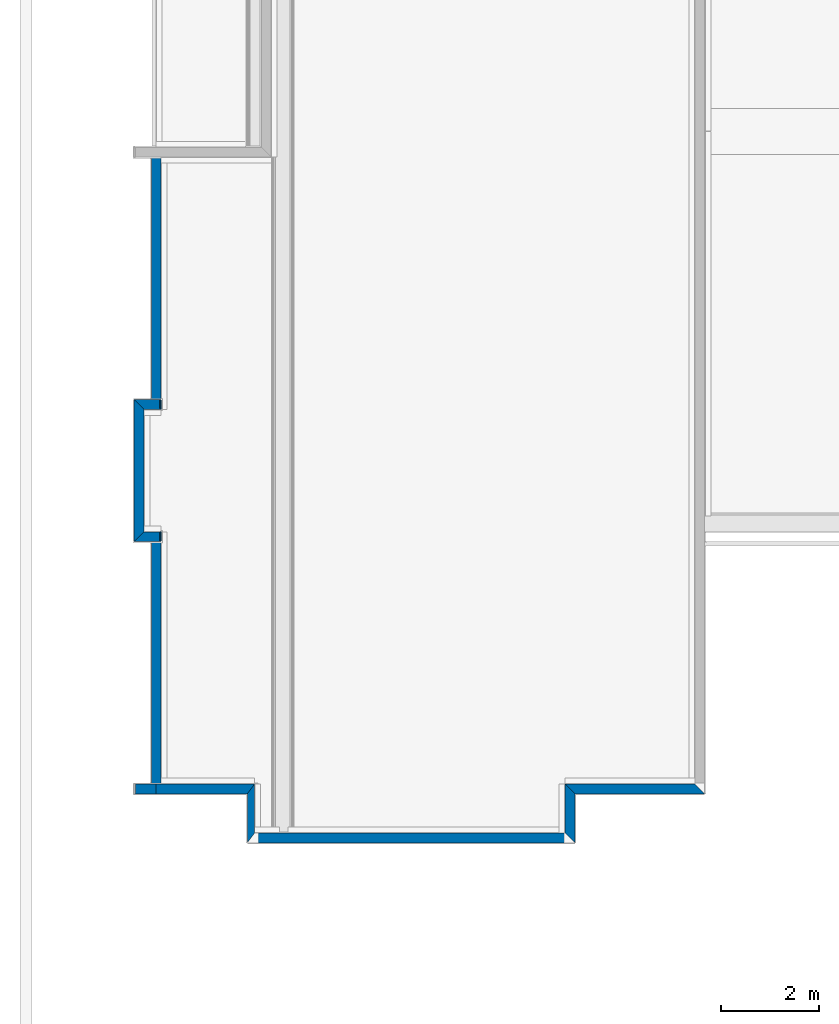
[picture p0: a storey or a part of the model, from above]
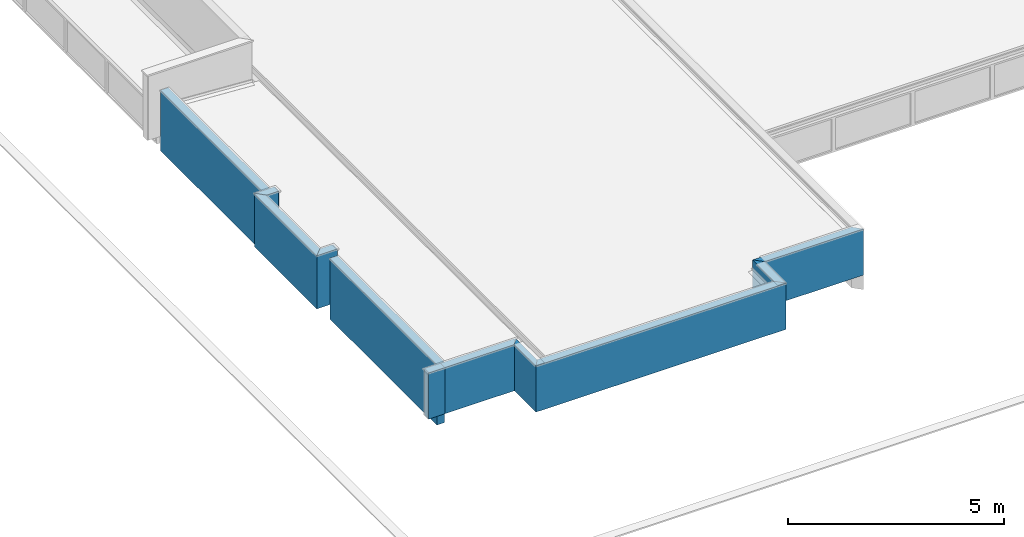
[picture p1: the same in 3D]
Properties of the parts of a building model (IFC4), part 1 of 22

# File
Description: ViewDefinition [Design_Transfer_View], ExchangeRequirement [Architecture], Option [Elements to export: Visible elements (on all stories)], Option [Partial Structure Display: Entire Model], Option [IFC Domain: All], Option [Structural Function: All Elements], Option [Convert Grid elements: On], Option [Convert IFC Annotations and Archicad 2D elements: Off], Option [Convert 2D symbols of Doors and Windows: Off], Option [Export geometries that Participates in Collision Detection only: Off], Option [Split complex elements: Off], Option [Material Preservation: Never explode], Option [Elements in Solid Element Operations: Extruded/revolved], Option [Elements with junctions: Extruded/revolved without junctions], Option [IFC Model position: Survey Point only], Option [Curtain Wall export mode: Container Element], Option [Railing export mode: Single Element], Option [Stair export mode: Single Element], Option [Properties To Export: Current Scheme properties only], Option [Space containment: Off], Option [Geometry to type objects: Off], Option [Element Properties: Visible Only], Option [Building Material Properties: Off], Option [Element Parameters: Off], Option [Component Parameters: IFC Component Quantities Only], Option [IFC Base Quantities: Off], Option [Door Window Parameters: Off], Option [IFC Space boundaries: Off], Option [Archicad Zone Categories as IFC Space classification data: Off], Option [Element Classifications: On]
File name: TIPO2-ARQ-DTV_R03.ifc
Time: 2025-12-15T11:57:10-03:00
Author: Architect
Organization: FUNDO NACIONAL DE DESENVOLVIMENTO DA EDUCAÇÃO - FNDE
Written by: IfcOpenShell 0.8.4
Made in: Bonsai 0.8.4
Authorization: The authorising person

# IfcProject, PROJETO PADRÃO - FNDE
Description: CRECHE PRÉ-ESCOLA TIPO 2; LongName: PROJETO DE ARQUITETURA; Phase: PROJETO PADRÃO

# IfcSite, PADRÃO
RefLatitude: -15, -48, -3, -672000; RefLongitude: -47, -53, 0, -456000; RefElevation: 0 m

# IfcBuildingStorey (2)
In: CRECHE PRÉ-ESCOLA TIPO 2
Name | Elevation (m)
COBERTURA | 3.26
TÉRREO | 0.16

# IfcSpace: Ambientes Administrativos (5)
In: TÉRREO
Type - PredefinedType: INTERNAL
Classification: Zoneamento (Classificação Archicad)
Pset_SpaceCommon - Category: Ambientes Administrativos
FNDE - Ambiente - Quantidade de Alunos: -; Ambiente - Idade dos Alunos: -
Name | LongName = Ambiente
05 | DEPÓSITO
05 | SALA DE ATENDIMENTO
04 | SALA PROF. / REUNIÕES
05 | ADMINISTRAÇÃO
01 | HALL DE ENTRADA

# IfcSpace: Ambientes Externos de Atividades (6)
In: TÉRREO
Type - PredefinedType: INTERNAL
Classification: Zoneamento (Classificação Archicad)
Pset_SpaceCommon - Category: Ambientes Externos de Atividades
FNDE - Ambiente - Quantidade de Alunos: -; Ambiente - Idade dos Alunos: -
Name | LongName = Ambiente
29 | SOLÁRIO - 3
29 | SOLÁRIO - 2
2 x 03 | PLAYGROUND
03 | PÁTIO COBERTO / REFEITÓRIO
29 | SOLÁRIO - 1

# IfcSpace: Ambientes de Alimentaçao / Atenção (2)
In: TÉRREO
Type - PredefinedType: INTERNAL
Classification: Zoneamento (Classificação Archicad)
Pset_SpaceCommon - Category: Ambientes de Alimentaçao / Atenção
FNDE - Ambiente - Quantidade de Alunos: -; Ambiente - Idade dos Alunos: -
Name | LongName = Ambiente
02 | AMAMENTAÇÃO
02 | LACTÁRIO

# IfcSpace: Ambientes de Aprendizagem (6)
In: TÉRREO
Type - PredefinedType: INTERNAL
Classification: Zoneamento (Classificação Archicad)
Pset_SpaceCommon - Category: Ambientes de Aprendizagem
Name | LongName = Ambiente | Ambiente - Quantidade de Alunos | Ambiente - Idade dos Alunos
06 | INFANTIL 1 | 16 alunos | (1 a 2 anos)
06 | INFANTIL 2/3 | 20 alunos | (2 a 4 anos)
06 | INFANTIL 4 | 24 alunos | (4 a 5 anos)
06 | INFANTIL 5 | 24 alunos | (5 a 6 anos)
07 | SALA MULTIUSO | 10 alunos | (0 a 1 ano)
06 | BERÇARIO | 10 alunos | (0 a 1 ano)

# IfcSpace: Ambientes de Higiene (7)
In: TÉRREO
Type - PredefinedType: INTERNAL
Classification: Zoneamento (Classificação Archicad)
Pset_SpaceCommon - Category: Ambientes de Higiene
FNDE - Ambiente - Quantidade de Alunos: -; Ambiente - Idade dos Alunos: -
Name | LongName = Ambiente
11 | SANIT. INFANTIL FEM.
11 | SANIT. INFANTIL MASC.
11 | PCD INFANTIL
06 | HIGIENIZAÇÃO
07 | SANIT. PCD FEM.
06 | SANIT. PCD MASC.
10 | FRALDÁRIO

# IfcSpace: Ambientes de Serviço (11)
In: TÉRREO
Type - PredefinedType: INTERNAL
Classification: Zoneamento (Classificação Archicad)
Pset_SpaceCommon - Category: Ambientes de Serviço
FNDE - Ambiente - Quantidade de Alunos: -; Ambiente - Idade dos Alunos: -
Name | LongName = Ambiente
03 | CASA DE BOMBAS
04 | COZINHA
03 | DESPENSA
05 | LAVANDERIA / ROUPARIA
04 | COPA FUNCIONÁRIOS
03 | VEST. FUNC. FEM.
03 | VEST. FUNC. MASC.
03 | VARANDA DE SERVIÇO / DML
03 | GÁS
03 | CASTELO D'ÁGUA
03 | LIXO

# IfcSpace: Circulações Internas (4)
In: TÉRREO
Type - PredefinedType: INTERNAL
LongName: CIRCULAÇÃO; Classification: Zoneamento (Classificação Archicad)
Pset_SpaceCommon - Category: Circulações Internas
FNDE - Ambiente - Quantidade de Alunos: -; Ambiente - Idade dos Alunos: -; Ambiente: CIRCULAÇÃO

# IfcCovering: ACABAMENTO POLIDO PARA PISO DE CONCRETO 10, L06
In: TÉRREO
Classification: Piso (Acabamento) (Classificação Archicad); Material: ACABAMENTO POLIDO PARA PISO DE CONCRETO
Pset_CoveringCommon - Material: ACABAMENTO POLIDO PARA PISO DE CONCRETO
FNDE - 1_Bloco: ÁREAS EXTERNAS; 0_ID: L06
Component Quantities - ACABAMENTO POLIDO PARA PISO DE CONCRETO, Massa: 49.2388 kg; ACABAMENTO POLIDO PARA PISO DE CONCRETO, Área de Componente Projetada (Líquida): 2.8964 m2; ACABAMENTO POLIDO PARA PISO DE CONCRETO, Área de Componente Projetada (Bruta): 2.8964 m2; ACABAMENTO POLIDO PARA PISO DE CONCRETO, Espessura do Componente: 0.01 m; ACABAMENTO POLIDO PARA PISO DE CONCRETO, Volume Componente (Líquido): 0.028964 m3; ACABAMENTO POLIDO PARA PISO DE CONCRETO, Volume do componente (Bruto): 0.028964 m3

# IfcCovering: ACABAMENTO POLIDO PARA PISO DE CONCRETO 190, L01
In: TÉRREO
Classification: Piso (Acabamento) (Classificação Archicad); Material: ACABAMENTO POLIDO PARA PISO DE CONCRETO
Pset_CoveringCommon - Material: ACABAMENTO POLIDO PARA PISO DE CONCRETO
FNDE - 1_Bloco: CASA DE BOMBAS / GÁS / LIXO; 0_ID: L01
Component Quantities - ACABAMENTO POLIDO PARA PISO DE CONCRETO, Massa: 1296.58 kg; ACABAMENTO POLIDO PARA PISO DE CONCRETO, Área de Componente Projetada (Líquida): 4.01418 m2; ACABAMENTO POLIDO PARA PISO DE CONCRETO, Área de Componente Projetada (Bruta): 4.01418 m2; ACABAMENTO POLIDO PARA PISO DE CONCRETO, Espessura do Componente: 0.19 m; ACABAMENTO POLIDO PARA PISO DE CONCRETO, Volume Componente (Líquido): 0.762694 m3; ACABAMENTO POLIDO PARA PISO DE CONCRETO, Volume do componente (Bruto): 0.762694 m3

# IfcCovering: EI-GRA-Granito cinza Andorinha (Bancadas, bancos e prateleiras) 20 (7)
In: TÉRREO
Type - PredefinedType: CLADDING
Classification: Acabamento (Classificação Archicad); Material: EI-GRA-Granito cinza Andorinha (Bancadas, bancos e prateleiras)
Pset_CoveringCommon - Material: EI-GRA-Granito cinza Andorinha (Bancadas, bancos e prateleiras)
FNDE - Alvenarias: -; Soleira/Peitoril: -
Component Quantities - EI-GRA-Granito cinza Andorinha (Bancadas, bancos e prateleiras), Espessura do Componente: 0.02 m
Name | Pedras | 1_Bloco | 0_ID | EI-GRA-Granito cinza Andorinha (Bancadas, bancos e prateleiras), Massa (kg) | EI-GRA-Granito cinza Andorinha (Bancadas, bancos e prateleiras), Área de Componente Projetada (Líquida) (m2) | EI-GRA-Granito cinza Andorinha (Bancadas, bancos e prateleiras), Área de Componente Projetada (Bruta) (m2) | EI-GRA-Granito cinza Andorinha (Bancadas, bancos e prateleiras), Volume Componente (Líquido) (m3) | EI-GRA-Granito cinza Andorinha (Bancadas, bancos e prateleiras), Volume do componente (Bruto) (m3)
2 x B22 | PRATELEIRA - GRANITO CINZA ANDORINHA - esp. 2 cm | BLOCO A | B22 | 2.52 | 0.045 | 0.045 | 0.0009 | 0.0009
2 x B19 | BANCADA - GRANITO CINZA ANDORINHA - esp. 2 cm | BLOCO B | B19 | 45.0169 | 0.803874 | 0.803874 | 0.0160775 | 0.0160775
2 x B18 | BANCADA - GRANITO CINZA ANDORINHA - esp. 2 cm | BLOCO B | B18 | 56.1624 | 1.0029 | 1.38604 | 0.020058 | 0.0277207
B23 | BANCADA - GRANITO CINZA ANDORINHA - esp. 2 cm | BLOCO A | B23 | 73.4475 | 1.31156 | 1.31156 | 0.0262313 | 0.0262313

# IfcCovering: EI-PIS-3-Cerâmica 45x45 50, L09
In: TÉRREO
Type - PredefinedType: CLADDING
Classification: Acabamento (Classificação Archicad); Material: EI-PIS-3-Cerâmica 45x45
Pset_CoveringCommon - Material: EI-PIS-3-Cerâmica 45x45
FNDE - Alvenarias: -; Soleira/Peitoril: -; Pedras: - -; 1_Bloco: BLOCO B; 0_ID: L09
Component Quantities - EI-PIS-3-Cerâmica 45x45, Massa: 13.0523 kg; EI-PIS-3-Cerâmica 45x45, Área de Componente Projetada (Líquida): 0.130523 m2; EI-PIS-3-Cerâmica 45x45, Área de Componente Projetada (Bruta): 0.130523 m2; EI-PIS-3-Cerâmica 45x45, Espessura do Componente: 0.05 m; EI-PIS-3-Cerâmica 45x45, Volume Componente (Líquido): 0.00652617 m3; EI-PIS-3-Cerâmica 45x45, Volume do componente (Bruto): 0.00652617 m3

# IfcCovering: EI-PIS-6-Bloco intertravado de concreto 100, L01
In: TÉRREO
Classification: Piso (Acabamento) (Classificação Archicad); Material: EI-PIS-6-Bloco intertravado de concreto
Pset_CoveringCommon - Material: EI-PIS-6-Bloco intertravado de concreto
FNDE - 1_Bloco: ÁREAS EXTERNAS; 0_ID: L01
Component Quantities - EI-PIS-6-Bloco intertravado de concreto, Massa: 4190.73 kg; EI-PIS-6-Bloco intertravado de concreto, Área de Componente Projetada (Líquida): 23.2818 m2; EI-PIS-6-Bloco intertravado de concreto, Área de Componente Projetada (Bruta): 23.2818 m2; EI-PIS-6-Bloco intertravado de concreto, Espessura do Componente: 0.1 m; EI-PIS-6-Bloco intertravado de concreto, Volume Componente (Líquido): 2.32818 m3; EI-PIS-6-Bloco intertravado de concreto, Volume do componente (Bruto): 2.32818 m3

# IfcCovering: EI-PIS-8-Gramado (2)
In: TÉRREO
Type - PredefinedType: CLADDING
Classification: Acabamento (Classificação Archicad); Material: EI-PIS-8-Gramado
Pset_CoveringCommon - Material: EI-PIS-8-Gramado
FNDE - Alvenarias: -; Soleira/Peitoril: -; Pedras: - -; 1_Bloco: ÁREAS EXTERNAS; 0_ID: Malha-001

# IfcCovering: EI-PIS-8-Gramado 100 (8)
In: TÉRREO
Type - PredefinedType: CLADDING
Classification: Acabamento (Classificação Archicad); Material: EI-PIS-8-Gramado
Pset_CoveringCommon - Material: EI-PIS-8-Gramado
FNDE - Alvenarias: -; Soleira/Peitoril: -; Pedras: - -; 1_Bloco: ÁREAS EXTERNAS
Component Quantities - EI-PIS-8-Gramado, Espessura do Componente: 0.1 m
Name | 0_ID | EI-PIS-8-Gramado, Massa (kg) | EI-PIS-8-Gramado, Área de Componente Projetada (Líquida) (m2) = EI-PIS-8-Gramado, Área de Componente Projetada (Bruta) (m2) | EI-PIS-8-Gramado, Volume Componente (Líquido) (m3) = EI-PIS-8-Gramado, Volume do componente (Bruto) (m3)
L01 | L01 | 11459.6 | 127.329 | 12.7329
L01 | L01 | 6568.96 | 72.9885 | 7.29885
L01 | L01 | 107.095 | 1.18994 | 0.118994
L01 | L01 | 1648.21 | 18.3135 | 1.83135
L01 | L01 | 335.469 | 3.72743 | 0.372743
L02 | L02 | 5713.51 | 63.4835 | 6.34835
L02 | L02 | 1409.41 | 15.6601 | 1.56601
L01 | L01 | 797.238 | 8.8582 | 0.88582

# IfcCovering: EI-PIS-Piso Tátil alerta em placas de borracha Amarela 7 (5)
In: TÉRREO
Type - PredefinedType: CLADDING
Classification: Acabamento (Classificação Archicad); Material: EI-PIS-Piso Tátil alerta em placas de borracha Amarela
Pset_CoveringCommon - Material: EI-PIS-Piso Tátil alerta em placas de borracha Amarela
FNDE - Alvenarias: -; Soleira/Peitoril: -; Pedras: - -; 0_ID: L01
Component Quantities - EI-PIS-Piso Tátil alerta em placas de borracha Amarela, Massa: 7.2975 kg; EI-PIS-Piso Tátil alerta em placas de borracha Amarela, Área de Componente Projetada (Líquida): 0.75 m2; EI-PIS-Piso Tátil alerta em placas de borracha Amarela, Área de Componente Projetada (Bruta): 1 m2; EI-PIS-Piso Tátil alerta em placas de borracha Amarela, Espessura do Componente: 0.007 m; EI-PIS-Piso Tátil alerta em placas de borracha Amarela, Volume Componente (Líquido): 0.00525 m3; EI-PIS-Piso Tátil alerta em placas de borracha Amarela, Volume do componente (Bruto): 0.007 m3
Name | 1_Bloco
3 x L01 | BLOCO A
2 x L01 | BLOCO B

# IfcCovering: EI-PIS-Piso Tátil alerta em placas de borracha Azul 7 (8)
In: TÉRREO
Type - PredefinedType: CLADDING
Classification: Acabamento (Classificação Archicad); Material: EI-PIS-Piso Tátil alerta em placas de borracha Azul
Pset_CoveringCommon - Material: EI-PIS-Piso Tátil alerta em placas de borracha Azul
FNDE - Alvenarias: -; Soleira/Peitoril: -; Pedras: - -
Component Quantities - EI-PIS-Piso Tátil alerta em placas de borracha Azul, Espessura do Componente: 0.007 m
Name | 1_Bloco | 0_ID | EI-PIS-Piso Tátil alerta em placas de borracha Azul, Massa (kg) | EI-PIS-Piso Tátil alerta em placas de borracha Azul, Área de Componente Projetada (Líquida) (m2) = EI-PIS-Piso Tátil alerta em placas de borracha Azul, Área de Componente Projetada (Bruta) (m2) | EI-PIS-Piso Tátil alerta em placas de borracha Azul, Volume Componente (Líquido) (m3) = EI-PIS-Piso Tátil alerta em placas de borracha Azul, Volume do componente (Bruto) (m3)
2 x L01 | BLOCO B | L01 | 6.68938 | 0.6875 | 0.0048125
Forro-017 | BLOCO B | Forro-017 | 3.64875 | 0.375 | 0.002625
L01 | BLOCO A | L01 | 1.82439 | 0.187502 | 0.00131251
L01 | BLOCO A | L01 | 2.43253 | 0.250003 | 0.00175002
L01 | BLOCO A | L01 | 3.64879 | 0.375004 | 0.00262503
L01 | BLOCO A | L01 | 1.82438 | 0.1875 | 0.0013125
L01 | BLOCO A | L01 | 1.82437 | 0.1875 | 0.0013125

# IfcCovering: EI-PIS-Piso Tátil alerta em placas pré-moldadas na cor vermelha 10 (4)
In: TÉRREO
Type - PredefinedType: CLADDING
Classification: Acabamento (Classificação Archicad); Material: EI-PIS-Piso Tátil alerta em placas pré-moldadas na cor vermelha
Pset_CoveringCommon - Material: EI-PIS-Piso Tátil alerta em placas pré-moldadas na cor vermelha
FNDE - Alvenarias: -; Soleira/Peitoril: -; Pedras: - -; 1_Bloco: ÁREAS EXTERNAS
Name | 0_ID | EI-PIS-Piso Tátil alerta em placas pré-moldadas na cor vermelha, Massa (kg) | EI-PIS-Piso Tátil alerta em placas pré-moldadas na cor vermelha, Área de Componente Projetada (Líquida) (m2) = EI-PIS-Piso Tátil alerta em placas pré-moldadas na cor vermelha, Área de Componente Projetada (Bruta) (m2) | EI-PIS-Piso Tátil alerta em placas pré-moldadas na cor vermelha, Espessura do Componente (m) | EI-PIS-Piso Tátil alerta em placas pré-moldadas na cor vermelha, Volume Componente (Líquido) (m3) = EI-PIS-Piso Tátil alerta em placas pré-moldadas na cor vermelha, Volume do componente (Bruto) (m3)
Cobert.-001 | Cobert.-001 | 4.5 | 0.250084 | 0.00999662 | 0.0025
L01 | L01 | 3.375 | 0.1875 | 0.01 | 0.001875
2 x Cobert.-001 | Cobert.-001 | 3.375 | 0.187563 | 0.00999662 | 0.001875

# IfcCovering: EI-PIS-Piso Tátil direcional em placas de borracha Azul 7 (3)
In: TÉRREO
Type - PredefinedType: CLADDING
Classification: Acabamento (Classificação Archicad); Material: EI-PIS-Piso Tátil direcional em placas de borracha Azul
Pset_CoveringCommon - Material: EI-PIS-Piso Tátil direcional em placas de borracha Azul
FNDE - Alvenarias: -; Soleira/Peitoril: -; Pedras: - -
Component Quantities - EI-PIS-Piso Tátil direcional em placas de borracha Azul, Espessura do Componente: 0.007 m
Name | 1_Bloco | 0_ID | EI-PIS-Piso Tátil direcional em placas de borracha Azul, Massa (kg) | EI-PIS-Piso Tátil direcional em placas de borracha Azul, Área de Componente Projetada (Líquida) (m2) = EI-PIS-Piso Tátil direcional em placas de borracha Azul, Área de Componente Projetada (Bruta) (m2) | EI-PIS-Piso Tátil direcional em placas de borracha Azul, Volume Componente (Líquido) (m3) = EI-PIS-Piso Tátil direcional em placas de borracha Azul, Volume do componente (Bruto) (m3)
Forro-016 | BLOCO B | Forro-016 | 1.82438 | 0.1875 | 0.0013125
Forro-015 | BLOCO B | Forro-015 | 1.82438 | 0.1875 | 0.0013125
Forro-014 | PÁTIO COBERTO | Forro-014 | 32.8364 | 3.37476 | 0.0236233

# IfcCovering: EI-PIS-Piso Tátil direcional em placas pré-moldadas na cor vermelha 10 (6)
In: TÉRREO
Type - PredefinedType: CLADDING
Classification: Acabamento (Classificação Archicad); Material: EI-PIS-Piso Tátil direcional em placas pré-moldadas na cor vermelha
Pset_CoveringCommon - Material: EI-PIS-Piso Tátil direcional em placas pré-moldadas na cor vermelha
FNDE - Alvenarias: -; Soleira/Peitoril: -; Pedras: - -; 1_Bloco: ÁREAS EXTERNAS
Name | 0_ID | EI-PIS-Piso Tátil direcional em placas pré-moldadas na cor vermelha, Massa (kg) | EI-PIS-Piso Tátil direcional em placas pré-moldadas na cor vermelha, Área de Componente Projetada (Líquida) (m2) = EI-PIS-Piso Tátil direcional em placas pré-moldadas na cor vermelha, Área de Componente Projetada (Bruta) (m2) | EI-PIS-Piso Tátil direcional em placas pré-moldadas na cor vermelha, Espessura do Componente (m) | EI-PIS-Piso Tátil direcional em placas pré-moldadas na cor vermelha, Volume Componente (Líquido) (m3) = EI-PIS-Piso Tátil direcional em placas pré-moldadas na cor vermelha, Volume do componente (Bruto) (m3)
Cobert.-001 | Cobert.-001 | 3.375 | 0.187563 | 0.00999662 | 0.001875
Cobert.-001 | Cobert.-001 | 0.67308 | 0.037406 | 0.00999662 | 0.000373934
L01 | L01 | 17.9094 | 0.994966 | 0.01 | 0.00994966
Cobert.-001 | Cobert.-001 | 14.3572 | 0.798535 | 0.0099886 | 0.00797624
Cobert.-001 | Cobert.-001 | 2.25 | 0.125042 | 0.00999662 | 0.00125
L01 | L01 | 2.74503 | 0.152502 | 0.01 | 0.00152502

# IfcCovering: EI-REV-Cerâmica 10x10 Azul 10 (2)
In: TÉRREO
Type - PredefinedType: CLADDING
Classification: Acabamento (Classificação Archicad); Material: EI-REV-Cerâmica 10x10 Azul
Pset_CoveringCommon - Material: EI-REV-Cerâmica 10x10 Azul
FNDE - Alvenarias: -; Soleira/Peitoril: -; Pedras: - -; 1_Bloco: BLOCO B
Component Quantities - EI-REV-Cerâmica 10x10 Azul, Espessura do Componente: 0.01 m
Name | EI-REV-Cerâmica 10x10 Azul, Massa (kg) | EI-REV-Cerâmica 10x10 Azul, Área de Componente Projetada (Líquida) (m2) = EI-REV-Cerâmica 10x10 Azul, Área de Componente Projetada (Bruta) (m2) | EI-REV-Cerâmica 10x10 Azul, Volume Componente (Líquido) (m3) = EI-REV-Cerâmica 10x10 Azul, Volume do componente (Bruto) (m3)
 | 1.19029 | 0.1329 | 0.000595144
 | 2.06608 | 0.103304 | 0.00103304

# IfcCovering: EI-REV-Cerâmica 10x10 Vermelha 10
In: TÉRREO
Type - PredefinedType: CLADDING
Classification: Acabamento (Classificação Archicad); Material: EI-REV-Cerâmica 10x10 Vermelha
Pset_CoveringCommon - Material: EI-REV-Cerâmica 10x10 Vermelha
FNDE - Alvenarias: -; Soleira/Peitoril: -; Pedras: - -; 1_Bloco: BLOCO B
Component Quantities - EI-REV-Cerâmica 10x10 Vermelha, Massa: 0.92164 kg; EI-REV-Cerâmica 10x10 Vermelha, Área de Componente Projetada (Líquida): 0.103304 m2; EI-REV-Cerâmica 10x10 Vermelha, Área de Componente Projetada (Bruta): 0.103304 m2; EI-REV-Cerâmica 10x10 Vermelha, Espessura do Componente: 0.01 m; EI-REV-Cerâmica 10x10 Vermelha, Volume Componente (Líquido): 0.00046082 m3; EI-REV-Cerâmica 10x10 Vermelha, Volume do componente (Bruto): 0.00046082 m3

# IfcCovering: EI-REV-Cerâmica 30x40 15, L26
In: TÉRREO
Classification: Piso (Acabamento) (Classificação Archicad); Material: EI-REV-Cerâmica 30x40
Pset_CoveringCommon - Material: EI-REV-Cerâmica 30x40
FNDE - 1_Bloco: BLOCO A; 0_ID: L26
Component Quantities - EI-REV-Cerâmica 30x40, Massa: 3.1509 kg; EI-REV-Cerâmica 30x40, Área de Componente Projetada (Líquida): 0.10503 m2; EI-REV-Cerâmica 30x40, Área de Componente Projetada (Bruta): 0.10503 m2; EI-REV-Cerâmica 30x40, Espessura do Componente: 0.015 m; EI-REV-Cerâmica 30x40, Volume Componente (Líquido): 0.00157545 m3; EI-REV-Cerâmica 30x40, Volume do componente (Bruto): 0.00157545 m3

# IfcCovering: EI-REV-Pintura Epóxi cor Amarelo 1, L01
In: TÉRREO
Classification: Piso (Acabamento) (Classificação Archicad); Material: EI-REV-Pintura Epóxi cor Amarelo
Pset_CoveringCommon - Material: EI-REV-Pintura Epóxi cor Amarelo
FNDE - 1_Bloco: ÁREAS EXTERNAS; 0_ID: L01
Component Quantities - EI-REV-Pintura Epóxi cor Amarelo, Massa: 0.663006 kg; EI-REV-Pintura Epóxi cor Amarelo, Área de Componente Projetada (Líquida): 0.510004 m2; EI-REV-Pintura Epóxi cor Amarelo, Área de Componente Projetada (Bruta): 1 m2; EI-REV-Pintura Epóxi cor Amarelo, Espessura do Componente: 0.001 m; EI-REV-Pintura Epóxi cor Amarelo, Volume Componente (Líquido): 0.000510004 m3; EI-REV-Pintura Epóxi cor Amarelo, Volume do componente (Bruto): 0.001 m3

# IfcCovering: EI-REV-Pintura Epóxi cor Amarelo 1 (7)
In: TÉRREO
Type - PredefinedType: CLADDING
Classification: Acabamento (Classificação Archicad); Material: EI-REV-Pintura Epóxi cor Amarelo
Pset_CoveringCommon - Material: EI-REV-Pintura Epóxi cor Amarelo
FNDE - Alvenarias: -; Soleira/Peitoril: -; Pedras: - -; 1_Bloco: PÁTIO COBERTO; 0_ID: L09
Component Quantities - EI-REV-Pintura Epóxi cor Amarelo, Espessura do Componente: 0.001 m
Name | EI-REV-Pintura Epóxi cor Amarelo, Massa (kg) | EI-REV-Pintura Epóxi cor Amarelo, Área de Componente Projetada (Líquida) (m2) = EI-REV-Pintura Epóxi cor Amarelo, Área de Componente Projetada (Bruta) (m2) | EI-REV-Pintura Epóxi cor Amarelo, Volume Componente (Líquido) (m3) = EI-REV-Pintura Epóxi cor Amarelo, Volume do componente (Bruto) (m3)
L09 | 0.208 | 0.16 | 0.00016
L09 | 0.312 | 0.24 | 0.00024
L09 | 0.286629 | 0.220484 | 0.000220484
L09 | 0.304129 | 0.233946 | 0.000233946
L09 | 0.267889 | 0.206069 | 0.000206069
L09 | 0.246051 | 0.18927 | 0.00018927
L09 | 0.270051 | 0.207731 | 0.000207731

# IfcCovering: EI-REV-Pintura Epóxi cor Azul 1 (10)
In: TÉRREO
Type - PredefinedType: CLADDING
Classification: Acabamento (Classificação Archicad); Material: EI-REV-Pintura Epóxi cor Azul
Pset_CoveringCommon - Material: EI-REV-Pintura Epóxi cor Azul
FNDE - Alvenarias: -; Soleira/Peitoril: -; Pedras: - -; 1_Bloco: PÁTIO COBERTO; 0_ID: L09
Component Quantities - EI-REV-Pintura Epóxi cor Azul, Espessura do Componente: 0.001 m
Name | EI-REV-Pintura Epóxi cor Azul, Massa (kg) | EI-REV-Pintura Epóxi cor Azul, Área de Componente Projetada (Líquida) (m2) = EI-REV-Pintura Epóxi cor Azul, Área de Componente Projetada (Bruta) (m2) | EI-REV-Pintura Epóxi cor Azul, Volume Componente (Líquido) (m3) = EI-REV-Pintura Epóxi cor Azul, Volume do componente (Bruto) (m3)
L09 | 1.1115 | 0.855 | 0.000855
L09 | 0.91975 | 0.7075 | 0.0007075
2 x L09 | 0.312 | 0.24 | 0.00024
L09 | 0.208 | 0.16 | 0.00016
L09 | 0.277579 | 0.213523 | 0.000213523
L09 | 0.301406 | 0.231851 | 0.000231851
L09 | 0.284155 | 0.21858 | 0.00021858
L09 | 0.248022 | 0.190786 | 0.000190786
L09 | 0.230028 | 0.176945 | 0.000176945

# IfcCovering: EI-REV-Pintura Epóxi cor Branco 1, L09
In: TÉRREO
Type - PredefinedType: CLADDING
Classification: Acabamento (Classificação Archicad); Material: EI-REV-Pintura Epóxi cor Branco
Pset_CoveringCommon - Material: EI-REV-Pintura Epóxi cor Branco
FNDE - Alvenarias: -; Soleira/Peitoril: -; Pedras: - -; 1_Bloco: PÁTIO COBERTO; 0_ID: L09
Component Quantities - EI-REV-Pintura Epóxi cor Branco, Massa: 1.60513 kg; EI-REV-Pintura Epóxi cor Branco, Área de Componente Projetada (Líquida): 0.944197 m2; EI-REV-Pintura Epóxi cor Branco, Área de Componente Projetada (Bruta): 6.75984 m2; EI-REV-Pintura Epóxi cor Branco, Espessura do Componente: 0.001 m; EI-REV-Pintura Epóxi cor Branco, Volume Componente (Líquido): 0.000944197 m3; EI-REV-Pintura Epóxi cor Branco, Volume do componente (Bruto): 0.00675984 m3

# IfcCovering: EI-REV-Pintura Epóxi cor Cinza 1 (6)
In: TÉRREO
Type - PredefinedType: CLADDING
Classification: Acabamento (Classificação Archicad); Material: EI-REV-Pintura Epóxi cor Cinza
Pset_CoveringCommon - Material: EI-REV-Pintura Epóxi cor Cinza
FNDE - Alvenarias: -; Soleira/Peitoril: -; Pedras: - -; 1_Bloco: PÁTIO COBERTO; 0_ID: L09
Component Quantities - EI-REV-Pintura Epóxi cor Cinza, Espessura do Componente: 0.001 m
Name | EI-REV-Pintura Epóxi cor Cinza, Massa (kg) | EI-REV-Pintura Epóxi cor Cinza, Área de Componente Projetada (Líquida) (m2) = EI-REV-Pintura Epóxi cor Cinza, Área de Componente Projetada (Bruta) (m2) | EI-REV-Pintura Epóxi cor Cinza, Volume Componente (Líquido) (m3) = EI-REV-Pintura Epóxi cor Cinza, Volume do componente (Bruto) (m3)
L09 | 0.352964 | 0.207626 | 0.000207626
L09 | 0.331531 | 0.195018 | 0.000195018
L09 | 0.217341 | 0.127848 | 0.000127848
L09 | 0.403751 | 0.2375 | 0.0002375
L09 | 0.359886 | 0.211698 | 0.000211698
L09 | 0.418063 | 0.245919 | 0.000245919

# IfcCovering: EI-REV-Pintura Epóxi cor Laranja 1 (9)
In: TÉRREO
Type - PredefinedType: CLADDING
Classification: Acabamento (Classificação Archicad); Material: EI-REV-Pintura Epóxi cor Laranja
Pset_CoveringCommon - Material: EI-REV-Pintura Epóxi cor Laranja
FNDE - Alvenarias: -; Soleira/Peitoril: -; Pedras: - -; 1_Bloco: PÁTIO COBERTO; 0_ID: L09
Component Quantities - EI-REV-Pintura Epóxi cor Laranja, Espessura do Componente: 0.001 m
Name | EI-REV-Pintura Epóxi cor Laranja, Massa (kg) | EI-REV-Pintura Epóxi cor Laranja, Área de Componente Projetada (Líquida) (m2) = EI-REV-Pintura Epóxi cor Laranja, Área de Componente Projetada (Bruta) (m2) | EI-REV-Pintura Epóxi cor Laranja, Volume Componente (Líquido) (m3) = EI-REV-Pintura Epóxi cor Laranja, Volume do componente (Bruto) (m3)
L09 | 0.312 | 0.24 | 0.00024
L09 | 0.208 | 0.16 | 0.00016
L09 | 0.593406 | 0.456466 | 0.000456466
L09 | 0.482799 | 0.371384 | 0.000371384
L09 | 0.290484 | 0.223449 | 0.000223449
L09 | 0.294511 | 0.226547 | 0.000226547
L09 | 0.275317 | 0.211782 | 0.000211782
L09 | 0.289915 | 0.223012 | 0.000223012
L09 | 0.246722 | 0.189786 | 0.000189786

# IfcCovering: EI-REV-Pintura Epóxi cor Verde 1 (8)
In: TÉRREO
Type - PredefinedType: CLADDING
Classification: Acabamento (Classificação Archicad); Material: EI-REV-Pintura Epóxi cor Verde
Pset_CoveringCommon - Material: EI-REV-Pintura Epóxi cor Verde
FNDE - Alvenarias: -; Soleira/Peitoril: -; Pedras: - -; 1_Bloco: PÁTIO COBERTO; 0_ID: L09
Component Quantities - EI-REV-Pintura Epóxi cor Verde, Espessura do Componente: 0.001 m
Name | EI-REV-Pintura Epóxi cor Verde, Massa (kg) | EI-REV-Pintura Epóxi cor Verde, Área de Componente Projetada (Líquida) (m2) = EI-REV-Pintura Epóxi cor Verde, Área de Componente Projetada (Bruta) (m2) | EI-REV-Pintura Epóxi cor Verde, Volume Componente (Líquido) (m3) = EI-REV-Pintura Epóxi cor Verde, Volume do componente (Bruto) (m3)
L09 | 0.208 | 0.16 | 0.00016
2 x L09 | 0.312 | 0.24 | 0.00024
L09 | 0.327408 | 0.251852 | 0.000251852
L09 | 0.273217 | 0.210167 | 0.000210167
L09 | 0.289267 | 0.222513 | 0.000222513
L09 | 0.266747 | 0.20519 | 0.00020519
L09 | 0.214944 | 0.165341 | 0.000165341

# IfcCovering: EI-REV-Pintura Epóxi cor Vermelho 1, L01
In: TÉRREO
Classification: Piso (Acabamento) (Classificação Archicad); Material: EI-REV-Pintura Epóxi cor Vermelho
Pset_CoveringCommon - Material: EI-REV-Pintura Epóxi cor Vermelho
FNDE - 1_Bloco: ÁREAS EXTERNAS; 0_ID: L01
Component Quantities - EI-REV-Pintura Epóxi cor Vermelho, Massa: 0.637 kg; EI-REV-Pintura Epóxi cor Vermelho, Área de Componente Projetada (Líquida): 0.49 m2; EI-REV-Pintura Epóxi cor Vermelho, Área de Componente Projetada (Bruta): 0.49 m2; EI-REV-Pintura Epóxi cor Vermelho, Espessura do Componente: 0.001 m; EI-REV-Pintura Epóxi cor Vermelho, Volume Componente (Líquido): 0.00049 m3; EI-REV-Pintura Epóxi cor Vermelho, Volume do componente (Bruto): 0.00049 m3

# IfcCovering: EI-REV-Rodapé Ceramico 13 x 70 (23)
In: TÉRREO
Classification: Rodapé (Classificação Archicad); Material: EI-REV-Rodapé Ceramico
Pset_CoveringCommon - Material: EI-REV-Rodapé Ceramico
FNDE - 1_Bloco: BLOCO B
Component Quantities - EI-REV-Rodapé Ceramico, Espessura do Componente: 0.013 m; EI-REV-Rodapé Ceramico, Altura do Componente Retangular: 0.07 m; EI-REV-Rodapé Ceramico, Largura do Componente Retangular: 0.013 m; EI-REV-Rodapé Ceramico, Área de Seção Transversal do Componente: 0.00091 m2
Name | EI-REV-Rodapé Ceramico, Massa (kg) | EI-REV-Rodapé Ceramico, Área de Componente Projetada (Líquida) (m2) = EI-REV-Rodapé Ceramico, Área de Componente Projetada (Bruta) (m2) | EI-REV-Rodapé Ceramico, Volume Componente (Líquido) (m3) = EI-REV-Rodapé Ceramico, Volume do componente (Bruto) (m3)
 | 2.77277 | 0.1071 | 0.00138639
 | 4.52634 | 0.175 | 0.00226317
2 x  | 5.43622 | 0.209995 | 0.00271811
 | 0.11557 | 0.0049 | 0.000057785
 | 8.01588 | 0.312547 | 0.00400794
 | 1.62617 | 0.063 | 0.000813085
 | 2.77272 | 0.107098 | 0.00138636
2 x  | 10.8963 | 0.419998 | 0.00544815
 | 3.96487 | 0.15295 | 0.00198244
 | 0.141089 | 0.00559692 | 0.0000705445
 | 4.17417 | 0.161 | 0.00208709
 | 4.89034 | 0.189 | 0.00244517
 | 2.62712 | 0.101498 | 0.00131356
 | 8.26917 | 0.3185 | 0.00413458
 | 0.09737 | 0.0042 | 0.000048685
 | 3.1006 | 0.119709 | 0.0015503
 | 0.552619 | 0.0217096 | 0.000276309
 | 2.26298 | 0.0874927 | 0.00113149
2 x  | 5.43201 | 0.209834 | 0.00271601
 | 4.5082 | 0.174302 | 0.0022541

# IfcCovering: EI-REV-Rodapé em PVC para piso vinílico 13 x 50 (49)
In: TÉRREO
Classification: Rodapé (Classificação Archicad); Material: EI-REV-Rodapé em PVC para piso vinílico
Pset_CoveringCommon - Material: EI-REV-Rodapé em PVC para piso vinílico
Component Quantities - EI-REV-Rodapé em PVC para piso vinílico, Espessura do Componente: 0.013 m; EI-REV-Rodapé em PVC para piso vinílico, Altura do Componente Retangular: 0.05 m; EI-REV-Rodapé em PVC para piso vinílico, Largura do Componente Retangular: 0.013 m; EI-REV-Rodapé em PVC para piso vinílico, Área de Seção Transversal do Componente: 0.00065 m2
Name | 1_Bloco | EI-REV-Rodapé em PVC para piso vinílico, Massa (kg) | EI-REV-Rodapé em PVC para piso vinílico, Área de Componente Projetada (Líquida) (m2) = EI-REV-Rodapé em PVC para piso vinílico, Área de Componente Projetada (Bruta) (m2) | EI-REV-Rodapé em PVC para piso vinílico, Volume Componente (Líquido) (m3) = EI-REV-Rodapé em PVC para piso vinílico, Volume do componente (Bruto) (m3)
 | BLOCO A | 1.40359 | 0.078 | 0.00100977
 | BLOCO A | 0.728784 | 0.0406561 | 0.000524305
 | BLOCO A | 5.41827 | 0.300499 | 0.00389804
 | BLOCO A | 0.897627 | 0.05 | 0.000645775
 | BLOCO A | 3.29188 | 0.182499 | 0.00236826
 | BLOCO A | 3.79631 | 0.210414 | 0.00273116
 | BLOCO A | 0.400702 | 0.0225 | 0.000288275
 | BLOCO B | 0.400703 | 0.0225001 | 0.000288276
4 x  | BLOCO B | 0.406575 | 0.02315 | 0.0002925
2 x  | BLOCO B | 1.79525 | 0.1 | 0.00129155
 | BLOCO B | 3.82045 | 0.21175 | 0.00274853
 | BLOCO B | 0.147271 | 0.0088 | 0.00010595
 | BLOCO B | 0.89763 | 0.0500001 | 0.000645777
 | BLOCO B | 5.40928 | 0.300001 | 0.00389157
 | BLOCO B | 3.46675 | 0.192501 | 0.00249407
 | BLOCO B | 0.703375 | 0.03925 | 0.000506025
 | BLOCO B | 0.195607 | 0.01115 | 0.000140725
 | BLOCO B | 0.0483367 | 0.00299997 | 0.0000347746
 | BLOCO B | 2.92465 | 0.162501 | 0.00210407
 | BLOCO B | 0.14727 | 0.0088 | 0.00010595
4 x  | BLOCO B | 5.40929 | 0.300002 | 0.00389158
 | BLOCO B | 0.988026 | 0.0550027 | 0.00071081
2 x  | BLOCO B | 0.400702 | 0.0225 | 0.000288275
2 x  | BLOCO B | 0.5421 | 0.03065 | 0.00039
2 x  | BLOCO B | 0.852452 | 0.0475 | 0.000613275
 | BLOCO B | 0.852425 | 0.0474985 | 0.000613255
2 x  | BLOCO B | 4.37023 | 0.2425 | 0.00314405
 | BLOCO B | 0.85248 | 0.0475015 | 0.000613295
 | BLOCO B | 0.195608 | 0.01115 | 0.000140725
 | BLOCO B | 0.987971 | 0.0549997 | 0.000710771
 | BLOCO B | 4.86713 | 0.269999 | 0.00350153
 | BLOCO B | 0.400764 | 0.0225034 | 0.000288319
 | BLOCO B | 0.703435 | 0.0392533 | 0.000506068
 | BLOCO B | 5.40923 | 0.299999 | 0.00389153
 | BLOCO B | 0.897565 | 0.0499965 | 0.00064573
 | BLOCO B | 5.40919 | 0.299996 | 0.0038915
 | BLOCO B | 3.82033 | 0.211743 | 0.00274844
 | BLOCO B | 0.0483372 | 0.003 | 0.000034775

# IfcCovering: FNDE-COB_IMP-PM 33, L01
In: TÉRREO
Classification: Piso (Acabamento) (Classificação Archicad); Material: EI-ISO-Impermeabilização Manta Líquida, EI-PIS-Proteção Meânica
Pset_CoveringCommon - Material: FNDE-COB_IMP-PM
FNDE - 1_Bloco: CASA DE BOMBAS / GÁS / LIXO; 0_ID: L01
Component Quantities - EI-PIS-Proteção Meânica, Massa: 922.258 kg; EI-PIS-Proteção Meânica, Área de Componente Projetada (Líquida): 13.8841 m2; EI-PIS-Proteção Meânica, Área de Componente Projetada (Bruta): 13.8841 m2; EI-PIS-Proteção Meânica, Espessura do Componente: 0.03 m; EI-PIS-Proteção Meânica, Volume Componente (Líquido): 0.400982 m3; EI-PIS-Proteção Meânica, Volume do componente (Bruto): 0.400982 m3; EI-ISO-Impermeabilização Manta Líquida, Massa: 42.8007 kg; EI-ISO-Impermeabilização Manta Líquida, Área de Componente Projetada (Líquida): 12.9699 m2; EI-ISO-Impermeabilização Manta Líquida, Área de Componente Projetada (Bruta): 12.9699 m2; EI-ISO-Impermeabilização Manta Líquida, Espessura do Componente: 0.003 m; EI-ISO-Impermeabilização Manta Líquida, Volume Componente (Líquido): 0.0389098 m3; EI-ISO-Impermeabilização Manta Líquida, Volume do componente (Bruto): 0.0389098 m3

# IfcCovering: FNDE-Chuveiros - escada 920 x 370 (4)
In: TÉRREO
Type - PredefinedType: CLADDING
Classification: Acabamento (Classificação Archicad); Material: FNDE-Enchimento, LASTRO DE CONCRETO, EI-ISO-Impermeabilização, EI-PIS-3-Cerâmica 45x45, TIJOLO - CERAMICO 9x19x39 - espessura 15cm, EI-REV-Chapisco (interno) (3), EI-REV-Emboço Interno (3), EI-REV-Cerâmica 30x40 (3)
Pset_CoveringCommon - Material: FNDE-Chuveiros - escada
FNDE - Alvenarias: Mureta; Soleira/Peitoril: -; Pedras: - -
Component Quantities - FNDE-Enchimento, Altura do Componente Retangular: 0.29 m; FNDE-Enchimento, Largura do Componente Retangular: 0.61 m; FNDE-Enchimento, Área de Seção Transversal do Componente: 0.1769 m2; LASTRO DE CONCRETO, Altura do Componente Retangular: 0.05 m; LASTRO DE CONCRETO, Largura do Componente Retangular: 0.615 m; LASTRO DE CONCRETO, Área de Seção Transversal do Componente: 0.03075 m2; EI-ISO-Impermeabilização, Altura do Componente Retangular: 0.005 m; EI-ISO-Impermeabilização, Largura do Componente Retangular: 0.62 m; EI-ISO-Impermeabilização, Área de Seção Transversal do Componente: 0.0031 m2; EI-PIS-3-Cerâmica 45x45, Área de Seção Transversal do Componente: 0.01575 m2; TIJOLO - CERAMICO 9x19x39 - espessura 15cm, Altura do Componente Retangular: 0.17 m; TIJOLO - CERAMICO 9x19x39 - espessura 15cm, Largura do Componente Retangular: 0.28 m; TIJOLO - CERAMICO 9x19x39 - espessura 15cm, Área de Seção Transversal do Componente: 0.0476 m2; EI-REV-Chapisco (interno) 1, Área de Seção Transversal do Componente: 0.000862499 m2; EI-REV-Emboço Interno 1, Área de Seção Transversal do Componente: 0.0008875 m2; EI-REV-Cerâmica 30x40 1, Área de Seção Transversal do Componente: 0.0032 m2; EI-REV-Chapisco (interno) 2, Área de Seção Transversal do Componente: 0.0014 m2; EI-REV-Cerâmica 30x40 2, Área de Seção Transversal do Componente: 0.0056 m2; EI-REV-Chapisco (interno) 3, Área de Seção Transversal do Componente: 0.0005875 m2; EI-REV-Emboço Interno 3, Área de Seção Transversal do Componente: 0.0008125 m2; EI-REV-Cerâmica 30x40 3, Área de Seção Transversal do Componente: 0.00335 m2
Name | 1_Bloco | FNDE-Enchimento, Massa (kg) | FNDE-Enchimento, Área de Componente Projetada (Líquida) (m2) = FNDE-Enchimento, Área de Componente Projetada (Bruta) (m2) | FNDE-Enchimento, Volume Componente (Líquido) (m3) = FNDE-Enchimento, Volume do componente (Bruto) (m3) | LASTRO DE CONCRETO, Massa (kg) | LASTRO DE CONCRETO, Área de Componente Projetada (Líquida) (m2) = LASTRO DE CONCRETO, Área de Componente Projetada (Bruta) (m2) | LASTRO DE CONCRETO, Volume Componente (Líquido) (m3) = LASTRO DE CONCRETO, Volume do componente (Bruto) (m3) | EI-ISO-Impermeabilização, Massa (kg) | EI-ISO-Impermeabilização, Área de Componente Projetada (Líquida) (m2) = EI-ISO-Impermeabilização, Área de Componente Projetada (Bruta) (m2) | EI-ISO-Impermeabilização, Volume Componente (Líquido) (m3) = EI-ISO-Impermeabilização, Volume do componente (Bruto) (m3) | EI-PIS-3-Cerâmica 45x45, Massa (kg) | EI-PIS-3-Cerâmica 45x45, Área de Componente Projetada (Líquida) (m2) = EI-PIS-3-Cerâmica 45x45, Área de Componente Projetada (Bruta) (m2) | EI-PIS-3-Cerâmica 45x45, Volume Componente (Líquido) (m3) = EI-PIS-3-Cerâmica 45x45, Volume do componente (Bruto) (m3) | TIJOLO - CERAMICO 9x19x39 - espessura 15cm, Massa (kg) | TIJOLO - CERAMICO 9x19x39 - espessura 15cm, Área de Componente Projetada (Líquida) (m2) = TIJOLO - CERAMICO 9x19x39 - espessura 15cm, Área de Componente Projetada (Bruta) (m2) = EI-REV-Cerâmica 30x40 1, Área de Componente Projetada (Líquida) (m2) = EI-REV-Cerâmica 30x40 1, Área de Componente Projetada (Bruta) (m2) | TIJOLO - CERAMICO 9x19x39 - espessura 15cm, Volume Componente (Líquido) (m3) = TIJOLO - CERAMICO 9x19x39 - espessura 15cm, Volume do componente (Bruto) (m3) | EI-REV-Chapisco (interno) 1, Massa (kg) | EI-REV-Chapisco (interno) 1, Área de Componente Projetada (Líquida) (m2) = EI-REV-Chapisco (interno) 1, Área de Componente Projetada (Bruta) (m2) | EI-REV-Chapisco (interno) 1, Volume Componente (Líquido) (m3) = EI-REV-Chapisco (interno) 1, Volume do componente (Bruto) (m3) | EI-REV-Emboço Interno 1, Massa (kg) | EI-REV-Emboço Interno 1, Área de Componente Projetada (Líquida) (m2) = EI-REV-Emboço Interno 1, Área de Componente Projetada (Bruta) (m2) | EI-REV-Emboço Interno 1, Volume Componente (Líquido) (m3) = EI-REV-Emboço Interno 1, Volume do componente (Bruto) (m3) | EI-REV-Cerâmica 30x40 1, Massa (kg) | EI-REV-Cerâmica 30x40 1, Volume Componente (Líquido) (m3) = EI-REV-Cerâmica 30x40 1, Volume do componente (Bruto) (m3) | EI-REV-Chapisco (interno) 2, Massa (kg) | EI-REV-Chapisco (interno) 2, Área de Componente Projetada (Líquida) (m2) = EI-REV-Chapisco (interno) 2, Área de Componente Projetada (Bruta) (m2) | EI-REV-Chapisco (interno) 2, Volume Componente (Líquido) (m3) = EI-REV-Chapisco (interno) 2, Volume do componente (Bruto) (m3) | EI-REV-Cerâmica 30x40 2, Massa (kg) | EI-REV-Cerâmica 30x40 2, Área de Componente Projetada (Líquida) (m2) = EI-REV-Cerâmica 30x40 2, Área de Componente Projetada (Bruta) (m2) | EI-REV-Cerâmica 30x40 2, Volume Componente (Líquido) (m3) = EI-REV-Cerâmica 30x40 2, Volume do componente (Bruto) (m3) | EI-REV-Chapisco (interno) 3, Massa (kg) | EI-REV-Chapisco (interno) 3, Área de Componente Projetada (Líquida) (m2) = EI-REV-Chapisco (interno) 3, Área de Componente Projetada (Bruta) (m2) | EI-REV-Chapisco (interno) 3, Volume Componente (Líquido) (m3) = EI-REV-Chapisco (interno) 3, Volume do componente (Bruto) (m3) | EI-REV-Emboço Interno 3, Massa (kg) | EI-REV-Emboço Interno 3, Área de Componente Projetada (Líquida) (m2) = EI-REV-Emboço Interno 3, Área de Componente Projetada (Bruta) (m2) | EI-REV-Emboço Interno 3, Volume Componente (Líquido) (m3) = EI-REV-Emboço Interno 3, Volume do componente (Bruto) (m3) | EI-REV-Cerâmica 30x40 3, Massa (kg) | EI-REV-Cerâmica 30x40 3, Área de Componente Projetada (Líquida) (m2) = EI-REV-Cerâmica 30x40 3, Área de Componente Projetada (Bruta) (m2) | EI-REV-Cerâmica 30x40 3, Volume Componente (Líquido) (m3) = EI-REV-Cerâmica 30x40 3, Volume do componente (Bruto) (m3)
 | BLOCO B | 169.778 | 0.390293 | 0.113185 | 35.4144 | 0.393493 | 0.0196747 | 2.18181 | 0.396693 | 0.00198347 | 20.1546 | 0.409493 | 0.0100773 | 19.7398 | 0.108795 | 0.0304627 | 0.568284 | 0.0889533 | 0.000437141 | 0.588108 | 0.0920031 | 0.000452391 | 4.09583 | 0.00204791 | 1.11015 | 0.173842 | 0.000853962 | 7.1677 | 0.191992 | 0.00358385 | 0.465867 | 0.0731967 | 0.000358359 | 0.644284 | 0.100646 | 0.000495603 | 4.28782 | 0.121595 | 0.00214391 | Component Quantities - EI-REV-Chapisco (interno) 2: 2 with these values
 | BLOCO A | 169.733 | 0.390191 | 0.113155 | 35.405 | 0.393389 | 0.0196694 | 2.18123 | 0.396587 | 0.00198294 | 20.1492 | 0.40938 | 0.0100746 | 19.7301 | 0.108742 | 0.0304477 | 0.592458 | 0.0927466 | 0.000455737 | 0.613247 | 0.0959448 | 0.000471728 | 4.0938 | 0.0020469 | 1.16413 | 0.182295 | 0.000895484 | 7.16415 | 0.191897 | 0.00358208 | 0.488519 | 0.0767558 | 0.000375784 | 0.675611 | 0.105539 | 0.000519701 | 4.2857 | 0.121535 | 0.00214285 | Component Quantities - EI-REV-Emboço Interno 2, Massa: 1.16413 kg; EI-REV-Emboço Interno 2, Área de Componente Projetada (Líquida): 0.182295 m2; EI-REV-Emboço Interno 2, Área de Componente Projetada (Bruta): 0.182295 m2; EI-REV-Emboço Interno 2, Área de Seção Transversal do Componente: 0.0014 m2; EI-REV-Emboço Interno 2, Volume Componente (Líquido): 0.000895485 m3; EI-REV-Emboço Interno 2, Volume do componente (Bruto): 0.000895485 m3
 | BLOCO B | 0.00772169 | 0.0000428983 | 0.00000514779 | 0.00386085 | 0.0000428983 | 0.00000214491 | 0.000235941 | 0.0000428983 | 2.14491e-07 | 0.00000359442 | 0.0000428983 | 1.79721e-09 | 0.00472567 | 0.108795 | 0.00000729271 | 0 | 0 | 0 | 0.0000442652 | 0.000507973 | 3.40502e-08 | 0.0145825 | 0.00000729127 | 0 | 0 | 0 | 0.00000287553 | 0.0000428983 | 1.43777e-09 | 0 | 0 | 0 | 0 | 0 | 0 | 0.0145818 | 0.108795 | 0.00000729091 | Component Quantities - EI-REV-Chapisco (interno) 2: 2 with these values
 | BLOCO B | 169.778 | 0.390293 | 0.113185 | 35.4144 | 0.393493 | 0.0196747 | 2.18181 | 0.396693 | 0.00198347 | 20.1546 | 0.409493 | 0.0100773 | 19.7398 | 0.108795 | 0.0304627 | 0.560827 | 0.0889577 | 0.000431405 | 0.588137 | 0.0920077 | 0.000452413 | 4.09583 | 0.00204791 | 1.11019 | 0.173809 | 0.000853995 | 7.1677 | 0.191992 | 0.00358385 | 0.459509 | 0.0731589 | 0.000353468 | 0.641652 | 0.10065 | 0.000493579 | 4.28739 | 0.121595 | 0.00214369 | Component Quantities - EI-REV-Emboço Interno 2, Massa: 1.1102 kg; EI-REV-Emboço Interno 2, Área de Componente Projetada (Líquida): 0.173849 m2; EI-REV-Emboço Interno 2, Área de Componente Projetada (Bruta): 0.173849 m2; EI-REV-Emboço Interno 2, Área de Seção Transversal do Componente: 0.0014 m2; EI-REV-Emboço Interno 2, Volume Componente (Líquido): 0.000853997 m3; EI-REV-Emboço Interno 2, Volume do componente (Bruto): 0.000853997 m3

# IfcCovering: FNDE-Chuveiros 890 x 830 (4)
In: TÉRREO
Type - PredefinedType: CLADDING
Classification: Acabamento (Classificação Archicad); Material: FNDE-Enchimento, LASTRO DE CONCRETO, EI-ISO-Impermeabilização (2), EI-PIS-3-Cerâmica 45x45, TIJOLO - CERAMICO 9x19x39 - espessura 15cm (2), EI-REV-Chapisco (interno) (5), EI-REV-Emboço Interno (5), EI-REV-Cerâmica 30x40 (5)
Pset_CoveringCommon - Material: FNDE-Chuveiros
FNDE - Alvenarias: Mureta; Soleira/Peitoril: -; Pedras: - -
Component Quantities - FNDE-Enchimento, Altura do Componente Retangular: 0.29 m; FNDE-Enchimento, Largura do Componente Retangular: 0.67 m; FNDE-Enchimento, Área de Seção Transversal do Componente: 0.1943 m2; LASTRO DE CONCRETO, Altura do Componente Retangular: 0.05 m; LASTRO DE CONCRETO, Largura do Componente Retangular: 0.67 m; LASTRO DE CONCRETO, Área de Seção Transversal do Componente: 0.0335 m2; EI-ISO-Impermeabilização 1, Área de Seção Transversal do Componente: 0.0033375 m2; EI-PIS-3-Cerâmica 45x45, Altura do Componente Retangular: 0.025 m; EI-PIS-3-Cerâmica 45x45, Largura do Componente Retangular: 0.665 m; EI-PIS-3-Cerâmica 45x45, Área de Seção Transversal do Componente: 0.016625 m2; EI-ISO-Impermeabilização 2, Área de Seção Transversal do Componente: 0.0015375 m2; TIJOLO - CERAMICO 9x19x39 - espessura 15cm 1, Área de Seção Transversal do Componente: 0.072 m2; EI-REV-Chapisco (interno) 1, Área de Seção Transversal do Componente: 0.0040125 m2; EI-REV-Emboço Interno 1, Área de Seção Transversal do Componente: 0.0040375 m2; EI-REV-Cerâmica 30x40 1, Área de Seção Transversal do Componente: 0.0158 m2; TIJOLO - CERAMICO 9x19x39 - espessura 15cm 2, Altura do Componente Retangular: 0.65 m; TIJOLO - CERAMICO 9x19x39 - espessura 15cm 2, Largura do Componente Retangular: 0.1 m; TIJOLO - CERAMICO 9x19x39 - espessura 15cm 2, Área de Seção Transversal do Componente: 0.065 m2; EI-REV-Chapisco (interno) 2, Área de Seção Transversal do Componente: 0.0014125 m2; EI-REV-Emboço Interno 2, Área de Seção Transversal do Componente: 0.0014375 m2; EI-REV-Cerâmica 30x40 2, Área de Seção Transversal do Componente: 0.0045 m2; EI-REV-Chapisco (interno) 3, Área de Seção Transversal do Componente: 0.000525 m2; EI-REV-Cerâmica 30x40 3, Área de Seção Transversal do Componente: 0.00205 m2; EI-REV-Chapisco (interno) 4, Área de Seção Transversal do Componente: 0.000750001 m2; EI-REV-Emboço Interno 4, Área de Seção Transversal do Componente: 0.00075 m2; EI-REV-Cerâmica 30x40 4, Área de Seção Transversal do Componente: 0.003 m2; EI-REV-Chapisco (interno) 5, Área de Seção Transversal do Componente: 0.000475 m2; EI-REV-Cerâmica 30x40 5, Área de Seção Transversal do Componente: 0.0026 m2
Name | 1_Bloco | FNDE-Enchimento, Massa (kg) | FNDE-Enchimento, Área de Componente Projetada (Líquida) (m2) = FNDE-Enchimento, Área de Componente Projetada (Bruta) (m2) = LASTRO DE CONCRETO, Área de Componente Projetada (Líquida) (m2) = LASTRO DE CONCRETO, Área de Componente Projetada (Bruta) (m2) = EI-ISO-Impermeabilização 1, Área de Componente Projetada (Líquida) (m2) = EI-ISO-Impermeabilização 1, Área de Componente Projetada (Bruta) (m2) | FNDE-Enchimento, Volume Componente (Líquido) (m3) = FNDE-Enchimento, Volume do componente (Bruto) (m3) | LASTRO DE CONCRETO, Massa (kg) | LASTRO DE CONCRETO, Volume Componente (Líquido) (m3) = LASTRO DE CONCRETO, Volume do componente (Bruto) (m3) | EI-ISO-Impermeabilização 1, Massa (kg) | EI-ISO-Impermeabilização 1, Volume Componente (Líquido) (m3) = EI-ISO-Impermeabilização 1, Volume do componente (Bruto) (m3) | EI-PIS-3-Cerâmica 45x45, Massa (kg) | EI-PIS-3-Cerâmica 45x45, Área de Componente Projetada (Líquida) (m2) = EI-PIS-3-Cerâmica 45x45, Área de Componente Projetada (Bruta) (m2) | EI-PIS-3-Cerâmica 45x45, Volume Componente (Líquido) (m3) | EI-PIS-3-Cerâmica 45x45, Volume do componente (Bruto) (m3) | EI-ISO-Impermeabilização 2, Massa (kg) | EI-ISO-Impermeabilização 2, Área de Componente Projetada (Líquida) (m2) = EI-ISO-Impermeabilização 2, Área de Componente Projetada (Bruta) (m2) | EI-ISO-Impermeabilização 2, Volume Componente (Líquido) (m3) = EI-ISO-Impermeabilização 2, Volume do componente (Bruto) (m3) | TIJOLO - CERAMICO 9x19x39 - espessura 15cm 1, Massa (kg) | TIJOLO - CERAMICO 9x19x39 - espessura 15cm 1, Área de Componente Projetada (Líquida) (m2) = TIJOLO - CERAMICO 9x19x39 - espessura 15cm 1, Área de Componente Projetada (Bruta) (m2) | TIJOLO - CERAMICO 9x19x39 - espessura 15cm 1, Volume Componente (Líquido) (m3) = TIJOLO - CERAMICO 9x19x39 - espessura 15cm 1, Volume do componente (Bruto) (m3) | EI-REV-Chapisco (interno) 1, Massa (kg) | EI-REV-Chapisco (interno) 1, Área de Componente Projetada (Líquida) (m2) = EI-REV-Chapisco (interno) 1, Área de Componente Projetada (Bruta) (m2) | EI-REV-Chapisco (interno) 1, Volume Componente (Líquido) (m3) = EI-REV-Chapisco (interno) 1, Volume do componente (Bruto) (m3) | EI-REV-Emboço Interno 1, Massa (kg) | EI-REV-Emboço Interno 1, Área de Componente Projetada (Líquida) (m2) = EI-REV-Emboço Interno 1, Área de Componente Projetada (Bruta) (m2) | EI-REV-Emboço Interno 1, Volume Componente (Líquido) (m3) = EI-REV-Emboço Interno 1, Volume do componente (Bruto) (m3) | EI-REV-Cerâmica 30x40 1, Massa (kg) | EI-REV-Cerâmica 30x40 1, Área de Componente Projetada (Líquida) (m2) = EI-REV-Cerâmica 30x40 1, Área de Componente Projetada (Bruta) (m2) | EI-REV-Cerâmica 30x40 1, Volume Componente (Líquido) (m3) = EI-REV-Cerâmica 30x40 1, Volume do componente (Bruto) (m3) | TIJOLO - CERAMICO 9x19x39 - espessura 15cm 2, Massa (kg) | TIJOLO - CERAMICO 9x19x39 - espessura 15cm 2, Área de Componente Projetada (Líquida) (m2) = TIJOLO - CERAMICO 9x19x39 - espessura 15cm 2, Área de Componente Projetada (Bruta) (m2) | TIJOLO - CERAMICO 9x19x39 - espessura 15cm 2, Volume Componente (Líquido) (m3) = TIJOLO - CERAMICO 9x19x39 - espessura 15cm 2, Volume do componente (Bruto) (m3) | EI-REV-Chapisco (interno) 2, Massa (kg) | EI-REV-Chapisco (interno) 2, Área de Componente Projetada (Líquida) (m2) = EI-REV-Chapisco (interno) 2, Área de Componente Projetada (Bruta) (m2) | EI-REV-Chapisco (interno) 2, Volume Componente (Líquido) (m3) = EI-REV-Chapisco (interno) 2, Volume do componente (Bruto) (m3) | EI-REV-Emboço Interno 2, Massa (kg) | EI-REV-Emboço Interno 2, Área de Componente Projetada (Líquida) (m2) = EI-REV-Emboço Interno 2, Área de Componente Projetada (Bruta) (m2) | EI-REV-Emboço Interno 2, Volume Componente (Líquido) (m3) = EI-REV-Emboço Interno 2, Volume do componente (Bruto) (m3) | EI-REV-Cerâmica 30x40 2, Massa (kg) | EI-REV-Cerâmica 30x40 2, Área de Componente Projetada (Líquida) (m2) = EI-REV-Cerâmica 30x40 2, Área de Componente Projetada (Bruta) (m2) | EI-REV-Cerâmica 30x40 2, Volume Componente (Líquido) (m3) = EI-REV-Cerâmica 30x40 2, Volume do componente (Bruto) (m3) | EI-REV-Chapisco (interno) 3, Massa (kg) | EI-REV-Chapisco (interno) 3, Área de Componente Projetada (Líquida) (m2) = EI-REV-Chapisco (interno) 3, Área de Componente Projetada (Bruta) (m2) | EI-REV-Chapisco (interno) 3, Volume Componente (Líquido) (m3) = EI-REV-Chapisco (interno) 3, Volume do componente (Bruto) (m3) | EI-REV-Cerâmica 30x40 3, Massa (kg) | EI-REV-Cerâmica 30x40 3, Área de Componente Projetada (Líquida) (m2) = EI-REV-Cerâmica 30x40 3, Área de Componente Projetada (Bruta) (m2) | EI-REV-Cerâmica 30x40 3, Volume Componente (Líquido) (m3) = EI-REV-Cerâmica 30x40 3, Volume do componente (Bruto) (m3) | EI-REV-Chapisco (interno) 4, Massa (kg) | EI-REV-Chapisco (interno) 4, Área de Componente Projetada (Líquida) (m2) = EI-REV-Chapisco (interno) 4, Área de Componente Projetada (Bruta) (m2) | EI-REV-Chapisco (interno) 4, Volume Componente (Líquido) (m3) = EI-REV-Chapisco (interno) 4, Volume do componente (Bruto) (m3) | EI-REV-Emboço Interno 4, Massa (kg) | EI-REV-Emboço Interno 4, Área de Componente Projetada (Líquida) (m2) = EI-REV-Emboço Interno 4, Área de Componente Projetada (Bruta) (m2) | EI-REV-Emboço Interno 4, Volume Componente (Líquido) (m3) = EI-REV-Emboço Interno 4, Volume do componente (Bruto) (m3) | EI-REV-Cerâmica 30x40 4, Massa (kg) | EI-REV-Cerâmica 30x40 4, Área de Componente Projetada (Líquida) (m2) = EI-REV-Cerâmica 30x40 4, Área de Componente Projetada (Bruta) (m2) | EI-REV-Cerâmica 30x40 4, Volume Componente (Líquido) (m3) = EI-REV-Cerâmica 30x40 4, Volume do componente (Bruto) (m3) | EI-REV-Chapisco (interno) 5, Massa (kg) | EI-REV-Chapisco (interno) 5, Área de Componente Projetada (Líquida) (m2) = EI-REV-Chapisco (interno) 5, Área de Componente Projetada (Bruta) (m2) | EI-REV-Chapisco (interno) 5, Volume Componente (Líquido) (m3) = EI-REV-Chapisco (interno) 5, Volume do componente (Bruto) (m3) | EI-REV-Cerâmica 30x40 5, Massa (kg) | EI-REV-Cerâmica 30x40 5, Área de Componente Projetada (Líquida) (m2) = EI-REV-Cerâmica 30x40 5, Área de Componente Projetada (Bruta) (m2) | EI-REV-Cerâmica 30x40 5, Volume Componente (Líquido) (m3) = EI-REV-Cerâmica 30x40 5, Volume do componente (Bruto) (m3)
 | BLOCO B | 408.909 | 0.94002 | 0.272606 | 84.6018 | 0.047001 | 5.15073 | 0.00468248 | 45.6497 | 0.93297 | 0.0228248 | 0.0233242 | 2.38471 | 0.437108 | 0.00216791 | 65.7862 | 1.12802 | 0.101522 | 7.0801 | 1.09277 | 0.00544623 | 7.12593 | 1.09982 | 0.00548148 | 43.9928 | 1.09982 | 0.0219964 | 59.3903 | 0.916518 | 0.0916518 | 2.58917 | 0.401858 | 0.00199167 | 2.63499 | 0.408908 | 0.00202691 | 12.6902 | 0.437108 | 0.00634512 | 0.962343 | 0.155103 | 0.000740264 | 5.78111 | 0.169203 | 0.00289056 | 1.37478 | 0.218554 | 0.00105752 | 1.37478 | 0.218554 | 0.00105752 | 7.89615 | 0.211504 | 0.00394808 | 0.870692 | 0.141003 | 0.000669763 | 0 | 0 | 0 | Component Quantities - EI-REV-Emboço Interno 3, Massa: 0.962344 kg; EI-REV-Emboço Interno 3, Área de Componente Projetada (Líquida): 0.155103 m2; EI-REV-Emboço Interno 3, Área de Componente Projetada (Bruta): 0.155103 m2; EI-REV-Emboço Interno 3, Área de Seção Transversal do Componente: 0.000525 m2; EI-REV-Emboço Interno 3, Volume Componente (Líquido): 0.000740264 m3; EI-REV-Emboço Interno 3, Volume do componente (Bruto): 0.000740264 m3; EI-REV-Emboço Interno 3: 2 with these values
 | BLOCO A | 177.892 | 0.408947 | 0.118595 | 36.8053 | 0.0204474 | 2.24082 | 0.00203711 | 20.2948 | 0.405895 | 0.0101474 | 0.0101474 | 1.03229 | 0.189214 | 0.000938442 | 28.4774 | 0.488295 | 0.0439466 | 3.06482 | 0.473036 | 0.00235755 | 3.08466 | 0.476088 | 0.00237281 | 19.2266 | 0.482192 | 0.00961332 | 25.7087 | 0.39674 | 0.039674 | 1.12079 | 0.173955 | 0.000862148 | 1.14063 | 0.177007 | 0.000877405 | 5.49332 | 0.189214 | 0.00274666 | 0.416577 | 0.0671406 | 0.000320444 | 2.50251 | 0.0732443 | 0.00125126 | 0.59511 | 0.0946072 | 0.000457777 | 0.59511 | 0.0946072 | 0.000457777 | 3.60118 | 0.0976591 | 0.00180059 | 0.376903 | 0.0610369 | 0.000289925 | 1.46489 | 0.0793481 | 0.000732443 | Component Quantities - EI-REV-Chapisco (interno) 3: 3 with these values
 | BLOCO B | 0 | 0 | 0 | 0 | 0 | 0 | 0 | 0 | 0 | 0 | 0 | 0 | 0 | 0 | 0.0489972 | 1.12802 | 0.0000756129 | 0 | 0 | 0 | 0 | 0 | 0 | 0.147445 | 1.09982 | 0.0000737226 | 0 | 0 | 0 | 0 | 0 | 0 | 0 | 0 | 0 | 0.0548193 | 0.408908 | 0.0000274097 | 0 | 0 | 0 | 0.00000633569 | 0.0000945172 | 3.16785e-09 | 0 | 0 | 0 | 0 | 0 | 0 | 0.0283485 | 0.211504 | 0.0000141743 | 0 | 0 | 0 | 0 | 0 | 0 | Component Quantities - EI-REV-Chapisco (interno) 3: 3 with these values
 | BLOCO B | 408.901 | 0.940002 | 0.272601 | 84.6002 | 0.0470001 | 5.15063 | 0.00468239 | 45.6488 | 0.932952 | 0.0228244 | 0.0233238 | 2.38471 | 0.437108 | 0.00216791 | 65.7862 | 1.12802 | 0.101522 | 6.98549 | 1.09277 | 0.00537345 | 7.12593 | 1.09982 | 0.00548148 | 43.9928 | 1.09982 | 0.0219964 | 59.3903 | 0.916518 | 0.0916518 | 2.58917 | 0.401858 | 0.00199167 | 2.59936 | 0.408813 | 0.00199951 | 12.6902 | 0.437108 | 0.00634512 | 0.962343 | 0.155103 | 0.000740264 | 5.78111 | 0.169203 | 0.00289056 | 1.37478 | 0.218554 | 0.00105752 | 1.35635 | 0.21846 | 0.00104335 | 7.89615 | 0.211504 | 0.00394808 | 0.870692 | 0.141003 | 0.000669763 | 0 | 0 | 0 | Component Quantities - EI-REV-Emboço Interno 3, Massa: 0.962339 kg; EI-REV-Emboço Interno 3, Área de Componente Projetada (Líquida): 0.155008 m2; EI-REV-Emboço Interno 3, Área de Componente Projetada (Bruta): 0.155008 m2; EI-REV-Emboço Interno 3, Área de Seção Transversal do Componente: 0.000525 m2; EI-REV-Emboço Interno 3, Volume Componente (Líquido): 0.000740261 m3; EI-REV-Emboço Interno 3, Volume do componente (Bruto): 0.000740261 m3; EI-REV-Emboço Interno 3: 2 with these values

# IfcCovering: FNDE-FOR_FOR-MSA-PTA 15 (29)
In: TÉRREO
Type - PredefinedType: CEILING
Classification: Forro (Classificação Archicad); Material: EI-REV-Pintura PVA Cor Branco Neve, EI-REV-Massa Corrida PVA (interna), EI-FOR-2-Forro de Gesso Acartonado
Pset_CoveringCommon - Material: FNDE-FOR_FOR-MSA-PTA
Component Quantities - EI-FOR-2-Forro de Gesso Acartonado, Espessura do Componente: 0.01 m; EI-REV-Massa Corrida PVA (interna), Espessura do Componente: 0.0025 m; EI-REV-Massa Corrida PVA (interna): 2 with these values
Name | 1_Bloco | 0_ID | EI-FOR-2-Forro de Gesso Acartonado, Massa (kg) | EI-FOR-2-Forro de Gesso Acartonado, Área de Componente Projetada (Líquida) (m2) = EI-FOR-2-Forro de Gesso Acartonado, Área de Componente Projetada (Bruta) (m2) | EI-FOR-2-Forro de Gesso Acartonado, Volume Componente (Líquido) (m3) = EI-FOR-2-Forro de Gesso Acartonado, Volume do componente (Bruto) (m3) | EI-REV-Massa Corrida PVA (interna), Massa (kg) | EI-REV-Massa Corrida PVA (interna), Área de Componente Projetada (Líquida) (m2) = EI-REV-Massa Corrida PVA (interna), Área de Componente Projetada (Bruta) (m2) | EI-REV-Massa Corrida PVA (interna), Volume Componente (Líquido) (m3) = EI-REV-Massa Corrida PVA (interna), Volume do componente (Bruto) (m3)
Forro-014 | BLOCO B | Forro-014 | 137.389 | 15.2655 | 0.152655 | 49.6127 | 15.2655 | 0.0381636
Forro-014 | BLOCO B | Forro-014 | 64.1341 | 7.12602 | 0.0712602 | 23.1596 | 7.12602 | 0.017815
Forro-015 | BLOCO B | Forro-015 | 232.503 | 25.8337 | 0.258337 | 83.9594 | 25.8337 | 0.0645841
Forro-015 | BLOCO B | Forro-015 | 232.509 | 25.8344 | 0.258344 | 83.9617 | 25.8344 | 0.0645859
Forro-014 | BLOCO B | Forro-014 | 64.1342 | 7.12602 | 0.0712602 | 23.1596 | 7.12602 | 0.017815
Forro-011 | BLOCO A | Forro-011 | 106.085 | 11.7872 | 0.117872 | 38.3085 | 11.7872 | 0.0294681
Forro-015 | BLOCO A | Forro-015 | 239.183 | 26.5759 | 0.265759 | 86.3715 | 26.5759 | 0.0664397
Forro-014 | BLOCO A | Forro-014 | 23.8812 | 2.65346 | 0.0265346 | 8.62375 | 2.65346 | 0.00663365
Forro-015 | BLOCO A | Forro-015 | 23.8812 | 2.65347 | 0.0265347 | 8.62376 | 2.65347 | 0.00663366
Forro-016 | BLOCO A | Forro-016 | 51.198 | 5.68866 | 0.0568866 | 18.4882 | 5.68866 | 0.0142217
Forro-017 | BLOCO A | Forro-017 | 29.3192 | 3.25769 | 0.0325769 | 10.5875 | 3.25769 | 0.00814423
Forro-015 | BLOCO A | Forro-015 | 232.503 | 25.8337 | 0.258337 | 83.9594 | 25.8337 | 0.0645841
Forro-018 | BLOCO A | Forro-018 | 29.299 | 3.25545 | 0.0325545 | 10.5802 | 3.25545 | 0.00813862
Forro-019 | BLOCO A | Forro-019 | 64.1351 | 7.12612 | 0.0712612 | 23.1599 | 7.12612 | 0.0178153
Forro-020 | BLOCO A | Forro-020 | 56.3425 | 6.26028 | 0.0626028 | 20.3459 | 6.26028 | 0.0156507
Forro-021 | BLOCO A | Forro-021 | 175.828 | 19.5365 | 0.195365 | 63.4935 | 19.5365 | 0.0488412
Forro-022 | BLOCO A | Forro-022 | 0.000584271 | 0.0000656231 | 6.4919e-07 | 0.000213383 | 0.0000656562 | 1.64141e-07
Forro-001 | BLOCO B | Forro-001 | 553.614 | 61.5127 | 0.615127 | 199.916 | 61.5127 | 0.153782
Forro-001 | BLOCO A | Forro-001 | 602.408 | 66.9342 | 0.669342 | 217.536 | 66.9342 | 0.167335
Forro-015 | BLOCO A | Forro-015 | 271.249 | 30.1388 | 0.301388 | 97.8489 | 30.1074 | 0.0752684
Forro-022 | BLOCO A | Forro-022 | 284.295 | 31.5883 | 0.315883 | 102.662 | 31.5883 | 0.0789707
Forro-015 | BLOCO A | Forro-015 | 85.2555 | 9.48511 | 0.0947283 | 30.8266 | 9.48511 | 0.0237128
Forro-001 | BLOCO A | Forro-001 | 37.8815 | 4.20905 | 0.0420905 | 13.6794 | 4.20905 | 0.0105226
Forro-014 | BLOCO B | Forro-014 | 136.823 | 15.2026 | 0.152026 | 49.4085 | 15.2026 | 0.0380065
Forro-014 | BLOCO B | Forro-014 | 13.1372 | 1.45968 | 0.0145968 | 4.74397 | 1.45968 | 0.00364921
Forro-022 | BLOCO A | Forro-022 | 19.4001 | 2.15819 | 0.0215556 | 7.01413 | 2.15819 | 0.00539548
Forro-001 | BLOCO B | Forro-001 | 3.51775 | 0.390861 | 0.00390861 | 1.2703 | 0.390861 | 0.000977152
Forro-001 | BLOCO B | Forro-001 | 3.51775 | 0.390861 | 0.00390861 | 1.2703 | 0.390861 | 0.000977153
Forro-001 | BLOCO B | Forro-001 | 37.8815 | 4.20905 | 0.0420905 | 13.6794 | 4.20905 | 0.0105226

# IfcCovering: FNDE-FOR_MSA-PTA 20, L01
In: TÉRREO
Type - PredefinedType: CEILING
Classification: Forro (Classificação Archicad); Material: EI-REV-Pintura PVA Cor Branco Neve, EI-REV-Massa Corrida PVA (interna)
Pset_CoveringCommon - Material: FNDE-FOR_MSA-PTA
FNDE - 1_Bloco: CASA DE BOMBAS / GÁS / LIXO; 0_ID: L01
Component Quantities - EI-REV-Massa Corrida PVA (interna), Massa: 144.869 kg; EI-REV-Massa Corrida PVA (interna), Área de Componente Projetada (Líquida): 11.1438 m2; EI-REV-Massa Corrida PVA (interna), Área de Componente Projetada (Bruta): 11.1438 m2; EI-REV-Massa Corrida PVA (interna), Espessura do Componente: 0.01 m; EI-REV-Massa Corrida PVA (interna), Volume Componente (Líquido): 0.111438 m3; EI-REV-Massa Corrida PVA (interna), Volume do componente (Bruto): 0.111438 m3; EI-REV-Pintura PVA Cor Branco Neve, Massa: 147.548 kg; EI-REV-Pintura PVA Cor Branco Neve, Área de Componente Projetada (Líquida): 11.3498 m2; EI-REV-Pintura PVA Cor Branco Neve, Área de Componente Projetada (Bruta): 11.3498 m2; EI-REV-Pintura PVA Cor Branco Neve, Espessura do Componente: 0.01 m; EI-REV-Pintura PVA Cor Branco Neve, Volume Componente (Líquido): 0.113498 m3; EI-REV-Pintura PVA Cor Branco Neve, Volume do componente (Bruto): 0.113498 m3

# IfcCovering: FNDE-PIS_EXT_AREIA 350, L01
In: TÉRREO
Classification: Piso (Acabamento) (Classificação Archicad); Material: COMPACTAÇÃO DE SOLO, EI-PIS-7-Areia
Pset_CoveringCommon - Material: FNDE-PIS_EXT_AREIA
FNDE - 1_Bloco: ÁREAS EXTERNAS; 0_ID: L01
Component Quantities - EI-PIS-7-Areia, Massa: 40132.6 kg; EI-PIS-7-Areia, Área de Componente Projetada (Líquida): 53.7394 m2; EI-PIS-7-Areia, Área de Componente Projetada (Bruta): 53.7394 m2; EI-PIS-7-Areia, Espessura do Componente: 0.34 m; EI-PIS-7-Areia, Volume Componente (Líquido): 18.2421 m3; EI-PIS-7-Areia, Volume do componente (Bruto): 18.2421 m3; COMPACTAÇÃO DE SOLO, Massa: 967.309 kg; COMPACTAÇÃO DE SOLO, Área de Componente Projetada (Líquida): 53.7394 m2; COMPACTAÇÃO DE SOLO, Área de Componente Projetada (Bruta): 53.7394 m2; COMPACTAÇÃO DE SOLO, Espessura do Componente: 0.01 m; COMPACTAÇÃO DE SOLO, Volume Componente (Líquido): 0.537394 m3; COMPACTAÇÃO DE SOLO, Volume do componente (Bruto): 0.537394 m3
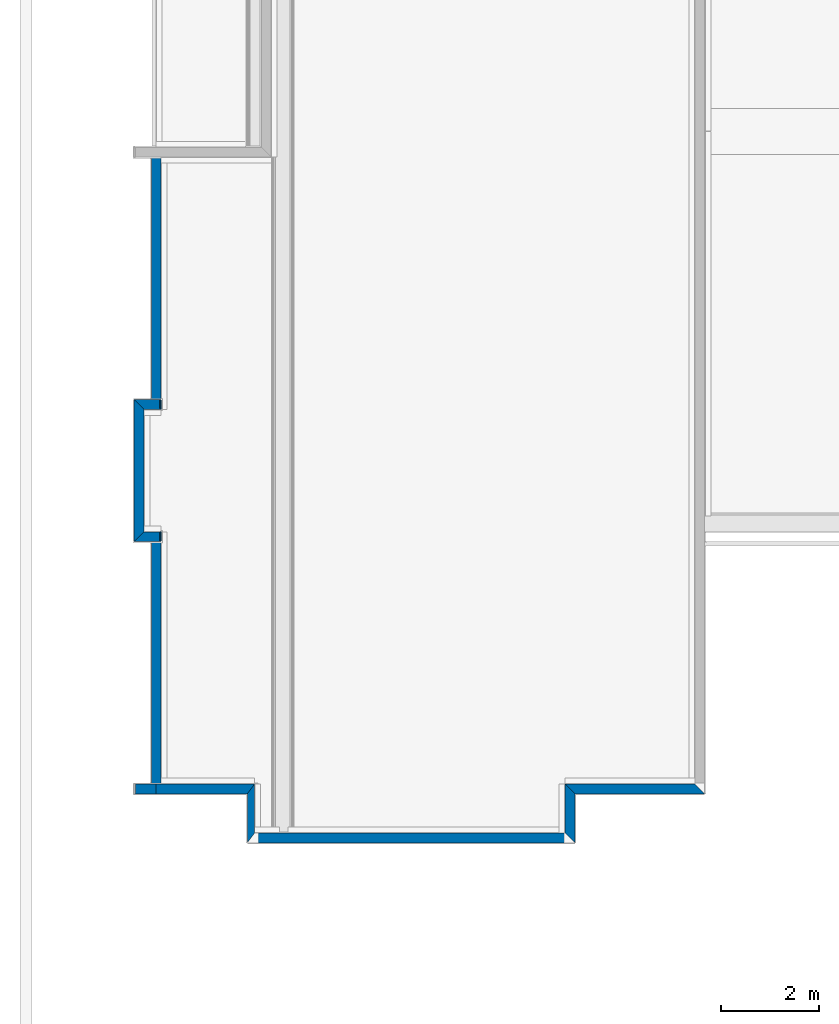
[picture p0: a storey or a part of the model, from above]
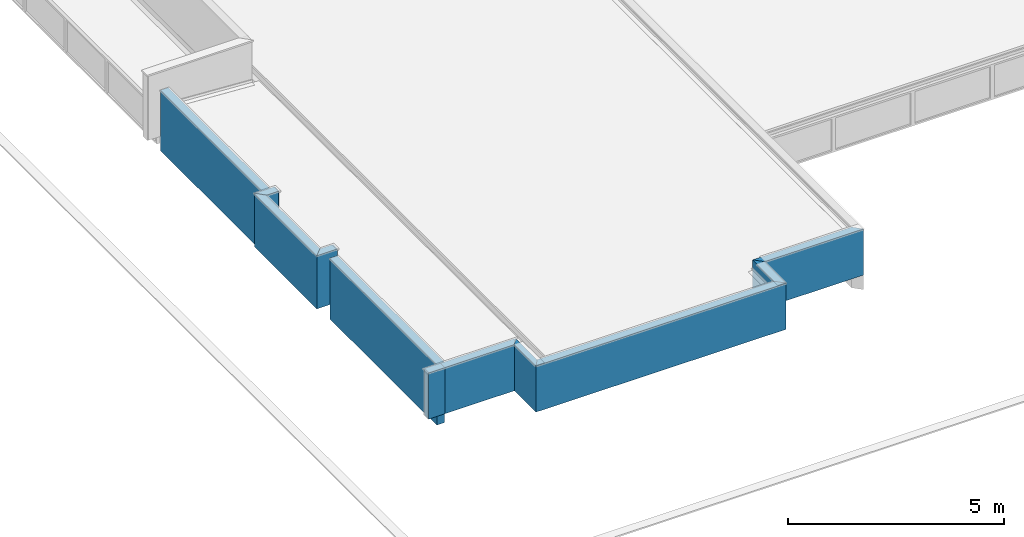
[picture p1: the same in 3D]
Properties of the parts of a building model (IFC4), part 2 of 22

# IfcCovering: FNDE-PIS_EXT_CON (gás) 260, L01
In: TÉRREO
Classification: Piso (Acabamento) (Classificação Archicad); Material: COMPACTAÇÃO DE SOLO, LASTRO DE BRITA, EI-PIS-1-Passeio de Concreto desempenado
Pset_CoveringCommon - Material: FNDE-PIS_EXT_CON (gás)
FNDE - 1_Bloco: CASA DE BOMBAS / GÁS / LIXO; 0_ID: L01
Component Quantities - EI-PIS-1-Passeio de Concreto desempenado, Massa: 410.551 kg; EI-PIS-1-Passeio de Concreto desempenado, Área de Componente Projetada (Líquida): 1.52056 m2; EI-PIS-1-Passeio de Concreto desempenado, Área de Componente Projetada (Bruta): 1.32846 m2; EI-PIS-1-Passeio de Concreto desempenado, Espessura do Componente: 0.15 m; EI-PIS-1-Passeio de Concreto desempenado, Volume Componente (Líquido): 0.228084 m3; EI-PIS-1-Passeio de Concreto desempenado, Volume do componente (Bruto): 0.199269 m3; LASTRO DE BRITA, Massa: 319.142 kg; LASTRO DE BRITA, Área de Componente Projetada (Líquida): 1.77301 m2; LASTRO DE BRITA, Área de Componente Projetada (Bruta): 1.77301 m2; LASTRO DE BRITA, Espessura do Componente: 0.1 m; LASTRO DE BRITA, Volume Componente (Líquido): 0.177301 m3; LASTRO DE BRITA, Volume do componente (Bruto): 0.177301 m3; COMPACTAÇÃO DE SOLO, Massa: 31.9142 kg; COMPACTAÇÃO DE SOLO, Área de Componente Projetada (Líquida): 1.77301 m2; COMPACTAÇÃO DE SOLO, Área de Componente Projetada (Bruta): 1.77301 m2; COMPACTAÇÃO DE SOLO, Espessura do Componente: 0.01 m; COMPACTAÇÃO DE SOLO, Volume Componente (Líquido): 0.0177301 m3; COMPACTAÇÃO DE SOLO, Volume do componente (Bruto): 0.0177301 m3

# IfcCovering: FNDE-PIS_EXT_CON 190 (14)
In: TÉRREO
Classification: Piso (Acabamento) (Classificação Archicad); Material: COMPACTAÇÃO DE SOLO, LASTRO DE BRITA, EI-PIS-1-Passeio de Concreto desempenado
Pset_CoveringCommon - Material: FNDE-PIS_EXT_CON
FNDE - 1_Bloco: ÁREAS EXTERNAS; 0_ID: L01
Component Quantities - EI-PIS-1-Passeio de Concreto desempenado, Espessura do Componente: 0.08 m; LASTRO DE BRITA, Espessura do Componente: 0.1 m; COMPACTAÇÃO DE SOLO, Espessura do Componente: 0.01 m
Name | EI-PIS-1-Passeio de Concreto desempenado, Massa (kg) | EI-PIS-1-Passeio de Concreto desempenado, Área de Componente Projetada (Líquida) (m2) | EI-PIS-1-Passeio de Concreto desempenado, Área de Componente Projetada (Bruta) (m2) | EI-PIS-1-Passeio de Concreto desempenado, Volume Componente (Líquido) (m3) | EI-PIS-1-Passeio de Concreto desempenado, Volume do componente (Bruto) (m3) | LASTRO DE BRITA, Massa (kg) | LASTRO DE BRITA, Área de Componente Projetada (Líquida) (m2) = COMPACTAÇÃO DE SOLO, Área de Componente Projetada (Líquida) (m2) | LASTRO DE BRITA, Área de Componente Projetada (Bruta) (m2) = COMPACTAÇÃO DE SOLO, Área de Componente Projetada (Bruta) (m2) | LASTRO DE BRITA, Volume Componente (Líquido) (m3) | LASTRO DE BRITA, Volume do componente (Bruto) (m3) | COMPACTAÇÃO DE SOLO, Massa (kg) | COMPACTAÇÃO DE SOLO, Volume Componente (Líquido) (m3) | COMPACTAÇÃO DE SOLO, Volume do componente (Bruto) (m3)
L01 | 1951.12 | 13.5495 | 13.5495 | 1.08396 | 1.08396 | 2438.9 | 13.5495 | 13.5495 | 1.35495 | 1.35495 | 243.89 | 0.135495 | 0.135495
L01 | 2538.16 | 17.6261 | 17.6261 | 1.41009 | 1.41009 | 3172.7 | 17.6261 | 17.6261 | 1.76261 | 1.76261 | 317.27 | 0.176261 | 0.176261
L01 | 2575.54 | 17.9177 | 17.9177 | 1.43086 | 1.43086 | 3221.05 | 17.8947 | 17.8947 | 1.78947 | 1.78947 | 322.105 | 0.178947 | 0.178947
L01 | 704.537 | 4.89262 | 4.89262 | 0.391409 | 0.391409 | 880.671 | 4.89262 | 4.89262 | 0.489262 | 0.489262 | 88.0671 | 0.0489262 | 0.0489262
L01 | 1686.56 | 11.7122 | 11.7122 | 0.936977 | 0.936977 | 2108.2 | 11.7122 | 11.7122 | 1.17122 | 1.17122 | 210.82 | 0.117122 | 0.117122
L01 | 1835.35 | 12.7455 | 12.7455 | 1.01964 | 1.01964 | 2294.19 | 12.7455 | 12.7455 | 1.27455 | 1.27455 | 229.419 | 0.127455 | 0.127455
L01 | 24566.6 | 170.602 | 170.619 | 13.6481 | 13.6496 | 30708.4 | 170.606 | 170.623 | 17.0602 | 17.062 | 3070.9 | 1.70606 | 1.70623
L01 | 0.0102946 | 0.00007149 | 0.00007149 | 0.0000057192 | 0.0000057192 | 0.0128682 | 0.00007149 | 0.00007149 | 0.000007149 | 0.000007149 | 0.00128682 | 7.149e-07 | 7.149e-07
L01 | 734.98 | 5.10402 | 5.10402 | 0.408322 | 0.408322 | 918.724 | 5.10402 | 5.10402 | 0.510402 | 0.510402 | 91.8724 | 0.0510402 | 0.0510402
L01 | 3144.93 | 21.8398 | 21.8398 | 1.74718 | 1.74718 | 3931.16 | 21.8398 | 21.8398 | 2.18398 | 2.18398 | 393.116 | 0.218398 | 0.218398
L01 | 8501.7 | 59.4451 | 75.104 | 4.72317 | 5.97588 | 10586.2 | 58.8123 | 74.4712 | 5.88123 | 7.44712 | 1058.62 | 0.588123 | 0.744712
L01 | 1982.28 | 13.7658 | 13.7658 | 1.10126 | 1.10126 | 2477.85 | 13.7658 | 13.7658 | 1.37658 | 1.37658 | 247.785 | 0.137658 | 0.137658
L01 | 51.6327 | 0.35856 | 0.35856 | 0.0286848 | 0.0286848 | 64.5409 | 0.35856 | 0.35856 | 0.035856 | 0.035856 | 6.45409 | 0.0035856 | 0.0035856
L01 | 1522.39 | 10.5722 | 10.5722 | 0.845774 | 0.845774 | 1902.99 | 10.5722 | 10.5722 | 1.05722 | 1.05722 | 190.299 | 0.105722 | 0.105722

# IfcCovering: FNDE-PIS_INT_DIV_CER45 261 (3)
In: TÉRREO
Classification: Piso (Acabamento) (Classificação Archicad); Material: COMPACTAÇÃO DE SOLO, LASTRO DE BRITA, CAMADA SEPARADORA EM LONA PLÁSTICA, LASTRO DE CONCRETO, EI-PIS-Contrapiso Áreas secas, EI-PIS-3-Cerâmica 45x45
Pset_CoveringCommon - Material: FNDE-PIS_INT_DIV_CER45
Component Quantities - EI-PIS-3-Cerâmica 45x45, Espessura do Componente: 0.04 m; EI-PIS-Contrapiso Áreas secas, Espessura do Componente: 0.03 m; LASTRO DE CONCRETO, Espessura do Componente: 0.08 m; CAMADA SEPARADORA EM LONA PLÁSTICA, Espessura do Componente: 0.001 m; LASTRO DE BRITA, Espessura do Componente: 0.1 m; COMPACTAÇÃO DE SOLO, Espessura do Componente: 0.01 m
Name | 1_Bloco | 0_ID | EI-PIS-3-Cerâmica 45x45, Massa (kg) | EI-PIS-3-Cerâmica 45x45, Área de Componente Projetada (Líquida) (m2) = EI-PIS-3-Cerâmica 45x45, Área de Componente Projetada (Bruta) (m2) | EI-PIS-3-Cerâmica 45x45, Volume Componente (Líquido) (m3) = EI-PIS-3-Cerâmica 45x45, Volume do componente (Bruto) (m3) | EI-PIS-Contrapiso Áreas secas, Massa (kg) | EI-PIS-Contrapiso Áreas secas, Área de Componente Projetada (Líquida) (m2) = EI-PIS-Contrapiso Áreas secas, Área de Componente Projetada (Bruta) (m2) = LASTRO DE CONCRETO, Área de Componente Projetada (Líquida) (m2) = LASTRO DE CONCRETO, Área de Componente Projetada (Bruta) (m2) = CAMADA SEPARADORA EM LONA PLÁSTICA, Área de Componente Projetada (Líquida) (m2) = CAMADA SEPARADORA EM LONA PLÁSTICA, Área de Componente Projetada (Bruta) (m2) = LASTRO DE BRITA, Área de Componente Projetada (Líquida) (m2) = LASTRO DE BRITA, Área de Componente Projetada (Bruta) (m2) = COMPACTAÇÃO DE SOLO, Área de Componente Projetada (Líquida) (m2) = COMPACTAÇÃO DE SOLO, Área de Componente Projetada (Bruta) (m2) | EI-PIS-Contrapiso Áreas secas, Volume Componente (Líquido) (m3) = EI-PIS-Contrapiso Áreas secas, Volume do componente (Bruto) (m3) | LASTRO DE CONCRETO, Massa (kg) | LASTRO DE CONCRETO, Volume Componente (Líquido) (m3) = LASTRO DE CONCRETO, Volume do componente (Bruto) (m3) | CAMADA SEPARADORA EM LONA PLÁSTICA, Massa (kg) | CAMADA SEPARADORA EM LONA PLÁSTICA, Volume Componente (Líquido) (m3) = CAMADA SEPARADORA EM LONA PLÁSTICA, Volume do componente (Bruto) (m3) | LASTRO DE BRITA, Massa (kg) | LASTRO DE BRITA, Volume Componente (Líquido) (m3) = LASTRO DE BRITA, Volume do componente (Bruto) (m3) | COMPACTAÇÃO DE SOLO, Massa (kg) | COMPACTAÇÃO DE SOLO, Volume Componente (Líquido) (m3) = COMPACTAÇÃO DE SOLO, Volume do componente (Bruto) (m3)
L26 | BLOCO A | L26 | 412.646 | 6.03857 | 0.206323 | 310.198 | 5.7444 | 0.172332 | 827.194 | 0.459552 | 10.3399 | 0.0057444 | 1033.99 | 0.57444 | 103.399 | 0.057444
L13 | BLOCO B | L13 | 611.584 | 7.65007 | 0.305792 | 393.005 | 7.27787 | 0.218336 | 1048.01 | 0.582229 | 13.1002 | 0.00727787 | 1310.02 | 0.727787 | 131.002 | 0.0727787
L26 | BLOCO A | L26 | 1560.05 | 20.2701 | 0.780023 | 1065.36 | 19.7288 | 0.591864 | 2840.95 | 1.5783 | 35.5119 | 0.0197288 | 3551.19 | 1.97288 | 355.119 | 0.197288

# IfcCovering: FNDE-PIS_INT_DIV_CER60 252 (3)
In: TÉRREO
Classification: Piso (Acabamento) (Classificação Archicad); Material: COMPACTAÇÃO DE SOLO, LASTRO DE BRITA, CAMADA SEPARADORA EM LONA PLÁSTICA, LASTRO DE CONCRETO, EI-PIS-Contrapiso Áreas secas, EI-PIS-4-Cerâmica 60x60
Pset_CoveringCommon - Material: FNDE-PIS_INT_DIV_CER60
FNDE - 1_Bloco: BLOCO A
Component Quantities - EI-PIS-4-Cerâmica 60x60, Espessura do Componente: 0.04 m; EI-PIS-Contrapiso Áreas secas, Espessura do Componente: 0.03 m; LASTRO DE CONCRETO, Espessura do Componente: 0.08 m; CAMADA SEPARADORA EM LONA PLÁSTICA, Espessura do Componente: 0.001 m; LASTRO DE BRITA, Espessura do Componente: 0.1 m; CAMADA SEPARADORA EM LONA PLÁSTICA: 2 with these values
Name | 0_ID | EI-PIS-4-Cerâmica 60x60, Massa (kg) | EI-PIS-4-Cerâmica 60x60, Área de Componente Projetada (Líquida) (m2) = EI-PIS-4-Cerâmica 60x60, Área de Componente Projetada (Bruta) (m2) | EI-PIS-4-Cerâmica 60x60, Volume Componente (Líquido) (m3) = EI-PIS-4-Cerâmica 60x60, Volume do componente (Bruto) (m3) | EI-PIS-Contrapiso Áreas secas, Massa (kg) | EI-PIS-Contrapiso Áreas secas, Área de Componente Projetada (Líquida) (m2) = EI-PIS-Contrapiso Áreas secas, Área de Componente Projetada (Bruta) (m2) = LASTRO DE CONCRETO, Área de Componente Projetada (Líquida) (m2) = LASTRO DE CONCRETO, Área de Componente Projetada (Bruta) (m2) = CAMADA SEPARADORA EM LONA PLÁSTICA, Área de Componente Projetada (Líquida) (m2) = CAMADA SEPARADORA EM LONA PLÁSTICA, Área de Componente Projetada (Bruta) (m2) = LASTRO DE BRITA, Área de Componente Projetada (Líquida) (m2) = LASTRO DE BRITA, Área de Componente Projetada (Bruta) (m2) | EI-PIS-Contrapiso Áreas secas, Volume Componente (Líquido) (m3) = EI-PIS-Contrapiso Áreas secas, Volume do componente (Bruto) (m3) | LASTRO DE CONCRETO, Massa (kg) | LASTRO DE CONCRETO, Volume Componente (Líquido) (m3) = LASTRO DE CONCRETO, Volume do componente (Bruto) (m3) | CAMADA SEPARADORA EM LONA PLÁSTICA, Massa (kg) | CAMADA SEPARADORA EM LONA PLÁSTICA, Volume Componente (Líquido) (m3) = CAMADA SEPARADORA EM LONA PLÁSTICA, Volume do componente (Bruto) (m3) | LASTRO DE BRITA, Massa (kg) | LASTRO DE BRITA, Volume Componente (Líquido) (m3) = LASTRO DE BRITA, Volume do componente (Bruto) (m3)
L25 | L25 | 1535.99 | 19.2001 | 0.767993 | 1016.04 | 18.8155 | 0.564464 | 2709.43 | 1.50524 | 33.8678 | 0.0188155 | 3386.78 | 1.88155
L27 | L27 | 597.093 | 7.46396 | 0.298546 | 398.959 | 7.38813 | 0.221644 | 1063.89 | 0.59105 | 13.2986 | 0.00738813 | 1329.86 | 0.738813
L26 | L26 | 1295.98 | 16.2 | 0.647988 | 856.271 | 15.8569 | 0.475706 | 2283.39 | 1.26855 | 28.5424 | 0.0158569 | 2854.24 | 1.58569

# IfcCovering: FNDE-PIS_INT_DIV_GRA 229 (7)
In: TÉRREO
Classification: Piso (Acabamento) (Classificação Archicad); Material: COMPACTAÇÃO DE SOLO, LASTRO DE BRITA, CAMADA SEPARADORA EM LONA PLÁSTICA, LASTRO DE CONCRETO, EI-PIS-Contrapiso Áreas molhadas, EI-PIS-2-Granitina com juntas plásticas cor cinza
Pset_CoveringCommon - Material: FNDE-PIS_INT_DIV_GRA
FNDE - 0_ID: L09
Component Quantities - EI-PIS-2-Granitina com juntas plásticas cor cinza, Espessura do Componente: 0.008 m; EI-PIS-Contrapiso Áreas molhadas, Espessura do Componente: 0.03 m; LASTRO DE CONCRETO, Espessura do Componente: 0.08 m; CAMADA SEPARADORA EM LONA PLÁSTICA, Espessura do Componente: 0.001 m; LASTRO DE BRITA, Espessura do Componente: 0.1 m; COMPACTAÇÃO DE SOLO, Espessura do Componente: 0.01 m
Name | 1_Bloco | EI-PIS-2-Granitina com juntas plásticas cor cinza, Massa (kg) | EI-PIS-2-Granitina com juntas plásticas cor cinza, Área de Componente Projetada (Líquida) (m2) = EI-PIS-2-Granitina com juntas plásticas cor cinza, Área de Componente Projetada (Bruta) (m2) | EI-PIS-2-Granitina com juntas plásticas cor cinza, Volume Componente (Líquido) (m3) = EI-PIS-2-Granitina com juntas plásticas cor cinza, Volume do componente (Bruto) (m3) | EI-PIS-Contrapiso Áreas molhadas, Massa (kg) | EI-PIS-Contrapiso Áreas molhadas, Área de Componente Projetada (Líquida) (m2) = EI-PIS-Contrapiso Áreas molhadas, Área de Componente Projetada (Bruta) (m2) | EI-PIS-Contrapiso Áreas molhadas, Volume Componente (Líquido) (m3) = EI-PIS-Contrapiso Áreas molhadas, Volume do componente (Bruto) (m3) | LASTRO DE CONCRETO, Massa (kg) | LASTRO DE CONCRETO, Área de Componente Projetada (Líquida) (m2) = LASTRO DE CONCRETO, Área de Componente Projetada (Bruta) (m2) = CAMADA SEPARADORA EM LONA PLÁSTICA, Área de Componente Projetada (Líquida) (m2) = CAMADA SEPARADORA EM LONA PLÁSTICA, Área de Componente Projetada (Bruta) (m2) = LASTRO DE BRITA, Área de Componente Projetada (Líquida) (m2) = LASTRO DE BRITA, Área de Componente Projetada (Bruta) (m2) = COMPACTAÇÃO DE SOLO, Área de Componente Projetada (Líquida) (m2) = COMPACTAÇÃO DE SOLO, Área de Componente Projetada (Bruta) (m2) | LASTRO DE CONCRETO, Volume Componente (Líquido) (m3) = LASTRO DE CONCRETO, Volume do componente (Bruto) (m3) | CAMADA SEPARADORA EM LONA PLÁSTICA, Massa (kg) | CAMADA SEPARADORA EM LONA PLÁSTICA, Volume Componente (Líquido) (m3) = CAMADA SEPARADORA EM LONA PLÁSTICA, Volume do componente (Bruto) (m3) | LASTRO DE BRITA, Massa (kg) | LASTRO DE BRITA, Volume Componente (Líquido) (m3) = LASTRO DE BRITA, Volume do componente (Bruto) (m3) | COMPACTAÇÃO DE SOLO, Massa (kg) | COMPACTAÇÃO DE SOLO, Volume Componente (Líquido) (m3) = COMPACTAÇÃO DE SOLO, Volume do componente (Bruto) (m3)
L09 | BLOCO A | 387.797 | 26.9303 | 0.215443 | 1435.41 | 26.9303 | 0.79745 | 3689.69 | 25.6229 | 2.04983 | 46.1212 | 0.0256229 | 4612.12 | 2.56229 | 461.212 | 0.256229
L09 | BLOCO B | 399.497 | 27.7452 | 0.221943 | 1467.99 | 27.836 | 0.815547 | 3675.07 | 25.5213 | 2.0417 | 45.9383 | 0.0255213 | 4593.83 | 2.55213 | 459.383 | 0.255213
L09 | BLOCO B | 400.736 | 27.8313 | 0.222631 | 1472.29 | 27.9239 | 0.817939 | 3683.69 | 25.5812 | 2.04649 | 46.0461 | 0.0255812 | 4604.61 | 2.55812 | 460.461 | 0.255812
L09 | BLOCO A | 402.268 | 27.9353 | 0.223482 | 1499.38 | 27.9353 | 0.83299 | 3982.13 | 27.6537 | 2.2123 | 49.7766 | 0.0276537 | 4977.66 | 2.76537 | 497.766 | 0.276537
L09 | PÁTIO COBERTO | 2050.21 | 142.376 | 1.13901 | 7688.3 | 142.376 | 4.27128 | 20502.1 | 142.376 | 11.3901 | 256.277 | 0.142376 | 25627.7 | 14.2376 | 2562.77 | 1.42376
L09 | BLOCO B | 1085.09 | 75.3544 | 0.602827 | 4052.03 | 75.359 | 2.25113 | 10678.8 | 74.1584 | 5.93267 | 133.485 | 0.0741584 | 13348.5 | 7.41584 | 1334.85 | 0.741584
L09 | BLOCO A | 1569.29 | 108.979 | 0.871829 | 5843.4 | 108.979 | 3.24633 | 15278.4 | 106.1 | 8.48801 | 190.98 | 0.1061 | 19098 | 10.61 | 1909.8 | 1.061

# IfcCovering: FNDE-PIS_INT_IMP_CER45 236 (13)
In: TÉRREO
Classification: Piso (Acabamento) (Classificação Archicad); Material: COMPACTAÇÃO DE SOLO, LASTRO DE BRITA, CAMADA SEPARADORA EM LONA PLÁSTICA, LASTRO DE CONCRETO, EI-ISO-Impermeabilização, EI-PIS-Contrapiso Áreas molhadas, EI-PIS-3-Cerâmica 45x45
Pset_CoveringCommon - Material: FNDE-PIS_INT_IMP_CER45
Component Quantities - EI-PIS-3-Cerâmica 45x45, Espessura do Componente: 0.01 m; EI-PIS-Contrapiso Áreas molhadas, Espessura do Componente: 0.03 m; EI-ISO-Impermeabilização, Espessura do Componente: 0.005 m; LASTRO DE CONCRETO, Espessura do Componente: 0.08 m; CAMADA SEPARADORA EM LONA PLÁSTICA, Espessura do Componente: 0.001 m; LASTRO DE BRITA, Espessura do Componente: 0.1 m; COMPACTAÇÃO DE SOLO, Espessura do Componente: 0.01 m
Name | 1_Bloco | 0_ID | EI-PIS-3-Cerâmica 45x45, Massa (kg) | EI-PIS-3-Cerâmica 45x45, Área de Componente Projetada (Líquida) (m2) = EI-PIS-3-Cerâmica 45x45, Área de Componente Projetada (Bruta) (m2) | EI-PIS-3-Cerâmica 45x45, Volume Componente (Líquido) (m3) = EI-PIS-3-Cerâmica 45x45, Volume do componente (Bruto) (m3) | EI-PIS-Contrapiso Áreas molhadas, Massa (kg) | EI-PIS-Contrapiso Áreas molhadas, Área de Componente Projetada (Líquida) (m2) = EI-PIS-Contrapiso Áreas molhadas, Área de Componente Projetada (Bruta) (m2) | EI-PIS-Contrapiso Áreas molhadas, Volume Componente (Líquido) (m3) = EI-PIS-Contrapiso Áreas molhadas, Volume do componente (Bruto) (m3) | EI-ISO-Impermeabilização, Massa (kg) | EI-ISO-Impermeabilização, Área de Componente Projetada (Líquida) (m2) = EI-ISO-Impermeabilização, Área de Componente Projetada (Bruta) (m2) = LASTRO DE CONCRETO, Área de Componente Projetada (Líquida) (m2) = LASTRO DE CONCRETO, Área de Componente Projetada (Bruta) (m2) = CAMADA SEPARADORA EM LONA PLÁSTICA, Área de Componente Projetada (Líquida) (m2) = CAMADA SEPARADORA EM LONA PLÁSTICA, Área de Componente Projetada (Bruta) (m2) = LASTRO DE BRITA, Área de Componente Projetada (Líquida) (m2) = LASTRO DE BRITA, Área de Componente Projetada (Bruta) (m2) = COMPACTAÇÃO DE SOLO, Área de Componente Projetada (Líquida) (m2) = COMPACTAÇÃO DE SOLO, Área de Componente Projetada (Bruta) (m2) | EI-ISO-Impermeabilização, Volume Componente (Líquido) (m3) = EI-ISO-Impermeabilização, Volume do componente (Bruto) (m3) | LASTRO DE CONCRETO, Massa (kg) | LASTRO DE CONCRETO, Volume Componente (Líquido) (m3) = LASTRO DE CONCRETO, Volume do componente (Bruto) (m3) | CAMADA SEPARADORA EM LONA PLÁSTICA, Massa (kg) | CAMADA SEPARADORA EM LONA PLÁSTICA, Volume Componente (Líquido) (m3) = CAMADA SEPARADORA EM LONA PLÁSTICA, Volume do componente (Bruto) (m3) | LASTRO DE BRITA, Massa (kg) | LASTRO DE BRITA, Volume Componente (Líquido) (m3) = LASTRO DE BRITA, Volume do componente (Bruto) (m3) | COMPACTAÇÃO DE SOLO, Massa (kg) | COMPACTAÇÃO DE SOLO, Volume Componente (Líquido) (m3) = COMPACTAÇÃO DE SOLO, Volume do componente (Bruto) (m3)
L26 | BLOCO A | L26 | 545.515 | 27.2764 | 0.272758 | 1583.7 | 34.2288 | 0.879831 | 181.998 | 33.0906 | 0.165453 | 4765.05 | 2.64725 | 59.5631 | 0.0330906 | 5956.31 | 3.30906 | 595.631 | 0.330906
L27 | BLOCO A | L27 | 57.6811 | 2.88406 | 0.0288406 | 152.858 | 2.88406 | 0.0849208 | 14.9818 | 2.72397 | 0.0136199 | 392.252 | 0.217918 | 4.90315 | 0.00272397 | 490.315 | 0.272397 | 49.0315 | 0.0272397
L23 | BLOCO B | L23 | 150.027 | 7.50137 | 0.0750137 | 399.796 | 7.50947 | 0.222109 | 39.6003 | 7.20005 | 0.0360002 | 1036.81 | 0.576004 | 12.9601 | 0.00720005 | 1296.01 | 0.720005 | 129.601 | 0.0720005
L23 | BLOCO B | L23 | 284.078 | 14.2039 | 0.142039 | 769.393 | 15.817 | 0.427441 | 78.577 | 14.2867 | 0.0714336 | 2057.29 | 1.14294 | 25.7161 | 0.0142867 | 2571.61 | 1.42867 | 257.161 | 0.142867
L23 | BLOCO B | L23 | 283.4 | 14.17 | 0.1417 | 769.867 | 15.827 | 0.427704 | 79.0967 | 14.3812 | 0.0719061 | 2070.9 | 1.1505 | 25.8862 | 0.0143812 | 2588.62 | 1.43812 | 258.862 | 0.143812
L28 | BLOCO A | L28 | 57.6811 | 2.88406 | 0.0288406 | 152.898 | 2.88406 | 0.0849434 | 14.9942 | 2.72623 | 0.0136311 | 392.577 | 0.218098 | 4.90721 | 0.00272623 | 490.721 | 0.272623 | 49.0721 | 0.0272623
L21 | BLOCO A | L21 | 50.8641 | 2.54321 | 0.0254321 | 134.421 | 2.54321 | 0.0746781 | 13.0977 | 2.3814 | 0.011907 | 342.922 | 0.190512 | 4.28653 | 0.0023814 | 428.653 | 0.23814 | 42.8653 | 0.023814
L22 | BLOCO A | L22 | 50.8453 | 2.54227 | 0.0254227 | 135.214 | 2.54227 | 0.0751189 | 13.3505 | 2.42736 | 0.0121368 | 349.54 | 0.194189 | 4.36925 | 0.00242736 | 436.925 | 0.242736 | 43.6925 | 0.0242736
L23 | BLOCO A | L23 | 114.124 | 5.70619 | 0.0570619 | 319.667 | 6.46272 | 0.177593 | 34.8421 | 6.33492 | 0.0316746 | 912.229 | 0.506794 | 11.4029 | 0.00633492 | 1140.29 | 0.633492 | 114.029 | 0.0633492
L24 | BLOCO A | L24 | 121.483 | 6.07417 | 0.0607417 | 353.2 | 7.49995 | 0.196222 | 40.9057 | 7.43741 | 0.037187 | 1070.99 | 0.594993 | 13.3873 | 0.00743741 | 1338.73 | 0.743741 | 133.873 | 0.0743741
L22 | BLOCO A | L22 | 225.033 | 11.2519 | 0.112517 | 610.28 | 12.0701 | 0.339044 | 62.6656 | 11.3937 | 0.0569687 | 1640.7 | 0.911499 | 20.5087 | 0.0113937 | 2050.87 | 1.13937 | 205.087 | 0.113937
L16 | BLOCO A | L16 | 19.3928 | 0.969642 | 0.00969642 | 50.8907 | 0.942421 | 0.0282726 | 5.18332 | 0.942421 | 0.00471211 | 135.709 | 0.0753937 | 1.69636 | 0.000942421 | 169.636 | 0.0942421 | 16.9636 | 0.00942421
L16 | BLOCO A | L16 | 19.3928 | 0.969642 | 0.00969642 | 50.8316 | 0.941326 | 0.0282398 | 5.17729 | 0.941326 | 0.00470663 | 135.551 | 0.0753061 | 1.69439 | 0.000941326 | 169.439 | 0.0941326 | 16.9439 | 0.00941326

# IfcCovering: FNDE-PIS_INT_VIN (amarelo) 223 (4)
In: TÉRREO
Classification: Piso (Acabamento) (Classificação Archicad); Material: COMPACTAÇÃO DE SOLO, LASTRO DE BRITA, CAMADA SEPARADORA EM LONA PLÁSTICA, LASTRO DE CONCRETO, EI-PIS-Contrapiso Áreas secas, EI-PIS-5-Piso Vinílico em manta Amarelo
Pset_CoveringCommon - Material: FNDE-PIS_INT_VIN (amarelo)
Component Quantities - EI-PIS-5-Piso Vinílico em manta Amarelo, Espessura do Componente: 0.002 m; EI-PIS-Contrapiso Áreas secas, Espessura do Componente: 0.03 m; LASTRO DE CONCRETO, Espessura do Componente: 0.08 m; CAMADA SEPARADORA EM LONA PLÁSTICA, Espessura do Componente: 0.001 m; LASTRO DE BRITA, Espessura do Componente: 0.1 m; COMPACTAÇÃO DE SOLO, Espessura do Componente: 0.01 m
Name | 1_Bloco | 0_ID | EI-PIS-5-Piso Vinílico em manta Amarelo, Massa (kg) | EI-PIS-5-Piso Vinílico em manta Amarelo, Área de Componente Projetada (Líquida) (m2) = EI-PIS-Contrapiso Áreas secas, Área de Componente Projetada (Líquida) (m2) = LASTRO DE CONCRETO, Área de Componente Projetada (Líquida) (m2) | EI-PIS-5-Piso Vinílico em manta Amarelo, Área de Componente Projetada (Bruta) (m2) = EI-PIS-Contrapiso Áreas secas, Área de Componente Projetada (Bruta) (m2) = LASTRO DE CONCRETO, Área de Componente Projetada (Bruta) (m2) | EI-PIS-5-Piso Vinílico em manta Amarelo, Volume Componente (Líquido) (m3) | EI-PIS-5-Piso Vinílico em manta Amarelo, Volume do componente (Bruto) (m3) | EI-PIS-Contrapiso Áreas secas, Massa (kg) | EI-PIS-Contrapiso Áreas secas, Volume Componente (Líquido) (m3) | EI-PIS-Contrapiso Áreas secas, Volume do componente (Bruto) (m3) | LASTRO DE CONCRETO, Massa (kg) | LASTRO DE CONCRETO, Volume Componente (Líquido) (m3) | LASTRO DE CONCRETO, Volume do componente (Bruto) (m3) | CAMADA SEPARADORA EM LONA PLÁSTICA, Massa (kg) | CAMADA SEPARADORA EM LONA PLÁSTICA, Área de Componente Projetada (Líquida) (m2) = LASTRO DE BRITA, Área de Componente Projetada (Líquida) (m2) = COMPACTAÇÃO DE SOLO, Área de Componente Projetada (Líquida) (m2) | CAMADA SEPARADORA EM LONA PLÁSTICA, Área de Componente Projetada (Bruta) (m2) = LASTRO DE BRITA, Área de Componente Projetada (Bruta) (m2) = COMPACTAÇÃO DE SOLO, Área de Componente Projetada (Bruta) (m2) | CAMADA SEPARADORA EM LONA PLÁSTICA, Volume Componente (Líquido) (m3) | CAMADA SEPARADORA EM LONA PLÁSTICA, Volume do componente (Bruto) (m3) | LASTRO DE BRITA, Massa (kg) | LASTRO DE BRITA, Volume Componente (Líquido) (m3) | LASTRO DE BRITA, Volume do componente (Bruto) (m3) | COMPACTAÇÃO DE SOLO, Massa (kg) | COMPACTAÇÃO DE SOLO, Volume Componente (Líquido) (m3) | COMPACTAÇÃO DE SOLO, Volume do componente (Bruto) (m3)
L10 | BLOCO B | L10 | 25.33 | 7.45 | 17.8 | 0.0149 | 0.0356 | 402.3 | 0.2235 | 0.534 | 1072.8 | 0.596 | 1.424 | 13.41 | 7.45 | 17.8 | 0.00745 | 0.0178 | 1341 | 0.745 | 1.78 | 134.1 | 0.0745 | 0.178
L10 | BLOCO B | L10 | 12.5801 | 3.70003 | 3.70003 | 0.00740006 | 0.00740006 | 199.802 | 0.111001 | 0.111001 | 532.805 | 0.296003 | 0.296003 | 6.66006 | 3.70003 | 3.70003 | 0.00370003 | 0.00370003 | 666.006 | 0.370003 | 0.370003 | 66.6006 | 0.0370003 | 0.0370003
L09 | BLOCO B | L09 | 14.1933 | 4.17454 | 4.17454 | 0.00834901 | 0.00834901 | 225.413 | 0.12523 | 0.12523 | 599.47 | 0.333039 | 0.333039 | 7.49106 | 4.1617 | 4.1617 | 0.0041617 | 0.0041617 | 749.106 | 0.41617 | 0.41617 | 74.9106 | 0.041617 | 0.041617
L10 | BLOCO A | L10 | 25.0241 | 7.36002 | 17.4436 | 0.01472 | 0.0348871 | 397.441 | 0.220801 | 0.523307 | 1059.84 | 0.588801 | 1.39549 | 13.248 | 7.36002 | 17.4436 | 0.00736002 | 0.0174436 | 1324.8 | 0.736002 | 1.74436 | 132.48 | 0.0736002 | 0.174436

# IfcCovering: FNDE-PIS_INT_VIN (azul) 223 (3)
In: TÉRREO
Classification: Piso (Acabamento) (Classificação Archicad); Material: COMPACTAÇÃO DE SOLO, LASTRO DE BRITA, CAMADA SEPARADORA EM LONA PLÁSTICA, LASTRO DE CONCRETO, EI-PIS-Contrapiso Áreas secas, EI-PIS-5-Piso Vinílico em manta Azul
Pset_CoveringCommon - Material: FNDE-PIS_INT_VIN (azul)
FNDE - 1_Bloco: BLOCO B
Component Quantities - EI-PIS-5-Piso Vinílico em manta Azul, Espessura do Componente: 0.002 m; EI-PIS-Contrapiso Áreas secas, Espessura do Componente: 0.03 m; LASTRO DE CONCRETO, Espessura do Componente: 0.08 m; CAMADA SEPARADORA EM LONA PLÁSTICA, Espessura do Componente: 0.001 m; LASTRO DE BRITA, Espessura do Componente: 0.1 m; COMPACTAÇÃO DE SOLO, Espessura do Componente: 0.01 m
Name | 0_ID | EI-PIS-5-Piso Vinílico em manta Azul, Massa (kg) | EI-PIS-5-Piso Vinílico em manta Azul, Área de Componente Projetada (Líquida) (m2) = EI-PIS-Contrapiso Áreas secas, Área de Componente Projetada (Líquida) (m2) = LASTRO DE CONCRETO, Área de Componente Projetada (Líquida) (m2) = CAMADA SEPARADORA EM LONA PLÁSTICA, Área de Componente Projetada (Líquida) (m2) = LASTRO DE BRITA, Área de Componente Projetada (Líquida) (m2) = COMPACTAÇÃO DE SOLO, Área de Componente Projetada (Líquida) (m2) | EI-PIS-5-Piso Vinílico em manta Azul, Área de Componente Projetada (Bruta) (m2) = EI-PIS-Contrapiso Áreas secas, Área de Componente Projetada (Bruta) (m2) = LASTRO DE CONCRETO, Área de Componente Projetada (Bruta) (m2) = CAMADA SEPARADORA EM LONA PLÁSTICA, Área de Componente Projetada (Bruta) (m2) = LASTRO DE BRITA, Área de Componente Projetada (Bruta) (m2) = COMPACTAÇÃO DE SOLO, Área de Componente Projetada (Bruta) (m2) | EI-PIS-5-Piso Vinílico em manta Azul, Volume Componente (Líquido) (m3) | EI-PIS-5-Piso Vinílico em manta Azul, Volume do componente (Bruto) (m3) | EI-PIS-Contrapiso Áreas secas, Massa (kg) | EI-PIS-Contrapiso Áreas secas, Volume Componente (Líquido) (m3) | EI-PIS-Contrapiso Áreas secas, Volume do componente (Bruto) (m3) | LASTRO DE CONCRETO, Massa (kg) | LASTRO DE CONCRETO, Volume Componente (Líquido) (m3) | LASTRO DE CONCRETO, Volume do componente (Bruto) (m3) | CAMADA SEPARADORA EM LONA PLÁSTICA, Massa (kg) | CAMADA SEPARADORA EM LONA PLÁSTICA, Volume Componente (Líquido) (m3) | CAMADA SEPARADORA EM LONA PLÁSTICA, Volume do componente (Bruto) (m3) | LASTRO DE BRITA, Massa (kg) | LASTRO DE BRITA, Volume Componente (Líquido) (m3) | LASTRO DE BRITA, Volume do componente (Bruto) (m3) | COMPACTAÇÃO DE SOLO, Massa (kg) | COMPACTAÇÃO DE SOLO, Volume Componente (Líquido) (m3) | COMPACTAÇÃO DE SOLO, Volume do componente (Bruto) (m3)
L09 | L09 | 14.197 | 4.17911 | 4.17911 | 0.00835119 | 0.00835119 | 225.527 | 0.125293 | 0.125293 | 601.792 | 0.334329 | 0.334329 | 7.52241 | 0.00417911 | 0.00417911 | 752.241 | 0.417911 | 0.417911 | 75.2241 | 0.0417911 | 0.0417911
L09 | L09 | 12.5802 | 3.70006 | 3.70006 | 0.00740011 | 0.00740011 | 199.803 | 0.111002 | 0.111002 | 532.808 | 0.296005 | 0.296005 | 6.6601 | 0.00370006 | 0.00370006 | 666.01 | 0.370006 | 0.370006 | 66.601 | 0.0370006 | 0.0370006
L10 | L10 | 25.3303 | 7.45009 | 17.8 | 0.0149002 | 0.0356 | 402.305 | 0.223503 | 0.534 | 1072.81 | 0.596007 | 1.424 | 13.4102 | 0.00745009 | 0.0178 | 1341.02 | 0.745009 | 1.78 | 134.102 | 0.0745009 | 0.178

# IfcCovering: FNDE-PIS_INT_VIN (cinza claro) 223 (11)
In: TÉRREO
Classification: Piso (Acabamento) (Classificação Archicad); Material: COMPACTAÇÃO DE SOLO, LASTRO DE BRITA, CAMADA SEPARADORA EM LONA PLÁSTICA, LASTRO DE CONCRETO, EI-PIS-Contrapiso Áreas secas, EI-PIS-5-Piso Vinílico em manta Cinza Claro
Pset_CoveringCommon - Material: FNDE-PIS_INT_VIN (cinza claro)
Component Quantities - EI-PIS-5-Piso Vinílico em manta Cinza Claro, Espessura do Componente: 0.002 m; EI-PIS-Contrapiso Áreas secas, Espessura do Componente: 0.03 m; LASTRO DE CONCRETO, Espessura do Componente: 0.08 m; CAMADA SEPARADORA EM LONA PLÁSTICA, Espessura do Componente: 0.001 m; LASTRO DE BRITA, Espessura do Componente: 0.1 m; COMPACTAÇÃO DE SOLO, Espessura do Componente: 0.01 m
Name | 1_Bloco | 0_ID | EI-PIS-5-Piso Vinílico em manta Cinza Claro, Massa (kg) | EI-PIS-5-Piso Vinílico em manta Cinza Claro, Área de Componente Projetada (Líquida) (m2) = LASTRO DE CONCRETO, Área de Componente Projetada (Líquida) (m2) | EI-PIS-5-Piso Vinílico em manta Cinza Claro, Área de Componente Projetada (Bruta) (m2) = LASTRO DE CONCRETO, Área de Componente Projetada (Bruta) (m2) | EI-PIS-5-Piso Vinílico em manta Cinza Claro, Volume Componente (Líquido) (m3) | EI-PIS-5-Piso Vinílico em manta Cinza Claro, Volume do componente (Bruto) (m3) | EI-PIS-Contrapiso Áreas secas, Massa (kg) | EI-PIS-Contrapiso Áreas secas, Área de Componente Projetada (Líquida) (m2) | EI-PIS-Contrapiso Áreas secas, Área de Componente Projetada (Bruta) (m2) | EI-PIS-Contrapiso Áreas secas, Volume Componente (Líquido) (m3) | EI-PIS-Contrapiso Áreas secas, Volume do componente (Bruto) (m3) | LASTRO DE CONCRETO, Massa (kg) | LASTRO DE CONCRETO, Volume Componente (Líquido) (m3) | LASTRO DE CONCRETO, Volume do componente (Bruto) (m3) | CAMADA SEPARADORA EM LONA PLÁSTICA, Massa (kg) | CAMADA SEPARADORA EM LONA PLÁSTICA, Área de Componente Projetada (Líquida) (m2) = LASTRO DE BRITA, Área de Componente Projetada (Líquida) (m2) = COMPACTAÇÃO DE SOLO, Área de Componente Projetada (Líquida) (m2) | CAMADA SEPARADORA EM LONA PLÁSTICA, Área de Componente Projetada (Bruta) (m2) = LASTRO DE BRITA, Área de Componente Projetada (Bruta) (m2) = COMPACTAÇÃO DE SOLO, Área de Componente Projetada (Bruta) (m2) | CAMADA SEPARADORA EM LONA PLÁSTICA, Volume Componente (Líquido) (m3) | CAMADA SEPARADORA EM LONA PLÁSTICA, Volume do componente (Bruto) (m3) | LASTRO DE BRITA, Massa (kg) | LASTRO DE BRITA, Volume Componente (Líquido) (m3) | LASTRO DE BRITA, Volume do componente (Bruto) (m3) | COMPACTAÇÃO DE SOLO, Massa (kg) | COMPACTAÇÃO DE SOLO, Volume Componente (Líquido) (m3) | COMPACTAÇÃO DE SOLO, Volume do componente (Bruto) (m3)
L10 | BLOCO A | L10 | 34.2841 | 10.0836 | 10.0836 | 0.0201671 | 0.0201671 | 544.512 | 10.0836 | 10.0836 | 0.302507 | 0.302507 | 1452.03 | 0.806685 | 0.806685 | 18.1504 | 10.0836 | 10.0836 | 0.0100836 | 0.0100836 | 1815.04 | 1.00836 | 1.00836 | 181.504 | 0.100836 | 0.100836
L09 | BLOCO B | L09 | 29.989 | 8.846 | 8.846 | 0.0176406 | 0.0176406 | 476.626 | 8.846 | 8.846 | 0.264792 | 0.264792 | 1229.25 | 0.682917 | 0.682917 | 15.3037 | 8.50207 | 8.50207 | 0.00850207 | 0.00850207 | 1530.37 | 0.850207 | 0.850207 | 153.037 | 0.0850207 | 0.0850207
L09 | BLOCO B | L09 | 29.9871 | 8.84424 | 8.84424 | 0.0176395 | 0.0176395 | 476.586 | 8.84424 | 8.84424 | 0.26477 | 0.26477 | 1209.15 | 0.671748 | 0.671748 | 15.0249 | 8.34714 | 8.34714 | 0.00834714 | 0.00834714 | 1502.49 | 0.834714 | 0.834714 | 150.249 | 0.0834714 | 0.0834714
L09 | BLOCO B | L09 | 71.2957 | 21.0454 | 38.6454 | 0.0419386 | 0.0771387 | 1133.27 | 21.0454 | 38.6454 | 0.629593 | 1.15759 | 2896.56 | 1.6092 | 3.0172 | 36.021 | 20.0117 | 37.6117 | 0.0200117 | 0.0376117 | 3602.1 | 2.00117 | 3.76117 | 360.21 | 0.200117 | 0.376117
L09 | BLOCO B | L09 | 29.5715 | 8.69997 | 8.69997 | 0.017395 | 0.017395 | 469.375 | 8.69998 | 8.69998 | 0.260764 | 0.260764 | 1212.47 | 0.673593 | 0.673593 | 15.0998 | 8.38879 | 8.38879 | 0.00838879 | 0.00838879 | 1509.98 | 0.838879 | 0.838879 | 150.998 | 0.0838879 | 0.0838879
L09 | BLOCO B | L09 | 34.1697 | 10.0499 | 10.0499 | 0.0200998 | 0.0200998 | 542.696 | 10.0499 | 10.0499 | 0.301498 | 0.301498 | 1447.19 | 0.803993 | 0.803993 | 18.0899 | 10.0499 | 10.0499 | 0.0100499 | 0.0100499 | 1808.99 | 1.00499 | 1.00499 | 180.899 | 0.100499 | 0.100499
L09 | BLOCO B | L09 | 35.19 | 10.35 | 10.35 | 0.0207 | 0.0207 | 558.9 | 10.35 | 10.35 | 0.3105 | 0.3105 | 1490.4 | 0.828 | 0.828 | 18.63 | 10.35 | 10.35 | 0.01035 | 0.01035 | 1863 | 1.035 | 1.035 | 186.3 | 0.1035 | 0.1035
L09 | BLOCO B | L09 | 34.6798 | 10.1999 | 10.1999 | 0.0203999 | 0.0203999 | 550.797 | 10.1999 | 10.1999 | 0.305998 | 0.305998 | 1468.79 | 0.815995 | 0.815995 | 18.3599 | 10.1999 | 10.1999 | 0.0101999 | 0.0101999 | 1835.99 | 1.01999 | 1.01999 | 183.599 | 0.101999 | 0.101999
L09 | BLOCO B | L09 | 35.1897 | 10.3499 | 10.3499 | 0.0206998 | 0.0206998 | 558.895 | 10.3499 | 10.3499 | 0.310497 | 0.310497 | 1490.39 | 0.827993 | 0.827993 | 18.6298 | 10.3499 | 10.3499 | 0.0103499 | 0.0103499 | 1862.98 | 1.03499 | 1.03499 | 186.298 | 0.103499 | 0.103499
L09 | BLOCO B | L09 | 29.7923 | 8.76246 | 8.76246 | 0.0175249 | 0.0175249 | 472.842 | 8.76246 | 8.76246 | 0.26269 | 0.26269 | 1221.94 | 0.678856 | 0.678856 | 15.2189 | 8.45494 | 8.45494 | 0.00845494 | 0.00845494 | 1521.89 | 0.845494 | 0.845494 | 152.189 | 0.0845494 | 0.0845494
L09 | BLOCO B | L09 | 34.17 | 10.05 | 10.05 | 0.0201 | 0.0201 | 542.7 | 10.05 | 10.05 | 0.3015 | 0.3015 | 1447.2 | 0.804 | 0.804 | 18.09 | 10.05 | 10.05 | 0.01005 | 0.01005 | 1809 | 1.005 | 1.005 | 180.9 | 0.1005 | 0.1005

# IfcCovering: FNDE-PIS_INT_VIN (cinza escuro) 223 (5)
In: TÉRREO
Classification: Piso (Acabamento) (Classificação Archicad); Material: COMPACTAÇÃO DE SOLO, LASTRO DE BRITA, CAMADA SEPARADORA EM LONA PLÁSTICA, LASTRO DE CONCRETO, EI-PIS-Contrapiso Áreas secas, EI-PIS-5-Piso Vinílico em manta Cinza Escuro
Pset_CoveringCommon - Material: FNDE-PIS_INT_VIN (cinza escuro)
Component Quantities - EI-PIS-5-Piso Vinílico em manta Cinza Escuro, Espessura do Componente: 0.002 m; EI-PIS-Contrapiso Áreas secas, Espessura do Componente: 0.03 m; LASTRO DE CONCRETO, Espessura do Componente: 0.08 m; CAMADA SEPARADORA EM LONA PLÁSTICA, Espessura do Componente: 0.001 m; LASTRO DE BRITA, Espessura do Componente: 0.1 m; COMPACTAÇÃO DE SOLO, Espessura do Componente: 0.01 m
Name | 1_Bloco | 0_ID | EI-PIS-5-Piso Vinílico em manta Cinza Escuro, Massa (kg) | EI-PIS-5-Piso Vinílico em manta Cinza Escuro, Área de Componente Projetada (Líquida) (m2) = EI-PIS-Contrapiso Áreas secas, Área de Componente Projetada (Líquida) (m2) = LASTRO DE CONCRETO, Área de Componente Projetada (Líquida) (m2) | EI-PIS-5-Piso Vinílico em manta Cinza Escuro, Área de Componente Projetada (Bruta) (m2) = EI-PIS-Contrapiso Áreas secas, Área de Componente Projetada (Bruta) (m2) = LASTRO DE CONCRETO, Área de Componente Projetada (Bruta) (m2) | EI-PIS-5-Piso Vinílico em manta Cinza Escuro, Volume Componente (Líquido) (m3) | EI-PIS-5-Piso Vinílico em manta Cinza Escuro, Volume do componente (Bruto) (m3) | EI-PIS-Contrapiso Áreas secas, Massa (kg) | EI-PIS-Contrapiso Áreas secas, Volume Componente (Líquido) (m3) | EI-PIS-Contrapiso Áreas secas, Volume do componente (Bruto) (m3) | LASTRO DE CONCRETO, Massa (kg) | LASTRO DE CONCRETO, Volume Componente (Líquido) (m3) | LASTRO DE CONCRETO, Volume do componente (Bruto) (m3) | CAMADA SEPARADORA EM LONA PLÁSTICA, Massa (kg) | CAMADA SEPARADORA EM LONA PLÁSTICA, Área de Componente Projetada (Líquida) (m2) = LASTRO DE BRITA, Área de Componente Projetada (Líquida) (m2) = COMPACTAÇÃO DE SOLO, Área de Componente Projetada (Líquida) (m2) | CAMADA SEPARADORA EM LONA PLÁSTICA, Área de Componente Projetada (Bruta) (m2) = LASTRO DE BRITA, Área de Componente Projetada (Bruta) (m2) = COMPACTAÇÃO DE SOLO, Área de Componente Projetada (Bruta) (m2) | CAMADA SEPARADORA EM LONA PLÁSTICA, Volume Componente (Líquido) (m3) | CAMADA SEPARADORA EM LONA PLÁSTICA, Volume do componente (Bruto) (m3) | LASTRO DE BRITA, Massa (kg) | LASTRO DE BRITA, Volume Componente (Líquido) (m3) | LASTRO DE BRITA, Volume do componente (Bruto) (m3) | COMPACTAÇÃO DE SOLO, Massa (kg) | COMPACTAÇÃO DE SOLO, Volume Componente (Líquido) (m3) | COMPACTAÇÃO DE SOLO, Volume do componente (Bruto) (m3)
L10 | BLOCO A | L10 | 63.115 | 18.64 | 36.0835 | 0.0371265 | 0.0720136 | 1002.68 | 0.557043 | 1.08035 | 2595.16 | 1.44175 | 2.83724 | 32.3159 | 17.9533 | 35.3968 | 0.0179533 | 0.0353968 | 3231.59 | 1.79533 | 3.53968 | 323.159 | 0.179533 | 0.353968
L09 | BLOCO B | L09 | 60.8432 | 17.9267 | 35.7267 | 0.0357901 | 0.0713901 | 966.74 | 0.537078 | 1.07108 | 2470.77 | 1.37265 | 2.79665 | 30.7309 | 17.0727 | 34.8727 | 0.0170727 | 0.0348727 | 3073.09 | 1.70727 | 3.48727 | 307.309 | 0.170727 | 0.348727
L09 | BLOCO B | L09 | 61.0828 | 17.9973 | 35.7973 | 0.035931 | 0.071531 | 970.546 | 0.539192 | 1.07319 | 2480.85 | 1.37825 | 2.80225 | 30.8568 | 17.1427 | 34.9427 | 0.0171427 | 0.0349427 | 3085.68 | 1.71427 | 3.49427 | 308.568 | 0.171427 | 0.349427
L09 | BLOCO B | L09 | 14.2156 | 4.18107 | 4.18107 | 0.00836213 | 0.00836213 | 225.778 | 0.125432 | 0.125432 | 598.062 | 0.332257 | 0.332257 | 7.47021 | 4.15011 | 4.15011 | 0.00415011 | 0.00415011 | 747.021 | 0.415011 | 0.415011 | 74.7021 | 0.0415011 | 0.0415011
L09 | BLOCO B | L09 | 14.2163 | 4.18127 | 4.18127 | 0.00836253 | 0.00836253 | 225.788 | 0.125438 | 0.125438 | 598.092 | 0.332273 | 0.332273 | 7.47057 | 4.15032 | 4.15032 | 0.00415032 | 0.00415032 | 747.057 | 0.415032 | 0.415032 | 74.7057 | 0.0415032 | 0.0415032

# IfcCovering: FNDE-Soco em Alvenaria Rev. Ceramica Branco Gelo 30x40cm 300 x 130 (2)
In: TÉRREO
Type - PredefinedType: CLADDING
Classification: Acabamento (Classificação Archicad); Material: TIJOLO - CERAMICO 9x19x19 - sóculos, EI-PIS-3-Cerâmica 45x45 (2)
Pset_CoveringCommon - Material: FNDE-Soco em Alvenaria Rev. Ceramica Branco Gelo 30x40cm
FNDE - Alvenarias: Alvenaria de Vedação / Edificação; Soleira/Peitoril: -; Pedras: - -; 1_Bloco: BLOCO A; 0_ID: V14
Component Quantities - TIJOLO - CERAMICO 9x19x19 - sóculos, Altura do Componente Retangular: 0.12 m; TIJOLO - CERAMICO 9x19x19 - sóculos, Largura do Componente Retangular: 0.2925 m; TIJOLO - CERAMICO 9x19x19 - sóculos, Área de Seção Transversal do Componente: 0.0351 m2; EI-PIS-3-Cerâmica 45x45 1, Área de Seção Transversal do Componente: 0.0007125 m2; EI-PIS-3-Cerâmica 45x45 2, Área de Seção Transversal do Componente: 0.0029625 m2
Name | TIJOLO - CERAMICO 9x19x19 - sóculos, Massa (kg) | TIJOLO - CERAMICO 9x19x19 - sóculos, Área de Componente Projetada (Líquida) (m2) = TIJOLO - CERAMICO 9x19x19 - sóculos, Área de Componente Projetada (Bruta) (m2) | TIJOLO - CERAMICO 9x19x19 - sóculos, Volume Componente (Líquido) (m3) = TIJOLO - CERAMICO 9x19x19 - sóculos, Volume do componente (Bruto) (m3) | EI-PIS-3-Cerâmica 45x45 1, Massa (kg) | EI-PIS-3-Cerâmica 45x45 1, Área de Componente Projetada (Líquida) (m2) = EI-PIS-3-Cerâmica 45x45 1, Área de Componente Projetada (Bruta) (m2) | EI-PIS-3-Cerâmica 45x45 1, Volume Componente (Líquido) (m3) = EI-PIS-3-Cerâmica 45x45 1, Volume do componente (Bruto) (m3) | EI-PIS-3-Cerâmica 45x45 2, Massa (kg) | EI-PIS-3-Cerâmica 45x45 2, Área de Componente Projetada (Líquida) (m2) = EI-PIS-3-Cerâmica 45x45 2, Área de Componente Projetada (Bruta) (m2) | EI-PIS-3-Cerâmica 45x45 2, Volume Componente (Líquido) (m3) = EI-PIS-3-Cerâmica 45x45 2, Volume do componente (Bruto) (m3)
V14 | 34.1244 | 0.438843 | 0.0526612 | 2.13795 | 0.150032 | 0.00106898 | 8.88938 | 0.450095 | 0.00444469
V14 | 34.1243 | 0.438841 | 0.0526609 | 2.13794 | 0.150031 | 0.00106897 | 8.88935 | 0.450093 | 0.00444467

# IfcCovering: FNDE-Soco em Alvenaria Rev. Ceramica Branco Gelo 30x40cm 350 x 130 (4)
In: TÉRREO
Type - PredefinedType: CLADDING
Classification: Acabamento (Classificação Archicad); Material: TIJOLO - CERAMICO 9x19x19 - sóculos, EI-PIS-3-Cerâmica 45x45 (2)
Pset_CoveringCommon - Material: FNDE-Soco em Alvenaria Rev. Ceramica Branco Gelo 30x40cm
FNDE - Alvenarias: Alvenaria de Vedação / Edificação; Soleira/Peitoril: -; Pedras: - -; 1_Bloco: BLOCO A
Component Quantities - TIJOLO - CERAMICO 9x19x19 - sóculos, Altura do Componente Retangular: 0.12 m
Name | 0_ID | TIJOLO - CERAMICO 9x19x19 - sóculos, Massa (kg) | TIJOLO - CERAMICO 9x19x19 - sóculos, Área de Componente Projetada (Líquida) (m2) = TIJOLO - CERAMICO 9x19x19 - sóculos, Área de Componente Projetada (Bruta) (m2) | TIJOLO - CERAMICO 9x19x19 - sóculos, Largura do Componente Retangular (m) | TIJOLO - CERAMICO 9x19x19 - sóculos, Área de Seção Transversal do Componente (m2) | TIJOLO - CERAMICO 9x19x19 - sóculos, Volume Componente (Líquido) (m3) = TIJOLO - CERAMICO 9x19x19 - sóculos, Volume do componente (Bruto) (m3) | EI-PIS-3-Cerâmica 45x45 1, Massa (kg) | EI-PIS-3-Cerâmica 45x45 1, Área de Componente Projetada (Líquida) (m2) = EI-PIS-3-Cerâmica 45x45 1, Área de Componente Projetada (Bruta) (m2) | EI-PIS-3-Cerâmica 45x45 1, Área de Seção Transversal do Componente (m2) | EI-PIS-3-Cerâmica 45x45 1, Volume Componente (Líquido) (m3) = EI-PIS-3-Cerâmica 45x45 1, Volume do componente (Bruto) (m3) | EI-PIS-3-Cerâmica 45x45 2, Massa (kg) | EI-PIS-3-Cerâmica 45x45 2, Área de Componente Projetada (Líquida) (m2) = EI-PIS-3-Cerâmica 45x45 2, Área de Componente Projetada (Bruta) (m2) | EI-PIS-3-Cerâmica 45x45 2, Área de Seção Transversal do Componente (m2) | EI-PIS-3-Cerâmica 45x45 2, Volume Componente (Líquido) (m3) = EI-PIS-3-Cerâmica 45x45 2, Volume do componente (Bruto) (m3)
V08 | V08 | 38.2124 | 0.491415 | 0.34126 | 0.0409512 | 0.0589698 | 2.39407 | 0.144 | 0.000831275 | 0.00119704 | 9.95429 | 0.504015 | 0.00345635 | 0.00497715
V08 | V08 | 31.5944 | 0.406306 | 0.341255 | 0.0409506 | 0.0487567 | 1.6052 | 0.0970684 | 0.000831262 | 0.000802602 | 8.21078 | 0.414755 | 0.0034563 | 0.00410539
V09 | V09 | 37.9656 | 0.488241 | 0.34126 | 0.0409512 | 0.0585889 | 2.00443 | 0.121079 | 0.000831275 | 0.00100221 | 9.87048 | 0.498791 | 0.00345635 | 0.00493524
V14 | V14 | 49.2561 | 0.633438 | 0.341255 | 0.0409506 | 0.0760125 | 2.6702 | 0.161185 | 0.000831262 | 0.0013351 | 12.8095 | 0.647492 | 0.0034563 | 0.00640474

# IfcCovering: FNDE-Soco em Alvenaria Rev. Ceramica Branco Gelo 30x40cm 400 x 130 (2)
In: TÉRREO
Type - PredefinedType: CLADDING
Classification: Acabamento (Classificação Archicad); Material: TIJOLO - CERAMICO 9x19x19 - sóculos, EI-PIS-3-Cerâmica 45x45 (2)
Pset_CoveringCommon - Material: FNDE-Soco em Alvenaria Rev. Ceramica Branco Gelo 30x40cm
FNDE - Alvenarias: Alvenaria de Vedação / Edificação; Soleira/Peitoril: -; Pedras: - -; 1_Bloco: BLOCO A
Component Quantities - TIJOLO - CERAMICO 9x19x19 - sóculos, Altura do Componente Retangular: 0.12 m; TIJOLO - CERAMICO 9x19x19 - sóculos, Largura do Componente Retangular: 0.39 m; TIJOLO - CERAMICO 9x19x19 - sóculos, Área de Seção Transversal do Componente: 0.0468 m2; EI-PIS-3-Cerâmica 45x45 1, Área de Seção Transversal do Componente: 0.00095 m2; EI-PIS-3-Cerâmica 45x45 2, Área de Seção Transversal do Componente: 0.00395 m2
Name | TIJOLO - CERAMICO 9x19x19 - sóculos, Massa (kg) | TIJOLO - CERAMICO 9x19x19 - sóculos, Área de Componente Projetada (Líquida) (m2) = TIJOLO - CERAMICO 9x19x19 - sóculos, Área de Componente Projetada (Bruta) (m2) | TIJOLO - CERAMICO 9x19x19 - sóculos, Volume Componente (Líquido) (m3) = TIJOLO - CERAMICO 9x19x19 - sóculos, Volume do componente (Bruto) (m3) | EI-PIS-3-Cerâmica 45x45 1, Massa (kg) | EI-PIS-3-Cerâmica 45x45 1, Área de Componente Projetada (Líquida) (m2) = EI-PIS-3-Cerâmica 45x45 1, Área de Componente Projetada (Bruta) (m2) | EI-PIS-3-Cerâmica 45x45 1, Volume Componente (Líquido) (m3) = EI-PIS-3-Cerâmica 45x45 1, Volume do componente (Bruto) (m3) | EI-PIS-3-Cerâmica 45x45 2, Massa (kg) | EI-PIS-3-Cerâmica 45x45 2, Área de Componente Projetada (Líquida) (m2) = EI-PIS-3-Cerâmica 45x45 2, Área de Componente Projetada (Bruta) (m2) | EI-PIS-3-Cerâmica 45x45 2, Volume Componente (Líquido) (m3) = EI-PIS-3-Cerâmica 45x45 2, Volume do componente (Bruto) (m3)
 | 48.5222 | 0.624 | 0.07488 | 2.338 | 0.1249 | 0.001169 | 12.64 | 0.64 | 0.00632
 | 42.8371 | 0.550889 | 0.0661067 | 2.66482 | 0.140254 | 0.00133241 | 11.08 | 0.561014 | 0.00554002

# IfcCovering: FNDE-Soco em Alvenaria Rev. Ceramica Branco Gelo 30x40cm 450 x 130 (7)
In: TÉRREO
Type - PredefinedType: CLADDING
Classification: Acabamento (Classificação Archicad); Material: TIJOLO - CERAMICO 9x19x19 - sóculos, EI-PIS-3-Cerâmica 45x45 (2)
Pset_CoveringCommon - Material: FNDE-Soco em Alvenaria Rev. Ceramica Branco Gelo 30x40cm
FNDE - Alvenarias: Alvenaria de Vedação / Edificação; Soleira/Peitoril: -; Pedras: - -; 1_Bloco: BLOCO A
Component Quantities - TIJOLO - CERAMICO 9x19x19 - sóculos, Altura do Componente Retangular: 0.12 m
Name | 0_ID | TIJOLO - CERAMICO 9x19x19 - sóculos, Massa (kg) | TIJOLO - CERAMICO 9x19x19 - sóculos, Área de Componente Projetada (Líquida) (m2) = TIJOLO - CERAMICO 9x19x19 - sóculos, Área de Componente Projetada (Bruta) (m2) | TIJOLO - CERAMICO 9x19x19 - sóculos, Largura do Componente Retangular (m) | TIJOLO - CERAMICO 9x19x19 - sóculos, Área de Seção Transversal do Componente (m2) | TIJOLO - CERAMICO 9x19x19 - sóculos, Volume Componente (Líquido) (m3) = TIJOLO - CERAMICO 9x19x19 - sóculos, Volume do componente (Bruto) (m3) | EI-PIS-3-Cerâmica 45x45 1, Massa (kg) | EI-PIS-3-Cerâmica 45x45 1, Área de Componente Projetada (Líquida) (m2) = EI-PIS-3-Cerâmica 45x45 1, Área de Componente Projetada (Bruta) (m2) | EI-PIS-3-Cerâmica 45x45 1, Área de Seção Transversal do Componente (m2) | EI-PIS-3-Cerâmica 45x45 1, Volume Componente (Líquido) (m3) = EI-PIS-3-Cerâmica 45x45 1, Volume do componente (Bruto) (m3) | EI-PIS-3-Cerâmica 45x45 2, Massa (kg) | EI-PIS-3-Cerâmica 45x45 2, Área de Componente Projetada (Líquida) (m2) = EI-PIS-3-Cerâmica 45x45 2, Área de Componente Projetada (Bruta) (m2) | EI-PIS-3-Cerâmica 45x45 2, Área de Seção Transversal do Componente (m2) | EI-PIS-3-Cerâmica 45x45 2, Volume Componente (Líquido) (m3) = EI-PIS-3-Cerâmica 45x45 2, Volume do componente (Bruto) (m3)
V13 | V13 | 65.1881 | 0.838324 | 0.438755 | 0.0526506 | 0.100599 | 3.4104 | 0.160075 | 0.00106876 | 0.0017052 | 16.1564 | 0.816787 | 0.0044438 | 0.00807822
V07 | V07 | 68.6389 | 0.882702 | 0.438754 | 0.0526505 | 0.105924 | 3.92611 | 0.184077 | 0.00106876 | 0.00196305 | 17.8609 | 0.903367 | 0.00444379 | 0.00893043
V10 | V10 | 58.9444 | 0.75803 | 0.438754 | 0.0526505 | 0.0909636 | 3.31882 | 0.155666 | 0.00106876 | 0.00165941 | 15.3354 | 0.775498 | 0.00444379 | 0.00766772
V11 | V11 | 58.3616 | 0.750535 | 0.438758 | 0.0526509 | 0.0900642 | 3.17522 | 0.149062 | 0.00106877 | 0.00158761 | 15.178 | 0.767248 | 0.00444383 | 0.00758902
V10 | V10 | 60.7223 | 0.780893 | 0.438758 | 0.0526509 | 0.0937072 | 3.32312 | 0.155981 | 0.00106877 | 0.00166156 | 15.793 | 0.798385 | 0.00444383 | 0.0078965
V14 | V14 | 61.498 | 0.79087 | 0.438754 | 0.0526505 | 0.0949044 | 3.85296 | 0.180254 | 0.00106876 | 0.00192648 | 16.0202 | 0.811149 | 0.00444379 | 0.00801009
V13 | V13 | 37.8929 | 0.487305 | 0.438755 | 0.0526506 | 0.0584767 | 1.89289 | 0.0890714 | 0.00106876 | 0.000946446 | 9.84596 | 0.497269 | 0.0044438 | 0.00492298

# IfcCovering: FNDE-Soco em Alvenaria Rev. Ceramica Branco Gelo 30x40cm 500 x 130 (3)
In: TÉRREO
Type - PredefinedType: CLADDING
Classification: Acabamento (Classificação Archicad); Material: TIJOLO - CERAMICO 9x19x19 - sóculos, EI-PIS-3-Cerâmica 45x45 (2)
Pset_CoveringCommon - Material: FNDE-Soco em Alvenaria Rev. Ceramica Branco Gelo 30x40cm
FNDE - Alvenarias: Alvenaria de Vedação / Edificação; Soleira/Peitoril: -; Pedras: - -; 1_Bloco: BLOCO A
Component Quantities - TIJOLO - CERAMICO 9x19x19 - sóculos, Altura do Componente Retangular: 0.12 m; TIJOLO - CERAMICO 9x19x19 - sóculos, Largura do Componente Retangular: 0.4875 m; TIJOLO - CERAMICO 9x19x19 - sóculos, Área de Seção Transversal do Componente: 0.0585 m2; EI-PIS-3-Cerâmica 45x45 1, Área de Seção Transversal do Componente: 0.0011875 m2; EI-PIS-3-Cerâmica 45x45 2, Área de Seção Transversal do Componente: 0.0049375 m2
Name | 0_ID | TIJOLO - CERAMICO 9x19x19 - sóculos, Massa (kg) | TIJOLO - CERAMICO 9x19x19 - sóculos, Área de Componente Projetada (Líquida) (m2) = TIJOLO - CERAMICO 9x19x19 - sóculos, Área de Componente Projetada (Bruta) (m2) | TIJOLO - CERAMICO 9x19x19 - sóculos, Volume Componente (Líquido) (m3) = TIJOLO - CERAMICO 9x19x19 - sóculos, Volume do componente (Bruto) (m3) | EI-PIS-3-Cerâmica 45x45 1, Massa (kg) | EI-PIS-3-Cerâmica 45x45 1, Área de Componente Projetada (Líquida) (m2) = EI-PIS-3-Cerâmica 45x45 1, Área de Componente Projetada (Bruta) (m2) | EI-PIS-3-Cerâmica 45x45 1, Volume Componente (Líquido) (m3) = EI-PIS-3-Cerâmica 45x45 1, Volume do componente (Bruto) (m3) | EI-PIS-3-Cerâmica 45x45 2, Massa (kg) | EI-PIS-3-Cerâmica 45x45 2, Área de Componente Projetada (Líquida) (m2) = EI-PIS-3-Cerâmica 45x45 2, Área de Componente Projetada (Bruta) (m2) | EI-PIS-3-Cerâmica 45x45 2, Volume Componente (Líquido) (m3) = EI-PIS-3-Cerâmica 45x45 2, Volume do componente (Bruto) (m3)
V13 | V13 | 12.4871 | 0.160585 | 0.0192702 | 0.366602 | 0.0158372 | 0.000183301 | 3.23119 | 0.162516 | 0.0016156
V12 | V12 | 83.3964 | 1.07248 | 0.128698 | 5.22492 | 0.219997 | 0.00261246 | 21.7247 | 1.09998 | 0.0108623
V12 | V12 | 79.5803 | 1.02341 | 0.122809 | 4.98802 | 0.210022 | 0.00249401 | 20.7307 | 1.04966 | 0.0103654

# IfcCovering: FNDE-Soleira em Granito 150 x 20 (6)
In: TÉRREO
Type - PredefinedType: CLADDING
Classification: Acabamento (Classificação Archicad); Material: EI-GRA-Soleira/ Peitoril - Granito cinza Andorinha
Pset_CoveringCommon - Material: FNDE-Soleira em Granito
FNDE - Alvenarias: -; Soleira/Peitoril: SOLEIRA EM GRANITO CINZA ANDORINHA E=2cm; Pedras: - -
Component Quantities - EI-GRA-Soleira/ Peitoril - Granito cinza Andorinha, Altura do Componente Retangular: 0.02 m
Name | 1_Bloco | 0_ID | EI-GRA-Soleira/ Peitoril - Granito cinza Andorinha, Massa (kg) | EI-GRA-Soleira/ Peitoril - Granito cinza Andorinha, Largura do Componente Retangular (m) | EI-GRA-Soleira/ Peitoril - Granito cinza Andorinha, Área de Seção Transversal do Componente (m2) | EI-GRA-Soleira/ Peitoril - Granito cinza Andorinha, Volume Componente (Líquido) (m3) = EI-GRA-Soleira/ Peitoril - Granito cinza Andorinha, Volume do componente (Bruto) (m3)
S | BLOCO B | S | 7.56 | 0.15 | 0.003 | 0.0027
S | BLOCO B | S | 7.5605 | 0.15001 | 0.0030002 | 0.00270018
S | BLOCO B | S | 7.56017 | 0.150003 | 0.00300007 | 0.00270006
S | BLOCO A | S | 7.56 | 0.15 | 0.003 | 0.0027
B14 | BLOCO A | B14 | 7.56 | 0.15 | 0.003 | 0.0027
B15 | BLOCO A | B15 | 7.56 | 0.15 | 0.003 | 0.0027

# IfcCovering: FNDE-Soleira em Granito 320 x 20 (4)
In: TÉRREO
Type - PredefinedType: CLADDING
Classification: Acabamento (Classificação Archicad); Material: EI-GRA-Soleira/ Peitoril - Granito cinza Andorinha
Pset_CoveringCommon - Material: FNDE-Soleira em Granito
FNDE - Alvenarias: -; Soleira/Peitoril: SOLEIRA EM GRANITO CINZA ANDORINHA E=2cm; Pedras: - -; 1_Bloco: BLOCO A; 0_ID: B13
Component Quantities - EI-GRA-Soleira/ Peitoril - Granito cinza Andorinha, Altura do Componente Retangular: 0.02 m; EI-GRA-Soleira/ Peitoril - Granito cinza Andorinha, Largura do Componente Retangular: 0.320014 m; EI-GRA-Soleira/ Peitoril - Granito cinza Andorinha, Área de Seção Transversal do Componente: 0.00640027 m2
Name | EI-GRA-Soleira/ Peitoril - Granito cinza Andorinha, Massa (kg) | EI-GRA-Soleira/ Peitoril - Granito cinza Andorinha, Volume Componente (Líquido) (m3) = EI-GRA-Soleira/ Peitoril - Granito cinza Andorinha, Volume do componente (Bruto) (m3)
2 x B13 | 12.5445 | 0.00448019
2 x B13 | 6.2174 | 0.0022205

# IfcCovering: FNDE-Soleira em Granito Inclinada 150 x 30 (22)
In: TÉRREO
Type - PredefinedType: CLADDING
Classification: Acabamento (Classificação Archicad); Material: EI-GRA-Soleira/ Peitoril - Granito cinza Andorinha
Pset_CoveringCommon - Material: FNDE-Soleira em Granito Inclinada
FNDE - Alvenarias: -; Soleira/Peitoril: SOLEIRA EM GRANITO CINZA ANDORINHA E=2cm; Pedras: - -
Name | 1_Bloco | 0_ID | EI-GRA-Soleira/ Peitoril - Granito cinza Andorinha, Massa (kg) | EI-GRA-Soleira/ Peitoril - Granito cinza Andorinha, Área de Seção Transversal do Componente (m2) | EI-GRA-Soleira/ Peitoril - Granito cinza Andorinha, Volume Componente (Líquido) (m3) = EI-GRA-Soleira/ Peitoril - Granito cinza Andorinha, Volume do componente (Bruto) (m3)
2 x S | BLOCO B | S | 37.5508 | 0.00298018 | 0.013411
S | BLOCO B | S | 37.5504 | 0.00298018 | 0.0134108
S | BLOCO B | S | 37.5503 | 0.00298018 | 0.0134108
4 x B13 | BLOCO B | B13 | 7.51058 | 0.00298034 | 0.00268235
B13 | BLOCO B | B13 | 7.51074 | 0.00298041 | 0.00268241
B13 | BLOCO B | B13 | 37.5529 | 0.00298034 | 0.0134117
S | BLOCO A | S | 6.67592 | 0.00298028 | 0.00238426
B13 | BLOCO A | B13 | 7.51058 | 0.00298034 | 0.00268235
B14 | BLOCO A | B14 | 7.51058 | 0.00298034 | 0.00268235
B15 | BLOCO A | B15 | 7.51058 | 0.00298034 | 0.00268235
B16 | BLOCO A | B16 | 7.51058 | 0.00298034 | 0.00268235
4 x S | BLOCO A | S | 7.5109 | 0.00298047 | 0.00268246
S | BLOCO A | S | 6.92672 | 0.00298047 | 0.00247383
S | BLOCO A | S | 37.5533 | 0.00298038 | 0.0134119
S | BLOCO A | S | 7.51066 | 0.00298038 | 0.00268238

# IfcCovering: FNDE-Soleira em Granito Inclinada 151 x 30 (2)
In: TÉRREO
Type - PredefinedType: CLADDING
Classification: Acabamento (Classificação Archicad); Material: EI-GRA-Soleira/ Peitoril - Granito cinza Andorinha
Pset_CoveringCommon - Material: FNDE-Soleira em Granito Inclinada
FNDE - Alvenarias: -; Soleira/Peitoril: SOLEIRA EM GRANITO CINZA ANDORINHA E=2cm; Pedras: - -; 1_Bloco: BLOCO A; 0_ID: B13
Component Quantities - EI-GRA-Soleira/ Peitoril - Granito cinza Andorinha, Altura do Componente Retangular: 0.02 m; EI-GRA-Soleira/ Peitoril - Granito cinza Andorinha, Largura do Componente Retangular: 0.15 m; EI-GRA-Soleira/ Peitoril - Granito cinza Andorinha, Área de Seção Transversal do Componente: 0.003 m2
Name | EI-GRA-Soleira/ Peitoril - Granito cinza Andorinha, Massa (kg) | EI-GRA-Soleira/ Peitoril - Granito cinza Andorinha, Volume Componente (Líquido) (m3) = EI-GRA-Soleira/ Peitoril - Granito cinza Andorinha, Volume do componente (Bruto) (m3)
B13 | 6.972 | 0.00249
B13 | 8.652 | 0.00309

# IfcCovering: FNDE-Soleira em Granito Inclinada 201 x 30, S
In: TÉRREO
Type - PredefinedType: CLADDING
Classification: Acabamento (Classificação Archicad); Material: EI-GRA-Soleira/ Peitoril - Granito cinza Andorinha
Pset_CoveringCommon - Material: FNDE-Soleira em Granito Inclinada
FNDE - Alvenarias: -; Soleira/Peitoril: SOLEIRA EM GRANITO CINZA ANDORINHA E=2cm; Pedras: - -; 1_Bloco: BLOCO B; 0_ID: S
Component Quantities - EI-GRA-Soleira/ Peitoril - Granito cinza Andorinha, Massa: 50.3723 kg; EI-GRA-Soleira/ Peitoril - Granito cinza Andorinha, Área de Seção Transversal do Componente: 0.0039978 m2; EI-GRA-Soleira/ Peitoril - Granito cinza Andorinha, Volume Componente (Líquido): 0.0179901 m3; EI-GRA-Soleira/ Peitoril - Granito cinza Andorinha, Volume do componente (Bruto): 0.0179901 m3

# IfcCovering: FNDE-Tabica 60 x 60 (252)
In: TÉRREO
Type - PredefinedType: CEILING
Classification: Forro (Classificação Archicad); Material: Alumínio, Volume de Ar - Moldura
Pset_CoveringCommon - Material: FNDE-Tabica
Component Quantities - Alumínio, Área de Seção Transversal do Componente: 0.000566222 m2; Volume de Ar - Moldura, Altura do Componente Retangular: 0.03 m; Volume de Ar - Moldura, Largura do Componente Retangular: 0.03 m; Volume de Ar - Moldura, Área de Seção Transversal do Componente: 0.0009 m2
Name | 1_Bloco | 0_ID | Alumínio, Massa (kg) | Alumínio, Volume Componente (Líquido) (m3) = Alumínio, Volume do componente (Bruto) (m3) | Volume de Ar - Moldura, Massa (kg) | Volume de Ar - Moldura, Volume Componente (Líquido) (m3) = Volume de Ar - Moldura, Volume do componente (Bruto) (m3)
B72 | BLOCO B | B72 | 1.5595 | 0.000556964 | 0.00104178 | 0.000868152
4 x B21 | BLOCO B | B21 | 1.67274 | 0.000597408 | 0.00113948 | 0.00094957
2 x B21 | BLOCO B | B21 | 4.56754 | 0.00163126 | 0.003132 | 0.00261
4 x B21 | BLOCO B | B21 | 1.67285 | 0.000597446 | 0.00113956 | 0.00094963
4 x B21 | BLOCO B | B21 | 0.315557 | 0.000112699 | 0.0001944 | 0.000162
B21 | BLOCO A | B21 | 0.315557 | 0.000112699 | 0.0001944 | 0.000162
B71 | BLOCO B | B71 | 0.539044 | 0.000192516 | 0.000367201 | 0.000306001
B21 | BLOCO B | B21 | 7.77019 | 0.00277507 | 0.00531367 | 0.00442806
B21 | BLOCO B | B21 | 4.67546 | 0.00166981 | 0.0031644 | 0.002637
2 x B21 | BLOCO B | B21 | 1.50768 | 0.000538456 | 0.0010476 | 0.000873
2 x B21 | BLOCO B | B21 | 0.396355 | 0.000141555 | 0.00027 | 0.000225
2 x B21 | BLOCO B | B21 | 3.25169 | 0.00116132 | 0.00223563 | 0.00186303
2 x B21 | BLOCO B | B21 | 0.951202 | 0.000339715 | 0.000647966 | 0.000539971
B21 | BLOCO B | B21 | 3.88576 | 0.00138777 | 0.00266756 | 0.00222297
2 x B21 | BLOCO B | B21 | 0.951213 | 0.000339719 | 0.000647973 | 0.000539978
B21 | BLOCO B | B21 | 7.77013 | 0.00277505 | 0.00531363 | 0.00442802
B21 | BLOCO B | B21 | 0.396373 | 0.000141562 | 0.000270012 | 0.00022501
2 x B21 | BLOCO B | B21 | 0.396395 | 0.00014157 | 0.000270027 | 0.000225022
2 x B21 | BLOCO B | B21 | 3.25177 | 0.00116135 | 0.00223569 | 0.00186307
B21 | BLOCO B | B21 | 7.7701 | 0.00277504 | 0.00531361 | 0.00442801
B21 | BLOCO B | B21 | 7.7701 | 0.00277503 | 0.00531361 | 0.00442801
B21 | BLOCO B | B21 | 0.396374 | 0.000141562 | 0.000270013 | 0.000225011
B21 | BLOCO B | B21 | 3.88576 | 0.00138777 | 0.00266757 | 0.00222297
B21 | BLOCO B | B21 | 7.77014 | 0.00277505 | 0.00531364 | 0.00442803
B21 | BLOCO B | B21 | 0.396363 | 0.000141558 | 0.000270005 | 0.000225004
B21 | BLOCO B | B21 | 9.83113 | 0.00351112 | 0.0067176 | 0.005598
3 x B21 | BLOCO B | B21 | 4.67841 | 0.00167086 | 0.00320753 | 0.00267294
2 x B21 | BLOCO B | B21 | 4.04424 | 0.00144437 | 0.00277553 | 0.00231294
B21 | BLOCO B | B21 | 3.12485 | 0.00111602 | 0.00214923 | 0.00179102
2 x B21 | BLOCO B | B21 | 4.04435 | 0.00144441 | 0.0027756 | 0.002313
B21 | BLOCO B | B21 | 3.76614 | 0.00134505 | 0.0025758 | 0.0021465
4 x B21 | BLOCO B | B21 | 3.88581 | 0.00138779 | 0.0026676 | 0.002223
B21 | BLOCO B | B21 | 2.02207 | 0.000722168 | 0.00138773 | 0.00115644
4 x B21 | BLOCO B | B21 | 0.394828 | 0.00014101 | 0.0002484 | 0.000207
B21 | BLOCO B | B21 | 6.06504 | 0.00216608 | 0.00414183 | 0.00345152
B21 | BLOCO B | B21 | 7.77 | 0.002775 | 0.00531354 | 0.00442795
B21 | BLOCO B | B21 | 3.12481 | 0.001116 | 0.0021492 | 0.001791
B21 | BLOCO B | B21 | 2.65634 | 0.000948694 | 0.0018198 | 0.0015165
B21 | BLOCO B | B21 | 4.67536 | 0.00166977 | 0.00316433 | 0.00263694
B21 | BLOCO B | B21 | 0.396362 | 0.000141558 | 0.000270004 | 0.000225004
B21 | BLOCO B | B21 | 7.77001 | 0.002775 | 0.00531355 | 0.00442796
B21 | BLOCO B | B21 | 7.77009 | 0.00277503 | 0.0053136 | 0.004428
B73 | BLOCO B | B73 | 0.539044 | 0.000192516 | 0.000367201 | 0.000306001
B71 | BLOCO B | B71 | 22.6728 | 0.00809744 | 0.0154655 | 0.0128879
B13 | BLOCO A | B13 | 0.586607 | 0.000209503 | 0.000399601 | 0.000333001
B21 | BLOCO A | B21 | 7.53231 | 0.00269011 | 0.00515163 | 0.00429302
B21 | BLOCO A | B21 | 4.04435 | 0.00144441 | 0.0027756 | 0.002313
B21 | BLOCO A | B21 | 1.22946 | 0.000439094 | 0.0008478 | 0.0007065
B21 | BLOCO A | B21 | 1.82648 | 0.000652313 | 0.00124421 | 0.00103684
B21 | BLOCO A | B21 | 1.36346 | 0.000486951 | 0.0009288 | 0.000774
B21 | BLOCO A | B21 | 0.988409 | 0.000353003 | 0.000683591 | 0.000569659
B21 | BLOCO A | B21 | 1.36346 | 0.00048695 | 0.0009288 | 0.000774
B21 | BLOCO A | B21 | 1.90403 | 0.000680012 | 0.0013176 | 0.001098
B21 | BLOCO A | B21 | 5.31269 | 0.00189739 | 0.0036396 | 0.003033
B78 | BLOCO B | B78 | 0.489953 | 0.000174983 | 0.0003132 | 0.000261
B21 | BLOCO A | B21 | 2.78003 | 0.000992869 | 0.00191434 | 0.00159528
B22 | BLOCO A | B22 | 2.45789 | 0.000877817 | 0.00169489 | 0.00141241
B24 | BLOCO A | B24 | 2.45789 | 0.000877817 | 0.00169489 | 0.00141241
B25 | BLOCO A | B25 | 2.45789 | 0.000877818 | 0.00169489 | 0.00141241
B23 | BLOCO A | B23 | 2.78003 | 0.000992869 | 0.00191434 | 0.00159528
B26 | BLOCO A | B26 | 2.78003 | 0.00099287 | 0.00191434 | 0.00159528
B27 | BLOCO A | B27 | 2.45789 | 0.000877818 | 0.00169489 | 0.00141241
B28 | BLOCO A | B28 | 2.78003 | 0.00099287 | 0.00191434 | 0.00159528
B29 | BLOCO A | B29 | 3.2436 | 0.00115843 | 0.00223012 | 0.00185844
B30 | BLOCO A | B30 | 2.69417 | 0.000962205 | 0.00183529 | 0.00152941
B32 | BLOCO A | B32 | 2.69417 | 0.000962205 | 0.00183529 | 0.00152941
B33 | BLOCO A | B33 | 2.9319 | 0.00104711 | 0.00200751 | 0.00167293
B34 | BLOCO A | B34 | 2.93533 | 0.00104833 | 0.00200985 | 0.00167488
B35 | BLOCO A | B35 | 6.02501 | 0.00215179 | 0.00412484 | 0.00343737
B37 | BLOCO A | B37 | 4.12249 | 0.00147232 | 0.00282883 | 0.00235736
B39 | BLOCO A | B39 | 1.30961 | 0.000467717 | 0.000901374 | 0.000751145
B40 | BLOCO A | B40 | 0.315557 | 0.000112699 | 0.0001944 | 0.000162
B38 | BLOCO A | B38 | 3.25092 | 0.00116104 | 0.00223538 | 0.00186281
B41 | BLOCO A | B41 | 3.24879 | 0.00116028 | 0.0022131 | 0.00184425
B42 | BLOCO A | B42 | 1.60172 | 0.000572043 | 0.00110748 | 0.000922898
B43 | BLOCO A | B43 | 3.25092 | 0.00116104 | 0.00223538 | 0.00186281
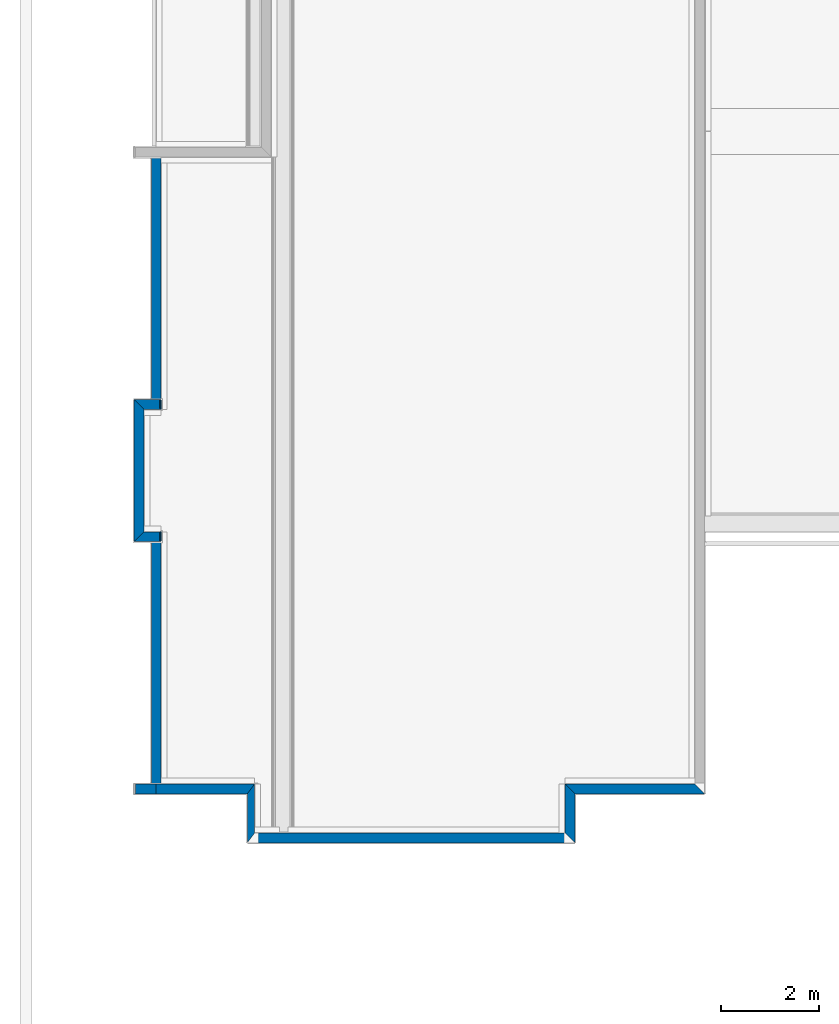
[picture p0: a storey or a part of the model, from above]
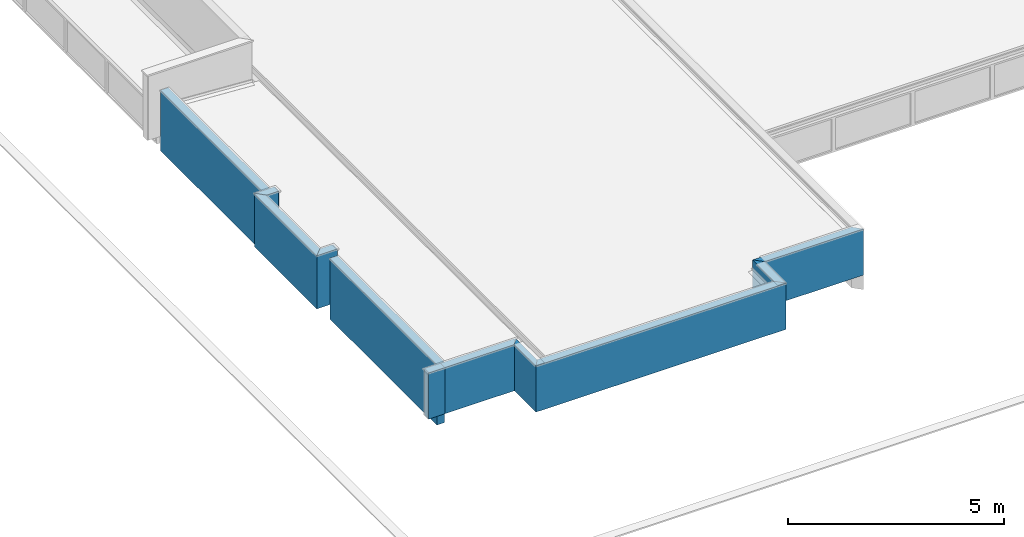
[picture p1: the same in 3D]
Properties of the parts of a building model (IFC4), part 3 of 22

# IfcCovering: FNDE-Tabica 60 x 60 (252)
Name | 1_Bloco | 0_ID | Alumínio, Massa (kg) | Alumínio, Volume Componente (Líquido) (m3) = Alumínio, Volume do componente (Bruto) (m3) | Volume de Ar - Moldura, Massa (kg) | Volume de Ar - Moldura, Volume Componente (Líquido) (m3) = Volume de Ar - Moldura, Volume do componente (Bruto) (m3)
B44 | BLOCO A | B44 | 3.33209 | 0.00119003 | 0.00229023 | 0.00190853
B45 | BLOCO A | B45 | 0.0000188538 | 6.73352e-09 | 1.28439e-08 | 1.07032e-08
B46 | BLOCO A | B46 | 1.58532 | 0.000566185 | 0.00107982 | 0.000899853
B36 | BLOCO A | B36 | 9.43476 | 0.00336956 | 0.00644759 | 0.00537299
B48 | BLOCO A | B48 | 3.29149 | 0.00117553 | 0.00225246 | 0.00187705
B49 | BLOCO A | B49 | 3.88578 | 0.00138778 | 0.00266758 | 0.00222298
B50 | BLOCO A | B50 | 4.67852 | 0.0016709 | 0.0032076 | 0.002673
B51 | BLOCO A | B51 | 3.88578 | 0.00138778 | 0.00266758 | 0.00222298
B69 | BLOCO A | B69 | 2.77412 | 0.000990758 | 0.00191031 | 0.00159193
B68 | BLOCO A | B68 | 3.0148 | 0.00107671 | 0.00207426 | 0.00172855
B52 | BLOCO A | B52 | 4.67852 | 0.0016709 | 0.0032076 | 0.002673
B47 | BLOCO A | B47 | 3.25195 | 0.00116141 | 0.00223581 | 0.00186318
B62 | BLOCO A | B62 | 1.27692 | 0.000456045 | 0.00088013 | 0.000733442
B61 | BLOCO A | B61 | 2.77601 | 0.000991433 | 0.0019116 | 0.001593
B64 | BLOCO A | B64 | 2.77601 | 0.000991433 | 0.0019116 | 0.001593
B66 | BLOCO A | B66 | 3.0148 | 0.00107671 | 0.00207426 | 0.00172855
B63 | BLOCO A | B63 | 1.73788 | 0.00062067 | 0.00119413 | 0.000995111
B67 | BLOCO A | B67 | 2.77412 | 0.000990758 | 0.00191031 | 0.00159193
B73 | BLOCO A | B73 | 2.31467 | 0.000826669 | 0.00157677 | 0.00131398
B65 | BLOCO A | B65 | 3.0148 | 0.00107671 | 0.00207426 | 0.00172855
B71 | BLOCO B | B71 | 0.659633 | 0.000235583 | 0.000470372 | 0.000391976
B72 | BLOCO A | B72 | 4.04435 | 0.00144441 | 0.0027756 | 0.002313
B75 | BLOCO A | B75 | 2.29882 | 0.000821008 | 0.00156597 | 0.00130498
B72 | BLOCO B | B72 | 1.5859 | 0.000566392 | 0.00110115 | 0.000917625
B71 | BLOCO B | B71 | 0.468647 | 0.000167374 | 0.0003885 | 0.00032375
B77 | BLOCO B | B77 | 11.0996 | 0.00396415 | 0.00758171 | 0.00631809
B84 | BLOCO A | B84 | 2.78003 | 0.000992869 | 0.00191434 | 0.00159528
B85 | BLOCO A | B85 | 5.23348 | 0.0018691 | 0.00358564 | 0.00298804
B87 | BLOCO A | B87 | 5.23348 | 0.0018691 | 0.00358564 | 0.00298804
B86 | BLOCO A | B86 | 2.78004 | 0.000992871 | 0.00191434 | 0.00159529
B12 | BLOCO A | B12 | 1.89534 | 0.000676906 | 0.0013014 | 0.0010845
B13 | BLOCO A | B13 | 2.42972 | 0.000867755 | 0.00165514 | 0.00137928
B15 | BLOCO A | B15 | 0.400375 | 0.000142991 | 0.000272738 | 0.000227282
B17 | BLOCO A | B17 | 6.73956 | 0.00240699 | 0.0046116 | 0.003843
B16 | BLOCO A | B16 | 10.0689 | 0.00359605 | 0.0068796 | 0.005733
B18 | BLOCO A | B18 | 2.48195 | 0.00088641 | 0.001701 | 0.0014175
B20 | BLOCO A | B20 | 7.77001 | 0.002775 | 0.00531355 | 0.00442796
B19 | BLOCO A | B19 | 5.10505 | 0.00182323 | 0.0034776 | 0.002898
B21 | BLOCO A | B21 | 0.396362 | 0.000141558 | 0.000270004 | 0.000225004
B23 | BLOCO A | B23 | 0.951202 | 0.000339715 | 0.000647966 | 0.000539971
B24 | BLOCO A | B24 | 3.88576 | 0.00138777 | 0.00266756 | 0.00222297
B22 | BLOCO A | B22 | 0.394828 | 0.00014101 | 0.0002484 | 0.000207
B25 | BLOCO A | B25 | 0.951213 | 0.000339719 | 0.000647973 | 0.000539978
B26 | BLOCO A | B26 | 0.394828 | 0.00014101 | 0.0002484 | 0.000207
B28 | BLOCO A | B28 | 7.77013 | 0.00277505 | 0.00531363 | 0.00442802
B27 | BLOCO A | B27 | 0.396373 | 0.000141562 | 0.000270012 | 0.00022501
B30 | BLOCO A | B30 | 7.77009 | 0.00277503 | 0.0053136 | 0.004428
B29 | BLOCO A | B29 | 3.25169 | 0.00116132 | 0.00223563 | 0.00186303
B31 | BLOCO A | B31 | 0.396355 | 0.000141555 | 0.00027 | 0.000225
B73 | BLOCO B | B73 | 0.659632 | 0.000235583 | 0.000470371 | 0.000391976
B33 | BLOCO A | B33 | 0.396355 | 0.000141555 | 0.00027 | 0.000225
B35 | BLOCO A | B35 | 3.25169 | 0.00116132 | 0.00223563 | 0.00186303
B36 | BLOCO A | B36 | 3.25169 | 0.00116132 | 0.00223563 | 0.00186303
B37 | BLOCO A | B37 | 7.80896 | 0.00278891 | 0.0053298 | 0.0044415
B38 | BLOCO A | B38 | 4.59772 | 0.00164204 | 0.003132 | 0.00261
B32 | BLOCO A | B32 | 4.67546 | 0.00166981 | 0.0031644 | 0.002637
B39 | BLOCO A | B39 | 7.80887 | 0.00278888 | 0.00532974 | 0.00444145
B40 | BLOCO A | B40 | 3.25169 | 0.00116132 | 0.00223563 | 0.00186303
B42 | BLOCO A | B42 | 0.396362 | 0.000141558 | 0.000270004 | 0.000225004
B43 | BLOCO A | B43 | 0.394828 | 0.00014101 | 0.0002484 | 0.000207
B41 | BLOCO A | B41 | 7.77001 | 0.002775 | 0.00531355 | 0.00442796
B45 | BLOCO A | B45 | 3.88576 | 0.00138777 | 0.00266756 | 0.00222297
B44 | BLOCO A | B44 | 0.951202 | 0.000339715 | 0.000647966 | 0.000539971
B46 | BLOCO A | B46 | 0.951213 | 0.000339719 | 0.000647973 | 0.000539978
B47 | BLOCO A | B47 | 0.394828 | 0.00014101 | 0.0002484 | 0.000207
B48 | BLOCO A | B48 | 0.396373 | 0.000141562 | 0.000270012 | 0.00022501
B14 | BLOCO A | B14 | 2.80056 | 0.0010002 | 0.00192878 | 0.00160732
B15 | BLOCO A | B15 | 1.75258 | 0.000625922 | 0.00120415 | 0.00100346
B49 | BLOCO A | B49 | 7.77013 | 0.00277505 | 0.00531363 | 0.00442802
B16 | BLOCO A | B16 | 0.230649 | 0.0000823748 | 0.0001674 | 0.0001395
B18 | BLOCO A | B18 | 8.95769 | 0.00319918 | 0.00610204 | 0.00508504
B17 | BLOCO A | B17 | 2.80056 | 0.0010002 | 0.00192878 | 0.00160732
B19 | BLOCO A | B19 | 6.33919 | 0.002264 | 0.00433886 | 0.00361572
B20 | BLOCO A | B20 | 11.0994 | 0.00396408 | 0.00758157 | 0.00631797
B24 | BLOCO A | B24 | 3.2516 | 0.00116128 | 0.00223557 | 0.00186298
B23 | BLOCO A | B23 | 9.43478 | 0.00336956 | 0.0064476 | 0.005373
B25 | BLOCO A | B25 | 2.78003 | 0.000992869 | 0.00191434 | 0.00159528
B26 | BLOCO A | B26 | 1.10987 | 0.000396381 | 0.000756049 | 0.000630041
2 x B72 | BLOCO B | B72 | 1.07578 | 0.000384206 | 0.000727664 | 0.000606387
B34 | BLOCO A | B34 | 7.77 | 0.002775 | 0.00531354 | 0.00442795
B27 | BLOCO A | B27 | 0.315557 | 0.000112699 | 0.0001944 | 0.000162
B72 | BLOCO B | B72 | 1.58695 | 0.000566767 | 0.0011016 | 0.000918
B21 | BLOCO A | B21 | 3.0996 | 0.001107 | 0.00211147 | 0.00175956
B22 | BLOCO A | B22 | 3.47338 | 0.00124049 | 0.00238665 | 0.00198888
B26 | BLOCO A | B26 | 0.435444 | 0.000155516 | 0.000286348 | 0.000238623
B27 | BLOCO A | B27 | 0.103375 | 0.0000369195 | 0.0000704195 | 0.0000586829
B28 | BLOCO A | B28 | 0.413513 | 0.000147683 | 0.000291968 | 0.000243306
B25 | BLOCO A | B25 | 3.17852 | 0.00113519 | 0.00216523 | 0.00180436
B29 | BLOCO A | B29 | 3.88576 | 0.00138777 | 0.00266757 | 0.00222297
B30 | BLOCO A | B30 | 0.407394 | 0.000145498 | 0.0002878 | 0.000239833
B32 | BLOCO A | B32 | 0.394828 | 0.00014101 | 0.0002484 | 0.000207
B31 | BLOCO A | B31 | 0.544949 | 0.000194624 | 0.000360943 | 0.000300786
B33 | BLOCO A | B33 | 0.396584 | 0.000141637 | 0.000270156 | 0.00022513
B35 | BLOCO A | B35 | 0.0712151 | 0.000025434 | 0.0000485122 | 0.0000404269
B34 | BLOCO A | B34 | 7.74679 | 0.00276671 | 0.00529773 | 0.00441478
B36 | BLOCO A | B36 | 0.489953 | 0.000174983 | 0.0003132 | 0.000261
B38 | BLOCO A | B38 | 11.0996 | 0.00396415 | 0.00758171 | 0.00631809
B37 | BLOCO A | B37 | 0.0711755 | 0.0000254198 | 0.0000484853 | 0.0000404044
B39 | BLOCO A | B39 | 1.03047 | 0.000368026 | 0.000701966 | 0.000584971
B41 | BLOCO A | B41 | 3.88577 | 0.00138777 | 0.00266757 | 0.00222298
B42 | BLOCO A | B42 | 2.77622 | 0.000991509 | 0.00191174 | 0.00159312
B44 | BLOCO A | B44 | 2.77622 | 0.000991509 | 0.00191174 | 0.00159312
B43 | BLOCO A | B43 | 3.88577 | 0.00138777 | 0.00266757 | 0.00222298
B46 | BLOCO A | B46 | 0.696058 | 0.000248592 | 0.0004536 | 0.000378
B45 | BLOCO A | B45 | 0.951253 | 0.000339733 | 0.000648 | 0.00054
B48 | BLOCO A | B48 | 2.4577 | 0.00087775 | 0.00169476 | 0.0014123
B47 | BLOCO A | B47 | 0.951253 | 0.000339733 | 0.000648 | 0.00054
B50 | BLOCO A | B50 | 0.902164 | 0.000322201 | 0.000594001 | 0.000495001
B52 | BLOCO A | B52 | 19.6275 | 0.00700982 | 0.0133704 | 0.011142
B49 | BLOCO A | B49 | 0.951253 | 0.000339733 | 0.000648 | 0.00054
B54 | BLOCO B | B54 | 0.489953 | 0.000174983 | 0.0003132 | 0.000261
B55 | BLOCO B | B55 | 0.129383 | 0.0000462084 | 0.000088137 | 0.0000734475
B53 | BLOCO B | B53 | 0.129344 | 0.0000461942 | 0.00008811 | 0.000073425
B58 | BLOCO B | B58 | 4.67541 | 0.00166979 | 0.00316437 | 0.00263697
B56 | BLOCO B | B56 | 7.74645 | 0.00276659 | 0.0052975 | 0.00441458
B57 | BLOCO B | B57 | 0.87221 | 0.000311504 | 0.000594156 | 0.00049513
B66 | BLOCO B | B66 | 0.87221 | 0.000311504 | 0.000594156 | 0.00049513
B68 | BLOCO B | B68 | 3.88581 | 0.00138779 | 0.0026676 | 0.002223
B67 | BLOCO B | B67 | 2.7837 | 0.000994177 | 0.00191683 | 0.00159736
B73 | BLOCO B | B73 | 0.659633 | 0.000235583 | 0.000470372 | 0.000391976
B72 | BLOCO B | B72 | 3.88577 | 0.00138777 | 0.00266757 | 0.00222298
B71 | BLOCO B | B71 | 17.2357 | 0.00615559 | 0.0117616 | 0.00980135
B73 | BLOCO B | B73 | 2.77622 | 0.000991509 | 0.00191174 | 0.00159312
B74 | BLOCO B | B74 | 3.88577 | 0.00138777 | 0.00265799 | 0.00221499
B75 | BLOCO B | B75 | 0.0922879 | 0.0000329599 | 0.0000324 | 0.000027
B76 | BLOCO B | B76 | 3.88577 | 0.00138777 | 0.00265799 | 0.00221499
B77 | BLOCO B | B77 | 14.1829 | 0.00506532 | 0.00968205 | 0.00806838
B17 | BLOCO A | B17 | 9.67259 | 0.0034545 | 0.0066096 | 0.005508
B18 | BLOCO A | B18 | 2.49733 | 0.000891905 | 0.00172176 | 0.0014348
B19 | BLOCO A | B19 | 9.67259 | 0.0034545 | 0.0066096 | 0.005508
B16 | BLOCO A | B16 | 2.49733 | 0.000891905 | 0.00172176 | 0.0014348
B51 | BLOCO A | B51 | 0.951253 | 0.000339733 | 0.000648 | 0.00054
B51 | BLOCO A | B51 | 0.665886 | 0.000237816 | 0.000453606 | 0.000378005
B22 | BLOCO B | B22 | 1.11217 | 0.000397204 | 0.000778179 | 0.000648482
B21 | BLOCO B | B21 | 3.42598 | 0.00122357 | 0.00235437 | 0.00196197
B24 | BLOCO B | B24 | 1.11221 | 0.000397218 | 0.000778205 | 0.000648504
B23 | BLOCO B | B23 | 3.42598 | 0.00122357 | 0.00235437 | 0.00196197
B79 | BLOCO B | B79 | 0.129344 | 0.0000461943 | 0.00008811 | 0.000073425
B39 | BLOCO A | B39 | 1.98391 | 0.00070854 | 0.00130391 | 0.00108659
B71 | BLOCO B | B71 | 2.77622 | 0.000991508 | 0.00191174 | 0.00159312
B39 | BLOCO A | B39 | 0.1002 | 0.0000357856 | 0.0000687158 | 0.0000572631
B14 | BLOCO A | B14 | 1.34918 | 0.00048185 | 0.000906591 | 0.000755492
B44 | BLOCO A | B44 | 10.6795 | 0.0038141 | 0.00728522 | 0.00607102
B38 | BLOCO A | B38 | 0.0711755 | 0.0000254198 | 0.0000484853 | 0.0000404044
B40 | BLOCO A | B40 | 0.0711755 | 0.0000254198 | 0.0000484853 | 0.0000404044
B38 | BLOCO A | B38 | 14.1825 | 0.0050652 | 0.00968182 | 0.00806818
B39 | BLOCO A | B39 | 0.489953 | 0.000174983 | 0.0003132 | 0.000261
B77 | BLOCO B | B77 | 0.129344 | 0.0000461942 | 0.00008811 | 0.000073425

# IfcCovering: FORRO EM FIBRA MINERAL 40 (9)
In: TÉRREO
Type - PredefinedType: CEILING
Classification: Forro (Classificação Archicad); Material: FORRO EM FIBRA MINERAL
Pset_CoveringCommon - Material: FORRO EM FIBRA MINERAL
Component Quantities - FORRO EM FIBRA MINERAL, Espessura do Componente: 0.04 m
Name | 1_Bloco | 0_ID | FORRO EM FIBRA MINERAL, Massa (kg) | FORRO EM FIBRA MINERAL, Área de Componente Projetada (Líquida) (m2) = FORRO EM FIBRA MINERAL, Área de Componente Projetada (Bruta) (m2) | FORRO EM FIBRA MINERAL, Volume Componente (Líquido) (m3) = FORRO EM FIBRA MINERAL, Volume do componente (Bruto) (m3)
Forro-001 | BLOCO B | Forro-001 | 57.1191 | 35.6994 | 1.42798
Forro-001 | BLOCO B | Forro-001 | 61.4404 | 38.4003 | 1.53601
Forro-001 | BLOCO B | Forro-001 | 56.8203 | 35.5127 | 1.42051
Forro-001 | BLOCO B | Forro-001 | 57.0109 | 35.6318 | 1.42527
Forro-001 | BLOCO B | Forro-001 | 56.9279 | 35.5799 | 1.4232
Forro-001 | BLOCO A | Forro-001 | 57.215 | 35.7594 | 1.43037
Forro-002 | BLOCO A | Forro-002 | 25.9199 | 16.1999 | 0.647997
Forro-004 | BLOCO A | Forro-004 | 11.9423 | 7.46396 | 0.298558
Forro-003 | BLOCO A | Forro-003 | 30.6715 | 19.1697 | 0.766786

# IfcCovering: RODAMEIO EM MADEIRA COM PINTURA ESMALTE NA COR BRANCA 13 x 70 (47)
In: TÉRREO
Classification: Rodapé (Classificação Archicad); Material: RODAMEIO EM MADEIRA COM PINTURA ESMALTE NA COR BRANCA
Pset_CoveringCommon - Material: RODAMEIO EM MADEIRA COM PINTURA ESMALTE NA COR BRANCA
Component Quantities - RODAMEIO EM MADEIRA COM PINTURA ESMALTE NA COR BRANCA, Espessura do Componente: 0.013 m; RODAMEIO EM MADEIRA COM PINTURA ESMALTE NA COR BRANCA, Altura do Componente Retangular: 0.07 m; RODAMEIO EM MADEIRA COM PINTURA ESMALTE NA COR BRANCA, Largura do Componente Retangular: 0.013 m; RODAMEIO EM MADEIRA COM PINTURA ESMALTE NA COR BRANCA, Área de Seção Transversal do Componente: 0.00091 m2
Name | 1_Bloco | RODAMEIO EM MADEIRA COM PINTURA ESMALTE NA COR BRANCA, Massa (kg) | RODAMEIO EM MADEIRA COM PINTURA ESMALTE NA COR BRANCA, Área de Componente Projetada (Líquida) (m2) = RODAMEIO EM MADEIRA COM PINTURA ESMALTE NA COR BRANCA, Área de Componente Projetada (Bruta) (m2) | RODAMEIO EM MADEIRA COM PINTURA ESMALTE NA COR BRANCA, Volume Componente (Líquido) (m3) = RODAMEIO EM MADEIRA COM PINTURA ESMALTE NA COR BRANCA, Volume do componente (Bruto) (m3)
 | BLOCO B | 1.63443 | 0.419995 | 0.0054481
3 x  | BLOCO B | 1.63446 | 0.420003 | 0.00544821
2 x  | BLOCO B | 0.0427245 | 0.01141 | 0.000142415
2 x  | BLOCO B | 0.12285 | 0.03241 | 0.0004095
 | BLOCO B | 0.271207 | 0.0699952 | 0.000904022
 | BLOCO B | 0.121076 | 0.0315 | 0.000403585
 | BLOCO B | 0.1638 | 0.04291 | 0.000546
 | BLOCO B | 0.0146053 | 0.00419996 | 0.0000486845
 | BLOCO B | 0.257576 | 0.0665 | 0.000858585
 | BLOCO B | 0.212531 | 0.05495 | 0.000708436
 | BLOCO B | 0.257584 | 0.0665021 | 0.000858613
 | BLOCO B | 0.257575 | 0.0665 | 0.000858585
 | BLOCO B | 1.63624 | 0.420003 | 0.00545412
 | BLOCO B | 0.121094 | 0.0315048 | 0.000403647
 | BLOCO B | 1.47064 | 0.377998 | 0.00490215
 | BLOCO B | 0.298524 | 0.0769995 | 0.000995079
 | BLOCO B | 0.165574 | 0.04291 | 0.000551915
 | BLOCO B | 0.257567 | 0.0664979 | 0.000858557
 | BLOCO B | 0.0591045 | 0.01561 | 0.000197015
 | BLOCO B | 0.0146055 | 0.0042 | 0.000048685
 | BLOCO B | 0.212549 | 0.0549547 | 0.000708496
 | BLOCO B | 1.15434 | 0.29644 | 0.00384781
 | BLOCO A | 0.271225 | 0.07 | 0.000904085
 | BLOCO A | 0.220017 | 0.0568695 | 0.000733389
 | BLOCO A | 1.63717 | 0.420698 | 0.00545725
 | BLOCO A | 1.14709 | 0.29458 | 0.00382362
 | BLOCO A | 0.121076 | 0.0315 | 0.000403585
 | BLOCO B | 1.63444 | 0.419998 | 0.00544815
2 x  | BLOCO B | 1.15616 | 0.29645 | 0.00385385
 | BLOCO B | 1.32405 | 0.3395 | 0.0044135
 | BLOCO B | 0.29854 | 0.0770038 | 0.000995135
 | BLOCO A | 0.994669 | 0.255498 | 0.00331556
 | BLOCO B | 0.883708 | 0.227502 | 0.00294569
 | BLOCO B | 1.3205 | 0.3395 | 0.00440167
 | BLOCO A | 0.424105 | 0.1092 | 0.00141368
 | BLOCO B | 1.47419 | 0.377998 | 0.00491398
 | BLOCO B | 0.271226 | 0.0700002 | 0.000904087
 | BLOCO B | 1.63446 | 0.420002 | 0.00544819
 | BLOCO B | 1.04751 | 0.269502 | 0.00349169
 | BLOCO B | 1.15438 | 0.29645 | 0.00384794
 | BLOCO B | 0.0591043 | 0.01561 | 0.000197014
 | BLOCO B | 1.63526 | 0.419298 | 0.00545088

# IfcDoor: FNDE - Porta Personalizada - Com veneziana (3)
In: TÉRREO
OverallHeight: 2.4 m; OverallWidth: 1.5 m; Classification: Porta (Classificação Archicad); Material: Água, Madeira
Pset_DoorCommon - ThermalTransmittance: 0; IsExternal: no
FNDE - Esquadrias - Grupo da Esquadria: PORTA DE MADEIRA; Soleira/Peitoril: SOLEIRA EM GRANITO CINZA ANDORINHA E=2cm; Esquadrias - Tipo de Abertura: DE ABRIR; Esquadrias - Descrição ou Complemento: COM VENEZIANA; Esquadrias - Tipo de Vidro: -; Esquadrias - Quantidade de Folhas: 01 FOLHA; Esquadrias - Fechaduras: Internas; Esquadrias - Fechamentos metálicos e Gradis: -; 0_ID: PM2; Esquadrias - Verga e Contra-verga: C1-IN - Verga Interna
Component Quantities - Água, Massa: 84.1503 kg; Água, Volume Componente (Líquido): 0.0841503 m3; Água, Volume do componente (Bruto): 0.0841503 m3; Madeira, Massa: 0.4248 kg; Madeira, Volume Componente (Líquido): 0.001416 m3; Madeira, Volume do componente (Bruto): 0.001416 m3
Name | 1_Bloco
PM2 | BLOCO B
2 x PM2 | BLOCO A

# IfcDoor: FNDE - Porta Personalizada - Com visor (5)
In: TÉRREO
OverallHeight: 2.4 m; OverallWidth: 1.5 m; Classification: Porta (Classificação Archicad); Material: Alumínio, Vidro, Madeira, Madeira Compensada
Pset_DoorCommon - ThermalTransmittance: 0; IsExternal: no
FNDE - Esquadrias - Grupo da Esquadria: PORTA DE MADEIRA; Soleira/Peitoril: SOLEIRA EM GRANITO CINZA ANDORINHA E=2cm; Esquadrias - Tipo de Abertura: DE ABRIR; Esquadrias - Descrição ou Complemento: COM VISOR DE VIDRO E CHAPA METÁLICA; Esquadrias - Tipo de Vidro: TEMPERADO INCOLOR 6mm VISOR; Esquadrias - Quantidade de Folhas: 01 FOLHA; Esquadrias - Fechaduras: Internas; Esquadrias - Fechamentos metálicos e Gradis: -; 0_ID: PM4; Esquadrias - Verga e Contra-verga: C1-IN - Verga Interna
Component Quantities - Alumínio, Massa: 0.140758 kg; Alumínio, Volume Componente (Líquido): 0.0000502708 m3; Alumínio, Volume do componente (Bruto): 0.0000502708 m3; Vidro, Massa: 0 kg; Vidro, Volume Componente (Líquido): 0 m3; Vidro, Volume do componente (Bruto): 0 m3; Madeira, Massa: 13.008 kg; Madeira, Volume Componente (Líquido): 0.04336 m3; Madeira, Volume do componente (Bruto): 0.04336 m3; Madeira Compensada, Massa: 46.368 kg; Madeira Compensada, Volume Componente (Líquido): 0.046368 m3; Madeira Compensada, Volume do componente (Bruto): 0.046368 m3
Name | 1_Bloco
4 x PM4 | BLOCO B
PM4 | BLOCO A

# IfcDoor: FNDE - Porta Personalizada - Sanitários (3)
In: TÉRREO
OverallHeight: 2.4 m; OverallWidth: 1.5 m; Classification: Porta (Classificação Archicad); Material: Água
Pset_DoorCommon - ThermalTransmittance: 0; IsExternal: no
FNDE - Esquadrias - Grupo da Esquadria: PORTA DE MADEIRA; Soleira/Peitoril: SOLEIRA EM GRANITO CINZA ANDORINHA E=2cm; Esquadrias - Tipo de Abertura: DE ABRIR; Esquadrias - Descrição ou Complemento: COM CHAPA E BARRA METÁLICA; Esquadrias - Tipo de Vidro: -; Esquadrias - Quantidade de Folhas: 01 FOLHA; Esquadrias - Fechaduras: Banheiros; Esquadrias - Fechamentos metálicos e Gradis: -; 0_ID: PM3; Esquadrias - Verga e Contra-verga: C1-IN - Verga Interna
Component Quantities - Água, Massa: 94.7107 kg; Água, Volume Componente (Líquido): 0.0947107 m3; Água, Volume do componente (Bruto): 0.0947107 m3
Name | 1_Bloco
PM3 | BLOCO B
2 x PM3 | BLOCO A

# IfcDoor: FNDE - Porta Personalizada - sanitarios infantis - amarelo (2)
In: TÉRREO
OverallHeight: 2.4 m; OverallWidth: 1.5 m; Classification: Porta (Classificação Archicad); Material: Água, Alumínio
Pset_DoorCommon - ThermalTransmittance: 0; IsExternal: no
FNDE - Esquadrias - Grupo da Esquadria: PORTA DE MADEIRA; Soleira/Peitoril: -; Esquadrias - Tipo de Abertura: DE ABRIR; Esquadrias - Descrição ou Complemento: COM REVESTIMENTO EM LAMINADO MELAMÍNICO; Esquadrias - Tipo de Vidro: -; Esquadrias - Quantidade de Folhas: 01 FOLHA; Esquadrias - Fechaduras: Tarj. Livre/Ocupado; Esquadrias - Fechamentos metálicos e Gradis: -; 1_Bloco: BLOCO B; 0_ID: PM5; Esquadrias - Verga e Contra-verga: -
Component Quantities - Água, Massa: 13.56 kg; Água, Volume Componente (Líquido): 0.01356 m3; Água, Volume do componente (Bruto): 0.01356 m3; Alumínio, Massa: 0.0468757 kg; Alumínio, Volume Componente (Líquido): 0.0000167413 m3; Alumínio, Volume do componente (Bruto): 0.0000167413 m3

# IfcDoor: FNDE - Porta Personalizada - sanitarios infantis - azul (2)
In: TÉRREO
OverallHeight: 2.4 m; OverallWidth: 1.5 m; Classification: Porta (Classificação Archicad); Material: Água, Alumínio
Pset_DoorCommon - ThermalTransmittance: 0; IsExternal: no
FNDE - Esquadrias - Grupo da Esquadria: PORTA DE MADEIRA; Soleira/Peitoril: -; Esquadrias - Tipo de Abertura: DE ABRIR; Esquadrias - Descrição ou Complemento: COM REVESTIMENTO EM LAMINADO MELAMÍNICO; Esquadrias - Tipo de Vidro: -; Esquadrias - Quantidade de Folhas: 01 FOLHA; Esquadrias - Fechaduras: Tarj. Livre/Ocupado; Esquadrias - Fechamentos metálicos e Gradis: -; 1_Bloco: BLOCO B; 0_ID: PM5; Esquadrias - Verga e Contra-verga: -
Component Quantities - Água, Massa: 13.56 kg; Água, Volume Componente (Líquido): 0.01356 m3; Água, Volume do componente (Bruto): 0.01356 m3; Alumínio, Massa: 0.0468757 kg; Alumínio, Volume Componente (Líquido): 0.0000167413 m3; Alumínio, Volume do componente (Bruto): 0.0000167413 m3

# IfcDoor: FNDE - Porta Personalizada - sanitarios infantis - laranja (2)
In: TÉRREO
OverallHeight: 2.4 m; OverallWidth: 1.5 m; Classification: Porta (Classificação Archicad); Material: Água, Alumínio
Pset_DoorCommon - ThermalTransmittance: 0; IsExternal: no
FNDE - Esquadrias - Grupo da Esquadria: PORTA DE MADEIRA; Soleira/Peitoril: -; Esquadrias - Tipo de Abertura: DE ABRIR; Esquadrias - Descrição ou Complemento: COM REVESTIMENTO EM LAMINADO MELAMÍNICO; Esquadrias - Tipo de Vidro: -; Esquadrias - Quantidade de Folhas: 01 FOLHA; Esquadrias - Fechaduras: Tarj. Livre/Ocupado; Esquadrias - Fechamentos metálicos e Gradis: -; 1_Bloco: BLOCO B; 0_ID: PM5; Esquadrias - Verga e Contra-verga: -
Component Quantities - Água, Massa: 13.56 kg; Água, Volume Componente (Líquido): 0.01356 m3; Água, Volume do componente (Bruto): 0.01356 m3; Alumínio, Massa: 0.0468757 kg; Alumínio, Volume Componente (Líquido): 0.0000167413 m3; Alumínio, Volume do componente (Bruto): 0.0000167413 m3

# IfcDoor: FNDE - Porta Personalizada - sanitarios infantis - verde (2)
In: TÉRREO
OverallHeight: 2.4 m; OverallWidth: 1.5 m; Classification: Porta (Classificação Archicad); Material: Água, Alumínio
Pset_DoorCommon - ThermalTransmittance: 0; IsExternal: no
FNDE - Esquadrias - Grupo da Esquadria: PORTA DE MADEIRA; Soleira/Peitoril: -; Esquadrias - Tipo de Abertura: DE ABRIR; Esquadrias - Descrição ou Complemento: COM REVESTIMENTO EM LAMINADO MELAMÍNICO; Esquadrias - Tipo de Vidro: -; Esquadrias - Quantidade de Folhas: 01 FOLHA; Esquadrias - Fechaduras: Tarj. Livre/Ocupado; Esquadrias - Fechamentos metálicos e Gradis: -; 1_Bloco: BLOCO B; 0_ID: PM5; Esquadrias - Verga e Contra-verga: -
Component Quantities - Água, Massa: 13.56 kg; Água, Volume Componente (Líquido): 0.01356 m3; Água, Volume do componente (Bruto): 0.01356 m3; Alumínio, Massa: 0.0468757 kg; Alumínio, Volume Componente (Líquido): 0.0000167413 m3; Alumínio, Volume do componente (Bruto): 0.0000167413 m3

# IfcDoor: FNDE-PF solarios R01 (2)
In: TÉRREO
OverallHeight: 2.4 m; OverallWidth: 1.5 m; Classification: Porta (Classificação Archicad); Material: EI-MTL-CHAPA DE AÇO CARBONO PERFURADA -AMARELO, EI-MTL-PERFIL EM AÇO GALVANIZADO -AMARELO
Pset_DoorCommon - ThermalTransmittance: 0; IsExternal: yes
FNDE - Esquadrias - Grupo da Esquadria: PORTÃO METÁLICO; Soleira/Peitoril: -; Esquadrias - Tipo de Abertura: DE ABRIR; Esquadrias - Descrição ou Complemento: COM CHAPA METÁLICA; Esquadrias - Tipo de Vidro: -; Esquadrias - Quantidade de Folhas: 01 FOLHA; Esquadrias - Fechaduras: -; Esquadrias - Fechamentos metálicos e Gradis: -; 1_Bloco: BLOCO B; 0_ID: PF2; Esquadrias - Verga e Contra-verga: -
Component Quantities - EI-MTL-CHAPA DE AÇO CARBONO PERFURADA -AMARELO, Massa: 11.8381 kg; EI-MTL-CHAPA DE AÇO CARBONO PERFURADA -AMARELO, Volume Componente (Líquido): 0.0014985 m3; EI-MTL-CHAPA DE AÇO CARBONO PERFURADA -AMARELO, Volume do componente (Bruto): 0.0014985 m3; EI-MTL-PERFIL EM AÇO GALVANIZADO -AMARELO, Massa: 126.037 kg; EI-MTL-PERFIL EM AÇO GALVANIZADO -AMARELO, Volume Componente (Líquido): 0.015954 m3; EI-MTL-PERFIL EM AÇO GALVANIZADO -AMARELO, Volume do componente (Bruto): 0.015954 m3

# IfcDoor: FNDE-PO-1 Folha 120, PO3
In: TÉRREO
OverallHeight: 2.4 m; OverallWidth: 1.5 m; Classification: Porta (Classificação Archicad); Material: EI-MTL-PERFIL EM AÇO GALVANIZADO, GENÉRICO - ESTRUTURAL, EI-MTL-PERFIL EM AÇO GALVANIZADO -AMARELO
Pset_DoorCommon - ThermalTransmittance: 0; IsExternal: yes
FNDE - Esquadrias - Grupo da Esquadria: PORTÃO METÁLICO; Soleira/Peitoril: -; Esquadrias - Tipo de Abertura: DE ABRIR; Esquadrias - Descrição ou Complemento: COM GRADIL METÁLICO E TELA DE AÇO GALVANIZADO; Esquadrias - Tipo de Vidro: -; Esquadrias - Quantidade de Folhas: 01 FOLHA; Esquadrias - Fechaduras: -; Esquadrias - Fechamentos metálicos e Gradis: -; 1_Bloco: MURETAS; 0_ID: PO3; Esquadrias - Verga e Contra-verga: -
Component Quantities - EI-MTL-PERFIL EM AÇO GALVANIZADO, Massa: 171.588 kg; EI-MTL-PERFIL EM AÇO GALVANIZADO, Volume Componente (Líquido): 0.02172 m3; EI-MTL-PERFIL EM AÇO GALVANIZADO, Volume do componente (Bruto): 0.02172 m3; GENÉRICO - ESTRUTURAL, Massa: 0.117714 kg; GENÉRICO - ESTRUTURAL, Volume Componente (Líquido): 0.00005118 m3; GENÉRICO - ESTRUTURAL, Volume do componente (Bruto): 0.00005118 m3; EI-MTL-PERFIL EM AÇO GALVANIZADO -AMARELO, Massa: 1.64121 kg; EI-MTL-PERFIL EM AÇO GALVANIZADO -AMARELO, Volume Componente (Líquido): 0.000207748 m3; EI-MTL-PERFIL EM AÇO GALVANIZADO -AMARELO, Volume do componente (Bruto): 0.000207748 m3

# IfcDoor: FNDE-PO-1 Folha 140 180graus, PO2
In: TÉRREO
OverallHeight: 2.4 m; OverallWidth: 1.5 m; Classification: Porta (Classificação Archicad); Material: EI-MTL-PERFIL EM AÇO GALVANIZADO, GENÉRICO - ESTRUTURAL, EI-MTL-PERFIL EM AÇO GALVANIZADO -AMARELO
Pset_DoorCommon - ThermalTransmittance: 0; IsExternal: yes
FNDE - Esquadrias - Grupo da Esquadria: PORTÃO METÁLICO; Soleira/Peitoril: -; Esquadrias - Tipo de Abertura: DE ABRIR 180º; Esquadrias - Descrição ou Complemento: COM GRADIL METÁLICO E TELA DE AÇO GALVANIZADO; Esquadrias - Tipo de Vidro: -; Esquadrias - Quantidade de Folhas: 01 FOLHA; Esquadrias - Fechaduras: -; Esquadrias - Fechamentos metálicos e Gradis: -; 1_Bloco: MURETAS; 0_ID: PO2; Esquadrias - Verga e Contra-verga: -
Component Quantities - EI-MTL-PERFIL EM AÇO GALVANIZADO, Massa: 185.808 kg; EI-MTL-PERFIL EM AÇO GALVANIZADO, Volume Componente (Líquido): 0.02352 m3; EI-MTL-PERFIL EM AÇO GALVANIZADO, Volume do componente (Bruto): 0.02352 m3; GENÉRICO - ESTRUTURAL, Massa: 0.139978 kg; GENÉRICO - ESTRUTURAL, Volume Componente (Líquido): 0.00006086 m3; GENÉRICO - ESTRUTURAL, Volume do componente (Bruto): 0.00006086 m3; EI-MTL-PERFIL EM AÇO GALVANIZADO -AMARELO, Massa: 1.64121 kg; EI-MTL-PERFIL EM AÇO GALVANIZADO -AMARELO, Volume Componente (Líquido): 0.000207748 m3; EI-MTL-PERFIL EM AÇO GALVANIZADO -AMARELO, Volume do componente (Bruto): 0.000207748 m3

# IfcDoor: FNDE-PO-1 Folha 140 90graus, PO2
In: TÉRREO
OverallHeight: 2.4 m; OverallWidth: 1.5 m; Classification: Porta (Classificação Archicad); Material: EI-MTL-PERFIL EM AÇO GALVANIZADO, GENÉRICO - ESTRUTURAL, EI-MTL-PERFIL EM AÇO GALVANIZADO -AMARELO
Pset_DoorCommon - ThermalTransmittance: 0; IsExternal: yes
FNDE - Esquadrias - Grupo da Esquadria: PORTÃO METÁLICO; Soleira/Peitoril: -; Esquadrias - Tipo de Abertura: DE ABRIR 180º; Esquadrias - Descrição ou Complemento: COM GRADIL METÁLICO E TELA DE AÇO GALVANIZADO; Esquadrias - Tipo de Vidro: -; Esquadrias - Quantidade de Folhas: 01 FOLHA; Esquadrias - Fechaduras: -; Esquadrias - Fechamentos metálicos e Gradis: -; 1_Bloco: MURETAS; 0_ID: PO2; Esquadrias - Verga e Contra-verga: -
Component Quantities - EI-MTL-PERFIL EM AÇO GALVANIZADO, Massa: 185.808 kg; EI-MTL-PERFIL EM AÇO GALVANIZADO, Volume Componente (Líquido): 0.02352 m3; EI-MTL-PERFIL EM AÇO GALVANIZADO, Volume do componente (Bruto): 0.02352 m3; GENÉRICO - ESTRUTURAL, Massa: 0.139978 kg; GENÉRICO - ESTRUTURAL, Volume Componente (Líquido): 0.00006086 m3; GENÉRICO - ESTRUTURAL, Volume do componente (Bruto): 0.00006086 m3; EI-MTL-PERFIL EM AÇO GALVANIZADO -AMARELO, Massa: 1.64121 kg; EI-MTL-PERFIL EM AÇO GALVANIZADO -AMARELO, Volume Componente (Líquido): 0.000207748 m3; EI-MTL-PERFIL EM AÇO GALVANIZADO -AMARELO, Volume do componente (Bruto): 0.000207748 m3

# IfcDoor: FNDE-PO-2 Folhas 185 (2)
In: TÉRREO
OverallHeight: 2.4 m; OverallWidth: 1.5 m; Classification: Porta (Classificação Archicad); Material: EI-MTL-PERFIL EM AÇO GALVANIZADO, GENÉRICO - ESTRUTURAL, EI-MTL-PERFIL EM AÇO GALVANIZADO -AMARELO
Pset_DoorCommon - ThermalTransmittance: 0; IsExternal: yes
FNDE - Esquadrias - Grupo da Esquadria: PORTÃO METÁLICO; Soleira/Peitoril: SOLEIRA EM GRANITO CINZA ANDORINHA E=2cm; Esquadrias - Tipo de Abertura: DE ABRIR 180º; Esquadrias - Descrição ou Complemento: COM GRADIL METÁLICO E TELA DE AÇO GALVANIZADO; Esquadrias - Tipo de Vidro: -; Esquadrias - Quantidade de Folhas: 02 FOLHAS; Esquadrias - Fechaduras: -; Esquadrias - Fechamentos metálicos e Gradis: -; 1_Bloco: MURETAS; 0_ID: PO1; Esquadrias - Verga e Contra-verga: -
Component Quantities - EI-MTL-PERFIL EM AÇO GALVANIZADO, Massa: 312.129 kg; EI-MTL-PERFIL EM AÇO GALVANIZADO, Volume Componente (Líquido): 0.03951 m3; EI-MTL-PERFIL EM AÇO GALVANIZADO, Volume do componente (Bruto): 0.03951 m3; GENÉRICO - ESTRUTURAL, Massa: 0.175536 kg; GENÉRICO - ESTRUTURAL, Volume Componente (Líquido): 0.00007632 m3; GENÉRICO - ESTRUTURAL, Volume do componente (Bruto): 0.00007632 m3; EI-MTL-PERFIL EM AÇO GALVANIZADO -AMARELO, Massa: 2.63997 kg; EI-MTL-PERFIL EM AÇO GALVANIZADO -AMARELO, Volume Componente (Líquido): 0.000334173 m3; EI-MTL-PERFIL EM AÇO GALVANIZADO -AMARELO, Volume do componente (Bruto): 0.000334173 m3

# IfcDoor: FNDE-PV-Acesso (2)
In: TÉRREO
OverallHeight: 2.4 m; OverallWidth: 1.5 m; Classification: Porta (Classificação Archicad); Material: Água, Alumínio, GENÉRICO - REV. INTERNO
Pset_DoorCommon - ThermalTransmittance: 0; IsExternal: yes
FNDE - Esquadrias - Grupo da Esquadria: PORTA DE VIDRO; Soleira/Peitoril: SOLEIRA EM GRANITO CINZA ANDORINHA E=2cm; Esquadrias - Tipo de Abertura: DE ABRIR; Esquadrias - Tipo de Vidro: TEMPERADO INCOLOR 10mm; Esquadrias - Quantidade de Folhas: 02 FOLHAS; Esquadrias - Fechaduras: -; Esquadrias - Fechamentos metálicos e Gradis: -; 1_Bloco: BLOCO A; 0_ID: PV1; Esquadrias - Verga e Contra-verga: -
Component Quantities - Água, Massa: 50.5632 kg; Água, Volume Componente (Líquido): 0.0505632 m3; Água, Volume do componente (Bruto): 0.0505632 m3; Alumínio, Massa: 4.94894 kg; Alumínio, Volume Componente (Líquido): 0.00176748 m3; Alumínio, Volume do componente (Bruto): 0.00176748 m3; GENÉRICO - REV. INTERNO, Massa: 0.739063 kg; GENÉRICO - REV. INTERNO, Volume Componente (Líquido): 0.000492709 m3; GENÉRICO - REV. INTERNO, Volume do componente (Bruto): 0.000492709 m3

# IfcDoor: FNDE-Portão de Ferro Tipo 2, PO4
In: TÉRREO
OverallHeight: 2.4 m; OverallWidth: 1.5 m; Classification: Porta (Classificação Archicad); Material: Água, AÇO SUPORTE
Pset_DoorCommon - ThermalTransmittance: 0; IsExternal: yes
FNDE - Esquadrias - Grupo da Esquadria: PORTÃO METÁLICO; Soleira/Peitoril: -; Esquadrias - Tipo de Abertura: DE ABRIR; Esquadrias - Descrição ou Complemento: COM GRADIL METÁLICO E TELA DE AÇO GALVANIZADO; Esquadrias - Tipo de Vidro: -; Esquadrias - Quantidade de Folhas: 02 FOLHAS; Esquadrias - Fechaduras: -; Esquadrias - Fechamentos metálicos e Gradis: -; 1_Bloco: MURO; 0_ID: PO4; Esquadrias - Verga e Contra-verga: -
Component Quantities - Água, Massa: 59.0645 kg; Água, Volume Componente (Líquido): 0.0590645 m3; Água, Volume do componente (Bruto): 0.0590645 m3; AÇO SUPORTE, Massa: 0.498706 kg; AÇO SUPORTE, Volume Componente (Líquido): 0.000216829 m3; AÇO SUPORTE, Volume do componente (Bruto): 0.000216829 m3

# IfcDoor: PF1-portão de ferro R01, PF1
In: TÉRREO
OverallHeight: 2.4 m; OverallWidth: 1.5 m; Classification: Porta (Classificação Archicad); Material: EI-MTL-PERFIL EM AÇO GALVANIZADO -AMARELO, EI-MTL-CHAPA DE AÇO CARBONO PERFURADA -AMARELO
Pset_DoorCommon - ThermalTransmittance: 0; IsExternal: yes
FNDE - Esquadrias - Grupo da Esquadria: PORTÃO METÁLICO; Soleira/Peitoril: -; Esquadrias - Tipo de Abertura: DE ABRIR; Esquadrias - Descrição ou Complemento: COM CHAPA METÁLICA; Esquadrias - Tipo de Vidro: -; Esquadrias - Quantidade de Folhas: 01 FOLHA; Esquadrias - Fechaduras: -; Esquadrias - Fechamentos metálicos e Gradis: -; 1_Bloco: BLOCO A; 0_ID: PF1; Esquadrias - Verga e Contra-verga: -
Component Quantities - EI-MTL-PERFIL EM AÇO GALVANIZADO -AMARELO, Massa: 239.11 kg; EI-MTL-PERFIL EM AÇO GALVANIZADO -AMARELO, Volume Componente (Líquido): 0.030267 m3; EI-MTL-PERFIL EM AÇO GALVANIZADO -AMARELO, Volume do componente (Bruto): 0.030267 m3; EI-MTL-CHAPA DE AÇO CARBONO PERFURADA -AMARELO, Massa: 25.3827 kg; EI-MTL-CHAPA DE AÇO CARBONO PERFURADA -AMARELO, Volume Componente (Líquido): 0.003213 m3; EI-MTL-CHAPA DE AÇO CARBONO PERFURADA -AMARELO, Volume do componente (Bruto): 0.003213 m3

# IfcDoor: Porta 27 (7)
In: TÉRREO
Type - OperationType: SINGLE_SWING_LEFT
Classification: Porta (Classificação Archicad)
Pset_DoorCommon - ThermalTransmittance: 0; IsExternal: no
FNDE - Soleira/Peitoril: SOLEIRA EM GRANITO CINZA ANDORINHA E=2cm; Esquadrias - Tipo de Abertura: DE ABRIR; Esquadrias - Quantidade de Folhas: 01 FOLHA; Esquadrias - Fechamentos metálicos e Gradis: -; 1_Bloco: BLOCO A; Esquadrias - Verga e Contra-verga: C1-IN - Verga Interna
Name | OverallHeight (m) | OverallWidth (m) | Esquadrias - Grupo da Esquadria | Esquadrias - Descrição ou Complemento | Esquadrias - Tipo de Vidro | Esquadrias - Fechaduras | 0_ID | Component, Volume Componente (Líquido) (m3) = Component, Volume do componente (Bruto) (m3)
PM1 | 2.14 | 0.9 | PORTA DE MADEIRA | COM CHAPA METÁLICA | - | Internas | PM1 | 0.0946983
2 x PA2 | 2.115 | 0.83 | PORTA DE ALUMÍNIO | COM VENEZIANA | - | Externas | PA2 | 0.00424943 | Material: Água; Component Quantities - Água, Massa: 23.3221 kg; Água, Volume Componente (Líquido): 0.0233221 m3; Água, Volume do componente (Bruto): 0.0233221 m3
PA1 | 2.115 | 1.03 | PORTA DE ALUMÍNIO | COM VIDRO E VENEZIANA | MINIBOREAL 6mm | Externas | PA1 | 0.00287104 | Material: Água, Vidro; Component Quantities - Água, Massa: 20.1797 kg; Água, Volume Componente (Líquido): 0.0201797 m3; Água, Volume do componente (Bruto): 0.0201797 m3; Vidro, Massa: 0 kg; Vidro, Volume Componente (Líquido): 0 m3; Vidro, Volume do componente (Bruto): 0 m3
3 x PM1 | 2.14 | 0.9 | PORTA DE MADEIRA | COM CHAPA METÁLICA | - | Banheiros | PM1 | 0.0946983

# IfcDoor: Porta 27 (5)
In: TÉRREO
Type - OperationType: SINGLE_SWING_RIGHT
OverallHeight: 2.14 m; OverallWidth: 0.9 m; Classification: Porta (Classificação Archicad)
Pset_DoorCommon - ThermalTransmittance: 0; IsExternal: no
FNDE - Esquadrias - Grupo da Esquadria: PORTA DE MADEIRA; Soleira/Peitoril: SOLEIRA EM GRANITO CINZA ANDORINHA E=2cm; Esquadrias - Tipo de Abertura: DE ABRIR; Esquadrias - Descrição ou Complemento: COM CHAPA METÁLICA; Esquadrias - Tipo de Vidro: -; Esquadrias - Quantidade de Folhas: 01 FOLHA; Esquadrias - Fechamentos metálicos e Gradis: -; 0_ID: PM1; Esquadrias - Verga e Contra-verga: C1-IN - Verga Interna
Component Quantities - Component, Volume Componente (Líquido): 0.0946983 m3; Component, Volume do componente (Bruto): 0.0946983 m3
Name | Esquadrias - Fechaduras | 1_Bloco
2 x PM1 | Internas | BLOCO B
2 x PM1 | Internas | BLOCO A
PM1 | Banheiros | BLOCO A

# IfcDoor: Porta Dupla 27 (4)
In: TÉRREO
Type - OperationType: DOUBLE_DOOR_SINGLE_SWING
Classification: Porta (Classificação Archicad); Material: Água
Pset_DoorCommon - ThermalTransmittance: 0
FNDE - Esquadrias - Grupo da Esquadria: PORTA DE ALUMÍNIO; Esquadrias - Tipo de Abertura: DE ABRIR; Esquadrias - Descrição ou Complemento: COM VENEZIANA; Esquadrias - Tipo de Vidro: -; Esquadrias - Quantidade de Folhas: 02 FOLHAS; Esquadrias - Fechamentos metálicos e Gradis: -
Name | OverallHeight (m) | OverallWidth (m) | IsExternal | Soleira/Peitoril | Esquadrias - Fechaduras | 1_Bloco | 0_ID | Esquadrias - Verga e Contra-verga | Component, Volume Componente (Líquido) (m3) = Component, Volume do componente (Bruto) (m3) | Água, Massa (kg) | Água, Volume Componente (Líquido) (m3) = Água, Volume do componente (Bruto) (m3)
PA3 | 2.115 | 1.63 | no | SOLEIRA EM GRANITO CINZA ANDORINHA E=2cm | - | BLOCO B | PA3 | C1-IN - Verga Interna | 0.00331133 | 46.9122 | 0.0469122
3 x PA5 | 1.715 | 1.13 | yes | - | Internas | CASA DE BOMBAS / GÁS / LIXO | PA5 | - | 0.00262883 | 27.9823 | 0.0279823

# IfcDoor: Porta de Correr com Travessa 27 (7)
In: TÉRREO
Type - OperationType: USERDEFINED
OverallHeight: 2.65 m; OverallWidth: 4.5 m; Classification: Porta (Classificação Archicad); Material: Água
Pset_DoorCommon - ThermalTransmittance: 0
FNDE - Esquadrias - Grupo da Esquadria: PORTA DE ALUMÍNIO; Soleira/Peitoril: SOLEIRA EM GRANITO CINZA ANDORINHA E=2cm; Esquadrias - Tipo de Abertura: DE CORRER COM BANDEIRA SUPERIOR FIXA; Esquadrias - Descrição ou Complemento: COM VIDRO; Esquadrias - Tipo de Vidro: TEMPERADO INCOLOR 8mm; Esquadrias - Quantidade de Folhas: 04 FOLHAS; Esquadrias - Fechaduras: -; Esquadrias - Fechamentos metálicos e Gradis: -; 0_ID: PA4; Esquadrias - Verga e Contra-verga: -
Name | IsExternal | 1_Bloco | Component, Volume Componente (Líquido) (m3) = Component, Volume do componente (Bruto) (m3) | Água, Massa (kg) | Água, Volume Componente (Líquido) (m3) = Água, Volume do componente (Bruto) (m3)
PA4 | yes | BLOCO B | 0.0272256 | 35.718 | 0.035718
4 x PA4 | no | BLOCO B | 0.0272256 | 35.718 | 0.035718
PA4 | no | BLOCO A | 0.0272256 | 35.718 | 0.035718
PA4 | no | BLOCO B | 0.0424488 | 35.4397 | 0.0354397

# IfcFurniture: Barra de Apoio 27 (18)
In: TÉRREO
Classification: Mobiliário (Classificação Archicad)
FNDE - Pedras: - -
Component Quantities - Component, Volume Componente (Líquido): 0.0000123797 m3; Component, Volume do componente (Bruto): 0.0000123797 m3
Name | ModelLabel = Mobiliário ou Equipamento - Modelo | 1_Bloco | 0_ID
3 x BR2 | BARRA DE APOIO 70cm | BLOCO B | BR2
3 x BR3 | BARRA DE APOIO 80cm | BLOCO B | BR3
2 x BR1 | BARRA DE APOIO 40cm | BLOCO B | BR1
4 x BR3 | BARRA DE APOIO 80cm | BLOCO A | BR3
2 x BR2 | BARRA DE APOIO 70cm | BLOCO A | BR2
4 x BR1 | BARRA DE APOIO 40cm | BLOCO A | BR1

# IfcFurniture: Deca Izy Registro Parede (7)
In: TÉRREO
Classification: Mobiliário (Classificação Archicad)
Pset_ManufacturerTypeInformation - ModelLabel: ACABAMENTO PARA REGISTRO PEQUENO, DECA OU EQUIVALENTE
FNDE - Mobiliário ou Equipamento - Modelo: ACABAMENTO PARA REGISTRO PEQUENO, DECA OU EQUIVALENTE; Pedras: - -; 0_ID: RG1
Component Quantities - Component, Volume Componente (Líquido): 0.000056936 m3; Component, Volume do componente (Bruto): 0.000056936 m3
Name | 1_Bloco
4 x RG1 | BLOCO B
3 x RG1 | BLOCO A

# IfcFurniture: Deca Link Registro Parede, RG2
In: TÉRREO
Classification: Mobiliário (Classificação Archicad)
Pset_ManufacturerTypeInformation - ModelLabel: ACABAMENTO PARA REGISTRO (ACIONAMENTO FACILITADO)
FNDE - Mobiliário ou Equipamento - Modelo: ACABAMENTO PARA REGISTRO (ACIONAMENTO FACILITADO); Pedras: - -; 1_Bloco: BLOCO B; 0_ID: RG2
Component Quantities - Component, Volume Componente (Líquido): 0.0000728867 m3; Component, Volume do componente (Bruto): 0.0000728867 m3

# IfcFurniture: EI-CON-Banco de Concreto Pré-moldado 50 (3)
In: TÉRREO
Classification: Mobiliário (Classificação Archicad); Material: EI-CON-Banco de Concreto Pré-moldado
FNDE - Pedras: BANCO - ALVENARIA E ASSENTO EM CONCRETO PRÉ-MOLDADO
Component Quantities - EI-CON-Banco de Concreto Pré-moldado, Espessura do Componente: 0.05 m
Name | 1_Bloco | 0_ID | EI-CON-Banco de Concreto Pré-moldado, Massa (kg) | EI-CON-Banco de Concreto Pré-moldado, Área de Componente Projetada (Líquida) (m2) = EI-CON-Banco de Concreto Pré-moldado, Área de Componente Projetada (Bruta) (m2) | EI-CON-Banco de Concreto Pré-moldado, Volume Componente (Líquido) (m3) = EI-CON-Banco de Concreto Pré-moldado, Volume do componente (Bruto) (m3)
BC1 | BLOCO A | BC1 | 210.847 | 2.34275 | 0.117137
BC4 | BLOCO B | BC4 | 183.011 | 2.03345 | 0.101673
BC4 | BLOCO A | BC4 | 177.469 | 1.97187 | 0.0985937

# IfcFurniture: EI-GRA-Divisória - Granito cinza Andorinha 30 (2)
In: TÉRREO
Classification: Mobiliário (Classificação Archicad); Material: EI-GRA-Divisória - Granito cinza Andorinha
FNDE - Pedras: DIVISÓRIA - GRANITO CINZA ANDORINHA - esp. 3 cm; 1_Bloco: BLOCO B; 0_ID: DV1
Component Quantities - EI-GRA-Divisória - Granito cinza Andorinha, Massa: 53.3232 kg; EI-GRA-Divisória - Granito cinza Andorinha, Área de Componente Projetada (Líquida): 0.6348 m2; EI-GRA-Divisória - Granito cinza Andorinha, Área de Componente Projetada (Bruta): 3.5148 m2; EI-GRA-Divisória - Granito cinza Andorinha, Espessura do Componente: 0.03 m; EI-GRA-Divisória - Granito cinza Andorinha, Altura do Componente Retangular: 1.2 m; EI-GRA-Divisória - Granito cinza Andorinha, Largura do Componente Retangular: 0.03 m; EI-GRA-Divisória - Granito cinza Andorinha, Área de Seção Transversal do Componente: 0.036 m2; EI-GRA-Divisória - Granito cinza Andorinha, Volume Componente (Líquido): 0.019044 m3; EI-GRA-Divisória - Granito cinza Andorinha, Volume do componente (Bruto): 0.105444 m3

# IfcFurniture: EI-GRA-Granito cinza Andorinha (Bancadas, bancos e prateleiras) 20 x 100 (6)
In: TÉRREO
Classification: Mobiliário (Classificação Archicad); Material: EI-GRA-Granito cinza Andorinha (Bancadas, bancos e prateleiras)
FNDE - Pedras: BANCADA - GRANITO CINZA ANDORINHA - esp. 2 cm; 1_Bloco: BLOCO B
Component Quantities - EI-GRA-Granito cinza Andorinha (Bancadas, bancos e prateleiras), Espessura do Componente: 0.02 m; EI-GRA-Granito cinza Andorinha (Bancadas, bancos e prateleiras), Altura do Componente Retangular: 0.1 m; EI-GRA-Granito cinza Andorinha (Bancadas, bancos e prateleiras), Largura do Componente Retangular: 0.02 m; EI-GRA-Granito cinza Andorinha (Bancadas, bancos e prateleiras), Área de Seção Transversal do Componente: 0.002 m2
Name | 0_ID | EI-GRA-Granito cinza Andorinha (Bancadas, bancos e prateleiras), Massa (kg) | EI-GRA-Granito cinza Andorinha (Bancadas, bancos e prateleiras), Área de Componente Projetada (Líquida) (m2) = EI-GRA-Granito cinza Andorinha (Bancadas, bancos e prateleiras), Área de Componente Projetada (Bruta) (m2) | EI-GRA-Granito cinza Andorinha (Bancadas, bancos e prateleiras), Volume Componente (Líquido) (m3) = EI-GRA-Granito cinza Andorinha (Bancadas, bancos e prateleiras), Volume do componente (Bruto) (m3)
2 x B19 | B19 | 6.664 | 0.12 | 0.00238
2 x B19 | B19 | 3.864 | 0.07 | 0.00138
2 x B18 | B18 | 16.408 | 0.293 | 0.00586

# IfcFurniture: EI-GRA-Granito cinza Andorinha (Bancadas, bancos e prateleiras) 20 x 50 (14)
In: TÉRREO
Classification: Mobiliário (Classificação Archicad); Material: EI-GRA-Granito cinza Andorinha (Bancadas, bancos e prateleiras)
FNDE - Pedras: BANCADA - GRANITO CINZA ANDORINHA - esp. 2 cm; 1_Bloco: BLOCO B
Component Quantities - EI-GRA-Granito cinza Andorinha (Bancadas, bancos e prateleiras), Espessura do Componente: 0.02 m; EI-GRA-Granito cinza Andorinha (Bancadas, bancos e prateleiras), Altura do Componente Retangular: 0.05 m; EI-GRA-Granito cinza Andorinha (Bancadas, bancos e prateleiras), Largura do Componente Retangular: 0.02 m; EI-GRA-Granito cinza Andorinha (Bancadas, bancos e prateleiras), Área de Seção Transversal do Componente: 0.001 m2
Name | 0_ID | EI-GRA-Granito cinza Andorinha (Bancadas, bancos e prateleiras), Massa (kg) | EI-GRA-Granito cinza Andorinha (Bancadas, bancos e prateleiras), Área de Componente Projetada (Líquida) (m2) = EI-GRA-Granito cinza Andorinha (Bancadas, bancos e prateleiras), Área de Componente Projetada (Bruta) (m2) | EI-GRA-Granito cinza Andorinha (Bancadas, bancos e prateleiras), Volume Componente (Líquido) (m3) = EI-GRA-Granito cinza Andorinha (Bancadas, bancos e prateleiras), Volume do componente (Bruto) (m3)
2 x B19 | B19 | 1.68 | 0.03 | 0.0006
2 x B19 | B19 | 0.396849 | 0.00785398 | 0.000141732
2 x B19 | B19 | 3.08 | 0.055 | 0.0011
2 x B18 | B18 | 1.372 | 0.025 | 0.00049
2 x B18 | B18 | 7.896 | 0.1415 | 0.00282
2 x B18 | B18 | 1.12 | 0.02 | 0.0004
2 x B18 | B18 | 0.396849 | 0.00785398 | 0.000141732

# IfcFurniture: EI-GRA-Soleira/ Peitoril - Granito cinza Andorinha 160 x 20 (3)
In: TÉRREO
Classification: Mobiliário (Classificação Archicad); Material: EI-GRA-Soleira/ Peitoril - Granito cinza Andorinha
FNDE - Pedras: PEITORIL - GRANITO CINZA ANDORINHA - esp. 2 cm
Component Quantities - EI-GRA-Soleira/ Peitoril - Granito cinza Andorinha, Espessura do Componente: 0.16 m; EI-GRA-Soleira/ Peitoril - Granito cinza Andorinha, Altura do Componente Retangular: 0.02 m; EI-GRA-Soleira/ Peitoril - Granito cinza Andorinha, Largura do Componente Retangular: 0.16 m; EI-GRA-Soleira/ Peitoril - Granito cinza Andorinha, Área de Seção Transversal do Componente: 0.0032 m2
Name | 1_Bloco | EI-GRA-Soleira/ Peitoril - Granito cinza Andorinha, Massa (kg) | EI-GRA-Soleira/ Peitoril - Granito cinza Andorinha, Área de Componente Projetada (Líquida) (m2) = EI-GRA-Soleira/ Peitoril - Granito cinza Andorinha, Área de Componente Projetada (Bruta) (m2) | EI-GRA-Soleira/ Peitoril - Granito cinza Andorinha, Volume Componente (Líquido) (m3) = EI-GRA-Soleira/ Peitoril - Granito cinza Andorinha, Volume do componente (Bruto) (m3)
2 x  | BLOCO B | 12.6786 | 0.0283005 | 0.00452809
 | BLOCO A | 5.4877 | 0.0122493 | 0.00195989

# IfcFurniture: EI-GRA-Soleira/ Peitoril - Granito cinza Andorinha 190 x 20
In: TÉRREO
Classification: Mobiliário (Classificação Archicad); Material: EI-GRA-Soleira/ Peitoril - Granito cinza Andorinha
FNDE - Pedras: PEITORIL - GRANITO CINZA ANDORINHA - esp. 2 cm; 1_Bloco: BLOCO A
Component Quantities - EI-GRA-Soleira/ Peitoril - Granito cinza Andorinha, Massa: 25.2168 kg; EI-GRA-Soleira/ Peitoril - Granito cinza Andorinha, Área de Componente Projetada (Líquida): 0.0474 m2; EI-GRA-Soleira/ Peitoril - Granito cinza Andorinha, Área de Componente Projetada (Bruta): 0.0474 m2; EI-GRA-Soleira/ Peitoril - Granito cinza Andorinha, Espessura do Componente: 0.19 m; EI-GRA-Soleira/ Peitoril - Granito cinza Andorinha, Altura do Componente Retangular: 0.02 m; EI-GRA-Soleira/ Peitoril - Granito cinza Andorinha, Largura do Componente Retangular: 0.19 m; EI-GRA-Soleira/ Peitoril - Granito cinza Andorinha, Área de Seção Transversal do Componente: 0.0038 m2; EI-GRA-Soleira/ Peitoril - Granito cinza Andorinha, Volume Componente (Líquido): 0.009006 m3; EI-GRA-Soleira/ Peitoril - Granito cinza Andorinha, Volume do componente (Bruto): 0.009006 m3

# IfcFurniture: Escaninho Sala Multiuso, EC3
In: TÉRREO
Classification: Mobiliário (Classificação Archicad)
Pset_ManufacturerTypeInformation - ModelLabel: ESCANINHO EM MDF COM LAMINADO MELAMÍNICO BRANCO
FNDE - Mobiliário ou Equipamento - Modelo: ESCANINHO EM MDF COM LAMINADO MELAMÍNICO BRANCO; Pedras: - - MDF REV. COM LAMINADO MELAMÍNICO BRANCO - esp. 2 cm; 1_Bloco: BLOCO B; 0_ID: EC3
Component Quantities - Component, Volume Componente (Líquido): 0.173565 m3; Component, Volume do componente (Bruto): 0.173565 m3

# IfcFurniture: Espelho 27 (15)
In: TÉRREO
Classification: Mobiliário (Classificação Archicad)
FNDE - Pedras: - -
Name | ModelLabel = Mobiliário ou Equipamento - Modelo | 1_Bloco | 0_ID | Component, Volume Componente (Líquido) (m3) = Component, Volume do componente (Bruto) (m3)
8 x ES1 | ESPELHO 40x50cm | BLOCO B | ES1 | 0.00266667
ES3 | ESPELHO 50x90cm | BLOCO B | ES3 | 0.006
ES4 | ESPELHO 300X80cm | BLOCO A | ES4 | 0.034
2 x ES2 | ESPELHO 50x80cm | BLOCO A | ES2 | 0.00533333
2 x ES3 | ESPELHO 50x90cm | BLOCO A | ES3 | 0.006
ES4 | ESPELHO 300X80cm | BLOCO B | ES4 | 0.034

# IfcFurniture: Estante 01 27 (5)
In: TÉRREO
Classification: Mobiliário (Classificação Archicad)
Pset_ManufacturerTypeInformation - ModelLabel: ESCANINHO EM MDF COM LAMINADO MELAMÍNICO BRANCO
FNDE - Mobiliário ou Equipamento - Modelo: ESCANINHO EM MDF COM LAMINADO MELAMÍNICO BRANCO; Pedras: - - MDF REV. COM LAMINADO MELAMÍNICO BRANCO - esp. 2 cm
Name | 1_Bloco | 0_ID | Component, Volume Componente (Líquido) (m3) = Component, Volume do componente (Bruto) (m3)
2 x EC2 | BLOCO B | EC2 | 0.1528
EC4 | BLOCO B | EC4 | 0.161639
EC5 | BLOCO B | EC5 | 0.15
EC1 | BLOCO A | EC1 | 0.1028

# IfcFurniture: FITA ANTIDERRAPANTE 50mm 50 x 1 (8)
In: TÉRREO
Classification: Mobiliário (Classificação Archicad); Material: FITA ANTIDERRAPANTE 50mm
FNDE - Pedras: - -
Component Quantities - FITA ANTIDERRAPANTE 50mm, Massa: 0 kg; FITA ANTIDERRAPANTE 50mm, Espessura do Componente: 0.05 m; FITA ANTIDERRAPANTE 50mm, Altura do Componente Retangular: 0.001 m; FITA ANTIDERRAPANTE 50mm, Largura do Componente Retangular: 0.05 m; FITA ANTIDERRAPANTE 50mm, Área de Seção Transversal do Componente: 0.00005 m2
Name | 1_Bloco | FITA ANTIDERRAPANTE 50mm, Área de Componente Projetada (Líquida) (m2) = FITA ANTIDERRAPANTE 50mm, Área de Componente Projetada (Bruta) (m2) | FITA ANTIDERRAPANTE 50mm, Volume Componente (Líquido) (m3) = FITA ANTIDERRAPANTE 50mm, Volume do componente (Bruto) (m3)
4 x  | BLOCO B | 0.00056 | 0.000028
2 x  | BLOCO A | 0.0006 | 0.00003
2 x  | BLOCO B | 0.00056 | 3.75376e-08

# IfcFurniture: FNDE-Bancada Granito - Área Seca 500 x 150 (3)
In: TÉRREO
Classification: Mobiliário (Classificação Archicad); Material: EI-GRA-Granito cinza Andorinha (Bancadas, bancos e prateleiras) (3)
FNDE - Pedras: BANCADA - GRANITO CINZA ANDORINHA - esp. 2 cm; 1_Bloco: BLOCO A
Component Quantities - EI-GRA-Granito cinza Andorinha (Bancadas, bancos e prateleiras) 1, Altura do Componente Retangular: 0.1 m; EI-GRA-Granito cinza Andorinha (Bancadas, bancos e prateleiras) 1, Largura do Componente Retangular: 0.02 m; EI-GRA-Granito cinza Andorinha (Bancadas, bancos e prateleiras) 1, Área de Seção Transversal do Componente: 0.002 m2; EI-GRA-Granito cinza Andorinha (Bancadas, bancos e prateleiras) 2, Área de Seção Transversal do Componente: 0.0098 m2; EI-GRA-Granito cinza Andorinha (Bancadas, bancos e prateleiras) 3, Área de Seção Transversal do Componente: 0.0008 m2
Name | 0_ID | EI-GRA-Granito cinza Andorinha (Bancadas, bancos e prateleiras) 1, Massa (kg) | EI-GRA-Granito cinza Andorinha (Bancadas, bancos e prateleiras) 1, Área de Componente Projetada (Líquida) (m2) = EI-GRA-Granito cinza Andorinha (Bancadas, bancos e prateleiras) 1, Área de Componente Projetada (Bruta) (m2) | EI-GRA-Granito cinza Andorinha (Bancadas, bancos e prateleiras) 1, Volume Componente (Líquido) (m3) = EI-GRA-Granito cinza Andorinha (Bancadas, bancos e prateleiras) 1, Volume do componente (Bruto) (m3) | EI-GRA-Granito cinza Andorinha (Bancadas, bancos e prateleiras) 2, Massa (kg) | EI-GRA-Granito cinza Andorinha (Bancadas, bancos e prateleiras) 2, Área de Componente Projetada (Líquida) (m2) = EI-GRA-Granito cinza Andorinha (Bancadas, bancos e prateleiras) 2, Área de Componente Projetada (Bruta) (m2) | EI-GRA-Granito cinza Andorinha (Bancadas, bancos e prateleiras) 2, Volume Componente (Líquido) (m3) = EI-GRA-Granito cinza Andorinha (Bancadas, bancos e prateleiras) 2, Volume do componente (Bruto) (m3) | EI-GRA-Granito cinza Andorinha (Bancadas, bancos e prateleiras) 3, Massa (kg) | EI-GRA-Granito cinza Andorinha (Bancadas, bancos e prateleiras) 3, Área de Componente Projetada (Líquida) (m2) = EI-GRA-Granito cinza Andorinha (Bancadas, bancos e prateleiras) 3, Área de Componente Projetada (Bruta) (m2) | EI-GRA-Granito cinza Andorinha (Bancadas, bancos e prateleiras) 3, Volume Componente (Líquido) (m3) = EI-GRA-Granito cinza Andorinha (Bancadas, bancos e prateleiras) 3, Volume do componente (Bruto) (m3)
B08 | B08 | 4.96679 | 0.0899928 | 0.00177386 | 15.9532 | 0.287464 | 0.00569756 | 0.586531 | 0.0135364 | 0.000209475
B10 | B10 | 10.125 | 0.182004 | 0.00361609 | 41.8745 | 0.76004 | 0.0149552 | 2.75771 | 0.0619659 | 0.000984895
B10 | B10 | 8.7808 | 0.158 | 0.003136 | 35.2867 | 0.64 | 0.0126024 | 2.21984 | 0.04996 | 0.0007928

# IfcFurniture: FNDE-Cantoneira emborrachada 30 x 30 (10)
In: TÉRREO
Classification: Mobiliário (Classificação Archicad); Material: EI-CANTONEIRA EMBORRACHADA
FNDE - Pedras: - -
Component Quantities - EI-CANTONEIRA EMBORRACHADA, Área de Seção Transversal do Componente: 0.000224 m2
Name | 1_Bloco | EI-CANTONEIRA EMBORRACHADA, Massa (kg) | EI-CANTONEIRA EMBORRACHADA, Volume Componente (Líquido) (m3) = EI-CANTONEIRA EMBORRACHADA, Volume do componente (Bruto) (m3)
2 x  | BLOCO B | 0.346183 | 0.000314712
 | BLOCO B | 1.21967 | 0.00110879
 | BLOCO B | 1.2209 | 0.00110991
 | BLOCO B | 1.21969 | 0.00110881
 | BLOCO B | 1.22091 | 0.00110992
2 x  | BLOCO A | 1.21968 | 0.0011088
 | BLOCO A | 0.343975 | 0.000312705
 | BLOCO A | 0.343974 | 0.000312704

# IfcFurniture: FNDE-Cobrimento vigas com ceramica 150 x 426, B21
In: TÉRREO
Classification: Mobiliário (Classificação Archicad); Material: EI-REV-Cerâmica 30x40 (3)
FNDE - Pedras: - -; 1_Bloco: BLOCO A; 0_ID: B21
Component Quantities - EI-REV-Cerâmica 30x40 1, Massa: 6.20697 kg; EI-REV-Cerâmica 30x40 1, Área de Componente Projetada (Líquida): 0.553781 m2; EI-REV-Cerâmica 30x40 1, Área de Componente Projetada (Bruta): 0.553781 m2; EI-REV-Cerâmica 30x40 1, Área de Seção Transversal do Componente: 0.0123966 m2; EI-REV-Cerâmica 30x40 1, Volume Componente (Líquido): 0.00310349 m3; EI-REV-Cerâmica 30x40 1, Volume do componente (Bruto): 0.00310349 m3; EI-REV-Cerâmica 30x40 2, Massa: 5.79355 kg; EI-REV-Cerâmica 30x40 2, Área de Componente Projetada (Líquida): 0.508032 m2; EI-REV-Cerâmica 30x40 2, Área de Componente Projetada (Bruta): 0.508032 m2; EI-REV-Cerâmica 30x40 2, Área de Seção Transversal do Componente: 0.0123966 m2; EI-REV-Cerâmica 30x40 2, Volume Componente (Líquido): 0.00289677 m3; EI-REV-Cerâmica 30x40 2, Volume do componente (Bruto): 0.00289677 m3; EI-REV-Cerâmica 30x40 3, Massa: 7.97444 kg; EI-REV-Cerâmica 30x40 3, Área de Componente Projetada (Líquida): 0.194993 m2; EI-REV-Cerâmica 30x40 3, Área de Componente Projetada (Bruta): 0.194993 m2; EI-REV-Cerâmica 30x40 3, Área de Seção Transversal do Componente: 0.0030672 m2; EI-REV-Cerâmica 30x40 3, Volume Componente (Líquido): 0.00398722 m3; EI-REV-Cerâmica 30x40 3, Volume do componente (Bruto): 0.00398722 m3

# IfcFurniture: FNDE-Cobrimento vigas com pintura (20cm) 260 x 111, B21
In: TÉRREO
Classification: Mobiliário (Classificação Archicad); Material: EI-REV-Pintura Acrílica Cor Branco Gelo (3)
FNDE - Pedras: - -; 1_Bloco: CASA DE BOMBAS / GÁS / LIXO; 0_ID: B21
Component Quantities - EI-REV-Pintura Acrílica Cor Branco Gelo 1, Massa: 15.9067 kg; EI-REV-Pintura Acrílica Cor Branco Gelo 1, Área de Componente Projetada (Líquida): 0.420478 m2; EI-REV-Pintura Acrílica Cor Branco Gelo 1, Área de Componente Projetada (Bruta): 0.420478 m2; EI-REV-Pintura Acrílica Cor Branco Gelo 1, Área de Seção Transversal do Componente: 0.00321997 m2; EI-REV-Pintura Acrílica Cor Branco Gelo 1, Volume Componente (Líquido): 0.0122359 m3; EI-REV-Pintura Acrílica Cor Branco Gelo 1, Volume do componente (Bruto): 0.0122359 m3; EI-REV-Pintura Acrílica Cor Branco Gelo 3, Massa: 7.54337 kg; EI-REV-Pintura Acrílica Cor Branco Gelo 3, Área de Componente Projetada (Líquida): 0.988 m2; EI-REV-Pintura Acrílica Cor Branco Gelo 3, Área de Componente Projetada (Bruta): 0.988 m2; EI-REV-Pintura Acrílica Cor Branco Gelo 3, Área de Seção Transversal do Componente: 0.001527 m2; EI-REV-Pintura Acrílica Cor Branco Gelo 3, Volume Componente (Líquido): 0.00580259 m3; EI-REV-Pintura Acrílica Cor Branco Gelo 3, Volume do componente (Bruto): 0.00580259 m3; EI-REV-Pintura Acrílica Cor Branco Gelo 1: 2 with these values

# IfcFurniture: FNDE-Cobrimento vigas com pintura AL09 150 x 400, B21
In: TÉRREO
Classification: Mobiliário (Classificação Archicad); Material: EI-REV-Pintura Acrílica Cor Branco Gelo (3)
FNDE - Pedras: - -; 1_Bloco: BLOCO A; 0_ID: B21
Component Quantities - EI-REV-Pintura Acrílica Cor Branco Gelo 1, Massa: 5.26182 kg; EI-REV-Pintura Acrílica Cor Branco Gelo 1, Área de Componente Projetada (Líquida): 0.742131 m2; EI-REV-Pintura Acrílica Cor Branco Gelo 1, Área de Componente Projetada (Bruta): 0.742131 m2; EI-REV-Pintura Acrílica Cor Branco Gelo 1, Área de Seção Transversal do Componente: 0.01164 m2; EI-REV-Pintura Acrílica Cor Branco Gelo 1, Volume Componente (Líquido): 0.00404755 m3; EI-REV-Pintura Acrílica Cor Branco Gelo 1, Volume do componente (Bruto): 0.00404755 m3; EI-REV-Pintura Acrílica Cor Branco Gelo 2, Massa: 5.109 kg; EI-REV-Pintura Acrílica Cor Branco Gelo 2, Área de Componente Projetada (Líquida): 0.677328 m2; EI-REV-Pintura Acrílica Cor Branco Gelo 2, Área de Componente Projetada (Bruta): 0.677328 m2; EI-REV-Pintura Acrílica Cor Branco Gelo 2, Área de Seção Transversal do Componente: 0.01164 m2; EI-REV-Pintura Acrílica Cor Branco Gelo 2, Volume Componente (Líquido): 0.00393 m3; EI-REV-Pintura Acrílica Cor Branco Gelo 2, Volume do componente (Bruto): 0.00393 m3; EI-REV-Pintura Acrílica Cor Branco Gelo 3, Massa: 6.94536 kg; EI-REV-Pintura Acrílica Cor Branco Gelo 3, Área de Componente Projetada (Líquida): 0.278304 m2; EI-REV-Pintura Acrílica Cor Branco Gelo 3, Área de Componente Projetada (Bruta): 0.278304 m2; EI-REV-Pintura Acrílica Cor Branco Gelo 3, Área de Seção Transversal do Componente: 0.00288 m2; EI-REV-Pintura Acrílica Cor Branco Gelo 3, Volume Componente (Líquido): 0.00534259 m3; EI-REV-Pintura Acrílica Cor Branco Gelo 3, Volume do componente (Bruto): 0.00534259 m3

# IfcFurniture: FNDE-Cobrimento vigas com pintura AL09 150 x 425 (2)
In: TÉRREO
Classification: Mobiliário (Classificação Archicad); Material: EI-REV-Pintura Acrílica Cor Branco Gelo (3)
FNDE - Pedras: - -; 1_Bloco: BLOCO A; 0_ID: B21
Component Quantities - EI-REV-Pintura Acrílica Cor Branco Gelo 1, Área de Seção Transversal do Componente: 0.0123675 m2; EI-REV-Pintura Acrílica Cor Branco Gelo 2, Área de Seção Transversal do Componente: 0.0123675 m2; EI-REV-Pintura Acrílica Cor Branco Gelo 3, Área de Seção Transversal do Componente: 0.00306 m2
Name | EI-REV-Pintura Acrílica Cor Branco Gelo 1, Massa (kg) | EI-REV-Pintura Acrílica Cor Branco Gelo 1, Área de Componente Projetada (Líquida) (m2) = EI-REV-Pintura Acrílica Cor Branco Gelo 1, Área de Componente Projetada (Bruta) (m2) = EI-REV-Pintura Acrílica Cor Branco Gelo 2, Área de Componente Projetada (Líquida) (m2) = EI-REV-Pintura Acrílica Cor Branco Gelo 2, Área de Componente Projetada (Bruta) (m2) | EI-REV-Pintura Acrílica Cor Branco Gelo 1, Volume Componente (Líquido) (m3) = EI-REV-Pintura Acrílica Cor Branco Gelo 1, Volume do componente (Bruto) (m3) | EI-REV-Pintura Acrílica Cor Branco Gelo 2, Massa (kg) | EI-REV-Pintura Acrílica Cor Branco Gelo 2, Volume Componente (Líquido) (m3) = EI-REV-Pintura Acrílica Cor Branco Gelo 2, Volume do componente (Bruto) (m3) | EI-REV-Pintura Acrílica Cor Branco Gelo 3, Massa (kg) | EI-REV-Pintura Acrílica Cor Branco Gelo 3, Área de Componente Projetada (Líquida) (m2) = EI-REV-Pintura Acrílica Cor Branco Gelo 3, Área de Componente Projetada (Bruta) (m2) | EI-REV-Pintura Acrílica Cor Branco Gelo 3, Volume Componente (Líquido) (m3) = EI-REV-Pintura Acrílica Cor Branco Gelo 3, Volume do componente (Bruto) (m3)
B21 | 3.82507 | 0.522749 | 0.00294236 | 3.78592 | 0.00291225 | 4.89294 | 0.1845 | 0.0037638
B21 | 4.92979 | 0.67575 | 0.00379215 | 4.90607 | 0.0037739 | 6.32502 | 0.2385 | 0.0048654

# IfcFurniture: FNDE-Cobrimento vigas com pintura AL14 200 x 430, B21
In: TÉRREO
Classification: Mobiliário (Classificação Archicad); Material: EI-REV-Pintura Acrílica Cor Branco Gelo (3)
FNDE - Pedras: - -; 1_Bloco: BLOCO B; 0_ID: B21
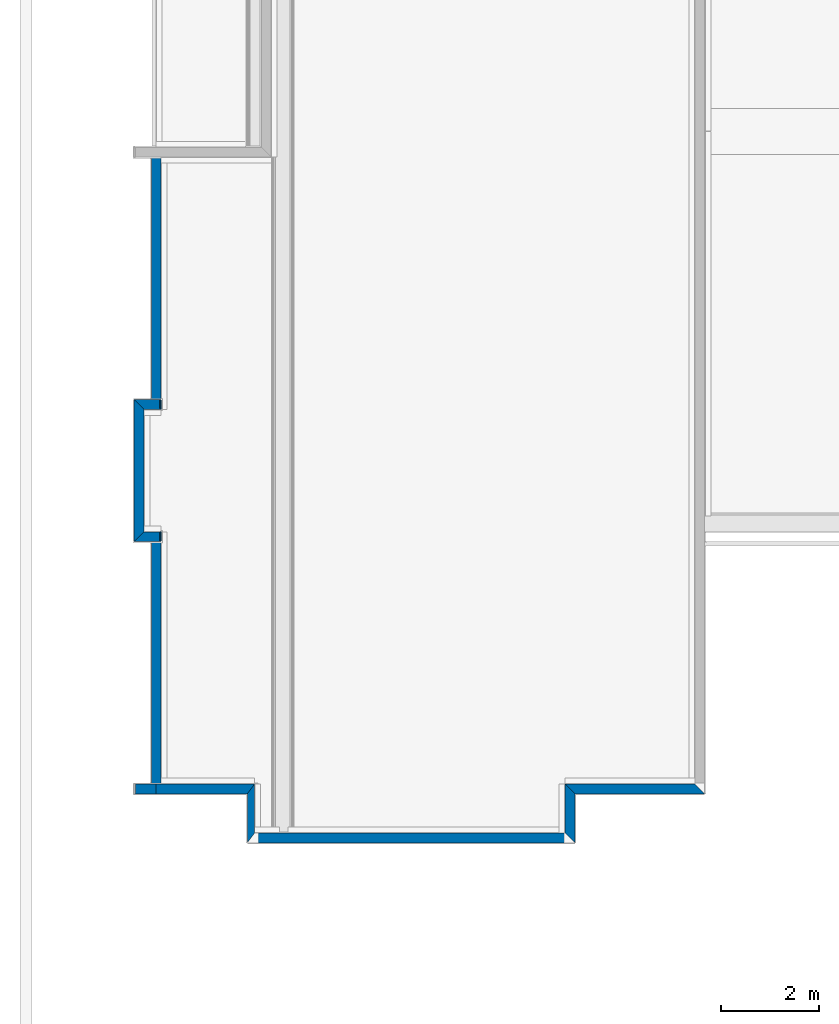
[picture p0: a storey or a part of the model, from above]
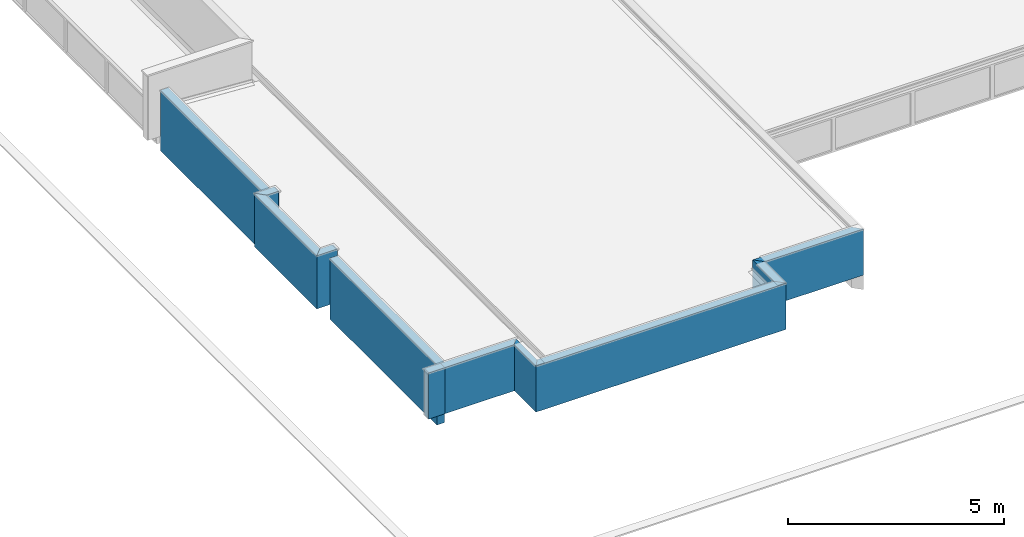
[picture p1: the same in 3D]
Properties of the parts of a building model (IFC4), part 4 of 22

# IfcFurniture: FNDE-Cobrimento vigas com pintura AL14 200 x 430, B21
Component Quantities - EI-REV-Pintura Acrílica Cor Branco Gelo 1, Massa: 21.1122 kg; EI-REV-Pintura Acrílica Cor Branco Gelo 1, Área de Componente Projetada (Líquida): 1.07349 m2; EI-REV-Pintura Acrílica Cor Branco Gelo 1, Área de Componente Projetada (Bruta): 1.07349 m2; EI-REV-Pintura Acrílica Cor Branco Gelo 1, Área de Seção Transversal do Componente: 0.012513 m2; EI-REV-Pintura Acrílica Cor Branco Gelo 1, Volume Componente (Líquido): 0.0162401 m3; EI-REV-Pintura Acrílica Cor Branco Gelo 1, Volume do componente (Bruto): 0.0162401 m3; EI-REV-Pintura Acrílica Cor Branco Gelo 2, Massa: 21.1634 kg; EI-REV-Pintura Acrílica Cor Branco Gelo 2, Área de Componente Projetada (Líquida): 1.07349 m2; EI-REV-Pintura Acrílica Cor Branco Gelo 2, Área de Componente Projetada (Bruta): 1.07349 m2; EI-REV-Pintura Acrílica Cor Branco Gelo 2, Área de Seção Transversal do Componente: 0.012513 m2; EI-REV-Pintura Acrílica Cor Branco Gelo 2, Volume Componente (Líquido): 0.0162795 m3; EI-REV-Pintura Acrílica Cor Branco Gelo 2, Volume do componente (Bruto): 0.0162795 m3; EI-REV-Pintura Acrílica Cor Branco Gelo 3, Massa: 14.2539 kg; EI-REV-Pintura Acrílica Cor Branco Gelo 3, Área de Componente Projetada (Líquida): 0.499979 m2; EI-REV-Pintura Acrílica Cor Branco Gelo 3, Área de Componente Projetada (Bruta): 0.499979 m2; EI-REV-Pintura Acrílica Cor Branco Gelo 3, Área de Seção Transversal do Componente: 0.004386 m2; EI-REV-Pintura Acrílica Cor Branco Gelo 3, Volume Componente (Líquido): 0.0109645 m3; EI-REV-Pintura Acrílica Cor Branco Gelo 3, Volume do componente (Bruto): 0.0109645 m3

# IfcFurniture: FNDE-DV Divisória de Granito (105cm) 1050 x 1200 (6)
In: TÉRREO
Classification: Mobiliário (Classificação Archicad); Material: EI-GRA-Divisória - Granito cinza Andorinha
FNDE - Pedras: DIVISÓRIA - GRANITO CINZA ANDORINHA - esp. 3 cm; 1_Bloco: BLOCO B; 0_ID: DV1
Component Quantities - EI-GRA-Divisória - Granito cinza Andorinha, Massa: 96.075 kg; EI-GRA-Divisória - Granito cinza Andorinha, Área de Componente Projetada (Líquida): 0.169752 m2; EI-GRA-Divisória - Granito cinza Andorinha, Área de Componente Projetada (Bruta): 0.169752 m2; EI-GRA-Divisória - Granito cinza Andorinha, Área de Seção Transversal do Componente: 1.14375 m2; EI-GRA-Divisória - Granito cinza Andorinha, Volume Componente (Líquido): 0.0343125 m3; EI-GRA-Divisória - Granito cinza Andorinha, Volume do componente (Bruto): 0.0343125 m3

# IfcFurniture: FNDE-Mão Francesa 250 x 250 (4)
In: TÉRREO
Classification: Mobiliário (Classificação Archicad); Material: Aço
FNDE - Pedras: - - GRANITO CINZA ANDORINHA - esp. 2 cm; 1_Bloco: BLOCO B; 0_ID: B18
Component Quantities - Aço, Massa: 0.5772 kg; Aço, Área de Seção Transversal do Componente: 0.0037 m2; Aço, Volume Componente (Líquido): 0.000074 m3; Aço, Volume do componente (Bruto): 0.000074 m3

# IfcFurniture: Lousa Escolar 27 (5)
In: TÉRREO
Classification: Mobiliário (Classificação Archicad)
FNDE - Pedras: - -
Name | ModelLabel = Mobiliário ou Equipamento - Modelo | 1_Bloco | 0_ID | Component, Volume Componente (Líquido) (m3) = Component, Volume do componente (Bruto) (m3)
2 x QB1 | QUADRO BRANCO TIPO LOUSA MAGNÉTICO - DIM: 120x200cm (AxL) | BLOCO B | QB1 | 0.12
2 x QB2 | QUADRO BRANCO TIPO LOUSA MAGNÉTICO - DIM: 120x300cm (AxL) | BLOCO B | QB2 | 0.18
QM | QUADRO MURAL DE FELTRO - DIM: 120x90cm (AxL) | BLOCO A | QM | 0.054

# IfcFurniture: Porta de Chuveiro 27 (2)
In: TÉRREO
Classification: Mobiliário (Classificação Archicad)
Pset_ManufacturerTypeInformation - ModelLabel: BOX EM VIDRO TEMPERADO INCOLOR, 10mm, COM ALTURA DE 1,80m
FNDE - Mobiliário ou Equipamento - Modelo: BOX EM VIDRO TEMPERADO INCOLOR, 10mm, COM ALTURA DE 1,80m; Pedras: - -; 1_Bloco: BLOCO A
Component Quantities - Component, Volume Componente (Líquido): 0.00873526 m3; Component, Volume do componente (Bruto): 0.00873526 m3

# IfcFurniture: Shower Seat, CA
In: TÉRREO
Classification: Mobiliário (Classificação Archicad)
Pset_ManufacturerTypeInformation - ModelLabel: CADEIRA ARTICULADA PARA BANHO CONFORTO, DECA OU EQUIVALENTE
FNDE - Mobiliário ou Equipamento - Modelo: CADEIRA ARTICULADA PARA BANHO CONFORTO, DECA OU EQUIVALENTE; Pedras: - -; 1_Bloco: BLOCO B; 0_ID: CA
Component Quantities - Component, Volume Componente (Líquido): 0.00289503 m3; Component, Volume do componente (Bruto): 0.00289503 m3

# IfcFurniture: Texto 3D 27 (2)
In: TÉRREO
Classification: Mobiliário (Classificação Archicad)
Pset_ManufacturerTypeInformation - ModelLabel: Papeleira sobrepor interfolhado
FNDE - Mobiliário ou Equipamento - Modelo: Papeleira sobrepor interfolhado; Pedras: - -; 1_Bloco: BLOCO A; 0_ID: CJR-70
Name | Component, Volume Componente (Líquido) (m3) = Component, Volume do componente (Bruto) (m3)
CJR-70 | 0.00564572
CJR-70 | 0.00327974

# IfcFurniture: Várias Estruturas- 2 Segmentos - 600 x 150 x 1235 (20+1215), B13
In: TÉRREO
Classification: Mobiliário (Classificação Archicad); Material: EI-GRA-Granito cinza Andorinha (Bancadas, bancos e prateleiras) (6)
FNDE - Pedras: BANCADA - GRANITO CINZA ANDORINHA - esp. 2 cm; 1_Bloco: BLOCO A; 0_ID: B13
Component Quantities - EI-GRA-Granito cinza Andorinha (Bancadas, bancos e prateleiras) 1, Massa: 3.696 kg; EI-GRA-Granito cinza Andorinha (Bancadas, bancos e prateleiras) 1, Altura do Componente Retangular: 0.11 m; EI-GRA-Granito cinza Andorinha (Bancadas, bancos e prateleiras) 1, Largura do Componente Retangular: 0.6 m; EI-GRA-Granito cinza Andorinha (Bancadas, bancos e prateleiras) 1, Área de Seção Transversal do Componente: 0.066 m2; EI-GRA-Granito cinza Andorinha (Bancadas, bancos e prateleiras) 1, Volume Componente (Líquido): 0.00132 m3; EI-GRA-Granito cinza Andorinha (Bancadas, bancos e prateleiras) 1, Volume do componente (Bruto): 0.00132 m3; EI-GRA-Granito cinza Andorinha (Bancadas, bancos e prateleiras) 2, Massa: 0.64512 kg; EI-GRA-Granito cinza Andorinha (Bancadas, bancos e prateleiras) 2, Altura do Componente Retangular: 0.02 m; EI-GRA-Granito cinza Andorinha (Bancadas, bancos e prateleiras) 2, Largura do Componente Retangular: 0.576 m; EI-GRA-Granito cinza Andorinha (Bancadas, bancos e prateleiras) 2, Área de Seção Transversal do Componente: 0.01152 m2; EI-GRA-Granito cinza Andorinha (Bancadas, bancos e prateleiras) 2, Volume Componente (Líquido): 0.0002304 m3; EI-GRA-Granito cinza Andorinha (Bancadas, bancos e prateleiras) 2, Volume do componente (Bruto): 0.0002304 m3; EI-GRA-Granito cinza Andorinha (Bancadas, bancos e prateleiras) 3, Massa: 0.05376 kg; EI-GRA-Granito cinza Andorinha (Bancadas, bancos e prateleiras) 3, Altura do Componente Retangular: 0.04 m; EI-GRA-Granito cinza Andorinha (Bancadas, bancos e prateleiras) 3, Largura do Componente Retangular: 0.024 m; EI-GRA-Granito cinza Andorinha (Bancadas, bancos e prateleiras) 3, Área de Seção Transversal do Componente: 0.00096 m2; EI-GRA-Granito cinza Andorinha (Bancadas, bancos e prateleiras) 3, Volume Componente (Líquido): 0.0000192 m3; EI-GRA-Granito cinza Andorinha (Bancadas, bancos e prateleiras) 3, Volume do componente (Bruto): 0.0000192 m3; EI-GRA-Granito cinza Andorinha (Bancadas, bancos e prateleiras) 4, Massa: 8.98065 kg; EI-GRA-Granito cinza Andorinha (Bancadas, bancos e prateleiras) 4, Altura do Componente Retangular: 0.11 m; EI-GRA-Granito cinza Andorinha (Bancadas, bancos e prateleiras) 4, Largura do Componente Retangular: 0.024 m; EI-GRA-Granito cinza Andorinha (Bancadas, bancos e prateleiras) 4, Área de Seção Transversal do Componente: 0.00264 m2; EI-GRA-Granito cinza Andorinha (Bancadas, bancos e prateleiras) 4, Volume Componente (Líquido): 0.00320738 m3; EI-GRA-Granito cinza Andorinha (Bancadas, bancos e prateleiras) 4, Volume do componente (Bruto): 0.00320738 m3; EI-GRA-Granito cinza Andorinha (Bancadas, bancos e prateleiras) 5, Massa: 28.1775 kg; EI-GRA-Granito cinza Andorinha (Bancadas, bancos e prateleiras) 5, Altura do Componente Retangular: 0.02 m; EI-GRA-Granito cinza Andorinha (Bancadas, bancos e prateleiras) 5, Largura do Componente Retangular: 0.576 m; EI-GRA-Granito cinza Andorinha (Bancadas, bancos e prateleiras) 5, Área de Seção Transversal do Componente: 0.01152 m2; EI-GRA-Granito cinza Andorinha (Bancadas, bancos e prateleiras) 5, Volume Componente (Líquido): 0.0100634 m3; EI-GRA-Granito cinza Andorinha (Bancadas, bancos e prateleiras) 5, Volume do componente (Bruto): 0.0139958 m3; EI-GRA-Granito cinza Andorinha (Bancadas, bancos e prateleiras) 6, Massa: 4.08211 kg; EI-GRA-Granito cinza Andorinha (Bancadas, bancos e prateleiras) 6, Altura do Componente Retangular: 0.05 m; EI-GRA-Granito cinza Andorinha (Bancadas, bancos e prateleiras) 6, Largura do Componente Retangular: 0.024 m; EI-GRA-Granito cinza Andorinha (Bancadas, bancos e prateleiras) 6, Área de Seção Transversal do Componente: 0.0012 m2; EI-GRA-Granito cinza Andorinha (Bancadas, bancos e prateleiras) 6, Volume Componente (Líquido): 0.0014579 m3; EI-GRA-Granito cinza Andorinha (Bancadas, bancos e prateleiras) 6, Volume do componente (Bruto): 0.0014579 m3

# IfcFurniture: Várias Estruturas- 2 Segmentos - 600 x 150 x 1500 (20+1480), B16
In: TÉRREO
Classification: Mobiliário (Classificação Archicad); Material: EI-GRA-Granito cinza Andorinha (Bancadas, bancos e prateleiras) (6)
FNDE - Pedras: BANCADA - GRANITO CINZA ANDORINHA - esp. 2 cm; 1_Bloco: BLOCO A; 0_ID: B16
Component Quantities - EI-GRA-Granito cinza Andorinha (Bancadas, bancos e prateleiras) 1, Massa: 0.1344 kg; EI-GRA-Granito cinza Andorinha (Bancadas, bancos e prateleiras) 1, Altura do Componente Retangular: 0.1 m; EI-GRA-Granito cinza Andorinha (Bancadas, bancos e prateleiras) 1, Largura do Componente Retangular: 0.024 m; EI-GRA-Granito cinza Andorinha (Bancadas, bancos e prateleiras) 1, Área de Seção Transversal do Componente: 0.0024 m2; EI-GRA-Granito cinza Andorinha (Bancadas, bancos e prateleiras) 1, Volume Componente (Líquido): 0.000048 m3; EI-GRA-Granito cinza Andorinha (Bancadas, bancos e prateleiras) 1, Volume do componente (Bruto): 0.000048 m3; EI-GRA-Granito cinza Andorinha (Bancadas, bancos e prateleiras) 2, Massa: 0.672 kg; EI-GRA-Granito cinza Andorinha (Bancadas, bancos e prateleiras) 2, Altura do Componente Retangular: 0.02 m; EI-GRA-Granito cinza Andorinha (Bancadas, bancos e prateleiras) 2, Largura do Componente Retangular: 0.6 m; EI-GRA-Granito cinza Andorinha (Bancadas, bancos e prateleiras) 2, Área de Seção Transversal do Componente: 0.012 m2; EI-GRA-Granito cinza Andorinha (Bancadas, bancos e prateleiras) 2, Volume Componente (Líquido): 0.00024 m3; EI-GRA-Granito cinza Andorinha (Bancadas, bancos e prateleiras) 2, Volume do componente (Bruto): 0.00024 m3; EI-GRA-Granito cinza Andorinha (Bancadas, bancos e prateleiras) 3, Massa: 1.008 kg; EI-GRA-Granito cinza Andorinha (Bancadas, bancos e prateleiras) 3, Altura do Componente Retangular: 0.03 m; EI-GRA-Granito cinza Andorinha (Bancadas, bancos e prateleiras) 3, Largura do Componente Retangular: 0.6 m; EI-GRA-Granito cinza Andorinha (Bancadas, bancos e prateleiras) 3, Área de Seção Transversal do Componente: 0.018 m2; EI-GRA-Granito cinza Andorinha (Bancadas, bancos e prateleiras) 3, Volume Componente (Líquido): 0.00036 m3; EI-GRA-Granito cinza Andorinha (Bancadas, bancos e prateleiras) 3, Volume do componente (Bruto): 0.00036 m3; EI-GRA-Granito cinza Andorinha (Bancadas, bancos e prateleiras) 4, Massa: 9.86294 kg; EI-GRA-Granito cinza Andorinha (Bancadas, bancos e prateleiras) 4, Altura do Componente Retangular: 0.1 m; EI-GRA-Granito cinza Andorinha (Bancadas, bancos e prateleiras) 4, Largura do Componente Retangular: 0.024 m; EI-GRA-Granito cinza Andorinha (Bancadas, bancos e prateleiras) 4, Área de Seção Transversal do Componente: 0.0024 m2; EI-GRA-Granito cinza Andorinha (Bancadas, bancos e prateleiras) 4, Volume Componente (Líquido): 0.00352248 m3; EI-GRA-Granito cinza Andorinha (Bancadas, bancos e prateleiras) 4, Volume do componente (Bruto): 0.00352248 m3; EI-GRA-Granito cinza Andorinha (Bancadas, bancos e prateleiras) 5, Massa: 29.6385 kg; EI-GRA-Granito cinza Andorinha (Bancadas, bancos e prateleiras) 5, Área de Seção Transversal do Componente: 0.01176 m2; EI-GRA-Granito cinza Andorinha (Bancadas, bancos e prateleiras) 5, Volume Componente (Líquido): 0.0105852 m3; EI-GRA-Granito cinza Andorinha (Bancadas, bancos e prateleiras) 5, Volume do componente (Bruto): 0.0105852 m3; EI-GRA-Granito cinza Andorinha (Bancadas, bancos e prateleiras) 6, Massa: 2.36553 kg; EI-GRA-Granito cinza Andorinha (Bancadas, bancos e prateleiras) 6, Área de Seção Transversal do Componente: 0.00096 m2; EI-GRA-Granito cinza Andorinha (Bancadas, bancos e prateleiras) 6, Volume Componente (Líquido): 0.000844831 m3; EI-GRA-Granito cinza Andorinha (Bancadas, bancos e prateleiras) 6, Volume do componente (Bruto): 0.000844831 m3

# IfcFurniture: Várias Estruturas- 2 Segmentos - 600 x 150 x 2100 (2080+20), B12
In: TÉRREO
Classification: Mobiliário (Classificação Archicad); Material: EI-GRA-Granito cinza Andorinha (Bancadas, bancos e prateleiras) (6)
FNDE - Pedras: BANCADA - GRANITO CINZA ANDORINHA - esp. 2 cm; 1_Bloco: BLOCO A; 0_ID: B12
Component Quantities - EI-GRA-Granito cinza Andorinha (Bancadas, bancos e prateleiras) 1, Massa: 13.8969 kg; EI-GRA-Granito cinza Andorinha (Bancadas, bancos e prateleiras) 1, Altura do Componente Retangular: 0.1 m; EI-GRA-Granito cinza Andorinha (Bancadas, bancos e prateleiras) 1, Largura do Componente Retangular: 0.024 m; EI-GRA-Granito cinza Andorinha (Bancadas, bancos e prateleiras) 1, Área de Seção Transversal do Componente: 0.0024 m2; EI-GRA-Granito cinza Andorinha (Bancadas, bancos e prateleiras) 1, Volume Componente (Líquido): 0.0049632 m3; EI-GRA-Granito cinza Andorinha (Bancadas, bancos e prateleiras) 1, Volume do componente (Bruto): 0.0049632 m3; EI-GRA-Granito cinza Andorinha (Bancadas, bancos e prateleiras) 2, Massa: 58.8065 kg; EI-GRA-Granito cinza Andorinha (Bancadas, bancos e prateleiras) 2, Área de Seção Transversal do Componente: 0.01176 m2; EI-GRA-Granito cinza Andorinha (Bancadas, bancos e prateleiras) 2, Volume Componente (Líquido): 0.0210023 m3; EI-GRA-Granito cinza Andorinha (Bancadas, bancos e prateleiras) 2, Volume do componente (Bruto): 0.0210023 m3; EI-GRA-Granito cinza Andorinha (Bancadas, bancos e prateleiras) 3, Massa: 4.00756 kg; EI-GRA-Granito cinza Andorinha (Bancadas, bancos e prateleiras) 3, Área de Seção Transversal do Componente: 0.00096 m2; EI-GRA-Granito cinza Andorinha (Bancadas, bancos e prateleiras) 3, Volume Componente (Líquido): 0.00143127 m3; EI-GRA-Granito cinza Andorinha (Bancadas, bancos e prateleiras) 3, Volume do componente (Bruto): 0.00143127 m3; EI-GRA-Granito cinza Andorinha (Bancadas, bancos e prateleiras) 4, Massa: 0.1344 kg; EI-GRA-Granito cinza Andorinha (Bancadas, bancos e prateleiras) 4, Altura do Componente Retangular: 0.1 m; EI-GRA-Granito cinza Andorinha (Bancadas, bancos e prateleiras) 4, Largura do Componente Retangular: 0.024 m; EI-GRA-Granito cinza Andorinha (Bancadas, bancos e prateleiras) 4, Área de Seção Transversal do Componente: 0.0024 m2; EI-GRA-Granito cinza Andorinha (Bancadas, bancos e prateleiras) 4, Volume Componente (Líquido): 0.000048 m3; EI-GRA-Granito cinza Andorinha (Bancadas, bancos e prateleiras) 4, Volume do componente (Bruto): 0.000048 m3; EI-GRA-Granito cinza Andorinha (Bancadas, bancos e prateleiras) 5, Massa: 0.672 kg; EI-GRA-Granito cinza Andorinha (Bancadas, bancos e prateleiras) 5, Altura do Componente Retangular: 0.02 m; EI-GRA-Granito cinza Andorinha (Bancadas, bancos e prateleiras) 5, Largura do Componente Retangular: 0.6 m; EI-GRA-Granito cinza Andorinha (Bancadas, bancos e prateleiras) 5, Área de Seção Transversal do Componente: 0.012 m2; EI-GRA-Granito cinza Andorinha (Bancadas, bancos e prateleiras) 5, Volume Componente (Líquido): 0.00024 m3; EI-GRA-Granito cinza Andorinha (Bancadas, bancos e prateleiras) 5, Volume do componente (Bruto): 0.00024 m3; EI-GRA-Granito cinza Andorinha (Bancadas, bancos e prateleiras) 6, Massa: 1.008 kg; EI-GRA-Granito cinza Andorinha (Bancadas, bancos e prateleiras) 6, Altura do Componente Retangular: 0.03 m; EI-GRA-Granito cinza Andorinha (Bancadas, bancos e prateleiras) 6, Largura do Componente Retangular: 0.6 m; EI-GRA-Granito cinza Andorinha (Bancadas, bancos e prateleiras) 6, Área de Seção Transversal do Componente: 0.018 m2; EI-GRA-Granito cinza Andorinha (Bancadas, bancos e prateleiras) 6, Volume Componente (Líquido): 0.00036 m3; EI-GRA-Granito cinza Andorinha (Bancadas, bancos e prateleiras) 6, Volume do componente (Bruto): 0.00036 m3

# IfcFurniture: Várias Estruturas- 2 Segmentos - 600 x 150 x 865 (845+20), B13
In: TÉRREO
Classification: Mobiliário (Classificação Archicad); Material: EI-GRA-Granito cinza Andorinha (Bancadas, bancos e prateleiras) (6)
FNDE - Pedras: BANCADA - GRANITO CINZA ANDORINHA - esp. 2 cm; 1_Bloco: BLOCO A; 0_ID: B13
Component Quantities - EI-GRA-Granito cinza Andorinha (Bancadas, bancos e prateleiras) 1, Massa: 5.68045 kg; EI-GRA-Granito cinza Andorinha (Bancadas, bancos e prateleiras) 1, Altura do Componente Retangular: 0.1 m; EI-GRA-Granito cinza Andorinha (Bancadas, bancos e prateleiras) 1, Largura do Componente Retangular: 0.024 m; EI-GRA-Granito cinza Andorinha (Bancadas, bancos e prateleiras) 1, Área de Seção Transversal do Componente: 0.0024 m2; EI-GRA-Granito cinza Andorinha (Bancadas, bancos e prateleiras) 1, Volume Componente (Líquido): 0.00202873 m3; EI-GRA-Granito cinza Andorinha (Bancadas, bancos e prateleiras) 1, Volume do componente (Bruto): 0.00202873 m3; EI-GRA-Granito cinza Andorinha (Bancadas, bancos e prateleiras) 2, Massa: 27.8342 kg; EI-GRA-Granito cinza Andorinha (Bancadas, bancos e prateleiras) 2, Área de Seção Transversal do Componente: 0.01176 m2; EI-GRA-Granito cinza Andorinha (Bancadas, bancos e prateleiras) 2, Volume Componente (Líquido): 0.00994079 m3; EI-GRA-Granito cinza Andorinha (Bancadas, bancos e prateleiras) 2, Volume do componente (Bruto): 0.00994079 m3; EI-GRA-Granito cinza Andorinha (Bancadas, bancos e prateleiras) 3, Massa: 2.27218 kg; EI-GRA-Granito cinza Andorinha (Bancadas, bancos e prateleiras) 3, Área de Seção Transversal do Componente: 0.00096 m2; EI-GRA-Granito cinza Andorinha (Bancadas, bancos e prateleiras) 3, Volume Componente (Líquido): 0.000811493 m3; EI-GRA-Granito cinza Andorinha (Bancadas, bancos e prateleiras) 3, Volume do componente (Bruto): 0.000811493 m3; EI-GRA-Granito cinza Andorinha (Bancadas, bancos e prateleiras) 4, Massa: 0.05376 kg; EI-GRA-Granito cinza Andorinha (Bancadas, bancos e prateleiras) 4, Área de Seção Transversal do Componente: 0.00096 m2; EI-GRA-Granito cinza Andorinha (Bancadas, bancos e prateleiras) 4, Volume Componente (Líquido): 0.0000192 m3; EI-GRA-Granito cinza Andorinha (Bancadas, bancos e prateleiras) 4, Volume do componente (Bruto): 0.0000192 m3; EI-GRA-Granito cinza Andorinha (Bancadas, bancos e prateleiras) 5, Massa: 3.23433 kg; EI-GRA-Granito cinza Andorinha (Bancadas, bancos e prateleiras) 5, Altura do Componente Retangular: 0.1 m; EI-GRA-Granito cinza Andorinha (Bancadas, bancos e prateleiras) 5, Largura do Componente Retangular: 0.6 m; EI-GRA-Granito cinza Andorinha (Bancadas, bancos e prateleiras) 5, Área de Seção Transversal do Componente: 0.06 m2; EI-GRA-Granito cinza Andorinha (Bancadas, bancos e prateleiras) 5, Volume Componente (Líquido): 0.00115512 m3; EI-GRA-Granito cinza Andorinha (Bancadas, bancos e prateleiras) 5, Volume do componente (Bruto): 0.00115512 m3; EI-GRA-Granito cinza Andorinha (Bancadas, bancos e prateleiras) 6, Massa: 0.633426 kg; EI-GRA-Granito cinza Andorinha (Bancadas, bancos e prateleiras) 6, Área de Seção Transversal do Componente: 0.01176 m2; EI-GRA-Granito cinza Andorinha (Bancadas, bancos e prateleiras) 6, Volume Componente (Líquido): 0.000226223 m3; EI-GRA-Granito cinza Andorinha (Bancadas, bancos e prateleiras) 6, Volume do componente (Bruto): 0.000226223 m3

# IfcFurniture: Várias Estruturas- 3 Segmentos - 40 x 40 x 6000 (3000+2000+1000) (2)
In: TÉRREO
Classification: Mobiliário (Classificação Archicad); Material: GENÉRICO - ESTRUTURAL (3)
FNDE - Pedras: - -; 1_Bloco: ÁREAS EXTERNAS; 0_ID: P01
Component Quantities - GENÉRICO - ESTRUTURAL 1, Massa: 8.28 kg; GENÉRICO - ESTRUTURAL 1, Espessura do Componente: 0.04 m; GENÉRICO - ESTRUTURAL 1, Área de Seção Transversal do Componente: 0.00125664 m2; GENÉRICO - ESTRUTURAL 1, Volume Componente (Líquido): 0.0036 m3; GENÉRICO - ESTRUTURAL 1, Volume do componente (Bruto): 0.0036 m3; GENÉRICO - ESTRUTURAL 2, Massa: 3.105 kg; GENÉRICO - ESTRUTURAL 2, Espessura do Componente: 0.03 m; GENÉRICO - ESTRUTURAL 2, Área de Seção Transversal do Componente: 0.000706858 m2; GENÉRICO - ESTRUTURAL 2, Volume Componente (Líquido): 0.00135 m3; GENÉRICO - ESTRUTURAL 2, Volume do componente (Bruto): 0.00135 m3; GENÉRICO - ESTRUTURAL 3, Massa: 0.650538 kg; GENÉRICO - ESTRUTURAL 3, Espessura do Componente: 0.02 m; GENÉRICO - ESTRUTURAL 3, Área de Seção Transversal do Componente: 0.000314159 m2; GENÉRICO - ESTRUTURAL 3, Volume Componente (Líquido): 0.000282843 m3; GENÉRICO - ESTRUTURAL 3, Volume do componente (Bruto): 0.000282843 m3

# IfcFurniture: Várias Estruturas- 3 Segmentos - 40 x 40 x 7000 (3000+3000+1000), P01
In: TÉRREO
Classification: Mobiliário (Classificação Archicad); Material: GENÉRICO - ESTRUTURAL (3)
FNDE - Pedras: - -; 1_Bloco: ÁREAS EXTERNAS; 0_ID: P01
Component Quantities - GENÉRICO - ESTRUTURAL 1, Massa: 8.28 kg; GENÉRICO - ESTRUTURAL 1, Espessura do Componente: 0.04 m; GENÉRICO - ESTRUTURAL 1, Área de Seção Transversal do Componente: 0.00125664 m2; GENÉRICO - ESTRUTURAL 1, Volume Componente (Líquido): 0.0036 m3; GENÉRICO - ESTRUTURAL 1, Volume do componente (Bruto): 0.0036 m3; GENÉRICO - ESTRUTURAL 2, Massa: 4.6575 kg; GENÉRICO - ESTRUTURAL 2, Espessura do Componente: 0.03 m; GENÉRICO - ESTRUTURAL 2, Área de Seção Transversal do Componente: 0.000706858 m2; GENÉRICO - ESTRUTURAL 2, Volume Componente (Líquido): 0.002025 m3; GENÉRICO - ESTRUTURAL 2, Volume do componente (Bruto): 0.002025 m3; GENÉRICO - ESTRUTURAL 3, Massa: 0.650538 kg; GENÉRICO - ESTRUTURAL 3, Espessura do Componente: 0.02 m; GENÉRICO - ESTRUTURAL 3, Área de Seção Transversal do Componente: 0.000314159 m2; GENÉRICO - ESTRUTURAL 3, Volume Componente (Líquido): 0.000282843 m3; GENÉRICO - ESTRUTURAL 3, Volume do componente (Bruto): 0.000282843 m3

# IfcFurniture: Várias Estruturas- 3 Segmentos - 400 x 150 x 3151 (20+3111+20), B14
In: TÉRREO
Classification: Mobiliário (Classificação Archicad); Material: EI-GRA-Granito cinza Andorinha (Bancadas, bancos e prateleiras) (9)
FNDE - Pedras: BANCADA - GRANITO CINZA ANDORINHA - esp. 2 cm; 1_Bloco: BLOCO A; 0_ID: B14
Component Quantities - EI-GRA-Granito cinza Andorinha (Bancadas, bancos e prateleiras) 1, Massa: 0.03584 kg; EI-GRA-Granito cinza Andorinha (Bancadas, bancos e prateleiras) 1, Área de Seção Transversal do Componente: 0.00064 m2; EI-GRA-Granito cinza Andorinha (Bancadas, bancos e prateleiras) 1, Volume Componente (Líquido): 0.0000128 m3; EI-GRA-Granito cinza Andorinha (Bancadas, bancos e prateleiras) 1, Volume do componente (Bruto): 0.0000128 m3; EI-GRA-Granito cinza Andorinha (Bancadas, bancos e prateleiras) 2, Massa: 2.24 kg; EI-GRA-Granito cinza Andorinha (Bancadas, bancos e prateleiras) 2, Altura do Componente Retangular: 0.1 m; EI-GRA-Granito cinza Andorinha (Bancadas, bancos e prateleiras) 2, Largura do Componente Retangular: 0.4 m; EI-GRA-Granito cinza Andorinha (Bancadas, bancos e prateleiras) 2, Área de Seção Transversal do Componente: 0.04 m2; EI-GRA-Granito cinza Andorinha (Bancadas, bancos e prateleiras) 2, Volume Componente (Líquido): 0.0008 m3; EI-GRA-Granito cinza Andorinha (Bancadas, bancos e prateleiras) 2, Volume do componente (Bruto): 0.0008 m3; EI-GRA-Granito cinza Andorinha (Bancadas, bancos e prateleiras) 3, Massa: 0.43904 kg; EI-GRA-Granito cinza Andorinha (Bancadas, bancos e prateleiras) 3, Área de Seção Transversal do Componente: 0.00784 m2; EI-GRA-Granito cinza Andorinha (Bancadas, bancos e prateleiras) 3, Volume Componente (Líquido): 0.0001568 m3; EI-GRA-Granito cinza Andorinha (Bancadas, bancos e prateleiras) 3, Volume do componente (Bruto): 0.0001568 m3; EI-GRA-Granito cinza Andorinha (Bancadas, bancos e prateleiras) 4, Massa: 13.9356 kg; EI-GRA-Granito cinza Andorinha (Bancadas, bancos e prateleiras) 4, Altura do Componente Retangular: 0.1 m; EI-GRA-Granito cinza Andorinha (Bancadas, bancos e prateleiras) 4, Largura do Componente Retangular: 0.016 m; EI-GRA-Granito cinza Andorinha (Bancadas, bancos e prateleiras) 4, Área de Seção Transversal do Componente: 0.0016 m2; EI-GRA-Granito cinza Andorinha (Bancadas, bancos e prateleiras) 4, Volume Componente (Líquido): 0.00497701 m3; EI-GRA-Granito cinza Andorinha (Bancadas, bancos e prateleiras) 4, Volume do componente (Bruto): 0.00497701 m3; EI-GRA-Granito cinza Andorinha (Bancadas, bancos e prateleiras) 5, Massa: 68.2845 kg; EI-GRA-Granito cinza Andorinha (Bancadas, bancos e prateleiras) 5, Área de Seção Transversal do Componente: 0.00784 m2; EI-GRA-Granito cinza Andorinha (Bancadas, bancos e prateleiras) 5, Volume Componente (Líquido): 0.0243873 m3; EI-GRA-Granito cinza Andorinha (Bancadas, bancos e prateleiras) 5, Volume do componente (Bruto): 0.0243873 m3; EI-GRA-Granito cinza Andorinha (Bancadas, bancos e prateleiras) 6, Massa: 5.57425 kg; EI-GRA-Granito cinza Andorinha (Bancadas, bancos e prateleiras) 6, Área de Seção Transversal do Componente: 0.00064 m2; EI-GRA-Granito cinza Andorinha (Bancadas, bancos e prateleiras) 6, Volume Componente (Líquido): 0.0019908 m3; EI-GRA-Granito cinza Andorinha (Bancadas, bancos e prateleiras) 6, Volume do componente (Bruto): 0.0019908 m3; EI-GRA-Granito cinza Andorinha (Bancadas, bancos e prateleiras) 1: 2 with these values; EI-GRA-Granito cinza Andorinha (Bancadas, bancos e prateleiras) 2: 2 with these values; EI-GRA-Granito cinza Andorinha (Bancadas, bancos e prateleiras) 3: 2 with these values

# IfcFurniture: Várias Estruturas- 3 Segmentos - 400 x 50 x 1310 (30+1250+30) (2)
In: TÉRREO
Classification: Mobiliário (Classificação Archicad); Material: EI-GRA-Granito cinza Andorinha (Bancadas, bancos e prateleiras) (4)
FNDE - Pedras: BANCO - GRANITO CINZA ANDORINHA - esp. 2 cm; 1_Bloco: BLOCO B; 0_ID: BC2
Component Quantities - EI-GRA-Granito cinza Andorinha (Bancadas, bancos e prateleiras) 1, Massa: 0.672 kg; EI-GRA-Granito cinza Andorinha (Bancadas, bancos e prateleiras) 1, Altura do Componente Retangular: 0.02 m; EI-GRA-Granito cinza Andorinha (Bancadas, bancos e prateleiras) 1, Largura do Componente Retangular: 0.4 m; EI-GRA-Granito cinza Andorinha (Bancadas, bancos e prateleiras) 1, Área de Seção Transversal do Componente: 0.008 m2; EI-GRA-Granito cinza Andorinha (Bancadas, bancos e prateleiras) 1, Volume Componente (Líquido): 0.00024 m3; EI-GRA-Granito cinza Andorinha (Bancadas, bancos e prateleiras) 1, Volume do componente (Bruto): 0.00024 m3; EI-GRA-Granito cinza Andorinha (Bancadas, bancos e prateleiras) 2, Massa: 27.44 kg; EI-GRA-Granito cinza Andorinha (Bancadas, bancos e prateleiras) 2, Área de Seção Transversal do Componente: 0.00784 m2; EI-GRA-Granito cinza Andorinha (Bancadas, bancos e prateleiras) 2, Volume Componente (Líquido): 0.0098 m3; EI-GRA-Granito cinza Andorinha (Bancadas, bancos e prateleiras) 2, Volume do componente (Bruto): 0.0098 m3; EI-GRA-Granito cinza Andorinha (Bancadas, bancos e prateleiras) 3, Massa: 2.24 kg; EI-GRA-Granito cinza Andorinha (Bancadas, bancos e prateleiras) 3, Área de Seção Transversal do Componente: 0.00064 m2; EI-GRA-Granito cinza Andorinha (Bancadas, bancos e prateleiras) 3, Volume Componente (Líquido): 0.0008 m3; EI-GRA-Granito cinza Andorinha (Bancadas, bancos e prateleiras) 3, Volume do componente (Bruto): 0.0008 m3
Name
BC2 | Component Quantities - EI-GRA-Granito cinza Andorinha (Bancadas, bancos e prateleiras) 4, Massa: 0.56358 kg; EI-GRA-Granito cinza Andorinha (Bancadas, bancos e prateleiras) 4, Altura do Componente Retangular: 0.02 m; EI-GRA-Granito cinza Andorinha (Bancadas, bancos e prateleiras) 4, Largura do Componente Retangular: 0.4 m; EI-GRA-Granito cinza Andorinha (Bancadas, bancos e prateleiras) 4, Área de Seção Transversal do Componente: 0.008 m2; EI-GRA-Granito cinza Andorinha (Bancadas, bancos e prateleiras) 4, Volume Componente (Líquido): 0.000201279 m3; EI-GRA-Granito cinza Andorinha (Bancadas, bancos e prateleiras) 4, Volume do componente (Bruto): 0.000201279 m3
BC2 | Component Quantities - EI-GRA-Granito cinza Andorinha (Bancadas, bancos e prateleiras) 1: 2 with these values

# IfcFurniture: Várias Estruturas- 3 Segmentos - 400 x 50 x 927 (30+870+27) (2)
In: TÉRREO
Classification: Mobiliário (Classificação Archicad); Material: EI-GRA-Granito cinza Andorinha (Bancadas, bancos e prateleiras) (4)
FNDE - Pedras: BANCO - GRANITO CINZA ANDORINHA - esp. 2 cm; 1_Bloco: BLOCO B; 0_ID: BC3
Component Quantities - EI-GRA-Granito cinza Andorinha (Bancadas, bancos e prateleiras) 1, Massa: 0.672 kg; EI-GRA-Granito cinza Andorinha (Bancadas, bancos e prateleiras) 1, Altura do Componente Retangular: 0.02 m; EI-GRA-Granito cinza Andorinha (Bancadas, bancos e prateleiras) 1, Largura do Componente Retangular: 0.4 m; EI-GRA-Granito cinza Andorinha (Bancadas, bancos e prateleiras) 1, Área de Seção Transversal do Componente: 0.008 m2; EI-GRA-Granito cinza Andorinha (Bancadas, bancos e prateleiras) 1, Volume Componente (Líquido): 0.00024 m3; EI-GRA-Granito cinza Andorinha (Bancadas, bancos e prateleiras) 1, Volume do componente (Bruto): 0.00024 m3; EI-GRA-Granito cinza Andorinha (Bancadas, bancos e prateleiras) 2, Massa: 19.0982 kg; EI-GRA-Granito cinza Andorinha (Bancadas, bancos e prateleiras) 2, Área de Seção Transversal do Componente: 0.00784 m2; EI-GRA-Granito cinza Andorinha (Bancadas, bancos e prateleiras) 2, Volume Componente (Líquido): 0.0068208 m3; EI-GRA-Granito cinza Andorinha (Bancadas, bancos e prateleiras) 2, Volume do componente (Bruto): 0.0068208 m3; EI-GRA-Granito cinza Andorinha (Bancadas, bancos e prateleiras) 3, Massa: 1.55904 kg; EI-GRA-Granito cinza Andorinha (Bancadas, bancos e prateleiras) 3, Área de Seção Transversal do Componente: 0.00064 m2; EI-GRA-Granito cinza Andorinha (Bancadas, bancos e prateleiras) 3, Volume Componente (Líquido): 0.0005568 m3; EI-GRA-Granito cinza Andorinha (Bancadas, bancos e prateleiras) 3, Volume do componente (Bruto): 0.0005568 m3; EI-GRA-Granito cinza Andorinha (Bancadas, bancos e prateleiras) 4, Massa: 0.615276 kg; EI-GRA-Granito cinza Andorinha (Bancadas, bancos e prateleiras) 4, Altura do Componente Retangular: 0.02 m; EI-GRA-Granito cinza Andorinha (Bancadas, bancos e prateleiras) 4, Largura do Componente Retangular: 0.4 m; EI-GRA-Granito cinza Andorinha (Bancadas, bancos e prateleiras) 4, Área de Seção Transversal do Componente: 0.008 m2; EI-GRA-Granito cinza Andorinha (Bancadas, bancos e prateleiras) 4, Volume Componente (Líquido): 0.000219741 m3; EI-GRA-Granito cinza Andorinha (Bancadas, bancos e prateleiras) 4, Volume do componente (Bruto): 0.000219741 m3

# IfcFurniture: Várias Estruturas- 3 Segmentos - 500 x 150 x 1599 (20+1559+20), B05
In: TÉRREO
Classification: Mobiliário (Classificação Archicad); Material: EI-GRA-Granito cinza Andorinha (Bancadas, bancos e prateleiras) (9)
FNDE - Pedras: BANCADA - GRANITO CINZA ANDORINHA - esp. 2 cm; 1_Bloco: BLOCO A; 0_ID: B05
Component Quantities - EI-GRA-Granito cinza Andorinha (Bancadas, bancos e prateleiras) 1, Massa: 0.0448 kg; EI-GRA-Granito cinza Andorinha (Bancadas, bancos e prateleiras) 1, Área de Seção Transversal do Componente: 0.0008 m2; EI-GRA-Granito cinza Andorinha (Bancadas, bancos e prateleiras) 1, Volume Componente (Líquido): 0.000016 m3; EI-GRA-Granito cinza Andorinha (Bancadas, bancos e prateleiras) 1, Volume do componente (Bruto): 0.000016 m3; EI-GRA-Granito cinza Andorinha (Bancadas, bancos e prateleiras) 2, Massa: 2.8 kg; EI-GRA-Granito cinza Andorinha (Bancadas, bancos e prateleiras) 2, Altura do Componente Retangular: 0.1 m; EI-GRA-Granito cinza Andorinha (Bancadas, bancos e prateleiras) 2, Largura do Componente Retangular: 0.5 m; EI-GRA-Granito cinza Andorinha (Bancadas, bancos e prateleiras) 2, Área de Seção Transversal do Componente: 0.05 m2; EI-GRA-Granito cinza Andorinha (Bancadas, bancos e prateleiras) 2, Volume Componente (Líquido): 0.001 m3; EI-GRA-Granito cinza Andorinha (Bancadas, bancos e prateleiras) 2, Volume do componente (Bruto): 0.001 m3; EI-GRA-Granito cinza Andorinha (Bancadas, bancos e prateleiras) 3, Massa: 0.5488 kg; EI-GRA-Granito cinza Andorinha (Bancadas, bancos e prateleiras) 3, Área de Seção Transversal do Componente: 0.0098 m2; EI-GRA-Granito cinza Andorinha (Bancadas, bancos e prateleiras) 3, Volume Componente (Líquido): 0.000196 m3; EI-GRA-Granito cinza Andorinha (Bancadas, bancos e prateleiras) 3, Volume do componente (Bruto): 0.000196 m3; EI-GRA-Granito cinza Andorinha (Bancadas, bancos e prateleiras) 4, Massa: 8.73167 kg; EI-GRA-Granito cinza Andorinha (Bancadas, bancos e prateleiras) 4, Altura do Componente Retangular: 0.1 m; EI-GRA-Granito cinza Andorinha (Bancadas, bancos e prateleiras) 4, Largura do Componente Retangular: 0.02 m; EI-GRA-Granito cinza Andorinha (Bancadas, bancos e prateleiras) 4, Área de Seção Transversal do Componente: 0.002 m2; EI-GRA-Granito cinza Andorinha (Bancadas, bancos e prateleiras) 4, Volume Componente (Líquido): 0.00311845 m3; EI-GRA-Granito cinza Andorinha (Bancadas, bancos e prateleiras) 4, Volume do componente (Bruto): 0.00311845 m3; EI-GRA-Granito cinza Andorinha (Bancadas, bancos e prateleiras) 5, Massa: 32.3748 kg; EI-GRA-Granito cinza Andorinha (Bancadas, bancos e prateleiras) 5, Área de Seção Transversal do Componente: 0.0098 m2; EI-GRA-Granito cinza Andorinha (Bancadas, bancos e prateleiras) 5, Volume Componente (Líquido): 0.0115624 m3; EI-GRA-Granito cinza Andorinha (Bancadas, bancos e prateleiras) 5, Volume do componente (Bruto): 0.0152804 m3; EI-GRA-Granito cinza Andorinha (Bancadas, bancos e prateleiras) 6, Massa: 3.49267 kg; EI-GRA-Granito cinza Andorinha (Bancadas, bancos e prateleiras) 6, Área de Seção Transversal do Componente: 0.0008 m2; EI-GRA-Granito cinza Andorinha (Bancadas, bancos e prateleiras) 6, Volume Componente (Líquido): 0.00124738 m3; EI-GRA-Granito cinza Andorinha (Bancadas, bancos e prateleiras) 6, Volume do componente (Bruto): 0.00124738 m3; EI-GRA-Granito cinza Andorinha (Bancadas, bancos e prateleiras) 1: 2 with these values; EI-GRA-Granito cinza Andorinha (Bancadas, bancos e prateleiras) 2: 2 with these values; EI-GRA-Granito cinza Andorinha (Bancadas, bancos e prateleiras) 3: 2 with these values

# IfcFurniture: Várias Estruturas- 3 Segmentos - 500 x 150 x 1800 (20+1760+20), B15
In: TÉRREO
Classification: Mobiliário (Classificação Archicad); Material: EI-GRA-Granito cinza Andorinha (Bancadas, bancos e prateleiras) (9)
FNDE - Pedras: BANCADA - GRANITO CINZA ANDORINHA - esp. 2 cm; 1_Bloco: BLOCO A; 0_ID: B15
Component Quantities - EI-GRA-Granito cinza Andorinha (Bancadas, bancos e prateleiras) 1, Massa: 0.0448 kg; EI-GRA-Granito cinza Andorinha (Bancadas, bancos e prateleiras) 1, Área de Seção Transversal do Componente: 0.0008 m2; EI-GRA-Granito cinza Andorinha (Bancadas, bancos e prateleiras) 1, Volume Componente (Líquido): 0.000016 m3; EI-GRA-Granito cinza Andorinha (Bancadas, bancos e prateleiras) 1, Volume do componente (Bruto): 0.000016 m3; EI-GRA-Granito cinza Andorinha (Bancadas, bancos e prateleiras) 2, Massa: 2.8 kg; EI-GRA-Granito cinza Andorinha (Bancadas, bancos e prateleiras) 2, Altura do Componente Retangular: 0.1 m; EI-GRA-Granito cinza Andorinha (Bancadas, bancos e prateleiras) 2, Largura do Componente Retangular: 0.5 m; EI-GRA-Granito cinza Andorinha (Bancadas, bancos e prateleiras) 2, Área de Seção Transversal do Componente: 0.05 m2; EI-GRA-Granito cinza Andorinha (Bancadas, bancos e prateleiras) 2, Volume Componente (Líquido): 0.001 m3; EI-GRA-Granito cinza Andorinha (Bancadas, bancos e prateleiras) 2, Volume do componente (Bruto): 0.001 m3; EI-GRA-Granito cinza Andorinha (Bancadas, bancos e prateleiras) 3, Massa: 0.5488 kg; EI-GRA-Granito cinza Andorinha (Bancadas, bancos e prateleiras) 3, Área de Seção Transversal do Componente: 0.0098 m2; EI-GRA-Granito cinza Andorinha (Bancadas, bancos e prateleiras) 3, Volume Componente (Líquido): 0.000196 m3; EI-GRA-Granito cinza Andorinha (Bancadas, bancos e prateleiras) 3, Volume do componente (Bruto): 0.000196 m3; EI-GRA-Granito cinza Andorinha (Bancadas, bancos e prateleiras) 4, Massa: 9.85552 kg; EI-GRA-Granito cinza Andorinha (Bancadas, bancos e prateleiras) 4, Altura do Componente Retangular: 0.1 m; EI-GRA-Granito cinza Andorinha (Bancadas, bancos e prateleiras) 4, Largura do Componente Retangular: 0.02 m; EI-GRA-Granito cinza Andorinha (Bancadas, bancos e prateleiras) 4, Área de Seção Transversal do Componente: 0.002 m2; EI-GRA-Granito cinza Andorinha (Bancadas, bancos e prateleiras) 4, Volume Componente (Líquido): 0.00351983 m3; EI-GRA-Granito cinza Andorinha (Bancadas, bancos e prateleiras) 4, Volume do componente (Bruto): 0.00351983 m3; EI-GRA-Granito cinza Andorinha (Bancadas, bancos e prateleiras) 5, Massa: 43.0869 kg; EI-GRA-Granito cinza Andorinha (Bancadas, bancos e prateleiras) 5, Área de Seção Transversal do Componente: 0.0098 m2; EI-GRA-Granito cinza Andorinha (Bancadas, bancos e prateleiras) 5, Volume Componente (Líquido): 0.0153882 m3; EI-GRA-Granito cinza Andorinha (Bancadas, bancos e prateleiras) 5, Volume do componente (Bruto): 0.0172472 m3; EI-GRA-Granito cinza Andorinha (Bancadas, bancos e prateleiras) 6, Massa: 3.94221 kg; EI-GRA-Granito cinza Andorinha (Bancadas, bancos e prateleiras) 6, Área de Seção Transversal do Componente: 0.0008 m2; EI-GRA-Granito cinza Andorinha (Bancadas, bancos e prateleiras) 6, Volume Componente (Líquido): 0.00140793 m3; EI-GRA-Granito cinza Andorinha (Bancadas, bancos e prateleiras) 6, Volume do componente (Bruto): 0.00140793 m3; EI-GRA-Granito cinza Andorinha (Bancadas, bancos e prateleiras) 1: 2 with these values; EI-GRA-Granito cinza Andorinha (Bancadas, bancos e prateleiras) 2: 2 with these values; EI-GRA-Granito cinza Andorinha (Bancadas, bancos e prateleiras) 3: 2 with these values

# IfcFurniture: Várias Estruturas- 3 Segmentos - 500 x 150 x 2500 (20+2460+20), B01
In: TÉRREO
Classification: Mobiliário (Classificação Archicad); Material: EI-GRA-Granito cinza Andorinha (Bancadas, bancos e prateleiras) (9)
FNDE - Pedras: BANCADA - GRANITO CINZA ANDORINHA - esp. 2 cm; 1_Bloco: BLOCO A; 0_ID: B01
Component Quantities - EI-GRA-Granito cinza Andorinha (Bancadas, bancos e prateleiras) 1, Massa: 0.0448 kg; EI-GRA-Granito cinza Andorinha (Bancadas, bancos e prateleiras) 1, Área de Seção Transversal do Componente: 0.0008 m2; EI-GRA-Granito cinza Andorinha (Bancadas, bancos e prateleiras) 1, Volume Componente (Líquido): 0.000016 m3; EI-GRA-Granito cinza Andorinha (Bancadas, bancos e prateleiras) 1, Volume do componente (Bruto): 0.000016 m3; EI-GRA-Granito cinza Andorinha (Bancadas, bancos e prateleiras) 2, Massa: 2.8 kg; EI-GRA-Granito cinza Andorinha (Bancadas, bancos e prateleiras) 2, Altura do Componente Retangular: 0.1 m; EI-GRA-Granito cinza Andorinha (Bancadas, bancos e prateleiras) 2, Largura do Componente Retangular: 0.5 m; EI-GRA-Granito cinza Andorinha (Bancadas, bancos e prateleiras) 2, Área de Seção Transversal do Componente: 0.05 m2; EI-GRA-Granito cinza Andorinha (Bancadas, bancos e prateleiras) 2, Volume Componente (Líquido): 0.001 m3; EI-GRA-Granito cinza Andorinha (Bancadas, bancos e prateleiras) 2, Volume do componente (Bruto): 0.001 m3; EI-GRA-Granito cinza Andorinha (Bancadas, bancos e prateleiras) 3, Massa: 0.5488 kg; EI-GRA-Granito cinza Andorinha (Bancadas, bancos e prateleiras) 3, Área de Seção Transversal do Componente: 0.0098 m2; EI-GRA-Granito cinza Andorinha (Bancadas, bancos e prateleiras) 3, Volume Componente (Líquido): 0.000196 m3; EI-GRA-Granito cinza Andorinha (Bancadas, bancos e prateleiras) 3, Volume do componente (Bruto): 0.000196 m3; EI-GRA-Granito cinza Andorinha (Bancadas, bancos e prateleiras) 4, Massa: 13.776 kg; EI-GRA-Granito cinza Andorinha (Bancadas, bancos e prateleiras) 4, Altura do Componente Retangular: 0.1 m; EI-GRA-Granito cinza Andorinha (Bancadas, bancos e prateleiras) 4, Largura do Componente Retangular: 0.02 m; EI-GRA-Granito cinza Andorinha (Bancadas, bancos e prateleiras) 4, Área de Seção Transversal do Componente: 0.002 m2; EI-GRA-Granito cinza Andorinha (Bancadas, bancos e prateleiras) 4, Volume Componente (Líquido): 0.00492 m3; EI-GRA-Granito cinza Andorinha (Bancadas, bancos e prateleiras) 4, Volume do componente (Bruto): 0.00492 m3; EI-GRA-Granito cinza Andorinha (Bancadas, bancos e prateleiras) 5, Massa: 62.2972 kg; EI-GRA-Granito cinza Andorinha (Bancadas, bancos e prateleiras) 5, Área de Seção Transversal do Componente: 0.0098 m2; EI-GRA-Granito cinza Andorinha (Bancadas, bancos e prateleiras) 5, Volume Componente (Líquido): 0.022249 m3; EI-GRA-Granito cinza Andorinha (Bancadas, bancos e prateleiras) 5, Volume do componente (Bruto): 0.024108 m3; EI-GRA-Granito cinza Andorinha (Bancadas, bancos e prateleiras) 6, Massa: 5.5104 kg; EI-GRA-Granito cinza Andorinha (Bancadas, bancos e prateleiras) 6, Área de Seção Transversal do Componente: 0.0008 m2; EI-GRA-Granito cinza Andorinha (Bancadas, bancos e prateleiras) 6, Volume Componente (Líquido): 0.001968 m3; EI-GRA-Granito cinza Andorinha (Bancadas, bancos e prateleiras) 6, Volume do componente (Bruto): 0.001968 m3; EI-GRA-Granito cinza Andorinha (Bancadas, bancos e prateleiras) 1: 2 with these values; EI-GRA-Granito cinza Andorinha (Bancadas, bancos e prateleiras) 2: 2 with these values; EI-GRA-Granito cinza Andorinha (Bancadas, bancos e prateleiras) 3: 2 with these values

# IfcFurniture: Várias Estruturas- 3 Segmentos - 500 x 150 x 899 (20+859+20) (2)
In: TÉRREO
Classification: Mobiliário (Classificação Archicad); Material: EI-GRA-Granito cinza Andorinha (Bancadas, bancos e prateleiras) (9)
FNDE - Pedras: BANCADA - GRANITO CINZA ANDORINHA - esp. 2 cm; 1_Bloco: BLOCO A
Component Quantities - EI-GRA-Granito cinza Andorinha (Bancadas, bancos e prateleiras) 1, Massa: 0.0448 kg; EI-GRA-Granito cinza Andorinha (Bancadas, bancos e prateleiras) 1, Área de Seção Transversal do Componente: 0.0008 m2; EI-GRA-Granito cinza Andorinha (Bancadas, bancos e prateleiras) 1, Volume Componente (Líquido): 0.000016 m3; EI-GRA-Granito cinza Andorinha (Bancadas, bancos e prateleiras) 1, Volume do componente (Bruto): 0.000016 m3; EI-GRA-Granito cinza Andorinha (Bancadas, bancos e prateleiras) 2, Massa: 2.8 kg; EI-GRA-Granito cinza Andorinha (Bancadas, bancos e prateleiras) 2, Altura do Componente Retangular: 0.1 m; EI-GRA-Granito cinza Andorinha (Bancadas, bancos e prateleiras) 2, Largura do Componente Retangular: 0.5 m; EI-GRA-Granito cinza Andorinha (Bancadas, bancos e prateleiras) 2, Área de Seção Transversal do Componente: 0.05 m2; EI-GRA-Granito cinza Andorinha (Bancadas, bancos e prateleiras) 2, Volume Componente (Líquido): 0.001 m3; EI-GRA-Granito cinza Andorinha (Bancadas, bancos e prateleiras) 2, Volume do componente (Bruto): 0.001 m3; EI-GRA-Granito cinza Andorinha (Bancadas, bancos e prateleiras) 3, Massa: 0.5488 kg; EI-GRA-Granito cinza Andorinha (Bancadas, bancos e prateleiras) 3, Área de Seção Transversal do Componente: 0.0098 m2; EI-GRA-Granito cinza Andorinha (Bancadas, bancos e prateleiras) 3, Volume Componente (Líquido): 0.000196 m3; EI-GRA-Granito cinza Andorinha (Bancadas, bancos e prateleiras) 3, Volume do componente (Bruto): 0.000196 m3; EI-GRA-Granito cinza Andorinha (Bancadas, bancos e prateleiras) 4, Massa: 4.80812 kg; EI-GRA-Granito cinza Andorinha (Bancadas, bancos e prateleiras) 4, Altura do Componente Retangular: 0.1 m; EI-GRA-Granito cinza Andorinha (Bancadas, bancos e prateleiras) 4, Largura do Componente Retangular: 0.02 m; EI-GRA-Granito cinza Andorinha (Bancadas, bancos e prateleiras) 4, Área de Seção Transversal do Componente: 0.002 m2; EI-GRA-Granito cinza Andorinha (Bancadas, bancos e prateleiras) 4, Volume Componente (Líquido): 0.00171719 m3; EI-GRA-Granito cinza Andorinha (Bancadas, bancos e prateleiras) 4, Volume do componente (Bruto): 0.00171719 m3; EI-GRA-Granito cinza Andorinha (Bancadas, bancos e prateleiras) 5, Massa: 23.5598 kg; EI-GRA-Granito cinza Andorinha (Bancadas, bancos e prateleiras) 5, Área de Seção Transversal do Componente: 0.0098 m2; EI-GRA-Granito cinza Andorinha (Bancadas, bancos e prateleiras) 5, Volume Componente (Líquido): 0.00841421 m3; EI-GRA-Granito cinza Andorinha (Bancadas, bancos e prateleiras) 5, Volume do componente (Bruto): 0.00841421 m3; EI-GRA-Granito cinza Andorinha (Bancadas, bancos e prateleiras) 6, Massa: 1.92325 kg; EI-GRA-Granito cinza Andorinha (Bancadas, bancos e prateleiras) 6, Área de Seção Transversal do Componente: 0.0008 m2; EI-GRA-Granito cinza Andorinha (Bancadas, bancos e prateleiras) 6, Volume Componente (Líquido): 0.000686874 m3; EI-GRA-Granito cinza Andorinha (Bancadas, bancos e prateleiras) 6, Volume do componente (Bruto): 0.000686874 m3; EI-GRA-Granito cinza Andorinha (Bancadas, bancos e prateleiras) 7, Massa: 0.112 kg; EI-GRA-Granito cinza Andorinha (Bancadas, bancos e prateleiras) 7, Altura do Componente Retangular: 0.1 m; EI-GRA-Granito cinza Andorinha (Bancadas, bancos e prateleiras) 7, Largura do Componente Retangular: 0.02 m; EI-GRA-Granito cinza Andorinha (Bancadas, bancos e prateleiras) 7, Área de Seção Transversal do Componente: 0.002 m2; EI-GRA-Granito cinza Andorinha (Bancadas, bancos e prateleiras) 7, Volume Componente (Líquido): 0.00004 m3; EI-GRA-Granito cinza Andorinha (Bancadas, bancos e prateleiras) 7, Volume do componente (Bruto): 0.00004 m3; EI-GRA-Granito cinza Andorinha (Bancadas, bancos e prateleiras) 8, Massa: 0.56 kg; EI-GRA-Granito cinza Andorinha (Bancadas, bancos e prateleiras) 8, Altura do Componente Retangular: 0.02 m; EI-GRA-Granito cinza Andorinha (Bancadas, bancos e prateleiras) 8, Largura do Componente Retangular: 0.5 m; EI-GRA-Granito cinza Andorinha (Bancadas, bancos e prateleiras) 8, Área de Seção Transversal do Componente: 0.01 m2; EI-GRA-Granito cinza Andorinha (Bancadas, bancos e prateleiras) 8, Volume Componente (Líquido): 0.0002 m3; EI-GRA-Granito cinza Andorinha (Bancadas, bancos e prateleiras) 8, Volume do componente (Bruto): 0.0002 m3; EI-GRA-Granito cinza Andorinha (Bancadas, bancos e prateleiras) 9, Massa: 0.84 kg; EI-GRA-Granito cinza Andorinha (Bancadas, bancos e prateleiras) 9, Altura do Componente Retangular: 0.03 m; EI-GRA-Granito cinza Andorinha (Bancadas, bancos e prateleiras) 9, Largura do Componente Retangular: 0.5 m; EI-GRA-Granito cinza Andorinha (Bancadas, bancos e prateleiras) 9, Área de Seção Transversal do Componente: 0.015 m2; EI-GRA-Granito cinza Andorinha (Bancadas, bancos e prateleiras) 9, Volume Componente (Líquido): 0.0003 m3; EI-GRA-Granito cinza Andorinha (Bancadas, bancos e prateleiras) 9, Volume do componente (Bruto): 0.0003 m3
Name | 0_ID
B04 | B04
B03 | B03

# IfcFurniture: Várias Estruturas- 3 Segmentos - 550 x 150 x 950 (20+910+20) (2)
In: TÉRREO
Classification: Mobiliário (Classificação Archicad); Material: EI-GRA-Granito cinza Andorinha (Bancadas, bancos e prateleiras) (9)
FNDE - Pedras: BANCADA - GRANITO CINZA ANDORINHA - esp. 2 cm; 1_Bloco: BLOCO B; 0_ID: B20
Component Quantities - EI-GRA-Granito cinza Andorinha (Bancadas, bancos e prateleiras) 1, Massa: 0.1232 kg; EI-GRA-Granito cinza Andorinha (Bancadas, bancos e prateleiras) 1, Altura do Componente Retangular: 0.1 m; EI-GRA-Granito cinza Andorinha (Bancadas, bancos e prateleiras) 1, Largura do Componente Retangular: 0.0220001 m; EI-GRA-Granito cinza Andorinha (Bancadas, bancos e prateleiras) 1, Área de Seção Transversal do Componente: 0.00220001 m2; EI-GRA-Granito cinza Andorinha (Bancadas, bancos e prateleiras) 1, Volume Componente (Líquido): 0.0000440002 m3; EI-GRA-Granito cinza Andorinha (Bancadas, bancos e prateleiras) 1, Volume do componente (Bruto): 0.0000440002 m3; EI-GRA-Granito cinza Andorinha (Bancadas, bancos e prateleiras) 2, Massa: 0.616002 kg; EI-GRA-Granito cinza Andorinha (Bancadas, bancos e prateleiras) 2, Altura do Componente Retangular: 0.02 m; EI-GRA-Granito cinza Andorinha (Bancadas, bancos e prateleiras) 2, Largura do Componente Retangular: 0.550002 m; EI-GRA-Granito cinza Andorinha (Bancadas, bancos e prateleiras) 2, Área de Seção Transversal do Componente: 0.011 m2; EI-GRA-Granito cinza Andorinha (Bancadas, bancos e prateleiras) 2, Volume Componente (Líquido): 0.000220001 m3; EI-GRA-Granito cinza Andorinha (Bancadas, bancos e prateleiras) 2, Volume do componente (Bruto): 0.000220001 m3; EI-GRA-Granito cinza Andorinha (Bancadas, bancos e prateleiras) 3, Massa: 0.924004 kg; EI-GRA-Granito cinza Andorinha (Bancadas, bancos e prateleiras) 3, Altura do Componente Retangular: 0.03 m; EI-GRA-Granito cinza Andorinha (Bancadas, bancos e prateleiras) 3, Largura do Componente Retangular: 0.550002 m; EI-GRA-Granito cinza Andorinha (Bancadas, bancos e prateleiras) 3, Área de Seção Transversal do Componente: 0.0165001 m2; EI-GRA-Granito cinza Andorinha (Bancadas, bancos e prateleiras) 3, Volume Componente (Líquido): 0.000330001 m3; EI-GRA-Granito cinza Andorinha (Bancadas, bancos e prateleiras) 3, Volume do componente (Bruto): 0.000330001 m3; EI-GRA-Granito cinza Andorinha (Bancadas, bancos e prateleiras) 4, Massa: 6.16596 kg; EI-GRA-Granito cinza Andorinha (Bancadas, bancos e prateleiras) 4, Altura do Componente Retangular: 0.11 m; EI-GRA-Granito cinza Andorinha (Bancadas, bancos e prateleiras) 4, Largura do Componente Retangular: 0.0220001 m; EI-GRA-Granito cinza Andorinha (Bancadas, bancos e prateleiras) 4, Área de Seção Transversal do Componente: 0.00242001 m2; EI-GRA-Granito cinza Andorinha (Bancadas, bancos e prateleiras) 4, Volume Componente (Líquido): 0.00220213 m3; EI-GRA-Granito cinza Andorinha (Bancadas, bancos e prateleiras) 4, Volume do componente (Bruto): 0.00220213 m3; EI-GRA-Granito cinza Andorinha (Bancadas, bancos e prateleiras) 5, Altura do Componente Retangular: 0.02 m; EI-GRA-Granito cinza Andorinha (Bancadas, bancos e prateleiras) 5, Largura do Componente Retangular: 0.528002 m; EI-GRA-Granito cinza Andorinha (Bancadas, bancos e prateleiras) 5, Área de Seção Transversal do Componente: 0.01056 m2; EI-GRA-Granito cinza Andorinha (Bancadas, bancos e prateleiras) 5, Volume do componente (Bruto): 0.0091893 m3; EI-GRA-Granito cinza Andorinha (Bancadas, bancos e prateleiras) 6, Massa: 2.80271 kg; EI-GRA-Granito cinza Andorinha (Bancadas, bancos e prateleiras) 6, Altura do Componente Retangular: 0.05 m; EI-GRA-Granito cinza Andorinha (Bancadas, bancos e prateleiras) 6, Largura do Componente Retangular: 0.0220001 m; EI-GRA-Granito cinza Andorinha (Bancadas, bancos e prateleiras) 6, Área de Seção Transversal do Componente: 0.0011 m2; EI-GRA-Granito cinza Andorinha (Bancadas, bancos e prateleiras) 6, Volume Componente (Líquido): 0.00100097 m3; EI-GRA-Granito cinza Andorinha (Bancadas, bancos e prateleiras) 6, Volume do componente (Bruto): 0.00100097 m3; EI-GRA-Granito cinza Andorinha (Bancadas, bancos e prateleiras) 7, Massa: 3.38801 kg; EI-GRA-Granito cinza Andorinha (Bancadas, bancos e prateleiras) 7, Altura do Componente Retangular: 0.11 m; EI-GRA-Granito cinza Andorinha (Bancadas, bancos e prateleiras) 7, Largura do Componente Retangular: 0.550002 m; EI-GRA-Granito cinza Andorinha (Bancadas, bancos e prateleiras) 7, Área de Seção Transversal do Componente: 0.0605002 m2; EI-GRA-Granito cinza Andorinha (Bancadas, bancos e prateleiras) 7, Volume Componente (Líquido): 0.00121 m3; EI-GRA-Granito cinza Andorinha (Bancadas, bancos e prateleiras) 7, Volume do componente (Bruto): 0.00121 m3; EI-GRA-Granito cinza Andorinha (Bancadas, bancos e prateleiras) 8, Massa: 0.591362 kg; EI-GRA-Granito cinza Andorinha (Bancadas, bancos e prateleiras) 8, Altura do Componente Retangular: 0.02 m; EI-GRA-Granito cinza Andorinha (Bancadas, bancos e prateleiras) 8, Largura do Componente Retangular: 0.528002 m; EI-GRA-Granito cinza Andorinha (Bancadas, bancos e prateleiras) 8, Área de Seção Transversal do Componente: 0.01056 m2; EI-GRA-Granito cinza Andorinha (Bancadas, bancos e prateleiras) 8, Volume Componente (Líquido): 0.000211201 m3; EI-GRA-Granito cinza Andorinha (Bancadas, bancos e prateleiras) 8, Volume do componente (Bruto): 0.000211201 m3; EI-GRA-Granito cinza Andorinha (Bancadas, bancos e prateleiras) 9, Massa: 0.0492802 kg; EI-GRA-Granito cinza Andorinha (Bancadas, bancos e prateleiras) 9, Altura do Componente Retangular: 0.04 m; EI-GRA-Granito cinza Andorinha (Bancadas, bancos e prateleiras) 9, Largura do Componente Retangular: 0.0220001 m; EI-GRA-Granito cinza Andorinha (Bancadas, bancos e prateleiras) 9, Área de Seção Transversal do Componente: 0.000880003 m2; EI-GRA-Granito cinza Andorinha (Bancadas, bancos e prateleiras) 9, Volume Componente (Líquido): 0.0000176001 m3; EI-GRA-Granito cinza Andorinha (Bancadas, bancos e prateleiras) 9, Volume do componente (Bruto): 0.0000176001 m3
Name | EI-GRA-Granito cinza Andorinha (Bancadas, bancos e prateleiras) 5, Massa (kg) | EI-GRA-Granito cinza Andorinha (Bancadas, bancos e prateleiras) 5, Volume Componente (Líquido) (m3)
B20 | 18.3032 | 0.00653687
B20 | 18.3033 | 0.00653688

# IfcFurniture: Várias Estruturas- 3 Segmentos - 600 x 150 x 3400 (20+3360+20), B06
In: TÉRREO
Classification: Mobiliário (Classificação Archicad); Material: EI-GRA-Granito cinza Andorinha (Bancadas, bancos e prateleiras) (9)
FNDE - Pedras: BANCADA - GRANITO CINZA ANDORINHA - esp. 2 cm; 1_Bloco: BLOCO A; 0_ID: B06
Component Quantities - EI-GRA-Granito cinza Andorinha (Bancadas, bancos e prateleiras) 1, Massa: 0.1344 kg; EI-GRA-Granito cinza Andorinha (Bancadas, bancos e prateleiras) 1, Altura do Componente Retangular: 0.1 m; EI-GRA-Granito cinza Andorinha (Bancadas, bancos e prateleiras) 1, Largura do Componente Retangular: 0.024 m; EI-GRA-Granito cinza Andorinha (Bancadas, bancos e prateleiras) 1, Área de Seção Transversal do Componente: 0.0024 m2; EI-GRA-Granito cinza Andorinha (Bancadas, bancos e prateleiras) 1, Volume Componente (Líquido): 0.000048 m3; EI-GRA-Granito cinza Andorinha (Bancadas, bancos e prateleiras) 1, Volume do componente (Bruto): 0.000048 m3; EI-GRA-Granito cinza Andorinha (Bancadas, bancos e prateleiras) 2, Massa: 0.672 kg; EI-GRA-Granito cinza Andorinha (Bancadas, bancos e prateleiras) 2, Altura do Componente Retangular: 0.02 m; EI-GRA-Granito cinza Andorinha (Bancadas, bancos e prateleiras) 2, Largura do Componente Retangular: 0.6 m; EI-GRA-Granito cinza Andorinha (Bancadas, bancos e prateleiras) 2, Área de Seção Transversal do Componente: 0.012 m2; EI-GRA-Granito cinza Andorinha (Bancadas, bancos e prateleiras) 2, Volume Componente (Líquido): 0.00024 m3; EI-GRA-Granito cinza Andorinha (Bancadas, bancos e prateleiras) 2, Volume do componente (Bruto): 0.00024 m3; EI-GRA-Granito cinza Andorinha (Bancadas, bancos e prateleiras) 3, Massa: 1.008 kg; EI-GRA-Granito cinza Andorinha (Bancadas, bancos e prateleiras) 3, Altura do Componente Retangular: 0.03 m; EI-GRA-Granito cinza Andorinha (Bancadas, bancos e prateleiras) 3, Largura do Componente Retangular: 0.6 m; EI-GRA-Granito cinza Andorinha (Bancadas, bancos e prateleiras) 3, Área de Seção Transversal do Componente: 0.018 m2; EI-GRA-Granito cinza Andorinha (Bancadas, bancos e prateleiras) 3, Volume Componente (Líquido): 0.00036 m3; EI-GRA-Granito cinza Andorinha (Bancadas, bancos e prateleiras) 3, Volume do componente (Bruto): 0.00036 m3; EI-GRA-Granito cinza Andorinha (Bancadas, bancos e prateleiras) 4, Massa: 24.8371 kg; EI-GRA-Granito cinza Andorinha (Bancadas, bancos e prateleiras) 4, Altura do Componente Retangular: 0.11 m; EI-GRA-Granito cinza Andorinha (Bancadas, bancos e prateleiras) 4, Largura do Componente Retangular: 0.024 m; EI-GRA-Granito cinza Andorinha (Bancadas, bancos e prateleiras) 4, Área de Seção Transversal do Componente: 0.00264 m2; EI-GRA-Granito cinza Andorinha (Bancadas, bancos e prateleiras) 4, Volume Componente (Líquido): 0.0088704 m3; EI-GRA-Granito cinza Andorinha (Bancadas, bancos e prateleiras) 4, Volume do componente (Bruto): 0.0088704 m3; EI-GRA-Granito cinza Andorinha (Bancadas, bancos e prateleiras) 5, Massa: 94.467 kg; EI-GRA-Granito cinza Andorinha (Bancadas, bancos e prateleiras) 5, Altura do Componente Retangular: 0.02 m; EI-GRA-Granito cinza Andorinha (Bancadas, bancos e prateleiras) 5, Largura do Componente Retangular: 0.576 m; EI-GRA-Granito cinza Andorinha (Bancadas, bancos e prateleiras) 5, Área de Seção Transversal do Componente: 0.01152 m2; EI-GRA-Granito cinza Andorinha (Bancadas, bancos e prateleiras) 5, Volume Componente (Líquido): 0.0337382 m3; EI-GRA-Granito cinza Andorinha (Bancadas, bancos e prateleiras) 5, Volume do componente (Bruto): 0.0376706 m3; EI-GRA-Granito cinza Andorinha (Bancadas, bancos e prateleiras) 6, Massa: 11.2896 kg; EI-GRA-Granito cinza Andorinha (Bancadas, bancos e prateleiras) 6, Altura do Componente Retangular: 0.05 m; EI-GRA-Granito cinza Andorinha (Bancadas, bancos e prateleiras) 6, Largura do Componente Retangular: 0.024 m; EI-GRA-Granito cinza Andorinha (Bancadas, bancos e prateleiras) 6, Área de Seção Transversal do Componente: 0.0012 m2; EI-GRA-Granito cinza Andorinha (Bancadas, bancos e prateleiras) 6, Volume Componente (Líquido): 0.004032 m3; EI-GRA-Granito cinza Andorinha (Bancadas, bancos e prateleiras) 6, Volume do componente (Bruto): 0.004032 m3; EI-GRA-Granito cinza Andorinha (Bancadas, bancos e prateleiras) 7, Massa: 3.696 kg; EI-GRA-Granito cinza Andorinha (Bancadas, bancos e prateleiras) 7, Altura do Componente Retangular: 0.11 m; EI-GRA-Granito cinza Andorinha (Bancadas, bancos e prateleiras) 7, Largura do Componente Retangular: 0.6 m; EI-GRA-Granito cinza Andorinha (Bancadas, bancos e prateleiras) 7, Área de Seção Transversal do Componente: 0.066 m2; EI-GRA-Granito cinza Andorinha (Bancadas, bancos e prateleiras) 7, Volume Componente (Líquido): 0.00132 m3; EI-GRA-Granito cinza Andorinha (Bancadas, bancos e prateleiras) 7, Volume do componente (Bruto): 0.00132 m3; EI-GRA-Granito cinza Andorinha (Bancadas, bancos e prateleiras) 8, Massa: 0.64512 kg; EI-GRA-Granito cinza Andorinha (Bancadas, bancos e prateleiras) 8, Altura do Componente Retangular: 0.02 m; EI-GRA-Granito cinza Andorinha (Bancadas, bancos e prateleiras) 8, Largura do Componente Retangular: 0.576 m; EI-GRA-Granito cinza Andorinha (Bancadas, bancos e prateleiras) 8, Área de Seção Transversal do Componente: 0.01152 m2; EI-GRA-Granito cinza Andorinha (Bancadas, bancos e prateleiras) 8, Volume Componente (Líquido): 0.0002304 m3; EI-GRA-Granito cinza Andorinha (Bancadas, bancos e prateleiras) 8, Volume do componente (Bruto): 0.0002304 m3; EI-GRA-Granito cinza Andorinha (Bancadas, bancos e prateleiras) 9, Massa: 0.05376 kg; EI-GRA-Granito cinza Andorinha (Bancadas, bancos e prateleiras) 9, Altura do Componente Retangular: 0.04 m; EI-GRA-Granito cinza Andorinha (Bancadas, bancos e prateleiras) 9, Largura do Componente Retangular: 0.024 m; EI-GRA-Granito cinza Andorinha (Bancadas, bancos e prateleiras) 9, Área de Seção Transversal do Componente: 0.00096 m2; EI-GRA-Granito cinza Andorinha (Bancadas, bancos e prateleiras) 9, Volume Componente (Líquido): 0.0000192 m3; EI-GRA-Granito cinza Andorinha (Bancadas, bancos e prateleiras) 9, Volume do componente (Bruto): 0.0000192 m3

# IfcFurniture: Várias Estruturas- 3 Segmentos - 750 x 200 x 1440 (20+1400+20), B10
In: TÉRREO
Classification: Mobiliário (Classificação Archicad); Material: EI-GRA-Granito cinza Andorinha (Bancadas, bancos e prateleiras) (6)
FNDE - Pedras: BANCADA - GRANITO CINZA ANDORINHA - esp. 2 cm; 1_Bloco: BLOCO A; 0_ID: B10
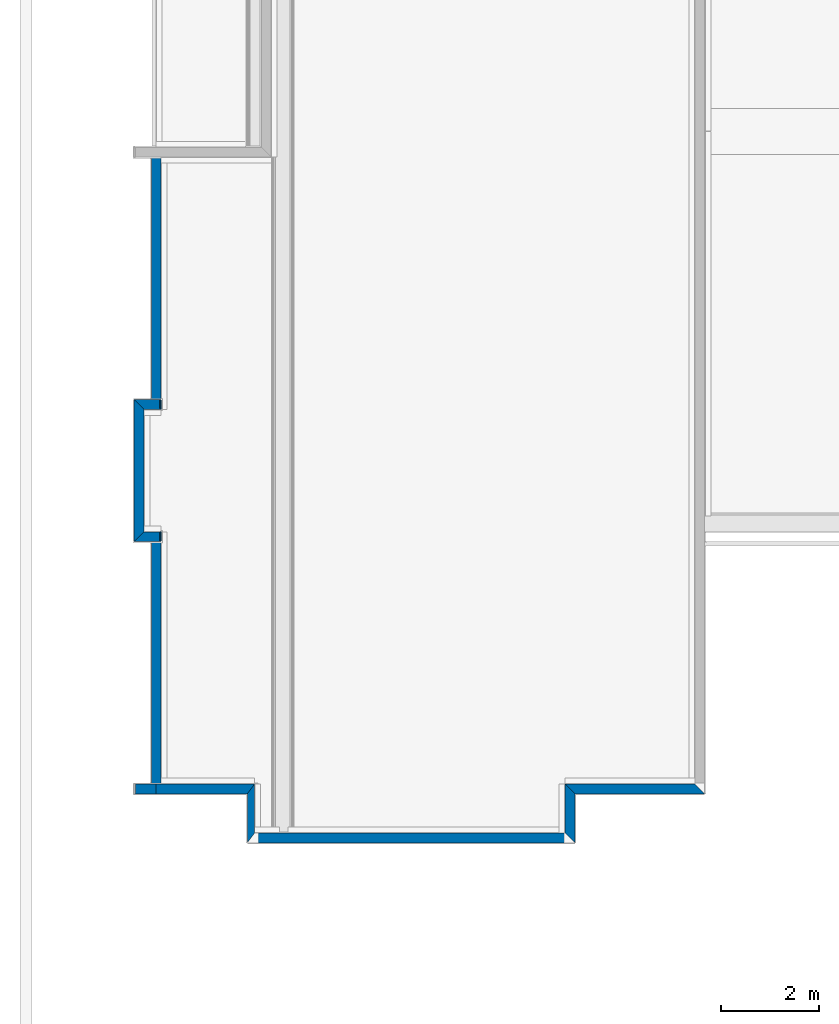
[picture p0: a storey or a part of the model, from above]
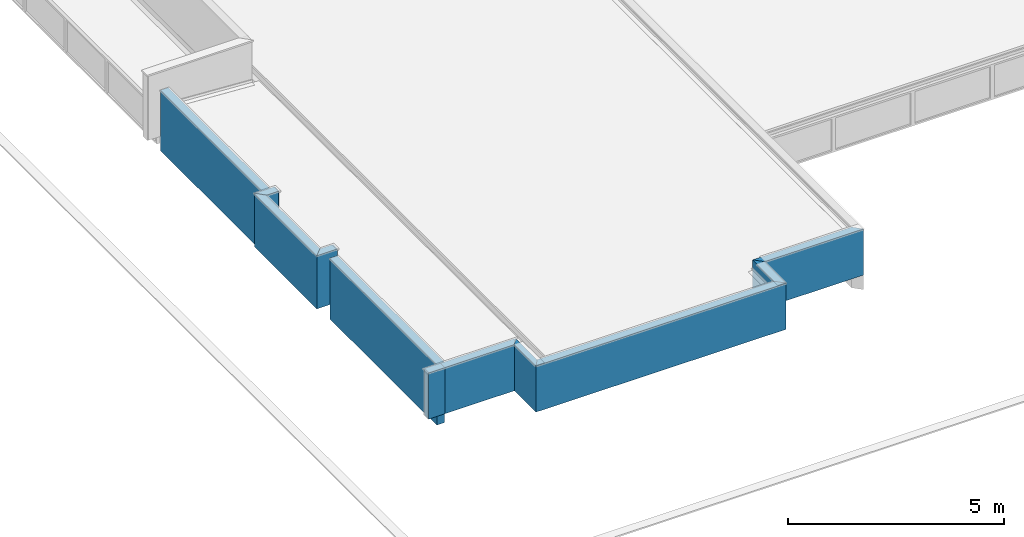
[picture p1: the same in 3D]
Properties of the parts of a building model (IFC4), part 5 of 22

# IfcFurniture: Várias Estruturas- 3 Segmentos - 750 x 200 x 1440 (20+1400+20), B10
Component Quantities - EI-GRA-Granito cinza Andorinha (Bancadas, bancos e prateleiras) 1, Massa: 4.7264 kg; EI-GRA-Granito cinza Andorinha (Bancadas, bancos e prateleiras) 1, Altura do Componente Retangular: 0.17 m; EI-GRA-Granito cinza Andorinha (Bancadas, bancos e prateleiras) 1, Largura do Componente Retangular: 0.5 m; EI-GRA-Granito cinza Andorinha (Bancadas, bancos e prateleiras) 1, Área de Seção Transversal do Componente: 0.085 m2; EI-GRA-Granito cinza Andorinha (Bancadas, bancos e prateleiras) 1, Volume Componente (Líquido): 0.001688 m3; EI-GRA-Granito cinza Andorinha (Bancadas, bancos e prateleiras) 1, Volume do componente (Bruto): 0.001688 m3; EI-GRA-Granito cinza Andorinha (Bancadas, bancos e prateleiras) 2, Massa: 0.84 kg; EI-GRA-Granito cinza Andorinha (Bancadas, bancos e prateleiras) 2, Altura do Componente Retangular: 0.03 m; EI-GRA-Granito cinza Andorinha (Bancadas, bancos e prateleiras) 2, Largura do Componente Retangular: 0.5 m; EI-GRA-Granito cinza Andorinha (Bancadas, bancos e prateleiras) 2, Área de Seção Transversal do Componente: 0.015 m2; EI-GRA-Granito cinza Andorinha (Bancadas, bancos e prateleiras) 2, Volume Componente (Líquido): 0.0003 m3; EI-GRA-Granito cinza Andorinha (Bancadas, bancos e prateleiras) 2, Volume do componente (Bruto): 0.0003 m3; EI-GRA-Granito cinza Andorinha (Bancadas, bancos e prateleiras) 3, Massa: 50.96 kg; EI-GRA-Granito cinza Andorinha (Bancadas, bancos e prateleiras) 3, Área de Seção Transversal do Componente: 0.0148 m2; EI-GRA-Granito cinza Andorinha (Bancadas, bancos e prateleiras) 3, Volume Componente (Líquido): 0.0182 m3; EI-GRA-Granito cinza Andorinha (Bancadas, bancos e prateleiras) 3, Volume do componente (Bruto): 0.0182 m3; EI-GRA-Granito cinza Andorinha (Bancadas, bancos e prateleiras) 4, Massa: 3.136 kg; EI-GRA-Granito cinza Andorinha (Bancadas, bancos e prateleiras) 4, Área de Seção Transversal do Componente: 0.0008 m2; EI-GRA-Granito cinza Andorinha (Bancadas, bancos e prateleiras) 4, Volume Componente (Líquido): 0.00112 m3; EI-GRA-Granito cinza Andorinha (Bancadas, bancos e prateleiras) 4, Volume do componente (Bruto): 0.00112 m3; EI-GRA-Granito cinza Andorinha (Bancadas, bancos e prateleiras) 1: 2 with these values; EI-GRA-Granito cinza Andorinha (Bancadas, bancos e prateleiras) 2: 2 with these values

# IfcFurniture: Várias Estruturas- 4 Segmentos - 600 x 150 x 2300 (20+1060+1200+20), B16
In: TÉRREO
Classification: Mobiliário (Classificação Archicad); Material: EI-GRA-Granito cinza Andorinha (Bancadas, bancos e prateleiras) (11)
FNDE - Pedras: BANCADA - GRANITO CINZA ANDORINHA - esp. 2 cm; 1_Bloco: BLOCO A; 0_ID: B16
Component Quantities - EI-GRA-Granito cinza Andorinha (Bancadas, bancos e prateleiras) 1, Massa: 0.056 kg; EI-GRA-Granito cinza Andorinha (Bancadas, bancos e prateleiras) 1, Altura do Componente Retangular: 0.1 m; EI-GRA-Granito cinza Andorinha (Bancadas, bancos e prateleiras) 1, Largura do Componente Retangular: 0.024 m; EI-GRA-Granito cinza Andorinha (Bancadas, bancos e prateleiras) 1, Área de Seção Transversal do Componente: 0.0024 m2; EI-GRA-Granito cinza Andorinha (Bancadas, bancos e prateleiras) 1, Volume Componente (Líquido): 0.00002 m3; EI-GRA-Granito cinza Andorinha (Bancadas, bancos e prateleiras) 1, Volume do componente (Bruto): 0.00002 m3; EI-GRA-Granito cinza Andorinha (Bancadas, bancos e prateleiras) 2, Massa: 0.0112 kg; EI-GRA-Granito cinza Andorinha (Bancadas, bancos e prateleiras) 2, Altura do Componente Retangular: 0.02 m; EI-GRA-Granito cinza Andorinha (Bancadas, bancos e prateleiras) 2, Largura do Componente Retangular: 0.6 m; EI-GRA-Granito cinza Andorinha (Bancadas, bancos e prateleiras) 2, Área de Seção Transversal do Componente: 0.012 m2; EI-GRA-Granito cinza Andorinha (Bancadas, bancos e prateleiras) 2, Volume Componente (Líquido): 0.000004 m3; EI-GRA-Granito cinza Andorinha (Bancadas, bancos e prateleiras) 2, Volume do componente (Bruto): 0.000004 m3; EI-GRA-Granito cinza Andorinha (Bancadas, bancos e prateleiras) 3, Massa: 0.0168 kg; EI-GRA-Granito cinza Andorinha (Bancadas, bancos e prateleiras) 3, Altura do Componente Retangular: 0.03 m; EI-GRA-Granito cinza Andorinha (Bancadas, bancos e prateleiras) 3, Largura do Componente Retangular: 0.6 m; EI-GRA-Granito cinza Andorinha (Bancadas, bancos e prateleiras) 3, Área de Seção Transversal do Componente: 0.018 m2; EI-GRA-Granito cinza Andorinha (Bancadas, bancos e prateleiras) 3, Volume Componente (Líquido): 0.000006 m3; EI-GRA-Granito cinza Andorinha (Bancadas, bancos e prateleiras) 3, Volume do componente (Bruto): 0.000006 m3; EI-GRA-Granito cinza Andorinha (Bancadas, bancos e prateleiras) 4, Massa: 7.12363 kg; EI-GRA-Granito cinza Andorinha (Bancadas, bancos e prateleiras) 4, Altura do Componente Retangular: 0.1 m; EI-GRA-Granito cinza Andorinha (Bancadas, bancos e prateleiras) 4, Largura do Componente Retangular: 0.024 m; EI-GRA-Granito cinza Andorinha (Bancadas, bancos e prateleiras) 4, Área de Seção Transversal do Componente: 0.0024 m2; EI-GRA-Granito cinza Andorinha (Bancadas, bancos e prateleiras) 4, Volume Componente (Líquido): 0.00254416 m3; EI-GRA-Granito cinza Andorinha (Bancadas, bancos e prateleiras) 4, Volume do componente (Bruto): 0.00254416 m3; EI-GRA-Granito cinza Andorinha (Bancadas, bancos e prateleiras) 5, Massa: 34.9058 kg; EI-GRA-Granito cinza Andorinha (Bancadas, bancos e prateleiras) 5, Área de Seção Transversal do Componente: 0.01176 m2; EI-GRA-Granito cinza Andorinha (Bancadas, bancos e prateleiras) 5, Volume Componente (Líquido): 0.0124664 m3; EI-GRA-Granito cinza Andorinha (Bancadas, bancos e prateleiras) 5, Volume do componente (Bruto): 0.0124664 m3; EI-GRA-Granito cinza Andorinha (Bancadas, bancos e prateleiras) 6, Massa: 2.84945 kg; EI-GRA-Granito cinza Andorinha (Bancadas, bancos e prateleiras) 6, Área de Seção Transversal do Componente: 0.00096 m2; EI-GRA-Granito cinza Andorinha (Bancadas, bancos e prateleiras) 6, Volume Componente (Líquido): 0.00101766 m3; EI-GRA-Granito cinza Andorinha (Bancadas, bancos e prateleiras) 6, Volume do componente (Bruto): 0.00101766 m3; EI-GRA-Granito cinza Andorinha (Bancadas, bancos e prateleiras) 7, Massa: 8.8704 kg; EI-GRA-Granito cinza Andorinha (Bancadas, bancos e prateleiras) 7, Altura do Componente Retangular: 0.11 m; EI-GRA-Granito cinza Andorinha (Bancadas, bancos e prateleiras) 7, Largura do Componente Retangular: 0.024 m; EI-GRA-Granito cinza Andorinha (Bancadas, bancos e prateleiras) 7, Área de Seção Transversal do Componente: 0.00264 m2; EI-GRA-Granito cinza Andorinha (Bancadas, bancos e prateleiras) 7, Volume Componente (Líquido): 0.003168 m3; EI-GRA-Granito cinza Andorinha (Bancadas, bancos e prateleiras) 7, Volume do componente (Bruto): 0.003168 m3; EI-GRA-Granito cinza Andorinha (Bancadas, bancos e prateleiras) 8, Massa: 25.9324 kg; EI-GRA-Granito cinza Andorinha (Bancadas, bancos e prateleiras) 8, Altura do Componente Retangular: 0.02 m; EI-GRA-Granito cinza Andorinha (Bancadas, bancos e prateleiras) 8, Largura do Componente Retangular: 0.576 m; EI-GRA-Granito cinza Andorinha (Bancadas, bancos e prateleiras) 8, Área de Seção Transversal do Componente: 0.01152 m2; EI-GRA-Granito cinza Andorinha (Bancadas, bancos e prateleiras) 8, Volume Componente (Líquido): 0.00926157 m3; EI-GRA-Granito cinza Andorinha (Bancadas, bancos e prateleiras) 8, Volume do componente (Bruto): 0.013194 m3; EI-GRA-Granito cinza Andorinha (Bancadas, bancos e prateleiras) 9, Massa: 4.032 kg; EI-GRA-Granito cinza Andorinha (Bancadas, bancos e prateleiras) 9, Altura do Componente Retangular: 0.05 m; EI-GRA-Granito cinza Andorinha (Bancadas, bancos e prateleiras) 9, Largura do Componente Retangular: 0.024 m; EI-GRA-Granito cinza Andorinha (Bancadas, bancos e prateleiras) 9, Área de Seção Transversal do Componente: 0.0012 m2; EI-GRA-Granito cinza Andorinha (Bancadas, bancos e prateleiras) 9, Volume Componente (Líquido): 0.00144 m3; EI-GRA-Granito cinza Andorinha (Bancadas, bancos e prateleiras) 9, Volume do componente (Bruto): 0.00144 m3; EI-GRA-Granito cinza Andorinha (Bancadas, bancos e prateleiras) 10, Massa: 0.1344 kg; EI-GRA-Granito cinza Andorinha (Bancadas, bancos e prateleiras) 10, Altura do Componente Retangular: 0.1 m; EI-GRA-Granito cinza Andorinha (Bancadas, bancos e prateleiras) 10, Largura do Componente Retangular: 0.024 m; EI-GRA-Granito cinza Andorinha (Bancadas, bancos e prateleiras) 10, Área de Seção Transversal do Componente: 0.0024 m2; EI-GRA-Granito cinza Andorinha (Bancadas, bancos e prateleiras) 10, Volume Componente (Líquido): 0.000048 m3; EI-GRA-Granito cinza Andorinha (Bancadas, bancos e prateleiras) 10, Volume do componente (Bruto): 0.000048 m3; EI-GRA-Granito cinza Andorinha (Bancadas, bancos e prateleiras) 11, Massa: 1.68 kg; EI-GRA-Granito cinza Andorinha (Bancadas, bancos e prateleiras) 11, Altura do Componente Retangular: 0.05 m; EI-GRA-Granito cinza Andorinha (Bancadas, bancos e prateleiras) 11, Largura do Componente Retangular: 0.6 m; EI-GRA-Granito cinza Andorinha (Bancadas, bancos e prateleiras) 11, Área de Seção Transversal do Componente: 0.03 m2; EI-GRA-Granito cinza Andorinha (Bancadas, bancos e prateleiras) 11, Volume Componente (Líquido): 0.0006 m3; EI-GRA-Granito cinza Andorinha (Bancadas, bancos e prateleiras) 11, Volume do componente (Bruto): 0.0006 m3

# IfcFurniture: Várias Estruturas- 4 Segmentos - 600 x 150 x 2832 (20+1832+480+500), B09
In: TÉRREO
Classification: Mobiliário (Classificação Archicad); Material: EI-GRA-Granito cinza Andorinha (Bancadas, bancos e prateleiras) (11)
FNDE - Pedras: BANCADA - GRANITO CINZA ANDORINHA - esp. 2 cm; 1_Bloco: BLOCO A; 0_ID: B09
Component Quantities - EI-GRA-Granito cinza Andorinha (Bancadas, bancos e prateleiras) 1, Massa: 0.1344 kg; EI-GRA-Granito cinza Andorinha (Bancadas, bancos e prateleiras) 1, Altura do Componente Retangular: 0.1 m; EI-GRA-Granito cinza Andorinha (Bancadas, bancos e prateleiras) 1, Largura do Componente Retangular: 0.024 m; EI-GRA-Granito cinza Andorinha (Bancadas, bancos e prateleiras) 1, Área de Seção Transversal do Componente: 0.0024 m2; EI-GRA-Granito cinza Andorinha (Bancadas, bancos e prateleiras) 1, Volume Componente (Líquido): 0.000048 m3; EI-GRA-Granito cinza Andorinha (Bancadas, bancos e prateleiras) 1, Volume do componente (Bruto): 0.000048 m3; EI-GRA-Granito cinza Andorinha (Bancadas, bancos e prateleiras) 2, Massa: 1.68 kg; EI-GRA-Granito cinza Andorinha (Bancadas, bancos e prateleiras) 2, Altura do Componente Retangular: 0.05 m; EI-GRA-Granito cinza Andorinha (Bancadas, bancos e prateleiras) 2, Largura do Componente Retangular: 0.6 m; EI-GRA-Granito cinza Andorinha (Bancadas, bancos e prateleiras) 2, Área de Seção Transversal do Componente: 0.03 m2; EI-GRA-Granito cinza Andorinha (Bancadas, bancos e prateleiras) 2, Volume Componente (Líquido): 0.0006 m3; EI-GRA-Granito cinza Andorinha (Bancadas, bancos e prateleiras) 2, Volume do componente (Bruto): 0.0006 m3; EI-GRA-Granito cinza Andorinha (Bancadas, bancos e prateleiras) 3, Massa: 13.5456 kg; EI-GRA-Granito cinza Andorinha (Bancadas, bancos e prateleiras) 3, Altura do Componente Retangular: 0.11 m; EI-GRA-Granito cinza Andorinha (Bancadas, bancos e prateleiras) 3, Largura do Componente Retangular: 0.024 m; EI-GRA-Granito cinza Andorinha (Bancadas, bancos e prateleiras) 3, Área de Seção Transversal do Componente: 0.00264 m2; EI-GRA-Granito cinza Andorinha (Bancadas, bancos e prateleiras) 3, Volume Componente (Líquido): 0.00483771 m3; EI-GRA-Granito cinza Andorinha (Bancadas, bancos e prateleiras) 3, Volume do componente (Bruto): 0.00483771 m3; EI-GRA-Granito cinza Andorinha (Bancadas, bancos e prateleiras) 4, Massa: 35.9525 kg; EI-GRA-Granito cinza Andorinha (Bancadas, bancos e prateleiras) 4, Altura do Componente Retangular: 0.02 m; EI-GRA-Granito cinza Andorinha (Bancadas, bancos e prateleiras) 4, Largura do Componente Retangular: 0.576 m; EI-GRA-Granito cinza Andorinha (Bancadas, bancos e prateleiras) 4, Área de Seção Transversal do Componente: 0.01152 m2; EI-GRA-Granito cinza Andorinha (Bancadas, bancos e prateleiras) 4, Volume Componente (Líquido): 0.0128402 m3; EI-GRA-Granito cinza Andorinha (Bancadas, bancos e prateleiras) 4, Volume do componente (Bruto): 0.020705 m3; EI-GRA-Granito cinza Andorinha (Bancadas, bancos e prateleiras) 5, Massa: 6.15709 kg; EI-GRA-Granito cinza Andorinha (Bancadas, bancos e prateleiras) 5, Altura do Componente Retangular: 0.05 m; EI-GRA-Granito cinza Andorinha (Bancadas, bancos e prateleiras) 5, Largura do Componente Retangular: 0.024 m; EI-GRA-Granito cinza Andorinha (Bancadas, bancos e prateleiras) 5, Área de Seção Transversal do Componente: 0.0012 m2; EI-GRA-Granito cinza Andorinha (Bancadas, bancos e prateleiras) 5, Volume Componente (Líquido): 0.00219896 m3; EI-GRA-Granito cinza Andorinha (Bancadas, bancos e prateleiras) 5, Volume do componente (Bruto): 0.00219896 m3; EI-GRA-Granito cinza Andorinha (Bancadas, bancos e prateleiras) 6, Massa: 3.2256 kg; EI-GRA-Granito cinza Andorinha (Bancadas, bancos e prateleiras) 6, Altura do Componente Retangular: 0.1 m; EI-GRA-Granito cinza Andorinha (Bancadas, bancos e prateleiras) 6, Largura do Componente Retangular: 0.024 m; EI-GRA-Granito cinza Andorinha (Bancadas, bancos e prateleiras) 6, Área de Seção Transversal do Componente: 0.0024 m2; EI-GRA-Granito cinza Andorinha (Bancadas, bancos e prateleiras) 6, Volume Componente (Líquido): 0.001152 m3; EI-GRA-Granito cinza Andorinha (Bancadas, bancos e prateleiras) 6, Volume do componente (Bruto): 0.001152 m3; EI-GRA-Granito cinza Andorinha (Bancadas, bancos e prateleiras) 7, Massa: 8.38208 kg; EI-GRA-Granito cinza Andorinha (Bancadas, bancos e prateleiras) 7, Área de Seção Transversal do Componente: 0.01176 m2; EI-GRA-Granito cinza Andorinha (Bancadas, bancos e prateleiras) 7, Volume Componente (Líquido): 0.0029936 m3; EI-GRA-Granito cinza Andorinha (Bancadas, bancos e prateleiras) 7, Volume do componente (Bruto): 0.0029936 m3; EI-GRA-Granito cinza Andorinha (Bancadas, bancos e prateleiras) 8, Massa: 0.952 kg; EI-GRA-Granito cinza Andorinha (Bancadas, bancos e prateleiras) 8, Área de Seção Transversal do Componente: 0.00096 m2; EI-GRA-Granito cinza Andorinha (Bancadas, bancos e prateleiras) 8, Volume Componente (Líquido): 0.00034 m3; EI-GRA-Granito cinza Andorinha (Bancadas, bancos e prateleiras) 8, Volume do componente (Bruto): 0.00034 m3; EI-GRA-Granito cinza Andorinha (Bancadas, bancos e prateleiras) 9, Massa: 1.2656 kg; EI-GRA-Granito cinza Andorinha (Bancadas, bancos e prateleiras) 9, Área de Seção Transversal do Componente: 0.00096 m2; EI-GRA-Granito cinza Andorinha (Bancadas, bancos e prateleiras) 9, Volume Componente (Líquido): 0.000452 m3; EI-GRA-Granito cinza Andorinha (Bancadas, bancos e prateleiras) 9, Volume do componente (Bruto): 0.000452 m3; EI-GRA-Granito cinza Andorinha (Bancadas, bancos e prateleiras) 10, Massa: 0.0672 kg; EI-GRA-Granito cinza Andorinha (Bancadas, bancos e prateleiras) 10, Altura do Componente Retangular: 0.1 m; EI-GRA-Granito cinza Andorinha (Bancadas, bancos e prateleiras) 10, Largura do Componente Retangular: 0.6 m; EI-GRA-Granito cinza Andorinha (Bancadas, bancos e prateleiras) 10, Área de Seção Transversal do Componente: 0.06 m2; EI-GRA-Granito cinza Andorinha (Bancadas, bancos e prateleiras) 10, Volume Componente (Líquido): 0.000024 m3; EI-GRA-Granito cinza Andorinha (Bancadas, bancos e prateleiras) 10, Volume do componente (Bruto): 0.000024 m3; EI-GRA-Granito cinza Andorinha (Bancadas, bancos e prateleiras) 11, Massa: 0.01344 kg; EI-GRA-Granito cinza Andorinha (Bancadas, bancos e prateleiras) 11, Área de Seção Transversal do Componente: 0.01176 m2; EI-GRA-Granito cinza Andorinha (Bancadas, bancos e prateleiras) 11, Volume Componente (Líquido): 0.0000048 m3; EI-GRA-Granito cinza Andorinha (Bancadas, bancos e prateleiras) 11, Volume do componente (Bruto): 0.0000048 m3

# IfcFurniture: Várias Estruturas- 4 Segmentos - 650 x 150 x 3500 (20+2500+480+500), B07
In: TÉRREO
Classification: Mobiliário (Classificação Archicad); Material: EI-GRA-Granito cinza Andorinha (Bancadas, bancos e prateleiras) (12)
FNDE - Pedras: BANCADA - GRANITO CINZA ANDORINHA - esp. 2 cm; 1_Bloco: BLOCO A; 0_ID: B07
Component Quantities - EI-GRA-Granito cinza Andorinha (Bancadas, bancos e prateleiras) 1, Massa: 4.004 kg; EI-GRA-Granito cinza Andorinha (Bancadas, bancos e prateleiras) 1, Altura do Componente Retangular: 0.11 m; EI-GRA-Granito cinza Andorinha (Bancadas, bancos e prateleiras) 1, Largura do Componente Retangular: 0.65 m; EI-GRA-Granito cinza Andorinha (Bancadas, bancos e prateleiras) 1, Área de Seção Transversal do Componente: 0.0715 m2; EI-GRA-Granito cinza Andorinha (Bancadas, bancos e prateleiras) 1, Volume Componente (Líquido): 0.00143 m3; EI-GRA-Granito cinza Andorinha (Bancadas, bancos e prateleiras) 1, Volume do componente (Bruto): 0.00143 m3; EI-GRA-Granito cinza Andorinha (Bancadas, bancos e prateleiras) 2, Massa: 0.69888 kg; EI-GRA-Granito cinza Andorinha (Bancadas, bancos e prateleiras) 2, Altura do Componente Retangular: 0.02 m; EI-GRA-Granito cinza Andorinha (Bancadas, bancos e prateleiras) 2, Largura do Componente Retangular: 0.624 m; EI-GRA-Granito cinza Andorinha (Bancadas, bancos e prateleiras) 2, Área de Seção Transversal do Componente: 0.01248 m2; EI-GRA-Granito cinza Andorinha (Bancadas, bancos e prateleiras) 2, Volume Componente (Líquido): 0.0002496 m3; EI-GRA-Granito cinza Andorinha (Bancadas, bancos e prateleiras) 2, Volume do componente (Bruto): 0.0002496 m3; EI-GRA-Granito cinza Andorinha (Bancadas, bancos e prateleiras) 3, Massa: 0.05824 kg; EI-GRA-Granito cinza Andorinha (Bancadas, bancos e prateleiras) 3, Altura do Componente Retangular: 0.04 m; EI-GRA-Granito cinza Andorinha (Bancadas, bancos e prateleiras) 3, Largura do Componente Retangular: 0.026 m; EI-GRA-Granito cinza Andorinha (Bancadas, bancos e prateleiras) 3, Área de Seção Transversal do Componente: 0.00104 m2; EI-GRA-Granito cinza Andorinha (Bancadas, bancos e prateleiras) 3, Volume Componente (Líquido): 0.0000208 m3; EI-GRA-Granito cinza Andorinha (Bancadas, bancos e prateleiras) 3, Volume do componente (Bruto): 0.0000208 m3; EI-GRA-Granito cinza Andorinha (Bancadas, bancos e prateleiras) 4, Massa: 20.02 kg; EI-GRA-Granito cinza Andorinha (Bancadas, bancos e prateleiras) 4, Altura do Componente Retangular: 0.11 m; EI-GRA-Granito cinza Andorinha (Bancadas, bancos e prateleiras) 4, Largura do Componente Retangular: 0.026 m; EI-GRA-Granito cinza Andorinha (Bancadas, bancos e prateleiras) 4, Área de Seção Transversal do Componente: 0.00286 m2; EI-GRA-Granito cinza Andorinha (Bancadas, bancos e prateleiras) 4, Volume Componente (Líquido): 0.00715 m3; EI-GRA-Granito cinza Andorinha (Bancadas, bancos e prateleiras) 4, Volume do componente (Bruto): 0.00715 m3; EI-GRA-Granito cinza Andorinha (Bancadas, bancos e prateleiras) 5, Massa: 56.7988 kg; EI-GRA-Granito cinza Andorinha (Bancadas, bancos e prateleiras) 5, Altura do Componente Retangular: 0.02 m; EI-GRA-Granito cinza Andorinha (Bancadas, bancos e prateleiras) 5, Largura do Componente Retangular: 0.624 m; EI-GRA-Granito cinza Andorinha (Bancadas, bancos e prateleiras) 5, Área de Seção Transversal do Componente: 0.01248 m2; EI-GRA-Granito cinza Andorinha (Bancadas, bancos e prateleiras) 5, Volume Componente (Líquido): 0.0202853 m3; EI-GRA-Granito cinza Andorinha (Bancadas, bancos e prateleiras) 5, Volume do componente (Bruto): 0.0301501 m3; EI-GRA-Granito cinza Andorinha (Bancadas, bancos e prateleiras) 6, Massa: 9.1 kg; EI-GRA-Granito cinza Andorinha (Bancadas, bancos e prateleiras) 6, Altura do Componente Retangular: 0.05 m; EI-GRA-Granito cinza Andorinha (Bancadas, bancos e prateleiras) 6, Largura do Componente Retangular: 0.026 m; EI-GRA-Granito cinza Andorinha (Bancadas, bancos e prateleiras) 6, Área de Seção Transversal do Componente: 0.0013 m2; EI-GRA-Granito cinza Andorinha (Bancadas, bancos e prateleiras) 6, Volume Componente (Líquido): 0.00325 m3; EI-GRA-Granito cinza Andorinha (Bancadas, bancos e prateleiras) 6, Volume do componente (Bruto): 0.00325 m3; EI-GRA-Granito cinza Andorinha (Bancadas, bancos e prateleiras) 7, Massa: 3.4944 kg; EI-GRA-Granito cinza Andorinha (Bancadas, bancos e prateleiras) 7, Altura do Componente Retangular: 0.1 m; EI-GRA-Granito cinza Andorinha (Bancadas, bancos e prateleiras) 7, Largura do Componente Retangular: 0.026 m; EI-GRA-Granito cinza Andorinha (Bancadas, bancos e prateleiras) 7, Área de Seção Transversal do Componente: 0.0026 m2; EI-GRA-Granito cinza Andorinha (Bancadas, bancos e prateleiras) 7, Volume Componente (Líquido): 0.001248 m3; EI-GRA-Granito cinza Andorinha (Bancadas, bancos e prateleiras) 7, Volume do componente (Bruto): 0.001248 m3; EI-GRA-Granito cinza Andorinha (Bancadas, bancos e prateleiras) 8, Massa: 9.08059 kg; EI-GRA-Granito cinza Andorinha (Bancadas, bancos e prateleiras) 8, Área de Seção Transversal do Componente: 0.01274 m2; EI-GRA-Granito cinza Andorinha (Bancadas, bancos e prateleiras) 8, Volume Componente (Líquido): 0.00324307 m3; EI-GRA-Granito cinza Andorinha (Bancadas, bancos e prateleiras) 8, Volume do componente (Bruto): 0.00324307 m3; EI-GRA-Granito cinza Andorinha (Bancadas, bancos e prateleiras) 9, Massa: 1.03133 kg; EI-GRA-Granito cinza Andorinha (Bancadas, bancos e prateleiras) 9, Área de Seção Transversal do Componente: 0.00104 m2; EI-GRA-Granito cinza Andorinha (Bancadas, bancos e prateleiras) 9, Volume Componente (Líquido): 0.000368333 m3; EI-GRA-Granito cinza Andorinha (Bancadas, bancos e prateleiras) 9, Volume do componente (Bruto): 0.000368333 m3; EI-GRA-Granito cinza Andorinha (Bancadas, bancos e prateleiras) 10, Massa: 1.37107 kg; EI-GRA-Granito cinza Andorinha (Bancadas, bancos e prateleiras) 10, Área de Seção Transversal do Componente: 0.00104 m2; EI-GRA-Granito cinza Andorinha (Bancadas, bancos e prateleiras) 10, Volume Componente (Líquido): 0.000489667 m3; EI-GRA-Granito cinza Andorinha (Bancadas, bancos e prateleiras) 10, Volume do componente (Bruto): 0.000489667 m3; EI-GRA-Granito cinza Andorinha (Bancadas, bancos e prateleiras) 11, Massa: 0.0728 kg; EI-GRA-Granito cinza Andorinha (Bancadas, bancos e prateleiras) 11, Altura do Componente Retangular: 0.1 m; EI-GRA-Granito cinza Andorinha (Bancadas, bancos e prateleiras) 11, Largura do Componente Retangular: 0.65 m; EI-GRA-Granito cinza Andorinha (Bancadas, bancos e prateleiras) 11, Área de Seção Transversal do Componente: 0.065 m2; EI-GRA-Granito cinza Andorinha (Bancadas, bancos e prateleiras) 11, Volume Componente (Líquido): 0.000026 m3; EI-GRA-Granito cinza Andorinha (Bancadas, bancos e prateleiras) 11, Volume do componente (Bruto): 0.000026 m3; EI-GRA-Granito cinza Andorinha (Bancadas, bancos e prateleiras) 12, Massa: 0.01456 kg; EI-GRA-Granito cinza Andorinha (Bancadas, bancos e prateleiras) 12, Área de Seção Transversal do Componente: 0.01274 m2; EI-GRA-Granito cinza Andorinha (Bancadas, bancos e prateleiras) 12, Volume Componente (Líquido): 0.0000052 m3; EI-GRA-Granito cinza Andorinha (Bancadas, bancos e prateleiras) 12, Volume do componente (Bruto): 0.0000052 m3

# IfcFurniture: Várias Estruturas- 4 Segmentos - 750 x 200 x 1220 (20+1099+81+20), B08
In: TÉRREO
Classification: Mobiliário (Classificação Archicad); Material: EI-GRA-Granito cinza Andorinha (Bancadas, bancos e prateleiras) (10)
FNDE - Pedras: BANCADA - GRANITO CINZA ANDORINHA - esp. 2 cm; 1_Bloco: BLOCO A; 0_ID: B08
Component Quantities - EI-GRA-Granito cinza Andorinha (Bancadas, bancos e prateleiras) 1, Massa: 4.7264 kg; EI-GRA-Granito cinza Andorinha (Bancadas, bancos e prateleiras) 1, Altura do Componente Retangular: 0.17 m; EI-GRA-Granito cinza Andorinha (Bancadas, bancos e prateleiras) 1, Largura do Componente Retangular: 0.5 m; EI-GRA-Granito cinza Andorinha (Bancadas, bancos e prateleiras) 1, Área de Seção Transversal do Componente: 0.085 m2; EI-GRA-Granito cinza Andorinha (Bancadas, bancos e prateleiras) 1, Volume Componente (Líquido): 0.001688 m3; EI-GRA-Granito cinza Andorinha (Bancadas, bancos e prateleiras) 1, Volume do componente (Bruto): 0.001688 m3; EI-GRA-Granito cinza Andorinha (Bancadas, bancos e prateleiras) 2, Massa: 0.84 kg; EI-GRA-Granito cinza Andorinha (Bancadas, bancos e prateleiras) 2, Altura do Componente Retangular: 0.03 m; EI-GRA-Granito cinza Andorinha (Bancadas, bancos e prateleiras) 2, Largura do Componente Retangular: 0.5 m; EI-GRA-Granito cinza Andorinha (Bancadas, bancos e prateleiras) 2, Área de Seção Transversal do Componente: 0.015 m2; EI-GRA-Granito cinza Andorinha (Bancadas, bancos e prateleiras) 2, Volume Componente (Líquido): 0.0003 m3; EI-GRA-Granito cinza Andorinha (Bancadas, bancos e prateleiras) 2, Volume do componente (Bruto): 0.0003 m3; EI-GRA-Granito cinza Andorinha (Bancadas, bancos e prateleiras) 3, Massa: 39.9898 kg; EI-GRA-Granito cinza Andorinha (Bancadas, bancos e prateleiras) 3, Área de Seção Transversal do Componente: 0.0148 m2; EI-GRA-Granito cinza Andorinha (Bancadas, bancos e prateleiras) 3, Volume Componente (Líquido): 0.0142821 m3; EI-GRA-Granito cinza Andorinha (Bancadas, bancos e prateleiras) 3, Volume do componente (Bruto): 0.0142821 m3; EI-GRA-Granito cinza Andorinha (Bancadas, bancos e prateleiras) 4, Massa: 2.46091 kg; EI-GRA-Granito cinza Andorinha (Bancadas, bancos e prateleiras) 4, Área de Seção Transversal do Componente: 0.0008 m2; EI-GRA-Granito cinza Andorinha (Bancadas, bancos e prateleiras) 4, Volume Componente (Líquido): 0.000878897 m3; EI-GRA-Granito cinza Andorinha (Bancadas, bancos e prateleiras) 4, Volume do componente (Bruto): 0.000878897 m3; EI-GRA-Granito cinza Andorinha (Bancadas, bancos e prateleiras) 5, Massa: 0.455724 kg; EI-GRA-Granito cinza Andorinha (Bancadas, bancos e prateleiras) 5, Altura do Componente Retangular: 0.1 m; EI-GRA-Granito cinza Andorinha (Bancadas, bancos e prateleiras) 5, Largura do Componente Retangular: 0.02 m; EI-GRA-Granito cinza Andorinha (Bancadas, bancos e prateleiras) 5, Área de Seção Transversal do Componente: 0.002 m2; EI-GRA-Granito cinza Andorinha (Bancadas, bancos e prateleiras) 5, Volume Componente (Líquido): 0.000162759 m3; EI-GRA-Granito cinza Andorinha (Bancadas, bancos e prateleiras) 5, Volume do componente (Bruto): 0.000162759 m3; EI-GRA-Granito cinza Andorinha (Bancadas, bancos e prateleiras) 6, Massa: 2.23305 kg; EI-GRA-Granito cinza Andorinha (Bancadas, bancos e prateleiras) 6, Área de Seção Transversal do Componente: 0.0098 m2; EI-GRA-Granito cinza Andorinha (Bancadas, bancos e prateleiras) 6, Volume Componente (Líquido): 0.000797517 m3; EI-GRA-Granito cinza Andorinha (Bancadas, bancos e prateleiras) 6, Volume do componente (Bruto): 0.000797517 m3; EI-GRA-Granito cinza Andorinha (Bancadas, bancos e prateleiras) 7, Massa: 0.18229 kg; EI-GRA-Granito cinza Andorinha (Bancadas, bancos e prateleiras) 7, Área de Seção Transversal do Componente: 0.0008 m2; EI-GRA-Granito cinza Andorinha (Bancadas, bancos e prateleiras) 7, Volume Componente (Líquido): 0.0000651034 m3; EI-GRA-Granito cinza Andorinha (Bancadas, bancos e prateleiras) 7, Volume do componente (Bruto): 0.0000651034 m3; EI-GRA-Granito cinza Andorinha (Bancadas, bancos e prateleiras) 8, Massa: 0.0448 kg; EI-GRA-Granito cinza Andorinha (Bancadas, bancos e prateleiras) 8, Área de Seção Transversal do Componente: 0.0008 m2; EI-GRA-Granito cinza Andorinha (Bancadas, bancos e prateleiras) 8, Volume Componente (Líquido): 0.000016 m3; EI-GRA-Granito cinza Andorinha (Bancadas, bancos e prateleiras) 8, Volume do componente (Bruto): 0.000016 m3; EI-GRA-Granito cinza Andorinha (Bancadas, bancos e prateleiras) 9, Massa: 2.8 kg; EI-GRA-Granito cinza Andorinha (Bancadas, bancos e prateleiras) 9, Altura do Componente Retangular: 0.1 m; EI-GRA-Granito cinza Andorinha (Bancadas, bancos e prateleiras) 9, Largura do Componente Retangular: 0.5 m; EI-GRA-Granito cinza Andorinha (Bancadas, bancos e prateleiras) 9, Área de Seção Transversal do Componente: 0.05 m2; EI-GRA-Granito cinza Andorinha (Bancadas, bancos e prateleiras) 9, Volume Componente (Líquido): 0.001 m3; EI-GRA-Granito cinza Andorinha (Bancadas, bancos e prateleiras) 9, Volume do componente (Bruto): 0.001 m3; EI-GRA-Granito cinza Andorinha (Bancadas, bancos e prateleiras) 10, Massa: 0.5488 kg; EI-GRA-Granito cinza Andorinha (Bancadas, bancos e prateleiras) 10, Área de Seção Transversal do Componente: 0.0098 m2; EI-GRA-Granito cinza Andorinha (Bancadas, bancos e prateleiras) 10, Volume Componente (Líquido): 0.000196 m3; EI-GRA-Granito cinza Andorinha (Bancadas, bancos e prateleiras) 10, Volume do componente (Bruto): 0.000196 m3

# IfcFurniture: Várias Estruturas- 5 Segmentos - 300 x 270 x 1220 (200+20+780+20+200), PTG9
In: TÉRREO
Classification: Mobiliário (Classificação Archicad); Material: EI-GRA-Granito cinza Andorinha (Bancadas, bancos e prateleiras) (5), Aço (2)
FNDE - Pedras: PRATELEIRA - GRANITO CINZA ANDORINHA - esp. 2 cm; 1_Bloco: BLOCO A; 0_ID: PTG9
Component Quantities - EI-GRA-Granito cinza Andorinha (Bancadas, bancos e prateleiras) 1, Massa: 3.36 kg; EI-GRA-Granito cinza Andorinha (Bancadas, bancos e prateleiras) 1, Altura do Componente Retangular: 0.02 m; EI-GRA-Granito cinza Andorinha (Bancadas, bancos e prateleiras) 1, Largura do Componente Retangular: 0.3 m; EI-GRA-Granito cinza Andorinha (Bancadas, bancos e prateleiras) 1, Área de Seção Transversal do Componente: 0.006 m2; EI-GRA-Granito cinza Andorinha (Bancadas, bancos e prateleiras) 1, Volume Componente (Líquido): 0.0012 m3; EI-GRA-Granito cinza Andorinha (Bancadas, bancos e prateleiras) 1, Volume do componente (Bruto): 0.0012 m3; EI-GRA-Granito cinza Andorinha (Bancadas, bancos e prateleiras) 2, Massa: 0.336 kg; EI-GRA-Granito cinza Andorinha (Bancadas, bancos e prateleiras) 2, Altura do Componente Retangular: 0.02 m; EI-GRA-Granito cinza Andorinha (Bancadas, bancos e prateleiras) 2, Largura do Componente Retangular: 0.3 m; EI-GRA-Granito cinza Andorinha (Bancadas, bancos e prateleiras) 2, Área de Seção Transversal do Componente: 0.006 m2; EI-GRA-Granito cinza Andorinha (Bancadas, bancos e prateleiras) 2, Volume Componente (Líquido): 0.00012 m3; EI-GRA-Granito cinza Andorinha (Bancadas, bancos e prateleiras) 2, Volume do componente (Bruto): 0.00012 m3; Aço 1, Massa: 0.5772 kg; Aço 1, Área de Seção Transversal do Componente: 0.0037 m2; Aço 1, Volume Componente (Líquido): 0.000074 m3; Aço 1, Volume do componente (Bruto): 0.000074 m3; EI-GRA-Granito cinza Andorinha (Bancadas, bancos e prateleiras) 3, Massa: 13.104 kg; EI-GRA-Granito cinza Andorinha (Bancadas, bancos e prateleiras) 3, Altura do Componente Retangular: 0.02 m; EI-GRA-Granito cinza Andorinha (Bancadas, bancos e prateleiras) 3, Largura do Componente Retangular: 0.3 m; EI-GRA-Granito cinza Andorinha (Bancadas, bancos e prateleiras) 3, Área de Seção Transversal do Componente: 0.006 m2; EI-GRA-Granito cinza Andorinha (Bancadas, bancos e prateleiras) 3, Volume Componente (Líquido): 0.00468 m3; EI-GRA-Granito cinza Andorinha (Bancadas, bancos e prateleiras) 3, Volume do componente (Bruto): 0.00468 m3; EI-GRA-Granito cinza Andorinha (Bancadas, bancos e prateleiras) 1: 2 with these values; EI-GRA-Granito cinza Andorinha (Bancadas, bancos e prateleiras) 2: 2 with these values; Aço 1: 2 with these values

# IfcFurniture: Várias Estruturas- 5 Segmentos - 300 x 270 x 2100 (200+20+1660+20+200), PTG7
In: TÉRREO
Classification: Mobiliário (Classificação Archicad); Material: EI-GRA-Granito cinza Andorinha (Bancadas, bancos e prateleiras) (5), Aço (2)
FNDE - Pedras: PRATELEIRA - GRANITO CINZA ANDORINHA - esp. 2 cm; 1_Bloco: BLOCO A; 0_ID: PTG7
Component Quantities - EI-GRA-Granito cinza Andorinha (Bancadas, bancos e prateleiras) 1, Massa: 3.33487 kg; EI-GRA-Granito cinza Andorinha (Bancadas, bancos e prateleiras) 1, Altura do Componente Retangular: 0.02 m; EI-GRA-Granito cinza Andorinha (Bancadas, bancos e prateleiras) 1, Largura do Componente Retangular: 0.3 m; EI-GRA-Granito cinza Andorinha (Bancadas, bancos e prateleiras) 1, Área de Seção Transversal do Componente: 0.006 m2; EI-GRA-Granito cinza Andorinha (Bancadas, bancos e prateleiras) 1, Volume Componente (Líquido): 0.00119102 m3; EI-GRA-Granito cinza Andorinha (Bancadas, bancos e prateleiras) 1, Volume do componente (Bruto): 0.00119102 m3; EI-GRA-Granito cinza Andorinha (Bancadas, bancos e prateleiras) 2, Massa: 0.336 kg; EI-GRA-Granito cinza Andorinha (Bancadas, bancos e prateleiras) 2, Altura do Componente Retangular: 0.02 m; EI-GRA-Granito cinza Andorinha (Bancadas, bancos e prateleiras) 2, Largura do Componente Retangular: 0.3 m; EI-GRA-Granito cinza Andorinha (Bancadas, bancos e prateleiras) 2, Área de Seção Transversal do Componente: 0.006 m2; EI-GRA-Granito cinza Andorinha (Bancadas, bancos e prateleiras) 2, Volume Componente (Líquido): 0.00012 m3; EI-GRA-Granito cinza Andorinha (Bancadas, bancos e prateleiras) 2, Volume do componente (Bruto): 0.00012 m3; Aço 1, Massa: 0.5772 kg; Aço 1, Área de Seção Transversal do Componente: 0.0037 m2; Aço 1, Volume Componente (Líquido): 0.000074 m3; Aço 1, Volume do componente (Bruto): 0.000074 m3; EI-GRA-Granito cinza Andorinha (Bancadas, bancos e prateleiras) 3, Massa: 27.8917 kg; EI-GRA-Granito cinza Andorinha (Bancadas, bancos e prateleiras) 3, Altura do Componente Retangular: 0.02 m; EI-GRA-Granito cinza Andorinha (Bancadas, bancos e prateleiras) 3, Largura do Componente Retangular: 0.3 m; EI-GRA-Granito cinza Andorinha (Bancadas, bancos e prateleiras) 3, Área de Seção Transversal do Componente: 0.006 m2; EI-GRA-Granito cinza Andorinha (Bancadas, bancos e prateleiras) 3, Volume Componente (Líquido): 0.00996132 m3; EI-GRA-Granito cinza Andorinha (Bancadas, bancos e prateleiras) 3, Volume do componente (Bruto): 0.00996132 m3; EI-GRA-Granito cinza Andorinha (Bancadas, bancos e prateleiras) 5, Massa: 3.36 kg; EI-GRA-Granito cinza Andorinha (Bancadas, bancos e prateleiras) 5, Altura do Componente Retangular: 0.02 m; EI-GRA-Granito cinza Andorinha (Bancadas, bancos e prateleiras) 5, Largura do Componente Retangular: 0.3 m; EI-GRA-Granito cinza Andorinha (Bancadas, bancos e prateleiras) 5, Área de Seção Transversal do Componente: 0.006 m2; EI-GRA-Granito cinza Andorinha (Bancadas, bancos e prateleiras) 5, Volume Componente (Líquido): 0.0012 m3; EI-GRA-Granito cinza Andorinha (Bancadas, bancos e prateleiras) 5, Volume do componente (Bruto): 0.0012 m3; EI-GRA-Granito cinza Andorinha (Bancadas, bancos e prateleiras) 2: 2 with these values; Aço 1: 2 with these values

# IfcFurniture: Várias Estruturas- 5 Segmentos - 400 x 1110 x 1201 (130+20+901+20+130), PTG2b
In: TÉRREO
Classification: Mobiliário (Classificação Archicad); Material: EI-GRA-Granito cinza Andorinha (Bancadas, bancos e prateleiras) (15), Aço (6)
FNDE - Pedras: PRATELEIRA - GRANITO CINZA ANDORINHA - esp. 2 cm; 1_Bloco: BLOCO A; 0_ID: PTG2b
Component Quantities - EI-GRA-Granito cinza Andorinha (Bancadas, bancos e prateleiras) 1, Massa: 2.912 kg; EI-GRA-Granito cinza Andorinha (Bancadas, bancos e prateleiras) 1, Altura do Componente Retangular: 0.02 m; EI-GRA-Granito cinza Andorinha (Bancadas, bancos e prateleiras) 1, Largura do Componente Retangular: 0.4 m; EI-GRA-Granito cinza Andorinha (Bancadas, bancos e prateleiras) 1, Área de Seção Transversal do Componente: 0.008 m2; EI-GRA-Granito cinza Andorinha (Bancadas, bancos e prateleiras) 1, Volume Componente (Líquido): 0.00104 m3; EI-GRA-Granito cinza Andorinha (Bancadas, bancos e prateleiras) 1, Volume do componente (Bruto): 0.00104 m3; EI-GRA-Granito cinza Andorinha (Bancadas, bancos e prateleiras) 4, Massa: 0.448 kg; EI-GRA-Granito cinza Andorinha (Bancadas, bancos e prateleiras) 4, Altura do Componente Retangular: 0.02 m; EI-GRA-Granito cinza Andorinha (Bancadas, bancos e prateleiras) 4, Largura do Componente Retangular: 0.4 m; EI-GRA-Granito cinza Andorinha (Bancadas, bancos e prateleiras) 4, Área de Seção Transversal do Componente: 0.008 m2; EI-GRA-Granito cinza Andorinha (Bancadas, bancos e prateleiras) 4, Volume Componente (Líquido): 0.00016 m3; EI-GRA-Granito cinza Andorinha (Bancadas, bancos e prateleiras) 4, Volume do componente (Bruto): 0.00016 m3; Aço 1, Massa: 0.5772 kg; Aço 1, Área de Seção Transversal do Componente: 0.0037 m2; Aço 1, Volume Componente (Líquido): 0.000074 m3; Aço 1, Volume do componente (Bruto): 0.000074 m3; EI-GRA-Granito cinza Andorinha (Bancadas, bancos e prateleiras) 7, Massa: 20.1742 kg; EI-GRA-Granito cinza Andorinha (Bancadas, bancos e prateleiras) 7, Altura do Componente Retangular: 0.02 m; EI-GRA-Granito cinza Andorinha (Bancadas, bancos e prateleiras) 7, Largura do Componente Retangular: 0.4 m; EI-GRA-Granito cinza Andorinha (Bancadas, bancos e prateleiras) 7, Área de Seção Transversal do Componente: 0.008 m2; EI-GRA-Granito cinza Andorinha (Bancadas, bancos e prateleiras) 7, Volume Componente (Líquido): 0.00720506 m3; EI-GRA-Granito cinza Andorinha (Bancadas, bancos e prateleiras) 7, Volume do componente (Bruto): 0.00720506 m3; EI-GRA-Granito cinza Andorinha (Bancadas, bancos e prateleiras) 1: 6 with these values; EI-GRA-Granito cinza Andorinha (Bancadas, bancos e prateleiras) 4: 6 with these values; Aço 1: 6 with these values; EI-GRA-Granito cinza Andorinha (Bancadas, bancos e prateleiras) 7: 3 with these values

# IfcFurniture: Várias Estruturas- 5 Segmentos - 400 x 1950 x 1803 (150+20+1463+20+150), PTG2a
In: TÉRREO
Classification: Mobiliário (Classificação Archicad); Material: EI-GRA-Granito cinza Andorinha (Bancadas, bancos e prateleiras) (25), Aço (10)
FNDE - Pedras: PRATELEIRA - GRANITO CINZA ANDORINHA - esp. 2 cm; 1_Bloco: BLOCO A; 0_ID: PTG2a
Component Quantities - EI-GRA-Granito cinza Andorinha (Bancadas, bancos e prateleiras) 1, Massa: 3.36 kg; EI-GRA-Granito cinza Andorinha (Bancadas, bancos e prateleiras) 1, Altura do Componente Retangular: 0.02 m; EI-GRA-Granito cinza Andorinha (Bancadas, bancos e prateleiras) 1, Largura do Componente Retangular: 0.4 m; EI-GRA-Granito cinza Andorinha (Bancadas, bancos e prateleiras) 1, Área de Seção Transversal do Componente: 0.008 m2; EI-GRA-Granito cinza Andorinha (Bancadas, bancos e prateleiras) 1, Volume Componente (Líquido): 0.0012 m3; EI-GRA-Granito cinza Andorinha (Bancadas, bancos e prateleiras) 1, Volume do componente (Bruto): 0.0012 m3; EI-GRA-Granito cinza Andorinha (Bancadas, bancos e prateleiras) 6, Massa: 0.448 kg; EI-GRA-Granito cinza Andorinha (Bancadas, bancos e prateleiras) 6, Altura do Componente Retangular: 0.02 m; EI-GRA-Granito cinza Andorinha (Bancadas, bancos e prateleiras) 6, Largura do Componente Retangular: 0.4 m; EI-GRA-Granito cinza Andorinha (Bancadas, bancos e prateleiras) 6, Área de Seção Transversal do Componente: 0.008 m2; EI-GRA-Granito cinza Andorinha (Bancadas, bancos e prateleiras) 6, Volume Componente (Líquido): 0.00016 m3; EI-GRA-Granito cinza Andorinha (Bancadas, bancos e prateleiras) 6, Volume do componente (Bruto): 0.00016 m3; Aço 1, Massa: 0.5772 kg; Aço 1, Área de Seção Transversal do Componente: 0.0037 m2; Aço 1, Volume Componente (Líquido): 0.000074 m3; Aço 1, Volume do componente (Bruto): 0.000074 m3; EI-GRA-Granito cinza Andorinha (Bancadas, bancos e prateleiras) 11, Massa: 32.7608 kg; EI-GRA-Granito cinza Andorinha (Bancadas, bancos e prateleiras) 11, Altura do Componente Retangular: 0.02 m; EI-GRA-Granito cinza Andorinha (Bancadas, bancos e prateleiras) 11, Largura do Componente Retangular: 0.4 m; EI-GRA-Granito cinza Andorinha (Bancadas, bancos e prateleiras) 11, Área de Seção Transversal do Componente: 0.008 m2; EI-GRA-Granito cinza Andorinha (Bancadas, bancos e prateleiras) 11, Volume Componente (Líquido): 0.0117003 m3; EI-GRA-Granito cinza Andorinha (Bancadas, bancos e prateleiras) 11, Volume do componente (Bruto): 0.0117003 m3; EI-GRA-Granito cinza Andorinha (Bancadas, bancos e prateleiras) 1: 10 with these values; EI-GRA-Granito cinza Andorinha (Bancadas, bancos e prateleiras) 6: 10 with these values; Aço 1: 10 with these values; EI-GRA-Granito cinza Andorinha (Bancadas, bancos e prateleiras) 11: 5 with these values

# IfcFurniture: Várias Estruturas- 5 Segmentos - 500 x 370 x 850 (20+20+770+20+20) (2)
In: TÉRREO
Classification: Mobiliário (Classificação Archicad); Material: EI-GRA-Granito cinza Andorinha (Bancadas, bancos e prateleiras) (15), Aço (2)
FNDE - Pedras: BANCADA - GRANITO CINZA ANDORINHA - esp. 2 cm; 1_Bloco: BLOCO A; 0_ID: B17
Component Quantities - EI-GRA-Granito cinza Andorinha (Bancadas, bancos e prateleiras) 1, Massa: 0.0448 kg; EI-GRA-Granito cinza Andorinha (Bancadas, bancos e prateleiras) 1, Área de Seção Transversal do Componente: 0.0008 m2; EI-GRA-Granito cinza Andorinha (Bancadas, bancos e prateleiras) 1, Volume Componente (Líquido): 0.000016 m3; EI-GRA-Granito cinza Andorinha (Bancadas, bancos e prateleiras) 1, Volume do componente (Bruto): 0.000016 m3; EI-GRA-Granito cinza Andorinha (Bancadas, bancos e prateleiras) 2, Massa: 2.8 kg; EI-GRA-Granito cinza Andorinha (Bancadas, bancos e prateleiras) 2, Altura do Componente Retangular: 0.1 m; EI-GRA-Granito cinza Andorinha (Bancadas, bancos e prateleiras) 2, Largura do Componente Retangular: 0.5 m; EI-GRA-Granito cinza Andorinha (Bancadas, bancos e prateleiras) 2, Área de Seção Transversal do Componente: 0.05 m2; EI-GRA-Granito cinza Andorinha (Bancadas, bancos e prateleiras) 2, Volume Componente (Líquido): 0.001 m3; EI-GRA-Granito cinza Andorinha (Bancadas, bancos e prateleiras) 2, Volume do componente (Bruto): 0.001 m3; EI-GRA-Granito cinza Andorinha (Bancadas, bancos e prateleiras) 3, Massa: 0.5488 kg; EI-GRA-Granito cinza Andorinha (Bancadas, bancos e prateleiras) 3, Área de Seção Transversal do Componente: 0.0098 m2; EI-GRA-Granito cinza Andorinha (Bancadas, bancos e prateleiras) 3, Volume Componente (Líquido): 0.000196 m3; EI-GRA-Granito cinza Andorinha (Bancadas, bancos e prateleiras) 3, Volume do componente (Bruto): 0.000196 m3; EI-GRA-Granito cinza Andorinha (Bancadas, bancos e prateleiras) 4, Massa: 0.112 kg; EI-GRA-Granito cinza Andorinha (Bancadas, bancos e prateleiras) 4, Altura do Componente Retangular: 0.1 m; EI-GRA-Granito cinza Andorinha (Bancadas, bancos e prateleiras) 4, Largura do Componente Retangular: 0.02 m; EI-GRA-Granito cinza Andorinha (Bancadas, bancos e prateleiras) 4, Área de Seção Transversal do Componente: 0.002 m2; EI-GRA-Granito cinza Andorinha (Bancadas, bancos e prateleiras) 4, Volume Componente (Líquido): 0.00004 m3; EI-GRA-Granito cinza Andorinha (Bancadas, bancos e prateleiras) 4, Volume do componente (Bruto): 0.00004 m3; Aço 1, Massa: 0.5772 kg; Aço 1, Área de Seção Transversal do Componente: 0.0037 m2; Aço 1, Volume Componente (Líquido): 0.000074 m3; Aço 1, Volume do componente (Bruto): 0.000074 m3; EI-GRA-Granito cinza Andorinha (Bancadas, bancos e prateleiras) 7, Massa: 4.312 kg; EI-GRA-Granito cinza Andorinha (Bancadas, bancos e prateleiras) 7, Altura do Componente Retangular: 0.1 m; EI-GRA-Granito cinza Andorinha (Bancadas, bancos e prateleiras) 7, Largura do Componente Retangular: 0.02 m; EI-GRA-Granito cinza Andorinha (Bancadas, bancos e prateleiras) 7, Área de Seção Transversal do Componente: 0.002 m2; EI-GRA-Granito cinza Andorinha (Bancadas, bancos e prateleiras) 7, Volume Componente (Líquido): 0.00154 m3; EI-GRA-Granito cinza Andorinha (Bancadas, bancos e prateleiras) 7, Volume do componente (Bruto): 0.00154 m3; EI-GRA-Granito cinza Andorinha (Bancadas, bancos e prateleiras) 8, Massa: 15.9236 kg; EI-GRA-Granito cinza Andorinha (Bancadas, bancos e prateleiras) 8, Área de Seção Transversal do Componente: 0.0098 m2; EI-GRA-Granito cinza Andorinha (Bancadas, bancos e prateleiras) 8, Volume Componente (Líquido): 0.00568701 m3; EI-GRA-Granito cinza Andorinha (Bancadas, bancos e prateleiras) 8, Volume do componente (Bruto): 0.007546 m3; EI-GRA-Granito cinza Andorinha (Bancadas, bancos e prateleiras) 9, Massa: 1.7248 kg; EI-GRA-Granito cinza Andorinha (Bancadas, bancos e prateleiras) 9, Área de Seção Transversal do Componente: 0.0008 m2; EI-GRA-Granito cinza Andorinha (Bancadas, bancos e prateleiras) 9, Volume Componente (Líquido): 0.000616 m3; EI-GRA-Granito cinza Andorinha (Bancadas, bancos e prateleiras) 9, Volume do componente (Bruto): 0.000616 m3; EI-GRA-Granito cinza Andorinha (Bancadas, bancos e prateleiras) 14, Massa: 0.56 kg; EI-GRA-Granito cinza Andorinha (Bancadas, bancos e prateleiras) 14, Altura do Componente Retangular: 0.02 m; EI-GRA-Granito cinza Andorinha (Bancadas, bancos e prateleiras) 14, Largura do Componente Retangular: 0.5 m; EI-GRA-Granito cinza Andorinha (Bancadas, bancos e prateleiras) 14, Área de Seção Transversal do Componente: 0.01 m2; EI-GRA-Granito cinza Andorinha (Bancadas, bancos e prateleiras) 14, Volume Componente (Líquido): 0.0002 m3; EI-GRA-Granito cinza Andorinha (Bancadas, bancos e prateleiras) 14, Volume do componente (Bruto): 0.0002 m3; EI-GRA-Granito cinza Andorinha (Bancadas, bancos e prateleiras) 15, Massa: 0.84 kg; EI-GRA-Granito cinza Andorinha (Bancadas, bancos e prateleiras) 15, Altura do Componente Retangular: 0.03 m; EI-GRA-Granito cinza Andorinha (Bancadas, bancos e prateleiras) 15, Largura do Componente Retangular: 0.5 m; EI-GRA-Granito cinza Andorinha (Bancadas, bancos e prateleiras) 15, Área de Seção Transversal do Componente: 0.015 m2; EI-GRA-Granito cinza Andorinha (Bancadas, bancos e prateleiras) 15, Volume Componente (Líquido): 0.0003 m3; EI-GRA-Granito cinza Andorinha (Bancadas, bancos e prateleiras) 15, Volume do componente (Bruto): 0.0003 m3; EI-GRA-Granito cinza Andorinha (Bancadas, bancos e prateleiras) 1: 3 with these values; EI-GRA-Granito cinza Andorinha (Bancadas, bancos e prateleiras) 3: 3 with these values; EI-GRA-Granito cinza Andorinha (Bancadas, bancos e prateleiras) 4: 3 with these values; Aço 1: 2 with these values

# IfcFurniture: Várias Estruturas- 5 Segmentos - 550 x 370 x 1570 (20+610+20+900+20), B20
In: TÉRREO
Classification: Mobiliário (Classificação Archicad); Material: EI-GRA-Granito cinza Andorinha (Bancadas, bancos e prateleiras) (14), Aço
FNDE - Pedras: BANCADA - GRANITO CINZA ANDORINHA - esp. 2 cm; 1_Bloco: BLOCO B; 0_ID: B20
Component Quantities - EI-GRA-Granito cinza Andorinha (Bancadas, bancos e prateleiras) 1, Massa: 0.0492804 kg; EI-GRA-Granito cinza Andorinha (Bancadas, bancos e prateleiras) 1, Área de Seção Transversal do Componente: 0.000880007 m2; EI-GRA-Granito cinza Andorinha (Bancadas, bancos e prateleiras) 1, Volume Componente (Líquido): 0.0000176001 m3; EI-GRA-Granito cinza Andorinha (Bancadas, bancos e prateleiras) 1, Volume do componente (Bruto): 0.0000176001 m3; EI-GRA-Granito cinza Andorinha (Bancadas, bancos e prateleiras) 2, Massa: 3.08002 kg; EI-GRA-Granito cinza Andorinha (Bancadas, bancos e prateleiras) 2, Altura do Componente Retangular: 0.1 m; EI-GRA-Granito cinza Andorinha (Bancadas, bancos e prateleiras) 2, Largura do Componente Retangular: 0.550004 m; EI-GRA-Granito cinza Andorinha (Bancadas, bancos e prateleiras) 2, Área de Seção Transversal do Componente: 0.0550004 m2; EI-GRA-Granito cinza Andorinha (Bancadas, bancos e prateleiras) 2, Volume Componente (Líquido): 0.00110001 m3; EI-GRA-Granito cinza Andorinha (Bancadas, bancos e prateleiras) 2, Volume do componente (Bruto): 0.00110001 m3; EI-GRA-Granito cinza Andorinha (Bancadas, bancos e prateleiras) 3, Massa: 0.603685 kg; EI-GRA-Granito cinza Andorinha (Bancadas, bancos e prateleiras) 3, Área de Seção Transversal do Componente: 0.0107801 m2; EI-GRA-Granito cinza Andorinha (Bancadas, bancos e prateleiras) 3, Volume Componente (Líquido): 0.000215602 m3; EI-GRA-Granito cinza Andorinha (Bancadas, bancos e prateleiras) 3, Volume do componente (Bruto): 0.000215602 m3; EI-GRA-Granito cinza Andorinha (Bancadas, bancos e prateleiras) 4, Massa: 3.75751 kg; EI-GRA-Granito cinza Andorinha (Bancadas, bancos e prateleiras) 4, Altura do Componente Retangular: 0.1 m; EI-GRA-Granito cinza Andorinha (Bancadas, bancos e prateleiras) 4, Largura do Componente Retangular: 0.0220002 m; EI-GRA-Granito cinza Andorinha (Bancadas, bancos e prateleiras) 4, Área de Seção Transversal do Componente: 0.00220002 m2; EI-GRA-Granito cinza Andorinha (Bancadas, bancos e prateleiras) 4, Volume Componente (Líquido): 0.00134197 m3; EI-GRA-Granito cinza Andorinha (Bancadas, bancos e prateleiras) 4, Volume do componente (Bruto): 0.00134197 m3; EI-GRA-Granito cinza Andorinha (Bancadas, bancos e prateleiras) 5, Massa: 18.4118 kg; EI-GRA-Granito cinza Andorinha (Bancadas, bancos e prateleiras) 5, Área de Seção Transversal do Componente: 0.0107801 m2; EI-GRA-Granito cinza Andorinha (Bancadas, bancos e prateleiras) 5, Volume Componente (Líquido): 0.00657565 m3; EI-GRA-Granito cinza Andorinha (Bancadas, bancos e prateleiras) 5, Volume do componente (Bruto): 0.00657565 m3; EI-GRA-Granito cinza Andorinha (Bancadas, bancos e prateleiras) 6, Massa: 1.50301 kg; EI-GRA-Granito cinza Andorinha (Bancadas, bancos e prateleiras) 6, Área de Seção Transversal do Componente: 0.000880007 m2; EI-GRA-Granito cinza Andorinha (Bancadas, bancos e prateleiras) 6, Volume Componente (Líquido): 0.000536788 m3; EI-GRA-Granito cinza Andorinha (Bancadas, bancos e prateleiras) 6, Volume do componente (Bruto): 0.000536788 m3; EI-GRA-Granito cinza Andorinha (Bancadas, bancos e prateleiras) 7, Massa: 0.123315 kg; EI-GRA-Granito cinza Andorinha (Bancadas, bancos e prateleiras) 7, Altura do Componente Retangular: 0.1 m; EI-GRA-Granito cinza Andorinha (Bancadas, bancos e prateleiras) 7, Largura do Componente Retangular: 0.0220001 m; EI-GRA-Granito cinza Andorinha (Bancadas, bancos e prateleiras) 7, Área de Seção Transversal do Componente: 0.00220001 m2; EI-GRA-Granito cinza Andorinha (Bancadas, bancos e prateleiras) 7, Volume Componente (Líquido): 0.000044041 m3; EI-GRA-Granito cinza Andorinha (Bancadas, bancos e prateleiras) 7, Volume do componente (Bruto): 0.000044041 m3; EI-GRA-Granito cinza Andorinha (Bancadas, bancos e prateleiras) 8, Massa: 0.604243 kg; EI-GRA-Granito cinza Andorinha (Bancadas, bancos e prateleiras) 8, Área de Seção Transversal do Componente: 0.0107801 m2; EI-GRA-Granito cinza Andorinha (Bancadas, bancos e prateleiras) 8, Volume Componente (Líquido): 0.000215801 m3; EI-GRA-Granito cinza Andorinha (Bancadas, bancos e prateleiras) 8, Volume do componente (Bruto): 0.000215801 m3; EI-GRA-Granito cinza Andorinha (Bancadas, bancos e prateleiras) 9, Massa: 0.0493259 kg; EI-GRA-Granito cinza Andorinha (Bancadas, bancos e prateleiras) 9, Área de Seção Transversal do Componente: 0.000880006 m2; EI-GRA-Granito cinza Andorinha (Bancadas, bancos e prateleiras) 9, Volume Componente (Líquido): 0.0000176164 m3; EI-GRA-Granito cinza Andorinha (Bancadas, bancos e prateleiras) 9, Volume do componente (Bruto): 0.0000176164 m3; Aço, Massa: 0.635512 kg; Aço, Área de Seção Transversal do Componente: 0.00407003 m2; Aço, Volume Componente (Líquido): 0.0000814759 m3; Aço, Volume do componente (Bruto): 0.0000814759 m3; EI-GRA-Granito cinza Andorinha (Bancadas, bancos e prateleiras) 10, Massa: 6.09845 kg; EI-GRA-Granito cinza Andorinha (Bancadas, bancos e prateleiras) 10, Altura do Componente Retangular: 0.11 m; EI-GRA-Granito cinza Andorinha (Bancadas, bancos e prateleiras) 10, Largura do Componente Retangular: 0.0220002 m; EI-GRA-Granito cinza Andorinha (Bancadas, bancos e prateleiras) 10, Área de Seção Transversal do Componente: 0.00242002 m2; EI-GRA-Granito cinza Andorinha (Bancadas, bancos e prateleiras) 10, Volume Componente (Líquido): 0.00217802 m3; EI-GRA-Granito cinza Andorinha (Bancadas, bancos e prateleiras) 10, Volume do componente (Bruto): 0.00217802 m3; EI-GRA-Granito cinza Andorinha (Bancadas, bancos e prateleiras) 11, Massa: 19.1846 kg; EI-GRA-Granito cinza Andorinha (Bancadas, bancos e prateleiras) 11, Altura do Componente Retangular: 0.02 m; EI-GRA-Granito cinza Andorinha (Bancadas, bancos e prateleiras) 11, Largura do Componente Retangular: 0.528004 m; EI-GRA-Granito cinza Andorinha (Bancadas, bancos e prateleiras) 11, Área de Seção Transversal do Componente: 0.0105601 m2; EI-GRA-Granito cinza Andorinha (Bancadas, bancos e prateleiras) 11, Volume Componente (Líquido): 0.00685165 m3; EI-GRA-Granito cinza Andorinha (Bancadas, bancos e prateleiras) 11, Volume do componente (Bruto): 0.00950407 m3; EI-GRA-Granito cinza Andorinha (Bancadas, bancos e prateleiras) 12, Massa: 2.77202 kg; EI-GRA-Granito cinza Andorinha (Bancadas, bancos e prateleiras) 12, Altura do Componente Retangular: 0.05 m; EI-GRA-Granito cinza Andorinha (Bancadas, bancos e prateleiras) 12, Largura do Componente Retangular: 0.0220002 m; EI-GRA-Granito cinza Andorinha (Bancadas, bancos e prateleiras) 12, Área de Seção Transversal do Componente: 0.00110001 m2; EI-GRA-Granito cinza Andorinha (Bancadas, bancos e prateleiras) 12, Volume Componente (Líquido): 0.000990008 m3; EI-GRA-Granito cinza Andorinha (Bancadas, bancos e prateleiras) 12, Volume do componente (Bruto): 0.000990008 m3; EI-GRA-Granito cinza Andorinha (Bancadas, bancos e prateleiras) 13, Massa: 5.23601 kg; EI-GRA-Granito cinza Andorinha (Bancadas, bancos e prateleiras) 13, Altura do Componente Retangular: 0.22 m; EI-GRA-Granito cinza Andorinha (Bancadas, bancos e prateleiras) 13, Largura do Componente Retangular: 0.55 m; EI-GRA-Granito cinza Andorinha (Bancadas, bancos e prateleiras) 13, Área de Seção Transversal do Componente: 0.121 m2; EI-GRA-Granito cinza Andorinha (Bancadas, bancos e prateleiras) 13, Volume Componente (Líquido): 0.00187 m3; EI-GRA-Granito cinza Andorinha (Bancadas, bancos e prateleiras) 13, Volume do componente (Bruto): 0.00187 m3; EI-GRA-Granito cinza Andorinha (Bancadas, bancos e prateleiras) 14, Massa: 0.924 kg; EI-GRA-Granito cinza Andorinha (Bancadas, bancos e prateleiras) 14, Altura do Componente Retangular: 0.03 m; EI-GRA-Granito cinza Andorinha (Bancadas, bancos e prateleiras) 14, Largura do Componente Retangular: 0.55 m; EI-GRA-Granito cinza Andorinha (Bancadas, bancos e prateleiras) 14, Área de Seção Transversal do Componente: 0.0165 m2; EI-GRA-Granito cinza Andorinha (Bancadas, bancos e prateleiras) 14, Volume Componente (Líquido): 0.00033 m3; EI-GRA-Granito cinza Andorinha (Bancadas, bancos e prateleiras) 14, Volume do componente (Bruto): 0.00033 m3

# IfcFurniture: Várias Estruturas- 5 Segmentos - 550 x 370 x 1570 (20+611+19+900+20), B20
In: TÉRREO
Classification: Mobiliário (Classificação Archicad); Material: EI-GRA-Granito cinza Andorinha (Bancadas, bancos e prateleiras) (14), Aço
FNDE - Pedras: BANCADA - GRANITO CINZA ANDORINHA - esp. 2 cm; 1_Bloco: BLOCO B; 0_ID: B20
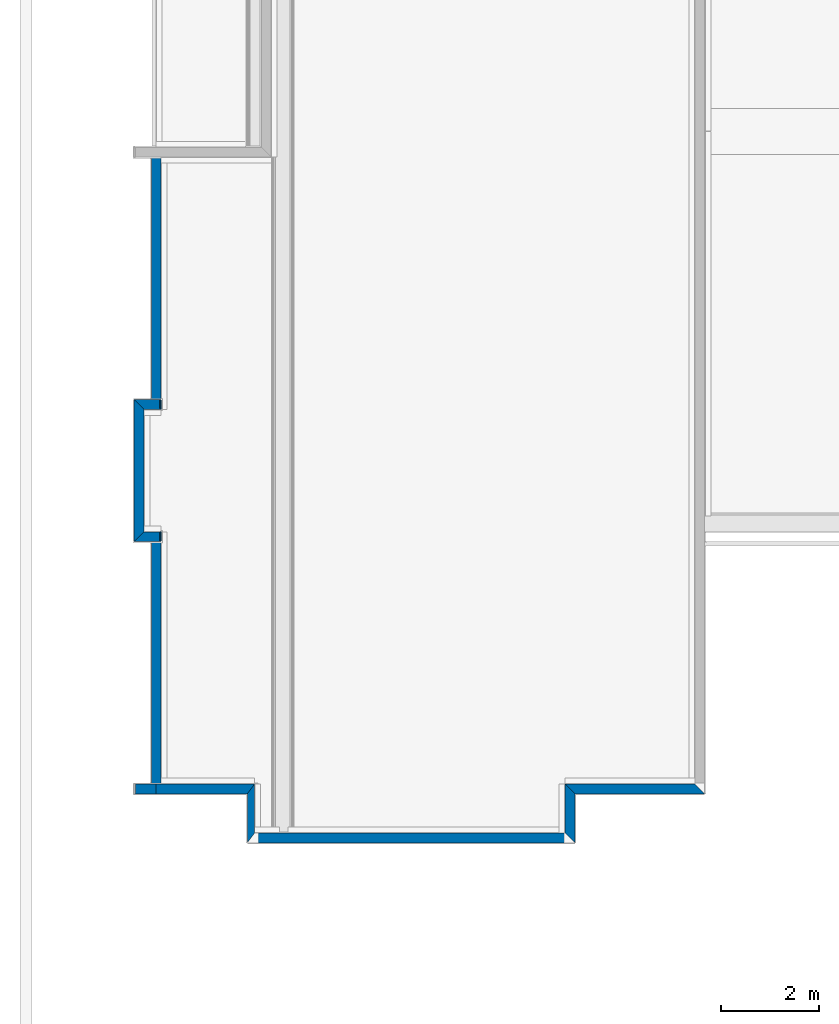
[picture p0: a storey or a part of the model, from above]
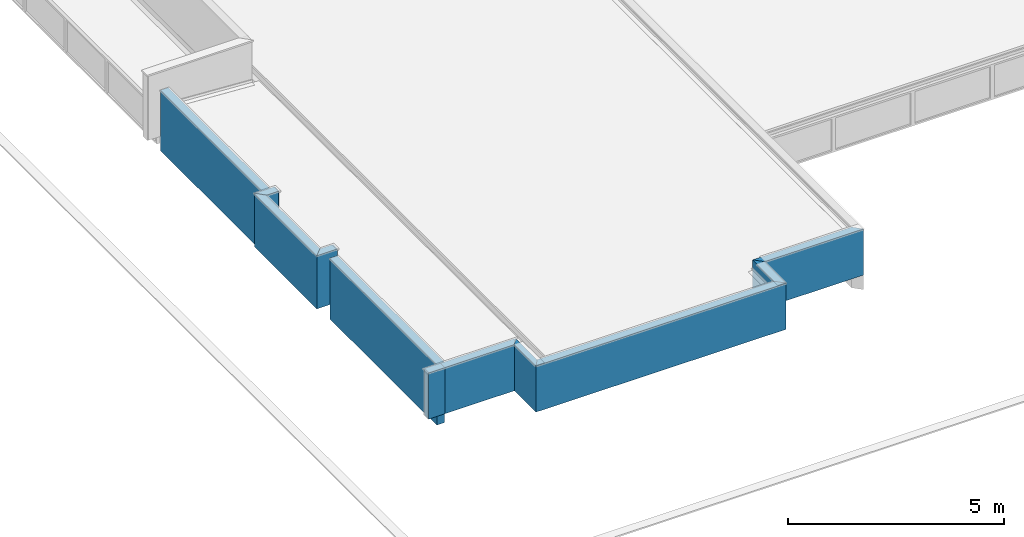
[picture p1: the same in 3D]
Properties of the parts of a building model (IFC4), part 6 of 22

# IfcFurniture: Várias Estruturas- 5 Segmentos - 550 x 370 x 1570 (20+611+19+900+20), B20
Component Quantities - EI-GRA-Granito cinza Andorinha (Bancadas, bancos e prateleiras) 1, Massa: 0.0492804 kg; EI-GRA-Granito cinza Andorinha (Bancadas, bancos e prateleiras) 1, Área de Seção Transversal do Componente: 0.000880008 m2; EI-GRA-Granito cinza Andorinha (Bancadas, bancos e prateleiras) 1, Volume Componente (Líquido): 0.0000176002 m3; EI-GRA-Granito cinza Andorinha (Bancadas, bancos e prateleiras) 1, Volume do componente (Bruto): 0.0000176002 m3; EI-GRA-Granito cinza Andorinha (Bancadas, bancos e prateleiras) 2, Massa: 3.08003 kg; EI-GRA-Granito cinza Andorinha (Bancadas, bancos e prateleiras) 2, Altura do Componente Retangular: 0.1 m; EI-GRA-Granito cinza Andorinha (Bancadas, bancos e prateleiras) 2, Largura do Componente Retangular: 0.550005 m; EI-GRA-Granito cinza Andorinha (Bancadas, bancos e prateleiras) 2, Área de Seção Transversal do Componente: 0.0550005 m2; EI-GRA-Granito cinza Andorinha (Bancadas, bancos e prateleiras) 2, Volume Componente (Líquido): 0.00110001 m3; EI-GRA-Granito cinza Andorinha (Bancadas, bancos e prateleiras) 2, Volume do componente (Bruto): 0.00110001 m3; EI-GRA-Granito cinza Andorinha (Bancadas, bancos e prateleiras) 3, Massa: 0.603685 kg; EI-GRA-Granito cinza Andorinha (Bancadas, bancos e prateleiras) 3, Área de Seção Transversal do Componente: 0.0107801 m2; EI-GRA-Granito cinza Andorinha (Bancadas, bancos e prateleiras) 3, Volume Componente (Líquido): 0.000215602 m3; EI-GRA-Granito cinza Andorinha (Bancadas, bancos e prateleiras) 3, Volume do componente (Bruto): 0.000215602 m3; EI-GRA-Granito cinza Andorinha (Bancadas, bancos e prateleiras) 4, Massa: 3.76307 kg; EI-GRA-Granito cinza Andorinha (Bancadas, bancos e prateleiras) 4, Altura do Componente Retangular: 0.1 m; EI-GRA-Granito cinza Andorinha (Bancadas, bancos e prateleiras) 4, Largura do Componente Retangular: 0.0220002 m; EI-GRA-Granito cinza Andorinha (Bancadas, bancos e prateleiras) 4, Área de Seção Transversal do Componente: 0.00220002 m2; EI-GRA-Granito cinza Andorinha (Bancadas, bancos e prateleiras) 4, Volume Componente (Líquido): 0.00134395 m3; EI-GRA-Granito cinza Andorinha (Bancadas, bancos e prateleiras) 4, Volume do componente (Bruto): 0.00134395 m3; EI-GRA-Granito cinza Andorinha (Bancadas, bancos e prateleiras) 5, Massa: 18.439 kg; EI-GRA-Granito cinza Andorinha (Bancadas, bancos e prateleiras) 5, Área de Seção Transversal do Componente: 0.0107801 m2; EI-GRA-Granito cinza Andorinha (Bancadas, bancos e prateleiras) 5, Volume Componente (Líquido): 0.00658537 m3; EI-GRA-Granito cinza Andorinha (Bancadas, bancos e prateleiras) 5, Volume do componente (Bruto): 0.00658537 m3; EI-GRA-Granito cinza Andorinha (Bancadas, bancos e prateleiras) 6, Massa: 1.50523 kg; EI-GRA-Granito cinza Andorinha (Bancadas, bancos e prateleiras) 6, Área de Seção Transversal do Componente: 0.000880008 m2; EI-GRA-Granito cinza Andorinha (Bancadas, bancos e prateleiras) 6, Volume Componente (Líquido): 0.000537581 m3; EI-GRA-Granito cinza Andorinha (Bancadas, bancos e prateleiras) 6, Volume do componente (Bruto): 0.000537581 m3; EI-GRA-Granito cinza Andorinha (Bancadas, bancos e prateleiras) 7, Massa: 0.117767 kg; EI-GRA-Granito cinza Andorinha (Bancadas, bancos e prateleiras) 7, Altura do Componente Retangular: 0.1 m; EI-GRA-Granito cinza Andorinha (Bancadas, bancos e prateleiras) 7, Largura do Componente Retangular: 0.0220001 m; EI-GRA-Granito cinza Andorinha (Bancadas, bancos e prateleiras) 7, Área de Seção Transversal do Componente: 0.00220001 m2; EI-GRA-Granito cinza Andorinha (Bancadas, bancos e prateleiras) 7, Volume Componente (Líquido): 0.0000420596 m3; EI-GRA-Granito cinza Andorinha (Bancadas, bancos e prateleiras) 7, Volume do componente (Bruto): 0.0000420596 m3; EI-GRA-Granito cinza Andorinha (Bancadas, bancos e prateleiras) 8, Massa: 0.577057 kg; EI-GRA-Granito cinza Andorinha (Bancadas, bancos e prateleiras) 8, Área de Seção Transversal do Componente: 0.0107801 m2; EI-GRA-Granito cinza Andorinha (Bancadas, bancos e prateleiras) 8, Volume Componente (Líquido): 0.000206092 m3; EI-GRA-Granito cinza Andorinha (Bancadas, bancos e prateleiras) 8, Volume do componente (Bruto): 0.000206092 m3; EI-GRA-Granito cinza Andorinha (Bancadas, bancos e prateleiras) 9, Massa: 0.0471067 kg; EI-GRA-Granito cinza Andorinha (Bancadas, bancos e prateleiras) 9, Área de Seção Transversal do Componente: 0.000880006 m2; EI-GRA-Granito cinza Andorinha (Bancadas, bancos e prateleiras) 9, Volume Componente (Líquido): 0.0000168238 m3; EI-GRA-Granito cinza Andorinha (Bancadas, bancos e prateleiras) 9, Volume do componente (Bruto): 0.0000168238 m3; Aço, Massa: 0.60692 kg; Aço, Área de Seção Transversal do Componente: 0.00407003 m2; Aço, Volume Componente (Líquido): 0.0000778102 m3; Aço, Volume do componente (Bruto): 0.0000778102 m3; EI-GRA-Granito cinza Andorinha (Bancadas, bancos e prateleiras) 10, Massa: 6.09846 kg; EI-GRA-Granito cinza Andorinha (Bancadas, bancos e prateleiras) 10, Altura do Componente Retangular: 0.11 m; EI-GRA-Granito cinza Andorinha (Bancadas, bancos e prateleiras) 10, Largura do Componente Retangular: 0.0220002 m; EI-GRA-Granito cinza Andorinha (Bancadas, bancos e prateleiras) 10, Área de Seção Transversal do Componente: 0.00242002 m2; EI-GRA-Granito cinza Andorinha (Bancadas, bancos e prateleiras) 10, Volume Componente (Líquido): 0.00217802 m3; EI-GRA-Granito cinza Andorinha (Bancadas, bancos e prateleiras) 10, Volume do componente (Bruto): 0.00217802 m3; EI-GRA-Granito cinza Andorinha (Bancadas, bancos e prateleiras) 11, Massa: 19.1846 kg; EI-GRA-Granito cinza Andorinha (Bancadas, bancos e prateleiras) 11, Altura do Componente Retangular: 0.02 m; EI-GRA-Granito cinza Andorinha (Bancadas, bancos e prateleiras) 11, Largura do Componente Retangular: 0.528005 m; EI-GRA-Granito cinza Andorinha (Bancadas, bancos e prateleiras) 11, Área de Seção Transversal do Componente: 0.0105601 m2; EI-GRA-Granito cinza Andorinha (Bancadas, bancos e prateleiras) 11, Volume Componente (Líquido): 0.00685166 m3; EI-GRA-Granito cinza Andorinha (Bancadas, bancos e prateleiras) 11, Volume do componente (Bruto): 0.00950409 m3; EI-GRA-Granito cinza Andorinha (Bancadas, bancos e prateleiras) 12, Massa: 2.77203 kg; EI-GRA-Granito cinza Andorinha (Bancadas, bancos e prateleiras) 12, Altura do Componente Retangular: 0.05 m; EI-GRA-Granito cinza Andorinha (Bancadas, bancos e prateleiras) 12, Largura do Componente Retangular: 0.0220002 m; EI-GRA-Granito cinza Andorinha (Bancadas, bancos e prateleiras) 12, Área de Seção Transversal do Componente: 0.00110001 m2; EI-GRA-Granito cinza Andorinha (Bancadas, bancos e prateleiras) 12, Volume Componente (Líquido): 0.000990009 m3; EI-GRA-Granito cinza Andorinha (Bancadas, bancos e prateleiras) 12, Volume do componente (Bruto): 0.000990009 m3; EI-GRA-Granito cinza Andorinha (Bancadas, bancos e prateleiras) 13, Massa: 5.23601 kg; EI-GRA-Granito cinza Andorinha (Bancadas, bancos e prateleiras) 13, Altura do Componente Retangular: 0.22 m; EI-GRA-Granito cinza Andorinha (Bancadas, bancos e prateleiras) 13, Largura do Componente Retangular: 0.55 m; EI-GRA-Granito cinza Andorinha (Bancadas, bancos e prateleiras) 13, Área de Seção Transversal do Componente: 0.121 m2; EI-GRA-Granito cinza Andorinha (Bancadas, bancos e prateleiras) 13, Volume Componente (Líquido): 0.00187 m3; EI-GRA-Granito cinza Andorinha (Bancadas, bancos e prateleiras) 13, Volume do componente (Bruto): 0.00187 m3; EI-GRA-Granito cinza Andorinha (Bancadas, bancos e prateleiras) 14, Massa: 0.924 kg; EI-GRA-Granito cinza Andorinha (Bancadas, bancos e prateleiras) 14, Altura do Componente Retangular: 0.03 m; EI-GRA-Granito cinza Andorinha (Bancadas, bancos e prateleiras) 14, Largura do Componente Retangular: 0.55 m; EI-GRA-Granito cinza Andorinha (Bancadas, bancos e prateleiras) 14, Área de Seção Transversal do Componente: 0.0165 m2; EI-GRA-Granito cinza Andorinha (Bancadas, bancos e prateleiras) 14, Volume Componente (Líquido): 0.00033 m3; EI-GRA-Granito cinza Andorinha (Bancadas, bancos e prateleiras) 14, Volume do componente (Bruto): 0.00033 m3

# IfcFurniture: Várias Estruturas- 5 Segmentos - 600 x 150 x 4047 (500+1200+550+1197+600), B11
In: TÉRREO
Classification: Mobiliário (Classificação Archicad); Material: EI-GRA-Granito cinza Andorinha (Bancadas, bancos e prateleiras) (15)
FNDE - Pedras: BANCADA - GRANITO CINZA ANDORINHA - esp. 2 cm; 1_Bloco: BLOCO A; 0_ID: B11
Component Quantities - EI-GRA-Granito cinza Andorinha (Bancadas, bancos e prateleiras) 1, Massa: 3.29281 kg; EI-GRA-Granito cinza Andorinha (Bancadas, bancos e prateleiras) 1, Altura do Componente Retangular: 0.1 m; EI-GRA-Granito cinza Andorinha (Bancadas, bancos e prateleiras) 1, Largura do Componente Retangular: 0.024 m; EI-GRA-Granito cinza Andorinha (Bancadas, bancos e prateleiras) 1, Área de Seção Transversal do Componente: 0.0024 m2; EI-GRA-Granito cinza Andorinha (Bancadas, bancos e prateleiras) 1, Volume Componente (Líquido): 0.001176 m3; EI-GRA-Granito cinza Andorinha (Bancadas, bancos e prateleiras) 1, Volume do componente (Bruto): 0.001176 m3; EI-GRA-Granito cinza Andorinha (Bancadas, bancos e prateleiras) 2, Massa: 8.39704 kg; EI-GRA-Granito cinza Andorinha (Bancadas, bancos e prateleiras) 2, Área de Seção Transversal do Componente: 0.01176 m2; EI-GRA-Granito cinza Andorinha (Bancadas, bancos e prateleiras) 2, Volume Componente (Líquido): 0.00299894 m3; EI-GRA-Granito cinza Andorinha (Bancadas, bancos e prateleiras) 2, Volume do componente (Bruto): 0.00299894 m3; EI-GRA-Granito cinza Andorinha (Bancadas, bancos e prateleiras) 3, Massa: 0.0248884 kg; EI-GRA-Granito cinza Andorinha (Bancadas, bancos e prateleiras) 3, Área de Seção Transversal do Componente: 0.00096 m2; EI-GRA-Granito cinza Andorinha (Bancadas, bancos e prateleiras) 3, Volume Componente (Líquido): 0.00000888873 m3; EI-GRA-Granito cinza Andorinha (Bancadas, bancos e prateleiras) 3, Volume do componente (Bruto): 0.00000888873 m3; EI-GRA-Granito cinza Andorinha (Bancadas, bancos e prateleiras) 4, Massa: 8.8704 kg; EI-GRA-Granito cinza Andorinha (Bancadas, bancos e prateleiras) 4, Altura do Componente Retangular: 0.11 m; EI-GRA-Granito cinza Andorinha (Bancadas, bancos e prateleiras) 4, Largura do Componente Retangular: 0.024 m; EI-GRA-Granito cinza Andorinha (Bancadas, bancos e prateleiras) 4, Área de Seção Transversal do Componente: 0.00264 m2; EI-GRA-Granito cinza Andorinha (Bancadas, bancos e prateleiras) 4, Volume Componente (Líquido): 0.003168 m3; EI-GRA-Granito cinza Andorinha (Bancadas, bancos e prateleiras) 4, Volume do componente (Bruto): 0.003168 m3; EI-GRA-Granito cinza Andorinha (Bancadas, bancos e prateleiras) 5, Massa: 27.6964 kg; EI-GRA-Granito cinza Andorinha (Bancadas, bancos e prateleiras) 5, Altura do Componente Retangular: 0.02 m; EI-GRA-Granito cinza Andorinha (Bancadas, bancos e prateleiras) 5, Largura do Componente Retangular: 0.576 m; EI-GRA-Granito cinza Andorinha (Bancadas, bancos e prateleiras) 5, Área de Seção Transversal do Componente: 0.01152 m2; EI-GRA-Granito cinza Andorinha (Bancadas, bancos e prateleiras) 5, Volume Componente (Líquido): 0.00989158 m3; EI-GRA-Granito cinza Andorinha (Bancadas, bancos e prateleiras) 5, Volume do componente (Bruto): 0.013824 m3; EI-GRA-Granito cinza Andorinha (Bancadas, bancos e prateleiras) 6, Massa: 4.032 kg; EI-GRA-Granito cinza Andorinha (Bancadas, bancos e prateleiras) 6, Altura do Componente Retangular: 0.05 m; EI-GRA-Granito cinza Andorinha (Bancadas, bancos e prateleiras) 6, Largura do Componente Retangular: 0.024 m; EI-GRA-Granito cinza Andorinha (Bancadas, bancos e prateleiras) 6, Área de Seção Transversal do Componente: 0.0012 m2; EI-GRA-Granito cinza Andorinha (Bancadas, bancos e prateleiras) 6, Volume Componente (Líquido): 0.00144 m3; EI-GRA-Granito cinza Andorinha (Bancadas, bancos e prateleiras) 6, Volume do componente (Bruto): 0.00144 m3; EI-GRA-Granito cinza Andorinha (Bancadas, bancos e prateleiras) 7, Massa: 3.696 kg; EI-GRA-Granito cinza Andorinha (Bancadas, bancos e prateleiras) 7, Altura do Componente Retangular: 0.1 m; EI-GRA-Granito cinza Andorinha (Bancadas, bancos e prateleiras) 7, Largura do Componente Retangular: 0.024 m; EI-GRA-Granito cinza Andorinha (Bancadas, bancos e prateleiras) 7, Área de Seção Transversal do Componente: 0.0024 m2; EI-GRA-Granito cinza Andorinha (Bancadas, bancos e prateleiras) 7, Volume Componente (Líquido): 0.00132 m3; EI-GRA-Granito cinza Andorinha (Bancadas, bancos e prateleiras) 7, Volume do componente (Bruto): 0.00132 m3; EI-GRA-Granito cinza Andorinha (Bancadas, bancos e prateleiras) 8, Massa: 18.1104 kg; EI-GRA-Granito cinza Andorinha (Bancadas, bancos e prateleiras) 8, Área de Seção Transversal do Componente: 0.01176 m2; EI-GRA-Granito cinza Andorinha (Bancadas, bancos e prateleiras) 8, Volume Componente (Líquido): 0.006468 m3; EI-GRA-Granito cinza Andorinha (Bancadas, bancos e prateleiras) 8, Volume do componente (Bruto): 0.006468 m3; EI-GRA-Granito cinza Andorinha (Bancadas, bancos e prateleiras) 9, Massa: 1.4784 kg; EI-GRA-Granito cinza Andorinha (Bancadas, bancos e prateleiras) 9, Área de Seção Transversal do Componente: 0.00096 m2; EI-GRA-Granito cinza Andorinha (Bancadas, bancos e prateleiras) 9, Volume Componente (Líquido): 0.000528 m3; EI-GRA-Granito cinza Andorinha (Bancadas, bancos e prateleiras) 9, Volume do componente (Bruto): 0.000528 m3; EI-GRA-Granito cinza Andorinha (Bancadas, bancos e prateleiras) 10, Massa: 8.85096 kg; EI-GRA-Granito cinza Andorinha (Bancadas, bancos e prateleiras) 10, Altura do Componente Retangular: 0.11 m; EI-GRA-Granito cinza Andorinha (Bancadas, bancos e prateleiras) 10, Largura do Componente Retangular: 0.024 m; EI-GRA-Granito cinza Andorinha (Bancadas, bancos e prateleiras) 10, Área de Seção Transversal do Componente: 0.00264 m2; EI-GRA-Granito cinza Andorinha (Bancadas, bancos e prateleiras) 10, Volume Componente (Líquido): 0.00316106 m3; EI-GRA-Granito cinza Andorinha (Bancadas, bancos e prateleiras) 10, Volume do componente (Bruto): 0.00316106 m3; EI-GRA-Granito cinza Andorinha (Bancadas, bancos e prateleiras) 11, Massa: 27.6116 kg; EI-GRA-Granito cinza Andorinha (Bancadas, bancos e prateleiras) 11, Altura do Componente Retangular: 0.02 m; EI-GRA-Granito cinza Andorinha (Bancadas, bancos e prateleiras) 11, Largura do Componente Retangular: 0.576 m; EI-GRA-Granito cinza Andorinha (Bancadas, bancos e prateleiras) 11, Área de Seção Transversal do Componente: 0.01152 m2; EI-GRA-Granito cinza Andorinha (Bancadas, bancos e prateleiras) 11, Volume Componente (Líquido): 0.00986129 m3; EI-GRA-Granito cinza Andorinha (Bancadas, bancos e prateleiras) 11, Volume do componente (Bruto): 0.0137937 m3; EI-GRA-Granito cinza Andorinha (Bancadas, bancos e prateleiras) 12, Massa: 4.02317 kg; EI-GRA-Granito cinza Andorinha (Bancadas, bancos e prateleiras) 12, Altura do Componente Retangular: 0.05 m; EI-GRA-Granito cinza Andorinha (Bancadas, bancos e prateleiras) 12, Largura do Componente Retangular: 0.024 m; EI-GRA-Granito cinza Andorinha (Bancadas, bancos e prateleiras) 12, Área de Seção Transversal do Componente: 0.0012 m2; EI-GRA-Granito cinza Andorinha (Bancadas, bancos e prateleiras) 12, Volume Componente (Líquido): 0.00143684 m3; EI-GRA-Granito cinza Andorinha (Bancadas, bancos e prateleiras) 12, Volume do componente (Bruto): 0.00143684 m3; EI-GRA-Granito cinza Andorinha (Bancadas, bancos e prateleiras) 13, Massa: 3.95198 kg; EI-GRA-Granito cinza Andorinha (Bancadas, bancos e prateleiras) 13, Altura do Componente Retangular: 0.1 m; EI-GRA-Granito cinza Andorinha (Bancadas, bancos e prateleiras) 13, Largura do Componente Retangular: 0.024 m; EI-GRA-Granito cinza Andorinha (Bancadas, bancos e prateleiras) 13, Área de Seção Transversal do Componente: 0.0024 m2; EI-GRA-Granito cinza Andorinha (Bancadas, bancos e prateleiras) 13, Volume Componente (Líquido): 0.00141142 m3; EI-GRA-Granito cinza Andorinha (Bancadas, bancos e prateleiras) 13, Volume do componente (Bruto): 0.00141142 m3; EI-GRA-Granito cinza Andorinha (Bancadas, bancos e prateleiras) 14, Massa: 10.0762 kg; EI-GRA-Granito cinza Andorinha (Bancadas, bancos e prateleiras) 14, Área de Seção Transversal do Componente: 0.01176 m2; EI-GRA-Granito cinza Andorinha (Bancadas, bancos e prateleiras) 14, Volume Componente (Líquido): 0.00359864 m3; EI-GRA-Granito cinza Andorinha (Bancadas, bancos e prateleiras) 14, Volume do componente (Bruto): 0.00359864 m3; EI-GRA-Granito cinza Andorinha (Bancadas, bancos e prateleiras) 15, Massa: 0.0295726 kg; EI-GRA-Granito cinza Andorinha (Bancadas, bancos e prateleiras) 15, Área de Seção Transversal do Componente: 0.00096 m2; EI-GRA-Granito cinza Andorinha (Bancadas, bancos e prateleiras) 15, Volume Componente (Líquido): 0.0000105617 m3; EI-GRA-Granito cinza Andorinha (Bancadas, bancos e prateleiras) 15, Volume do componente (Bruto): 0.0000105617 m3

# IfcFurniture: Várias Estruturas- 5 Segmentos - 700 x 150 x 4800 (20+1380+2015+1365+20), B02
In: TÉRREO
Classification: Mobiliário (Classificação Archicad); Material: EI-GRA-Granito cinza Andorinha (Bancadas, bancos e prateleiras) (15)
FNDE - Pedras: BANCADA - GRANITO CINZA ANDORINHA - esp. 2 cm; 1_Bloco: BLOCO A; 0_ID: B02
Component Quantities - EI-GRA-Granito cinza Andorinha (Bancadas, bancos e prateleiras) 1, Massa: 4.312 kg; EI-GRA-Granito cinza Andorinha (Bancadas, bancos e prateleiras) 1, Altura do Componente Retangular: 0.11 m; EI-GRA-Granito cinza Andorinha (Bancadas, bancos e prateleiras) 1, Largura do Componente Retangular: 0.7 m; EI-GRA-Granito cinza Andorinha (Bancadas, bancos e prateleiras) 1, Área de Seção Transversal do Componente: 0.077 m2; EI-GRA-Granito cinza Andorinha (Bancadas, bancos e prateleiras) 1, Volume Componente (Líquido): 0.00154 m3; EI-GRA-Granito cinza Andorinha (Bancadas, bancos e prateleiras) 1, Volume do componente (Bruto): 0.00154 m3; EI-GRA-Granito cinza Andorinha (Bancadas, bancos e prateleiras) 2, Massa: 0.75264 kg; EI-GRA-Granito cinza Andorinha (Bancadas, bancos e prateleiras) 2, Altura do Componente Retangular: 0.02 m; EI-GRA-Granito cinza Andorinha (Bancadas, bancos e prateleiras) 2, Largura do Componente Retangular: 0.672 m; EI-GRA-Granito cinza Andorinha (Bancadas, bancos e prateleiras) 2, Área de Seção Transversal do Componente: 0.01344 m2; EI-GRA-Granito cinza Andorinha (Bancadas, bancos e prateleiras) 2, Volume Componente (Líquido): 0.0002688 m3; EI-GRA-Granito cinza Andorinha (Bancadas, bancos e prateleiras) 2, Volume do componente (Bruto): 0.0002688 m3; EI-GRA-Granito cinza Andorinha (Bancadas, bancos e prateleiras) 3, Massa: 0.06272 kg; EI-GRA-Granito cinza Andorinha (Bancadas, bancos e prateleiras) 3, Altura do Componente Retangular: 0.04 m; EI-GRA-Granito cinza Andorinha (Bancadas, bancos e prateleiras) 3, Largura do Componente Retangular: 0.028 m; EI-GRA-Granito cinza Andorinha (Bancadas, bancos e prateleiras) 3, Área de Seção Transversal do Componente: 0.00112 m2; EI-GRA-Granito cinza Andorinha (Bancadas, bancos e prateleiras) 3, Volume Componente (Líquido): 0.0000224 m3; EI-GRA-Granito cinza Andorinha (Bancadas, bancos e prateleiras) 3, Volume do componente (Bruto): 0.0000224 m3; EI-GRA-Granito cinza Andorinha (Bancadas, bancos e prateleiras) 4, Massa: 11.9013 kg; EI-GRA-Granito cinza Andorinha (Bancadas, bancos e prateleiras) 4, Altura do Componente Retangular: 0.11 m; EI-GRA-Granito cinza Andorinha (Bancadas, bancos e prateleiras) 4, Largura do Componente Retangular: 0.028 m; EI-GRA-Granito cinza Andorinha (Bancadas, bancos e prateleiras) 4, Área de Seção Transversal do Componente: 0.00308 m2; EI-GRA-Granito cinza Andorinha (Bancadas, bancos e prateleiras) 4, Volume Componente (Líquido): 0.00425048 m3; EI-GRA-Granito cinza Andorinha (Bancadas, bancos e prateleiras) 4, Volume do componente (Bruto): 0.00425048 m3; EI-GRA-Granito cinza Andorinha (Bancadas, bancos e prateleiras) 5, Massa: 31.8365 kg; EI-GRA-Granito cinza Andorinha (Bancadas, bancos e prateleiras) 5, Altura do Componente Retangular: 0.02 m; EI-GRA-Granito cinza Andorinha (Bancadas, bancos e prateleiras) 5, Largura do Componente Retangular: 0.672 m; EI-GRA-Granito cinza Andorinha (Bancadas, bancos e prateleiras) 5, Área de Seção Transversal do Componente: 0.01344 m2; EI-GRA-Granito cinza Andorinha (Bancadas, bancos e prateleiras) 5, Volume Componente (Líquido): 0.0113702 m3; EI-GRA-Granito cinza Andorinha (Bancadas, bancos e prateleiras) 5, Volume do componente (Bruto): 0.0183002 m3; EI-GRA-Granito cinza Andorinha (Bancadas, bancos e prateleiras) 6, Massa: 5.4097 kg; EI-GRA-Granito cinza Andorinha (Bancadas, bancos e prateleiras) 6, Altura do Componente Retangular: 0.05 m; EI-GRA-Granito cinza Andorinha (Bancadas, bancos e prateleiras) 6, Largura do Componente Retangular: 0.028 m; EI-GRA-Granito cinza Andorinha (Bancadas, bancos e prateleiras) 6, Área de Seção Transversal do Componente: 0.0014 m2; EI-GRA-Granito cinza Andorinha (Bancadas, bancos e prateleiras) 6, Volume Componente (Líquido): 0.00193204 m3; EI-GRA-Granito cinza Andorinha (Bancadas, bancos e prateleiras) 6, Volume do componente (Bruto): 0.00193204 m3; EI-GRA-Granito cinza Andorinha (Bancadas, bancos e prateleiras) 7, Massa: 15.7984 kg; EI-GRA-Granito cinza Andorinha (Bancadas, bancos e prateleiras) 7, Altura do Componente Retangular: 0.1 m; EI-GRA-Granito cinza Andorinha (Bancadas, bancos e prateleiras) 7, Largura do Componente Retangular: 0.028 m; EI-GRA-Granito cinza Andorinha (Bancadas, bancos e prateleiras) 7, Área de Seção Transversal do Componente: 0.0028 m2; EI-GRA-Granito cinza Andorinha (Bancadas, bancos e prateleiras) 7, Volume Componente (Líquido): 0.00564228 m3; EI-GRA-Granito cinza Andorinha (Bancadas, bancos e prateleiras) 7, Volume do componente (Bruto): 0.00564228 m3; EI-GRA-Granito cinza Andorinha (Bancadas, bancos e prateleiras) 8, Massa: 77.4121 kg; EI-GRA-Granito cinza Andorinha (Bancadas, bancos e prateleiras) 8, Área de Seção Transversal do Componente: 0.01372 m2; EI-GRA-Granito cinza Andorinha (Bancadas, bancos e prateleiras) 8, Volume Componente (Líquido): 0.0276472 m3; EI-GRA-Granito cinza Andorinha (Bancadas, bancos e prateleiras) 8, Volume do componente (Bruto): 0.0276472 m3; EI-GRA-Granito cinza Andorinha (Bancadas, bancos e prateleiras) 9, Massa: 6.31935 kg; EI-GRA-Granito cinza Andorinha (Bancadas, bancos e prateleiras) 9, Área de Seção Transversal do Componente: 0.00112 m2; EI-GRA-Granito cinza Andorinha (Bancadas, bancos e prateleiras) 9, Volume Componente (Líquido): 0.00225691 m3; EI-GRA-Granito cinza Andorinha (Bancadas, bancos e prateleiras) 9, Volume do componente (Bruto): 0.00225691 m3; EI-GRA-Granito cinza Andorinha (Bancadas, bancos e prateleiras) 10, Massa: 11.7709 kg; EI-GRA-Granito cinza Andorinha (Bancadas, bancos e prateleiras) 10, Altura do Componente Retangular: 0.11 m; EI-GRA-Granito cinza Andorinha (Bancadas, bancos e prateleiras) 10, Largura do Componente Retangular: 0.028 m; EI-GRA-Granito cinza Andorinha (Bancadas, bancos e prateleiras) 10, Área de Seção Transversal do Componente: 0.00308 m2; EI-GRA-Granito cinza Andorinha (Bancadas, bancos e prateleiras) 10, Volume Componente (Líquido): 0.00420389 m3; EI-GRA-Granito cinza Andorinha (Bancadas, bancos e prateleiras) 10, Volume do componente (Bruto): 0.00420389 m3; EI-GRA-Granito cinza Andorinha (Bancadas, bancos e prateleiras) 11, Massa: 31.9599 kg; EI-GRA-Granito cinza Andorinha (Bancadas, bancos e prateleiras) 11, Altura do Componente Retangular: 0.02 m; EI-GRA-Granito cinza Andorinha (Bancadas, bancos e prateleiras) 11, Largura do Componente Retangular: 0.672 m; EI-GRA-Granito cinza Andorinha (Bancadas, bancos e prateleiras) 11, Área de Seção Transversal do Componente: 0.01344 m2; EI-GRA-Granito cinza Andorinha (Bancadas, bancos e prateleiras) 11, Volume Componente (Líquido): 0.0114143 m3; EI-GRA-Granito cinza Andorinha (Bancadas, bancos e prateleiras) 11, Volume do componente (Bruto): 0.0183443 m3; EI-GRA-Granito cinza Andorinha (Bancadas, bancos e prateleiras) 12, Massa: 5.35041 kg; EI-GRA-Granito cinza Andorinha (Bancadas, bancos e prateleiras) 12, Altura do Componente Retangular: 0.05 m; EI-GRA-Granito cinza Andorinha (Bancadas, bancos e prateleiras) 12, Largura do Componente Retangular: 0.028 m; EI-GRA-Granito cinza Andorinha (Bancadas, bancos e prateleiras) 12, Área de Seção Transversal do Componente: 0.0014 m2; EI-GRA-Granito cinza Andorinha (Bancadas, bancos e prateleiras) 12, Volume Componente (Líquido): 0.00191086 m3; EI-GRA-Granito cinza Andorinha (Bancadas, bancos e prateleiras) 12, Volume do componente (Bruto): 0.00191086 m3; EI-GRA-Granito cinza Andorinha (Bancadas, bancos e prateleiras) 1: 2 with these values; EI-GRA-Granito cinza Andorinha (Bancadas, bancos e prateleiras) 2: 2 with these values; EI-GRA-Granito cinza Andorinha (Bancadas, bancos e prateleiras) 3: 2 with these values

# IfcFurniture: Várias Estruturas- 5 Segmentos - 700 x 370 x 1550 (20+745+20+745+20), B21
In: TÉRREO
Classification: Mobiliário (Classificação Archicad); Material: EI-GRA-Granito cinza Andorinha (Bancadas, bancos e prateleiras) (15), Aço
FNDE - Pedras: BANCADA - GRANITO CINZA ANDORINHA - esp. 2 cm; 1_Bloco: BLOCO B; 0_ID: B21
Component Quantities - EI-GRA-Granito cinza Andorinha (Bancadas, bancos e prateleiras) 1, Massa: 0.06272 kg; EI-GRA-Granito cinza Andorinha (Bancadas, bancos e prateleiras) 1, Área de Seção Transversal do Componente: 0.00112 m2; EI-GRA-Granito cinza Andorinha (Bancadas, bancos e prateleiras) 1, Volume Componente (Líquido): 0.0000224 m3; EI-GRA-Granito cinza Andorinha (Bancadas, bancos e prateleiras) 1, Volume do componente (Bruto): 0.0000224 m3; EI-GRA-Granito cinza Andorinha (Bancadas, bancos e prateleiras) 2, Massa: 3.92 kg; EI-GRA-Granito cinza Andorinha (Bancadas, bancos e prateleiras) 2, Altura do Componente Retangular: 0.1 m; EI-GRA-Granito cinza Andorinha (Bancadas, bancos e prateleiras) 2, Largura do Componente Retangular: 0.7 m; EI-GRA-Granito cinza Andorinha (Bancadas, bancos e prateleiras) 2, Área de Seção Transversal do Componente: 0.07 m2; EI-GRA-Granito cinza Andorinha (Bancadas, bancos e prateleiras) 2, Volume Componente (Líquido): 0.0014 m3; EI-GRA-Granito cinza Andorinha (Bancadas, bancos e prateleiras) 2, Volume do componente (Bruto): 0.0014 m3; EI-GRA-Granito cinza Andorinha (Bancadas, bancos e prateleiras) 3, Massa: 0.76832 kg; EI-GRA-Granito cinza Andorinha (Bancadas, bancos e prateleiras) 3, Área de Seção Transversal do Componente: 0.01372 m2; EI-GRA-Granito cinza Andorinha (Bancadas, bancos e prateleiras) 3, Volume Componente (Líquido): 0.0002744 m3; EI-GRA-Granito cinza Andorinha (Bancadas, bancos e prateleiras) 3, Volume do componente (Bruto): 0.0002744 m3; EI-GRA-Granito cinza Andorinha (Bancadas, bancos e prateleiras) 4, Massa: 5.8408 kg; EI-GRA-Granito cinza Andorinha (Bancadas, bancos e prateleiras) 4, Altura do Componente Retangular: 0.1 m; EI-GRA-Granito cinza Andorinha (Bancadas, bancos e prateleiras) 4, Largura do Componente Retangular: 0.028 m; EI-GRA-Granito cinza Andorinha (Bancadas, bancos e prateleiras) 4, Área de Seção Transversal do Componente: 0.0028 m2; EI-GRA-Granito cinza Andorinha (Bancadas, bancos e prateleiras) 4, Volume Componente (Líquido): 0.002086 m3; EI-GRA-Granito cinza Andorinha (Bancadas, bancos e prateleiras) 4, Volume do componente (Bruto): 0.002086 m3; EI-GRA-Granito cinza Andorinha (Bancadas, bancos e prateleiras) 5, Massa: 28.6199 kg; EI-GRA-Granito cinza Andorinha (Bancadas, bancos e prateleiras) 5, Área de Seção Transversal do Componente: 0.01372 m2; EI-GRA-Granito cinza Andorinha (Bancadas, bancos e prateleiras) 5, Volume Componente (Líquido): 0.0102214 m3; EI-GRA-Granito cinza Andorinha (Bancadas, bancos e prateleiras) 5, Volume do componente (Bruto): 0.0102214 m3; EI-GRA-Granito cinza Andorinha (Bancadas, bancos e prateleiras) 6, Massa: 2.33632 kg; EI-GRA-Granito cinza Andorinha (Bancadas, bancos e prateleiras) 6, Área de Seção Transversal do Componente: 0.00112 m2; EI-GRA-Granito cinza Andorinha (Bancadas, bancos e prateleiras) 6, Volume Componente (Líquido): 0.0008344 m3; EI-GRA-Granito cinza Andorinha (Bancadas, bancos e prateleiras) 6, Volume do componente (Bruto): 0.0008344 m3; EI-GRA-Granito cinza Andorinha (Bancadas, bancos e prateleiras) 7, Massa: 0.1568 kg; EI-GRA-Granito cinza Andorinha (Bancadas, bancos e prateleiras) 7, Altura do Componente Retangular: 0.1 m; EI-GRA-Granito cinza Andorinha (Bancadas, bancos e prateleiras) 7, Largura do Componente Retangular: 0.028 m; EI-GRA-Granito cinza Andorinha (Bancadas, bancos e prateleiras) 7, Área de Seção Transversal do Componente: 0.0028 m2; EI-GRA-Granito cinza Andorinha (Bancadas, bancos e prateleiras) 7, Volume Componente (Líquido): 0.000056 m3; EI-GRA-Granito cinza Andorinha (Bancadas, bancos e prateleiras) 7, Volume do componente (Bruto): 0.000056 m3; Aço, Massa: 0.80808 kg; Aço, Área de Seção Transversal do Componente: 0.00518 m2; Aço, Volume Componente (Líquido): 0.0001036 m3; Aço, Volume do componente (Bruto): 0.0001036 m3; EI-GRA-Granito cinza Andorinha (Bancadas, bancos e prateleiras) 1: 3 with these values; EI-GRA-Granito cinza Andorinha (Bancadas, bancos e prateleiras) 2: 2 with these values; EI-GRA-Granito cinza Andorinha (Bancadas, bancos e prateleiras) 3: 3 with these values; EI-GRA-Granito cinza Andorinha (Bancadas, bancos e prateleiras) 4: 2 with these values; EI-GRA-Granito cinza Andorinha (Bancadas, bancos e prateleiras) 5: 2 with these values; EI-GRA-Granito cinza Andorinha (Bancadas, bancos e prateleiras) 6: 2 with these values

# IfcFurniture: Várias Estruturas- 7 Segmentos - 300 x 270 x 2100 (100+20+920+20+920+20+100), PTG7
In: TÉRREO
Classification: Mobiliário (Classificação Archicad); Material: EI-GRA-Granito cinza Andorinha (Bancadas, bancos e prateleiras) (7), Aço (3)
FNDE - Pedras: PRATELEIRA - GRANITO CINZA ANDORINHA - esp. 2 cm; 1_Bloco: BLOCO A; 0_ID: PTG7
Component Quantities - EI-GRA-Granito cinza Andorinha (Bancadas, bancos e prateleiras) 1, Massa: 1.68 kg; EI-GRA-Granito cinza Andorinha (Bancadas, bancos e prateleiras) 1, Altura do Componente Retangular: 0.02 m; EI-GRA-Granito cinza Andorinha (Bancadas, bancos e prateleiras) 1, Largura do Componente Retangular: 0.3 m; EI-GRA-Granito cinza Andorinha (Bancadas, bancos e prateleiras) 1, Área de Seção Transversal do Componente: 0.006 m2; EI-GRA-Granito cinza Andorinha (Bancadas, bancos e prateleiras) 1, Volume Componente (Líquido): 0.0006 m3; EI-GRA-Granito cinza Andorinha (Bancadas, bancos e prateleiras) 1, Volume do componente (Bruto): 0.0006 m3; EI-GRA-Granito cinza Andorinha (Bancadas, bancos e prateleiras) 2, Massa: 0.336 kg; EI-GRA-Granito cinza Andorinha (Bancadas, bancos e prateleiras) 2, Altura do Componente Retangular: 0.02 m; EI-GRA-Granito cinza Andorinha (Bancadas, bancos e prateleiras) 2, Largura do Componente Retangular: 0.3 m; EI-GRA-Granito cinza Andorinha (Bancadas, bancos e prateleiras) 2, Área de Seção Transversal do Componente: 0.006 m2; EI-GRA-Granito cinza Andorinha (Bancadas, bancos e prateleiras) 2, Volume Componente (Líquido): 0.00012 m3; EI-GRA-Granito cinza Andorinha (Bancadas, bancos e prateleiras) 2, Volume do componente (Bruto): 0.00012 m3; Aço 1, Massa: 0.5772 kg; Aço 1, Área de Seção Transversal do Componente: 0.0037 m2; Aço 1, Volume Componente (Líquido): 0.000074 m3; Aço 1, Volume do componente (Bruto): 0.000074 m3; EI-GRA-Granito cinza Andorinha (Bancadas, bancos e prateleiras) 3, Massa: 15.456 kg; EI-GRA-Granito cinza Andorinha (Bancadas, bancos e prateleiras) 3, Altura do Componente Retangular: 0.02 m; EI-GRA-Granito cinza Andorinha (Bancadas, bancos e prateleiras) 3, Largura do Componente Retangular: 0.3 m; EI-GRA-Granito cinza Andorinha (Bancadas, bancos e prateleiras) 3, Área de Seção Transversal do Componente: 0.006 m2; EI-GRA-Granito cinza Andorinha (Bancadas, bancos e prateleiras) 3, Volume Componente (Líquido): 0.00552 m3; EI-GRA-Granito cinza Andorinha (Bancadas, bancos e prateleiras) 3, Volume do componente (Bruto): 0.00552 m3; EI-GRA-Granito cinza Andorinha (Bancadas, bancos e prateleiras) 1: 2 with these values; EI-GRA-Granito cinza Andorinha (Bancadas, bancos e prateleiras) 2: 3 with these values; Aço 1: 3 with these values; EI-GRA-Granito cinza Andorinha (Bancadas, bancos e prateleiras) 3: 2 with these values

# IfcFurniture: Várias Estruturas- 7 Segmentos - 300 x 270 x 2500 (100+20+1120+20+1120+20+100) (3)
In: TÉRREO
Classification: Mobiliário (Classificação Archicad); Material: EI-GRA-Granito cinza Andorinha (Bancadas, bancos e prateleiras) (7), Aço (3)
FNDE - Pedras: PRATELEIRA - GRANITO CINZA ANDORINHA - esp. 2 cm; 0_ID: PTG1
Component Quantities - EI-GRA-Granito cinza Andorinha (Bancadas, bancos e prateleiras) 1, Massa: 1.68 kg; EI-GRA-Granito cinza Andorinha (Bancadas, bancos e prateleiras) 1, Altura do Componente Retangular: 0.02 m; EI-GRA-Granito cinza Andorinha (Bancadas, bancos e prateleiras) 1, Largura do Componente Retangular: 0.3 m; EI-GRA-Granito cinza Andorinha (Bancadas, bancos e prateleiras) 1, Área de Seção Transversal do Componente: 0.006 m2; EI-GRA-Granito cinza Andorinha (Bancadas, bancos e prateleiras) 1, Volume Componente (Líquido): 0.0006 m3; EI-GRA-Granito cinza Andorinha (Bancadas, bancos e prateleiras) 1, Volume do componente (Bruto): 0.0006 m3; EI-GRA-Granito cinza Andorinha (Bancadas, bancos e prateleiras) 2, Massa: 0.336 kg; EI-GRA-Granito cinza Andorinha (Bancadas, bancos e prateleiras) 2, Altura do Componente Retangular: 0.02 m; EI-GRA-Granito cinza Andorinha (Bancadas, bancos e prateleiras) 2, Largura do Componente Retangular: 0.3 m; EI-GRA-Granito cinza Andorinha (Bancadas, bancos e prateleiras) 2, Área de Seção Transversal do Componente: 0.006 m2; EI-GRA-Granito cinza Andorinha (Bancadas, bancos e prateleiras) 2, Volume Componente (Líquido): 0.00012 m3; EI-GRA-Granito cinza Andorinha (Bancadas, bancos e prateleiras) 2, Volume do componente (Bruto): 0.00012 m3; Aço 1, Massa: 0.5772 kg; Aço 1, Área de Seção Transversal do Componente: 0.0037 m2; Aço 1, Volume Componente (Líquido): 0.000074 m3; Aço 1, Volume do componente (Bruto): 0.000074 m3; EI-GRA-Granito cinza Andorinha (Bancadas, bancos e prateleiras) 3, Altura do Componente Retangular: 0.02 m; EI-GRA-Granito cinza Andorinha (Bancadas, bancos e prateleiras) 3, Largura do Componente Retangular: 0.3 m; EI-GRA-Granito cinza Andorinha (Bancadas, bancos e prateleiras) 3, Área de Seção Transversal do Componente: 0.006 m2; EI-GRA-Granito cinza Andorinha (Bancadas, bancos e prateleiras) 1: 2 with these values; EI-GRA-Granito cinza Andorinha (Bancadas, bancos e prateleiras) 2: 3 with these values; Aço 1: 3 with these values; EI-GRA-Granito cinza Andorinha (Bancadas, bancos e prateleiras) 3: 2 with these values
Name | 1_Bloco | EI-GRA-Granito cinza Andorinha (Bancadas, bancos e prateleiras) 3, Massa (kg) | EI-GRA-Granito cinza Andorinha (Bancadas, bancos e prateleiras) 3, Volume Componente (Líquido) (m3) = EI-GRA-Granito cinza Andorinha (Bancadas, bancos e prateleiras) 3, Volume do componente (Bruto) (m3)
PTG1 | BLOCO A | 18.8161 | 0.00672002
2 x PTG1 | BLOCO B | 18.8157 | 0.0067199

# IfcFurniture: Várias Estruturas- 7 Segmentos - 300 x 270 x 2520 (100+20+1130+20+1130+20+100), PTG4
In: TÉRREO
Classification: Mobiliário (Classificação Archicad); Material: EI-GRA-Granito cinza Andorinha (Bancadas, bancos e prateleiras) (7), Aço (3)
FNDE - Pedras: PRATELEIRA - GRANITO CINZA ANDORINHA - esp. 2 cm; 1_Bloco: BLOCO A; 0_ID: PTG4
Component Quantities - EI-GRA-Granito cinza Andorinha (Bancadas, bancos e prateleiras) 1, Massa: 1.68 kg; EI-GRA-Granito cinza Andorinha (Bancadas, bancos e prateleiras) 1, Altura do Componente Retangular: 0.02 m; EI-GRA-Granito cinza Andorinha (Bancadas, bancos e prateleiras) 1, Largura do Componente Retangular: 0.3 m; EI-GRA-Granito cinza Andorinha (Bancadas, bancos e prateleiras) 1, Área de Seção Transversal do Componente: 0.006 m2; EI-GRA-Granito cinza Andorinha (Bancadas, bancos e prateleiras) 1, Volume Componente (Líquido): 0.0006 m3; EI-GRA-Granito cinza Andorinha (Bancadas, bancos e prateleiras) 1, Volume do componente (Bruto): 0.0006 m3; EI-GRA-Granito cinza Andorinha (Bancadas, bancos e prateleiras) 2, Massa: 0.336 kg; EI-GRA-Granito cinza Andorinha (Bancadas, bancos e prateleiras) 2, Altura do Componente Retangular: 0.02 m; EI-GRA-Granito cinza Andorinha (Bancadas, bancos e prateleiras) 2, Largura do Componente Retangular: 0.3 m; EI-GRA-Granito cinza Andorinha (Bancadas, bancos e prateleiras) 2, Área de Seção Transversal do Componente: 0.006 m2; EI-GRA-Granito cinza Andorinha (Bancadas, bancos e prateleiras) 2, Volume Componente (Líquido): 0.00012 m3; EI-GRA-Granito cinza Andorinha (Bancadas, bancos e prateleiras) 2, Volume do componente (Bruto): 0.00012 m3; Aço 1, Massa: 0.5772 kg; Aço 1, Área de Seção Transversal do Componente: 0.0037 m2; Aço 1, Volume Componente (Líquido): 0.000074 m3; Aço 1, Volume do componente (Bruto): 0.000074 m3; EI-GRA-Granito cinza Andorinha (Bancadas, bancos e prateleiras) 3, Massa: 18.984 kg; EI-GRA-Granito cinza Andorinha (Bancadas, bancos e prateleiras) 3, Altura do Componente Retangular: 0.02 m; EI-GRA-Granito cinza Andorinha (Bancadas, bancos e prateleiras) 3, Largura do Componente Retangular: 0.3 m; EI-GRA-Granito cinza Andorinha (Bancadas, bancos e prateleiras) 3, Área de Seção Transversal do Componente: 0.006 m2; EI-GRA-Granito cinza Andorinha (Bancadas, bancos e prateleiras) 3, Volume Componente (Líquido): 0.00678 m3; EI-GRA-Granito cinza Andorinha (Bancadas, bancos e prateleiras) 3, Volume do componente (Bruto): 0.00678 m3; EI-GRA-Granito cinza Andorinha (Bancadas, bancos e prateleiras) 1: 2 with these values; EI-GRA-Granito cinza Andorinha (Bancadas, bancos e prateleiras) 2: 3 with these values; Aço 1: 3 with these values; EI-GRA-Granito cinza Andorinha (Bancadas, bancos e prateleiras) 3: 2 with these values

# IfcFurniture: Várias Estruturas- 7 Segmentos - 300 x 270 x 2950 (100+20+1345+20+1345+20+100), PTG3
In: TÉRREO
Classification: Mobiliário (Classificação Archicad); Material: EI-GRA-Granito cinza Andorinha (Bancadas, bancos e prateleiras) (7), Aço (3)
FNDE - Pedras: PRATELEIRA - GRANITO CINZA ANDORINHA - esp. 2 cm; 1_Bloco: BLOCO A; 0_ID: PTG3
Component Quantities - EI-GRA-Granito cinza Andorinha (Bancadas, bancos e prateleiras) 1, Massa: 1.68 kg; EI-GRA-Granito cinza Andorinha (Bancadas, bancos e prateleiras) 1, Altura do Componente Retangular: 0.02 m; EI-GRA-Granito cinza Andorinha (Bancadas, bancos e prateleiras) 1, Largura do Componente Retangular: 0.3 m; EI-GRA-Granito cinza Andorinha (Bancadas, bancos e prateleiras) 1, Área de Seção Transversal do Componente: 0.006 m2; EI-GRA-Granito cinza Andorinha (Bancadas, bancos e prateleiras) 1, Volume Componente (Líquido): 0.0006 m3; EI-GRA-Granito cinza Andorinha (Bancadas, bancos e prateleiras) 1, Volume do componente (Bruto): 0.0006 m3; EI-GRA-Granito cinza Andorinha (Bancadas, bancos e prateleiras) 2, Massa: 0.336 kg; EI-GRA-Granito cinza Andorinha (Bancadas, bancos e prateleiras) 2, Altura do Componente Retangular: 0.02 m; EI-GRA-Granito cinza Andorinha (Bancadas, bancos e prateleiras) 2, Largura do Componente Retangular: 0.3 m; EI-GRA-Granito cinza Andorinha (Bancadas, bancos e prateleiras) 2, Área de Seção Transversal do Componente: 0.006 m2; EI-GRA-Granito cinza Andorinha (Bancadas, bancos e prateleiras) 2, Volume Componente (Líquido): 0.00012 m3; EI-GRA-Granito cinza Andorinha (Bancadas, bancos e prateleiras) 2, Volume do componente (Bruto): 0.00012 m3; Aço 1, Massa: 0.5772 kg; Aço 1, Área de Seção Transversal do Componente: 0.0037 m2; Aço 1, Volume Componente (Líquido): 0.000074 m3; Aço 1, Volume do componente (Bruto): 0.000074 m3; EI-GRA-Granito cinza Andorinha (Bancadas, bancos e prateleiras) 3, Massa: 22.596 kg; EI-GRA-Granito cinza Andorinha (Bancadas, bancos e prateleiras) 3, Altura do Componente Retangular: 0.02 m; EI-GRA-Granito cinza Andorinha (Bancadas, bancos e prateleiras) 3, Largura do Componente Retangular: 0.3 m; EI-GRA-Granito cinza Andorinha (Bancadas, bancos e prateleiras) 3, Área de Seção Transversal do Componente: 0.006 m2; EI-GRA-Granito cinza Andorinha (Bancadas, bancos e prateleiras) 3, Volume Componente (Líquido): 0.00807 m3; EI-GRA-Granito cinza Andorinha (Bancadas, bancos e prateleiras) 3, Volume do componente (Bruto): 0.00807 m3; EI-GRA-Granito cinza Andorinha (Bancadas, bancos e prateleiras) 1: 2 with these values; EI-GRA-Granito cinza Andorinha (Bancadas, bancos e prateleiras) 2: 3 with these values; Aço 1: 3 with these values; EI-GRA-Granito cinza Andorinha (Bancadas, bancos e prateleiras) 3: 2 with these values

# IfcFurniture: Várias Estruturas- 7 Segmentos - 300 x 270 x 3151 (100+20+1445+20+1445+20+100), PTG8
In: TÉRREO
Classification: Mobiliário (Classificação Archicad); Material: EI-GRA-Granito cinza Andorinha (Bancadas, bancos e prateleiras) (7), Aço (3)
FNDE - Pedras: PRATELEIRA - GRANITO CINZA ANDORINHA - esp. 2 cm; 1_Bloco: BLOCO A; 0_ID: PTG8
Component Quantities - EI-GRA-Granito cinza Andorinha (Bancadas, bancos e prateleiras) 1, Massa: 1.68 kg; EI-GRA-Granito cinza Andorinha (Bancadas, bancos e prateleiras) 1, Altura do Componente Retangular: 0.02 m; EI-GRA-Granito cinza Andorinha (Bancadas, bancos e prateleiras) 1, Largura do Componente Retangular: 0.3 m; EI-GRA-Granito cinza Andorinha (Bancadas, bancos e prateleiras) 1, Área de Seção Transversal do Componente: 0.006 m2; EI-GRA-Granito cinza Andorinha (Bancadas, bancos e prateleiras) 1, Volume Componente (Líquido): 0.0006 m3; EI-GRA-Granito cinza Andorinha (Bancadas, bancos e prateleiras) 1, Volume do componente (Bruto): 0.0006 m3; EI-GRA-Granito cinza Andorinha (Bancadas, bancos e prateleiras) 2, Massa: 0.336 kg; EI-GRA-Granito cinza Andorinha (Bancadas, bancos e prateleiras) 2, Altura do Componente Retangular: 0.02 m; EI-GRA-Granito cinza Andorinha (Bancadas, bancos e prateleiras) 2, Largura do Componente Retangular: 0.3 m; EI-GRA-Granito cinza Andorinha (Bancadas, bancos e prateleiras) 2, Área de Seção Transversal do Componente: 0.006 m2; EI-GRA-Granito cinza Andorinha (Bancadas, bancos e prateleiras) 2, Volume Componente (Líquido): 0.00012 m3; EI-GRA-Granito cinza Andorinha (Bancadas, bancos e prateleiras) 2, Volume do componente (Bruto): 0.00012 m3; Aço 1, Massa: 0.5772 kg; Aço 1, Área de Seção Transversal do Componente: 0.0037 m2; Aço 1, Volume Componente (Líquido): 0.000074 m3; Aço 1, Volume do componente (Bruto): 0.000074 m3; EI-GRA-Granito cinza Andorinha (Bancadas, bancos e prateleiras) 3, Massa: 24.2813 kg; EI-GRA-Granito cinza Andorinha (Bancadas, bancos e prateleiras) 3, Altura do Componente Retangular: 0.02 m; EI-GRA-Granito cinza Andorinha (Bancadas, bancos e prateleiras) 3, Largura do Componente Retangular: 0.3 m; EI-GRA-Granito cinza Andorinha (Bancadas, bancos e prateleiras) 3, Área de Seção Transversal do Componente: 0.006 m2; EI-GRA-Granito cinza Andorinha (Bancadas, bancos e prateleiras) 3, Volume Componente (Líquido): 0.00867189 m3; EI-GRA-Granito cinza Andorinha (Bancadas, bancos e prateleiras) 3, Volume do componente (Bruto): 0.00867189 m3; EI-GRA-Granito cinza Andorinha (Bancadas, bancos e prateleiras) 1: 2 with these values; EI-GRA-Granito cinza Andorinha (Bancadas, bancos e prateleiras) 2: 3 with these values; Aço 1: 3 with these values; EI-GRA-Granito cinza Andorinha (Bancadas, bancos e prateleiras) 3: 2 with these values

# IfcFurniture: Várias Estruturas- 7 Segmentos - 400 x 1530 x 2500 (140+20+766+20+766+20+768), PTG10b
In: TÉRREO
Classification: Mobiliário (Classificação Archicad); Material: EI-GRA-Granito cinza Andorinha (Bancadas, bancos e prateleiras) (28), Aço (12)
FNDE - Pedras: PRATELEIRA - GRANITO CINZA ANDORINHA - esp. 2 cm; 1_Bloco: BLOCO B; 0_ID: PTG10b
Component Quantities - EI-GRA-Granito cinza Andorinha (Bancadas, bancos e prateleiras) 1, Massa: 3.136 kg; EI-GRA-Granito cinza Andorinha (Bancadas, bancos e prateleiras) 1, Altura do Componente Retangular: 0.02 m; EI-GRA-Granito cinza Andorinha (Bancadas, bancos e prateleiras) 1, Largura do Componente Retangular: 0.4 m; EI-GRA-Granito cinza Andorinha (Bancadas, bancos e prateleiras) 1, Área de Seção Transversal do Componente: 0.008 m2; EI-GRA-Granito cinza Andorinha (Bancadas, bancos e prateleiras) 1, Volume Componente (Líquido): 0.00112 m3; EI-GRA-Granito cinza Andorinha (Bancadas, bancos e prateleiras) 1, Volume do componente (Bruto): 0.00112 m3; EI-GRA-Granito cinza Andorinha (Bancadas, bancos e prateleiras) 5, Massa: 0.448 kg; EI-GRA-Granito cinza Andorinha (Bancadas, bancos e prateleiras) 5, Altura do Componente Retangular: 0.02 m; EI-GRA-Granito cinza Andorinha (Bancadas, bancos e prateleiras) 5, Largura do Componente Retangular: 0.4 m; EI-GRA-Granito cinza Andorinha (Bancadas, bancos e prateleiras) 5, Área de Seção Transversal do Componente: 0.008 m2; EI-GRA-Granito cinza Andorinha (Bancadas, bancos e prateleiras) 5, Volume Componente (Líquido): 0.00016 m3; EI-GRA-Granito cinza Andorinha (Bancadas, bancos e prateleiras) 5, Volume do componente (Bruto): 0.00016 m3; Aço 1, Massa: 0.5772 kg; Aço 1, Área de Seção Transversal do Componente: 0.0037 m2; Aço 1, Volume Componente (Líquido): 0.000074 m3; Aço 1, Volume do componente (Bruto): 0.000074 m3; EI-GRA-Granito cinza Andorinha (Bancadas, bancos e prateleiras) 9, Massa: 17.156 kg; EI-GRA-Granito cinza Andorinha (Bancadas, bancos e prateleiras) 9, Altura do Componente Retangular: 0.02 m; EI-GRA-Granito cinza Andorinha (Bancadas, bancos e prateleiras) 9, Largura do Componente Retangular: 0.4 m; EI-GRA-Granito cinza Andorinha (Bancadas, bancos e prateleiras) 9, Área de Seção Transversal do Componente: 0.008 m2; EI-GRA-Granito cinza Andorinha (Bancadas, bancos e prateleiras) 9, Volume Componente (Líquido): 0.00612713 m3; EI-GRA-Granito cinza Andorinha (Bancadas, bancos e prateleiras) 9, Volume do componente (Bruto): 0.00612713 m3; EI-GRA-Granito cinza Andorinha (Bancadas, bancos e prateleiras) 25, Massa: 12.7275 kg; EI-GRA-Granito cinza Andorinha (Bancadas, bancos e prateleiras) 25, Altura do Componente Retangular: 0.02 m; EI-GRA-Granito cinza Andorinha (Bancadas, bancos e prateleiras) 25, Largura do Componente Retangular: 0.4 m; EI-GRA-Granito cinza Andorinha (Bancadas, bancos e prateleiras) 25, Área de Seção Transversal do Componente: 0.008 m2; EI-GRA-Granito cinza Andorinha (Bancadas, bancos e prateleiras) 25, Volume Componente (Líquido): 0.00454553 m3; EI-GRA-Granito cinza Andorinha (Bancadas, bancos e prateleiras) 25, Volume do componente (Bruto): 0.00454553 m3; EI-GRA-Granito cinza Andorinha (Bancadas, bancos e prateleiras) 1: 4 with these values; EI-GRA-Granito cinza Andorinha (Bancadas, bancos e prateleiras) 5: 12 with these values; Aço 1: 12 with these values; EI-GRA-Granito cinza Andorinha (Bancadas, bancos e prateleiras) 9: 8 with these values; EI-GRA-Granito cinza Andorinha (Bancadas, bancos e prateleiras) 25: 4 with these values

# IfcFurniture: Várias Estruturas- 7 Segmentos - 500 x 1530 x 1699 (130+20+689+20+689+20+130), PTG6
In: TÉRREO
Classification: Mobiliário (Classificação Archicad); Material: EI-GRA-Granito cinza Andorinha (Bancadas, bancos e prateleiras) (28), Aço (12)
FNDE - Pedras: PRATELEIRA - GRANITO CINZA ANDORINHA - esp. 2 cm; 1_Bloco: BLOCO A; 0_ID: PTG6
Component Quantities - EI-GRA-Granito cinza Andorinha (Bancadas, bancos e prateleiras) 1, Massa: 3.64 kg; EI-GRA-Granito cinza Andorinha (Bancadas, bancos e prateleiras) 1, Altura do Componente Retangular: 0.02 m; EI-GRA-Granito cinza Andorinha (Bancadas, bancos e prateleiras) 1, Largura do Componente Retangular: 0.5 m; EI-GRA-Granito cinza Andorinha (Bancadas, bancos e prateleiras) 1, Área de Seção Transversal do Componente: 0.01 m2; EI-GRA-Granito cinza Andorinha (Bancadas, bancos e prateleiras) 1, Volume Componente (Líquido): 0.0013 m3; EI-GRA-Granito cinza Andorinha (Bancadas, bancos e prateleiras) 1, Volume do componente (Bruto): 0.0013 m3; EI-GRA-Granito cinza Andorinha (Bancadas, bancos e prateleiras) 5, Massa: 0.56 kg; EI-GRA-Granito cinza Andorinha (Bancadas, bancos e prateleiras) 5, Altura do Componente Retangular: 0.02 m; EI-GRA-Granito cinza Andorinha (Bancadas, bancos e prateleiras) 5, Largura do Componente Retangular: 0.5 m; EI-GRA-Granito cinza Andorinha (Bancadas, bancos e prateleiras) 5, Área de Seção Transversal do Componente: 0.01 m2; EI-GRA-Granito cinza Andorinha (Bancadas, bancos e prateleiras) 5, Volume Componente (Líquido): 0.0002 m3; EI-GRA-Granito cinza Andorinha (Bancadas, bancos e prateleiras) 5, Volume do componente (Bruto): 0.0002 m3; Aço 1, Massa: 0.7215 kg; Aço 1, Área de Seção Transversal do Componente: 0.004625 m2; Aço 1, Volume Componente (Líquido): 0.0000925 m3; Aço 1, Volume do componente (Bruto): 0.0000925 m3; EI-GRA-Granito cinza Andorinha (Bancadas, bancos e prateleiras) 9, Massa: 19.3 kg; EI-GRA-Granito cinza Andorinha (Bancadas, bancos e prateleiras) 9, Altura do Componente Retangular: 0.02 m; EI-GRA-Granito cinza Andorinha (Bancadas, bancos e prateleiras) 9, Largura do Componente Retangular: 0.5 m; EI-GRA-Granito cinza Andorinha (Bancadas, bancos e prateleiras) 9, Área de Seção Transversal do Componente: 0.01 m2; EI-GRA-Granito cinza Andorinha (Bancadas, bancos e prateleiras) 9, Volume Componente (Líquido): 0.00689285 m3; EI-GRA-Granito cinza Andorinha (Bancadas, bancos e prateleiras) 9, Volume do componente (Bruto): 0.00689285 m3; EI-GRA-Granito cinza Andorinha (Bancadas, bancos e prateleiras) 1: 8 with these values; EI-GRA-Granito cinza Andorinha (Bancadas, bancos e prateleiras) 5: 12 with these values; Aço 1: 12 with these values; EI-GRA-Granito cinza Andorinha (Bancadas, bancos e prateleiras) 9: 8 with these values

# IfcFurniture: Várias Estruturas- 7 Segmentos - 600 x 1110 x 1803 (130+20+741+20+741+20+130), PTG5
In: TÉRREO
Classification: Mobiliário (Classificação Archicad); Material: EI-GRA-Granito cinza Andorinha (Bancadas, bancos e prateleiras) (21), Aço (9)
FNDE - Pedras: PRATELEIRA - GRANITO CINZA ANDORINHA - esp. 2 cm; 1_Bloco: BLOCO A; 0_ID: PTG5
Component Quantities - EI-GRA-Granito cinza Andorinha (Bancadas, bancos e prateleiras) 1, Massa: 4.368 kg; EI-GRA-Granito cinza Andorinha (Bancadas, bancos e prateleiras) 1, Altura do Componente Retangular: 0.02 m; EI-GRA-Granito cinza Andorinha (Bancadas, bancos e prateleiras) 1, Largura do Componente Retangular: 0.6 m; EI-GRA-Granito cinza Andorinha (Bancadas, bancos e prateleiras) 1, Área de Seção Transversal do Componente: 0.012 m2; EI-GRA-Granito cinza Andorinha (Bancadas, bancos e prateleiras) 1, Volume Componente (Líquido): 0.00156 m3; EI-GRA-Granito cinza Andorinha (Bancadas, bancos e prateleiras) 1, Volume do componente (Bruto): 0.00156 m3; EI-GRA-Granito cinza Andorinha (Bancadas, bancos e prateleiras) 4, Massa: 0.672 kg; EI-GRA-Granito cinza Andorinha (Bancadas, bancos e prateleiras) 4, Altura do Componente Retangular: 0.02 m; EI-GRA-Granito cinza Andorinha (Bancadas, bancos e prateleiras) 4, Largura do Componente Retangular: 0.6 m; EI-GRA-Granito cinza Andorinha (Bancadas, bancos e prateleiras) 4, Área de Seção Transversal do Componente: 0.012 m2; EI-GRA-Granito cinza Andorinha (Bancadas, bancos e prateleiras) 4, Volume Componente (Líquido): 0.00024 m3; EI-GRA-Granito cinza Andorinha (Bancadas, bancos e prateleiras) 4, Volume do componente (Bruto): 0.00024 m3; Aço 1, Massa: 0.8658 kg; Aço 1, Área de Seção Transversal do Componente: 0.00555 m2; Aço 1, Volume Componente (Líquido): 0.000111 m3; Aço 1, Volume do componente (Bruto): 0.000111 m3; EI-GRA-Granito cinza Andorinha (Bancadas, bancos e prateleiras) 7, Massa: 24.9066 kg; EI-GRA-Granito cinza Andorinha (Bancadas, bancos e prateleiras) 7, Altura do Componente Retangular: 0.02 m; EI-GRA-Granito cinza Andorinha (Bancadas, bancos e prateleiras) 7, Largura do Componente Retangular: 0.6 m; EI-GRA-Granito cinza Andorinha (Bancadas, bancos e prateleiras) 7, Área de Seção Transversal do Componente: 0.012 m2; EI-GRA-Granito cinza Andorinha (Bancadas, bancos e prateleiras) 7, Volume Componente (Líquido): 0.00889522 m3; EI-GRA-Granito cinza Andorinha (Bancadas, bancos e prateleiras) 7, Volume do componente (Bruto): 0.00889522 m3; EI-GRA-Granito cinza Andorinha (Bancadas, bancos e prateleiras) 1: 6 with these values; EI-GRA-Granito cinza Andorinha (Bancadas, bancos e prateleiras) 4: 9 with these values; Aço 1: 9 with these values; EI-GRA-Granito cinza Andorinha (Bancadas, bancos e prateleiras) 7: 6 with these values

# IfcFurniture: Várias Estruturas- 9 Segmentos - 400 x 1530 x 3000 (140+20+879+20+882+20+879+20+140), PTG10a
In: TÉRREO
Classification: Mobiliário (Classificação Archicad); Material: EI-GRA-Granito cinza Andorinha (Bancadas, bancos e prateleiras) (36), Aço (16)
FNDE - Pedras: PRATELEIRA - GRANITO CINZA ANDORINHA - esp. 2 cm; 1_Bloco: BLOCO B; 0_ID: PTG10a
Component Quantities - EI-GRA-Granito cinza Andorinha (Bancadas, bancos e prateleiras) 1, Massa: 0.5488 kg; EI-GRA-Granito cinza Andorinha (Bancadas, bancos e prateleiras) 1, Altura do Componente Retangular: 0.02 m; EI-GRA-Granito cinza Andorinha (Bancadas, bancos e prateleiras) 1, Largura do Componente Retangular: 0.4 m; EI-GRA-Granito cinza Andorinha (Bancadas, bancos e prateleiras) 1, Área de Seção Transversal do Componente: 0.008 m2; EI-GRA-Granito cinza Andorinha (Bancadas, bancos e prateleiras) 1, Volume Componente (Líquido): 0.000196 m3; EI-GRA-Granito cinza Andorinha (Bancadas, bancos e prateleiras) 1, Volume do componente (Bruto): 0.000196 m3; EI-GRA-Granito cinza Andorinha (Bancadas, bancos e prateleiras) 5, Massa: 0.168 kg; EI-GRA-Granito cinza Andorinha (Bancadas, bancos e prateleiras) 5, Altura do Componente Retangular: 0.02 m; EI-GRA-Granito cinza Andorinha (Bancadas, bancos e prateleiras) 5, Largura do Componente Retangular: 0.4 m; EI-GRA-Granito cinza Andorinha (Bancadas, bancos e prateleiras) 5, Área de Seção Transversal do Componente: 0.008 m2; EI-GRA-Granito cinza Andorinha (Bancadas, bancos e prateleiras) 5, Volume Componente (Líquido): 0.00006 m3; EI-GRA-Granito cinza Andorinha (Bancadas, bancos e prateleiras) 5, Volume do componente (Bruto): 0.00006 m3; Aço 1, Massa: 0.5772 kg; Aço 1, Área de Seção Transversal do Componente: 0.0037 m2; Aço 1, Volume Componente (Líquido): 0.000074 m3; Aço 1, Volume do componente (Bruto): 0.000074 m3; EI-GRA-Granito cinza Andorinha (Bancadas, bancos e prateleiras) 9, Massa: 18.079 kg; EI-GRA-Granito cinza Andorinha (Bancadas, bancos e prateleiras) 9, Altura do Componente Retangular: 0.02 m; EI-GRA-Granito cinza Andorinha (Bancadas, bancos e prateleiras) 9, Largura do Componente Retangular: 0.4 m; EI-GRA-Granito cinza Andorinha (Bancadas, bancos e prateleiras) 9, Área de Seção Transversal do Componente: 0.008 m2; EI-GRA-Granito cinza Andorinha (Bancadas, bancos e prateleiras) 9, Volume Componente (Líquido): 0.00645679 m3; EI-GRA-Granito cinza Andorinha (Bancadas, bancos e prateleiras) 9, Volume do componente (Bruto): 0.00645679 m3; EI-GRA-Granito cinza Andorinha (Bancadas, bancos e prateleiras) 13, Massa: 0.448 kg; EI-GRA-Granito cinza Andorinha (Bancadas, bancos e prateleiras) 13, Altura do Componente Retangular: 0.02 m; EI-GRA-Granito cinza Andorinha (Bancadas, bancos e prateleiras) 13, Largura do Componente Retangular: 0.4 m; EI-GRA-Granito cinza Andorinha (Bancadas, bancos e prateleiras) 13, Área de Seção Transversal do Componente: 0.008 m2; EI-GRA-Granito cinza Andorinha (Bancadas, bancos e prateleiras) 13, Volume Componente (Líquido): 0.00016 m3; EI-GRA-Granito cinza Andorinha (Bancadas, bancos e prateleiras) 13, Volume do componente (Bruto): 0.00016 m3; EI-GRA-Granito cinza Andorinha (Bancadas, bancos e prateleiras) 17, Massa: 19.7509 kg; EI-GRA-Granito cinza Andorinha (Bancadas, bancos e prateleiras) 17, Altura do Componente Retangular: 0.02 m; EI-GRA-Granito cinza Andorinha (Bancadas, bancos e prateleiras) 17, Largura do Componente Retangular: 0.4 m; EI-GRA-Granito cinza Andorinha (Bancadas, bancos e prateleiras) 17, Área de Seção Transversal do Componente: 0.008 m2; EI-GRA-Granito cinza Andorinha (Bancadas, bancos e prateleiras) 17, Volume Componente (Líquido): 0.0070539 m3; EI-GRA-Granito cinza Andorinha (Bancadas, bancos e prateleiras) 17, Volume do componente (Bruto): 0.0070539 m3; EI-GRA-Granito cinza Andorinha (Bancadas, bancos e prateleiras) 25, Massa: 19.6918 kg; EI-GRA-Granito cinza Andorinha (Bancadas, bancos e prateleiras) 25, Altura do Componente Retangular: 0.02 m; EI-GRA-Granito cinza Andorinha (Bancadas, bancos e prateleiras) 25, Largura do Componente Retangular: 0.4 m; EI-GRA-Granito cinza Andorinha (Bancadas, bancos e prateleiras) 25, Área de Seção Transversal do Componente: 0.008 m2; EI-GRA-Granito cinza Andorinha (Bancadas, bancos e prateleiras) 25, Volume Componente (Líquido): 0.00703279 m3; EI-GRA-Granito cinza Andorinha (Bancadas, bancos e prateleiras) 25, Volume do componente (Bruto): 0.00703279 m3; EI-GRA-Granito cinza Andorinha (Bancadas, bancos e prateleiras) 33, Massa: 3.136 kg; EI-GRA-Granito cinza Andorinha (Bancadas, bancos e prateleiras) 33, Altura do Componente Retangular: 0.02 m; EI-GRA-Granito cinza Andorinha (Bancadas, bancos e prateleiras) 33, Largura do Componente Retangular: 0.4 m; EI-GRA-Granito cinza Andorinha (Bancadas, bancos e prateleiras) 33, Área de Seção Transversal do Componente: 0.008 m2; EI-GRA-Granito cinza Andorinha (Bancadas, bancos e prateleiras) 33, Volume Componente (Líquido): 0.00112 m3; EI-GRA-Granito cinza Andorinha (Bancadas, bancos e prateleiras) 33, Volume do componente (Bruto): 0.00112 m3; EI-GRA-Granito cinza Andorinha (Bancadas, bancos e prateleiras) 1: 4 with these values; EI-GRA-Granito cinza Andorinha (Bancadas, bancos e prateleiras) 5: 4 with these values; Aço 1: 16 with these values; EI-GRA-Granito cinza Andorinha (Bancadas, bancos e prateleiras) 9: 4 with these values; EI-GRA-Granito cinza Andorinha (Bancadas, bancos e prateleiras) 13: 12 with these values; EI-GRA-Granito cinza Andorinha (Bancadas, bancos e prateleiras) 17: 4 with these values; EI-GRA-Granito cinza Andorinha (Bancadas, bancos e prateleiras) 25: 4 with these values; EI-GRA-Granito cinza Andorinha (Bancadas, bancos e prateleiras) 33: 4 with these values

# IfcLightFixture: Arandela Led Tartaruga (8)
In: TÉRREO
Classification: Luminária (Classificação Archicad); Material: Vidro, Plástico
FNDE - Iluminação - Descrição luminária: ARANDELAS LED SOBREPOR 24W, BRANCO FRIO, REF.: ILUMINIM OU SIMILAR, H=220cm DO PISO ACABADO; 0_ID: L7
Component Quantities - Vidro, Massa: 1.52361 kg; Vidro, Volume Componente (Líquido): 0.000609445 m3; Vidro, Volume do componente (Bruto): 0.000609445 m3; Plástico, Massa: 0.907501 kg; Plástico, Volume Componente (Líquido): 0.000652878 m3; Plástico, Volume do componente (Bruto): 0.000652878 m3
Name | 1_Bloco
4 x L7 | BLOCO B
4 x L7 | BLOCO A

# IfcLightFixture: Arandela Led Tartaruga para teto (2)
In: TÉRREO
Classification: Luminária (Classificação Archicad); Material: Água
FNDE - Iluminação - Descrição luminária: ARANDELAS LED SOBREPOR 24W, BRANCO FRIO, REF.: ILUMINIM OU SIMILAR; 1_Bloco: CASA DE BOMBAS / GÁS / LIXO; 0_ID: L7
Component Quantities - Água, Massa: 1.26232 kg; Água, Volume Componente (Líquido): 0.00126232 m3; Água, Volume do componente (Bruto): 0.00126232 m3

# IfcLightFixture: Luminária Fluorescente 27 (106)
In: TÉRREO
Classification: Luminária (Classificação Archicad)
Name | Iluminação - Descrição luminária | 1_Bloco | 0_ID | Component, Volume Componente (Líquido) (m3) = Component, Volume do componente (Bruto) (m3)
26 x L1 | LUMINÁRIA DE EMBUTIR EM FORRO DE GESSO OU MODULADO COM PERFIL “T”, COM BARRA DE LED 39W, REFLETOR E ALETA, REF.: 2005 LED SOFT ITAIM OU SIMILAR (dim.: 220 X 1250mm) | BLOCO B | L1 | 0.00073044
20 x L3 | LUMINÁRIA DE EMBUTIR EM FORRO DE GESSO OU MODULADO COM PERFIL “T”, COM BARRA DE LED 31W, REF.: MINOTAURO RE SOFT ITAIM OU SIMILAR (dim.: 220 X 1250mm) | BLOCO B | L3 | 0.0007346
26 x L3 | LUMINÁRIA DE EMBUTIR EM FORRO DE GESSO OU MODULADO COM PERFIL “T”, COM BARRA DE LED 31W, REF.: MINOTAURO RE SOFT ITAIM OU SIMILAR (dim.: 220 X 1250mm) | BLOCO A | L3 | 0.0007346
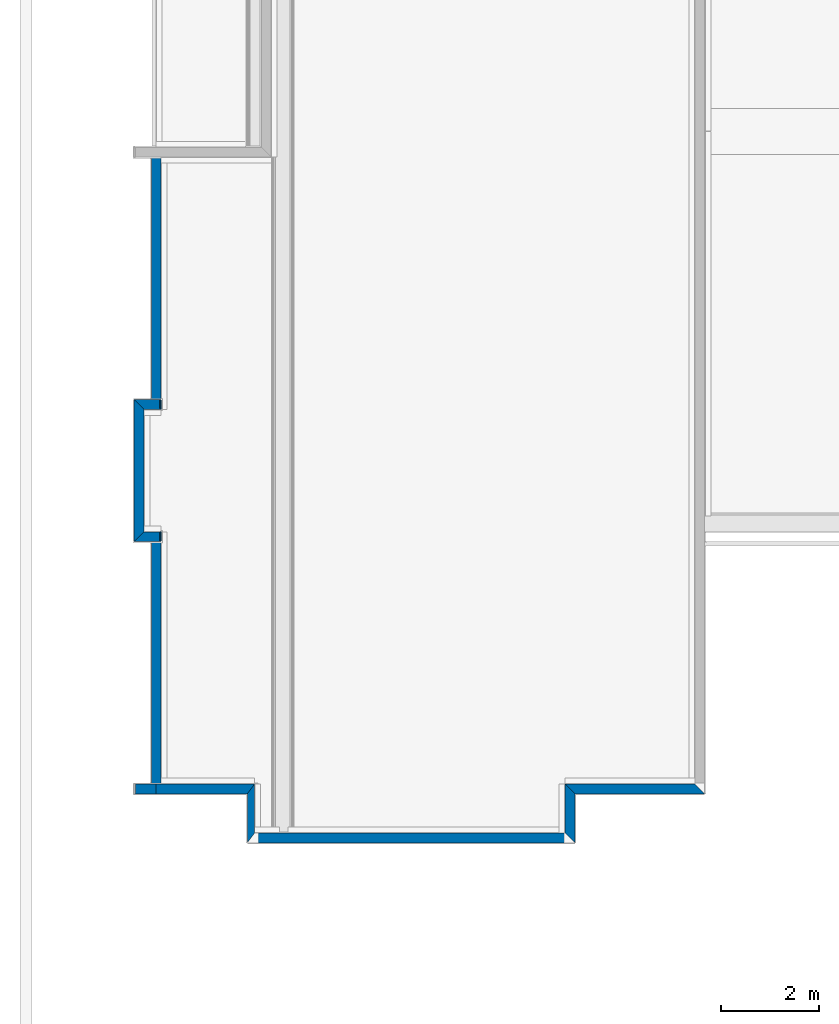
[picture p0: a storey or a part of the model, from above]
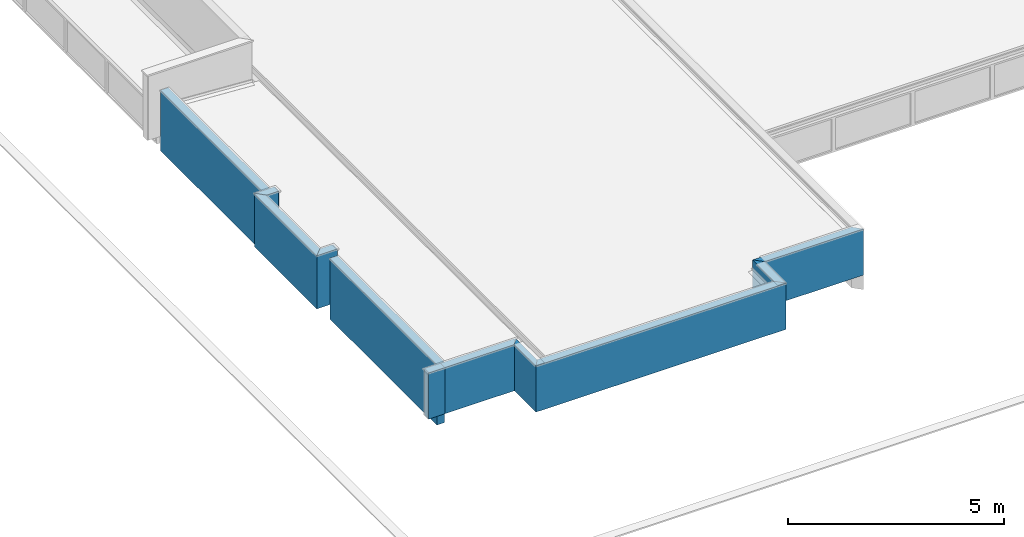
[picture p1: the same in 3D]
Properties of the parts of a building model (IFC4), part 7 of 22

# IfcLightFixture: Luminária Fluorescente 27 (106)
Name | Iluminação - Descrição luminária | 1_Bloco | 0_ID | Component, Volume Componente (Líquido) (m3) = Component, Volume do componente (Bruto) (m3)
5 x L1 | LUMINÁRIA DE EMBUTIR EM FORRO DE GESSO OU MODULADO COM PERFIL “T”, COM BARRA DE LED 39W, REFLETOR E ALETA, REF.: 2005 LED SOFT ITAIM OU SIMILAR (dim.: 220 X 1250mm) | BLOCO A | L1 | 0.00073044
6 x L2 | LUMINÁRIA DE EMBUTIR EM FORRO DE GESSO OU MODULADO COM PERFIL “T”, COM BARRA DE LED 17W, REF.: MINOTAURO 2PE SOFT ITAIM OU SIMILAR (dim. 212 X 625mm) | BLOCO A | L2 | 0.0004096
6 x L9 | LUMINÁRIA BLINDADA HERMÉTICA, LED 36W COM 2XT8 DE 120CM IP65, REF.:TLR 3118 TASCHIBRA OU SIMILAR | BLOCO A | L9 | 0.00726963
2 x L10 | LUMINÁRIA BLINDADA HERMÉTICA, LED 18W COM 2XT8 DE 65CM IP65, REF.:TLR 3118 TASCHIBRA OU SIMILAR | BLOCO A | L10 | 0.00367578
15 x L4 | LÂMPADA TUBULAR LED T8 18W, COM CALHA ACOPLADA. REF.: TASCHIBRA OU SIMILAR. (dim.: 40 X 1200mm) | PÁTIO COBERTO | L4 | 0.00216904

# IfcLightFixture: Spot Parede 27 (4)
In: TÉRREO
Classification: Luminária (Classificação Archicad)
FNDE - Iluminação - Descrição luminária: REFLETORES LED SLIM 200W, BRANCO FRIO, REF.: ILUMINIM OU SIMILAR, H=260cm DO PISO ACABADO; 0_ID: L6
Component Quantities - Component, Volume Componente (Líquido): 0.000272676 m3; Component, Volume do componente (Bruto): 0.000272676 m3
Name | 1_Bloco
L6 | BLOCO B
2 x L6 | PÁTIO COBERTO
L6 | BLOCO A

# IfcLightFixture: Spot de Piso 27 (10)
In: TÉRREO
Classification: Luminária (Classificação Archicad)
FNDE - 1_Bloco: ÁREAS EXTERNAS
Component Quantities - Component, Volume Componente (Líquido): 0.000320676 m3; Component, Volume do componente (Bruto): 0.000320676 m3
Name | Iluminação - Descrição luminária | 0_ID
9 x L5 | SPOTS BALIZADORES LED 12W, BRANCO FRIO, REF.: ILUMINIM OU SIMILAR | L5
L8 | REFLETORES LED SLIM 200W, BRANCO FRIO, REF.: ILUMINIM OU SIMILAR, FIXADO NO PISO | L8

# IfcRailing: Janela 27 (2)
In: TÉRREO
Classification: Guarda-Corpo (Classificação Archicad)
FNDE - Esquadrias - Fechamentos metálicos e Gradis: Guarda-corpo metálico; Barras metálicas: -; 1_Bloco: BLOCO B
Pset_RailingCommon - IsExternal: yes
Component Quantities - Component, Volume Componente (Líquido): 0.011 m3; Component, Volume do componente (Bruto): 0.011 m3

# IfcRailing: Tipo de Guarda-Corpo (9)
In: TÉRREO
Classification: Guarda-Corpo (Classificação Archicad)
FNDE - Esquadrias - Fechamentos metálicos e Gradis: -
Name | Material | Barras metálicas | 1_Bloco | 0_ID | IsExternal | Aço - Inoxidável 1, Massa (kg) | Aço - Inoxidável 1, Volume Componente (Líquido) (m3) = Aço - Inoxidável 1, Volume do componente (Bruto) (m3) | Aço - Inoxidável 3, Massa (kg) | Aço - Inoxidável 3, Volume Componente (Líquido) (m3) = Aço - Inoxidável 3, Volume do componente (Bruto) (m3) | Aço - Inoxidável 1
2 x Guarda-Corpo - 001 | Aço - Inoxidável (8) | BARRA DE APOIO DUPLA EM AÇO INOX POLIDO d=30mm | BLOCO B | Guarda-Corpo - 001 | no | 0.912524 | 0.000115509 | 0.816838 | 0.000103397 | 2 with these values | Component Quantities - Aço - Inoxidável 5, Massa: 6.58556 kg; Aço - Inoxidável 5, Volume Componente (Líquido): 0.000833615 m3; Aço - Inoxidável 5, Volume do componente (Bruto): 0.000833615 m3; Aço - Inoxidável 7, Massa: 1.67785 kg; Aço - Inoxidável 7, Volume Componente (Líquido): 0.000212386 m3; Aço - Inoxidável 7, Volume do componente (Bruto): 0.000212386 m3; Aço - Inoxidável 5: 2 with these values; Aço - Inoxidável 7: 2 with these values; Aço - Inoxidável 3: 2 with these values
2 x BM | Aço - Inoxidável | BARRA DE APOIO EM AÇO INOX POLIDO d=30mm | BLOCO B | BM | no | Component Quantities - Aço - Inoxidável, Massa: 7.92343 kg; Aço - Inoxidável, Volume Componente (Líquido): 0.00100297 m3; Aço - Inoxidável, Volume do componente (Bruto): 0.00100297 m3
Guarda-Corpo - 001 | Aço - Inoxidável (8) | BARRA DE APOIO DUPLA EM AÇO INOX POLIDO d=30mm | BLOCO A | Guarda-Corpo - 001 | no | 0.915422 | 0.000115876 | 0.816838 | 0.000103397 | 2 with these values | Component Quantities - Aço - Inoxidável 5, Massa: 6.59823 kg; Aço - Inoxidável 5, Volume Componente (Líquido): 0.000835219 m3; Aço - Inoxidável 5, Volume do componente (Bruto): 0.000835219 m3; Aço - Inoxidável 7, Massa: 1.67785 kg; Aço - Inoxidável 7, Volume Componente (Líquido): 0.000212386 m3; Aço - Inoxidável 7, Volume do componente (Bruto): 0.000212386 m3; Aço - Inoxidável 5: 2 with these values; Aço - Inoxidável 7: 2 with these values; Aço - Inoxidável 3: 2 with these values
BM | Aço - Inoxidável | BARRA DE APOIO EM AÇO INOX POLIDO d=30mm | BLOCO A | BM | no | Component Quantities - Aço - Inoxidável, Massa: 3.35822 kg; Aço - Inoxidável, Volume Componente (Líquido): 0.000425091 m3; Aço - Inoxidável, Volume do componente (Bruto): 0.000425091 m3
BM | Aço - Inoxidável (3) | BARRA DE PROTEÇÃO EM AÇO INOX POLIDO d=30mm | BLOCO A | BM | no | 0.487251 | 0.0000616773 | 17.2232 | 0.00218015 | 2 with these values
Guarda-Corpo - 002 | EI-MTL-PERFIL EM AÇO GALVANIZADO -AZUL (12), Alumínio (8) | GUARDA CORPO EM AÇO INOX POLIDO d=30mm COM PINTURA AZUL | CASA DE BOMBAS / GÁS / LIXO | Guarda-Corpo - 002 | yes | Component Quantities - EI-MTL-PERFIL EM AÇO GALVANIZADO -AZUL 2, Massa: 0.493855 kg; EI-MTL-PERFIL EM AÇO GALVANIZADO -AZUL 2, Volume Componente (Líquido): 0.0000625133 m3; EI-MTL-PERFIL EM AÇO GALVANIZADO -AZUL 2, Volume do componente (Bruto): 0.0000625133 m3; EI-MTL-PERFIL EM AÇO GALVANIZADO -AZUL 1, Massa: 11.6056 kg; EI-MTL-PERFIL EM AÇO GALVANIZADO -AZUL 1, Volume Componente (Líquido): 0.00146906 m3; EI-MTL-PERFIL EM AÇO GALVANIZADO -AZUL 1, Volume do componente (Bruto): 0.00146906 m3; Alumínio 1, Massa: 0.0700149 kg; Alumínio 1, Volume Componente (Líquido): 0.0000250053 m3; Alumínio 1, Volume do componente (Bruto): 0.0000250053 m3; EI-MTL-PERFIL EM AÇO GALVANIZADO -AZUL 5, Massa: 38.8087 kg; EI-MTL-PERFIL EM AÇO GALVANIZADO -AZUL 5, Volume Componente (Líquido): 0.0049125 m3; EI-MTL-PERFIL EM AÇO GALVANIZADO -AZUL 5, Volume do componente (Bruto): 0.0049125 m3; EI-MTL-PERFIL EM AÇO GALVANIZADO -AZUL 6, Massa: 9.70218 kg; EI-MTL-PERFIL EM AÇO GALVANIZADO -AZUL 6, Volume Componente (Líquido): 0.00122812 m3; EI-MTL-PERFIL EM AÇO GALVANIZADO -AZUL 6, Volume do componente (Bruto): 0.00122812 m3; EI-MTL-PERFIL EM AÇO GALVANIZADO -AZUL 2: 2 with these values; EI-MTL-PERFIL EM AÇO GALVANIZADO -AZUL 1: 8 with these values; Alumínio 1: 8 with these values
BM | Aço - Inoxidável (3) | BARRA DE PROTEÇÃO EM AÇO INOX POLIDO d=30mm | BLOCO B | BM | no | 0.487251 | 0.0000616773 | 17.2232 | 0.00218015 | 2 with these values

# IfcRailing: Várias Estruturas- 15 Segmentos - 50 x 900 x 4950 (50+300+50+1100+50+325+50+1100+50+325+50+1100+50+300+50) (4)
In: TÉRREO
Classification: Guarda-Corpo (Classificação Archicad); Material: Aço (10), EI-MTL-CHAPA DE AÇO CARBONO PERFURADA (4), EI-MTL-PERFIL EM AÇO GALVANIZADO -AMARELO (12), EI-MTL-CHAPA DE AÇO CARBONO PERFURADA -AMARELO (3)
FNDE - Esquadrias - Fechamentos metálicos e Gradis: Guarda-corpo metálico; Barras metálicas: -; 1_Bloco: BLOCO B
Pset_RailingCommon - IsExternal: yes
Component Quantities - Aço 1, Massa: 15.6 kg; Aço 1, Altura do Componente Retangular: 0.8 m; Aço 1, Largura do Componente Retangular: 0.05 m; Aço 1, Área de Seção Transversal do Componente: 0.04 m2; Aço 1, Volume Componente (Líquido): 0.002 m3; Aço 1, Volume do componente (Bruto): 0.002 m3; Aço 2, Massa: 5.85 kg; Aço 2, Altura do Componente Retangular: 0.05 m; Aço 2, Largura do Componente Retangular: 0.05 m; Aço 2, Área de Seção Transversal do Componente: 0.0025 m2; Aço 2, Volume Componente (Líquido): 0.00075 m3; Aço 2, Volume do componente (Bruto): 0.00075 m3; EI-MTL-CHAPA DE AÇO CARBONO PERFURADA 1, Massa: 2.48851 kg; EI-MTL-CHAPA DE AÇO CARBONO PERFURADA 1, Altura do Componente Retangular: 0.7 m; EI-MTL-CHAPA DE AÇO CARBONO PERFURADA 1, Largura do Componente Retangular: 0.0015 m; EI-MTL-CHAPA DE AÇO CARBONO PERFURADA 1, Área de Seção Transversal do Componente: 0.00105 m2; EI-MTL-CHAPA DE AÇO CARBONO PERFURADA 1, Volume Componente (Líquido): 0.000315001 m3; EI-MTL-CHAPA DE AÇO CARBONO PERFURADA 1, Volume do componente (Bruto): 0.000315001 m3; EI-MTL-PERFIL EM AÇO GALVANIZADO -AMARELO 1, Massa: 17.775 kg; EI-MTL-PERFIL EM AÇO GALVANIZADO -AMARELO 1, Altura do Componente Retangular: 0.9 m; EI-MTL-PERFIL EM AÇO GALVANIZADO -AMARELO 1, Largura do Componente Retangular: 0.05 m; EI-MTL-PERFIL EM AÇO GALVANIZADO -AMARELO 1, Área de Seção Transversal do Componente: 0.045 m2; EI-MTL-PERFIL EM AÇO GALVANIZADO -AMARELO 1, Volume Componente (Líquido): 0.00225 m3; EI-MTL-PERFIL EM AÇO GALVANIZADO -AMARELO 1, Volume do componente (Bruto): 0.00225 m3; EI-MTL-PERFIL EM AÇO GALVANIZADO -AMARELO 2, Massa: 21.725 kg; EI-MTL-PERFIL EM AÇO GALVANIZADO -AMARELO 2, Altura do Componente Retangular: 0.05 m; EI-MTL-PERFIL EM AÇO GALVANIZADO -AMARELO 2, Largura do Componente Retangular: 0.05 m; EI-MTL-PERFIL EM AÇO GALVANIZADO -AMARELO 2, Área de Seção Transversal do Componente: 0.0025 m2; EI-MTL-PERFIL EM AÇO GALVANIZADO -AMARELO 2, Volume Componente (Líquido): 0.00275 m3; EI-MTL-PERFIL EM AÇO GALVANIZADO -AMARELO 2, Volume do componente (Bruto): 0.00275 m3; EI-MTL-CHAPA DE AÇO CARBONO PERFURADA -AMARELO 1, Massa: 10.428 kg; EI-MTL-CHAPA DE AÇO CARBONO PERFURADA -AMARELO 1, Altura do Componente Retangular: 0.8 m; EI-MTL-CHAPA DE AÇO CARBONO PERFURADA -AMARELO 1, Largura do Componente Retangular: 0.0015 m; EI-MTL-CHAPA DE AÇO CARBONO PERFURADA -AMARELO 1, Área de Seção Transversal do Componente: 0.0012 m2; EI-MTL-CHAPA DE AÇO CARBONO PERFURADA -AMARELO 1, Volume Componente (Líquido): 0.00132 m3; EI-MTL-CHAPA DE AÇO CARBONO PERFURADA -AMARELO 1, Volume do componente (Bruto): 0.00132 m3; Aço 4, Altura do Componente Retangular: 0.05 m; Aço 4, Largura do Componente Retangular: 0.05 m; Aço 4, Área de Seção Transversal do Componente: 0.0025 m2; EI-MTL-CHAPA DE AÇO CARBONO PERFURADA 2, Altura do Componente Retangular: 0.7 m; EI-MTL-CHAPA DE AÇO CARBONO PERFURADA 2, Largura do Componente Retangular: 0.0015 m; EI-MTL-CHAPA DE AÇO CARBONO PERFURADA 2, Área de Seção Transversal do Componente: 0.00105 m2; Aço 1: 2 with these values; Aço 2: 4 with these values; EI-MTL-CHAPA DE AÇO CARBONO PERFURADA 1: 2 with these values; EI-MTL-PERFIL EM AÇO GALVANIZADO -AMARELO 1: 6 with these values; EI-MTL-PERFIL EM AÇO GALVANIZADO -AMARELO 2: 6 with these values; EI-MTL-CHAPA DE AÇO CARBONO PERFURADA -AMARELO 1: 3 with these values; Aço 4: 4 with these values; EI-MTL-CHAPA DE AÇO CARBONO PERFURADA 2: 2 with these values
Name | Aço 4, Massa (kg) | Aço 4, Volume Componente (Líquido) (m3) = Aço 4, Volume do componente (Bruto) (m3) | EI-MTL-CHAPA DE AÇO CARBONO PERFURADA 2, Massa (kg) | EI-MTL-CHAPA DE AÇO CARBONO PERFURADA 2, Volume Componente (Líquido) (m3) = EI-MTL-CHAPA DE AÇO CARBONO PERFURADA 2, Volume do componente (Bruto) (m3)
 | 6.33775 | 0.000812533 | 2.69599 | 0.000341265
 | 6.33703 | 0.00081244 | 2.69568 | 0.000341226
 | 6.33782 | 0.000812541 | 2.69602 | 0.000341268
 | 6.33756 | 0.000812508 | 2.69591 | 0.000341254

# IfcRamp: FNDE-PIS_EXT_CON 190 (5)
In: TÉRREO
Classification: Rampa (Classificação Archicad); Material: COMPACTAÇÃO DE SOLO, LASTRO DE BRITA, EI-PIS-1-Passeio de Concreto desempenado
FNDE - 1_Bloco: ÁREAS EXTERNAS
Pset_RampCommon - IsExternal: yes
Component Quantities - EI-PIS-1-Passeio de Concreto desempenado, Espessura do Componente: 0.08 m; LASTRO DE BRITA, Espessura do Componente: 0.1 m; COMPACTAÇÃO DE SOLO, Espessura do Componente: 0.01 m
Name | 0_ID | EI-PIS-1-Passeio de Concreto desempenado, Massa (kg) | EI-PIS-1-Passeio de Concreto desempenado, Área de Componente Projetada (Líquida) (m2) = EI-PIS-1-Passeio de Concreto desempenado, Área de Componente Projetada (Bruta) (m2) = LASTRO DE BRITA, Área de Componente Projetada (Líquida) (m2) = LASTRO DE BRITA, Área de Componente Projetada (Bruta) (m2) = COMPACTAÇÃO DE SOLO, Área de Componente Projetada (Líquida) (m2) = COMPACTAÇÃO DE SOLO, Área de Componente Projetada (Bruta) (m2) | EI-PIS-1-Passeio de Concreto desempenado, Volume Componente (Líquido) (m3) = EI-PIS-1-Passeio de Concreto desempenado, Volume do componente (Bruto) (m3) | LASTRO DE BRITA, Massa (kg) | LASTRO DE BRITA, Volume Componente (Líquido) (m3) = LASTRO DE BRITA, Volume do componente (Bruto) (m3) | COMPACTAÇÃO DE SOLO, Massa (kg) | COMPACTAÇÃO DE SOLO, Volume Componente (Líquido) (m3) = COMPACTAÇÃO DE SOLO, Volume do componente (Bruto) (m3)
Cobert.-002 | Cobert.-002 | 2191.63 | 15.2197 | 1.21757 | 2739.54 | 1.52197 | 273.954 | 0.152197
Cobert.-003 | Cobert.-003 | 1374.05 | 9.54204 | 0.763363 | 1717.57 | 0.954204 | 171.757 | 0.0954204
Cobert.-001 | Cobert.-001 | 1469.25 | 10.2031 | 0.816251 | 1836.56 | 1.02031 | 183.656 | 0.102031
Cobert.-001 | Cobert.-001 | 172.878 | 1.20054 | 0.0960432 | 216.097 | 0.120054 | 21.6097 | 0.0120054
Cobert.-002 | Cobert.-002 | 172.877 | 1.20053 | 0.0960426 | 216.096 | 0.120053 | 21.6096 | 0.0120053

# IfcRoof: FNDE-Calha 2 320 x 225, V01
In: COBERTURA
Classification: Cobertura (Classificação Archicad); Material: CALHA EM CHAPA DE AÇO GALVANIZADO (5)
Pset_RoofCommon - TotalArea: 17.1376 m2; IsExternal: yes
FNDE - Sistemas de Cobertura: CALHA EM CHAPA DE AÇO GALVANIZADO; 1_Bloco: BLOCO B; 0_ID: V01
Component Quantities - CALHA EM CHAPA DE AÇO GALVANIZADO 1, Massa: 132.709 kg; CALHA EM CHAPA DE AÇO GALVANIZADO 1, Área de Seção Transversal do Componente: 0.00199952 m2; CALHA EM CHAPA DE AÇO GALVANIZADO 1, Volume Componente (Líquido): 0.0167986 m3; CALHA EM CHAPA DE AÇO GALVANIZADO 1, Volume do componente (Bruto): 0.0167986 m3; CALHA EM CHAPA DE AÇO GALVANIZADO 2, Massa: 41.6831 kg; CALHA EM CHAPA DE AÇO GALVANIZADO 2, Área de Seção Transversal do Componente: 0.000621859 m2; CALHA EM CHAPA DE AÇO GALVANIZADO 2, Volume Componente (Líquido): 0.00527634 m3; CALHA EM CHAPA DE AÇO GALVANIZADO 2, Volume do componente (Bruto): 0.00527634 m3; CALHA EM CHAPA DE AÇO GALVANIZADO 3, Massa: 532.522 kg; CALHA EM CHAPA DE AÇO GALVANIZADO 3, Área de Seção Transversal do Componente: 0.00800335 m2; CALHA EM CHAPA DE AÇO GALVANIZADO 3, Volume Componente (Líquido): 0.0674079 m3; CALHA EM CHAPA DE AÇO GALVANIZADO 3, Volume do componente (Bruto): 0.0674079 m3; CALHA EM CHAPA DE AÇO GALVANIZADO 4, Massa: 19.9551 kg; CALHA EM CHAPA DE AÇO GALVANIZADO 4, Área de Seção Transversal do Componente: 0.000297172 m2; CALHA EM CHAPA DE AÇO GALVANIZADO 4, Volume Componente (Líquido): 0.00252597 m3; CALHA EM CHAPA DE AÇO GALVANIZADO 4, Volume do componente (Bruto): 0.00252597 m3

# IfcRoof: FNDE-Calha 3 398 x 400 (2)
In: COBERTURA
Classification: Cobertura (Classificação Archicad); Material: CALHA EM CHAPA DE AÇO GALVANIZADO
Pset_RoofCommon - IsExternal: yes
FNDE - Sistemas de Cobertura: CALHA EM CHAPA DE AÇO GALVANIZADO; 1_Bloco: PÁTIO COBERTO; 0_ID: V06
Component Quantities - CALHA EM CHAPA DE AÇO GALVANIZADO, Área de Seção Transversal do Componente: 0.000462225 m2
Name | TotalArea (m2) | CALHA EM CHAPA DE AÇO GALVANIZADO, Massa (kg) | CALHA EM CHAPA DE AÇO GALVANIZADO, Volume Componente (Líquido) (m3) = CALHA EM CHAPA DE AÇO GALVANIZADO, Volume do componente (Bruto) (m3)
V06 | 15.725 | 31.0047 | 0.00392464
V06 | 15.7253 | 31.0012 | 0.0039242

# IfcRoof: FNDE-Calha 4 259 x 385, V01
In: COBERTURA
Classification: Cobertura (Classificação Archicad); Material: CALHA EM CHAPA DE AÇO GALVANIZADO
Pset_RoofCommon - TotalArea: 9.65055 m2; IsExternal: yes
FNDE - Sistemas de Cobertura: CALHA EM CHAPA DE AÇO GALVANIZADO; 1_Bloco: BLOCO A; 0_ID: V01
Component Quantities - CALHA EM CHAPA DE AÇO GALVANIZADO, Massa: 18.9937 kg; CALHA EM CHAPA DE AÇO GALVANIZADO, Área de Seção Transversal do Componente: 0.000367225 m2; CALHA EM CHAPA DE AÇO GALVANIZADO, Volume Componente (Líquido): 0.00240427 m3; CALHA EM CHAPA DE AÇO GALVANIZADO, Volume do componente (Bruto): 0.00240427 m3

# IfcRoof: FNDE-Calha 450 x 234 (3)
In: COBERTURA
Classification: Cobertura (Classificação Archicad); Material: CALHA EM CHAPA DE AÇO GALVANIZADO (7)
Pset_RoofCommon - IsExternal: yes
FNDE - Sistemas de Cobertura: CALHA EM CHAPA DE AÇO GALVANIZADO; 0_ID: V01
Component Quantities - CALHA EM CHAPA DE AÇO GALVANIZADO 1, Área de Seção Transversal do Componente: 0.001998 m2; CALHA EM CHAPA DE AÇO GALVANIZADO 2, Área de Seção Transversal do Componente: 0.00199952 m2; CALHA EM CHAPA DE AÇO GALVANIZADO 3, Área de Seção Transversal do Componente: 0.000621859 m2; CALHA EM CHAPA DE AÇO GALVANIZADO 4, Altura do Componente Retangular: 0.024998 m; CALHA EM CHAPA DE AÇO GALVANIZADO 4, Largura do Componente Retangular: 0.450452 m; CALHA EM CHAPA DE AÇO GALVANIZADO 4, Área de Seção Transversal do Componente: 0.0112605 m2
Name | TotalArea (m2) | 1_Bloco | CALHA EM CHAPA DE AÇO GALVANIZADO 1, Massa (kg) | CALHA EM CHAPA DE AÇO GALVANIZADO 1, Volume Componente (Líquido) (m3) = CALHA EM CHAPA DE AÇO GALVANIZADO 1, Volume do componente (Bruto) (m3) | CALHA EM CHAPA DE AÇO GALVANIZADO 2, Massa (kg) | CALHA EM CHAPA DE AÇO GALVANIZADO 2, Volume Componente (Líquido) (m3) = CALHA EM CHAPA DE AÇO GALVANIZADO 2, Volume do componente (Bruto) (m3) | CALHA EM CHAPA DE AÇO GALVANIZADO 3, Massa (kg) | CALHA EM CHAPA DE AÇO GALVANIZADO 3, Volume Componente (Líquido) (m3) = CALHA EM CHAPA DE AÇO GALVANIZADO 3, Volume do componente (Bruto) (m3) | CALHA EM CHAPA DE AÇO GALVANIZADO 4, Massa (kg) | CALHA EM CHAPA DE AÇO GALVANIZADO 4, Volume Componente (Líquido) (m3) = CALHA EM CHAPA DE AÇO GALVANIZADO 4, Volume do componente (Bruto) (m3) | CALHA EM CHAPA DE AÇO GALVANIZADO 3
V01 | 109.585 | BLOCO B | 574.827 | 0.072763 | 575.889 | 0.0728973 | 178.99 | 0.022657 | 3235.4 | 0.409544 | 2 with these values
V01 | 44.8155 | BLOCO A | 234.375 | 0.0296677 | 231.459 | 0.0292986 | 72.794 | 0.00921443 | 1315.92 | 0.166573 | Component Quantities - CALHA EM CHAPA DE AÇO GALVANIZADO 5, Massa: 72.8219 kg; CALHA EM CHAPA DE AÇO GALVANIZADO 5, Área de Seção Transversal do Componente: 0.000621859 m2; CALHA EM CHAPA DE AÇO GALVANIZADO 5, Volume Componente (Líquido): 0.00921796 m3; CALHA EM CHAPA DE AÇO GALVANIZADO 5, Volume do componente (Bruto): 0.00921796 m3
V01 | 45.3862 | BLOCO A | 237.812 | 0.0301027 | 238.095 | 0.0301386 | 74.0528 | 0.00937377 | 1337.87 | 0.169351 | 2 with these values

# IfcRoof: FNDE-Cumeeira 936 x 33, V05
In: COBERTURA
Classification: Cobertura (Classificação Archicad); Material: CUMEEIRA
Pset_RoofCommon - TotalArea: 15.9072 m2; IsExternal: yes
FNDE - Sistemas de Cobertura: CUMEEIRA METÁLICA; 1_Bloco: PÁTIO COBERTO; 0_ID: V05
Component Quantities - CUMEEIRA, Massa: 79.0671 kg; CUMEEIRA, Área de Seção Transversal do Componente: 0.00468468 m2; CUMEEIRA, Volume Componente (Líquido): 0.0395336 m3; CUMEEIRA, Volume do componente (Bruto): 0.0395336 m3

# IfcRoof: FNDE-Pingadeira em chapa de aço galvanizado 250 x 40 (38)
In: COBERTURA
Classification: Cobertura (Classificação Archicad); Material: PINGADEIRA EM CHAPA DE AÇO GALVANIZADO
Pset_RoofCommon - IsExternal: yes
FNDE - Sistemas de Cobertura: PINGADEIRA EM CHAPA DE AÇO GALVANIZADO
Component Quantities - PINGADEIRA EM CHAPA DE AÇO GALVANIZADO, Área de Seção Transversal do Componente: 0.000370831 m2
Name | TotalArea (m2) | 1_Bloco | 0_ID | PINGADEIRA EM CHAPA DE AÇO GALVANIZADO, Massa (kg) | PINGADEIRA EM CHAPA DE AÇO GALVANIZADO, Volume Componente (Líquido) (m3) | PINGADEIRA EM CHAPA DE AÇO GALVANIZADO, Volume do componente (Bruto) (m3)
V01 | 4.82736 | BLOCO A | V01 | 19.0126 | 0.00240666 | 0.00240666
V01 | 0.74471 | BLOCO A | V01 | 2.92956 | 0.000370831 | 0.000370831
V01 | 4.82738 | BLOCO A | V01 | 19.0127 | 0.00240667 | 0.00240667
V01 | 0.744753 | BLOCO A | V01 | 2.92973 | 0.000370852 | 0.000370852
V01 | 1.97137 | BLOCO A | V01 | 7.76183 | 0.00098251 | 0.00098251
V01 | 1.97137 | BLOCO A | V01 | 7.76183 | 0.000982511 | 0.000982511
V01 | 0.744712 | BLOCO A | V01 | 2.92957 | 0.000370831 | 0.000370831
V01 | 6.43918 | BLOCO A | V01 | 25.3603 | 0.00321017 | 0.00321017
V01 | 3.6694 | BLOCO A | V01 | 14.45 | 0.00182911 | 0.00182911
V01 | 2.0089 | BLOCO A | V01 | 7.90968 | 0.00100122 | 0.00100122
V01 | 3.68186 | BLOCO A | V01 | 14.5013 | 0.00183561 | 0.00183561
V01 | 0.744812 | BLOCO A | V01 | 2.92996 | 0.000370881 | 0.000370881
V01 | 3.6637 | BLOCO A | V01 | 14.4298 | 0.00182655 | 0.00182655
2 x V01 | 2.00892 | BLOCO A | V01 | 7.90975 | 0.00100123 | 0.00100123
V01 | 3.68142 | BLOCO A | V01 | 14.4996 | 0.00183539 | 0.00183539
V01 | 0.744658 | BLOCO B | V01 | 2.92936 | 0.000370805 | 0.000370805
V01 | 4.82741 | BLOCO B | V01 | 19.0129 | 0.00240669 | 0.00240669
V01 | 0.744635 | BLOCO B | V01 | 2.92927 | 0.000370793 | 0.000370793
V01 | 1.97171 | BLOCO B | V01 | 7.76317 | 0.00098268 | 0.00098268
V01 | 1.97173 | BLOCO B | V01 | 7.76327 | 0.000982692 | 0.000982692
V01 | 0.747784 | BLOCO B | V01 | 2.94167 | 0.000372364 | 0.000372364
V01 | 0.743176 | BLOCO B | V01 | 2.92352 | 0.000370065 | 0.000370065
V01 | 4.8272 | BLOCO B | V01 | 19.012 | 0.00240659 | 0.00240659
V01 | 3.65955 | BLOCO B | V01 | 14.4134 | 0.00182449 | 0.00182449
2 x V01 | 3.68186 | BLOCO B | V01 | 14.5013 | 0.00183561 | 0.00183561
V01 | 3.66326 | BLOCO B | V01 | 14.4281 | 0.00182634 | 0.00182634
3 x V01 | 2.00892 | BLOCO B | V01 | 7.90975 | 0.00100123 | 0.00100123
V01 | 6.47092 | BLOCO B | V01 | 25.4873 | 0.00322624 | 0.00322624
V02 | 33.3171 | MURO | V02 | 131.244 | 0.0166132 | 0.0166132
V03 | 28.3396 | MURO | V03 | 111.623 | 0.0141295 | 0.0141293
V01 | 3.75631 | BLOCO A | V01 | 14.794 | 0.00187266 | 0.00187266
V03 | 19.894 | BLOCO B | V03 | 78.3655 | 0.00991969 | 0.00991969
V02 | 19.8938 | BLOCO A | V02 | 78.3658 | 0.00991973 | 0.00991973
V01 | 3.75386 | BLOCO B | V01 | 14.7843 | 0.00187144 | 0.00187144

# IfcRoof: FNDE-Rufo 124 x 94 (73)
In: COBERTURA
Classification: Cobertura (Classificação Archicad); Material: RUFO EM CHAPA DE AÇO GALVANIZADO
Pset_RoofCommon - IsExternal: yes
FNDE - Sistemas de Cobertura: RUFO EM CHAPA DE AÇO GALV.
Component Quantities - RUFO EM CHAPA DE AÇO GALVANIZADO, Área de Seção Transversal do Componente: 0.000198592 m2
Name | TotalArea (m2) | 1_Bloco | 0_ID | RUFO EM CHAPA DE AÇO GALVANIZADO, Massa (kg) | RUFO EM CHAPA DE AÇO GALVANIZADO, Volume Componente (Líquido) (m3) = RUFO EM CHAPA DE AÇO GALVANIZADO, Volume do componente (Bruto) (m3)
V01 | 0.688198 | BLOCO A | V01 | 2.69801 | 0.000341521
V01 | 0.124234 | BLOCO A | V01 | 0.486523 | 0.0000615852
V01 | 0.963179 | BLOCO A | V01 | 3.7836 | 0.000478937
V01 | 0.140157 | BLOCO A | V01 | 0.547913 | 0.0000693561
V01 | 2.03848 | BLOCO A | V01 | 8.0097 | 0.00101389
V01 | 2.05614 | BLOCO A | V01 | 8.07865 | 0.00102261
V01 | 0.963172 | BLOCO A | V01 | 3.78357 | 0.000478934
V01 | 2.05628 | BLOCO A | V01 | 8.07932 | 0.0010227
V01 | 0.140643 | BLOCO A | V01 | 0.5505 | 0.0000696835
V01 | 0.140689 | BLOCO A | V01 | 0.550681 | 0.0000697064
V01 | 1.06031 | BLOCO A | V01 | 4.16499 | 0.000527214
V01 | 2.27681 | BLOCO A | V01 | 8.94659 | 0.00113248
V01 | 2.27777 | BLOCO A | V01 | 8.95016 | 0.00113293
V01 | 1.0603 | BLOCO A | V01 | 4.16495 | 0.000527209
V01 | 0.399732 | BLOCO A | V01 | 1.56887 | 0.000198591
V01 | 0.399757 | BLOCO A | V01 | 1.56897 | 0.000198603
V01 | 0.764592 | BLOCO A | V01 | 3.00275 | 0.000380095
V01 | 0.852395 | BLOCO A | V01 | 3.34783 | 0.000423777
V01 | 0.852543 | BLOCO A | V01 | 3.34842 | 0.000423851
V01 | 2.43779 | BLOCO A | V01 | 9.57789 | 0.00121239
V01 | 0.692838 | BLOCO A | V01 | 2.72143 | 0.000344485
V01 | 0.676775 | BLOCO A | V01 | 2.65812 | 0.000336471
V01 | 0.482083 | BLOCO A | V01 | 1.89313 | 0.000239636
V01 | 0.227657 | BLOCO A | V01 | 0.892997 | 0.000113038
V01 | 0.53738 | BLOCO A | V01 | 2.10993 | 0.000267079
V01 | 0.376543 | BLOCO A | V01 | 1.47527 | 0.000186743
V01 | 0.226755 | BLOCO A | V01 | 0.889452 | 0.000112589
V01 | 0.399713 | BLOCO A | V01 | 1.56879 | 0.000198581
V01 | 0.399734 | BLOCO A | V01 | 1.56887 | 0.000198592
V01 | 2.08384 | BLOCO A | V01 | 8.18782 | 0.00103643
V01 | 0.77257 | BLOCO A | V01 | 3.02627 | 0.000383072
V01 | 0.185705 | BLOCO B | V01 | 0.728117 | 0.0000921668
V01 | 0.239689 | BLOCO B | V01 | 0.940465 | 0.000119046
V01 | 0.144753 | BLOCO B | V01 | 0.566654 | 0.0000717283
V01 | 0.963179 | BLOCO B | V01 | 3.7836 | 0.000478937
V01 | 0.140338 | BLOCO B | V01 | 0.549302 | 0.0000695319
V01 | 2.06954 | BLOCO B | V01 | 8.12449 | 0.00102842
V01 | 2.05478 | BLOCO B | V01 | 8.07326 | 0.00102193
V01 | 2.05601 | BLOCO B | V01 | 8.07812 | 0.00102255
V01 | 0.963172 | BLOCO B | V01 | 3.78357 | 0.000478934
V01 | 2.056 | BLOCO B | V01 | 8.0781 | 0.00102254
V01 | 0.140643 | BLOCO B | V01 | 0.5505 | 0.0000696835
V01 | 1.06105 | BLOCO B | V01 | 4.16789 | 0.000527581
V01 | 0.140715 | BLOCO B | V01 | 0.550786 | 0.0000697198
V10 | 3.13961 | BLOCO B | V10 | 12.3275 | 0.00156045
V01 | 2.25453 | BLOCO B | V01 | 8.85527 | 0.00112092
V01 | 2.2767 | BLOCO B | V01 | 8.94618 | 0.00113243
V01 | 0.391745 | BLOCO B | V01 | 1.53575 | 0.000194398
V01 | 0.417334 | BLOCO B | V01 | 1.63821 | 0.000207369
V01 | 1.06256 | BLOCO B | V01 | 4.17383 | 0.000528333
V01 | 0.78311 | BLOCO B | V01 | 3.07571 | 0.000389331
V01 | 0.884452 | BLOCO B | V01 | 3.47434 | 0.000439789
V01 | 0.884416 | BLOCO B | V01 | 3.4742 | 0.000439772
V01 | 0.764547 | BLOCO B | V01 | 3.00258 | 0.000380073
V01 | 3.35824 | BLOCO B | V01 | 13.1966 | 0.00167046
V02 | 0.713874 | BLOCO B | V02 | 2.80393 | 0.000354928
V01 | 3.634 | BLOCO B | V01 | 14.2785 | 0.0018074
V01 | 0.718086 | BLOCO B | V01 | 2.82049 | 0.000357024
V01 | 0.399761 | BLOCO B | V01 | 1.56898 | 0.000198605
V01 | 0.413184 | BLOCO B | V01 | 1.62131 | 0.00020523
V13 | 0.963779 | BLOCO B | V13 | 3.78596 | 0.000479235
V14 | 0.13923 | BLOCO B | V14 | 0.544941 | 0.0000689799
V02 | 10.7186 | BLOCO A | V02 | 42.1241 | 0.00533217
V03 | 2.05629 | BLOCO A | V03 | 8.0795 | 0.00102272
V05 | 0.963167 | BLOCO A | V05 | 3.78356 | 0.000478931
V12 | 0.139227 | BLOCO B | V12 | 0.544937 | 0.0000689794
V09 | 3.13354 | BLOCO B | V09 | 12.3034 | 0.00155739
V04 | 0.140535 | BLOCO A | V04 | 0.550078 | 0.0000696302
V06 | 0.140526 | BLOCO A | V06 | 0.550042 | 0.0000696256
V11 | 10.7187 | BLOCO B | V11 | 42.1245 | 0.00533222
V15 | 2.05631 | BLOCO B | V15 | 8.07957 | 0.00102273
V08 | 3.15085 | BLOCO A | V08 | 12.3786 | 0.00156691
V07 | 3.15095 | BLOCO A | V07 | 12.3807 | 0.00156717

# IfcRoof: TELHA METÁLICA TERMOACÚSTICA 70 (10)
In: COBERTURA
Classification: Cobertura (Classificação Archicad); Material: TELHA METÁLICA TERMOACÚSTICA
Pset_RoofCommon - IsExternal: yes
FNDE - Sistemas de Cobertura: -
Component Quantities - TELHA METÁLICA TERMOACÚSTICA, Espessura do Componente: 0.07 m
Name | TotalArea (m2) = TELHA METÁLICA TERMOACÚSTICA, Área de Componente Projetada (Líquida) (m2) = TELHA METÁLICA TERMOACÚSTICA, Área de Componente Projetada (Bruta) (m2) | 1_Bloco | 0_ID | TELHA METÁLICA TERMOACÚSTICA, Massa (kg) | TELHA METÁLICA TERMOACÚSTICA, Volume Componente (Líquido) (m3) = TELHA METÁLICA TERMOACÚSTICA, Volume do componente (Bruto) (m3)
Cobert.-001 | 32.6255 | BLOCO B | Cobert.-001 | 4567.57 | 2.28378
Cobert.-001 | 15.5326 | BLOCO B | Cobert.-001 | 2174.56 | 1.08728
Cobert.-001 | 32.7078 | BLOCO B | Cobert.-001 | 4579.09 | 2.28954
Cobert.-001 | 33.1009 | BLOCO A | Cobert.-001 | 4634.12 | 2.31706
Cobert.-001 | 32.9962 | BLOCO A | Cobert.-001 | 4619.47 | 2.30973
Cobert.-001 | 10.7954 | BLOCO A | Cobert.-001 | 1511.36 | 0.755678
Cobert.-004 | 299.25 | BLOCO B | Cobert.-004 | 41895 | 20.9475
Cobert.-005 | 289.084 | BLOCO A | Cobert.-005 | 40471.8 | 20.2359
Cobert.-005 | 67.0939 | PÁTIO COBERTO | Cobert.-005 | 9393.15 | 4.69658
Cobert.-005 | 67.0936 | PÁTIO COBERTO | Cobert.-005 | 9393.11 | 4.69655

# IfcRoof: Várias Estruturas- 2 Segmentos - 250 x 40 x 1700 (1+1699), V01
In: COBERTURA
Classification: Cobertura (Classificação Archicad); Material: PINGADEIRA EM CHAPA DE AÇO GALVANIZADO (2)
Pset_RoofCommon - TotalArea: 1.28481 m2; IsExternal: yes
FNDE - Sistemas de Cobertura: PINGADEIRA EM CHAPA DE AÇO GALVANIZADO; 1_Bloco: BLOCO A; 0_ID: V01
Component Quantities - PINGADEIRA EM CHAPA DE AÇO GALVANIZADO 1, Massa: 0.0790118 kg; PINGADEIRA EM CHAPA DE AÇO GALVANIZADO 1, Altura do Componente Retangular: 0.04 m; PINGADEIRA EM CHAPA DE AÇO GALVANIZADO 1, Largura do Componente Retangular: 0.250037 m; PINGADEIRA EM CHAPA DE AÇO GALVANIZADO 1, Área de Seção Transversal do Componente: 0.0100015 m2; PINGADEIRA EM CHAPA DE AÇO GALVANIZADO 1, Volume Componente (Líquido): 0.0000100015 m3; PINGADEIRA EM CHAPA DE AÇO GALVANIZADO 1, Volume do componente (Bruto): 0.0000100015 m3; PINGADEIRA EM CHAPA DE AÇO GALVANIZADO 2, Massa: 4.97733 kg; PINGADEIRA EM CHAPA DE AÇO GALVANIZADO 2, Área de Seção Transversal do Componente: 0.000370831 m2; PINGADEIRA EM CHAPA DE AÇO GALVANIZADO 2, Volume Componente (Líquido): 0.000630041 m3; PINGADEIRA EM CHAPA DE AÇO GALVANIZADO 2, Volume do componente (Bruto): 0.000630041 m3

# IfcRoof: Várias Estruturas- 2 Segmentos - 250 x 40 x 1700 (1699+1), V01
In: COBERTURA
Classification: Cobertura (Classificação Archicad); Material: PINGADEIRA EM CHAPA DE AÇO GALVANIZADO (2)
Pset_RoofCommon - TotalArea: 1.28481 m2; IsExternal: yes
FNDE - Sistemas de Cobertura: PINGADEIRA EM CHAPA DE AÇO GALVANIZADO; 1_Bloco: BLOCO A; 0_ID: V01
Component Quantities - PINGADEIRA EM CHAPA DE AÇO GALVANIZADO 1, Massa: 4.97733 kg; PINGADEIRA EM CHAPA DE AÇO GALVANIZADO 1, Área de Seção Transversal do Componente: 0.000370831 m2; PINGADEIRA EM CHAPA DE AÇO GALVANIZADO 1, Volume Componente (Líquido): 0.000630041 m3; PINGADEIRA EM CHAPA DE AÇO GALVANIZADO 1, Volume do componente (Bruto): 0.000630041 m3; PINGADEIRA EM CHAPA DE AÇO GALVANIZADO 2, Massa: 0.0790118 kg; PINGADEIRA EM CHAPA DE AÇO GALVANIZADO 2, Altura do Componente Retangular: 0.04 m; PINGADEIRA EM CHAPA DE AÇO GALVANIZADO 2, Largura do Componente Retangular: 0.250037 m; PINGADEIRA EM CHAPA DE AÇO GALVANIZADO 2, Área de Seção Transversal do Componente: 0.0100015 m2; PINGADEIRA EM CHAPA DE AÇO GALVANIZADO 2, Volume Componente (Líquido): 0.0000100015 m3; PINGADEIRA EM CHAPA DE AÇO GALVANIZADO 2, Volume do componente (Bruto): 0.0000100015 m3

# IfcRoof: Várias Estruturas- 2 Segmentos - 250 x 40 x 2536 (1+2535), V01
In: COBERTURA
Classification: Cobertura (Classificação Archicad); Material: PINGADEIRA EM CHAPA DE AÇO GALVANIZADO (2)
Pset_RoofCommon - TotalArea: 1.78988 m2; IsExternal: yes
FNDE - Sistemas de Cobertura: PINGADEIRA EM CHAPA DE AÇO GALVANIZADO; 1_Bloco: BLOCO A; 0_ID: V01
Component Quantities - PINGADEIRA EM CHAPA DE AÇO GALVANIZADO 1, Massa: 0.0458317 kg; PINGADEIRA EM CHAPA DE AÇO GALVANIZADO 1, Altura do Componente Retangular: 0.04 m; PINGADEIRA EM CHAPA DE AÇO GALVANIZADO 1, Largura do Componente Retangular: 0.250037 m; PINGADEIRA EM CHAPA DE AÇO GALVANIZADO 1, Área de Seção Transversal do Componente: 0.0100015 m2; PINGADEIRA EM CHAPA DE AÇO GALVANIZADO 1, Volume Componente (Líquido): 0.00000580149 m3; PINGADEIRA EM CHAPA DE AÇO GALVANIZADO 1, Volume do componente (Bruto): 0.00000580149 m3; PINGADEIRA EM CHAPA DE AÇO GALVANIZADO 2, Massa: 6.99868 kg; PINGADEIRA EM CHAPA DE AÇO GALVANIZADO 2, Área de Seção Transversal do Componente: 0.000370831 m2; PINGADEIRA EM CHAPA DE AÇO GALVANIZADO 2, Volume Componente (Líquido): 0.000885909 m3; PINGADEIRA EM CHAPA DE AÇO GALVANIZADO 2, Volume do componente (Bruto): 0.000885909 m3

# IfcRoof: Várias Estruturas- 2 Segmentos - 250 x 40 x 2560 (1+2559) (2)
In: COBERTURA
Classification: Cobertura (Classificação Archicad); Material: PINGADEIRA EM CHAPA DE AÇO GALVANIZADO (2)
Pset_RoofCommon - IsExternal: yes
FNDE - Sistemas de Cobertura: PINGADEIRA EM CHAPA DE AÇO GALVANIZADO; 0_ID: V01
Component Quantities - PINGADEIRA EM CHAPA DE AÇO GALVANIZADO 1, Massa: 0.0790118 kg; PINGADEIRA EM CHAPA DE AÇO GALVANIZADO 1, Altura do Componente Retangular: 0.04 m; PINGADEIRA EM CHAPA DE AÇO GALVANIZADO 1, Largura do Componente Retangular: 0.250037 m; PINGADEIRA EM CHAPA DE AÇO GALVANIZADO 1, Área de Seção Transversal do Componente: 0.0100015 m2; PINGADEIRA EM CHAPA DE AÇO GALVANIZADO 1, Volume Componente (Líquido): 0.0000100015 m3; PINGADEIRA EM CHAPA DE AÇO GALVANIZADO 1, Volume do componente (Bruto): 0.0000100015 m3; PINGADEIRA EM CHAPA DE AÇO GALVANIZADO 2, Área de Seção Transversal do Componente: 0.000370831 m2
Name | TotalArea (m2) | 1_Bloco | PINGADEIRA EM CHAPA DE AÇO GALVANIZADO 2, Massa (kg) | PINGADEIRA EM CHAPA DE AÇO GALVANIZADO 2, Volume Componente (Líquido) (m3) = PINGADEIRA EM CHAPA DE AÇO GALVANIZADO 2, Volume do componente (Bruto) (m3)
V01 | 1.81603 | BLOCO A | 7.06884 | 0.00089479
V01 | 1.81599 | BLOCO B | 7.06867 | 0.000894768

# IfcRoof: Várias Estruturas- 2 Segmentos - 250 x 40 x 2560 (2559+1), V01
In: COBERTURA
Classification: Cobertura (Classificação Archicad); Material: PINGADEIRA EM CHAPA DE AÇO GALVANIZADO (2)
Pset_RoofCommon - TotalArea: 1.816 m2; IsExternal: yes
FNDE - Sistemas de Cobertura: PINGADEIRA EM CHAPA DE AÇO GALVANIZADO; 1_Bloco: BLOCO B; 0_ID: V01
Component Quantities - PINGADEIRA EM CHAPA DE AÇO GALVANIZADO 1, Massa: 7.06872 kg; PINGADEIRA EM CHAPA DE AÇO GALVANIZADO 1, Área de Seção Transversal do Componente: 0.000370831 m2; PINGADEIRA EM CHAPA DE AÇO GALVANIZADO 1, Volume Componente (Líquido): 0.000894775 m3; PINGADEIRA EM CHAPA DE AÇO GALVANIZADO 1, Volume do componente (Bruto): 0.000894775 m3; PINGADEIRA EM CHAPA DE AÇO GALVANIZADO 2, Massa: 0.0790118 kg; PINGADEIRA EM CHAPA DE AÇO GALVANIZADO 2, Altura do Componente Retangular: 0.04 m; PINGADEIRA EM CHAPA DE AÇO GALVANIZADO 2, Largura do Componente Retangular: 0.250037 m; PINGADEIRA EM CHAPA DE AÇO GALVANIZADO 2, Área de Seção Transversal do Componente: 0.0100015 m2; PINGADEIRA EM CHAPA DE AÇO GALVANIZADO 2, Volume Componente (Líquido): 0.0000100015 m3; PINGADEIRA EM CHAPA DE AÇO GALVANIZADO 2, Volume do componente (Bruto): 0.0000100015 m3

# IfcRoof: Várias Estruturas- 2 Segmentos - 250 x 40 x 2705 (1+2704), V01
In: COBERTURA
Classification: Cobertura (Classificação Archicad); Material: PINGADEIRA EM CHAPA DE AÇO GALVANIZADO (2)
Pset_RoofCommon - TotalArea: 1.93927 m2; IsExternal: yes
FNDE - Sistemas de Cobertura: PINGADEIRA EM CHAPA DE AÇO GALVANIZADO; 1_Bloco: BLOCO A; 0_ID: V01
Component Quantities - PINGADEIRA EM CHAPA DE AÇO GALVANIZADO 1, Massa: 0.0790118 kg; PINGADEIRA EM CHAPA DE AÇO GALVANIZADO 1, Altura do Componente Retangular: 0.04 m; PINGADEIRA EM CHAPA DE AÇO GALVANIZADO 1, Largura do Componente Retangular: 0.250037 m; PINGADEIRA EM CHAPA DE AÇO GALVANIZADO 1, Área de Seção Transversal do Componente: 0.0100015 m2; PINGADEIRA EM CHAPA DE AÇO GALVANIZADO 1, Volume Componente (Líquido): 0.0000100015 m3; PINGADEIRA EM CHAPA DE AÇO GALVANIZADO 1, Volume do componente (Bruto): 0.0000100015 m3; PINGADEIRA EM CHAPA DE AÇO GALVANIZADO 2, Massa: 7.55491 kg; PINGADEIRA EM CHAPA DE AÇO GALVANIZADO 2, Área de Seção Transversal do Componente: 0.000370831 m2; PINGADEIRA EM CHAPA DE AÇO GALVANIZADO 2, Volume Componente (Líquido): 0.000956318 m3; PINGADEIRA EM CHAPA DE AÇO GALVANIZADO 2, Volume do componente (Bruto): 0.000956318 m3

# IfcRoof: Várias Estruturas- 2 Segmentos - 250 x 40 x 2715 (2714+1), V01
In: COBERTURA
Classification: Cobertura (Classificação Archicad); Material: PINGADEIRA EM CHAPA DE AÇO GALVANIZADO (2)
Pset_RoofCommon - TotalArea: 1.94683 m2; IsExternal: yes
FNDE - Sistemas de Cobertura: PINGADEIRA EM CHAPA DE AÇO GALVANIZADO; 1_Bloco: BLOCO A; 0_ID: V01
Component Quantities - PINGADEIRA EM CHAPA DE AÇO GALVANIZADO 1, Massa: 7.58468 kg; PINGADEIRA EM CHAPA DE AÇO GALVANIZADO 1, Área de Seção Transversal do Componente: 0.000370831 m2; PINGADEIRA EM CHAPA DE AÇO GALVANIZADO 1, Volume Componente (Líquido): 0.000960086 m3; PINGADEIRA EM CHAPA DE AÇO GALVANIZADO 1, Volume do componente (Bruto): 0.000960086 m3; PINGADEIRA EM CHAPA DE AÇO GALVANIZADO 2, Massa: 0.0790118 kg; PINGADEIRA EM CHAPA DE AÇO GALVANIZADO 2, Altura do Componente Retangular: 0.04 m; PINGADEIRA EM CHAPA DE AÇO GALVANIZADO 2, Largura do Componente Retangular: 0.250037 m; PINGADEIRA EM CHAPA DE AÇO GALVANIZADO 2, Área de Seção Transversal do Componente: 0.0100015 m2; PINGADEIRA EM CHAPA DE AÇO GALVANIZADO 2, Volume Componente (Líquido): 0.0000100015 m3; PINGADEIRA EM CHAPA DE AÇO GALVANIZADO 2, Volume do componente (Bruto): 0.0000100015 m3

# IfcRoof: Várias Estruturas- 2 Segmentos - 250 x 40 x 2850 (1+2849), V01
In: COBERTURA
Classification: Cobertura (Classificação Archicad); Material: PINGADEIRA EM CHAPA DE AÇO GALVANIZADO (2)
Pset_RoofCommon - TotalArea: 2.04722 m2; IsExternal: yes
FNDE - Sistemas de Cobertura: PINGADEIRA EM CHAPA DE AÇO GALVANIZADO; 1_Bloco: BLOCO B; 0_ID: V01
Component Quantities - PINGADEIRA EM CHAPA DE AÇO GALVANIZADO 1, Massa: 0.0790118 kg; PINGADEIRA EM CHAPA DE AÇO GALVANIZADO 1, Altura do Componente Retangular: 0.04 m; PINGADEIRA EM CHAPA DE AÇO GALVANIZADO 1, Largura do Componente Retangular: 0.250037 m; PINGADEIRA EM CHAPA DE AÇO GALVANIZADO 1, Área de Seção Transversal do Componente: 0.0100015 m2; PINGADEIRA EM CHAPA DE AÇO GALVANIZADO 1, Volume Componente (Líquido): 0.0000100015 m3; PINGADEIRA EM CHAPA DE AÇO GALVANIZADO 1, Volume do componente (Bruto): 0.0000100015 m3; PINGADEIRA EM CHAPA DE AÇO GALVANIZADO 2, Massa: 7.98016 kg; PINGADEIRA EM CHAPA DE AÇO GALVANIZADO 2, Área de Seção Transversal do Componente: 0.000370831 m2; PINGADEIRA EM CHAPA DE AÇO GALVANIZADO 2, Volume Componente (Líquido): 0.00101015 m3; PINGADEIRA EM CHAPA DE AÇO GALVANIZADO 2, Volume do componente (Bruto): 0.00101015 m3

# IfcRoof: Várias Estruturas- 2 Segmentos - 250 x 40 x 2850 (2849+1), V01
In: COBERTURA
Classification: Cobertura (Classificação Archicad); Material: PINGADEIRA EM CHAPA DE AÇO GALVANIZADO (2)
Pset_RoofCommon - TotalArea: 2.04725 m2; IsExternal: yes
FNDE - Sistemas de Cobertura: PINGADEIRA EM CHAPA DE AÇO GALVANIZADO; 1_Bloco: BLOCO B; 0_ID: V01
Component Quantities - PINGADEIRA EM CHAPA DE AÇO GALVANIZADO 1, Massa: 7.98027 kg; PINGADEIRA EM CHAPA DE AÇO GALVANIZADO 1, Área de Seção Transversal do Componente: 0.000370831 m2; PINGADEIRA EM CHAPA DE AÇO GALVANIZADO 1, Volume Componente (Líquido): 0.00101016 m3; PINGADEIRA EM CHAPA DE AÇO GALVANIZADO 1, Volume do componente (Bruto): 0.00101016 m3; PINGADEIRA EM CHAPA DE AÇO GALVANIZADO 2, Massa: 0.0790118 kg; PINGADEIRA EM CHAPA DE AÇO GALVANIZADO 2, Altura do Componente Retangular: 0.04 m; PINGADEIRA EM CHAPA DE AÇO GALVANIZADO 2, Largura do Componente Retangular: 0.250037 m; PINGADEIRA EM CHAPA DE AÇO GALVANIZADO 2, Área de Seção Transversal do Componente: 0.0100015 m2; PINGADEIRA EM CHAPA DE AÇO GALVANIZADO 2, Volume Componente (Líquido): 0.0000100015 m3; PINGADEIRA EM CHAPA DE AÇO GALVANIZADO 2, Volume do componente (Bruto): 0.0000100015 m3

# IfcRoof: Várias Estruturas- 2 Segmentos - 250 x 40 x 40025 (1+40024), V01
In: COBERTURA
Classification: Cobertura (Classificação Archicad); Material: PINGADEIRA EM CHAPA DE AÇO GALVANIZADO (2)
Pset_RoofCommon - TotalArea: 29.6845 m2; IsExternal: yes
FNDE - Sistemas de Cobertura: PINGADEIRA EM CHAPA DE AÇO GALVANIZADO; 1_Bloco: MURO; 0_ID: V01
Component Quantities - PINGADEIRA EM CHAPA DE AÇO GALVANIZADO 1, Massa: 0.0458318 kg; PINGADEIRA EM CHAPA DE AÇO GALVANIZADO 1, Altura do Componente Retangular: 0.04 m; PINGADEIRA EM CHAPA DE AÇO GALVANIZADO 1, Largura do Componente Retangular: 0.250037 m; PINGADEIRA EM CHAPA DE AÇO GALVANIZADO 1, Área de Seção Transversal do Componente: 0.0100015 m2; PINGADEIRA EM CHAPA DE AÇO GALVANIZADO 1, Volume Componente (Líquido): 0.0000058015 m3; PINGADEIRA EM CHAPA DE AÇO GALVANIZADO 1, Volume do componente (Bruto): 0.0000058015 m3; PINGADEIRA EM CHAPA DE AÇO GALVANIZADO 2, Massa: 116.887 kg; PINGADEIRA EM CHAPA DE AÇO GALVANIZADO 2, Área de Seção Transversal do Componente: 0.000370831 m2; PINGADEIRA EM CHAPA DE AÇO GALVANIZADO 2, Volume Componente (Líquido): 0.0147958 m3; PINGADEIRA EM CHAPA DE AÇO GALVANIZADO 2, Volume do componente (Bruto): 0.0147958 m3

# IfcRoof: Várias Estruturas- 2 Segmentos - 250 x 40 x 609 (1+608) (5)
In: COBERTURA
Classification: Cobertura (Classificação Archicad); Material: PINGADEIRA EM CHAPA DE AÇO GALVANIZADO (2)
Pset_RoofCommon - IsExternal: yes
FNDE - Sistemas de Cobertura: PINGADEIRA EM CHAPA DE AÇO GALVANIZADO; 0_ID: V01
Component Quantities - PINGADEIRA EM CHAPA DE AÇO GALVANIZADO 1, Massa: 0.0790118 kg; PINGADEIRA EM CHAPA DE AÇO GALVANIZADO 1, Altura do Componente Retangular: 0.04 m; PINGADEIRA EM CHAPA DE AÇO GALVANIZADO 1, Largura do Componente Retangular: 0.250037 m; PINGADEIRA EM CHAPA DE AÇO GALVANIZADO 1, Área de Seção Transversal do Componente: 0.0100015 m2; PINGADEIRA EM CHAPA DE AÇO GALVANIZADO 1, Volume Componente (Líquido): 0.0000100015 m3; PINGADEIRA EM CHAPA DE AÇO GALVANIZADO 1, Volume do componente (Bruto): 0.0000100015 m3; PINGADEIRA EM CHAPA DE AÇO GALVANIZADO 2, Área de Seção Transversal do Componente: 0.000370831 m2
Name | TotalArea (m2) | 1_Bloco | PINGADEIRA EM CHAPA DE AÇO GALVANIZADO 2, Massa (kg) | PINGADEIRA EM CHAPA DE AÇO GALVANIZADO 2, Volume Componente (Líquido) (m3) = PINGADEIRA EM CHAPA DE AÇO GALVANIZADO 2, Volume do componente (Bruto) (m3)
V01 | 0.380761 | BLOCO A | 1.41535 | 0.000179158
V01 | 0.380615 | BLOCO A | 1.41478 | 0.000179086
V01 | 0.38066 | BLOCO B | 1.41495 | 0.000179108
V01 | 0.380636 | BLOCO A | 1.41486 | 0.000179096
V01 | 0.380636 | BLOCO B | 1.41486 | 0.000179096

# IfcRoof: Várias Estruturas- 2 Segmentos - 250 x 40 x 609 (608+1) (6)
In: COBERTURA
Classification: Cobertura (Classificação Archicad); Material: PINGADEIRA EM CHAPA DE AÇO GALVANIZADO (2)
Pset_RoofCommon - IsExternal: yes
FNDE - Sistemas de Cobertura: PINGADEIRA EM CHAPA DE AÇO GALVANIZADO; 0_ID: V01
Component Quantities - PINGADEIRA EM CHAPA DE AÇO GALVANIZADO 1, Área de Seção Transversal do Componente: 0.000370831 m2; PINGADEIRA EM CHAPA DE AÇO GALVANIZADO 2, Massa: 0.0790118 kg; PINGADEIRA EM CHAPA DE AÇO GALVANIZADO 2, Altura do Componente Retangular: 0.04 m; PINGADEIRA EM CHAPA DE AÇO GALVANIZADO 2, Largura do Componente Retangular: 0.250037 m; PINGADEIRA EM CHAPA DE AÇO GALVANIZADO 2, Área de Seção Transversal do Componente: 0.0100015 m2; PINGADEIRA EM CHAPA DE AÇO GALVANIZADO 2, Volume Componente (Líquido): 0.0000100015 m3; PINGADEIRA EM CHAPA DE AÇO GALVANIZADO 2, Volume do componente (Bruto): 0.0000100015 m3
Name | TotalArea (m2) | 1_Bloco | PINGADEIRA EM CHAPA DE AÇO GALVANIZADO 1, Massa (kg) | PINGADEIRA EM CHAPA DE AÇO GALVANIZADO 1, Volume Componente (Líquido) (m3) = PINGADEIRA EM CHAPA DE AÇO GALVANIZADO 1, Volume do componente (Bruto) (m3)
V01 | 0.380661 | BLOCO A | 1.41496 | 0.000179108
V01 | 0.380619 | BLOCO A | 1.41479 | 0.000179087
3 x V01 | 0.380635 | BLOCO B | 1.41486 | 0.000179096
V01 | 0.380635 | BLOCO A | 1.41486 | 0.000179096

# IfcRoof: Várias Estruturas- 2 Segmentos - 250 x 40 x 612 (1+611), V01
In: COBERTURA
Classification: Cobertura (Classificação Archicad); Material: PINGADEIRA EM CHAPA DE AÇO GALVANIZADO (2)
Pset_RoofCommon - TotalArea: 0.383245 m2; IsExternal: yes
FNDE - Sistemas de Cobertura: PINGADEIRA EM CHAPA DE AÇO GALVANIZADO; 1_Bloco: BLOCO B; 0_ID: V01
Component Quantities - PINGADEIRA EM CHAPA DE AÇO GALVANIZADO 1, Massa: 0.0790118 kg; PINGADEIRA EM CHAPA DE AÇO GALVANIZADO 1, Altura do Componente Retangular: 0.04 m; PINGADEIRA EM CHAPA DE AÇO GALVANIZADO 1, Largura do Componente Retangular: 0.250037 m; PINGADEIRA EM CHAPA DE AÇO GALVANIZADO 1, Área de Seção Transversal do Componente: 0.0100015 m2; PINGADEIRA EM CHAPA DE AÇO GALVANIZADO 1, Volume Componente (Líquido): 0.0000100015 m3; PINGADEIRA EM CHAPA DE AÇO GALVANIZADO 1, Volume do componente (Bruto): 0.0000100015 m3; PINGADEIRA EM CHAPA DE AÇO GALVANIZADO 2, Massa: 1.42514 kg; PINGADEIRA EM CHAPA DE AÇO GALVANIZADO 2, Área de Seção Transversal do Componente: 0.000370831 m2; PINGADEIRA EM CHAPA DE AÇO GALVANIZADO 2, Volume Componente (Líquido): 0.000180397 m3; PINGADEIRA EM CHAPA DE AÇO GALVANIZADO 2, Volume do componente (Bruto): 0.000180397 m3

# IfcSanitaryTerminal: Banheira 27 (2)
In: TÉRREO
Classification: Terminal Hidrosanitário (Classificação Archicad)
Pset_ManufacturerTypeInformation - ModelLabel: BANHEIRA PLÁSTICA RÍGIDA, 77x45x20cm DE EMBUTIR, BURIGOTTO OU EQUIVALENTE
FNDE - Mobiliário ou Equipamento - Modelo: BANHEIRA PLÁSTICA RÍGIDA, 77x45x20cm DE EMBUTIR, BURIGOTTO OU EQUIVALENTE; 1_Bloco: BLOCO A; 0_ID: BP
Component Quantities - Component, Volume Componente (Líquido): 0.00799275 m3; Component, Volume do componente (Bruto): 0.00799275 m3

# IfcSanitaryTerminal: Basin Oval #1397 (14)
In: TÉRREO
Classification: Terminal Hidrosanitário (Classificação Archicad)
Pset_ManufacturerTypeInformation - ModelLabel: CUBA DE EMBUTIR OVAL COR BRANCO GELO, DECA OU EQUIVALENTE
FNDE - Mobiliário ou Equipamento - Modelo: CUBA DE EMBUTIR OVAL COR BRANCO GELO, DECA OU EQUIVALENTE; 0_ID: CB
Component Quantities - Component, Volume Componente (Líquido): 0.00282224 m3; Component, Volume do componente (Bruto): 0.00282224 m3
Name | 1_Bloco
6 x CB | BLOCO A
8 x CB | BLOCO B

# IfcSanitaryTerminal: Chuveiro Elétrico (1) (8)
In: TÉRREO
Classification: Terminal Hidrosanitário (Classificação Archicad)
Pset_ManufacturerTypeInformation - ModelLabel: CHUVEIRO COM DESVIADOR PARA DUCHAS ELÉTRICAS, LORENZETTI OU EQUIVALENTE
FNDE - Mobiliário ou Equipamento - Modelo: CHUVEIRO COM DESVIADOR PARA DUCHAS ELÉTRICAS, LORENZETTI OU EQUIVALENTE; 0_ID: CH
Component Quantities - Component, Volume Componente (Líquido): 0 m3; Component, Volume do componente (Bruto): 0 m3
Name | 1_Bloco
5 x CH | BLOCO B
3 x CH | BLOCO A

# IfcSanitaryTerminal: Deca Izy Parede (16)
In: TÉRREO
Classification: Terminal Hidrosanitário (Classificação Archicad)
Pset_ManufacturerTypeInformation - ModelLabel: TORNEIRA DE PAREDE DE USO GERAL PARA TANQUE OU JARDIM
FNDE - Mobiliário ou Equipamento - Modelo: TORNEIRA DE PAREDE DE USO GERAL PARA TANQUE OU JARDIM; 0_ID: TJ
Component Quantities - Component, Volume Componente (Líquido): 0.000109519 m3; Component, Volume do componente (Bruto): 0.000109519 m3
Name | 1_Bloco
8 x TJ | BLOCO A
4 x TJ | BLOCO B
4 x TJ | CASA DE BOMBAS / GÁS / LIXO

# IfcSanitaryTerminal: Deca Sif+úo para Lavat+¦rio Slim (34)
In: TÉRREO
Classification: Terminal Hidrosanitário (Classificação Archicad)
Pset_ManufacturerTypeInformation - ModelLabel: SIFÃO CROMADO
FNDE - Mobiliário ou Equipamento - Modelo: SIFÃO CROMADO; 0_ID: SF
Name | 1_Bloco | Component, Volume Componente (Líquido) (m3) = Component, Volume do componente (Bruto) (m3)
8 x SF | BLOCO B | 0.000490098
15 x SF | BLOCO A | 0.000418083
5 x SF | BLOCO B | 0.000418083
6 x SF | BLOCO A | 0.000490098

# IfcSanitaryTerminal: Ducha_Higiênica_Deca_Universal (11)
In: TÉRREO
Classification: Terminal Hidrosanitário (Classificação Archicad); Material: Alumínio
Pset_ManufacturerTypeInformation - ModelLabel: DUCHA HIGIÊNICA COM REGISTRO E DERIVAÇAO, DECA OU EQUIVALENTE
FNDE - Mobiliário ou Equipamento - Modelo: DUCHA HIGIÊNICA COM REGISTRO E DERIVAÇAO, DECA OU EQUIVALENTE; 0_ID: DH
Name | 1_Bloco | Alumínio, Massa (kg) | Alumínio, Volume Componente (Líquido) (m3) = Alumínio, Volume do componente (Bruto) (m3)
9 x DH | BLOCO B | 0.296288 | 0.000105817
2 x DH | BLOCO A | 0.242195 | 0.0000864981

# IfcSanitaryTerminal: Lavatório 27 (2)
In: TÉRREO
Classification: Terminal Hidrosanitário (Classificação Archicad)
Pset_ManufacturerTypeInformation - ModelLabel: LAVATÓRIO PEQUENO COR BRANCO GELO, COM COLUNA SUSPENSA, DECA OU EQUIVALENTE
FNDE - Mobiliário ou Equipamento - Modelo: LAVATÓRIO PEQUENO COR BRANCO GELO, COM COLUNA SUSPENSA, DECA OU EQUIVALENTE; 1_Bloco: BLOCO A; 0_ID: LV3
Component Quantities - Component, Volume Componente (Líquido): 0.0100128 m3; Component, Volume do componente (Bruto): 0.0100128 m3

# IfcSanitaryTerminal: Lavatório de Canto 27 (3)
In: TÉRREO
Classification: Terminal Hidrosanitário (Classificação Archicad)
Pset_ManufacturerTypeInformation - ModelLabel: LAVATÓRIO DE CANTO SUSPENSO, DECA OU EQUIVALENTE
FNDE - Mobiliário ou Equipamento - Modelo: LAVATÓRIO DE CANTO SUSPENSO, DECA OU EQUIVALENTE; 0_ID: LV1
Component Quantities - Component, Volume Componente (Líquido): 0 m3; Component, Volume do componente (Bruto): 0 m3
Name | 1_Bloco
LV1 | BLOCO B
2 x LV1 | BLOCO A

# IfcSanitaryTerminal: Pia Belfast 27 (13)
In: TÉRREO
Classification: Terminal Hidrosanitário (Classificação Archicad)
Name | ModelLabel = Mobiliário ou Equipamento - Modelo | 1_Bloco | 0_ID | Component, Volume Componente (Líquido) (m3) = Component, Volume do componente (Bruto) (m3)
8 x CM2 | CUBA INOX DE EMBUTIR (50x40x20cm) | BLOCO A | CM2 | 0.0178919
4 x CM1 | CUBA INOX DE EMBUTIR (40x34x17cm) | BLOCO B | CM1 | 0.0117844
CM3 | CUBA INOX DE EMBUTIR (60x50x40cm) | BLOCO A | CM3 | 0.0401781

# IfcSanitaryTerminal: Tanque de Lavar Roupa 27 (4)
In: TÉRREO
Classification: Terminal Hidrosanitário (Classificação Archicad)
Pset_ManufacturerTypeInformation - ModelLabel: TANQUE DE LOUÇA 40l, COR BRANCO GELO, DECA OU EQUIVALENTE
FNDE - Mobiliário ou Equipamento - Modelo: TANQUE DE LOUÇA 40l, COR BRANCO GELO, DECA OU EQUIVALENTE; 1_Bloco: BLOCO A; 0_ID: TQ
Component Quantities - Component, Volume Componente (Líquido): 0.0238542 m3; Component, Volume do componente (Bruto): 0.0238542 m3

# IfcSanitaryTerminal: Torneira 27 (27)
In: TÉRREO
Classification: Terminal Hidrosanitário (Classificação Archicad)
Name | ModelLabel = Mobiliário ou Equipamento - Modelo | 1_Bloco | 0_ID | Component, Volume Componente (Líquido) (m3) = Component, Volume do componente (Bruto) (m3)
4 x TM3 | TORNEIRA PARA COZINHA DE MESA BICA MÓVEL, DECA OU EQUIVALENTE | BLOCO A | TM3 | 0.000120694
4 x TM3 | TORNEIRA PARA COZINHA DE MESA BICA MÓVEL, DECA OU EQUIVALENTE | BLOCO B | TM3 | 0.000120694
TM2 | TORNEIRA PARA LAVATÓRIO COM ACIONAMENTO POR ALAVANCA | BLOCO B | TM2 | 0.000187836
8 x TM1 | TORNEIRA AUTOMÁTICA DE PRESSÃO PARA LAVATÓRIO DE MESA BICA BAIXA, DECA OU EQUIVALENTE | BLOCO B | TM1 | 0.000602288
8 x TM1 | TORNEIRA AUTOMÁTICA DE PRESSÃO PARA LAVATÓRIO DE MESA BICA BAIXA, DECA OU EQUIVALENTE | BLOCO A | TM1 | 0.000602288
2 x TM2 | TORNEIRA PARA LAVATÓRIO COM ACIONAMENTO POR ALAVANCA | BLOCO A | TM2 | 0.000187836

# IfcSanitaryTerminal: Torneira Elétrica 2 (2)
In: TÉRREO
Classification: Terminal Hidrosanitário (Classificação Archicad); Material: Plástico, Água
Pset_ManufacturerTypeInformation - ModelLabel: TORNEIRA ELÉTRICA COM MANGUEIRA PLÁSTICA FORTTI MAXI, LORENZETTI OU EQUIVALENTE
FNDE - Mobiliário ou Equipamento - Modelo: TORNEIRA ELÉTRICA COM MANGUEIRA PLÁSTICA FORTTI MAXI, LORENZETTI OU EQUIVALENTE; 1_Bloco: BLOCO A; 0_ID: TE1
Component Quantities - Plástico, Massa: 1.16494 kg; Plástico, Volume Componente (Líquido): 0.000838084 m3; Plástico, Volume do componente (Bruto): 0.000838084 m3; Água, Massa: 0 kg; Água, Volume Componente (Líquido): 0 m3; Água, Volume do componente (Bruto): 0 m3

# IfcSanitaryTerminal: Torneira de Parede Deca Just (4)
In: TÉRREO
Classification: Terminal Hidrosanitário (Classificação Archicad)
Pset_ManufacturerOccurrence - SerialNumber: 00525206
Pset_ManufacturerTypeInformation - ModelLabel: TORNEIRA ELÉTRICA DE PAREDE
FNDE - Mobiliário ou Equipamento - Modelo: TORNEIRA ELÉTRICA DE PAREDE; 1_Bloco: BLOCO A; 0_ID: TE2
Component Quantities - Component, Volume Componente (Líquido): 0.000205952 m3; Component, Volume do componente (Bruto): 0.000205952 m3

# IfcSanitaryTerminal: Vaso Sanitário 27 (14)
In: TÉRREO
Classification: Terminal Hidrosanitário (Classificação Archicad)
Name | ModelLabel = Mobiliário ou Equipamento - Modelo | 1_Bloco | 0_ID | Component, Volume Componente (Líquido) (m3) = Component, Volume do componente (Bruto) (m3)
8 x VS1 | BACIA CONVENCIONAL STUDIO KIDS, DECA OU EQUIVALENTE COM ACESSORIOS | BLOCO B | VS1 | 0.00383456
VS1 | BACIA CONVENCIONAL STUDIO KIDS, DECA OU EQUIVALENTE COM ACESSORIOS | BLOCO B | VS1 | 0.00244422
VS1 | BACIA CONVENCIONAL STUDIO KIDS, DECA OU EQUIVALENTE COM ACESSORIOS | BLOCO A | VS1 | 0.00383456
4 x VS2 | BACIA CONVENCIONAL, DECA OU EQUIVALENTE COM ACESSORIOS | BLOCO A | VS2 | 0.00648043

# IfcShadingDevice: Janela 27 (3)
In: TÉRREO
Classification: Dispositivo de Sombreamento (Classificação Archicad)
FNDE - Esquadrias - Fechamentos metálicos e Gradis: Fechamento metálico; 1_Bloco: BLOCO A
Component Quantities - Component, Volume Componente (Líquido): 0.023125 m3; Component, Volume do componente (Bruto): 0.023125 m3

# IfcShadingDevice: Várias Estruturas- 13 Segmentos - 60 x 1580 x 14655 (40+2480+40+2480+40+2480+40+2480+40+2480+40+1975+40), GR4
In: TÉRREO
Classification: Dispositivo de Sombreamento (Classificação Archicad); Material: EI-REV-Pintura Acrílica Cor Branco Gelo (7), EI-MTL-GRADIL METÁLICO (6)
FNDE - Esquadrias - Fechamentos metálicos e Gradis: Gradis; 1_Bloco: MURETAS; 0_ID: GR4
Component Quantities - EI-REV-Pintura Acrílica Cor Branco Gelo 1, Massa: 4.9296 kg; EI-REV-Pintura Acrílica Cor Branco Gelo 1, Altura do Componente Retangular: 1.58 m; EI-REV-Pintura Acrílica Cor Branco Gelo 1, Largura do Componente Retangular: 0.06 m; EI-REV-Pintura Acrílica Cor Branco Gelo 1, Área de Seção Transversal do Componente: 0.0948 m2; EI-REV-Pintura Acrílica Cor Branco Gelo 1, Volume Componente (Líquido): 0.003792 m3; EI-REV-Pintura Acrílica Cor Branco Gelo 1, Volume do componente (Bruto): 0.003792 m3; EI-MTL-GRADIL METÁLICO 1, Massa: 299.758 kg; EI-MTL-GRADIL METÁLICO 1, Altura do Componente Retangular: 1.53 m; EI-MTL-GRADIL METÁLICO 1, Largura do Componente Retangular: 0.01 m; EI-MTL-GRADIL METÁLICO 1, Área de Seção Transversal do Componente: 0.0153 m2; EI-MTL-GRADIL METÁLICO 1, Volume Componente (Líquido): 0.037944 m3; EI-MTL-GRADIL METÁLICO 1, Volume do componente (Bruto): 0.037944 m3; EI-MTL-GRADIL METÁLICO 6, Massa: 238.714 kg; EI-MTL-GRADIL METÁLICO 6, Altura do Componente Retangular: 1.53 m; EI-MTL-GRADIL METÁLICO 6, Largura do Componente Retangular: 0.01 m; EI-MTL-GRADIL METÁLICO 6, Área de Seção Transversal do Componente: 0.0153 m2; EI-MTL-GRADIL METÁLICO 6, Volume Componente (Líquido): 0.030217 m3; EI-MTL-GRADIL METÁLICO 6, Volume do componente (Bruto): 0.030217 m3; EI-REV-Pintura Acrílica Cor Branco Gelo 1: 7 with these values; EI-MTL-GRADIL METÁLICO 1: 5 with these values

# IfcShadingDevice: Várias Estruturas- 15 Segmentos - 90 x 1000 x 8500 (50+2024+50+1+50+2024+50+1+50+2024+50+1+50+2024+50) (2)
In: COBERTURA
Classification: Dispositivo de Sombreamento (Classificação Archicad); Material: EI-MTL-PERFIL EM AÇO GALVANIZADO -AZUL (16), EI-MTL-CHAPA DE AÇO CARBONO PERFURADA -AZUL (4), Volume de Ar - Moldura (3)
FNDE - Esquadrias - Fechamentos metálicos e Gradis: Platibanda metálica; 1_Bloco: PÁTIO COBERTO
Component Quantities - EI-MTL-PERFIL EM AÇO GALVANIZADO -AZUL 1, Massa: 35.546 kg; EI-MTL-PERFIL EM AÇO GALVANIZADO -AZUL 1, Altura do Componente Retangular: 1 m; EI-MTL-PERFIL EM AÇO GALVANIZADO -AZUL 1, Largura do Componente Retangular: 0.09 m; EI-MTL-PERFIL EM AÇO GALVANIZADO -AZUL 1, Área de Seção Transversal do Componente: 0.09 m2; EI-MTL-PERFIL EM AÇO GALVANIZADO -AZUL 1, Volume Componente (Líquido): 0.00449949 m3; EI-MTL-PERFIL EM AÇO GALVANIZADO -AZUL 1, Volume do componente (Bruto): 0.00449949 m3; EI-MTL-PERFIL EM AÇO GALVANIZADO -AZUL 2, Massa: 71.9624 kg; EI-MTL-PERFIL EM AÇO GALVANIZADO -AZUL 2, Altura do Componente Retangular: 0.05 m; EI-MTL-PERFIL EM AÇO GALVANIZADO -AZUL 2, Largura do Componente Retangular: 0.09 m; EI-MTL-PERFIL EM AÇO GALVANIZADO -AZUL 2, Área de Seção Transversal do Componente: 0.0045 m2; EI-MTL-PERFIL EM AÇO GALVANIZADO -AZUL 2, Volume Componente (Líquido): 0.00910916 m3; EI-MTL-PERFIL EM AÇO GALVANIZADO -AZUL 2, Volume do componente (Bruto): 0.00910916 m3; EI-MTL-CHAPA DE AÇO CARBONO PERFURADA -AZUL 1, Massa: 21.5889 kg; EI-MTL-CHAPA DE AÇO CARBONO PERFURADA -AZUL 1, Altura do Componente Retangular: 0.9 m; EI-MTL-CHAPA DE AÇO CARBONO PERFURADA -AZUL 1, Largura do Componente Retangular: 0.00150001 m; EI-MTL-CHAPA DE AÇO CARBONO PERFURADA -AZUL 1, Área de Seção Transversal do Componente: 0.00135001 m2; EI-MTL-CHAPA DE AÇO CARBONO PERFURADA -AZUL 1, Volume Componente (Líquido): 0.00273277 m3; EI-MTL-CHAPA DE AÇO CARBONO PERFURADA -AZUL 1, Volume do componente (Bruto): 0.00273277 m3; EI-MTL-PERFIL EM AÇO GALVANIZADO -AZUL 3, Massa: 71.7995 kg; EI-MTL-PERFIL EM AÇO GALVANIZADO -AZUL 3, Altura do Componente Retangular: 0.05 m; EI-MTL-PERFIL EM AÇO GALVANIZADO -AZUL 3, Largura do Componente Retangular: 0.09 m; EI-MTL-PERFIL EM AÇO GALVANIZADO -AZUL 3, Área de Seção Transversal do Componente: 0.0045 m2; EI-MTL-PERFIL EM AÇO GALVANIZADO -AZUL 3, Volume Componente (Líquido): 0.00908854 m3; EI-MTL-PERFIL EM AÇO GALVANIZADO -AZUL 3, Volume do componente (Bruto): 0.00908854 m3; Volume de Ar - Moldura 1, Massa: 0.000107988 kg; Volume de Ar - Moldura 1, Altura do Componente Retangular: 1 m; Volume de Ar - Moldura 1, Largura do Componente Retangular: 0.09 m; Volume de Ar - Moldura 1, Área de Seção Transversal do Componente: 0.09 m2; Volume de Ar - Moldura 1, Volume Componente (Líquido): 0.0000899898 m3; Volume de Ar - Moldura 1, Volume do componente (Bruto): 0.0000899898 m3; EI-MTL-PERFIL EM AÇO GALVANIZADO -AZUL 12, Massa: 35.5576 kg; EI-MTL-PERFIL EM AÇO GALVANIZADO -AZUL 12, Altura do Componente Retangular: 1 m; EI-MTL-PERFIL EM AÇO GALVANIZADO -AZUL 12, Largura do Componente Retangular: 0.09 m; EI-MTL-PERFIL EM AÇO GALVANIZADO -AZUL 12, Área de Seção Transversal do Componente: 0.09 m2; EI-MTL-PERFIL EM AÇO GALVANIZADO -AZUL 12, Volume Componente (Líquido): 0.00450096 m3; EI-MTL-PERFIL EM AÇO GALVANIZADO -AZUL 12, Volume do componente (Bruto): 0.00450096 m3; EI-MTL-PERFIL EM AÇO GALVANIZADO -AZUL 1: 7 with these values; EI-MTL-PERFIL EM AÇO GALVANIZADO -AZUL 2: 4 with these values; EI-MTL-CHAPA DE AÇO CARBONO PERFURADA -AZUL 1: 4 with these values; Volume de Ar - Moldura 1: 3 with these values
Name | EI-MTL-PERFIL EM AÇO GALVANIZADO -AZUL 3
 | 4 with these values
 | 2 with these values | Component Quantities - EI-MTL-PERFIL EM AÇO GALVANIZADO -AZUL 11, Massa: 71.7995 kg; EI-MTL-PERFIL EM AÇO GALVANIZADO -AZUL 11, Altura do Componente Retangular: 0.05 m; EI-MTL-PERFIL EM AÇO GALVANIZADO -AZUL 11, Largura do Componente Retangular: 0.09 m; EI-MTL-PERFIL EM AÇO GALVANIZADO -AZUL 11, Área de Seção Transversal do Componente: 0.0045 m2; EI-MTL-PERFIL EM AÇO GALVANIZADO -AZUL 11, Volume Componente (Líquido): 0.00908855 m3; EI-MTL-PERFIL EM AÇO GALVANIZADO -AZUL 11, Volume do componente (Bruto): 0.00908855 m3; EI-MTL-PERFIL EM AÇO GALVANIZADO -AZUL 11: 2 with these values

# IfcShadingDevice: Várias Estruturas- 17 Segmentos - 60 x 1580 x 19945 (40+2480+40+2480+40+2480+40+2480+40+2480+40+2480+40+2480+40+2225+40), GR4
In: TÉRREO
Classification: Dispositivo de Sombreamento (Classificação Archicad); Material: EI-REV-Pintura Acrílica Cor Branco Gelo (9), EI-MTL-GRADIL METÁLICO (8)
FNDE - Esquadrias - Fechamentos metálicos e Gradis: Gradis; 1_Bloco: MURETAS; 0_ID: GR4
Component Quantities - EI-REV-Pintura Acrílica Cor Branco Gelo 1, Massa: 4.9296 kg; EI-REV-Pintura Acrílica Cor Branco Gelo 1, Altura do Componente Retangular: 1.58 m; EI-REV-Pintura Acrílica Cor Branco Gelo 1, Largura do Componente Retangular: 0.06 m; EI-REV-Pintura Acrílica Cor Branco Gelo 1, Área de Seção Transversal do Componente: 0.0948 m2; EI-REV-Pintura Acrílica Cor Branco Gelo 1, Volume Componente (Líquido): 0.003792 m3; EI-REV-Pintura Acrílica Cor Branco Gelo 1, Volume do componente (Bruto): 0.003792 m3; EI-MTL-GRADIL METÁLICO 1, Massa: 299.758 kg; EI-MTL-GRADIL METÁLICO 1, Altura do Componente Retangular: 1.53 m; EI-MTL-GRADIL METÁLICO 1, Largura do Componente Retangular: 0.01 m; EI-MTL-GRADIL METÁLICO 1, Área de Seção Transversal do Componente: 0.0153 m2; EI-MTL-GRADIL METÁLICO 1, Volume Componente (Líquido): 0.037944 m3; EI-MTL-GRADIL METÁLICO 1, Volume do componente (Bruto): 0.037944 m3; EI-MTL-GRADIL METÁLICO 8, Massa: 268.917 kg; EI-MTL-GRADIL METÁLICO 8, Altura do Componente Retangular: 1.53 m; EI-MTL-GRADIL METÁLICO 8, Largura do Componente Retangular: 0.01 m; EI-MTL-GRADIL METÁLICO 8, Área de Seção Transversal do Componente: 0.0153 m2; EI-MTL-GRADIL METÁLICO 8, Volume Componente (Líquido): 0.0340402 m3; EI-MTL-GRADIL METÁLICO 8, Volume do componente (Bruto): 0.0340402 m3; EI-REV-Pintura Acrílica Cor Branco Gelo 1: 9 with these values; EI-MTL-GRADIL METÁLICO 1: 7 with these values

# IfcShadingDevice: Várias Estruturas- 2 Segmentos - 50 x 950 x 2375 (2325+50)
In: TÉRREO
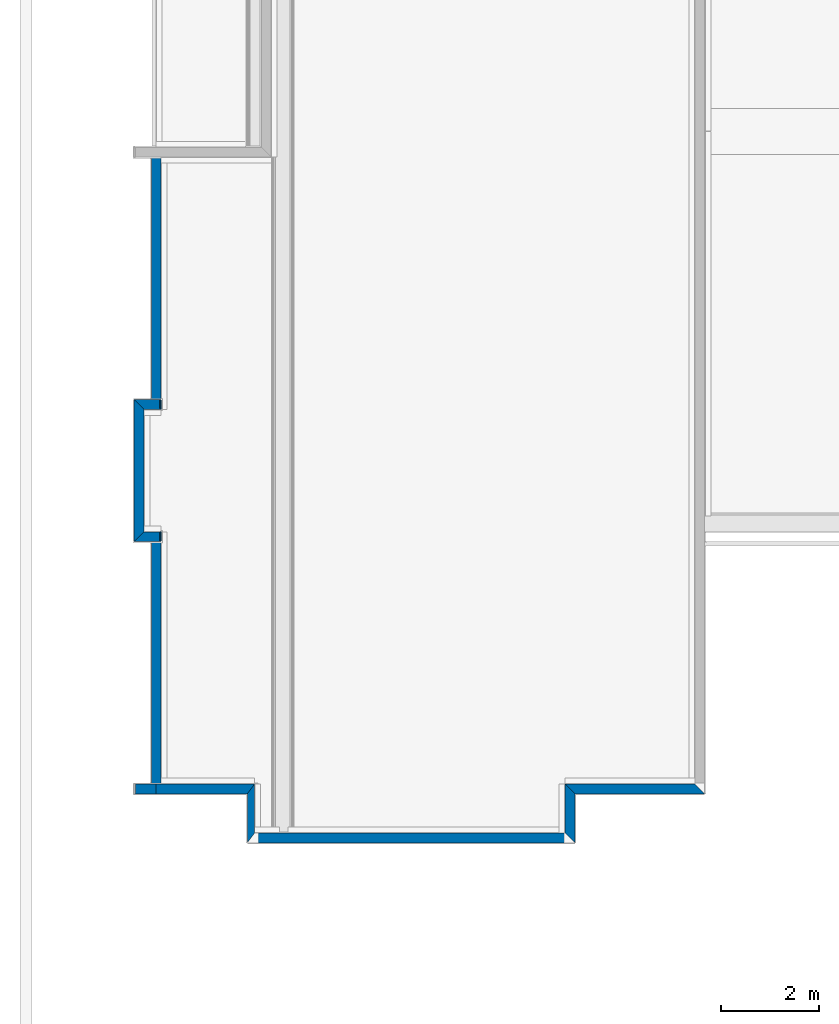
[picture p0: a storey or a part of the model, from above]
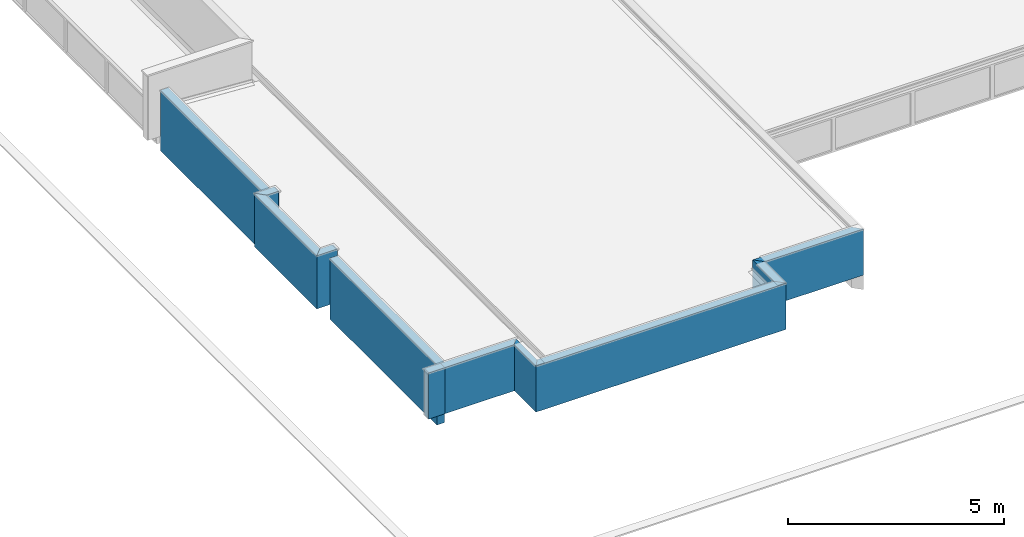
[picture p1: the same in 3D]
Properties of the parts of a building model (IFC4), part 8 of 22

# IfcShadingDevice: Várias Estruturas- 2 Segmentos - 50 x 950 x 2375 (2325+50)
Classification: Dispositivo de Sombreamento (Classificação Archicad); Material: EI-MTL-CHAPA DE AÇO CARBONO PERFURADA, Aço (3)
FNDE - Esquadrias - Fechamentos metálicos e Gradis: Fechamento metálico; 1_Bloco: BLOCO A
Component Quantities - Aço 1, Massa: 45.3375 kg; Aço 1, Altura do Componente Retangular: 0.05 m; Aço 1, Largura do Componente Retangular: 0.05 m; Aço 1, Área de Seção Transversal do Componente: 0.0025 m2; Aço 1, Volume Componente (Líquido): 0.0058125 m3; Aço 1, Volume do componente (Bruto): 0.0058125 m3; EI-MTL-CHAPA DE AÇO CARBONO PERFURADA, Massa: 23.4186 kg; EI-MTL-CHAPA DE AÇO CARBONO PERFURADA, Altura do Componente Retangular: 0.85 m; EI-MTL-CHAPA DE AÇO CARBONO PERFURADA, Largura do Componente Retangular: 0.0015 m; EI-MTL-CHAPA DE AÇO CARBONO PERFURADA, Área de Seção Transversal do Componente: 0.001275 m2; EI-MTL-CHAPA DE AÇO CARBONO PERFURADA, Volume Componente (Líquido): 0.00296437 m3; EI-MTL-CHAPA DE AÇO CARBONO PERFURADA, Volume do componente (Bruto): 0.00296437 m3; Aço 3, Massa: 18.525 kg; Aço 3, Altura do Componente Retangular: 0.95 m; Aço 3, Largura do Componente Retangular: 0.05 m; Aço 3, Área de Seção Transversal do Componente: 0.0475 m2; Aço 3, Volume Componente (Líquido): 0.002375 m3; Aço 3, Volume do componente (Bruto): 0.002375 m3; Aço 1: 2 with these values

# IfcShadingDevice: Várias Estruturas- 2 Segmentos - 50 x 950 x 2375 (50+2325)
In: TÉRREO
Classification: Dispositivo de Sombreamento (Classificação Archicad); Material: Aço (3), EI-MTL-CHAPA DE AÇO CARBONO PERFURADA
FNDE - Esquadrias - Fechamentos metálicos e Gradis: Fechamento metálico; 1_Bloco: BLOCO A
Component Quantities - Aço 1, Massa: 18.525 kg; Aço 1, Altura do Componente Retangular: 0.95 m; Aço 1, Largura do Componente Retangular: 0.05 m; Aço 1, Área de Seção Transversal do Componente: 0.0475 m2; Aço 1, Volume Componente (Líquido): 0.002375 m3; Aço 1, Volume do componente (Bruto): 0.002375 m3; Aço 2, Massa: 45.3375 kg; Aço 2, Altura do Componente Retangular: 0.05 m; Aço 2, Largura do Componente Retangular: 0.05 m; Aço 2, Área de Seção Transversal do Componente: 0.0025 m2; Aço 2, Volume Componente (Líquido): 0.0058125 m3; Aço 2, Volume do componente (Bruto): 0.0058125 m3; EI-MTL-CHAPA DE AÇO CARBONO PERFURADA, Massa: 23.4186 kg; EI-MTL-CHAPA DE AÇO CARBONO PERFURADA, Altura do Componente Retangular: 0.85 m; EI-MTL-CHAPA DE AÇO CARBONO PERFURADA, Largura do Componente Retangular: 0.0015 m; EI-MTL-CHAPA DE AÇO CARBONO PERFURADA, Área de Seção Transversal do Componente: 0.001275 m2; EI-MTL-CHAPA DE AÇO CARBONO PERFURADA, Volume Componente (Líquido): 0.00296437 m3; EI-MTL-CHAPA DE AÇO CARBONO PERFURADA, Volume do componente (Bruto): 0.00296437 m3; Aço 2: 2 with these values

# IfcShadingDevice: Várias Estruturas- 23 Segmentos - 90 x 1000 x 8502 (51+350+49+1+50+1800+50+1+50+1799+50+1+50+1799+50+1+50+1800+50+1+49+350+51)
In: COBERTURA
Classification: Dispositivo de Sombreamento (Classificação Archicad); Material: EI-MTL-PERFIL EM AÇO GALVANIZADO -AZUL (24), EI-MTL-CHAPA DE AÇO CARBONO PERFURADA -AZUL (6), Volume de Ar - Moldura (5)
FNDE - Esquadrias - Fechamentos metálicos e Gradis: Platibanda metálica; 1_Bloco: BLOCO B
Component Quantities - EI-MTL-PERFIL EM AÇO GALVANIZADO -AZUL 1, Massa: 35.1535 kg; EI-MTL-PERFIL EM AÇO GALVANIZADO -AZUL 1, Altura do Componente Retangular: 1 m; EI-MTL-PERFIL EM AÇO GALVANIZADO -AZUL 1, Largura do Componente Retangular: 0.09 m; EI-MTL-PERFIL EM AÇO GALVANIZADO -AZUL 1, Área de Seção Transversal do Componente: 0.09 m2; EI-MTL-PERFIL EM AÇO GALVANIZADO -AZUL 1, Volume Componente (Líquido): 0.00444981 m3; EI-MTL-PERFIL EM AÇO GALVANIZADO -AZUL 1, Volume do componente (Bruto): 0.00444981 m3; EI-MTL-PERFIL EM AÇO GALVANIZADO -AZUL 2, Massa: 12.4317 kg; EI-MTL-PERFIL EM AÇO GALVANIZADO -AZUL 2, Altura do Componente Retangular: 0.05 m; EI-MTL-PERFIL EM AÇO GALVANIZADO -AZUL 2, Largura do Componente Retangular: 0.09 m; EI-MTL-PERFIL EM AÇO GALVANIZADO -AZUL 2, Área de Seção Transversal do Componente: 0.0045 m2; EI-MTL-PERFIL EM AÇO GALVANIZADO -AZUL 2, Volume Componente (Líquido): 0.00157364 m3; EI-MTL-PERFIL EM AÇO GALVANIZADO -AZUL 2, Volume do componente (Bruto): 0.00157364 m3; EI-MTL-CHAPA DE AÇO CARBONO PERFURADA -AZUL 1, Massa: 3.73207 kg; EI-MTL-CHAPA DE AÇO CARBONO PERFURADA -AZUL 1, Altura do Componente Retangular: 0.9 m; EI-MTL-CHAPA DE AÇO CARBONO PERFURADA -AZUL 1, Largura do Componente Retangular: 0.00150001 m; EI-MTL-CHAPA DE AÇO CARBONO PERFURADA -AZUL 1, Área de Seção Transversal do Componente: 0.00135001 m2; EI-MTL-CHAPA DE AÇO CARBONO PERFURADA -AZUL 1, Volume Componente (Líquido): 0.000472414 m3; EI-MTL-CHAPA DE AÇO CARBONO PERFURADA -AZUL 1, Volume do componente (Bruto): 0.000472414 m3; EI-MTL-PERFIL EM AÇO GALVANIZADO -AZUL 3, Massa: 12.4402 kg; EI-MTL-PERFIL EM AÇO GALVANIZADO -AZUL 3, Altura do Componente Retangular: 0.05 m; EI-MTL-PERFIL EM AÇO GALVANIZADO -AZUL 3, Largura do Componente Retangular: 0.09 m; EI-MTL-PERFIL EM AÇO GALVANIZADO -AZUL 3, Área de Seção Transversal do Componente: 0.0045 m2; EI-MTL-PERFIL EM AÇO GALVANIZADO -AZUL 3, Volume Componente (Líquido): 0.0015747 m3; EI-MTL-PERFIL EM AÇO GALVANIZADO -AZUL 3, Volume do componente (Bruto): 0.0015747 m3; EI-MTL-PERFIL EM AÇO GALVANIZADO -AZUL 4, Massa: 35.0541 kg; EI-MTL-PERFIL EM AÇO GALVANIZADO -AZUL 4, Altura do Componente Retangular: 1 m; EI-MTL-PERFIL EM AÇO GALVANIZADO -AZUL 4, Largura do Componente Retangular: 0.09 m; EI-MTL-PERFIL EM AÇO GALVANIZADO -AZUL 4, Área de Seção Transversal do Componente: 0.09 m2; EI-MTL-PERFIL EM AÇO GALVANIZADO -AZUL 4, Volume Componente (Líquido): 0.00443723 m3; EI-MTL-PERFIL EM AÇO GALVANIZADO -AZUL 4, Volume do componente (Bruto): 0.00443723 m3; Volume de Ar - Moldura 1, Massa: 0.000128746 kg; Volume de Ar - Moldura 1, Altura do Componente Retangular: 1 m; Volume de Ar - Moldura 1, Largura do Componente Retangular: 0.09 m; Volume de Ar - Moldura 1, Área de Seção Transversal do Componente: 0.09 m2; Volume de Ar - Moldura 1, Volume Componente (Líquido): 0.000107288 m3; Volume de Ar - Moldura 1, Volume do componente (Bruto): 0.000107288 m3; EI-MTL-PERFIL EM AÇO GALVANIZADO -AZUL 5, Massa: 35.1908 kg; EI-MTL-PERFIL EM AÇO GALVANIZADO -AZUL 5, Altura do Componente Retangular: 1 m; EI-MTL-PERFIL EM AÇO GALVANIZADO -AZUL 5, Largura do Componente Retangular: 0.09 m; EI-MTL-PERFIL EM AÇO GALVANIZADO -AZUL 5, Área de Seção Transversal do Componente: 0.09 m2; EI-MTL-PERFIL EM AÇO GALVANIZADO -AZUL 5, Volume Componente (Líquido): 0.00445453 m3; EI-MTL-PERFIL EM AÇO GALVANIZADO -AZUL 5, Volume do componente (Bruto): 0.00445453 m3; EI-MTL-PERFIL EM AÇO GALVANIZADO -AZUL 6, Massa: 63.9328 kg; EI-MTL-PERFIL EM AÇO GALVANIZADO -AZUL 6, Altura do Componente Retangular: 0.05 m; EI-MTL-PERFIL EM AÇO GALVANIZADO -AZUL 6, Largura do Componente Retangular: 0.09 m; EI-MTL-PERFIL EM AÇO GALVANIZADO -AZUL 6, Área de Seção Transversal do Componente: 0.0045 m2; EI-MTL-PERFIL EM AÇO GALVANIZADO -AZUL 6, Volume Componente (Líquido): 0.00809276 m3; EI-MTL-PERFIL EM AÇO GALVANIZADO -AZUL 6, Volume do componente (Bruto): 0.00809276 m3; EI-MTL-CHAPA DE AÇO CARBONO PERFURADA -AZUL 2, Massa: 19.1918 kg; EI-MTL-CHAPA DE AÇO CARBONO PERFURADA -AZUL 2, Altura do Componente Retangular: 0.9 m; EI-MTL-CHAPA DE AÇO CARBONO PERFURADA -AZUL 2, Largura do Componente Retangular: 0.00150001 m; EI-MTL-CHAPA DE AÇO CARBONO PERFURADA -AZUL 2, Área de Seção Transversal do Componente: 0.00135001 m2; EI-MTL-CHAPA DE AÇO CARBONO PERFURADA -AZUL 2, Volume Componente (Líquido): 0.00242934 m3; EI-MTL-CHAPA DE AÇO CARBONO PERFURADA -AZUL 2, Volume do componente (Bruto): 0.00242934 m3; EI-MTL-PERFIL EM AÇO GALVANIZADO -AZUL 7, Massa: 63.9722 kg; EI-MTL-PERFIL EM AÇO GALVANIZADO -AZUL 7, Altura do Componente Retangular: 0.05 m; EI-MTL-PERFIL EM AÇO GALVANIZADO -AZUL 7, Largura do Componente Retangular: 0.09 m; EI-MTL-PERFIL EM AÇO GALVANIZADO -AZUL 7, Área de Seção Transversal do Componente: 0.0045 m2; EI-MTL-PERFIL EM AÇO GALVANIZADO -AZUL 7, Volume Componente (Líquido): 0.00809775 m3; EI-MTL-PERFIL EM AÇO GALVANIZADO -AZUL 7, Volume do componente (Bruto): 0.00809775 m3; EI-MTL-PERFIL EM AÇO GALVANIZADO -AZUL 8, Massa: 35.5467 kg; EI-MTL-PERFIL EM AÇO GALVANIZADO -AZUL 8, Altura do Componente Retangular: 1 m; EI-MTL-PERFIL EM AÇO GALVANIZADO -AZUL 8, Largura do Componente Retangular: 0.09 m; EI-MTL-PERFIL EM AÇO GALVANIZADO -AZUL 8, Área de Seção Transversal do Componente: 0.09 m2; EI-MTL-PERFIL EM AÇO GALVANIZADO -AZUL 8, Volume Componente (Líquido): 0.00449958 m3; EI-MTL-PERFIL EM AÇO GALVANIZADO -AZUL 8, Volume do componente (Bruto): 0.00449958 m3; Volume de Ar - Moldura 2, Massa: 0.00010799 kg; Volume de Ar - Moldura 2, Altura do Componente Retangular: 1 m; Volume de Ar - Moldura 2, Largura do Componente Retangular: 0.09 m; Volume de Ar - Moldura 2, Área de Seção Transversal do Componente: 0.09 m2; Volume de Ar - Moldura 2, Volume Componente (Líquido): 0.0000899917 m3; Volume de Ar - Moldura 2, Volume do componente (Bruto): 0.0000899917 m3; EI-MTL-PERFIL EM AÇO GALVANIZADO -AZUL 9, Massa: 35.5467 kg; EI-MTL-PERFIL EM AÇO GALVANIZADO -AZUL 9, Altura do Componente Retangular: 1 m; EI-MTL-PERFIL EM AÇO GALVANIZADO -AZUL 9, Largura do Componente Retangular: 0.09 m; EI-MTL-PERFIL EM AÇO GALVANIZADO -AZUL 9, Área de Seção Transversal do Componente: 0.09 m2; EI-MTL-PERFIL EM AÇO GALVANIZADO -AZUL 9, Volume Componente (Líquido): 0.00449959 m3; EI-MTL-PERFIL EM AÇO GALVANIZADO -AZUL 9, Volume do componente (Bruto): 0.00449959 m3; EI-MTL-PERFIL EM AÇO GALVANIZADO -AZUL 10, Massa: 63.9236 kg; EI-MTL-PERFIL EM AÇO GALVANIZADO -AZUL 10, Altura do Componente Retangular: 0.05 m; EI-MTL-PERFIL EM AÇO GALVANIZADO -AZUL 10, Largura do Componente Retangular: 0.09 m; EI-MTL-PERFIL EM AÇO GALVANIZADO -AZUL 10, Área de Seção Transversal do Componente: 0.0045 m2; EI-MTL-PERFIL EM AÇO GALVANIZADO -AZUL 10, Volume Componente (Líquido): 0.0080916 m3; EI-MTL-PERFIL EM AÇO GALVANIZADO -AZUL 10, Volume do componente (Bruto): 0.0080916 m3; EI-MTL-CHAPA DE AÇO CARBONO PERFURADA -AZUL 3, Massa: 19.1872 kg; EI-MTL-CHAPA DE AÇO CARBONO PERFURADA -AZUL 3, Altura do Componente Retangular: 0.9 m; EI-MTL-CHAPA DE AÇO CARBONO PERFURADA -AZUL 3, Largura do Componente Retangular: 0.00150001 m; EI-MTL-CHAPA DE AÇO CARBONO PERFURADA -AZUL 3, Área de Seção Transversal do Componente: 0.00135001 m2; EI-MTL-CHAPA DE AÇO CARBONO PERFURADA -AZUL 3, Volume Componente (Líquido): 0.00242876 m3; EI-MTL-CHAPA DE AÇO CARBONO PERFURADA -AZUL 3, Volume do componente (Bruto): 0.00242876 m3; EI-MTL-PERFIL EM AÇO GALVANIZADO -AZUL 11, Massa: 63.9568 kg; EI-MTL-PERFIL EM AÇO GALVANIZADO -AZUL 11, Altura do Componente Retangular: 0.05 m; EI-MTL-PERFIL EM AÇO GALVANIZADO -AZUL 11, Largura do Componente Retangular: 0.09 m; EI-MTL-PERFIL EM AÇO GALVANIZADO -AZUL 11, Área de Seção Transversal do Componente: 0.0045 m2; EI-MTL-PERFIL EM AÇO GALVANIZADO -AZUL 11, Volume Componente (Líquido): 0.0080958 m3; EI-MTL-PERFIL EM AÇO GALVANIZADO -AZUL 11, Volume do componente (Bruto): 0.0080958 m3; EI-MTL-PERFIL EM AÇO GALVANIZADO -AZUL 12, Massa: 35.5472 kg; EI-MTL-PERFIL EM AÇO GALVANIZADO -AZUL 12, Altura do Componente Retangular: 1 m; EI-MTL-PERFIL EM AÇO GALVANIZADO -AZUL 12, Largura do Componente Retangular: 0.09 m; EI-MTL-PERFIL EM AÇO GALVANIZADO -AZUL 12, Área de Seção Transversal do Componente: 0.09 m2; EI-MTL-PERFIL EM AÇO GALVANIZADO -AZUL 12, Volume Componente (Líquido): 0.00449965 m3; EI-MTL-PERFIL EM AÇO GALVANIZADO -AZUL 12, Volume do componente (Bruto): 0.00449965 m3; Volume de Ar - Moldura 3, Massa: 0.000107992 kg; Volume de Ar - Moldura 3, Altura do Componente Retangular: 1 m; Volume de Ar - Moldura 3, Largura do Componente Retangular: 0.09 m; Volume de Ar - Moldura 3, Área de Seção Transversal do Componente: 0.09 m2; Volume de Ar - Moldura 3, Volume Componente (Líquido): 0.000089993 m3; Volume de Ar - Moldura 3, Volume do componente (Bruto): 0.000089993 m3; EI-MTL-PERFIL EM AÇO GALVANIZADO -AZUL 13, Massa: 35.5473 kg; EI-MTL-PERFIL EM AÇO GALVANIZADO -AZUL 13, Altura do Componente Retangular: 1 m; EI-MTL-PERFIL EM AÇO GALVANIZADO -AZUL 13, Largura do Componente Retangular: 0.09 m; EI-MTL-PERFIL EM AÇO GALVANIZADO -AZUL 13, Área de Seção Transversal do Componente: 0.09 m2; EI-MTL-PERFIL EM AÇO GALVANIZADO -AZUL 13, Volume Componente (Líquido): 0.00449965 m3; EI-MTL-PERFIL EM AÇO GALVANIZADO -AZUL 13, Volume do componente (Bruto): 0.00449965 m3; EI-MTL-PERFIL EM AÇO GALVANIZADO -AZUL 14, Massa: 63.9151 kg; EI-MTL-PERFIL EM AÇO GALVANIZADO -AZUL 14, Altura do Componente Retangular: 0.05 m; EI-MTL-PERFIL EM AÇO GALVANIZADO -AZUL 14, Largura do Componente Retangular: 0.09 m; EI-MTL-PERFIL EM AÇO GALVANIZADO -AZUL 14, Área de Seção Transversal do Componente: 0.0045 m2; EI-MTL-PERFIL EM AÇO GALVANIZADO -AZUL 14, Volume Componente (Líquido): 0.00809052 m3; EI-MTL-PERFIL EM AÇO GALVANIZADO -AZUL 14, Volume do componente (Bruto): 0.00809052 m3; EI-MTL-CHAPA DE AÇO CARBONO PERFURADA -AZUL 4, Massa: 19.1827 kg; EI-MTL-CHAPA DE AÇO CARBONO PERFURADA -AZUL 4, Altura do Componente Retangular: 0.9 m; EI-MTL-CHAPA DE AÇO CARBONO PERFURADA -AZUL 4, Largura do Componente Retangular: 0.00150001 m; EI-MTL-CHAPA DE AÇO CARBONO PERFURADA -AZUL 4, Área de Seção Transversal do Componente: 0.00135001 m2; EI-MTL-CHAPA DE AÇO CARBONO PERFURADA -AZUL 4, Volume Componente (Líquido): 0.00242819 m3; EI-MTL-CHAPA DE AÇO CARBONO PERFURADA -AZUL 4, Volume do componente (Bruto): 0.00242819 m3; EI-MTL-PERFIL EM AÇO GALVANIZADO -AZUL 15, Massa: 63.942 kg; EI-MTL-PERFIL EM AÇO GALVANIZADO -AZUL 15, Altura do Componente Retangular: 0.05 m; EI-MTL-PERFIL EM AÇO GALVANIZADO -AZUL 15, Largura do Componente Retangular: 0.09 m; EI-MTL-PERFIL EM AÇO GALVANIZADO -AZUL 15, Área de Seção Transversal do Componente: 0.0045 m2; EI-MTL-PERFIL EM AÇO GALVANIZADO -AZUL 15, Volume Componente (Líquido): 0.00809393 m3; EI-MTL-PERFIL EM AÇO GALVANIZADO -AZUL 15, Volume do componente (Bruto): 0.00809393 m3; EI-MTL-PERFIL EM AÇO GALVANIZADO -AZUL 16, Massa: 35.7494 kg; EI-MTL-PERFIL EM AÇO GALVANIZADO -AZUL 16, Altura do Componente Retangular: 1 m; EI-MTL-PERFIL EM AÇO GALVANIZADO -AZUL 16, Largura do Componente Retangular: 0.09 m; EI-MTL-PERFIL EM AÇO GALVANIZADO -AZUL 16, Área de Seção Transversal do Componente: 0.09 m2; EI-MTL-PERFIL EM AÇO GALVANIZADO -AZUL 16, Volume Componente (Líquido): 0.00452524 m3; EI-MTL-PERFIL EM AÇO GALVANIZADO -AZUL 16, Volume do componente (Bruto): 0.00452524 m3; Volume de Ar - Moldura 4, Massa: 0.000107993 kg; Volume de Ar - Moldura 4, Altura do Componente Retangular: 1 m; Volume de Ar - Moldura 4, Largura do Componente Retangular: 0.09 m; Volume de Ar - Moldura 4, Área de Seção Transversal do Componente: 0.09 m2; Volume de Ar - Moldura 4, Volume Componente (Líquido): 0.0000899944 m3; Volume de Ar - Moldura 4, Volume do componente (Bruto): 0.0000899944 m3; EI-MTL-PERFIL EM AÇO GALVANIZADO -AZUL 17, Massa: 35.5478 kg; EI-MTL-PERFIL EM AÇO GALVANIZADO -AZUL 17, Altura do Componente Retangular: 1 m; EI-MTL-PERFIL EM AÇO GALVANIZADO -AZUL 17, Largura do Componente Retangular: 0.09 m; EI-MTL-PERFIL EM AÇO GALVANIZADO -AZUL 17, Área de Seção Transversal do Componente: 0.09 m2; EI-MTL-PERFIL EM AÇO GALVANIZADO -AZUL 17, Volume Componente (Líquido): 0.00449972 m3; EI-MTL-PERFIL EM AÇO GALVANIZADO -AZUL 17, Volume do componente (Bruto): 0.00449972 m3; EI-MTL-PERFIL EM AÇO GALVANIZADO -AZUL 18, Massa: 63.9516 kg; EI-MTL-PERFIL EM AÇO GALVANIZADO -AZUL 18, Altura do Componente Retangular: 0.05 m; EI-MTL-PERFIL EM AÇO GALVANIZADO -AZUL 18, Largura do Componente Retangular: 0.09 m; EI-MTL-PERFIL EM AÇO GALVANIZADO -AZUL 18, Área de Seção Transversal do Componente: 0.0045 m2; EI-MTL-PERFIL EM AÇO GALVANIZADO -AZUL 18, Volume Componente (Líquido): 0.00809514 m3; EI-MTL-PERFIL EM AÇO GALVANIZADO -AZUL 18, Volume do componente (Bruto): 0.00809514 m3; EI-MTL-PERFIL EM AÇO GALVANIZADO -AZUL 20, Massa: 35.2137 kg; EI-MTL-PERFIL EM AÇO GALVANIZADO -AZUL 20, Altura do Componente Retangular: 1 m; EI-MTL-PERFIL EM AÇO GALVANIZADO -AZUL 20, Largura do Componente Retangular: 0.09 m; EI-MTL-PERFIL EM AÇO GALVANIZADO -AZUL 20, Área de Seção Transversal do Componente: 0.09 m2; EI-MTL-PERFIL EM AÇO GALVANIZADO -AZUL 20, Volume Componente (Líquido): 0.00445743 m3; EI-MTL-PERFIL EM AÇO GALVANIZADO -AZUL 20, Volume do componente (Bruto): 0.00445743 m3; Volume de Ar - Moldura 5, Massa: 0.000107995 kg; Volume de Ar - Moldura 5, Altura do Componente Retangular: 1 m; Volume de Ar - Moldura 5, Largura do Componente Retangular: 0.09 m; Volume de Ar - Moldura 5, Área de Seção Transversal do Componente: 0.09 m2; Volume de Ar - Moldura 5, Volume Componente (Líquido): 0.0000899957 m3; Volume de Ar - Moldura 5, Volume do componente (Bruto): 0.0000899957 m3; EI-MTL-PERFIL EM AÇO GALVANIZADO -AZUL 21, Massa: 35.1719 kg; EI-MTL-PERFIL EM AÇO GALVANIZADO -AZUL 21, Altura do Componente Retangular: 1 m; EI-MTL-PERFIL EM AÇO GALVANIZADO -AZUL 21, Largura do Componente Retangular: 0.09 m; EI-MTL-PERFIL EM AÇO GALVANIZADO -AZUL 21, Área de Seção Transversal do Componente: 0.09 m2; EI-MTL-PERFIL EM AÇO GALVANIZADO -AZUL 21, Volume Componente (Líquido): 0.00445214 m3; EI-MTL-PERFIL EM AÇO GALVANIZADO -AZUL 21, Volume do componente (Bruto): 0.00445214 m3; EI-MTL-PERFIL EM AÇO GALVANIZADO -AZUL 22, Massa: 12.4416 kg; EI-MTL-PERFIL EM AÇO GALVANIZADO -AZUL 22, Altura do Componente Retangular: 0.05 m; EI-MTL-PERFIL EM AÇO GALVANIZADO -AZUL 22, Largura do Componente Retangular: 0.09 m; EI-MTL-PERFIL EM AÇO GALVANIZADO -AZUL 22, Área de Seção Transversal do Componente: 0.0045 m2; EI-MTL-PERFIL EM AÇO GALVANIZADO -AZUL 22, Volume Componente (Líquido): 0.00157489 m3; EI-MTL-PERFIL EM AÇO GALVANIZADO -AZUL 22, Volume do componente (Bruto): 0.00157489 m3; EI-MTL-CHAPA DE AÇO CARBONO PERFURADA -AZUL 6, Massa: 3.73349 kg; EI-MTL-CHAPA DE AÇO CARBONO PERFURADA -AZUL 6, Altura do Componente Retangular: 0.9 m; EI-MTL-CHAPA DE AÇO CARBONO PERFURADA -AZUL 6, Largura do Componente Retangular: 0.00150001 m; EI-MTL-CHAPA DE AÇO CARBONO PERFURADA -AZUL 6, Área de Seção Transversal do Componente: 0.00135001 m2; EI-MTL-CHAPA DE AÇO CARBONO PERFURADA -AZUL 6, Volume Componente (Líquido): 0.000472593 m3; EI-MTL-CHAPA DE AÇO CARBONO PERFURADA -AZUL 6, Volume do componente (Bruto): 0.000472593 m3; EI-MTL-PERFIL EM AÇO GALVANIZADO -AZUL 23, Massa: 12.4449 kg; EI-MTL-PERFIL EM AÇO GALVANIZADO -AZUL 23, Altura do Componente Retangular: 0.05 m; EI-MTL-PERFIL EM AÇO GALVANIZADO -AZUL 23, Largura do Componente Retangular: 0.09 m; EI-MTL-PERFIL EM AÇO GALVANIZADO -AZUL 23, Área de Seção Transversal do Componente: 0.0045 m2; EI-MTL-PERFIL EM AÇO GALVANIZADO -AZUL 23, Volume Componente (Líquido): 0.0015753 m3; EI-MTL-PERFIL EM AÇO GALVANIZADO -AZUL 23, Volume do componente (Bruto): 0.0015753 m3; EI-MTL-PERFIL EM AÇO GALVANIZADO -AZUL 24, Massa: 35.1554 kg; EI-MTL-PERFIL EM AÇO GALVANIZADO -AZUL 24, Altura do Componente Retangular: 1 m; EI-MTL-PERFIL EM AÇO GALVANIZADO -AZUL 24, Largura do Componente Retangular: 0.09 m; EI-MTL-PERFIL EM AÇO GALVANIZADO -AZUL 24, Área de Seção Transversal do Componente: 0.09 m2; EI-MTL-PERFIL EM AÇO GALVANIZADO -AZUL 24, Volume Componente (Líquido): 0.00445005 m3; EI-MTL-PERFIL EM AÇO GALVANIZADO -AZUL 24, Volume do componente (Bruto): 0.00445005 m3; EI-MTL-CHAPA DE AÇO CARBONO PERFURADA -AZUL 2: 2 with these values; EI-MTL-PERFIL EM AÇO GALVANIZADO -AZUL 7: 2 with these values

# IfcShadingDevice: Várias Estruturas- 3 Segmentos - 50 x 2250 x 400 (50+300+50) (8)
In: TÉRREO
Classification: Dispositivo de Sombreamento (Classificação Archicad); Material: EI-MTL-PERFIL EM AÇO GALVANIZADO (4), EI-MTL-CHAPA DE AÇO CARBONO PERFURADA
FNDE - Esquadrias - Fechamentos metálicos e Gradis: Fechamento metálico; 1_Bloco: BLOCO A
Component Quantities - EI-MTL-PERFIL EM AÇO GALVANIZADO 1, Massa: 44.4375 kg; EI-MTL-PERFIL EM AÇO GALVANIZADO 1, Altura do Componente Retangular: 2.25 m; EI-MTL-PERFIL EM AÇO GALVANIZADO 1, Largura do Componente Retangular: 0.05 m; EI-MTL-PERFIL EM AÇO GALVANIZADO 1, Área de Seção Transversal do Componente: 0.1125 m2; EI-MTL-PERFIL EM AÇO GALVANIZADO 1, Volume Componente (Líquido): 0.005625 m3; EI-MTL-PERFIL EM AÇO GALVANIZADO 1, Volume do componente (Bruto): 0.005625 m3; EI-MTL-PERFIL EM AÇO GALVANIZADO 2, Massa: 5.925 kg; EI-MTL-PERFIL EM AÇO GALVANIZADO 2, Altura do Componente Retangular: 0.05 m; EI-MTL-PERFIL EM AÇO GALVANIZADO 2, Largura do Componente Retangular: 0.05 m; EI-MTL-PERFIL EM AÇO GALVANIZADO 2, Área de Seção Transversal do Componente: 0.0025 m2; EI-MTL-PERFIL EM AÇO GALVANIZADO 2, Volume Componente (Líquido): 0.00075 m3; EI-MTL-PERFIL EM AÇO GALVANIZADO 2, Volume do componente (Bruto): 0.00075 m3; EI-MTL-CHAPA DE AÇO CARBONO PERFURADA, Massa: 7.64325 kg; EI-MTL-CHAPA DE AÇO CARBONO PERFURADA, Altura do Componente Retangular: 2.15 m; EI-MTL-CHAPA DE AÇO CARBONO PERFURADA, Largura do Componente Retangular: 0.0015 m; EI-MTL-CHAPA DE AÇO CARBONO PERFURADA, Área de Seção Transversal do Componente: 0.003225 m2; EI-MTL-CHAPA DE AÇO CARBONO PERFURADA, Volume Componente (Líquido): 0.0009675 m3; EI-MTL-CHAPA DE AÇO CARBONO PERFURADA, Volume do componente (Bruto): 0.0009675 m3; EI-MTL-PERFIL EM AÇO GALVANIZADO 1: 2 with these values; EI-MTL-PERFIL EM AÇO GALVANIZADO 2: 2 with these values

# IfcShadingDevice: Várias Estruturas- 3 Segmentos - 50 x 2250 x 420 (50+320+50) (3)
In: TÉRREO
Classification: Dispositivo de Sombreamento (Classificação Archicad); Material: EI-MTL-PERFIL EM AÇO GALVANIZADO (4), EI-MTL-CHAPA DE AÇO CARBONO PERFURADA
FNDE - Esquadrias - Fechamentos metálicos e Gradis: Fechamento metálico; 1_Bloco: BLOCO A
Component Quantities - EI-MTL-PERFIL EM AÇO GALVANIZADO 1, Massa: 44.4375 kg; EI-MTL-PERFIL EM AÇO GALVANIZADO 1, Altura do Componente Retangular: 2.25 m; EI-MTL-PERFIL EM AÇO GALVANIZADO 1, Largura do Componente Retangular: 0.05 m; EI-MTL-PERFIL EM AÇO GALVANIZADO 1, Área de Seção Transversal do Componente: 0.1125 m2; EI-MTL-PERFIL EM AÇO GALVANIZADO 1, Volume Componente (Líquido): 0.005625 m3; EI-MTL-PERFIL EM AÇO GALVANIZADO 1, Volume do componente (Bruto): 0.005625 m3; EI-MTL-PERFIL EM AÇO GALVANIZADO 2, Massa: 6.32 kg; EI-MTL-PERFIL EM AÇO GALVANIZADO 2, Altura do Componente Retangular: 0.05 m; EI-MTL-PERFIL EM AÇO GALVANIZADO 2, Largura do Componente Retangular: 0.05 m; EI-MTL-PERFIL EM AÇO GALVANIZADO 2, Área de Seção Transversal do Componente: 0.0025 m2; EI-MTL-PERFIL EM AÇO GALVANIZADO 2, Volume Componente (Líquido): 0.0008 m3; EI-MTL-PERFIL EM AÇO GALVANIZADO 2, Volume do componente (Bruto): 0.0008 m3; EI-MTL-CHAPA DE AÇO CARBONO PERFURADA, Massa: 8.1528 kg; EI-MTL-CHAPA DE AÇO CARBONO PERFURADA, Altura do Componente Retangular: 2.15 m; EI-MTL-CHAPA DE AÇO CARBONO PERFURADA, Largura do Componente Retangular: 0.0015 m; EI-MTL-CHAPA DE AÇO CARBONO PERFURADA, Área de Seção Transversal do Componente: 0.003225 m2; EI-MTL-CHAPA DE AÇO CARBONO PERFURADA, Volume Componente (Líquido): 0.001032 m3; EI-MTL-CHAPA DE AÇO CARBONO PERFURADA, Volume do componente (Bruto): 0.001032 m3; EI-MTL-PERFIL EM AÇO GALVANIZADO 1: 2 with these values; EI-MTL-PERFIL EM AÇO GALVANIZADO 2: 2 with these values

# IfcShadingDevice: Várias Estruturas- 3 Segmentos - 50 x 2250 x 430 (50+330+50) (5)
In: TÉRREO
Classification: Dispositivo de Sombreamento (Classificação Archicad); Material: EI-MTL-PERFIL EM AÇO GALVANIZADO (4), EI-MTL-CHAPA DE AÇO CARBONO PERFURADA
FNDE - Esquadrias - Fechamentos metálicos e Gradis: Fechamento metálico; 1_Bloco: BLOCO A
Component Quantities - EI-MTL-PERFIL EM AÇO GALVANIZADO 1, Massa: 44.4375 kg; EI-MTL-PERFIL EM AÇO GALVANIZADO 1, Altura do Componente Retangular: 2.25 m; EI-MTL-PERFIL EM AÇO GALVANIZADO 1, Largura do Componente Retangular: 0.05 m; EI-MTL-PERFIL EM AÇO GALVANIZADO 1, Área de Seção Transversal do Componente: 0.1125 m2; EI-MTL-PERFIL EM AÇO GALVANIZADO 1, Volume Componente (Líquido): 0.005625 m3; EI-MTL-PERFIL EM AÇO GALVANIZADO 1, Volume do componente (Bruto): 0.005625 m3; EI-MTL-PERFIL EM AÇO GALVANIZADO 2, Massa: 6.5175 kg; EI-MTL-PERFIL EM AÇO GALVANIZADO 2, Altura do Componente Retangular: 0.05 m; EI-MTL-PERFIL EM AÇO GALVANIZADO 2, Largura do Componente Retangular: 0.05 m; EI-MTL-PERFIL EM AÇO GALVANIZADO 2, Área de Seção Transversal do Componente: 0.0025 m2; EI-MTL-PERFIL EM AÇO GALVANIZADO 2, Volume Componente (Líquido): 0.000825 m3; EI-MTL-PERFIL EM AÇO GALVANIZADO 2, Volume do componente (Bruto): 0.000825 m3; EI-MTL-CHAPA DE AÇO CARBONO PERFURADA, Altura do Componente Retangular: 2.15 m; EI-MTL-CHAPA DE AÇO CARBONO PERFURADA, Largura do Componente Retangular: 0.0015 m; EI-MTL-CHAPA DE AÇO CARBONO PERFURADA, Área de Seção Transversal do Componente: 0.003225 m2; EI-MTL-CHAPA DE AÇO CARBONO PERFURADA, Volume Componente (Líquido): 0.00106425 m3; EI-MTL-CHAPA DE AÇO CARBONO PERFURADA, Volume do componente (Bruto): 0.00106425 m3; EI-MTL-PERFIL EM AÇO GALVANIZADO 1: 2 with these values; EI-MTL-PERFIL EM AÇO GALVANIZADO 2: 2 with these values
Name | EI-MTL-CHAPA DE AÇO CARBONO PERFURADA, Massa (kg)
4 x  | 8.40758
 | 8.40757

# IfcShadingDevice: Várias Estruturas- 3 Segmentos - 50 x 2750 x 1200 (50+1100+50) (12)
In: TÉRREO
Classification: Dispositivo de Sombreamento (Classificação Archicad)
FNDE - Esquadrias - Fechamentos metálicos e Gradis: Fechamento metálico; 1_Bloco: BLOCO A
Name | Material
4 x  | EI-MTL-PERFIL EM AÇO GALVANIZADO (4), EI-MTL-CHAPA DE AÇO CARBONO PERFURADA | Component Quantities - EI-MTL-PERFIL EM AÇO GALVANIZADO 1, Massa: 54.3125 kg; EI-MTL-PERFIL EM AÇO GALVANIZADO 1, Altura do Componente Retangular: 2.75 m; EI-MTL-PERFIL EM AÇO GALVANIZADO 1, Largura do Componente Retangular: 0.05 m; EI-MTL-PERFIL EM AÇO GALVANIZADO 1, Área de Seção Transversal do Componente: 0.1375 m2; EI-MTL-PERFIL EM AÇO GALVANIZADO 1, Volume Componente (Líquido): 0.006875 m3; EI-MTL-PERFIL EM AÇO GALVANIZADO 1, Volume do componente (Bruto): 0.006875 m3; EI-MTL-PERFIL EM AÇO GALVANIZADO 2, Massa: 21.725 kg; EI-MTL-PERFIL EM AÇO GALVANIZADO 2, Altura do Componente Retangular: 0.05 m; EI-MTL-PERFIL EM AÇO GALVANIZADO 2, Largura do Componente Retangular: 0.05 m; EI-MTL-PERFIL EM AÇO GALVANIZADO 2, Área de Seção Transversal do Componente: 0.0025 m2; EI-MTL-PERFIL EM AÇO GALVANIZADO 2, Volume Componente (Líquido): 0.00275 m3; EI-MTL-PERFIL EM AÇO GALVANIZADO 2, Volume do componente (Bruto): 0.00275 m3; EI-MTL-CHAPA DE AÇO CARBONO PERFURADA, Massa: 34.5428 kg; EI-MTL-CHAPA DE AÇO CARBONO PERFURADA, Altura do Componente Retangular: 2.65 m; EI-MTL-CHAPA DE AÇO CARBONO PERFURADA, Largura do Componente Retangular: 0.0015 m; EI-MTL-CHAPA DE AÇO CARBONO PERFURADA, Área de Seção Transversal do Componente: 0.003975 m2; EI-MTL-CHAPA DE AÇO CARBONO PERFURADA, Volume Componente (Líquido): 0.0043725 m3; EI-MTL-CHAPA DE AÇO CARBONO PERFURADA, Volume do componente (Bruto): 0.0043725 m3; EI-MTL-PERFIL EM AÇO GALVANIZADO 1: 2 with these values; EI-MTL-PERFIL EM AÇO GALVANIZADO 2: 2 with these values
5 x  | EI-MTL-PERFIL EM AÇO GALVANIZADO -AMARELO (4), EI-MTL-CHAPA DE AÇO CARBONO PERFURADA -AMARELO | Component Quantities - EI-MTL-PERFIL EM AÇO GALVANIZADO -AMARELO 1, Massa: 54.3125 kg; EI-MTL-PERFIL EM AÇO GALVANIZADO -AMARELO 1, Altura do Componente Retangular: 2.75 m; EI-MTL-PERFIL EM AÇO GALVANIZADO -AMARELO 1, Largura do Componente Retangular: 0.05 m; EI-MTL-PERFIL EM AÇO GALVANIZADO -AMARELO 1, Área de Seção Transversal do Componente: 0.1375 m2; EI-MTL-PERFIL EM AÇO GALVANIZADO -AMARELO 1, Volume Componente (Líquido): 0.006875 m3; EI-MTL-PERFIL EM AÇO GALVANIZADO -AMARELO 1, Volume do componente (Bruto): 0.006875 m3; EI-MTL-PERFIL EM AÇO GALVANIZADO -AMARELO 2, Massa: 21.725 kg; EI-MTL-PERFIL EM AÇO GALVANIZADO -AMARELO 2, Altura do Componente Retangular: 0.05 m; EI-MTL-PERFIL EM AÇO GALVANIZADO -AMARELO 2, Largura do Componente Retangular: 0.05 m; EI-MTL-PERFIL EM AÇO GALVANIZADO -AMARELO 2, Área de Seção Transversal do Componente: 0.0025 m2; EI-MTL-PERFIL EM AÇO GALVANIZADO -AMARELO 2, Volume Componente (Líquido): 0.00275 m3; EI-MTL-PERFIL EM AÇO GALVANIZADO -AMARELO 2, Volume do componente (Bruto): 0.00275 m3; EI-MTL-CHAPA DE AÇO CARBONO PERFURADA -AMARELO, Massa: 34.5428 kg; EI-MTL-CHAPA DE AÇO CARBONO PERFURADA -AMARELO, Altura do Componente Retangular: 2.65 m; EI-MTL-CHAPA DE AÇO CARBONO PERFURADA -AMARELO, Largura do Componente Retangular: 0.0015 m; EI-MTL-CHAPA DE AÇO CARBONO PERFURADA -AMARELO, Área de Seção Transversal do Componente: 0.003975 m2; EI-MTL-CHAPA DE AÇO CARBONO PERFURADA -AMARELO, Volume Componente (Líquido): 0.0043725 m3; EI-MTL-CHAPA DE AÇO CARBONO PERFURADA -AMARELO, Volume do componente (Bruto): 0.0043725 m3; EI-MTL-PERFIL EM AÇO GALVANIZADO -AMARELO 1: 2 with these values; EI-MTL-PERFIL EM AÇO GALVANIZADO -AMARELO 2: 2 with these values
 | EI-MTL-PERFIL EM AÇO GALVANIZADO -AMARELO (4), EI-MTL-CHAPA DE AÇO CARBONO PERFURADA -AMARELO | Component Quantities - EI-MTL-PERFIL EM AÇO GALVANIZADO -AMARELO 1, Massa: 54.3125 kg; EI-MTL-PERFIL EM AÇO GALVANIZADO -AMARELO 1, Altura do Componente Retangular: 2.75 m; EI-MTL-PERFIL EM AÇO GALVANIZADO -AMARELO 1, Largura do Componente Retangular: 0.05 m; EI-MTL-PERFIL EM AÇO GALVANIZADO -AMARELO 1, Área de Seção Transversal do Componente: 0.1375 m2; EI-MTL-PERFIL EM AÇO GALVANIZADO -AMARELO 1, Volume Componente (Líquido): 0.006875 m3; EI-MTL-PERFIL EM AÇO GALVANIZADO -AMARELO 1, Volume do componente (Bruto): 0.006875 m3; EI-MTL-PERFIL EM AÇO GALVANIZADO -AMARELO 2, Massa: 21.725 kg; EI-MTL-PERFIL EM AÇO GALVANIZADO -AMARELO 2, Altura do Componente Retangular: 0.05 m; EI-MTL-PERFIL EM AÇO GALVANIZADO -AMARELO 2, Largura do Componente Retangular: 0.05 m; EI-MTL-PERFIL EM AÇO GALVANIZADO -AMARELO 2, Área de Seção Transversal do Componente: 0.0025 m2; EI-MTL-PERFIL EM AÇO GALVANIZADO -AMARELO 2, Volume Componente (Líquido): 0.00275 m3; EI-MTL-PERFIL EM AÇO GALVANIZADO -AMARELO 2, Volume do componente (Bruto): 0.00275 m3; EI-MTL-CHAPA DE AÇO CARBONO PERFURADA -AMARELO, Massa: 34.5427 kg; EI-MTL-CHAPA DE AÇO CARBONO PERFURADA -AMARELO, Altura do Componente Retangular: 2.65 m; EI-MTL-CHAPA DE AÇO CARBONO PERFURADA -AMARELO, Largura do Componente Retangular: 0.0015 m; EI-MTL-CHAPA DE AÇO CARBONO PERFURADA -AMARELO, Área de Seção Transversal do Componente: 0.003975 m2; EI-MTL-CHAPA DE AÇO CARBONO PERFURADA -AMARELO, Volume Componente (Líquido): 0.0043725 m3; EI-MTL-CHAPA DE AÇO CARBONO PERFURADA -AMARELO, Volume do componente (Bruto): 0.0043725 m3; EI-MTL-PERFIL EM AÇO GALVANIZADO -AMARELO 1: 2 with these values; EI-MTL-PERFIL EM AÇO GALVANIZADO -AMARELO 2: 2 with these values
2 x  | EI-MTL-PERFIL EM AÇO GALVANIZADO (4), EI-MTL-CHAPA DE AÇO CARBONO PERFURADA | Component Quantities - EI-MTL-PERFIL EM AÇO GALVANIZADO 1, Massa: 54.3125 kg; EI-MTL-PERFIL EM AÇO GALVANIZADO 1, Altura do Componente Retangular: 2.75 m; EI-MTL-PERFIL EM AÇO GALVANIZADO 1, Largura do Componente Retangular: 0.05 m; EI-MTL-PERFIL EM AÇO GALVANIZADO 1, Área de Seção Transversal do Componente: 0.1375 m2; EI-MTL-PERFIL EM AÇO GALVANIZADO 1, Volume Componente (Líquido): 0.006875 m3; EI-MTL-PERFIL EM AÇO GALVANIZADO 1, Volume do componente (Bruto): 0.006875 m3; EI-MTL-PERFIL EM AÇO GALVANIZADO 2, Massa: 21.725 kg; EI-MTL-PERFIL EM AÇO GALVANIZADO 2, Altura do Componente Retangular: 0.05 m; EI-MTL-PERFIL EM AÇO GALVANIZADO 2, Largura do Componente Retangular: 0.05 m; EI-MTL-PERFIL EM AÇO GALVANIZADO 2, Área de Seção Transversal do Componente: 0.0025 m2; EI-MTL-PERFIL EM AÇO GALVANIZADO 2, Volume Componente (Líquido): 0.00275 m3; EI-MTL-PERFIL EM AÇO GALVANIZADO 2, Volume do componente (Bruto): 0.00275 m3; EI-MTL-CHAPA DE AÇO CARBONO PERFURADA, Massa: 34.5427 kg; EI-MTL-CHAPA DE AÇO CARBONO PERFURADA, Altura do Componente Retangular: 2.65 m; EI-MTL-CHAPA DE AÇO CARBONO PERFURADA, Largura do Componente Retangular: 0.0015 m; EI-MTL-CHAPA DE AÇO CARBONO PERFURADA, Área de Seção Transversal do Componente: 0.003975 m2; EI-MTL-CHAPA DE AÇO CARBONO PERFURADA, Volume Componente (Líquido): 0.0043725 m3; EI-MTL-CHAPA DE AÇO CARBONO PERFURADA, Volume do componente (Bruto): 0.0043725 m3; EI-MTL-PERFIL EM AÇO GALVANIZADO 1: 2 with these values; EI-MTL-PERFIL EM AÇO GALVANIZADO 2: 2 with these values

# IfcShadingDevice: Várias Estruturas- 3 Segmentos - 50 x 3600 x 700 (50+600+50) (2)
In: TÉRREO
Classification: Dispositivo de Sombreamento (Classificação Archicad)
FNDE - Esquadrias - Fechamentos metálicos e Gradis: Fechamento metálico; 1_Bloco: BLOCO A
Component Quantities - Aço 1, Largura do Componente Retangular: 0.05 m; Aço 2, Largura do Componente Retangular: 0.05 m; Aço 3, Largura do Componente Retangular: 0.05 m; Aço 4, Altura do Componente Retangular: 0.05 m; Aço 4, Largura do Componente Retangular: 0.05 m; Aço 4, Área de Seção Transversal do Componente: 0.0025 m2; Aço 11, Largura do Componente Retangular: 0.05 m; Aço 12, Largura do Componente Retangular: 0.05 m; Aço 13, Largura do Componente Retangular: 0.05 m
Name | Material | Aço 1, Massa (kg) | Aço 1, Altura do Componente Retangular (m) | Aço 1, Área de Seção Transversal do Componente (m2) | Aço 1, Volume Componente (Líquido) (m3) = Aço 1, Volume do componente (Bruto) (m3) | Aço 2, Massa (kg) | Aço 2, Altura do Componente Retangular (m) | Aço 2, Área de Seção Transversal do Componente (m2) | Aço 2, Volume Componente (Líquido) (m3) = Aço 2, Volume do componente (Bruto) (m3) | Aço 3, Massa (kg) | Aço 3, Altura do Componente Retangular (m) | Aço 3, Área de Seção Transversal do Componente (m2) | Aço 3, Volume Componente (Líquido) (m3) = Aço 3, Volume do componente (Bruto) (m3) | Aço 4, Massa (kg) | Aço 4, Volume Componente (Líquido) (m3) = Aço 4, Volume do componente (Bruto) (m3) | EI-MTL-CHAPA DE AÇO CARBONO PERFURADA 1, Massa (kg) | EI-MTL-CHAPA DE AÇO CARBONO PERFURADA 1, Altura do Componente Retangular (m) | EI-MTL-CHAPA DE AÇO CARBONO PERFURADA 1, Largura do Componente Retangular (m) | EI-MTL-CHAPA DE AÇO CARBONO PERFURADA 1, Área de Seção Transversal do Componente (m2) | EI-MTL-CHAPA DE AÇO CARBONO PERFURADA 1, Volume Componente (Líquido) (m3) = EI-MTL-CHAPA DE AÇO CARBONO PERFURADA 1, Volume do componente (Bruto) (m3) | EI-MTL-CHAPA DE AÇO CARBONO PERFURADA 2, Massa (kg) | EI-MTL-CHAPA DE AÇO CARBONO PERFURADA 2, Altura do Componente Retangular (m) | EI-MTL-CHAPA DE AÇO CARBONO PERFURADA 2, Largura do Componente Retangular (m) | EI-MTL-CHAPA DE AÇO CARBONO PERFURADA 2, Área de Seção Transversal do Componente (m2) | EI-MTL-CHAPA DE AÇO CARBONO PERFURADA 2, Volume Componente (Líquido) (m3) = EI-MTL-CHAPA DE AÇO CARBONO PERFURADA 2, Volume do componente (Bruto) (m3) | EI-MTL-CHAPA DE AÇO CARBONO PERFURADA 3, Massa (kg) | EI-MTL-CHAPA DE AÇO CARBONO PERFURADA 3, Altura do Componente Retangular (m) | EI-MTL-CHAPA DE AÇO CARBONO PERFURADA 3, Largura do Componente Retangular (m) | EI-MTL-CHAPA DE AÇO CARBONO PERFURADA 3, Área de Seção Transversal do Componente (m2) | EI-MTL-CHAPA DE AÇO CARBONO PERFURADA 3, Volume Componente (Líquido) (m3) = EI-MTL-CHAPA DE AÇO CARBONO PERFURADA 3, Volume do componente (Bruto) (m3) | Aço 11, Massa (kg) | Aço 11, Altura do Componente Retangular (m) | Aço 11, Área de Seção Transversal do Componente (m2) | Aço 11, Volume Componente (Líquido) (m3) = Aço 11, Volume do componente (Bruto) (m3) | Aço 12, Massa (kg) | Aço 12, Altura do Componente Retangular (m) | Aço 12, Área de Seção Transversal do Componente (m2) | Aço 12, Volume Componente (Líquido) (m3) = Aço 12, Volume do componente (Bruto) (m3) | EI-MTL-CHAPA DE AÇO CARBONO PERFURADA 4, Massa (kg) | EI-MTL-CHAPA DE AÇO CARBONO PERFURADA 4, Altura do Componente Retangular (m) | EI-MTL-CHAPA DE AÇO CARBONO PERFURADA 4, Largura do Componente Retangular (m) | EI-MTL-CHAPA DE AÇO CARBONO PERFURADA 4, Área de Seção Transversal do Componente (m2) | EI-MTL-CHAPA DE AÇO CARBONO PERFURADA 4, Volume Componente (Líquido) (m3) = EI-MTL-CHAPA DE AÇO CARBONO PERFURADA 4, Volume do componente (Bruto) (m3) | Aço 13, Massa (kg) | Aço 13, Altura do Componente Retangular (m) | Aço 13, Área de Seção Transversal do Componente (m2) | Aço 13, Volume Componente (Líquido) (m3) = Aço 13, Volume do componente (Bruto) (m3)
 | Aço (13), EI-MTL-CHAPA DE AÇO CARBONO PERFURADA (4) | 25.74 | 1.32 | 0.066 | 0.0033 | 19.11 | 0.98 | 0.049 | 0.00245 | 25.35 | 1.3 | 0.065 | 0.00325 | 11.7009 | 0.00150011 | 8.31935 | 1.17 | 0.0015 | 0.001755 | 0.00105308 | 6.61283 | 0.93 | 0.00150001 | 0.00139501 | 0.000837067 | 8.53259 | 1.2 | 0.00149999 | 0.00179999 | 0.00108007 | 20.0667 | 1.03 | 0.0515 | 0.00257266 | 7.79291 | 0.4 | 0.02 | 0.000999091 | 0.50317 | 0.85 | 0.00150001 | 0.00127501 | 0.0000636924 | 0.974114 | 0.05 | 0.0025 | 0.000124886 | Component Quantities - Aço 10, Massa: 24.7425 kg; Aço 10, Altura do Componente Retangular: 1.27 m; Aço 10, Largura do Componente Retangular: 0.05 m; Aço 10, Área de Seção Transversal do Componente: 0.0635 m2; Aço 10, Volume Componente (Líquido): 0.00317211 m3; Aço 10, Volume do componente (Bruto): 0.00317211 m3; Aço 4: 6 with these values
 | EI-MTL-CHAPA DE AÇO CARBONO PERFURADA (4), Aço (13) | 24.7425 | 1.27 | 0.0635 | 0.00317211 | 20.0667 | 1.03 | 0.0515 | 0.00257266 | 7.79291 | 0.4 | 0.02 | 0.000999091 | 0.974114 | 0.000124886 | 0.50317 | 0.85 | 0.00150001 | 0.00127501 | 0.0000636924 | 8.31935 | 1.17 | 0.0015 | 0.001755 | 0.00105308 | 6.61283 | 0.93 | 0.00150001 | 0.00139501 | 0.000837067 | 25.74 | 1.32 | 0.066 | 0.0033 | 19.11 | 0.98 | 0.049 | 0.00245 | 8.53259 | 1.2 | 0.00149999 | 0.00179999 | 0.00108007 | 25.35 | 1.3 | 0.065 | 0.00325 | Component Quantities - Aço 5, Massa: 11.7009 kg; Aço 5, Altura do Componente Retangular: 0.05 m; Aço 5, Largura do Componente Retangular: 0.05 m; Aço 5, Área de Seção Transversal do Componente: 0.0025 m2; Aço 5, Volume Componente (Líquido): 0.00150011 m3; Aço 5, Volume do componente (Bruto): 0.00150011 m3; Aço 5: 6 with these values

# IfcShadingDevice: Várias Estruturas- 3 Segmentos - 60 x 1580 x 200 (40+120+40), GR2
In: TÉRREO
Classification: Dispositivo de Sombreamento (Classificação Archicad); Material: EI-REV-Pintura Acrílica Cor Branco Gelo (2), EI-MTL-GRADIL METÁLICO
FNDE - Esquadrias - Fechamentos metálicos e Gradis: Gradis; 1_Bloco: MURETAS; 0_ID: GR2
Component Quantities - EI-REV-Pintura Acrílica Cor Branco Gelo 1, Massa: 4.9296 kg; EI-REV-Pintura Acrílica Cor Branco Gelo 1, Altura do Componente Retangular: 1.58 m; EI-REV-Pintura Acrílica Cor Branco Gelo 1, Largura do Componente Retangular: 0.06 m; EI-REV-Pintura Acrílica Cor Branco Gelo 1, Área de Seção Transversal do Componente: 0.0948 m2; EI-REV-Pintura Acrílica Cor Branco Gelo 1, Volume Componente (Líquido): 0.003792 m3; EI-REV-Pintura Acrílica Cor Branco Gelo 1, Volume do componente (Bruto): 0.003792 m3; EI-MTL-GRADIL METÁLICO, Massa: 14.5044 kg; EI-MTL-GRADIL METÁLICO, Altura do Componente Retangular: 1.53 m; EI-MTL-GRADIL METÁLICO, Largura do Componente Retangular: 0.01 m; EI-MTL-GRADIL METÁLICO, Área de Seção Transversal do Componente: 0.0153 m2; EI-MTL-GRADIL METÁLICO, Volume Componente (Líquido): 0.001836 m3; EI-MTL-GRADIL METÁLICO, Volume do componente (Bruto): 0.001836 m3; EI-REV-Pintura Acrílica Cor Branco Gelo 1: 2 with these values

# IfcShadingDevice: Várias Estruturas- 3 Segmentos - 60 x 1580 x 2360 (40+2280+40), GR3
In: TÉRREO
Classification: Dispositivo de Sombreamento (Classificação Archicad); Material: EI-REV-Pintura Acrílica Cor Branco Gelo (2), EI-MTL-GRADIL METÁLICO
FNDE - Esquadrias - Fechamentos metálicos e Gradis: Gradis; 1_Bloco: MURETAS; 0_ID: GR3
Component Quantities - EI-REV-Pintura Acrílica Cor Branco Gelo 1, Massa: 4.91687 kg; EI-REV-Pintura Acrílica Cor Branco Gelo 1, Altura do Componente Retangular: 1.58 m; EI-REV-Pintura Acrílica Cor Branco Gelo 1, Largura do Componente Retangular: 0.06 m; EI-REV-Pintura Acrílica Cor Branco Gelo 1, Área de Seção Transversal do Componente: 0.0948 m2; EI-REV-Pintura Acrílica Cor Branco Gelo 1, Volume Componente (Líquido): 0.00378221 m3; EI-REV-Pintura Acrílica Cor Branco Gelo 1, Volume do componente (Bruto): 0.00378221 m3; EI-MTL-GRADIL METÁLICO, Massa: 275.565 kg; EI-MTL-GRADIL METÁLICO, Altura do Componente Retangular: 1.53 m; EI-MTL-GRADIL METÁLICO, Largura do Componente Retangular: 0.01 m; EI-MTL-GRADIL METÁLICO, Área de Seção Transversal do Componente: 0.0153 m2; EI-MTL-GRADIL METÁLICO, Volume Componente (Líquido): 0.0348816 m3; EI-MTL-GRADIL METÁLICO, Volume do componente (Bruto): 0.0348816 m3; EI-REV-Pintura Acrílica Cor Branco Gelo 2, Massa: 4.9296 kg; EI-REV-Pintura Acrílica Cor Branco Gelo 2, Altura do Componente Retangular: 1.58 m; EI-REV-Pintura Acrílica Cor Branco Gelo 2, Largura do Componente Retangular: 0.06 m; EI-REV-Pintura Acrílica Cor Branco Gelo 2, Área de Seção Transversal do Componente: 0.0948 m2; EI-REV-Pintura Acrílica Cor Branco Gelo 2, Volume Componente (Líquido): 0.003792 m3; EI-REV-Pintura Acrílica Cor Branco Gelo 2, Volume do componente (Bruto): 0.003792 m3

# IfcShadingDevice: Várias Estruturas- 3 Segmentos - 60 x 1580 x 3160 (40+3080+40), GR2
In: TÉRREO
Classification: Dispositivo de Sombreamento (Classificação Archicad); Material: EI-REV-Pintura Acrílica Cor Branco Gelo (2), EI-MTL-GRADIL METÁLICO
FNDE - Esquadrias - Fechamentos metálicos e Gradis: Gradis; 1_Bloco: MURETAS; 0_ID: GR2
Component Quantities - EI-REV-Pintura Acrílica Cor Branco Gelo 1, Massa: 4.9296 kg; EI-REV-Pintura Acrílica Cor Branco Gelo 1, Altura do Componente Retangular: 1.58 m; EI-REV-Pintura Acrílica Cor Branco Gelo 1, Largura do Componente Retangular: 0.06 m; EI-REV-Pintura Acrílica Cor Branco Gelo 1, Área de Seção Transversal do Componente: 0.0948 m2; EI-REV-Pintura Acrílica Cor Branco Gelo 1, Volume Componente (Líquido): 0.003792 m3; EI-REV-Pintura Acrílica Cor Branco Gelo 1, Volume do componente (Bruto): 0.003792 m3; EI-MTL-GRADIL METÁLICO, Massa: 372.299 kg; EI-MTL-GRADIL METÁLICO, Altura do Componente Retangular: 1.53 m; EI-MTL-GRADIL METÁLICO, Largura do Componente Retangular: 0.01 m; EI-MTL-GRADIL METÁLICO, Área de Seção Transversal do Componente: 0.0153 m2; EI-MTL-GRADIL METÁLICO, Volume Componente (Líquido): 0.0471264 m3; EI-MTL-GRADIL METÁLICO, Volume do componente (Bruto): 0.0471264 m3; EI-REV-Pintura Acrílica Cor Branco Gelo 1: 2 with these values

# IfcShadingDevice: Várias Estruturas- 5 Segmentos - 60 x 1580 x 4400 (40+2140+40+2140+40), GR1
In: TÉRREO
Classification: Dispositivo de Sombreamento (Classificação Archicad); Material: EI-REV-Pintura Acrílica Cor Branco Gelo (3), EI-MTL-GRADIL METÁLICO (2)
FNDE - Esquadrias - Fechamentos metálicos e Gradis: Gradis; 1_Bloco: MURETAS; 0_ID: GR1
Component Quantities - EI-REV-Pintura Acrílica Cor Branco Gelo 1, Massa: 4.9296 kg; EI-REV-Pintura Acrílica Cor Branco Gelo 1, Altura do Componente Retangular: 1.58 m; EI-REV-Pintura Acrílica Cor Branco Gelo 1, Largura do Componente Retangular: 0.06 m; EI-REV-Pintura Acrílica Cor Branco Gelo 1, Área de Seção Transversal do Componente: 0.0948 m2; EI-REV-Pintura Acrílica Cor Branco Gelo 1, Volume Componente (Líquido): 0.003792 m3; EI-REV-Pintura Acrílica Cor Branco Gelo 1, Volume do componente (Bruto): 0.003792 m3; EI-MTL-GRADIL METÁLICO 1, Massa: 258.664 kg; EI-MTL-GRADIL METÁLICO 1, Altura do Componente Retangular: 1.53 m; EI-MTL-GRADIL METÁLICO 1, Largura do Componente Retangular: 0.01 m; EI-MTL-GRADIL METÁLICO 1, Área de Seção Transversal do Componente: 0.0153 m2; EI-MTL-GRADIL METÁLICO 1, Volume Componente (Líquido): 0.0327422 m3; EI-MTL-GRADIL METÁLICO 1, Volume do componente (Bruto): 0.0327422 m3; EI-REV-Pintura Acrílica Cor Branco Gelo 1: 3 with these values; EI-MTL-GRADIL METÁLICO 1: 2 with these values

# IfcStair: Escada Enjaulada 27, ESCADA MARINHEIRO COM GAIOLA
In: TÉRREO
Classification: Escada (Classificação Archicad)
FNDE - 1_Bloco: CASA DE BOMBAS / GÁS / LIXO; 0_ID: ESCADA MARINHEIRO COM GAIOLA
Pset_StairCommon - IsExternal: yes
Component Quantities - Component, Volume Componente (Líquido): 0.159836 m3; Component, Volume do componente (Bruto): 0.159836 m3

# IfcTank: FNDE-TORRE CAIXA D'ÁGUA 200 (2)
In: TÉRREO
Classification: Reservatório (Classificação Archicad); Material: EI-REV-Pintura Primer interno, GENÉRICO - ESTRUTURAL, EI-REV-Pintura Primer externo, EI-REV-Pintura Poliuretano cor Amarelo
FNDE - 1_Bloco: CASA DE BOMBAS / GÁS / LIXO; 0_ID: AL14
Component Quantities - EI-REV-Pintura Poliuretano cor Amarelo, Massa: 645.961 kg; EI-REV-Pintura Poliuretano cor Amarelo, Área de Componente Projetada (Líquida): 24.8186 m2; EI-REV-Pintura Poliuretano cor Amarelo, Área de Componente Projetada (Bruta): 24.8186 m2; EI-REV-Pintura Poliuretano cor Amarelo, Espessura do Componente: 0.02 m; EI-REV-Pintura Poliuretano cor Amarelo, Altura do Componente Retangular: 10 m; EI-REV-Pintura Poliuretano cor Amarelo, Largura do Componente Retangular: 0.02 m; EI-REV-Pintura Poliuretano cor Amarelo, Área de Seção Transversal do Componente: 0.2 m2; EI-REV-Pintura Poliuretano cor Amarelo, Volume Componente (Líquido): 0.496893 m3; EI-REV-Pintura Poliuretano cor Amarelo, Volume do componente (Bruto): 0.496893 m3; EI-REV-Pintura Primer externo, Massa: 619.505 kg; EI-REV-Pintura Primer externo, Área de Componente Projetada (Líquida): 24.2688 m2; EI-REV-Pintura Primer externo, Área de Componente Projetada (Bruta): 24.2688 m2; EI-REV-Pintura Primer externo, Espessura do Componente: 0.015 m; EI-REV-Pintura Primer externo, Altura do Componente Retangular: 10 m; EI-REV-Pintura Primer externo, Largura do Componente Retangular: 0.015 m; EI-REV-Pintura Primer externo, Área de Seção Transversal do Componente: 0.15 m2; EI-REV-Pintura Primer externo, Volume Componente (Líquido): 0.364414 m3; EI-REV-Pintura Primer externo, Volume do componente (Bruto): 0.364414 m3; GENÉRICO - ESTRUTURAL, Massa: 7486.42 kg; GENÉRICO - ESTRUTURAL, Área de Componente Projetada (Líquida): 21.677 m2; GENÉRICO - ESTRUTURAL, Área de Componente Projetada (Bruta): 21.677 m2; GENÉRICO - ESTRUTURAL, Espessura do Componente: 0.15 m; GENÉRICO - ESTRUTURAL, Altura do Componente Retangular: 10 m; GENÉRICO - ESTRUTURAL, Largura do Componente Retangular: 0.15 m; GENÉRICO - ESTRUTURAL, Área de Seção Transversal do Componente: 1.5 m2; GENÉRICO - ESTRUTURAL, Volume Componente (Líquido): 3.25496 m3; GENÉRICO - ESTRUTURAL, Volume do componente (Bruto): 3.25496 m3; EI-REV-Pintura Primer interno, Massa: 487.183 kg; EI-REV-Pintura Primer interno, Área de Componente Projetada (Líquida): 19.0852 m2; EI-REV-Pintura Primer interno, Área de Componente Projetada (Bruta): 19.0852 m2; EI-REV-Pintura Primer interno, Espessura do Componente: 0.015 m; EI-REV-Pintura Primer interno, Altura do Componente Retangular: 10 m; EI-REV-Pintura Primer interno, Largura do Componente Retangular: 0.015 m; EI-REV-Pintura Primer interno, Área de Seção Transversal do Componente: 0.15 m2; EI-REV-Pintura Primer interno, Volume Componente (Líquido): 0.286578 m3; EI-REV-Pintura Primer interno, Volume do componente (Bruto): 0.286578 m3

# IfcWall: Arremate com Dobra Revest 27 (61)
Classification: Parede (Classificação Archicad)
FNDE - Sistemas de Cobertura: -; Esquadrias - Fechamentos metálicos e Gradis: -
Pset_WallCommon - LoadBearing: no
Name | In | Material | Alvenarias | 1_Bloco | 0_ID | IsExternal | EI-REV-Massa Acrílica (externa), Massa (kg) | EI-REV-Massa Acrílica (externa), Volume Componente (Líquido) (m3) = EI-REV-Massa Acrílica (externa), Volume do componente (Bruto) (m3) | EI-REV-Massa única - Fachada, Massa (kg) | EI-REV-Massa única - Fachada, Volume Componente (Líquido) (m3) = EI-REV-Massa única - Fachada, Volume do componente (Bruto) (m3)
4 x AL14 | TÉRREO | EI-REV-Pintura Acrílica Cor Cinza, EI-REV-Massa Acrílica (externa), EI-REV-Massa única - Fachada | Alvenaria de Vedação / Edificação | BLOCO B | AL14 | yes | 3.72775 | 0.0028675 | 3.627 | 0.00279 | Component Quantities - EI-REV-Pintura Acrílica Cor Cinza, Massa: 12.09 kg; EI-REV-Pintura Acrílica Cor Cinza, Volume Componente (Líquido): 0.0093 m3; EI-REV-Pintura Acrílica Cor Cinza, Volume do componente (Bruto): 0.0093 m3
AL14 | TÉRREO | EI-REV-Cerâmica 30x40, EI-REV-Emboço Interno, EI-REV-Chapisco (interno) | Mureta | BLOCO B | AL14 | no | Component Quantities - EI-REV-Cerâmica 30x40, Massa: 3.016 kg; EI-REV-Cerâmica 30x40, Volume Componente (Líquido): 0.001508 m3; EI-REV-Cerâmica 30x40, Volume do componente (Bruto): 0.001508 m3; EI-REV-Emboço Interno, Massa: 0.4147 kg; EI-REV-Emboço Interno, Volume Componente (Líquido): 0.000319 m3; EI-REV-Emboço Interno, Volume do componente (Bruto): 0.000319 m3; EI-REV-Chapisco (interno), Massa: 0.39585 kg; EI-REV-Chapisco (interno), Volume Componente (Líquido): 0.0003045 m3; EI-REV-Chapisco (interno), Volume do componente (Bruto): 0.0003045 m3
AL14 | TÉRREO | EI-REV-Cerâmica 30x40, EI-REV-Emboço Interno, EI-REV-Chapisco (interno) | Mureta | BLOCO B | AL14 | no | Component Quantities - EI-REV-Cerâmica 30x40, Massa: 4.056 kg; EI-REV-Cerâmica 30x40, Volume Componente (Líquido): 0.002028 m3; EI-REV-Cerâmica 30x40, Volume do componente (Bruto): 0.002028 m3; EI-REV-Emboço Interno, Massa: 0.5577 kg; EI-REV-Emboço Interno, Volume Componente (Líquido): 0.000429 m3; EI-REV-Emboço Interno, Volume do componente (Bruto): 0.000429 m3; EI-REV-Chapisco (interno), Massa: 0.53235 kg; EI-REV-Chapisco (interno), Volume Componente (Líquido): 0.0004095 m3; EI-REV-Chapisco (interno), Volume do componente (Bruto): 0.0004095 m3
AL18 | TÉRREO | EI-REV-Cerâmica 30x40, EI-REV-Emboço Interno, EI-REV-Chapisco (interno) | - | BLOCO A | AL18 | no | Component Quantities - EI-REV-Cerâmica 30x40, Massa: 4.68 kg; EI-REV-Cerâmica 30x40, Volume Componente (Líquido): 0.00234 m3; EI-REV-Cerâmica 30x40, Volume do componente (Bruto): 0.00234 m3; EI-REV-Emboço Interno, Massa: 0.6591 kg; EI-REV-Emboço Interno, Volume Componente (Líquido): 0.000507 m3; EI-REV-Emboço Interno, Volume do componente (Bruto): 0.000507 m3; EI-REV-Chapisco (interno), Massa: 0.63375 kg; EI-REV-Chapisco (interno), Volume Componente (Líquido): 0.0004875 m3; EI-REV-Chapisco (interno), Volume do componente (Bruto): 0.0004875 m3
AL12 | TÉRREO | EI-REV-Cerâmica 30x40, EI-REV-Emboço Interno, EI-REV-Chapisco (interno) | - | BLOCO A | AL12 | no | Component Quantities - EI-REV-Cerâmica 30x40, Massa: 5.46 kg; EI-REV-Cerâmica 30x40, Volume Componente (Líquido): 0.00273 m3; EI-REV-Cerâmica 30x40, Volume do componente (Bruto): 0.00273 m3; EI-REV-Emboço Interno, Massa: 0.76895 kg; EI-REV-Emboço Interno, Volume Componente (Líquido): 0.0005915 m3; EI-REV-Emboço Interno, Volume do componente (Bruto): 0.0005915 m3; EI-REV-Chapisco (interno), Massa: 0.739375 kg; EI-REV-Chapisco (interno), Volume Componente (Líquido): 0.00056875 m3; EI-REV-Chapisco (interno), Volume do componente (Bruto): 0.00056875 m3
2 x AL16 | TÉRREO | EI-REV-Cerâmica 30x40, EI-REV-Emboço Interno, EI-REV-Chapisco (interno) | - | BLOCO A | AL16 | no | Component Quantities - EI-REV-Cerâmica 30x40, Massa: 5.46 kg; EI-REV-Cerâmica 30x40, Volume Componente (Líquido): 0.00273 m3; EI-REV-Cerâmica 30x40, Volume do componente (Bruto): 0.00273 m3; EI-REV-Emboço Interno, Massa: 0.76895 kg; EI-REV-Emboço Interno, Volume Componente (Líquido): 0.0005915 m3; EI-REV-Emboço Interno, Volume do componente (Bruto): 0.0005915 m3; EI-REV-Chapisco (interno), Massa: 0.739375 kg; EI-REV-Chapisco (interno), Volume Componente (Líquido): 0.00056875 m3; EI-REV-Chapisco (interno), Volume do componente (Bruto): 0.00056875 m3
AL10 | TÉRREO | EI-REV-Cerâmica 30x40, EI-REV-Emboço Interno, EI-REV-Chapisco (interno) | - | BLOCO A | AL10 | no | Component Quantities - EI-REV-Cerâmica 30x40, Massa: 5.46 kg; EI-REV-Cerâmica 30x40, Volume Componente (Líquido): 0.00273 m3; EI-REV-Cerâmica 30x40, Volume do componente (Bruto): 0.00273 m3; EI-REV-Emboço Interno, Massa: 0.76895 kg; EI-REV-Emboço Interno, Volume Componente (Líquido): 0.0005915 m3; EI-REV-Emboço Interno, Volume do componente (Bruto): 0.0005915 m3; EI-REV-Chapisco (interno), Massa: 0.739375 kg; EI-REV-Chapisco (interno), Volume Componente (Líquido): 0.00056875 m3; EI-REV-Chapisco (interno), Volume do componente (Bruto): 0.00056875 m3
AL14 | TÉRREO | EI-REV-Cerâmica 30x40, EI-REV-Emboço Interno, EI-REV-Chapisco (interno) | Mureta | BLOCO B | AL14 | no | Component Quantities - EI-REV-Cerâmica 30x40, Massa: 4.16 kg; EI-REV-Cerâmica 30x40, Volume Componente (Líquido): 0.00208 m3; EI-REV-Cerâmica 30x40, Volume do componente (Bruto): 0.00208 m3; EI-REV-Emboço Interno, Massa: 0.572 kg; EI-REV-Emboço Interno, Volume Componente (Líquido): 0.00044 m3; EI-REV-Emboço Interno, Volume do componente (Bruto): 0.00044 m3; EI-REV-Chapisco (interno), Massa: 0.546 kg; EI-REV-Chapisco (interno), Volume Componente (Líquido): 0.00042 m3; EI-REV-Chapisco (interno), Volume do componente (Bruto): 0.00042 m3
4 x AL14 | TÉRREO | EI-REV-Pintura Acrílica Cor Cinza, EI-REV-Massa Acrílica (externa), EI-REV-Massa única - Fachada | Alvenaria de Vedação / Edificação | BLOCO A | AL14 | yes | 3.72775 | 0.0028675 | 3.627 | 0.00279 | Component Quantities - EI-REV-Pintura Acrílica Cor Cinza, Massa: 12.09 kg; EI-REV-Pintura Acrílica Cor Cinza, Volume Componente (Líquido): 0.0093 m3; EI-REV-Pintura Acrílica Cor Cinza, Volume do componente (Bruto): 0.0093 m3
2 x AL14 | TÉRREO | EI-REV-Pintura Acrílica Cor Branco Gelo, EI-REV-Massa Acrílica (externa), EI-REV-Massa única - Fachada | - | BLOCO A | AL14 | no | 3.4255 | 0.002635 | 3.32475 | 0.0025575 | Component Quantities - EI-REV-Pintura Acrílica Cor Branco Gelo, Massa: 11.1832 kg; EI-REV-Pintura Acrílica Cor Branco Gelo, Volume Componente (Líquido): 0.0086025 m3; EI-REV-Pintura Acrílica Cor Branco Gelo, Volume do componente (Bruto): 0.0086025 m3
3 x AL14 | TÉRREO | EI-REV-Cerâmica 30x40, EI-REV-Emboço Interno, EI-REV-Chapisco (interno) | Mureta | BLOCO A | AL14 | no | Component Quantities - EI-REV-Cerâmica 30x40, Massa: 4.68 kg; EI-REV-Cerâmica 30x40, Volume Componente (Líquido): 0.00234 m3; EI-REV-Cerâmica 30x40, Volume do componente (Bruto): 0.00234 m3; EI-REV-Emboço Interno, Massa: 0.6591 kg; EI-REV-Emboço Interno, Volume Componente (Líquido): 0.000507 m3; EI-REV-Emboço Interno, Volume do componente (Bruto): 0.000507 m3; EI-REV-Chapisco (interno), Massa: 0.63375 kg; EI-REV-Chapisco (interno), Volume Componente (Líquido): 0.0004875 m3; EI-REV-Chapisco (interno), Volume do componente (Bruto): 0.0004875 m3
AL14 | TÉRREO | EI-REV-Cerâmica 30x40, EI-REV-Emboço Interno, EI-REV-Chapisco (interno) | Mureta | BLOCO A | AL14 | no | Component Quantities - EI-REV-Cerâmica 30x40, Massa: 4.86 kg; EI-REV-Cerâmica 30x40, Volume Componente (Líquido): 0.00243 m3; EI-REV-Cerâmica 30x40, Volume do componente (Bruto): 0.00243 m3; EI-REV-Emboço Interno, Massa: 0.68445 kg; EI-REV-Emboço Interno, Volume Componente (Líquido): 0.0005265 m3; EI-REV-Emboço Interno, Volume do componente (Bruto): 0.0005265 m3; EI-REV-Chapisco (interno), Massa: 0.658125 kg; EI-REV-Chapisco (interno), Volume Componente (Líquido): 0.00050625 m3; EI-REV-Chapisco (interno), Volume do componente (Bruto): 0.00050625 m3
AL09 | TÉRREO | EI-REV-Cerâmica 30x40, EI-REV-Emboço Interno, EI-REV-Chapisco (interno) | - | BLOCO A | AL09 | no | Component Quantities - EI-REV-Cerâmica 30x40, Massa: 18.6 kg; EI-REV-Cerâmica 30x40, Volume Componente (Líquido): 0.0093 m3; EI-REV-Cerâmica 30x40, Volume do componente (Bruto): 0.0093 m3; EI-REV-Emboço Interno, Massa: 2.6195 kg; EI-REV-Emboço Interno, Volume Componente (Líquido): 0.002015 m3; EI-REV-Emboço Interno, Volume do componente (Bruto): 0.002015 m3; EI-REV-Chapisco (interno), Massa: 2.51875 kg; EI-REV-Chapisco (interno), Volume Componente (Líquido): 0.0019375 m3; EI-REV-Chapisco (interno), Volume do componente (Bruto): 0.0019375 m3
AL25 | TÉRREO | EI-REV-Cerâmica 30x40, EI-REV-Emboço Interno, EI-REV-Chapisco (interno) | - | BLOCO A | AL25 | no | Component Quantities - EI-REV-Cerâmica 30x40, Massa: 16.12 kg; EI-REV-Cerâmica 30x40, Volume Componente (Líquido): 0.00806 m3; EI-REV-Cerâmica 30x40, Volume do componente (Bruto): 0.00806 m3; EI-REV-Emboço Interno, Massa: 2.2165 kg; EI-REV-Emboço Interno, Volume Componente (Líquido): 0.001705 m3; EI-REV-Emboço Interno, Volume do componente (Bruto): 0.001705 m3; EI-REV-Chapisco (interno), Massa: 2.11575 kg; EI-REV-Chapisco (interno), Volume Componente (Líquido): 0.0016275 m3; EI-REV-Chapisco (interno), Volume do componente (Bruto): 0.0016275 m3
AL22 | TÉRREO | EI-REV-Cerâmica 30x40, EI-REV-Emboço Interno, EI-REV-Chapisco (interno) | - | BLOCO A | AL22 | no | Component Quantities - EI-REV-Cerâmica 30x40, Massa: 6.136 kg; EI-REV-Cerâmica 30x40, Volume Componente (Líquido): 0.003068 m3; EI-REV-Cerâmica 30x40, Volume do componente (Bruto): 0.003068 m3; EI-REV-Emboço Interno, Massa: 0.8437 kg; EI-REV-Emboço Interno, Volume Componente (Líquido): 0.000649 m3; EI-REV-Emboço Interno, Volume do componente (Bruto): 0.000649 m3; EI-REV-Chapisco (interno), Massa: 0.80535 kg; EI-REV-Chapisco (interno), Volume Componente (Líquido): 0.0006195 m3; EI-REV-Chapisco (interno), Volume do componente (Bruto): 0.0006195 m3
AL17 | TÉRREO | EI-REV-Cerâmica 30x40, EI-REV-Emboço Interno, EI-REV-Chapisco (interno) | - | BLOCO A | AL17 | no | Component Quantities - EI-REV-Cerâmica 30x40, Massa: 5.4 kg; EI-REV-Cerâmica 30x40, Volume Componente (Líquido): 0.0027 m3; EI-REV-Cerâmica 30x40, Volume do componente (Bruto): 0.0027 m3; EI-REV-Emboço Interno, Massa: 0.7605 kg; EI-REV-Emboço Interno, Volume Componente (Líquido): 0.000585 m3; EI-REV-Emboço Interno, Volume do componente (Bruto): 0.000585 m3; EI-REV-Chapisco (interno), Massa: 0.73125 kg; EI-REV-Chapisco (interno), Volume Componente (Líquido): 0.0005625 m3; EI-REV-Chapisco (interno), Volume do componente (Bruto): 0.0005625 m3
AL14 | TÉRREO | EI-REV-Cerâmica 30x40, EI-REV-Emboço Interno, EI-REV-Chapisco (interno) | - | BLOCO A | AL14 | no | Component Quantities - EI-REV-Cerâmica 30x40, Massa: 5.4 kg; EI-REV-Cerâmica 30x40, Volume Componente (Líquido): 0.0027 m3; EI-REV-Cerâmica 30x40, Volume do componente (Bruto): 0.0027 m3; EI-REV-Emboço Interno, Massa: 0.7605 kg; EI-REV-Emboço Interno, Volume Componente (Líquido): 0.000585 m3; EI-REV-Emboço Interno, Volume do componente (Bruto): 0.000585 m3; EI-REV-Chapisco (interno), Massa: 0.73125 kg; EI-REV-Chapisco (interno), Volume Componente (Líquido): 0.0005625 m3; EI-REV-Chapisco (interno), Volume do componente (Bruto): 0.0005625 m3
AL16 | TÉRREO | EI-REV-Cerâmica 30x40, EI-REV-Emboço Interno, EI-REV-Chapisco (interno) | - | BLOCO A | AL16 | no | Component Quantities - EI-REV-Cerâmica 30x40, Massa: 4.732 kg; EI-REV-Cerâmica 30x40, Volume Componente (Líquido): 0.002366 m3; EI-REV-Cerâmica 30x40, Volume do componente (Bruto): 0.002366 m3; EI-REV-Emboço Interno, Massa: 0.65065 kg; EI-REV-Emboço Interno, Volume Componente (Líquido): 0.0005005 m3; EI-REV-Emboço Interno, Volume do componente (Bruto): 0.0005005 m3; EI-REV-Chapisco (interno), Massa: 0.621075 kg; EI-REV-Chapisco (interno), Volume Componente (Líquido): 0.00047775 m3; EI-REV-Chapisco (interno), Volume do componente (Bruto): 0.00047775 m3
AL17 | TÉRREO | EI-REV-Cerâmica 30x40, EI-REV-Emboço Interno, EI-REV-Chapisco (interno) | - | BLOCO A | AL17 | no | Component Quantities - EI-REV-Cerâmica 30x40, Massa: 5.46 kg; EI-REV-Cerâmica 30x40, Volume Componente (Líquido): 0.00273 m3; EI-REV-Cerâmica 30x40, Volume do componente (Bruto): 0.00273 m3; EI-REV-Emboço Interno, Massa: 0.76895 kg; EI-REV-Emboço Interno, Volume Componente (Líquido): 0.0005915 m3; EI-REV-Emboço Interno, Volume do componente (Bruto): 0.0005915 m3; EI-REV-Chapisco (interno), Massa: 0.739375 kg; EI-REV-Chapisco (interno), Volume Componente (Líquido): 0.00056875 m3; EI-REV-Chapisco (interno), Volume do componente (Bruto): 0.00056875 m3
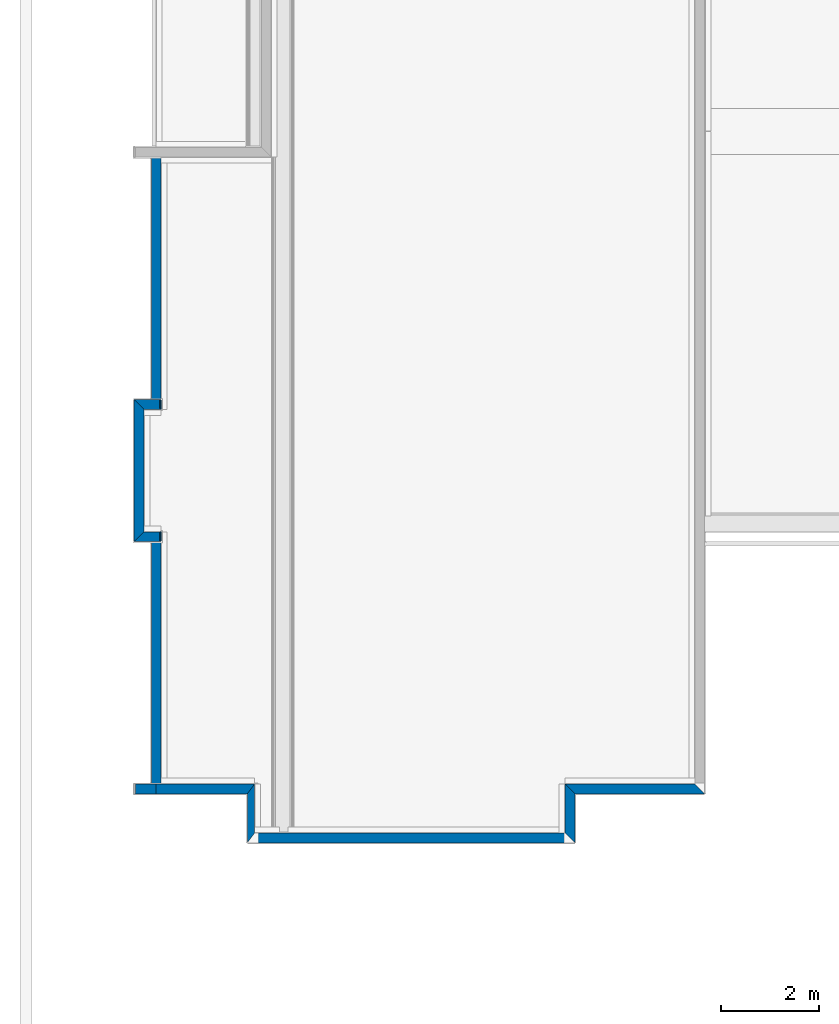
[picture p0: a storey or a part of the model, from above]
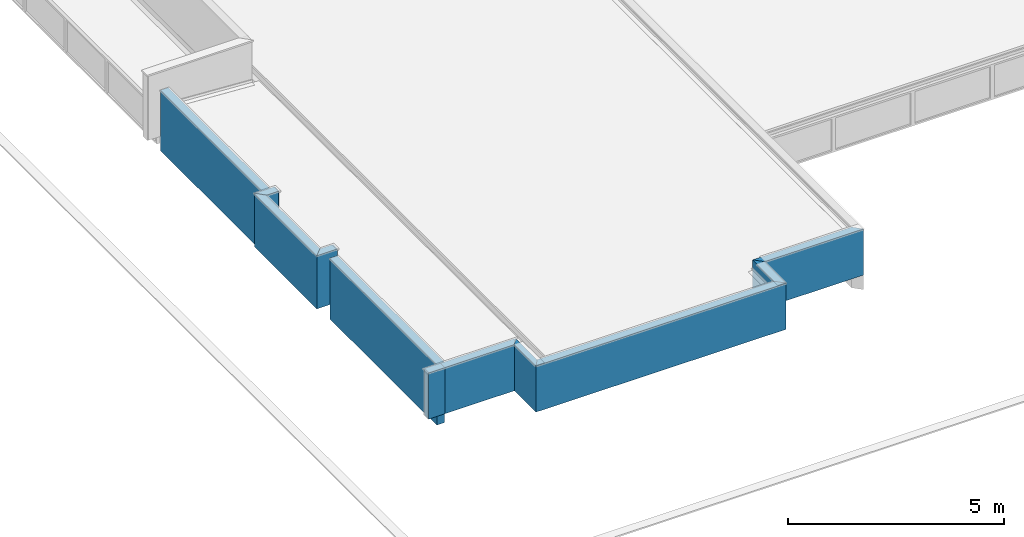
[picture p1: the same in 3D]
Properties of the parts of a building model (IFC4), part 9 of 22

# IfcWall: Arremate com Dobra Revest 27 (61)
Name | In | Material | Alvenarias | 1_Bloco | 0_ID | IsExternal | EI-REV-Massa Acrílica (externa), Massa (kg) | EI-REV-Massa Acrílica (externa), Volume Componente (Líquido) (m3) = EI-REV-Massa Acrílica (externa), Volume do componente (Bruto) (m3) | EI-REV-Massa única - Fachada, Massa (kg) | EI-REV-Massa única - Fachada, Volume Componente (Líquido) (m3) = EI-REV-Massa única - Fachada, Volume do componente (Bruto) (m3)
AL18 | TÉRREO | EI-REV-Cerâmica 30x40, EI-REV-Emboço Interno, EI-REV-Chapisco (interno) | - | BLOCO A | AL18 | no | Component Quantities - EI-REV-Cerâmica 30x40, Massa: 5.46 kg; EI-REV-Cerâmica 30x40, Volume Componente (Líquido): 0.00273 m3; EI-REV-Cerâmica 30x40, Volume do componente (Bruto): 0.00273 m3; EI-REV-Emboço Interno, Massa: 0.76895 kg; EI-REV-Emboço Interno, Volume Componente (Líquido): 0.0005915 m3; EI-REV-Emboço Interno, Volume do componente (Bruto): 0.0005915 m3; EI-REV-Chapisco (interno), Massa: 0.739375 kg; EI-REV-Chapisco (interno), Volume Componente (Líquido): 0.00056875 m3; EI-REV-Chapisco (interno), Volume do componente (Bruto): 0.00056875 m3
AL19 | TÉRREO | EI-REV-Cerâmica 30x40, EI-REV-Emboço Interno, EI-REV-Chapisco (interno) | - | BLOCO A | AL19 | no | Component Quantities - EI-REV-Cerâmica 30x40, Massa: 4.732 kg; EI-REV-Cerâmica 30x40, Volume Componente (Líquido): 0.002366 m3; EI-REV-Cerâmica 30x40, Volume do componente (Bruto): 0.002366 m3; EI-REV-Emboço Interno, Massa: 0.65065 kg; EI-REV-Emboço Interno, Volume Componente (Líquido): 0.0005005 m3; EI-REV-Emboço Interno, Volume do componente (Bruto): 0.0005005 m3; EI-REV-Chapisco (interno), Massa: 0.621075 kg; EI-REV-Chapisco (interno), Volume Componente (Líquido): 0.00047775 m3; EI-REV-Chapisco (interno), Volume do componente (Bruto): 0.00047775 m3
AL15 | TÉRREO | EI-REV-Cerâmica 30x40, EI-REV-Emboço Interno, EI-REV-Chapisco (interno) | - | BLOCO A | AL15 | no | Component Quantities - EI-REV-Cerâmica 30x40, Massa: 5.46 kg; EI-REV-Cerâmica 30x40, Volume Componente (Líquido): 0.00273 m3; EI-REV-Cerâmica 30x40, Volume do componente (Bruto): 0.00273 m3; EI-REV-Emboço Interno, Massa: 0.76895 kg; EI-REV-Emboço Interno, Volume Componente (Líquido): 0.0005915 m3; EI-REV-Emboço Interno, Volume do componente (Bruto): 0.0005915 m3; EI-REV-Chapisco (interno), Massa: 0.739375 kg; EI-REV-Chapisco (interno), Volume Componente (Líquido): 0.00056875 m3; EI-REV-Chapisco (interno), Volume do componente (Bruto): 0.00056875 m3
AL24 | TÉRREO | EI-REV-Cerâmica 30x40, EI-REV-Emboço Interno, EI-REV-Chapisco (interno) | - | BLOCO A | AL24 | no | Component Quantities - EI-REV-Cerâmica 30x40, Massa: 4.238 kg; EI-REV-Cerâmica 30x40, Volume Componente (Líquido): 0.002119 m3; EI-REV-Cerâmica 30x40, Volume do componente (Bruto): 0.002119 m3; EI-REV-Emboço Interno, Massa: 0.582725 kg; EI-REV-Emboço Interno, Volume Componente (Líquido): 0.00044825 m3; EI-REV-Emboço Interno, Volume do componente (Bruto): 0.00044825 m3; EI-REV-Chapisco (interno), Massa: 0.556238 kg; EI-REV-Chapisco (interno), Volume Componente (Líquido): 0.000427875 m3; EI-REV-Chapisco (interno), Volume do componente (Bruto): 0.000427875 m3
AL21 | TÉRREO | EI-REV-Cerâmica 30x40, EI-REV-Emboço Interno, EI-REV-Chapisco (interno) | - | BLOCO A | AL21 | no | Component Quantities - EI-REV-Cerâmica 30x40, Massa: 5.46 kg; EI-REV-Cerâmica 30x40, Volume Componente (Líquido): 0.00273 m3; EI-REV-Cerâmica 30x40, Volume do componente (Bruto): 0.00273 m3; EI-REV-Emboço Interno, Massa: 0.76895 kg; EI-REV-Emboço Interno, Volume Componente (Líquido): 0.0005915 m3; EI-REV-Emboço Interno, Volume do componente (Bruto): 0.0005915 m3; EI-REV-Chapisco (interno), Massa: 0.739375 kg; EI-REV-Chapisco (interno), Volume Componente (Líquido): 0.00056875 m3; EI-REV-Chapisco (interno), Volume do componente (Bruto): 0.00056875 m3
AL20 | TÉRREO | EI-REV-Cerâmica 30x40, EI-REV-Emboço Interno, EI-REV-Chapisco (interno) | - | BLOCO A | AL20 | no | Component Quantities - EI-REV-Cerâmica 30x40, Massa: 5.46 kg; EI-REV-Cerâmica 30x40, Volume Componente (Líquido): 0.00273 m3; EI-REV-Cerâmica 30x40, Volume do componente (Bruto): 0.00273 m3; EI-REV-Emboço Interno, Massa: 0.76895 kg; EI-REV-Emboço Interno, Volume Componente (Líquido): 0.0005915 m3; EI-REV-Emboço Interno, Volume do componente (Bruto): 0.0005915 m3; EI-REV-Chapisco (interno), Massa: 0.739375 kg; EI-REV-Chapisco (interno), Volume Componente (Líquido): 0.00056875 m3; EI-REV-Chapisco (interno), Volume do componente (Bruto): 0.00056875 m3
AL23 | TÉRREO | EI-REV-Cerâmica 30x40, EI-REV-Emboço Interno, EI-REV-Chapisco (interno) | - | BLOCO A | AL23 | no | Component Quantities - EI-REV-Cerâmica 30x40, Massa: 4.238 kg; EI-REV-Cerâmica 30x40, Volume Componente (Líquido): 0.002119 m3; EI-REV-Cerâmica 30x40, Volume do componente (Bruto): 0.002119 m3; EI-REV-Emboço Interno, Massa: 0.582725 kg; EI-REV-Emboço Interno, Volume Componente (Líquido): 0.00044825 m3; EI-REV-Emboço Interno, Volume do componente (Bruto): 0.00044825 m3; EI-REV-Chapisco (interno), Massa: 0.556238 kg; EI-REV-Chapisco (interno), Volume Componente (Líquido): 0.000427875 m3; EI-REV-Chapisco (interno), Volume do componente (Bruto): 0.000427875 m3
AL14 | TÉRREO | EI-REV-Cerâmica 30x40, EI-REV-Emboço Interno, EI-REV-Chapisco (interno) | Mureta | BLOCO B | AL14 | no | Component Quantities - EI-REV-Cerâmica 30x40, Massa: 3.48 kg; EI-REV-Cerâmica 30x40, Volume Componente (Líquido): 0.00174 m3; EI-REV-Cerâmica 30x40, Volume do componente (Bruto): 0.00174 m3; EI-REV-Emboço Interno, Massa: 0.4901 kg; EI-REV-Emboço Interno, Volume Componente (Líquido): 0.000377 m3; EI-REV-Emboço Interno, Volume do componente (Bruto): 0.000377 m3; EI-REV-Chapisco (interno), Massa: 0.47125 kg; EI-REV-Chapisco (interno), Volume Componente (Líquido): 0.0003625 m3; EI-REV-Chapisco (interno), Volume do componente (Bruto): 0.0003625 m3
AL14 | TÉRREO | EI-REV-Cerâmica 30x40, EI-REV-Emboço Interno, EI-REV-Chapisco (interno) | Mureta | BLOCO B | AL14 | no | Component Quantities - EI-REV-Cerâmica 30x40, Massa: 4.8 kg; EI-REV-Cerâmica 30x40, Volume Componente (Líquido): 0.0024 m3; EI-REV-Cerâmica 30x40, Volume do componente (Bruto): 0.0024 m3; EI-REV-Emboço Interno, Massa: 0.676 kg; EI-REV-Emboço Interno, Volume Componente (Líquido): 0.00052 m3; EI-REV-Emboço Interno, Volume do componente (Bruto): 0.00052 m3; EI-REV-Chapisco (interno), Massa: 0.65 kg; EI-REV-Chapisco (interno), Volume Componente (Líquido): 0.0005 m3; EI-REV-Chapisco (interno), Volume do componente (Bruto): 0.0005 m3
AL09 | TÉRREO | EI-REV-Cerâmica 30x40, EI-REV-Emboço Interno, EI-REV-Chapisco (interno) | - | BLOCO A | AL09 | no | Component Quantities - EI-REV-Cerâmica 30x40, Massa: 5.46 kg; EI-REV-Cerâmica 30x40, Volume Componente (Líquido): 0.00273 m3; EI-REV-Cerâmica 30x40, Volume do componente (Bruto): 0.00273 m3; EI-REV-Emboço Interno, Massa: 0.76895 kg; EI-REV-Emboço Interno, Volume Componente (Líquido): 0.0005915 m3; EI-REV-Emboço Interno, Volume do componente (Bruto): 0.0005915 m3; EI-REV-Chapisco (interno), Massa: 0.739375 kg; EI-REV-Chapisco (interno), Volume Componente (Líquido): 0.00056875 m3; EI-REV-Chapisco (interno), Volume do componente (Bruto): 0.00056875 m3
2 x AL14 | COBERTURA | EI-REV-Pintura Acrílica Cor Cinza, EI-REV-Massa Acrílica (externa), EI-REV-Massa única - Fachada | Alvenaria de Vedação / Edificação | BLOCO B | AL14 | yes | 1.57527 | 0.00121175 | 1.5327 | 0.001179 | Component Quantities - EI-REV-Pintura Acrílica Cor Cinza, Massa: 5.109 kg; EI-REV-Pintura Acrílica Cor Cinza, Volume Componente (Líquido): 0.00393 m3; EI-REV-Pintura Acrílica Cor Cinza, Volume do componente (Bruto): 0.00393 m3
2 x AL14 | COBERTURA | EI-REV-Pintura Acrílica Cor Cinza, EI-REV-Massa Acrílica (externa), EI-REV-Massa única - Fachada | Alvenaria de Vedação / Edificação | BLOCO B | AL14 | yes | 2.23665 | 0.0017205 | 2.1762 | 0.001674 | Component Quantities - EI-REV-Pintura Acrílica Cor Cinza, Massa: 7.254 kg; EI-REV-Pintura Acrílica Cor Cinza, Volume Componente (Líquido): 0.00558 m3; EI-REV-Pintura Acrílica Cor Cinza, Volume do componente (Bruto): 0.00558 m3
6 x AL14 | COBERTURA | EI-REV-Pintura Acrílica Cor Branco Gelo, EI-REV-Massa Acrílica (externa), EI-REV-Massa única - Fachada | - | BLOCO B | AL14 | yes | 1.66855 | 0.0012835 | 1.61947 | 0.00124575 | Component Quantities - EI-REV-Pintura Acrílica Cor Branco Gelo, Massa: 5.44733 kg; EI-REV-Pintura Acrílica Cor Branco Gelo, Volume Componente (Líquido): 0.00419025 m3; EI-REV-Pintura Acrílica Cor Branco Gelo, Volume do componente (Bruto): 0.00419025 m3
5 x AL14 | COBERTURA | EI-REV-Pintura Acrílica Cor Branco Gelo, EI-REV-Massa Acrílica (externa), EI-REV-Massa única - Fachada | - | BLOCO A | AL14 | yes | 1.66855 | 0.0012835 | 1.61947 | 0.00124575 | Component Quantities - EI-REV-Pintura Acrílica Cor Branco Gelo, Massa: 5.44733 kg; EI-REV-Pintura Acrílica Cor Branco Gelo, Volume Componente (Líquido): 0.00419025 m3; EI-REV-Pintura Acrílica Cor Branco Gelo, Volume do componente (Bruto): 0.00419025 m3
AL14 | COBERTURA | EI-REV-Pintura Acrílica Cor Branco Gelo, EI-REV-Massa Acrílica (externa), EI-REV-Massa única - Fachada | - | BLOCO A | AL14 | no | 1.66855 | 0.0012835 | 1.61947 | 0.00124575 | Component Quantities - EI-REV-Pintura Acrílica Cor Branco Gelo, Massa: 5.44733 kg; EI-REV-Pintura Acrílica Cor Branco Gelo, Volume Componente (Líquido): 0.00419025 m3; EI-REV-Pintura Acrílica Cor Branco Gelo, Volume do componente (Bruto): 0.00419025 m3
2 x AL14 | COBERTURA | EI-REV-Pintura Acrílica Cor Cinza, EI-REV-Massa Acrílica (externa), EI-REV-Massa única - Fachada | Alvenaria de Vedação / Edificação | BLOCO A | AL14 | yes | 2.23665 | 0.0017205 | 2.1762 | 0.001674 | Component Quantities - EI-REV-Pintura Acrílica Cor Cinza, Massa: 7.254 kg; EI-REV-Pintura Acrílica Cor Cinza, Volume Componente (Líquido): 0.00558 m3; EI-REV-Pintura Acrílica Cor Cinza, Volume do componente (Bruto): 0.00558 m3
2 x AL14 | COBERTURA | EI-REV-Pintura Acrílica Cor Cinza, EI-REV-Massa Acrílica (externa), EI-REV-Massa única - Fachada | Alvenaria de Vedação / Edificação | BLOCO A | AL14 | yes | 1.57527 | 0.00121175 | 1.5327 | 0.001179 | Component Quantities - EI-REV-Pintura Acrílica Cor Cinza, Massa: 5.109 kg; EI-REV-Pintura Acrílica Cor Cinza, Volume Componente (Líquido): 0.00393 m3; EI-REV-Pintura Acrílica Cor Cinza, Volume do componente (Bruto): 0.00393 m3
2 x AL09 | COBERTURA | EI-REV-Pintura Acrílica Cor Branco Gelo, EI-REV-Massa Acrílica (externa), EI-REV-Massa única - Fachada | - | BLOCO A | AL09 | no | 1.4586 | 0.001122 | 1.4157 | 0.001089 | Component Quantities - EI-REV-Pintura Acrílica Cor Branco Gelo, Massa: 4.7619 kg; EI-REV-Pintura Acrílica Cor Branco Gelo, Volume Componente (Líquido): 0.003663 m3; EI-REV-Pintura Acrílica Cor Branco Gelo, Volume do componente (Bruto): 0.003663 m3

# IfcWall: Cobogó 27 (30)
In: TÉRREO
Classification: Parede (Classificação Archicad)
Pset_WallCommon - ThermalTransmittance: 0; IsExternal: no; LoadBearing: no
FNDE - Alvenarias: -; Sistemas de Cobertura: -; Esquadrias - Fechamentos metálicos e Gradis: -; 1_Bloco: BLOCO A; 0_ID: CG1
Name | Cobogó | Component, Volume Componente (Líquido) (m3) = Component, Volume do componente (Bruto) (m3)
18 x CG1 | COBOGÓ PADRÃO 03 - QUADRICULADO | 0.001824
7 x CG1 | COBOGÓ PADRÃO 02 - TACO CHINES | 0.00111744
5 x CG1 | COBOGÓ PADRÃO 01 - 4 PONTAS | 0.00352349

# IfcWall: FNDE-AL09-E1 (cinza) 120 x 3100 (4)
In: TÉRREO
Classification: Parede (Classificação Archicad); Material: TIJOLO - CERAMICO 9x19x39 - espessura 15cm, EI-REV-Chapisco (externo), EI-REV-Pintura Acrílica Cor Cinza, EI-REV-Massa única - Fachada, EI-REV-Massa Acrílica (externa), EI-REV-Pintura Acrílica Cor Branco Gelo
FNDE - Alvenarias: Alvenaria de Vedação / Edificação; Sistemas de Cobertura: -; Esquadrias - Fechamentos metálicos e Gradis: -; 0_ID: AL09
Pset_WallCommon - IsExternal: yes; LoadBearing: no
Component Quantities - TIJOLO - CERAMICO 9x19x39 - espessura 15cm, Altura do Componente Retangular: 3.1 m; TIJOLO - CERAMICO 9x19x39 - espessura 15cm, Largura do Componente Retangular: 0.09 m; TIJOLO - CERAMICO 9x19x39 - espessura 15cm, Área de Seção Transversal do Componente: 0.279 m2; EI-REV-Chapisco (externo), Altura do Componente Retangular: 3.1 m; EI-REV-Chapisco (externo), Largura do Componente Retangular: 0.005 m; EI-REV-Chapisco (externo), Área de Seção Transversal do Componente: 0.0155 m2; EI-REV-Pintura Acrílica Cor Cinza, Altura do Componente Retangular: 0.44 m; EI-REV-Pintura Acrílica Cor Cinza, Largura do Componente Retangular: 0.015 m; EI-REV-Pintura Acrílica Cor Cinza, Área de Seção Transversal do Componente: 0.0066 m2; EI-REV-Pintura Acrílica Cor Branco Gelo, Altura do Componente Retangular: 2.66 m; EI-REV-Pintura Acrílica Cor Branco Gelo, Largura do Componente Retangular: 0.015 m; EI-REV-Pintura Acrílica Cor Branco Gelo, Área de Seção Transversal do Componente: 0.0399 m2
Name | 1_Bloco | TIJOLO - CERAMICO 9x19x39 - espessura 15cm, Massa (kg) | TIJOLO - CERAMICO 9x19x39 - espessura 15cm, Área de Componente Projetada (Líquida) (m2) = TIJOLO - CERAMICO 9x19x39 - espessura 15cm, Área de Componente Projetada (Bruta) (m2) | TIJOLO - CERAMICO 9x19x39 - espessura 15cm, Volume Componente (Líquido) (m3) = TIJOLO - CERAMICO 9x19x39 - espessura 15cm, Volume do componente (Bruto) (m3) | EI-REV-Chapisco (externo), Massa (kg) | EI-REV-Chapisco (externo), Área de Componente Projetada (Líquida) (m2) = EI-REV-Chapisco (externo), Área de Componente Projetada (Bruta) (m2) | EI-REV-Chapisco (externo), Volume Componente (Líquido) (m3) = EI-REV-Chapisco (externo), Volume do componente (Bruto) (m3) | EI-REV-Pintura Acrílica Cor Cinza, Massa (kg) | EI-REV-Pintura Acrílica Cor Cinza, Área de Componente Projetada (Líquida) (m2) = EI-REV-Pintura Acrílica Cor Cinza, Área de Componente Projetada (Bruta) (m2) | EI-REV-Pintura Acrílica Cor Cinza, Volume Componente (Líquido) (m3) = EI-REV-Pintura Acrílica Cor Cinza, Volume do componente (Bruto) (m3) | EI-REV-Pintura Acrílica Cor Branco Gelo, Massa (kg) | EI-REV-Pintura Acrílica Cor Branco Gelo, Área de Componente Projetada (Líquida) (m2) = EI-REV-Pintura Acrílica Cor Branco Gelo, Área de Componente Projetada (Bruta) (m2) | EI-REV-Pintura Acrílica Cor Branco Gelo, Volume Componente (Líquido) (m3) = EI-REV-Pintura Acrílica Cor Branco Gelo, Volume do componente (Bruto) (m3)
AL09 | BLOCO B | 135.426 | 2.66201 | 0.20899 | 20.0363 | 3.08251 | 0.0154125 | 8.45132 | 0.433401 | 0.00650102 | 51.0921 | 2.62011 | 0.0393016 | Component Quantities - EI-REV-Massa única - Fachada, Massa: 20.0493 kg; EI-REV-Massa única - Fachada, Área de Componente Projetada (Líquida): 3.08451 m2; EI-REV-Massa única - Fachada, Área de Componente Projetada (Bruta): 3.08451 m2; EI-REV-Massa única - Fachada, Altura do Componente Retangular: 3.1 m; EI-REV-Massa única - Fachada, Largura do Componente Retangular: 0.005 m; EI-REV-Massa única - Fachada, Área de Seção Transversal do Componente: 0.0155 m2; EI-REV-Massa única - Fachada, Volume Componente (Líquido): 0.0154225 m3; EI-REV-Massa única - Fachada, Volume do componente (Bruto): 0.0154225 m3; EI-REV-Massa única - Fachada: 2 with these values
AL09 | BLOCO B | 133.852 | 2.66558 | 0.206561 | 20.0465 | 3.08408 | 0.0154204 | 8.45014 | 0.43334 | 0.0065001 | 51.0849 | 2.61974 | 0.0392961 | Component Quantities - EI-REV-Chapisco (externo): 3 with these values
AL09 | BLOCO A | 135.651 | 2.32598 | 0.209338 | 15.1319 | 2.32798 | 0.0116399 | 8.57556 | 0.44 | 0.00659658 | 51.8195 | 2.66 | 0.0398612 | Component Quantities - EI-REV-Massa única - Fachada, Massa: 15.1449 kg; EI-REV-Massa única - Fachada, Área de Componente Projetada (Líquida): 2.32998 m2; EI-REV-Massa única - Fachada, Área de Componente Projetada (Bruta): 2.32998 m2; EI-REV-Massa única - Fachada, Altura do Componente Retangular: 3.1 m; EI-REV-Massa única - Fachada, Largura do Componente Retangular: 0.005 m; EI-REV-Massa única - Fachada, Área de Seção Transversal do Componente: 0.0155 m2; EI-REV-Massa única - Fachada, Volume Componente (Líquido): 0.0116499 m3; EI-REV-Massa única - Fachada, Volume do componente (Bruto): 0.0116499 m3; EI-REV-Massa Acrílica (externa), Massa: 15.1579 kg; EI-REV-Massa Acrílica (externa), Área de Componente Projetada (Líquida): 2.33198 m2; EI-REV-Massa Acrílica (externa), Área de Componente Projetada (Bruta): 2.33198 m2; EI-REV-Massa Acrílica (externa), Altura do Componente Retangular: 3.1 m; EI-REV-Massa Acrílica (externa), Largura do Componente Retangular: 0.005 m; EI-REV-Massa Acrílica (externa), Área de Seção Transversal do Componente: 0.0155 m2; EI-REV-Massa Acrílica (externa), Volume Componente (Líquido): 0.0116599 m3; EI-REV-Massa Acrílica (externa), Volume do componente (Bruto): 0.0116599 m3
AL09 | BLOCO A | 148.82 | 2.66578 | 0.22966 | 20.0479 | 3.0843 | 0.0154215 | 8.45075 | 0.433372 | 0.00650057 | 51.0886 | 2.61993 | 0.0392989 | Component Quantities - EI-REV-Chapisco (externo): 3 with these values

# IfcWall: FNDE-AL09-E1 (cinza) 120 x 3640, AL09
In: TÉRREO
Classification: Parede (Classificação Archicad); Material: TIJOLO - CERAMICO 9x19x39 - espessura 15cm, EI-REV-Chapisco (externo), EI-REV-Pintura Acrílica Cor Cinza, EI-REV-Massa única - Fachada, EI-REV-Massa Acrílica (externa), EI-REV-Pintura Acrílica Cor Branco Gelo
FNDE - Alvenarias: Alvenaria de Vedação / Edificação; Sistemas de Cobertura: -; Esquadrias - Fechamentos metálicos e Gradis: -; 1_Bloco: BLOCO A; 0_ID: AL09
Pset_WallCommon - IsExternal: yes; LoadBearing: no
Component Quantities - TIJOLO - CERAMICO 9x19x39 - espessura 15cm, Massa: 302.945 kg; TIJOLO - CERAMICO 9x19x39 - espessura 15cm, Área de Componente Projetada (Líquida): 5.51471 m2; TIJOLO - CERAMICO 9x19x39 - espessura 15cm, Área de Componente Projetada (Bruta): 5.51471 m2; TIJOLO - CERAMICO 9x19x39 - espessura 15cm, Altura do Componente Retangular: 3.64 m; TIJOLO - CERAMICO 9x19x39 - espessura 15cm, Largura do Componente Retangular: 0.09 m; TIJOLO - CERAMICO 9x19x39 - espessura 15cm, Área de Seção Transversal do Componente: 0.3276 m2; TIJOLO - CERAMICO 9x19x39 - espessura 15cm, Volume Componente (Líquido): 0.467508 m3; TIJOLO - CERAMICO 9x19x39 - espessura 15cm, Volume do componente (Bruto): 0.467508 m3; EI-REV-Chapisco (externo), Massa: 41.7442 kg; EI-REV-Chapisco (externo), Área de Componente Projetada (Líquida): 6.42222 m2; EI-REV-Chapisco (externo), Área de Componente Projetada (Bruta): 6.42222 m2; EI-REV-Chapisco (externo), Altura do Componente Retangular: 3.64 m; EI-REV-Chapisco (externo), Largura do Componente Retangular: 0.00499998 m; EI-REV-Chapisco (externo), Área de Seção Transversal do Componente: 0.0181999 m2; EI-REV-Chapisco (externo), Volume Componente (Líquido): 0.0321109 m3; EI-REV-Chapisco (externo), Volume do componente (Bruto): 0.0321109 m3; EI-REV-Pintura Acrílica Cor Cinza, Massa: 17.0312 kg; EI-REV-Pintura Acrílica Cor Cinza, Área de Componente Projetada (Líquida): 0.873396 m2; EI-REV-Pintura Acrílica Cor Cinza, Área de Componente Projetada (Bruta): 0.873396 m2; EI-REV-Pintura Acrílica Cor Cinza, Altura do Componente Retangular: 0.44 m; EI-REV-Pintura Acrílica Cor Cinza, Largura do Componente Retangular: 0.015 m; EI-REV-Pintura Acrílica Cor Cinza, Área de Seção Transversal do Componente: 0.00659999 m2; EI-REV-Pintura Acrílica Cor Cinza, Volume Componente (Líquido): 0.0131009 m3; EI-REV-Pintura Acrílica Cor Cinza, Volume do componente (Bruto): 0.0131009 m3; EI-REV-Massa única - Fachada, Massa: 42.1981 kg; EI-REV-Massa única - Fachada, Área de Componente Projetada (Líquida): 6.49202 m2; EI-REV-Massa única - Fachada, Área de Componente Projetada (Bruta): 6.49202 m2; EI-REV-Massa única - Fachada, Altura do Componente Retangular: 3.64 m; EI-REV-Massa única - Fachada, Largura do Componente Retangular: 0.005 m; EI-REV-Massa única - Fachada, Área de Seção Transversal do Componente: 0.0182 m2; EI-REV-Massa única - Fachada, Volume Componente (Líquido): 0.0324601 m3; EI-REV-Massa única - Fachada, Volume do componente (Bruto): 0.0324601 m3; EI-REV-Massa Acrílica (externa), Massa: 42.489 kg; EI-REV-Massa Acrílica (externa), Área de Componente Projetada (Líquida): 7.2049 m2; EI-REV-Massa Acrílica (externa), Área de Componente Projetada (Bruta): 7.2049 m2; EI-REV-Massa Acrílica (externa), Altura do Componente Retangular: 3.64 m; EI-REV-Massa Acrílica (externa), Largura do Componente Retangular: 0.00500003 m; EI-REV-Massa Acrílica (externa), Área de Seção Transversal do Componente: 0.0182 m2; EI-REV-Massa Acrílica (externa), Volume Componente (Líquido): 0.0326838 m3; EI-REV-Massa Acrílica (externa), Volume do componente (Bruto): 0.0326838 m3; EI-REV-Pintura Acrílica Cor Branco Gelo, Massa: 123.819 kg; EI-REV-Pintura Acrílica Cor Branco Gelo, Área de Componente Projetada (Líquida): 6.3497 m2; EI-REV-Pintura Acrílica Cor Branco Gelo, Área de Componente Projetada (Bruta): 6.3497 m2; EI-REV-Pintura Acrílica Cor Branco Gelo, Altura do Componente Retangular: 3.2 m; EI-REV-Pintura Acrílica Cor Branco Gelo, Largura do Componente Retangular: 0.015 m; EI-REV-Pintura Acrílica Cor Branco Gelo, Área de Seção Transversal do Componente: 0.048 m2; EI-REV-Pintura Acrílica Cor Branco Gelo, Volume Componente (Líquido): 0.0952454 m3; EI-REV-Pintura Acrílica Cor Branco Gelo, Volume do componente (Bruto): 0.0952454 m3

# IfcWall: FNDE-AL09-E2 120 (3)
In: TÉRREO
Classification: Parede (Classificação Archicad); Material: EI-REV-Pintura Acrílica Cor Cinza 0.015 m, EI-REV-Massa Acrílica (externa) 0.005 m, EI-REV-Massa única - Fachada 0.005 m, EI-REV-Chapisco (externo) 0.005 m, TIJOLO - CERAMICO 9x19x39 - espessura 15cm 0.09 m
FNDE - Alvenarias: Alvenaria de Vedação / Edificação; Sistemas de Cobertura: -; Esquadrias - Fechamentos metálicos e Gradis: -; 1_Bloco: BLOCO B; 0_ID: AL09
Pset_WallCommon - IsExternal: yes; LoadBearing: no
Component Quantities - EI-REV-Pintura Acrílica Cor Cinza, Espessura do Componente: 0.015 m; EI-REV-Pintura Acrílica Cor Cinza, Altura do Componente Retangular: 3.14 m; EI-REV-Pintura Acrílica Cor Cinza, Largura do Componente Retangular: 0.015 m; EI-REV-Pintura Acrílica Cor Cinza, Área de Seção Transversal do Componente: 0.0471 m2; EI-REV-Massa Acrílica (externa), Espessura do Componente: 0.005 m; EI-REV-Massa Acrílica (externa), Altura do Componente Retangular: 3.14 m; EI-REV-Massa Acrílica (externa), Largura do Componente Retangular: 0.005 m; EI-REV-Massa Acrílica (externa), Área de Seção Transversal do Componente: 0.0157 m2; TIJOLO - CERAMICO 9x19x39 - espessura 15cm, Espessura do Componente: 0.09 m; TIJOLO - CERAMICO 9x19x39 - espessura 15cm, Altura do Componente Retangular: 3.14 m; TIJOLO - CERAMICO 9x19x39 - espessura 15cm, Largura do Componente Retangular: 0.09 m; TIJOLO - CERAMICO 9x19x39 - espessura 15cm, Área de Seção Transversal do Componente: 0.2826 m2
Name | EI-REV-Pintura Acrílica Cor Cinza, Massa (kg) | EI-REV-Pintura Acrílica Cor Cinza, Área de Componente Projetada (Líquida) (m2) = EI-REV-Pintura Acrílica Cor Cinza, Área de Componente Projetada (Bruta) (m2) | EI-REV-Pintura Acrílica Cor Cinza, Volume Componente (Líquido) (m3) = EI-REV-Pintura Acrílica Cor Cinza, Volume do componente (Bruto) (m3) | EI-REV-Massa Acrílica (externa), Massa (kg) | EI-REV-Massa Acrílica (externa), Área de Componente Projetada (Líquida) (m2) = EI-REV-Massa Acrílica (externa), Área de Componente Projetada (Bruta) (m2) | EI-REV-Massa Acrílica (externa), Volume Componente (Líquido) (m3) = EI-REV-Massa Acrílica (externa), Volume do componente (Bruto) (m3) | EI-REV-Massa única - Fachada, Massa (kg) | EI-REV-Massa única - Fachada, Área de Componente Projetada (Líquida) (m2) = EI-REV-Massa única - Fachada, Área de Componente Projetada (Bruta) (m2) | EI-REV-Massa única - Fachada, Espessura do Componente (m) = EI-REV-Massa única - Fachada, Largura do Componente Retangular (m) | EI-REV-Massa única - Fachada, Altura do Componente Retangular (m) | EI-REV-Massa única - Fachada, Área de Seção Transversal do Componente (m2) | EI-REV-Massa única - Fachada, Volume Componente (Líquido) (m3) = EI-REV-Massa única - Fachada, Volume do componente (Bruto) (m3) | TIJOLO - CERAMICO 9x19x39 - espessura 15cm, Massa (kg) | TIJOLO - CERAMICO 9x19x39 - espessura 15cm, Área de Componente Projetada (Líquida) (m2) = TIJOLO - CERAMICO 9x19x39 - espessura 15cm, Área de Componente Projetada (Bruta) (m2) | TIJOLO - CERAMICO 9x19x39 - espessura 15cm, Volume Componente (Líquido) (m3) = TIJOLO - CERAMICO 9x19x39 - espessura 15cm, Volume do componente (Bruto) (m3)
AL09 | 29.0842 | 1.4915 | 0.0223725 | 9.89592 | 1.52245 | 0.00761224 | 9.88206 | 1.52032 | 0.005 | 3.14 | 0.0157 | 0.00760158 | 66.1117 | 1.1336 | 0.102024 | Component Quantities - EI-REV-Chapisco (externo), Massa: 9.86099 kg; EI-REV-Chapisco (externo), Área de Componente Projetada (Líquida): 1.51817 m2; EI-REV-Chapisco (externo), Área de Componente Projetada (Bruta): 1.51817 m2; EI-REV-Chapisco (externo), Espessura do Componente: 0.005 m; EI-REV-Chapisco (externo), Altura do Componente Retangular: 3.14 m; EI-REV-Chapisco (externo), Largura do Componente Retangular: 0.005 m; EI-REV-Chapisco (externo), Área de Seção Transversal do Componente: 0.0157 m2; EI-REV-Chapisco (externo), Volume Componente (Líquido): 0.00758537 m3; EI-REV-Chapisco (externo), Volume do componente (Bruto): 0.00758537 m3
AL09 | 36.6839 | 1.88111 | 0.0282184 | 10.6586 | 1.64116 | 0.00819889 | 10.6675 | 1.64116 | 0.005 | 3.14 | 0.0157 | 0.00820581 | 73.5087 | 1.26044 | 0.113439 | Component Quantities - EI-REV-Massa única - Fachada: 2 with these values
AL09 | 36.6818 | 1.88112 | 0.0282167 | 12.2272 | 1.88111 | 0.00940553 |  |  |  |  |  |  | 99.385 | 1.88405 | 0.153372 | Component Quantities - EI-REV-Massa Acrílica (externa): 3 with these values

# IfcWall: FNDE-AL09-E2-E2 150 (3)
In: TÉRREO
Classification: Parede (Classificação Archicad); Material: EI-REV-Pintura Acrílica Cor Cinza 0.015 m, EI-REV-Massa Acrílica (externa) 0.005 m, EI-REV-Massa única - Fachada 0.005 m, EI-REV-Chapisco (externo) 0.005 m, TIJOLO - CERAMICO 9x19x39 - espessura 15cm 0.09 m, EI-REV-Chapisco (externo) 0.005 m, EI-REV-Massa única - Fachada 0.005 m, EI-REV-Massa Acrílica (externa) 0.005 m, EI-REV-Pintura Acrílica Cor Cinza 0.015 m
FNDE - Alvenarias: Alvenaria de Vedação / Edificação; Sistemas de Cobertura: -; Esquadrias - Fechamentos metálicos e Gradis: -; 1_Bloco: CASA DE BOMBAS / GÁS / LIXO; 0_ID: AL09
Pset_WallCommon - IsExternal: yes; LoadBearing: no
Component Quantities - EI-REV-Pintura Acrílica Cor Cinza 1, Espessura do Componente: 0.015 m; EI-REV-Pintura Acrílica Cor Cinza 1, Altura do Componente Retangular: 2.12 m; EI-REV-Pintura Acrílica Cor Cinza 1, Largura do Componente Retangular: 0.015 m; EI-REV-Pintura Acrílica Cor Cinza 1, Área de Seção Transversal do Componente: 0.0318 m2; EI-REV-Massa Acrílica (externa) 1, Espessura do Componente: 0.005 m; EI-REV-Massa Acrílica (externa) 1, Altura do Componente Retangular: 2.12 m; EI-REV-Massa Acrílica (externa) 1, Largura do Componente Retangular: 0.005 m; EI-REV-Massa Acrílica (externa) 1, Área de Seção Transversal do Componente: 0.0106 m2; EI-REV-Massa única - Fachada 1, Espessura do Componente: 0.005 m; EI-REV-Massa única - Fachada 1, Altura do Componente Retangular: 2.12 m; EI-REV-Massa única - Fachada 1, Largura do Componente Retangular: 0.005 m; EI-REV-Massa única - Fachada 1, Área de Seção Transversal do Componente: 0.0106 m2; EI-REV-Chapisco (externo) 1, Espessura do Componente: 0.005 m; EI-REV-Chapisco (externo) 1, Altura do Componente Retangular: 2.12 m; EI-REV-Chapisco (externo) 1, Largura do Componente Retangular: 0.005 m; EI-REV-Chapisco (externo) 1, Área de Seção Transversal do Componente: 0.0106 m2; TIJOLO - CERAMICO 9x19x39 - espessura 15cm, Espessura do Componente: 0.09 m; TIJOLO - CERAMICO 9x19x39 - espessura 15cm, Altura do Componente Retangular: 2.12 m; TIJOLO - CERAMICO 9x19x39 - espessura 15cm, Largura do Componente Retangular: 0.09 m; TIJOLO - CERAMICO 9x19x39 - espessura 15cm, Área de Seção Transversal do Componente: 0.1908 m2; EI-REV-Pintura Acrílica Cor Cinza 2, Espessura do Componente: 0.015 m; EI-REV-Pintura Acrílica Cor Cinza 2, Altura do Componente Retangular: 2.12 m; EI-REV-Pintura Acrílica Cor Cinza 2, Largura do Componente Retangular: 0.015 m; EI-REV-Pintura Acrílica Cor Cinza 2, Área de Seção Transversal do Componente: 0.0318 m2
Name | EI-REV-Pintura Acrílica Cor Cinza 1, Massa (kg) | EI-REV-Pintura Acrílica Cor Cinza 1, Área de Componente Projetada (Líquida) (m2) | EI-REV-Pintura Acrílica Cor Cinza 1, Área de Componente Projetada (Bruta) (m2) | EI-REV-Pintura Acrílica Cor Cinza 1, Volume Componente (Líquido) (m3) | EI-REV-Pintura Acrílica Cor Cinza 1, Volume do componente (Bruto) (m3) | EI-REV-Massa Acrílica (externa) 1, Massa (kg) | EI-REV-Massa Acrílica (externa) 1, Área de Componente Projetada (Líquida) (m2) | EI-REV-Massa Acrílica (externa) 1, Área de Componente Projetada (Bruta) (m2) | EI-REV-Massa Acrílica (externa) 1, Volume Componente (Líquido) (m3) | EI-REV-Massa Acrílica (externa) 1, Volume do componente (Bruto) (m3) | EI-REV-Massa única - Fachada 1, Massa (kg) | EI-REV-Massa única - Fachada 1, Área de Componente Projetada (Líquida) (m2) | EI-REV-Massa única - Fachada 1, Área de Componente Projetada (Bruta) (m2) | EI-REV-Massa única - Fachada 1, Volume Componente (Líquido) (m3) | EI-REV-Massa única - Fachada 1, Volume do componente (Bruto) (m3) | EI-REV-Chapisco (externo) 1, Massa (kg) | EI-REV-Chapisco (externo) 1, Área de Componente Projetada (Líquida) (m2) | EI-REV-Chapisco (externo) 1, Área de Componente Projetada (Bruta) (m2) | EI-REV-Chapisco (externo) 1, Volume Componente (Líquido) (m3) | EI-REV-Chapisco (externo) 1, Volume do componente (Bruto) (m3) | TIJOLO - CERAMICO 9x19x39 - espessura 15cm, Massa (kg) | TIJOLO - CERAMICO 9x19x39 - espessura 15cm, Área de Componente Projetada (Líquida) (m2) | TIJOLO - CERAMICO 9x19x39 - espessura 15cm, Área de Componente Projetada (Bruta) (m2) | TIJOLO - CERAMICO 9x19x39 - espessura 15cm, Volume Componente (Líquido) (m3) | TIJOLO - CERAMICO 9x19x39 - espessura 15cm, Volume do componente (Bruto) (m3) | EI-REV-Chapisco (externo) 2, Massa (kg) | EI-REV-Chapisco (externo) 2, Área de Componente Projetada (Líquida) (m2) | EI-REV-Chapisco (externo) 2, Área de Componente Projetada (Bruta) (m2) | EI-REV-Chapisco (externo) 2, Espessura do Componente (m) = EI-REV-Chapisco (externo) 2, Largura do Componente Retangular (m) = EI-REV-Massa única - Fachada 2, Espessura do Componente (m) = EI-REV-Massa única - Fachada 2, Largura do Componente Retangular (m) = EI-REV-Massa Acrílica (externa) 2, Espessura do Componente (m) = EI-REV-Massa Acrílica (externa) 2, Largura do Componente Retangular (m) | EI-REV-Chapisco (externo) 2, Altura do Componente Retangular (m) = EI-REV-Massa única - Fachada 2, Altura do Componente Retangular (m) = EI-REV-Massa Acrílica (externa) 2, Altura do Componente Retangular (m) | EI-REV-Chapisco (externo) 2, Área de Seção Transversal do Componente (m2) = EI-REV-Massa única - Fachada 2, Área de Seção Transversal do Componente (m2) = EI-REV-Massa Acrílica (externa) 2, Área de Seção Transversal do Componente (m2) | EI-REV-Chapisco (externo) 2, Volume Componente (Líquido) (m3) | EI-REV-Chapisco (externo) 2, Volume do componente (Bruto) (m3) | EI-REV-Massa única - Fachada 2, Massa (kg) | EI-REV-Massa única - Fachada 2, Área de Componente Projetada (Líquida) (m2) | EI-REV-Massa única - Fachada 2, Área de Componente Projetada (Bruta) (m2) | EI-REV-Massa única - Fachada 2, Volume Componente (Líquido) (m3) | EI-REV-Massa única - Fachada 2, Volume do componente (Bruto) (m3) | EI-REV-Massa Acrílica (externa) 2, Massa (kg) | EI-REV-Massa Acrílica (externa) 2, Área de Componente Projetada (Líquida) (m2) | EI-REV-Massa Acrílica (externa) 2, Área de Componente Projetada (Bruta) (m2) | EI-REV-Massa Acrílica (externa) 2, Volume Componente (Líquido) (m3) | EI-REV-Massa Acrílica (externa) 2, Volume do componente (Bruto) (m3) | EI-REV-Pintura Acrílica Cor Cinza 2, Massa (kg) | EI-REV-Pintura Acrílica Cor Cinza 2, Área de Componente Projetada (Líquida) (m2) | EI-REV-Pintura Acrílica Cor Cinza 2, Área de Componente Projetada (Bruta) (m2) | EI-REV-Pintura Acrílica Cor Cinza 2, Volume Componente (Líquido) (m3) | EI-REV-Pintura Acrílica Cor Cinza 2, Volume do componente (Bruto) (m3)
AL09 | 63.5718 | 3.48681 | 3.48681 | 0.0489014 | 0.0489014 | 18.0628 | 2.77889 | 2.77889 | 0.0138944 | 0.0138944 | 17.9984 | 2.76899 | 2.76899 | 0.0138449 | 0.0138449 | 17.9341 | 2.75909 | 2.75909 | 0.0137954 | 0.0137954 | 162.705 | 2.78987 | 2.78987 | 0.251088 | 0.251088 | 17.907 | 2.75493 | 2.75493 | 0.005 | 2.12 | 0.0106 | 0.0137746 | 0.0137746 | 17.9181 | 3.44891 | 3.44891 | 0.0137832 | 0.0137832 | 21.1583 | 3.25342 | 3.25342 | 0.0162756 | 0.0162756 | 62.9541 | 3.22842 | 3.22842 | 0.0484262 | 0.0484262
AL09 | 27.7678 | 1.42399 | 5.29989 | 0.0213599 | 0.0794984 | 9.17341 | 1.41129 | 5.28719 | 0.00705647 | 0.026436 | 9.04471 | 1.39149 | 5.26739 | 0.00695747 | 0.026337 | 6.61261 | 1.37169 | 5.24759 | 0.00508663 | 0.0244661 | 47.3428 | 0.811776 | 4.68768 | 0.0730598 | 0.421891 | 4.94436 | 0.76067 | 4.63657 | 0.005 | 2.12 | 0.0106 | 0.00380335 | 0.0231829 | 4.9442 | 0.760647 | 4.63655 | 0.00380323 | 0.0231827 | 4.88245 | 0.751147 | 4.62705 | 0.00375573 | 0.0231352 | 14.0916 | 0.722647 | 4.59855 | 0.0108397 | 0.0689782
AL09 | 58.3297 | 2.99126 | 3.47126 | 0.044869 | 0.052069 | 14.89 | 2.99898 | 3.47898 | 0.0114538 | 0.0138538 | 14.8141 | 2.27909 | 2.75909 | 0.0113954 | 0.0137954 | 14.787 | 2.27493 | 2.75493 | 0.0113746 | 0.0137746 | 134.607 | 2.30807 | 2.78807 | 0.207726 | 0.250926 |  |  |  |  |  |  |  |  |  |  |  |  |  |  |  |  |  |  | 51.0983 | 2.62085 | 3.10085 | 0.0393064 | 0.0465064 | Component Quantities - EI-REV-Chapisco (externo) 1: 4 with these values

# IfcWall: FNDE-AL09-I1 (branco) 120 x 3100 (3)
In: TÉRREO
Classification: Parede (Classificação Archicad); Material: TIJOLO - CERAMICO 9x19x39 - espessura 15cm, EI-REV-Chapisco (interno), EI-REV-Massa única - Maior que 10m², EI-REV-Massa Corrida PVA (interna), EI-REV-Pintura Acrílica Cor Branco Gelo - Interna
FNDE - Alvenarias: Alvenaria de Vedação / Edificação; Sistemas de Cobertura: -; Esquadrias - Fechamentos metálicos e Gradis: -; 1_Bloco: BLOCO A; 0_ID: AL09
Pset_WallCommon - LoadBearing: no
Component Quantities - TIJOLO - CERAMICO 9x19x39 - espessura 15cm, Altura do Componente Retangular: 3.1 m; TIJOLO - CERAMICO 9x19x39 - espessura 15cm, Largura do Componente Retangular: 0.09 m; TIJOLO - CERAMICO 9x19x39 - espessura 15cm, Área de Seção Transversal do Componente: 0.279 m2; EI-REV-Chapisco (interno), Altura do Componente Retangular: 3.1 m; EI-REV-Chapisco (interno), Largura do Componente Retangular: 0.005 m; EI-REV-Chapisco (interno), Área de Seção Transversal do Componente: 0.0155 m2; EI-REV-Massa única - Maior que 10m², Altura do Componente Retangular: 3.06 m; EI-REV-Massa única - Maior que 10m², Largura do Componente Retangular: 0.01 m; EI-REV-Massa única - Maior que 10m², Área de Seção Transversal do Componente: 0.0306 m2; EI-REV-Massa Corrida PVA (interna), Altura do Componente Retangular: 3.06 m; EI-REV-Massa Corrida PVA (interna), Largura do Componente Retangular: 0.005 m; EI-REV-Massa Corrida PVA (interna), Área de Seção Transversal do Componente: 0.0153 m2; EI-REV-Pintura Acrílica Cor Branco Gelo - Interna, Altura do Componente Retangular: 3.06 m; EI-REV-Pintura Acrílica Cor Branco Gelo - Interna, Largura do Componente Retangular: 0.01 m; EI-REV-Pintura Acrílica Cor Branco Gelo - Interna, Área de Seção Transversal do Componente: 0.0306 m2
Name | IsExternal | TIJOLO - CERAMICO 9x19x39 - espessura 15cm, Massa (kg) | TIJOLO - CERAMICO 9x19x39 - espessura 15cm, Área de Componente Projetada (Líquida) (m2) = TIJOLO - CERAMICO 9x19x39 - espessura 15cm, Área de Componente Projetada (Bruta) (m2) | TIJOLO - CERAMICO 9x19x39 - espessura 15cm, Volume Componente (Líquido) (m3) = TIJOLO - CERAMICO 9x19x39 - espessura 15cm, Volume do componente (Bruto) (m3) | EI-REV-Chapisco (interno), Massa (kg) | EI-REV-Chapisco (interno), Área de Componente Projetada (Líquida) (m2) = EI-REV-Chapisco (interno), Área de Componente Projetada (Bruta) (m2) | EI-REV-Chapisco (interno), Volume Componente (Líquido) (m3) = EI-REV-Chapisco (interno), Volume do componente (Bruto) (m3) | EI-REV-Massa única - Maior que 10m², Massa (kg) | EI-REV-Massa única - Maior que 10m², Área de Componente Projetada (Líquida) (m2) = EI-REV-Massa única - Maior que 10m², Área de Componente Projetada (Bruta) (m2) | EI-REV-Massa única - Maior que 10m², Volume Componente (Líquido) (m3) = EI-REV-Massa única - Maior que 10m², Volume do componente (Bruto) (m3) | EI-REV-Massa Corrida PVA (interna), Massa (kg) | EI-REV-Massa Corrida PVA (interna), Área de Componente Projetada (Líquida) (m2) = EI-REV-Massa Corrida PVA (interna), Área de Componente Projetada (Bruta) (m2) | EI-REV-Massa Corrida PVA (interna), Volume Componente (Líquido) (m3) = EI-REV-Massa Corrida PVA (interna), Volume do componente (Bruto) (m3) | EI-REV-Pintura Acrílica Cor Branco Gelo - Interna, Massa (kg) | EI-REV-Pintura Acrílica Cor Branco Gelo - Interna, Área de Componente Projetada (Líquida) (m2) = EI-REV-Pintura Acrílica Cor Branco Gelo - Interna, Área de Componente Projetada (Bruta) (m2) | EI-REV-Pintura Acrílica Cor Branco Gelo - Interna, Volume Componente (Líquido) (m3) = EI-REV-Pintura Acrílica Cor Branco Gelo - Interna, Volume do componente (Bruto) (m3)
AL09 | yes | 120.453 | 2.06538 | 0.185884 | 13.2443 | 2.03758 | 0.0101879 | 29.8156 | 2.5511 | 0.0229351 | 16.4093 | 2.5245 | 0.0126225 | 33.8861 | 2.75198 | 0.0260662
AL09 | yes | 230.716 | 3.95604 | 0.356044 | 25.7143 | 3.95604 | 0.0197802 | 50.6667 | 3.89743 | 0.0389744 | 26.6998 | 4.10963 | 0.0205383 | 53.2523 | 4.09633 | 0.0409633
AL09 | no | 84.4338 | 1.44777 | 0.130299 | 6.90756 | 1.0627 | 0.00531351 | 13.4446 | 1.0342 | 0.010342 | 6.54938 | 1.0076 | 0.00503798 | 13.6206 | 1.10211 | 0.0104774

# IfcWall: FNDE-AL09-I1 120, AL09
In: TÉRREO
Classification: Parede (Classificação Archicad); Material: EI-REV-Pintura Acrílica Cor Branco Gelo - Interna 0.01 m, EI-REV-Massa Corrida PVA (interna) 0.005 m, EI-REV-Massa única - Maior que 10m² 0.01 m, EI-REV-Chapisco (interno) 0.005 m, TIJOLO - CERAMICO 9x19x39 - espessura 15cm 0.09 m
FNDE - Alvenarias: Alvenaria de Vedação / Edificação; Sistemas de Cobertura: -; Esquadrias - Fechamentos metálicos e Gradis: -; 1_Bloco: BLOCO B; 0_ID: AL09
Pset_WallCommon - IsExternal: no; LoadBearing: no
Component Quantities - EI-REV-Pintura Acrílica Cor Branco Gelo - Interna, Massa: 31.3475 kg; EI-REV-Pintura Acrílica Cor Branco Gelo - Interna, Área de Componente Projetada (Líquida): 2.41135 m2; EI-REV-Pintura Acrílica Cor Branco Gelo - Interna, Área de Componente Projetada (Bruta): 2.41135 m2; EI-REV-Pintura Acrílica Cor Branco Gelo - Interna, Espessura do Componente: 0.01 m; EI-REV-Pintura Acrílica Cor Branco Gelo - Interna, Altura do Componente Retangular: 3.1 m; EI-REV-Pintura Acrílica Cor Branco Gelo - Interna, Largura do Componente Retangular: 0.01 m; EI-REV-Pintura Acrílica Cor Branco Gelo - Interna, Área de Seção Transversal do Componente: 0.031 m2; EI-REV-Pintura Acrílica Cor Branco Gelo - Interna, Volume Componente (Líquido): 0.0241135 m3; EI-REV-Pintura Acrílica Cor Branco Gelo - Interna, Volume do componente (Bruto): 0.0241135 m3; EI-REV-Massa Corrida PVA (interna), Massa: 15.7384 kg; EI-REV-Massa Corrida PVA (interna), Área de Componente Projetada (Líquida): 2.42129 m2; EI-REV-Massa Corrida PVA (interna), Área de Componente Projetada (Bruta): 2.42129 m2; EI-REV-Massa Corrida PVA (interna), Espessura do Componente: 0.005 m; EI-REV-Massa Corrida PVA (interna), Altura do Componente Retangular: 3.1 m; EI-REV-Massa Corrida PVA (interna), Largura do Componente Retangular: 0.005 m; EI-REV-Massa Corrida PVA (interna), Área de Seção Transversal do Componente: 0.0155 m2; EI-REV-Massa Corrida PVA (interna), Volume Componente (Líquido): 0.0121065 m3; EI-REV-Massa Corrida PVA (interna), Volume do componente (Bruto): 0.0121065 m3; EI-REV-Massa única - Maior que 10m², Massa: 32.2204 kg; EI-REV-Massa única - Maior que 10m², Área de Componente Projetada (Líquida): 2.47849 m2; EI-REV-Massa única - Maior que 10m², Área de Componente Projetada (Bruta): 2.47849 m2; EI-REV-Massa única - Maior que 10m², Espessura do Componente: 0.01 m; EI-REV-Massa única - Maior que 10m², Altura do Componente Retangular: 3.1 m; EI-REV-Massa única - Maior que 10m², Largura do Componente Retangular: 0.01 m; EI-REV-Massa única - Maior que 10m², Área de Seção Transversal do Componente: 0.031 m2; EI-REV-Massa única - Maior que 10m², Volume Componente (Líquido): 0.0247849 m3; EI-REV-Massa única - Maior que 10m², Volume do componente (Bruto): 0.0247849 m3; EI-REV-Chapisco (interno), Massa: 16.2948 kg; EI-REV-Chapisco (interno), Área de Componente Projetada (Líquida): 2.50689 m2; EI-REV-Chapisco (interno), Área de Componente Projetada (Bruta): 2.50689 m2; EI-REV-Chapisco (interno), Espessura do Componente: 0.005 m; EI-REV-Chapisco (interno), Altura do Componente Retangular: 3.1 m; EI-REV-Chapisco (interno), Largura do Componente Retangular: 0.005 m; EI-REV-Chapisco (interno), Área de Seção Transversal do Componente: 0.0155 m2; EI-REV-Chapisco (interno), Volume Componente (Líquido): 0.0125345 m3; EI-REV-Chapisco (interno), Volume do componente (Bruto): 0.0125345 m3; TIJOLO - CERAMICO 9x19x39 - espessura 15cm, Massa: 184.506 kg; TIJOLO - CERAMICO 9x19x39 - espessura 15cm, Área de Componente Projetada (Líquida): 3.16369 m2; TIJOLO - CERAMICO 9x19x39 - espessura 15cm, Área de Componente Projetada (Bruta): 3.16369 m2; TIJOLO - CERAMICO 9x19x39 - espessura 15cm, Espessura do Componente: 0.09 m; TIJOLO - CERAMICO 9x19x39 - espessura 15cm, Altura do Componente Retangular: 3.1 m; TIJOLO - CERAMICO 9x19x39 - espessura 15cm, Largura do Componente Retangular: 0.09 m; TIJOLO - CERAMICO 9x19x39 - espessura 15cm, Área de Seção Transversal do Componente: 0.279 m2; TIJOLO - CERAMICO 9x19x39 - espessura 15cm, Volume Componente (Líquido): 0.284732 m3; TIJOLO - CERAMICO 9x19x39 - espessura 15cm, Volume do componente (Bruto): 0.284732 m3

# IfcWall: FNDE-AL09-I1-I1 150, AL09
In: TÉRREO
Classification: Parede (Classificação Archicad); Material: EI-REV-Pintura Acrílica Cor Branco Gelo - Interna 0.01 m, EI-REV-Massa Corrida PVA (interna) 0.005 m, EI-REV-Massa única - Maior que 10m² 0.01 m, EI-REV-Chapisco (interno) 0.005 m, TIJOLO - CERAMICO 9x19x39 - espessura 15cm 0.09 m, EI-REV-Chapisco (interno) 0.005 m, EI-REV-Massa única - Maior que 10m² 0.01 m, EI-REV-Massa Corrida PVA (interna) 0.005 m, EI-REV-Pintura Acrílica Cor Branco Gelo - Interna 0.01 m
FNDE - Alvenarias: Alvenaria de Vedação / Edificação; Sistemas de Cobertura: -; Esquadrias - Fechamentos metálicos e Gradis: -; 1_Bloco: BLOCO A; 0_ID: AL09
Pset_WallCommon - IsExternal: no; LoadBearing: no
Component Quantities - EI-REV-Pintura Acrílica Cor Branco Gelo - Interna 1, Massa: 218.909 kg; EI-REV-Pintura Acrílica Cor Branco Gelo - Interna 1, Área de Componente Projetada (Líquida): 18.6589 m2; EI-REV-Pintura Acrílica Cor Branco Gelo - Interna 1, Área de Componente Projetada (Bruta): 18.6589 m2; EI-REV-Pintura Acrílica Cor Branco Gelo - Interna 1, Espessura do Componente: 0.01 m; EI-REV-Pintura Acrílica Cor Branco Gelo - Interna 1, Altura do Componente Retangular: 3.1 m; EI-REV-Pintura Acrílica Cor Branco Gelo - Interna 1, Largura do Componente Retangular: 0.01 m; EI-REV-Pintura Acrílica Cor Branco Gelo - Interna 1, Área de Seção Transversal do Componente: 0.031 m2; EI-REV-Pintura Acrílica Cor Branco Gelo - Interna 1, Volume Componente (Líquido): 0.168392 m3; EI-REV-Pintura Acrílica Cor Branco Gelo - Interna 1, Volume do componente (Bruto): 0.168392 m3; EI-REV-Massa Corrida PVA (interna) 1, Massa: 97.4025 kg; EI-REV-Massa Corrida PVA (interna) 1, Área de Componente Projetada (Líquida): 14.985 m2; EI-REV-Massa Corrida PVA (interna) 1, Área de Componente Projetada (Bruta): 14.985 m2; EI-REV-Massa Corrida PVA (interna) 1, Espessura do Componente: 0.005 m; EI-REV-Massa Corrida PVA (interna) 1, Altura do Componente Retangular: 3.1 m; EI-REV-Massa Corrida PVA (interna) 1, Largura do Componente Retangular: 0.005 m; EI-REV-Massa Corrida PVA (interna) 1, Área de Seção Transversal do Componente: 0.0155 m2; EI-REV-Massa Corrida PVA (interna) 1, Volume Componente (Líquido): 0.074925 m3; EI-REV-Massa Corrida PVA (interna) 1, Volume do componente (Bruto): 0.074925 m3; EI-REV-Massa única - Maior que 10m² 1, Massa: 194.805 kg; EI-REV-Massa única - Maior que 10m² 1, Área de Componente Projetada (Líquida): 14.985 m2; EI-REV-Massa única - Maior que 10m² 1, Área de Componente Projetada (Bruta): 14.985 m2; EI-REV-Massa única - Maior que 10m² 1, Espessura do Componente: 0.01 m; EI-REV-Massa única - Maior que 10m² 1, Altura do Componente Retangular: 3.1 m; EI-REV-Massa única - Maior que 10m² 1, Largura do Componente Retangular: 0.01 m; EI-REV-Massa única - Maior que 10m² 1, Área de Seção Transversal do Componente: 0.031 m2; EI-REV-Massa única - Maior que 10m² 1, Volume Componente (Líquido): 0.14985 m3; EI-REV-Massa única - Maior que 10m² 1, Volume do componente (Bruto): 0.14985 m3; TIJOLO - CERAMICO 9x19x39 - espessura 15cm, Massa: 873.925 kg; TIJOLO - CERAMICO 9x19x39 - espessura 15cm, Área de Componente Projetada (Líquida): 14.985 m2; TIJOLO - CERAMICO 9x19x39 - espessura 15cm, Área de Componente Projetada (Bruta): 14.985 m2; TIJOLO - CERAMICO 9x19x39 - espessura 15cm, Espessura do Componente: 0.09 m; TIJOLO - CERAMICO 9x19x39 - espessura 15cm, Altura do Componente Retangular: 3.1 m; TIJOLO - CERAMICO 9x19x39 - espessura 15cm, Largura do Componente Retangular: 0.09 m; TIJOLO - CERAMICO 9x19x39 - espessura 15cm, Área de Seção Transversal do Componente: 0.279 m2; TIJOLO - CERAMICO 9x19x39 - espessura 15cm, Volume Componente (Líquido): 1.34865 m3; TIJOLO - CERAMICO 9x19x39 - espessura 15cm, Volume do componente (Bruto): 1.34865 m3; EI-REV-Pintura Acrílica Cor Branco Gelo - Interna 2, Massa: 218.202 kg; EI-REV-Pintura Acrílica Cor Branco Gelo - Interna 2, Área de Componente Projetada (Líquida): 18.6299 m2; EI-REV-Pintura Acrílica Cor Branco Gelo - Interna 2, Área de Componente Projetada (Bruta): 18.6299 m2; EI-REV-Pintura Acrílica Cor Branco Gelo - Interna 2, Espessura do Componente: 0.01 m; EI-REV-Pintura Acrílica Cor Branco Gelo - Interna 2, Altura do Componente Retangular: 3.1 m; EI-REV-Pintura Acrílica Cor Branco Gelo - Interna 2, Largura do Componente Retangular: 0.01 m; EI-REV-Pintura Acrílica Cor Branco Gelo - Interna 2, Área de Seção Transversal do Componente: 0.031 m2; EI-REV-Pintura Acrílica Cor Branco Gelo - Interna 2, Volume Componente (Líquido): 0.167848 m3; EI-REV-Pintura Acrílica Cor Branco Gelo - Interna 2, Volume do componente (Bruto): 0.167848 m3; EI-REV-Massa Corrida PVA (interna) 1: 4 with these values; EI-REV-Massa única - Maior que 10m² 1: 2 with these values

# IfcWall: FNDE-AL09-I1-I2 (branco-laranja) 150 x 3100 (3)
In: TÉRREO
Classification: Parede (Classificação Archicad); Material: EI-REV-Chapisco (interno) (2), EI-REV-Massa única - Maior que 10m² (2), EI-REV-Massa Corrida PVA (interna) (2), EI-REV-Pintura Acrílica Cor Branco Gelo - Interna, EI-REV-Pintura Epóxi cor Laranja, EI-REV-Pintura Acrílica Cor Branco Gelo, TIJOLO - CERAMICO 9x19x39 - espessura 15cm
FNDE - Alvenarias: Alvenaria de Vedação / Edificação; Sistemas de Cobertura: -; Esquadrias - Fechamentos metálicos e Gradis: -; 0_ID: AL09
Pset_WallCommon - IsExternal: no; LoadBearing: no
Component Quantities - EI-REV-Chapisco (interno) 1, Altura do Componente Retangular: 3.1 m; EI-REV-Chapisco (interno) 1, Largura do Componente Retangular: 0.005 m; EI-REV-Chapisco (interno) 1, Área de Seção Transversal do Componente: 0.0155 m2; EI-REV-Massa única - Maior que 10m² 1, Altura do Componente Retangular: 3.06 m; EI-REV-Massa única - Maior que 10m² 1, Largura do Componente Retangular: 0.01 m; EI-REV-Massa única - Maior que 10m² 1, Área de Seção Transversal do Componente: 0.0306 m2; EI-REV-Massa Corrida PVA (interna) 1, Altura do Componente Retangular: 3.06 m; EI-REV-Massa Corrida PVA (interna) 1, Largura do Componente Retangular: 0.005 m; EI-REV-Massa Corrida PVA (interna) 1, Área de Seção Transversal do Componente: 0.0153 m2; EI-REV-Pintura Epóxi cor Laranja, Altura do Componente Retangular: 0.9 m; EI-REV-Pintura Epóxi cor Laranja, Largura do Componente Retangular: 0.02 m; EI-REV-Pintura Epóxi cor Laranja, Área de Seção Transversal do Componente: 0.018 m2; EI-REV-Massa Corrida PVA (interna) 2, Altura do Componente Retangular: 2.16 m; EI-REV-Massa Corrida PVA (interna) 2, Largura do Componente Retangular: 0.005 m; EI-REV-Massa Corrida PVA (interna) 2, Área de Seção Transversal do Componente: 0.0108 m2; EI-REV-Pintura Acrílica Cor Branco Gelo, Altura do Componente Retangular: 2.16 m; EI-REV-Pintura Acrílica Cor Branco Gelo, Largura do Componente Retangular: 0.015 m; EI-REV-Pintura Acrílica Cor Branco Gelo, Área de Seção Transversal do Componente: 0.0324 m2; TIJOLO - CERAMICO 9x19x39 - espessura 15cm, Altura do Componente Retangular: 3.1 m; TIJOLO - CERAMICO 9x19x39 - espessura 15cm, Largura do Componente Retangular: 0.09 m; TIJOLO - CERAMICO 9x19x39 - espessura 15cm, Área de Seção Transversal do Componente: 0.279 m2
Name | 1_Bloco | EI-REV-Chapisco (interno) 1, Massa (kg) | EI-REV-Chapisco (interno) 1, Área de Componente Projetada (Líquida) (m2) = EI-REV-Chapisco (interno) 1, Área de Componente Projetada (Bruta) (m2) | EI-REV-Chapisco (interno) 1, Volume Componente (Líquido) (m3) = EI-REV-Chapisco (interno) 1, Volume do componente (Bruto) (m3) | EI-REV-Massa única - Maior que 10m² 1, Massa (kg) | EI-REV-Massa única - Maior que 10m² 1, Área de Componente Projetada (Líquida) (m2) = EI-REV-Massa única - Maior que 10m² 1, Área de Componente Projetada (Bruta) (m2) | EI-REV-Massa única - Maior que 10m² 1, Volume Componente (Líquido) (m3) = EI-REV-Massa única - Maior que 10m² 1, Volume do componente (Bruto) (m3) | EI-REV-Massa Corrida PVA (interna) 1, Massa (kg) | EI-REV-Massa Corrida PVA (interna) 1, Área de Componente Projetada (Líquida) (m2) = EI-REV-Massa Corrida PVA (interna) 1, Área de Componente Projetada (Bruta) (m2) | EI-REV-Massa Corrida PVA (interna) 1, Volume Componente (Líquido) (m3) = EI-REV-Massa Corrida PVA (interna) 1, Volume do componente (Bruto) (m3) | EI-REV-Pintura Acrílica Cor Branco Gelo - Interna, Massa (kg) | EI-REV-Pintura Acrílica Cor Branco Gelo - Interna, Área de Componente Projetada (Líquida) (m2) = EI-REV-Pintura Acrílica Cor Branco Gelo - Interna, Área de Componente Projetada (Bruta) (m2) | EI-REV-Pintura Acrílica Cor Branco Gelo - Interna, Altura do Componente Retangular (m) | EI-REV-Pintura Acrílica Cor Branco Gelo - Interna, Largura do Componente Retangular (m) | EI-REV-Pintura Acrílica Cor Branco Gelo - Interna, Área de Seção Transversal do Componente (m2) | EI-REV-Pintura Acrílica Cor Branco Gelo - Interna, Volume Componente (Líquido) (m3) = EI-REV-Pintura Acrílica Cor Branco Gelo - Interna, Volume do componente (Bruto) (m3) | EI-REV-Chapisco (interno) 2, Massa (kg) | EI-REV-Chapisco (interno) 2, Área de Componente Projetada (Líquida) (m2) = EI-REV-Chapisco (interno) 2, Área de Componente Projetada (Bruta) (m2) | EI-REV-Chapisco (interno) 2, Altura do Componente Retangular (m) = EI-REV-Massa única - Maior que 10m² 2, Altura do Componente Retangular (m) | EI-REV-Chapisco (interno) 2, Largura do Componente Retangular (m) = EI-REV-Massa única - Maior que 10m² 2, Largura do Componente Retangular (m) | EI-REV-Chapisco (interno) 2, Área de Seção Transversal do Componente (m2) = EI-REV-Massa única - Maior que 10m² 2, Área de Seção Transversal do Componente (m2) | EI-REV-Chapisco (interno) 2, Volume Componente (Líquido) (m3) = EI-REV-Chapisco (interno) 2, Volume do componente (Bruto) (m3) | EI-REV-Pintura Epóxi cor Laranja, Massa (kg) | EI-REV-Pintura Epóxi cor Laranja, Área de Componente Projetada (Líquida) (m2) = EI-REV-Pintura Epóxi cor Laranja, Área de Componente Projetada (Bruta) (m2) | EI-REV-Pintura Epóxi cor Laranja, Volume Componente (Líquido) (m3) = EI-REV-Pintura Epóxi cor Laranja, Volume do componente (Bruto) (m3) | EI-REV-Massa única - Maior que 10m² 2, Massa (kg) | EI-REV-Massa única - Maior que 10m² 2, Área de Componente Projetada (Líquida) (m2) = EI-REV-Massa única - Maior que 10m² 2, Área de Componente Projetada (Bruta) (m2) | EI-REV-Massa única - Maior que 10m² 2, Volume Componente (Líquido) (m3) = EI-REV-Massa única - Maior que 10m² 2, Volume do componente (Bruto) (m3) | EI-REV-Massa Corrida PVA (interna) 2, Massa (kg) | EI-REV-Massa Corrida PVA (interna) 2, Área de Componente Projetada (Líquida) (m2) = EI-REV-Massa Corrida PVA (interna) 2, Área de Componente Projetada (Bruta) (m2) | EI-REV-Massa Corrida PVA (interna) 2, Volume Componente (Líquido) (m3) = EI-REV-Massa Corrida PVA (interna) 2, Volume do componente (Bruto) (m3) | EI-REV-Pintura Acrílica Cor Branco Gelo, Massa (kg) | EI-REV-Pintura Acrílica Cor Branco Gelo, Área de Componente Projetada (Líquida) (m2) = EI-REV-Pintura Acrílica Cor Branco Gelo, Área de Componente Projetada (Bruta) (m2) | EI-REV-Pintura Acrílica Cor Branco Gelo, Volume Componente (Líquido) (m3) = EI-REV-Pintura Acrílica Cor Branco Gelo, Volume do componente (Bruto) (m3) | TIJOLO - CERAMICO 9x19x39 - espessura 15cm, Massa (kg) | TIJOLO - CERAMICO 9x19x39 - espessura 15cm, Área de Componente Projetada (Líquida) (m2) = TIJOLO - CERAMICO 9x19x39 - espessura 15cm, Área de Componente Projetada (Bruta) (m2) | TIJOLO - CERAMICO 9x19x39 - espessura 15cm, Volume Componente (Líquido) (m3) = TIJOLO - CERAMICO 9x19x39 - espessura 15cm, Volume do componente (Bruto) (m3)
AL09 | BLOCO B | 51.9468 | 7.99182 | 0.0399591 | 102.009 | 7.84682 | 0.0784683 | 50.9179 | 7.83352 | 0.0391676 | 106.479 | 9.1798 | 3.06 | 0.01 | 0.0306 | 0.0819073 | 51.9273 | 7.98882 | 3.1 | 0.005 | 0.0155 | 0.0399441 | 69.2253 | 2.69994 | 0.0532503 | 51.7835 | 7.96672 | 0.0398334 | 33.69 | 5.18308 | 0.0259154 | 113.037 | 6.47986 | 0.0869514 | 466.865 | 8.00523 | 0.720471
AL09 | BLOCO A | 53.1342 | 8.17449 | 0.0408725 | 104.348 | 8.02679 | 0.080268 | 52.0877 | 8.01349 | 0.0400675 | 111.499 | 9.17273 | 3.06 | 0.01 | 0.0306 | 0.0857686 | 53.1747 | 8.1807 | 3.1 | 0.005 | 0.0155 | 0.0409036 | 70.1447 | 2.69786 | 0.0539575 | 53.0316 | 8.1586 | 0.0407935 | 34.4647 | 5.30216 | 0.0265113 | 110.626 | 6.47487 | 0.0850966 | 477.524 | 8.18799 | 0.73692
AL09 | BLOCO A | 0 | 0 | 0 | 0 | 0 | 0 | 0 | 0 | 0 |  |  |  |  |  |  |  |  |  |  |  |  | 0 | 0 | 0 |  |  |  | 0 | 0 | 0 | 0 | 0 | 0 | 37.0041 | 0.6345 | 0.057105 | Component Quantities - EI-REV-Chapisco (interno) 1: 3 with these values; EI-REV-Massa única - Maior que 10m² 1: 2 with these values

# IfcWall: FNDE-AL09-I1-I5 (branco-vermelho) 150 x 3100, AL09
In: TÉRREO
Classification: Parede (Classificação Archicad); Material: TIJOLO - CERAMICO 9x19x39 - espessura 15cm, EI-REV-Chapisco (interno) (2), EI-REV-Cerâmica 30x40, EI-REV-Cerâmica 10x10 Vermelha, EI-REV-Emboço Interno, EI-REV-Massa única - Maior que 10m² (2), EI-REV-Massa Corrida PVA (interna) (2), EI-REV-Pintura Acrílica Cor Branco Gelo, EI-REV-Pintura Acrílica Cor Branco Gelo - Interna
FNDE - Alvenarias: Alvenaria de Vedação / Edificação; Sistemas de Cobertura: -; Esquadrias - Fechamentos metálicos e Gradis: -; 1_Bloco: BLOCO A; 0_ID: AL09
Pset_WallCommon - IsExternal: no; LoadBearing: no
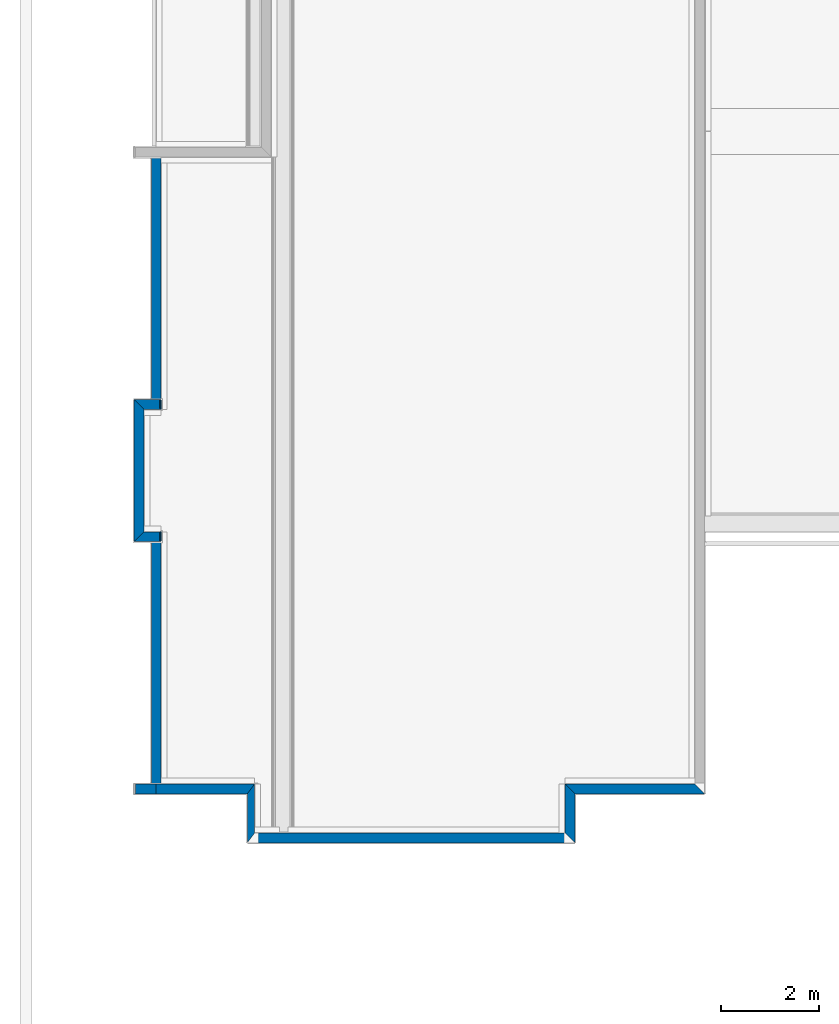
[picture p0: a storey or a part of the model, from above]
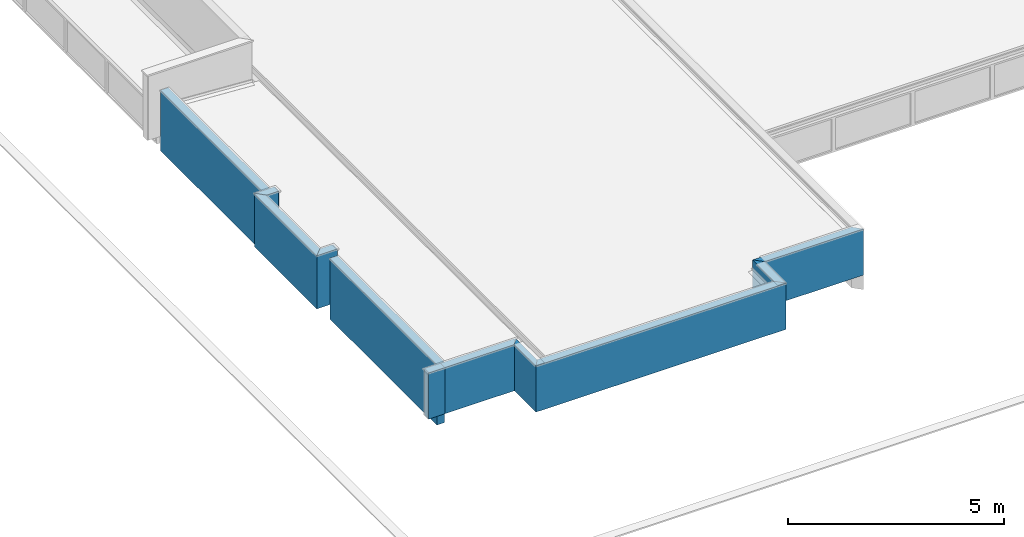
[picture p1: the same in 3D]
Properties of the parts of a building model (IFC4), part 10 of 22

# IfcWall: FNDE-AL09-I1-I5 (branco-vermelho) 150 x 3100, AL09
Component Quantities - TIJOLO - CERAMICO 9x19x39 - espessura 15cm, Massa: 693.629 kg; TIJOLO - CERAMICO 9x19x39 - espessura 15cm, Área de Componente Projetada (Líquida): 11.8935 m2; TIJOLO - CERAMICO 9x19x39 - espessura 15cm, Área de Componente Projetada (Bruta): 11.8935 m2; TIJOLO - CERAMICO 9x19x39 - espessura 15cm, Altura do Componente Retangular: 3.1 m; TIJOLO - CERAMICO 9x19x39 - espessura 15cm, Largura do Componente Retangular: 0.09 m; TIJOLO - CERAMICO 9x19x39 - espessura 15cm, Área de Seção Transversal do Componente: 0.279 m2; TIJOLO - CERAMICO 9x19x39 - espessura 15cm, Volume Componente (Líquido): 1.07041 m3; TIJOLO - CERAMICO 9x19x39 - espessura 15cm, Volume do componente (Bruto): 1.07041 m3; EI-REV-Chapisco (interno) 1, Massa: 75.9194 kg; EI-REV-Chapisco (interno) 1, Área de Componente Projetada (Líquida): 11.6799 m2; EI-REV-Chapisco (interno) 1, Área de Componente Projetada (Bruta): 11.6799 m2; EI-REV-Chapisco (interno) 1, Altura do Componente Retangular: 3.1 m; EI-REV-Chapisco (interno) 1, Largura do Componente Retangular: 0.005 m; EI-REV-Chapisco (interno) 1, Área de Seção Transversal do Componente: 0.0155 m2; EI-REV-Chapisco (interno) 1, Volume Componente (Líquido): 0.0583995 m3; EI-REV-Chapisco (interno) 1, Volume do componente (Bruto): 0.0583995 m3; EI-REV-Cerâmica 30x40, Massa: 309.874 kg; EI-REV-Cerâmica 30x40, Área de Componente Projetada (Líquida): 7.8417 m2; EI-REV-Cerâmica 30x40, Área de Componente Projetada (Bruta): 7.8417 m2; EI-REV-Cerâmica 30x40, Altura do Componente Retangular: 1.8 m; EI-REV-Cerâmica 30x40, Largura do Componente Retangular: 0.02 m; EI-REV-Cerâmica 30x40, Área de Seção Transversal do Componente: 0.036 m2; EI-REV-Cerâmica 30x40, Volume Componente (Líquido): 0.154937 m3; EI-REV-Cerâmica 30x40, Volume do componente (Bruto): 0.154937 m3; EI-REV-Cerâmica 10x10 Vermelha, Massa: 17.5892 kg; EI-REV-Cerâmica 10x10 Vermelha, Área de Componente Projetada (Líquida): 0.445 m2; EI-REV-Cerâmica 10x10 Vermelha, Área de Componente Projetada (Bruta): 0.445 m2; EI-REV-Cerâmica 10x10 Vermelha, Altura do Componente Retangular: 0.1 m; EI-REV-Cerâmica 10x10 Vermelha, Largura do Componente Retangular: 0.02 m; EI-REV-Cerâmica 10x10 Vermelha, Área de Seção Transversal do Componente: 0.002 m2; EI-REV-Cerâmica 10x10 Vermelha, Volume Componente (Líquido): 0.00879461 m3; EI-REV-Cerâmica 10x10 Vermelha, Volume do componente (Bruto): 0.00879461 m3; EI-REV-Emboço Interno, Massa: 75.82 kg; EI-REV-Emboço Interno, Área de Componente Projetada (Líquida): 11.6646 m2; EI-REV-Emboço Interno, Área de Componente Projetada (Bruta): 11.6646 m2; EI-REV-Emboço Interno, Altura do Componente Retangular: 3.1 m; EI-REV-Emboço Interno, Largura do Componente Retangular: 0.005 m; EI-REV-Emboço Interno, Área de Seção Transversal do Componente: 0.0155 m2; EI-REV-Emboço Interno, Volume Componente (Líquido): 0.058323 m3; EI-REV-Emboço Interno, Volume do componente (Bruto): 0.058323 m3; EI-REV-Massa única - Maior que 10m² 1, Massa: 21.9215 kg; EI-REV-Massa única - Maior que 10m² 1, Área de Componente Projetada (Líquida): 3.37256 m2; EI-REV-Massa única - Maior que 10m² 1, Área de Componente Projetada (Bruta): 3.37256 m2; EI-REV-Massa única - Maior que 10m² 1, Altura do Componente Retangular: 1.17 m; EI-REV-Massa única - Maior que 10m² 1, Largura do Componente Retangular: 0.005 m; EI-REV-Massa única - Maior que 10m² 1, Área de Seção Transversal do Componente: 0.00585001 m2; EI-REV-Massa única - Maior que 10m² 1, Volume Componente (Líquido): 0.0168627 m3; EI-REV-Massa única - Maior que 10m² 1, Volume do componente (Bruto): 0.0168627 m3; EI-REV-Massa Corrida PVA (interna) 1, Massa: 21.9217 kg; EI-REV-Massa Corrida PVA (interna) 1, Área de Componente Projetada (Líquida): 3.37256 m2; EI-REV-Massa Corrida PVA (interna) 1, Área de Componente Projetada (Bruta): 3.37256 m2; EI-REV-Massa Corrida PVA (interna) 1, Altura do Componente Retangular: 1.17 m; EI-REV-Massa Corrida PVA (interna) 1, Largura do Componente Retangular: 0.005 m; EI-REV-Massa Corrida PVA (interna) 1, Área de Seção Transversal do Componente: 0.00585001 m2; EI-REV-Massa Corrida PVA (interna) 1, Volume Componente (Líquido): 0.0168628 m3; EI-REV-Massa Corrida PVA (interna) 1, Volume do componente (Bruto): 0.0168628 m3; EI-REV-Pintura Acrílica Cor Branco Gelo, Massa: 57.5947 kg; EI-REV-Pintura Acrílica Cor Branco Gelo, Área de Componente Projetada (Líquida): 5.4873 m2; EI-REV-Pintura Acrílica Cor Branco Gelo, Área de Componente Projetada (Bruta): 5.4873 m2; EI-REV-Pintura Acrílica Cor Branco Gelo, Altura do Componente Retangular: 1.17 m; EI-REV-Pintura Acrílica Cor Branco Gelo, Largura do Componente Retangular: 0.00999999 m; EI-REV-Pintura Acrílica Cor Branco Gelo, Área de Seção Transversal do Componente: 0.0117 m2; EI-REV-Pintura Acrílica Cor Branco Gelo, Volume Componente (Líquido): 0.0443036 m3; EI-REV-Pintura Acrílica Cor Branco Gelo, Volume do componente (Bruto): 0.0443036 m3; EI-REV-Chapisco (interno) 2, Massa: 77.3077 kg; EI-REV-Chapisco (interno) 2, Área de Componente Projetada (Líquida): 11.8935 m2; EI-REV-Chapisco (interno) 2, Área de Componente Projetada (Bruta): 11.8935 m2; EI-REV-Chapisco (interno) 2, Altura do Componente Retangular: 3.1 m; EI-REV-Chapisco (interno) 2, Largura do Componente Retangular: 0.005 m; EI-REV-Chapisco (interno) 2, Área de Seção Transversal do Componente: 0.0155 m2; EI-REV-Chapisco (interno) 2, Volume Componente (Líquido): 0.0594675 m3; EI-REV-Chapisco (interno) 2, Volume do componente (Bruto): 0.0594675 m3; EI-REV-Massa única - Maior que 10m² 2, Massa: 152.325 kg; EI-REV-Massa única - Maior que 10m² 2, Área de Componente Projetada (Líquida): 11.7173 m2; EI-REV-Massa única - Maior que 10m² 2, Área de Componente Projetada (Bruta): 11.7173 m2; EI-REV-Massa única - Maior que 10m² 2, Altura do Componente Retangular: 3.06 m; EI-REV-Massa única - Maior que 10m² 2, Largura do Componente Retangular: 0.01 m; EI-REV-Massa única - Maior que 10m² 2, Área de Seção Transversal do Componente: 0.0306 m2; EI-REV-Massa única - Maior que 10m² 2, Volume Componente (Líquido): 0.117173 m3; EI-REV-Massa única - Maior que 10m² 2, Volume do componente (Bruto): 0.117173 m3; EI-REV-Massa Corrida PVA (interna) 2, Massa: 76.1626 kg; EI-REV-Massa Corrida PVA (interna) 2, Área de Componente Projetada (Líquida): 11.7173 m2; EI-REV-Massa Corrida PVA (interna) 2, Área de Componente Projetada (Bruta): 11.7173 m2; EI-REV-Massa Corrida PVA (interna) 2, Altura do Componente Retangular: 3.06 m; EI-REV-Massa Corrida PVA (interna) 2, Largura do Componente Retangular: 0.005 m; EI-REV-Massa Corrida PVA (interna) 2, Área de Seção Transversal do Componente: 0.0153 m2; EI-REV-Massa Corrida PVA (interna) 2, Volume Componente (Líquido): 0.0585866 m3; EI-REV-Massa Corrida PVA (interna) 2, Volume do componente (Bruto): 0.0585866 m3; EI-REV-Pintura Acrílica Cor Branco Gelo - Interna, Massa: 166.788 kg; EI-REV-Pintura Acrílica Cor Branco Gelo - Interna, Área de Componente Projetada (Líquida): 13.923 m2; EI-REV-Pintura Acrílica Cor Branco Gelo - Interna, Área de Componente Projetada (Bruta): 13.923 m2; EI-REV-Pintura Acrílica Cor Branco Gelo - Interna, Altura do Componente Retangular: 3.06 m; EI-REV-Pintura Acrílica Cor Branco Gelo - Interna, Largura do Componente Retangular: 0.01 m; EI-REV-Pintura Acrílica Cor Branco Gelo - Interna, Área de Seção Transversal do Componente: 0.0306 m2; EI-REV-Pintura Acrílica Cor Branco Gelo - Interna, Volume Componente (Líquido): 0.128298 m3; EI-REV-Pintura Acrílica Cor Branco Gelo - Interna, Volume do componente (Bruto): 0.128298 m3

# IfcWall: FNDE-AL09-I1-I7 (branco-amarela) 150 x 3100 (6)
In: TÉRREO
Classification: Parede (Classificação Archicad); Material: EI-REV-Chapisco (interno) (2), EI-REV-Cerâmica 10x10 Amarela, EI-REV-Cerâmica 10x10 Branca, EI-REV-Emboço Interno, EI-REV-Massa única - Maior que 10m² (2), EI-REV-Massa Corrida PVA (interna) (2), EI-REV-Pintura Acrílica Cor Branco Gelo, EI-REV-Pintura Acrílica Cor Branco Gelo - Interna, TIJOLO - CERAMICO 9x19x39 - espessura 15cm
FNDE - Alvenarias: Alvenaria de Vedação / Edificação; Sistemas de Cobertura: -; Esquadrias - Fechamentos metálicos e Gradis: -; 0_ID: AL09
Pset_WallCommon - IsExternal: no; LoadBearing: no
Component Quantities - EI-REV-Chapisco (interno) 1, Altura do Componente Retangular: 3.1 m; EI-REV-Chapisco (interno) 1, Largura do Componente Retangular: 0.005 m; EI-REV-Chapisco (interno) 1, Área de Seção Transversal do Componente: 0.0155 m2; EI-REV-Cerâmica 10x10 Amarela, Altura do Componente Retangular: 0.9 m; EI-REV-Cerâmica 10x10 Amarela, Largura do Componente Retangular: 0.02 m; EI-REV-Cerâmica 10x10 Amarela, Área de Seção Transversal do Componente: 0.018 m2; EI-REV-Cerâmica 10x10 Branca, Altura do Componente Retangular: 0.1 m; EI-REV-Cerâmica 10x10 Branca, Largura do Componente Retangular: 0.02 m; EI-REV-Cerâmica 10x10 Branca, Área de Seção Transversal do Componente: 0.002 m2; EI-REV-Massa única - Maior que 10m² 1, Altura do Componente Retangular: 2.06 m; EI-REV-Massa única - Maior que 10m² 1, Largura do Componente Retangular: 0.00499999 m; EI-REV-Massa única - Maior que 10m² 1, Área de Seção Transversal do Componente: 0.0103 m2; EI-REV-Massa Corrida PVA (interna) 1, Altura do Componente Retangular: 2.06 m; EI-REV-Massa Corrida PVA (interna) 1, Largura do Componente Retangular: 0.00500002 m; EI-REV-Massa Corrida PVA (interna) 1, Área de Seção Transversal do Componente: 0.0103 m2; EI-REV-Pintura Acrílica Cor Branco Gelo, Altura do Componente Retangular: 2.06 m; EI-REV-Pintura Acrílica Cor Branco Gelo, Largura do Componente Retangular: 0.01 m; EI-REV-Pintura Acrílica Cor Branco Gelo, Área de Seção Transversal do Componente: 0.0206 m2; EI-REV-Massa única - Maior que 10m² 2, Altura do Componente Retangular: 3.06 m; EI-REV-Massa única - Maior que 10m² 2, Largura do Componente Retangular: 0.01 m; EI-REV-Massa única - Maior que 10m² 2, Área de Seção Transversal do Componente: 0.0306 m2; EI-REV-Massa Corrida PVA (interna) 2, Altura do Componente Retangular: 3.06 m; EI-REV-Massa Corrida PVA (interna) 2, Largura do Componente Retangular: 0.005 m; EI-REV-Massa Corrida PVA (interna) 2, Área de Seção Transversal do Componente: 0.0153 m2; EI-REV-Pintura Acrílica Cor Branco Gelo - Interna, Altura do Componente Retangular: 3.06 m; EI-REV-Pintura Acrílica Cor Branco Gelo - Interna, Largura do Componente Retangular: 0.01 m; EI-REV-Pintura Acrílica Cor Branco Gelo - Interna, Área de Seção Transversal do Componente: 0.0306 m2; TIJOLO - CERAMICO 9x19x39 - espessura 15cm, Altura do Componente Retangular: 3.1 m; TIJOLO - CERAMICO 9x19x39 - espessura 15cm, Largura do Componente Retangular: 0.09 m; TIJOLO - CERAMICO 9x19x39 - espessura 15cm, Área de Seção Transversal do Componente: 0.279 m2
Name | 1_Bloco | EI-REV-Chapisco (interno) 1, Massa (kg) | EI-REV-Chapisco (interno) 1, Área de Componente Projetada (Líquida) (m2) | EI-REV-Chapisco (interno) 1, Área de Componente Projetada (Bruta) (m2) | EI-REV-Chapisco (interno) 1, Volume Componente (Líquido) (m3) | EI-REV-Chapisco (interno) 1, Volume do componente (Bruto) (m3) | EI-REV-Cerâmica 10x10 Amarela, Massa (kg) | EI-REV-Cerâmica 10x10 Amarela, Área de Componente Projetada (Líquida) (m2) | EI-REV-Cerâmica 10x10 Amarela, Área de Componente Projetada (Bruta) (m2) | EI-REV-Cerâmica 10x10 Amarela, Volume Componente (Líquido) (m3) | EI-REV-Cerâmica 10x10 Amarela, Volume do componente (Bruto) (m3) | EI-REV-Cerâmica 10x10 Branca, Massa (kg) | EI-REV-Cerâmica 10x10 Branca, Área de Componente Projetada (Líquida) (m2) | EI-REV-Cerâmica 10x10 Branca, Área de Componente Projetada (Bruta) (m2) | EI-REV-Cerâmica 10x10 Branca, Volume Componente (Líquido) (m3) | EI-REV-Cerâmica 10x10 Branca, Volume do componente (Bruto) (m3) | EI-REV-Massa única - Maior que 10m² 1, Massa (kg) | EI-REV-Massa única - Maior que 10m² 1, Área de Componente Projetada (Líquida) (m2) | EI-REV-Massa única - Maior que 10m² 1, Área de Componente Projetada (Bruta) (m2) | EI-REV-Massa única - Maior que 10m² 1, Volume Componente (Líquido) (m3) | EI-REV-Massa única - Maior que 10m² 1, Volume do componente (Bruto) (m3) | EI-REV-Massa Corrida PVA (interna) 1, Massa (kg) | EI-REV-Massa Corrida PVA (interna) 1, Área de Componente Projetada (Líquida) (m2) | EI-REV-Massa Corrida PVA (interna) 1, Área de Componente Projetada (Bruta) (m2) | EI-REV-Massa Corrida PVA (interna) 1, Volume Componente (Líquido) (m3) | EI-REV-Massa Corrida PVA (interna) 1, Volume do componente (Bruto) (m3) | EI-REV-Pintura Acrílica Cor Branco Gelo, Massa (kg) | EI-REV-Pintura Acrílica Cor Branco Gelo, Área de Componente Projetada (Líquida) (m2) | EI-REV-Pintura Acrílica Cor Branco Gelo, Área de Componente Projetada (Bruta) (m2) | EI-REV-Pintura Acrílica Cor Branco Gelo, Volume Componente (Líquido) (m3) | EI-REV-Pintura Acrílica Cor Branco Gelo, Volume do componente (Bruto) (m3) | EI-REV-Chapisco (interno) 2, Massa (kg) | EI-REV-Chapisco (interno) 2, Área de Componente Projetada (Líquida) (m2) | EI-REV-Chapisco (interno) 2, Área de Componente Projetada (Bruta) (m2) | EI-REV-Chapisco (interno) 2, Altura do Componente Retangular (m) | EI-REV-Chapisco (interno) 2, Largura do Componente Retangular (m) | EI-REV-Chapisco (interno) 2, Área de Seção Transversal do Componente (m2) | EI-REV-Chapisco (interno) 2, Volume Componente (Líquido) (m3) | EI-REV-Chapisco (interno) 2, Volume do componente (Bruto) (m3) | EI-REV-Massa única - Maior que 10m² 2, Massa (kg) | EI-REV-Massa única - Maior que 10m² 2, Área de Componente Projetada (Líquida) (m2) | EI-REV-Massa única - Maior que 10m² 2, Área de Componente Projetada (Bruta) (m2) | EI-REV-Massa única - Maior que 10m² 2, Volume Componente (Líquido) (m3) | EI-REV-Massa única - Maior que 10m² 2, Volume do componente (Bruto) (m3) | EI-REV-Massa Corrida PVA (interna) 2, Massa (kg) | EI-REV-Massa Corrida PVA (interna) 2, Área de Componente Projetada (Líquida) (m2) | EI-REV-Massa Corrida PVA (interna) 2, Área de Componente Projetada (Bruta) (m2) | EI-REV-Massa Corrida PVA (interna) 2, Volume Componente (Líquido) (m3) | EI-REV-Massa Corrida PVA (interna) 2, Volume do componente (Bruto) (m3) | EI-REV-Pintura Acrílica Cor Branco Gelo - Interna, Massa (kg) | EI-REV-Pintura Acrílica Cor Branco Gelo - Interna, Área de Componente Projetada (Líquida) (m2) | EI-REV-Pintura Acrílica Cor Branco Gelo - Interna, Área de Componente Projetada (Bruta) (m2) | EI-REV-Pintura Acrílica Cor Branco Gelo - Interna, Volume Componente (Líquido) (m3) | EI-REV-Pintura Acrílica Cor Branco Gelo - Interna, Volume do componente (Bruto) (m3) | TIJOLO - CERAMICO 9x19x39 - espessura 15cm, Massa (kg) | TIJOLO - CERAMICO 9x19x39 - espessura 15cm, Área de Componente Projetada (Líquida) (m2) | TIJOLO - CERAMICO 9x19x39 - espessura 15cm, Área de Componente Projetada (Bruta) (m2) | TIJOLO - CERAMICO 9x19x39 - espessura 15cm, Volume Componente (Líquido) (m3) | TIJOLO - CERAMICO 9x19x39 - espessura 15cm, Volume do componente (Bruto) (m3) | EI-REV-Emboço Interno, Massa (kg) | EI-REV-Emboço Interno, Área de Componente Projetada (Líquida) (m2) | EI-REV-Emboço Interno, Área de Componente Projetada (Bruta) (m2) | EI-REV-Emboço Interno, Altura do Componente Retangular (m) | EI-REV-Emboço Interno, Largura do Componente Retangular (m) | EI-REV-Emboço Interno, Área de Seção Transversal do Componente (m2) | EI-REV-Emboço Interno, Volume Componente (Líquido) (m3) | EI-REV-Emboço Interno, Volume do componente (Bruto) (m3)
AL09 | BLOCO B | 38.1611 | 5.87124 | 7.79724 | 0.0293547 | 0.0389847 | 58.3632 | 1.45908 | 2.26908 | 0.0291816 | 0.0453816 | 6.4848 | 0.16212 | 0.25212 | 0.0032424 | 0.0050424 | 27.0898 | 4.16767 | 5.19367 | 0.0208383 | 0.0259683 | 27.0438 | 4.16058 | 5.18658 | 0.0208029 | 0.025933 | 53.6858 | 4.12968 | 5.15568 | 0.0412968 | 0.0515568 | 38.1659 | 5.87198 | 7.79798 | 3.1 | 0.005 | 0.0155 | 0.0293584 | 0.0389884 | 75.119 | 5.77838 | 7.70438 | 0.0577838 | 0.0770438 | 37.4601 | 5.76308 | 7.68908 | 0.0288154 | 0.0384455 | 74.8084 | 5.75449 | 7.68049 | 0.0575449 | 0.0768049 | 342.436 | 5.87712 | 7.80312 | 0.528451 | 0.701791 | Component Quantities - EI-REV-Chapisco (interno) 1: 2 with these values
AL09 | BLOCO A | 72.832 | 11.2055 | 15.0575 | 0.0560246 | 0.0752846 | 143.861 | 4.095 | 5.715 | 0.0719303 | 0.10433 | 15.9845 | 0.455 | 0.635 | 0.00799225 | 0.0115923 | 46.9784 | 7.22747 | 9.27947 | 0.0361373 | 0.0463972 | 47.0327 | 7.23577 | 9.28777 | 0.036179 | 0.046439 | 119.044 | 11.029 | 13.081 | 0.0915727 | 0.112093 |  |  |  |  |  |  |  |  | 143.226 | 11.0174 | 14.8694 | 0.110174 | 0.148694 | 71.6132 | 11.0174 | 14.8694 | 0.055087 | 0.0743471 | 164.255 | 14.2724 | 18.1244 | 0.12635 | 0.16487 | 653.471 | 11.2158 | 15.0678 | 1.00844 | 1.35512 | Component Quantities - EI-REV-Chapisco (interno) 1: 3 with these values
AL09 | BLOCO A | 56.3707 | 8.67242 | 11.2324 | 0.0433621 | 0.0561621 | 149.657 | 3.805 | 3.965 | 0.0748285 | 0.0780285 | 9.51745 | 0.245 | 0.445 | 0.00475873 | 0.00875873 | 30.7648 | 6.91699 | 9.11699 | 0.0236652 | 0.0346652 | 44.9476 | 6.91499 | 9.11499 | 0.0345751 | 0.0455751 | 89.8689 | 6.91299 | 9.11299 | 0.0691299 | 0.0911299 | 57.863 | 8.902 | 11.462 | 3.1 | 0.005 | 0.0155 | 0.04451 | 0.05731 | 113.511 | 8.7316 | 11.2916 | 0.0873161 | 0.112916 | 57.6976 | 8.87782 | 11.4378 | 0.0443828 | 0.0571828 | 115.412 | 8.87782 | 11.4378 | 0.0887782 | 0.114378 | 521.497 | 8.942 | 11.502 | 0.80478 | 1.03518 | 56.283 | 8.65892 | 11.2189 | 3.1 | 0.005 | 0.0155 | 0.0432946 | 0.0560946
AL09 | BLOCO A | 21.4987 | 3.3075 | 3.3075 | 0.0165375 | 0.0165375 | 46.107 | 1.30498 | 1.30498 | 0.0230535 | 0.0230535 | 5.123 | 0.144998 | 0.144998 | 0.0025615 | 0.0025615 | 13.2177 | 2.0335 | 2.0335 | 0.0101675 | 0.0101675 | 13.2178 | 2.0335 | 2.0335 | 0.0101675 | 0.0101675 | 32.5528 | 2.98297 | 2.98297 | 0.0250406 | 0.0250406 |  |  |  |  |  |  |  |  | 42.3605 | 3.2585 | 3.2585 | 0.032585 | 0.032585 | 21.1803 | 3.2585 | 3.2585 | 0.0162925 | 0.0162925 | 49.7546 | 4.39912 | 4.39912 | 0.0382728 | 0.0382728 | 192.893 | 3.3075 | 3.3075 | 0.297675 | 0.297675 | 21.4988 | 3.3075 | 3.3075 | 3.1 | 0.005 | 0.0155 | 0.0165375 | 0.0165375 | Component Quantities - EI-REV-Chapisco (interno) 1: 2 with these values
AL09 | BLOCO A | 25.8548 | 3.97797 | 5.90397 | 0.0198883 | 0.0295183 | 44.9612 | 1.24188 | 2.05188 | 0.0224806 | 0.0386806 | 4.99568 | 0.137987 | 0.227987 | 0.00249784 | 0.00429784 | 17.411 | 2.67862 | 3.70462 | 0.013393 | 0.018523 | 17.3539 | 2.66982 | 3.69582 | 0.0133491 | 0.0184791 | 40.4338 | 3.62733 | 4.65333 | 0.0311029 | 0.0413629 | 23.8403 | 3.66803 | 5.54046 | 3.1 | 0.005 | 0.0155 | 0.0183387 | 0.0277009 | 46.8764 | 3.60588 | 5.47831 | 0.0360588 | 0.0547832 | 23.4382 | 3.60588 | 5.47831 | 0.0180294 | 0.0273916 | 54.3681 | 4.75055 | 6.62299 | 0.0418217 | 0.060546 | 213.902 | 3.67302 | 5.54545 | 0.330096 | 0.498615 | 25.7638 | 3.96397 | 5.88997 | 3.1 | 0.005 | 0.0155 | 0.0198183 | 0.0294483
AL09 | BLOCO B | 25.7137 | 3.95595 | 7.4034 | 0.0197798 | 0.037017 | 28.0788 | 0.701971 | 2.16897 | 0.0140394 | 0.0433794 | 3.11987 | 0.0779968 | 0.240997 | 0.00155994 | 0.00481994 | 20.456 | 3.14708 | 4.96453 | 0.0157354 | 0.0248227 | 20.4561 | 3.14708 | 4.96453 | 0.0157354 | 0.0248227 | 40.6443 | 3.12648 | 4.94393 | 0.0312648 | 0.0494394 | 22.686 | 3.49015 | 6.9376 | 3.1 | 0.005 | 0.0155 | 0.0174507 | 0.034688 | 44.2891 | 3.40685 | 6.8543 | 0.0340685 | 0.0685431 | 21.9457 | 3.37625 | 6.8237 | 0.0168813 | 0.0341185 | 43.0957 | 3.31505 | 6.7625 | 0.0331505 | 0.067625 | 205.47 | 3.52315 | 6.9706 | 0.317084 | 0.627354 | 25.7149 | 3.95615 | 7.4036 | 3.1 | 0.005 | 0.0155 | 0.0197807 | 0.037018

# IfcWall: FNDE-AL09-I1-I8 (branco-cinza) 150 x 3100 (2)
In: TÉRREO
Classification: Parede (Classificação Archicad); Material: TIJOLO - CERAMICO 9x19x39 - espessura 15cm, EI-REV-Chapisco (interno) (2), EI-REV-Pintura Acrílica Cor Cinza, EI-REV-Massa única - Maior que 10m² (2), EI-REV-Massa Corrida PVA (interna) (2), EI-REV-Pintura Acrílica Cor Branco Gelo, EI-REV-Pintura Acrílica Cor Branco Gelo - Interna
FNDE - Alvenarias: Alvenaria de Vedação / Edificação; Sistemas de Cobertura: -; Esquadrias - Fechamentos metálicos e Gradis: -; 1_Bloco: BLOCO A; 0_ID: AL09
Pset_WallCommon - IsExternal: no; LoadBearing: no
Component Quantities - TIJOLO - CERAMICO 9x19x39 - espessura 15cm, Altura do Componente Retangular: 3.1 m; TIJOLO - CERAMICO 9x19x39 - espessura 15cm, Largura do Componente Retangular: 0.09 m; TIJOLO - CERAMICO 9x19x39 - espessura 15cm, Área de Seção Transversal do Componente: 0.279 m2; EI-REV-Chapisco (interno) 1, Altura do Componente Retangular: 3.1 m; EI-REV-Chapisco (interno) 1, Largura do Componente Retangular: 0.005 m; EI-REV-Chapisco (interno) 1, Área de Seção Transversal do Componente: 0.0155 m2; EI-REV-Pintura Acrílica Cor Cinza, Altura do Componente Retangular: 0.44 m; EI-REV-Pintura Acrílica Cor Cinza, Largura do Componente Retangular: 0.01 m; EI-REV-Pintura Acrílica Cor Cinza, Área de Seção Transversal do Componente: 0.0044 m2; EI-REV-Massa única - Maior que 10m² 1, Altura do Componente Retangular: 3.1 m; EI-REV-Massa única - Maior que 10m² 1, Largura do Componente Retangular: 0.01 m; EI-REV-Massa única - Maior que 10m² 1, Área de Seção Transversal do Componente: 0.031 m2; EI-REV-Pintura Acrílica Cor Branco Gelo, Altura do Componente Retangular: 2.66 m; EI-REV-Pintura Acrílica Cor Branco Gelo, Largura do Componente Retangular: 0.01 m; EI-REV-Pintura Acrílica Cor Branco Gelo, Área de Seção Transversal do Componente: 0.0266 m2; EI-REV-Chapisco (interno) 2, Altura do Componente Retangular: 3.1 m; EI-REV-Chapisco (interno) 2, Largura do Componente Retangular: 0.005 m; EI-REV-Chapisco (interno) 2, Área de Seção Transversal do Componente: 0.0155 m2; EI-REV-Massa única - Maior que 10m² 2, Altura do Componente Retangular: 3.06 m; EI-REV-Massa única - Maior que 10m² 2, Largura do Componente Retangular: 0.01 m; EI-REV-Massa única - Maior que 10m² 2, Área de Seção Transversal do Componente: 0.0306 m2; EI-REV-Massa Corrida PVA (interna) 2, Altura do Componente Retangular: 3.06 m; EI-REV-Massa Corrida PVA (interna) 2, Largura do Componente Retangular: 0.005 m; EI-REV-Massa Corrida PVA (interna) 2, Área de Seção Transversal do Componente: 0.0153 m2; EI-REV-Pintura Acrílica Cor Branco Gelo - Interna, Altura do Componente Retangular: 3.06 m; EI-REV-Pintura Acrílica Cor Branco Gelo - Interna, Largura do Componente Retangular: 0.01 m; EI-REV-Pintura Acrílica Cor Branco Gelo - Interna, Área de Seção Transversal do Componente: 0.0306 m2
Name | TIJOLO - CERAMICO 9x19x39 - espessura 15cm, Massa (kg) | TIJOLO - CERAMICO 9x19x39 - espessura 15cm, Área de Componente Projetada (Líquida) (m2) | TIJOLO - CERAMICO 9x19x39 - espessura 15cm, Área de Componente Projetada (Bruta) (m2) | TIJOLO - CERAMICO 9x19x39 - espessura 15cm, Volume Componente (Líquido) (m3) | TIJOLO - CERAMICO 9x19x39 - espessura 15cm, Volume do componente (Bruto) (m3) | EI-REV-Chapisco (interno) 1, Massa (kg) | EI-REV-Chapisco (interno) 1, Área de Componente Projetada (Líquida) (m2) = EI-REV-Massa única - Maior que 10m² 1, Área de Componente Projetada (Líquida) (m2) | EI-REV-Chapisco (interno) 1, Área de Componente Projetada (Bruta) (m2) = EI-REV-Massa única - Maior que 10m² 1, Área de Componente Projetada (Bruta) (m2) | EI-REV-Chapisco (interno) 1, Volume Componente (Líquido) (m3) | EI-REV-Chapisco (interno) 1, Volume do componente (Bruto) (m3) | EI-REV-Pintura Acrílica Cor Cinza, Massa (kg) | EI-REV-Pintura Acrílica Cor Cinza, Área de Componente Projetada (Líquida) (m2) = EI-REV-Pintura Acrílica Cor Cinza, Área de Componente Projetada (Bruta) (m2) | EI-REV-Pintura Acrílica Cor Cinza, Volume Componente (Líquido) (m3) = EI-REV-Pintura Acrílica Cor Cinza, Volume do componente (Bruto) (m3) | EI-REV-Massa única - Maior que 10m² 1, Massa (kg) | EI-REV-Massa única - Maior que 10m² 1, Volume Componente (Líquido) (m3) | EI-REV-Massa única - Maior que 10m² 1, Volume do componente (Bruto) (m3) | EI-REV-Pintura Acrílica Cor Branco Gelo, Massa (kg) | EI-REV-Pintura Acrílica Cor Branco Gelo, Área de Componente Projetada (Líquida) (m2) | EI-REV-Pintura Acrílica Cor Branco Gelo, Área de Componente Projetada (Bruta) (m2) | EI-REV-Pintura Acrílica Cor Branco Gelo, Volume Componente (Líquido) (m3) | EI-REV-Pintura Acrílica Cor Branco Gelo, Volume do componente (Bruto) (m3) | EI-REV-Chapisco (interno) 2, Massa (kg) | EI-REV-Chapisco (interno) 2, Área de Componente Projetada (Líquida) (m2) | EI-REV-Chapisco (interno) 2, Área de Componente Projetada (Bruta) (m2) | EI-REV-Chapisco (interno) 2, Volume Componente (Líquido) (m3) | EI-REV-Chapisco (interno) 2, Volume do componente (Bruto) (m3) | EI-REV-Massa única - Maior que 10m² 2, Massa (kg) | EI-REV-Massa única - Maior que 10m² 2, Área de Componente Projetada (Líquida) (m2) = EI-REV-Massa Corrida PVA (interna) 2, Área de Componente Projetada (Líquida) (m2) | EI-REV-Massa única - Maior que 10m² 2, Área de Componente Projetada (Bruta) (m2) = EI-REV-Massa Corrida PVA (interna) 2, Área de Componente Projetada (Bruta) (m2) | EI-REV-Massa única - Maior que 10m² 2, Volume Componente (Líquido) (m3) | EI-REV-Massa única - Maior que 10m² 2, Volume do componente (Bruto) (m3) | EI-REV-Massa Corrida PVA (interna) 2, Massa (kg) | EI-REV-Massa Corrida PVA (interna) 2, Volume Componente (Líquido) (m3) | EI-REV-Massa Corrida PVA (interna) 2, Volume do componente (Bruto) (m3) | EI-REV-Pintura Acrílica Cor Branco Gelo - Interna, Massa (kg) | EI-REV-Pintura Acrílica Cor Branco Gelo - Interna, Área de Componente Projetada (Líquida) (m2) | EI-REV-Pintura Acrílica Cor Branco Gelo - Interna, Área de Componente Projetada (Bruta) (m2) | EI-REV-Pintura Acrílica Cor Branco Gelo - Interna, Volume Componente (Líquido) (m3) | EI-REV-Pintura Acrílica Cor Branco Gelo - Interna, Volume do componente (Bruto) (m3)
AL09 | 243.019 | 4.167 | 7.317 | 0.37503 | 0.65853 | 27.0855 | 4.167 | 7.317 | 0.020835 | 0.036585 | 15.8831 | 1.25182 | 0.0122178 | 54.171 | 0.04167 | 0.07317 | 48.0221 | 4.42362 | 7.57362 | 0.03694 | 0.06844 | 27.0842 | 4.1668 | 7.3168 | 0.020834 | 0.0365839 | 52.7618 | 4.0586 | 7.2086 | 0.040586 | 0.072086 | 26.3809 | 0.020293 | 0.036043 | 59.7016 | 5.12743 | 8.27743 | 0.0459243 | 0.0774243 | Component Quantities - EI-REV-Chapisco (interno) 1: 2 with these values
AL09 | 152.485 | 2.61462 | 5.76462 | 0.235316 | 0.518816 | 16.8195 | 2.58762 | 5.73762 | 0.0129381 | 0.0286881 | 12.012 | 0.924 | 0.00924 | 33.639 | 0.0258762 | 0.0573762 | 26.1474 | 2.436 | 5.586 | 0.0201134 | 0.0516134 | 19.4507 | 2.99242 | 6.14242 | 0.0149621 | 0.0307121 | 37.894 | 2.91492 | 6.06492 | 0.0291492 | 0.0606492 | 18.947 | 0.0145746 | 0.0303246 | 43.7001 | 3.8115 | 6.9615 | 0.0336155 | 0.0651155 | Component Quantities - EI-REV-Massa Corrida PVA (interna) 1, Massa: 16.7318 kg; EI-REV-Massa Corrida PVA (interna) 1, Área de Componente Projetada (Líquida): 2.57412 m2; EI-REV-Massa Corrida PVA (interna) 1, Área de Componente Projetada (Bruta): 5.72412 m2; EI-REV-Massa Corrida PVA (interna) 1, Altura do Componente Retangular: 3.1 m; EI-REV-Massa Corrida PVA (interna) 1, Largura do Componente Retangular: 0.005 m; EI-REV-Massa Corrida PVA (interna) 1, Área de Seção Transversal do Componente: 0.0155 m2; EI-REV-Massa Corrida PVA (interna) 1, Volume Componente (Líquido): 0.0128706 m3; EI-REV-Massa Corrida PVA (interna) 1, Volume do componente (Bruto): 0.0286206 m3

# IfcWall: FNDE-AL09-I2 (laranja) 120 x 3100 (2)
In: TÉRREO
Classification: Parede (Classificação Archicad); Material: TIJOLO - CERAMICO 9x19x39 - espessura 15cm, EI-REV-Chapisco (interno), EI-REV-Pintura Epóxi cor Laranja, EI-REV-Massa única - Maior que 10m², EI-REV-Massa Corrida PVA (interna), EI-REV-Pintura Acrílica Cor Branco Gelo
FNDE - Alvenarias: Alvenaria de Vedação / Edificação; Sistemas de Cobertura: -; Esquadrias - Fechamentos metálicos e Gradis: -; 0_ID: AL09
Pset_WallCommon - IsExternal: yes; LoadBearing: no
Component Quantities - TIJOLO - CERAMICO 9x19x39 - espessura 15cm, Altura do Componente Retangular: 3.1 m; TIJOLO - CERAMICO 9x19x39 - espessura 15cm, Largura do Componente Retangular: 0.09 m; TIJOLO - CERAMICO 9x19x39 - espessura 15cm, Área de Seção Transversal do Componente: 0.279 m2; EI-REV-Chapisco (interno), Altura do Componente Retangular: 3.1 m; EI-REV-Chapisco (interno), Largura do Componente Retangular: 0.005 m; EI-REV-Chapisco (interno), Área de Seção Transversal do Componente: 0.0155 m2; EI-REV-Pintura Epóxi cor Laranja, Altura do Componente Retangular: 0.9 m; EI-REV-Pintura Epóxi cor Laranja, Largura do Componente Retangular: 0.02 m; EI-REV-Pintura Epóxi cor Laranja, Área de Seção Transversal do Componente: 0.018 m2; EI-REV-Massa única - Maior que 10m², Área de Seção Transversal do Componente: 0.0155 m2; EI-REV-Massa Corrida PVA (interna), Altura do Componente Retangular: 2.16 m; EI-REV-Massa Corrida PVA (interna), Largura do Componente Retangular: 0.005 m; EI-REV-Massa Corrida PVA (interna), Área de Seção Transversal do Componente: 0.0108001 m2; EI-REV-Pintura Acrílica Cor Branco Gelo, Altura do Componente Retangular: 2.16 m; EI-REV-Pintura Acrílica Cor Branco Gelo, Largura do Componente Retangular: 0.015 m; EI-REV-Pintura Acrílica Cor Branco Gelo, Área de Seção Transversal do Componente: 0.0324 m2
Name | 1_Bloco | TIJOLO - CERAMICO 9x19x39 - espessura 15cm, Massa (kg) | TIJOLO - CERAMICO 9x19x39 - espessura 15cm, Área de Componente Projetada (Líquida) (m2) = TIJOLO - CERAMICO 9x19x39 - espessura 15cm, Área de Componente Projetada (Bruta) (m2) | TIJOLO - CERAMICO 9x19x39 - espessura 15cm, Volume Componente (Líquido) (m3) = TIJOLO - CERAMICO 9x19x39 - espessura 15cm, Volume do componente (Bruto) (m3) | EI-REV-Chapisco (interno), Massa (kg) | EI-REV-Chapisco (interno), Área de Componente Projetada (Líquida) (m2) = EI-REV-Chapisco (interno), Área de Componente Projetada (Bruta) (m2) | EI-REV-Chapisco (interno), Volume Componente (Líquido) (m3) = EI-REV-Chapisco (interno), Volume do componente (Bruto) (m3) | EI-REV-Pintura Epóxi cor Laranja, Massa (kg) | EI-REV-Pintura Epóxi cor Laranja, Área de Componente Projetada (Líquida) (m2) = EI-REV-Pintura Epóxi cor Laranja, Área de Componente Projetada (Bruta) (m2) | EI-REV-Pintura Epóxi cor Laranja, Volume Componente (Líquido) (m3) = EI-REV-Pintura Epóxi cor Laranja, Volume do componente (Bruto) (m3) | EI-REV-Massa única - Maior que 10m², Massa (kg) | EI-REV-Massa única - Maior que 10m², Área de Componente Projetada (Líquida) (m2) = EI-REV-Massa única - Maior que 10m², Área de Componente Projetada (Bruta) (m2) | EI-REV-Massa única - Maior que 10m², Volume Componente (Líquido) (m3) = EI-REV-Massa única - Maior que 10m², Volume do componente (Bruto) (m3) | EI-REV-Massa Corrida PVA (interna), Massa (kg) | EI-REV-Massa Corrida PVA (interna), Área de Componente Projetada (Líquida) (m2) = EI-REV-Massa Corrida PVA (interna), Área de Componente Projetada (Bruta) (m2) | EI-REV-Massa Corrida PVA (interna), Volume Componente (Líquido) (m3) = EI-REV-Massa Corrida PVA (interna), Volume do componente (Bruto) (m3) | EI-REV-Pintura Acrílica Cor Branco Gelo, Massa (kg) | EI-REV-Pintura Acrílica Cor Branco Gelo, Área de Componente Projetada (Líquida) (m2) = EI-REV-Pintura Acrílica Cor Branco Gelo, Área de Componente Projetada (Bruta) (m2) | EI-REV-Pintura Acrílica Cor Branco Gelo, Volume Componente (Líquido) (m3) = EI-REV-Pintura Acrílica Cor Branco Gelo, Volume do componente (Bruto) (m3)
AL09 | BLOCO B | 133.226 | 2.2844 | 0.205596 | 12.5476 | 1.9304 | 0.00965199 | 17.5825 | 0.827878 | 0.013525 | 12.4598 | 1.9169 | 0.00958449 | 8.06481 | 1.24073 | 0.0062037 | 28.2006 | 1.97611 | 0.0216928
AL09 | BLOCO A | 133.24 | 2.28464 | 0.205618 | 12.5492 | 1.93064 | 0.0096532 | 17.7696 | 0.827998 | 0.0136689 | 12.4605 | 1.91714 | 0.00958501 | 8.06585 | 1.24089 | 0.0062045 | 28.9174 | 1.97639 | 0.0222442

# IfcWall: FNDE-AL09-I2-I2 (laranja) 150 x 3100, AL09
In: TÉRREO
Classification: Parede (Classificação Archicad); Material: TIJOLO - CERAMICO 9x19x39 - espessura 15cm, EI-REV-Chapisco (interno) (2), EI-REV-Pintura Epóxi cor Laranja (2), EI-REV-Massa única - Maior que 10m² (2), EI-REV-Massa Corrida PVA (interna) (2), EI-REV-Pintura Acrílica Cor Branco Gelo (2)
FNDE - Alvenarias: Alvenaria de Vedação / Edificação; Sistemas de Cobertura: -; Esquadrias - Fechamentos metálicos e Gradis: -; 1_Bloco: BLOCO B; 0_ID: AL09
Pset_WallCommon - IsExternal: no; LoadBearing: no
Component Quantities - TIJOLO - CERAMICO 9x19x39 - espessura 15cm, Massa: 100.32 kg; TIJOLO - CERAMICO 9x19x39 - espessura 15cm, Área de Componente Projetada (Líquida): 1.72016 m2; TIJOLO - CERAMICO 9x19x39 - espessura 15cm, Área de Componente Projetada (Bruta): 1.72016 m2; TIJOLO - CERAMICO 9x19x39 - espessura 15cm, Altura do Componente Retangular: 3.1 m; TIJOLO - CERAMICO 9x19x39 - espessura 15cm, Largura do Componente Retangular: 0.09 m; TIJOLO - CERAMICO 9x19x39 - espessura 15cm, Área de Seção Transversal do Componente: 0.279 m2; TIJOLO - CERAMICO 9x19x39 - espessura 15cm, Volume Componente (Líquido): 0.154814 m3; TIJOLO - CERAMICO 9x19x39 - espessura 15cm, Volume do componente (Bruto): 0.154814 m3; EI-REV-Chapisco (interno) 1, Massa: 9.60152 kg; EI-REV-Chapisco (interno) 1, Área de Componente Projetada (Líquida): 1.47716 m2; EI-REV-Chapisco (interno) 1, Área de Componente Projetada (Bruta): 1.47716 m2; EI-REV-Chapisco (interno) 1, Altura do Componente Retangular: 3.1 m; EI-REV-Chapisco (interno) 1, Largura do Componente Retangular: 0.005 m; EI-REV-Chapisco (interno) 1, Área de Seção Transversal do Componente: 0.0155 m2; EI-REV-Chapisco (interno) 1, Volume Componente (Líquido): 0.00738578 m3; EI-REV-Chapisco (interno) 1, Volume do componente (Bruto): 0.00738578 m3; EI-REV-Pintura Epóxi cor Laranja 1, Massa: 10.998 kg; EI-REV-Pintura Epóxi cor Laranja 1, Área de Componente Projetada (Líquida): 0.423 m2; EI-REV-Pintura Epóxi cor Laranja 1, Área de Componente Projetada (Bruta): 0.423 m2; EI-REV-Pintura Epóxi cor Laranja 1, Altura do Componente Retangular: 0.9 m; EI-REV-Pintura Epóxi cor Laranja 1, Largura do Componente Retangular: 0.02 m; EI-REV-Pintura Epóxi cor Laranja 1, Área de Seção Transversal do Componente: 0.018 m2; EI-REV-Pintura Epóxi cor Laranja 1, Volume Componente (Líquido): 0.00846 m3; EI-REV-Pintura Epóxi cor Laranja 1, Volume do componente (Bruto): 0.00846 m3; EI-REV-Massa única - Maior que 10m² 1, Massa: 9.51248 kg; EI-REV-Massa única - Maior que 10m² 1, Área de Componente Projetada (Líquida): 1.46346 m2; EI-REV-Massa única - Maior que 10m² 1, Área de Componente Projetada (Bruta): 1.46346 m2; EI-REV-Massa única - Maior que 10m² 1, Área de Seção Transversal do Componente: 0.0155 m2; EI-REV-Massa única - Maior que 10m² 1, Volume Componente (Líquido): 0.00731729 m3; EI-REV-Massa única - Maior que 10m² 1, Volume do componente (Bruto): 0.00731729 m3; EI-REV-Massa Corrida PVA (interna) 1, Massa: 6.55957 kg; EI-REV-Massa Corrida PVA (interna) 1, Área de Componente Projetada (Líquida): 1.00916 m2; EI-REV-Massa Corrida PVA (interna) 1, Área de Componente Projetada (Bruta): 1.00916 m2; EI-REV-Massa Corrida PVA (interna) 1, Altura do Componente Retangular: 2.16 m; EI-REV-Massa Corrida PVA (interna) 1, Largura do Componente Retangular: 0.005 m; EI-REV-Massa Corrida PVA (interna) 1, Área de Seção Transversal do Componente: 0.0108001 m2; EI-REV-Massa Corrida PVA (interna) 1, Volume Componente (Líquido): 0.00504582 m3; EI-REV-Massa Corrida PVA (interna) 1, Volume do componente (Bruto): 0.00504582 m3; EI-REV-Pintura Acrílica Cor Branco Gelo 1, Massa: 19.507 kg; EI-REV-Pintura Acrílica Cor Branco Gelo 1, Área de Componente Projetada (Líquida): 1.00036 m2; EI-REV-Pintura Acrílica Cor Branco Gelo 1, Área de Componente Projetada (Bruta): 1.00036 m2; EI-REV-Pintura Acrílica Cor Branco Gelo 1, Altura do Componente Retangular: 2.16 m; EI-REV-Pintura Acrílica Cor Branco Gelo 1, Largura do Componente Retangular: 0.015 m; EI-REV-Pintura Acrílica Cor Branco Gelo 1, Área de Seção Transversal do Componente: 0.0324 m2; EI-REV-Pintura Acrílica Cor Branco Gelo 1, Volume Componente (Líquido): 0.0150054 m3; EI-REV-Pintura Acrílica Cor Branco Gelo 1, Volume do componente (Bruto): 0.0150054 m3; EI-REV-Chapisco (interno) 2, Massa: 9.6025 kg; EI-REV-Chapisco (interno) 2, Área de Componente Projetada (Líquida): 1.47731 m2; EI-REV-Chapisco (interno) 2, Área de Componente Projetada (Bruta): 1.47731 m2; EI-REV-Chapisco (interno) 2, Altura do Componente Retangular: 3.1 m; EI-REV-Chapisco (interno) 2, Largura do Componente Retangular: 0.005 m; EI-REV-Chapisco (interno) 2, Área de Seção Transversal do Componente: 0.0155 m2; EI-REV-Chapisco (interno) 2, Volume Componente (Líquido): 0.00738654 m3; EI-REV-Chapisco (interno) 2, Volume do componente (Bruto): 0.00738654 m3; EI-REV-Massa única - Maior que 10m² 2, Massa: 9.51476 kg; EI-REV-Massa única - Maior que 10m² 2, Área de Componente Projetada (Líquida): 1.46381 m2; EI-REV-Massa única - Maior que 10m² 2, Área de Componente Projetada (Bruta): 1.46381 m2; EI-REV-Massa única - Maior que 10m² 2, Altura do Componente Retangular: 3.1 m; EI-REV-Massa única - Maior que 10m² 2, Largura do Componente Retangular: 0.005 m; EI-REV-Massa única - Maior que 10m² 2, Área de Seção Transversal do Componente: 0.0155 m2; EI-REV-Massa única - Maior que 10m² 2, Volume Componente (Líquido): 0.00731905 m3; EI-REV-Massa única - Maior que 10m² 2, Volume do componente (Bruto): 0.00731905 m3; EI-REV-Massa Corrida PVA (interna) 2, Massa: 6.55954 kg; EI-REV-Massa Corrida PVA (interna) 2, Área de Componente Projetada (Líquida): 1.00916 m2; EI-REV-Massa Corrida PVA (interna) 2, Área de Componente Projetada (Bruta): 1.00916 m2; EI-REV-Massa Corrida PVA (interna) 2, Altura do Componente Retangular: 2.16 m; EI-REV-Massa Corrida PVA (interna) 2, Largura do Componente Retangular: 0.005 m; EI-REV-Massa Corrida PVA (interna) 2, Área de Seção Transversal do Componente: 0.0108 m2; EI-REV-Massa Corrida PVA (interna) 2, Volume Componente (Líquido): 0.0050458 m3; EI-REV-Massa Corrida PVA (interna) 2, Volume do componente (Bruto): 0.0050458 m3; EI-REV-Pintura Acrílica Cor Branco Gelo 2, Massa: 19.8139 kg; EI-REV-Pintura Acrílica Cor Branco Gelo 2, Área de Componente Projetada (Líquida): 1.0161 m2; EI-REV-Pintura Acrílica Cor Branco Gelo 2, Área de Componente Projetada (Bruta): 1.0161 m2; EI-REV-Pintura Acrílica Cor Branco Gelo 2, Altura do Componente Retangular: 2.16 m; EI-REV-Pintura Acrílica Cor Branco Gelo 2, Largura do Componente Retangular: 0.015 m; EI-REV-Pintura Acrílica Cor Branco Gelo 2, Área de Seção Transversal do Componente: 0.0324 m2; EI-REV-Pintura Acrílica Cor Branco Gelo 2, Volume Componente (Líquido): 0.0152415 m3; EI-REV-Pintura Acrílica Cor Branco Gelo 2, Volume do componente (Bruto): 0.0152415 m3; EI-REV-Pintura Epóxi cor Laranja 1: 2 with these values

# IfcWall: FNDE-AL09-I2-I3 (laranja-verde) 150 x 3100, AL09
In: TÉRREO
Classification: Parede (Classificação Archicad); Material: TIJOLO - CERAMICO 9x19x39 - espessura 15cm, EI-REV-Chapisco (interno) (2), EI-REV-Pintura Epóxi cor Laranja, EI-REV-Massa única - Maior que 10m² (2), EI-REV-Massa Corrida PVA (interna) (2), EI-REV-Pintura Acrílica Cor Branco Gelo (2), EI-REV-Pintura Epóxi cor Verde
FNDE - Alvenarias: Alvenaria de Vedação / Edificação; Sistemas de Cobertura: -; Esquadrias - Fechamentos metálicos e Gradis: -; 1_Bloco: BLOCO B; 0_ID: AL09
Pset_WallCommon - IsExternal: no; LoadBearing: no
Component Quantities - TIJOLO - CERAMICO 9x19x39 - espessura 15cm, Massa: 876.641 kg; TIJOLO - CERAMICO 9x19x39 - espessura 15cm, Área de Componente Projetada (Líquida): 15.0316 m2; TIJOLO - CERAMICO 9x19x39 - espessura 15cm, Área de Componente Projetada (Bruta): 15.0316 m2; TIJOLO - CERAMICO 9x19x39 - espessura 15cm, Altura do Componente Retangular: 3.1 m; TIJOLO - CERAMICO 9x19x39 - espessura 15cm, Largura do Componente Retangular: 0.09 m; TIJOLO - CERAMICO 9x19x39 - espessura 15cm, Área de Seção Transversal do Componente: 0.279 m2; TIJOLO - CERAMICO 9x19x39 - espessura 15cm, Volume Componente (Líquido): 1.35284 m3; TIJOLO - CERAMICO 9x19x39 - espessura 15cm, Volume do componente (Bruto): 1.35284 m3; EI-REV-Chapisco (interno) 1, Massa: 97.6174 kg; EI-REV-Chapisco (interno) 1, Área de Componente Projetada (Líquida): 15.0181 m2; EI-REV-Chapisco (interno) 1, Área de Componente Projetada (Bruta): 15.0181 m2; EI-REV-Chapisco (interno) 1, Altura do Componente Retangular: 3.1 m; EI-REV-Chapisco (interno) 1, Largura do Componente Retangular: 0.005 m; EI-REV-Chapisco (interno) 1, Área de Seção Transversal do Componente: 0.0155 m2; EI-REV-Chapisco (interno) 1, Volume Componente (Líquido): 0.0750903 m3; EI-REV-Chapisco (interno) 1, Volume do componente (Bruto): 0.0750903 m3; EI-REV-Pintura Epóxi cor Laranja, Massa: 137.695 kg; EI-REV-Pintura Epóxi cor Laranja, Área de Componente Projetada (Líquida): 5.40004 m2; EI-REV-Pintura Epóxi cor Laranja, Área de Componente Projetada (Bruta): 5.40004 m2; EI-REV-Pintura Epóxi cor Laranja, Altura do Componente Retangular: 0.9 m; EI-REV-Pintura Epóxi cor Laranja, Largura do Componente Retangular: 0.02 m; EI-REV-Pintura Epóxi cor Laranja, Área de Seção Transversal do Componente: 0.018 m2; EI-REV-Pintura Epóxi cor Laranja, Volume Componente (Líquido): 0.105919 m3; EI-REV-Pintura Epóxi cor Laranja, Volume do componente (Bruto): 0.105919 m3; EI-REV-Massa única - Maior que 10m² 1, Massa: 97.5297 kg; EI-REV-Massa única - Maior que 10m² 1, Área de Componente Projetada (Líquida): 15.0046 m2; EI-REV-Massa única - Maior que 10m² 1, Área de Componente Projetada (Bruta): 15.0046 m2; EI-REV-Massa única - Maior que 10m² 1, Área de Seção Transversal do Componente: 0.0155 m2; EI-REV-Massa única - Maior que 10m² 1, Volume Componente (Líquido): 0.0750228 m3; EI-REV-Massa única - Maior que 10m² 1, Volume do componente (Bruto): 0.0750228 m3; EI-REV-Massa Corrida PVA (interna) 1, Massa: 63.4994 kg; EI-REV-Massa Corrida PVA (interna) 1, Área de Componente Projetada (Líquida): 9.77195 m2; EI-REV-Massa Corrida PVA (interna) 1, Área de Componente Projetada (Bruta): 9.77195 m2; EI-REV-Massa Corrida PVA (interna) 1, Altura do Componente Retangular: 2.16 m; EI-REV-Massa Corrida PVA (interna) 1, Largura do Componente Retangular: 0.005 m; EI-REV-Massa Corrida PVA (interna) 1, Área de Seção Transversal do Componente: 0.0108001 m2; EI-REV-Massa Corrida PVA (interna) 1, Volume Componente (Líquido): 0.0488457 m3; EI-REV-Massa Corrida PVA (interna) 1, Volume do componente (Bruto): 0.0488457 m3; EI-REV-Pintura Acrílica Cor Branco Gelo 1, Massa: 221.528 kg; EI-REV-Pintura Acrílica Cor Branco Gelo 1, Área de Componente Projetada (Líquida): 12.9601 m2; EI-REV-Pintura Acrílica Cor Branco Gelo 1, Área de Componente Projetada (Bruta): 12.9601 m2; EI-REV-Pintura Acrílica Cor Branco Gelo 1, Altura do Componente Retangular: 2.16 m; EI-REV-Pintura Acrílica Cor Branco Gelo 1, Largura do Componente Retangular: 0.015 m; EI-REV-Pintura Acrílica Cor Branco Gelo 1, Área de Seção Transversal do Componente: 0.0324 m2; EI-REV-Pintura Acrílica Cor Branco Gelo 1, Volume Componente (Líquido): 0.170406 m3; EI-REV-Pintura Acrílica Cor Branco Gelo 1, Volume do componente (Bruto): 0.170406 m3; EI-REV-Pintura Epóxi cor Verde, Massa: 138.044 kg; EI-REV-Pintura Epóxi cor Verde, Área de Componente Projetada (Líquida): 5.41804 m2; EI-REV-Pintura Epóxi cor Verde, Área de Componente Projetada (Bruta): 5.41804 m2; EI-REV-Pintura Epóxi cor Verde, Altura do Componente Retangular: 0.9 m; EI-REV-Pintura Epóxi cor Verde, Largura do Componente Retangular: 0.02 m; EI-REV-Pintura Epóxi cor Verde, Área de Seção Transversal do Componente: 0.018 m2; EI-REV-Pintura Epóxi cor Verde, Volume Componente (Líquido): 0.106187 m3; EI-REV-Pintura Epóxi cor Verde, Volume do componente (Bruto): 0.106187 m3; EI-REV-Massa única - Maior que 10m² 2, Massa: 97.5297 kg; EI-REV-Massa única - Maior que 10m² 2, Área de Componente Projetada (Líquida): 15.0046 m2; EI-REV-Massa única - Maior que 10m² 2, Área de Componente Projetada (Bruta): 15.0046 m2; EI-REV-Massa única - Maior que 10m² 2, Altura do Componente Retangular: 3.1 m; EI-REV-Massa única - Maior que 10m² 2, Largura do Componente Retangular: 0.005 m; EI-REV-Massa única - Maior que 10m² 2, Área de Seção Transversal do Componente: 0.0155 m2; EI-REV-Massa única - Maior que 10m² 2, Volume Componente (Líquido): 0.0750228 m3; EI-REV-Massa única - Maior que 10m² 2, Volume do componente (Bruto): 0.0750228 m3; EI-REV-Massa Corrida PVA (interna) 2, Massa: 63.5362 kg; EI-REV-Massa Corrida PVA (interna) 2, Área de Componente Projetada (Líquida): 9.77195 m2; EI-REV-Massa Corrida PVA (interna) 2, Área de Componente Projetada (Bruta): 9.77195 m2; EI-REV-Massa Corrida PVA (interna) 2, Altura do Componente Retangular: 2.16 m; EI-REV-Massa Corrida PVA (interna) 2, Largura do Componente Retangular: 0.005 m; EI-REV-Massa Corrida PVA (interna) 2, Área de Seção Transversal do Componente: 0.0108 m2; EI-REV-Massa Corrida PVA (interna) 2, Volume Componente (Líquido): 0.048874 m3; EI-REV-Massa Corrida PVA (interna) 2, Volume do componente (Bruto): 0.048874 m3; EI-REV-Pintura Acrílica Cor Branco Gelo 2, Massa: 222.049 kg; EI-REV-Pintura Acrílica Cor Branco Gelo 2, Área de Componente Projetada (Líquida): 12.9894 m2; EI-REV-Pintura Acrílica Cor Branco Gelo 2, Área de Componente Projetada (Bruta): 12.9894 m2; EI-REV-Pintura Acrílica Cor Branco Gelo 2, Altura do Componente Retangular: 2.16 m; EI-REV-Pintura Acrílica Cor Branco Gelo 2, Largura do Componente Retangular: 0.015 m; EI-REV-Pintura Acrílica Cor Branco Gelo 2, Área de Seção Transversal do Componente: 0.0324 m2; EI-REV-Pintura Acrílica Cor Branco Gelo 2, Volume Componente (Líquido): 0.170807 m3; EI-REV-Pintura Acrílica Cor Branco Gelo 2, Volume do componente (Bruto): 0.170807 m3; EI-REV-Chapisco (interno) 1: 2 with these values

# IfcWall: FNDE-AL09-I2-I5 (laranja-azul) 150 x 3100 (4)
In: TÉRREO
Classification: Parede (Classificação Archicad); Material: EI-REV-Pintura Acrílica Cor Branco Gelo (2), EI-REV-Cerâmica 10x10 Azul, EI-REV-Chapisco (interno) (2), EI-REV-Massa Corrida PVA (interna) (2), EI-REV-Cerâmica 30x40, EI-REV-Emboço Interno, EI-REV-Massa única - Maior que 10m² (2), EI-REV-Pintura Epóxi cor Laranja, TIJOLO - CERAMICO 9x19x39 - espessura 15cm
FNDE - Alvenarias: Alvenaria de Vedação / Edificação; Sistemas de Cobertura: -; Esquadrias - Fechamentos metálicos e Gradis: -; 0_ID: AL09
Pset_WallCommon - IsExternal: no; LoadBearing: no
Component Quantities - EI-REV-Pintura Acrílica Cor Branco Gelo 1, Altura do Componente Retangular: 2.16 m; EI-REV-Pintura Acrílica Cor Branco Gelo 1, Largura do Componente Retangular: 0.015 m; EI-REV-Pintura Acrílica Cor Branco Gelo 1, Área de Seção Transversal do Componente: 0.0324 m2; EI-REV-Cerâmica 10x10 Azul, Altura do Componente Retangular: 0.1 m; EI-REV-Cerâmica 10x10 Azul, Largura do Componente Retangular: 0.02 m; EI-REV-Cerâmica 10x10 Azul, Área de Seção Transversal do Componente: 0.002 m2; EI-REV-Chapisco (interno) 1, Altura do Componente Retangular: 3.1 m; EI-REV-Chapisco (interno) 1, Largura do Componente Retangular: 0.005 m; EI-REV-Chapisco (interno) 1, Área de Seção Transversal do Componente: 0.0155 m2; EI-REV-Chapisco (interno) 2, Altura do Componente Retangular: 3.1 m; EI-REV-Chapisco (interno) 2, Largura do Componente Retangular: 0.005 m; EI-REV-Chapisco (interno) 2, Área de Seção Transversal do Componente: 0.0155 m2; EI-REV-Massa Corrida PVA (interna) 1, Altura do Componente Retangular: 2.16 m; EI-REV-Massa Corrida PVA (interna) 1, Largura do Componente Retangular: 0.005 m; EI-REV-Massa Corrida PVA (interna) 1, Área de Seção Transversal do Componente: 0.0108 m2; EI-REV-Cerâmica 30x40, Largura do Componente Retangular: 0.02 m; EI-REV-Emboço Interno, Altura do Componente Retangular: 3.1 m; EI-REV-Emboço Interno, Largura do Componente Retangular: 0.005 m; EI-REV-Emboço Interno, Área de Seção Transversal do Componente: 0.0155 m2; EI-REV-Massa única - Maior que 10m² 1, Largura do Componente Retangular: 0.005 m; EI-REV-Pintura Epóxi cor Laranja, Altura do Componente Retangular: 0.9 m; EI-REV-Pintura Epóxi cor Laranja, Largura do Componente Retangular: 0.02 m; EI-REV-Pintura Epóxi cor Laranja, Área de Seção Transversal do Componente: 0.018 m2; TIJOLO - CERAMICO 9x19x39 - espessura 15cm, Altura do Componente Retangular: 3.1 m; TIJOLO - CERAMICO 9x19x39 - espessura 15cm, Largura do Componente Retangular: 0.09 m; TIJOLO - CERAMICO 9x19x39 - espessura 15cm, Área de Seção Transversal do Componente: 0.279 m2
Name | 1_Bloco | EI-REV-Pintura Acrílica Cor Branco Gelo 1, Massa (kg) | EI-REV-Pintura Acrílica Cor Branco Gelo 1, Área de Componente Projetada (Líquida) (m2) | EI-REV-Pintura Acrílica Cor Branco Gelo 1, Área de Componente Projetada (Bruta) (m2) | EI-REV-Pintura Acrílica Cor Branco Gelo 1, Volume Componente (Líquido) (m3) | EI-REV-Pintura Acrílica Cor Branco Gelo 1, Volume do componente (Bruto) (m3) | EI-REV-Cerâmica 10x10 Azul, Massa (kg) | EI-REV-Cerâmica 10x10 Azul, Área de Componente Projetada (Líquida) (m2) | EI-REV-Cerâmica 10x10 Azul, Área de Componente Projetada (Bruta) (m2) | EI-REV-Cerâmica 10x10 Azul, Volume Componente (Líquido) (m3) | EI-REV-Cerâmica 10x10 Azul, Volume do componente (Bruto) (m3) | EI-REV-Chapisco (interno) 1, Massa (kg) | EI-REV-Chapisco (interno) 1, Área de Componente Projetada (Líquida) (m2) | EI-REV-Chapisco (interno) 1, Área de Componente Projetada (Bruta) (m2) | EI-REV-Chapisco (interno) 1, Volume Componente (Líquido) (m3) | EI-REV-Chapisco (interno) 1, Volume do componente (Bruto) (m3) | EI-REV-Chapisco (interno) 2, Massa (kg) | EI-REV-Chapisco (interno) 2, Área de Componente Projetada (Líquida) (m2) | EI-REV-Chapisco (interno) 2, Área de Componente Projetada (Bruta) (m2) | EI-REV-Chapisco (interno) 2, Volume Componente (Líquido) (m3) | EI-REV-Chapisco (interno) 2, Volume do componente (Bruto) (m3) | EI-REV-Massa Corrida PVA (interna) 1, Massa (kg) | EI-REV-Massa Corrida PVA (interna) 1, Área de Componente Projetada (Líquida) (m2) | EI-REV-Massa Corrida PVA (interna) 1, Área de Componente Projetada (Bruta) (m2) | EI-REV-Massa Corrida PVA (interna) 1, Volume Componente (Líquido) (m3) | EI-REV-Massa Corrida PVA (interna) 1, Volume do componente (Bruto) (m3) | EI-REV-Pintura Acrílica Cor Branco Gelo 2, Massa (kg) | EI-REV-Pintura Acrílica Cor Branco Gelo 2, Área de Componente Projetada (Líquida) (m2) | EI-REV-Pintura Acrílica Cor Branco Gelo 2, Área de Componente Projetada (Bruta) (m2) | EI-REV-Pintura Acrílica Cor Branco Gelo 2, Altura do Componente Retangular (m) = EI-REV-Massa única - Maior que 10m² 1, Altura do Componente Retangular (m) | EI-REV-Pintura Acrílica Cor Branco Gelo 2, Largura do Componente Retangular (m) | EI-REV-Pintura Acrílica Cor Branco Gelo 2, Área de Seção Transversal do Componente (m2) | EI-REV-Pintura Acrílica Cor Branco Gelo 2, Volume Componente (Líquido) (m3) | EI-REV-Pintura Acrílica Cor Branco Gelo 2, Volume do componente (Bruto) (m3) | EI-REV-Cerâmica 30x40, Massa (kg) | EI-REV-Cerâmica 30x40, Área de Componente Projetada (Líquida) (m2) | EI-REV-Cerâmica 30x40, Área de Componente Projetada (Bruta) (m2) | EI-REV-Cerâmica 30x40, Altura do Componente Retangular (m) | EI-REV-Cerâmica 30x40, Área de Seção Transversal do Componente (m2) | EI-REV-Cerâmica 30x40, Volume Componente (Líquido) (m3) | EI-REV-Cerâmica 30x40, Volume do componente (Bruto) (m3) | EI-REV-Emboço Interno, Massa (kg) | EI-REV-Emboço Interno, Área de Componente Projetada (Líquida) (m2) | EI-REV-Emboço Interno, Área de Componente Projetada (Bruta) (m2) | EI-REV-Emboço Interno, Volume Componente (Líquido) (m3) | EI-REV-Emboço Interno, Volume do componente (Bruto) (m3) | EI-REV-Massa única - Maior que 10m² 1, Massa (kg) | EI-REV-Massa única - Maior que 10m² 1, Área de Componente Projetada (Líquida) (m2) | EI-REV-Massa única - Maior que 10m² 1, Área de Componente Projetada (Bruta) (m2) | EI-REV-Massa única - Maior que 10m² 1, Área de Seção Transversal do Componente (m2) | EI-REV-Massa única - Maior que 10m² 1, Volume Componente (Líquido) (m3) | EI-REV-Massa única - Maior que 10m² 1, Volume do componente (Bruto) (m3) | EI-REV-Massa Corrida PVA (interna) 2, Massa (kg) | EI-REV-Massa Corrida PVA (interna) 2, Área de Componente Projetada (Líquida) (m2) | EI-REV-Massa Corrida PVA (interna) 2, Área de Componente Projetada (Bruta) (m2) | EI-REV-Massa Corrida PVA (interna) 2, Altura do Componente Retangular (m) | EI-REV-Massa Corrida PVA (interna) 2, Largura do Componente Retangular (m) | EI-REV-Massa Corrida PVA (interna) 2, Área de Seção Transversal do Componente (m2) | EI-REV-Massa Corrida PVA (interna) 2, Volume Componente (Líquido) (m3) | EI-REV-Massa Corrida PVA (interna) 2, Volume do componente (Bruto) (m3) | EI-REV-Pintura Epóxi cor Laranja, Massa (kg) | EI-REV-Pintura Epóxi cor Laranja, Área de Componente Projetada (Líquida) (m2) | EI-REV-Pintura Epóxi cor Laranja, Área de Componente Projetada (Bruta) (m2) | EI-REV-Pintura Epóxi cor Laranja, Volume Componente (Líquido) (m3) | EI-REV-Pintura Epóxi cor Laranja, Volume do componente (Bruto) (m3) | TIJOLO - CERAMICO 9x19x39 - espessura 15cm, Massa (kg) | TIJOLO - CERAMICO 9x19x39 - espessura 15cm, Área de Componente Projetada (Líquida) (m2) | TIJOLO - CERAMICO 9x19x39 - espessura 15cm, Área de Componente Projetada (Bruta) (m2) | TIJOLO - CERAMICO 9x19x39 - espessura 15cm, Volume Componente (Líquido) (m3) | TIJOLO - CERAMICO 9x19x39 - espessura 15cm, Volume do componente (Bruto) (m3) | EI-REV-Massa única - Maior que 10m² 2, Massa (kg) | EI-REV-Massa única - Maior que 10m² 2, Área de Componente Projetada (Líquida) (m2) | EI-REV-Massa única - Maior que 10m² 2, Área de Componente Projetada (Bruta) (m2) | EI-REV-Massa única - Maior que 10m² 2, Altura do Componente Retangular (m) | EI-REV-Massa única - Maior que 10m² 2, Largura do Componente Retangular (m) | EI-REV-Massa única - Maior que 10m² 2, Área de Seção Transversal do Componente (m2) | EI-REV-Massa única - Maior que 10m² 2, Volume Componente (Líquido) (m3) | EI-REV-Massa única - Maior que 10m² 2, Volume do componente (Bruto) (m3)
AL09 | BLOCO B | 153.067 | 9.04481 | 9.04481 | 0.117744 | 0.117744 | 16.4 | 0.41 | 0.41 | 0.0082 | 0.0082 | 71.7889 | 11.0444 | 11.0444 | 0.0552222 | 0.0552222 | 72.2315 | 11.1125 | 11.1125 | 0.0555627 | 0.0555627 | 47.1007 | 7.24627 | 7.24627 | 0.0362313 | 0.0362313 | 83.9237 | 7.30935 | 7.30935 | 1.77 | 0.00999998 | 0.0177 | 0.0645567 | 0.0645567 | 194.38 | 4.8595 | 4.8595 | 1.2 | 0.024 | 0.09719 | 0.09719 | 71.7099 | 11.0323 | 11.0323 | 0.0551615 | 0.0551615 | 36.5467 | 5.62257 | 5.62257 | 0.00885001 | 0.0281129 | 0.0281129 | 36.5469 | 5.62257 | 5.62257 | 1.77 | 0.00500003 | 0.00885005 | 0.028113 | 0.028113 | 96.9312 | 3.79548 | 3.79548 | 0.0745624 | 0.0745624 | 633.679 | 10.8655 | 10.8655 | 0.977899 | 0.977899 | Component Quantities - EI-REV-Chapisco (interno) 2: 2 with these values
AL09 | BLOCO B | 61.8451 | 3.9109 | 3.9109 | 0.0475732 | 0.0475732 | 7.53877 | 0.201997 | 0.201997 | 0.00376939 | 0.00376939 | 31.768 | 4.88739 | 4.88739 | 0.024437 | 0.024437 | 28.3682 | 4.36434 | 4.36434 | 0.0218217 | 0.0218217 | 18.361 | 2.82476 | 2.82476 | 0.0141238 | 0.0141238 | 21.9506 | 2.15862 | 2.15862 | 1.17 | 0.00999999 | 0.0117 | 0.0168851 | 0.0168851 | 132.31 | 3.55125 | 3.55125 | 1.8 | 0.036 | 0.066155 | 0.066155 | 31.717 | 4.87954 | 4.87954 | 0.0243977 | 0.0243977 | 9.2091 | 1.41678 | 1.41678 | 0.00585001 | 0.00708393 | 0.00708393 |  |  |  |  |  |  |  |  | 38.2651 | 1.59298 | 1.59298 | 0.0294347 | 0.0294347 | 269.72 | 4.62484 | 4.62484 | 0.416235 | 0.416235 | 28.2805 | 4.35084 | 4.35084 | 3.1 | 0.005 | 0.0155 | 0.0217542 | 0.0217542 | Component Quantities - EI-REV-Massa única - Maior que 10m² 1: 2 with these values
AL09 | BLOCO A | 112.647 | 6.929 | 7.929 | 0.0866514 | 0.101651 | 10.4 | 0.26 | 0.34 | 0.0052 | 0.0068 | 48.999 | 7.53858 | 9.25858 | 0.0376916 | 0.0462916 | 50.563 | 7.77919 | 9.49919 | 0.0388946 | 0.0474946 | 33.933 | 5.22046 | 6.22046 | 0.0261023 | 0.0311023 | 41.3085 | 3.77 | 3.978 | 1.17 | 0.00999999 | 0.0117 | 0.0317758 | 0.0338558 | 187.501 | 4.688 | 6.12 | 1.8 | 0.036 | 0.0937503 | 0.12239 | 48.9113 | 7.52508 | 9.24508 | 0.0376241 | 0.0462241 | 15.7899 | 2.42921 | 2.63721 | 0.00585001 | 0.012146 | 0.013186 | 15.7648 | 2.42536 | 2.63336 | 1.17 | 0.005 | 0.00585001 | 0.0121268 | 0.0131668 | 63.882 | 2.457 | 3.177 | 0.04914 | 0.06354 | 435.707 | 7.4758 | 9.1958 | 0.672387 | 0.827187 | 50.6507 | 7.79269 | 9.51269 | 3.1 | 0.005 | 0.0155 | 0.0389621 | 0.0475621
AL09 | BLOCO A | 36.5852 | 2.16 | 2.16 | 0.0281424 | 0.0281424 | 5 | 0.125 | 0.125 | 0.0025 | 0.0025 | 19.3694 | 2.98001 | 2.98001 | 0.0148996 | 0.0148996 | 18.0937 | 2.78365 | 2.78365 | 0.0139182 | 0.0139182 | 11.6617 | 1.7941 | 1.7941 | 0.0089705 | 0.0089705 | 12.9449 | 1.17 | 1.17 | 1.17 | 0.00999999 | 0.0117 | 0.00995758 | 0.00995758 | 73.0003 | 1.82501 | 1.82501 | 1.8 | 0.036 | 0.0365002 | 0.0365002 | 19.2823 | 2.96651 | 2.96651 | 0.0148325 | 0.0148325 | 6.33133 | 0.97405 | 0.97405 | 0.00585001 | 0.00487025 | 0.00487025 | 6.30631 | 0.9702 | 0.9702 | 1.17 | 0.005 | 0.00585001 | 0.004851 | 0.004851 | 23.4 | 0.9 | 0.9 | 0.018 | 0.018 | 201.554 | 3.456 | 3.456 | 0.31104 | 0.31104 | 17.98 | 2.76615 | 2.76615 | 3.1 | 0.005 | 0.0155 | 0.0138307 | 0.0138307

# IfcWall: FNDE-AL09-I2-I5 (laranja-vermelho) (sem rodameio) 150 x 3100 (2)
In: TÉRREO
Classification: Parede (Classificação Archicad); Material: TIJOLO - CERAMICO 9x19x39 - espessura 15cm, EI-REV-Chapisco (interno) (2), EI-REV-Cerâmica 30x40, EI-REV-Cerâmica 10x10 Vermelha, EI-REV-Emboço Interno, EI-REV-Massa única - Maior que 10m² (2), EI-REV-Massa Corrida PVA (interna) (2), EI-REV-Pintura Acrílica Cor Branco Gelo (2), EI-REV-Pintura Epóxi cor Laranja
FNDE - Alvenarias: Alvenaria de Vedação / Edificação; Sistemas de Cobertura: -; Esquadrias - Fechamentos metálicos e Gradis: -; 1_Bloco: BLOCO B; 0_ID: AL09
Pset_WallCommon - IsExternal: no; LoadBearing: no
Component Quantities - TIJOLO - CERAMICO 9x19x39 - espessura 15cm, Altura do Componente Retangular: 3.1 m; TIJOLO - CERAMICO 9x19x39 - espessura 15cm, Largura do Componente Retangular: 0.09 m; TIJOLO - CERAMICO 9x19x39 - espessura 15cm, Área de Seção Transversal do Componente: 0.279 m2; EI-REV-Chapisco (interno) 1, Altura do Componente Retangular: 3.1 m; EI-REV-Chapisco (interno) 1, Largura do Componente Retangular: 0.005 m; EI-REV-Chapisco (interno) 1, Área de Seção Transversal do Componente: 0.0155 m2; EI-REV-Cerâmica 30x40, Largura do Componente Retangular: 0.02 m; EI-REV-Cerâmica 10x10 Vermelha, Altura do Componente Retangular: 0.1 m; EI-REV-Cerâmica 10x10 Vermelha, Largura do Componente Retangular: 0.02 m; EI-REV-Cerâmica 10x10 Vermelha, Área de Seção Transversal do Componente: 0.002 m2; EI-REV-Emboço Interno, Altura do Componente Retangular: 3.1 m; EI-REV-Emboço Interno, Largura do Componente Retangular: 0.005 m; EI-REV-Emboço Interno, Área de Seção Transversal do Componente: 0.0155 m2; EI-REV-Massa única - Maior que 10m² 1, Largura do Componente Retangular: 0.005 m; EI-REV-Chapisco (interno) 2, Altura do Componente Retangular: 3.1 m; EI-REV-Chapisco (interno) 2, Largura do Componente Retangular: 0.005 m; EI-REV-Chapisco (interno) 2, Área de Seção Transversal do Componente: 0.0155 m2; EI-REV-Pintura Epóxi cor Laranja, Altura do Componente Retangular: 0.9 m; EI-REV-Pintura Epóxi cor Laranja, Largura do Componente Retangular: 0.02 m; EI-REV-Pintura Epóxi cor Laranja, Área de Seção Transversal do Componente: 0.018 m2; EI-REV-Massa única - Maior que 10m² 2, Área de Seção Transversal do Componente: 0.0155 m2; EI-REV-Massa Corrida PVA (interna) 2, Altura do Componente Retangular: 2.16 m; EI-REV-Massa Corrida PVA (interna) 2, Largura do Componente Retangular: 0.005 m; EI-REV-Massa Corrida PVA (interna) 2, Área de Seção Transversal do Componente: 0.0108001 m2; EI-REV-Pintura Acrílica Cor Branco Gelo 2, Altura do Componente Retangular: 2.16 m; EI-REV-Pintura Acrílica Cor Branco Gelo 2, Largura do Componente Retangular: 0.015 m; EI-REV-Pintura Acrílica Cor Branco Gelo 2, Área de Seção Transversal do Componente: 0.0324 m2
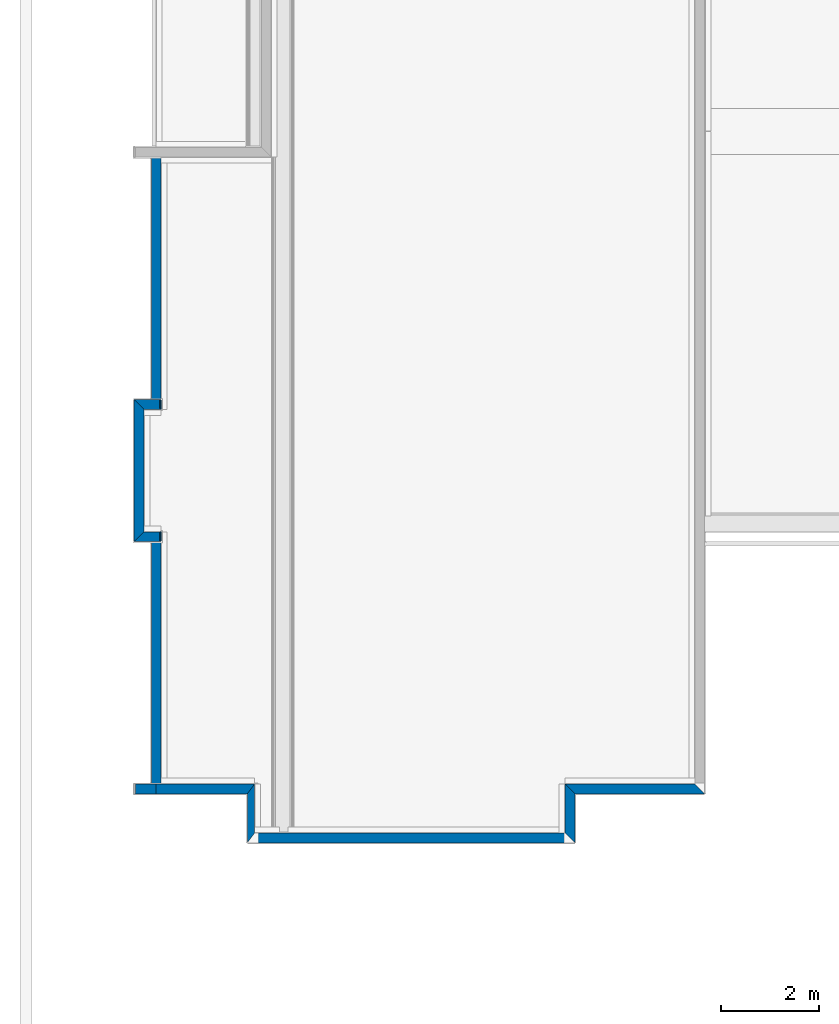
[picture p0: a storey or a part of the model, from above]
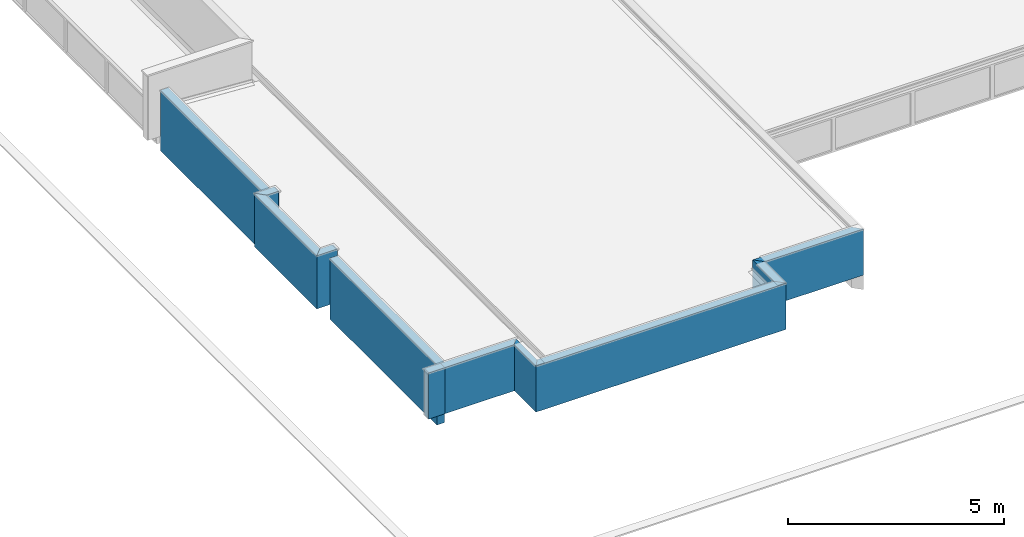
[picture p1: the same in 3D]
Properties of the parts of a building model (IFC4), part 11 of 22

# IfcWall: FNDE-AL09-I2-I5 (laranja-vermelho) (sem rodameio) 150 x 3100 (2)
Name | TIJOLO - CERAMICO 9x19x39 - espessura 15cm, Massa (kg) | TIJOLO - CERAMICO 9x19x39 - espessura 15cm, Área de Componente Projetada (Líquida) (m2) = TIJOLO - CERAMICO 9x19x39 - espessura 15cm, Área de Componente Projetada (Bruta) (m2) | TIJOLO - CERAMICO 9x19x39 - espessura 15cm, Volume Componente (Líquido) (m3) = TIJOLO - CERAMICO 9x19x39 - espessura 15cm, Volume do componente (Bruto) (m3) | EI-REV-Chapisco (interno) 1, Massa (kg) | EI-REV-Chapisco (interno) 1, Área de Componente Projetada (Líquida) (m2) = EI-REV-Chapisco (interno) 1, Área de Componente Projetada (Bruta) (m2) | EI-REV-Chapisco (interno) 1, Volume Componente (Líquido) (m3) = EI-REV-Chapisco (interno) 1, Volume do componente (Bruto) (m3) | EI-REV-Cerâmica 30x40, Massa (kg) | EI-REV-Cerâmica 30x40, Área de Componente Projetada (Líquida) (m2) = EI-REV-Cerâmica 30x40, Área de Componente Projetada (Bruta) (m2) | EI-REV-Cerâmica 30x40, Altura do Componente Retangular (m) | EI-REV-Cerâmica 30x40, Área de Seção Transversal do Componente (m2) | EI-REV-Cerâmica 30x40, Volume Componente (Líquido) (m3) = EI-REV-Cerâmica 30x40, Volume do componente (Bruto) (m3) | EI-REV-Cerâmica 10x10 Vermelha, Massa (kg) | EI-REV-Cerâmica 10x10 Vermelha, Área de Componente Projetada (Líquida) (m2) = EI-REV-Cerâmica 10x10 Vermelha, Área de Componente Projetada (Bruta) (m2) | EI-REV-Cerâmica 10x10 Vermelha, Volume Componente (Líquido) (m3) = EI-REV-Cerâmica 10x10 Vermelha, Volume do componente (Bruto) (m3) | EI-REV-Emboço Interno, Massa (kg) | EI-REV-Emboço Interno, Área de Componente Projetada (Líquida) (m2) = EI-REV-Emboço Interno, Área de Componente Projetada (Bruta) (m2) | EI-REV-Emboço Interno, Volume Componente (Líquido) (m3) = EI-REV-Emboço Interno, Volume do componente (Bruto) (m3) | EI-REV-Massa única - Maior que 10m² 1, Massa (kg) | EI-REV-Massa única - Maior que 10m² 1, Área de Componente Projetada (Líquida) (m2) = EI-REV-Massa única - Maior que 10m² 1, Área de Componente Projetada (Bruta) (m2) | EI-REV-Massa única - Maior que 10m² 1, Altura do Componente Retangular (m) = EI-REV-Pintura Acrílica Cor Branco Gelo 1, Altura do Componente Retangular (m) | EI-REV-Massa única - Maior que 10m² 1, Área de Seção Transversal do Componente (m2) | EI-REV-Massa única - Maior que 10m² 1, Volume Componente (Líquido) (m3) = EI-REV-Massa única - Maior que 10m² 1, Volume do componente (Bruto) (m3) | EI-REV-Pintura Acrílica Cor Branco Gelo 1, Massa (kg) | EI-REV-Pintura Acrílica Cor Branco Gelo 1, Área de Componente Projetada (Líquida) (m2) = EI-REV-Pintura Acrílica Cor Branco Gelo 1, Área de Componente Projetada (Bruta) (m2) | EI-REV-Pintura Acrílica Cor Branco Gelo 1, Largura do Componente Retangular (m) | EI-REV-Pintura Acrílica Cor Branco Gelo 1, Área de Seção Transversal do Componente (m2) | EI-REV-Pintura Acrílica Cor Branco Gelo 1, Volume Componente (Líquido) (m3) = EI-REV-Pintura Acrílica Cor Branco Gelo 1, Volume do componente (Bruto) (m3) | EI-REV-Chapisco (interno) 2, Massa (kg) | EI-REV-Chapisco (interno) 2, Área de Componente Projetada (Líquida) (m2) = EI-REV-Chapisco (interno) 2, Área de Componente Projetada (Bruta) (m2) | EI-REV-Chapisco (interno) 2, Volume Componente (Líquido) (m3) = EI-REV-Chapisco (interno) 2, Volume do componente (Bruto) (m3) | EI-REV-Pintura Epóxi cor Laranja, Massa (kg) | EI-REV-Pintura Epóxi cor Laranja, Área de Componente Projetada (Líquida) (m2) = EI-REV-Pintura Epóxi cor Laranja, Área de Componente Projetada (Bruta) (m2) | EI-REV-Pintura Epóxi cor Laranja, Volume Componente (Líquido) (m3) = EI-REV-Pintura Epóxi cor Laranja, Volume do componente (Bruto) (m3) | EI-REV-Massa única - Maior que 10m² 2, Massa (kg) | EI-REV-Massa única - Maior que 10m² 2, Área de Componente Projetada (Líquida) (m2) = EI-REV-Massa única - Maior que 10m² 2, Área de Componente Projetada (Bruta) (m2) | EI-REV-Massa única - Maior que 10m² 2, Volume Componente (Líquido) (m3) = EI-REV-Massa única - Maior que 10m² 2, Volume do componente (Bruto) (m3) | EI-REV-Massa Corrida PVA (interna) 2, Massa (kg) | EI-REV-Massa Corrida PVA (interna) 2, Área de Componente Projetada (Líquida) (m2) = EI-REV-Massa Corrida PVA (interna) 2, Área de Componente Projetada (Bruta) (m2) | EI-REV-Massa Corrida PVA (interna) 2, Volume Componente (Líquido) (m3) = EI-REV-Massa Corrida PVA (interna) 2, Volume do componente (Bruto) (m3) | EI-REV-Pintura Acrílica Cor Branco Gelo 2, Massa (kg) | EI-REV-Pintura Acrílica Cor Branco Gelo 2, Área de Componente Projetada (Líquida) (m2) = EI-REV-Pintura Acrílica Cor Branco Gelo 2, Área de Componente Projetada (Bruta) (m2) | EI-REV-Pintura Acrílica Cor Branco Gelo 2, Volume Componente (Líquido) (m3) = EI-REV-Pintura Acrílica Cor Branco Gelo 2, Volume do componente (Bruto) (m3)
AL09 | 22.0404 | 0.377921 | 0.0340129 | 6.11344 | 0.940529 | 0.00470265 | 15.8388 | 0.39597 | 1.2 | 0.024 | 0.0079194 | 1.3199 | 0.0329975 | 0.00065995 | 6.06924 | 0.933729 | 0.00466865 | 3.08856 | 0.475163 | 1.77 | 0.00885001 | 0.00237581 | 2.36546 | 0.229306 | 0.00999998 | 0.0177 | 0.00181958 | 1.99829 | 0.307429 | 0.00153715 | 1.87142 | 0.0719776 | 0.00143955 | 1.91054 | 0.293929 | 0.00146965 | 1.23665 | 0.190253 | 0.000951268 | 3.81065 | 0.260496 | 0.00293127 | Component Quantities - EI-REV-Massa Corrida PVA (interna) 1, Massa: 3.08857 kg; EI-REV-Massa Corrida PVA (interna) 1, Área de Componente Projetada (Líquida): 0.475163 m2; EI-REV-Massa Corrida PVA (interna) 1, Área de Componente Projetada (Bruta): 0.475163 m2; EI-REV-Massa Corrida PVA (interna) 1, Altura do Componente Retangular: 1.77 m; EI-REV-Massa Corrida PVA (interna) 1, Largura do Componente Retangular: 0.00500003 m; EI-REV-Massa Corrida PVA (interna) 1, Área de Seção Transversal do Componente: 0.00885005 m2; EI-REV-Massa Corrida PVA (interna) 1, Volume Componente (Líquido): 0.00237583 m3; EI-REV-Massa Corrida PVA (interna) 1, Volume do componente (Bruto): 0.00237583 m3
AL09 | 255.096 | 4.37408 | 0.393667 | 31.7689 | 4.88753 | 0.0244376 | 132.767 | 3.58735 | 1.8 | 0.036 | 0.0663833 | 7.56415 | 0.204003 | 0.00378207 | 31.7179 | 4.87968 | 0.0243984 | 9.20936 | 1.41682 | 1.17 | 0.00585001 | 0.00708412 | 22.1119 | 2.15868 | 0.00999999 | 0.0117 | 0.0170092 | 28.4055 | 4.37007 | 0.0218504 | 39.1602 | 1.71002 | 0.0301233 | 28.3795 | 4.36607 | 0.0218304 | 18.426 | 2.83475 | 0.0141738 | 62.6052 | 4.0397 | 0.0481579 | Component Quantities - EI-REV-Massa única - Maior que 10m² 1: 2 with these values

# IfcWall: FNDE-AL09-I2-I5 (laranja-vermelho) 150 x 3100, AL09
In: TÉRREO
Classification: Parede (Classificação Archicad); Material: TIJOLO - CERAMICO 9x19x39 - espessura 15cm, EI-REV-Chapisco (interno) (2), EI-REV-Cerâmica 30x40, EI-REV-Cerâmica 10x10 Vermelha, EI-REV-Emboço Interno, EI-REV-Massa única - Maior que 10m² (2), EI-REV-Massa Corrida PVA (interna) (2), EI-REV-Pintura Acrílica Cor Branco Gelo (2), EI-REV-Pintura Epóxi cor Laranja
FNDE - Alvenarias: Alvenaria de Vedação / Edificação; Sistemas de Cobertura: -; Esquadrias - Fechamentos metálicos e Gradis: -; 1_Bloco: BLOCO B; 0_ID: AL09
Pset_WallCommon - IsExternal: no; LoadBearing: no
Component Quantities - TIJOLO - CERAMICO 9x19x39 - espessura 15cm, Massa: 508.613 kg; TIJOLO - CERAMICO 9x19x39 - espessura 15cm, Área de Componente Projetada (Líquida): 8.72108 m2; TIJOLO - CERAMICO 9x19x39 - espessura 15cm, Área de Componente Projetada (Bruta): 8.72108 m2; TIJOLO - CERAMICO 9x19x39 - espessura 15cm, Altura do Componente Retangular: 3.1 m; TIJOLO - CERAMICO 9x19x39 - espessura 15cm, Largura do Componente Retangular: 0.09 m; TIJOLO - CERAMICO 9x19x39 - espessura 15cm, Área de Seção Transversal do Componente: 0.279 m2; TIJOLO - CERAMICO 9x19x39 - espessura 15cm, Volume Componente (Líquido): 0.784897 m3; TIJOLO - CERAMICO 9x19x39 - espessura 15cm, Volume do componente (Bruto): 0.784897 m3; EI-REV-Chapisco (interno) 1, Massa: 54.0974 kg; EI-REV-Chapisco (interno) 1, Área de Componente Projetada (Líquida): 8.32268 m2; EI-REV-Chapisco (interno) 1, Área de Componente Projetada (Bruta): 8.32268 m2; EI-REV-Chapisco (interno) 1, Altura do Componente Retangular: 3.1 m; EI-REV-Chapisco (interno) 1, Largura do Componente Retangular: 0.005 m; EI-REV-Chapisco (interno) 1, Área de Seção Transversal do Componente: 0.0155 m2; EI-REV-Chapisco (interno) 1, Volume Componente (Líquido): 0.0416134 m3; EI-REV-Chapisco (interno) 1, Volume do componente (Bruto): 0.0416134 m3; EI-REV-Cerâmica 30x40, Massa: 150.054 kg; EI-REV-Cerâmica 30x40, Área de Componente Projetada (Líquida): 4.01954 m2; EI-REV-Cerâmica 30x40, Área de Componente Projetada (Bruta): 4.01954 m2; EI-REV-Cerâmica 30x40, Altura do Componente Retangular: 1.2 m; EI-REV-Cerâmica 30x40, Largura do Componente Retangular: 0.02 m; EI-REV-Cerâmica 30x40, Área de Seção Transversal do Componente: 0.024 m2; EI-REV-Cerâmica 30x40, Volume Componente (Líquido): 0.075027 m3; EI-REV-Cerâmica 30x40, Volume do componente (Bruto): 0.075027 m3; EI-REV-Cerâmica 10x10 Vermelha, Massa: 12.7062 kg; EI-REV-Cerâmica 10x10 Vermelha, Área de Componente Projetada (Líquida): 0.340003 m2; EI-REV-Cerâmica 10x10 Vermelha, Área de Componente Projetada (Bruta): 0.340003 m2; EI-REV-Cerâmica 10x10 Vermelha, Altura do Componente Retangular: 0.1 m; EI-REV-Cerâmica 10x10 Vermelha, Largura do Componente Retangular: 0.02 m; EI-REV-Cerâmica 10x10 Vermelha, Área de Seção Transversal do Componente: 0.002 m2; EI-REV-Cerâmica 10x10 Vermelha, Volume Componente (Líquido): 0.00635308 m3; EI-REV-Cerâmica 10x10 Vermelha, Volume do componente (Bruto): 0.00635308 m3; EI-REV-Emboço Interno, Massa: 54.0626 kg; EI-REV-Emboço Interno, Área de Componente Projetada (Líquida): 8.31733 m2; EI-REV-Emboço Interno, Área de Componente Projetada (Bruta): 8.31733 m2; EI-REV-Emboço Interno, Altura do Componente Retangular: 3.1 m; EI-REV-Emboço Interno, Largura do Componente Retangular: 0.005 m; EI-REV-Emboço Interno, Área de Seção Transversal do Componente: 0.0155 m2; EI-REV-Emboço Interno, Volume Componente (Líquido): 0.0415866 m3; EI-REV-Emboço Interno, Volume do componente (Bruto): 0.0415866 m3; EI-REV-Massa única - Maior que 10m² 1, Massa: 27.6058 kg; EI-REV-Massa única - Maior que 10m² 1, Área de Componente Projetada (Líquida): 4.24704 m2; EI-REV-Massa única - Maior que 10m² 1, Área de Componente Projetada (Bruta): 4.24704 m2; EI-REV-Massa única - Maior que 10m² 1, Altura do Componente Retangular: 1.77 m; EI-REV-Massa única - Maior que 10m² 1, Largura do Componente Retangular: 0.005 m; EI-REV-Massa única - Maior que 10m² 1, Área de Seção Transversal do Componente: 0.00885001 m2; EI-REV-Massa única - Maior que 10m² 1, Volume Componente (Líquido): 0.0212352 m3; EI-REV-Massa única - Maior que 10m² 1, Volume do componente (Bruto): 0.0212352 m3; EI-REV-Massa Corrida PVA (interna) 1, Massa: 27.6059 kg; EI-REV-Massa Corrida PVA (interna) 1, Área de Componente Projetada (Líquida): 4.24704 m2; EI-REV-Massa Corrida PVA (interna) 1, Área de Componente Projetada (Bruta): 4.24704 m2; EI-REV-Massa Corrida PVA (interna) 1, Altura do Componente Retangular: 1.77 m; EI-REV-Massa Corrida PVA (interna) 1, Largura do Componente Retangular: 0.00500003 m; EI-REV-Massa Corrida PVA (interna) 1, Área de Seção Transversal do Componente: 0.00885005 m2; EI-REV-Massa Corrida PVA (interna) 1, Volume Componente (Líquido): 0.0212353 m3; EI-REV-Massa Corrida PVA (interna) 1, Volume do componente (Bruto): 0.0212353 m3; EI-REV-Pintura Acrílica Cor Branco Gelo 1, Massa: 71.7637 kg; EI-REV-Pintura Acrílica Cor Branco Gelo 1, Área de Componente Projetada (Líquida): 6.434 m2; EI-REV-Pintura Acrílica Cor Branco Gelo 1, Área de Componente Projetada (Bruta): 6.434 m2; EI-REV-Pintura Acrílica Cor Branco Gelo 1, Altura do Componente Retangular: 1.77 m; EI-REV-Pintura Acrílica Cor Branco Gelo 1, Largura do Componente Retangular: 0.00999998 m; EI-REV-Pintura Acrílica Cor Branco Gelo 1, Área de Seção Transversal do Componente: 0.0177 m2; EI-REV-Pintura Acrílica Cor Branco Gelo 1, Volume Componente (Líquido): 0.0552029 m3; EI-REV-Pintura Acrílica Cor Branco Gelo 1, Volume do componente (Bruto): 0.0552029 m3; EI-REV-Chapisco (interno) 2, Massa: 56.5993 kg; EI-REV-Chapisco (interno) 2, Área de Componente Projetada (Líquida): 8.70758 m2; EI-REV-Chapisco (interno) 2, Área de Componente Projetada (Bruta): 8.70758 m2; EI-REV-Chapisco (interno) 2, Altura do Componente Retangular: 3.1 m; EI-REV-Chapisco (interno) 2, Largura do Componente Retangular: 0.005 m; EI-REV-Chapisco (interno) 2, Área de Seção Transversal do Componente: 0.0155 m2; EI-REV-Chapisco (interno) 2, Volume Componente (Líquido): 0.0435379 m3; EI-REV-Chapisco (interno) 2, Volume do componente (Bruto): 0.0435379 m3; EI-REV-Pintura Epóxi cor Laranja, Massa: 75.1673 kg; EI-REV-Pintura Epóxi cor Laranja, Área de Componente Projetada (Líquida): 2.92502 m2; EI-REV-Pintura Epóxi cor Laranja, Área de Componente Projetada (Bruta): 2.92502 m2; EI-REV-Pintura Epóxi cor Laranja, Altura do Componente Retangular: 0.9 m; EI-REV-Pintura Epóxi cor Laranja, Largura do Componente Retangular: 0.02 m; EI-REV-Pintura Epóxi cor Laranja, Área de Seção Transversal do Componente: 0.018 m2; EI-REV-Pintura Epóxi cor Laranja, Volume Componente (Líquido): 0.057821 m3; EI-REV-Pintura Epóxi cor Laranja, Volume do componente (Bruto): 0.057821 m3; EI-REV-Massa única - Maior que 10m² 2, Massa: 56.5115 kg; EI-REV-Massa única - Maior que 10m² 2, Área de Componente Projetada (Líquida): 8.69408 m2; EI-REV-Massa única - Maior que 10m² 2, Área de Componente Projetada (Bruta): 8.69408 m2; EI-REV-Massa única - Maior que 10m² 2, Área de Seção Transversal do Componente: 0.0155 m2; EI-REV-Massa única - Maior que 10m² 2, Volume Componente (Líquido): 0.0434704 m3; EI-REV-Massa única - Maior que 10m² 2, Volume do componente (Bruto): 0.0434704 m3; EI-REV-Massa Corrida PVA (interna) 2, Massa: 36.78 kg; EI-REV-Massa Corrida PVA (interna) 2, Área de Componente Projetada (Líquida): 5.65845 m2; EI-REV-Massa Corrida PVA (interna) 2, Área de Componente Projetada (Bruta): 5.65845 m2; EI-REV-Massa Corrida PVA (interna) 2, Altura do Componente Retangular: 2.16 m; EI-REV-Massa Corrida PVA (interna) 2, Largura do Componente Retangular: 0.005 m; EI-REV-Massa Corrida PVA (interna) 2, Área de Seção Transversal do Componente: 0.0108001 m2; EI-REV-Massa Corrida PVA (interna) 2, Volume Componente (Líquido): 0.0282923 m3; EI-REV-Massa Corrida PVA (interna) 2, Volume do componente (Bruto): 0.0282923 m3; EI-REV-Pintura Acrílica Cor Branco Gelo 2, Massa: 118.665 kg; EI-REV-Pintura Acrílica Cor Branco Gelo 2, Área de Componente Projetada (Líquida): 7.02005 m2; EI-REV-Pintura Acrílica Cor Branco Gelo 2, Área de Componente Projetada (Bruta): 7.02005 m2; EI-REV-Pintura Acrílica Cor Branco Gelo 2, Altura do Componente Retangular: 2.16 m; EI-REV-Pintura Acrílica Cor Branco Gelo 2, Largura do Componente Retangular: 0.015 m; EI-REV-Pintura Acrílica Cor Branco Gelo 2, Área de Seção Transversal do Componente: 0.0324 m2; EI-REV-Pintura Acrílica Cor Branco Gelo 2, Volume Componente (Líquido): 0.0912809 m3; EI-REV-Pintura Acrílica Cor Branco Gelo 2, Volume do componente (Bruto): 0.0912809 m3

# IfcWall: FNDE-AL09-I2-I7 (laranja-amarela) 150 x 3100 (6)
In: TÉRREO
Classification: Parede (Classificação Archicad); Material: EI-REV-Chapisco (interno) (2), EI-REV-Cerâmica 10x10 Amarela, EI-REV-Cerâmica 10x10 Branca, EI-REV-Emboço Interno, EI-REV-Massa única - Maior que 10m² (2), EI-REV-Massa Corrida PVA (interna) (2), EI-REV-Pintura Acrílica Cor Branco Gelo (2), EI-REV-Pintura Epóxi cor Laranja, TIJOLO - CERAMICO 9x19x39 - espessura 15cm
FNDE - Alvenarias: Alvenaria de Vedação / Edificação; Sistemas de Cobertura: -; Esquadrias - Fechamentos metálicos e Gradis: -; 0_ID: AL09
Pset_WallCommon - IsExternal: no; LoadBearing: no
Component Quantities - EI-REV-Chapisco (interno) 1, Altura do Componente Retangular: 3.1 m; EI-REV-Chapisco (interno) 1, Largura do Componente Retangular: 0.005 m; EI-REV-Chapisco (interno) 1, Área de Seção Transversal do Componente: 0.0155 m2; EI-REV-Cerâmica 10x10 Amarela, Altura do Componente Retangular: 0.9 m; EI-REV-Cerâmica 10x10 Amarela, Largura do Componente Retangular: 0.02 m; EI-REV-Cerâmica 10x10 Amarela, Área de Seção Transversal do Componente: 0.018 m2; EI-REV-Cerâmica 10x10 Branca, Altura do Componente Retangular: 0.1 m; EI-REV-Cerâmica 10x10 Branca, Largura do Componente Retangular: 0.02 m; EI-REV-Cerâmica 10x10 Branca, Área de Seção Transversal do Componente: 0.002 m2; EI-REV-Massa única - Maior que 10m² 1, Altura do Componente Retangular: 2.06 m; EI-REV-Massa única - Maior que 10m² 1, Largura do Componente Retangular: 0.00499999 m; EI-REV-Massa única - Maior que 10m² 1, Área de Seção Transversal do Componente: 0.0103 m2; EI-REV-Massa Corrida PVA (interna) 1, Altura do Componente Retangular: 2.06 m; EI-REV-Massa Corrida PVA (interna) 1, Largura do Componente Retangular: 0.00500002 m; EI-REV-Massa Corrida PVA (interna) 1, Área de Seção Transversal do Componente: 0.0103 m2; EI-REV-Pintura Acrílica Cor Branco Gelo 1, Altura do Componente Retangular: 2.06 m; EI-REV-Pintura Acrílica Cor Branco Gelo 1, Largura do Componente Retangular: 0.01 m; EI-REV-Pintura Acrílica Cor Branco Gelo 1, Área de Seção Transversal do Componente: 0.0206 m2; EI-REV-Chapisco (interno) 2, Altura do Componente Retangular: 3.1 m; EI-REV-Chapisco (interno) 2, Largura do Componente Retangular: 0.005 m; EI-REV-Chapisco (interno) 2, Área de Seção Transversal do Componente: 0.0155 m2; EI-REV-Pintura Epóxi cor Laranja, Altura do Componente Retangular: 0.9 m; EI-REV-Pintura Epóxi cor Laranja, Largura do Componente Retangular: 0.02 m; EI-REV-Pintura Epóxi cor Laranja, Área de Seção Transversal do Componente: 0.018 m2; EI-REV-Massa única - Maior que 10m² 2, Área de Seção Transversal do Componente: 0.0155 m2; EI-REV-Massa Corrida PVA (interna) 2, Altura do Componente Retangular: 2.16 m; EI-REV-Massa Corrida PVA (interna) 2, Largura do Componente Retangular: 0.005 m; EI-REV-Massa Corrida PVA (interna) 2, Área de Seção Transversal do Componente: 0.0108001 m2; EI-REV-Pintura Acrílica Cor Branco Gelo 2, Altura do Componente Retangular: 2.16 m; EI-REV-Pintura Acrílica Cor Branco Gelo 2, Largura do Componente Retangular: 0.015 m; EI-REV-Pintura Acrílica Cor Branco Gelo 2, Área de Seção Transversal do Componente: 0.0324 m2; TIJOLO - CERAMICO 9x19x39 - espessura 15cm, Altura do Componente Retangular: 3.1 m; TIJOLO - CERAMICO 9x19x39 - espessura 15cm, Largura do Componente Retangular: 0.09 m; TIJOLO - CERAMICO 9x19x39 - espessura 15cm, Área de Seção Transversal do Componente: 0.279 m2
Name | 1_Bloco | EI-REV-Chapisco (interno) 1, Massa (kg) | EI-REV-Chapisco (interno) 1, Área de Componente Projetada (Líquida) (m2) | EI-REV-Chapisco (interno) 1, Área de Componente Projetada (Bruta) (m2) | EI-REV-Chapisco (interno) 1, Volume Componente (Líquido) (m3) | EI-REV-Chapisco (interno) 1, Volume do componente (Bruto) (m3) | EI-REV-Cerâmica 10x10 Amarela, Massa (kg) | EI-REV-Cerâmica 10x10 Amarela, Área de Componente Projetada (Líquida) (m2) | EI-REV-Cerâmica 10x10 Amarela, Área de Componente Projetada (Bruta) (m2) | EI-REV-Cerâmica 10x10 Amarela, Volume Componente (Líquido) (m3) | EI-REV-Cerâmica 10x10 Amarela, Volume do componente (Bruto) (m3) | EI-REV-Cerâmica 10x10 Branca, Massa (kg) | EI-REV-Cerâmica 10x10 Branca, Área de Componente Projetada (Líquida) (m2) | EI-REV-Cerâmica 10x10 Branca, Área de Componente Projetada (Bruta) (m2) | EI-REV-Cerâmica 10x10 Branca, Volume Componente (Líquido) (m3) | EI-REV-Cerâmica 10x10 Branca, Volume do componente (Bruto) (m3) | EI-REV-Massa única - Maior que 10m² 1, Massa (kg) | EI-REV-Massa única - Maior que 10m² 1, Área de Componente Projetada (Líquida) (m2) | EI-REV-Massa única - Maior que 10m² 1, Área de Componente Projetada (Bruta) (m2) | EI-REV-Massa única - Maior que 10m² 1, Volume Componente (Líquido) (m3) | EI-REV-Massa única - Maior que 10m² 1, Volume do componente (Bruto) (m3) | EI-REV-Massa Corrida PVA (interna) 1, Massa (kg) | EI-REV-Massa Corrida PVA (interna) 1, Área de Componente Projetada (Líquida) (m2) | EI-REV-Massa Corrida PVA (interna) 1, Área de Componente Projetada (Bruta) (m2) | EI-REV-Massa Corrida PVA (interna) 1, Volume Componente (Líquido) (m3) | EI-REV-Massa Corrida PVA (interna) 1, Volume do componente (Bruto) (m3) | EI-REV-Pintura Acrílica Cor Branco Gelo 1, Massa (kg) | EI-REV-Pintura Acrílica Cor Branco Gelo 1, Área de Componente Projetada (Líquida) (m2) | EI-REV-Pintura Acrílica Cor Branco Gelo 1, Área de Componente Projetada (Bruta) (m2) | EI-REV-Pintura Acrílica Cor Branco Gelo 1, Volume Componente (Líquido) (m3) | EI-REV-Pintura Acrílica Cor Branco Gelo 1, Volume do componente (Bruto) (m3) | EI-REV-Chapisco (interno) 2, Massa (kg) | EI-REV-Chapisco (interno) 2, Área de Componente Projetada (Líquida) (m2) | EI-REV-Chapisco (interno) 2, Área de Componente Projetada (Bruta) (m2) | EI-REV-Chapisco (interno) 2, Volume Componente (Líquido) (m3) | EI-REV-Chapisco (interno) 2, Volume do componente (Bruto) (m3) | EI-REV-Pintura Epóxi cor Laranja, Massa (kg) | EI-REV-Pintura Epóxi cor Laranja, Área de Componente Projetada (Líquida) (m2) | EI-REV-Pintura Epóxi cor Laranja, Área de Componente Projetada (Bruta) (m2) | EI-REV-Pintura Epóxi cor Laranja, Volume Componente (Líquido) (m3) | EI-REV-Pintura Epóxi cor Laranja, Volume do componente (Bruto) (m3) | EI-REV-Massa única - Maior que 10m² 2, Massa (kg) | EI-REV-Massa única - Maior que 10m² 2, Área de Componente Projetada (Líquida) (m2) | EI-REV-Massa única - Maior que 10m² 2, Área de Componente Projetada (Bruta) (m2) | EI-REV-Massa única - Maior que 10m² 2, Volume Componente (Líquido) (m3) | EI-REV-Massa única - Maior que 10m² 2, Volume do componente (Bruto) (m3) | EI-REV-Massa Corrida PVA (interna) 2, Massa (kg) | EI-REV-Massa Corrida PVA (interna) 2, Área de Componente Projetada (Líquida) (m2) | EI-REV-Massa Corrida PVA (interna) 2, Área de Componente Projetada (Bruta) (m2) | EI-REV-Massa Corrida PVA (interna) 2, Volume Componente (Líquido) (m3) | EI-REV-Massa Corrida PVA (interna) 2, Volume do componente (Bruto) (m3) | EI-REV-Pintura Acrílica Cor Branco Gelo 2, Massa (kg) | EI-REV-Pintura Acrílica Cor Branco Gelo 2, Área de Componente Projetada (Líquida) (m2) | EI-REV-Pintura Acrílica Cor Branco Gelo 2, Área de Componente Projetada (Bruta) (m2) | EI-REV-Pintura Acrílica Cor Branco Gelo 2, Volume Componente (Líquido) (m3) | EI-REV-Pintura Acrílica Cor Branco Gelo 2, Volume do componente (Bruto) (m3) | TIJOLO - CERAMICO 9x19x39 - espessura 15cm, Massa (kg) | TIJOLO - CERAMICO 9x19x39 - espessura 15cm, Área de Componente Projetada (Líquida) (m2) | TIJOLO - CERAMICO 9x19x39 - espessura 15cm, Área de Componente Projetada (Bruta) (m2) | TIJOLO - CERAMICO 9x19x39 - espessura 15cm, Volume Componente (Líquido) (m3) | TIJOLO - CERAMICO 9x19x39 - espessura 15cm, Volume do componente (Bruto) (m3) | EI-REV-Emboço Interno, Massa (kg) | EI-REV-Emboço Interno, Área de Componente Projetada (Líquida) (m2) | EI-REV-Emboço Interno, Área de Componente Projetada (Bruta) (m2) | EI-REV-Emboço Interno, Altura do Componente Retangular (m) | EI-REV-Emboço Interno, Largura do Componente Retangular (m) | EI-REV-Emboço Interno, Área de Seção Transversal do Componente (m2) | EI-REV-Emboço Interno, Volume Componente (Líquido) (m3) | EI-REV-Emboço Interno, Volume do componente (Bruto) (m3)
AL09 | BLOCO B | 69.8301 | 10.7431 | 12.8431 | 0.0537155 | 0.0642155 | 174.585 | 4.41 | 4.41 | 0.0872923 | 0.0872923 | 19.3983 | 0.49 | 0.49 | 0.00969914 | 0.00969914 | 37.6564 | 5.7933 | 7.8933 | 0.0289665 | 0.0394665 | 38.4709 | 6.0174 | 8.1174 | 0.029593 | 0.040093 | 85.547 | 7.98969 | 10.0897 | 0.0658054 | 0.0868054 | 71.8184 | 11.049 | 13.149 | 0.0552449 | 0.0657449 | 113.958 | 4.383 | 4.383 | 0.0876601 | 0.0876601 | 71.8185 | 11.049 | 13.149 | 0.055245 | 0.065745 | 42.063 | 6.4712 | 8.5712 | 0.0323561 | 0.0428562 | 139.982 | 8.4152 | 10.5152 | 0.107678 | 0.139178 | 626.269 | 10.7385 | 12.8385 | 0.966465 | 1.15546 | Component Quantities - EI-REV-Chapisco (interno) 1: 2 with these values
AL09 | BLOCO B | 5.56693 | 0.856451 | 0.856451 | 0.00428226 | 0.00428226 | 13.6956 | 0.54 | 0.54 | 0.00684778 | 0.00684778 | 1.52173 | 0.06 | 0.06 | 0.000760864 | 0.000760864 | 3.31472 | 0.509959 | 0.509959 | 0.00254979 | 0.00254979 | 3.2608 | 0.501659 | 0.501659 | 0.0025083 | 0.0025083 | 10.8755 | 1.175 | 1.175 | 0.00836576 | 0.00836576 | 7.23418 | 1.11295 | 1.11295 | 0.00556476 | 0.00556476 | 11.1826 | 0.54 | 0.54 | 0.00860198 | 0.00860198 | 7.32193 | 1.12645 | 1.12645 | 0.00563226 | 0.00563226 | 4.83003 | 0.743079 | 0.743079 | 0.00371541 | 0.00371541 | 18.4519 | 1.296 | 1.296 | 0.0141938 | 0.0141938 | 64.12 | 1.09945 | 1.09945 | 0.0989506 | 0.0989506 | 5.47919 | 0.842951 | 0.842951 | 3.1 | 0.005 | 0.0155 | 0.00421476 | 0.00421476
AL09 | BLOCO B | 6.31595 | 0.971986 | 2.89799 | 0.00485842 | 0.0144884 | 5.39996 | 0.134999 | 0.944999 | 0.00269998 | 0.0189 | 0.599995 | 0.0149999 | 0.105 | 0.000299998 | 0.0021 | 4.87519 | 0.750031 | 1.77603 | 0.00375014 | 0.00888013 | 4.82127 | 0.741731 | 1.76773 | 0.00370867 | 0.00883868 | 12.0487 | 1.137 | 2.163 | 0.0092682 | 0.0195282 | 7.9832 | 1.22849 | 3.15449 | 0.00614092 | 0.0157709 | 6.66662 | 0.256408 | 1.06641 | 0.00512817 | 0.0213282 | 8.07095 | 1.24199 | 3.16799 | 0.00620843 | 0.0158384 | 6.30127 | 0.969421 | 2.08542 | 0.00484713 | 0.0104272 | 22.1717 | 1.45418 | 2.57018 | 0.0170551 | 0.0337951 | 57.456 | 0.99062 | 2.91662 | 0.0886666 | 0.262007 | 6.2282 | 0.958486 | 2.88449 | 3.1 | 0.005 | 0.0155 | 0.00479092 | 0.0144209
AL09 | BLOCO B | 16.3212 | 2.51126 | 4.43726 | 0.0125548 | 0.0221848 | 27.7552 | 0.81006 | 1.62006 | 0.0138776 | 0.0300776 | 3.08391 | 0.0900067 | 0.180007 | 0.00154195 | 0.00334195 | 11.1345 | 1.713 | 2.739 | 0.00856498 | 0.013695 | 11.1345 | 1.713 | 2.739 | 0.00856503 | 0.013695 | 25.7912 | 2.68214 | 3.70814 | 0.0198394 | 0.0300994 | 16.3173 | 2.51066 | 4.43666 | 0.0125518 | 0.0221818 | 19.995 | 0.93606 | 1.74606 | 0.0153808 | 0.0315808 | 16.3173 | 2.51066 | 4.43666 | 0.0125518 | 0.0221818 | 11.622 | 1.788 | 2.904 | 0.00894001 | 0.01452 | 46.9153 | 3.07454 | 4.19054 | 0.0360887 | 0.0528287 | 146.439 | 2.5164 | 4.4424 | 0.225986 | 0.399326 | Component Quantities - EI-REV-Chapisco (interno) 1: 2 with these values
AL09 | BLOCO A | 25.1848 | 3.87458 | 3.87458 | 0.0193729 | 0.0193729 | 52.5611 | 1.31403 | 1.31403 | 0.0262805 | 0.0262805 | 5.84012 | 0.146003 | 0.146003 | 0.00292006 | 0.00292006 | 15.5918 | 2.39875 | 2.39875 | 0.0119937 | 0.0119937 | 15.6459 | 2.40705 | 2.40705 | 0.0120353 | 0.0120353 | 35.8039 | 3.00766 | 3.00766 | 0.0275414 | 0.0275414 | 23.498 | 3.61508 | 3.61508 | 0.0180754 | 0.0180754 | 31.785 | 1.31398 | 1.31398 | 0.02445 | 0.02445 | 23.4103 | 3.60158 | 3.60158 | 0.0180079 | 0.0180079 | 15.2156 | 2.34085 | 2.34085 | 0.0117043 | 0.0117043 | 47.4532 | 2.86963 | 2.86963 | 0.0365025 | 0.0365025 | 209.423 | 3.59093 | 3.59093 | 0.323184 | 0.323184 | 25.2725 | 3.88808 | 3.88808 | 3.1 | 0.005 | 0.0155 | 0.0194404 | 0.0194404
AL09 | BLOCO A | 21.1886 | 3.26009 | 5.18609 | 0.0162989 | 0.0259289 | 37.1632 | 0.92908 | 1.73908 | 0.0185816 | 0.0347816 | 4.12925 | 0.103231 | 0.193231 | 0.00206462 | 0.00386462 | 14.2349 | 2.18999 | 3.21599 | 0.0109499 | 0.0160799 | 14.2889 | 2.19829 | 3.22429 | 0.0109915 | 0.0161215 | 33.6579 | 2.97516 | 4.00116 | 0.0258907 | 0.0361507 | 19.4973 | 2.99988 | 4.92588 | 0.0149979 | 0.024628 | 22.0166 | 0.93808 | 1.74808 | 0.0169359 | 0.0331359 | 19.4096 | 2.98638 | 4.91238 | 0.0149304 | 0.0245605 | 13.5937 | 2.09133 | 3.20733 | 0.0104567 | 0.0160367 | 46.8199 | 3.07939 | 4.19539 | 0.0360153 | 0.0527553 | 175.939 | 3.02222 | 4.94822 | 0.271511 | 0.444851 | 21.2764 | 3.27359 | 5.19959 | 3.1 | 0.005 | 0.0155 | 0.0163664 | 0.0259964

# IfcWall: FNDE-AL09-I2-I8 (laranja-cinza) 150 x 3100 (3)
In: TÉRREO
Classification: Parede (Classificação Archicad); Material: TIJOLO - CERAMICO 9x19x39 - espessura 15cm, EI-REV-Chapisco (interno) (2), EI-REV-Pintura Acrílica Cor Cinza, EI-REV-Massa única - Maior que 10m² (2), EI-REV-Massa Corrida PVA (interna) (2), EI-REV-Pintura Acrílica Cor Branco Gelo (2), EI-REV-Pintura Epóxi cor Laranja
FNDE - Alvenarias: Alvenaria de Vedação / Edificação; Sistemas de Cobertura: -; Esquadrias - Fechamentos metálicos e Gradis: -; 0_ID: AL09
Pset_WallCommon - IsExternal: no; LoadBearing: no
Component Quantities - TIJOLO - CERAMICO 9x19x39 - espessura 15cm, Altura do Componente Retangular: 3.1 m; TIJOLO - CERAMICO 9x19x39 - espessura 15cm, Largura do Componente Retangular: 0.09 m; TIJOLO - CERAMICO 9x19x39 - espessura 15cm, Área de Seção Transversal do Componente: 0.279 m2; EI-REV-Chapisco (interno) 1, Altura do Componente Retangular: 3.1 m; EI-REV-Chapisco (interno) 1, Largura do Componente Retangular: 0.005 m; EI-REV-Chapisco (interno) 1, Área de Seção Transversal do Componente: 0.0155 m2; EI-REV-Pintura Acrílica Cor Cinza, Altura do Componente Retangular: 0.44 m; EI-REV-Pintura Acrílica Cor Cinza, Largura do Componente Retangular: 0.01 m; EI-REV-Pintura Acrílica Cor Cinza, Área de Seção Transversal do Componente: 0.0044 m2; EI-REV-Massa única - Maior que 10m² 1, Altura do Componente Retangular: 3.1 m; EI-REV-Massa única - Maior que 10m² 1, Largura do Componente Retangular: 0.01 m; EI-REV-Massa única - Maior que 10m² 1, Área de Seção Transversal do Componente: 0.031 m2; EI-REV-Massa Corrida PVA (interna) 1, Altura do Componente Retangular: 3.1 m; EI-REV-Massa Corrida PVA (interna) 1, Largura do Componente Retangular: 0.005 m; EI-REV-Massa Corrida PVA (interna) 1, Área de Seção Transversal do Componente: 0.0155 m2; EI-REV-Pintura Acrílica Cor Branco Gelo 1, Altura do Componente Retangular: 2.66 m; EI-REV-Pintura Acrílica Cor Branco Gelo 1, Largura do Componente Retangular: 0.01 m; EI-REV-Pintura Acrílica Cor Branco Gelo 1, Área de Seção Transversal do Componente: 0.0266 m2; EI-REV-Chapisco (interno) 2, Altura do Componente Retangular: 3.1 m; EI-REV-Chapisco (interno) 2, Largura do Componente Retangular: 0.005 m; EI-REV-Chapisco (interno) 2, Área de Seção Transversal do Componente: 0.0155 m2; EI-REV-Pintura Epóxi cor Laranja, Altura do Componente Retangular: 0.9 m; EI-REV-Pintura Epóxi cor Laranja, Largura do Componente Retangular: 0.02 m; EI-REV-Pintura Epóxi cor Laranja, Área de Seção Transversal do Componente: 0.018 m2; EI-REV-Massa única - Maior que 10m² 2, Área de Seção Transversal do Componente: 0.0155 m2; EI-REV-Massa Corrida PVA (interna) 2, Altura do Componente Retangular: 2.16 m; EI-REV-Massa Corrida PVA (interna) 2, Largura do Componente Retangular: 0.005 m; EI-REV-Massa Corrida PVA (interna) 2, Área de Seção Transversal do Componente: 0.0108001 m2; EI-REV-Pintura Acrílica Cor Branco Gelo 2, Altura do Componente Retangular: 2.16 m; EI-REV-Pintura Acrílica Cor Branco Gelo 2, Largura do Componente Retangular: 0.015 m; EI-REV-Pintura Acrílica Cor Branco Gelo 2, Área de Seção Transversal do Componente: 0.0324 m2
Name | 1_Bloco | TIJOLO - CERAMICO 9x19x39 - espessura 15cm, Massa (kg) | TIJOLO - CERAMICO 9x19x39 - espessura 15cm, Área de Componente Projetada (Líquida) (m2) | TIJOLO - CERAMICO 9x19x39 - espessura 15cm, Área de Componente Projetada (Bruta) (m2) | TIJOLO - CERAMICO 9x19x39 - espessura 15cm, Volume Componente (Líquido) (m3) | TIJOLO - CERAMICO 9x19x39 - espessura 15cm, Volume do componente (Bruto) (m3) | EI-REV-Chapisco (interno) 1, Massa (kg) | EI-REV-Chapisco (interno) 1, Área de Componente Projetada (Líquida) (m2) | EI-REV-Chapisco (interno) 1, Área de Componente Projetada (Bruta) (m2) | EI-REV-Chapisco (interno) 1, Volume Componente (Líquido) (m3) | EI-REV-Chapisco (interno) 1, Volume do componente (Bruto) (m3) | EI-REV-Pintura Acrílica Cor Cinza, Massa (kg) | EI-REV-Pintura Acrílica Cor Cinza, Área de Componente Projetada (Líquida) (m2) | EI-REV-Pintura Acrílica Cor Cinza, Área de Componente Projetada (Bruta) (m2) | EI-REV-Pintura Acrílica Cor Cinza, Volume Componente (Líquido) (m3) | EI-REV-Pintura Acrílica Cor Cinza, Volume do componente (Bruto) (m3) | EI-REV-Massa única - Maior que 10m² 1, Massa (kg) | EI-REV-Massa única - Maior que 10m² 1, Área de Componente Projetada (Líquida) (m2) | EI-REV-Massa única - Maior que 10m² 1, Área de Componente Projetada (Bruta) (m2) | EI-REV-Massa única - Maior que 10m² 1, Volume Componente (Líquido) (m3) | EI-REV-Massa única - Maior que 10m² 1, Volume do componente (Bruto) (m3) | EI-REV-Massa Corrida PVA (interna) 1, Massa (kg) | EI-REV-Massa Corrida PVA (interna) 1, Área de Componente Projetada (Líquida) (m2) | EI-REV-Massa Corrida PVA (interna) 1, Área de Componente Projetada (Bruta) (m2) | EI-REV-Massa Corrida PVA (interna) 1, Volume Componente (Líquido) (m3) | EI-REV-Massa Corrida PVA (interna) 1, Volume do componente (Bruto) (m3) | EI-REV-Pintura Acrílica Cor Branco Gelo 1, Massa (kg) | EI-REV-Pintura Acrílica Cor Branco Gelo 1, Área de Componente Projetada (Líquida) (m2) | EI-REV-Pintura Acrílica Cor Branco Gelo 1, Área de Componente Projetada (Bruta) (m2) | EI-REV-Pintura Acrílica Cor Branco Gelo 1, Volume Componente (Líquido) (m3) | EI-REV-Pintura Acrílica Cor Branco Gelo 1, Volume do componente (Bruto) (m3) | EI-REV-Chapisco (interno) 2, Massa (kg) | EI-REV-Chapisco (interno) 2, Área de Componente Projetada (Líquida) (m2) | EI-REV-Chapisco (interno) 2, Área de Componente Projetada (Bruta) (m2) | EI-REV-Chapisco (interno) 2, Volume Componente (Líquido) (m3) | EI-REV-Chapisco (interno) 2, Volume do componente (Bruto) (m3) | EI-REV-Pintura Epóxi cor Laranja, Massa (kg) | EI-REV-Pintura Epóxi cor Laranja, Área de Componente Projetada (Líquida) (m2) | EI-REV-Pintura Epóxi cor Laranja, Área de Componente Projetada (Bruta) (m2) | EI-REV-Pintura Epóxi cor Laranja, Volume Componente (Líquido) (m3) | EI-REV-Pintura Epóxi cor Laranja, Volume do componente (Bruto) (m3) | EI-REV-Massa única - Maior que 10m² 2, Massa (kg) | EI-REV-Massa única - Maior que 10m² 2, Área de Componente Projetada (Líquida) (m2) | EI-REV-Massa única - Maior que 10m² 2, Área de Componente Projetada (Bruta) (m2) | EI-REV-Massa única - Maior que 10m² 2, Volume Componente (Líquido) (m3) | EI-REV-Massa única - Maior que 10m² 2, Volume do componente (Bruto) (m3) | EI-REV-Massa Corrida PVA (interna) 2, Massa (kg) | EI-REV-Massa Corrida PVA (interna) 2, Área de Componente Projetada (Líquida) (m2) | EI-REV-Massa Corrida PVA (interna) 2, Área de Componente Projetada (Bruta) (m2) | EI-REV-Massa Corrida PVA (interna) 2, Volume Componente (Líquido) (m3) | EI-REV-Massa Corrida PVA (interna) 2, Volume do componente (Bruto) (m3) | EI-REV-Pintura Acrílica Cor Branco Gelo 2, Massa (kg) | EI-REV-Pintura Acrílica Cor Branco Gelo 2, Área de Componente Projetada (Líquida) (m2) | EI-REV-Pintura Acrílica Cor Branco Gelo 2, Área de Componente Projetada (Bruta) (m2) | EI-REV-Pintura Acrílica Cor Branco Gelo 2, Volume Componente (Líquido) (m3) | EI-REV-Pintura Acrílica Cor Branco Gelo 2, Volume do componente (Bruto) (m3)
AL09 | BLOCO B | 52.7338 | 0.931393 | 12.8564 | 0.0813793 | 1.15463 | 4.2979 | 0.662725 | 12.5877 | 0.00330607 | 0.0629311 | 2.41012 | 0.239779 | 2.03978 | 0.00185394 | 0.0198539 | 8.42029 | 0.650735 | 12.5757 | 0.00647715 | 0.125727 | 3.87012 | 0.622225 | 12.5472 | 0.00297701 | 0.062602 | 25.4106 | 3.10669 | 13.2317 | 0.0195466 | 0.120797 | 4.29884 | 0.662873 | 12.5879 | 0.0033068 | 0.0629318 | 6.27505 | 0.51306 | 4.56306 | 0.00482696 | 0.085827 | 4.21111 | 0.649373 | 12.5744 | 0.00323932 | 0.0628644 | 2.40868 | 0.370545 | 8.24554 | 0.00185283 | 0.0412279 | 22.4076 | 3.07124 | 10.9462 | 0.0172366 | 0.135362
AL09 | BLOCO B | 50.3768 | 0.89098 | 12.816 | 0.077742 | 1.15099 | 4.03521 | 0.622311 | 12.5473 | 0.00310401 | 0.062729 | 2.5299 | 0.2336 | 2.0336 | 0.00194607 | 0.0199461 | 7.89492 | 0.610322 | 12.5353 | 0.00607302 | 0.125323 | 3.63978 | 0.581812 | 12.5068 | 0.00279983 | 0.0624248 | 29.2474 | 3.06656 | 13.1916 | 0.022498 | 0.123748 | 4.03616 | 0.622459 | 12.5475 | 0.00310474 | 0.0627297 | 5.05578 | 0.423 | 4.473 | 0.00388906 | 0.0848891 | 3.94841 | 0.60896 | 12.534 | 0.00303724 | 0.0626623 | 2.23731 | 0.3442 | 8.2192 | 0.00172101 | 0.0410962 | 16.7494 | 2.8551 | 10.7301 | 0.0128841 | 0.131009
AL09 | BLOCO A | 99.9691 | 1.74133 | 13.6663 | 0.154273 | 1.22752 | 9.56247 | 1.47266 | 13.3977 | 0.00735574 | 0.0669807 | 4.116 | 0.389 | 2.189 | 0.00316615 | 0.0211662 | 18.9494 | 1.46067 | 13.3857 | 0.0145765 | 0.133826 | 9.29922 | 1.43216 | 13.3572 | 0.00715324 | 0.0667782 | 27.3167 | 3.10624 | 13.2312 | 0.0210128 | 0.122263 | 9.56241 | 1.47266 | 13.3977 | 0.0073557 | 0.0669807 | 11.8508 | 0.513 | 4.563 | 0.00911599 | 0.0901161 | 9.47116 | 1.45915 | 13.3841 | 0.00728551 | 0.0669105 | 5.84028 | 0.898501 | 8.7735 | 0.00449252 | 0.0438676 | 31.8142 | 3.0711 | 10.9461 | 0.0244725 | 0.142597

# IfcWall: FNDE-AL09-I3 (verde) 120 x 3100 (2)
In: TÉRREO
Classification: Parede (Classificação Archicad); Material: TIJOLO - CERAMICO 9x19x39 - espessura 15cm, EI-REV-Chapisco (interno), EI-REV-Pintura Epóxi cor Verde, EI-REV-Massa única - Maior que 10m², EI-REV-Massa Corrida PVA (interna), EI-REV-Pintura Acrílica Cor Branco Gelo
FNDE - Alvenarias: Alvenaria de Vedação / Edificação; Sistemas de Cobertura: -; Esquadrias - Fechamentos metálicos e Gradis: -; 1_Bloco: BLOCO B; 0_ID: AL09
Pset_WallCommon - LoadBearing: no
Component Quantities - TIJOLO - CERAMICO 9x19x39 - espessura 15cm, Altura do Componente Retangular: 3.1 m; TIJOLO - CERAMICO 9x19x39 - espessura 15cm, Largura do Componente Retangular: 0.09 m; TIJOLO - CERAMICO 9x19x39 - espessura 15cm, Área de Seção Transversal do Componente: 0.279 m2; EI-REV-Chapisco (interno), Altura do Componente Retangular: 3.1 m; EI-REV-Chapisco (interno), Largura do Componente Retangular: 0.005 m; EI-REV-Chapisco (interno), Área de Seção Transversal do Componente: 0.0155 m2; EI-REV-Pintura Epóxi cor Verde, Altura do Componente Retangular: 0.9 m; EI-REV-Pintura Epóxi cor Verde, Largura do Componente Retangular: 0.02 m; EI-REV-Pintura Epóxi cor Verde, Área de Seção Transversal do Componente: 0.018 m2; EI-REV-Massa única - Maior que 10m², Área de Seção Transversal do Componente: 0.0155 m2; EI-REV-Massa Corrida PVA (interna), Altura do Componente Retangular: 2.16 m; EI-REV-Massa Corrida PVA (interna), Largura do Componente Retangular: 0.005 m; EI-REV-Massa Corrida PVA (interna), Área de Seção Transversal do Componente: 0.0108001 m2; EI-REV-Pintura Acrílica Cor Branco Gelo, Altura do Componente Retangular: 2.16 m; EI-REV-Pintura Acrílica Cor Branco Gelo, Largura do Componente Retangular: 0.015 m; EI-REV-Pintura Acrílica Cor Branco Gelo, Área de Seção Transversal do Componente: 0.0324 m2
Name | IsExternal | TIJOLO - CERAMICO 9x19x39 - espessura 15cm, Massa (kg) | TIJOLO - CERAMICO 9x19x39 - espessura 15cm, Área de Componente Projetada (Líquida) (m2) = TIJOLO - CERAMICO 9x19x39 - espessura 15cm, Área de Componente Projetada (Bruta) (m2) | TIJOLO - CERAMICO 9x19x39 - espessura 15cm, Volume Componente (Líquido) (m3) = TIJOLO - CERAMICO 9x19x39 - espessura 15cm, Volume do componente (Bruto) (m3) | EI-REV-Chapisco (interno), Massa (kg) = EI-REV-Massa única - Maior que 10m², Massa (kg) | EI-REV-Chapisco (interno), Área de Componente Projetada (Líquida) (m2) = EI-REV-Massa única - Maior que 10m², Área de Componente Projetada (Líquida) (m2) | EI-REV-Chapisco (interno), Área de Componente Projetada (Bruta) (m2) = EI-REV-Massa única - Maior que 10m², Área de Componente Projetada (Bruta) (m2) | EI-REV-Chapisco (interno), Volume Componente (Líquido) (m3) = EI-REV-Massa única - Maior que 10m², Volume Componente (Líquido) (m3) | EI-REV-Chapisco (interno), Volume do componente (Bruto) (m3) = EI-REV-Massa única - Maior que 10m², Volume do componente (Bruto) (m3) | EI-REV-Pintura Epóxi cor Verde, Massa (kg) | EI-REV-Pintura Epóxi cor Verde, Área de Componente Projetada (Líquida) (m2) = EI-REV-Pintura Epóxi cor Verde, Área de Componente Projetada (Bruta) (m2) | EI-REV-Pintura Epóxi cor Verde, Volume Componente (Líquido) (m3) = EI-REV-Pintura Epóxi cor Verde, Volume do componente (Bruto) (m3) | EI-REV-Massa Corrida PVA (interna), Massa (kg) | EI-REV-Massa Corrida PVA (interna), Área de Componente Projetada (Líquida) (m2) | EI-REV-Massa Corrida PVA (interna), Área de Componente Projetada (Bruta) (m2) | EI-REV-Massa Corrida PVA (interna), Volume Componente (Líquido) (m3) | EI-REV-Massa Corrida PVA (interna), Volume do componente (Bruto) (m3) | EI-REV-Pintura Acrílica Cor Branco Gelo, Massa (kg) | EI-REV-Pintura Acrílica Cor Branco Gelo, Área de Componente Projetada (Líquida) (m2) = EI-REV-Pintura Acrílica Cor Branco Gelo, Área de Componente Projetada (Bruta) (m2) | EI-REV-Pintura Acrílica Cor Branco Gelo, Volume Componente (Líquido) (m3) | EI-REV-Pintura Acrílica Cor Branco Gelo, Volume do componente (Bruto) (m3)
AL09 | yes | 112.587 | 1.93051 | 0.173746 | 12.3727 | 1.9035 | 1.9035 | 0.0095175 | 0.0095175 | 17.3198 | 0.828002 | 0.0133229 | 8.06525 | 1.2408 | 1.2408 | 0.00620404 | 0.00620404 | 27.1891 | 1.97641 | 0.0209147 | 0.0209147
AL09 | no | 109.377 | 1.87546 | 0.168791 | 19.8994 | 3.06149 | 3.09333 | 0.0153073 | 0.0154665 | 26.55 | 1.02115 | 0.0204231 | 12.98 | 1.99692 | 2.02877 | 0.00998465 | 0.0101439 | 43.1905 | 2.45077 | 0.0332235 | 0.0334717

# IfcWall: FNDE-AL09-I3-I3 (verde) 150 x 3100 (2)
In: TÉRREO
Classification: Parede (Classificação Archicad); Material: TIJOLO - CERAMICO 9x19x39 - espessura 15cm, EI-REV-Chapisco (interno) (2), EI-REV-Pintura Epóxi cor Verde (2), EI-REV-Massa única - Maior que 10m² (2), EI-REV-Massa Corrida PVA (interna) (2), EI-REV-Pintura Acrílica Cor Branco Gelo (2)
FNDE - Alvenarias: Alvenaria de Vedação / Edificação; Sistemas de Cobertura: -; Esquadrias - Fechamentos metálicos e Gradis: -; 1_Bloco: BLOCO B; 0_ID: AL09
Pset_WallCommon - IsExternal: no; LoadBearing: no
Component Quantities - TIJOLO - CERAMICO 9x19x39 - espessura 15cm, Altura do Componente Retangular: 3.1 m; TIJOLO - CERAMICO 9x19x39 - espessura 15cm, Largura do Componente Retangular: 0.09 m; TIJOLO - CERAMICO 9x19x39 - espessura 15cm, Área de Seção Transversal do Componente: 0.279 m2; EI-REV-Chapisco (interno) 1, Altura do Componente Retangular: 3.1 m; EI-REV-Chapisco (interno) 1, Largura do Componente Retangular: 0.005 m; EI-REV-Chapisco (interno) 1, Área de Seção Transversal do Componente: 0.0155 m2; EI-REV-Pintura Epóxi cor Verde 1, Altura do Componente Retangular: 0.9 m; EI-REV-Pintura Epóxi cor Verde 1, Largura do Componente Retangular: 0.02 m; EI-REV-Pintura Epóxi cor Verde 1, Área de Seção Transversal do Componente: 0.018 m2; EI-REV-Massa única - Maior que 10m² 1, Área de Seção Transversal do Componente: 0.0155 m2; EI-REV-Massa Corrida PVA (interna) 1, Altura do Componente Retangular: 2.16 m; EI-REV-Massa Corrida PVA (interna) 1, Largura do Componente Retangular: 0.005 m; EI-REV-Massa Corrida PVA (interna) 1, Área de Seção Transversal do Componente: 0.0108001 m2; EI-REV-Pintura Acrílica Cor Branco Gelo 1, Altura do Componente Retangular: 2.16 m; EI-REV-Pintura Acrílica Cor Branco Gelo 1, Largura do Componente Retangular: 0.015 m; EI-REV-Pintura Acrílica Cor Branco Gelo 1, Área de Seção Transversal do Componente: 0.0324 m2; EI-REV-Chapisco (interno) 2, Altura do Componente Retangular: 3.1 m; EI-REV-Chapisco (interno) 2, Largura do Componente Retangular: 0.005 m; EI-REV-Chapisco (interno) 2, Área de Seção Transversal do Componente: 0.0155 m2; EI-REV-Pintura Epóxi cor Verde 2, Altura do Componente Retangular: 0.9 m; EI-REV-Pintura Epóxi cor Verde 2, Largura do Componente Retangular: 0.02 m; EI-REV-Pintura Epóxi cor Verde 2, Área de Seção Transversal do Componente: 0.018 m2; EI-REV-Massa única - Maior que 10m² 2, Altura do Componente Retangular: 3.1 m; EI-REV-Massa única - Maior que 10m² 2, Largura do Componente Retangular: 0.005 m; EI-REV-Massa única - Maior que 10m² 2, Área de Seção Transversal do Componente: 0.0155 m2; EI-REV-Massa Corrida PVA (interna) 2, Altura do Componente Retangular: 2.16 m; EI-REV-Massa Corrida PVA (interna) 2, Largura do Componente Retangular: 0.005 m; EI-REV-Massa Corrida PVA (interna) 2, Área de Seção Transversal do Componente: 0.0108 m2; EI-REV-Pintura Acrílica Cor Branco Gelo 2, Altura do Componente Retangular: 2.16 m; EI-REV-Pintura Acrílica Cor Branco Gelo 2, Largura do Componente Retangular: 0.015 m; EI-REV-Pintura Acrílica Cor Branco Gelo 2, Área de Seção Transversal do Componente: 0.0324 m2
Name | TIJOLO - CERAMICO 9x19x39 - espessura 15cm, Massa (kg) | TIJOLO - CERAMICO 9x19x39 - espessura 15cm, Área de Componente Projetada (Líquida) (m2) = TIJOLO - CERAMICO 9x19x39 - espessura 15cm, Área de Componente Projetada (Bruta) (m2) | TIJOLO - CERAMICO 9x19x39 - espessura 15cm, Volume Componente (Líquido) (m3) = TIJOLO - CERAMICO 9x19x39 - espessura 15cm, Volume do componente (Bruto) (m3) | EI-REV-Chapisco (interno) 1, Massa (kg) | EI-REV-Chapisco (interno) 1, Área de Componente Projetada (Líquida) (m2) = EI-REV-Chapisco (interno) 1, Área de Componente Projetada (Bruta) (m2) | EI-REV-Chapisco (interno) 1, Volume Componente (Líquido) (m3) = EI-REV-Chapisco (interno) 1, Volume do componente (Bruto) (m3) | EI-REV-Pintura Epóxi cor Verde 1, Massa (kg) | EI-REV-Pintura Epóxi cor Verde 1, Área de Componente Projetada (Líquida) (m2) = EI-REV-Pintura Epóxi cor Verde 1, Área de Componente Projetada (Bruta) (m2) | EI-REV-Pintura Epóxi cor Verde 1, Volume Componente (Líquido) (m3) = EI-REV-Pintura Epóxi cor Verde 1, Volume do componente (Bruto) (m3) | EI-REV-Massa única - Maior que 10m² 1, Massa (kg) | EI-REV-Massa única - Maior que 10m² 1, Área de Componente Projetada (Líquida) (m2) = EI-REV-Massa única - Maior que 10m² 1, Área de Componente Projetada (Bruta) (m2) | EI-REV-Massa única - Maior que 10m² 1, Volume Componente (Líquido) (m3) = EI-REV-Massa única - Maior que 10m² 1, Volume do componente (Bruto) (m3) | EI-REV-Massa Corrida PVA (interna) 1, Massa (kg) | EI-REV-Massa Corrida PVA (interna) 1, Área de Componente Projetada (Líquida) (m2) = EI-REV-Massa Corrida PVA (interna) 1, Área de Componente Projetada (Bruta) (m2) | EI-REV-Massa Corrida PVA (interna) 1, Volume Componente (Líquido) (m3) = EI-REV-Massa Corrida PVA (interna) 1, Volume do componente (Bruto) (m3) | EI-REV-Pintura Acrílica Cor Branco Gelo 1, Massa (kg) | EI-REV-Pintura Acrílica Cor Branco Gelo 1, Área de Componente Projetada (Líquida) (m2) = EI-REV-Pintura Acrílica Cor Branco Gelo 1, Área de Componente Projetada (Bruta) (m2) | EI-REV-Pintura Acrílica Cor Branco Gelo 1, Volume Componente (Líquido) (m3) = EI-REV-Pintura Acrílica Cor Branco Gelo 1, Volume do componente (Bruto) (m3) | EI-REV-Chapisco (interno) 2, Massa (kg) | EI-REV-Chapisco (interno) 2, Área de Componente Projetada (Líquida) (m2) = EI-REV-Chapisco (interno) 2, Área de Componente Projetada (Bruta) (m2) | EI-REV-Chapisco (interno) 2, Volume Componente (Líquido) (m3) = EI-REV-Chapisco (interno) 2, Volume do componente (Bruto) (m3) | EI-REV-Pintura Epóxi cor Verde 2, Massa (kg) | EI-REV-Pintura Epóxi cor Verde 2, Área de Componente Projetada (Líquida) (m2) = EI-REV-Pintura Epóxi cor Verde 2, Área de Componente Projetada (Bruta) (m2) | EI-REV-Pintura Epóxi cor Verde 2, Volume Componente (Líquido) (m3) = EI-REV-Pintura Epóxi cor Verde 2, Volume do componente (Bruto) (m3) | EI-REV-Massa única - Maior que 10m² 2, Massa (kg) | EI-REV-Massa única - Maior que 10m² 2, Área de Componente Projetada (Líquida) (m2) = EI-REV-Massa única - Maior que 10m² 2, Área de Componente Projetada (Bruta) (m2) | EI-REV-Massa única - Maior que 10m² 2, Volume Componente (Líquido) (m3) = EI-REV-Massa única - Maior que 10m² 2, Volume do componente (Bruto) (m3) | EI-REV-Massa Corrida PVA (interna) 2, Massa (kg) | EI-REV-Massa Corrida PVA (interna) 2, Área de Componente Projetada (Líquida) (m2) = EI-REV-Massa Corrida PVA (interna) 2, Área de Componente Projetada (Bruta) (m2) | EI-REV-Massa Corrida PVA (interna) 2, Volume Componente (Líquido) (m3) = EI-REV-Massa Corrida PVA (interna) 2, Volume do componente (Bruto) (m3) | EI-REV-Pintura Acrílica Cor Branco Gelo 2, Massa (kg) | EI-REV-Pintura Acrílica Cor Branco Gelo 2, Área de Componente Projetada (Líquida) (m2) = EI-REV-Pintura Acrílica Cor Branco Gelo 2, Área de Componente Projetada (Bruta) (m2) | EI-REV-Pintura Acrílica Cor Branco Gelo 2, Volume Componente (Líquido) (m3) = EI-REV-Pintura Acrílica Cor Branco Gelo 2, Volume do componente (Bruto) (m3)
AL09 | 876.641 | 15.0316 | 1.35284 | 97.6173 | 15.0181 | 0.0750902 | 138.044 | 5.41804 | 0.106187 | 97.5297 | 15.0046 | 0.0750228 | 63.5364 | 9.77195 | 0.0488742 | 222.056 | 12.9897 | 0.170812 | 97.6174 | 15.0181 | 0.0750903 | 138.046 | 5.41804 | 0.106189 | 97.5297 | 15.0046 | 0.0750228 | 63.4992 | 9.77195 | 0.0488455 | 222.407 | 13.0071 | 0.171082
AL09 | 86.1526 | 1.47724 | 0.132952 | 9.60076 | 1.47704 | 0.0073852 | 10.53 | 0.405 | 0.0081 | 9.51171 | 1.46334 | 0.0073167 | 6.56008 | 1.00924 | 0.00504622 | 18.8767 | 0.968039 | 0.0145205 | 9.51301 | 1.46354 | 0.0073177 | 10.062 | 0.387 | 0.00774001 | 9.42396 | 1.44984 | 0.0072492 | 6.50287 | 1.00044 | 0.0050022 | 18.3222 | 0.939601 | 0.014094

# IfcWall: FNDE-AL09-I3-I5 (verde-azul) 150 x 3100 (3)
In: TÉRREO
Classification: Parede (Classificação Archicad); Material: TIJOLO - CERAMICO 9x19x39 - espessura 15cm, EI-REV-Chapisco (interno) (2), EI-REV-Cerâmica 30x40, EI-REV-Cerâmica 10x10 Azul, EI-REV-Emboço Interno, EI-REV-Massa única - Maior que 10m² (2), EI-REV-Massa Corrida PVA (interna) (2), EI-REV-Pintura Acrílica Cor Branco Gelo (2), EI-REV-Pintura Epóxi cor Verde
FNDE - Alvenarias: Alvenaria de Vedação / Edificação; Sistemas de Cobertura: -; Esquadrias - Fechamentos metálicos e Gradis: -; 1_Bloco: BLOCO B; 0_ID: AL09
Pset_WallCommon - IsExternal: no; LoadBearing: no
Component Quantities - TIJOLO - CERAMICO 9x19x39 - espessura 15cm, Altura do Componente Retangular: 3.1 m; TIJOLO - CERAMICO 9x19x39 - espessura 15cm, Largura do Componente Retangular: 0.09 m; TIJOLO - CERAMICO 9x19x39 - espessura 15cm, Área de Seção Transversal do Componente: 0.279 m2; EI-REV-Chapisco (interno) 1, Altura do Componente Retangular: 3.1 m; EI-REV-Chapisco (interno) 1, Largura do Componente Retangular: 0.005 m; EI-REV-Chapisco (interno) 1, Área de Seção Transversal do Componente: 0.0155 m2; EI-REV-Cerâmica 30x40, Largura do Componente Retangular: 0.02 m; EI-REV-Cerâmica 10x10 Azul, Altura do Componente Retangular: 0.1 m; EI-REV-Cerâmica 10x10 Azul, Largura do Componente Retangular: 0.02 m; EI-REV-Cerâmica 10x10 Azul, Área de Seção Transversal do Componente: 0.002 m2; EI-REV-Emboço Interno, Altura do Componente Retangular: 3.1 m; EI-REV-Emboço Interno, Largura do Componente Retangular: 0.005 m; EI-REV-Emboço Interno, Área de Seção Transversal do Componente: 0.0155 m2; EI-REV-Massa única - Maior que 10m² 1, Largura do Componente Retangular: 0.005 m; EI-REV-Chapisco (interno) 2, Altura do Componente Retangular: 3.1 m; EI-REV-Chapisco (interno) 2, Largura do Componente Retangular: 0.005 m; EI-REV-Chapisco (interno) 2, Área de Seção Transversal do Componente: 0.0155 m2; EI-REV-Pintura Epóxi cor Verde, Altura do Componente Retangular: 0.9 m; EI-REV-Pintura Epóxi cor Verde, Largura do Componente Retangular: 0.02 m; EI-REV-Pintura Epóxi cor Verde, Área de Seção Transversal do Componente: 0.018 m2; EI-REV-Massa única - Maior que 10m² 2, Área de Seção Transversal do Componente: 0.0155 m2; EI-REV-Massa Corrida PVA (interna) 2, Altura do Componente Retangular: 2.16 m; EI-REV-Massa Corrida PVA (interna) 2, Largura do Componente Retangular: 0.005 m; EI-REV-Massa Corrida PVA (interna) 2, Área de Seção Transversal do Componente: 0.0108001 m2; EI-REV-Pintura Acrílica Cor Branco Gelo 2, Altura do Componente Retangular: 2.16 m; EI-REV-Pintura Acrílica Cor Branco Gelo 2, Largura do Componente Retangular: 0.015 m; EI-REV-Pintura Acrílica Cor Branco Gelo 2, Área de Seção Transversal do Componente: 0.0324 m2
Name | TIJOLO - CERAMICO 9x19x39 - espessura 15cm, Massa (kg) | TIJOLO - CERAMICO 9x19x39 - espessura 15cm, Área de Componente Projetada (Líquida) (m2) = TIJOLO - CERAMICO 9x19x39 - espessura 15cm, Área de Componente Projetada (Bruta) (m2) | TIJOLO - CERAMICO 9x19x39 - espessura 15cm, Volume Componente (Líquido) (m3) = TIJOLO - CERAMICO 9x19x39 - espessura 15cm, Volume do componente (Bruto) (m3) | EI-REV-Chapisco (interno) 1, Massa (kg) | EI-REV-Chapisco (interno) 1, Área de Componente Projetada (Líquida) (m2) = EI-REV-Chapisco (interno) 1, Área de Componente Projetada (Bruta) (m2) | EI-REV-Chapisco (interno) 1, Volume Componente (Líquido) (m3) = EI-REV-Chapisco (interno) 1, Volume do componente (Bruto) (m3) | EI-REV-Cerâmica 30x40, Massa (kg) | EI-REV-Cerâmica 30x40, Área de Componente Projetada (Líquida) (m2) = EI-REV-Cerâmica 30x40, Área de Componente Projetada (Bruta) (m2) | EI-REV-Cerâmica 30x40, Altura do Componente Retangular (m) | EI-REV-Cerâmica 30x40, Área de Seção Transversal do Componente (m2) | EI-REV-Cerâmica 30x40, Volume Componente (Líquido) (m3) = EI-REV-Cerâmica 30x40, Volume do componente (Bruto) (m3) | EI-REV-Cerâmica 10x10 Azul, Massa (kg) | EI-REV-Cerâmica 10x10 Azul, Área de Componente Projetada (Líquida) (m2) = EI-REV-Cerâmica 10x10 Azul, Área de Componente Projetada (Bruta) (m2) | EI-REV-Cerâmica 10x10 Azul, Volume Componente (Líquido) (m3) = EI-REV-Cerâmica 10x10 Azul, Volume do componente (Bruto) (m3) | EI-REV-Emboço Interno, Massa (kg) | EI-REV-Emboço Interno, Área de Componente Projetada (Líquida) (m2) = EI-REV-Emboço Interno, Área de Componente Projetada (Bruta) (m2) | EI-REV-Emboço Interno, Volume Componente (Líquido) (m3) = EI-REV-Emboço Interno, Volume do componente (Bruto) (m3) | EI-REV-Massa única - Maior que 10m² 1, Massa (kg) | EI-REV-Massa única - Maior que 10m² 1, Área de Componente Projetada (Líquida) (m2) = EI-REV-Massa única - Maior que 10m² 1, Área de Componente Projetada (Bruta) (m2) | EI-REV-Massa única - Maior que 10m² 1, Altura do Componente Retangular (m) = EI-REV-Massa Corrida PVA (interna) 1, Altura do Componente Retangular (m) = EI-REV-Pintura Acrílica Cor Branco Gelo 1, Altura do Componente Retangular (m) | EI-REV-Massa única - Maior que 10m² 1, Área de Seção Transversal do Componente (m2) | EI-REV-Massa única - Maior que 10m² 1, Volume Componente (Líquido) (m3) = EI-REV-Massa única - Maior que 10m² 1, Volume do componente (Bruto) (m3) | EI-REV-Massa Corrida PVA (interna) 1, Massa (kg) | EI-REV-Massa Corrida PVA (interna) 1, Área de Componente Projetada (Líquida) (m2) = EI-REV-Massa Corrida PVA (interna) 1, Área de Componente Projetada (Bruta) (m2) | EI-REV-Massa Corrida PVA (interna) 1, Largura do Componente Retangular (m) | EI-REV-Massa Corrida PVA (interna) 1, Área de Seção Transversal do Componente (m2) | EI-REV-Massa Corrida PVA (interna) 1, Volume Componente (Líquido) (m3) = EI-REV-Massa Corrida PVA (interna) 1, Volume do componente (Bruto) (m3) | EI-REV-Pintura Acrílica Cor Branco Gelo 1, Massa (kg) | EI-REV-Pintura Acrílica Cor Branco Gelo 1, Área de Componente Projetada (Líquida) (m2) = EI-REV-Pintura Acrílica Cor Branco Gelo 1, Área de Componente Projetada (Bruta) (m2) | EI-REV-Pintura Acrílica Cor Branco Gelo 1, Largura do Componente Retangular (m) | EI-REV-Pintura Acrílica Cor Branco Gelo 1, Área de Seção Transversal do Componente (m2) | EI-REV-Pintura Acrílica Cor Branco Gelo 1, Volume Componente (Líquido) (m3) = EI-REV-Pintura Acrílica Cor Branco Gelo 1, Volume do componente (Bruto) (m3) | EI-REV-Chapisco (interno) 2, Massa (kg) | EI-REV-Chapisco (interno) 2, Área de Componente Projetada (Líquida) (m2) = EI-REV-Chapisco (interno) 2, Área de Componente Projetada (Bruta) (m2) | EI-REV-Chapisco (interno) 2, Volume Componente (Líquido) (m3) = EI-REV-Chapisco (interno) 2, Volume do componente (Bruto) (m3) | EI-REV-Pintura Epóxi cor Verde, Massa (kg) | EI-REV-Pintura Epóxi cor Verde, Área de Componente Projetada (Líquida) (m2) = EI-REV-Pintura Epóxi cor Verde, Área de Componente Projetada (Bruta) (m2) | EI-REV-Pintura Epóxi cor Verde, Volume Componente (Líquido) (m3) = EI-REV-Pintura Epóxi cor Verde, Volume do componente (Bruto) (m3) | EI-REV-Massa única - Maior que 10m² 2, Massa (kg) | EI-REV-Massa única - Maior que 10m² 2, Área de Componente Projetada (Líquida) (m2) = EI-REV-Massa única - Maior que 10m² 2, Área de Componente Projetada (Bruta) (m2) | EI-REV-Massa única - Maior que 10m² 2, Volume Componente (Líquido) (m3) = EI-REV-Massa única - Maior que 10m² 2, Volume do componente (Bruto) (m3) | EI-REV-Massa Corrida PVA (interna) 2, Massa (kg) | EI-REV-Massa Corrida PVA (interna) 2, Área de Componente Projetada (Líquida) (m2) = EI-REV-Massa Corrida PVA (interna) 2, Área de Componente Projetada (Bruta) (m2) | EI-REV-Massa Corrida PVA (interna) 2, Volume Componente (Líquido) (m3) = EI-REV-Massa Corrida PVA (interna) 2, Volume do componente (Bruto) (m3) | EI-REV-Pintura Acrílica Cor Branco Gelo 2, Massa (kg) | EI-REV-Pintura Acrílica Cor Branco Gelo 2, Área de Componente Projetada (Líquida) (m2) = EI-REV-Pintura Acrílica Cor Branco Gelo 2, Área de Componente Projetada (Bruta) (m2) | EI-REV-Pintura Acrílica Cor Branco Gelo 2, Volume Componente (Líquido) (m3) = EI-REV-Pintura Acrílica Cor Branco Gelo 2, Volume do componente (Bruto) (m3)
AL09 | 414.12 | 7.10082 | 0.639074 | 47.2201 | 7.26462 | 0.0363231 | 201.734 | 5.23788 | 1.8 | 0.036 | 0.100867 | 11.2075 | 0.290993 | 0.00560374 | 46.9191 | 7.21832 | 0.0360916 | 13.6884 | 2.1059 | 1.17 | 0.00585001 | 0.0105295 | 14.4778 | 2.3292 | 0.005 | 0.00585001 | 0.0111368 | 34.5489 | 3.51934 | 0.00999999 | 0.0117 | 0.0265761 | 49.6826 | 7.64347 | 0.0382174 | 72.2593 | 2.81694 | 0.055584 | 49.7444 | 7.65297 | 0.0382649 | 33.9916 | 5.52469 | 0.0261474 | 110.788 | 6.28686 | 0.0852214
AL09 | 255.088 | 4.37394 | 0.393655 | 27.8665 | 4.28715 | 0.0214357 | 110.082 | 2.94916 | 1.8 | 0.036 | 0.0550409 | 7.53986 | 0.201997 | 0.00376993 | 27.8665 | 4.28715 | 0.0214358 | 9.2091 | 1.41678 | 1.17 | 0.00585001 | 0.00708393 | 9.20912 | 1.41678 | 0.005 | 0.00585001 | 0.00708394 | 21.4168 | 2.07087 | 0.00999999 | 0.0117 | 0.0164745 | 28.3429 | 4.36044 | 0.0218022 | 38.2588 | 1.59298 | 0.0294299 | 28.2552 | 4.34694 | 0.0217347 | 18.361 | 2.82476 | 0.0141239 | 61.2312 | 3.82315 | 0.0471009
AL09 | 564.508 | 9.67949 | 0.871154 | 61.3372 | 9.4365 | 0.0471825 | 162.54 | 4.0635 | 1.2 | 0.024 | 0.08127 | 13.86 | 0.3465 | 0.00693 | 60.4598 | 9.3015 | 0.0465075 | 30.8558 | 4.74705 | 1.77 | 0.00885001 | 0.0237353 | 30.7224 | 4.7265 | 0.00500003 | 0.00885005 | 0.0236326 | 70.1055 | 6.07995 | 0.00999998 | 0.0177 | 0.0539273 | 62.1268 | 9.55799 | 0.0477898 | 83.1872 | 3.267 | 0.0639901 | 62.0405 | 9.54469 | 0.0477235 | 40.3833 | 6.21279 | 0.0310641 | 131.676 | 7.8494 | 0.101289

# IfcWall: FNDE-AL09-I3-I5 (verde-vermelho) (sem rodameio) 150 x 3100 (2)
In: TÉRREO
Classification: Parede (Classificação Archicad); Material: TIJOLO - CERAMICO 9x19x39 - espessura 15cm, EI-REV-Chapisco (interno) (2), EI-REV-Cerâmica 30x40, EI-REV-Cerâmica 10x10 Vermelha, EI-REV-Emboço Interno, EI-REV-Massa única - Maior que 10m² (2), EI-REV-Massa Corrida PVA (interna) (2), EI-REV-Pintura Acrílica Cor Branco Gelo (2), EI-REV-Pintura Epóxi cor Verde
FNDE - Alvenarias: Alvenaria de Vedação / Edificação; Sistemas de Cobertura: -; Esquadrias - Fechamentos metálicos e Gradis: -; 1_Bloco: BLOCO B; 0_ID: AL09
Pset_WallCommon - IsExternal: no; LoadBearing: no
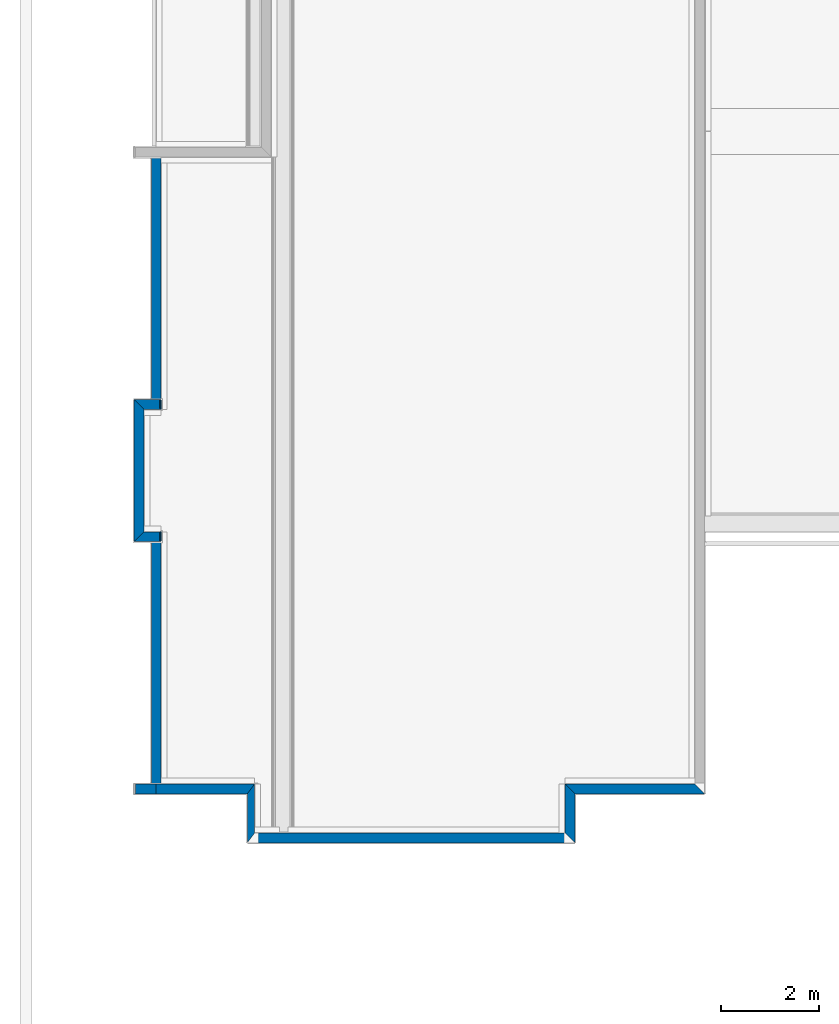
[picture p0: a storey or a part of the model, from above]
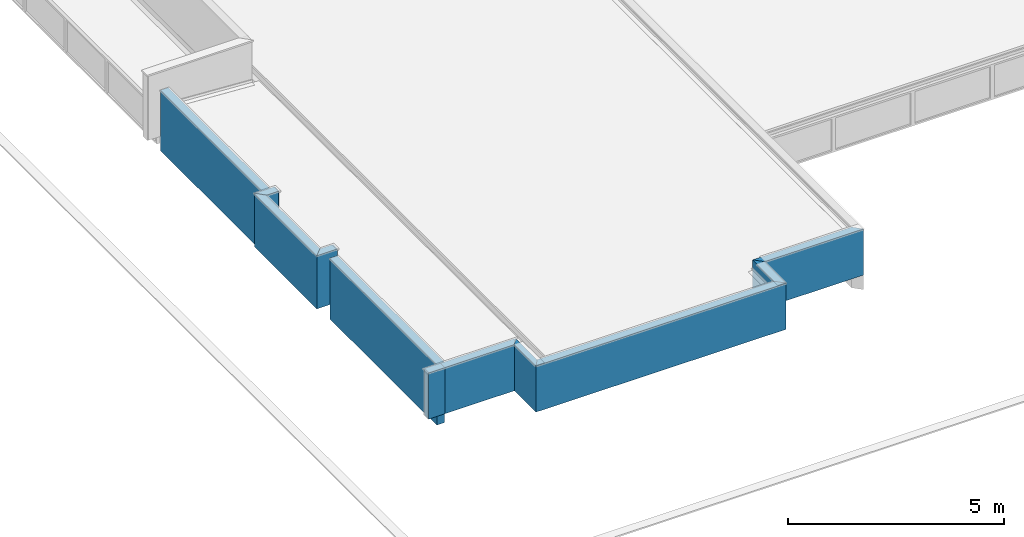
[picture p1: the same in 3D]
Properties of the parts of a building model (IFC4), part 12 of 22

# IfcWall: FNDE-AL09-I3-I5 (verde-vermelho) (sem rodameio) 150 x 3100 (2)
Component Quantities - TIJOLO - CERAMICO 9x19x39 - espessura 15cm, Altura do Componente Retangular: 3.1 m; TIJOLO - CERAMICO 9x19x39 - espessura 15cm, Largura do Componente Retangular: 0.09 m; TIJOLO - CERAMICO 9x19x39 - espessura 15cm, Área de Seção Transversal do Componente: 0.279 m2; EI-REV-Chapisco (interno) 1, Altura do Componente Retangular: 3.1 m; EI-REV-Chapisco (interno) 1, Largura do Componente Retangular: 0.005 m; EI-REV-Chapisco (interno) 1, Área de Seção Transversal do Componente: 0.0155 m2; EI-REV-Cerâmica 30x40, Largura do Componente Retangular: 0.02 m; EI-REV-Cerâmica 10x10 Vermelha, Altura do Componente Retangular: 0.1 m; EI-REV-Cerâmica 10x10 Vermelha, Largura do Componente Retangular: 0.02 m; EI-REV-Cerâmica 10x10 Vermelha, Área de Seção Transversal do Componente: 0.002 m2; EI-REV-Emboço Interno, Altura do Componente Retangular: 3.1 m; EI-REV-Emboço Interno, Largura do Componente Retangular: 0.005 m; EI-REV-Emboço Interno, Área de Seção Transversal do Componente: 0.0155 m2; EI-REV-Massa única - Maior que 10m² 1, Largura do Componente Retangular: 0.005 m; EI-REV-Chapisco (interno) 2, Altura do Componente Retangular: 3.1 m; EI-REV-Chapisco (interno) 2, Largura do Componente Retangular: 0.005 m; EI-REV-Chapisco (interno) 2, Área de Seção Transversal do Componente: 0.0155 m2; EI-REV-Pintura Epóxi cor Verde, Altura do Componente Retangular: 0.9 m; EI-REV-Pintura Epóxi cor Verde, Largura do Componente Retangular: 0.02 m; EI-REV-Pintura Epóxi cor Verde, Área de Seção Transversal do Componente: 0.018 m2; EI-REV-Massa única - Maior que 10m² 2, Área de Seção Transversal do Componente: 0.0155 m2; EI-REV-Massa Corrida PVA (interna) 2, Altura do Componente Retangular: 2.16 m; EI-REV-Massa Corrida PVA (interna) 2, Largura do Componente Retangular: 0.005 m; EI-REV-Massa Corrida PVA (interna) 2, Área de Seção Transversal do Componente: 0.0108001 m2; EI-REV-Pintura Acrílica Cor Branco Gelo 2, Altura do Componente Retangular: 2.16 m; EI-REV-Pintura Acrílica Cor Branco Gelo 2, Largura do Componente Retangular: 0.015 m; EI-REV-Pintura Acrílica Cor Branco Gelo 2, Área de Seção Transversal do Componente: 0.0324 m2
Name | TIJOLO - CERAMICO 9x19x39 - espessura 15cm, Massa (kg) | TIJOLO - CERAMICO 9x19x39 - espessura 15cm, Área de Componente Projetada (Líquida) (m2) = TIJOLO - CERAMICO 9x19x39 - espessura 15cm, Área de Componente Projetada (Bruta) (m2) | TIJOLO - CERAMICO 9x19x39 - espessura 15cm, Volume Componente (Líquido) (m3) = TIJOLO - CERAMICO 9x19x39 - espessura 15cm, Volume do componente (Bruto) (m3) | EI-REV-Chapisco (interno) 1, Massa (kg) | EI-REV-Chapisco (interno) 1, Área de Componente Projetada (Líquida) (m2) = EI-REV-Chapisco (interno) 1, Área de Componente Projetada (Bruta) (m2) | EI-REV-Chapisco (interno) 1, Volume Componente (Líquido) (m3) = EI-REV-Chapisco (interno) 1, Volume do componente (Bruto) (m3) | EI-REV-Cerâmica 30x40, Massa (kg) | EI-REV-Cerâmica 30x40, Área de Componente Projetada (Líquida) (m2) = EI-REV-Cerâmica 30x40, Área de Componente Projetada (Bruta) (m2) | EI-REV-Cerâmica 30x40, Altura do Componente Retangular (m) | EI-REV-Cerâmica 30x40, Área de Seção Transversal do Componente (m2) | EI-REV-Cerâmica 30x40, Volume Componente (Líquido) (m3) = EI-REV-Cerâmica 30x40, Volume do componente (Bruto) (m3) | EI-REV-Cerâmica 10x10 Vermelha, Massa (kg) | EI-REV-Cerâmica 10x10 Vermelha, Área de Componente Projetada (Líquida) (m2) = EI-REV-Cerâmica 10x10 Vermelha, Área de Componente Projetada (Bruta) (m2) | EI-REV-Cerâmica 10x10 Vermelha, Volume Componente (Líquido) (m3) = EI-REV-Cerâmica 10x10 Vermelha, Volume do componente (Bruto) (m3) | EI-REV-Emboço Interno, Massa (kg) | EI-REV-Emboço Interno, Área de Componente Projetada (Líquida) (m2) = EI-REV-Emboço Interno, Área de Componente Projetada (Bruta) (m2) | EI-REV-Emboço Interno, Volume Componente (Líquido) (m3) = EI-REV-Emboço Interno, Volume do componente (Bruto) (m3) | EI-REV-Massa única - Maior que 10m² 1, Massa (kg) | EI-REV-Massa única - Maior que 10m² 1, Área de Componente Projetada (Líquida) (m2) = EI-REV-Massa única - Maior que 10m² 1, Área de Componente Projetada (Bruta) (m2) | EI-REV-Massa única - Maior que 10m² 1, Altura do Componente Retangular (m) = EI-REV-Pintura Acrílica Cor Branco Gelo 1, Altura do Componente Retangular (m) | EI-REV-Massa única - Maior que 10m² 1, Área de Seção Transversal do Componente (m2) | EI-REV-Massa única - Maior que 10m² 1, Volume Componente (Líquido) (m3) = EI-REV-Massa única - Maior que 10m² 1, Volume do componente (Bruto) (m3) | EI-REV-Pintura Acrílica Cor Branco Gelo 1, Massa (kg) | EI-REV-Pintura Acrílica Cor Branco Gelo 1, Área de Componente Projetada (Líquida) (m2) = EI-REV-Pintura Acrílica Cor Branco Gelo 1, Área de Componente Projetada (Bruta) (m2) | EI-REV-Pintura Acrílica Cor Branco Gelo 1, Largura do Componente Retangular (m) | EI-REV-Pintura Acrílica Cor Branco Gelo 1, Área de Seção Transversal do Componente (m2) | EI-REV-Pintura Acrílica Cor Branco Gelo 1, Volume Componente (Líquido) (m3) = EI-REV-Pintura Acrílica Cor Branco Gelo 1, Volume do componente (Bruto) (m3) | EI-REV-Chapisco (interno) 2, Massa (kg) | EI-REV-Chapisco (interno) 2, Área de Componente Projetada (Líquida) (m2) = EI-REV-Chapisco (interno) 2, Área de Componente Projetada (Bruta) (m2) | EI-REV-Chapisco (interno) 2, Volume Componente (Líquido) (m3) = EI-REV-Chapisco (interno) 2, Volume do componente (Bruto) (m3) | EI-REV-Pintura Epóxi cor Verde, Massa (kg) | EI-REV-Pintura Epóxi cor Verde, Área de Componente Projetada (Líquida) (m2) = EI-REV-Pintura Epóxi cor Verde, Área de Componente Projetada (Bruta) (m2) | EI-REV-Pintura Epóxi cor Verde, Volume Componente (Líquido) (m3) = EI-REV-Pintura Epóxi cor Verde, Volume do componente (Bruto) (m3) | EI-REV-Massa única - Maior que 10m² 2, Massa (kg) | EI-REV-Massa única - Maior que 10m² 2, Área de Componente Projetada (Líquida) (m2) = EI-REV-Massa única - Maior que 10m² 2, Área de Componente Projetada (Bruta) (m2) | EI-REV-Massa única - Maior que 10m² 2, Volume Componente (Líquido) (m3) = EI-REV-Massa única - Maior que 10m² 2, Volume do componente (Bruto) (m3) | EI-REV-Massa Corrida PVA (interna) 2, Massa (kg) | EI-REV-Massa Corrida PVA (interna) 2, Área de Componente Projetada (Líquida) (m2) = EI-REV-Massa Corrida PVA (interna) 2, Área de Componente Projetada (Bruta) (m2) | EI-REV-Massa Corrida PVA (interna) 2, Volume Componente (Líquido) (m3) = EI-REV-Massa Corrida PVA (interna) 2, Volume do componente (Bruto) (m3) | EI-REV-Pintura Acrílica Cor Branco Gelo 2, Massa (kg) | EI-REV-Pintura Acrílica Cor Branco Gelo 2, Área de Componente Projetada (Líquida) (m2) = EI-REV-Pintura Acrílica Cor Branco Gelo 2, Área de Componente Projetada (Bruta) (m2) | EI-REV-Pintura Acrílica Cor Branco Gelo 2, Volume Componente (Líquido) (m3) = EI-REV-Pintura Acrílica Cor Branco Gelo 2, Volume do componente (Bruto) (m3)
AL09 | 262.182 | 4.49558 | 0.404602 | 25.2191 | 3.87952 | 0.0193993 | 100.165 | 2.72974 | 1.8 | 0.036 | 0.0500827 | 6.85608 | 0.186502 | 0.00342804 | 25.2169 | 3.87952 | 0.0193976 | 8.33348 | 1.28207 | 1.17 | 0.00585001 | 0.00641037 | 22.3655 | 2.17038 | 0.00999999 | 0.0117 | 0.0172042 | 28.4315 | 4.37408 | 0.0218704 | 39.1965 | 1.67852 | 0.0301512 | 28.3437 | 4.36058 | 0.0218029 | 18.4188 | 2.83365 | 0.0141683 | 62.9219 | 4.013 | 0.0484015 | Component Quantities - EI-REV-Massa única - Maior que 10m² 1: 2 with these values
AL09 | 36.2121 | 0.620921 | 0.0558829 | 4.12376 | 0.634425 | 0.00317213 | 11.9908 | 0.29977 | 1.2 | 0.024 | 0.0059954 | 0.9999 | 0.0249975 | 0.00049995 | 4.12381 | 0.634433 | 0.00317216 | 2.09245 | 0.321916 | 1.77 | 0.00885001 | 0.00160958 | 4.88573 | 0.424756 | 0.00999998 | 0.0177 | 0.00375825 | 2.45648 | 0.377921 | 0.0018896 | 3.3099 | 0.157478 | 0.00254608 | 2.36874 | 0.364421 | 0.00182211 | 1.48687 | 0.228749 | 0.00114375 | 5.26493 | 0.367146 | 0.00404994 | Component Quantities - EI-REV-Massa Corrida PVA (interna) 1, Massa: 2.04794 kg; EI-REV-Massa Corrida PVA (interna) 1, Área de Componente Projetada (Líquida): 0.315066 m2; EI-REV-Massa Corrida PVA (interna) 1, Área de Componente Projetada (Bruta): 0.315066 m2; EI-REV-Massa Corrida PVA (interna) 1, Altura do Componente Retangular: 1.77 m; EI-REV-Massa Corrida PVA (interna) 1, Largura do Componente Retangular: 0.00500003 m; EI-REV-Massa Corrida PVA (interna) 1, Área de Seção Transversal do Componente: 0.00885005 m2; EI-REV-Massa Corrida PVA (interna) 1, Volume Componente (Líquido): 0.00157534 m3; EI-REV-Massa Corrida PVA (interna) 1, Volume do componente (Bruto): 0.00157534 m3

# IfcWall: FNDE-AL09-I3-I5 (verde-vermelho) 150 x 3100 (2)
In: TÉRREO
Classification: Parede (Classificação Archicad); Material: TIJOLO - CERAMICO 9x19x39 - espessura 15cm, EI-REV-Chapisco (interno) (2), EI-REV-Cerâmica 30x40, EI-REV-Cerâmica 10x10 Vermelha, EI-REV-Emboço Interno, EI-REV-Massa única - Maior que 10m² (2), EI-REV-Massa Corrida PVA (interna) (2), EI-REV-Pintura Acrílica Cor Branco Gelo (2), EI-REV-Pintura Epóxi cor Verde
FNDE - Alvenarias: Alvenaria de Vedação / Edificação; Sistemas de Cobertura: -; Esquadrias - Fechamentos metálicos e Gradis: -; 1_Bloco: BLOCO B; 0_ID: AL09
Pset_WallCommon - IsExternal: no; LoadBearing: no
Component Quantities - TIJOLO - CERAMICO 9x19x39 - espessura 15cm, Altura do Componente Retangular: 3.1 m; TIJOLO - CERAMICO 9x19x39 - espessura 15cm, Largura do Componente Retangular: 0.09 m; TIJOLO - CERAMICO 9x19x39 - espessura 15cm, Área de Seção Transversal do Componente: 0.279 m2; EI-REV-Chapisco (interno) 1, Altura do Componente Retangular: 3.1 m; EI-REV-Chapisco (interno) 1, Largura do Componente Retangular: 0.005 m; EI-REV-Chapisco (interno) 1, Área de Seção Transversal do Componente: 0.0155 m2; EI-REV-Cerâmica 30x40, Altura do Componente Retangular: 1.2 m; EI-REV-Cerâmica 30x40, Largura do Componente Retangular: 0.02 m; EI-REV-Cerâmica 30x40, Área de Seção Transversal do Componente: 0.024 m2; EI-REV-Cerâmica 10x10 Vermelha, Altura do Componente Retangular: 0.1 m; EI-REV-Cerâmica 10x10 Vermelha, Largura do Componente Retangular: 0.02 m; EI-REV-Cerâmica 10x10 Vermelha, Área de Seção Transversal do Componente: 0.002 m2; EI-REV-Emboço Interno, Altura do Componente Retangular: 3.1 m; EI-REV-Emboço Interno, Largura do Componente Retangular: 0.005 m; EI-REV-Emboço Interno, Área de Seção Transversal do Componente: 0.0155 m2; EI-REV-Massa única - Maior que 10m² 1, Altura do Componente Retangular: 1.77 m; EI-REV-Massa única - Maior que 10m² 1, Largura do Componente Retangular: 0.005 m; EI-REV-Massa única - Maior que 10m² 1, Área de Seção Transversal do Componente: 0.00885001 m2; EI-REV-Massa Corrida PVA (interna) 1, Altura do Componente Retangular: 1.77 m; EI-REV-Massa Corrida PVA (interna) 1, Largura do Componente Retangular: 0.00500003 m; EI-REV-Massa Corrida PVA (interna) 1, Área de Seção Transversal do Componente: 0.00885005 m2; EI-REV-Pintura Acrílica Cor Branco Gelo 1, Altura do Componente Retangular: 1.77 m; EI-REV-Pintura Acrílica Cor Branco Gelo 1, Largura do Componente Retangular: 0.00999998 m; EI-REV-Pintura Acrílica Cor Branco Gelo 1, Área de Seção Transversal do Componente: 0.0177 m2; EI-REV-Chapisco (interno) 2, Altura do Componente Retangular: 3.1 m; EI-REV-Chapisco (interno) 2, Largura do Componente Retangular: 0.005 m; EI-REV-Chapisco (interno) 2, Área de Seção Transversal do Componente: 0.0155 m2; EI-REV-Pintura Epóxi cor Verde, Altura do Componente Retangular: 0.9 m; EI-REV-Pintura Epóxi cor Verde, Largura do Componente Retangular: 0.02 m; EI-REV-Pintura Epóxi cor Verde, Área de Seção Transversal do Componente: 0.018 m2; EI-REV-Massa única - Maior que 10m² 2, Área de Seção Transversal do Componente: 0.0155 m2; EI-REV-Massa Corrida PVA (interna) 2, Altura do Componente Retangular: 2.16 m; EI-REV-Massa Corrida PVA (interna) 2, Largura do Componente Retangular: 0.005 m; EI-REV-Massa Corrida PVA (interna) 2, Área de Seção Transversal do Componente: 0.0108001 m2; EI-REV-Pintura Acrílica Cor Branco Gelo 2, Altura do Componente Retangular: 2.16 m; EI-REV-Pintura Acrílica Cor Branco Gelo 2, Largura do Componente Retangular: 0.015 m; EI-REV-Pintura Acrílica Cor Branco Gelo 2, Área de Seção Transversal do Componente: 0.0324 m2
Name | TIJOLO - CERAMICO 9x19x39 - espessura 15cm, Massa (kg) | TIJOLO - CERAMICO 9x19x39 - espessura 15cm, Área de Componente Projetada (Líquida) (m2) = TIJOLO - CERAMICO 9x19x39 - espessura 15cm, Área de Componente Projetada (Bruta) (m2) | TIJOLO - CERAMICO 9x19x39 - espessura 15cm, Volume Componente (Líquido) (m3) = TIJOLO - CERAMICO 9x19x39 - espessura 15cm, Volume do componente (Bruto) (m3) | EI-REV-Chapisco (interno) 1, Massa (kg) | EI-REV-Chapisco (interno) 1, Área de Componente Projetada (Líquida) (m2) = EI-REV-Chapisco (interno) 1, Área de Componente Projetada (Bruta) (m2) | EI-REV-Chapisco (interno) 1, Volume Componente (Líquido) (m3) = EI-REV-Chapisco (interno) 1, Volume do componente (Bruto) (m3) | EI-REV-Cerâmica 30x40, Massa (kg) | EI-REV-Cerâmica 30x40, Área de Componente Projetada (Líquida) (m2) = EI-REV-Cerâmica 30x40, Área de Componente Projetada (Bruta) (m2) | EI-REV-Cerâmica 30x40, Volume Componente (Líquido) (m3) = EI-REV-Cerâmica 30x40, Volume do componente (Bruto) (m3) | EI-REV-Cerâmica 10x10 Vermelha, Massa (kg) | EI-REV-Cerâmica 10x10 Vermelha, Área de Componente Projetada (Líquida) (m2) = EI-REV-Cerâmica 10x10 Vermelha, Área de Componente Projetada (Bruta) (m2) | EI-REV-Cerâmica 10x10 Vermelha, Volume Componente (Líquido) (m3) = EI-REV-Cerâmica 10x10 Vermelha, Volume do componente (Bruto) (m3) | EI-REV-Emboço Interno, Massa (kg) | EI-REV-Emboço Interno, Área de Componente Projetada (Líquida) (m2) = EI-REV-Emboço Interno, Área de Componente Projetada (Bruta) (m2) | EI-REV-Emboço Interno, Volume Componente (Líquido) (m3) = EI-REV-Emboço Interno, Volume do componente (Bruto) (m3) | EI-REV-Massa única - Maior que 10m² 1, Massa (kg) | EI-REV-Massa única - Maior que 10m² 1, Área de Componente Projetada (Líquida) (m2) = EI-REV-Massa única - Maior que 10m² 1, Área de Componente Projetada (Bruta) (m2) | EI-REV-Massa única - Maior que 10m² 1, Volume Componente (Líquido) (m3) = EI-REV-Massa única - Maior que 10m² 1, Volume do componente (Bruto) (m3) | EI-REV-Massa Corrida PVA (interna) 1, Massa (kg) | EI-REV-Massa Corrida PVA (interna) 1, Área de Componente Projetada (Líquida) (m2) = EI-REV-Massa Corrida PVA (interna) 1, Área de Componente Projetada (Bruta) (m2) | EI-REV-Massa Corrida PVA (interna) 1, Volume Componente (Líquido) (m3) = EI-REV-Massa Corrida PVA (interna) 1, Volume do componente (Bruto) (m3) | EI-REV-Pintura Acrílica Cor Branco Gelo 1, Massa (kg) | EI-REV-Pintura Acrílica Cor Branco Gelo 1, Área de Componente Projetada (Líquida) (m2) = EI-REV-Pintura Acrílica Cor Branco Gelo 1, Área de Componente Projetada (Bruta) (m2) | EI-REV-Pintura Acrílica Cor Branco Gelo 1, Volume Componente (Líquido) (m3) = EI-REV-Pintura Acrílica Cor Branco Gelo 1, Volume do componente (Bruto) (m3) | EI-REV-Chapisco (interno) 2, Massa (kg) | EI-REV-Chapisco (interno) 2, Área de Componente Projetada (Líquida) (m2) = EI-REV-Chapisco (interno) 2, Área de Componente Projetada (Bruta) (m2) | EI-REV-Chapisco (interno) 2, Volume Componente (Líquido) (m3) = EI-REV-Chapisco (interno) 2, Volume do componente (Bruto) (m3) | EI-REV-Pintura Epóxi cor Verde, Massa (kg) | EI-REV-Pintura Epóxi cor Verde, Área de Componente Projetada (Líquida) (m2) = EI-REV-Pintura Epóxi cor Verde, Área de Componente Projetada (Bruta) (m2) | EI-REV-Pintura Epóxi cor Verde, Volume Componente (Líquido) (m3) = EI-REV-Pintura Epóxi cor Verde, Volume do componente (Bruto) (m3) | EI-REV-Massa única - Maior que 10m² 2, Massa (kg) | EI-REV-Massa única - Maior que 10m² 2, Área de Componente Projetada (Líquida) (m2) = EI-REV-Massa única - Maior que 10m² 2, Área de Componente Projetada (Bruta) (m2) | EI-REV-Massa única - Maior que 10m² 2, Volume Componente (Líquido) (m3) = EI-REV-Massa única - Maior que 10m² 2, Volume do componente (Bruto) (m3) | EI-REV-Massa Corrida PVA (interna) 2, Massa (kg) | EI-REV-Massa Corrida PVA (interna) 2, Área de Componente Projetada (Líquida) (m2) = EI-REV-Massa Corrida PVA (interna) 2, Área de Componente Projetada (Bruta) (m2) | EI-REV-Massa Corrida PVA (interna) 2, Volume Componente (Líquido) (m3) = EI-REV-Massa Corrida PVA (interna) 2, Volume do componente (Bruto) (m3) | EI-REV-Pintura Acrílica Cor Branco Gelo 2, Massa (kg) | EI-REV-Pintura Acrílica Cor Branco Gelo 2, Área de Componente Projetada (Líquida) (m2) = EI-REV-Pintura Acrílica Cor Branco Gelo 2, Área de Componente Projetada (Bruta) (m2) | EI-REV-Pintura Acrílica Cor Branco Gelo 2, Volume Componente (Líquido) (m3) = EI-REV-Pintura Acrílica Cor Branco Gelo 2, Volume do componente (Bruto) (m3)
AL09 | 142.852 | 2.44945 | 0.220451 | 18.2029 | 2.80045 | 0.0140023 | 49.4389 | 1.23597 | 0.0247194 | 4.12 | 0.103 | 0.00206 | 18.1152 | 2.78695 | 0.0139348 | 9.14725 | 1.40727 | 0.00703635 | 9.10276 | 1.40042 | 0.00700212 | 20.8185 | 1.8054 | 0.0160142 | 19.8263 | 3.0502 | 0.015251 | 26.6106 | 1.02348 | 0.0204697 | 19.9131 | 3.06355 | 0.0153178 | 13.0542 | 2.00833 | 0.0100417 | 35.2487 | 2.04926 | 0.0271144
AL09 | 469.247 | 8.04607 | 0.724146 | 48.2629 | 7.42507 | 0.0371253 | 125.829 | 3.14573 | 0.0629146 | 10.8001 | 0.270002 | 0.00540005 | 47.4732 | 7.30357 | 0.0365178 | 24.3109 | 3.74013 | 0.0187007 | 24.2664 | 3.73328 | 0.0186665 | 55.0208 | 4.77904 | 0.0423237 | 48.051 | 7.39247 | 0.0369623 | 63.1806 | 2.43002 | 0.0486005 | 47.9188 | 7.37212 | 0.0368606 | 31.149 | 4.79214 | 0.0239608 | 107.104 | 6.27455 | 0.0823874

# IfcWall: FNDE-AL09-I3-I7 (verde-amarela) (sem rodameio) 150 x 3100, AL09
In: TÉRREO
Classification: Parede (Classificação Archicad); Material: TIJOLO - CERAMICO 9x19x39 - espessura 15cm, EI-REV-Chapisco (interno) (2), EI-REV-Cerâmica 10x10 Amarela, EI-REV-Cerâmica 10x10 Branca, EI-REV-Emboço Interno, EI-REV-Massa única - Maior que 10m² (2), EI-REV-Massa Corrida PVA (interna) (2), EI-REV-Pintura Acrílica Cor Branco Gelo (2), EI-REV-Pintura Epóxi cor Verde
FNDE - Alvenarias: Alvenaria de Vedação / Edificação; Sistemas de Cobertura: -; Esquadrias - Fechamentos metálicos e Gradis: -; 1_Bloco: BLOCO B; 0_ID: AL09
Pset_WallCommon - IsExternal: no; LoadBearing: no
Component Quantities - TIJOLO - CERAMICO 9x19x39 - espessura 15cm, Massa: 619.184 kg; TIJOLO - CERAMICO 9x19x39 - espessura 15cm, Área de Componente Projetada (Líquida): 10.617 m2; TIJOLO - CERAMICO 9x19x39 - espessura 15cm, Área de Componente Projetada (Bruta): 12.717 m2; TIJOLO - CERAMICO 9x19x39 - espessura 15cm, Altura do Componente Retangular: 3.1 m; TIJOLO - CERAMICO 9x19x39 - espessura 15cm, Largura do Componente Retangular: 0.09 m; TIJOLO - CERAMICO 9x19x39 - espessura 15cm, Área de Seção Transversal do Componente: 0.279 m2; TIJOLO - CERAMICO 9x19x39 - espessura 15cm, Volume Componente (Líquido): 0.95553 m3; TIJOLO - CERAMICO 9x19x39 - espessura 15cm, Volume do componente (Bruto): 1.14453 m3; EI-REV-Chapisco (interno) 1, Massa: 65.7976 kg; EI-REV-Chapisco (interno) 1, Área de Componente Projetada (Líquida): 10.1227 m2; EI-REV-Chapisco (interno) 1, Área de Componente Projetada (Bruta): 12.2227 m2; EI-REV-Chapisco (interno) 1, Altura do Componente Retangular: 3.06 m; EI-REV-Chapisco (interno) 1, Largura do Componente Retangular: 0.005 m; EI-REV-Chapisco (interno) 1, Área de Seção Transversal do Componente: 0.0153 m2; EI-REV-Chapisco (interno) 1, Volume Componente (Líquido): 0.0506135 m3; EI-REV-Chapisco (interno) 1, Volume do componente (Bruto): 0.0611135 m3; EI-REV-Cerâmica 10x10 Amarela, Massa: 166.854 kg; EI-REV-Cerâmica 10x10 Amarela, Área de Componente Projetada (Líquida): 4.392 m2; EI-REV-Cerâmica 10x10 Amarela, Área de Componente Projetada (Bruta): 4.392 m2; EI-REV-Cerâmica 10x10 Amarela, Altura do Componente Retangular: 0.9 m; EI-REV-Cerâmica 10x10 Amarela, Largura do Componente Retangular: 0.02 m; EI-REV-Cerâmica 10x10 Amarela, Área de Seção Transversal do Componente: 0.018 m2; EI-REV-Cerâmica 10x10 Amarela, Volume Componente (Líquido): 0.0834271 m3; EI-REV-Cerâmica 10x10 Amarela, Volume do componente (Bruto): 0.0834271 m3; EI-REV-Cerâmica 10x10 Branca, Massa: 18.5394 kg; EI-REV-Cerâmica 10x10 Branca, Área de Componente Projetada (Líquida): 0.488 m2; EI-REV-Cerâmica 10x10 Branca, Área de Componente Projetada (Bruta): 0.488 m2; EI-REV-Cerâmica 10x10 Branca, Altura do Componente Retangular: 0.1 m; EI-REV-Cerâmica 10x10 Branca, Largura do Componente Retangular: 0.02 m; EI-REV-Cerâmica 10x10 Branca, Área de Seção Transversal do Componente: 0.002 m2; EI-REV-Cerâmica 10x10 Branca, Volume Componente (Líquido): 0.00926968 m3; EI-REV-Cerâmica 10x10 Branca, Volume do componente (Bruto): 0.00926968 m3; EI-REV-Massa única - Maior que 10m² 1, Massa: 35.9301 kg; EI-REV-Massa única - Maior que 10m² 1, Área de Componente Projetada (Líquida): 5.5277 m2; EI-REV-Massa única - Maior que 10m² 1, Área de Componente Projetada (Bruta): 7.6277 m2; EI-REV-Massa única - Maior que 10m² 1, Altura do Componente Retangular: 2.06 m; EI-REV-Massa única - Maior que 10m² 1, Largura do Componente Retangular: 0.00499999 m; EI-REV-Massa única - Maior que 10m² 1, Área de Seção Transversal do Componente: 0.0103 m2; EI-REV-Massa única - Maior que 10m² 1, Volume Componente (Líquido): 0.0276385 m3; EI-REV-Massa única - Maior que 10m² 1, Volume do componente (Bruto): 0.0381385 m3; EI-REV-Massa Corrida PVA (interna) 1, Massa: 35.93 kg; EI-REV-Massa Corrida PVA (interna) 1, Área de Componente Projetada (Líquida): 5.5277 m2; EI-REV-Massa Corrida PVA (interna) 1, Área de Componente Projetada (Bruta): 7.6277 m2; EI-REV-Massa Corrida PVA (interna) 1, Altura do Componente Retangular: 2.06 m; EI-REV-Massa Corrida PVA (interna) 1, Largura do Componente Retangular: 0.00500002 m; EI-REV-Massa Corrida PVA (interna) 1, Área de Seção Transversal do Componente: 0.0103 m2; EI-REV-Massa Corrida PVA (interna) 1, Volume Componente (Líquido): 0.0276384 m3; EI-REV-Massa Corrida PVA (interna) 1, Volume do componente (Bruto): 0.0381384 m3; EI-REV-Pintura Acrílica Cor Branco Gelo 1, Massa: 86.6112 kg; EI-REV-Pintura Acrílica Cor Branco Gelo 1, Área de Componente Projetada (Líquida): 8.4575 m2; EI-REV-Pintura Acrílica Cor Branco Gelo 1, Área de Componente Projetada (Bruta): 10.5575 m2; EI-REV-Pintura Acrílica Cor Branco Gelo 1, Altura do Componente Retangular: 2.06 m; EI-REV-Pintura Acrílica Cor Branco Gelo 1, Largura do Componente Retangular: 0.01 m; EI-REV-Pintura Acrílica Cor Branco Gelo 1, Área de Seção Transversal do Componente: 0.0206 m2; EI-REV-Pintura Acrílica Cor Branco Gelo 1, Volume Componente (Líquido): 0.066624 m3; EI-REV-Pintura Acrílica Cor Branco Gelo 1, Volume do componente (Bruto): 0.087624 m3; EI-REV-Chapisco (interno) 2, Massa: 67.7853 kg; EI-REV-Chapisco (interno) 2, Área de Componente Projetada (Líquida): 10.4286 m2; EI-REV-Chapisco (interno) 2, Área de Componente Projetada (Bruta): 12.5286 m2; EI-REV-Chapisco (interno) 2, Altura do Componente Retangular: 3.06 m; EI-REV-Chapisco (interno) 2, Largura do Componente Retangular: 0.00499996 m; EI-REV-Chapisco (interno) 2, Área de Seção Transversal do Componente: 0.0152999 m2; EI-REV-Chapisco (interno) 2, Volume Componente (Líquido): 0.0521426 m3; EI-REV-Chapisco (interno) 2, Volume do componente (Bruto): 0.0626425 m3; EI-REV-Pintura Epóxi cor Verde, Massa: 119.816 kg; EI-REV-Pintura Epóxi cor Verde, Área de Componente Projetada (Líquida): 4.7045 m2; EI-REV-Pintura Epóxi cor Verde, Área de Componente Projetada (Bruta): 4.7045 m2; EI-REV-Pintura Epóxi cor Verde, Altura do Componente Retangular: 0.97 m; EI-REV-Pintura Epóxi cor Verde, Largura do Componente Retangular: 0.02 m; EI-REV-Pintura Epóxi cor Verde, Área de Seção Transversal do Componente: 0.0194 m2; EI-REV-Pintura Epóxi cor Verde, Volume Componente (Líquido): 0.0921663 m3; EI-REV-Pintura Epóxi cor Verde, Volume do componente (Bruto): 0.0921663 m3; EI-REV-Massa única - Maior que 10m² 2, Massa: 67.7862 kg; EI-REV-Massa única - Maior que 10m² 2, Área de Componente Projetada (Líquida): 10.4286 m2; EI-REV-Massa única - Maior que 10m² 2, Área de Componente Projetada (Bruta): 12.5286 m2; EI-REV-Massa única - Maior que 10m² 2, Altura do Componente Retangular: 3.06 m; EI-REV-Massa única - Maior que 10m² 2, Largura do Componente Retangular: 0.005 m; EI-REV-Massa única - Maior que 10m² 2, Área de Seção Transversal do Componente: 0.0153001 m2; EI-REV-Massa única - Maior que 10m² 2, Volume Componente (Líquido): 0.0521432 m3; EI-REV-Massa única - Maior que 10m² 2, Volume do componente (Bruto): 0.0626433 m3; EI-REV-Massa Corrida PVA (interna) 2, Massa: 38.0893 kg; EI-REV-Massa Corrida PVA (interna) 2, Área de Componente Projetada (Líquida): 5.8599 m2; EI-REV-Massa Corrida PVA (interna) 2, Área de Componente Projetada (Bruta): 7.9599 m2; EI-REV-Massa Corrida PVA (interna) 2, Altura do Componente Retangular: 2.09 m; EI-REV-Massa Corrida PVA (interna) 2, Largura do Componente Retangular: 0.005 m; EI-REV-Massa Corrida PVA (interna) 2, Área de Seção Transversal do Componente: 0.01045 m2; EI-REV-Massa Corrida PVA (interna) 2, Volume Componente (Líquido): 0.0292994 m3; EI-REV-Massa Corrida PVA (interna) 2, Volume do componente (Bruto): 0.0397994 m3; EI-REV-Pintura Acrílica Cor Branco Gelo 2, Massa: 134.396 kg; EI-REV-Pintura Acrílica Cor Branco Gelo 2, Área de Componente Projetada (Líquida): 8.0365 m2; EI-REV-Pintura Acrílica Cor Branco Gelo 2, Área de Componente Projetada (Bruta): 10.1365 m2; EI-REV-Pintura Acrílica Cor Branco Gelo 2, Altura do Componente Retangular: 2.09 m; EI-REV-Pintura Acrílica Cor Branco Gelo 2, Largura do Componente Retangular: 0.015 m; EI-REV-Pintura Acrílica Cor Branco Gelo 2, Área de Seção Transversal do Componente: 0.03135 m2; EI-REV-Pintura Acrílica Cor Branco Gelo 2, Volume Componente (Líquido): 0.103382 m3; EI-REV-Pintura Acrílica Cor Branco Gelo 2, Volume do componente (Bruto): 0.134882 m3; EI-REV-Chapisco (interno) 1: 2 with these values

# IfcWall: FNDE-AL09-I3-I7 (verde-amarela) 150 x 3100 (5)
In: TÉRREO
Classification: Parede (Classificação Archicad); Material: TIJOLO - CERAMICO 9x19x39 - espessura 15cm, EI-REV-Chapisco (interno) (2), EI-REV-Cerâmica 10x10 Amarela, EI-REV-Cerâmica 10x10 Branca, EI-REV-Emboço Interno, EI-REV-Massa única - Maior que 10m² (2), EI-REV-Massa Corrida PVA (interna) (2), EI-REV-Pintura Acrílica Cor Branco Gelo (2), EI-REV-Pintura Epóxi cor Verde
FNDE - Alvenarias: Alvenaria de Vedação / Edificação; Sistemas de Cobertura: -; Esquadrias - Fechamentos metálicos e Gradis: -; 1_Bloco: BLOCO B; 0_ID: AL09
Pset_WallCommon - IsExternal: no; LoadBearing: no
Component Quantities - TIJOLO - CERAMICO 9x19x39 - espessura 15cm, Altura do Componente Retangular: 3.1 m; TIJOLO - CERAMICO 9x19x39 - espessura 15cm, Largura do Componente Retangular: 0.09 m; TIJOLO - CERAMICO 9x19x39 - espessura 15cm, Área de Seção Transversal do Componente: 0.279 m2; EI-REV-Chapisco (interno) 1, Altura do Componente Retangular: 3.06 m; EI-REV-Chapisco (interno) 1, Largura do Componente Retangular: 0.005 m; EI-REV-Chapisco (interno) 1, Área de Seção Transversal do Componente: 0.0153 m2; EI-REV-Cerâmica 10x10 Amarela, Altura do Componente Retangular: 0.9 m; EI-REV-Cerâmica 10x10 Amarela, Largura do Componente Retangular: 0.02 m; EI-REV-Cerâmica 10x10 Amarela, Área de Seção Transversal do Componente: 0.018 m2; EI-REV-Cerâmica 10x10 Branca, Altura do Componente Retangular: 0.1 m; EI-REV-Cerâmica 10x10 Branca, Largura do Componente Retangular: 0.02 m; EI-REV-Cerâmica 10x10 Branca, Área de Seção Transversal do Componente: 0.002 m2; EI-REV-Emboço Interno, Altura do Componente Retangular: 3.06 m; EI-REV-Emboço Interno, Largura do Componente Retangular: 0.005 m; EI-REV-Emboço Interno, Área de Seção Transversal do Componente: 0.0153 m2; EI-REV-Massa única - Maior que 10m² 1, Altura do Componente Retangular: 2.06 m; EI-REV-Massa única - Maior que 10m² 1, Área de Seção Transversal do Componente: 0.0103 m2; EI-REV-Massa Corrida PVA (interna) 1, Altura do Componente Retangular: 2.06 m; EI-REV-Pintura Acrílica Cor Branco Gelo 1, Altura do Componente Retangular: 2.06 m; EI-REV-Pintura Acrílica Cor Branco Gelo 1, Largura do Componente Retangular: 0.01 m; EI-REV-Pintura Acrílica Cor Branco Gelo 1, Área de Seção Transversal do Componente: 0.0206 m2; EI-REV-Chapisco (interno) 2, Altura do Componente Retangular: 3.06 m; EI-REV-Pintura Epóxi cor Verde, Altura do Componente Retangular: 0.9 m; EI-REV-Pintura Epóxi cor Verde, Largura do Componente Retangular: 0.02 m; EI-REV-Pintura Epóxi cor Verde, Área de Seção Transversal do Componente: 0.018 m2; EI-REV-Massa única - Maior que 10m² 2, Área de Seção Transversal do Componente: 0.0153 m2; EI-REV-Massa Corrida PVA (interna) 2, Altura do Componente Retangular: 2.16 m; EI-REV-Massa Corrida PVA (interna) 2, Largura do Componente Retangular: 0.005 m; EI-REV-Pintura Acrílica Cor Branco Gelo 2, Altura do Componente Retangular: 2.16 m; EI-REV-Pintura Acrílica Cor Branco Gelo 2, Largura do Componente Retangular: 0.015 m
Name | TIJOLO - CERAMICO 9x19x39 - espessura 15cm, Massa (kg) | TIJOLO - CERAMICO 9x19x39 - espessura 15cm, Área de Componente Projetada (Líquida) (m2) | TIJOLO - CERAMICO 9x19x39 - espessura 15cm, Área de Componente Projetada (Bruta) (m2) | TIJOLO - CERAMICO 9x19x39 - espessura 15cm, Volume Componente (Líquido) (m3) | TIJOLO - CERAMICO 9x19x39 - espessura 15cm, Volume do componente (Bruto) (m3) | EI-REV-Chapisco (interno) 1, Massa (kg) | EI-REV-Chapisco (interno) 1, Área de Componente Projetada (Líquida) (m2) | EI-REV-Chapisco (interno) 1, Área de Componente Projetada (Bruta) (m2) | EI-REV-Chapisco (interno) 1, Volume Componente (Líquido) (m3) | EI-REV-Chapisco (interno) 1, Volume do componente (Bruto) (m3) | EI-REV-Cerâmica 10x10 Amarela, Massa (kg) | EI-REV-Cerâmica 10x10 Amarela, Área de Componente Projetada (Líquida) (m2) | EI-REV-Cerâmica 10x10 Amarela, Área de Componente Projetada (Bruta) (m2) | EI-REV-Cerâmica 10x10 Amarela, Volume Componente (Líquido) (m3) | EI-REV-Cerâmica 10x10 Amarela, Volume do componente (Bruto) (m3) | EI-REV-Cerâmica 10x10 Branca, Massa (kg) | EI-REV-Cerâmica 10x10 Branca, Área de Componente Projetada (Líquida) (m2) | EI-REV-Cerâmica 10x10 Branca, Área de Componente Projetada (Bruta) (m2) | EI-REV-Cerâmica 10x10 Branca, Volume Componente (Líquido) (m3) | EI-REV-Cerâmica 10x10 Branca, Volume do componente (Bruto) (m3) | EI-REV-Emboço Interno, Massa (kg) | EI-REV-Emboço Interno, Área de Componente Projetada (Líquida) (m2) | EI-REV-Emboço Interno, Área de Componente Projetada (Bruta) (m2) | EI-REV-Emboço Interno, Volume Componente (Líquido) (m3) | EI-REV-Emboço Interno, Volume do componente (Bruto) (m3) | EI-REV-Massa única - Maior que 10m² 1, Massa (kg) | EI-REV-Massa única - Maior que 10m² 1, Área de Componente Projetada (Líquida) (m2) | EI-REV-Massa única - Maior que 10m² 1, Área de Componente Projetada (Bruta) (m2) | EI-REV-Massa única - Maior que 10m² 1, Largura do Componente Retangular (m) | EI-REV-Massa única - Maior que 10m² 1, Volume Componente (Líquido) (m3) | EI-REV-Massa única - Maior que 10m² 1, Volume do componente (Bruto) (m3) | EI-REV-Massa Corrida PVA (interna) 1, Massa (kg) | EI-REV-Massa Corrida PVA (interna) 1, Área de Componente Projetada (Líquida) (m2) | EI-REV-Massa Corrida PVA (interna) 1, Área de Componente Projetada (Bruta) (m2) | EI-REV-Massa Corrida PVA (interna) 1, Largura do Componente Retangular (m) | EI-REV-Massa Corrida PVA (interna) 1, Área de Seção Transversal do Componente (m2) | EI-REV-Massa Corrida PVA (interna) 1, Volume Componente (Líquido) (m3) | EI-REV-Massa Corrida PVA (interna) 1, Volume do componente (Bruto) (m3) | EI-REV-Pintura Acrílica Cor Branco Gelo 1, Massa (kg) | EI-REV-Pintura Acrílica Cor Branco Gelo 1, Área de Componente Projetada (Líquida) (m2) | EI-REV-Pintura Acrílica Cor Branco Gelo 1, Área de Componente Projetada (Bruta) (m2) | EI-REV-Pintura Acrílica Cor Branco Gelo 1, Volume Componente (Líquido) (m3) | EI-REV-Pintura Acrílica Cor Branco Gelo 1, Volume do componente (Bruto) (m3) | EI-REV-Chapisco (interno) 2, Massa (kg) | EI-REV-Chapisco (interno) 2, Área de Componente Projetada (Líquida) (m2) | EI-REV-Chapisco (interno) 2, Área de Componente Projetada (Bruta) (m2) | EI-REV-Chapisco (interno) 2, Largura do Componente Retangular (m) | EI-REV-Chapisco (interno) 2, Área de Seção Transversal do Componente (m2) | EI-REV-Chapisco (interno) 2, Volume Componente (Líquido) (m3) | EI-REV-Chapisco (interno) 2, Volume do componente (Bruto) (m3) | EI-REV-Pintura Epóxi cor Verde, Massa (kg) | EI-REV-Pintura Epóxi cor Verde, Área de Componente Projetada (Líquida) (m2) | EI-REV-Pintura Epóxi cor Verde, Área de Componente Projetada (Bruta) (m2) | EI-REV-Pintura Epóxi cor Verde, Volume Componente (Líquido) (m3) | EI-REV-Pintura Epóxi cor Verde, Volume do componente (Bruto) (m3) | EI-REV-Massa única - Maior que 10m² 2, Massa (kg) | EI-REV-Massa única - Maior que 10m² 2, Área de Componente Projetada (Líquida) (m2) | EI-REV-Massa única - Maior que 10m² 2, Área de Componente Projetada (Bruta) (m2) | EI-REV-Massa única - Maior que 10m² 2, Volume Componente (Líquido) (m3) | EI-REV-Massa única - Maior que 10m² 2, Volume do componente (Bruto) (m3) | EI-REV-Massa Corrida PVA (interna) 2, Massa (kg) | EI-REV-Massa Corrida PVA (interna) 2, Área de Componente Projetada (Líquida) (m2) | EI-REV-Massa Corrida PVA (interna) 2, Área de Componente Projetada (Bruta) (m2) | EI-REV-Massa Corrida PVA (interna) 2, Área de Seção Transversal do Componente (m2) | EI-REV-Massa Corrida PVA (interna) 2, Volume Componente (Líquido) (m3) | EI-REV-Massa Corrida PVA (interna) 2, Volume do componente (Bruto) (m3) | EI-REV-Pintura Acrílica Cor Branco Gelo 2, Massa (kg) | EI-REV-Pintura Acrílica Cor Branco Gelo 2, Área de Componente Projetada (Líquida) (m2) | EI-REV-Pintura Acrílica Cor Branco Gelo 2, Área de Componente Projetada (Bruta) (m2) | EI-REV-Pintura Acrílica Cor Branco Gelo 2, Área de Seção Transversal do Componente (m2) | EI-REV-Pintura Acrílica Cor Branco Gelo 2, Volume Componente (Líquido) (m3) | EI-REV-Pintura Acrílica Cor Branco Gelo 2, Volume do componente (Bruto) (m3)
AL09 | 90.8888 | 1.55845 | 1.55845 | 0.140261 | 0.140261 | 8.42376 | 1.29596 | 1.29596 | 0.00647982 | 0.00647982 | 18.5396 | 0.558 | 0.558 | 0.0092698 | 0.0092698 | 2.05996 | 0.062 | 0.062 | 0.00102998 | 0.00102998 | 8.33731 | 1.28266 | 1.28266 | 0.00641332 | 0.00641332 | 5.14902 | 0.792158 | 0.792158 | 0.00499999 | 0.00396078 | 0.00396078 | 5.0951 | 0.783858 | 0.783858 | 0.00500002 | 0.0103 | 0.00391931 | 0.00391931 | 11.6673 | 1.01372 | 1.01372 | 0.00897483 | 0.00897483 | 10.0662 | 1.54866 | 1.54866 | 0.00499996 | 0.0152999 | 0.00774325 | 0.00774325 | 14.2086 | 0.546483 | 0.546483 | 0.0109297 | 0.0109297 | 10.1528 | 1.56196 | 1.56196 | 0.00780982 | 0.00780982 | 6.77381 | 1.04228 | 1.04228 | 0.0108001 | 0.00521063 | 0.00521063 | 25.5754 | 1.31156 | 1.31156 | 0.0324 | 0.0196734 | 0.0196734
AL09 | 61.4086 | 1.0584 | 2.9844 | 0.0947664 | 0.268106 | 6.50001 | 1 | 2.926 | 0.005 | 0.01463 | 5.4 | 0.135 | 0.945 | 0.0027 | 0.0189 | 0.6 | 0.015 | 0.105 | 0.0003 | 0.0021 | 6.32711 | 0.9734 | 2.8994 | 0.004867 | 0.014497 | 4.98419 | 0.7668 | 1.7928 | 0.00499999 | 0.00383399 | 0.00896398 | 4.87632 | 0.7502 | 1.7762 | 0.00500002 | 0.0103 | 0.00375101 | 0.00888103 | 12.0359 | 1.135 | 2.161 | 0.00925838 | 0.0195184 | 8.14248 | 1.2527 | 3.1787 | 0.00499996 | 0.0152999 | 0.00626345 | 0.0158934 | 6.55201 | 0.252 | 1.062 | 0.00504 | 0.02124 | 8.14256 | 1.2527 | 3.1787 | 0.00626351 | 0.0158935 | 6.41683 | 0.9872 | 2.1032 | 0.0108001 | 0.00493603 | 0.010516 | 21.9906 | 1.4436 | 2.5596 | 0.0324 | 0.0169158 | 0.0336558
AL09 | 27.617 | 0.473543 | 0.473543 | 0.0426189 | 0.0426189 | 2.94598 | 0.453228 | 0.453228 | 0.00226614 | 0.00226614 | 7.99777 | 0.238848 | 0.238848 | 0.00399889 | 0.00399889 | 0.888641 | 0.0265386 | 0.0265386 | 0.000444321 | 0.000444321 | 2.85953 | 0.439928 | 0.439928 | 0.00219964 | 0.00219964 | 1.73057 | 0.266241 | 0.266241 | 0.00500001 | 0.00133121 | 0.00133121 | 2.40057 | 0.457141 | 0.457141 | 0.00499998 | 0.0102999 | 0.00184659 | 0.00184659 | 6.11285 | 0.546695 | 0.546695 | 0.00470219 | 0.00470219 | 0 | 0 | 0 | 0.005 | 0.0153 | 0 | 0 | 0 | 0 | 0 | 0 | 0 | 0 | 0 | 0 | 0 | 0 | 0 | 0 | 0 | 0.0108 | 0 | 0 | 0 | 0 | 0 | 0.0323999 | 0 | 0
AL09 | 201.552 | 3.4614 | 5.3874 | 0.311037 | 0.484377 | 18.1708 | 2.7955 | 4.7215 | 0.0139775 | 0.0236075 | 31.5058 | 0.927001 | 1.737 | 0.0157529 | 0.0319529 | 3.50065 | 0.103 | 0.193 | 0.00175032 | 0.00355032 | 18.0843 | 2.7822 | 4.7082 | 0.013911 | 0.023541 | 12.3754 | 1.9039 | 2.9299 | 0.00500001 | 0.00951953 | 0.0146495 | 12.3214 | 1.8956 | 2.9216 | 0.00499998 | 0.0102999 | 0.00947797 | 0.0146079 | 28.383 | 2.9675 | 3.9935 | 0.0218331 | 0.0320931 | 17.9543 | 2.7622 | 4.6882 | 0.005 | 0.0153 | 0.013811 | 0.023441 | 20.3115 | 0.810001 | 1.62 | 0.0156242 | 0.0318242 | 17.9003 | 2.7539 | 4.6799 | 0.0137695 | 0.0233995 | 12.8739 | 1.9806 | 3.0966 | 0.0108 | 0.00990301 | 0.015483 | 54.8945 | 3.287 | 4.403 | 0.0323999 | 0.0422265 | 0.0589666
AL09 | 164.538 | 2.84848 | 14.7735 | 0.253917 | 1.32717 | 19.3979 | 2.9843 | 14.9093 | 0.0149215 | 0.0745465 | 41.6439 | 1.08 | 5.13 | 0.0208219 | 0.101822 | 4.62709 | 0.12 | 0.57 | 0.00231355 | 0.0113135 | 19.3115 | 2.971 | 14.896 | 0.014855 | 0.07448 | 12.1076 | 1.8627 | 9.2877 | 0.00500001 | 0.00931351 | 0.0464386 | 12.952 | 2.1016 | 9.5266 | 0.00499998 | 0.0102999 | 0.00996304 | 0.0470879 | 29.0089 | 3.80199 | 11.227 | 0.0223146 | 0.0965647 | 16.9708 | 2.6109 | 14.2709 | 0.005 | 0.0153 | 0.0130545 | 0.0713544 | 22.23 | 0.855 | 4.815 | 0.0171 | 0.0963001 | 16.9709 | 2.6109 | 14.2709 | 0.0130546 | 0.0713545 | 11.3256 | 1.7424 | 9.4424 | 0.0108 | 0.008712 | 0.0472121 | 53.5045 | 3.856 | 11.556 | 0.0323999 | 0.0411573 | 0.156657

# IfcWall: FNDE-AL09-I3-I8 (verde-cinza) 150 x 3100 (2)
In: TÉRREO
Classification: Parede (Classificação Archicad); Material: TIJOLO - CERAMICO 9x19x39 - espessura 15cm, EI-REV-Chapisco (interno) (2), EI-REV-Pintura Acrílica Cor Cinza, EI-REV-Massa única - Maior que 10m² (2), EI-REV-Massa Corrida PVA (interna) (2), EI-REV-Pintura Acrílica Cor Branco Gelo (2), EI-REV-Pintura Epóxi cor Verde
FNDE - Alvenarias: Alvenaria de Vedação / Edificação; Sistemas de Cobertura: -; Esquadrias - Fechamentos metálicos e Gradis: -; 1_Bloco: BLOCO B; 0_ID: AL09
Pset_WallCommon - IsExternal: no; LoadBearing: no
Component Quantities - TIJOLO - CERAMICO 9x19x39 - espessura 15cm, Altura do Componente Retangular: 3.1 m; TIJOLO - CERAMICO 9x19x39 - espessura 15cm, Largura do Componente Retangular: 0.09 m; TIJOLO - CERAMICO 9x19x39 - espessura 15cm, Área de Seção Transversal do Componente: 0.279 m2; EI-REV-Chapisco (interno) 1, Altura do Componente Retangular: 3.1 m; EI-REV-Chapisco (interno) 1, Largura do Componente Retangular: 0.005 m; EI-REV-Chapisco (interno) 1, Área de Seção Transversal do Componente: 0.0155 m2; EI-REV-Pintura Acrílica Cor Cinza, Altura do Componente Retangular: 0.44 m; EI-REV-Pintura Acrílica Cor Cinza, Largura do Componente Retangular: 0.01 m; EI-REV-Pintura Acrílica Cor Cinza, Área de Seção Transversal do Componente: 0.0044 m2; EI-REV-Massa única - Maior que 10m² 1, Altura do Componente Retangular: 3.1 m; EI-REV-Massa única - Maior que 10m² 1, Largura do Componente Retangular: 0.01 m; EI-REV-Massa única - Maior que 10m² 1, Área de Seção Transversal do Componente: 0.031 m2; EI-REV-Massa Corrida PVA (interna) 1, Altura do Componente Retangular: 3.1 m; EI-REV-Massa Corrida PVA (interna) 1, Largura do Componente Retangular: 0.005 m; EI-REV-Massa Corrida PVA (interna) 1, Área de Seção Transversal do Componente: 0.0155 m2; EI-REV-Pintura Acrílica Cor Branco Gelo 1, Altura do Componente Retangular: 2.66 m; EI-REV-Pintura Acrílica Cor Branco Gelo 1, Largura do Componente Retangular: 0.01 m; EI-REV-Pintura Acrílica Cor Branco Gelo 1, Área de Seção Transversal do Componente: 0.0266 m2; EI-REV-Chapisco (interno) 2, Altura do Componente Retangular: 3.1 m; EI-REV-Chapisco (interno) 2, Largura do Componente Retangular: 0.005 m; EI-REV-Chapisco (interno) 2, Área de Seção Transversal do Componente: 0.0155 m2; EI-REV-Pintura Epóxi cor Verde, Altura do Componente Retangular: 0.9 m; EI-REV-Pintura Epóxi cor Verde, Largura do Componente Retangular: 0.02 m; EI-REV-Pintura Epóxi cor Verde, Área de Seção Transversal do Componente: 0.018 m2; EI-REV-Massa única - Maior que 10m² 2, Área de Seção Transversal do Componente: 0.0155 m2; EI-REV-Massa Corrida PVA (interna) 2, Área de Seção Transversal do Componente: 0.0108003 m2; EI-REV-Pintura Acrílica Cor Branco Gelo 2, Altura do Componente Retangular: 2.16 m; EI-REV-Pintura Acrílica Cor Branco Gelo 2, Largura do Componente Retangular: 0.015 m; EI-REV-Pintura Acrílica Cor Branco Gelo 2, Área de Seção Transversal do Componente: 0.0324 m2
Name | TIJOLO - CERAMICO 9x19x39 - espessura 15cm, Massa (kg) | TIJOLO - CERAMICO 9x19x39 - espessura 15cm, Área de Componente Projetada (Líquida) (m2) | TIJOLO - CERAMICO 9x19x39 - espessura 15cm, Área de Componente Projetada (Bruta) (m2) | TIJOLO - CERAMICO 9x19x39 - espessura 15cm, Volume Componente (Líquido) (m3) | TIJOLO - CERAMICO 9x19x39 - espessura 15cm, Volume do componente (Bruto) (m3) | EI-REV-Chapisco (interno) 1, Massa (kg) | EI-REV-Chapisco (interno) 1, Área de Componente Projetada (Líquida) (m2) | EI-REV-Chapisco (interno) 1, Área de Componente Projetada (Bruta) (m2) = EI-REV-Chapisco (interno) 2, Área de Componente Projetada (Bruta) (m2) | EI-REV-Chapisco (interno) 1, Volume Componente (Líquido) (m3) | EI-REV-Chapisco (interno) 1, Volume do componente (Bruto) (m3) = EI-REV-Chapisco (interno) 2, Volume do componente (Bruto) (m3) | EI-REV-Pintura Acrílica Cor Cinza, Massa (kg) | EI-REV-Pintura Acrílica Cor Cinza, Área de Componente Projetada (Líquida) (m2) | EI-REV-Pintura Acrílica Cor Cinza, Área de Componente Projetada (Bruta) (m2) | EI-REV-Pintura Acrílica Cor Cinza, Volume Componente (Líquido) (m3) | EI-REV-Pintura Acrílica Cor Cinza, Volume do componente (Bruto) (m3) | EI-REV-Massa única - Maior que 10m² 1, Massa (kg) | EI-REV-Massa única - Maior que 10m² 1, Área de Componente Projetada (Líquida) (m2) | EI-REV-Massa única - Maior que 10m² 1, Área de Componente Projetada (Bruta) (m2) | EI-REV-Massa única - Maior que 10m² 1, Volume Componente (Líquido) (m3) | EI-REV-Massa única - Maior que 10m² 1, Volume do componente (Bruto) (m3) | EI-REV-Massa Corrida PVA (interna) 1, Massa (kg) | EI-REV-Massa Corrida PVA (interna) 1, Área de Componente Projetada (Líquida) (m2) | EI-REV-Massa Corrida PVA (interna) 1, Área de Componente Projetada (Bruta) (m2) | EI-REV-Massa Corrida PVA (interna) 1, Volume Componente (Líquido) (m3) | EI-REV-Massa Corrida PVA (interna) 1, Volume do componente (Bruto) (m3) | EI-REV-Pintura Acrílica Cor Branco Gelo 1, Massa (kg) | EI-REV-Pintura Acrílica Cor Branco Gelo 1, Área de Componente Projetada (Líquida) (m2) | EI-REV-Pintura Acrílica Cor Branco Gelo 1, Área de Componente Projetada (Bruta) (m2) | EI-REV-Pintura Acrílica Cor Branco Gelo 1, Volume Componente (Líquido) (m3) | EI-REV-Pintura Acrílica Cor Branco Gelo 1, Volume do componente (Bruto) (m3) | EI-REV-Chapisco (interno) 2, Massa (kg) | EI-REV-Chapisco (interno) 2, Área de Componente Projetada (Líquida) (m2) | EI-REV-Chapisco (interno) 2, Volume Componente (Líquido) (m3) | EI-REV-Pintura Epóxi cor Verde, Massa (kg) | EI-REV-Pintura Epóxi cor Verde, Área de Componente Projetada (Líquida) (m2) | EI-REV-Pintura Epóxi cor Verde, Área de Componente Projetada (Bruta) (m2) | EI-REV-Pintura Epóxi cor Verde, Volume Componente (Líquido) (m3) | EI-REV-Pintura Epóxi cor Verde, Volume do componente (Bruto) (m3) | EI-REV-Massa única - Maior que 10m² 2, Massa (kg) | EI-REV-Massa única - Maior que 10m² 2, Área de Componente Projetada (Líquida) (m2) | EI-REV-Massa única - Maior que 10m² 2, Área de Componente Projetada (Bruta) (m2) | EI-REV-Massa única - Maior que 10m² 2, Volume Componente (Líquido) (m3) | EI-REV-Massa única - Maior que 10m² 2, Volume do componente (Bruto) (m3) | EI-REV-Massa Corrida PVA (interna) 2, Massa (kg) | EI-REV-Massa Corrida PVA (interna) 2, Área de Componente Projetada (Líquida) (m2) | EI-REV-Massa Corrida PVA (interna) 2, Área de Componente Projetada (Bruta) (m2) | EI-REV-Massa Corrida PVA (interna) 2, Volume Componente (Líquido) (m3) | EI-REV-Massa Corrida PVA (interna) 2, Volume do componente (Bruto) (m3) | EI-REV-Pintura Acrílica Cor Branco Gelo 2, Massa (kg) | EI-REV-Pintura Acrílica Cor Branco Gelo 2, Área de Componente Projetada (Líquida) (m2) | EI-REV-Pintura Acrílica Cor Branco Gelo 2, Área de Componente Projetada (Bruta) (m2) | EI-REV-Pintura Acrílica Cor Branco Gelo 2, Volume Componente (Líquido) (m3) | EI-REV-Pintura Acrílica Cor Branco Gelo 2, Volume do componente (Bruto) (m3)
AL09 | 38.5668 | 0.688476 | 12.6135 | 0.0595167 | 1.13277 | 4.21068 | 0.649307 | 12.5743 | 0.00323899 | 0.062864 | 2.5246 | 0.235651 | 2.03565 | 0.001942 | 0.019942 | 8.07037 | 0.623818 | 12.5488 | 0.00620798 | 0.125458 | 3.81413 | 0.608808 | 12.5338 | 0.00293395 | 0.0625589 | 28.8488 | 3.08189 | 13.2069 | 0.0221914 | 0.123441 | 4.21067 | 0.649305 | 0.00323898 | 5.33422 | 0.495001 | 4.545 | 0.00410325 | 0.0851033 | 4.12292 | 0.635806 | 12.5608 | 0.00317148 | 0.0627965 | 2.35356 | 0.362084 | 8.23708 | 0.00181043 | 0.0411855 | 17.8346 | 3.033 | 10.908 | 0.0137189 | 0.131864
AL09 | 50.3876 | 0.891164 | 12.8162 | 0.0777586 | 1.15101 | 4.03641 | 0.622496 | 12.5475 | 0.00310493 | 0.0627299 | 3.02115 | 0.233628 | 2.03363 | 0.00232396 | 0.020324 | 9.87616 | 1.42051 | 13.3455 | 0.00759705 | 0.126847 | 8.88739 | 1.392 | 13.317 | 0.00683645 | 0.0664614 | 31.8271 | 3.06678 | 13.1918 | 0.0244824 | 0.125732 | 4.03639 | 0.622494 | 0.00310492 | 8.58499 | 0.423062 | 4.47306 | 0.00660384 | 0.0876039 | 3.94863 | 0.608994 | 12.534 | 0.00303741 | 0.0626623 | 2.23994 | 0.344604 | 8.2196 | 0.00172303 | 0.041098 | 23.7789 | 2.85525 | 10.7302 | 0.0182915 | 0.136416

# IfcWall: FNDE-AL09-I4-I4 150 (33)
In: TÉRREO
Classification: Parede (Classificação Archicad); Material: EI-REV-Cerâmica 30x40 0.02 m, EI-REV-Emboço Interno 0.005 m, EI-REV-Chapisco (interno) 0.005 m, TIJOLO - CERAMICO 9x19x39 - espessura 15cm 0.09 m, EI-REV-Chapisco (interno) 0.005 m, EI-REV-Emboço Interno 0.005 m, EI-REV-Cerâmica 30x40 0.02 m
FNDE - Sistemas de Cobertura: -; Esquadrias - Fechamentos metálicos e Gradis: -; 0_ID: AL09
Pset_WallCommon - IsExternal: no; LoadBearing: no
Component Quantities - EI-REV-Cerâmica 30x40 1, Espessura do Componente: 0.02 m; EI-REV-Cerâmica 30x40 1, Largura do Componente Retangular: 0.02 m; EI-REV-Emboço Interno 1, Espessura do Componente: 0.005 m; EI-REV-Emboço Interno 1, Largura do Componente Retangular: 0.005 m; TIJOLO - CERAMICO 9x19x39 - espessura 15cm, Espessura do Componente: 0.09 m; TIJOLO - CERAMICO 9x19x39 - espessura 15cm, Largura do Componente Retangular: 0.09 m; EI-REV-Cerâmica 30x40 2, Espessura do Componente: 0.02 m; EI-REV-Cerâmica 30x40 2, Largura do Componente Retangular: 0.02 m
Name | Alvenarias | 1_Bloco | EI-REV-Cerâmica 30x40 1, Massa (kg) | EI-REV-Cerâmica 30x40 1, Área de Componente Projetada (Líquida) (m2) | EI-REV-Cerâmica 30x40 1, Área de Componente Projetada (Bruta) (m2) | EI-REV-Cerâmica 30x40 1, Altura do Componente Retangular (m) = EI-REV-Emboço Interno 1, Altura do Componente Retangular (m) = TIJOLO - CERAMICO 9x19x39 - espessura 15cm, Altura do Componente Retangular (m) = EI-REV-Cerâmica 30x40 2, Altura do Componente Retangular (m) | EI-REV-Cerâmica 30x40 1, Área de Seção Transversal do Componente (m2) = EI-REV-Cerâmica 30x40 2, Área de Seção Transversal do Componente (m2) | EI-REV-Cerâmica 30x40 1, Volume Componente (Líquido) (m3) | EI-REV-Cerâmica 30x40 1, Volume do componente (Bruto) (m3) | EI-REV-Emboço Interno 1, Massa (kg) | EI-REV-Emboço Interno 1, Área de Componente Projetada (Líquida) (m2) | EI-REV-Emboço Interno 1, Área de Componente Projetada (Bruta) (m2) | EI-REV-Emboço Interno 1, Área de Seção Transversal do Componente (m2) | EI-REV-Emboço Interno 1, Volume Componente (Líquido) (m3) | EI-REV-Emboço Interno 1, Volume do componente (Bruto) (m3) | EI-REV-Chapisco (interno) 1, Massa (kg) | EI-REV-Chapisco (interno) 1, Área de Componente Projetada (Líquida) (m2) | EI-REV-Chapisco (interno) 1, Área de Componente Projetada (Bruta) (m2) | EI-REV-Chapisco (interno) 1, Espessura do Componente (m) = EI-REV-Chapisco (interno) 1, Largura do Componente Retangular (m) | EI-REV-Chapisco (interno) 1, Altura do Componente Retangular (m) | EI-REV-Chapisco (interno) 1, Área de Seção Transversal do Componente (m2) | EI-REV-Chapisco (interno) 1, Volume Componente (Líquido) (m3) | EI-REV-Chapisco (interno) 1, Volume do componente (Bruto) (m3) | TIJOLO - CERAMICO 9x19x39 - espessura 15cm, Massa (kg) | TIJOLO - CERAMICO 9x19x39 - espessura 15cm, Área de Componente Projetada (Líquida) (m2) | TIJOLO - CERAMICO 9x19x39 - espessura 15cm, Área de Componente Projetada (Bruta) (m2) | TIJOLO - CERAMICO 9x19x39 - espessura 15cm, Área de Seção Transversal do Componente (m2) | TIJOLO - CERAMICO 9x19x39 - espessura 15cm, Volume Componente (Líquido) (m3) | TIJOLO - CERAMICO 9x19x39 - espessura 15cm, Volume do componente (Bruto) (m3) | EI-REV-Emboço Interno 2, Massa (kg) | EI-REV-Emboço Interno 2, Área de Componente Projetada (Líquida) (m2) | EI-REV-Emboço Interno 2, Área de Componente Projetada (Bruta) (m2) | EI-REV-Emboço Interno 2, Espessura do Componente (m) = EI-REV-Emboço Interno 2, Largura do Componente Retangular (m) | EI-REV-Emboço Interno 2, Altura do Componente Retangular (m) | EI-REV-Emboço Interno 2, Área de Seção Transversal do Componente (m2) | EI-REV-Emboço Interno 2, Volume Componente (Líquido) (m3) | EI-REV-Emboço Interno 2, Volume do componente (Bruto) (m3) | EI-REV-Cerâmica 30x40 2, Massa (kg) | EI-REV-Cerâmica 30x40 2, Área de Componente Projetada (Líquida) (m2) | EI-REV-Cerâmica 30x40 2, Área de Componente Projetada (Bruta) (m2) | EI-REV-Cerâmica 30x40 2, Volume Componente (Líquido) (m3) | EI-REV-Cerâmica 30x40 2, Volume do componente (Bruto) (m3) | EI-REV-Chapisco (interno) 1
AL09 | Mureta | BLOCO B | 8.38892 | 0.209724 | 0.220724 | 0.58 | 0.0116 | 0.00419446 | 0.00441446 | 1.44134 | 0.221744 | 0.235744 | 0.0029 | 0.00110872 | 0.00117872 | 1.44101 | 0.221694 | 0.238494 | 0.005 | 0.58 | 0.0029 | 0.00110847 | 0.00119247 | 13.5235 | 0.231884 | 0.249284 | 0.0522 | 0.0208696 | 0.0224356 | 1.37508 | 0.211551 | 0.227751 | 0.005 | 0.58 | 0.0029 | 0.00105776 | 0.00113876 | 8.50934 | 0.212734 | 0.212734 | 0.00425467 | 0.00425467 | Component Quantities - EI-REV-Chapisco (interno) 2, Massa: 1.39296 kg; EI-REV-Chapisco (interno) 2, Área de Componente Projetada (Líquida): 0.214301 m2; EI-REV-Chapisco (interno) 2, Área de Componente Projetada (Bruta): 0.230501 m2; EI-REV-Chapisco (interno) 2, Espessura do Componente: 0.005 m; EI-REV-Chapisco (interno) 2, Altura do Componente Retangular: 0.58 m; EI-REV-Chapisco (interno) 2, Largura do Componente Retangular: 0.005 m; EI-REV-Chapisco (interno) 2, Área de Seção Transversal do Componente: 0.0029 m2; EI-REV-Chapisco (interno) 2, Volume Componente (Líquido): 0.00107151 m3; EI-REV-Chapisco (interno) 2, Volume do componente (Bruto): 0.00115251 m3
AL09 | Mureta | BLOCO B | 10.1639 | 0.254098 | 0.269498 | 0.78 | 0.0156 | 0.00508196 | 0.00538996 | 1.72801 | 0.265848 | 0.285098 | 0.0039 | 0.00132924 | 0.00142549 | 1.72834 | 0.265898 | 0.288998 | 0.005 | 0.78 | 0.0039 | 0.00132949 | 0.00144499 | 15.9213 | 0.272998 | 0.296398 | 0.0702 | 0.0245698 | 0.0266758 | 1.72379 | 0.265198 | 0.288598 | 0.005 | 0.78 | 0.0039 | 0.00132599 | 0.00144299 | 10.9199 | 0.272998 | 0.272998 | 0.00545996 | 0.00545996 | Component Quantities - EI-REV-Chapisco (interno) 2, Massa: 1.74914 kg; EI-REV-Chapisco (interno) 2, Área de Componente Projetada (Líquida): 0.269098 m2; EI-REV-Chapisco (interno) 2, Área de Componente Projetada (Bruta): 0.292498 m2; EI-REV-Chapisco (interno) 2, Espessura do Componente: 0.005 m; EI-REV-Chapisco (interno) 2, Altura do Componente Retangular: 0.78 m; EI-REV-Chapisco (interno) 2, Largura do Componente Retangular: 0.005 m; EI-REV-Chapisco (interno) 2, Área de Seção Transversal do Componente: 0.0039 m2; EI-REV-Chapisco (interno) 2, Volume Componente (Líquido): 0.00134549 m3; EI-REV-Chapisco (interno) 2, Volume do componente (Bruto): 0.00146249 m3
AL09 | Mureta | BLOCO B | 9.85583 | 0.246396 | 0.269496 | 0.78 | 0.0156 | 0.00492791 | 0.00538991 | 1.70297 | 0.261996 | 0.285096 | 0.0039 | 0.00130998 | 0.00142548 | 1.72832 | 0.265896 | 0.288996 | 0.005 | 0.78 | 0.0039 | 0.00132948 | 0.00144498 | 15.9211 | 0.272996 | 0.296396 | 0.0702 | 0.0245696 | 0.0266756 | 1.74912 | 0.269096 | 0.288596 | 0.005 | 0.78 | 0.0039 | 0.00134548 | 0.00144298 | 10.2958 | 0.257396 | 0.272996 | 0.00514791 | 0.00545991 | Component Quantities - EI-REV-Chapisco (interno) 2, Massa: 1.74912 kg; EI-REV-Chapisco (interno) 2, Área de Componente Projetada (Líquida): 0.269096 m2; EI-REV-Chapisco (interno) 2, Área de Componente Projetada (Bruta): 0.292496 m2; EI-REV-Chapisco (interno) 2, Espessura do Componente: 0.005 m; EI-REV-Chapisco (interno) 2, Altura do Componente Retangular: 0.78 m; EI-REV-Chapisco (interno) 2, Largura do Componente Retangular: 0.005 m; EI-REV-Chapisco (interno) 2, Área de Seção Transversal do Componente: 0.0039 m2; EI-REV-Chapisco (interno) 2, Volume Componente (Líquido): 0.00134548 m3; EI-REV-Chapisco (interno) 2, Volume do componente (Bruto): 0.00146248 m3
AL09 | Mureta | BLOCO A | 15.1362 | 0.378405 | 0.396006 | 0.91 | 0.0182 | 0.00756811 | 0.00792011 | 2.57696 | 0.396455 | 0.418705 | 0.00455 | 0.00198227 | 0.00209352 | 2.57761 | 0.396555 | 0.423255 | 0.005 | 0.91 | 0.00455 | 0.00198277 | 0.00211627 | 23.8823 | 0.409504 | 0.436804 | 0.0819 | 0.0368553 | 0.0393123 | 2.54803 | 0.392005 | 0.418705 | 0.005 | 0.91 | 0.00455 | 0.00196002 | 0.00209352 | 14.7842 | 0.369605 | 0.396005 | 0.00739211 | 0.00792011 | 2 with these values
AL09 | Mureta | BLOCO A | 13.2441 | 0.331103 | 0.346504 | 0.91 | 0.0182 | 0.00662206 | 0.00693007 | 2.24544 | 0.345453 | 0.364816 | 0.00455 | 0.00172726 | 0.00182408 | 2.24999 | 0.346153 | 0.369366 | 0.005 | 0.91 | 0.00455 | 0.00173076 | 0.00184683 | 20.9429 | 0.359103 | 0.384153 | 0.0819 | 0.0323193 | 0.0345738 | 2.24772 | 0.345803 | 0.369316 | 0.005 | 0.91 | 0.00455 | 0.00172901 | 0.00184658 | 13.1041 | 0.327603 | 0.351004 | 0.00655206 | 0.00702007 | Component Quantities - EI-REV-Chapisco (interno) 2, Massa: 2.27729 kg; EI-REV-Chapisco (interno) 2, Área de Componente Projetada (Líquida): 0.350353 m2; EI-REV-Chapisco (interno) 2, Área de Componente Projetada (Bruta): 0.373866 m2; EI-REV-Chapisco (interno) 2, Espessura do Componente: 0.005 m; EI-REV-Chapisco (interno) 2, Altura do Componente Retangular: 0.91 m; EI-REV-Chapisco (interno) 2, Largura do Componente Retangular: 0.005 m; EI-REV-Chapisco (interno) 2, Área de Seção Transversal do Componente: 0.00455 m2; EI-REV-Chapisco (interno) 2, Volume Componente (Líquido): 0.00175176 m3; EI-REV-Chapisco (interno) 2, Volume do componente (Bruto): 0.00186933 m3
AL09 | Mureta | BLOCO A | 15.1362 | 0.378406 | 0.396006 | 0.91 | 0.0182 | 0.00756812 | 0.00792012 | 2.57695 | 0.396454 | 0.418704 | 0.00455 | 0.00198227 | 0.00209352 | 2.5776 | 0.396554 | 0.423254 | 0.005 | 0.91 | 0.00455 | 0.00198277 | 0.00211627 | 23.8823 | 0.409504 | 0.436804 | 0.0819 | 0.0368553 | 0.0393123 | 2.52072 | 0.387803 | 0.414203 | 0.005 | 0.91 | 0.00455 | 0.00193902 | 0.00207102 | 14.6162 | 0.365406 | 0.391506 | 0.00730812 | 0.00783012 | Component Quantities - EI-REV-Chapisco (interno) 2, Massa: 2.5503 kg; EI-REV-Chapisco (interno) 2, Área de Componente Projetada (Líquida): 0.392353 m2; EI-REV-Chapisco (interno) 2, Área de Componente Projetada (Bruta): 0.418753 m2; EI-REV-Chapisco (interno) 2, Espessura do Componente: 0.005 m; EI-REV-Chapisco (interno) 2, Altura do Componente Retangular: 0.91 m; EI-REV-Chapisco (interno) 2, Largura do Componente Retangular: 0.005 m; EI-REV-Chapisco (interno) 2, Área de Seção Transversal do Componente: 0.00455 m2; EI-REV-Chapisco (interno) 2, Volume Componente (Líquido): 0.00196177 m3; EI-REV-Chapisco (interno) 2, Volume do componente (Bruto): 0.00209377 m3
AL09 | Mureta | BLOCO B | 16.0272 | 0.400742 | 0.416142 | 0.8 | 0.016 | 0.00801361 | 0.00832161 | 2.71458 | 0.417628 | 0.437128 | 0.004 | 0.00208814 | 0.00218564 | 2.71426 | 0.417578 | 0.440978 | 0.005 | 0.8 | 0.004 | 0.00208789 | 0.00220489 | 25.6608 | 0.44 | 0.464 | 0.072 | 0.0396 | 0.04176 | 2.74125 | 0.421731 | 0.445131 | 0.005 | 0.8 | 0.004 | 0.00210866 | 0.00222566 | 16.9659 | 0.424148 | 0.424148 | 0.00848295 | 0.00848295 | Component Quantities - EI-REV-Chapisco (interno) 2, Massa: 2.76628 kg; EI-REV-Chapisco (interno) 2, Área de Componente Projetada (Líquida): 0.425581 m2; EI-REV-Chapisco (interno) 2, Área de Componente Projetada (Bruta): 0.448981 m2; EI-REV-Chapisco (interno) 2, Espessura do Componente: 0.005 m; EI-REV-Chapisco (interno) 2, Altura do Componente Retangular: 0.8 m; EI-REV-Chapisco (interno) 2, Largura do Componente Retangular: 0.005 m; EI-REV-Chapisco (interno) 2, Área de Seção Transversal do Componente: 0.004 m2; EI-REV-Chapisco (interno) 2, Volume Componente (Líquido): 0.00212791 m3; EI-REV-Chapisco (interno) 2, Volume do componente (Bruto): 0.00224491 m3
AL09 | Mureta | BLOCO A | 9.97548 | 0.249387 | 0.272787 | 0.78 | 0.0156 | 0.00498774 | 0.00545574 | 1.72242 | 0.264987 | 0.288387 | 0.0039 | 0.00132493 | 0.00144193 | 1.74777 | 0.268887 | 0.292287 | 0.005 | 0.78 | 0.0039 | 0.00134443 | 0.00146143 | 15.9089 | 0.272787 | 0.296187 | 0.0702 | 0.0245508 | 0.0266568 | 1.74777 | 0.268887 | 0.288387 | 0.005 | 0.78 | 0.0039 | 0.00134443 | 0.00144193 | 10.2875 | 0.257187 | 0.272787 | 0.00514374 | 0.00545574 | 2 with these values
AL09 | Mureta | BLOCO A | 10.2875 | 0.257187 | 0.272787 | 0.78 | 0.0156 | 0.00514374 | 0.00545574 | 1.74777 | 0.268887 | 0.288387 | 0.0039 | 0.00134443 | 0.00144193 | 1.74777 | 0.268887 | 0.292287 | 0.005 | 0.78 | 0.0039 | 0.00134443 | 0.00146143 | 15.9089 | 0.272787 | 0.296187 | 0.0702 | 0.0245508 | 0.0266568 | 1.72242 | 0.264987 | 0.288387 | 0.005 | 0.78 | 0.0039 | 0.00132493 | 0.00144193 | 9.97548 | 0.249387 | 0.272787 | 0.00498774 | 0.00545574 | 2 with these values
AL09 | Mureta | BLOCO A | 16.5717 | 0.4143 | 0.4299 | 0.78 | 0.0156 | 0.00828584 | 0.00859758 | 2.7651 | 0.4254 | 0.4449 | 0.0039 | 0.002127 | 0.0022245 | 2.76412 | 0.42525 | 0.44865 | 0.005 | 0.78 | 0.0039 | 0.00212625 | 0.00224325 | 25.0193 | 0.429 | 0.4524 | 0.0702 | 0.03861 | 0.040716 | 2.73975 | 0.4215 | 0.4449 | 0.005 | 0.78 | 0.0039 | 0.0021075 | 0.0022245 | 16.26 | 0.4065 | 0.4299 | 0.00813 | 0.008598 | 2 with these values
AL09 | Mureta | BLOCO A | 17.2024 | 0.4302 | 0.4464 | 0.81 | 0.0162 | 0.00860121 | 0.00892758 | 2.87137 | 0.44175 | 0.462 | 0.00405 | 0.00220875 | 0.00231 | 2.8704 | 0.4416 | 0.4659 | 0.005 | 0.81 | 0.00405 | 0.002208 | 0.0023295 | 25.9816 | 0.4455 | 0.4698 | 0.0729 | 0.040095 | 0.042282 | 2.81125 | 0.4325 | 0.4565 | 0.005 | 0.81 | 0.00405 | 0.0021625 | 0.0022825 | 16.676 | 0.4169 | 0.4409 | 0.008338 | 0.008818 | Component Quantities - EI-REV-Chapisco (interno) 2, Massa: 2.8366 kg; EI-REV-Chapisco (interno) 2, Área de Componente Projetada (Líquida): 0.4364 m2; EI-REV-Chapisco (interno) 2, Área de Componente Projetada (Bruta): 0.4604 m2; EI-REV-Chapisco (interno) 2, Espessura do Componente: 0.005 m; EI-REV-Chapisco (interno) 2, Altura do Componente Retangular: 0.81 m; EI-REV-Chapisco (interno) 2, Largura do Componente Retangular: 0.005 m; EI-REV-Chapisco (interno) 2, Área de Seção Transversal do Componente: 0.00405 m2; EI-REV-Chapisco (interno) 2, Volume Componente (Líquido): 0.002182 m3; EI-REV-Chapisco (interno) 2, Volume do componente (Bruto): 0.002302 m3
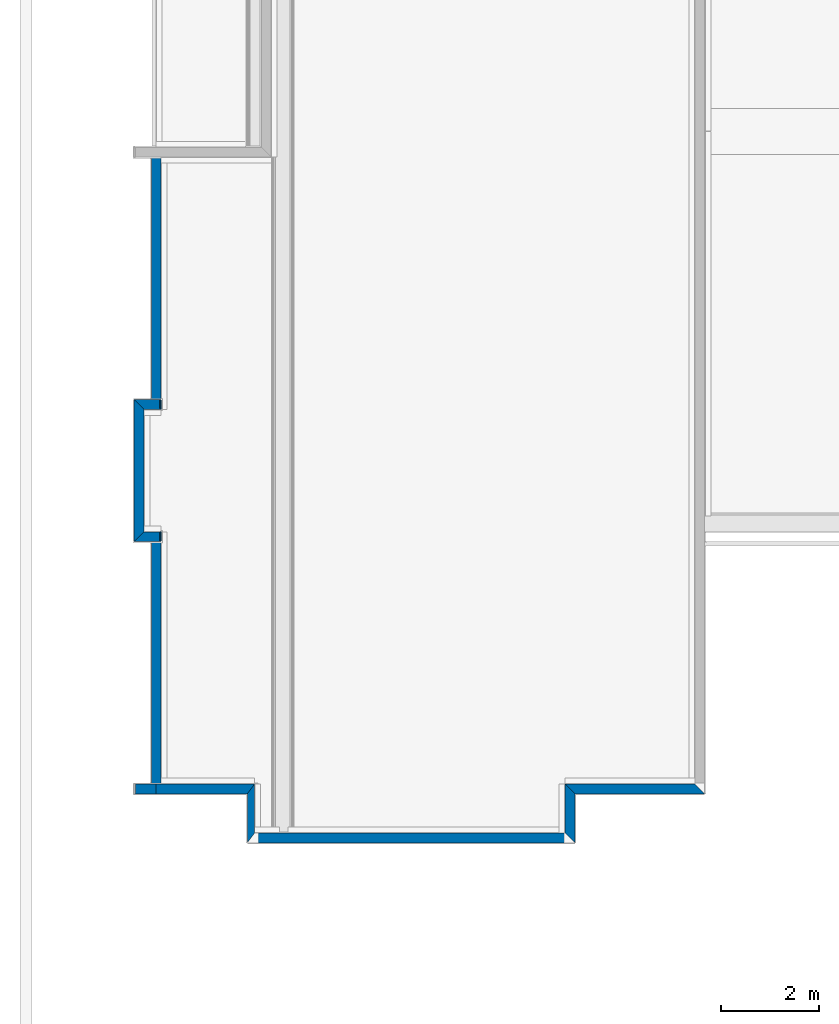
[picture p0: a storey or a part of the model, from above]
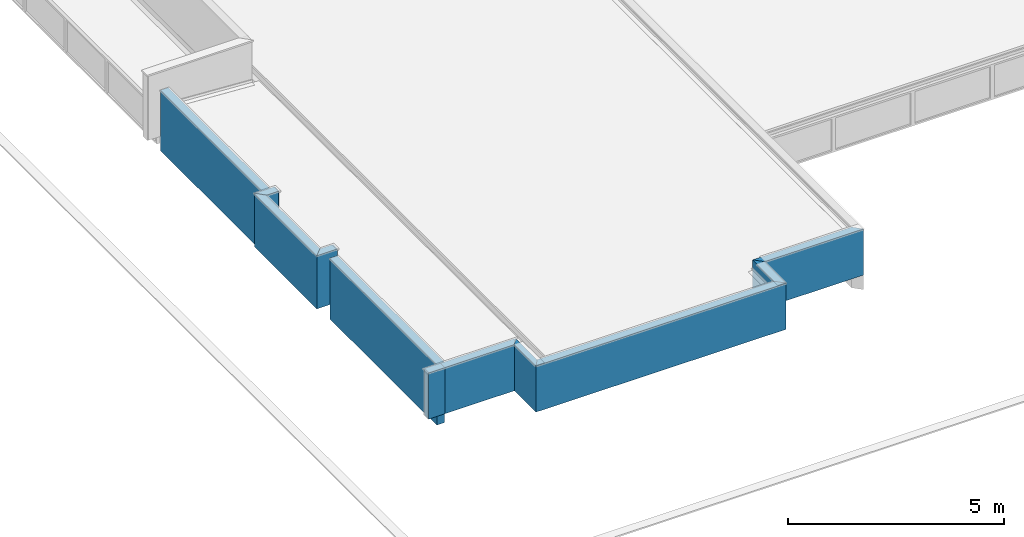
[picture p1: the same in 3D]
Properties of the parts of a building model (IFC4), part 13 of 22

# IfcWall: FNDE-AL09-I4-I4 150 (33)
Name | Alvenarias | 1_Bloco | EI-REV-Cerâmica 30x40 1, Massa (kg) | EI-REV-Cerâmica 30x40 1, Área de Componente Projetada (Líquida) (m2) | EI-REV-Cerâmica 30x40 1, Área de Componente Projetada (Bruta) (m2) | EI-REV-Cerâmica 30x40 1, Altura do Componente Retangular (m) = EI-REV-Emboço Interno 1, Altura do Componente Retangular (m) = TIJOLO - CERAMICO 9x19x39 - espessura 15cm, Altura do Componente Retangular (m) = EI-REV-Cerâmica 30x40 2, Altura do Componente Retangular (m) | EI-REV-Cerâmica 30x40 1, Área de Seção Transversal do Componente (m2) = EI-REV-Cerâmica 30x40 2, Área de Seção Transversal do Componente (m2) | EI-REV-Cerâmica 30x40 1, Volume Componente (Líquido) (m3) | EI-REV-Cerâmica 30x40 1, Volume do componente (Bruto) (m3) | EI-REV-Emboço Interno 1, Massa (kg) | EI-REV-Emboço Interno 1, Área de Componente Projetada (Líquida) (m2) | EI-REV-Emboço Interno 1, Área de Componente Projetada (Bruta) (m2) | EI-REV-Emboço Interno 1, Área de Seção Transversal do Componente (m2) | EI-REV-Emboço Interno 1, Volume Componente (Líquido) (m3) | EI-REV-Emboço Interno 1, Volume do componente (Bruto) (m3) | EI-REV-Chapisco (interno) 1, Massa (kg) | EI-REV-Chapisco (interno) 1, Área de Componente Projetada (Líquida) (m2) | EI-REV-Chapisco (interno) 1, Área de Componente Projetada (Bruta) (m2) | EI-REV-Chapisco (interno) 1, Espessura do Componente (m) = EI-REV-Chapisco (interno) 1, Largura do Componente Retangular (m) | EI-REV-Chapisco (interno) 1, Altura do Componente Retangular (m) | EI-REV-Chapisco (interno) 1, Área de Seção Transversal do Componente (m2) | EI-REV-Chapisco (interno) 1, Volume Componente (Líquido) (m3) | EI-REV-Chapisco (interno) 1, Volume do componente (Bruto) (m3) | TIJOLO - CERAMICO 9x19x39 - espessura 15cm, Massa (kg) | TIJOLO - CERAMICO 9x19x39 - espessura 15cm, Área de Componente Projetada (Líquida) (m2) | TIJOLO - CERAMICO 9x19x39 - espessura 15cm, Área de Componente Projetada (Bruta) (m2) | TIJOLO - CERAMICO 9x19x39 - espessura 15cm, Área de Seção Transversal do Componente (m2) | TIJOLO - CERAMICO 9x19x39 - espessura 15cm, Volume Componente (Líquido) (m3) | TIJOLO - CERAMICO 9x19x39 - espessura 15cm, Volume do componente (Bruto) (m3) | EI-REV-Emboço Interno 2, Massa (kg) | EI-REV-Emboço Interno 2, Área de Componente Projetada (Líquida) (m2) | EI-REV-Emboço Interno 2, Área de Componente Projetada (Bruta) (m2) | EI-REV-Emboço Interno 2, Espessura do Componente (m) = EI-REV-Emboço Interno 2, Largura do Componente Retangular (m) | EI-REV-Emboço Interno 2, Altura do Componente Retangular (m) | EI-REV-Emboço Interno 2, Área de Seção Transversal do Componente (m2) | EI-REV-Emboço Interno 2, Volume Componente (Líquido) (m3) | EI-REV-Emboço Interno 2, Volume do componente (Bruto) (m3) | EI-REV-Cerâmica 30x40 2, Massa (kg) | EI-REV-Cerâmica 30x40 2, Área de Componente Projetada (Líquida) (m2) | EI-REV-Cerâmica 30x40 2, Área de Componente Projetada (Bruta) (m2) | EI-REV-Cerâmica 30x40 2, Volume Componente (Líquido) (m3) | EI-REV-Cerâmica 30x40 2, Volume do componente (Bruto) (m3) | EI-REV-Chapisco (interno) 1
AL09 | Alvenaria de Vedação / Edificação | BLOCO A | 635.086 | 18.6 | 18.6 | 3.1 | 0.062 | 0.317543 | 0.317543 | 97.6652 | 15.0254 | 15.0254 | 0.0155 | 0.0751271 | 0.0751271 | 97.753 | 15.0389 | 15.0389 | 0.005 | 3.1 | 0.0155 | 0.0751946 | 0.0751946 | 877.857 | 15.0524 | 15.0524 | 0.279 | 1.35472 | 1.35472 | 96.4822 | 14.8434 | 14.8434 | 0.005 | 3.1 | 0.0155 | 0.0742171 | 0.0742171 | 627.159 | 18.3998 | 18.3998 | 0.313579 | 0.313579 | Component Quantities - EI-REV-Chapisco (interno) 2, Massa: 96.6883 kg; EI-REV-Chapisco (interno) 2, Área de Componente Projetada (Líquida): 14.8751 m2; EI-REV-Chapisco (interno) 2, Área de Componente Projetada (Bruta): 14.8751 m2; EI-REV-Chapisco (interno) 2, Espessura do Componente: 0.005 m; EI-REV-Chapisco (interno) 2, Altura do Componente Retangular: 3.1 m; EI-REV-Chapisco (interno) 2, Largura do Componente Retangular: 0.005 m; EI-REV-Chapisco (interno) 2, Área de Seção Transversal do Componente: 0.0155 m2; EI-REV-Chapisco (interno) 2, Volume Componente (Líquido): 0.0743756 m3; EI-REV-Chapisco (interno) 2, Volume do componente (Bruto): 0.0743756 m3
AL09 | Alvenaria de Vedação / Edificação | BLOCO A | 299.658 | 8.8741 | 10.4491 | 3.1 | 0.062 | 0.149829 | 0.181329 | 45.8049 | 7.04691 | 8.62191 | 0.0155 | 0.0352346 | 0.0431096 | 45.8049 | 7.04691 | 8.62191 | 0.005 | 3.1 | 0.0155 | 0.0352345 | 0.0431095 | 410.976 | 7.04691 | 8.62191 | 0.279 | 0.634222 | 0.775972 | 45.2134 | 6.95591 | 8.53091 | 0.005 | 3.1 | 0.0155 | 0.0347795 | 0.0426545 | 300.624 | 9.177 | 10.752 | 0.150312 | 0.181812 | Component Quantities - EI-REV-Chapisco (interno) 2, Massa: 45.2727 kg; EI-REV-Chapisco (interno) 2, Área de Componente Projetada (Líquida): 6.96501 m2; EI-REV-Chapisco (interno) 2, Área de Componente Projetada (Bruta): 8.54001 m2; EI-REV-Chapisco (interno) 2, Espessura do Componente: 0.005 m; EI-REV-Chapisco (interno) 2, Altura do Componente Retangular: 3.1 m; EI-REV-Chapisco (interno) 2, Largura do Componente Retangular: 0.005 m; EI-REV-Chapisco (interno) 2, Área de Seção Transversal do Componente: 0.0155 m2; EI-REV-Chapisco (interno) 2, Volume Componente (Líquido): 0.0348252 m3; EI-REV-Chapisco (interno) 2, Volume do componente (Bruto): 0.0427002 m3
AL09 | Alvenaria de Vedação / Edificação | BLOCO A | 146.776 | 3.70104 | 5.62704 | 3.1 | 0.062 | 0.0733878 | 0.111908 | 23.8876 | 3.67532 | 5.60132 | 0.0155 | 0.0183751 | 0.0280051 |  |  |  |  |  |  |  |  | 214.327 | 3.68046 | 5.60646 | 0.279 | 0.330752 | 0.504092 |  |  |  |  |  |  |  |  | 157.787 | 4.04588 | 5.97188 | 0.0788933 | 0.117413 | Component Quantities - EI-REV-Emboço Interno 1: 4 with these values
AL09 | Alvenaria de Vedação / Edificação | BLOCO A | 234.748 | 6.49522 | 6.49522 | 3.1 | 0.062 | 0.117374 | 0.117374 | 37.1223 | 5.71112 | 5.71112 | 0.0155 | 0.0285556 | 0.0285556 | 37.2101 | 5.72462 | 5.72462 | 0.005 | 3.1 | 0.0155 | 0.0286231 | 0.0286231 | 334.647 | 5.73812 | 5.73812 | 0.279 | 0.516431 | 0.516431 |  |  |  |  |  |  |  |  | 234.579 | 6.49522 | 6.49522 | 0.11729 | 0.11729 | 2 with these values | Component Quantities - EI-REV-Emboço Interno 1: 2 with these values
AL09 | Alvenaria de Vedação / Edificação | BLOCO A | 152.972 | 4.34751 | 6.33551 | 3.1 | 0.062 | 0.0764862 | 0.116245 | 19.8828 | 3.05919 | 5.06269 | 0.0155 | 0.0152944 | 0.0253119 | 19.8698 | 3.05719 | 5.07619 | 0.005 | 3.1 | 0.0155 | 0.0152844 | 0.0253794 | 179.065 | 3.07582 | 5.09482 | 0.279 | 0.276335 | 0.458045 | 19.782 | 3.04369 | 5.06269 | 0.005 | 3.1 | 0.0155 | 0.0152169 | 0.0253119 | 123.14 | 3.40342 | 5.42242 | 0.0615698 | 0.10195 | 2 with these values
AL09 | Alvenaria de Vedação / Edificação | BLOCO A | 336.082 | 9.3002 | 9.3002 | 3.1 | 0.062 | 0.168041 | 0.168041 | 53.265 | 8.19462 | 8.19462 | 0.0155 | 0.0409731 | 0.0409731 | 53.3528 | 8.20812 | 8.20812 | 0.005 | 3.1 | 0.0155 | 0.0410406 | 0.0410406 | 522 | 8.95062 | 8.95062 | 0.279 | 0.805555 | 0.805555 | 55.8325 | 8.58962 | 8.58962 | 0.005 | 3.1 | 0.0155 | 0.0429481 | 0.0429481 | 353.085 | 9.7771 | 9.7771 | 0.176542 | 0.176542 | Component Quantities - EI-REV-Chapisco (interno) 2, Massa: 56.0672 kg; EI-REV-Chapisco (interno) 2, Área de Componente Projetada (Líquida): 8.62572 m2; EI-REV-Chapisco (interno) 2, Área de Componente Projetada (Bruta): 8.62572 m2; EI-REV-Chapisco (interno) 2, Espessura do Componente: 0.005 m; EI-REV-Chapisco (interno) 2, Altura do Componente Retangular: 3.1 m; EI-REV-Chapisco (interno) 2, Largura do Componente Retangular: 0.005 m; EI-REV-Chapisco (interno) 2, Área de Seção Transversal do Componente: 0.0155 m2; EI-REV-Chapisco (interno) 2, Volume Componente (Líquido): 0.0431286 m3; EI-REV-Chapisco (interno) 2, Volume do componente (Bruto): 0.0431286 m3
AL09 | Alvenaria de Vedação / Edificação | BLOCO A | 191.751 | 5.93829 | 5.93829 | 3.1 | 0.062 | 0.0958757 | 0.0958757 | 29.0517 | 4.46949 | 4.46949 | 0.0155 | 0.0223474 | 0.0223474 | 29.1394 | 4.48299 | 4.48299 | 0.005 | 3.1 | 0.0155 | 0.0224149 | 0.0224149 | 264.157 | 4.52944 | 4.52944 | 0.279 | 0.407649 | 0.407649 |  |  |  |  |  |  |  |  | 187.969 | 5.59519 | 5.59519 | 0.0939844 | 0.0939844 | 2 with these values | Component Quantities - EI-REV-Emboço Interno 1: 2 with these values
AL09 | Alvenaria de Vedação / Edificação | BLOCO A | 83.5095 | 2.08774 | 2.14914 | 3.1 | 0.062 | 0.0417548 | 0.0429828 | 13.6149 | 2.0946 | 2.1716 | 0.0155 | 0.010473 | 0.010858 | 13.5148 | 2.0792 | 2.1716 | 0.005 | 3.1 | 0.0155 | 0.010396 | 0.010858 | 122.046 | 2.0927 | 2.1857 | 0.279 | 0.188343 | 0.196713 |  |  |  |  |  |  |  |  | 90.393 | 2.54824 | 2.54824 | 0.0451965 | 0.0451965 | 3 with these values
AL09 | Mureta | BLOCO A | 107.293 | 2.68234 | 2.70534 | 1.18 | 0.0236 | 0.0536467 | 0.0541067 | 17.5872 | 2.70573 | 2.73473 | 0.0059 | 0.0135286 | 0.0136736 | 17.5495 | 2.69993 | 2.73473 | 0.005 | 1.18 | 0.0059 | 0.0134996 | 0.0136736 | 160.169 | 2.74638 | 2.78178 | 0.1062 | 0.247174 | 0.25036 | 16.971 | 2.61093 | 2.64573 | 0.005 | 1.18 | 0.0059 | 0.0130546 | 0.0132286 | 104.341 | 2.60854 | 2.60854 | 0.0521707 | 0.0521707 | Component Quantities - EI-REV-Chapisco (interno) 2, Massa: 17.0289 kg; EI-REV-Chapisco (interno) 2, Área de Componente Projetada (Líquida): 2.61983 m2; EI-REV-Chapisco (interno) 2, Área de Componente Projetada (Bruta): 2.65463 m2; EI-REV-Chapisco (interno) 2, Espessura do Componente: 0.005 m; EI-REV-Chapisco (interno) 2, Altura do Componente Retangular: 1.18 m; EI-REV-Chapisco (interno) 2, Largura do Componente Retangular: 0.005 m; EI-REV-Chapisco (interno) 2, Área de Seção Transversal do Componente: 0.0059 m2; EI-REV-Chapisco (interno) 2, Volume Componente (Líquido): 0.0130991 m3; EI-REV-Chapisco (interno) 2, Volume do componente (Bruto): 0.0132731 m3
AL09 | Mureta | BLOCO A | 19.3441 | 0.483602 | 0.501002 | 0.9 | 0.018 | 0.00967204 | 0.01002 | 3.11514 | 0.479252 | 0.501002 | 0.0045 | 0.00239626 | 0.00250501 | 3.08686 | 0.474902 | 0.501002 | 0.005 | 0.9 | 0.0045 | 0.00237451 | 0.00250501 | 28.0146 | 0.48036 | 0.50676 | 0.081 | 0.0432324 | 0.0456084 |  |  |  |  |  |  |  |  | 18.9961 | 0.474902 | 0.501002 | 0.00949804 | 0.01002 | 3 with these values
AL09 | Mureta | BLOCO A | 18.9961 | 0.474902 | 0.501002 | 0.9 | 0.018 | 0.00949804 | 0.01002 | 3.08686 | 0.474902 | 0.501002 | 0.0045 | 0.00237451 | 0.00250501 |  |  |  |  |  |  |  |  | 28.0146 | 0.48036 | 0.50676 | 0.081 | 0.0432324 | 0.0456084 | 3.11514 | 0.479252 | 0.501002 | 0.005 | 0.9 | 0.0045 | 0.00239626 | 0.00250501 | 19.3441 | 0.483602 | 0.501002 | 0.00967203 | 0.01002 | Component Quantities - EI-REV-Emboço Interno 1: 3 with these values
AL09 | Mureta | BLOCO A | 15.1365 | 0.378413 | 0.396013 | 0.91 | 0.0182 | 0.00756826 | 0.00792026 | 2.45869 | 0.378259 | 0.400509 | 0.00455 | 0.0018913 | 0.00200255 | 2.42976 | 0.373809 | 0.400509 | 0.005 | 0.91 | 0.00455 | 0.00186905 | 0.00200255 | 22.29 | 0.382202 | 0.409502 | 0.0819 | 0.0343982 | 0.0368552 |  |  |  |  |  |  |  |  | 15.8405 | 0.396012 | 0.396012 | 0.00792025 | 0.00792025 | 3 with these values
AL09 | Mureta | BLOCO A | 11.6163 | 0.290407 | 0.308007 | 0.91 | 0.0182 | 0.00580814 | 0.00616014 | 1.99848 | 0.307458 | 0.329708 | 0.00455 | 0.00153729 | 0.00164854 | 1.99913 | 0.307558 | 0.334258 | 0.005 | 0.91 | 0.00455 | 0.00153779 | 0.00167129 | 18.5754 | 0.318508 | 0.345808 | 0.0819 | 0.0286657 | 0.0311227 | 1.96955 | 0.303008 | 0.329708 | 0.005 | 0.91 | 0.00455 | 0.00151504 | 0.00164854 | 11.2643 | 0.281607 | 0.308007 | 0.00563214 | 0.00616014 | 2 with these values
AL09 | Mureta | BLOCO A | 14.9643 | 0.3741 | 0.3915 | 0.91 | 0.0182 | 0.00748215 | 0.00783015 | 2.5467 | 0.3918 | 0.4138 | 0.00455 | 0.001959 | 0.002069 | 2.54703 | 0.39185 | 0.41825 | 0.005 | 0.91 | 0.00455 | 0.00195925 | 0.00209125 | 23.8821 | 0.4095 | 0.4368 | 0.0819 | 0.036855 | 0.039312 | 2.5181 | 0.3874 | 0.4138 | 0.005 | 0.91 | 0.00455 | 0.001937 | 0.002069 | 15.66 | 0.3915 | 0.3915 | 0.00783001 | 0.00783001 | 2 with these values
AL09 | Mureta | BLOCO A | 11.6163 | 0.290407 | 0.308007 | 0.91 | 0.0182 | 0.00580815 | 0.00616015 | 1.99848 | 0.307458 | 0.329708 | 0.00455 | 0.00153729 | 0.00164854 | 1.99913 | 0.307558 | 0.334258 | 0.005 | 0.91 | 0.00455 | 0.00153779 | 0.00167129 | 18.5754 | 0.318508 | 0.345808 | 0.0819 | 0.0286657 | 0.0311227 | 1.96955 | 0.303008 | 0.329708 | 0.005 | 0.91 | 0.00455 | 0.00151504 | 0.00164854 | 11.2643 | 0.281607 | 0.308007 | 0.00563215 | 0.00616015 | 2 with these values
AL09 | Mureta | BLOCO A | 14.7831 | 0.369578 | 0.395978 | 0.91 | 0.0182 | 0.00739156 | 0.00791956 | 2.54785 | 0.391978 | 0.418678 | 0.00455 | 0.00195989 | 0.00209339 | 2.57743 | 0.396528 | 0.423228 | 0.005 | 0.91 | 0.00455 | 0.00198264 | 0.00211614 | 23.8807 | 0.409477 | 0.436777 | 0.0819 | 0.0368529 | 0.0393099 | 2.57678 | 0.396428 | 0.418678 | 0.005 | 0.91 | 0.00455 | 0.00198214 | 0.00209339 | 15.1351 | 0.378378 | 0.395978 | 0.00756756 | 0.00791956 | 2 with these values
AL09 | Mureta | BLOCO A | 20.7303 | 0.518257 | 0.549657 | 0.815 | 0.0163 | 0.0103651 | 0.0109931 | 3.35991 | 0.516909 | 0.556659 | 0.004075 | 0.00258455 | 0.0027833 | 3.30824 | 0.508959 | 0.556659 | 0.005 | 0.815 | 0.004075 | 0.0025448 | 0.0027833 | 30.4292 | 0.521763 | 0.570663 | 0.07335 | 0.0469587 | 0.0513597 |  |  |  |  |  |  |  |  | 21.9863 | 0.549657 | 0.549657 | 0.0109931 | 0.0109931 | 3 with these values
AL09 | Mureta | BLOCO A | 16.8934 | 0.422335 | 0.439935 | 0.91 | 0.0182 | 0.00844671 | 0.00879871 | 2.86575 | 0.440885 | 0.463135 | 0.00455 | 0.00220442 | 0.00231567 | 2.8664 | 0.440985 | 0.467685 | 0.005 | 0.91 | 0.00455 | 0.00220492 | 0.00233842 | 26.5317 | 0.454933 | 0.482233 | 0.0819 | 0.040944 | 0.043401 | 2.80628 | 0.431735 | 0.458135 | 0.005 | 0.91 | 0.00455 | 0.00215868 | 0.00229068 | 16.3534 | 0.408836 | 0.434936 | 0.00817672 | 0.00869872 | Component Quantities - EI-REV-Chapisco (interno) 2, Massa: 2.83586 kg; EI-REV-Chapisco (interno) 2, Área de Componente Projetada (Líquida): 0.436285 m2; EI-REV-Chapisco (interno) 2, Área de Componente Projetada (Bruta): 0.462685 m2; EI-REV-Chapisco (interno) 2, Espessura do Componente: 0.005 m; EI-REV-Chapisco (interno) 2, Altura do Componente Retangular: 0.91 m; EI-REV-Chapisco (interno) 2, Largura do Componente Retangular: 0.005 m; EI-REV-Chapisco (interno) 2, Área de Seção Transversal do Componente: 0.00455 m2; EI-REV-Chapisco (interno) 2, Volume Componente (Líquido): 0.00218143 m3; EI-REV-Chapisco (interno) 2, Volume do componente (Bruto): 0.00231343 m3
AL09 | Mureta | BLOCO A | 16.6986 | 0.417543 | 0.434943 | 0.91 | 0.0182 | 0.00834928 | 0.00869725 | 2.83493 | 0.436143 | 0.458143 | 0.00455 | 0.00218071 | 0.00229071 | 2.8359 | 0.436293 | 0.462693 | 0.005 | 0.91 | 0.00455 | 0.00218146 | 0.00231346 | 26.5321 | 0.454941 | 0.482241 | 0.0819 | 0.0409447 | 0.0434017 | 2.80633 | 0.431743 | 0.458143 | 0.005 | 0.91 | 0.00455 | 0.00215871 | 0.00229071 | 16.3537 | 0.408843 | 0.434943 | 0.00817686 | 0.00869886 | 2 with these values
AL09 | Mureta | BLOCO B | 8.37949 | 0.209487 | 0.220487 | 0.58 | 0.0116 | 0.00418974 | 0.00440974 | 1.44031 | 0.221586 | 0.235586 | 0.0029 | 0.00110793 | 0.00117793 | 1.43999 | 0.221536 | 0.238336 | 0.005 | 0.58 | 0.0029 | 0.00110768 | 0.00119168 | 13.5235 | 0.231884 | 0.249284 | 0.0522 | 0.0208696 | 0.0224356 | 1.37404 | 0.21139 | 0.22759 | 0.005 | 0.58 | 0.0029 | 0.00105695 | 0.00113795 | 7.86365 | 0.196591 | 0.212491 | 0.00393182 | 0.00424983 | Component Quantities - EI-REV-Chapisco (interno) 2, Massa: 1.39191 kg; EI-REV-Chapisco (interno) 2, Área de Componente Projetada (Líquida): 0.21414 m2; EI-REV-Chapisco (interno) 2, Área de Componente Projetada (Bruta): 0.23034 m2; EI-REV-Chapisco (interno) 2, Espessura do Componente: 0.005 m; EI-REV-Chapisco (interno) 2, Altura do Componente Retangular: 0.58 m; EI-REV-Chapisco (interno) 2, Largura do Componente Retangular: 0.005 m; EI-REV-Chapisco (interno) 2, Área de Seção Transversal do Componente: 0.0029 m2; EI-REV-Chapisco (interno) 2, Volume Componente (Líquido): 0.0010707 m3; EI-REV-Chapisco (interno) 2, Volume do componente (Bruto): 0.0011517 m3
AL09 | Mureta | BLOCO B | 15.7175 | 0.392997 | 0.416097 | 0.8 | 0.016 | 0.00785873 | 0.00832073 | 2.68904 | 0.413698 | 0.437098 | 0.004 | 0.00206849 | 0.00218549 | 2.71406 | 0.417548 | 0.440948 | 0.005 | 0.8 | 0.004 | 0.00208774 | 0.00220474 | 25.6608 | 0.44 | 0.464 | 0.072 | 0.0396 | 0.04176 | 2.76639 | 0.425598 | 0.445098 | 0.005 | 0.8 | 0.004 | 0.00212799 | 0.00222549 | 16.3479 | 0.408697 | 0.424097 | 0.00817395 | 0.00848195 | Component Quantities - EI-REV-Chapisco (interno) 2, Massa: 2.76606 kg; EI-REV-Chapisco (interno) 2, Área de Componente Projetada (Líquida): 0.425548 m2; EI-REV-Chapisco (interno) 2, Área de Componente Projetada (Bruta): 0.448948 m2; EI-REV-Chapisco (interno) 2, Espessura do Componente: 0.005 m; EI-REV-Chapisco (interno) 2, Altura do Componente Retangular: 0.8 m; EI-REV-Chapisco (interno) 2, Largura do Componente Retangular: 0.005 m; EI-REV-Chapisco (interno) 2, Área de Seção Transversal do Componente: 0.004 m2; EI-REV-Chapisco (interno) 2, Volume Componente (Líquido): 0.00212774 m3; EI-REV-Chapisco (interno) 2, Volume do componente (Bruto): 0.00224474 m3
AL09 | Mureta | BLOCO A | 9.85647 | 0.246412 | 0.264012 | 0.91 | 0.0182 | 0.00492823 | 0.00528023 | 1.70925 | 0.262962 | 0.285212 | 0.00455 | 0.00131481 | 0.00142606 | 1.7099 | 0.263062 | 0.289762 | 0.005 | 0.91 | 0.00455 | 0.00131531 | 0.00144881 | 15.922 | 0.273012 | 0.300312 | 0.0819 | 0.0245711 | 0.0270281 | 1.68033 | 0.258512 | 0.285212 | 0.005 | 0.91 | 0.00455 | 0.00129256 | 0.00142606 | 9.50447 | 0.237612 | 0.264012 | 0.00475223 | 0.00528023 | 2 with these values

# IfcWall: FNDE-AL09-I4-I5 (30x40-azul) 150 x 3100 (2)
In: TÉRREO
Classification: Parede (Classificação Archicad); Material: TIJOLO - CERAMICO 9x19x39 - espessura 15cm, EI-REV-Chapisco (interno) (2), EI-REV-Cerâmica 30x40 (2), EI-REV-Cerâmica 10x10 Azul, EI-REV-Emboço Interno (2), EI-REV-Massa única - Maior que 10m², EI-REV-Massa Corrida PVA (interna), EI-REV-Pintura Acrílica Cor Branco Gelo
FNDE - Alvenarias: Alvenaria de Vedação / Edificação; Sistemas de Cobertura: -; Esquadrias - Fechamentos metálicos e Gradis: -; 1_Bloco: BLOCO A; 0_ID: AL09
Pset_WallCommon - IsExternal: no; LoadBearing: no
Component Quantities - TIJOLO - CERAMICO 9x19x39 - espessura 15cm, Altura do Componente Retangular: 3.1 m; TIJOLO - CERAMICO 9x19x39 - espessura 15cm, Largura do Componente Retangular: 0.09 m; TIJOLO - CERAMICO 9x19x39 - espessura 15cm, Área de Seção Transversal do Componente: 0.279 m2; EI-REV-Chapisco (interno) 1, Altura do Componente Retangular: 3.1 m; EI-REV-Chapisco (interno) 1, Largura do Componente Retangular: 0.005 m; EI-REV-Chapisco (interno) 1, Área de Seção Transversal do Componente: 0.0155 m2; EI-REV-Cerâmica 30x40 1, Altura do Componente Retangular: 1.8 m; EI-REV-Cerâmica 30x40 1, Largura do Componente Retangular: 0.02 m; EI-REV-Cerâmica 30x40 1, Área de Seção Transversal do Componente: 0.036 m2; EI-REV-Cerâmica 10x10 Azul, Altura do Componente Retangular: 0.1 m; EI-REV-Cerâmica 10x10 Azul, Largura do Componente Retangular: 0.02 m; EI-REV-Cerâmica 10x10 Azul, Área de Seção Transversal do Componente: 0.002 m2; EI-REV-Emboço Interno 1, Altura do Componente Retangular: 3.1 m; EI-REV-Emboço Interno 1, Largura do Componente Retangular: 0.005 m; EI-REV-Emboço Interno 1, Área de Seção Transversal do Componente: 0.0155 m2; EI-REV-Massa única - Maior que 10m², Altura do Componente Retangular: 1.17 m; EI-REV-Massa única - Maior que 10m², Largura do Componente Retangular: 0.005 m; EI-REV-Massa única - Maior que 10m², Área de Seção Transversal do Componente: 0.00585001 m2; EI-REV-Massa Corrida PVA (interna), Altura do Componente Retangular: 1.17 m; EI-REV-Massa Corrida PVA (interna), Largura do Componente Retangular: 0.005 m; EI-REV-Massa Corrida PVA (interna), Área de Seção Transversal do Componente: 0.00585001 m2; EI-REV-Pintura Acrílica Cor Branco Gelo, Altura do Componente Retangular: 1.17 m; EI-REV-Pintura Acrílica Cor Branco Gelo, Largura do Componente Retangular: 0.00999999 m; EI-REV-Pintura Acrílica Cor Branco Gelo, Área de Seção Transversal do Componente: 0.0117 m2; EI-REV-Chapisco (interno) 2, Altura do Componente Retangular: 3.1 m; EI-REV-Chapisco (interno) 2, Largura do Componente Retangular: 0.005 m; EI-REV-Chapisco (interno) 2, Área de Seção Transversal do Componente: 0.0155 m2; EI-REV-Emboço Interno 2, Altura do Componente Retangular: 3.1 m; EI-REV-Emboço Interno 2, Largura do Componente Retangular: 0.005 m; EI-REV-Emboço Interno 2, Área de Seção Transversal do Componente: 0.0155 m2; EI-REV-Cerâmica 30x40 2, Altura do Componente Retangular: 3.1 m; EI-REV-Cerâmica 30x40 2, Largura do Componente Retangular: 0.02 m; EI-REV-Cerâmica 30x40 2, Área de Seção Transversal do Componente: 0.062 m2
Name | TIJOLO - CERAMICO 9x19x39 - espessura 15cm, Massa (kg) | TIJOLO - CERAMICO 9x19x39 - espessura 15cm, Área de Componente Projetada (Líquida) (m2) | TIJOLO - CERAMICO 9x19x39 - espessura 15cm, Área de Componente Projetada (Bruta) (m2) | TIJOLO - CERAMICO 9x19x39 - espessura 15cm, Volume Componente (Líquido) (m3) | TIJOLO - CERAMICO 9x19x39 - espessura 15cm, Volume do componente (Bruto) (m3) | EI-REV-Chapisco (interno) 1, Massa (kg) | EI-REV-Chapisco (interno) 1, Área de Componente Projetada (Líquida) (m2) | EI-REV-Chapisco (interno) 1, Área de Componente Projetada (Bruta) (m2) | EI-REV-Chapisco (interno) 1, Volume Componente (Líquido) (m3) | EI-REV-Chapisco (interno) 1, Volume do componente (Bruto) (m3) | EI-REV-Cerâmica 30x40 1, Massa (kg) | EI-REV-Cerâmica 30x40 1, Área de Componente Projetada (Líquida) (m2) | EI-REV-Cerâmica 30x40 1, Área de Componente Projetada (Bruta) (m2) | EI-REV-Cerâmica 30x40 1, Volume Componente (Líquido) (m3) | EI-REV-Cerâmica 30x40 1, Volume do componente (Bruto) (m3) | EI-REV-Cerâmica 10x10 Azul, Massa (kg) | EI-REV-Cerâmica 10x10 Azul, Área de Componente Projetada (Líquida) (m2) | EI-REV-Cerâmica 10x10 Azul, Área de Componente Projetada (Bruta) (m2) | EI-REV-Cerâmica 10x10 Azul, Volume Componente (Líquido) (m3) | EI-REV-Cerâmica 10x10 Azul, Volume do componente (Bruto) (m3) | EI-REV-Emboço Interno 1, Massa (kg) | EI-REV-Emboço Interno 1, Área de Componente Projetada (Líquida) (m2) | EI-REV-Emboço Interno 1, Área de Componente Projetada (Bruta) (m2) | EI-REV-Emboço Interno 1, Volume Componente (Líquido) (m3) | EI-REV-Emboço Interno 1, Volume do componente (Bruto) (m3) | EI-REV-Massa única - Maior que 10m², Massa (kg) | EI-REV-Massa única - Maior que 10m², Área de Componente Projetada (Líquida) (m2) | EI-REV-Massa única - Maior que 10m², Área de Componente Projetada (Bruta) (m2) | EI-REV-Massa única - Maior que 10m², Volume Componente (Líquido) (m3) | EI-REV-Massa única - Maior que 10m², Volume do componente (Bruto) (m3) | EI-REV-Massa Corrida PVA (interna), Massa (kg) | EI-REV-Massa Corrida PVA (interna), Área de Componente Projetada (Líquida) (m2) | EI-REV-Massa Corrida PVA (interna), Área de Componente Projetada (Bruta) (m2) | EI-REV-Massa Corrida PVA (interna), Volume Componente (Líquido) (m3) | EI-REV-Massa Corrida PVA (interna), Volume do componente (Bruto) (m3) | EI-REV-Pintura Acrílica Cor Branco Gelo, Massa (kg) | EI-REV-Pintura Acrílica Cor Branco Gelo, Área de Componente Projetada (Líquida) (m2) | EI-REV-Pintura Acrílica Cor Branco Gelo, Área de Componente Projetada (Bruta) (m2) | EI-REV-Pintura Acrílica Cor Branco Gelo, Volume Componente (Líquido) (m3) | EI-REV-Pintura Acrílica Cor Branco Gelo, Volume do componente (Bruto) (m3) | EI-REV-Chapisco (interno) 2, Massa (kg) | EI-REV-Chapisco (interno) 2, Área de Componente Projetada (Líquida) (m2) | EI-REV-Chapisco (interno) 2, Área de Componente Projetada (Bruta) (m2) | EI-REV-Chapisco (interno) 2, Volume Componente (Líquido) (m3) | EI-REV-Chapisco (interno) 2, Volume do componente (Bruto) (m3) | EI-REV-Emboço Interno 2, Massa (kg) | EI-REV-Emboço Interno 2, Área de Componente Projetada (Líquida) (m2) | EI-REV-Emboço Interno 2, Área de Componente Projetada (Bruta) (m2) | EI-REV-Emboço Interno 2, Volume Componente (Líquido) (m3) | EI-REV-Emboço Interno 2, Volume do componente (Bruto) (m3) | EI-REV-Cerâmica 30x40 2, Massa (kg) | EI-REV-Cerâmica 30x40 2, Área de Componente Projetada (Líquida) (m2) | EI-REV-Cerâmica 30x40 2, Área de Componente Projetada (Bruta) (m2) | EI-REV-Cerâmica 30x40 2, Volume Componente (Líquido) (m3) | EI-REV-Cerâmica 30x40 2, Volume do componente (Bruto) (m3)
AL09 | 163.047 | 2.80116 | 4.72716 | 0.251616 | 0.424956 | 17.9545 | 2.76253 | 4.68853 | 0.0138111 | 0.0234411 | 64.9166 | 1.66675 | 3.27775 | 0.0324583 | 0.064678 | 3.58769 | 0.0920972 | 0.182097 | 0.00179384 | 0.00359383 | 17.8927 | 2.75303 | 4.67903 | 0.0137636 | 0.0233936 | 7.17348 | 1.10361 | 1.32861 | 0.00551806 | 0.00664306 | 7.6232 | 1.1733 | 1.3983 | 0.005864 | 0.006989 | 19.8773 | 1.89384 | 2.11884 | 0.0152902 | 0.0175402 | 18.0845 | 2.78253 | 4.70853 | 0.0139111 | 0.0235411 | 17.9967 | 2.76903 | 4.69503 | 0.0138436 | 0.0234736 | 128.367 | 3.87268 | 5.79868 | 0.0641833 | 0.102703
AL09 | 272.807 | 4.67777 | 4.67777 | 0.420999 | 0.420999 | 30.3177 | 4.66427 | 4.66427 | 0.0233213 | 0.0233213 | 123.449 | 3.24457 | 3.24457 | 0.0617245 | 0.0617245 | 6.85828 | 0.180254 | 0.180254 | 0.00342914 | 0.00342914 | 30.23 | 4.65077 | 4.65077 | 0.0232538 | 0.0232538 | 8.59612 | 1.32248 | 1.32248 | 0.0066124 | 0.0066124 | 8.5711 | 1.31863 | 1.31863 | 0.00659315 | 0.00659315 | 19.5447 | 2.10897 | 2.10897 | 0.0150344 | 0.0150344 | 30.3437 | 4.66827 | 4.66827 | 0.0233413 | 0.0233413 | 30.256 | 4.65477 | 4.65477 | 0.0232738 | 0.0232738 | 199.329 | 5.61445 | 5.61445 | 0.0996646 | 0.0996646

# IfcWall: FNDE-AL09-I4-I5 (30x40-vermelho) 150 x 3100 (3)
In: TÉRREO
Classification: Parede (Classificação Archicad); Material: TIJOLO - CERAMICO 9x19x39 - espessura 15cm, EI-REV-Chapisco (interno) (2), EI-REV-Cerâmica 30x40 (2), EI-REV-Cerâmica 10x10 Vermelha, EI-REV-Emboço Interno (2), EI-REV-Massa única - Maior que 10m², EI-REV-Massa Corrida PVA (interna), EI-REV-Pintura Acrílica Cor Branco Gelo
FNDE - Alvenarias: Alvenaria de Vedação / Edificação; Sistemas de Cobertura: -; Esquadrias - Fechamentos metálicos e Gradis: -; 1_Bloco: BLOCO A; 0_ID: AL09
Pset_WallCommon - IsExternal: no; LoadBearing: no
Component Quantities - TIJOLO - CERAMICO 9x19x39 - espessura 15cm, Altura do Componente Retangular: 3.1 m; TIJOLO - CERAMICO 9x19x39 - espessura 15cm, Largura do Componente Retangular: 0.09 m; TIJOLO - CERAMICO 9x19x39 - espessura 15cm, Área de Seção Transversal do Componente: 0.279 m2; EI-REV-Chapisco (interno) 1, Altura do Componente Retangular: 3.1 m; EI-REV-Chapisco (interno) 1, Largura do Componente Retangular: 0.005 m; EI-REV-Chapisco (interno) 1, Área de Seção Transversal do Componente: 0.0155 m2; EI-REV-Cerâmica 30x40 1, Altura do Componente Retangular: 1.8 m; EI-REV-Cerâmica 30x40 1, Largura do Componente Retangular: 0.02 m; EI-REV-Cerâmica 30x40 1, Área de Seção Transversal do Componente: 0.036 m2; EI-REV-Cerâmica 10x10 Vermelha, Altura do Componente Retangular: 0.1 m; EI-REV-Cerâmica 10x10 Vermelha, Largura do Componente Retangular: 0.02 m; EI-REV-Cerâmica 10x10 Vermelha, Área de Seção Transversal do Componente: 0.002 m2; EI-REV-Emboço Interno 1, Altura do Componente Retangular: 3.1 m; EI-REV-Emboço Interno 1, Largura do Componente Retangular: 0.005 m; EI-REV-Emboço Interno 1, Área de Seção Transversal do Componente: 0.0155 m2; EI-REV-Massa única - Maior que 10m², Altura do Componente Retangular: 1.17 m; EI-REV-Massa única - Maior que 10m², Largura do Componente Retangular: 0.005 m; EI-REV-Massa única - Maior que 10m², Área de Seção Transversal do Componente: 0.00585001 m2; EI-REV-Massa Corrida PVA (interna), Altura do Componente Retangular: 1.17 m; EI-REV-Massa Corrida PVA (interna), Largura do Componente Retangular: 0.005 m; EI-REV-Massa Corrida PVA (interna), Área de Seção Transversal do Componente: 0.00585001 m2; EI-REV-Pintura Acrílica Cor Branco Gelo, Altura do Componente Retangular: 1.17 m; EI-REV-Pintura Acrílica Cor Branco Gelo, Largura do Componente Retangular: 0.00999999 m; EI-REV-Pintura Acrílica Cor Branco Gelo, Área de Seção Transversal do Componente: 0.0117 m2; EI-REV-Cerâmica 30x40 2, Altura do Componente Retangular: 3.1 m; EI-REV-Cerâmica 30x40 2, Largura do Componente Retangular: 0.02 m; EI-REV-Cerâmica 30x40 2, Área de Seção Transversal do Componente: 0.062 m2
Name | TIJOLO - CERAMICO 9x19x39 - espessura 15cm, Massa (kg) | TIJOLO - CERAMICO 9x19x39 - espessura 15cm, Área de Componente Projetada (Líquida) (m2) | TIJOLO - CERAMICO 9x19x39 - espessura 15cm, Área de Componente Projetada (Bruta) (m2) | TIJOLO - CERAMICO 9x19x39 - espessura 15cm, Volume Componente (Líquido) (m3) | TIJOLO - CERAMICO 9x19x39 - espessura 15cm, Volume do componente (Bruto) (m3) | EI-REV-Chapisco (interno) 1, Massa (kg) | EI-REV-Chapisco (interno) 1, Área de Componente Projetada (Líquida) (m2) | EI-REV-Chapisco (interno) 1, Área de Componente Projetada (Bruta) (m2) | EI-REV-Chapisco (interno) 1, Volume Componente (Líquido) (m3) | EI-REV-Chapisco (interno) 1, Volume do componente (Bruto) (m3) | EI-REV-Cerâmica 30x40 1, Massa (kg) | EI-REV-Cerâmica 30x40 1, Área de Componente Projetada (Líquida) (m2) | EI-REV-Cerâmica 30x40 1, Área de Componente Projetada (Bruta) (m2) | EI-REV-Cerâmica 30x40 1, Volume Componente (Líquido) (m3) | EI-REV-Cerâmica 30x40 1, Volume do componente (Bruto) (m3) | EI-REV-Cerâmica 10x10 Vermelha, Massa (kg) | EI-REV-Cerâmica 10x10 Vermelha, Área de Componente Projetada (Líquida) (m2) | EI-REV-Cerâmica 10x10 Vermelha, Área de Componente Projetada (Bruta) (m2) | EI-REV-Cerâmica 10x10 Vermelha, Volume Componente (Líquido) (m3) | EI-REV-Cerâmica 10x10 Vermelha, Volume do componente (Bruto) (m3) | EI-REV-Emboço Interno 1, Massa (kg) | EI-REV-Emboço Interno 1, Área de Componente Projetada (Líquida) (m2) | EI-REV-Emboço Interno 1, Área de Componente Projetada (Bruta) (m2) | EI-REV-Emboço Interno 1, Volume Componente (Líquido) (m3) | EI-REV-Emboço Interno 1, Volume do componente (Bruto) (m3) | EI-REV-Massa única - Maior que 10m², Massa (kg) | EI-REV-Massa única - Maior que 10m², Área de Componente Projetada (Líquida) (m2) | EI-REV-Massa única - Maior que 10m², Área de Componente Projetada (Bruta) (m2) | EI-REV-Massa única - Maior que 10m², Volume Componente (Líquido) (m3) | EI-REV-Massa única - Maior que 10m², Volume do componente (Bruto) (m3) | EI-REV-Massa Corrida PVA (interna), Massa (kg) | EI-REV-Massa Corrida PVA (interna), Área de Componente Projetada (Líquida) (m2) | EI-REV-Massa Corrida PVA (interna), Área de Componente Projetada (Bruta) (m2) | EI-REV-Massa Corrida PVA (interna), Volume Componente (Líquido) (m3) | EI-REV-Massa Corrida PVA (interna), Volume do componente (Bruto) (m3) | EI-REV-Pintura Acrílica Cor Branco Gelo, Massa (kg) | EI-REV-Pintura Acrílica Cor Branco Gelo, Área de Componente Projetada (Líquida) (m2) | EI-REV-Pintura Acrílica Cor Branco Gelo, Área de Componente Projetada (Bruta) (m2) | EI-REV-Pintura Acrílica Cor Branco Gelo, Volume Componente (Líquido) (m3) | EI-REV-Pintura Acrílica Cor Branco Gelo, Volume do componente (Bruto) (m3) | EI-REV-Chapisco (interno) 2, Massa (kg) | EI-REV-Chapisco (interno) 2, Área de Componente Projetada (Líquida) (m2) | EI-REV-Chapisco (interno) 2, Área de Componente Projetada (Bruta) (m2) | EI-REV-Chapisco (interno) 2, Altura do Componente Retangular (m) | EI-REV-Chapisco (interno) 2, Largura do Componente Retangular (m) | EI-REV-Chapisco (interno) 2, Área de Seção Transversal do Componente (m2) | EI-REV-Chapisco (interno) 2, Volume Componente (Líquido) (m3) | EI-REV-Chapisco (interno) 2, Volume do componente (Bruto) (m3) | EI-REV-Cerâmica 30x40 2, Massa (kg) | EI-REV-Cerâmica 30x40 2, Área de Componente Projetada (Líquida) (m2) | EI-REV-Cerâmica 30x40 2, Área de Componente Projetada (Bruta) (m2) | EI-REV-Cerâmica 30x40 2, Volume Componente (Líquido) (m3) | EI-REV-Cerâmica 30x40 2, Volume do componente (Bruto) (m3) | EI-REV-Chapisco (interno) 1
AL09 | 177.036 | 3.04103 | 4.96703 | 0.273204 | 0.446544 | 18.1519 | 2.7929 | 4.7189 | 0.013963 | 0.023593 | 66.2191 | 1.69885 | 3.30985 | 0.0331096 | 0.0653296 | 3.66006 | 0.0938808 | 0.183881 | 0.00183003 | 0.00363003 | 18.0641 | 2.7794 | 4.7054 | 0.0138955 | 0.0235255 | 7.26778 | 1.11812 | 1.34312 | 0.0055906 | 0.0067156 | 7.68748 | 1.18318 | 1.40818 | 0.00591345 | 0.00703845 | 19.9649 | 1.90124 | 2.12624 | 0.0153576 | 0.0176076 | 18.2396 | 2.8064 | 4.7324 | 3.1 | 0.005 | 0.0155 | 0.0140305 | 0.0236605 | 132.564 | 3.97797 | 5.90397 | 0.066282 | 0.104802 | 2 with these values
AL09 | 316.599 | 5.42866 | 5.42866 | 0.488579 | 0.488579 | 35.1108 | 5.40166 | 5.40166 | 0.0270083 | 0.0270083 | 140.444 | 3.51111 | 3.51111 | 0.0702221 | 0.0702221 | 7.80246 | 0.195061 | 0.195061 | 0.00390123 | 0.00390123 | 34.9353 | 5.37466 | 5.37466 | 0.0268733 | 0.0268733 | 9.91298 | 1.52507 | 1.52507 | 0.00762537 | 0.00762537 | 9.86293 | 1.51737 | 1.51737 | 0.00758687 | 0.00758687 | 25.1952 | 2.28222 | 2.28222 | 0.0193809 | 0.0193809 | 36.778 | 5.65816 | 5.65816 | 3.1 | 0.005 | 0.0155 | 0.0282908 | 0.0282908 | 232.048 | 6.4499 | 6.4499 | 0.116024 | 0.116024 | Component Quantities - EI-REV-Chapisco (interno) 2: 2 with these values
AL09 | 276.754 | 4.74544 | 4.74544 | 0.427089 | 0.427089 | 30.7576 | 4.73194 | 4.73194 | 0.0236597 | 0.0236597 | 125.036 | 3.24456 | 3.24456 | 0.062518 | 0.062518 | 6.94645 | 0.180254 | 0.180254 | 0.00347322 | 0.00347322 | 30.6698 | 4.71844 | 4.71844 | 0.0235922 | 0.0235922 | 8.72157 | 1.34178 | 1.34178 | 0.0067089 | 0.0067089 | 8.69654 | 1.33793 | 1.33793 | 0.00668965 | 0.00668965 | 19.7351 | 2.10897 | 2.10897 | 0.0151808 | 0.0151808 |  |  |  |  |  |  |  |  | 200.393 | 5.58846 | 5.58846 | 0.100196 | 0.100196 | 2 with these values | Component Quantities - EI-REV-Emboço Interno 1: 2 with these values

# IfcWall: FNDE-AL09-I4-I6 (30x40) 150 x 3100 (2)
In: TÉRREO
Classification: Parede (Classificação Archicad); Material: TIJOLO - CERAMICO 9x19x39 - espessura 15cm, EI-REV-Chapisco (interno) (2), EI-REV-Cerâmica 30x40 h=1,50, EI-REV-Emboço Interno (2), EI-REV-Massa única - Maior que 10m², EI-REV-Massa Corrida PVA (interna), EI-REV-Pintura Acrílica Cor Branco Gelo, EI-REV-Cerâmica 30x40
FNDE - Alvenarias: Alvenaria de Vedação / Edificação; Sistemas de Cobertura: -; Esquadrias - Fechamentos metálicos e Gradis: -; 1_Bloco: BLOCO A; 0_ID: AL09
Pset_WallCommon - IsExternal: no; LoadBearing: no
Component Quantities - TIJOLO - CERAMICO 9x19x39 - espessura 15cm, Altura do Componente Retangular: 3.1 m; TIJOLO - CERAMICO 9x19x39 - espessura 15cm, Largura do Componente Retangular: 0.09 m; TIJOLO - CERAMICO 9x19x39 - espessura 15cm, Área de Seção Transversal do Componente: 0.279 m2; EI-REV-Chapisco (interno) 1, Altura do Componente Retangular: 3.1 m; EI-REV-Chapisco (interno) 1, Largura do Componente Retangular: 0.005 m; EI-REV-Chapisco (interno) 1, Área de Seção Transversal do Componente: 0.0155 m2; EI-REV-Cerâmica 30x40 h=1,50, Altura do Componente Retangular: 1.5 m; EI-REV-Cerâmica 30x40 h=1,50, Largura do Componente Retangular: 0.02 m; EI-REV-Cerâmica 30x40 h=1,50, Área de Seção Transversal do Componente: 0.03 m2; EI-REV-Massa única - Maior que 10m², Altura do Componente Retangular: 1.6 m; EI-REV-Massa única - Maior que 10m², Largura do Componente Retangular: 0.005 m; EI-REV-Massa única - Maior que 10m², Área de Seção Transversal do Componente: 0.008 m2; EI-REV-Pintura Acrílica Cor Branco Gelo, Altura do Componente Retangular: 1.6 m; EI-REV-Pintura Acrílica Cor Branco Gelo, Largura do Componente Retangular: 0.01 m; EI-REV-Pintura Acrílica Cor Branco Gelo, Área de Seção Transversal do Componente: 0.016 m2; EI-REV-Cerâmica 30x40, Altura do Componente Retangular: 3.1 m; EI-REV-Cerâmica 30x40, Largura do Componente Retangular: 0.02 m; EI-REV-Cerâmica 30x40, Área de Seção Transversal do Componente: 0.062 m2; EI-REV-Massa única - Maior que 10m²: 2 with these values
Name | TIJOLO - CERAMICO 9x19x39 - espessura 15cm, Massa (kg) | TIJOLO - CERAMICO 9x19x39 - espessura 15cm, Área de Componente Projetada (Líquida) (m2) = EI-REV-Chapisco (interno) 1, Área de Componente Projetada (Líquida) (m2) | TIJOLO - CERAMICO 9x19x39 - espessura 15cm, Área de Componente Projetada (Bruta) (m2) = EI-REV-Chapisco (interno) 1, Área de Componente Projetada (Bruta) (m2) | TIJOLO - CERAMICO 9x19x39 - espessura 15cm, Volume Componente (Líquido) (m3) | TIJOLO - CERAMICO 9x19x39 - espessura 15cm, Volume do componente (Bruto) (m3) | EI-REV-Chapisco (interno) 1, Massa (kg) | EI-REV-Chapisco (interno) 1, Volume Componente (Líquido) (m3) | EI-REV-Chapisco (interno) 1, Volume do componente (Bruto) (m3) | EI-REV-Cerâmica 30x40 h=1,50, Massa (kg) | EI-REV-Cerâmica 30x40 h=1,50, Área de Componente Projetada (Líquida) (m2) = EI-REV-Cerâmica 30x40 h=1,50, Área de Componente Projetada (Bruta) (m2) | EI-REV-Cerâmica 30x40 h=1,50, Volume Componente (Líquido) (m3) = EI-REV-Cerâmica 30x40 h=1,50, Volume do componente (Bruto) (m3) | EI-REV-Massa única - Maior que 10m², Massa (kg) | EI-REV-Massa única - Maior que 10m², Área de Componente Projetada (Líquida) (m2) | EI-REV-Massa única - Maior que 10m², Área de Componente Projetada (Bruta) (m2) | EI-REV-Massa única - Maior que 10m², Volume Componente (Líquido) (m3) | EI-REV-Massa única - Maior que 10m², Volume do componente (Bruto) (m3) | EI-REV-Pintura Acrílica Cor Branco Gelo, Massa (kg) | EI-REV-Pintura Acrílica Cor Branco Gelo, Área de Componente Projetada (Líquida) (m2) | EI-REV-Pintura Acrílica Cor Branco Gelo, Área de Componente Projetada (Bruta) (m2) | EI-REV-Pintura Acrílica Cor Branco Gelo, Volume Componente (Líquido) (m3) | EI-REV-Pintura Acrílica Cor Branco Gelo, Volume do componente (Bruto) (m3) | EI-REV-Cerâmica 30x40, Massa (kg) | EI-REV-Cerâmica 30x40, Área de Componente Projetada (Líquida) (m2) | EI-REV-Cerâmica 30x40, Área de Componente Projetada (Bruta) (m2) | EI-REV-Cerâmica 30x40, Volume Componente (Líquido) (m3) | EI-REV-Cerâmica 30x40, Volume do componente (Bruto) (m3) | EI-REV-Chapisco (interno) 1
AL09 | 448.344 | 7.68765 | 9.26265 | 0.691889 | 0.833639 | 49.9697 | 0.0384383 | 0.0463133 | 207.701 | 5.33352 | 0.103851 | 16.5213 | 2.54173 | 4.11673 | 0.0127087 | 0.0205837 | 43.201 | 4.11408 | 5.68908 | 0.0332316 | 0.0489816 | 314.547 | 8.86913 | 10.4441 | 0.157274 | 0.188774 | 2 with these values | Component Quantities - EI-REV-Chapisco (interno) 2, Massa: 49.18 kg; EI-REV-Chapisco (interno) 2, Área de Componente Projetada (Líquida): 7.56615 m2; EI-REV-Chapisco (interno) 2, Área de Componente Projetada (Bruta): 9.14115 m2; EI-REV-Chapisco (interno) 2, Altura do Componente Retangular: 3.1 m; EI-REV-Chapisco (interno) 2, Largura do Componente Retangular: 0.005 m; EI-REV-Chapisco (interno) 2, Área de Seção Transversal do Componente: 0.0155 m2; EI-REV-Chapisco (interno) 2, Volume Componente (Líquido): 0.0378308 m3; EI-REV-Chapisco (interno) 2, Volume do componente (Bruto): 0.0457058 m3; EI-REV-Emboço Interno 2, Massa: 49.0922 kg; EI-REV-Emboço Interno 2, Área de Componente Projetada (Líquida): 7.55265 m2; EI-REV-Emboço Interno 2, Área de Componente Projetada (Bruta): 9.12765 m2; EI-REV-Emboço Interno 2, Altura do Componente Retangular: 3.1 m; EI-REV-Emboço Interno 2, Largura do Componente Retangular: 0.005 m; EI-REV-Emboço Interno 2, Área de Seção Transversal do Componente: 0.0155 m2; EI-REV-Emboço Interno 2, Volume Componente (Líquido): 0.0377633 m3; EI-REV-Emboço Interno 2, Volume do componente (Bruto): 0.0456383 m3
AL09 | 2.37212 | 0.0406742 | 0.0406742 | 0.00366068 | 0.00366068 | 0.264382 | 0.000203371 | 0.000203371 | 3.21385 | 0.255 | 0.00160693 | 0.117503 | 0.0180774 | 0.0180774 | 0.0000903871 | 0.0000903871 | 1.87552 | 0.272 | 0.272 | 0.00144271 | 0.00144271 | 6.51963 | 0.527 | 0.527 | 0.00325982 | 0.00325982 | 4 with these values

# IfcWall: FNDE-AL09-I4-I7 (30x40-amarela) 150 x 3100 (2)
In: TÉRREO
Classification: Parede (Classificação Archicad); Material: TIJOLO - CERAMICO 9x19x39 - espessura 15cm, EI-REV-Chapisco (interno) (2), EI-REV-Cerâmica 10x10 Amarela, EI-REV-Cerâmica 10x10 Branca, EI-REV-Emboço Interno (2), EI-REV-Massa única - Maior que 10m², EI-REV-Massa Corrida PVA (interna), EI-REV-Pintura Acrílica Cor Branco Gelo, EI-REV-Cerâmica 30x40
FNDE - Alvenarias: Alvenaria de Vedação / Edificação; Sistemas de Cobertura: -; Esquadrias - Fechamentos metálicos e Gradis: -; 1_Bloco: BLOCO A; 0_ID: AL09
Pset_WallCommon - IsExternal: no; LoadBearing: no
Component Quantities - TIJOLO - CERAMICO 9x19x39 - espessura 15cm, Altura do Componente Retangular: 3.1 m; TIJOLO - CERAMICO 9x19x39 - espessura 15cm, Largura do Componente Retangular: 0.09 m; TIJOLO - CERAMICO 9x19x39 - espessura 15cm, Área de Seção Transversal do Componente: 0.279 m2; EI-REV-Chapisco (interno) 1, Altura do Componente Retangular: 3.1 m; EI-REV-Chapisco (interno) 1, Largura do Componente Retangular: 0.005 m; EI-REV-Chapisco (interno) 1, Área de Seção Transversal do Componente: 0.0155 m2; EI-REV-Cerâmica 10x10 Amarela, Altura do Componente Retangular: 0.9 m; EI-REV-Cerâmica 10x10 Amarela, Largura do Componente Retangular: 0.02 m; EI-REV-Cerâmica 10x10 Amarela, Área de Seção Transversal do Componente: 0.018 m2; EI-REV-Cerâmica 10x10 Branca, Altura do Componente Retangular: 0.1 m; EI-REV-Cerâmica 10x10 Branca, Largura do Componente Retangular: 0.02 m; EI-REV-Cerâmica 10x10 Branca, Área de Seção Transversal do Componente: 0.002 m2; EI-REV-Emboço Interno 1, Altura do Componente Retangular: 3.1 m; EI-REV-Emboço Interno 1, Largura do Componente Retangular: 0.005 m; EI-REV-Emboço Interno 1, Área de Seção Transversal do Componente: 0.0155 m2; EI-REV-Massa única - Maior que 10m², Altura do Componente Retangular: 2.06 m; EI-REV-Massa única - Maior que 10m², Largura do Componente Retangular: 0.00499999 m; EI-REV-Massa única - Maior que 10m², Área de Seção Transversal do Componente: 0.0103 m2; EI-REV-Massa Corrida PVA (interna), Altura do Componente Retangular: 2.06 m; EI-REV-Massa Corrida PVA (interna), Largura do Componente Retangular: 0.00500002 m; EI-REV-Massa Corrida PVA (interna), Área de Seção Transversal do Componente: 0.0103 m2; EI-REV-Pintura Acrílica Cor Branco Gelo, Altura do Componente Retangular: 2.06 m; EI-REV-Pintura Acrílica Cor Branco Gelo, Largura do Componente Retangular: 0.01 m; EI-REV-Pintura Acrílica Cor Branco Gelo, Área de Seção Transversal do Componente: 0.0206 m2; EI-REV-Chapisco (interno) 2, Altura do Componente Retangular: 3.1 m; EI-REV-Chapisco (interno) 2, Largura do Componente Retangular: 0.005 m; EI-REV-Chapisco (interno) 2, Área de Seção Transversal do Componente: 0.0155 m2; EI-REV-Cerâmica 30x40, Altura do Componente Retangular: 3.1 m; EI-REV-Cerâmica 30x40, Largura do Componente Retangular: 0.02 m; EI-REV-Cerâmica 30x40, Área de Seção Transversal do Componente: 0.062 m2; EI-REV-Emboço Interno 2, Altura do Componente Retangular: 3.1 m; EI-REV-Emboço Interno 2, Largura do Componente Retangular: 0.005 m; EI-REV-Emboço Interno 2, Área de Seção Transversal do Componente: 0.0155 m2
Name | TIJOLO - CERAMICO 9x19x39 - espessura 15cm, Massa (kg) | TIJOLO - CERAMICO 9x19x39 - espessura 15cm, Área de Componente Projetada (Líquida) (m2) | TIJOLO - CERAMICO 9x19x39 - espessura 15cm, Área de Componente Projetada (Bruta) (m2) | TIJOLO - CERAMICO 9x19x39 - espessura 15cm, Volume Componente (Líquido) (m3) | TIJOLO - CERAMICO 9x19x39 - espessura 15cm, Volume do componente (Bruto) (m3) | EI-REV-Chapisco (interno) 1, Massa (kg) | EI-REV-Chapisco (interno) 1, Área de Componente Projetada (Líquida) (m2) | EI-REV-Chapisco (interno) 1, Área de Componente Projetada (Bruta) (m2) | EI-REV-Chapisco (interno) 1, Volume Componente (Líquido) (m3) | EI-REV-Chapisco (interno) 1, Volume do componente (Bruto) (m3) | EI-REV-Cerâmica 10x10 Amarela, Massa (kg) | EI-REV-Cerâmica 10x10 Amarela, Área de Componente Projetada (Líquida) (m2) | EI-REV-Cerâmica 10x10 Amarela, Área de Componente Projetada (Bruta) (m2) | EI-REV-Cerâmica 10x10 Amarela, Volume Componente (Líquido) (m3) | EI-REV-Cerâmica 10x10 Amarela, Volume do componente (Bruto) (m3) | EI-REV-Cerâmica 10x10 Branca, Massa (kg) | EI-REV-Cerâmica 10x10 Branca, Área de Componente Projetada (Líquida) (m2) | EI-REV-Cerâmica 10x10 Branca, Área de Componente Projetada (Bruta) (m2) | EI-REV-Cerâmica 10x10 Branca, Volume Componente (Líquido) (m3) | EI-REV-Cerâmica 10x10 Branca, Volume do componente (Bruto) (m3) | EI-REV-Emboço Interno 1, Massa (kg) | EI-REV-Emboço Interno 1, Área de Componente Projetada (Líquida) (m2) | EI-REV-Emboço Interno 1, Área de Componente Projetada (Bruta) (m2) | EI-REV-Emboço Interno 1, Volume Componente (Líquido) (m3) | EI-REV-Emboço Interno 1, Volume do componente (Bruto) (m3) | EI-REV-Massa única - Maior que 10m², Massa (kg) | EI-REV-Massa única - Maior que 10m², Área de Componente Projetada (Líquida) (m2) | EI-REV-Massa única - Maior que 10m², Área de Componente Projetada (Bruta) (m2) | EI-REV-Massa única - Maior que 10m², Volume Componente (Líquido) (m3) | EI-REV-Massa única - Maior que 10m², Volume do componente (Bruto) (m3) | EI-REV-Massa Corrida PVA (interna), Massa (kg) | EI-REV-Massa Corrida PVA (interna), Área de Componente Projetada (Líquida) (m2) | EI-REV-Massa Corrida PVA (interna), Área de Componente Projetada (Bruta) (m2) | EI-REV-Massa Corrida PVA (interna), Volume Componente (Líquido) (m3) | EI-REV-Massa Corrida PVA (interna), Volume do componente (Bruto) (m3) | EI-REV-Pintura Acrílica Cor Branco Gelo, Massa (kg) | EI-REV-Pintura Acrílica Cor Branco Gelo, Área de Componente Projetada (Líquida) (m2) | EI-REV-Pintura Acrílica Cor Branco Gelo, Área de Componente Projetada (Bruta) (m2) | EI-REV-Pintura Acrílica Cor Branco Gelo, Volume Componente (Líquido) (m3) | EI-REV-Pintura Acrílica Cor Branco Gelo, Volume do componente (Bruto) (m3) | EI-REV-Chapisco (interno) 2, Massa (kg) | EI-REV-Chapisco (interno) 2, Área de Componente Projetada (Líquida) (m2) | EI-REV-Chapisco (interno) 2, Área de Componente Projetada (Bruta) (m2) | EI-REV-Chapisco (interno) 2, Volume Componente (Líquido) (m3) | EI-REV-Chapisco (interno) 2, Volume do componente (Bruto) (m3) | EI-REV-Cerâmica 30x40, Massa (kg) | EI-REV-Cerâmica 30x40, Área de Componente Projetada (Líquida) (m2) | EI-REV-Cerâmica 30x40, Área de Componente Projetada (Bruta) (m2) | EI-REV-Cerâmica 30x40, Volume Componente (Líquido) (m3) | EI-REV-Cerâmica 30x40, Volume do componente (Bruto) (m3) | EI-REV-Emboço Interno 2, Massa (kg) | EI-REV-Emboço Interno 2, Área de Componente Projetada (Líquida) (m2) | EI-REV-Emboço Interno 2, Área de Componente Projetada (Bruta) (m2) | EI-REV-Emboço Interno 2, Volume Componente (Líquido) (m3) | EI-REV-Emboço Interno 2, Volume do componente (Bruto) (m3)
AL09 | 806.122 | 13.8278 | 22.6538 | 1.24402 | 2.03836 | 88.2661 | 13.5797 | 22.3557 | 0.067897 | 0.111777 | 250.879 | 6.69296 | 7.97799 | 0.125439 | 0.15114 | 20.2088 | 0.551996 | 0.891996 | 0.0101044 | 0.0169044 | 88.1783 | 13.5662 | 22.3422 | 0.0678295 | 0.11171 | 43.0212 | 6.61866 | 13.7697 | 0.0330932 | 0.0688481 | 42.9675 | 6.61036 | 13.7614 | 0.0330519 | 0.068807 | 115.28 | 11.1056 | 18.2566 | 0.0886771 | 0.160187 | 88.7809 | 13.6589 | 22.4349 | 0.068293 | 0.112173 | 597.13 | 18.758 | 27.5341 | 0.298565 | 0.474086 | 88.6626 | 13.6407 | 22.4167 | 0.068202 | 0.112082
AL09 | 237.145 | 4.06627 | 6.86727 | 0.365964 | 0.618054 | 26.1662 | 4.02557 | 6.82657 | 0.0201279 | 0.0341329 | 58.0198 | 1.4505 | 2.2815 | 0.0290099 | 0.0456299 | 3.73998 | 0.0934995 | 0.2535 | 0.00186999 | 0.00506999 | 26.0788 | 4.01212 | 6.81312 | 0.0200606 | 0.0340656 | 15.4804 | 2.3816 | 4.1916 | 0.011908 | 0.020958 | 15.4265 | 2.3733 | 4.1833 | 0.0118666 | 0.0209166 | 37.1908 | 3.36067 | 5.17067 | 0.0286083 | 0.0467083 | 26.1669 | 4.02567 | 6.82667 | 0.0201284 | 0.0341334 | 171.214 | 5.04911 | 7.85011 | 0.0856071 | 0.141627 | 26.0791 | 4.01217 | 6.81317 | 0.0200609 | 0.0340659

# IfcWall: FNDE-AL09-I4-I8 (30x40-cinza) 150 x 3100, AL09
In: TÉRREO
Classification: Parede (Classificação Archicad); Material: TIJOLO - CERAMICO 9x19x39 - espessura 15cm, EI-REV-Chapisco (interno) (2), EI-REV-Pintura Acrílica Cor Cinza, EI-REV-Massa única - Maior que 10m², EI-REV-Massa Corrida PVA (interna), EI-REV-Pintura Acrílica Cor Branco Gelo, EI-REV-Cerâmica 30x40, EI-REV-Emboço Interno
FNDE - Alvenarias: Alvenaria de Vedação / Edificação; Sistemas de Cobertura: -; Esquadrias - Fechamentos metálicos e Gradis: -; 1_Bloco: BLOCO A; 0_ID: AL09
Pset_WallCommon - IsExternal: no; LoadBearing: no
Component Quantities - TIJOLO - CERAMICO 9x19x39 - espessura 15cm, Massa: 681.961 kg; TIJOLO - CERAMICO 9x19x39 - espessura 15cm, Área de Componente Projetada (Líquida): 11.704 m2; TIJOLO - CERAMICO 9x19x39 - espessura 15cm, Área de Componente Projetada (Bruta): 19.4814 m2; TIJOLO - CERAMICO 9x19x39 - espessura 15cm, Altura do Componente Retangular: 3.1 m; TIJOLO - CERAMICO 9x19x39 - espessura 15cm, Largura do Componente Retangular: 0.09 m; TIJOLO - CERAMICO 9x19x39 - espessura 15cm, Área de Seção Transversal do Componente: 0.279 m2; TIJOLO - CERAMICO 9x19x39 - espessura 15cm, Volume Componente (Líquido): 1.05241 m3; TIJOLO - CERAMICO 9x19x39 - espessura 15cm, Volume do componente (Bruto): 1.75187 m3; EI-REV-Chapisco (interno) 1, Massa: 75.9691 kg; EI-REV-Chapisco (interno) 1, Área de Componente Projetada (Líquida): 11.6881 m2; EI-REV-Chapisco (interno) 1, Área de Componente Projetada (Bruta): 19.4661 m2; EI-REV-Chapisco (interno) 1, Altura do Componente Retangular: 3.1 m; EI-REV-Chapisco (interno) 1, Largura do Componente Retangular: 0.005 m; EI-REV-Chapisco (interno) 1, Área de Seção Transversal do Componente: 0.0155 m2; EI-REV-Chapisco (interno) 1, Volume Componente (Líquido): 0.0584377 m3; EI-REV-Chapisco (interno) 1, Volume do componente (Bruto): 0.0973259 m3; EI-REV-Pintura Acrílica Cor Cinza, Massa: 27.3655 kg; EI-REV-Pintura Acrílica Cor Cinza, Área de Componente Projetada (Líquida): 2.20999 m2; EI-REV-Pintura Acrílica Cor Cinza, Área de Componente Projetada (Bruta): 3.31289 m2; EI-REV-Pintura Acrílica Cor Cinza, Altura do Componente Retangular: 0.44 m; EI-REV-Pintura Acrílica Cor Cinza, Largura do Componente Retangular: 0.01 m; EI-REV-Pintura Acrílica Cor Cinza, Área de Seção Transversal do Componente: 0.0044 m2; EI-REV-Pintura Acrílica Cor Cinza, Volume Componente (Líquido): 0.0210504 m3; EI-REV-Pintura Acrílica Cor Cinza, Volume do componente (Bruto): 0.0319957 m3; EI-REV-Massa única - Maior que 10m², Massa: 151.926 kg; EI-REV-Massa única - Maior que 10m², Área de Componente Projetada (Líquida): 11.6878 m2; EI-REV-Massa única - Maior que 10m², Área de Componente Projetada (Bruta): 19.467 m2; EI-REV-Massa única - Maior que 10m², Altura do Componente Retangular: 3.1 m; EI-REV-Massa única - Maior que 10m², Largura do Componente Retangular: 0.01 m; EI-REV-Massa única - Maior que 10m², Área de Seção Transversal do Componente: 0.031 m2; EI-REV-Massa única - Maior que 10m², Volume Componente (Líquido): 0.116866 m3; EI-REV-Massa única - Maior que 10m², Volume do componente (Bruto): 0.194652 m3; EI-REV-Massa Corrida PVA (interna), Massa: 75.957 kg; EI-REV-Massa Corrida PVA (interna), Área de Componente Projetada (Líquida): 11.6863 m2; EI-REV-Massa Corrida PVA (interna), Área de Componente Projetada (Bruta): 19.4661 m2; EI-REV-Massa Corrida PVA (interna), Altura do Componente Retangular: 3.1 m; EI-REV-Massa Corrida PVA (interna), Largura do Componente Retangular: 0.005 m; EI-REV-Massa Corrida PVA (interna), Área de Seção Transversal do Componente: 0.0155 m2; EI-REV-Massa Corrida PVA (interna), Volume Componente (Líquido): 0.0584284 m3; EI-REV-Massa Corrida PVA (interna), Volume do componente (Bruto): 0.0973259 m3; EI-REV-Pintura Acrílica Cor Branco Gelo, Massa: 149.312 kg; EI-REV-Pintura Acrílica Cor Branco Gelo, Área de Componente Projetada (Líquida): 13.3415 m2; EI-REV-Pintura Acrílica Cor Branco Gelo, Área de Componente Projetada (Bruta): 20.0279 m2; EI-REV-Pintura Acrílica Cor Branco Gelo, Altura do Componente Retangular: 2.66 m; EI-REV-Pintura Acrílica Cor Branco Gelo, Largura do Componente Retangular: 0.01 m; EI-REV-Pintura Acrílica Cor Branco Gelo, Área de Seção Transversal do Componente: 0.0266 m2; EI-REV-Pintura Acrílica Cor Branco Gelo, Volume Componente (Líquido): 0.114855 m3; EI-REV-Pintura Acrílica Cor Branco Gelo, Volume do componente (Bruto): 0.181716 m3; EI-REV-Chapisco (interno) 2, Massa: 71.3071 kg; EI-REV-Chapisco (interno) 2, Área de Componente Projetada (Líquida): 10.9709 m2; EI-REV-Chapisco (interno) 2, Área de Componente Projetada (Bruta): 18.7371 m2; EI-REV-Chapisco (interno) 2, Altura do Componente Retangular: 3.1 m; EI-REV-Chapisco (interno) 2, Largura do Componente Retangular: 0.005 m; EI-REV-Chapisco (interno) 2, Área de Seção Transversal do Componente: 0.0155 m2; EI-REV-Chapisco (interno) 2, Volume Componente (Líquido): 0.0548516 m3; EI-REV-Chapisco (interno) 2, Volume do componente (Bruto): 0.0936809 m3; EI-REV-Cerâmica 30x40, Massa: 469.498 kg; EI-REV-Cerâmica 30x40, Área de Componente Projetada (Líquida): 14.4746 m2; EI-REV-Cerâmica 30x40, Área de Componente Projetada (Bruta): 22.2395 m2; EI-REV-Cerâmica 30x40, Altura do Componente Retangular: 3.1 m; EI-REV-Cerâmica 30x40, Largura do Componente Retangular: 0.02 m; EI-REV-Cerâmica 30x40, Área de Seção Transversal do Componente: 0.062 m2; EI-REV-Cerâmica 30x40, Volume Componente (Líquido): 0.234749 m3; EI-REV-Cerâmica 30x40, Volume do componente (Bruto): 0.390023 m3; EI-REV-Emboço Interno, Massa: 70.8107 kg; EI-REV-Emboço Interno, Área de Componente Projetada (Líquida): 10.8945 m2; EI-REV-Emboço Interno, Área de Componente Projetada (Bruta): 18.6601 m2; EI-REV-Emboço Interno, Altura do Componente Retangular: 3.1 m; EI-REV-Emboço Interno, Largura do Componente Retangular: 0.005 m; EI-REV-Emboço Interno, Área de Seção Transversal do Componente: 0.0155 m2; EI-REV-Emboço Interno, Volume Componente (Líquido): 0.0544697 m3; EI-REV-Emboço Interno, Volume do componente (Bruto): 0.0932959 m3

# IfcWall: FNDE-AL09-I5 (azul) 120 x 3100, AL09
In: TÉRREO
Classification: Parede (Classificação Archicad); Material: EI-REV-Chapisco (interno), EI-REV-Pintura Acrílica Cor Branco Gelo, EI-REV-Cerâmica 30x40, EI-REV-Cerâmica 10x10 Azul, EI-REV-Emboço Interno, EI-REV-Massa única - Maior que 10m², EI-REV-Massa Corrida PVA (interna), TIJOLO - CERAMICO 9x19x39 - espessura 15cm
FNDE - Alvenarias: Alvenaria de Vedação / Edificação; Sistemas de Cobertura: -; Esquadrias - Fechamentos metálicos e Gradis: -; 1_Bloco: BLOCO A; 0_ID: AL09
Pset_WallCommon - IsExternal: yes; LoadBearing: no
Component Quantities - EI-REV-Chapisco (interno), Massa: 15.0041 kg; EI-REV-Chapisco (interno), Área de Componente Projetada (Líquida): 2.30833 m2; EI-REV-Chapisco (interno), Área de Componente Projetada (Bruta): 2.30833 m2; EI-REV-Chapisco (interno), Altura do Componente Retangular: 3.1 m; EI-REV-Chapisco (interno), Largura do Componente Retangular: 0.005 m; EI-REV-Chapisco (interno), Área de Seção Transversal do Componente: 0.0155 m2; EI-REV-Chapisco (interno), Volume Componente (Líquido): 0.0115416 m3; EI-REV-Chapisco (interno), Volume do componente (Bruto): 0.0115416 m3; EI-REV-Pintura Acrílica Cor Branco Gelo, Massa: 10.4785 kg; EI-REV-Pintura Acrílica Cor Branco Gelo, Área de Componente Projetada (Líquida): 0.971024 m2; EI-REV-Pintura Acrílica Cor Branco Gelo, Área de Componente Projetada (Bruta): 0.971024 m2; EI-REV-Pintura Acrílica Cor Branco Gelo, Altura do Componente Retangular: 1.17 m; EI-REV-Pintura Acrílica Cor Branco Gelo, Largura do Componente Retangular: 0.01 m; EI-REV-Pintura Acrílica Cor Branco Gelo, Área de Seção Transversal do Componente: 0.0117 m2; EI-REV-Pintura Acrílica Cor Branco Gelo, Volume Componente (Líquido): 0.00806041 m3; EI-REV-Pintura Acrílica Cor Branco Gelo, Volume do componente (Bruto): 0.00806041 m3; EI-REV-Cerâmica 30x40, Massa: 59.7553 kg; EI-REV-Cerâmica 30x40, Área de Componente Projetada (Líquida): 1.49388 m2; EI-REV-Cerâmica 30x40, Área de Componente Projetada (Bruta): 1.49388 m2; EI-REV-Cerâmica 30x40, Altura do Componente Retangular: 1.8 m; EI-REV-Cerâmica 30x40, Largura do Componente Retangular: 0.02 m; EI-REV-Cerâmica 30x40, Área de Seção Transversal do Componente: 0.036 m2; EI-REV-Cerâmica 30x40, Volume Componente (Líquido): 0.0298777 m3; EI-REV-Cerâmica 30x40, Volume do componente (Bruto): 0.0298777 m3; EI-REV-Cerâmica 10x10 Azul, Massa: 3.31974 kg; EI-REV-Cerâmica 10x10 Azul, Área de Componente Projetada (Líquida): 0.0829935 m2; EI-REV-Cerâmica 10x10 Azul, Área de Componente Projetada (Bruta): 0.0829935 m2; EI-REV-Cerâmica 10x10 Azul, Altura do Componente Retangular: 0.1 m; EI-REV-Cerâmica 10x10 Azul, Largura do Componente Retangular: 0.02 m; EI-REV-Cerâmica 10x10 Azul, Área de Seção Transversal do Componente: 0.002 m2; EI-REV-Cerâmica 10x10 Azul, Volume Componente (Líquido): 0.00165987 m3; EI-REV-Cerâmica 10x10 Azul, Volume do componente (Bruto): 0.00165987 m3; EI-REV-Emboço Interno, Massa: 14.9164 kg; EI-REV-Emboço Interno, Área de Componente Projetada (Líquida): 2.29483 m2; EI-REV-Emboço Interno, Área de Componente Projetada (Bruta): 2.29483 m2; EI-REV-Emboço Interno, Altura do Componente Retangular: 3.1 m; EI-REV-Emboço Interno, Largura do Componente Retangular: 0.005 m; EI-REV-Emboço Interno, Área de Seção Transversal do Componente: 0.0155 m2; EI-REV-Emboço Interno, Volume Componente (Líquido): 0.0114741 m3; EI-REV-Emboço Interno, Volume do componente (Bruto): 0.0114741 m3; EI-REV-Massa única - Maior que 10m², Massa: 4.22888 kg; EI-REV-Massa única - Maior que 10m², Área de Componente Projetada (Líquida): 0.6506 m2; EI-REV-Massa única - Maior que 10m², Área de Componente Projetada (Bruta): 0.6506 m2; EI-REV-Massa única - Maior que 10m², Altura do Componente Retangular: 1.17 m; EI-REV-Massa única - Maior que 10m², Largura do Componente Retangular: 0.00499997 m; EI-REV-Massa única - Maior que 10m², Área de Seção Transversal do Componente: 0.00584996 m2; EI-REV-Massa única - Maior que 10m², Volume Componente (Líquido): 0.00325298 m3; EI-REV-Massa única - Maior que 10m², Volume do componente (Bruto): 0.00325298 m3; EI-REV-Massa Corrida PVA (interna), Massa: 4.20388 kg; EI-REV-Massa Corrida PVA (interna), Área de Componente Projetada (Líquida): 0.64675 m2; EI-REV-Massa Corrida PVA (interna), Área de Componente Projetada (Bruta): 0.64675 m2; EI-REV-Massa Corrida PVA (interna), Altura do Componente Retangular: 1.17 m; EI-REV-Massa Corrida PVA (interna), Largura do Componente Retangular: 0.005 m; EI-REV-Massa Corrida PVA (interna), Área de Seção Transversal do Componente: 0.00585001 m2; EI-REV-Massa Corrida PVA (interna), Volume Componente (Líquido): 0.00323375 m3; EI-REV-Massa Corrida PVA (interna), Volume do componente (Bruto): 0.00323375 m3; TIJOLO - CERAMICO 9x19x39 - espessura 15cm, Massa: 135.409 kg; TIJOLO - CERAMICO 9x19x39 - espessura 15cm, Área de Componente Projetada (Líquida): 2.32183 m2; TIJOLO - CERAMICO 9x19x39 - espessura 15cm, Área de Componente Projetada (Bruta): 2.32183 m2; TIJOLO - CERAMICO 9x19x39 - espessura 15cm, Altura do Componente Retangular: 3.1 m; TIJOLO - CERAMICO 9x19x39 - espessura 15cm, Largura do Componente Retangular: 0.09 m; TIJOLO - CERAMICO 9x19x39 - espessura 15cm, Área de Seção Transversal do Componente: 0.279 m2; TIJOLO - CERAMICO 9x19x39 - espessura 15cm, Volume Componente (Líquido): 0.208964 m3; TIJOLO - CERAMICO 9x19x39 - espessura 15cm, Volume do componente (Bruto): 0.208964 m3

# IfcWall: FNDE-AL09-I5 (vermelho) 120 x 3100, AL09
In: TÉRREO
Classification: Parede (Classificação Archicad); Material: EI-REV-Chapisco (interno), EI-REV-Pintura Acrílica Cor Branco Gelo, EI-REV-Cerâmica 30x40, EI-REV-Cerâmica 10x10 Vermelha, EI-REV-Emboço Interno, EI-REV-Massa única - Maior que 10m², EI-REV-Massa Corrida PVA (interna), TIJOLO - CERAMICO 9x19x39 - espessura 15cm
FNDE - Alvenarias: Alvenaria de Vedação / Edificação; Sistemas de Cobertura: -; Esquadrias - Fechamentos metálicos e Gradis: -; 1_Bloco: BLOCO A; 0_ID: AL09
Pset_WallCommon - IsExternal: yes; LoadBearing: no
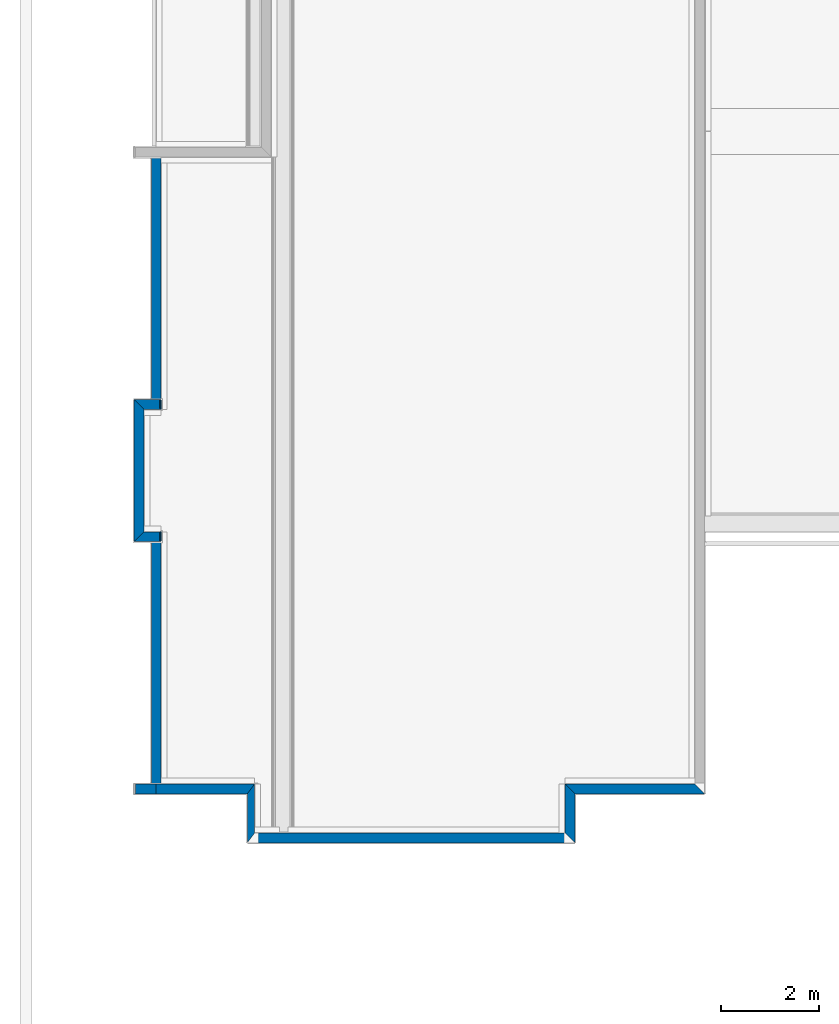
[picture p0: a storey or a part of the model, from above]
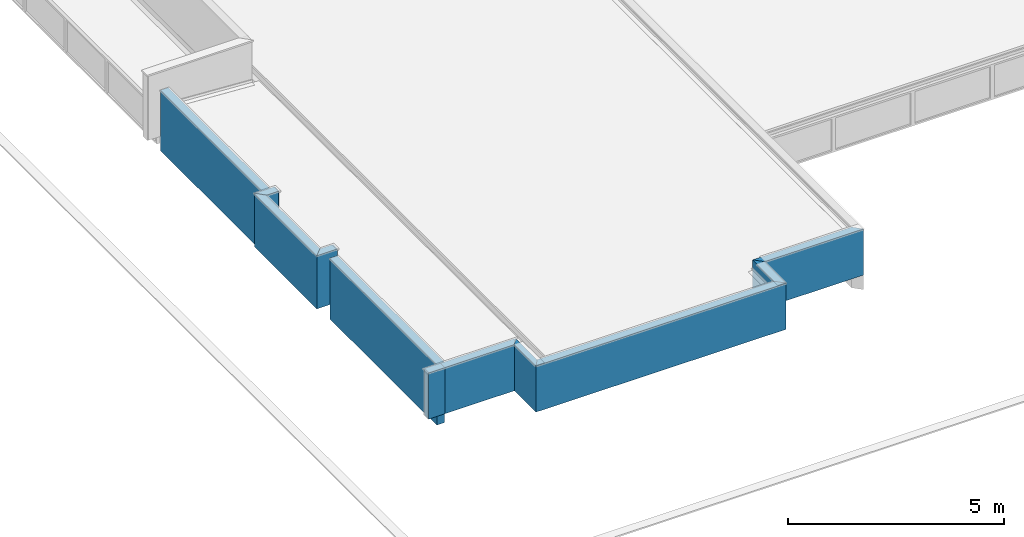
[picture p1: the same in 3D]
Properties of the parts of a building model (IFC4), part 14 of 22

# IfcWall: FNDE-AL09-I5 (vermelho) 120 x 3100, AL09
Component Quantities - EI-REV-Chapisco (interno), Massa: 15.1096 kg; EI-REV-Chapisco (interno), Área de Componente Projetada (Líquida): 2.32455 m2; EI-REV-Chapisco (interno), Área de Componente Projetada (Bruta): 2.32455 m2; EI-REV-Chapisco (interno), Altura do Componente Retangular: 3.1 m; EI-REV-Chapisco (interno), Largura do Componente Retangular: 0.005 m; EI-REV-Chapisco (interno), Área de Seção Transversal do Componente: 0.0155 m2; EI-REV-Chapisco (interno), Volume Componente (Líquido): 0.0116228 m3; EI-REV-Chapisco (interno), Volume do componente (Bruto): 0.0116228 m3; EI-REV-Pintura Acrílica Cor Branco Gelo, Massa: 13.689 kg; EI-REV-Pintura Acrílica Cor Branco Gelo, Área de Componente Projetada (Líquida): 1.053 m2; EI-REV-Pintura Acrílica Cor Branco Gelo, Área de Componente Projetada (Bruta): 1.053 m2; EI-REV-Pintura Acrílica Cor Branco Gelo, Altura do Componente Retangular: 1.17 m; EI-REV-Pintura Acrílica Cor Branco Gelo, Largura do Componente Retangular: 0.01 m; EI-REV-Pintura Acrílica Cor Branco Gelo, Área de Seção Transversal do Componente: 0.0117 m2; EI-REV-Pintura Acrílica Cor Branco Gelo, Volume Componente (Líquido): 0.01053 m3; EI-REV-Pintura Acrílica Cor Branco Gelo, Volume do componente (Bruto): 0.01053 m3; EI-REV-Cerâmica 30x40, Massa: 64.7999 kg; EI-REV-Cerâmica 30x40, Área de Componente Projetada (Líquida): 1.62 m2; EI-REV-Cerâmica 30x40, Área de Componente Projetada (Bruta): 1.62 m2; EI-REV-Cerâmica 30x40, Altura do Componente Retangular: 1.8 m; EI-REV-Cerâmica 30x40, Largura do Componente Retangular: 0.02 m; EI-REV-Cerâmica 30x40, Área de Seção Transversal do Componente: 0.036 m2; EI-REV-Cerâmica 30x40, Volume Componente (Líquido): 0.0324 m3; EI-REV-Cerâmica 30x40, Volume do componente (Bruto): 0.0324 m3; EI-REV-Cerâmica 10x10 Vermelha, Massa: 3.6 kg; EI-REV-Cerâmica 10x10 Vermelha, Área de Componente Projetada (Líquida): 0.09 m2; EI-REV-Cerâmica 10x10 Vermelha, Área de Componente Projetada (Bruta): 0.09 m2; EI-REV-Cerâmica 10x10 Vermelha, Altura do Componente Retangular: 0.1 m; EI-REV-Cerâmica 10x10 Vermelha, Largura do Componente Retangular: 0.02 m; EI-REV-Cerâmica 10x10 Vermelha, Área de Seção Transversal do Componente: 0.002 m2; EI-REV-Cerâmica 10x10 Vermelha, Volume Componente (Líquido): 0.0018 m3; EI-REV-Cerâmica 10x10 Vermelha, Volume do componente (Bruto): 0.0018 m3; EI-REV-Emboço Interno, Massa: 15.2794 kg; EI-REV-Emboço Interno, Área de Componente Projetada (Líquida): 2.89193 m2; EI-REV-Emboço Interno, Área de Componente Projetada (Bruta): 2.89193 m2; EI-REV-Emboço Interno, Altura do Componente Retangular: 3.1 m; EI-REV-Emboço Interno, Largura do Componente Retangular: 0.005 m; EI-REV-Emboço Interno, Área de Seção Transversal do Componente: 0.0155 m2; EI-REV-Emboço Interno, Volume Componente (Líquido): 0.0117534 m3; EI-REV-Emboço Interno, Volume do componente (Bruto): 0.0117534 m3; EI-REV-Massa única - Maior que 10m², Massa: 7.04662 kg; EI-REV-Massa única - Maior que 10m², Área de Componente Projetada (Líquida): 1.08997 m2; EI-REV-Massa única - Maior que 10m², Área de Componente Projetada (Bruta): 1.08997 m2; EI-REV-Massa única - Maior que 10m², Altura do Componente Retangular: 1.17 m; EI-REV-Massa única - Maior que 10m², Largura do Componente Retangular: 0.00499997 m; EI-REV-Massa única - Maior que 10m², Área de Seção Transversal do Componente: 0.00584996 m2; EI-REV-Massa única - Maior que 10m², Volume Componente (Líquido): 0.00542048 m3; EI-REV-Massa única - Maior que 10m², Volume do componente (Bruto): 0.00542048 m3; EI-REV-Massa Corrida PVA (interna), Massa: 7.02174 kg; EI-REV-Massa Corrida PVA (interna), Área de Componente Projetada (Líquida): 1.08027 m2; EI-REV-Massa Corrida PVA (interna), Área de Componente Projetada (Bruta): 1.08027 m2; EI-REV-Massa Corrida PVA (interna), Altura do Componente Retangular: 1.17 m; EI-REV-Massa Corrida PVA (interna), Largura do Componente Retangular: 0.005 m; EI-REV-Massa Corrida PVA (interna), Área de Seção Transversal do Componente: 0.00585001 m2; EI-REV-Massa Corrida PVA (interna), Volume Componente (Líquido): 0.00540134 m3; EI-REV-Massa Corrida PVA (interna), Volume do componente (Bruto): 0.00540134 m3; TIJOLO - CERAMICO 9x19x39 - espessura 15cm, Massa: 135.594 kg; TIJOLO - CERAMICO 9x19x39 - espessura 15cm, Área de Componente Projetada (Líquida): 2.325 m2; TIJOLO - CERAMICO 9x19x39 - espessura 15cm, Área de Componente Projetada (Bruta): 2.325 m2; TIJOLO - CERAMICO 9x19x39 - espessura 15cm, Altura do Componente Retangular: 3.1 m; TIJOLO - CERAMICO 9x19x39 - espessura 15cm, Largura do Componente Retangular: 0.09 m; TIJOLO - CERAMICO 9x19x39 - espessura 15cm, Área de Seção Transversal do Componente: 0.279 m2; TIJOLO - CERAMICO 9x19x39 - espessura 15cm, Volume Componente (Líquido): 0.20925 m3; TIJOLO - CERAMICO 9x19x39 - espessura 15cm, Volume do componente (Bruto): 0.20925 m3

# IfcWall: FNDE-AL09-I5-I5 (azul) 150 x 1930 (2)
In: TÉRREO
Classification: Parede (Classificação Archicad); Material: EI-REV-Chapisco (interno) (2), EI-REV-Cerâmica 30x40 (2), EI-REV-Cerâmica 10x10 Azul (2), EI-REV-Emboço Interno (2), TIJOLO - CERAMICO 9x19x39 - espessura 15cm
FNDE - Alvenarias: Mureta; Sistemas de Cobertura: -; Esquadrias - Fechamentos metálicos e Gradis: -; 1_Bloco: BLOCO B; 0_ID: AL09
Pset_WallCommon - IsExternal: no; LoadBearing: no
Component Quantities - EI-REV-Chapisco (interno) 1, Altura do Componente Retangular: 1.93 m; EI-REV-Chapisco (interno) 1, Largura do Componente Retangular: 0.005 m; EI-REV-Chapisco (interno) 1, Área de Seção Transversal do Componente: 0.00965 m2; EI-REV-Cerâmica 30x40 1, Altura do Componente Retangular: 1.8 m; EI-REV-Cerâmica 30x40 1, Largura do Componente Retangular: 0.02 m; EI-REV-Cerâmica 30x40 1, Área de Seção Transversal do Componente: 0.036 m2; EI-REV-Cerâmica 10x10 Azul 1, Altura do Componente Retangular: 0.1 m; EI-REV-Cerâmica 10x10 Azul 1, Largura do Componente Retangular: 0.02 m; EI-REV-Cerâmica 10x10 Azul 1, Área de Seção Transversal do Componente: 0.002 m2; EI-REV-Emboço Interno 1, Altura do Componente Retangular: 1.93 m; EI-REV-Emboço Interno 1, Largura do Componente Retangular: 0.005 m; EI-REV-Emboço Interno 1, Área de Seção Transversal do Componente: 0.00965 m2; TIJOLO - CERAMICO 9x19x39 - espessura 15cm, Altura do Componente Retangular: 1.93 m; TIJOLO - CERAMICO 9x19x39 - espessura 15cm, Largura do Componente Retangular: 0.09 m; TIJOLO - CERAMICO 9x19x39 - espessura 15cm, Área de Seção Transversal do Componente: 0.1737 m2
Name | EI-REV-Chapisco (interno) 1, Massa (kg) | EI-REV-Chapisco (interno) 1, Área de Componente Projetada (Líquida) (m2) = EI-REV-Chapisco (interno) 1, Área de Componente Projetada (Bruta) (m2) | EI-REV-Chapisco (interno) 1, Volume Componente (Líquido) (m3) = EI-REV-Chapisco (interno) 1, Volume do componente (Bruto) (m3) | EI-REV-Cerâmica 30x40 1, Massa (kg) | EI-REV-Cerâmica 30x40 1, Área de Componente Projetada (Líquida) (m2) = EI-REV-Cerâmica 30x40 1, Área de Componente Projetada (Bruta) (m2) | EI-REV-Cerâmica 30x40 1, Volume Componente (Líquido) (m3) = EI-REV-Cerâmica 30x40 1, Volume do componente (Bruto) (m3) | EI-REV-Cerâmica 10x10 Azul 1, Massa (kg) | EI-REV-Cerâmica 10x10 Azul 1, Área de Componente Projetada (Líquida) (m2) = EI-REV-Cerâmica 10x10 Azul 1, Área de Componente Projetada (Bruta) (m2) | EI-REV-Cerâmica 10x10 Azul 1, Volume Componente (Líquido) (m3) = EI-REV-Cerâmica 10x10 Azul 1, Volume do componente (Bruto) (m3) | EI-REV-Emboço Interno 1, Massa (kg) | EI-REV-Emboço Interno 1, Área de Componente Projetada (Líquida) (m2) = EI-REV-Emboço Interno 1, Área de Componente Projetada (Bruta) (m2) | EI-REV-Emboço Interno 1, Volume Componente (Líquido) (m3) = EI-REV-Emboço Interno 1, Volume do componente (Bruto) (m3) | TIJOLO - CERAMICO 9x19x39 - espessura 15cm, Massa (kg) | TIJOLO - CERAMICO 9x19x39 - espessura 15cm, Área de Componente Projetada (Líquida) (m2) = TIJOLO - CERAMICO 9x19x39 - espessura 15cm, Área de Componente Projetada (Bruta) (m2) | TIJOLO - CERAMICO 9x19x39 - espessura 15cm, Volume Componente (Líquido) (m3) = TIJOLO - CERAMICO 9x19x39 - espessura 15cm, Volume do componente (Bruto) (m3)
AL09 | 11.5464 | 1.77637 | 0.00888183 | 63.358 | 1.58395 | 0.031679 | 3.21928 | 0.0879973 | 0.00160964 | 11.4827 | 1.76657 | 0.00883283 | 104.64 | 1.79425 | 0.161482 | Component Quantities - EI-REV-Chapisco (interno) 1: 2 with these values; EI-REV-Cerâmica 30x40 1: 2 with these values; EI-REV-Cerâmica 10x10 Azul 1: 2 with these values; EI-REV-Emboço Interno 1: 2 with these values
AL09 | 8.70637 | 1.33944 | 0.00669721 | 49.678 | 1.24195 | 0.024839 | 2.76 | 0.069 | 0.00138 | 8.70637 | 1.33944 | 0.0066972 | 79.3165 | 1.35999 | 0.122402 | Component Quantities - EI-REV-Chapisco (interno) 2, Massa: 8.97684 kg; EI-REV-Chapisco (interno) 2, Área de Componente Projetada (Líquida): 1.38105 m2; EI-REV-Chapisco (interno) 2, Área de Componente Projetada (Bruta): 1.38105 m2; EI-REV-Chapisco (interno) 2, Altura do Componente Retangular: 1.93 m; EI-REV-Chapisco (interno) 2, Largura do Componente Retangular: 0.005 m; EI-REV-Chapisco (interno) 2, Área de Seção Transversal do Componente: 0.00965 m2; EI-REV-Chapisco (interno) 2, Volume Componente (Líquido): 0.00690526 m3; EI-REV-Chapisco (interno) 2, Volume do componente (Bruto): 0.00690526 m3; EI-REV-Cerâmica 30x40 2, Massa: 49.56 kg; EI-REV-Cerâmica 30x40 2, Área de Componente Projetada (Líquida): 1.239 m2; EI-REV-Cerâmica 30x40 2, Área de Componente Projetada (Bruta): 1.239 m2; EI-REV-Cerâmica 30x40 2, Altura do Componente Retangular: 1.8 m; EI-REV-Cerâmica 30x40 2, Largura do Componente Retangular: 0.02 m; EI-REV-Cerâmica 30x40 2, Área de Seção Transversal do Componente: 0.036 m2; EI-REV-Cerâmica 30x40 2, Volume Componente (Líquido): 0.02478 m3; EI-REV-Cerâmica 30x40 2, Volume do componente (Bruto): 0.02478 m3; EI-REV-Cerâmica 10x10 Azul 2, Massa: 2.84 kg; EI-REV-Cerâmica 10x10 Azul 2, Área de Componente Projetada (Líquida): 0.071 m2; EI-REV-Cerâmica 10x10 Azul 2, Área de Componente Projetada (Bruta): 0.071 m2; EI-REV-Cerâmica 10x10 Azul 2, Altura do Componente Retangular: 0.1 m; EI-REV-Cerâmica 10x10 Azul 2, Largura do Componente Retangular: 0.02 m; EI-REV-Cerâmica 10x10 Azul 2, Área de Seção Transversal do Componente: 0.002 m2; EI-REV-Cerâmica 10x10 Azul 2, Volume Componente (Líquido): 0.00142 m3; EI-REV-Cerâmica 10x10 Azul 2, Volume do componente (Bruto): 0.00142 m3; EI-REV-Emboço Interno 2, Massa: 8.93362 kg; EI-REV-Emboço Interno 2, Área de Componente Projetada (Líquida): 1.3744 m2; EI-REV-Emboço Interno 2, Área de Componente Projetada (Bruta): 1.3744 m2; EI-REV-Emboço Interno 2, Altura do Componente Retangular: 1.93 m; EI-REV-Emboço Interno 2, Largura do Componente Retangular: 0.005 m; EI-REV-Emboço Interno 2, Área de Seção Transversal do Componente: 0.00965 m2; EI-REV-Emboço Interno 2, Volume Componente (Líquido): 0.00687201 m3; EI-REV-Emboço Interno 2, Volume do componente (Bruto): 0.00687201 m3

# IfcWall: FNDE-AL09-I5-I5 (azul) 150 x 3100 (3)
In: TÉRREO
Classification: Parede (Classificação Archicad); Material: EI-REV-Chapisco (interno) (2), EI-REV-Pintura Acrílica Cor Branco Gelo, EI-REV-Pintura Acrílica Cor Branco Gelo - Interna, EI-REV-Cerâmica 30x40 (2), EI-REV-Cerâmica 10x10 Azul (2), EI-REV-Emboço Interno (2), EI-REV-Massa única - Maior que 10m² (2), EI-REV-Massa Corrida PVA (interna) (2), TIJOLO - CERAMICO 9x19x39 - espessura 15cm
FNDE - Alvenarias: Alvenaria de Vedação / Edificação; Sistemas de Cobertura: -; Esquadrias - Fechamentos metálicos e Gradis: -; 0_ID: AL09
Pset_WallCommon - IsExternal: no; LoadBearing: no
Component Quantities - EI-REV-Chapisco (interno) 1, Altura do Componente Retangular: 3.1 m; EI-REV-Chapisco (interno) 1, Largura do Componente Retangular: 0.005 m; EI-REV-Chapisco (interno) 1, Área de Seção Transversal do Componente: 0.0155 m2; EI-REV-Pintura Acrílica Cor Branco Gelo - Interna, Largura do Componente Retangular: 0.01 m; EI-REV-Cerâmica 30x40 1, Largura do Componente Retangular: 0.02 m; EI-REV-Cerâmica 10x10 Azul 1, Altura do Componente Retangular: 0.1 m; EI-REV-Cerâmica 10x10 Azul 1, Largura do Componente Retangular: 0.02 m; EI-REV-Cerâmica 10x10 Azul 1, Área de Seção Transversal do Componente: 0.002 m2; EI-REV-Emboço Interno 1, Altura do Componente Retangular: 3.1 m; EI-REV-Emboço Interno 1, Largura do Componente Retangular: 0.005 m; EI-REV-Emboço Interno 1, Área de Seção Transversal do Componente: 0.0155 m2; EI-REV-Massa única - Maior que 10m² 1, Largura do Componente Retangular: 0.005 m; EI-REV-Massa Corrida PVA (interna) 2, Largura do Componente Retangular: 0.005 m; TIJOLO - CERAMICO 9x19x39 - espessura 15cm, Altura do Componente Retangular: 3.1 m; TIJOLO - CERAMICO 9x19x39 - espessura 15cm, Largura do Componente Retangular: 0.09 m; TIJOLO - CERAMICO 9x19x39 - espessura 15cm, Área de Seção Transversal do Componente: 0.279 m2
Name | 1_Bloco | EI-REV-Chapisco (interno) 1, Massa (kg) | EI-REV-Chapisco (interno) 1, Área de Componente Projetada (Líquida) (m2) = EI-REV-Chapisco (interno) 1, Área de Componente Projetada (Bruta) (m2) | EI-REV-Chapisco (interno) 1, Volume Componente (Líquido) (m3) = EI-REV-Chapisco (interno) 1, Volume do componente (Bruto) (m3) | EI-REV-Chapisco (interno) 2, Massa (kg) | EI-REV-Chapisco (interno) 2, Área de Componente Projetada (Líquida) (m2) = EI-REV-Chapisco (interno) 2, Área de Componente Projetada (Bruta) (m2) | EI-REV-Chapisco (interno) 2, Altura do Componente Retangular (m) = EI-REV-Emboço Interno 2, Altura do Componente Retangular (m) | EI-REV-Chapisco (interno) 2, Largura do Componente Retangular (m) = EI-REV-Emboço Interno 2, Largura do Componente Retangular (m) | EI-REV-Chapisco (interno) 2, Área de Seção Transversal do Componente (m2) = EI-REV-Emboço Interno 2, Área de Seção Transversal do Componente (m2) | EI-REV-Chapisco (interno) 2, Volume Componente (Líquido) (m3) = EI-REV-Chapisco (interno) 2, Volume do componente (Bruto) (m3) | EI-REV-Pintura Acrílica Cor Branco Gelo, Massa (kg) | EI-REV-Pintura Acrílica Cor Branco Gelo, Área de Componente Projetada (Líquida) (m2) = EI-REV-Pintura Acrílica Cor Branco Gelo, Área de Componente Projetada (Bruta) (m2) | EI-REV-Pintura Acrílica Cor Branco Gelo, Altura do Componente Retangular (m) = EI-REV-Massa única - Maior que 10m² 1, Altura do Componente Retangular (m) = EI-REV-Massa Corrida PVA (interna) 1, Altura do Componente Retangular (m) | EI-REV-Pintura Acrílica Cor Branco Gelo, Largura do Componente Retangular (m) | EI-REV-Pintura Acrílica Cor Branco Gelo, Área de Seção Transversal do Componente (m2) | EI-REV-Pintura Acrílica Cor Branco Gelo, Volume Componente (Líquido) (m3) = EI-REV-Pintura Acrílica Cor Branco Gelo, Volume do componente (Bruto) (m3) | EI-REV-Pintura Acrílica Cor Branco Gelo - Interna, Massa (kg) | EI-REV-Pintura Acrílica Cor Branco Gelo - Interna, Área de Componente Projetada (Líquida) (m2) = EI-REV-Pintura Acrílica Cor Branco Gelo - Interna, Área de Componente Projetada (Bruta) (m2) | EI-REV-Pintura Acrílica Cor Branco Gelo - Interna, Altura do Componente Retangular (m) = EI-REV-Massa única - Maior que 10m² 2, Altura do Componente Retangular (m) = EI-REV-Massa Corrida PVA (interna) 2, Altura do Componente Retangular (m) | EI-REV-Pintura Acrílica Cor Branco Gelo - Interna, Área de Seção Transversal do Componente (m2) | EI-REV-Pintura Acrílica Cor Branco Gelo - Interna, Volume Componente (Líquido) (m3) = EI-REV-Pintura Acrílica Cor Branco Gelo - Interna, Volume do componente (Bruto) (m3) | EI-REV-Cerâmica 30x40 1, Massa (kg) | EI-REV-Cerâmica 30x40 1, Área de Componente Projetada (Líquida) (m2) = EI-REV-Cerâmica 30x40 1, Área de Componente Projetada (Bruta) (m2) | EI-REV-Cerâmica 30x40 1, Altura do Componente Retangular (m) | EI-REV-Cerâmica 30x40 1, Área de Seção Transversal do Componente (m2) | EI-REV-Cerâmica 30x40 1, Volume Componente (Líquido) (m3) = EI-REV-Cerâmica 30x40 1, Volume do componente (Bruto) (m3) | EI-REV-Cerâmica 10x10 Azul 1, Massa (kg) | EI-REV-Cerâmica 10x10 Azul 1, Área de Componente Projetada (Líquida) (m2) = EI-REV-Cerâmica 10x10 Azul 1, Área de Componente Projetada (Bruta) (m2) | EI-REV-Cerâmica 10x10 Azul 1, Volume Componente (Líquido) (m3) = EI-REV-Cerâmica 10x10 Azul 1, Volume do componente (Bruto) (m3) | EI-REV-Cerâmica 30x40 2, Massa (kg) | EI-REV-Cerâmica 30x40 2, Área de Componente Projetada (Líquida) (m2) = EI-REV-Cerâmica 30x40 2, Área de Componente Projetada (Bruta) (m2) | EI-REV-Cerâmica 30x40 2, Altura do Componente Retangular (m) | EI-REV-Cerâmica 30x40 2, Largura do Componente Retangular (m) = EI-REV-Cerâmica 10x10 Azul 2, Largura do Componente Retangular (m) | EI-REV-Cerâmica 30x40 2, Área de Seção Transversal do Componente (m2) | EI-REV-Cerâmica 30x40 2, Volume Componente (Líquido) (m3) = EI-REV-Cerâmica 30x40 2, Volume do componente (Bruto) (m3) | EI-REV-Cerâmica 10x10 Azul 2, Massa (kg) | EI-REV-Cerâmica 10x10 Azul 2, Área de Componente Projetada (Líquida) (m2) = EI-REV-Cerâmica 10x10 Azul 2, Área de Componente Projetada (Bruta) (m2) | EI-REV-Cerâmica 10x10 Azul 2, Altura do Componente Retangular (m) | EI-REV-Cerâmica 10x10 Azul 2, Área de Seção Transversal do Componente (m2) | EI-REV-Cerâmica 10x10 Azul 2, Volume Componente (Líquido) (m3) = EI-REV-Cerâmica 10x10 Azul 2, Volume do componente (Bruto) (m3) | EI-REV-Emboço Interno 1, Massa (kg) | EI-REV-Emboço Interno 1, Área de Componente Projetada (Líquida) (m2) = EI-REV-Emboço Interno 1, Área de Componente Projetada (Bruta) (m2) | EI-REV-Emboço Interno 1, Volume Componente (Líquido) (m3) = EI-REV-Emboço Interno 1, Volume do componente (Bruto) (m3) | EI-REV-Massa única - Maior que 10m² 1, Massa (kg) | EI-REV-Massa única - Maior que 10m² 1, Área de Componente Projetada (Líquida) (m2) = EI-REV-Massa única - Maior que 10m² 1, Área de Componente Projetada (Bruta) (m2) | EI-REV-Massa única - Maior que 10m² 1, Área de Seção Transversal do Componente (m2) | EI-REV-Massa única - Maior que 10m² 1, Volume Componente (Líquido) (m3) = EI-REV-Massa única - Maior que 10m² 1, Volume do componente (Bruto) (m3) | EI-REV-Massa Corrida PVA (interna) 1, Massa (kg) | EI-REV-Massa Corrida PVA (interna) 1, Área de Componente Projetada (Líquida) (m2) = EI-REV-Massa Corrida PVA (interna) 1, Área de Componente Projetada (Bruta) (m2) | EI-REV-Massa Corrida PVA (interna) 1, Largura do Componente Retangular (m) | EI-REV-Massa Corrida PVA (interna) 1, Área de Seção Transversal do Componente (m2) | EI-REV-Massa Corrida PVA (interna) 1, Volume Componente (Líquido) (m3) = EI-REV-Massa Corrida PVA (interna) 1, Volume do componente (Bruto) (m3) | EI-REV-Emboço Interno 2, Massa (kg) | EI-REV-Emboço Interno 2, Área de Componente Projetada (Líquida) (m2) = EI-REV-Emboço Interno 2, Área de Componente Projetada (Bruta) (m2) | EI-REV-Emboço Interno 2, Volume Componente (Líquido) (m3) = EI-REV-Emboço Interno 2, Volume do componente (Bruto) (m3) | EI-REV-Massa única - Maior que 10m² 2, Massa (kg) | EI-REV-Massa única - Maior que 10m² 2, Área de Componente Projetada (Líquida) (m2) = EI-REV-Massa única - Maior que 10m² 2, Área de Componente Projetada (Bruta) (m2) | EI-REV-Massa única - Maior que 10m² 2, Largura do Componente Retangular (m) | EI-REV-Massa única - Maior que 10m² 2, Área de Seção Transversal do Componente (m2) | EI-REV-Massa única - Maior que 10m² 2, Volume Componente (Líquido) (m3) = EI-REV-Massa única - Maior que 10m² 2, Volume do componente (Bruto) (m3) | EI-REV-Massa Corrida PVA (interna) 2, Massa (kg) | EI-REV-Massa Corrida PVA (interna) 2, Área de Componente Projetada (Líquida) (m2) = EI-REV-Massa Corrida PVA (interna) 2, Área de Componente Projetada (Bruta) (m2) | EI-REV-Massa Corrida PVA (interna) 2, Área de Seção Transversal do Componente (m2) | EI-REV-Massa Corrida PVA (interna) 2, Volume Componente (Líquido) (m3) = EI-REV-Massa Corrida PVA (interna) 2, Volume do componente (Bruto) (m3) | TIJOLO - CERAMICO 9x19x39 - espessura 15cm, Massa (kg) | TIJOLO - CERAMICO 9x19x39 - espessura 15cm, Área de Componente Projetada (Líquida) (m2) = TIJOLO - CERAMICO 9x19x39 - espessura 15cm, Área de Componente Projetada (Bruta) (m2) | TIJOLO - CERAMICO 9x19x39 - espessura 15cm, Volume Componente (Líquido) (m3) = TIJOLO - CERAMICO 9x19x39 - espessura 15cm, Volume do componente (Bruto) (m3)
AL09 | BLOCO B | 21.3566 | 3.28564 | 0.0164282 | 21.7019 | 3.33964 | 3.1 | 0.005 | 0.0155 | 0.0166938 | 16.1237 | 1.24029 | 1.17 | 0.00999999 | 0.0117 | 0.0124029 | 24.2774 | 1.86749 | 1.77 | 0.0177 | 0.0186749 | 76.6835 | 1.91709 | 1.8 | 0.036 | 0.0383418 | 4.26031 | 0.106508 | 0.00213016 | 50.6437 | 1.26609 | 1.2 | 0.02 | 0.024 | 0.0253219 | 4.22031 | 0.105508 | 0.1 | 0.002 | 0.00211016 | 21.3557 | 3.28549 | 0.0164274 | 8.06189 | 1.24029 | 0.00585001 | 0.00620145 | 8.06188 | 1.24029 | 0.005 | 0.00585001 | 0.00620145 | 21.6199 | 3.32614 | 0.0166307 | 12.2852 | 1.89004 | 0.00499998 | 0.00884996 | 0.00945014 | 12.2407 | 1.88319 | 0.00885001 | 0.00941594 | 191.623 | 3.28564 | 0.295714
AL09 | BLOCO B | 21.6038 | 3.32366 | 0.0166183 |  |  |  |  |  |  | 23.8434 | 1.83411 | 1.77 | 0.00999998 | 0.0177 | 0.0183411 | 23.8435 | 1.83411 | 1.77 | 0.0177 | 0.0183411 | 49.6837 | 1.24209 | 1.2 | 0.024 | 0.0248419 | 4.14031 | 0.103508 | 0.00207016 |  |  |  |  |  |  |  |  |  |  |  | 21.5151 | 3.31001 | 0.0165501 | 12.1824 | 1.87421 | 0.00885001 | 0.00937106 | 12.1379 | 1.86736 | 0.00500003 | 0.00885005 | 0.00933686 |  |  |  | 12.1823 | 1.87421 | 0.00499998 | 0.00884996 | 0.00937101 | 12.1379 | 1.86736 | 0.00885001 | 0.00933681 | 195.555 | 3.35314 | 0.301783 | Component Quantities - EI-REV-Chapisco (interno) 1: 2 with these values; EI-REV-Cerâmica 30x40 1: 2 with these values; EI-REV-Cerâmica 10x10 Azul 1: 2 with these values; EI-REV-Emboço Interno 1: 2 with these values
AL09 | BLOCO A | 17.9531 | 2.76201 | 0.01381 | 17.8653 | 2.74851 | 3.1 | 0.005 | 0.0155 | 0.0137425 | 13.2307 | 1.01775 | 1.17 | 0.00999999 | 0.0117 | 0.0101775 | 13.0567 | 1.01556 | 1.17 | 0.0117 | 0.0100436 | 64.072 | 1.6018 | 1.8 | 0.036 | 0.032036 | 3.56 | 0.089 | 0.00178 | 61.9218 | 1.584 | 1.8 | 0.02 | 0.036 | 0.0309609 | 3.4401 | 0.088 | 0.1 | 0.002 | 0.00172005 | 17.9511 | 2.76171 | 0.0138085 | 6.70513 | 1.03156 | 0.00585001 | 0.00515779 | 6.65508 | 1.02386 | 0.005 | 0.00585001 | 0.00511929 | 17.7766 | 2.73486 | 0.0136743 | 6.65505 | 1.02386 | 0.00499997 | 0.00584996 | 0.00511927 | 6.63006 | 1.02001 | 0.00585001 | 0.00510004 | 160.302 | 2.74866 | 0.247379

# IfcWall: FNDE-AL09-I5-I5 (azul-vermelha) 150 x 3100, AL09
In: TÉRREO
Classification: Parede (Classificação Archicad); Material: TIJOLO - CERAMICO 9x19x39 - espessura 15cm, EI-REV-Chapisco (interno) (2), EI-REV-Cerâmica 30x40 (2), EI-REV-Cerâmica 10x10 Vermelha, EI-REV-Emboço Interno (2), EI-REV-Massa única - Maior que 10m² (2), EI-REV-Massa Corrida PVA (interna) (2), EI-REV-Pintura Acrílica Cor Branco Gelo (2), EI-REV-Cerâmica 10x10 Azul
FNDE - Alvenarias: Alvenaria de Vedação / Edificação; Sistemas de Cobertura: -; Esquadrias - Fechamentos metálicos e Gradis: -; 1_Bloco: BLOCO A; 0_ID: AL09
Pset_WallCommon - IsExternal: no; LoadBearing: no
Component Quantities - TIJOLO - CERAMICO 9x19x39 - espessura 15cm, Massa: 360.551 kg; TIJOLO - CERAMICO 9x19x39 - espessura 15cm, Área de Componente Projetada (Líquida): 6.18229 m2; TIJOLO - CERAMICO 9x19x39 - espessura 15cm, Área de Componente Projetada (Bruta): 6.18229 m2; TIJOLO - CERAMICO 9x19x39 - espessura 15cm, Altura do Componente Retangular: 3.1 m; TIJOLO - CERAMICO 9x19x39 - espessura 15cm, Largura do Componente Retangular: 0.09 m; TIJOLO - CERAMICO 9x19x39 - espessura 15cm, Área de Seção Transversal do Componente: 0.279 m2; TIJOLO - CERAMICO 9x19x39 - espessura 15cm, Volume Componente (Líquido): 0.556406 m3; TIJOLO - CERAMICO 9x19x39 - espessura 15cm, Volume do componente (Bruto): 0.556406 m3; EI-REV-Chapisco (interno) 1, Massa: 40.0842 kg; EI-REV-Chapisco (interno) 1, Área de Componente Projetada (Líquida): 6.16679 m2; EI-REV-Chapisco (interno) 1, Área de Componente Projetada (Bruta): 6.16679 m2; EI-REV-Chapisco (interno) 1, Altura do Componente Retangular: 3.1 m; EI-REV-Chapisco (interno) 1, Largura do Componente Retangular: 0.005 m; EI-REV-Chapisco (interno) 1, Área de Seção Transversal do Componente: 0.0155 m2; EI-REV-Chapisco (interno) 1, Volume Componente (Líquido): 0.030834 m3; EI-REV-Chapisco (interno) 1, Volume do componente (Bruto): 0.030834 m3; EI-REV-Cerâmica 30x40 1, Massa: 140.444 kg; EI-REV-Cerâmica 30x40 1, Área de Componente Projetada (Líquida): 3.51111 m2; EI-REV-Cerâmica 30x40 1, Área de Componente Projetada (Bruta): 3.51111 m2; EI-REV-Cerâmica 30x40 1, Altura do Componente Retangular: 1.8 m; EI-REV-Cerâmica 30x40 1, Largura do Componente Retangular: 0.02 m; EI-REV-Cerâmica 30x40 1, Área de Seção Transversal do Componente: 0.036 m2; EI-REV-Cerâmica 30x40 1, Volume Componente (Líquido): 0.0702221 m3; EI-REV-Cerâmica 30x40 1, Volume do componente (Bruto): 0.0702221 m3; EI-REV-Cerâmica 10x10 Vermelha, Massa: 7.80246 kg; EI-REV-Cerâmica 10x10 Vermelha, Área de Componente Projetada (Líquida): 0.195061 m2; EI-REV-Cerâmica 10x10 Vermelha, Área de Componente Projetada (Bruta): 0.195061 m2; EI-REV-Cerâmica 10x10 Vermelha, Altura do Componente Retangular: 0.1 m; EI-REV-Cerâmica 10x10 Vermelha, Largura do Componente Retangular: 0.02 m; EI-REV-Cerâmica 10x10 Vermelha, Área de Seção Transversal do Componente: 0.002 m2; EI-REV-Cerâmica 10x10 Vermelha, Volume Componente (Líquido): 0.00390123 m3; EI-REV-Cerâmica 10x10 Vermelha, Volume do componente (Bruto): 0.00390123 m3; EI-REV-Emboço Interno 1, Massa: 39.9834 kg; EI-REV-Emboço Interno 1, Área de Componente Projetada (Líquida): 6.15129 m2; EI-REV-Emboço Interno 1, Área de Componente Projetada (Bruta): 6.15129 m2; EI-REV-Emboço Interno 1, Altura do Componente Retangular: 3.1 m; EI-REV-Emboço Interno 1, Largura do Componente Retangular: 0.005 m; EI-REV-Emboço Interno 1, Área de Seção Transversal do Componente: 0.0155 m2; EI-REV-Emboço Interno 1, Volume Componente (Líquido): 0.0307565 m3; EI-REV-Emboço Interno 1, Volume do componente (Bruto): 0.0307565 m3; EI-REV-Massa única - Maior que 10m² 1, Massa: 15.0363 kg; EI-REV-Massa única - Maior que 10m² 1, Área de Componente Projetada (Líquida): 2.31328 m2; EI-REV-Massa única - Maior que 10m² 1, Área de Componente Projetada (Bruta): 2.31328 m2; EI-REV-Massa única - Maior que 10m² 1, Altura do Componente Retangular: 1.17 m; EI-REV-Massa única - Maior que 10m² 1, Largura do Componente Retangular: 0.005 m; EI-REV-Massa única - Maior que 10m² 1, Área de Seção Transversal do Componente: 0.00585001 m2; EI-REV-Massa única - Maior que 10m² 1, Volume Componente (Líquido): 0.0115664 m3; EI-REV-Massa única - Maior que 10m² 1, Volume do componente (Bruto): 0.0115664 m3; EI-REV-Massa Corrida PVA (interna) 1, Massa: 14.9734 kg; EI-REV-Massa Corrida PVA (interna) 1, Área de Componente Projetada (Líquida): 2.3036 m2; EI-REV-Massa Corrida PVA (interna) 1, Área de Componente Projetada (Bruta): 2.3036 m2; EI-REV-Massa Corrida PVA (interna) 1, Altura do Componente Retangular: 1.17 m; EI-REV-Massa Corrida PVA (interna) 1, Largura do Componente Retangular: 0.005 m; EI-REV-Massa Corrida PVA (interna) 1, Área de Seção Transversal do Componente: 0.00585001 m2; EI-REV-Massa Corrida PVA (interna) 1, Volume Componente (Líquido): 0.011518 m3; EI-REV-Massa Corrida PVA (interna) 1, Volume do componente (Bruto): 0.011518 m3; EI-REV-Pintura Acrílica Cor Branco Gelo 1, Massa: 29.6688 kg; EI-REV-Pintura Acrílica Cor Branco Gelo 1, Área de Componente Projetada (Líquida): 2.28222 m2; EI-REV-Pintura Acrílica Cor Branco Gelo 1, Área de Componente Projetada (Bruta): 2.28222 m2; EI-REV-Pintura Acrílica Cor Branco Gelo 1, Altura do Componente Retangular: 1.17 m; EI-REV-Pintura Acrílica Cor Branco Gelo 1, Largura do Componente Retangular: 0.00999999 m; EI-REV-Pintura Acrílica Cor Branco Gelo 1, Área de Seção Transversal do Componente: 0.0117 m2; EI-REV-Pintura Acrílica Cor Branco Gelo 1, Volume Componente (Líquido): 0.0228222 m3; EI-REV-Pintura Acrílica Cor Branco Gelo 1, Volume do componente (Bruto): 0.0228222 m3; EI-REV-Massa única - Maior que 10m² 2, Massa: 15.0362 kg; EI-REV-Massa única - Maior que 10m² 2, Área de Componente Projetada (Líquida): 2.31328 m2; EI-REV-Massa única - Maior que 10m² 2, Área de Componente Projetada (Bruta): 2.31328 m2; EI-REV-Massa única - Maior que 10m² 2, Altura do Componente Retangular: 1.17 m; EI-REV-Massa única - Maior que 10m² 2, Largura do Componente Retangular: 0.00499997 m; EI-REV-Massa única - Maior que 10m² 2, Área de Seção Transversal do Componente: 0.00584996 m2; EI-REV-Massa única - Maior que 10m² 2, Volume Componente (Líquido): 0.0115663 m3; EI-REV-Massa única - Maior que 10m² 2, Volume do componente (Bruto): 0.0115663 m3; EI-REV-Pintura Acrílica Cor Branco Gelo 2, Massa: 29.6689 kg; EI-REV-Pintura Acrílica Cor Branco Gelo 2, Área de Componente Projetada (Líquida): 2.28222 m2; EI-REV-Pintura Acrílica Cor Branco Gelo 2, Área de Componente Projetada (Bruta): 2.28222 m2; EI-REV-Pintura Acrílica Cor Branco Gelo 2, Altura do Componente Retangular: 1.17 m; EI-REV-Pintura Acrílica Cor Branco Gelo 2, Largura do Componente Retangular: 0.01 m; EI-REV-Pintura Acrílica Cor Branco Gelo 2, Área de Seção Transversal do Componente: 0.0117 m2; EI-REV-Pintura Acrílica Cor Branco Gelo 2, Volume Componente (Líquido): 0.0228222 m3; EI-REV-Pintura Acrílica Cor Branco Gelo 2, Volume do componente (Bruto): 0.0228222 m3; EI-REV-Chapisco (interno) 1: 2 with these values; EI-REV-Cerâmica 30x40 1: 2 with these values; EI-REV-Cerâmica 10x10 Vermelha: 2 with these values; EI-REV-Emboço Interno 1: 2 with these values; EI-REV-Massa Corrida PVA (interna) 1: 2 with these values

# IfcWall: FNDE-AL09-I5-I5 (vermelho) 150 x 1930, AL09
In: TÉRREO
Classification: Parede (Classificação Archicad); Material: TIJOLO - CERAMICO 9x19x39 - espessura 15cm, EI-REV-Chapisco (interno) (2), EI-REV-Cerâmica 30x40 (2), EI-REV-Cerâmica 10x10 Vermelha (2), EI-REV-Emboço Interno (2)
FNDE - Alvenarias: Mureta; Sistemas de Cobertura: -; Esquadrias - Fechamentos metálicos e Gradis: -; 1_Bloco: BLOCO B; 0_ID: AL09
Pset_WallCommon - IsExternal: no; LoadBearing: no
Component Quantities - TIJOLO - CERAMICO 9x19x39 - espessura 15cm, Massa: 79.3314 kg; TIJOLO - CERAMICO 9x19x39 - espessura 15cm, Área de Componente Projetada (Líquida): 1.36024 m2; TIJOLO - CERAMICO 9x19x39 - espessura 15cm, Área de Componente Projetada (Bruta): 1.36024 m2; TIJOLO - CERAMICO 9x19x39 - espessura 15cm, Altura do Componente Retangular: 1.93 m; TIJOLO - CERAMICO 9x19x39 - espessura 15cm, Largura do Componente Retangular: 0.09 m; TIJOLO - CERAMICO 9x19x39 - espessura 15cm, Área de Seção Transversal do Componente: 0.1737 m2; TIJOLO - CERAMICO 9x19x39 - espessura 15cm, Volume Componente (Líquido): 0.122425 m3; TIJOLO - CERAMICO 9x19x39 - espessura 15cm, Volume do componente (Bruto): 0.122425 m3; EI-REV-Chapisco (interno) 1, Massa: 8.66716 kg; EI-REV-Chapisco (interno) 1, Área de Componente Projetada (Líquida): 1.33341 m2; EI-REV-Chapisco (interno) 1, Área de Componente Projetada (Bruta): 1.33341 m2; EI-REV-Chapisco (interno) 1, Altura do Componente Retangular: 1.93 m; EI-REV-Chapisco (interno) 1, Largura do Componente Retangular: 0.005 m; EI-REV-Chapisco (interno) 1, Área de Seção Transversal do Componente: 0.00965 m2; EI-REV-Chapisco (interno) 1, Volume Componente (Líquido): 0.00666705 m3; EI-REV-Chapisco (interno) 1, Volume do componente (Bruto): 0.00666705 m3; EI-REV-Cerâmica 30x40 1, Massa: 48.96 kg; EI-REV-Cerâmica 30x40 1, Área de Componente Projetada (Líquida): 1.224 m2; EI-REV-Cerâmica 30x40 1, Área de Componente Projetada (Bruta): 1.224 m2; EI-REV-Cerâmica 30x40 1, Altura do Componente Retangular: 1.8 m; EI-REV-Cerâmica 30x40 1, Largura do Componente Retangular: 0.02 m; EI-REV-Cerâmica 30x40 1, Área de Seção Transversal do Componente: 0.036 m2; EI-REV-Cerâmica 30x40 1, Volume Componente (Líquido): 0.02448 m3; EI-REV-Cerâmica 30x40 1, Volume do componente (Bruto): 0.02448 m3; EI-REV-Cerâmica 10x10 Vermelha 1, Massa: 2.47592 kg; EI-REV-Cerâmica 10x10 Vermelha 1, Área de Componente Projetada (Líquida): 0.061898 m2; EI-REV-Cerâmica 10x10 Vermelha 1, Área de Componente Projetada (Bruta): 0.061898 m2; EI-REV-Cerâmica 10x10 Vermelha 1, Altura do Componente Retangular: 0.1 m; EI-REV-Cerâmica 10x10 Vermelha 1, Largura do Componente Retangular: 0.02 m; EI-REV-Cerâmica 10x10 Vermelha 1, Área de Seção Transversal do Componente: 0.002 m2; EI-REV-Cerâmica 10x10 Vermelha 1, Volume Componente (Líquido): 0.00123796 m3; EI-REV-Cerâmica 10x10 Vermelha 1, Volume do componente (Bruto): 0.00123796 m3; EI-REV-Chapisco (interno) 2, Massa: 8.97855 kg; EI-REV-Chapisco (interno) 2, Área de Componente Projetada (Líquida): 1.38132 m2; EI-REV-Chapisco (interno) 2, Área de Componente Projetada (Bruta): 1.38132 m2; EI-REV-Chapisco (interno) 2, Altura do Componente Retangular: 1.93 m; EI-REV-Chapisco (interno) 2, Largura do Componente Retangular: 0.005 m; EI-REV-Chapisco (interno) 2, Área de Seção Transversal do Componente: 0.00965 m2; EI-REV-Chapisco (interno) 2, Volume Componente (Líquido): 0.00690658 m3; EI-REV-Chapisco (interno) 2, Volume do componente (Bruto): 0.00690658 m3; EI-REV-Cerâmica 30x40 2, Massa: 52.752 kg; EI-REV-Cerâmica 30x40 2, Área de Componente Projetada (Líquida): 1.3188 m2; EI-REV-Cerâmica 30x40 2, Área de Componente Projetada (Bruta): 1.3188 m2; EI-REV-Cerâmica 30x40 2, Altura do Componente Retangular: 1.8 m; EI-REV-Cerâmica 30x40 2, Largura do Componente Retangular: 0.02 m; EI-REV-Cerâmica 30x40 2, Área de Seção Transversal do Componente: 0.036 m2; EI-REV-Cerâmica 30x40 2, Volume Componente (Líquido): 0.026376 m3; EI-REV-Cerâmica 30x40 2, Volume do componente (Bruto): 0.026376 m3; EI-REV-Cerâmica 10x10 Vermelha 2, Massa: 2.74033 kg; EI-REV-Cerâmica 10x10 Vermelha 2, Área de Componente Projetada (Líquida): 0.074 m2; EI-REV-Cerâmica 10x10 Vermelha 2, Área de Componente Projetada (Bruta): 0.074 m2; EI-REV-Cerâmica 10x10 Vermelha 2, Altura do Componente Retangular: 0.1 m; EI-REV-Cerâmica 10x10 Vermelha 2, Largura do Componente Retangular: 0.02 m; EI-REV-Cerâmica 10x10 Vermelha 2, Área de Seção Transversal do Componente: 0.002 m2; EI-REV-Cerâmica 10x10 Vermelha 2, Volume Componente (Líquido): 0.00137016 m3; EI-REV-Cerâmica 10x10 Vermelha 2, Volume do componente (Bruto): 0.00137016 m3; EI-REV-Emboço Interno 2, Massa: 8.99707 kg; EI-REV-Emboço Interno 2, Área de Componente Projetada (Líquida): 1.38417 m2; EI-REV-Emboço Interno 2, Área de Componente Projetada (Bruta): 1.38417 m2; EI-REV-Emboço Interno 2, Altura do Componente Retangular: 1.93 m; EI-REV-Emboço Interno 2, Largura do Componente Retangular: 0.005 m; EI-REV-Emboço Interno 2, Área de Seção Transversal do Componente: 0.00965 m2; EI-REV-Emboço Interno 2, Volume Componente (Líquido): 0.00692083 m3; EI-REV-Emboço Interno 2, Volume do componente (Bruto): 0.00692083 m3; EI-REV-Chapisco (interno) 1: 2 with these values

# IfcWall: FNDE-AL09-I5-I5 (vermelho) 150 x 3100 (2)
In: TÉRREO
Classification: Parede (Classificação Archicad); Material: TIJOLO - CERAMICO 9x19x39 - espessura 15cm, EI-REV-Chapisco (interno) (2), EI-REV-Cerâmica 30x40 (2), EI-REV-Cerâmica 10x10 Vermelha (2), EI-REV-Emboço Interno (2), EI-REV-Massa única - Maior que 10m² (2), EI-REV-Massa Corrida PVA (interna) (2), EI-REV-Pintura Acrílica Cor Branco Gelo (2)
FNDE - Alvenarias: Alvenaria de Vedação / Edificação; Sistemas de Cobertura: -; Esquadrias - Fechamentos metálicos e Gradis: -; 1_Bloco: BLOCO B; 0_ID: AL09
Pset_WallCommon - IsExternal: no; LoadBearing: no
Component Quantities - TIJOLO - CERAMICO 9x19x39 - espessura 15cm, Altura do Componente Retangular: 3.1 m; TIJOLO - CERAMICO 9x19x39 - espessura 15cm, Largura do Componente Retangular: 0.09 m; TIJOLO - CERAMICO 9x19x39 - espessura 15cm, Área de Seção Transversal do Componente: 0.279 m2; EI-REV-Chapisco (interno) 1, Altura do Componente Retangular: 3.1 m; EI-REV-Chapisco (interno) 1, Largura do Componente Retangular: 0.005 m; EI-REV-Chapisco (interno) 1, Área de Seção Transversal do Componente: 0.0155 m2; EI-REV-Cerâmica 30x40 1, Largura do Componente Retangular: 0.02 m; EI-REV-Cerâmica 10x10 Vermelha 1, Altura do Componente Retangular: 0.1 m; EI-REV-Cerâmica 10x10 Vermelha 1, Largura do Componente Retangular: 0.02 m; EI-REV-Cerâmica 10x10 Vermelha 1, Área de Seção Transversal do Componente: 0.002 m2; EI-REV-Emboço Interno 1, Altura do Componente Retangular: 3.1 m; EI-REV-Emboço Interno 1, Largura do Componente Retangular: 0.005 m; EI-REV-Emboço Interno 1, Área de Seção Transversal do Componente: 0.0155 m2; EI-REV-Massa única - Maior que 10m² 1, Largura do Componente Retangular: 0.005 m; EI-REV-Chapisco (interno) 2, Altura do Componente Retangular: 3.1 m; EI-REV-Chapisco (interno) 2, Largura do Componente Retangular: 0.005 m; EI-REV-Chapisco (interno) 2, Área de Seção Transversal do Componente: 0.0155 m2; EI-REV-Cerâmica 30x40 2, Altura do Componente Retangular: 1.2 m; EI-REV-Cerâmica 30x40 2, Largura do Componente Retangular: 0.02 m; EI-REV-Cerâmica 30x40 2, Área de Seção Transversal do Componente: 0.024 m2; EI-REV-Emboço Interno 2, Altura do Componente Retangular: 3.1 m; EI-REV-Emboço Interno 2, Largura do Componente Retangular: 0.005 m; EI-REV-Emboço Interno 2, Área de Seção Transversal do Componente: 0.0155 m2; EI-REV-Massa única - Maior que 10m² 2, Altura do Componente Retangular: 1.77 m; EI-REV-Massa única - Maior que 10m² 2, Largura do Componente Retangular: 0.00499998 m; EI-REV-Massa única - Maior que 10m² 2, Área de Seção Transversal do Componente: 0.00884996 m2; EI-REV-Massa Corrida PVA (interna) 2, Altura do Componente Retangular: 1.77 m; EI-REV-Massa Corrida PVA (interna) 2, Largura do Componente Retangular: 0.005 m; EI-REV-Massa Corrida PVA (interna) 2, Área de Seção Transversal do Componente: 0.00885001 m2; EI-REV-Pintura Acrílica Cor Branco Gelo 2, Altura do Componente Retangular: 1.77 m; EI-REV-Pintura Acrílica Cor Branco Gelo 2, Largura do Componente Retangular: 0.01 m; EI-REV-Pintura Acrílica Cor Branco Gelo 2, Área de Seção Transversal do Componente: 0.0177 m2
Name | TIJOLO - CERAMICO 9x19x39 - espessura 15cm, Massa (kg) | TIJOLO - CERAMICO 9x19x39 - espessura 15cm, Área de Componente Projetada (Líquida) (m2) = TIJOLO - CERAMICO 9x19x39 - espessura 15cm, Área de Componente Projetada (Bruta) (m2) | TIJOLO - CERAMICO 9x19x39 - espessura 15cm, Volume Componente (Líquido) (m3) = TIJOLO - CERAMICO 9x19x39 - espessura 15cm, Volume do componente (Bruto) (m3) | EI-REV-Chapisco (interno) 1, Massa (kg) | EI-REV-Chapisco (interno) 1, Área de Componente Projetada (Líquida) (m2) = EI-REV-Chapisco (interno) 1, Área de Componente Projetada (Bruta) (m2) | EI-REV-Chapisco (interno) 1, Volume Componente (Líquido) (m3) = EI-REV-Chapisco (interno) 1, Volume do componente (Bruto) (m3) | EI-REV-Cerâmica 30x40 1, Massa (kg) | EI-REV-Cerâmica 30x40 1, Área de Componente Projetada (Líquida) (m2) = EI-REV-Cerâmica 30x40 1, Área de Componente Projetada (Bruta) (m2) | EI-REV-Cerâmica 30x40 1, Altura do Componente Retangular (m) | EI-REV-Cerâmica 30x40 1, Área de Seção Transversal do Componente (m2) | EI-REV-Cerâmica 30x40 1, Volume Componente (Líquido) (m3) = EI-REV-Cerâmica 30x40 1, Volume do componente (Bruto) (m3) | EI-REV-Cerâmica 10x10 Vermelha 1, Massa (kg) | EI-REV-Cerâmica 10x10 Vermelha 1, Área de Componente Projetada (Líquida) (m2) = EI-REV-Cerâmica 10x10 Vermelha 1, Área de Componente Projetada (Bruta) (m2) | EI-REV-Cerâmica 10x10 Vermelha 1, Volume Componente (Líquido) (m3) = EI-REV-Cerâmica 10x10 Vermelha 1, Volume do componente (Bruto) (m3) | EI-REV-Emboço Interno 1, Massa (kg) | EI-REV-Emboço Interno 1, Área de Componente Projetada (Líquida) (m2) = EI-REV-Emboço Interno 1, Área de Componente Projetada (Bruta) (m2) | EI-REV-Emboço Interno 1, Volume Componente (Líquido) (m3) = EI-REV-Emboço Interno 1, Volume do componente (Bruto) (m3) | EI-REV-Massa única - Maior que 10m² 1, Massa (kg) | EI-REV-Massa única - Maior que 10m² 1, Área de Componente Projetada (Líquida) (m2) = EI-REV-Massa única - Maior que 10m² 1, Área de Componente Projetada (Bruta) (m2) | EI-REV-Massa única - Maior que 10m² 1, Altura do Componente Retangular (m) = EI-REV-Pintura Acrílica Cor Branco Gelo 1, Altura do Componente Retangular (m) | EI-REV-Massa única - Maior que 10m² 1, Área de Seção Transversal do Componente (m2) | EI-REV-Massa única - Maior que 10m² 1, Volume Componente (Líquido) (m3) = EI-REV-Massa única - Maior que 10m² 1, Volume do componente (Bruto) (m3) | EI-REV-Pintura Acrílica Cor Branco Gelo 1, Massa (kg) | EI-REV-Pintura Acrílica Cor Branco Gelo 1, Área de Componente Projetada (Líquida) (m2) = EI-REV-Pintura Acrílica Cor Branco Gelo 1, Área de Componente Projetada (Bruta) (m2) | EI-REV-Pintura Acrílica Cor Branco Gelo 1, Largura do Componente Retangular (m) | EI-REV-Pintura Acrílica Cor Branco Gelo 1, Área de Seção Transversal do Componente (m2) | EI-REV-Pintura Acrílica Cor Branco Gelo 1, Volume Componente (Líquido) (m3) = EI-REV-Pintura Acrílica Cor Branco Gelo 1, Volume do componente (Bruto) (m3) | EI-REV-Chapisco (interno) 2, Massa (kg) | EI-REV-Chapisco (interno) 2, Área de Componente Projetada (Líquida) (m2) = EI-REV-Chapisco (interno) 2, Área de Componente Projetada (Bruta) (m2) | EI-REV-Chapisco (interno) 2, Volume Componente (Líquido) (m3) = EI-REV-Chapisco (interno) 2, Volume do componente (Bruto) (m3) | EI-REV-Cerâmica 30x40 2, Massa (kg) | EI-REV-Cerâmica 30x40 2, Área de Componente Projetada (Líquida) (m2) = EI-REV-Cerâmica 30x40 2, Área de Componente Projetada (Bruta) (m2) | EI-REV-Cerâmica 30x40 2, Volume Componente (Líquido) (m3) = EI-REV-Cerâmica 30x40 2, Volume do componente (Bruto) (m3) | EI-REV-Emboço Interno 2, Massa (kg) | EI-REV-Emboço Interno 2, Área de Componente Projetada (Líquida) (m2) = EI-REV-Emboço Interno 2, Área de Componente Projetada (Bruta) (m2) | EI-REV-Emboço Interno 2, Volume Componente (Líquido) (m3) = EI-REV-Emboço Interno 2, Volume do componente (Bruto) (m3) | EI-REV-Massa única - Maior que 10m² 2, Massa (kg) | EI-REV-Massa única - Maior que 10m² 2, Área de Componente Projetada (Líquida) (m2) = EI-REV-Massa única - Maior que 10m² 2, Área de Componente Projetada (Bruta) (m2) | EI-REV-Massa única - Maior que 10m² 2, Volume Componente (Líquido) (m3) = EI-REV-Massa única - Maior que 10m² 2, Volume do componente (Bruto) (m3) | EI-REV-Massa Corrida PVA (interna) 2, Massa (kg) | EI-REV-Massa Corrida PVA (interna) 2, Área de Componente Projetada (Líquida) (m2) = EI-REV-Massa Corrida PVA (interna) 2, Área de Componente Projetada (Bruta) (m2) | EI-REV-Massa Corrida PVA (interna) 2, Volume Componente (Líquido) (m3) = EI-REV-Massa Corrida PVA (interna) 2, Volume do componente (Bruto) (m3) | EI-REV-Pintura Acrílica Cor Branco Gelo 2, Massa (kg) | EI-REV-Pintura Acrílica Cor Branco Gelo 2, Área de Componente Projetada (Líquida) (m2) = EI-REV-Pintura Acrílica Cor Branco Gelo 2, Área de Componente Projetada (Bruta) (m2) | EI-REV-Pintura Acrílica Cor Branco Gelo 2, Volume Componente (Líquido) (m3) = EI-REV-Pintura Acrílica Cor Branco Gelo 2, Volume do componente (Bruto) (m3)
AL09 | 191.617 | 3.28554 | 0.295705 | 21.356 | 3.28554 | 0.0164277 | 75.9704 | 1.89926 | 1.8 | 0.036 | 0.0379852 | 4.22058 | 0.105514 | 0.00211029 | 21.355 | 3.28539 | 0.0164269 | 8.06164 | 1.24025 | 1.17 | 0.00585001 | 0.00620126 | 16.0487 | 1.23452 | 0.00999999 | 0.0117 | 0.0123452 | 21.701 | 3.33981 | 0.0166931 | 50.6469 | 1.26617 | 0.0253235 | 21.621 | 3.32631 | 0.0166315 | 12.2857 | 1.89012 | 0.00945053 | 12.2412 | 1.88327 | 0.00941633 | 24.2789 | 1.86761 | 0.0186761 | Component Quantities - EI-REV-Cerâmica 10x10 Vermelha 1: 2 with these values; EI-REV-Massa única - Maior que 10m² 1: 2 with these values
AL09 | 195.555 | 3.35313 | 0.301782 | 21.7944 | 3.35298 | 0.0167649 | 52.0759 | 1.30189 | 1.2 | 0.024 | 0.0260379 | 4.34032 | 0.108508 | 0.00217016 | 21.7924 | 3.35268 | 0.0167634 | 12.3742 | 1.90373 | 1.77 | 0.00885001 | 0.00951864 | 24.2513 | 1.86548 | 0.00999998 | 0.0177 | 0.0186549 | 21.7066 | 3.33948 | 0.0166974 | 49.6837 | 1.24209 | 0.0248419 | 21.6179 | 3.32583 | 0.0166292 | 12.2851 | 1.89003 | 0.00945009 | 12.2407 | 1.88318 | 0.00941589 | 24.0473 | 1.84979 | 0.0184979 | Component Quantities - EI-REV-Massa Corrida PVA (interna) 1, Massa: 12.3298 kg; EI-REV-Massa Corrida PVA (interna) 1, Área de Componente Projetada (Líquida): 1.89688 m2; EI-REV-Massa Corrida PVA (interna) 1, Área de Componente Projetada (Bruta): 1.89688 m2; EI-REV-Massa Corrida PVA (interna) 1, Altura do Componente Retangular: 1.77 m; EI-REV-Massa Corrida PVA (interna) 1, Largura do Componente Retangular: 0.00500003 m; EI-REV-Massa Corrida PVA (interna) 1, Área de Seção Transversal do Componente: 0.00885005 m2; EI-REV-Massa Corrida PVA (interna) 1, Volume Componente (Líquido): 0.00948443 m3; EI-REV-Massa Corrida PVA (interna) 1, Volume do componente (Bruto): 0.00948443 m3; EI-REV-Cerâmica 10x10 Vermelha 2, Massa: 4.14031 kg; EI-REV-Cerâmica 10x10 Vermelha 2, Área de Componente Projetada (Líquida): 0.103508 m2; EI-REV-Cerâmica 10x10 Vermelha 2, Área de Componente Projetada (Bruta): 0.103508 m2; EI-REV-Cerâmica 10x10 Vermelha 2, Altura do Componente Retangular: 0.1 m; EI-REV-Cerâmica 10x10 Vermelha 2, Largura do Componente Retangular: 0.02 m; EI-REV-Cerâmica 10x10 Vermelha 2, Área de Seção Transversal do Componente: 0.002 m2; EI-REV-Cerâmica 10x10 Vermelha 2, Volume Componente (Líquido): 0.00207016 m3; EI-REV-Cerâmica 10x10 Vermelha 2, Volume do componente (Bruto): 0.00207016 m3

# IfcWall: FNDE-AL09-I5-I6 (vermelho-30x40) 150 x 3100, AL09
In: TÉRREO
Classification: Parede (Classificação Archicad); Material: TIJOLO - CERAMICO 9x19x39 - espessura 15cm, EI-REV-Chapisco (interno) (2), EI-REV-Cerâmica 30x40 h=1,50, EI-REV-Emboço Interno (2), EI-REV-Massa única - Maior que 10m² (2), EI-REV-Massa Corrida PVA (interna) (2), EI-REV-Pintura Acrílica Cor Branco Gelo (2), EI-REV-Cerâmica 30x40, EI-REV-Cerâmica 10x10 Vermelha
FNDE - Alvenarias: Alvenaria de Vedação / Edificação; Sistemas de Cobertura: -; Esquadrias - Fechamentos metálicos e Gradis: -; 1_Bloco: BLOCO A; 0_ID: AL09
Pset_WallCommon - IsExternal: no; LoadBearing: no
Component Quantities - TIJOLO - CERAMICO 9x19x39 - espessura 15cm, Massa: 92.8073 kg; TIJOLO - CERAMICO 9x19x39 - espessura 15cm, Área de Componente Projetada (Líquida): 1.59135 m2; TIJOLO - CERAMICO 9x19x39 - espessura 15cm, Área de Componente Projetada (Bruta): 1.59135 m2; TIJOLO - CERAMICO 9x19x39 - espessura 15cm, Altura do Componente Retangular: 3.1 m; TIJOLO - CERAMICO 9x19x39 - espessura 15cm, Largura do Componente Retangular: 0.09 m; TIJOLO - CERAMICO 9x19x39 - espessura 15cm, Área de Seção Transversal do Componente: 0.279 m2; TIJOLO - CERAMICO 9x19x39 - espessura 15cm, Volume Componente (Líquido): 0.143221 m3; TIJOLO - CERAMICO 9x19x39 - espessura 15cm, Volume do componente (Bruto): 0.143221 m3; EI-REV-Chapisco (interno) 1, Massa: 10.3438 kg; EI-REV-Chapisco (interno) 1, Área de Componente Projetada (Líquida): 1.59135 m2; EI-REV-Chapisco (interno) 1, Área de Componente Projetada (Bruta): 1.59135 m2; EI-REV-Chapisco (interno) 1, Altura do Componente Retangular: 3.1 m; EI-REV-Chapisco (interno) 1, Largura do Componente Retangular: 0.005 m; EI-REV-Chapisco (interno) 1, Área de Seção Transversal do Componente: 0.0155 m2; EI-REV-Chapisco (interno) 1, Volume Componente (Líquido): 0.00795673 m3; EI-REV-Chapisco (interno) 1, Volume do componente (Bruto): 0.00795673 m3; EI-REV-Cerâmica 30x40 h=1,50, Massa: 35.3633 kg; EI-REV-Cerâmica 30x40 h=1,50, Área de Componente Projetada (Líquida): 0.884082 m2; EI-REV-Cerâmica 30x40 h=1,50, Área de Componente Projetada (Bruta): 0.884082 m2; EI-REV-Cerâmica 30x40 h=1,50, Altura do Componente Retangular: 1.5 m; EI-REV-Cerâmica 30x40 h=1,50, Largura do Componente Retangular: 0.02 m; EI-REV-Cerâmica 30x40 h=1,50, Área de Seção Transversal do Componente: 0.03 m2; EI-REV-Cerâmica 30x40 h=1,50, Volume Componente (Líquido): 0.0176816 m3; EI-REV-Cerâmica 30x40 h=1,50, Volume do componente (Bruto): 0.0176816 m3; EI-REV-Massa única - Maior que 10m² 1, Massa: 4.59722 kg; EI-REV-Massa única - Maior que 10m² 1, Área de Componente Projetada (Líquida): 0.707265 m2; EI-REV-Massa única - Maior que 10m² 1, Área de Componente Projetada (Bruta): 0.707265 m2; EI-REV-Massa única - Maior que 10m² 1, Altura do Componente Retangular: 1.6 m; EI-REV-Massa única - Maior que 10m² 1, Largura do Componente Retangular: 0.005 m; EI-REV-Massa única - Maior que 10m² 1, Área de Seção Transversal do Componente: 0.008 m2; EI-REV-Massa única - Maior que 10m² 1, Volume Componente (Líquido): 0.00353633 m3; EI-REV-Massa única - Maior que 10m² 1, Volume do componente (Bruto): 0.00353633 m3; EI-REV-Massa Corrida PVA (interna) 1, Massa: 4.59689 kg; EI-REV-Massa Corrida PVA (interna) 1, Área de Componente Projetada (Líquida): 0.707213 m2; EI-REV-Massa Corrida PVA (interna) 1, Área de Componente Projetada (Bruta): 0.707213 m2; EI-REV-Massa Corrida PVA (interna) 1, Altura do Componente Retangular: 1.6 m; EI-REV-Massa Corrida PVA (interna) 1, Largura do Componente Retangular: 0.005 m; EI-REV-Massa Corrida PVA (interna) 1, Área de Seção Transversal do Componente: 0.008 m2; EI-REV-Massa Corrida PVA (interna) 1, Volume Componente (Líquido): 0.00353607 m3; EI-REV-Massa Corrida PVA (interna) 1, Volume do componente (Bruto): 0.00353607 m3; EI-REV-Pintura Acrílica Cor Branco Gelo 1, Massa: 10.444 kg; EI-REV-Pintura Acrílica Cor Branco Gelo 1, Área de Componente Projetada (Líquida): 0.918951 m2; EI-REV-Pintura Acrílica Cor Branco Gelo 1, Área de Componente Projetada (Bruta): 0.918951 m2; EI-REV-Pintura Acrílica Cor Branco Gelo 1, Altura do Componente Retangular: 1.6 m; EI-REV-Pintura Acrílica Cor Branco Gelo 1, Largura do Componente Retangular: 0.01 m; EI-REV-Pintura Acrílica Cor Branco Gelo 1, Área de Seção Transversal do Componente: 0.016 m2; EI-REV-Pintura Acrílica Cor Branco Gelo 1, Volume Componente (Líquido): 0.00803388 m3; EI-REV-Pintura Acrílica Cor Branco Gelo 1, Volume do componente (Bruto): 0.00803388 m3; EI-REV-Chapisco (interno) 2, Massa: 9.55398 kg; EI-REV-Chapisco (interno) 2, Área de Componente Projetada (Líquida): 1.46985 m2; EI-REV-Chapisco (interno) 2, Área de Componente Projetada (Bruta): 1.46985 m2; EI-REV-Chapisco (interno) 2, Altura do Componente Retangular: 3.1 m; EI-REV-Chapisco (interno) 2, Largura do Componente Retangular: 0.005 m; EI-REV-Chapisco (interno) 2, Área de Seção Transversal do Componente: 0.0155 m2; EI-REV-Chapisco (interno) 2, Volume Componente (Líquido): 0.00734922 m3; EI-REV-Chapisco (interno) 2, Volume do componente (Bruto): 0.00734922 m3; EI-REV-Cerâmica 30x40, Massa: 48.7513 kg; EI-REV-Cerâmica 30x40, Área de Componente Projetada (Líquida): 1.29482 m2; EI-REV-Cerâmica 30x40, Área de Componente Projetada (Bruta): 1.29482 m2; EI-REV-Cerâmica 30x40, Altura do Componente Retangular: 1.8 m; EI-REV-Cerâmica 30x40, Largura do Componente Retangular: 0.02 m; EI-REV-Cerâmica 30x40, Área de Seção Transversal do Componente: 0.036 m2; EI-REV-Cerâmica 30x40, Volume Componente (Líquido): 0.0243757 m3; EI-REV-Cerâmica 30x40, Volume do componente (Bruto): 0.0243757 m3; EI-REV-Cerâmica 10x10 Vermelha, Massa: 2.70841 kg; EI-REV-Cerâmica 10x10 Vermelha, Área de Componente Projetada (Líquida): 0.0719345 m2; EI-REV-Cerâmica 10x10 Vermelha, Área de Componente Projetada (Bruta): 0.0719345 m2; EI-REV-Cerâmica 10x10 Vermelha, Altura do Componente Retangular: 0.1 m; EI-REV-Cerâmica 10x10 Vermelha, Largura do Componente Retangular: 0.02 m; EI-REV-Cerâmica 10x10 Vermelha, Área de Seção Transversal do Componente: 0.002 m2; EI-REV-Cerâmica 10x10 Vermelha, Volume Componente (Líquido): 0.0013542 m3; EI-REV-Cerâmica 10x10 Vermelha, Volume do componente (Bruto): 0.0013542 m3; EI-REV-Emboço Interno 2, Massa: 9.46626 kg; EI-REV-Emboço Interno 2, Área de Componente Projetada (Líquida): 1.45635 m2; EI-REV-Emboço Interno 2, Área de Componente Projetada (Bruta): 1.45635 m2; EI-REV-Emboço Interno 2, Altura do Componente Retangular: 3.1 m; EI-REV-Emboço Interno 2, Largura do Componente Retangular: 0.005 m; EI-REV-Emboço Interno 2, Área de Seção Transversal do Componente: 0.0155 m2; EI-REV-Emboço Interno 2, Volume Componente (Líquido): 0.00728174 m3; EI-REV-Emboço Interno 2, Volume do componente (Bruto): 0.00728174 m3; EI-REV-Massa única - Maior que 10m² 2, Massa: 2.68196 kg; EI-REV-Massa única - Maior que 10m² 2, Área de Componente Projetada (Líquida): 0.598628 m2; EI-REV-Massa única - Maior que 10m² 2, Área de Componente Projetada (Bruta): 0.598628 m2; EI-REV-Massa única - Maior que 10m² 2, Altura do Componente Retangular: 1.17 m; EI-REV-Massa única - Maior que 10m² 2, Largura do Componente Retangular: 0.00499997 m; EI-REV-Massa única - Maior que 10m² 2, Área de Seção Transversal do Componente: 0.00584996 m2; EI-REV-Massa única - Maior que 10m² 2, Volume Componente (Líquido): 0.00206305 m3; EI-REV-Massa única - Maior que 10m² 2, Volume do componente (Bruto): 0.00206305 m3; EI-REV-Massa Corrida PVA (interna) 2, Massa: 3.86606 kg; EI-REV-Massa Corrida PVA (interna) 2, Área de Componente Projetada (Líquida): 0.594778 m2; EI-REV-Massa Corrida PVA (interna) 2, Área de Componente Projetada (Bruta): 0.594778 m2; EI-REV-Massa Corrida PVA (interna) 2, Altura do Componente Retangular: 1.17 m; EI-REV-Massa Corrida PVA (interna) 2, Largura do Componente Retangular: 0.005 m; EI-REV-Massa Corrida PVA (interna) 2, Área de Seção Transversal do Componente: 0.00585001 m2; EI-REV-Massa Corrida PVA (interna) 2, Volume Componente (Líquido): 0.00297389 m3; EI-REV-Massa Corrida PVA (interna) 2, Volume do componente (Bruto): 0.00297389 m3; EI-REV-Pintura Acrílica Cor Branco Gelo 2, Massa: 9.03388 kg; EI-REV-Pintura Acrílica Cor Branco Gelo 2, Área de Componente Projetada (Líquida): 0.797648 m2; EI-REV-Pintura Acrílica Cor Branco Gelo 2, Área de Componente Projetada (Bruta): 0.797648 m2; EI-REV-Pintura Acrílica Cor Branco Gelo 2, Altura do Componente Retangular: 1.17 m; EI-REV-Pintura Acrílica Cor Branco Gelo 2, Largura do Componente Retangular: 0.01 m; EI-REV-Pintura Acrílica Cor Branco Gelo 2, Área de Seção Transversal do Componente: 0.0117 m2; EI-REV-Pintura Acrílica Cor Branco Gelo 2, Volume Componente (Líquido): 0.00694914 m3; EI-REV-Pintura Acrílica Cor Branco Gelo 2, Volume do componente (Bruto): 0.00694914 m3; EI-REV-Chapisco (interno) 1: 2 with these values

# IfcWall: FNDE-AL09-I5-I7 (azul-amarela) 150 x 3100 (6)
In: TÉRREO
Classification: Parede (Classificação Archicad); Material: TIJOLO - CERAMICO 9x19x39 - espessura 15cm, EI-REV-Chapisco (interno) (2), EI-REV-Cerâmica 10x10 Amarela, EI-REV-Cerâmica 10x10 Branca, EI-REV-Emboço Interno (2), EI-REV-Massa única - Maior que 10m² (2), EI-REV-Massa Corrida PVA (interna) (2), EI-REV-Pintura Acrílica Cor Branco Gelo (2), EI-REV-Cerâmica 30x40, EI-REV-Cerâmica 10x10 Azul
FNDE - Alvenarias: Alvenaria de Vedação / Edificação; Sistemas de Cobertura: -; Esquadrias - Fechamentos metálicos e Gradis: -; 0_ID: AL09
Pset_WallCommon - IsExternal: no; LoadBearing: no
Component Quantities - TIJOLO - CERAMICO 9x19x39 - espessura 15cm, Altura do Componente Retangular: 3.1 m; TIJOLO - CERAMICO 9x19x39 - espessura 15cm, Largura do Componente Retangular: 0.09 m; TIJOLO - CERAMICO 9x19x39 - espessura 15cm, Área de Seção Transversal do Componente: 0.279 m2; EI-REV-Chapisco (interno) 1, Altura do Componente Retangular: 3.1 m; EI-REV-Chapisco (interno) 1, Largura do Componente Retangular: 0.005 m; EI-REV-Chapisco (interno) 1, Área de Seção Transversal do Componente: 0.0155 m2; EI-REV-Cerâmica 10x10 Amarela, Altura do Componente Retangular: 0.9 m; EI-REV-Cerâmica 10x10 Amarela, Largura do Componente Retangular: 0.02 m; EI-REV-Cerâmica 10x10 Amarela, Área de Seção Transversal do Componente: 0.018 m2; EI-REV-Cerâmica 10x10 Branca, Altura do Componente Retangular: 0.1 m; EI-REV-Cerâmica 10x10 Branca, Largura do Componente Retangular: 0.02 m; EI-REV-Cerâmica 10x10 Branca, Área de Seção Transversal do Componente: 0.002 m2; EI-REV-Massa única - Maior que 10m² 1, Altura do Componente Retangular: 2.06 m; EI-REV-Massa única - Maior que 10m² 1, Largura do Componente Retangular: 0.00499999 m; EI-REV-Massa única - Maior que 10m² 1, Área de Seção Transversal do Componente: 0.0103 m2; EI-REV-Massa Corrida PVA (interna) 1, Altura do Componente Retangular: 2.06 m; EI-REV-Massa Corrida PVA (interna) 1, Largura do Componente Retangular: 0.00500002 m; EI-REV-Massa Corrida PVA (interna) 1, Área de Seção Transversal do Componente: 0.0103 m2; EI-REV-Pintura Acrílica Cor Branco Gelo 1, Altura do Componente Retangular: 2.06 m; EI-REV-Pintura Acrílica Cor Branco Gelo 1, Largura do Componente Retangular: 0.01 m; EI-REV-Pintura Acrílica Cor Branco Gelo 1, Área de Seção Transversal do Componente: 0.0206 m2; EI-REV-Chapisco (interno) 2, Altura do Componente Retangular: 3.1 m; EI-REV-Chapisco (interno) 2, Largura do Componente Retangular: 0.005 m; EI-REV-Chapisco (interno) 2, Área de Seção Transversal do Componente: 0.0155 m2; EI-REV-Cerâmica 30x40, Largura do Componente Retangular: 0.02 m; EI-REV-Cerâmica 10x10 Azul, Altura do Componente Retangular: 0.1 m; EI-REV-Cerâmica 10x10 Azul, Largura do Componente Retangular: 0.02 m; EI-REV-Cerâmica 10x10 Azul, Área de Seção Transversal do Componente: 0.002 m2; EI-REV-Massa Corrida PVA (interna) 2, Largura do Componente Retangular: 0.005 m; EI-REV-Pintura Acrílica Cor Branco Gelo 2, Largura do Componente Retangular: 0.01 m
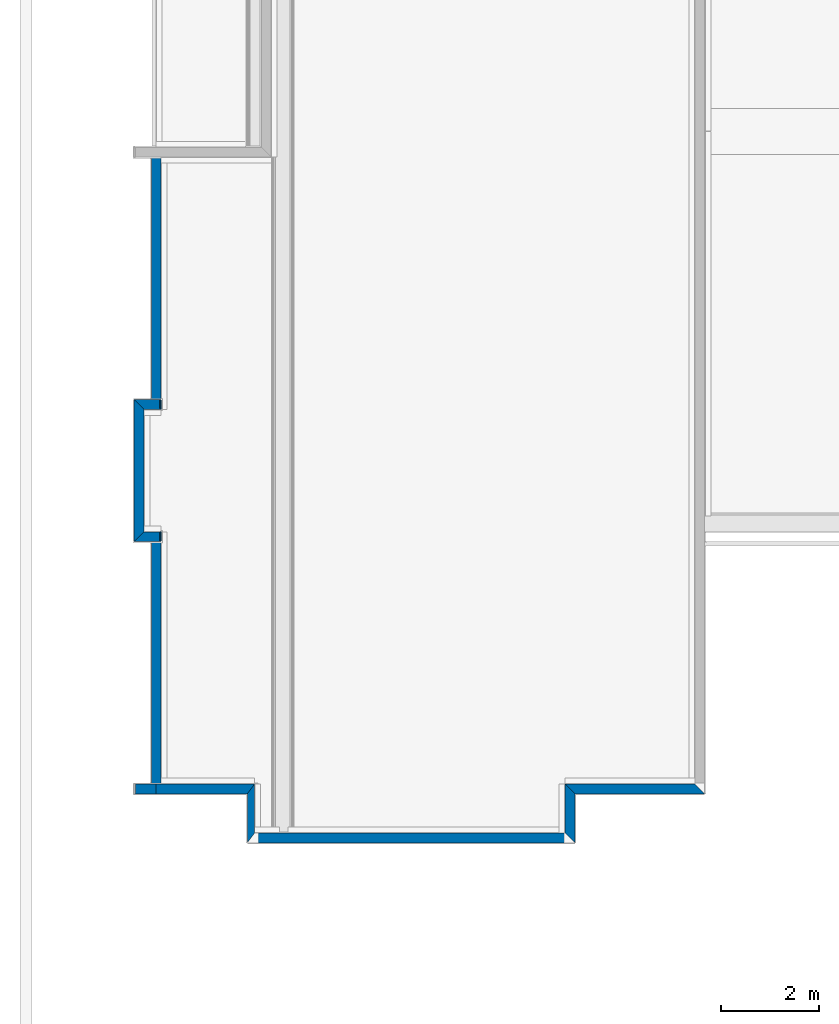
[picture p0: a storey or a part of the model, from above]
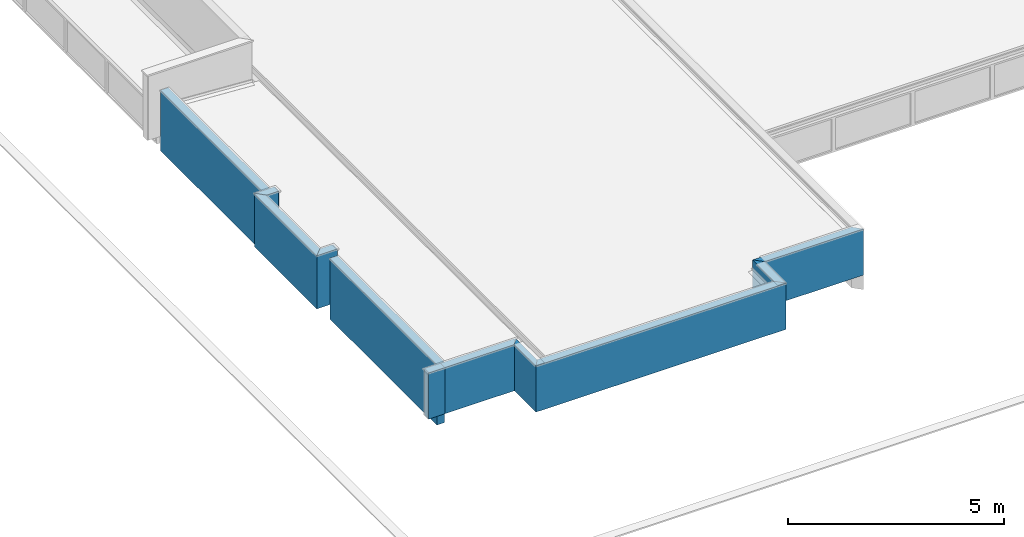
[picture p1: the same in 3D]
Properties of the parts of a building model (IFC4), part 15 of 22

# IfcWall: FNDE-AL09-I5-I7 (azul-amarela) 150 x 3100 (6)
Name | 1_Bloco | TIJOLO - CERAMICO 9x19x39 - espessura 15cm, Massa (kg) | TIJOLO - CERAMICO 9x19x39 - espessura 15cm, Área de Componente Projetada (Líquida) (m2) | TIJOLO - CERAMICO 9x19x39 - espessura 15cm, Área de Componente Projetada (Bruta) (m2) | TIJOLO - CERAMICO 9x19x39 - espessura 15cm, Volume Componente (Líquido) (m3) | TIJOLO - CERAMICO 9x19x39 - espessura 15cm, Volume do componente (Bruto) (m3) | EI-REV-Chapisco (interno) 1, Massa (kg) | EI-REV-Chapisco (interno) 1, Área de Componente Projetada (Líquida) (m2) | EI-REV-Chapisco (interno) 1, Área de Componente Projetada (Bruta) (m2) | EI-REV-Chapisco (interno) 1, Volume Componente (Líquido) (m3) | EI-REV-Chapisco (interno) 1, Volume do componente (Bruto) (m3) | EI-REV-Cerâmica 10x10 Amarela, Massa (kg) | EI-REV-Cerâmica 10x10 Amarela, Área de Componente Projetada (Líquida) (m2) | EI-REV-Cerâmica 10x10 Amarela, Área de Componente Projetada (Bruta) (m2) | EI-REV-Cerâmica 10x10 Amarela, Volume Componente (Líquido) (m3) | EI-REV-Cerâmica 10x10 Amarela, Volume do componente (Bruto) (m3) | EI-REV-Cerâmica 10x10 Branca, Massa (kg) | EI-REV-Cerâmica 10x10 Branca, Área de Componente Projetada (Líquida) (m2) | EI-REV-Cerâmica 10x10 Branca, Área de Componente Projetada (Bruta) (m2) | EI-REV-Cerâmica 10x10 Branca, Volume Componente (Líquido) (m3) | EI-REV-Cerâmica 10x10 Branca, Volume do componente (Bruto) (m3) | EI-REV-Emboço Interno 1, Massa (kg) | EI-REV-Emboço Interno 1, Área de Componente Projetada (Líquida) (m2) | EI-REV-Emboço Interno 1, Área de Componente Projetada (Bruta) (m2) | EI-REV-Emboço Interno 1, Altura do Componente Retangular (m) | EI-REV-Emboço Interno 1, Largura do Componente Retangular (m) | EI-REV-Emboço Interno 1, Área de Seção Transversal do Componente (m2) | EI-REV-Emboço Interno 1, Volume Componente (Líquido) (m3) | EI-REV-Emboço Interno 1, Volume do componente (Bruto) (m3) | EI-REV-Massa única - Maior que 10m² 1, Massa (kg) | EI-REV-Massa única - Maior que 10m² 1, Área de Componente Projetada (Líquida) (m2) | EI-REV-Massa única - Maior que 10m² 1, Área de Componente Projetada (Bruta) (m2) | EI-REV-Massa única - Maior que 10m² 1, Volume Componente (Líquido) (m3) | EI-REV-Massa única - Maior que 10m² 1, Volume do componente (Bruto) (m3) | EI-REV-Massa Corrida PVA (interna) 1, Massa (kg) | EI-REV-Massa Corrida PVA (interna) 1, Área de Componente Projetada (Líquida) (m2) | EI-REV-Massa Corrida PVA (interna) 1, Área de Componente Projetada (Bruta) (m2) | EI-REV-Massa Corrida PVA (interna) 1, Volume Componente (Líquido) (m3) | EI-REV-Massa Corrida PVA (interna) 1, Volume do componente (Bruto) (m3) | EI-REV-Pintura Acrílica Cor Branco Gelo 1, Massa (kg) | EI-REV-Pintura Acrílica Cor Branco Gelo 1, Área de Componente Projetada (Líquida) (m2) | EI-REV-Pintura Acrílica Cor Branco Gelo 1, Área de Componente Projetada (Bruta) (m2) | EI-REV-Pintura Acrílica Cor Branco Gelo 1, Volume Componente (Líquido) (m3) | EI-REV-Pintura Acrílica Cor Branco Gelo 1, Volume do componente (Bruto) (m3) | EI-REV-Chapisco (interno) 2, Massa (kg) | EI-REV-Chapisco (interno) 2, Área de Componente Projetada (Líquida) (m2) | EI-REV-Chapisco (interno) 2, Área de Componente Projetada (Bruta) (m2) | EI-REV-Chapisco (interno) 2, Volume Componente (Líquido) (m3) | EI-REV-Chapisco (interno) 2, Volume do componente (Bruto) (m3) | EI-REV-Cerâmica 30x40, Massa (kg) | EI-REV-Cerâmica 30x40, Área de Componente Projetada (Líquida) (m2) | EI-REV-Cerâmica 30x40, Área de Componente Projetada (Bruta) (m2) | EI-REV-Cerâmica 30x40, Altura do Componente Retangular (m) | EI-REV-Cerâmica 30x40, Área de Seção Transversal do Componente (m2) | EI-REV-Cerâmica 30x40, Volume Componente (Líquido) (m3) | EI-REV-Cerâmica 30x40, Volume do componente (Bruto) (m3) | EI-REV-Cerâmica 10x10 Azul, Massa (kg) | EI-REV-Cerâmica 10x10 Azul, Área de Componente Projetada (Líquida) (m2) | EI-REV-Cerâmica 10x10 Azul, Área de Componente Projetada (Bruta) (m2) | EI-REV-Cerâmica 10x10 Azul, Volume Componente (Líquido) (m3) | EI-REV-Cerâmica 10x10 Azul, Volume do componente (Bruto) (m3) | EI-REV-Emboço Interno 2, Massa (kg) | EI-REV-Emboço Interno 2, Área de Componente Projetada (Líquida) (m2) | EI-REV-Emboço Interno 2, Área de Componente Projetada (Bruta) (m2) | EI-REV-Emboço Interno 2, Altura do Componente Retangular (m) | EI-REV-Emboço Interno 2, Largura do Componente Retangular (m) | EI-REV-Emboço Interno 2, Área de Seção Transversal do Componente (m2) | EI-REV-Emboço Interno 2, Volume Componente (Líquido) (m3) | EI-REV-Emboço Interno 2, Volume do componente (Bruto) (m3) | EI-REV-Massa única - Maior que 10m² 2, Massa (kg) | EI-REV-Massa única - Maior que 10m² 2, Área de Componente Projetada (Líquida) (m2) | EI-REV-Massa única - Maior que 10m² 2, Área de Componente Projetada (Bruta) (m2) | EI-REV-Massa única - Maior que 10m² 2, Altura do Componente Retangular (m) = EI-REV-Massa Corrida PVA (interna) 2, Altura do Componente Retangular (m) = EI-REV-Pintura Acrílica Cor Branco Gelo 2, Altura do Componente Retangular (m) | EI-REV-Massa única - Maior que 10m² 2, Largura do Componente Retangular (m) | EI-REV-Massa única - Maior que 10m² 2, Área de Seção Transversal do Componente (m2) | EI-REV-Massa única - Maior que 10m² 2, Volume Componente (Líquido) (m3) | EI-REV-Massa única - Maior que 10m² 2, Volume do componente (Bruto) (m3) | EI-REV-Massa Corrida PVA (interna) 2, Massa (kg) | EI-REV-Massa Corrida PVA (interna) 2, Área de Componente Projetada (Líquida) (m2) | EI-REV-Massa Corrida PVA (interna) 2, Área de Componente Projetada (Bruta) (m2) | EI-REV-Massa Corrida PVA (interna) 2, Área de Seção Transversal do Componente (m2) | EI-REV-Massa Corrida PVA (interna) 2, Volume Componente (Líquido) (m3) | EI-REV-Massa Corrida PVA (interna) 2, Volume do componente (Bruto) (m3) | EI-REV-Pintura Acrílica Cor Branco Gelo 2, Massa (kg) | EI-REV-Pintura Acrílica Cor Branco Gelo 2, Área de Componente Projetada (Líquida) (m2) | EI-REV-Pintura Acrílica Cor Branco Gelo 2, Área de Componente Projetada (Bruta) (m2) | EI-REV-Pintura Acrílica Cor Branco Gelo 2, Área de Seção Transversal do Componente (m2) | EI-REV-Pintura Acrílica Cor Branco Gelo 2, Volume Componente (Líquido) (m3) | EI-REV-Pintura Acrílica Cor Branco Gelo 2, Volume do componente (Bruto) (m3)
AL09 | BLOCO B | 262.714 | 4.50469 | 6.43069 | 0.405422 | 0.578762 | 29.2805 | 4.50469 | 6.43069 | 0.0225235 | 0.0321535 | 58.1223 | 1.4849 | 2.2949 | 0.0290611 | 0.0452611 | 6.45803 | 0.164989 | 0.254989 | 0.00322902 | 0.00502902 | 29.2818 | 4.50489 | 6.43089 | 3.1 | 0.005 | 0.0155 | 0.0225245 | 0.0321545 | 19.0506 | 2.93045 | 3.95645 | 0.0146543 | 0.0197852 | 20.6286 | 3.17362 | 4.19962 | 0.0158681 | 0.0209982 | 47.2666 | 4.14149 | 5.16749 | 0.0363589 | 0.0466188 | 29.1927 | 4.49119 | 6.41719 | 0.022456 | 0.032086 | 113.006 | 2.88881 | 4.49981 | 1.8 | 0.036 | 0.0565032 | 0.0887231 | 6.25813 | 0.15999 | 0.24999 | 0.00312907 | 0.00492907 | 29.105 | 4.47769 | 6.40369 | 3.1 | 0.005 | 0.0155 | 0.0223885 | 0.0320185 | 10.4147 | 1.60252 | 1.82752 | 1.17 | 0.00499997 | 0.00584996 | 0.00801131 | 0.0091362 | 11.1496 | 1.71531 | 1.94031 | 0.00585001 | 0.00857658 | 0.00970158 | 27.6906 | 2.69987 | 2.92487 | 0.0117 | 0.0213005 | 0.0235505
AL09 | BLOCO B | 57.0341 | 0.97795 | 0.97795 | 0.0880155 | 0.0880155 | 5.56693 | 0.85645 | 0.85645 | 0.00428225 | 0.00428225 | 13.6953 | 0.54 | 0.54 | 0.00684765 | 0.00684765 | 1.5217 | 0.06 | 0.06 | 0.00076085 | 0.00076085 | 5.48048 | 0.84315 | 0.84315 | 3.1 | 0.005 | 0.0155 | 0.00421575 | 0.00421575 | 3.31472 | 0.509958 | 0.509958 | 0.00254979 | 0.00254979 | 3.26079 | 0.501658 | 0.501658 | 0.0025083 | 0.0025083 | 10.8752 | 1.175 | 1.175 | 0.00836557 | 0.00836557 | 6.35668 | 0.97795 | 0.97795 | 0.00488975 | 0.00488975 | 19.3387 | 0.629999 | 0.629999 | 1.2 | 0.024 | 0.00966937 | 0.00966937 | 1.61156 | 0.0525 | 0.0525 | 0.000805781 | 0.000805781 |  |  |  |  |  |  |  |  | 3.22541 | 0.496219 | 0.496219 | 1.77 | 0.00499998 | 0.00884996 | 0.00248109 | 0.00248109 | 3.22543 | 0.496219 | 0.496219 | 0.00885001 | 0.0024811 | 0.0024811 | 9.26471 | 0.929249 | 0.929249 | 0.0177 | 0.0071267 | 0.0071267 | Component Quantities - EI-REV-Chapisco (interno) 2: 2 with these values
AL09 | BLOCO B | 283.435 | 4.86 | 6.786 | 0.4374 | 0.61074 | 31.59 | 4.86 | 6.786 | 0.0243 | 0.03393 | 62.9068 | 1.79994 | 2.60994 | 0.0314534 | 0.0476534 | 6.98964 | 0.199993 | 0.289993 | 0.00349482 | 0.00529482 |  |  |  |  |  |  |  |  | 20.5217 | 3.1572 | 4.1832 | 0.015786 | 0.0209159 | 21.3363 | 3.3813 | 4.4073 | 0.0164126 | 0.0215426 | 49.5403 | 4.87556 | 5.90156 | 0.0381079 | 0.0483668 | 31.549 | 4.8537 | 6.7797 | 0.0242685 | 0.0338985 | 79.6578 | 2.07092 | 3.14192 | 1.2 | 0.024 | 0.0398289 | 0.0612489 | 6.63119 | 0.172493 | 0.262493 | 0.0033156 | 0.0051156 |  |  |  |  |  |  |  |  | 17.468 | 2.6874 | 3.4524 | 1.77 | 0.00499998 | 0.00884996 | 0.013437 | 0.0172619 | 17.4681 | 2.6874 | 3.4524 | 0.00885001 | 0.013437 | 0.017262 | 45.5664 | 3.82242 | 4.58742 | 0.0177 | 0.0350511 | 0.0427011 | Component Quantities - EI-REV-Chapisco (interno) 2: 2 with these values; EI-REV-Chapisco (interno) 1: 2 with these values
AL09 | BLOCO A | 272.41 | 4.67095 | 4.67095 | 0.420385 | 0.420385 | 28.8694 | 4.44145 | 4.44145 | 0.0222072 | 0.0222072 | 59.3993 | 1.48498 | 1.48498 | 0.0296996 | 0.0296996 | 6.59992 | 0.164998 | 0.164998 | 0.00329996 | 0.00329996 | 28.7816 | 4.42795 | 4.42795 | 3.1 | 0.005 | 0.0155 | 0.0221397 | 0.0221397 | 17.6414 | 2.71407 | 2.71407 | 0.0135703 | 0.0135703 | 17.5875 | 2.70577 | 2.70577 | 0.0135289 | 0.0135289 | 39.4132 | 3.35376 | 3.35376 | 0.0303178 | 0.0303178 | 28.7422 | 4.42188 | 4.42188 | 0.0221093 | 0.0221093 | 117.359 | 2.93396 | 2.93396 | 1.8 | 0.036 | 0.0586793 | 0.0586793 | 6.51992 | 0.162998 | 0.162998 | 0.00325996 | 0.00325996 | 28.6544 | 4.40838 | 4.40838 | 3.1 | 0.005 | 0.0155 | 0.0220419 | 0.0220419 | 8.12005 | 1.24924 | 1.24924 | 1.17 | 0.00499997 | 0.00584996 | 0.00624619 | 0.00624619 | 8.09506 | 1.24539 | 1.24539 | 0.00585001 | 0.00622697 | 0.00622697 | 20.292 | 1.88431 | 1.88431 | 0.0117 | 0.0156093 | 0.0156093
AL09 | BLOCO A | 258.727 | 4.43634 | 4.96134 | 0.39927 | 0.44652 | 28.8362 | 4.43634 | 4.96134 | 0.0221817 | 0.0248067 | 67.5805 | 1.78428 | 1.78428 | 0.0337902 | 0.0337902 | 7.50894 | 0.198254 | 0.198254 | 0.00375447 | 0.00375447 |  |  |  |  |  |  |  |  | 16.4145 | 2.52531 | 3.05031 | 0.0126265 | 0.0152515 | 16.4146 | 2.52531 | 3.05031 | 0.0126266 | 0.0152516 | 39.3021 | 3.48703 | 4.01203 | 0.0302324 | 0.0354824 | 28.7484 | 4.42283 | 4.94783 | 0.0221142 | 0.0247392 | 130.142 | 3.25356 | 3.25356 | 1.8 | 0.036 | 0.0650711 | 0.0650711 | 7.23012 | 0.180753 | 0.180753 | 0.00361506 | 0.00361506 | 28.6607 | 4.40933 | 4.93433 | 3.1 | 0.005 | 0.0155 | 0.0220467 | 0.0246717 | 5.70923 | 0.878349 | 1.40335 | 1.17 | 0.00499997 | 0.00584996 | 0.00439172 | 0.0070167 | 5.68425 | 0.874499 | 1.3995 | 0.00585001 | 0.0043725 | 0.0069975 | 15.7535 | 1.58981 | 2.11481 | 0.0117 | 0.0121181 | 0.0173681 | Component Quantities - EI-REV-Chapisco (interno) 1: 2 with these values
AL09 | BLOCO A | 132.961 | 2.27985 | 4.20585 | 0.205186 | 0.378526 | 12.362 | 1.90185 | 3.82785 | 0.00950923 | 0.0191392 | 21.0855 | 0.71941 | 1.52941 | 0.0105427 | 0.0267427 | 2.34283 | 0.0799345 | 0.169934 | 0.00117142 | 0.00297142 | 12.2743 | 1.88835 | 3.81435 | 3.1 | 0.005 | 0.0155 | 0.00944173 | 0.0190717 | 8.65072 | 1.33088 | 2.34788 | 0.0066544 | 0.0117394 | 8.59682 | 1.32258 | 2.33958 | 0.00661294 | 0.011698 | 24.6952 | 2.48365 | 3.50065 | 0.0189963 | 0.0291663 | 13.3012 | 2.04635 | 3.97235 | 0.0102317 | 0.0198617 | 44.862 | 1.33082 | 2.95082 | 1.8 | 0.036 | 0.022431 | 0.054831 | 2.49233 | 0.0739345 | 0.163934 | 0.00124617 | 0.00304617 | 13.2135 | 2.03285 | 3.95885 | 3.1 | 0.005 | 0.0155 | 0.0101642 | 0.0197942 | 5.92525 | 0.911579 | 1.12758 | 1.17 | 0.00499997 | 0.00584996 | 0.00455789 | 0.00563788 | 5.90024 | 0.907729 | 1.12373 | 0.00585001 | 0.00453865 | 0.00561865 | 16.685 | 1.6639 | 1.8799 | 0.0117 | 0.0128346 | 0.0149946

# IfcWall: FNDE-AL09-I5-I7 (vermelho-amarela) 150 x 3100 (5)
In: TÉRREO
Classification: Parede (Classificação Archicad); Material: TIJOLO - CERAMICO 9x19x39 - espessura 15cm, EI-REV-Chapisco (interno) (2), EI-REV-Cerâmica 10x10 Amarela, EI-REV-Cerâmica 10x10 Branca, EI-REV-Emboço Interno (2), EI-REV-Massa única - Maior que 10m² (2), EI-REV-Massa Corrida PVA (interna) (2), EI-REV-Pintura Acrílica Cor Branco Gelo (2), EI-REV-Cerâmica 30x40, EI-REV-Cerâmica 10x10 Vermelha
FNDE - Alvenarias: Alvenaria de Vedação / Edificação; Sistemas de Cobertura: -; Esquadrias - Fechamentos metálicos e Gradis: -; 0_ID: AL09
Pset_WallCommon - IsExternal: no; LoadBearing: no
Component Quantities - TIJOLO - CERAMICO 9x19x39 - espessura 15cm, Altura do Componente Retangular: 3.1 m; TIJOLO - CERAMICO 9x19x39 - espessura 15cm, Largura do Componente Retangular: 0.09 m; TIJOLO - CERAMICO 9x19x39 - espessura 15cm, Área de Seção Transversal do Componente: 0.279 m2; EI-REV-Chapisco (interno) 1, Altura do Componente Retangular: 3.1 m; EI-REV-Chapisco (interno) 1, Largura do Componente Retangular: 0.005 m; EI-REV-Chapisco (interno) 1, Área de Seção Transversal do Componente: 0.0155 m2; EI-REV-Cerâmica 10x10 Amarela, Altura do Componente Retangular: 0.9 m; EI-REV-Cerâmica 10x10 Amarela, Largura do Componente Retangular: 0.02 m; EI-REV-Cerâmica 10x10 Amarela, Área de Seção Transversal do Componente: 0.018 m2; EI-REV-Cerâmica 10x10 Branca, Altura do Componente Retangular: 0.1 m; EI-REV-Cerâmica 10x10 Branca, Largura do Componente Retangular: 0.02 m; EI-REV-Cerâmica 10x10 Branca, Área de Seção Transversal do Componente: 0.002 m2; EI-REV-Massa única - Maior que 10m² 1, Altura do Componente Retangular: 2.06 m; EI-REV-Massa única - Maior que 10m² 1, Largura do Componente Retangular: 0.00499999 m; EI-REV-Massa única - Maior que 10m² 1, Área de Seção Transversal do Componente: 0.0103 m2; EI-REV-Massa Corrida PVA (interna) 1, Altura do Componente Retangular: 2.06 m; EI-REV-Massa Corrida PVA (interna) 1, Largura do Componente Retangular: 0.00500002 m; EI-REV-Massa Corrida PVA (interna) 1, Área de Seção Transversal do Componente: 0.0103 m2; EI-REV-Pintura Acrílica Cor Branco Gelo 1, Altura do Componente Retangular: 2.06 m; EI-REV-Pintura Acrílica Cor Branco Gelo 1, Largura do Componente Retangular: 0.01 m; EI-REV-Pintura Acrílica Cor Branco Gelo 1, Área de Seção Transversal do Componente: 0.0206 m2; EI-REV-Cerâmica 30x40, Largura do Componente Retangular: 0.02 m; EI-REV-Cerâmica 10x10 Vermelha, Altura do Componente Retangular: 0.1 m; EI-REV-Cerâmica 10x10 Vermelha, Largura do Componente Retangular: 0.02 m; EI-REV-Cerâmica 10x10 Vermelha, Área de Seção Transversal do Componente: 0.002 m2; EI-REV-Emboço Interno 2, Altura do Componente Retangular: 3.1 m; EI-REV-Emboço Interno 2, Largura do Componente Retangular: 0.005 m; EI-REV-Emboço Interno 2, Área de Seção Transversal do Componente: 0.0155 m2; EI-REV-Massa Corrida PVA (interna) 2, Largura do Componente Retangular: 0.005 m; EI-REV-Pintura Acrílica Cor Branco Gelo 2, Largura do Componente Retangular: 0.01 m
Name | 1_Bloco | TIJOLO - CERAMICO 9x19x39 - espessura 15cm, Massa (kg) | TIJOLO - CERAMICO 9x19x39 - espessura 15cm, Área de Componente Projetada (Líquida) (m2) | TIJOLO - CERAMICO 9x19x39 - espessura 15cm, Área de Componente Projetada (Bruta) (m2) | TIJOLO - CERAMICO 9x19x39 - espessura 15cm, Volume Componente (Líquido) (m3) | TIJOLO - CERAMICO 9x19x39 - espessura 15cm, Volume do componente (Bruto) (m3) | EI-REV-Chapisco (interno) 1, Massa (kg) | EI-REV-Chapisco (interno) 1, Área de Componente Projetada (Líquida) (m2) | EI-REV-Chapisco (interno) 1, Área de Componente Projetada (Bruta) (m2) | EI-REV-Chapisco (interno) 1, Volume Componente (Líquido) (m3) | EI-REV-Chapisco (interno) 1, Volume do componente (Bruto) (m3) | EI-REV-Cerâmica 10x10 Amarela, Massa (kg) | EI-REV-Cerâmica 10x10 Amarela, Área de Componente Projetada (Líquida) (m2) | EI-REV-Cerâmica 10x10 Amarela, Área de Componente Projetada (Bruta) (m2) | EI-REV-Cerâmica 10x10 Amarela, Volume Componente (Líquido) (m3) | EI-REV-Cerâmica 10x10 Amarela, Volume do componente (Bruto) (m3) | EI-REV-Cerâmica 10x10 Branca, Massa (kg) | EI-REV-Cerâmica 10x10 Branca, Área de Componente Projetada (Líquida) (m2) | EI-REV-Cerâmica 10x10 Branca, Área de Componente Projetada (Bruta) (m2) | EI-REV-Cerâmica 10x10 Branca, Volume Componente (Líquido) (m3) | EI-REV-Cerâmica 10x10 Branca, Volume do componente (Bruto) (m3) | EI-REV-Emboço Interno 1, Massa (kg) | EI-REV-Emboço Interno 1, Área de Componente Projetada (Líquida) (m2) | EI-REV-Emboço Interno 1, Área de Componente Projetada (Bruta) (m2) | EI-REV-Emboço Interno 1, Altura do Componente Retangular (m) | EI-REV-Emboço Interno 1, Largura do Componente Retangular (m) | EI-REV-Emboço Interno 1, Área de Seção Transversal do Componente (m2) | EI-REV-Emboço Interno 1, Volume Componente (Líquido) (m3) | EI-REV-Emboço Interno 1, Volume do componente (Bruto) (m3) | EI-REV-Massa única - Maior que 10m² 1, Massa (kg) | EI-REV-Massa única - Maior que 10m² 1, Área de Componente Projetada (Líquida) (m2) | EI-REV-Massa única - Maior que 10m² 1, Área de Componente Projetada (Bruta) (m2) | EI-REV-Massa única - Maior que 10m² 1, Volume Componente (Líquido) (m3) | EI-REV-Massa única - Maior que 10m² 1, Volume do componente (Bruto) (m3) | EI-REV-Massa Corrida PVA (interna) 1, Massa (kg) | EI-REV-Massa Corrida PVA (interna) 1, Área de Componente Projetada (Líquida) (m2) | EI-REV-Massa Corrida PVA (interna) 1, Área de Componente Projetada (Bruta) (m2) | EI-REV-Massa Corrida PVA (interna) 1, Volume Componente (Líquido) (m3) | EI-REV-Massa Corrida PVA (interna) 1, Volume do componente (Bruto) (m3) | EI-REV-Pintura Acrílica Cor Branco Gelo 1, Massa (kg) | EI-REV-Pintura Acrílica Cor Branco Gelo 1, Área de Componente Projetada (Líquida) (m2) | EI-REV-Pintura Acrílica Cor Branco Gelo 1, Área de Componente Projetada (Bruta) (m2) | EI-REV-Pintura Acrílica Cor Branco Gelo 1, Volume Componente (Líquido) (m3) | EI-REV-Pintura Acrílica Cor Branco Gelo 1, Volume do componente (Bruto) (m3) | EI-REV-Chapisco (interno) 2, Massa (kg) | EI-REV-Chapisco (interno) 2, Área de Componente Projetada (Líquida) (m2) | EI-REV-Chapisco (interno) 2, Área de Componente Projetada (Bruta) (m2) | EI-REV-Chapisco (interno) 2, Altura do Componente Retangular (m) | EI-REV-Chapisco (interno) 2, Largura do Componente Retangular (m) | EI-REV-Chapisco (interno) 2, Área de Seção Transversal do Componente (m2) | EI-REV-Chapisco (interno) 2, Volume Componente (Líquido) (m3) | EI-REV-Chapisco (interno) 2, Volume do componente (Bruto) (m3) | EI-REV-Cerâmica 30x40, Massa (kg) | EI-REV-Cerâmica 30x40, Área de Componente Projetada (Líquida) (m2) | EI-REV-Cerâmica 30x40, Área de Componente Projetada (Bruta) (m2) | EI-REV-Cerâmica 30x40, Altura do Componente Retangular (m) | EI-REV-Cerâmica 30x40, Área de Seção Transversal do Componente (m2) | EI-REV-Cerâmica 30x40, Volume Componente (Líquido) (m3) | EI-REV-Cerâmica 30x40, Volume do componente (Bruto) (m3) | EI-REV-Cerâmica 10x10 Vermelha, Massa (kg) | EI-REV-Cerâmica 10x10 Vermelha, Área de Componente Projetada (Líquida) (m2) | EI-REV-Cerâmica 10x10 Vermelha, Área de Componente Projetada (Bruta) (m2) | EI-REV-Cerâmica 10x10 Vermelha, Volume Componente (Líquido) (m3) | EI-REV-Cerâmica 10x10 Vermelha, Volume do componente (Bruto) (m3) | EI-REV-Emboço Interno 2, Massa (kg) | EI-REV-Emboço Interno 2, Área de Componente Projetada (Líquida) (m2) | EI-REV-Emboço Interno 2, Área de Componente Projetada (Bruta) (m2) | EI-REV-Emboço Interno 2, Volume Componente (Líquido) (m3) | EI-REV-Emboço Interno 2, Volume do componente (Bruto) (m3) | EI-REV-Massa única - Maior que 10m² 2, Massa (kg) | EI-REV-Massa única - Maior que 10m² 2, Área de Componente Projetada (Líquida) (m2) | EI-REV-Massa única - Maior que 10m² 2, Área de Componente Projetada (Bruta) (m2) | EI-REV-Massa única - Maior que 10m² 2, Altura do Componente Retangular (m) = EI-REV-Massa Corrida PVA (interna) 2, Altura do Componente Retangular (m) = EI-REV-Pintura Acrílica Cor Branco Gelo 2, Altura do Componente Retangular (m) | EI-REV-Massa única - Maior que 10m² 2, Largura do Componente Retangular (m) | EI-REV-Massa única - Maior que 10m² 2, Área de Seção Transversal do Componente (m2) | EI-REV-Massa única - Maior que 10m² 2, Volume Componente (Líquido) (m3) | EI-REV-Massa única - Maior que 10m² 2, Volume do componente (Bruto) (m3) | EI-REV-Massa Corrida PVA (interna) 2, Massa (kg) | EI-REV-Massa Corrida PVA (interna) 2, Área de Componente Projetada (Líquida) (m2) | EI-REV-Massa Corrida PVA (interna) 2, Área de Componente Projetada (Bruta) (m2) | EI-REV-Massa Corrida PVA (interna) 2, Área de Seção Transversal do Componente (m2) | EI-REV-Massa Corrida PVA (interna) 2, Volume Componente (Líquido) (m3) | EI-REV-Massa Corrida PVA (interna) 2, Volume do componente (Bruto) (m3) | EI-REV-Pintura Acrílica Cor Branco Gelo 2, Massa (kg) | EI-REV-Pintura Acrílica Cor Branco Gelo 2, Área de Componente Projetada (Líquida) (m2) | EI-REV-Pintura Acrílica Cor Branco Gelo 2, Área de Componente Projetada (Bruta) (m2) | EI-REV-Pintura Acrílica Cor Branco Gelo 2, Área de Seção Transversal do Componente (m2) | EI-REV-Pintura Acrílica Cor Branco Gelo 2, Volume Componente (Líquido) (m3) | EI-REV-Pintura Acrílica Cor Branco Gelo 2, Volume do componente (Bruto) (m3)
AL09 | BLOCO B | 74.0077 | 1.26899 | 1.26899 | 0.114209 | 0.114209 | 8.33617 | 1.28249 | 1.28249 | 0.00641244 | 0.00641244 | 19.0581 | 0.558 | 0.558 | 0.00952905 | 0.00952905 | 2.11757 | 0.062 | 0.062 | 0.00105878 | 0.00105878 | 8.42392 | 1.29599 | 1.29599 | 3.1 | 0.005 | 0.0155 | 0.00647994 | 0.00647994 | 5.23309 | 0.805093 | 0.805093 | 0.00402545 | 0.00402545 | 5.28707 | 0.813393 | 0.813393 | 0.00406698 | 0.00406698 | 13.145 | 1.1986 | 1.1986 | 0.0101115 | 0.0101115 | 6.66896 | 1.02599 | 1.02599 | 3.1 | 0.005 | 0.0155 | 0.00512997 | 0.00512997 | 17.76 | 0.444 | 0.444 | 1.2 | 0.024 | 0.00888 | 0.00888 | 1.48 | 0.037 | 0.037 | 0.00074 | 0.00074 | 6.58121 | 1.01249 | 1.01249 | 0.00506247 | 0.00506247 | 3.29483 | 0.506897 | 0.506897 | 1.77 | 0.00499998 | 0.00884996 | 0.00253448 | 0.00253448 | 3.25032 | 0.500047 | 0.500047 | 0.00885001 | 0.00250024 | 0.00250024 | 7.35902 | 0.636077 | 0.636077 | 0.0177 | 0.00566078 | 0.00566078
AL09 | BLOCO B | 285.01 | 4.887 | 6.813 | 0.43983 | 0.61317 | 33.358 | 5.132 | 7.058 | 0.02566 | 0.03529 | 62.7832 | 1.647 | 2.457 | 0.0313916 | 0.0475916 | 6.97591 | 0.183 | 0.273 | 0.00348796 | 0.00528796 | 33.4457 | 5.1455 | 7.0715 | 3.1 | 0.005 | 0.0155 | 0.0257275 | 0.0353575 | 21.7087 | 3.3398 | 4.3658 | 0.016699 | 0.021829 | 21.7627 | 3.3481 | 4.3741 | 0.0167405 | 0.0218705 | 48.2197 | 4.61839 | 5.64439 | 0.0370921 | 0.0473521 | 31.6258 | 4.8655 | 6.7915 | 3.1 | 0.005 | 0.0155 | 0.0243275 | 0.0339575 | 78.569 | 2.041 | 3.112 | 1.2 | 0.024 | 0.0392845 | 0.0607045 | 6.54409 | 0.17 | 0.26 | 0.00327204 | 0.00507204 | 31.538 | 4.852 | 6.778 | 0.02426 | 0.03389 | 17.4235 | 2.68055 | 3.44555 | 1.77 | 0.00499998 | 0.00884996 | 0.0134027 | 0.0172277 | 17.3791 | 2.6737 | 3.4387 | 0.00885001 | 0.0133685 | 0.0171935 | 45.2381 | 3.798 | 4.563 | 0.0177 | 0.0347986 | 0.0424486
AL09 | BLOCO A | 324.645 | 5.56662 | 6.61662 | 0.500996 | 0.595496 | 36.183 | 5.56662 | 6.61662 | 0.0278331 | 0.0330831 | 88.0586 | 2.34 | 2.34 | 0.0440293 | 0.0440293 | 9.78429 | 0.26 | 0.26 | 0.00489214 | 0.00489214 |  |  |  |  |  |  |  |  | 19.6169 | 3.018 | 4.068 | 0.0150899 | 0.0203399 | 19.617 | 3.018 | 4.068 | 0.01509 | 0.0203401 | 39.2204 | 4.306 | 5.356 | 0.0301696 | 0.0406696 |  |  |  |  |  |  |  |  | 184.273 | 4.78775 | 4.78775 | 1.8 | 0.036 | 0.0921367 | 0.0921367 | 10.2378 | 0.266 | 0.266 | 0.00511889 | 0.00511889 | 36.1831 | 5.56662 | 6.61662 | 0.0278331 | 0.0330831 | 5.44025 | 0.836962 | 1.88696 | 1.17 | 0.00499997 | 0.00584996 | 0.00418481 | 0.00943481 | 5.44026 | 0.836962 | 1.88696 | 0.00585001 | 0.00418481 | 0.00943482 | 26.0165 | 2.00776 | 3.05776 | 0.0117 | 0.0200127 | 0.0305127 | Component Quantities - EI-REV-Chapisco (interno) 1: 3 with these values
AL09 | BLOCO A | 157.741 | 2.70474 | 4.63074 | 0.243427 | 0.416767 | 17.2752 | 2.65773 | 4.58373 | 0.0132887 | 0.0229187 | 29.4964 | 0.73741 | 1.54741 | 0.0147482 | 0.0309482 | 3.27738 | 0.0819344 | 0.171934 | 0.00163869 | 0.00343869 |  |  |  |  |  |  |  |  | 11.7208 | 1.80321 | 2.82921 | 0.00901603 | 0.014146 | 11.7209 | 1.80321 | 2.82921 | 0.00901609 | 0.0141461 | 27.9769 | 2.49525 | 3.52125 | 0.0215207 | 0.0317807 | 16.0013 | 2.46174 | 4.38774 | 3.1 | 0.005 | 0.0155 | 0.0123087 | 0.0219387 | 52.8728 | 1.32182 | 2.93282 | 1.8 | 0.036 | 0.0264364 | 0.0586564 | 2.91738 | 0.0729344 | 0.162934 | 0.00145869 | 0.00325869 | 15.9136 | 2.44824 | 4.37424 | 0.0122412 | 0.0218712 | 6.65436 | 1.02375 | 1.24875 | 1.17 | 0.00499997 | 0.00584996 | 0.00511874 | 0.00624374 | 6.62937 | 1.0199 | 1.2449 | 0.00585001 | 0.00509952 | 0.00622452 | 17.4146 | 1.65877 | 1.88377 | 0.0117 | 0.0133958 | 0.0156458 | Component Quantities - EI-REV-Chapisco (interno) 1: 2 with these values
AL09 | BLOCO A | 36.62 | 0.627915 | 0.627915 | 0.0565123 | 0.0565123 | 5.66094 | 0.870915 | 0.870915 | 0.00435457 | 0.00435457 | 11.9722 | 0.299305 | 0.299305 | 0.0059861 | 0.0059861 | 1.33024 | 0.0332561 | 0.0332561 | 0.000665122 | 0.000665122 | 5.7487 | 0.884415 | 0.884415 | 3.1 | 0.005 | 0.0155 | 0.00442207 | 0.00442207 | 3.58832 | 0.552051 | 0.552051 | 0.00276025 | 0.00276025 | 3.64229 | 0.560351 | 0.560351 | 0.00280177 | 0.00280177 | 8.27543 | 0.705676 | 0.705676 | 0.00636572 | 0.00636572 | 3.99369 | 0.614415 | 0.614415 | 3.1 | 0.005 | 0.0155 | 0.00307207 | 0.00307207 | 14.5844 | 0.36461 | 0.36461 | 1.8 | 0.036 | 0.00729219 | 0.00729219 | 0.810244 | 0.0202561 | 0.0202561 | 0.000405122 | 0.000405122 | 3.90594 | 0.600915 | 0.600915 | 0.00300457 | 0.00300457 | 1.08889 | 0.167522 | 0.167522 | 1.17 | 0.00499997 | 0.00584996 | 0.000837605 | 0.000837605 | 1.06387 | 0.163672 | 0.163672 | 0.00585001 | 0.00081836 | 0.00081836 | 2.55884 | 0.236996 | 0.236996 | 0.0117 | 0.00196834 | 0.00196834

# IfcWall: FNDE-AL09-I5-I8 (azul-cinza) 150 x 3100 (5)
In: TÉRREO
Classification: Parede (Classificação Archicad); Material: TIJOLO - CERAMICO 9x19x39 - espessura 15cm, EI-REV-Chapisco (interno) (2), EI-REV-Pintura Acrílica Cor Cinza, EI-REV-Massa única - Maior que 10m² (2), EI-REV-Massa Corrida PVA (interna) (2), EI-REV-Pintura Acrílica Cor Branco Gelo (2), EI-REV-Cerâmica 30x40, EI-REV-Cerâmica 10x10 Azul, EI-REV-Emboço Interno
FNDE - Alvenarias: Alvenaria de Vedação / Edificação; Sistemas de Cobertura: -; Esquadrias - Fechamentos metálicos e Gradis: -; 0_ID: AL09
Pset_WallCommon - IsExternal: no; LoadBearing: no
Component Quantities - TIJOLO - CERAMICO 9x19x39 - espessura 15cm, Altura do Componente Retangular: 3.1 m; TIJOLO - CERAMICO 9x19x39 - espessura 15cm, Largura do Componente Retangular: 0.09 m; TIJOLO - CERAMICO 9x19x39 - espessura 15cm, Área de Seção Transversal do Componente: 0.279 m2; EI-REV-Chapisco (interno) 1, Altura do Componente Retangular: 3.1 m; EI-REV-Chapisco (interno) 1, Largura do Componente Retangular: 0.005 m; EI-REV-Chapisco (interno) 1, Área de Seção Transversal do Componente: 0.0155 m2; EI-REV-Pintura Acrílica Cor Cinza, Altura do Componente Retangular: 0.44 m; EI-REV-Pintura Acrílica Cor Cinza, Largura do Componente Retangular: 0.01 m; EI-REV-Pintura Acrílica Cor Cinza, Área de Seção Transversal do Componente: 0.0044 m2; EI-REV-Massa única - Maior que 10m² 1, Altura do Componente Retangular: 3.1 m; EI-REV-Massa única - Maior que 10m² 1, Largura do Componente Retangular: 0.01 m; EI-REV-Massa única - Maior que 10m² 1, Área de Seção Transversal do Componente: 0.031 m2; EI-REV-Pintura Acrílica Cor Branco Gelo 1, Altura do Componente Retangular: 2.66 m; EI-REV-Pintura Acrílica Cor Branco Gelo 1, Largura do Componente Retangular: 0.01 m; EI-REV-Pintura Acrílica Cor Branco Gelo 1, Área de Seção Transversal do Componente: 0.0266 m2; EI-REV-Chapisco (interno) 2, Altura do Componente Retangular: 3.1 m; EI-REV-Chapisco (interno) 2, Largura do Componente Retangular: 0.005 m; EI-REV-Chapisco (interno) 2, Área de Seção Transversal do Componente: 0.0155 m2; EI-REV-Cerâmica 30x40, Altura do Componente Retangular: 1.8 m; EI-REV-Cerâmica 30x40, Largura do Componente Retangular: 0.02 m; EI-REV-Cerâmica 30x40, Área de Seção Transversal do Componente: 0.036 m2; EI-REV-Cerâmica 10x10 Azul, Altura do Componente Retangular: 0.1 m; EI-REV-Cerâmica 10x10 Azul, Largura do Componente Retangular: 0.02 m; EI-REV-Cerâmica 10x10 Azul, Área de Seção Transversal do Componente: 0.002 m2; EI-REV-Massa única - Maior que 10m² 2, Altura do Componente Retangular: 1.17 m; EI-REV-Massa única - Maior que 10m² 2, Largura do Componente Retangular: 0.00499997 m; EI-REV-Massa única - Maior que 10m² 2, Área de Seção Transversal do Componente: 0.00584996 m2; EI-REV-Massa Corrida PVA (interna) 2, Altura do Componente Retangular: 1.17 m; EI-REV-Massa Corrida PVA (interna) 2, Largura do Componente Retangular: 0.005 m; EI-REV-Massa Corrida PVA (interna) 2, Área de Seção Transversal do Componente: 0.00585001 m2; EI-REV-Pintura Acrílica Cor Branco Gelo 2, Altura do Componente Retangular: 1.17 m; EI-REV-Pintura Acrílica Cor Branco Gelo 2, Largura do Componente Retangular: 0.01 m; EI-REV-Pintura Acrílica Cor Branco Gelo 2, Área de Seção Transversal do Componente: 0.0117 m2
Name | 1_Bloco | TIJOLO - CERAMICO 9x19x39 - espessura 15cm, Massa (kg) | TIJOLO - CERAMICO 9x19x39 - espessura 15cm, Área de Componente Projetada (Líquida) (m2) | TIJOLO - CERAMICO 9x19x39 - espessura 15cm, Área de Componente Projetada (Bruta) (m2) | TIJOLO - CERAMICO 9x19x39 - espessura 15cm, Volume Componente (Líquido) (m3) | TIJOLO - CERAMICO 9x19x39 - espessura 15cm, Volume do componente (Bruto) (m3) | EI-REV-Chapisco (interno) 1, Massa (kg) | EI-REV-Chapisco (interno) 1, Área de Componente Projetada (Líquida) (m2) | EI-REV-Chapisco (interno) 1, Área de Componente Projetada (Bruta) (m2) | EI-REV-Chapisco (interno) 1, Volume Componente (Líquido) (m3) | EI-REV-Chapisco (interno) 1, Volume do componente (Bruto) (m3) | EI-REV-Pintura Acrílica Cor Cinza, Massa (kg) | EI-REV-Pintura Acrílica Cor Cinza, Área de Componente Projetada (Líquida) (m2) = EI-REV-Pintura Acrílica Cor Cinza, Área de Componente Projetada (Bruta) (m2) | EI-REV-Pintura Acrílica Cor Cinza, Volume Componente (Líquido) (m3) = EI-REV-Pintura Acrílica Cor Cinza, Volume do componente (Bruto) (m3) | EI-REV-Massa única - Maior que 10m² 1, Massa (kg) | EI-REV-Massa única - Maior que 10m² 1, Área de Componente Projetada (Líquida) (m2) | EI-REV-Massa única - Maior que 10m² 1, Área de Componente Projetada (Bruta) (m2) | EI-REV-Massa única - Maior que 10m² 1, Volume Componente (Líquido) (m3) | EI-REV-Massa única - Maior que 10m² 1, Volume do componente (Bruto) (m3) | EI-REV-Massa Corrida PVA (interna) 1, Massa (kg) | EI-REV-Massa Corrida PVA (interna) 1, Área de Componente Projetada (Líquida) (m2) | EI-REV-Massa Corrida PVA (interna) 1, Área de Componente Projetada (Bruta) (m2) | EI-REV-Massa Corrida PVA (interna) 1, Altura do Componente Retangular (m) | EI-REV-Massa Corrida PVA (interna) 1, Largura do Componente Retangular (m) | EI-REV-Massa Corrida PVA (interna) 1, Área de Seção Transversal do Componente (m2) | EI-REV-Massa Corrida PVA (interna) 1, Volume Componente (Líquido) (m3) | EI-REV-Massa Corrida PVA (interna) 1, Volume do componente (Bruto) (m3) | EI-REV-Pintura Acrílica Cor Branco Gelo 1, Massa (kg) | EI-REV-Pintura Acrílica Cor Branco Gelo 1, Área de Componente Projetada (Líquida) (m2) | EI-REV-Pintura Acrílica Cor Branco Gelo 1, Área de Componente Projetada (Bruta) (m2) | EI-REV-Pintura Acrílica Cor Branco Gelo 1, Volume Componente (Líquido) (m3) | EI-REV-Pintura Acrílica Cor Branco Gelo 1, Volume do componente (Bruto) (m3) | EI-REV-Chapisco (interno) 2, Massa (kg) | EI-REV-Chapisco (interno) 2, Área de Componente Projetada (Líquida) (m2) | EI-REV-Chapisco (interno) 2, Área de Componente Projetada (Bruta) (m2) | EI-REV-Chapisco (interno) 2, Volume Componente (Líquido) (m3) | EI-REV-Chapisco (interno) 2, Volume do componente (Bruto) (m3) | EI-REV-Cerâmica 30x40, Massa (kg) | EI-REV-Cerâmica 30x40, Área de Componente Projetada (Líquida) (m2) = EI-REV-Cerâmica 30x40, Área de Componente Projetada (Bruta) (m2) | EI-REV-Cerâmica 30x40, Volume Componente (Líquido) (m3) = EI-REV-Cerâmica 30x40, Volume do componente (Bruto) (m3) | EI-REV-Cerâmica 10x10 Azul, Massa (kg) | EI-REV-Cerâmica 10x10 Azul, Área de Componente Projetada (Líquida) (m2) = EI-REV-Cerâmica 10x10 Azul, Área de Componente Projetada (Bruta) (m2) | EI-REV-Cerâmica 10x10 Azul, Volume Componente (Líquido) (m3) = EI-REV-Cerâmica 10x10 Azul, Volume do componente (Bruto) (m3) | EI-REV-Emboço Interno, Massa (kg) | EI-REV-Emboço Interno, Área de Componente Projetada (Líquida) (m2) | EI-REV-Emboço Interno, Área de Componente Projetada (Bruta) (m2) | EI-REV-Emboço Interno, Altura do Componente Retangular (m) | EI-REV-Emboço Interno, Largura do Componente Retangular (m) | EI-REV-Emboço Interno, Área de Seção Transversal do Componente (m2) | EI-REV-Emboço Interno, Volume Componente (Líquido) (m3) | EI-REV-Emboço Interno, Volume do componente (Bruto) (m3) | EI-REV-Massa única - Maior que 10m² 2, Massa (kg) | EI-REV-Massa única - Maior que 10m² 2, Área de Componente Projetada (Líquida) (m2) | EI-REV-Massa única - Maior que 10m² 2, Área de Componente Projetada (Bruta) (m2) | EI-REV-Massa única - Maior que 10m² 2, Volume Componente (Líquido) (m3) | EI-REV-Massa única - Maior que 10m² 2, Volume do componente (Bruto) (m3) | EI-REV-Massa Corrida PVA (interna) 2, Massa (kg) | EI-REV-Massa Corrida PVA (interna) 2, Área de Componente Projetada (Líquida) (m2) | EI-REV-Massa Corrida PVA (interna) 2, Área de Componente Projetada (Bruta) (m2) | EI-REV-Massa Corrida PVA (interna) 2, Volume Componente (Líquido) (m3) | EI-REV-Massa Corrida PVA (interna) 2, Volume do componente (Bruto) (m3) | EI-REV-Pintura Acrílica Cor Branco Gelo 2, Massa (kg) | EI-REV-Pintura Acrílica Cor Branco Gelo 2, Área de Componente Projetada (Líquida) (m2) | EI-REV-Pintura Acrílica Cor Branco Gelo 2, Área de Componente Projetada (Bruta) (m2) | EI-REV-Pintura Acrílica Cor Branco Gelo 2, Volume Componente (Líquido) (m3) | EI-REV-Pintura Acrílica Cor Branco Gelo 2, Volume do componente (Bruto) (m3)
AL09 | BLOCO B | 355.333 | 6.09282 | 7.66782 | 0.548354 | 0.690104 | 39.7788 | 6.11982 | 7.69482 | 0.0305991 | 0.0384741 | 15.4566 | 1.18897 | 0.0118897 | 80.2596 | 6.17382 | 7.74882 | 0.0617382 | 0.0774882 | 40.0911 | 6.20082 | 7.77582 | 3.1 | 0.005 | 0.0155 | 0.0308393 | 0.0387143 | 75.1527 | 6.13882 | 7.71382 | 0.0578098 | 0.0735598 | 34.532 | 5.31262 | 6.88762 | 0.0265631 | 0.0344381 | 179.511 | 4.48778 | 0.0897555 | 10.5597 | 0.263993 | 0.00527987 | 34.3666 | 5.28717 | 6.86217 | 3.1 | 0.005 | 0.0155 | 0.0264359 | 0.0343109 | 2.97535 | 0.457748 | 2.03275 | 0.00228873 | 0.0101637 | 2.92532 | 0.450048 | 2.02505 | 0.00225024 | 0.0101253 | 9.95181 | 1.48631 | 3.06131 | 0.00765523 | 0.0234052
AL09 | BLOCO B | 25.1982 | 0.432068 | 0.432068 | 0.0388861 | 0.0388861 | 4.30019 | 0.661568 | 0.661568 | 0.00330784 | 0.00330784 | 1.27931 | 0.0984103 | 0.000984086 | 8.42488 | 0.648068 | 0.648068 | 0.00648068 | 0.00648068 |  |  |  |  |  |  |  |  | 7.67619 | 0.638467 | 0.638467 | 0.00590476 | 0.00590476 | 0.379005 | 0.0583085 | 0.0583085 | 0.000291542 | 0.000291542 | 0.00146528 | 0.0000366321 | 7.32641e-07 | 0.000100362 | 0.00000250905 | 5.01809e-08 | 0.30328 | 0.0466585 | 0.0466585 | 3.1 | 0.005 | 0.0155 | 0.000233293 | 0.000233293 | 0.0752007 | 0.0115693 | 0.0115693 | 0.0000578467 | 0.0000578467 | 0.0501757 | 0.00771933 | 0.00771933 | 0.0000385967 | 0.0000385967 | 2.96348 | 0.274979 | 0.274979 | 0.0022796 | 0.0022796 | Component Quantities - EI-REV-Chapisco (interno) 1: 2 with these values
AL09 | BLOCO A | 312.143 | 5.35224 | 6.92724 | 0.481701 | 0.623451 | 34.8773 | 5.36574 | 6.94074 | 0.0268287 | 0.0347037 | 15.7249 | 1.276 | 0.0120961 | 70.1056 | 5.39274 | 6.96774 | 0.0539274 | 0.0696774 | 35.1406 | 5.40624 | 6.98124 | 3.1 | 0.005 | 0.0155 | 0.0270312 | 0.0349062 | 67.8075 | 6.13899 | 7.71399 | 0.0521596 | 0.0679096 | 33.2101 | 5.10924 | 6.68424 | 0.0255462 | 0.0334212 | 180.666 | 4.752 | 0.0903331 | 10.038 | 0.264 | 0.00501898 | 33.1223 | 5.09574 | 6.67074 | 3.1 | 0.005 | 0.0155 | 0.0254787 | 0.0333537 | 2.10304 | 0.323546 | 1.89855 | 0.00161772 | 0.00949267 | 2.07803 | 0.319696 | 1.8947 | 0.00159848 | 0.00947349 | 11.7615 | 1.48664 | 3.06164 | 0.00904729 | 0.0247973
AL09 | BLOCO A | 21.2664 | 0.36465 | 0.36465 | 0.0328185 | 0.0328185 | 2.28247 | 0.35115 | 0.35115 | 0.00175575 | 0.00175575 | 0.937215 | 0.105611 | 0.000720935 | 4.21395 | 0.32415 | 0.32415 | 0.0032415 | 0.0032415 | 2.01922 | 0.31065 | 0.31065 | 3.1 | 0.005 | 0.0155 | 0.00155325 | 0.00155325 | 5.35466 | 0.638468 | 0.638468 | 0.00411897 | 0.00411897 | 0.0885972 | 0.013631 | 0.013631 | 0.0000681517 | 0.0000681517 | 0.00149982 | 0.0000374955 | 7.49909e-07 | 0.000102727 | 0.00000256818 | 5.13636e-08 | 0.0886015 | 0.013631 | 0.013631 | 3.1 | 0.005 | 0.0155 | 0.000068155 | 0.000068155 | 0.0253025 | 0.0038927 | 0.0038927 | 0.0000194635 | 0.0000194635 | 0.0253026 | 0.0038927 | 0.0038927 | 0.0000194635 | 0.0000194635 | 3.04238 | 0.27498 | 0.27498 | 0.00234029 | 0.00234029
AL09 | BLOCO A | 154.422 | 2.64783 | 2.64783 | 0.238305 | 0.238305 | 17.0354 | 2.62083 | 2.62083 | 0.0131042 | 0.0131042 | 5.43789 | 0.418299 | 0.00418299 | 34.0708 | 2.62083 | 2.62083 | 0.0262083 | 0.0262083 | 16.9477 | 2.60733 | 2.60733 | 3.1 | 0.005 | 0.0155 | 0.0130367 | 0.0130367 | 30.3878 | 2.52881 | 2.52881 | 0.0233752 | 0.0233752 | 19.6679 | 3.02583 | 3.02583 | 0.0151292 | 0.0151292 | 80.6889 | 2.01722 | 0.0403444 | 4.48272 | 0.112068 | 0.00224136 |  |  |  |  |  |  |  |  | 5.60897 | 0.862923 | 0.862923 | 0.00431459 | 0.00431459 | 5.609 | 0.862923 | 0.862923 | 0.00431462 | 0.00431462 | 14.1494 | 1.31119 | 1.31119 | 0.0108841 | 0.0108841 | Component Quantities - EI-REV-Chapisco (interno) 2: 2 with these values

# IfcWall: FNDE-AL09-I5-I8 (vermelho-cinza) 150 x 3100 (5)
In: TÉRREO
Classification: Parede (Classificação Archicad); Material: TIJOLO - CERAMICO 9x19x39 - espessura 15cm, EI-REV-Chapisco (interno) (2), EI-REV-Pintura Acrílica Cor Cinza, EI-REV-Massa única - Maior que 10m² (2), EI-REV-Massa Corrida PVA (interna) (2), EI-REV-Pintura Acrílica Cor Branco Gelo (2), EI-REV-Cerâmica 30x40, EI-REV-Cerâmica 10x10 Vermelha, EI-REV-Emboço Interno
FNDE - Alvenarias: Alvenaria de Vedação / Edificação; Sistemas de Cobertura: -; Esquadrias - Fechamentos metálicos e Gradis: -; 0_ID: AL09
Pset_WallCommon - IsExternal: no; LoadBearing: no
Component Quantities - TIJOLO - CERAMICO 9x19x39 - espessura 15cm, Altura do Componente Retangular: 3.1 m; TIJOLO - CERAMICO 9x19x39 - espessura 15cm, Largura do Componente Retangular: 0.09 m; TIJOLO - CERAMICO 9x19x39 - espessura 15cm, Área de Seção Transversal do Componente: 0.279 m2; EI-REV-Chapisco (interno) 1, Altura do Componente Retangular: 3.1 m; EI-REV-Chapisco (interno) 1, Largura do Componente Retangular: 0.005 m; EI-REV-Chapisco (interno) 1, Área de Seção Transversal do Componente: 0.0155 m2; EI-REV-Pintura Acrílica Cor Cinza, Altura do Componente Retangular: 0.44 m; EI-REV-Pintura Acrílica Cor Cinza, Largura do Componente Retangular: 0.01 m; EI-REV-Pintura Acrílica Cor Cinza, Área de Seção Transversal do Componente: 0.0044 m2; EI-REV-Massa única - Maior que 10m² 1, Altura do Componente Retangular: 3.1 m; EI-REV-Massa única - Maior que 10m² 1, Largura do Componente Retangular: 0.01 m; EI-REV-Massa única - Maior que 10m² 1, Área de Seção Transversal do Componente: 0.031 m2; EI-REV-Pintura Acrílica Cor Branco Gelo 1, Altura do Componente Retangular: 2.66 m; EI-REV-Pintura Acrílica Cor Branco Gelo 1, Largura do Componente Retangular: 0.01 m; EI-REV-Pintura Acrílica Cor Branco Gelo 1, Área de Seção Transversal do Componente: 0.0266 m2; EI-REV-Chapisco (interno) 2, Altura do Componente Retangular: 3.1 m; EI-REV-Chapisco (interno) 2, Largura do Componente Retangular: 0.005 m; EI-REV-Chapisco (interno) 2, Área de Seção Transversal do Componente: 0.0155 m2; EI-REV-Cerâmica 30x40, Altura do Componente Retangular: 1.8 m; EI-REV-Cerâmica 30x40, Largura do Componente Retangular: 0.02 m; EI-REV-Cerâmica 30x40, Área de Seção Transversal do Componente: 0.036 m2; EI-REV-Cerâmica 10x10 Vermelha, Altura do Componente Retangular: 0.1 m; EI-REV-Cerâmica 10x10 Vermelha, Largura do Componente Retangular: 0.02 m; EI-REV-Cerâmica 10x10 Vermelha, Área de Seção Transversal do Componente: 0.002 m2; EI-REV-Emboço Interno, Altura do Componente Retangular: 3.1 m; EI-REV-Emboço Interno, Largura do Componente Retangular: 0.005 m; EI-REV-Emboço Interno, Área de Seção Transversal do Componente: 0.0155 m2; EI-REV-Massa única - Maior que 10m² 2, Altura do Componente Retangular: 1.17 m; EI-REV-Massa única - Maior que 10m² 2, Largura do Componente Retangular: 0.00499997 m; EI-REV-Massa única - Maior que 10m² 2, Área de Seção Transversal do Componente: 0.00584996 m2; EI-REV-Massa Corrida PVA (interna) 2, Altura do Componente Retangular: 1.17 m; EI-REV-Massa Corrida PVA (interna) 2, Largura do Componente Retangular: 0.005 m; EI-REV-Massa Corrida PVA (interna) 2, Área de Seção Transversal do Componente: 0.00585001 m2; EI-REV-Pintura Acrílica Cor Branco Gelo 2, Altura do Componente Retangular: 1.17 m; EI-REV-Pintura Acrílica Cor Branco Gelo 2, Largura do Componente Retangular: 0.01 m; EI-REV-Pintura Acrílica Cor Branco Gelo 2, Área de Seção Transversal do Componente: 0.0117 m2
Name | 1_Bloco | TIJOLO - CERAMICO 9x19x39 - espessura 15cm, Massa (kg) | TIJOLO - CERAMICO 9x19x39 - espessura 15cm, Área de Componente Projetada (Líquida) (m2) | TIJOLO - CERAMICO 9x19x39 - espessura 15cm, Área de Componente Projetada (Bruta) (m2) | TIJOLO - CERAMICO 9x19x39 - espessura 15cm, Volume Componente (Líquido) (m3) | TIJOLO - CERAMICO 9x19x39 - espessura 15cm, Volume do componente (Bruto) (m3) | EI-REV-Chapisco (interno) 1, Massa (kg) | EI-REV-Chapisco (interno) 1, Área de Componente Projetada (Líquida) (m2) | EI-REV-Chapisco (interno) 1, Área de Componente Projetada (Bruta) (m2) | EI-REV-Chapisco (interno) 1, Volume Componente (Líquido) (m3) | EI-REV-Chapisco (interno) 1, Volume do componente (Bruto) (m3) | EI-REV-Pintura Acrílica Cor Cinza, Massa (kg) | EI-REV-Pintura Acrílica Cor Cinza, Área de Componente Projetada (Líquida) (m2) = EI-REV-Pintura Acrílica Cor Cinza, Área de Componente Projetada (Bruta) (m2) | EI-REV-Pintura Acrílica Cor Cinza, Volume Componente (Líquido) (m3) = EI-REV-Pintura Acrílica Cor Cinza, Volume do componente (Bruto) (m3) | EI-REV-Massa única - Maior que 10m² 1, Massa (kg) | EI-REV-Massa única - Maior que 10m² 1, Área de Componente Projetada (Líquida) (m2) | EI-REV-Massa única - Maior que 10m² 1, Área de Componente Projetada (Bruta) (m2) | EI-REV-Massa única - Maior que 10m² 1, Volume Componente (Líquido) (m3) | EI-REV-Massa única - Maior que 10m² 1, Volume do componente (Bruto) (m3) | EI-REV-Massa Corrida PVA (interna) 1, Massa (kg) | EI-REV-Massa Corrida PVA (interna) 1, Área de Componente Projetada (Líquida) (m2) | EI-REV-Massa Corrida PVA (interna) 1, Área de Componente Projetada (Bruta) (m2) | EI-REV-Massa Corrida PVA (interna) 1, Altura do Componente Retangular (m) | EI-REV-Massa Corrida PVA (interna) 1, Largura do Componente Retangular (m) | EI-REV-Massa Corrida PVA (interna) 1, Área de Seção Transversal do Componente (m2) | EI-REV-Massa Corrida PVA (interna) 1, Volume Componente (Líquido) (m3) | EI-REV-Massa Corrida PVA (interna) 1, Volume do componente (Bruto) (m3) | EI-REV-Pintura Acrílica Cor Branco Gelo 1, Massa (kg) | EI-REV-Pintura Acrílica Cor Branco Gelo 1, Área de Componente Projetada (Líquida) (m2) | EI-REV-Pintura Acrílica Cor Branco Gelo 1, Área de Componente Projetada (Bruta) (m2) | EI-REV-Pintura Acrílica Cor Branco Gelo 1, Volume Componente (Líquido) (m3) | EI-REV-Pintura Acrílica Cor Branco Gelo 1, Volume do componente (Bruto) (m3) | EI-REV-Chapisco (interno) 2, Massa (kg) | EI-REV-Chapisco (interno) 2, Área de Componente Projetada (Líquida) (m2) | EI-REV-Chapisco (interno) 2, Área de Componente Projetada (Bruta) (m2) | EI-REV-Chapisco (interno) 2, Volume Componente (Líquido) (m3) | EI-REV-Chapisco (interno) 2, Volume do componente (Bruto) (m3) | EI-REV-Cerâmica 30x40, Massa (kg) | EI-REV-Cerâmica 30x40, Área de Componente Projetada (Líquida) (m2) = EI-REV-Cerâmica 30x40, Área de Componente Projetada (Bruta) (m2) | EI-REV-Cerâmica 30x40, Volume Componente (Líquido) (m3) = EI-REV-Cerâmica 30x40, Volume do componente (Bruto) (m3) | EI-REV-Cerâmica 10x10 Vermelha, Massa (kg) | EI-REV-Cerâmica 10x10 Vermelha, Área de Componente Projetada (Líquida) (m2) = EI-REV-Cerâmica 10x10 Vermelha, Área de Componente Projetada (Bruta) (m2) | EI-REV-Cerâmica 10x10 Vermelha, Volume Componente (Líquido) (m3) = EI-REV-Cerâmica 10x10 Vermelha, Volume do componente (Bruto) (m3) | EI-REV-Emboço Interno, Massa (kg) | EI-REV-Emboço Interno, Área de Componente Projetada (Líquida) (m2) | EI-REV-Emboço Interno, Área de Componente Projetada (Bruta) (m2) | EI-REV-Emboço Interno, Volume Componente (Líquido) (m3) | EI-REV-Emboço Interno, Volume do componente (Bruto) (m3) | EI-REV-Massa única - Maior que 10m² 2, Massa (kg) | EI-REV-Massa única - Maior que 10m² 2, Área de Componente Projetada (Líquida) (m2) | EI-REV-Massa única - Maior que 10m² 2, Área de Componente Projetada (Bruta) (m2) | EI-REV-Massa única - Maior que 10m² 2, Volume Componente (Líquido) (m3) | EI-REV-Massa única - Maior que 10m² 2, Volume do componente (Bruto) (m3) | EI-REV-Massa Corrida PVA (interna) 2, Massa (kg) | EI-REV-Massa Corrida PVA (interna) 2, Área de Componente Projetada (Líquida) (m2) | EI-REV-Massa Corrida PVA (interna) 2, Área de Componente Projetada (Bruta) (m2) | EI-REV-Massa Corrida PVA (interna) 2, Volume Componente (Líquido) (m3) | EI-REV-Massa Corrida PVA (interna) 2, Volume do componente (Bruto) (m3) | EI-REV-Pintura Acrílica Cor Branco Gelo 2, Massa (kg) | EI-REV-Pintura Acrílica Cor Branco Gelo 2, Área de Componente Projetada (Líquida) (m2) | EI-REV-Pintura Acrílica Cor Branco Gelo 2, Área de Componente Projetada (Bruta) (m2) | EI-REV-Pintura Acrílica Cor Branco Gelo 2, Volume Componente (Líquido) (m3) | EI-REV-Pintura Acrílica Cor Branco Gelo 2, Volume do componente (Bruto) (m3)
AL09 | BLOCO B | 341.172 | 5.85 | 7.425 | 0.5265 | 0.66825 | 39.6923 | 6.1065 | 7.6815 | 0.0305325 | 0.0384075 | 15.4037 | 1.1849 | 0.011849 | 79.911 | 6.147 | 7.722 | 0.06147 | 0.07722 | 40.2675 | 6.29345 | 7.86845 | 3.1 | 0.005 | 0.0155 | 0.030975 | 0.03885 | 68.5073 | 6.1124 | 7.6874 | 0.0526979 | 0.0684479 | 34.4667 | 5.5935 | 7.1685 | 0.0265129 | 0.0343879 | 178.346 | 4.45865 | 0.089173 | 10.48 | 0.262 | 0.00524 | 34.2918 | 5.27566 | 6.85066 | 0.0263783 | 0.0342533 | 2.95066 | 0.45395 | 2.02895 | 0.00226974 | 0.0101447 | 2.90063 | 0.44625 | 2.02125 | 0.00223125 | 0.0101063 | 16.584 | 1.47674 | 3.05174 | 0.0127569 | 0.0285069
AL09 | BLOCO B | 25.1982 | 0.432068 | 0.432068 | 0.0388861 | 0.0388861 | 4.30019 | 0.661568 | 0.661568 | 0.00330784 | 0.00330784 | 1.27995 | 0.105554 | 0.000984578 | 8.42488 | 0.648068 | 0.648068 | 0.00648068 | 0.00648068 |  |  |  |  |  |  |  |  | 7.67993 | 0.638467 | 0.638467 | 0.00590764 | 0.00590764 | 0.482091 | 0.0741678 | 0.0741678 | 0.000370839 | 0.000370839 | 0.00180651 | 0.0000451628 | 9.03257e-07 | 0.000100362 | 0.00000250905 | 5.01809e-08 | 0.395317 | 0.0608178 | 0.0608178 | 0.00030409 | 0.00030409 | 0.0752007 | 0.0115693 | 0.0115693 | 0.0000578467 | 0.0000578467 | 0.0501757 | 0.00771933 | 0.00771933 | 0.0000385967 | 0.0000385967 | 2.95982 | 0.274979 | 0.274979 | 0.00227678 | 0.00227678 | Component Quantities - EI-REV-Chapisco (interno) 1: 2 with these values
AL09 | BLOCO B | 25.1942 | 0.432 | 0.432 | 0.03888 | 0.03888 | 4.29975 | 0.6615 | 0.6615 | 0.0033075 | 0.0033075 | 1.27925 | 0.0984 | 0.000984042 | 8.424 | 0.648 | 0.648 | 0.00648 | 0.00648 |  |  |  |  |  |  |  |  | 7.66774 | 0.6384 | 0.6384 | 0.00589826 | 0.00589826 | 0.48165 | 0.0741 | 0.0741 | 0.0003705 | 0.0003705 | 0 | 0 | 0 | 0 | 0 | 0 | 0.394877 | 0.06075 | 0.06075 | 0.000303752 | 0.000303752 | 0.0750748 | 0.01155 | 0.01155 | 0.0000577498 | 0.0000577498 | 0.05005 | 0.00769999 | 0.00769999 | 0.0000385 | 0.0000385 | 2.97567 | 0.27495 | 0.27495 | 0.00228898 | 0.00228898 | Component Quantities - EI-REV-Chapisco (interno) 1: 2 with these values
AL09 | BLOCO B | 46.4519 | 0.7965 | 0.7965 | 0.071685 | 0.071685 | 4.47525 | 0.6885 | 0.6885 | 0.0034425 | 0.0034425 | 1.38574 | 0.1066 | 0.00106595 | 9.126 | 0.702 | 0.702 | 0.00702 | 0.00702 | 4.48021 | 0.689214 | 0.689214 | 3.1 | 0.005 | 0.0155 | 0.00344632 | 0.00344632 | 8.3375 | 0.690252 | 0.690252 | 0.00641346 | 0.00641346 | 3.10473 | 0.477659 | 0.477659 | 0.00238826 | 0.00238826 | 11.388 | 0.2847 | 0.005694 | 0.78 | 0.0195 | 0.00039 | 3.029 | 0.466 | 0.466 | 0.00233 | 0.00233 | 0.975969 | 0.15015 | 0.15015 | 0.000750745 | 0.000750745 | 0.950951 | 0.1463 | 0.1463 | 0.000731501 | 0.000731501 | 2.327 | 0.215678 | 0.215678 | 0.00179 | 0.00179
AL09 | BLOCO A | 8.65583 | 0.14842 | 0.14842 | 0.0133578 | 0.0133578 | 2.54423 | 0.39142 | 0.39142 | 0.0019571 | 0.0019571 | 1.16018 | 0.105611 | 0.000892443 | 5.26396 | 0.40492 | 0.40492 | 0.0040492 | 0.0040492 | 2.80748 | 0.43192 | 0.43192 | 3.1 | 0.005 | 0.0155 | 0.0021596 | 0.0021596 | 6.58864 | 0.638468 | 0.638468 | 0.00506819 | 0.00506819 | 1.37696 | 0.21184 | 0.21184 | 0.0010592 | 0.0010592 | 8.95435 | 0.630046 | 0.00447717 | 0.497464 | 0.0350026 | 0.000248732 | 1.28921 | 0.19834 | 0.19834 | 0.000991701 | 0.000991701 | 0.390595 | 0.060092 | 0.060092 | 0.000300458 | 0.000300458 | 0.365573 | 0.056242 | 0.056242 | 0.00028121 | 0.00028121 | 0.88008 | 0.11703 | 0.11703 | 0.000676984 | 0.000676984

# IfcWall: FNDE-AL09-I5-I8 (vermelho-cinza) 150 x 3640, AL09
In: TÉRREO
Classification: Parede (Classificação Archicad); Material: TIJOLO - CERAMICO 9x19x39 - espessura 15cm, EI-REV-Chapisco (interno) (2), EI-REV-Pintura Acrílica Cor Cinza, EI-REV-Massa única - Maior que 10m² (2), EI-REV-Massa Corrida PVA (interna) (2), EI-REV-Pintura Acrílica Cor Branco Gelo (2), EI-REV-Cerâmica 30x40, EI-REV-Cerâmica 10x10 Vermelha, EI-REV-Emboço Interno
FNDE - Alvenarias: Alvenaria de Vedação / Edificação; Sistemas de Cobertura: -; Esquadrias - Fechamentos metálicos e Gradis: -; 1_Bloco: BLOCO A; 0_ID: AL09
Pset_WallCommon - IsExternal: yes; LoadBearing: no
Component Quantities - TIJOLO - CERAMICO 9x19x39 - espessura 15cm, Massa: 228.295 kg; TIJOLO - CERAMICO 9x19x39 - espessura 15cm, Área de Componente Projetada (Líquida): 3.91475 m2; TIJOLO - CERAMICO 9x19x39 - espessura 15cm, Área de Componente Projetada (Bruta): 4.43975 m2; TIJOLO - CERAMICO 9x19x39 - espessura 15cm, Altura do Componente Retangular: 3.64 m; TIJOLO - CERAMICO 9x19x39 - espessura 15cm, Largura do Componente Retangular: 0.09 m; TIJOLO - CERAMICO 9x19x39 - espessura 15cm, Área de Seção Transversal do Componente: 0.3276 m2; TIJOLO - CERAMICO 9x19x39 - espessura 15cm, Volume Componente (Líquido): 0.352307 m3; TIJOLO - CERAMICO 9x19x39 - espessura 15cm, Volume do componente (Bruto): 0.399557 m3; EI-REV-Chapisco (interno) 1, Massa: 25.5641 kg; EI-REV-Chapisco (interno) 1, Área de Componente Projetada (Líquida): 3.93295 m2; EI-REV-Chapisco (interno) 1, Área de Componente Projetada (Bruta): 4.45795 m2; EI-REV-Chapisco (interno) 1, Altura do Componente Retangular: 3.64 m; EI-REV-Chapisco (interno) 1, Largura do Componente Retangular: 0.00499998 m; EI-REV-Chapisco (interno) 1, Área de Seção Transversal do Componente: 0.0181999 m2; EI-REV-Chapisco (interno) 1, Volume Componente (Líquido): 0.0196647 m3; EI-REV-Chapisco (interno) 1, Volume do componente (Bruto): 0.0222897 m3; EI-REV-Pintura Acrílica Cor Cinza, Massa: 10.0024 kg; EI-REV-Pintura Acrílica Cor Cinza, Área de Componente Projetada (Líquida): 0.83598 m2; EI-REV-Pintura Acrílica Cor Cinza, Área de Componente Projetada (Bruta): 0.83598 m2; EI-REV-Pintura Acrílica Cor Cinza, Altura do Componente Retangular: 0.44 m; EI-REV-Pintura Acrílica Cor Cinza, Largura do Componente Retangular: 0.01 m; EI-REV-Pintura Acrílica Cor Cinza, Área de Seção Transversal do Componente: 0.0044 m2; EI-REV-Pintura Acrílica Cor Cinza, Volume Componente (Líquido): 0.00769412 m3; EI-REV-Pintura Acrílica Cor Cinza, Volume do componente (Bruto): 0.00769412 m3; EI-REV-Massa única - Maior que 10m² 1, Massa: 51.0997 kg; EI-REV-Massa única - Maior que 10m² 1, Área de Componente Projetada (Líquida): 3.93295 m2; EI-REV-Massa única - Maior que 10m² 1, Área de Componente Projetada (Bruta): 4.45795 m2; EI-REV-Massa única - Maior que 10m² 1, Altura do Componente Retangular: 3.64 m; EI-REV-Massa única - Maior que 10m² 1, Largura do Componente Retangular: 0.01 m; EI-REV-Massa única - Maior que 10m² 1, Área de Seção Transversal do Componente: 0.0364 m2; EI-REV-Massa única - Maior que 10m² 1, Volume Componente (Líquido): 0.0393075 m3; EI-REV-Massa única - Maior que 10m² 1, Volume do componente (Bruto): 0.0445575 m3; EI-REV-Massa Corrida PVA (interna) 1, Massa: 30.8296 kg; EI-REV-Massa Corrida PVA (interna) 1, Área de Componente Projetada (Líquida): 4.75255 m2; EI-REV-Massa Corrida PVA (interna) 1, Área de Componente Projetada (Bruta): 5.27755 m2; EI-REV-Massa Corrida PVA (interna) 1, Altura do Componente Retangular: 3.64 m; EI-REV-Massa Corrida PVA (interna) 1, Largura do Componente Retangular: 0.00499998 m; EI-REV-Massa Corrida PVA (interna) 1, Área de Seção Transversal do Componente: 0.0181999 m2; EI-REV-Massa Corrida PVA (interna) 1, Volume Componente (Líquido): 0.0237151 m3; EI-REV-Massa Corrida PVA (interna) 1, Volume do componente (Bruto): 0.02634 m3; EI-REV-Pintura Acrílica Cor Branco Gelo 1, Massa: 62.4555 kg; EI-REV-Pintura Acrílica Cor Branco Gelo 1, Área de Componente Projetada (Líquida): 5.55458 m2; EI-REV-Pintura Acrílica Cor Branco Gelo 1, Área de Componente Projetada (Bruta): 6.07958 m2; EI-REV-Pintura Acrílica Cor Branco Gelo 1, Altura do Componente Retangular: 3.2 m; EI-REV-Pintura Acrílica Cor Branco Gelo 1, Largura do Componente Retangular: 0.01 m; EI-REV-Pintura Acrílica Cor Branco Gelo 1, Área de Seção Transversal do Componente: 0.032 m2; EI-REV-Pintura Acrílica Cor Branco Gelo 1, Volume Componente (Líquido): 0.0480427 m3; EI-REV-Pintura Acrílica Cor Branco Gelo 1, Volume do componente (Bruto): 0.0532927 m3; EI-REV-Chapisco (interno) 2, Massa: 19.7569 kg; EI-REV-Chapisco (interno) 2, Área de Componente Projetada (Líquida): 3.03955 m2; EI-REV-Chapisco (interno) 2, Área de Componente Projetada (Bruta): 3.56455 m2; EI-REV-Chapisco (interno) 2, Altura do Componente Retangular: 3.1 m; EI-REV-Chapisco (interno) 2, Largura do Componente Retangular: 0.00499995 m; EI-REV-Chapisco (interno) 2, Área de Seção Transversal do Componente: 0.0154999 m2; EI-REV-Chapisco (interno) 2, Volume Componente (Líquido): 0.0151976 m3; EI-REV-Chapisco (interno) 2, Volume do componente (Bruto): 0.0178226 m3; EI-REV-Cerâmica 30x40, Massa: 100.485 kg; EI-REV-Cerâmica 30x40, Área de Componente Projetada (Líquida): 2.91596 m2; EI-REV-Cerâmica 30x40, Área de Componente Projetada (Bruta): 2.91596 m2; EI-REV-Cerâmica 30x40, Altura do Componente Retangular: 1.8 m; EI-REV-Cerâmica 30x40, Largura do Componente Retangular: 0.02 m; EI-REV-Cerâmica 30x40, Área de Seção Transversal do Componente: 0.036 m2; EI-REV-Cerâmica 30x40, Volume Componente (Líquido): 0.0502424 m3; EI-REV-Cerâmica 30x40, Volume do componente (Bruto): 0.0502424 m3; EI-REV-Cerâmica 10x10 Vermelha, Massa: 5.58249 kg; EI-REV-Cerâmica 10x10 Vermelha, Área de Componente Projetada (Líquida): 0.161997 m2; EI-REV-Cerâmica 10x10 Vermelha, Área de Componente Projetada (Bruta): 0.161997 m2; EI-REV-Cerâmica 10x10 Vermelha, Altura do Componente Retangular: 0.1 m; EI-REV-Cerâmica 10x10 Vermelha, Largura do Componente Retangular: 0.02 m; EI-REV-Cerâmica 10x10 Vermelha, Área de Seção Transversal do Componente: 0.002 m2; EI-REV-Cerâmica 10x10 Vermelha, Volume Componente (Líquido): 0.00279125 m3; EI-REV-Cerâmica 10x10 Vermelha, Volume do componente (Bruto): 0.00279125 m3; EI-REV-Emboço Interno, Massa: 19.7571 kg; EI-REV-Emboço Interno, Área de Componente Projetada (Líquida): 3.03955 m2; EI-REV-Emboço Interno, Área de Componente Projetada (Bruta): 3.56455 m2; EI-REV-Emboço Interno, Altura do Componente Retangular: 3.1 m; EI-REV-Emboço Interno, Largura do Componente Retangular: 0.005 m; EI-REV-Emboço Interno, Área de Seção Transversal do Componente: 0.0155 m2; EI-REV-Emboço Interno, Volume Componente (Líquido): 0.0151978 m3; EI-REV-Emboço Interno, Volume do componente (Bruto): 0.0178228 m3; EI-REV-Massa única - Maior que 10m² 2, Massa: 3.19396 kg; EI-REV-Massa única - Maior que 10m² 2, Área de Componente Projetada (Líquida): 0.491381 m2; EI-REV-Massa única - Maior que 10m² 2, Área de Componente Projetada (Bruta): 1.01638 m2; EI-REV-Massa única - Maior que 10m² 2, Altura do Componente Retangular: 1.17 m; EI-REV-Massa única - Maior que 10m² 2, Largura do Componente Retangular: 0.00499997 m; EI-REV-Massa única - Maior que 10m² 2, Área de Seção Transversal do Componente: 0.00584996 m2; EI-REV-Massa única - Maior que 10m² 2, Volume Componente (Líquido): 0.00245689 m3; EI-REV-Massa única - Maior que 10m² 2, Volume do componente (Bruto): 0.00508187 m3; EI-REV-Massa Corrida PVA (interna) 2, Massa: 3.16895 kg; EI-REV-Massa Corrida PVA (interna) 2, Área de Componente Projetada (Líquida): 0.487531 m2; EI-REV-Massa Corrida PVA (interna) 2, Área de Componente Projetada (Bruta): 1.01253 m2; EI-REV-Massa Corrida PVA (interna) 2, Altura do Componente Retangular: 1.17 m; EI-REV-Massa Corrida PVA (interna) 2, Largura do Componente Retangular: 0.005 m; EI-REV-Massa Corrida PVA (interna) 2, Área de Seção Transversal do Componente: 0.00585001 m2; EI-REV-Massa Corrida PVA (interna) 2, Volume Componente (Líquido): 0.00243766 m3; EI-REV-Massa Corrida PVA (interna) 2, Volume do componente (Bruto): 0.00506266 m3; EI-REV-Pintura Acrílica Cor Branco Gelo 2, Massa: 12.0244 kg; EI-REV-Pintura Acrílica Cor Branco Gelo 2, Área de Componente Projetada (Líquida): 1.35867 m2; EI-REV-Pintura Acrílica Cor Branco Gelo 2, Área de Componente Projetada (Bruta): 1.88367 m2; EI-REV-Pintura Acrílica Cor Branco Gelo 2, Altura do Componente Retangular: 1.17 m; EI-REV-Pintura Acrílica Cor Branco Gelo 2, Largura do Componente Retangular: 0.01 m; EI-REV-Pintura Acrílica Cor Branco Gelo 2, Área de Seção Transversal do Componente: 0.0117 m2; EI-REV-Pintura Acrílica Cor Branco Gelo 2, Volume Componente (Líquido): 0.00924956 m3; EI-REV-Pintura Acrílica Cor Branco Gelo 2, Volume do componente (Bruto): 0.0144996 m3

# IfcWall: FNDE-AL09-I7 (amarela) 120 x 3100 (11)
In: TÉRREO
Classification: Parede (Classificação Archicad); Material: EI-REV-Cerâmica 10x10 Amarela, EI-REV-Chapisco (interno), EI-REV-Pintura Acrílica Cor Branco Gelo, EI-REV-Emboço Interno, EI-REV-Massa única - Maior que 10m², EI-REV-Massa Corrida PVA (interna), EI-REV-Cerâmica 10x10 Branca, TIJOLO - CERAMICO 9x19x39 - espessura 15cm
FNDE - Alvenarias: Alvenaria de Vedação / Edificação; Sistemas de Cobertura: -; Esquadrias - Fechamentos metálicos e Gradis: -; 0_ID: AL09
Pset_WallCommon - IsExternal: no; LoadBearing: no
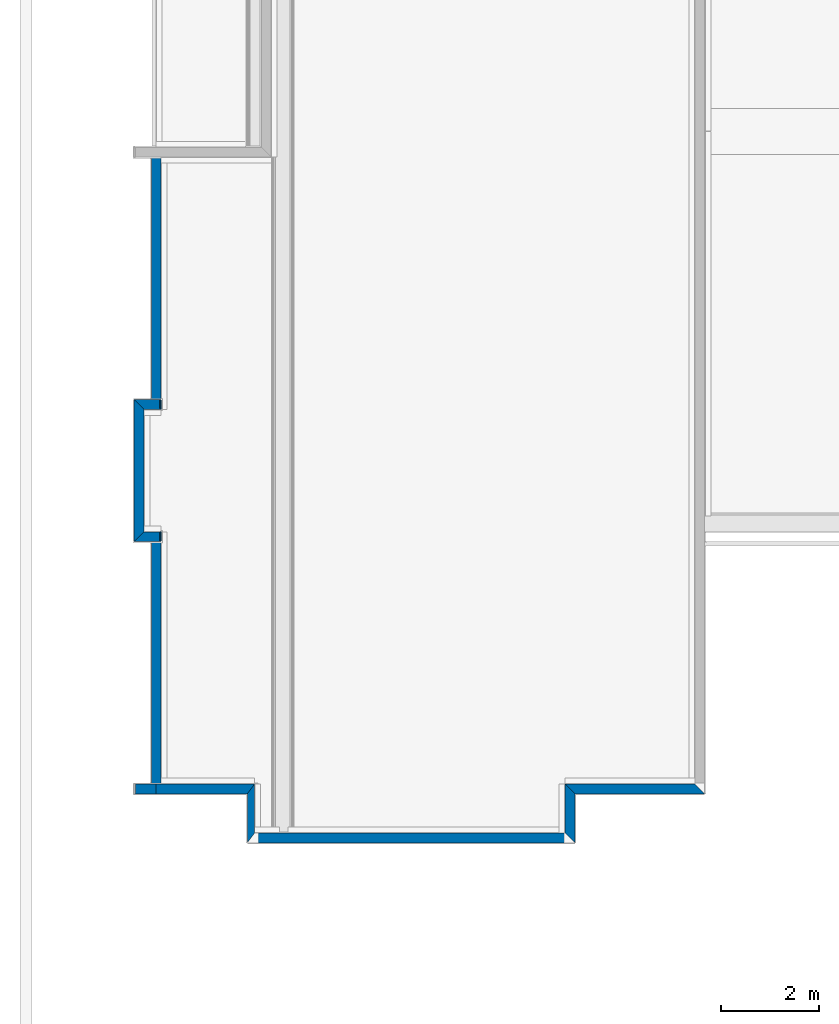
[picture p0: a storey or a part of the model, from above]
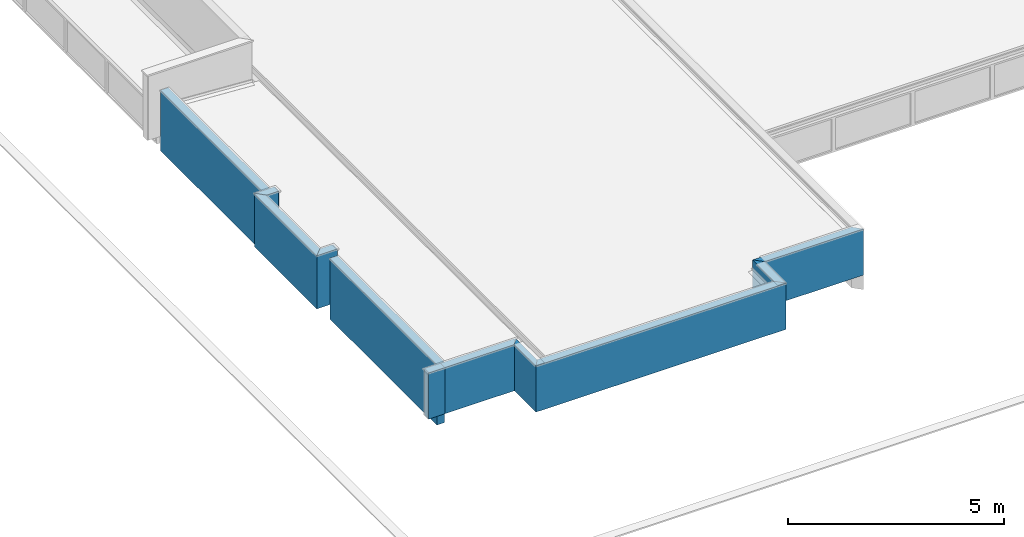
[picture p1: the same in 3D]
Properties of the parts of a building model (IFC4), part 16 of 22

# IfcWall: FNDE-AL09-I7 (amarela) 120 x 3100 (11)
Component Quantities - EI-REV-Cerâmica 10x10 Amarela, Altura do Componente Retangular: 0.9 m; EI-REV-Cerâmica 10x10 Amarela, Largura do Componente Retangular: 0.02 m; EI-REV-Cerâmica 10x10 Amarela, Área de Seção Transversal do Componente: 0.018 m2; EI-REV-Chapisco (interno), Altura do Componente Retangular: 3.1 m; EI-REV-Chapisco (interno), Largura do Componente Retangular: 0.005 m; EI-REV-Chapisco (interno), Área de Seção Transversal do Componente: 0.0155 m2; EI-REV-Pintura Acrílica Cor Branco Gelo, Altura do Componente Retangular: 2.06 m; EI-REV-Pintura Acrílica Cor Branco Gelo, Largura do Componente Retangular: 0.01 m; EI-REV-Pintura Acrílica Cor Branco Gelo, Área de Seção Transversal do Componente: 0.0206 m2; EI-REV-Emboço Interno, Área de Seção Transversal do Componente: 0.0155 m2; EI-REV-Massa única - Maior que 10m², Altura do Componente Retangular: 2.06 m; EI-REV-Massa única - Maior que 10m², Largura do Componente Retangular: 0.00500002 m; EI-REV-Massa única - Maior que 10m², Área de Seção Transversal do Componente: 0.0103 m2; EI-REV-Massa Corrida PVA (interna), Altura do Componente Retangular: 2.06 m; EI-REV-Massa Corrida PVA (interna), Largura do Componente Retangular: 0.00499999 m; EI-REV-Massa Corrida PVA (interna), Área de Seção Transversal do Componente: 0.0103 m2; EI-REV-Cerâmica 10x10 Branca, Altura do Componente Retangular: 0.1 m; EI-REV-Cerâmica 10x10 Branca, Largura do Componente Retangular: 0.02 m; EI-REV-Cerâmica 10x10 Branca, Área de Seção Transversal do Componente: 0.002 m2; TIJOLO - CERAMICO 9x19x39 - espessura 15cm, Altura do Componente Retangular: 3.1 m; TIJOLO - CERAMICO 9x19x39 - espessura 15cm, Largura do Componente Retangular: 0.09 m; TIJOLO - CERAMICO 9x19x39 - espessura 15cm, Área de Seção Transversal do Componente: 0.279 m2
Name | 1_Bloco | EI-REV-Cerâmica 10x10 Amarela, Massa (kg) | EI-REV-Cerâmica 10x10 Amarela, Área de Componente Projetada (Líquida) (m2) = EI-REV-Cerâmica 10x10 Amarela, Área de Componente Projetada (Bruta) (m2) | EI-REV-Cerâmica 10x10 Amarela, Volume Componente (Líquido) (m3) = EI-REV-Cerâmica 10x10 Amarela, Volume do componente (Bruto) (m3) | EI-REV-Chapisco (interno), Massa (kg) | EI-REV-Chapisco (interno), Área de Componente Projetada (Líquida) (m2) = EI-REV-Chapisco (interno), Área de Componente Projetada (Bruta) (m2) | EI-REV-Chapisco (interno), Volume Componente (Líquido) (m3) = EI-REV-Chapisco (interno), Volume do componente (Bruto) (m3) | EI-REV-Pintura Acrílica Cor Branco Gelo, Massa (kg) | EI-REV-Pintura Acrílica Cor Branco Gelo, Área de Componente Projetada (Líquida) (m2) = EI-REV-Pintura Acrílica Cor Branco Gelo, Área de Componente Projetada (Bruta) (m2) | EI-REV-Pintura Acrílica Cor Branco Gelo, Volume Componente (Líquido) (m3) = EI-REV-Pintura Acrílica Cor Branco Gelo, Volume do componente (Bruto) (m3) | EI-REV-Emboço Interno, Massa (kg) | EI-REV-Emboço Interno, Área de Componente Projetada (Líquida) (m2) = EI-REV-Emboço Interno, Área de Componente Projetada (Bruta) (m2) | EI-REV-Emboço Interno, Volume Componente (Líquido) (m3) = EI-REV-Emboço Interno, Volume do componente (Bruto) (m3) | EI-REV-Massa única - Maior que 10m², Massa (kg) | EI-REV-Massa única - Maior que 10m², Área de Componente Projetada (Líquida) (m2) = EI-REV-Massa única - Maior que 10m², Área de Componente Projetada (Bruta) (m2) | EI-REV-Massa única - Maior que 10m², Volume Componente (Líquido) (m3) = EI-REV-Massa única - Maior que 10m², Volume do componente (Bruto) (m3) | EI-REV-Massa Corrida PVA (interna), Massa (kg) | EI-REV-Massa Corrida PVA (interna), Área de Componente Projetada (Líquida) (m2) = EI-REV-Massa Corrida PVA (interna), Área de Componente Projetada (Bruta) (m2) | EI-REV-Massa Corrida PVA (interna), Volume Componente (Líquido) (m3) = EI-REV-Massa Corrida PVA (interna), Volume do componente (Bruto) (m3) | EI-REV-Cerâmica 10x10 Branca, Massa (kg) | EI-REV-Cerâmica 10x10 Branca, Área de Componente Projetada (Líquida) (m2) = EI-REV-Cerâmica 10x10 Branca, Área de Componente Projetada (Bruta) (m2) | EI-REV-Cerâmica 10x10 Branca, Volume Componente (Líquido) (m3) = EI-REV-Cerâmica 10x10 Branca, Volume do componente (Bruto) (m3) | TIJOLO - CERAMICO 9x19x39 - espessura 15cm, Massa (kg) | TIJOLO - CERAMICO 9x19x39 - espessura 15cm, Área de Componente Projetada (Líquida) (m2) = TIJOLO - CERAMICO 9x19x39 - espessura 15cm, Área de Componente Projetada (Bruta) (m2) | TIJOLO - CERAMICO 9x19x39 - espessura 15cm, Volume Componente (Líquido) (m3) = TIJOLO - CERAMICO 9x19x39 - espessura 15cm, Volume do componente (Bruto) (m3)
AL09 | BLOCO A | 18 | 0.45 | 0.009 | 8.16506 | 1.25616 | 0.00628081 | 13.6578 | 1.0506 | 0.010506 | 8.35355 | 1.28516 | 0.00642581 | 5.27115 | 0.9991 | 0.00405473 | 6.62803 | 1.0197 | 0.00509849 | 2 | 0.05 | 0.001 | 58.2617 | 0.999 | 0.08991
AL09 | BLOCO A | 72.0832 | 1.80208 | 0.0360416 | 36.338 | 5.59047 | 0.0279523 | 53.6216 | 4.12475 | 0.0412474 | 36.3348 | 5.58997 | 0.0279498 | 22.8802 | 4.12177 | 0.0176002 | 26.8012 | 4.12327 | 0.0206163 | 8.00925 | 0.200231 | 0.00400462 | 326.065 | 5.59097 | 0.503187
AL09 | BLOCO A | 20.0288 | 0.54 | 0.0100144 | 9.2143 | 1.41758 | 0.00708792 | 12.9907 | 1.236 | 0.00999281 | 9.30205 | 1.43108 | 0.00715542 | 5.77309 | 0.888165 | 0.00444084 | 5.84001 | 0.898465 | 0.00449231 | 2.22542 | 0.06 | 0.00111271 | 81.8862 | 1.40408 | 0.126368
AL09 | BLOCO B | 32.9261 | 0.823152 | 0.016463 | 15.8374 | 2.43653 | 0.0121827 | 22.7479 | 1.9047 | 0.0174984 | 16.0175 | 2.46423 | 0.0123211 | 10.2916 | 1.58332 | 0.00791664 | 10.4157 | 1.60242 | 0.00801208 | 3.65845 | 0.0914614 | 0.00182923 | 126.752 | 2.17338 | 0.195604
AL09 | BLOCO A | 12.6 | 0.315 | 0.00630001 | 6.40576 | 0.985501 | 0.00492751 | 9.64081 | 0.741601 | 0.00741601 | 7.31108 | 1.12564 | 0.00562391 | 4.86229 | 0.748043 | 0.00374023 | 4.87526 | 0.750042 | 0.0037502 | 1.4 | 0.035 | 0.000700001 | 44.09 | 0.756001 | 0.0680401
AL09 | BLOCO B | 17.64 | 0.441 | 0.00882 | 8.76525 | 1.3485 | 0.0067425 | 12.8544 | 0.9888 | 0.009888 | 8.96674 | 1.3795 | 0.00689749 | 6.15942 | 0.9476 | 0.00473802 | 6.29328 | 0.9682 | 0.00484099 | 1.96 | 0.049 | 0.00098 | 61.4693 | 1.054 | 0.09486
AL09 | BLOCO B | 12.96 | 0.324 | 0.00648 | 6.1999 | 0.95383 | 0.00476915 | 9.33554 | 0.718118 | 0.00718119 | 6.20347 | 0.95438 | 0.0047719 | 3.93563 | 0.60548 | 0.0030274 | 4.53791 | 0.705818 | 0.0034907 | 1.44 | 0.036 | 0.00072 | 68.9914 | 1.18298 | 0.106468
AL09 | BLOCO B | 12.24 | 0.306001 | 0.00612001 | 6.10988 | 0.939981 | 0.00469991 | 9.06776 | 0.69752 | 0.0069752 | 6.11345 | 0.940531 | 0.00470266 | 3.87913 | 0.596681 | 0.00298395 | 4.52087 | 0.69552 | 0.00347759 | 1.36 | 0.0340001 | 0.000680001 | 54.4523 | 0.933681 | 0.0840313
AL09 | BLOCO A | 41.4 | 1.035 | 0.0207 | 20.4085 | 3.4005 | 0.0156989 | 30.2351 | 2.32578 | 0.0232578 | 22.3047 | 3.4315 | 0.0171575 | 14.8337 | 2.2821 | 0.0114105 | 14.9675 | 2.3027 | 0.0115135 | 4.6 | 0.115 | 0.0023 | 160.613 | 2.754 | 0.24786
AL09 | BLOCO A | 12.6 | 0.315 | 0.00630001 | 5.79151 | 0.891001 | 0.004455 | 9.90861 | 0.762201 | 0.00762201 | 5.96701 | 0.918001 | 0.00459001 | 3.78222 | 0.721001 | 0.0029094 | 4.82039 | 0.741601 | 0.00370799 | 1.4 | 0.035 | 0.000700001 | 23.6196 | 0.405001 | 0.0364501
AL09 | BLOCO A | 21.6 | 0.54 | 0.0108 | 10.53 | 1.62 | 0.0081 | 14.2943 | 1.236 | 0.0109956 | 10.53 | 1.62 | 0.0081 | 6.4741 | 0.996013 | 0.00498008 | 6.48706 | 0.998013 | 0.00499005 | 2.4 | 0.06 | 0.0012 | 94.4784 | 1.62 | 0.1458

# IfcWall: FNDE-AL09-I7-I7 (amarela) 150 x 3100, AL09
In: TÉRREO
Classification: Parede (Classificação Archicad); Material: TIJOLO - CERAMICO 9x19x39 - espessura 15cm, EI-REV-Chapisco (interno) (2), EI-REV-Cerâmica 10x10 Amarela (2), EI-REV-Cerâmica 10x10 Branca (2), EI-REV-Emboço Interno (2), EI-REV-Massa única - Maior que 10m² (2), EI-REV-Massa Corrida PVA (interna) (2), EI-REV-Pintura Acrílica Cor Branco Gelo (2)
FNDE - Alvenarias: Alvenaria de Vedação / Edificação; Sistemas de Cobertura: -; Esquadrias - Fechamentos metálicos e Gradis: -; 1_Bloco: BLOCO A; 0_ID: AL09
Pset_WallCommon - IsExternal: no; LoadBearing: no
Component Quantities - TIJOLO - CERAMICO 9x19x39 - espessura 15cm, Massa: 94.4784 kg; TIJOLO - CERAMICO 9x19x39 - espessura 15cm, Área de Componente Projetada (Líquida): 1.62 m2; TIJOLO - CERAMICO 9x19x39 - espessura 15cm, Área de Componente Projetada (Bruta): 1.62 m2; TIJOLO - CERAMICO 9x19x39 - espessura 15cm, Altura do Componente Retangular: 3.1 m; TIJOLO - CERAMICO 9x19x39 - espessura 15cm, Largura do Componente Retangular: 0.09 m; TIJOLO - CERAMICO 9x19x39 - espessura 15cm, Área de Seção Transversal do Componente: 0.279 m2; TIJOLO - CERAMICO 9x19x39 - espessura 15cm, Volume Componente (Líquido): 0.1458 m3; TIJOLO - CERAMICO 9x19x39 - espessura 15cm, Volume do componente (Bruto): 0.1458 m3; EI-REV-Chapisco (interno) 1, Massa: 10.53 kg; EI-REV-Chapisco (interno) 1, Área de Componente Projetada (Líquida): 1.62 m2; EI-REV-Chapisco (interno) 1, Área de Componente Projetada (Bruta): 1.62 m2; EI-REV-Chapisco (interno) 1, Altura do Componente Retangular: 3.1 m; EI-REV-Chapisco (interno) 1, Largura do Componente Retangular: 0.005 m; EI-REV-Chapisco (interno) 1, Área de Seção Transversal do Componente: 0.0155 m2; EI-REV-Chapisco (interno) 1, Volume Componente (Líquido): 0.0081 m3; EI-REV-Chapisco (interno) 1, Volume do componente (Bruto): 0.0081 m3; EI-REV-Cerâmica 10x10 Amarela 1, Massa: 21.6 kg; EI-REV-Cerâmica 10x10 Amarela 1, Área de Componente Projetada (Líquida): 0.54 m2; EI-REV-Cerâmica 10x10 Amarela 1, Área de Componente Projetada (Bruta): 0.54 m2; EI-REV-Cerâmica 10x10 Amarela 1, Altura do Componente Retangular: 0.9 m; EI-REV-Cerâmica 10x10 Amarela 1, Largura do Componente Retangular: 0.02 m; EI-REV-Cerâmica 10x10 Amarela 1, Área de Seção Transversal do Componente: 0.018 m2; EI-REV-Cerâmica 10x10 Amarela 1, Volume Componente (Líquido): 0.0108 m3; EI-REV-Cerâmica 10x10 Amarela 1, Volume do componente (Bruto): 0.0108 m3; EI-REV-Cerâmica 10x10 Branca 1, Massa: 2.4 kg; EI-REV-Cerâmica 10x10 Branca 1, Área de Componente Projetada (Líquida): 0.06 m2; EI-REV-Cerâmica 10x10 Branca 1, Área de Componente Projetada (Bruta): 0.06 m2; EI-REV-Cerâmica 10x10 Branca 1, Altura do Componente Retangular: 0.1 m; EI-REV-Cerâmica 10x10 Branca 1, Largura do Componente Retangular: 0.02 m; EI-REV-Cerâmica 10x10 Branca 1, Área de Seção Transversal do Componente: 0.002 m2; EI-REV-Cerâmica 10x10 Branca 1, Volume Componente (Líquido): 0.0012 m3; EI-REV-Cerâmica 10x10 Branca 1, Volume do componente (Bruto): 0.0012 m3; EI-REV-Massa única - Maior que 10m² 1, Massa: 6.47409 kg; EI-REV-Massa única - Maior que 10m² 1, Área de Componente Projetada (Líquida): 0.996013 m2; EI-REV-Massa única - Maior que 10m² 1, Área de Componente Projetada (Bruta): 0.996013 m2; EI-REV-Massa única - Maior que 10m² 1, Altura do Componente Retangular: 2.06 m; EI-REV-Massa única - Maior que 10m² 1, Largura do Componente Retangular: 0.00499999 m; EI-REV-Massa única - Maior que 10m² 1, Área de Seção Transversal do Componente: 0.0103 m2; EI-REV-Massa única - Maior que 10m² 1, Volume Componente (Líquido): 0.00498007 m3; EI-REV-Massa única - Maior que 10m² 1, Volume do componente (Bruto): 0.00498007 m3; EI-REV-Massa Corrida PVA (interna) 1, Massa: 6.48711 kg; EI-REV-Massa Corrida PVA (interna) 1, Área de Componente Projetada (Líquida): 0.998013 m2; EI-REV-Massa Corrida PVA (interna) 1, Área de Componente Projetada (Bruta): 0.998013 m2; EI-REV-Massa Corrida PVA (interna) 1, Altura do Componente Retangular: 2.06 m; EI-REV-Massa Corrida PVA (interna) 1, Largura do Componente Retangular: 0.00500002 m; EI-REV-Massa Corrida PVA (interna) 1, Área de Seção Transversal do Componente: 0.0103 m2; EI-REV-Massa Corrida PVA (interna) 1, Volume Componente (Líquido): 0.00499008 m3; EI-REV-Massa Corrida PVA (interna) 1, Volume do componente (Bruto): 0.00499008 m3; EI-REV-Pintura Acrílica Cor Branco Gelo 1, Massa: 14.3663 kg; EI-REV-Pintura Acrílica Cor Branco Gelo 1, Área de Componente Projetada (Líquida): 1.236 m2; EI-REV-Pintura Acrílica Cor Branco Gelo 1, Área de Componente Projetada (Bruta): 1.236 m2; EI-REV-Pintura Acrílica Cor Branco Gelo 1, Altura do Componente Retangular: 2.06 m; EI-REV-Pintura Acrílica Cor Branco Gelo 1, Largura do Componente Retangular: 0.01 m; EI-REV-Pintura Acrílica Cor Branco Gelo 1, Área de Seção Transversal do Componente: 0.0206 m2; EI-REV-Pintura Acrílica Cor Branco Gelo 1, Volume Componente (Líquido): 0.011051 m3; EI-REV-Pintura Acrílica Cor Branco Gelo 1, Volume do componente (Bruto): 0.011051 m3; EI-REV-Chapisco (interno) 2, Massa: 8.86271 kg; EI-REV-Chapisco (interno) 2, Área de Componente Projetada (Líquida): 1.3635 m2; EI-REV-Chapisco (interno) 2, Área de Componente Projetada (Bruta): 1.3635 m2; EI-REV-Chapisco (interno) 2, Altura do Componente Retangular: 3.1 m; EI-REV-Chapisco (interno) 2, Largura do Componente Retangular: 0.005 m; EI-REV-Chapisco (interno) 2, Área de Seção Transversal do Componente: 0.0155 m2; EI-REV-Chapisco (interno) 2, Volume Componente (Líquido): 0.00681747 m3; EI-REV-Chapisco (interno) 2, Volume do componente (Bruto): 0.00681747 m3; EI-REV-Cerâmica 10x10 Amarela 2, Massa: 17.28 kg; EI-REV-Cerâmica 10x10 Amarela 2, Área de Componente Projetada (Líquida): 0.432 m2; EI-REV-Cerâmica 10x10 Amarela 2, Área de Componente Projetada (Bruta): 0.432 m2; EI-REV-Cerâmica 10x10 Amarela 2, Altura do Componente Retangular: 0.9 m; EI-REV-Cerâmica 10x10 Amarela 2, Largura do Componente Retangular: 0.02 m; EI-REV-Cerâmica 10x10 Amarela 2, Área de Seção Transversal do Componente: 0.018 m2; EI-REV-Cerâmica 10x10 Amarela 2, Volume Componente (Líquido): 0.00863999 m3; EI-REV-Cerâmica 10x10 Amarela 2, Volume do componente (Bruto): 0.00863999 m3; EI-REV-Cerâmica 10x10 Branca 2, Massa: 1.92 kg; EI-REV-Cerâmica 10x10 Branca 2, Área de Componente Projetada (Líquida): 0.048 m2; EI-REV-Cerâmica 10x10 Branca 2, Área de Componente Projetada (Bruta): 0.048 m2; EI-REV-Cerâmica 10x10 Branca 2, Altura do Componente Retangular: 0.1 m; EI-REV-Cerâmica 10x10 Branca 2, Largura do Componente Retangular: 0.02 m; EI-REV-Cerâmica 10x10 Branca 2, Área de Seção Transversal do Componente: 0.002 m2; EI-REV-Cerâmica 10x10 Branca 2, Volume Componente (Líquido): 0.000959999 m3; EI-REV-Cerâmica 10x10 Branca 2, Volume do componente (Bruto): 0.000959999 m3; EI-REV-Emboço Interno 2, Massa: 8.77495 kg; EI-REV-Emboço Interno 2, Área de Componente Projetada (Líquida): 1.35 m2; EI-REV-Emboço Interno 2, Área de Componente Projetada (Bruta): 1.35 m2; EI-REV-Emboço Interno 2, Área de Seção Transversal do Componente: 0.0155 m2; EI-REV-Emboço Interno 2, Volume Componente (Líquido): 0.00674997 m3; EI-REV-Emboço Interno 2, Volume do componente (Bruto): 0.00674997 m3; EI-REV-Massa única - Maior que 10m² 2, Massa: 5.34104 kg; EI-REV-Massa única - Maior que 10m² 2, Área de Componente Projetada (Líquida): 0.8217 m2; EI-REV-Massa única - Maior que 10m² 2, Área de Componente Projetada (Bruta): 0.8217 m2; EI-REV-Massa única - Maior que 10m² 2, Altura do Componente Retangular: 2.06 m; EI-REV-Massa única - Maior que 10m² 2, Largura do Componente Retangular: 0.00500002 m; EI-REV-Massa única - Maior que 10m² 2, Área de Seção Transversal do Componente: 0.0103 m2; EI-REV-Massa única - Maior que 10m² 2, Volume Componente (Líquido): 0.00410849 m3; EI-REV-Massa única - Maior que 10m² 2, Volume do componente (Bruto): 0.00410849 m3; EI-REV-Massa Corrida PVA (interna) 2, Massa: 5.28706 kg; EI-REV-Massa Corrida PVA (interna) 2, Área de Componente Projetada (Líquida): 0.8134 m2; EI-REV-Massa Corrida PVA (interna) 2, Área de Componente Projetada (Bruta): 0.8134 m2; EI-REV-Massa Corrida PVA (interna) 2, Altura do Componente Retangular: 2.06 m; EI-REV-Massa Corrida PVA (interna) 2, Largura do Componente Retangular: 0.00499999 m; EI-REV-Massa Corrida PVA (interna) 2, Área de Seção Transversal do Componente: 0.0103 m2; EI-REV-Massa Corrida PVA (interna) 2, Volume Componente (Líquido): 0.00406697 m3; EI-REV-Massa Corrida PVA (interna) 2, Volume do componente (Bruto): 0.00406697 m3; EI-REV-Pintura Acrílica Cor Branco Gelo 2, Massa: 11.6482 kg; EI-REV-Pintura Acrílica Cor Branco Gelo 2, Área de Componente Projetada (Líquida): 0.974788 m2; EI-REV-Pintura Acrílica Cor Branco Gelo 2, Área de Componente Projetada (Bruta): 0.974788 m2; EI-REV-Pintura Acrílica Cor Branco Gelo 2, Altura do Componente Retangular: 2.06 m; EI-REV-Pintura Acrílica Cor Branco Gelo 2, Largura do Componente Retangular: 0.01 m; EI-REV-Pintura Acrílica Cor Branco Gelo 2, Área de Seção Transversal do Componente: 0.0206 m2; EI-REV-Pintura Acrílica Cor Branco Gelo 2, Volume Componente (Líquido): 0.00896014 m3; EI-REV-Pintura Acrílica Cor Branco Gelo 2, Volume do componente (Bruto): 0.00896014 m3; EI-REV-Chapisco (interno) 1: 2 with these values

# IfcWall: FNDE-AL09-Pintura Branca 2 Faces 150 (4)
In: TÉRREO
Classification: Parede (Classificação Archicad); Material: EI-REV-Pintura Acrílica Cor Branco Gelo 0.01 m, EI-REV-Massa Corrida PVA (interna) 0.005 m, EI-REV-Massa única - Maior que 10m² 0.01 m, EI-REV-Chapisco (interno) 0.005 m, TIJOLO - CERAMICO 9x19x39 - espessura 15cm 0.09 m, EI-REV-Chapisco (interno) 0.005 m, EI-REV-Massa única - Maior que 10m² 0.01 m, EI-REV-Massa Corrida PVA (interna) 0.005 m, EI-REV-Pintura Acrílica Cor Branco Gelo 0.01 m
FNDE - Alvenarias: Alvenaria de Vedação / Edificação; Sistemas de Cobertura: -; Esquadrias - Fechamentos metálicos e Gradis: -; 1_Bloco: BLOCO A; 0_ID: AL09
Pset_WallCommon - IsExternal: no; LoadBearing: no
Component Quantities - EI-REV-Pintura Acrílica Cor Branco Gelo 1, Espessura do Componente: 0.01 m; EI-REV-Pintura Acrílica Cor Branco Gelo 1, Largura do Componente Retangular: 0.01 m; EI-REV-Massa Corrida PVA (interna) 1, Espessura do Componente: 0.005 m; EI-REV-Massa Corrida PVA (interna) 1, Largura do Componente Retangular: 0.005 m; TIJOLO - CERAMICO 9x19x39 - espessura 15cm, Espessura do Componente: 0.09 m; TIJOLO - CERAMICO 9x19x39 - espessura 15cm, Largura do Componente Retangular: 0.09 m; EI-REV-Massa Corrida PVA (interna) 1: 4 with these values
Name | EI-REV-Pintura Acrílica Cor Branco Gelo 1, Massa (kg) | EI-REV-Pintura Acrílica Cor Branco Gelo 1, Área de Componente Projetada (Líquida) (m2) = EI-REV-Pintura Acrílica Cor Branco Gelo 1, Área de Componente Projetada (Bruta) (m2) | EI-REV-Pintura Acrílica Cor Branco Gelo 1, Altura do Componente Retangular (m) = EI-REV-Massa Corrida PVA (interna) 1, Altura do Componente Retangular (m) = TIJOLO - CERAMICO 9x19x39 - espessura 15cm, Altura do Componente Retangular (m) | EI-REV-Pintura Acrílica Cor Branco Gelo 1, Área de Seção Transversal do Componente (m2) | EI-REV-Pintura Acrílica Cor Branco Gelo 1, Volume Componente (Líquido) (m3) = EI-REV-Pintura Acrílica Cor Branco Gelo 1, Volume do componente (Bruto) (m3) | EI-REV-Massa Corrida PVA (interna) 1, Massa (kg) | EI-REV-Massa Corrida PVA (interna) 1, Área de Componente Projetada (Líquida) (m2) = EI-REV-Massa Corrida PVA (interna) 1, Área de Componente Projetada (Bruta) (m2) = TIJOLO - CERAMICO 9x19x39 - espessura 15cm, Área de Componente Projetada (Líquida) (m2) = TIJOLO - CERAMICO 9x19x39 - espessura 15cm, Área de Componente Projetada (Bruta) (m2) | EI-REV-Massa Corrida PVA (interna) 1, Área de Seção Transversal do Componente (m2) | EI-REV-Massa Corrida PVA (interna) 1, Volume Componente (Líquido) (m3) = EI-REV-Massa Corrida PVA (interna) 1, Volume do componente (Bruto) (m3) | EI-REV-Massa única - Maior que 10m² 1, Massa (kg) | EI-REV-Massa única - Maior que 10m² 1, Área de Componente Projetada (Líquida) (m2) = EI-REV-Massa única - Maior que 10m² 1, Área de Componente Projetada (Bruta) (m2) | EI-REV-Massa única - Maior que 10m² 1, Espessura do Componente (m) = EI-REV-Massa única - Maior que 10m² 1, Largura do Componente Retangular (m) = EI-REV-Pintura Acrílica Cor Branco Gelo 2, Espessura do Componente (m) = EI-REV-Pintura Acrílica Cor Branco Gelo 2, Largura do Componente Retangular (m) | EI-REV-Massa única - Maior que 10m² 1, Altura do Componente Retangular (m) = EI-REV-Pintura Acrílica Cor Branco Gelo 2, Altura do Componente Retangular (m) | EI-REV-Massa única - Maior que 10m² 1, Área de Seção Transversal do Componente (m2) = EI-REV-Pintura Acrílica Cor Branco Gelo 2, Área de Seção Transversal do Componente (m2) | EI-REV-Massa única - Maior que 10m² 1, Volume Componente (Líquido) (m3) = EI-REV-Massa única - Maior que 10m² 1, Volume do componente (Bruto) (m3) | TIJOLO - CERAMICO 9x19x39 - espessura 15cm, Massa (kg) | TIJOLO - CERAMICO 9x19x39 - espessura 15cm, Área de Seção Transversal do Componente (m2) | TIJOLO - CERAMICO 9x19x39 - espessura 15cm, Volume Componente (Líquido) (m3) = TIJOLO - CERAMICO 9x19x39 - espessura 15cm, Volume do componente (Bruto) (m3) | EI-REV-Pintura Acrílica Cor Branco Gelo 2, Massa (kg) | EI-REV-Pintura Acrílica Cor Branco Gelo 2, Área de Componente Projetada (Líquida) (m2) = EI-REV-Pintura Acrílica Cor Branco Gelo 2, Área de Componente Projetada (Bruta) (m2) | EI-REV-Pintura Acrílica Cor Branco Gelo 2, Volume Componente (Líquido) (m3) = EI-REV-Pintura Acrílica Cor Branco Gelo 2, Volume do componente (Bruto) (m3) | EI-REV-Massa única - Maior que 10m² 1
AL09 | 8.82077 | 1.15112 | 3.1 | 0.031 | 0.00678521 | 1.30081 | 0.200125 | 0.0155 | 0.00100062 | 2.60162 | 0.200125 | 0.01 | 3.1 | 0.031 | 0.00200125 | 11.6713 | 0.279 | 0.0180112 | 8.74478 | 1.15112 | 0.00672676 | 2 with these values
AL09 | 11.2776 | 1.3585 | 0.55 | 0.0055 | 0.00867509 | 2.40825 | 0.3705 | 0.00275 | 0.0018525 | 4.8165 | 0.3705 | 0.01 | 0.55 | 0.0055 | 0.003705 | 21.6076 | 0.0495 | 0.033345 | 11.1968 | 1.3585 | 0.00861291 | 2 with these values
AL09 | 8.82077 | 1.15112 | 3.1 | 0.031 | 0.00678521 | 1.30081 | 0.200125 | 0.0155 | 0.00100062 | 2.60162 | 0.200125 | 0.01 | 3.1 | 0.031 | 0.00200125 | 11.6713 | 0.279 | 0.0180112 | 8.74547 | 1.15112 | 0.00672729 | 2 with these values
AL09 | 13.1651 | 1.0127 | 0.49 | 0.0049 | 0.010127 | 6.58255 | 1.0127 | 0.00245 | 0.0050635 |  |  |  |  |  |  | 59.0607 | 0.0441 | 0.091143 | Component Quantities - EI-REV-Pintura Acrílica Cor Branco Gelo 1: 4 with these values

# IfcWall: FNDE-AL14-E1 (cinza) 170 x 3100 (5)
In: TÉRREO
Classification: Parede (Classificação Archicad); Material: TIJOLO - CERAMICO 14x19x39 - espessura 20cm, EI-REV-Chapisco (externo), EI-REV-Pintura Acrílica Cor Cinza, EI-REV-Massa única - Fachada, EI-REV-Massa Acrílica (externa), EI-REV-Pintura Acrílica Cor Branco Gelo
FNDE - Alvenarias: Alvenaria de Vedação / Edificação; Sistemas de Cobertura: -; Esquadrias - Fechamentos metálicos e Gradis: -; 0_ID: AL14
Pset_WallCommon - IsExternal: yes; LoadBearing: no
Component Quantities - TIJOLO - CERAMICO 14x19x39 - espessura 20cm, Altura do Componente Retangular: 3.1 m; TIJOLO - CERAMICO 14x19x39 - espessura 20cm, Largura do Componente Retangular: 0.14 m; TIJOLO - CERAMICO 14x19x39 - espessura 20cm, Área de Seção Transversal do Componente: 0.434 m2; EI-REV-Chapisco (externo), Altura do Componente Retangular: 3.1 m; EI-REV-Chapisco (externo), Largura do Componente Retangular: 0.005 m; EI-REV-Chapisco (externo), Área de Seção Transversal do Componente: 0.0155 m2; EI-REV-Pintura Acrílica Cor Cinza, Altura do Componente Retangular: 0.44 m; EI-REV-Pintura Acrílica Cor Cinza, Largura do Componente Retangular: 0.015 m; EI-REV-Pintura Acrílica Cor Cinza, Área de Seção Transversal do Componente: 0.0066 m2; EI-REV-Pintura Acrílica Cor Branco Gelo, Altura do Componente Retangular: 2.66 m; EI-REV-Pintura Acrílica Cor Branco Gelo, Largura do Componente Retangular: 0.015 m; EI-REV-Pintura Acrílica Cor Branco Gelo, Área de Seção Transversal do Componente: 0.0399 m2
Name | 1_Bloco | TIJOLO - CERAMICO 14x19x39 - espessura 20cm, Massa (kg) | TIJOLO - CERAMICO 14x19x39 - espessura 20cm, Área de Componente Projetada (Líquida) (m2) = TIJOLO - CERAMICO 14x19x39 - espessura 20cm, Área de Componente Projetada (Bruta) (m2) | TIJOLO - CERAMICO 14x19x39 - espessura 20cm, Volume Componente (Líquido) (m3) = TIJOLO - CERAMICO 14x19x39 - espessura 20cm, Volume do componente (Bruto) (m3) | EI-REV-Chapisco (externo), Massa (kg) | EI-REV-Chapisco (externo), Área de Componente Projetada (Líquida) (m2) = EI-REV-Chapisco (externo), Área de Componente Projetada (Bruta) (m2) | EI-REV-Chapisco (externo), Volume Componente (Líquido) (m3) = EI-REV-Chapisco (externo), Volume do componente (Bruto) (m3) | EI-REV-Pintura Acrílica Cor Cinza, Massa (kg) | EI-REV-Pintura Acrílica Cor Cinza, Área de Componente Projetada (Líquida) (m2) = EI-REV-Pintura Acrílica Cor Cinza, Área de Componente Projetada (Bruta) (m2) | EI-REV-Pintura Acrílica Cor Cinza, Volume Componente (Líquido) (m3) = EI-REV-Pintura Acrílica Cor Cinza, Volume do componente (Bruto) (m3) | EI-REV-Massa única - Fachada, Massa (kg) | EI-REV-Massa única - Fachada, Área de Componente Projetada (Líquida) (m2) = EI-REV-Massa única - Fachada, Área de Componente Projetada (Bruta) (m2) | EI-REV-Massa única - Fachada, Altura do Componente Retangular (m) = EI-REV-Massa Acrílica (externa), Altura do Componente Retangular (m) | EI-REV-Massa única - Fachada, Largura do Componente Retangular (m) = EI-REV-Massa Acrílica (externa), Largura do Componente Retangular (m) | EI-REV-Massa única - Fachada, Área de Seção Transversal do Componente (m2) = EI-REV-Massa Acrílica (externa), Área de Seção Transversal do Componente (m2) | EI-REV-Massa única - Fachada, Volume Componente (Líquido) (m3) = EI-REV-Massa única - Fachada, Volume do componente (Bruto) (m3) | EI-REV-Massa Acrílica (externa), Massa (kg) | EI-REV-Massa Acrílica (externa), Área de Componente Projetada (Líquida) (m2) = EI-REV-Massa Acrílica (externa), Área de Componente Projetada (Bruta) (m2) | EI-REV-Massa Acrílica (externa), Volume Componente (Líquido) (m3) = EI-REV-Massa Acrílica (externa), Volume do componente (Bruto) (m3) | EI-REV-Pintura Acrílica Cor Branco Gelo, Massa (kg) | EI-REV-Pintura Acrílica Cor Branco Gelo, Área de Componente Projetada (Líquida) (m2) = EI-REV-Pintura Acrílica Cor Branco Gelo, Área de Componente Projetada (Bruta) (m2) | EI-REV-Pintura Acrílica Cor Branco Gelo, Volume Componente (Líquido) (m3) = EI-REV-Pintura Acrílica Cor Branco Gelo, Volume do componente (Bruto) (m3)
AL14 | BLOCO A | 16.5276 | 0.764978 | 0.0255056 | 11.2777 | 1.736 | 0.00867514 | 4.9335 | 0.253 | 0.003795 | 11.3848 | 1.7515 | 3.1 | 0.005 | 0.0155 | 0.0087575 | 11.4855 | 1.767 | 0.008835 | 29.8253 | 1.5295 | 0.0229425
AL14 | BLOCO A | 438.477 | 5.44753 | 0.676663 | 41.4214 | 6.37253 | 0.0318626 | 17.0351 | 0.873597 | 0.013104 |  |  |  |  |  |  |  |  |  | 107.229 | 5.49893 | 0.082484 | Component Quantities - EI-REV-Chapisco (externo): 3 with these values
AL14 | BLOCO B | 49.5133 | 0.545798 | 0.0764094 | 3.6353 | 0.559276 | 0.00279638 | 3.00551 | 0.154282 | 0.00231193 | 3.72305 | 0.572776 | 3.1 | 0.005 | 0.0155 | 0.00286388 | 3.81115 | 0.586331 | 0.00293166 | 18.1562 | 0.932741 | 0.0139663
AL14 | BLOCO B | 48.9888 | 0.54 | 0.0756 | 5.967 | 0.918 | 0.00459 | 3.04299 | 0.1562 | 0.00234076 | 6.05475 | 0.9315 | 3.1 | 0.005 | 0.0155 | 0.0046575 | 6.16219 | 1.085 | 0.00474015 | 18.4138 | 0.9443 | 0.0141645
AL14 | BLOCO A | 65.8916 | 1.10949 | 0.101685 | 7.78471 | 1.209 | 0.00598824 | 3.5607 | 0.1826 | 0.002739 | 7.95925 | 1.2245 | 3.1 | 0.005 | 0.0155 | 0.0061225 | 8.06 | 1.24 | 0.0062 | 21.526 | 1.1039 | 0.0165585

# IfcWall: FNDE-AL14-E1-E1 (faixa cinza) 200 x 3100 (3)
In: TÉRREO
Classification: Parede (Classificação Archicad); Material: EI-REV-Pintura Acrílica Cor Cinza (2), TIJOLO - CERAMICO 14x19x39 - espessura 20cm, EI-REV-Chapisco (externo) (2), EI-REV-Pintura Acrílica Cor Branco Gelo (2), EI-REV-Massa única - Fachada (2), EI-REV-Massa Acrílica (externa) (2)
FNDE - Alvenarias: Alvenaria de Vedação / Edificação; Sistemas de Cobertura: -; Esquadrias - Fechamentos metálicos e Gradis: -; 0_ID: AL14
Pset_WallCommon - IsExternal: yes; LoadBearing: no
Component Quantities - EI-REV-Pintura Acrílica Cor Cinza 1, Altura do Componente Retangular: 0.44 m; EI-REV-Pintura Acrílica Cor Cinza 1, Largura do Componente Retangular: 0.015 m; EI-REV-Pintura Acrílica Cor Cinza 1, Área de Seção Transversal do Componente: 0.0066 m2; EI-REV-Pintura Acrílica Cor Cinza 2, Altura do Componente Retangular: 0.44 m; EI-REV-Pintura Acrílica Cor Cinza 2, Largura do Componente Retangular: 0.015 m; EI-REV-Pintura Acrílica Cor Cinza 2, Área de Seção Transversal do Componente: 0.0066 m2; TIJOLO - CERAMICO 14x19x39 - espessura 20cm, Altura do Componente Retangular: 3.1 m; TIJOLO - CERAMICO 14x19x39 - espessura 20cm, Largura do Componente Retangular: 0.14 m; TIJOLO - CERAMICO 14x19x39 - espessura 20cm, Área de Seção Transversal do Componente: 0.434 m2; EI-REV-Chapisco (externo) 1, Altura do Componente Retangular: 3.1 m; EI-REV-Chapisco (externo) 1, Largura do Componente Retangular: 0.005 m; EI-REV-Chapisco (externo) 1, Área de Seção Transversal do Componente: 0.0155 m2; EI-REV-Pintura Acrílica Cor Branco Gelo 1, Altura do Componente Retangular: 2.66 m; EI-REV-Pintura Acrílica Cor Branco Gelo 1, Largura do Componente Retangular: 0.015 m; EI-REV-Pintura Acrílica Cor Branco Gelo 1, Área de Seção Transversal do Componente: 0.0399 m2; EI-REV-Massa única - Fachada 1, Altura do Componente Retangular: 3.1 m; EI-REV-Massa única - Fachada 1, Largura do Componente Retangular: 0.005 m; EI-REV-Massa única - Fachada 1, Área de Seção Transversal do Componente: 0.0155 m2; EI-REV-Massa Acrílica (externa) 1, Altura do Componente Retangular: 3.1 m; EI-REV-Massa Acrílica (externa) 1, Largura do Componente Retangular: 0.005 m; EI-REV-Massa Acrílica (externa) 1, Área de Seção Transversal do Componente: 0.0155 m2; EI-REV-Chapisco (externo) 2, Altura do Componente Retangular: 3.1 m; EI-REV-Chapisco (externo) 2, Largura do Componente Retangular: 0.005 m; EI-REV-Chapisco (externo) 2, Área de Seção Transversal do Componente: 0.0155 m2; EI-REV-Pintura Acrílica Cor Branco Gelo 2, Altura do Componente Retangular: 2.66 m; EI-REV-Pintura Acrílica Cor Branco Gelo 2, Largura do Componente Retangular: 0.015 m; EI-REV-Pintura Acrílica Cor Branco Gelo 2, Área de Seção Transversal do Componente: 0.0399 m2; EI-REV-Massa Acrílica (externa) 2, Altura do Componente Retangular: 3.1 m; EI-REV-Massa Acrílica (externa) 2, Largura do Componente Retangular: 0.005 m; EI-REV-Massa Acrílica (externa) 2, Área de Seção Transversal do Componente: 0.0155 m2
Name | 1_Bloco | EI-REV-Pintura Acrílica Cor Cinza 1, Massa (kg) | EI-REV-Pintura Acrílica Cor Cinza 1, Volume Componente (Líquido) (m3) = EI-REV-Pintura Acrílica Cor Cinza 1, Volume do componente (Bruto) (m3) | EI-REV-Pintura Acrílica Cor Cinza 2, Massa (kg) | EI-REV-Pintura Acrílica Cor Cinza 2, Volume Componente (Líquido) (m3) = EI-REV-Pintura Acrílica Cor Cinza 2, Volume do componente (Bruto) (m3) | TIJOLO - CERAMICO 14x19x39 - espessura 20cm, Massa (kg) | TIJOLO - CERAMICO 14x19x39 - espessura 20cm, Área de Componente Projetada (Líquida) (m2) = TIJOLO - CERAMICO 14x19x39 - espessura 20cm, Área de Componente Projetada (Bruta) (m2) | TIJOLO - CERAMICO 14x19x39 - espessura 20cm, Volume Componente (Líquido) (m3) = TIJOLO - CERAMICO 14x19x39 - espessura 20cm, Volume do componente (Bruto) (m3) | EI-REV-Chapisco (externo) 1, Massa (kg) | EI-REV-Chapisco (externo) 1, Área de Componente Projetada (Líquida) (m2) = EI-REV-Chapisco (externo) 1, Área de Componente Projetada (Bruta) (m2) | EI-REV-Chapisco (externo) 1, Volume Componente (Líquido) (m3) = EI-REV-Chapisco (externo) 1, Volume do componente (Bruto) (m3) | EI-REV-Pintura Acrílica Cor Branco Gelo 1, Massa (kg) | EI-REV-Pintura Acrílica Cor Branco Gelo 1, Área de Componente Projetada (Líquida) (m2) = EI-REV-Pintura Acrílica Cor Branco Gelo 1, Área de Componente Projetada (Bruta) (m2) | EI-REV-Pintura Acrílica Cor Branco Gelo 1, Volume Componente (Líquido) (m3) = EI-REV-Pintura Acrílica Cor Branco Gelo 1, Volume do componente (Bruto) (m3) | EI-REV-Massa única - Fachada 1, Massa (kg) | EI-REV-Massa única - Fachada 1, Área de Componente Projetada (Líquida) (m2) = EI-REV-Massa única - Fachada 1, Área de Componente Projetada (Bruta) (m2) | EI-REV-Massa única - Fachada 1, Volume Componente (Líquido) (m3) = EI-REV-Massa única - Fachada 1, Volume do componente (Bruto) (m3) | EI-REV-Massa Acrílica (externa) 1, Massa (kg) | EI-REV-Massa Acrílica (externa) 1, Área de Componente Projetada (Líquida) (m2) = EI-REV-Massa Acrílica (externa) 1, Área de Componente Projetada (Bruta) (m2) | EI-REV-Massa Acrílica (externa) 1, Volume Componente (Líquido) (m3) = EI-REV-Massa Acrílica (externa) 1, Volume do componente (Bruto) (m3) | EI-REV-Chapisco (externo) 2, Massa (kg) | EI-REV-Chapisco (externo) 2, Área de Componente Projetada (Líquida) (m2) = EI-REV-Chapisco (externo) 2, Área de Componente Projetada (Bruta) (m2) | EI-REV-Chapisco (externo) 2, Volume Componente (Líquido) (m3) = EI-REV-Chapisco (externo) 2, Volume do componente (Bruto) (m3) | EI-REV-Pintura Acrílica Cor Branco Gelo 2, Massa (kg) | EI-REV-Pintura Acrílica Cor Branco Gelo 2, Área de Componente Projetada (Líquida) (m2) = EI-REV-Pintura Acrílica Cor Branco Gelo 2, Área de Componente Projetada (Bruta) (m2) | EI-REV-Pintura Acrílica Cor Branco Gelo 2, Volume Componente (Líquido) (m3) = EI-REV-Pintura Acrílica Cor Branco Gelo 2, Volume do componente (Bruto) (m3) | EI-REV-Massa Acrílica (externa) 2, Massa (kg) | EI-REV-Massa Acrílica (externa) 2, Área de Componente Projetada (Líquida) (m2) = EI-REV-Massa Acrílica (externa) 2, Área de Componente Projetada (Bruta) (m2) | EI-REV-Massa Acrílica (externa) 2, Volume Componente (Líquido) (m3) = EI-REV-Massa Acrílica (externa) 2, Volume do componente (Bruto) (m3) | EI-REV-Massa única - Fachada 2, Massa (kg) | EI-REV-Massa única - Fachada 2, Área de Componente Projetada (Líquida) (m2) = EI-REV-Massa única - Fachada 2, Área de Componente Projetada (Bruta) (m2) | EI-REV-Massa única - Fachada 2, Altura do Componente Retangular (m) | EI-REV-Massa única - Fachada 2, Largura do Componente Retangular (m) | EI-REV-Massa única - Fachada 2, Área de Seção Transversal do Componente (m2) | EI-REV-Massa única - Fachada 2, Volume Componente (Líquido) (m3) = EI-REV-Massa única - Fachada 2, Volume do componente (Bruto) (m3)
AL14 | BLOCO B | 4.72391 | 0.00363377 | 3.10707 | 0.00239006 | 54.0208 | 0.595468 | 0.0833655 | 3.95829 | 0.608968 | 0.00304484 | 27.1975 | 1.39475 | 0.0209212 | 4.04604 | 0.622468 | 0.00311234 | 4.14844 | 1.59399 | 0.00319111 | 1.41354 | 0.217468 | 0.00108734 | 18.689 | 0.959046 | 0.0143761 | 1.15419 | 0.177568 | 0.000887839 | Component Quantities - EI-REV-Chapisco (externo) 2: 2 with these values
AL14 | BLOCO B | 16.9731 | 0.0130562 | 17.5932 | 0.0135332 | 398.044 | 6.43006 | 0.614265 | 29.7351 | 4.76614 | 0.0228731 | 101.619 | 5.21127 | 0.0781686 | 30.717 | 4.72567 | 0.0236284 | 36.8657 | 6.1054 | 0.0283582 | 41.7908 | 6.42934 | 0.0321468 | 106.332 | 5.51615 | 0.0817936 | 41.4005 | 6.36929 | 0.0318465 | 41.4981 | 6.38432 | 3.1 | 0.005 | 0.0155 | 0.0319216
AL14 | BLOCO A | 5.60068 | 0.00430822 | 6.99298 | 0.00537922 | 170.917 | 2.1051 | 0.26376 | 11.7393 | 1.80604 | 0.00903019 | 30.3285 | 1.72609 | 0.0233296 | 11.7389 | 1.80599 | 0.00902994 | 11.5241 | 1.77294 | 0.00886469 | 13.9328 | 2.1435 | 0.0107175 | 40.7772 | 2.09114 | 0.0313671 | 13.6303 | 2.45745 | 0.0104848 | 13.6269 | 2.09645 | 3.1 | 0.005 | 0.0155 | 0.0104823

# IfcWall: FNDE-AL14-E2 170 (4)
In: TÉRREO
Classification: Parede (Classificação Archicad); Material: EI-REV-Pintura Acrílica Cor Cinza 0.015 m, EI-REV-Massa Acrílica (externa) 0.005 m, EI-REV-Massa única - Fachada 0.005 m, EI-REV-Chapisco (externo) 0.005 m, TIJOLO - CERAMICO 14x19x39 - espessura 20cm 0.14 m
FNDE - Alvenarias: Alvenaria de Vedação / Edificação; Sistemas de Cobertura: -; Esquadrias - Fechamentos metálicos e Gradis: -; 0_ID: AL14
Pset_WallCommon - IsExternal: yes; LoadBearing: no
Component Quantities - EI-REV-Pintura Acrílica Cor Cinza, Espessura do Componente: 0.015 m; EI-REV-Pintura Acrílica Cor Cinza, Largura do Componente Retangular: 0.015 m; EI-REV-Massa Acrílica (externa), Espessura do Componente: 0.005 m; EI-REV-Massa Acrílica (externa), Largura do Componente Retangular: 0.005 m; TIJOLO - CERAMICO 14x19x39 - espessura 20cm, Espessura do Componente: 0.14 m; TIJOLO - CERAMICO 14x19x39 - espessura 20cm, Largura do Componente Retangular: 0.14 m
Name | 1_Bloco | EI-REV-Pintura Acrílica Cor Cinza, Massa (kg) | EI-REV-Pintura Acrílica Cor Cinza, Área de Componente Projetada (Líquida) (m2) = EI-REV-Pintura Acrílica Cor Cinza, Área de Componente Projetada (Bruta) (m2) | EI-REV-Pintura Acrílica Cor Cinza, Altura do Componente Retangular (m) = EI-REV-Massa Acrílica (externa), Altura do Componente Retangular (m) = TIJOLO - CERAMICO 14x19x39 - espessura 20cm, Altura do Componente Retangular (m) | EI-REV-Pintura Acrílica Cor Cinza, Área de Seção Transversal do Componente (m2) | EI-REV-Pintura Acrílica Cor Cinza, Volume Componente (Líquido) (m3) = EI-REV-Pintura Acrílica Cor Cinza, Volume do componente (Bruto) (m3) | EI-REV-Massa Acrílica (externa), Massa (kg) | EI-REV-Massa Acrílica (externa), Área de Componente Projetada (Líquida) (m2) = EI-REV-Massa Acrílica (externa), Área de Componente Projetada (Bruta) (m2) | EI-REV-Massa Acrílica (externa), Área de Seção Transversal do Componente (m2) | EI-REV-Massa Acrílica (externa), Volume Componente (Líquido) (m3) = EI-REV-Massa Acrílica (externa), Volume do componente (Bruto) (m3) | EI-REV-Massa única - Fachada, Massa (kg) | EI-REV-Massa única - Fachada, Área de Componente Projetada (Líquida) (m2) = EI-REV-Massa única - Fachada, Área de Componente Projetada (Bruta) (m2) | EI-REV-Massa única - Fachada, Espessura do Componente (m) = EI-REV-Massa única - Fachada, Largura do Componente Retangular (m) | EI-REV-Massa única - Fachada, Altura do Componente Retangular (m) | EI-REV-Massa única - Fachada, Área de Seção Transversal do Componente (m2) | EI-REV-Massa única - Fachada, Volume Componente (Líquido) (m3) = EI-REV-Massa única - Fachada, Volume do componente (Bruto) (m3) | EI-REV-Chapisco (externo), Massa (kg) | EI-REV-Chapisco (externo), Área de Componente Projetada (Líquida) (m2) = EI-REV-Chapisco (externo), Área de Componente Projetada (Bruta) (m2) | EI-REV-Chapisco (externo), Espessura do Componente (m) = EI-REV-Chapisco (externo), Largura do Componente Retangular (m) | EI-REV-Chapisco (externo), Altura do Componente Retangular (m) | EI-REV-Chapisco (externo), Área de Seção Transversal do Componente (m2) | EI-REV-Chapisco (externo), Volume Componente (Líquido) (m3) = EI-REV-Chapisco (externo), Volume do componente (Bruto) (m3) | TIJOLO - CERAMICO 14x19x39 - espessura 20cm, Massa (kg) | TIJOLO - CERAMICO 14x19x39 - espessura 20cm, Área de Componente Projetada (Líquida) (m2) = TIJOLO - CERAMICO 14x19x39 - espessura 20cm, Área de Componente Projetada (Bruta) (m2) | TIJOLO - CERAMICO 14x19x39 - espessura 20cm, Área de Seção Transversal do Componente (m2) | TIJOLO - CERAMICO 14x19x39 - espessura 20cm, Volume Componente (Líquido) (m3) = TIJOLO - CERAMICO 14x19x39 - espessura 20cm, Volume do componente (Bruto) (m3)
AL14 | BLOCO B | 39.6961 | 2.03751 | 3.14 | 0.0471 | 0.0305355 | 11.8846 | 1.82841 | 0.0157 | 0.00914203 | 11.7969 | 1.81491 | 0.005 | 3.14 | 0.0157 | 0.00907453 | 11.7091 | 1.80141 | 0.005 | 3.14 | 0.0157 | 0.00900703 | 129.065 | 1.9416 | 0.4396 | 0.199175
AL14 | BLOCO B | 42.363 | 2.17314 | 3.1 | 0.0465 | 0.0325869 | 12.6123 | 1.94035 | 0.0155 | 0.00970176 |  |  |  |  |  |  | 12.1527 | 1.87243 | 0.005 | 3.1 | 0.0155 | 0.00934826 | 140.964 | 1.55384 | 0.434 | 0.217537 | Component Quantities - EI-REV-Massa Acrílica (externa): 2 with these values
AL14 | BLOCO B | 43.8656 | 2.24976 | 3.1 | 0.0465 | 0.0337427 | 10.6072 | 1.62982 | 0.0155 | 0.00815939 | 10.5938 | 1.62982 | 0.005 | 3.1 | 0.0155 | 0.00814911 | 10.5331 | 1.62048 | 0.005 | 3.1 | 0.0155 | 0.00810239 | 147.01 | 1.62048 | 0.434 | 0.226867
AL14 | BLOCO A | 16.5845 | 0.850488 | 3.1 | 0.0465 | 0.0127573 | 5.61592 | 0.863988 | 0.0155 | 0.00431994 | 5.87917 | 0.904488 | 0.005 | 3.1 | 0.0155 | 0.00452244 |  |  |  |  |  |  | 94.3074 | 1.14749 | 0.434 | 0.145536 | Component Quantities - EI-REV-Massa única - Fachada: 2 with these values

# IfcWall: FNDE-AL14-E2-E2 (Muros - sem massa corrida) 190 (13)
In: TÉRREO
Classification: Parede (Classificação Archicad); Material: EI-REV-Pintura Acrílica Cor Cinza 0.015 m, EI-REV-Massa única - Fachada 0.005 m, EI-REV-Chapisco (externo) 0.005 m, TIJOLO - CERAMICO 14x19x39 - espessura 20cm 0.14 m, EI-REV-Chapisco (externo) 0.005 m, EI-REV-Massa única - Fachada 0.005 m, EI-REV-Pintura Acrílica Cor Cinza 0.015 m
FNDE - Sistemas de Cobertura: -; Esquadrias - Fechamentos metálicos e Gradis: -; 0_ID: AL14
Pset_WallCommon - IsExternal: yes; LoadBearing: no
Component Quantities - EI-REV-Pintura Acrílica Cor Cinza 1, Espessura do Componente: 0.015 m; EI-REV-Pintura Acrílica Cor Cinza 1, Largura do Componente Retangular: 0.015 m; EI-REV-Massa única - Fachada 1, Espessura do Componente: 0.005 m; EI-REV-Massa única - Fachada 1, Largura do Componente Retangular: 0.005 m; TIJOLO - CERAMICO 14x19x39 - espessura 20cm, Espessura do Componente: 0.14 m; TIJOLO - CERAMICO 14x19x39 - espessura 20cm, Largura do Componente Retangular: 0.14 m
Name | Alvenarias | 1_Bloco | EI-REV-Pintura Acrílica Cor Cinza 1, Massa (kg) | EI-REV-Pintura Acrílica Cor Cinza 1, Área de Componente Projetada (Líquida) (m2) | EI-REV-Pintura Acrílica Cor Cinza 1, Área de Componente Projetada (Bruta) (m2) | EI-REV-Pintura Acrílica Cor Cinza 1, Altura do Componente Retangular (m) = EI-REV-Massa única - Fachada 1, Altura do Componente Retangular (m) = TIJOLO - CERAMICO 14x19x39 - espessura 20cm, Altura do Componente Retangular (m) | EI-REV-Pintura Acrílica Cor Cinza 1, Área de Seção Transversal do Componente (m2) | EI-REV-Pintura Acrílica Cor Cinza 1, Volume Componente (Líquido) (m3) | EI-REV-Pintura Acrílica Cor Cinza 1, Volume do componente (Bruto) (m3) | EI-REV-Massa única - Fachada 1, Massa (kg) | EI-REV-Massa única - Fachada 1, Área de Componente Projetada (Líquida) (m2) | EI-REV-Massa única - Fachada 1, Área de Componente Projetada (Bruta) (m2) | EI-REV-Massa única - Fachada 1, Área de Seção Transversal do Componente (m2) | EI-REV-Massa única - Fachada 1, Volume Componente (Líquido) (m3) | EI-REV-Massa única - Fachada 1, Volume do componente (Bruto) (m3) | EI-REV-Chapisco (externo) 1, Massa (kg) | EI-REV-Chapisco (externo) 1, Área de Componente Projetada (Líquida) (m2) | EI-REV-Chapisco (externo) 1, Área de Componente Projetada (Bruta) (m2) | EI-REV-Chapisco (externo) 1, Espessura do Componente (m) = EI-REV-Chapisco (externo) 1, Largura do Componente Retangular (m) | EI-REV-Chapisco (externo) 1, Altura do Componente Retangular (m) | EI-REV-Chapisco (externo) 1, Área de Seção Transversal do Componente (m2) | EI-REV-Chapisco (externo) 1, Volume Componente (Líquido) (m3) | EI-REV-Chapisco (externo) 1, Volume do componente (Bruto) (m3) | TIJOLO - CERAMICO 14x19x39 - espessura 20cm, Massa (kg) | TIJOLO - CERAMICO 14x19x39 - espessura 20cm, Área de Componente Projetada (Líquida) (m2) | TIJOLO - CERAMICO 14x19x39 - espessura 20cm, Área de Componente Projetada (Bruta) (m2) | TIJOLO - CERAMICO 14x19x39 - espessura 20cm, Área de Seção Transversal do Componente (m2) | TIJOLO - CERAMICO 14x19x39 - espessura 20cm, Volume Componente (Líquido) (m3) | TIJOLO - CERAMICO 14x19x39 - espessura 20cm, Volume do componente (Bruto) (m3) | EI-REV-Chapisco (externo) 2, Massa (kg) | EI-REV-Chapisco (externo) 2, Área de Componente Projetada (Líquida) (m2) | EI-REV-Chapisco (externo) 2, Área de Componente Projetada (Bruta) (m2) | EI-REV-Chapisco (externo) 2, Espessura do Componente (m) = EI-REV-Chapisco (externo) 2, Largura do Componente Retangular (m) | EI-REV-Chapisco (externo) 2, Altura do Componente Retangular (m) = EI-REV-Pintura Acrílica Cor Cinza 2, Altura do Componente Retangular (m) | EI-REV-Chapisco (externo) 2, Área de Seção Transversal do Componente (m2) | EI-REV-Chapisco (externo) 2, Volume Componente (Líquido) (m3) | EI-REV-Chapisco (externo) 2, Volume do componente (Bruto) (m3) | EI-REV-Pintura Acrílica Cor Cinza 2, Massa (kg) | EI-REV-Pintura Acrílica Cor Cinza 2, Área de Componente Projetada (Líquida) (m2) | EI-REV-Pintura Acrílica Cor Cinza 2, Área de Componente Projetada (Bruta) (m2) | EI-REV-Pintura Acrílica Cor Cinza 2, Espessura do Componente (m) = EI-REV-Pintura Acrílica Cor Cinza 2, Largura do Componente Retangular (m) | EI-REV-Pintura Acrílica Cor Cinza 2, Área de Seção Transversal do Componente (m2) | EI-REV-Pintura Acrílica Cor Cinza 2, Volume Componente (Líquido) (m3) | EI-REV-Pintura Acrílica Cor Cinza 2, Volume do componente (Bruto) (m3) | EI-REV-Massa única - Fachada 1
AL14 | Alvenaria de Vedação / Edificação | MURO | 1652.98 | 84.7682 | 84.7682 | 2.12 | 0.0318 | 1.27152 | 1.27152 | 550.924 | 84.7576 | 84.7576 | 0.0106 | 0.423788 | 0.423788 | 550.855 | 84.747 | 84.747 | 0.005 | 2.12 | 0.0106 | 0.423735 | 0.423735 | 6568.45 | 84.4502 | 84.4502 | 0.2968 | 10.1365 | 10.1365 | 446.717 | 68.7257 | 68.7257 | 0.005 | 2.12 | 0.0106 | 0.343628 | 0.343628 | 1594.91 | 84.249 | 84.249 | 0.015 | 0.0318 | 1.22686 | 1.22686 | Component Quantities - EI-REV-Massa única - Fachada 2, Massa: 446.686 kg; EI-REV-Massa única - Fachada 2, Área de Componente Projetada (Líquida): 68.721 m2; EI-REV-Massa única - Fachada 2, Área de Componente Projetada (Bruta): 68.721 m2; EI-REV-Massa única - Fachada 2, Espessura do Componente: 0.005 m; EI-REV-Massa única - Fachada 2, Altura do Componente Retangular: 2.12 m; EI-REV-Massa única - Fachada 2, Largura do Componente Retangular: 0.005 m; EI-REV-Massa única - Fachada 2, Área de Seção Transversal do Componente: 0.0106 m2; EI-REV-Massa única - Fachada 2, Volume Componente (Líquido): 0.343605 m3; EI-REV-Massa única - Fachada 2, Volume do componente (Bruto): 0.343605 m3
AL14 | Alvenaria de Vedação / Edificação | MURO | 1860.3 | 95.4 | 95.4 | 2.12 | 0.0318 | 1.431 | 1.431 | 506.733 | 95.3364 | 95.3364 | 0.0106 | 0.389795 | 0.389795 | 506.312 | 77.8942 | 77.8942 | 0.005 | 2.12 | 0.0106 | 0.389471 | 0.389471 | 7394.32 | 94.8005 | 94.8005 | 0.2968 | 11.411 | 11.411 | 615.416 | 94.6794 | 94.6794 | 0.005 | 2.12 | 0.0106 | 0.473397 | 0.473397 | 1845.83 | 94.658 | 94.658 | 0.015 | 0.0318 | 1.41987 | 1.41987 | Component Quantities - EI-REV-Massa única - Fachada 2, Massa: 615.347 kg; EI-REV-Massa única - Fachada 2, Área de Componente Projetada (Líquida): 94.6687 m2; EI-REV-Massa única - Fachada 2, Área de Componente Projetada (Bruta): 94.6687 m2; EI-REV-Massa única - Fachada 2, Espessura do Componente: 0.005 m; EI-REV-Massa única - Fachada 2, Altura do Componente Retangular: 2.12 m; EI-REV-Massa única - Fachada 2, Largura do Componente Retangular: 0.005 m; EI-REV-Massa única - Fachada 2, Área de Seção Transversal do Componente: 0.0106 m2; EI-REV-Massa única - Fachada 2, Volume Componente (Líquido): 0.473344 m3; EI-REV-Massa única - Fachada 2, Volume do componente (Bruto): 0.473344 m3
AL14 | Mureta | MURETAS | 1.794 | 0.092 | 0.092 | 0.46 | 0.0069 | 0.00138 | 0.00138 | 0.598 | 0.092 | 0.092 | 0.0023 | 0.00046 | 0.00046 |  |  |  |  |  |  |  |  | 8.34624 | 0.092 | 0.092 | 0.0644 | 0.01288 | 0.01288 |  |  |  |  |  |  |  |  |  |  |  |  |  |  |  | 4 with these values | Component Quantities - EI-REV-Pintura Acrílica Cor Cinza 1: 2 with these values
AL14 | Alvenaria de Vedação / Edificação | MURO | 336.345 | 17.2485 | 17.2485 | 2.28 | 0.0342 | 0.258727 | 0.258727 | 111.893 | 17.2143 | 17.2143 | 0.0114 | 0.0860713 | 0.0860713 | 85.3945 | 13.1376 | 13.1376 | 0.005 | 2.28 | 0.0114 | 0.0656881 | 0.0656881 | 1234.39 | 15.7645 | 15.7645 | 0.3192 | 1.90493 | 1.90493 | 101.974 | 15.6882 | 15.6882 | 0.005 | 2.28 | 0.0114 | 0.0784412 | 0.0784412 | 328.564 | 16.8495 | 16.8495 | 0.015 | 0.0342 | 0.252742 | 0.252742 | Component Quantities - EI-REV-Massa única - Fachada 2, Massa: 109.596 kg; EI-REV-Massa única - Fachada 2, Área de Componente Projetada (Líquida): 16.8609 m2; EI-REV-Massa única - Fachada 2, Área de Componente Projetada (Bruta): 16.8609 m2; EI-REV-Massa única - Fachada 2, Espessura do Componente: 0.005 m; EI-REV-Massa única - Fachada 2, Altura do Componente Retangular: 2.28 m; EI-REV-Massa única - Fachada 2, Largura do Componente Retangular: 0.005 m; EI-REV-Massa única - Fachada 2, Área de Seção Transversal do Componente: 0.0114 m2; EI-REV-Massa única - Fachada 2, Volume Componente (Líquido): 0.0843043 m3; EI-REV-Massa única - Fachada 2, Volume do componente (Bruto): 0.0843043 m3
AL14 | Mureta | MURETAS | 210.319 | 12.3962 | 12.3962 | 0.62 | 0.0093 | 0.161784 | 0.161784 | 49.3421 | 7.59109 | 7.59109 | 0.0031 | 0.0379554 | 0.0379554 |  |  |  |  |  |  |  |  | 793.511 | 12.3816 | 12.3816 | 0.0868 | 1.22455 | 1.22455 | 80.4804 | 12.3816 | 12.3816 | 0.005 | 0.62 | 0.0031 | 0.061908 | 0.061908 | 241.352 | 12.377 | 12.377 | 0.015 | 0.0093 | 0.185655 | 0.185655 | 2 with these values | Component Quantities - EI-REV-Chapisco (externo) 2: 2 with these values
AL14 | Mureta | MURETAS | 153.646 | 9.08611 | 9.08611 | 0.62 | 0.0093 | 0.118189 | 0.118189 | 35.5848 | 5.47459 | 5.47459 | 0.0031 | 0.0273729 | 0.0273729 |  |  |  |  |  |  |  |  | 575.744 | 9.08611 | 9.08611 | 0.0868 | 0.888494 | 0.888494 | 59.0597 | 9.08611 | 9.08611 | 0.005 | 0.62 | 0.0031 | 0.0454305 | 0.0454305 | 177.179 | 9.08611 | 9.08611 | 0.015 | 0.0093 | 0.136292 | 0.136292 | 2 with these values | Component Quantities - EI-REV-Chapisco (externo) 2: 2 with these values
AL14 | Mureta | MURETAS | 30.9838 | 2.178 | 10.934 | 2.2 | 0.033 | 0.0238337 | 0.15478 | 2.69862 | 0.415172 | 9.09262 | 0.011 | 0.00207586 | 0.0454631 | 2.69862 | 0.415173 | 9.09262 | 0.005 | 2.2 | 0.011 | 0.00207586 | 0.0454631 | 77.4674 | 2.178 | 10.934 | 0.308 | 0.119548 | 1.33595 | 14.157 | 2.178 | 10.934 | 0.005 | 2.2 | 0.011 | 0.01089 | 0.05467 | 42.471 | 2.178 | 10.934 | 0.015 | 0.033 | 0.03267 | 0.16401 | Component Quantities - EI-REV-Chapisco (externo) 2: 2 with these values
AL14 | Alvenaria de Vedação / Edificação | CASA DE BOMBAS / GÁS / LIXO | 74.1568 | 3.80291 | 3.80291 | 2.28 | 0.0342 | 0.0570437 | 0.0570437 | 26.3361 | 4.0517 | 4.0517 | 0.0114 | 0.0202585 | 0.0202585 |  |  |  |  |  |  |  |  | 290.686 | 4.0517 | 4.0517 | 0.3192 | 0.448589 | 0.448589 | 22.8131 | 3.50971 | 3.50971 | 0.005 | 2.28 | 0.0114 | 0.0175486 | 0.0175486 | 67.0067 | 3.43624 | 3.43624 | 0.015 | 0.0342 | 0.0515436 | 0.0515436 | 2 with these values | Component Quantities - EI-REV-Massa única - Fachada 2, Massa: 22.6844 kg; EI-REV-Massa única - Fachada 2, Área de Componente Projetada (Líquida): 3.48991 m2; EI-REV-Massa única - Fachada 2, Área de Componente Projetada (Bruta): 3.48991 m2; EI-REV-Massa única - Fachada 2, Espessura do Componente: 0.005 m; EI-REV-Massa única - Fachada 2, Altura do Componente Retangular: 2.28 m; EI-REV-Massa única - Fachada 2, Largura do Componente Retangular: 0.005 m; EI-REV-Massa única - Fachada 2, Área de Seção Transversal do Componente: 0.0114 m2; EI-REV-Massa única - Fachada 2, Volume Componente (Líquido): 0.0174496 m3; EI-REV-Massa única - Fachada 2, Volume do componente (Bruto): 0.0174496 m3
AL14 | Alvenaria de Vedação / Edificação | MURO | 1340.24 | 68.7302 | 68.7302 | 2.12 | 0.0318 | 1.03095 | 1.03095 | 446.677 | 68.7196 | 68.7196 | 0.0106 | 0.343598 | 0.343598 | 360.325 | 56.052 | 56.052 | 0.005 | 2.12 | 0.0106 | 0.277173 | 0.277173 | 5223.71 | 67.7601 | 67.7601 | 0.2968 | 8.06128 | 8.06128 | 436.765 | 67.1946 | 67.1946 | 0.005 | 2.12 | 0.0106 | 0.335973 | 0.335973 | 1308.12 | 67.083 | 67.083 | 0.015 | 0.0318 | 1.00624 | 1.00624 | Component Quantities - EI-REV-Massa única - Fachada 2, Massa: 436.536 kg; EI-REV-Massa única - Fachada 2, Área de Componente Projetada (Líquida): 67.1594 m2; EI-REV-Massa única - Fachada 2, Área de Componente Projetada (Bruta): 67.1594 m2; EI-REV-Massa única - Fachada 2, Espessura do Componente: 0.005 m; EI-REV-Massa única - Fachada 2, Altura do Componente Retangular: 2.12 m; EI-REV-Massa única - Fachada 2, Largura do Componente Retangular: 0.005 m; EI-REV-Massa única - Fachada 2, Área de Seção Transversal do Componente: 0.0106 m2; EI-REV-Massa única - Fachada 2, Volume Componente (Líquido): 0.335797 m3; EI-REV-Massa única - Fachada 2, Volume do componente (Bruto): 0.335797 m3
AL14 | Mureta | MURETAS | 52.5733 | 2.69607 | 2.69607 | 0.62 | 0.0093 | 0.040441 | 0.040441 | 17.5849 | 2.70537 | 2.70537 | 0.0031 | 0.0135268 | 0.0135268 | 17.605 | 2.70847 | 2.70847 | 0.005 | 0.62 | 0.0031 | 0.0135423 | 0.0135423 | 170.51 | 2.74352 | 2.74352 | 0.0868 | 0.263133 | 0.263133 |  |  |  |  |  |  |  |  |  |  |  |  |  |  |  | 2 with these values | Component Quantities - EI-REV-Pintura Acrílica Cor Cinza 1: 2 with these values; EI-REV-Chapisco (externo) 1: 2 with these values
AL14 | Alvenaria de Vedação / Edificação | MURO | 82.2135 | 4.48063 | 11.9134 | 2.28 | 0.0342 | 0.0632411 | 0.17457 | 23.8912 | 3.67557 | 11.0758 | 0.0114 | 0.0183779 | 0.0553789 | 23.8906 | 3.67547 | 11.0757 | 0.005 | 2.28 | 0.0114 | 0.0183774 | 0.0553784 | 342.867 | 4.11383 | 11.5466 | 0.3192 | 0.529116 | 1.56531 | 26.2624 | 4.04038 | 11.4732 | 0.005 | 2.28 | 0.0114 | 0.0202019 | 0.0573659 | 77.6563 | 3.98238 | 11.4152 | 0.015 | 0.0342 | 0.0597356 | 0.171228 | Component Quantities - EI-REV-Massa única - Fachada 2, Massa: 26.148 kg; EI-REV-Massa única - Fachada 2, Área de Componente Projetada (Líquida): 4.02278 m2; EI-REV-Massa única - Fachada 2, Área de Componente Projetada (Bruta): 11.4556 m2; EI-REV-Massa única - Fachada 2, Espessura do Componente: 0.005 m; EI-REV-Massa única - Fachada 2, Altura do Componente Retangular: 2.28 m; EI-REV-Massa única - Fachada 2, Largura do Componente Retangular: 0.005 m; EI-REV-Massa única - Fachada 2, Área de Seção Transversal do Componente: 0.0114 m2; EI-REV-Massa única - Fachada 2, Volume Componente (Líquido): 0.0201139 m3; EI-REV-Massa única - Fachada 2, Volume do componente (Bruto): 0.0572779 m3
AL14 | Mureta | MURETAS | 28.3466 | 1.45367 | 1.45367 | 0.46 | 0.0069 | 0.0218051 | 0.0218051 | 9.49372 | 1.46057 | 1.46057 | 0.0023 | 0.00730286 | 0.00730286 | 9.50867 | 1.46287 | 1.46287 | 0.005 | 0.46 | 0.0023 | 0.00731436 | 0.00731436 | 77.7077 | 1.46517 | 1.46517 | 0.0644 | 0.119919 | 0.119919 |  |  |  |  |  |  |  |  |  |  |  |  |  |  |  | 2 with these values | Component Quantities - EI-REV-Pintura Acrílica Cor Cinza 1: 2 with these values; EI-REV-Chapisco (externo) 1: 2 with these values
AL14 | Mureta | MURETAS | 21.1701 | 1.08565 | 1.08565 | 0.46 | 0.0069 | 0.0162847 | 0.0162847 | 7.10155 | 1.09255 | 1.09255 | 0.0023 | 0.00546273 | 0.00546273 | 7.1165 | 1.09485 | 1.09485 | 0.005 | 0.46 | 0.0023 | 0.00547423 | 0.00547423 | 99.5332 | 1.09715 | 1.09715 | 0.0644 | 0.153601 | 0.153601 |  |  |  |  |  |  |  |  |  |  |  |  |  |  |  | 2 with these values | Component Quantities - EI-REV-Pintura Acrílica Cor Cinza 1: 2 with these values; EI-REV-Chapisco (externo) 1: 2 with these values

# IfcWall: FNDE-AL14-E2-E2 200 (20)
In: TÉRREO
Classification: Parede (Classificação Archicad); Material: EI-REV-Pintura Acrílica Cor Cinza 0.015 m, EI-REV-Massa Acrílica (externa) 0.005 m, EI-REV-Massa única - Fachada 0.005 m, EI-REV-Chapisco (externo) 0.005 m, TIJOLO - CERAMICO 14x19x39 - espessura 20cm 0.14 m, EI-REV-Chapisco (externo) 0.005 m, EI-REV-Massa única - Fachada 0.005 m, EI-REV-Massa Acrílica (externa) 0.005 m, EI-REV-Pintura Acrílica Cor Cinza 0.015 m
FNDE - Sistemas de Cobertura: -; Esquadrias - Fechamentos metálicos e Gradis: -; 0_ID: AL14
Pset_WallCommon - IsExternal: yes; LoadBearing: no
Component Quantities - EI-REV-Pintura Acrílica Cor Cinza 1, Espessura do Componente: 0.015 m; EI-REV-Pintura Acrílica Cor Cinza 1, Largura do Componente Retangular: 0.015 m; EI-REV-Massa Acrílica (externa) 1, Espessura do Componente: 0.005 m; EI-REV-Massa Acrílica (externa) 1, Largura do Componente Retangular: 0.005 m; TIJOLO - CERAMICO 14x19x39 - espessura 20cm, Espessura do Componente: 0.14 m; TIJOLO - CERAMICO 14x19x39 - espessura 20cm, Largura do Componente Retangular: 0.14 m
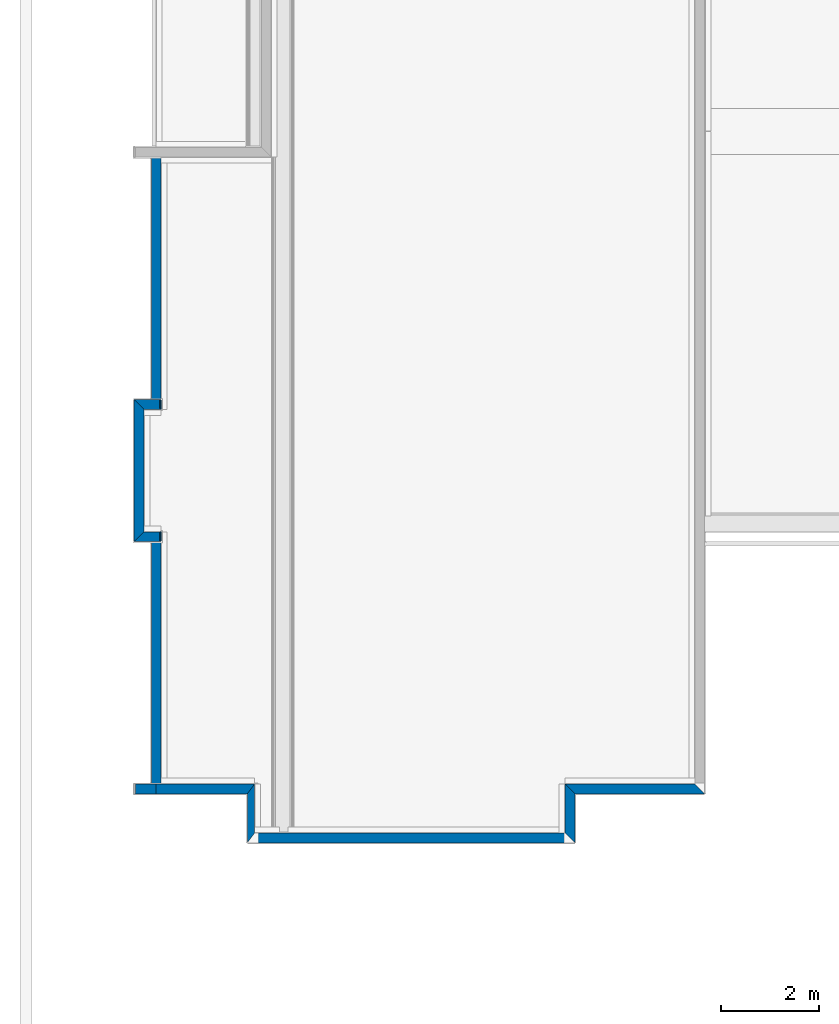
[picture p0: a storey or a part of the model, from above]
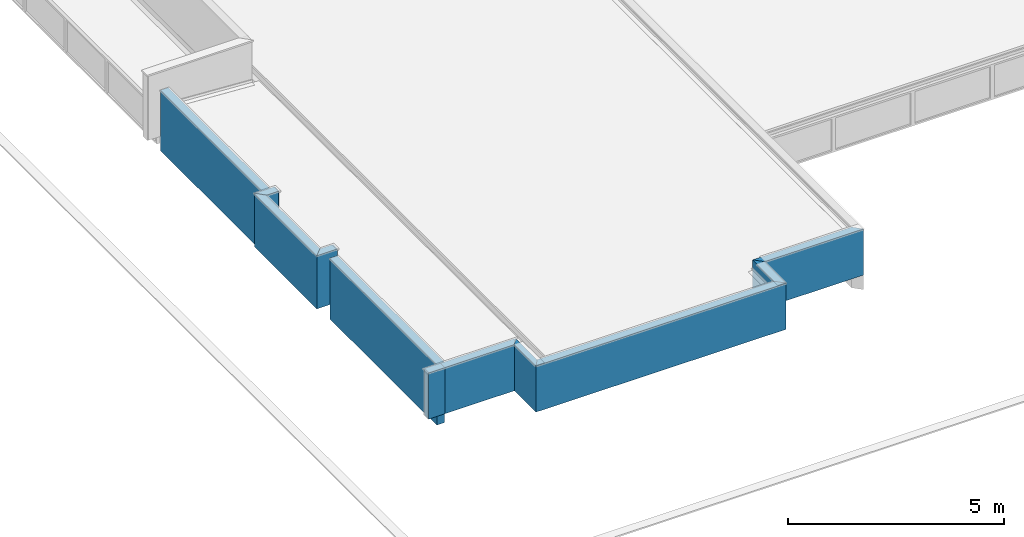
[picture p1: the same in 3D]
Properties of the parts of a building model (IFC4), part 17 of 22

# IfcWall: FNDE-AL14-E2-E2 200 (20)
Name | Alvenarias | 1_Bloco | EI-REV-Pintura Acrílica Cor Cinza 1, Massa (kg) | EI-REV-Pintura Acrílica Cor Cinza 1, Área de Componente Projetada (Líquida) (m2) | EI-REV-Pintura Acrílica Cor Cinza 1, Área de Componente Projetada (Bruta) (m2) | EI-REV-Pintura Acrílica Cor Cinza 1, Altura do Componente Retangular (m) = EI-REV-Massa Acrílica (externa) 1, Altura do Componente Retangular (m) = TIJOLO - CERAMICO 14x19x39 - espessura 20cm, Altura do Componente Retangular (m) | EI-REV-Pintura Acrílica Cor Cinza 1, Área de Seção Transversal do Componente (m2) | EI-REV-Pintura Acrílica Cor Cinza 1, Volume Componente (Líquido) (m3) | EI-REV-Pintura Acrílica Cor Cinza 1, Volume do componente (Bruto) (m3) | EI-REV-Massa Acrílica (externa) 1, Massa (kg) | EI-REV-Massa Acrílica (externa) 1, Área de Componente Projetada (Líquida) (m2) | EI-REV-Massa Acrílica (externa) 1, Área de Componente Projetada (Bruta) (m2) | EI-REV-Massa Acrílica (externa) 1, Área de Seção Transversal do Componente (m2) | EI-REV-Massa Acrílica (externa) 1, Volume Componente (Líquido) (m3) | EI-REV-Massa Acrílica (externa) 1, Volume do componente (Bruto) (m3) | EI-REV-Massa única - Fachada 1, Massa (kg) | EI-REV-Massa única - Fachada 1, Área de Componente Projetada (Líquida) (m2) | EI-REV-Massa única - Fachada 1, Área de Componente Projetada (Bruta) (m2) | EI-REV-Massa única - Fachada 1, Espessura do Componente (m) = EI-REV-Massa única - Fachada 1, Largura do Componente Retangular (m) | EI-REV-Massa única - Fachada 1, Altura do Componente Retangular (m) | EI-REV-Massa única - Fachada 1, Área de Seção Transversal do Componente (m2) | EI-REV-Massa única - Fachada 1, Volume Componente (Líquido) (m3) | EI-REV-Massa única - Fachada 1, Volume do componente (Bruto) (m3) | EI-REV-Chapisco (externo) 1, Massa (kg) | EI-REV-Chapisco (externo) 1, Área de Componente Projetada (Líquida) (m2) | EI-REV-Chapisco (externo) 1, Área de Componente Projetada (Bruta) (m2) | EI-REV-Chapisco (externo) 1, Espessura do Componente (m) = EI-REV-Chapisco (externo) 1, Largura do Componente Retangular (m) | EI-REV-Chapisco (externo) 1, Altura do Componente Retangular (m) | EI-REV-Chapisco (externo) 1, Área de Seção Transversal do Componente (m2) | EI-REV-Chapisco (externo) 1, Volume Componente (Líquido) (m3) | EI-REV-Chapisco (externo) 1, Volume do componente (Bruto) (m3) | TIJOLO - CERAMICO 14x19x39 - espessura 20cm, Massa (kg) | TIJOLO - CERAMICO 14x19x39 - espessura 20cm, Área de Componente Projetada (Líquida) (m2) | TIJOLO - CERAMICO 14x19x39 - espessura 20cm, Área de Componente Projetada (Bruta) (m2) | TIJOLO - CERAMICO 14x19x39 - espessura 20cm, Área de Seção Transversal do Componente (m2) | TIJOLO - CERAMICO 14x19x39 - espessura 20cm, Volume Componente (Líquido) (m3) | TIJOLO - CERAMICO 14x19x39 - espessura 20cm, Volume do componente (Bruto) (m3) | EI-REV-Chapisco (externo) 2, Massa (kg) | EI-REV-Chapisco (externo) 2, Área de Componente Projetada (Líquida) (m2) | EI-REV-Chapisco (externo) 2, Área de Componente Projetada (Bruta) (m2) | EI-REV-Chapisco (externo) 2, Espessura do Componente (m) = EI-REV-Chapisco (externo) 2, Largura do Componente Retangular (m) | EI-REV-Chapisco (externo) 2, Altura do Componente Retangular (m) | EI-REV-Chapisco (externo) 2, Área de Seção Transversal do Componente (m2) | EI-REV-Chapisco (externo) 2, Volume Componente (Líquido) (m3) | EI-REV-Chapisco (externo) 2, Volume do componente (Bruto) (m3) | EI-REV-Massa única - Fachada 2, Massa (kg) | EI-REV-Massa única - Fachada 2, Área de Componente Projetada (Líquida) (m2) | EI-REV-Massa única - Fachada 2, Área de Componente Projetada (Bruta) (m2) | EI-REV-Massa única - Fachada 2, Espessura do Componente (m) = EI-REV-Massa única - Fachada 2, Largura do Componente Retangular (m) | EI-REV-Massa única - Fachada 2, Altura do Componente Retangular (m) | EI-REV-Massa única - Fachada 2, Área de Seção Transversal do Componente (m2) | EI-REV-Massa única - Fachada 2, Volume Componente (Líquido) (m3) | EI-REV-Massa única - Fachada 2, Volume do componente (Bruto) (m3) | EI-REV-Massa Acrílica (externa) 2, Massa (kg) | EI-REV-Massa Acrílica (externa) 2, Área de Componente Projetada (Líquida) (m2) | EI-REV-Massa Acrílica (externa) 2, Área de Componente Projetada (Bruta) (m2) | EI-REV-Massa Acrílica (externa) 2, Espessura do Componente (m) = EI-REV-Massa Acrílica (externa) 2, Largura do Componente Retangular (m) | EI-REV-Massa Acrílica (externa) 2, Altura do Componente Retangular (m) | EI-REV-Massa Acrílica (externa) 2, Área de Seção Transversal do Componente (m2) | EI-REV-Massa Acrílica (externa) 2, Volume Componente (Líquido) (m3) | EI-REV-Massa Acrílica (externa) 2, Volume do componente (Bruto) (m3) | EI-REV-Pintura Acrílica Cor Cinza 2, Massa (kg) | EI-REV-Pintura Acrílica Cor Cinza 2, Área de Componente Projetada (Líquida) (m2) | EI-REV-Pintura Acrílica Cor Cinza 2, Área de Componente Projetada (Bruta) (m2) | EI-REV-Pintura Acrílica Cor Cinza 2, Espessura do Componente (m) = EI-REV-Pintura Acrílica Cor Cinza 2, Largura do Componente Retangular (m) | EI-REV-Pintura Acrílica Cor Cinza 2, Altura do Componente Retangular (m) | EI-REV-Pintura Acrílica Cor Cinza 2, Área de Seção Transversal do Componente (m2) | EI-REV-Pintura Acrílica Cor Cinza 2, Volume Componente (Líquido) (m3) | EI-REV-Pintura Acrílica Cor Cinza 2, Volume do componente (Bruto) (m3)
AL14 | Alvenaria de Vedação / Edificação | BLOCO B | 87.2044 | 4.47202 | 8.04392 | 3.1 | 0.0465 | 0.0670803 | 0.120659 | 29.2195 | 4.49531 | 8.06721 | 0.0155 | 0.0224765 | 0.040336 | 29.2579 | 4.50122 | 8.07312 | 0.005 | 3.1 | 0.0155 | 0.0225061 | 0.0403656 | 29.2993 | 4.50727 | 8.08477 | 0.005 | 3.1 | 0.0155 | 0.022538 | 0.0404204 | 252.749 | 2.7929 | 6.3664 | 0.434 | 0.390045 | 0.89034 | 28.3145 | 4.35617 | 7.93367 | 0.005 | 3.1 | 0.0155 | 0.0217804 | 0.0396679 | 28.2144 | 4.34067 | 7.91817 | 0.005 | 3.1 | 0.0155 | 0.0217034 | 0.0395909 | 28.2144 | 4.34067 | 7.90267 | 0.005 | 3.1 | 0.0155 | 0.0217034 | 0.0395134 | 84.6431 | 4.34067 | 7.88717 | 0.015 | 3.1 | 0.0465 | 0.0651101 | 0.118308
AL14 | Alvenaria de Vedação / Edificação | BLOCO B | 84.7008 | 4.34363 | 7.89013 | 3.1 | 0.0465 | 0.0651544 | 0.118352 | 28.2342 | 4.34363 | 7.90563 | 0.0155 | 0.0217186 | 0.0395286 | 21.7695 | 3.34898 | 6.9225 | 0.005 | 3.1 | 0.0155 | 0.0167458 | 0.0346075 | 21.8561 | 3.36248 | 6.936 | 0.005 | 3.1 | 0.0155 | 0.0168124 | 0.03468 | 259.029 | 3.72814 | 7.30564 | 0.434 | 0.399736 | 0.900065 | 29.286 | 4.50629 | 8.08379 | 0.005 | 3.1 | 0.0155 | 0.0225277 | 0.0404082 | 29.2642 | 4.50219 | 8.07409 | 0.005 | 3.1 | 0.0155 | 0.0225109 | 0.0403704 | 29.2436 | 4.49823 | 8.07013 | 0.005 | 3.1 | 0.0155 | 0.0224951 | 0.0403571 | 87.1986 | 4.47172 | 8.04362 | 0.015 | 3.1 | 0.0465 | 0.0670759 | 0.120654
AL14 | Mureta | BLOCO B | 15.444 | 0.792001 | 0.792001 | 0.19 | 0.00285 | 0.01188 | 0.01188 | 5.18018 | 0.796951 | 0.796951 | 0.00095 | 0.00398476 | 0.00398476 | 5.57313 | 0.948101 | 0.948101 | 0.005 | 0.19 | 0.00095 | 0.00428703 | 0.00428703 | 6.16882 | 0.94905 | 0.94905 | 0.005 | 0.19 | 0.00095 | 0.00474525 | 0.00474525 | 86.184 | 0.95 | 0.95 | 0.0266 | 0.133 | 0.133 |  |  |  |  |  |  |  |  | 6.16266 | 0.948101 | 0.948101 | 0.005 | 0.19 | 0.00095 | 0.00474051 | 0.00474051 | 6.15031 | 0.946201 | 0.946201 | 0.005 | 0.19 | 0.00095 | 0.00473101 | 0.00473101 | 18.3398 | 0.940501 | 0.940501 | 0.015 | 0.19 | 0.00285 | 0.0141075 | 0.0141075 | Component Quantities - EI-REV-Chapisco (externo) 1: 2 with these values
AL14 | Mureta | BLOCO B | 15.4441 | 0.792005 | 0.792005 | 0.19 | 0.00285 | 0.0118801 | 0.0118801 | 5.18213 | 0.797251 | 0.797251 | 0.00095 | 0.00398625 | 0.00398625 | 5.56814 | 0.947152 | 0.947152 | 0.005 | 0.19 | 0.00095 | 0.00428319 | 0.00428319 | 6.16266 | 0.948102 | 0.948102 | 0.005 | 0.19 | 0.00095 | 0.00474051 | 0.00474051 | 85.8761 | 0.949052 | 0.949052 | 0.0266 | 0.132525 | 0.132525 | 6.1503 | 0.9462 | 0.9462 | 0.005 | 0.19 | 0.00095 | 0.004731 | 0.004731 |  |  |  |  |  |  |  |  | 6.15031 | 0.946202 | 0.946202 | 0.005 | 0.19 | 0.00095 | 0.00473101 | 0.00473101 | 18.3399 | 0.940506 | 0.940506 | 0.015 | 0.19 | 0.00285 | 0.0141076 | 0.0141076 | Component Quantities - EI-REV-Chapisco (externo) 2: 2 with these values
AL14 | Mureta | BLOCO B | 15.4441 | 0.792004 | 0.792004 | 0.19 | 0.00285 | 0.0118801 | 0.0118801 | 5.18215 | 0.797254 | 0.797254 | 0.00095 | 0.00398627 | 0.00398627 | 5.57423 | 0.948105 | 0.948105 | 0.005 | 0.19 | 0.00095 | 0.00428787 | 0.00428787 | 6.17503 | 0.950005 | 0.950005 | 0.005 | 0.19 | 0.00095 | 0.00475002 | 0.00475002 | 86.116 | 0.951905 | 0.951905 | 0.0266 | 0.132895 | 0.132895 | 6.16265 | 0.9481 | 0.9481 | 0.005 | 0.19 | 0.00095 | 0.0047405 | 0.0047405 | 6.15648 | 0.94715 | 0.94715 | 0.005 | 0.19 | 0.00095 | 0.00473575 | 0.00473575 | 6.1503 | 0.9462 | 0.9462 | 0.005 | 0.19 | 0.00095 | 0.004731 | 0.004731 | 18.3398 | 0.940505 | 0.940505 | 0.015 | 0.19 | 0.00285 | 0.0141076 | 0.0141076
AL14 | Mureta | BLOCO B | 16.3131 | 0.88679 | 0.88679 | 0.19 | 0.00285 | 0.0125485 | 0.0125485 | 5.90844 | 0.92579 | 0.92579 | 0.00095 | 0.00454495 | 0.00454495 | 6.12233 | 0.948091 | 0.948091 | 0.005 | 0.19 | 0.00095 | 0.00470949 | 0.00470949 | 6.17491 | 0.949991 | 0.949991 | 0.005 | 0.19 | 0.00095 | 0.00474993 | 0.00474993 | 85.936 | 0.949033 | 0.949033 | 0.0266 | 0.132617 | 0.132617 | 6.15635 | 0.947131 | 0.947131 | 0.005 | 0.19 | 0.00095 | 0.00473566 | 0.00473566 | 6.15636 | 0.947133 | 0.947133 | 0.005 | 0.19 | 0.00095 | 0.00473566 | 0.00473566 | 6.15019 | 0.946183 | 0.946183 | 0.005 | 0.19 | 0.00095 | 0.00473091 | 0.00473091 | 18.3396 | 0.940491 | 0.940491 | 0.015 | 0.19 | 0.00285 | 0.0141074 | 0.0141074
AL14 | Alvenaria de Vedação / Edificação | BLOCO B | 49.1942 | 2.52387 | 6.29437 | 3.1 | 0.0465 | 0.0378417 | 0.0943999 | 5.84999 | 0.901264 | 4.68527 | 0.0155 | 0.00449999 | 0.023402 | 5.77047 | 0.887764 | 4.68527 | 0.005 | 3.1 | 0.0155 | 0.00443882 | 0.0234263 |  |  |  |  |  |  |  |  | 80.538 | 0.887764 | 4.68527 | 0.434 | 0.124287 | 0.655937 | 5.74455 | 0.883777 | 4.68128 | 0.005 | 3.1 | 0.0155 | 0.00441888 | 0.0234064 | 5.73805 | 0.882777 | 4.68028 | 0.005 | 3.1 | 0.0155 | 0.00441388 | 0.0234014 | 5.74067 | 0.881868 | 4.67937 | 0.005 | 3.1 | 0.0155 | 0.0044159 | 0.0234183 | 46.917 | 2.406 | 6.2075 | 0.015 | 3.1 | 0.0465 | 0.03609 | 0.0931125 | Component Quantities - EI-REV-Massa única - Fachada 1: 2 with these values
AL14 | Alvenaria de Vedação / Edificação | BLOCO B | 48.0918 | 2.47066 | 6.27216 | 3.1 | 0.0465 | 0.0369937 | 0.094016 | 6.19416 | 0.952948 | 4.75044 | 0.0155 | 0.00476474 | 0.0237522 | 6.20067 | 0.953949 | 4.75144 | 0.005 | 3.1 | 0.0155 | 0.00476974 | 0.0237572 | 6.20716 | 0.954947 | 4.75244 | 0.005 | 3.1 | 0.0155 | 0.00477474 | 0.0237622 | 86.6399 | 0.955035 | 4.75253 | 0.434 | 0.133704 | 0.665352 | 5.42669 | 0.834884 | 4.63237 | 0.005 | 3.1 | 0.0155 | 0.00417438 | 0.0231618 | 5.33998 | 0.821535 | 4.61903 | 0.005 | 3.1 | 0.0155 | 0.00410767 | 0.0230951 | 5.4321 | 2.43082 | 6.21682 | 0.005 | 3.1 | 0.0155 | 0.00417854 | 0.0230986 | 47.3741 | 2.43097 | 6.20147 | 0.015 | 3.1 | 0.0465 | 0.0364416 | 0.0929992
AL14 | Alvenaria de Vedação / Edificação | BLOCO A | 90.6726 | 4.64988 | 7.84638 | 3.1 | 0.0465 | 0.0697482 | 0.117696 | 30.3107 | 4.66318 | 7.87518 | 0.0155 | 0.0233159 | 0.0393759 | 30.57 | 4.70308 | 7.93058 | 0.005 | 3.1 | 0.0155 | 0.0235154 | 0.0396529 | 30.1612 | 4.65006 | 7.87756 | 0.005 | 3.1 | 0.0155 | 0.0232009 | 0.0393382 | 313.186 | 5.31356 | 8.54106 | 0.434 | 0.483312 | 0.934601 | 32.1995 | 4.96096 | 8.18846 | 0.005 | 3.1 | 0.0155 | 0.0247688 | 0.0409001 | 32.2176 | 4.95656 | 8.17847 | 0.005 | 3.1 | 0.0155 | 0.0247828 | 0.0408924 | 31.9258 | 4.91166 | 8.13357 | 0.005 | 3.1 | 0.0155 | 0.0245583 | 0.0406679 | 95.404 | 4.89376 | 8.11567 | 0.015 | 3.1 | 0.0465 | 0.0733877 | 0.121716
AL14 | Alvenaria de Vedação / Edificação | BLOCO A | 91.5409 | 4.69441 | 7.89091 | 3.1 | 0.0465 | 0.0704161 | 0.118364 | 30.5006 | 4.69241 | 7.90441 | 0.0155 | 0.023462 | 0.039522 | 30.4876 | 4.69041 | 7.91791 | 0.005 | 3.1 | 0.0155 | 0.023452 | 0.0395895 | 30.5754 | 4.70391 | 7.93141 | 0.005 | 3.1 | 0.0155 | 0.0235195 | 0.039657 | 285.01 | 4.94691 | 8.17441 | 0.434 | 0.43983 | 0.891118 | 31.618 | 4.88389 | 8.11139 | 0.005 | 3.1 | 0.0155 | 0.0243216 | 0.0404538 | 31.6901 | 4.87541 | 8.09732 | 0.005 | 3.1 | 0.0155 | 0.024377 | 0.0404866 | 31.6349 | 4.86691 | 8.08882 | 0.005 | 3.1 | 0.0155 | 0.0243345 | 0.0404441 | 94.44 | 4.84308 | 8.06499 | 0.015 | 3.1 | 0.0465 | 0.0726462 | 0.120975
AL14 | Mureta | BLOCO A | 42.5994 | 2.18458 | 2.18458 | 0.44 | 0.0066 | 0.0327687 | 0.0327687 | 14.2427 | 2.19118 | 2.19118 | 0.0022 | 0.0109559 | 0.0109559 | 14.257 | 2.19338 | 2.19338 | 0.005 | 0.44 | 0.0022 | 0.0109669 | 0.0109669 | 14.2713 | 2.19558 | 2.19558 | 0.005 | 0.44 | 0.0022 | 0.0109779 | 0.0109779 | 199.381 | 2.19778 | 2.19778 | 0.0616 | 0.307686 | 0.307686 |  |  |  |  |  |  |  |  |  |  |  |  |  |  |  |  | 14.2428 | 2.19338 | 2.19338 | 0.005 | 0.44 | 0.0022 | 0.010956 | 0.010956 | 42.5896 | 2.18458 | 2.18458 | 0.015 | 0.44 | 0.0066 | 0.0327613 | 0.0327613 | Component Quantities - EI-REV-Chapisco (externo) 1: 2 with these values; EI-REV-Massa única - Fachada 1: 2 with these values
AL14 | Mureta | BLOCO A | 42.5995 | 2.18459 | 2.18459 | 0.44 | 0.0066 | 0.0327688 | 0.0327688 | 14.2429 | 2.19122 | 2.19122 | 0.0022 | 0.0109561 | 0.0109561 | 14.2572 | 2.19342 | 2.19342 | 0.005 | 0.44 | 0.0022 | 0.0109671 | 0.0109671 | 14.2715 | 2.19562 | 2.19562 | 0.005 | 0.44 | 0.0022 | 0.0109781 | 0.0109781 | 199.385 | 2.19782 | 2.19782 | 0.0616 | 0.307692 | 0.307692 |  |  |  |  |  |  |  |  |  |  |  |  |  |  |  |  | 14.2431 | 2.19339 | 2.19339 | 0.005 | 0.44 | 0.0022 | 0.0109562 | 0.0109562 | 42.5893 | 2.18459 | 2.18459 | 0.015 | 0.44 | 0.0066 | 0.032761 | 0.032761 | Component Quantities - EI-REV-Chapisco (externo) 1: 2 with these values; EI-REV-Massa única - Fachada 1: 2 with these values
AL14 | Alvenaria de Vedação / Edificação | BLOCO A | 66.2025 | 3.395 | 7.2075 | 3.1 | 0.0465 | 0.050925 | 0.107693 | 22.0675 | 3.395 | 7.195 | 0.0155 | 0.016975 | 0.035975 | 22.0675 | 3.395 | 7.2105 | 0.005 | 3.1 | 0.0155 | 0.016975 | 0.0360525 | 21.8841 | 3.4105 | 7.226 | 0.005 | 3.1 | 0.0155 | 0.0168339 | 0.0360312 | 173.94 | 3.6215 | 7.437 | 0.434 | 0.268427 | 0.802155 | 23.1393 | 3.5599 | 7.3754 | 0.005 | 3.1 | 0.0155 | 0.0177995 | 0.036877 | 23.1107 | 3.5555 | 7.371 | 0.005 | 3.1 | 0.0155 | 0.0177775 | 0.036855 | 23.0821 | 3.5511 | 7.3666 | 0.005 | 3.1 | 0.0155 | 0.0177555 | 0.036833 | 69.1522 | 3.5467 | 7.3622 | 0.015 | 3.1 | 0.0465 | 0.053194 | 0.11043
AL14 | Alvenaria de Vedação / Edificação | BLOCO A | 90.4283 | 4.643 | 7.8395 | 3.1 | 0.0465 | 0.0695602 | 0.117508 | 17.6343 | 2.71297 | 5.92296 | 0.0155 | 0.0135648 | 0.0296148 | 17.5468 | 2.6995 | 5.92299 | 0.005 | 3.1 | 0.0155 | 0.0134975 | 0.029615 | 17.4325 | 2.68192 | 5.90541 | 0.005 | 3.1 | 0.0155 | 0.0134096 | 0.029527 | 243.304 | 2.68192 | 5.90541 | 0.434 | 0.375469 | 0.826757 |  |  |  |  |  |  |  |  |  |  |  |  |  |  |  |  | 17.5585 | 4.88909 | 8.11659 | 0.005 | 3.1 | 0.0155 | 0.0135065 | 0.0296241 | 95.1344 | 4.87869 | 8.10619 | 0.015 | 3.1 | 0.0465 | 0.0731803 | 0.121593 | Component Quantities - EI-REV-Chapisco (externo) 1: 3 with these values
AL14 | Mureta | BLOCO A | 42.471 | 2.178 | 2.178 | 0.44 | 0.0066 | 0.03267 | 0.03267 | 14.2407 | 2.19087 | 2.19087 | 0.0022 | 0.0109544 | 0.0109544 | 14.2408 | 2.19089 | 2.19089 | 0.005 | 0.44 | 0.0022 | 0.0109545 | 0.0109545 |  |  |  |  |  |  |  |  | 198.758 | 2.19089 | 2.19089 | 0.0616 | 0.306725 | 0.306725 |  |  |  |  |  |  |  |  |  |  |  |  |  |  |  |  | 14.2407 | 2.1912 | 2.1912 | 0.005 | 0.44 | 0.0022 | 0.0109544 | 0.0109544 | Component Quantities - EI-REV-Massa única - Fachada 1: 4 with these values; EI-REV-Pintura Acrílica Cor Cinza 1: 2 with these values
AL14 | Mureta | BLOCO A | 42.471 | 2.178 | 2.178 | 0.44 | 0.0066 | 0.03267 | 0.03267 | 14.1999 | 2.1846 | 2.1846 | 0.0022 | 0.010923 | 0.010923 | 14.2142 | 2.1868 | 2.1868 | 0.005 | 0.44 | 0.0022 | 0.010934 | 0.010934 | 14.2285 | 2.189 | 2.189 | 0.005 | 0.44 | 0.0022 | 0.010945 | 0.010945 | 198.786 | 2.1912 | 2.1912 | 0.0616 | 0.306768 | 0.306768 | Component Quantities - EI-REV-Chapisco (externo) 1: 2 with these values; EI-REV-Massa única - Fachada 1: 2 with these values; EI-REV-Pintura Acrílica Cor Cinza 1: 2 with these values; EI-REV-Massa Acrílica (externa) 1: 2 with these values
AL14 | Mureta | BLOCO A | 42.3428 | 2.17142 | 2.17142 | 0.44 | 0.0066 | 0.0325714 | 0.0325714 | 14.2001 | 2.18462 | 2.18462 | 0.0022 | 0.0109231 | 0.0109231 | 14.2211 | 2.18902 | 2.18902 | 0.005 | 0.44 | 0.0022 | 0.0109393 | 0.0109393 | 14.2288 | 2.18904 | 2.18904 | 0.005 | 0.44 | 0.0022 | 0.0109452 | 0.0109452 | 198.79 | 2.19124 | 2.19124 | 0.0616 | 0.306774 | 0.306774 | 13.2635 | 2.04054 | 2.04054 | 0.005 | 0.44 | 0.0022 | 0.0102027 | 0.0102027 | 13.2492 | 2.03834 | 2.03834 | 0.005 | 0.44 | 0.0022 | 0.0101917 | 0.0101917 | 13.2348 | 2.03612 | 2.03612 | 0.005 | 0.44 | 0.0022 | 0.0101806 | 0.0101806 | 39.4558 | 2.02337 | 2.02337 | 0.015 | 0.44 | 0.0066 | 0.0303506 | 0.0303506
AL14 | Mureta | BLOCO B | 42.4719 | 2.17804 | 2.17804 | 0.44 | 0.0066 | 0.0326707 | 0.0326707 | 14.1573 | 2.17804 | 2.17804 | 0.0022 | 0.0108902 | 0.0108902 |  |  |  |  |  |  |  |  |  |  |  |  |  |  |  |  | 197.592 | 2.17804 | 2.17804 | 0.0616 | 0.304926 | 0.304926 |  |  |  |  |  |  |  |  | 14.291 | 2.21542 | 2.21542 | 0.005 | 0.44 | 0.0022 | 0.0109931 | 0.0109931 | 14.4003 | 2.21542 | 2.21542 | 0.005 | 0.44 | 0.0022 | 0.0110771 | 0.0110771 | 43.1531 | 2.21543 | 2.21543 | 0.015 | 0.44 | 0.0066 | 0.0331947 | 0.0331947 | Component Quantities - EI-REV-Massa Acrílica (externa) 1: 4 with these values
AL14 | Alvenaria de Vedação / Edificação | CASA DE BOMBAS / GÁS / LIXO | 28.0517 | 1.43855 | 3.546 | 2.1 | 0.0315 | 0.0215783 | 0.05319 | 9.46758 | 1.45655 | 3.564 | 0.0105 | 0.00728275 | 0.01782 | 9.40323 | 1.44665 | 3.5541 | 0.005 | 2.1 | 0.0105 | 0.00723325 | 0.0177705 |  |  |  |  |  |  |  |  | 131.24 | 1.44665 | 3.5541 | 0.294 | 0.202531 | 0.497574 | 7.04958 | 1.08455 | 3.0225 | 0.005 | 2.1 | 0.0105 | 0.00542275 | 0.0151125 | 6.92575 | 1.0655 | 3.00345 | 0.005 | 2.1 | 0.0105 | 0.0053275 | 0.0150173 | 6.86628 | 1.05635 | 2.9943 | 0.005 | 2.1 | 0.0105 | 0.00528175 | 0.0149715 | 19.5263 | 1.00135 | 2.9393 | 0.015 | 2.1 | 0.0315 | 0.0150203 | 0.0440895 | Component Quantities - EI-REV-Massa única - Fachada 1: 2 with these values
AL14 | Alvenaria de Vedação / Edificação | CASA DE BOMBAS / GÁS / LIXO | 32.3487 | 1.65891 | 1.91091 | 2.12 | 0.0318 | 0.0248836 | 0.0286636 | 10.9766 | 1.68871 | 1.94071 | 0.0106 | 0.00844355 | 0.00970355 | 10.9123 | 1.67881 | 1.93081 | 0.005 | 2.12 | 0.0106 | 0.00839405 | 0.00965405 | 10.9129 | 1.67891 | 1.93091 | 0.005 | 2.12 | 0.0106 | 0.00839455 | 0.00965455 | 129.857 | 1.43141 | 1.68341 | 0.2968 | 0.200397 | 0.235677 | 8.25701 | 1.27031 | 1.52231 | 0.005 | 2.12 | 0.0106 | 0.00635154 | 0.00761154 | 8.13253 | 1.25116 | 1.50316 | 0.005 | 2.12 | 0.0106 | 0.00625579 | 0.00751579 | 8.07306 | 1.24201 | 1.49401 | 0.005 | 2.12 | 0.0106 | 0.00621004 | 0.00747004 | 22.9458 | 1.17671 | 1.42871 | 0.015 | 2.12 | 0.0318 | 0.0176506 | 0.0214306

# IfcWall: FNDE-AL14-E4 (vermelho) 170 x 3640, AL14
In: TÉRREO
Classification: Parede (Classificação Archicad); Material: TIJOLO - CERAMICO 14x19x39 - espessura 20cm, EI-REV-Chapisco (externo), EI-REV-Massa única - Fachada, EI-REV-Massa Acrílica (externa), EI-REV-Pintura Acrílica Cor Vermelho Externa
FNDE - Alvenarias: Alvenaria de Vedação / Edificação; Sistemas de Cobertura: -; Esquadrias - Fechamentos metálicos e Gradis: -; 1_Bloco: BLOCO A; 0_ID: AL14
Pset_WallCommon - IsExternal: yes; LoadBearing: no
Component Quantities - TIJOLO - CERAMICO 14x19x39 - espessura 20cm, Massa: 349.943 kg; TIJOLO - CERAMICO 14x19x39 - espessura 20cm, Área de Componente Projetada (Líquida): 4.82378 m2; TIJOLO - CERAMICO 14x19x39 - espessura 20cm, Área de Componente Projetada (Bruta): 4.82378 m2; TIJOLO - CERAMICO 14x19x39 - espessura 20cm, Altura do Componente Retangular: 3.64 m; TIJOLO - CERAMICO 14x19x39 - espessura 20cm, Largura do Componente Retangular: 0.14 m; TIJOLO - CERAMICO 14x19x39 - espessura 20cm, Área de Seção Transversal do Componente: 0.5096 m2; TIJOLO - CERAMICO 14x19x39 - espessura 20cm, Volume Componente (Líquido): 0.540035 m3; TIJOLO - CERAMICO 14x19x39 - espessura 20cm, Volume do componente (Bruto): 0.540035 m3; EI-REV-Chapisco (externo), Massa: 30.7579 kg; EI-REV-Chapisco (externo), Área de Componente Projetada (Líquida): 4.732 m2; EI-REV-Chapisco (externo), Área de Componente Projetada (Bruta): 4.732 m2; EI-REV-Chapisco (externo), Altura do Componente Retangular: 3.64 m; EI-REV-Chapisco (externo), Largura do Componente Retangular: 0.00499998 m; EI-REV-Chapisco (externo), Área de Seção Transversal do Componente: 0.0181999 m2; EI-REV-Chapisco (externo), Volume Componente (Líquido): 0.0236599 m3; EI-REV-Chapisco (externo), Volume do componente (Bruto): 0.0236599 m3; EI-REV-Massa única - Fachada, Massa: 30.758 kg; EI-REV-Massa única - Fachada, Área de Componente Projetada (Líquida): 4.732 m2; EI-REV-Massa única - Fachada, Área de Componente Projetada (Bruta): 4.732 m2; EI-REV-Massa única - Fachada, Altura do Componente Retangular: 3.64 m; EI-REV-Massa única - Fachada, Largura do Componente Retangular: 0.005 m; EI-REV-Massa única - Fachada, Área de Seção Transversal do Componente: 0.0182 m2; EI-REV-Massa única - Fachada, Volume Componente (Líquido): 0.02366 m3; EI-REV-Massa única - Fachada, Volume do componente (Bruto): 0.02366 m3; EI-REV-Pintura Acrílica Cor Vermelho Externa, Massa: 92.274 kg; EI-REV-Pintura Acrílica Cor Vermelho Externa, Área de Componente Projetada (Líquida): 4.732 m2; EI-REV-Pintura Acrílica Cor Vermelho Externa, Área de Componente Projetada (Bruta): 4.732 m2; EI-REV-Pintura Acrílica Cor Vermelho Externa, Altura do Componente Retangular: 3.64 m; EI-REV-Pintura Acrílica Cor Vermelho Externa, Largura do Componente Retangular: 0.015 m; EI-REV-Pintura Acrílica Cor Vermelho Externa, Área de Seção Transversal do Componente: 0.0546 m2; EI-REV-Pintura Acrílica Cor Vermelho Externa, Volume Componente (Líquido): 0.07098 m3; EI-REV-Pintura Acrílica Cor Vermelho Externa, Volume do componente (Bruto): 0.07098 m3; EI-REV-Chapisco (externo): 2 with these values

# IfcWall: FNDE-AL14-E5 (branco) 170 x 3640, AL14
In: TÉRREO
Classification: Parede (Classificação Archicad); Material: TIJOLO - CERAMICO 14x19x39 - espessura 20cm, EI-REV-Chapisco (externo), EI-REV-Massa única - Fachada, EI-REV-Massa Acrílica (externa), EI-REV-Pintura Acrílica Cor Branco Gelo
FNDE - Alvenarias: Alvenaria de Vedação / Edificação; Sistemas de Cobertura: -; Esquadrias - Fechamentos metálicos e Gradis: -; 1_Bloco: BLOCO A; 0_ID: AL14
Pset_WallCommon - IsExternal: yes; LoadBearing: no
Component Quantities - TIJOLO - CERAMICO 14x19x39 - espessura 20cm, Massa: 239.368 kg; TIJOLO - CERAMICO 14x19x39 - espessura 20cm, Área de Componente Projetada (Líquida): 3.44777 m2; TIJOLO - CERAMICO 14x19x39 - espessura 20cm, Área de Componente Projetada (Bruta): 3.44777 m2; TIJOLO - CERAMICO 14x19x39 - espessura 20cm, Altura do Componente Retangular: 3.64 m; TIJOLO - CERAMICO 14x19x39 - espessura 20cm, Largura do Componente Retangular: 0.14 m; TIJOLO - CERAMICO 14x19x39 - espessura 20cm, Área de Seção Transversal do Componente: 0.5096 m2; TIJOLO - CERAMICO 14x19x39 - espessura 20cm, Volume Componente (Líquido): 0.369395 m3; TIJOLO - CERAMICO 14x19x39 - espessura 20cm, Volume do componente (Bruto): 0.369395 m3; EI-REV-Chapisco (externo), Massa: 22.537 kg; EI-REV-Chapisco (externo), Área de Componente Projetada (Líquida): 3.46724 m2; EI-REV-Chapisco (externo), Área de Componente Projetada (Bruta): 3.46724 m2; EI-REV-Chapisco (externo), Altura do Componente Retangular: 3.64 m; EI-REV-Chapisco (externo), Largura do Componente Retangular: 0.00499998 m; EI-REV-Chapisco (externo), Área de Seção Transversal do Componente: 0.0181999 m2; EI-REV-Chapisco (externo), Volume Componente (Líquido): 0.0173361 m3; EI-REV-Chapisco (externo), Volume do componente (Bruto): 0.0173361 m3; EI-REV-Massa única - Fachada, Massa: 24.9406 kg; EI-REV-Massa única - Fachada, Área de Componente Projetada (Líquida): 3.84004 m2; EI-REV-Massa única - Fachada, Área de Componente Projetada (Bruta): 3.84004 m2; EI-REV-Massa única - Fachada, Altura do Componente Retangular: 3.64 m; EI-REV-Massa única - Fachada, Largura do Componente Retangular: 0.005 m; EI-REV-Massa única - Fachada, Área de Seção Transversal do Componente: 0.0182 m2; EI-REV-Massa única - Fachada, Volume Componente (Líquido): 0.0191851 m3; EI-REV-Massa única - Fachada, Volume do componente (Bruto): 0.0191851 m3; EI-REV-Massa Acrílica (externa), Massa: 25.1968 kg; EI-REV-Massa Acrílica (externa), Área de Componente Projetada (Líquida): 3.87644 m2; EI-REV-Massa Acrílica (externa), Área de Componente Projetada (Bruta): 3.87644 m2; EI-REV-Massa Acrílica (externa), Altura do Componente Retangular: 3.64 m; EI-REV-Massa Acrílica (externa), Largura do Componente Retangular: 0.00499998 m; EI-REV-Massa Acrílica (externa), Área de Seção Transversal do Componente: 0.0181999 m2; EI-REV-Massa Acrílica (externa), Volume Componente (Líquido): 0.0193821 m3; EI-REV-Massa Acrílica (externa), Volume do componente (Bruto): 0.0193821 m3; EI-REV-Pintura Acrílica Cor Branco Gelo, Massa: 74.5291 kg; EI-REV-Pintura Acrílica Cor Branco Gelo, Área de Componente Projetada (Líquida): 3.822 m2; EI-REV-Pintura Acrílica Cor Branco Gelo, Área de Componente Projetada (Bruta): 3.822 m2; EI-REV-Pintura Acrílica Cor Branco Gelo, Altura do Componente Retangular: 3.64 m; EI-REV-Pintura Acrílica Cor Branco Gelo, Largura do Componente Retangular: 0.015 m; EI-REV-Pintura Acrílica Cor Branco Gelo, Área de Seção Transversal do Componente: 0.0546 m2; EI-REV-Pintura Acrílica Cor Branco Gelo, Volume Componente (Líquido): 0.0573301 m3; EI-REV-Pintura Acrílica Cor Branco Gelo, Volume do componente (Bruto): 0.0573301 m3

# IfcWall: FNDE-AL14-E5-E3 200 (2)
In: TÉRREO
Classification: Parede (Classificação Archicad); Material: EI-REV-Pintura Acrílica Cor Branco Gelo 0.015 m, EI-REV-Massa Acrílica (externa) 0.005 m, EI-REV-Massa única - Fachada 0.005 m, EI-REV-Chapisco (externo) 0.005 m, TIJOLO - CERAMICO 14x19x39 - espessura 20cm 0.14 m, EI-REV-Chapisco (externo) 0.005 m, EI-REV-Massa única - Fachada 0.005 m, EI-REV-Massa Acrílica (externa) 0.005 m, EI-REV-Pintura Acrílica Cor Azul Externa 0.015 m
FNDE - Alvenarias: Alvenaria de Vedação / Edificação; Sistemas de Cobertura: -; Esquadrias - Fechamentos metálicos e Gradis: -; 1_Bloco: BLOCO A; 0_ID: AL14
Pset_WallCommon - IsExternal: yes; LoadBearing: no
Component Quantities - EI-REV-Pintura Acrílica Cor Branco Gelo, Espessura do Componente: 0.015 m; EI-REV-Pintura Acrílica Cor Branco Gelo, Altura do Componente Retangular: 3.1 m; EI-REV-Pintura Acrílica Cor Branco Gelo, Largura do Componente Retangular: 0.015 m; EI-REV-Pintura Acrílica Cor Branco Gelo, Área de Seção Transversal do Componente: 0.0465 m2; EI-REV-Massa Acrílica (externa) 1, Espessura do Componente: 0.005 m; EI-REV-Massa Acrílica (externa) 1, Altura do Componente Retangular: 3.1 m; EI-REV-Massa Acrílica (externa) 1, Largura do Componente Retangular: 0.005 m; EI-REV-Massa Acrílica (externa) 1, Área de Seção Transversal do Componente: 0.0155 m2; EI-REV-Massa única - Fachada 1, Espessura do Componente: 0.005 m; EI-REV-Massa única - Fachada 1, Altura do Componente Retangular: 3.1 m; EI-REV-Massa única - Fachada 1, Largura do Componente Retangular: 0.005 m; EI-REV-Massa única - Fachada 1, Área de Seção Transversal do Componente: 0.0155 m2; TIJOLO - CERAMICO 14x19x39 - espessura 20cm, Espessura do Componente: 0.14 m; TIJOLO - CERAMICO 14x19x39 - espessura 20cm, Altura do Componente Retangular: 3.1 m; TIJOLO - CERAMICO 14x19x39 - espessura 20cm, Largura do Componente Retangular: 0.14 m; TIJOLO - CERAMICO 14x19x39 - espessura 20cm, Área de Seção Transversal do Componente: 0.434 m2; EI-REV-Chapisco (externo) 2, Espessura do Componente: 0.005 m; EI-REV-Chapisco (externo) 2, Altura do Componente Retangular: 3.1 m; EI-REV-Chapisco (externo) 2, Largura do Componente Retangular: 0.005 m; EI-REV-Chapisco (externo) 2, Área de Seção Transversal do Componente: 0.0155 m2; EI-REV-Massa única - Fachada 2, Espessura do Componente: 0.005 m; EI-REV-Massa única - Fachada 2, Altura do Componente Retangular: 3.1 m; EI-REV-Massa única - Fachada 2, Largura do Componente Retangular: 0.005 m; EI-REV-Massa única - Fachada 2, Área de Seção Transversal do Componente: 0.0155 m2; EI-REV-Massa Acrílica (externa) 2, Espessura do Componente: 0.005 m; EI-REV-Massa Acrílica (externa) 2, Altura do Componente Retangular: 3.1 m; EI-REV-Massa Acrílica (externa) 2, Largura do Componente Retangular: 0.005 m; EI-REV-Massa Acrílica (externa) 2, Área de Seção Transversal do Componente: 0.0155 m2; EI-REV-Pintura Acrílica Cor Azul Externa, Espessura do Componente: 0.015 m; EI-REV-Pintura Acrílica Cor Azul Externa, Altura do Componente Retangular: 3.1 m; EI-REV-Pintura Acrílica Cor Azul Externa, Largura do Componente Retangular: 0.015 m; EI-REV-Pintura Acrílica Cor Azul Externa, Área de Seção Transversal do Componente: 0.0465 m2
Name | EI-REV-Pintura Acrílica Cor Branco Gelo, Massa (kg) | EI-REV-Pintura Acrílica Cor Branco Gelo, Área de Componente Projetada (Líquida) (m2) | EI-REV-Pintura Acrílica Cor Branco Gelo, Área de Componente Projetada (Bruta) (m2) | EI-REV-Pintura Acrílica Cor Branco Gelo, Volume Componente (Líquido) (m3) | EI-REV-Pintura Acrílica Cor Branco Gelo, Volume do componente (Bruto) (m3) | EI-REV-Massa Acrílica (externa) 1, Massa (kg) | EI-REV-Massa Acrílica (externa) 1, Área de Componente Projetada (Líquida) (m2) | EI-REV-Massa Acrílica (externa) 1, Área de Componente Projetada (Bruta) (m2) | EI-REV-Massa Acrílica (externa) 1, Volume Componente (Líquido) (m3) | EI-REV-Massa Acrílica (externa) 1, Volume do componente (Bruto) (m3) | EI-REV-Massa única - Fachada 1, Massa (kg) | EI-REV-Massa única - Fachada 1, Área de Componente Projetada (Líquida) (m2) | EI-REV-Massa única - Fachada 1, Área de Componente Projetada (Bruta) (m2) | EI-REV-Massa única - Fachada 1, Volume Componente (Líquido) (m3) | EI-REV-Massa única - Fachada 1, Volume do componente (Bruto) (m3) | TIJOLO - CERAMICO 14x19x39 - espessura 20cm, Massa (kg) | TIJOLO - CERAMICO 14x19x39 - espessura 20cm, Área de Componente Projetada (Líquida) (m2) | TIJOLO - CERAMICO 14x19x39 - espessura 20cm, Área de Componente Projetada (Bruta) (m2) | TIJOLO - CERAMICO 14x19x39 - espessura 20cm, Volume Componente (Líquido) (m3) | TIJOLO - CERAMICO 14x19x39 - espessura 20cm, Volume do componente (Bruto) (m3) | EI-REV-Chapisco (externo) 2, Massa (kg) | EI-REV-Chapisco (externo) 2, Área de Componente Projetada (Líquida) (m2) | EI-REV-Chapisco (externo) 2, Área de Componente Projetada (Bruta) (m2) | EI-REV-Chapisco (externo) 2, Volume Componente (Líquido) (m3) | EI-REV-Chapisco (externo) 2, Volume do componente (Bruto) (m3) | EI-REV-Massa única - Fachada 2, Massa (kg) | EI-REV-Massa única - Fachada 2, Área de Componente Projetada (Líquida) (m2) | EI-REV-Massa única - Fachada 2, Área de Componente Projetada (Bruta) (m2) | EI-REV-Massa única - Fachada 2, Volume Componente (Líquido) (m3) | EI-REV-Massa única - Fachada 2, Volume do componente (Bruto) (m3) | EI-REV-Massa Acrílica (externa) 2, Massa (kg) | EI-REV-Massa Acrílica (externa) 2, Área de Componente Projetada (Líquida) (m2) | EI-REV-Massa Acrílica (externa) 2, Área de Componente Projetada (Bruta) (m2) | EI-REV-Massa Acrílica (externa) 2, Volume Componente (Líquido) (m3) | EI-REV-Massa Acrílica (externa) 2, Volume do componente (Bruto) (m3) | EI-REV-Pintura Acrílica Cor Azul Externa, Massa (kg) | EI-REV-Pintura Acrílica Cor Azul Externa, Área de Componente Projetada (Líquida) (m2) = EI-REV-Pintura Acrílica Cor Azul Externa, Área de Componente Projetada (Bruta) (m2) | EI-REV-Pintura Acrílica Cor Azul Externa, Volume Componente (Líquido) (m3) = EI-REV-Pintura Acrílica Cor Azul Externa, Volume do componente (Bruto) (m3)
AL14 | 35.5103 | 1.82875 | 1.87524 | 0.0273156 | 0.0280124 | 5.13122 | 0.891147 | 0.953144 | 0.0039471 | 0.00424837 | 5.05322 | 0.777418 | 0.85092 | 0.00388709 | 0.0042546 | 108.956 | 1.20102 | 1.27452 | 0.168143 | 0.178433 | 7.89437 | 1.21452 | 1.28802 | 0.00607259 | 0.0064401 | 7.98212 | 1.22802 | 1.30152 | 0.00614009 | 0.0065076 | 8.07215 | 1.24149 | 1.31498 | 0.00620935 | 0.00657739 | 45.353 | 2.33544 | 0.0348869 | Component Quantities - EI-REV-Massa única - Fachada 1: 2 with these values
AL14 | 35.45 | 1.82877 | 1.87527 | 0.0272693 | 0.0279666 | 5.0262 | 0.773263 | 0.83327 | 0.00386631 | 0.00416635 | 5.05349 | 0.777461 | 0.850969 | 0.0038873 | 0.00425484 | 108.959 | 1.20106 | 1.27457 | 0.168146 | 0.178437 | 7.89449 | 1.21454 | 1.28805 | 0.00607269 | 0.00644023 | 7.98224 | 1.22804 | 1.30155 | 0.00614019 | 0.00650773 | 8.32126 | 2.23267 | 2.31017 | 0.00640097 | 0.00677159 | 45.6948 | 2.34347 | 0.0351499 | Component Quantities - EI-REV-Chapisco (externo) 1, Massa: 5.05348 kg; EI-REV-Chapisco (externo) 1, Área de Componente Projetada (Líquida): 0.77746 m2; EI-REV-Chapisco (externo) 1, Área de Componente Projetada (Bruta): 0.850968 m2; EI-REV-Chapisco (externo) 1, Espessura do Componente: 0.005 m; EI-REV-Chapisco (externo) 1, Altura do Componente Retangular: 3.1 m; EI-REV-Chapisco (externo) 1, Largura do Componente Retangular: 0.005 m; EI-REV-Chapisco (externo) 1, Área de Seção Transversal do Componente: 0.0155 m2; EI-REV-Chapisco (externo) 1, Volume Componente (Líquido): 0.00388729 m3; EI-REV-Chapisco (externo) 1, Volume do componente (Bruto): 0.00425483 m3

# IfcWall: FNDE-AL14-E5-E5 (branco) 200 x 3100, AL14
In: TÉRREO
Classification: Parede (Classificação Archicad); Material: TIJOLO - CERAMICO 14x19x39 - espessura 20cm, EI-REV-Chapisco (externo) (2), EI-REV-Massa única - Fachada (2), EI-REV-Massa Acrílica (externa) (2), EI-REV-Pintura Acrílica Cor Branco Gelo (2)
FNDE - Alvenarias: Alvenaria de Vedação / Edificação; Sistemas de Cobertura: -; Esquadrias - Fechamentos metálicos e Gradis: -; 1_Bloco: BLOCO A; 0_ID: AL14
Pset_WallCommon - IsExternal: yes; LoadBearing: no
Component Quantities - TIJOLO - CERAMICO 14x19x39 - espessura 20cm, Massa: 61.7906 kg; TIJOLO - CERAMICO 14x19x39 - espessura 20cm, Área de Componente Projetada (Líquida): 0.681114 m2; TIJOLO - CERAMICO 14x19x39 - espessura 20cm, Área de Componente Projetada (Bruta): 0.681114 m2; TIJOLO - CERAMICO 14x19x39 - espessura 20cm, Altura do Componente Retangular: 3.1 m; TIJOLO - CERAMICO 14x19x39 - espessura 20cm, Largura do Componente Retangular: 0.14 m; TIJOLO - CERAMICO 14x19x39 - espessura 20cm, Área de Seção Transversal do Componente: 0.434 m2; TIJOLO - CERAMICO 14x19x39 - espessura 20cm, Volume Componente (Líquido): 0.0953559 m3; TIJOLO - CERAMICO 14x19x39 - espessura 20cm, Volume do componente (Bruto): 0.0953559 m3; EI-REV-Chapisco (externo) 1, Massa: 4.42724 kg; EI-REV-Chapisco (externo) 1, Área de Componente Projetada (Líquida): 0.681114 m2; EI-REV-Chapisco (externo) 1, Área de Componente Projetada (Bruta): 0.681114 m2; EI-REV-Chapisco (externo) 1, Altura do Componente Retangular: 3.1 m; EI-REV-Chapisco (externo) 1, Largura do Componente Retangular: 0.005 m; EI-REV-Chapisco (externo) 1, Área de Seção Transversal do Componente: 0.0155 m2; EI-REV-Chapisco (externo) 1, Volume Componente (Líquido): 0.00340557 m3; EI-REV-Chapisco (externo) 1, Volume do componente (Bruto): 0.00340557 m3; EI-REV-Massa única - Fachada 1, Massa: 4.12505 kg; EI-REV-Massa única - Fachada 1, Área de Componente Projetada (Líquida): 0.634624 m2; EI-REV-Massa única - Fachada 1, Área de Componente Projetada (Bruta): 0.634624 m2; EI-REV-Massa única - Fachada 1, Altura do Componente Retangular: 3.1 m; EI-REV-Massa única - Fachada 1, Largura do Componente Retangular: 0.005 m; EI-REV-Massa única - Fachada 1, Área de Seção Transversal do Componente: 0.0155 m2; EI-REV-Massa única - Fachada 1, Volume Componente (Líquido): 0.00317312 m3; EI-REV-Massa única - Fachada 1, Volume do componente (Bruto): 0.00317312 m3; EI-REV-Massa Acrílica (externa) 1, Massa: 4.0373 kg; EI-REV-Massa Acrílica (externa) 1, Área de Componente Projetada (Líquida): 0.621124 m2; EI-REV-Massa Acrílica (externa) 1, Área de Componente Projetada (Bruta): 0.621124 m2; EI-REV-Massa Acrílica (externa) 1, Altura do Componente Retangular: 3.1 m; EI-REV-Massa Acrílica (externa) 1, Largura do Componente Retangular: 0.005 m; EI-REV-Massa Acrílica (externa) 1, Área de Seção Transversal do Componente: 0.0155 m2; EI-REV-Massa Acrílica (externa) 1, Volume Componente (Líquido): 0.00310562 m3; EI-REV-Massa Acrílica (externa) 1, Volume do componente (Bruto): 0.00310562 m3; EI-REV-Pintura Acrílica Cor Branco Gelo 1, Massa: 13.5988 kg; EI-REV-Pintura Acrílica Cor Branco Gelo 1, Área de Componente Projetada (Líquida): 0.697642 m2; EI-REV-Pintura Acrílica Cor Branco Gelo 1, Área de Componente Projetada (Bruta): 0.697642 m2; EI-REV-Pintura Acrílica Cor Branco Gelo 1, Altura do Componente Retangular: 3.1 m; EI-REV-Pintura Acrílica Cor Branco Gelo 1, Largura do Componente Retangular: 0.015 m; EI-REV-Pintura Acrílica Cor Branco Gelo 1, Área de Seção Transversal do Componente: 0.0465 m2; EI-REV-Pintura Acrílica Cor Branco Gelo 1, Volume Componente (Líquido): 0.0104606 m3; EI-REV-Pintura Acrílica Cor Branco Gelo 1, Volume do componente (Bruto): 0.0104606 m3; EI-REV-Massa Acrílica (externa) 2, Massa: 4.43273 kg; EI-REV-Massa Acrílica (externa) 2, Área de Componente Projetada (Líquida): 0.775142 m2; EI-REV-Massa Acrílica (externa) 2, Área de Componente Projetada (Bruta): 0.775142 m2; EI-REV-Massa Acrílica (externa) 2, Altura do Componente Retangular: 3.1 m; EI-REV-Massa Acrílica (externa) 2, Largura do Componente Retangular: 0.005 m; EI-REV-Massa Acrílica (externa) 2, Área de Seção Transversal do Componente: 0.0155 m2; EI-REV-Massa Acrílica (externa) 2, Volume Componente (Líquido): 0.00340979 m3; EI-REV-Massa Acrílica (externa) 2, Volume do componente (Bruto): 0.00340979 m3; EI-REV-Pintura Acrílica Cor Branco Gelo 2, Massa: 15.1101 kg; EI-REV-Pintura Acrílica Cor Branco Gelo 2, Área de Componente Projetada (Líquida): 0.775142 m2; EI-REV-Pintura Acrílica Cor Branco Gelo 2, Área de Componente Projetada (Bruta): 0.775142 m2; EI-REV-Pintura Acrílica Cor Branco Gelo 2, Altura do Componente Retangular: 3.1 m; EI-REV-Pintura Acrílica Cor Branco Gelo 2, Largura do Componente Retangular: 0.015 m; EI-REV-Pintura Acrílica Cor Branco Gelo 2, Área de Seção Transversal do Componente: 0.0465 m2; EI-REV-Pintura Acrílica Cor Branco Gelo 2, Volume Componente (Líquido): 0.0116231 m3; EI-REV-Pintura Acrílica Cor Branco Gelo 2, Volume do componente (Bruto): 0.0116231 m3; EI-REV-Chapisco (externo) 1: 3 with these values

# IfcWall: FNDE-AL14-I1-E1 (branco-cinza) 200 x 3100 (4)
In: TÉRREO
Classification: Parede (Classificação Archicad); Material: TIJOLO - CERAMICO 14x19x39 - espessura 20cm, EI-REV-Chapisco (externo), EI-REV-Pintura Acrílica Cor Cinza, EI-REV-Massa única - Fachada, EI-REV-Massa Acrílica (externa), EI-REV-Pintura Acrílica Cor Branco Gelo, EI-REV-Chapisco (interno), EI-REV-Massa única - Maior que 10m², EI-REV-Massa Corrida PVA (interna), EI-REV-Pintura Acrílica Cor Branco Gelo - Interna
FNDE - Alvenarias: Alvenaria de Vedação / Edificação; Sistemas de Cobertura: -; Esquadrias - Fechamentos metálicos e Gradis: -; 0_ID: AL14
Pset_WallCommon - IsExternal: yes; LoadBearing: no
Component Quantities - TIJOLO - CERAMICO 14x19x39 - espessura 20cm, Altura do Componente Retangular: 3.1 m; TIJOLO - CERAMICO 14x19x39 - espessura 20cm, Largura do Componente Retangular: 0.14 m; TIJOLO - CERAMICO 14x19x39 - espessura 20cm, Área de Seção Transversal do Componente: 0.434 m2; EI-REV-Chapisco (externo), Altura do Componente Retangular: 3.1 m; EI-REV-Chapisco (externo), Largura do Componente Retangular: 0.005 m; EI-REV-Chapisco (externo), Área de Seção Transversal do Componente: 0.0155 m2; EI-REV-Pintura Acrílica Cor Cinza, Altura do Componente Retangular: 0.44 m; EI-REV-Pintura Acrílica Cor Cinza, Largura do Componente Retangular: 0.015 m; EI-REV-Pintura Acrílica Cor Cinza, Área de Seção Transversal do Componente: 0.0066 m2; EI-REV-Massa única - Fachada, Altura do Componente Retangular: 3.1 m; EI-REV-Massa única - Fachada, Largura do Componente Retangular: 0.005 m; EI-REV-Massa única - Fachada, Área de Seção Transversal do Componente: 0.0155 m2; EI-REV-Massa Acrílica (externa), Altura do Componente Retangular: 3.1 m; EI-REV-Massa Acrílica (externa), Largura do Componente Retangular: 0.005 m; EI-REV-Massa Acrílica (externa), Área de Seção Transversal do Componente: 0.0155 m2; EI-REV-Pintura Acrílica Cor Branco Gelo, Altura do Componente Retangular: 2.66 m; EI-REV-Pintura Acrílica Cor Branco Gelo, Largura do Componente Retangular: 0.015 m; EI-REV-Pintura Acrílica Cor Branco Gelo, Área de Seção Transversal do Componente: 0.0399 m2; EI-REV-Chapisco (interno), Altura do Componente Retangular: 3.1 m; EI-REV-Chapisco (interno), Largura do Componente Retangular: 0.005 m; EI-REV-Chapisco (interno), Área de Seção Transversal do Componente: 0.0155 m2; EI-REV-Massa única - Maior que 10m², Altura do Componente Retangular: 3.06 m; EI-REV-Massa única - Maior que 10m², Largura do Componente Retangular: 0.01 m; EI-REV-Massa única - Maior que 10m², Área de Seção Transversal do Componente: 0.0306 m2; EI-REV-Massa Corrida PVA (interna), Altura do Componente Retangular: 3.06 m; EI-REV-Massa Corrida PVA (interna), Largura do Componente Retangular: 0.005 m; EI-REV-Massa Corrida PVA (interna), Área de Seção Transversal do Componente: 0.0153 m2; EI-REV-Pintura Acrílica Cor Branco Gelo - Interna, Altura do Componente Retangular: 3.06 m; EI-REV-Pintura Acrílica Cor Branco Gelo - Interna, Largura do Componente Retangular: 0.01 m; EI-REV-Pintura Acrílica Cor Branco Gelo - Interna, Área de Seção Transversal do Componente: 0.0306 m2
Name | 1_Bloco | TIJOLO - CERAMICO 14x19x39 - espessura 20cm, Massa (kg) | TIJOLO - CERAMICO 14x19x39 - espessura 20cm, Área de Componente Projetada (Líquida) (m2) = TIJOLO - CERAMICO 14x19x39 - espessura 20cm, Área de Componente Projetada (Bruta) (m2) | TIJOLO - CERAMICO 14x19x39 - espessura 20cm, Volume Componente (Líquido) (m3) = TIJOLO - CERAMICO 14x19x39 - espessura 20cm, Volume do componente (Bruto) (m3) | EI-REV-Chapisco (externo), Massa (kg) | EI-REV-Chapisco (externo), Área de Componente Projetada (Líquida) (m2) = EI-REV-Chapisco (externo), Área de Componente Projetada (Bruta) (m2) | EI-REV-Chapisco (externo), Volume Componente (Líquido) (m3) = EI-REV-Chapisco (externo), Volume do componente (Bruto) (m3) | EI-REV-Pintura Acrílica Cor Cinza, Massa (kg) | EI-REV-Pintura Acrílica Cor Cinza, Área de Componente Projetada (Líquida) (m2) = EI-REV-Pintura Acrílica Cor Cinza, Área de Componente Projetada (Bruta) (m2) | EI-REV-Pintura Acrílica Cor Cinza, Volume Componente (Líquido) (m3) = EI-REV-Pintura Acrílica Cor Cinza, Volume do componente (Bruto) (m3) | EI-REV-Massa única - Fachada, Massa (kg) | EI-REV-Massa única - Fachada, Área de Componente Projetada (Líquida) (m2) = EI-REV-Massa única - Fachada, Área de Componente Projetada (Bruta) (m2) | EI-REV-Massa única - Fachada, Volume Componente (Líquido) (m3) = EI-REV-Massa única - Fachada, Volume do componente (Bruto) (m3) | EI-REV-Massa Acrílica (externa), Massa (kg) | EI-REV-Massa Acrílica (externa), Área de Componente Projetada (Líquida) (m2) = EI-REV-Massa Acrílica (externa), Área de Componente Projetada (Bruta) (m2) | EI-REV-Massa Acrílica (externa), Volume Componente (Líquido) (m3) = EI-REV-Massa Acrílica (externa), Volume do componente (Bruto) (m3) | EI-REV-Pintura Acrílica Cor Branco Gelo, Massa (kg) | EI-REV-Pintura Acrílica Cor Branco Gelo, Área de Componente Projetada (Líquida) (m2) = EI-REV-Pintura Acrílica Cor Branco Gelo, Área de Componente Projetada (Bruta) (m2) | EI-REV-Pintura Acrílica Cor Branco Gelo, Volume Componente (Líquido) (m3) = EI-REV-Pintura Acrílica Cor Branco Gelo, Volume do componente (Bruto) (m3) | EI-REV-Chapisco (interno), Massa (kg) | EI-REV-Chapisco (interno), Área de Componente Projetada (Líquida) (m2) = EI-REV-Chapisco (interno), Área de Componente Projetada (Bruta) (m2) | EI-REV-Chapisco (interno), Volume Componente (Líquido) (m3) = EI-REV-Chapisco (interno), Volume do componente (Bruto) (m3) | EI-REV-Massa única - Maior que 10m², Massa (kg) | EI-REV-Massa única - Maior que 10m², Área de Componente Projetada (Líquida) (m2) = EI-REV-Massa única - Maior que 10m², Área de Componente Projetada (Bruta) (m2) | EI-REV-Massa única - Maior que 10m², Volume Componente (Líquido) (m3) = EI-REV-Massa única - Maior que 10m², Volume do componente (Bruto) (m3) | EI-REV-Massa Corrida PVA (interna), Massa (kg) | EI-REV-Massa Corrida PVA (interna), Área de Componente Projetada (Líquida) (m2) = EI-REV-Massa Corrida PVA (interna), Área de Componente Projetada (Bruta) (m2) | EI-REV-Massa Corrida PVA (interna), Volume Componente (Líquido) (m3) = EI-REV-Massa Corrida PVA (interna), Volume do componente (Bruto) (m3) | EI-REV-Pintura Acrílica Cor Branco Gelo - Interna, Massa (kg) | EI-REV-Pintura Acrílica Cor Branco Gelo - Interna, Área de Componente Projetada (Líquida) (m2) = EI-REV-Pintura Acrílica Cor Branco Gelo - Interna, Área de Componente Projetada (Bruta) (m2) | EI-REV-Pintura Acrílica Cor Branco Gelo - Interna, Volume Componente (Líquido) (m3) = EI-REV-Pintura Acrílica Cor Branco Gelo - Interna, Volume do componente (Bruto) (m3)
AL14 | BLOCO B | 755.459 | 9.6253 | 1.16583 | 65.3854 | 10.0593 | 0.0502965 | 27.9702 | 1.43437 | 0.0215156 | 65.4862 | 10.0748 | 0.050374 | 65.5869 | 10.0903 | 0.0504515 | 169.093 | 8.67143 | 0.130071 | 53.2806 | 8.19702 | 0.0409851 | 110.224 | 9.3022 | 0.0847873 | 60.166 | 9.2563 | 0.0462815 | 119.723 | 9.2104 | 0.0920943
AL14 | BLOCO A | 760.018 | 9.47863 | 1.17287 | 61.8126 | 9.50963 | 0.0475482 | 26.4489 | 1.35635 | 0.0203453 | 61.9133 | 9.52513 | 0.0476257 | 62.0141 | 9.54063 | 0.0477032 | 159.896 | 8.19978 | 0.122997 | 53.3087 | 8.20134 | 0.0410067 | 104.692 | 8.05324 | 0.0805324 | 55.8372 | 9.23242 | 0.0429517 | 119.245 | 9.17273 | 0.0917273
AL14 | BLOCO B | 556.015 | 6.12891 | 0.858048 | 43.8744 | 6.74991 | 0.0337496 | 21.5578 | 1.10659 | 0.0165829 | 43.9622 | 6.76341 | 0.0338171 | 44.2319 | 7.7809 | 0.0340246 | 130.451 | 6.68981 | 0.100347 | 39.563 | 6.08661 | 0.0304331 | 77.631 | 5.97161 | 0.0597162 | 44.2915 | 6.839 | 0.0340703 | 87.9125 | 6.7625 | 0.067625
AL14 | BLOCO A | 19.5843 | 0.215876 | 0.0302227 | 3.87404 | 0.596006 | 0.00298003 | 3.13094 | 0.16058 | 0.00240842 | 3.97479 | 0.611506 | 0.00305753 | 4.12016 | 1.50484 | 0.00316936 | 26.3886 | 1.35326 | 0.020299 | 1.0977 | 0.168876 | 0.000844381 | 2.05112 | 0.157778 | 0.00157778 | 7.03937 | 1.09146 | 0.0054149 | 13.9212 | 1.07086 | 0.0107086

# IfcWall: FNDE-AL14-I1-E2 (branco-cinza) 200 x 3100 (2)
In: TÉRREO
Classification: Parede (Classificação Archicad); Material: TIJOLO - CERAMICO 14x19x39 - espessura 20cm, EI-REV-Chapisco (interno), EI-REV-Massa única - Maior que 10m², EI-REV-Massa Corrida PVA (interna), EI-REV-Pintura Acrílica Cor Branco Gelo - Interna, EI-REV-Chapisco (externo), EI-REV-Massa única - Fachada, EI-REV-Massa Acrílica (externa), EI-REV-Pintura Acrílica Cor Cinza
FNDE - Alvenarias: Alvenaria de Vedação / Edificação; Sistemas de Cobertura: -; Esquadrias - Fechamentos metálicos e Gradis: -; 0_ID: AL14
Pset_WallCommon - IsExternal: yes; LoadBearing: no
Component Quantities - TIJOLO - CERAMICO 14x19x39 - espessura 20cm, Altura do Componente Retangular: 3.1 m; TIJOLO - CERAMICO 14x19x39 - espessura 20cm, Largura do Componente Retangular: 0.14 m; TIJOLO - CERAMICO 14x19x39 - espessura 20cm, Área de Seção Transversal do Componente: 0.434 m2; EI-REV-Chapisco (interno), Altura do Componente Retangular: 3.1 m; EI-REV-Chapisco (interno), Largura do Componente Retangular: 0.005 m; EI-REV-Chapisco (interno), Área de Seção Transversal do Componente: 0.0155 m2; EI-REV-Massa única - Maior que 10m², Altura do Componente Retangular: 3.06 m; EI-REV-Massa única - Maior que 10m², Largura do Componente Retangular: 0.01 m; EI-REV-Massa única - Maior que 10m², Área de Seção Transversal do Componente: 0.0306 m2; EI-REV-Massa Corrida PVA (interna), Altura do Componente Retangular: 3.06 m; EI-REV-Massa Corrida PVA (interna), Largura do Componente Retangular: 0.005 m; EI-REV-Massa Corrida PVA (interna), Área de Seção Transversal do Componente: 0.0153 m2; EI-REV-Pintura Acrílica Cor Branco Gelo - Interna, Altura do Componente Retangular: 3.06 m; EI-REV-Pintura Acrílica Cor Branco Gelo - Interna, Largura do Componente Retangular: 0.01 m; EI-REV-Pintura Acrílica Cor Branco Gelo - Interna, Área de Seção Transversal do Componente: 0.0306 m2; EI-REV-Chapisco (externo), Altura do Componente Retangular: 3.1 m; EI-REV-Chapisco (externo), Largura do Componente Retangular: 0.005 m; EI-REV-Chapisco (externo), Área de Seção Transversal do Componente: 0.0155 m2; EI-REV-Pintura Acrílica Cor Cinza, Altura do Componente Retangular: 3.1 m; EI-REV-Pintura Acrílica Cor Cinza, Largura do Componente Retangular: 0.015 m; EI-REV-Pintura Acrílica Cor Cinza, Área de Seção Transversal do Componente: 0.0465 m2
Name | 1_Bloco | TIJOLO - CERAMICO 14x19x39 - espessura 20cm, Massa (kg) | TIJOLO - CERAMICO 14x19x39 - espessura 20cm, Área de Componente Projetada (Líquida) (m2) | TIJOLO - CERAMICO 14x19x39 - espessura 20cm, Área de Componente Projetada (Bruta) (m2) | TIJOLO - CERAMICO 14x19x39 - espessura 20cm, Volume Componente (Líquido) (m3) | TIJOLO - CERAMICO 14x19x39 - espessura 20cm, Volume do componente (Bruto) (m3) | EI-REV-Chapisco (interno), Massa (kg) | EI-REV-Chapisco (interno), Área de Componente Projetada (Líquida) (m2) | EI-REV-Chapisco (interno), Área de Componente Projetada (Bruta) (m2) | EI-REV-Chapisco (interno), Volume Componente (Líquido) (m3) | EI-REV-Chapisco (interno), Volume do componente (Bruto) (m3) | EI-REV-Massa única - Maior que 10m², Massa (kg) | EI-REV-Massa única - Maior que 10m², Área de Componente Projetada (Líquida) (m2) | EI-REV-Massa única - Maior que 10m², Área de Componente Projetada (Bruta) (m2) | EI-REV-Massa única - Maior que 10m², Volume Componente (Líquido) (m3) | EI-REV-Massa única - Maior que 10m², Volume do componente (Bruto) (m3) | EI-REV-Massa Corrida PVA (interna), Massa (kg) | EI-REV-Massa Corrida PVA (interna), Área de Componente Projetada (Líquida) (m2) | EI-REV-Massa Corrida PVA (interna), Área de Componente Projetada (Bruta) (m2) | EI-REV-Massa Corrida PVA (interna), Volume Componente (Líquido) (m3) | EI-REV-Massa Corrida PVA (interna), Volume do componente (Bruto) (m3) | EI-REV-Pintura Acrílica Cor Branco Gelo - Interna, Massa (kg) | EI-REV-Pintura Acrílica Cor Branco Gelo - Interna, Área de Componente Projetada (Líquida) (m2) | EI-REV-Pintura Acrílica Cor Branco Gelo - Interna, Área de Componente Projetada (Bruta) (m2) | EI-REV-Pintura Acrílica Cor Branco Gelo - Interna, Volume Componente (Líquido) (m3) | EI-REV-Pintura Acrílica Cor Branco Gelo - Interna, Volume do componente (Bruto) (m3) | EI-REV-Chapisco (externo), Massa (kg) | EI-REV-Chapisco (externo), Área de Componente Projetada (Líquida) (m2) | EI-REV-Chapisco (externo), Área de Componente Projetada (Bruta) (m2) | EI-REV-Chapisco (externo), Volume Componente (Líquido) (m3) | EI-REV-Chapisco (externo), Volume do componente (Bruto) (m3) | EI-REV-Pintura Acrílica Cor Cinza, Massa (kg) | EI-REV-Pintura Acrílica Cor Cinza, Área de Componente Projetada (Líquida) (m2) | EI-REV-Pintura Acrílica Cor Cinza, Área de Componente Projetada (Bruta) (m2) | EI-REV-Pintura Acrílica Cor Cinza, Volume Componente (Líquido) (m3) | EI-REV-Pintura Acrílica Cor Cinza, Volume do componente (Bruto) (m3)
AL14 | BLOCO B | 349.519 | 6.50204 | 8.60204 | 0.539381 | 0.833381 | 37.8334 | 5.83361 | 7.93361 | 0.0291026 | 0.0396026 | 74.2192 | 5.70916 | 7.80916 | 0.0570917 | 0.0780917 | 36.726 | 5.65014 | 7.75014 | 0.0282508 | 0.0387508 | 73.5218 | 5.65552 | 7.75552 | 0.0565553 | 0.0775553 | 39.8477 | 6.13042 | 8.23042 | 0.0306521 | 0.0411521 | 120.148 | 6.16142 | 8.26142 | 0.0924213 | 0.123921 | Component Quantities - EI-REV-Chapisco (externo): 3 with these values
AL14 | BLOCO A | 380.957 | 4.60715 | 6.70715 | 0.587896 | 0.881896 | 27.896 | 4.2917 | 6.3917 | 0.0214585 | 0.0319585 | 54.4493 | 4.1884 | 6.2884 | 0.0418841 | 0.0628841 | 36.3552 | 5.61955 | 7.71955 | 0.0279655 | 0.0384656 | 73.1263 | 5.6251 | 7.7251 | 0.056251 | 0.077251 | 27.5902 | 4.24465 | 6.34465 | 0.0212233 | 0.0317233 | 119.547 | 6.1306 | 8.2306 | 0.091959 | 0.123459 | Component Quantities - EI-REV-Massa única - Fachada, Massa: 27.6032 kg; EI-REV-Massa única - Fachada, Área de Componente Projetada (Líquida): 4.24665 m2; EI-REV-Massa única - Fachada, Área de Componente Projetada (Bruta): 6.34665 m2; EI-REV-Massa única - Fachada, Altura do Componente Retangular: 3.1 m; EI-REV-Massa única - Fachada, Largura do Componente Retangular: 0.005 m; EI-REV-Massa única - Fachada, Área de Seção Transversal do Componente: 0.0155 m2; EI-REV-Massa única - Fachada, Volume Componente (Líquido): 0.0212333 m3; EI-REV-Massa única - Fachada, Volume do componente (Bruto): 0.0317333 m3; EI-REV-Massa Acrílica (externa), Massa: 27.8338 kg; EI-REV-Massa Acrílica (externa), Área de Componente Projetada (Líquida): 6.0996 m2; EI-REV-Massa Acrílica (externa), Área de Componente Projetada (Bruta): 8.1996 m2; EI-REV-Massa Acrílica (externa), Altura do Componente Retangular: 3.1 m; EI-REV-Massa Acrílica (externa), Largura do Componente Retangular: 0.005 m; EI-REV-Massa Acrílica (externa), Área de Seção Transversal do Componente: 0.0155 m2; EI-REV-Massa Acrílica (externa), Volume Componente (Líquido): 0.0214106 m3; EI-REV-Massa Acrílica (externa), Volume do componente (Bruto): 0.0319106 m3

# IfcWall: FNDE-AL14-I1-I1 200, AL14
In: TÉRREO
Classification: Parede (Classificação Archicad); Material: EI-REV-Pintura Acrílica Cor Branco Gelo - Interna 0.01 m, EI-REV-Massa Corrida PVA (interna) 0.005 m, EI-REV-Massa única - Maior que 10m² 0.01 m, EI-REV-Chapisco (interno) 0.005 m, TIJOLO - CERAMICO 14x19x39 - espessura 20cm 0.14 m, EI-REV-Chapisco (interno) 0.005 m, EI-REV-Massa única - Maior que 10m² 0.01 m, EI-REV-Massa Corrida PVA (interna) 0.005 m, EI-REV-Pintura Acrílica Cor Branco Gelo - Interna 0.01 m
FNDE - Alvenarias: Alvenaria de Vedação / Edificação; Sistemas de Cobertura: -; Esquadrias - Fechamentos metálicos e Gradis: -; 1_Bloco: BLOCO B; 0_ID: AL14
Pset_WallCommon - IsExternal: yes; LoadBearing: no
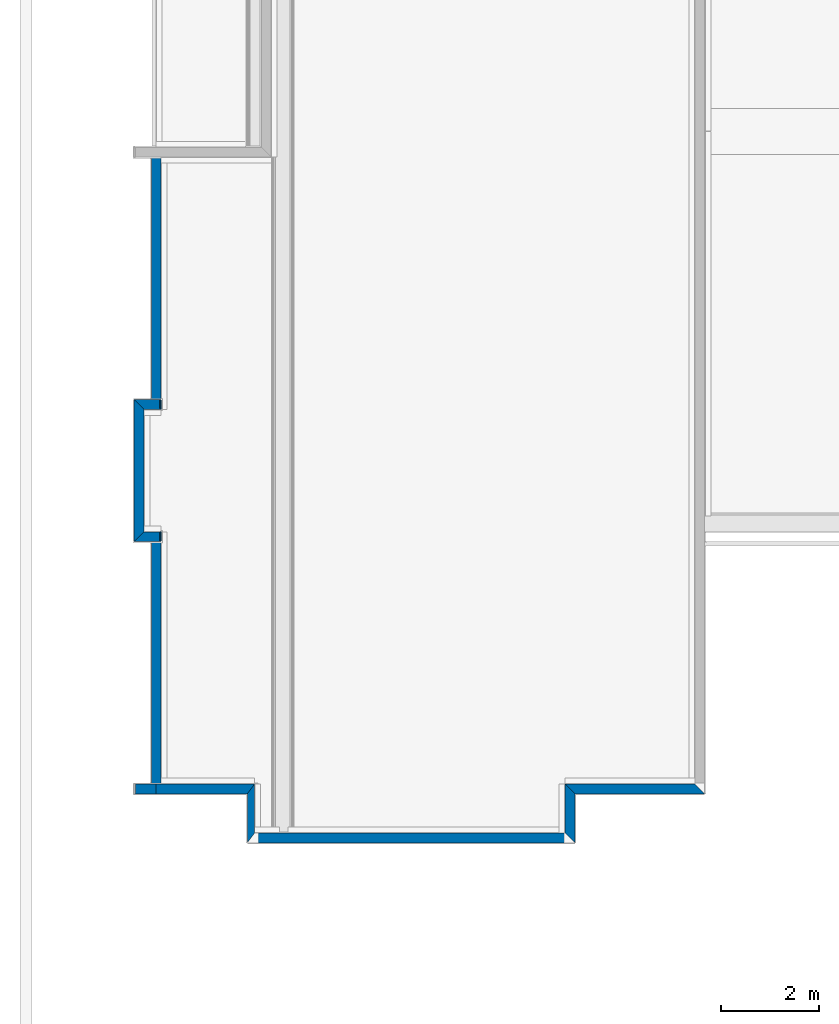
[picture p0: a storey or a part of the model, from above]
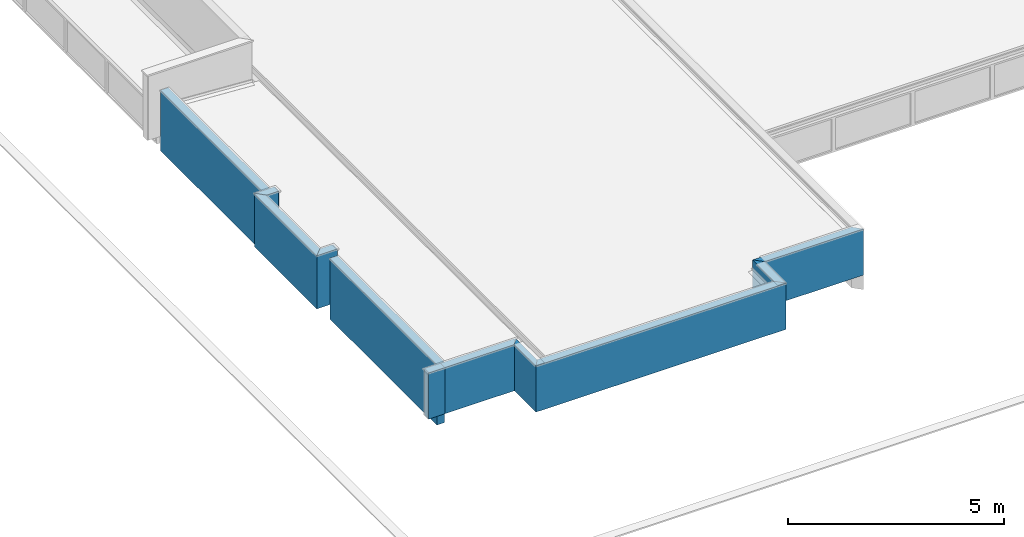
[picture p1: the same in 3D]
Properties of the parts of a building model (IFC4), part 18 of 22

# IfcWall: FNDE-AL14-I1-I1 200, AL14
Component Quantities - EI-REV-Pintura Acrílica Cor Branco Gelo - Interna 1, Massa: 16.5342 kg; EI-REV-Pintura Acrílica Cor Branco Gelo - Interna 1, Área de Componente Projetada (Líquida): 1.27186 m2; EI-REV-Pintura Acrílica Cor Branco Gelo - Interna 1, Área de Componente Projetada (Bruta): 1.27186 m2; EI-REV-Pintura Acrílica Cor Branco Gelo - Interna 1, Espessura do Componente: 0.01 m; EI-REV-Pintura Acrílica Cor Branco Gelo - Interna 1, Altura do Componente Retangular: 3.1 m; EI-REV-Pintura Acrílica Cor Branco Gelo - Interna 1, Largura do Componente Retangular: 0.01 m; EI-REV-Pintura Acrílica Cor Branco Gelo - Interna 1, Área de Seção Transversal do Componente: 0.031 m2; EI-REV-Pintura Acrílica Cor Branco Gelo - Interna 1, Volume Componente (Líquido): 0.0127186 m3; EI-REV-Pintura Acrílica Cor Branco Gelo - Interna 1, Volume do componente (Bruto): 0.0127186 m3; EI-REV-Massa Corrida PVA (interna) 1, Massa: 8.36514 kg; EI-REV-Massa Corrida PVA (interna) 1, Área de Componente Projetada (Líquida): 1.28716 m2; EI-REV-Massa Corrida PVA (interna) 1, Área de Componente Projetada (Bruta): 1.28716 m2; EI-REV-Massa Corrida PVA (interna) 1, Espessura do Componente: 0.005 m; EI-REV-Massa Corrida PVA (interna) 1, Altura do Componente Retangular: 3.1 m; EI-REV-Massa Corrida PVA (interna) 1, Largura do Componente Retangular: 0.005 m; EI-REV-Massa Corrida PVA (interna) 1, Área de Seção Transversal do Componente: 0.0155 m2; EI-REV-Massa Corrida PVA (interna) 1, Volume Componente (Líquido): 0.00643472 m3; EI-REV-Massa Corrida PVA (interna) 1, Volume do componente (Bruto): 0.00643472 m3; EI-REV-Massa única - Maior que 10m² 1, Massa: 15.9105 kg; EI-REV-Massa única - Maior que 10m² 1, Área de Componente Projetada (Líquida): 1.22388 m2; EI-REV-Massa única - Maior que 10m² 1, Área de Componente Projetada (Bruta): 1.22388 m2; EI-REV-Massa única - Maior que 10m² 1, Espessura do Componente: 0.01 m; EI-REV-Massa única - Maior que 10m² 1, Altura do Componente Retangular: 3.1 m; EI-REV-Massa única - Maior que 10m² 1, Largura do Componente Retangular: 0.01 m; EI-REV-Massa única - Maior que 10m² 1, Área de Seção Transversal do Componente: 0.031 m2; EI-REV-Massa única - Maior que 10m² 1, Volume Componente (Líquido): 0.0122388 m3; EI-REV-Massa única - Maior que 10m² 1, Volume do componente (Bruto): 0.0122388 m3; EI-REV-Chapisco (interno) 1, Massa: 8.05469 kg; EI-REV-Chapisco (interno) 1, Área de Componente Projetada (Líquida): 1.23918 m2; EI-REV-Chapisco (interno) 1, Área de Componente Projetada (Bruta): 1.23918 m2; EI-REV-Chapisco (interno) 1, Espessura do Componente: 0.005 m; EI-REV-Chapisco (interno) 1, Altura do Componente Retangular: 3.1 m; EI-REV-Chapisco (interno) 1, Largura do Componente Retangular: 0.005 m; EI-REV-Chapisco (interno) 1, Área de Seção Transversal do Componente: 0.0155 m2; EI-REV-Chapisco (interno) 1, Volume Componente (Líquido): 0.00619592 m3; EI-REV-Chapisco (interno) 1, Volume do componente (Bruto): 0.00619592 m3; TIJOLO - CERAMICO 14x19x39 - espessura 20cm, Massa: 137.73 kg; TIJOLO - CERAMICO 14x19x39 - espessura 20cm, Área de Componente Projetada (Líquida): 1.51818 m2; TIJOLO - CERAMICO 14x19x39 - espessura 20cm, Área de Componente Projetada (Bruta): 1.51818 m2; TIJOLO - CERAMICO 14x19x39 - espessura 20cm, Espessura do Componente: 0.14 m; TIJOLO - CERAMICO 14x19x39 - espessura 20cm, Altura do Componente Retangular: 3.1 m; TIJOLO - CERAMICO 14x19x39 - espessura 20cm, Largura do Componente Retangular: 0.14 m; TIJOLO - CERAMICO 14x19x39 - espessura 20cm, Área de Seção Transversal do Componente: 0.434 m2; TIJOLO - CERAMICO 14x19x39 - espessura 20cm, Volume Componente (Líquido): 0.212546 m3; TIJOLO - CERAMICO 14x19x39 - espessura 20cm, Volume do componente (Bruto): 0.212546 m3; EI-REV-Chapisco (interno) 2, Massa: 9.96894 kg; EI-REV-Chapisco (interno) 2, Área de Componente Projetada (Líquida): 1.53368 m2; EI-REV-Chapisco (interno) 2, Área de Componente Projetada (Bruta): 1.53368 m2; EI-REV-Chapisco (interno) 2, Espessura do Componente: 0.005 m; EI-REV-Chapisco (interno) 2, Altura do Componente Retangular: 3.1 m; EI-REV-Chapisco (interno) 2, Largura do Componente Retangular: 0.005 m; EI-REV-Chapisco (interno) 2, Área de Seção Transversal do Componente: 0.0155 m2; EI-REV-Chapisco (interno) 2, Volume Componente (Líquido): 0.00766842 m3; EI-REV-Chapisco (interno) 2, Volume do componente (Bruto): 0.00766842 m3; EI-REV-Massa única - Maior que 10m² 2, Massa: 20.1408 kg; EI-REV-Massa única - Maior que 10m² 2, Área de Componente Projetada (Líquida): 1.64306 m2; EI-REV-Massa única - Maior que 10m² 2, Área de Componente Projetada (Bruta): 1.64306 m2; EI-REV-Massa única - Maior que 10m² 2, Espessura do Componente: 0.01 m; EI-REV-Massa única - Maior que 10m² 2, Altura do Componente Retangular: 3.1 m; EI-REV-Massa única - Maior que 10m² 2, Largura do Componente Retangular: 0.01 m; EI-REV-Massa única - Maior que 10m² 2, Área de Seção Transversal do Componente: 0.031 m2; EI-REV-Massa única - Maior que 10m² 2, Volume Componente (Líquido): 0.0154929 m3; EI-REV-Massa única - Maior que 10m² 2, Volume do componente (Bruto): 0.0154929 m3; EI-REV-Massa Corrida PVA (interna) 2, Massa: 10.7469 kg; EI-REV-Massa Corrida PVA (interna) 2, Área de Componente Projetada (Líquida): 1.65336 m2; EI-REV-Massa Corrida PVA (interna) 2, Área de Componente Projetada (Bruta): 1.65336 m2; EI-REV-Massa Corrida PVA (interna) 2, Espessura do Componente: 0.005 m; EI-REV-Massa Corrida PVA (interna) 2, Altura do Componente Retangular: 3.1 m; EI-REV-Massa Corrida PVA (interna) 2, Largura do Componente Retangular: 0.005 m; EI-REV-Massa Corrida PVA (interna) 2, Área de Seção Transversal do Componente: 0.0155 m2; EI-REV-Massa Corrida PVA (interna) 2, Volume Componente (Líquido): 0.00826681 m3; EI-REV-Massa Corrida PVA (interna) 2, Volume do componente (Bruto): 0.00826681 m3; EI-REV-Pintura Acrílica Cor Branco Gelo - Interna 2, Massa: 21.8954 kg; EI-REV-Pintura Acrílica Cor Branco Gelo - Interna 2, Área de Componente Projetada (Líquida): 1.68426 m2; EI-REV-Pintura Acrílica Cor Branco Gelo - Interna 2, Área de Componente Projetada (Bruta): 1.68426 m2; EI-REV-Pintura Acrílica Cor Branco Gelo - Interna 2, Espessura do Componente: 0.01 m; EI-REV-Pintura Acrílica Cor Branco Gelo - Interna 2, Altura do Componente Retangular: 3.1 m; EI-REV-Pintura Acrílica Cor Branco Gelo - Interna 2, Largura do Componente Retangular: 0.01 m; EI-REV-Pintura Acrílica Cor Branco Gelo - Interna 2, Área de Seção Transversal do Componente: 0.031 m2; EI-REV-Pintura Acrílica Cor Branco Gelo - Interna 2, Volume Componente (Líquido): 0.0168426 m3; EI-REV-Pintura Acrílica Cor Branco Gelo - Interna 2, Volume do componente (Bruto): 0.0168426 m3

# IfcWall: FNDE-AL14-I2-E1 (laranja-cinza) 200 x 3100 (5)
In: TÉRREO
Classification: Parede (Classificação Archicad); Material: TIJOLO - CERAMICO 14x19x39 - espessura 20cm, EI-REV-Chapisco (externo), EI-REV-Pintura Acrílica Cor Cinza, EI-REV-Massa única - Fachada, EI-REV-Massa Acrílica (externa), EI-REV-Pintura Acrílica Cor Branco Gelo (2), EI-REV-Chapisco (interno), EI-REV-Pintura Epóxi cor Laranja, EI-REV-Massa única - Maior que 10m², EI-REV-Massa Corrida PVA (interna)
FNDE - Alvenarias: Alvenaria de Vedação / Edificação; Sistemas de Cobertura: -; Esquadrias - Fechamentos metálicos e Gradis: -; 0_ID: AL14
Pset_WallCommon - IsExternal: yes; LoadBearing: no
Component Quantities - TIJOLO - CERAMICO 14x19x39 - espessura 20cm, Altura do Componente Retangular: 3.1 m; TIJOLO - CERAMICO 14x19x39 - espessura 20cm, Largura do Componente Retangular: 0.14 m; TIJOLO - CERAMICO 14x19x39 - espessura 20cm, Área de Seção Transversal do Componente: 0.434 m2; EI-REV-Chapisco (externo), Altura do Componente Retangular: 3.1 m; EI-REV-Chapisco (externo), Largura do Componente Retangular: 0.005 m; EI-REV-Chapisco (externo), Área de Seção Transversal do Componente: 0.0155 m2; EI-REV-Pintura Acrílica Cor Cinza, Altura do Componente Retangular: 0.44 m; EI-REV-Pintura Acrílica Cor Cinza, Largura do Componente Retangular: 0.015 m; EI-REV-Pintura Acrílica Cor Cinza, Área de Seção Transversal do Componente: 0.0066 m2; EI-REV-Pintura Acrílica Cor Branco Gelo 1, Altura do Componente Retangular: 2.66 m; EI-REV-Pintura Acrílica Cor Branco Gelo 1, Largura do Componente Retangular: 0.015 m; EI-REV-Pintura Acrílica Cor Branco Gelo 1, Área de Seção Transversal do Componente: 0.0399 m2; EI-REV-Chapisco (interno), Altura do Componente Retangular: 3.1 m; EI-REV-Chapisco (interno), Largura do Componente Retangular: 0.005 m; EI-REV-Chapisco (interno), Área de Seção Transversal do Componente: 0.0155 m2; EI-REV-Pintura Epóxi cor Laranja, Altura do Componente Retangular: 0.9 m; EI-REV-Pintura Epóxi cor Laranja, Largura do Componente Retangular: 0.02 m; EI-REV-Pintura Epóxi cor Laranja, Área de Seção Transversal do Componente: 0.018 m2; EI-REV-Massa única - Maior que 10m², Área de Seção Transversal do Componente: 0.0155 m2; EI-REV-Massa Corrida PVA (interna), Altura do Componente Retangular: 2.16 m; EI-REV-Massa Corrida PVA (interna), Largura do Componente Retangular: 0.005 m; EI-REV-Massa Corrida PVA (interna), Área de Seção Transversal do Componente: 0.0108001 m2; EI-REV-Pintura Acrílica Cor Branco Gelo 2, Altura do Componente Retangular: 2.16 m; EI-REV-Pintura Acrílica Cor Branco Gelo 2, Largura do Componente Retangular: 0.015 m; EI-REV-Pintura Acrílica Cor Branco Gelo 2, Área de Seção Transversal do Componente: 0.0324 m2
Name | 1_Bloco | TIJOLO - CERAMICO 14x19x39 - espessura 20cm, Massa (kg) | TIJOLO - CERAMICO 14x19x39 - espessura 20cm, Área de Componente Projetada (Líquida) (m2) | TIJOLO - CERAMICO 14x19x39 - espessura 20cm, Área de Componente Projetada (Bruta) (m2) | TIJOLO - CERAMICO 14x19x39 - espessura 20cm, Volume Componente (Líquido) (m3) | TIJOLO - CERAMICO 14x19x39 - espessura 20cm, Volume do componente (Bruto) (m3) | EI-REV-Chapisco (externo), Massa (kg) | EI-REV-Chapisco (externo), Área de Componente Projetada (Líquida) (m2) | EI-REV-Chapisco (externo), Área de Componente Projetada (Bruta) (m2) | EI-REV-Chapisco (externo), Volume Componente (Líquido) (m3) | EI-REV-Chapisco (externo), Volume do componente (Bruto) (m3) | EI-REV-Pintura Acrílica Cor Cinza, Massa (kg) | EI-REV-Pintura Acrílica Cor Cinza, Área de Componente Projetada (Líquida) (m2) = EI-REV-Pintura Acrílica Cor Cinza, Área de Componente Projetada (Bruta) (m2) | EI-REV-Pintura Acrílica Cor Cinza, Volume Componente (Líquido) (m3) = EI-REV-Pintura Acrílica Cor Cinza, Volume do componente (Bruto) (m3) | EI-REV-Massa única - Fachada, Massa (kg) | EI-REV-Massa única - Fachada, Área de Componente Projetada (Líquida) (m2) | EI-REV-Massa única - Fachada, Área de Componente Projetada (Bruta) (m2) | EI-REV-Massa única - Fachada, Altura do Componente Retangular (m) = EI-REV-Massa Acrílica (externa), Altura do Componente Retangular (m) | EI-REV-Massa única - Fachada, Largura do Componente Retangular (m) = EI-REV-Massa Acrílica (externa), Largura do Componente Retangular (m) | EI-REV-Massa única - Fachada, Área de Seção Transversal do Componente (m2) = EI-REV-Massa Acrílica (externa), Área de Seção Transversal do Componente (m2) | EI-REV-Massa única - Fachada, Volume Componente (Líquido) (m3) | EI-REV-Massa única - Fachada, Volume do componente (Bruto) (m3) | EI-REV-Massa Acrílica (externa), Massa (kg) | EI-REV-Massa Acrílica (externa), Área de Componente Projetada (Líquida) (m2) | EI-REV-Massa Acrílica (externa), Área de Componente Projetada (Bruta) (m2) | EI-REV-Massa Acrílica (externa), Volume Componente (Líquido) (m3) | EI-REV-Massa Acrílica (externa), Volume do componente (Bruto) (m3) | EI-REV-Pintura Acrílica Cor Branco Gelo 1, Massa (kg) | EI-REV-Pintura Acrílica Cor Branco Gelo 1, Área de Componente Projetada (Líquida) (m2) | EI-REV-Pintura Acrílica Cor Branco Gelo 1, Área de Componente Projetada (Bruta) (m2) | EI-REV-Pintura Acrílica Cor Branco Gelo 1, Volume Componente (Líquido) (m3) | EI-REV-Pintura Acrílica Cor Branco Gelo 1, Volume do componente (Bruto) (m3) | EI-REV-Chapisco (interno), Massa (kg) | EI-REV-Chapisco (interno), Área de Componente Projetada (Líquida) (m2) | EI-REV-Chapisco (interno), Área de Componente Projetada (Bruta) (m2) | EI-REV-Chapisco (interno), Volume Componente (Líquido) (m3) | EI-REV-Chapisco (interno), Volume do componente (Bruto) (m3) | EI-REV-Pintura Epóxi cor Laranja, Massa (kg) | EI-REV-Pintura Epóxi cor Laranja, Área de Componente Projetada (Líquida) (m2) = EI-REV-Pintura Epóxi cor Laranja, Área de Componente Projetada (Bruta) (m2) | EI-REV-Pintura Epóxi cor Laranja, Volume Componente (Líquido) (m3) = EI-REV-Pintura Epóxi cor Laranja, Volume do componente (Bruto) (m3) | EI-REV-Massa única - Maior que 10m², Massa (kg) | EI-REV-Massa única - Maior que 10m², Área de Componente Projetada (Líquida) (m2) | EI-REV-Massa única - Maior que 10m², Área de Componente Projetada (Bruta) (m2) | EI-REV-Massa única - Maior que 10m², Volume Componente (Líquido) (m3) | EI-REV-Massa única - Maior que 10m², Volume do componente (Bruto) (m3) | EI-REV-Massa Corrida PVA (interna), Massa (kg) | EI-REV-Massa Corrida PVA (interna), Área de Componente Projetada (Líquida) (m2) | EI-REV-Massa Corrida PVA (interna), Área de Componente Projetada (Bruta) (m2) | EI-REV-Massa Corrida PVA (interna), Volume Componente (Líquido) (m3) | EI-REV-Massa Corrida PVA (interna), Volume do componente (Bruto) (m3) | EI-REV-Pintura Acrílica Cor Branco Gelo 2, Massa (kg) | EI-REV-Pintura Acrílica Cor Branco Gelo 2, Área de Componente Projetada (Líquida) (m2) | EI-REV-Pintura Acrílica Cor Branco Gelo 2, Área de Componente Projetada (Bruta) (m2) | EI-REV-Pintura Acrílica Cor Branco Gelo 2, Volume Componente (Líquido) (m3) | EI-REV-Pintura Acrílica Cor Branco Gelo 2, Volume do componente (Bruto) (m3)
AL14 | BLOCO B | 831.196 | 14.598 | 20.198 | 1.28271 | 2.05999 | 97.0743 | 14.9841 | 20.5841 | 0.0746725 | 0.102657 | 57.4004 | 2.94361 | 0.0441542 | 97.598 | 15.0151 | 20.6151 | 3.1 | 0.005 | 0.0155 | 0.0750754 | 0.103075 | 97.7995 | 15.0461 | 20.6461 | 0.0752304 | 0.10323 | 237.812 | 12.1955 | 17.7955 | 0.182932 | 0.266932 | 86.1954 | 13.2674 | 18.8674 | 0.0663042 | 0.0943042 | 146.719 | 5.64302 | 0.112861 | 84.6103 | 13.6307 | 19.2307 | 0.0650848 | 0.0930848 | 51.5876 | 7.93652 | 13.5365 | 0.0396828 | 0.067683 | 154.042 | 7.8996 | 13.4996 | 0.118494 | 0.202494
AL14 | BLOCO B | 215.716 | 2.66578 | 2.66578 | 0.332895 | 0.332895 | 20.0478 | 3.08428 | 3.08428 | 0.0154214 | 0.0154214 | 8.4507 | 0.433369 | 0.00650054 |  |  |  |  |  |  |  |  |  |  |  |  |  | 51.0883 | 2.61991 | 2.61991 | 0.0392987 | 0.0392987 | 14.9708 | 2.3032 | 2.3032 | 0.011516 | 0.011516 | 22.7064 | 0.890937 | 0.0174665 | 14.9689 | 2.30291 | 2.30291 | 0.0115146 | 0.0115146 | 10.5437 | 1.75988 | 1.75988 | 0.00811057 | 0.00811057 | 37.6829 | 2.13825 | 2.13825 | 0.0289869 | 0.0289869 | Component Quantities - EI-REV-Chapisco (externo): 3 with these values
AL14 | BLOCO B | 220.801 | 3.07206 | 3.07206 | 0.340742 | 0.340742 | 18.2672 | 2.81035 | 2.81035 | 0.0140517 | 0.0140517 | 7.51575 | 0.385423 | 0.00578134 | 18.1665 | 2.79485 | 2.79485 | 3.1 | 0.005 | 0.0155 | 0.0139742 | 0.0139742 | 18.0657 | 2.77935 | 2.77935 | 0.0138967 | 0.0138967 | 46.3793 | 2.37842 | 2.37842 | 0.0356763 | 0.0356763 | 14.0417 | 2.16026 | 2.16026 | 0.0108013 | 0.0108013 | 19.6762 | 0.985549 | 0.0151356 | 14.041 | 2.16015 | 2.16015 | 0.0108007 | 0.0108007 | 9.09546 | 1.3993 | 1.3993 | 0.00699651 | 0.00699651 | 30.9261 | 2.35052 | 2.35052 | 0.0237893 | 0.0237893
AL14 | BLOCO A | 848.065 | 13.1294 | 18.7294 | 1.30874 | 2.08602 | 85.9432 | 13.2479 | 18.8479 | 0.0661101 | 0.094103 | 52.2949 | 2.68179 | 0.0402269 | 86.2123 | 13.2634 | 18.8634 | 3.1 | 0.005 | 0.0155 | 0.0663172 | 0.0943172 | 86.3131 | 13.2789 | 18.8789 | 0.0663947 | 0.0943947 | 206.946 | 10.6126 | 16.2126 | 0.15919 | 0.24319 | 85.253 | 13.1159 | 18.7159 | 0.0655793 | 0.0935793 | 140.634 | 5.40898 | 0.10818 | 85.1653 | 13.1024 | 18.7024 | 0.0655118 | 0.0935118 | 48.2347 | 7.4207 | 13.0207 | 0.0371036 | 0.0651038 | 143.94 | 7.38155 | 12.9816 | 0.110723 | 0.194723
AL14 | BLOCO A | 191.017 | 3.09423 | 3.09423 | 0.294779 | 0.294779 | 20.1255 | 3.09623 | 3.09623 | 0.0154812 | 0.0154812 | 8.58054 | 0.440028 | 0.00660042 | 20.1385 | 3.09823 | 3.09823 | 3.1 | 0.005 | 0.0155 | 0.0154912 | 0.0154912 | 20.1513 | 3.1002 | 3.1002 | 0.015501 | 0.015501 | 51.8733 | 2.66017 | 2.66017 | 0.0399025 | 0.0399025 | 14.6737 | 2.2575 | 2.2575 | 0.0112875 | 0.0112875 | 20.9981 | 0.909057 | 0.0161524 | 14.7601 | 2.2708 | 2.2708 | 0.0113539 | 0.0113539 | 9.78248 | 1.50499 | 1.50499 | 0.00752498 | 0.00752498 | 33.7631 | 2.17094 | 2.17094 | 0.0259716 | 0.0259716

# IfcWall: FNDE-AL14-I3-E1 (verde-cinza) 200 x 3100 (4)
In: TÉRREO
Classification: Parede (Classificação Archicad); Material: TIJOLO - CERAMICO 14x19x39 - espessura 20cm, EI-REV-Chapisco (externo), EI-REV-Pintura Acrílica Cor Cinza, EI-REV-Massa única - Fachada, EI-REV-Massa Acrílica (externa), EI-REV-Pintura Acrílica Cor Branco Gelo (2), EI-REV-Chapisco (interno), EI-REV-Pintura Epóxi cor Verde, EI-REV-Massa única - Maior que 10m², EI-REV-Massa Corrida PVA (interna)
FNDE - Alvenarias: Alvenaria de Vedação / Edificação; Sistemas de Cobertura: -; Esquadrias - Fechamentos metálicos e Gradis: -; 1_Bloco: BLOCO B; 0_ID: AL14
Pset_WallCommon - IsExternal: yes; LoadBearing: no
Component Quantities - TIJOLO - CERAMICO 14x19x39 - espessura 20cm, Altura do Componente Retangular: 3.1 m; TIJOLO - CERAMICO 14x19x39 - espessura 20cm, Largura do Componente Retangular: 0.14 m; TIJOLO - CERAMICO 14x19x39 - espessura 20cm, Área de Seção Transversal do Componente: 0.434 m2; EI-REV-Chapisco (externo), Altura do Componente Retangular: 3.1 m; EI-REV-Chapisco (externo), Largura do Componente Retangular: 0.005 m; EI-REV-Chapisco (externo), Área de Seção Transversal do Componente: 0.0155 m2; EI-REV-Pintura Acrílica Cor Cinza, Altura do Componente Retangular: 0.44 m; EI-REV-Pintura Acrílica Cor Cinza, Largura do Componente Retangular: 0.015 m; EI-REV-Pintura Acrílica Cor Cinza, Área de Seção Transversal do Componente: 0.0066 m2; EI-REV-Pintura Acrílica Cor Branco Gelo 1, Altura do Componente Retangular: 2.66 m; EI-REV-Pintura Acrílica Cor Branco Gelo 1, Largura do Componente Retangular: 0.015 m; EI-REV-Pintura Acrílica Cor Branco Gelo 1, Área de Seção Transversal do Componente: 0.0399 m2; EI-REV-Chapisco (interno), Altura do Componente Retangular: 3.1 m; EI-REV-Chapisco (interno), Largura do Componente Retangular: 0.005 m; EI-REV-Chapisco (interno), Área de Seção Transversal do Componente: 0.0155 m2; EI-REV-Pintura Epóxi cor Verde, Altura do Componente Retangular: 0.9 m; EI-REV-Pintura Epóxi cor Verde, Largura do Componente Retangular: 0.02 m; EI-REV-Pintura Epóxi cor Verde, Área de Seção Transversal do Componente: 0.018 m2; EI-REV-Massa única - Maior que 10m², Área de Seção Transversal do Componente: 0.0155 m2; EI-REV-Massa Corrida PVA (interna), Altura do Componente Retangular: 2.16 m; EI-REV-Massa Corrida PVA (interna), Largura do Componente Retangular: 0.005 m; EI-REV-Massa Corrida PVA (interna), Área de Seção Transversal do Componente: 0.0108001 m2; EI-REV-Pintura Acrílica Cor Branco Gelo 2, Altura do Componente Retangular: 2.16 m; EI-REV-Pintura Acrílica Cor Branco Gelo 2, Largura do Componente Retangular: 0.015 m; EI-REV-Pintura Acrílica Cor Branco Gelo 2, Área de Seção Transversal do Componente: 0.0324 m2
Name | TIJOLO - CERAMICO 14x19x39 - espessura 20cm, Massa (kg) | TIJOLO - CERAMICO 14x19x39 - espessura 20cm, Área de Componente Projetada (Líquida) (m2) | TIJOLO - CERAMICO 14x19x39 - espessura 20cm, Área de Componente Projetada (Bruta) (m2) | TIJOLO - CERAMICO 14x19x39 - espessura 20cm, Volume Componente (Líquido) (m3) | TIJOLO - CERAMICO 14x19x39 - espessura 20cm, Volume do componente (Bruto) (m3) | EI-REV-Chapisco (externo), Massa (kg) | EI-REV-Chapisco (externo), Área de Componente Projetada (Líquida) (m2) | EI-REV-Chapisco (externo), Área de Componente Projetada (Bruta) (m2) | EI-REV-Chapisco (externo), Volume Componente (Líquido) (m3) | EI-REV-Chapisco (externo), Volume do componente (Bruto) (m3) | EI-REV-Pintura Acrílica Cor Cinza, Massa (kg) | EI-REV-Pintura Acrílica Cor Cinza, Área de Componente Projetada (Líquida) (m2) | EI-REV-Pintura Acrílica Cor Cinza, Área de Componente Projetada (Bruta) (m2) | EI-REV-Pintura Acrílica Cor Cinza, Volume Componente (Líquido) (m3) | EI-REV-Pintura Acrílica Cor Cinza, Volume do componente (Bruto) (m3) | EI-REV-Massa única - Fachada, Massa (kg) | EI-REV-Massa única - Fachada, Área de Componente Projetada (Líquida) (m2) | EI-REV-Massa única - Fachada, Área de Componente Projetada (Bruta) (m2) | EI-REV-Massa única - Fachada, Altura do Componente Retangular (m) = EI-REV-Massa Acrílica (externa), Altura do Componente Retangular (m) | EI-REV-Massa única - Fachada, Largura do Componente Retangular (m) = EI-REV-Massa Acrílica (externa), Largura do Componente Retangular (m) | EI-REV-Massa única - Fachada, Área de Seção Transversal do Componente (m2) = EI-REV-Massa Acrílica (externa), Área de Seção Transversal do Componente (m2) | EI-REV-Massa única - Fachada, Volume Componente (Líquido) (m3) | EI-REV-Massa única - Fachada, Volume do componente (Bruto) (m3) | EI-REV-Massa Acrílica (externa), Massa (kg) | EI-REV-Massa Acrílica (externa), Área de Componente Projetada (Líquida) (m2) | EI-REV-Massa Acrílica (externa), Área de Componente Projetada (Bruta) (m2) | EI-REV-Massa Acrílica (externa), Volume Componente (Líquido) (m3) | EI-REV-Massa Acrílica (externa), Volume do componente (Bruto) (m3) | EI-REV-Pintura Acrílica Cor Branco Gelo 1, Massa (kg) | EI-REV-Pintura Acrílica Cor Branco Gelo 1, Área de Componente Projetada (Líquida) (m2) | EI-REV-Pintura Acrílica Cor Branco Gelo 1, Área de Componente Projetada (Bruta) (m2) | EI-REV-Pintura Acrílica Cor Branco Gelo 1, Volume Componente (Líquido) (m3) | EI-REV-Pintura Acrílica Cor Branco Gelo 1, Volume do componente (Bruto) (m3) | EI-REV-Chapisco (interno), Massa (kg) | EI-REV-Chapisco (interno), Área de Componente Projetada (Líquida) (m2) | EI-REV-Chapisco (interno), Área de Componente Projetada (Bruta) (m2) | EI-REV-Chapisco (interno), Volume Componente (Líquido) (m3) | EI-REV-Chapisco (interno), Volume do componente (Bruto) (m3) | EI-REV-Pintura Epóxi cor Verde, Massa (kg) | EI-REV-Pintura Epóxi cor Verde, Área de Componente Projetada (Líquida) (m2) | EI-REV-Pintura Epóxi cor Verde, Área de Componente Projetada (Bruta) (m2) | EI-REV-Pintura Epóxi cor Verde, Volume Componente (Líquido) (m3) | EI-REV-Pintura Epóxi cor Verde, Volume do componente (Bruto) (m3) | EI-REV-Massa única - Maior que 10m², Massa (kg) | EI-REV-Massa única - Maior que 10m², Área de Componente Projetada (Líquida) (m2) | EI-REV-Massa única - Maior que 10m², Área de Componente Projetada (Bruta) (m2) | EI-REV-Massa única - Maior que 10m², Volume Componente (Líquido) (m3) | EI-REV-Massa única - Maior que 10m², Volume do componente (Bruto) (m3) | EI-REV-Massa Corrida PVA (interna), Massa (kg) | EI-REV-Massa Corrida PVA (interna), Área de Componente Projetada (Líquida) (m2) | EI-REV-Massa Corrida PVA (interna), Área de Componente Projetada (Bruta) (m2) | EI-REV-Massa Corrida PVA (interna), Volume Componente (Líquido) (m3) | EI-REV-Massa Corrida PVA (interna), Volume do componente (Bruto) (m3) | EI-REV-Pintura Acrílica Cor Branco Gelo 2, Massa (kg) | EI-REV-Pintura Acrílica Cor Branco Gelo 2, Área de Componente Projetada (Líquida) (m2) | EI-REV-Pintura Acrílica Cor Branco Gelo 2, Área de Componente Projetada (Bruta) (m2) | EI-REV-Pintura Acrílica Cor Branco Gelo 2, Volume Componente (Líquido) (m3) | EI-REV-Pintura Acrílica Cor Branco Gelo 2, Volume do componente (Bruto) (m3)
AL14 | 441.382 | 8.31838 | 20.2434 | 0.681145 | 2.35065 | 53.2668 | 8.19545 | 20.1204 | 0.0409744 | 0.100599 | 17.6791 | 0.951 | 2.751 | 0.0135993 | 0.0405993 | 53.2741 | 8.19657 | 20.1216 | 3.1 | 0.005 | 0.0155 | 0.0409801 | 0.100605 | 53.2814 | 8.1977 | 20.1227 | 0.0409857 | 0.100611 | 142.254 | 7.2951 | 17.4201 | 0.109426 | 0.261301 | 24.7441 | 3.80792 | 15.7329 | 0.0190339 | 0.0786588 | 33.4999 | 1.746 | 5.796 | 0.0257692 | 0.106769 | 24.5687 | 3.78093 | 15.7059 | 0.018899 | 0.078524 | 15.6223 | 2.4034 | 10.2784 | 0.0120172 | 0.0513922 | 60.8948 | 6.0058 | 13.8808 | 0.0468422 | 0.164967
AL14 | 223.396 | 3.05186 | 3.05186 | 0.344747 | 0.344747 | 18.1945 | 2.79916 | 2.79916 | 0.0139958 | 0.0139958 | 7.51525 | 0.385397 | 0.385397 | 0.00578096 | 0.00578096 | 18.1068 | 2.78566 | 2.78566 | 3.1 | 0.005 | 0.0155 | 0.0139283 | 0.0139283 | 18.019 | 2.77216 | 2.77216 | 0.0138608 | 0.0138608 | 46.2785 | 2.37326 | 2.37326 | 0.0355989 | 0.0355989 | 14.3033 | 2.20051 | 2.20051 | 0.0110025 | 0.0110025 | 19.8732 | 0.985494 | 0.985494 | 0.0152871 | 0.0152871 | 14.2155 | 2.18701 | 2.18701 | 0.010935 | 0.010935 | 9.20924 | 1.4168 | 1.4168 | 0.00708403 | 0.00708403 | 31.1975 | 2.35039 | 2.35039 | 0.023998 | 0.023998
AL14 | 852.229 | 11.2612 | 16.8612 | 1.31517 | 2.09245 | 97.3965 | 14.9841 | 20.5841 | 0.0749204 | 0.10292 | 57.4004 | 2.94361 | 2.94361 | 0.0441542 | 0.0441542 | 97.598 | 15.0151 | 20.6151 | 3.1 | 0.005 | 0.0155 | 0.0750754 | 0.103075 | 97.7995 | 15.0461 | 20.6461 | 0.0752304 | 0.10323 | 237.812 | 12.1955 | 17.7955 | 0.182932 | 0.266932 | 86.2932 | 13.2809 | 18.8809 | 0.0663794 | 0.0943682 | 146.719 | 5.64302 | 5.64302 | 0.112861 | 0.112861 | 84.6799 | 13.0266 | 18.6266 | 0.0651384 | 0.0931474 | 51.5705 | 7.93648 | 13.5365 | 0.0396696 | 0.0676655 | 154.048 | 7.89998 | 13.5 | 0.118498 | 0.202498
AL14 | 215.769 | 2.66619 | 2.66619 | 0.332977 | 0.332977 | 20.0506 | 3.08471 | 3.08471 | 0.0154236 | 0.0154236 | 8.45189 | 0.43343 | 0.43343 | 0.00650145 | 0.00650145 |  |  |  |  |  |  |  |  |  |  |  |  |  | 51.0955 | 2.62028 | 2.62028 | 0.0393042 | 0.0393042 | 17.4634 | 2.68668 | 2.68668 | 0.0134334 | 0.0134334 | 22.9336 | 0.882061 | 0.882061 | 0.0176412 | 0.0176412 | 17.4635 | 2.68668 | 2.68668 | 0.0134334 | 0.0134334 | 11.3836 | 1.75132 | 1.75132 | 0.00875664 | 0.00875664 | 37.4524 | 2.12865 | 2.12865 | 0.0288095 | 0.0288095 | Component Quantities - EI-REV-Chapisco (externo): 3 with these values

# IfcWall: FNDE-AL14-I4-E1 (30x40-cinza) 200 x 3100 (3)
In: TÉRREO
Classification: Parede (Classificação Archicad); Material: TIJOLO - CERAMICO 14x19x39 - espessura 20cm, EI-REV-Chapisco (externo), EI-REV-Pintura Acrílica Cor Cinza, EI-REV-Massa única - Fachada, EI-REV-Massa Acrílica (externa), EI-REV-Pintura Acrílica Cor Branco Gelo, EI-REV-Chapisco (interno), EI-REV-Emboço Interno, EI-REV-Cerâmica 30x40
FNDE - Alvenarias: Alvenaria de Vedação / Edificação; Sistemas de Cobertura: -; Esquadrias - Fechamentos metálicos e Gradis: -; 1_Bloco: BLOCO A; 0_ID: AL14
Pset_WallCommon - IsExternal: yes; LoadBearing: no
Component Quantities - TIJOLO - CERAMICO 14x19x39 - espessura 20cm, Altura do Componente Retangular: 3.1 m; TIJOLO - CERAMICO 14x19x39 - espessura 20cm, Largura do Componente Retangular: 0.14 m; TIJOLO - CERAMICO 14x19x39 - espessura 20cm, Área de Seção Transversal do Componente: 0.434 m2; EI-REV-Chapisco (externo), Altura do Componente Retangular: 3.1 m; EI-REV-Chapisco (externo), Largura do Componente Retangular: 0.005 m; EI-REV-Chapisco (externo), Área de Seção Transversal do Componente: 0.0155 m2; EI-REV-Pintura Acrílica Cor Cinza, Altura do Componente Retangular: 0.44 m; EI-REV-Pintura Acrílica Cor Cinza, Largura do Componente Retangular: 0.015 m; EI-REV-Pintura Acrílica Cor Cinza, Área de Seção Transversal do Componente: 0.0066 m2; EI-REV-Pintura Acrílica Cor Branco Gelo, Altura do Componente Retangular: 2.66 m; EI-REV-Pintura Acrílica Cor Branco Gelo, Largura do Componente Retangular: 0.015 m; EI-REV-Pintura Acrílica Cor Branco Gelo, Área de Seção Transversal do Componente: 0.0399 m2; EI-REV-Chapisco (interno), Altura do Componente Retangular: 3.1 m; EI-REV-Chapisco (interno), Largura do Componente Retangular: 0.005 m; EI-REV-Chapisco (interno), Área de Seção Transversal do Componente: 0.0155 m2; EI-REV-Cerâmica 30x40, Altura do Componente Retangular: 3.1 m; EI-REV-Cerâmica 30x40, Largura do Componente Retangular: 0.02 m; EI-REV-Cerâmica 30x40, Área de Seção Transversal do Componente: 0.062 m2
Name | TIJOLO - CERAMICO 14x19x39 - espessura 20cm, Massa (kg) | TIJOLO - CERAMICO 14x19x39 - espessura 20cm, Área de Componente Projetada (Líquida) (m2) | TIJOLO - CERAMICO 14x19x39 - espessura 20cm, Área de Componente Projetada (Bruta) (m2) | TIJOLO - CERAMICO 14x19x39 - espessura 20cm, Volume Componente (Líquido) (m3) | TIJOLO - CERAMICO 14x19x39 - espessura 20cm, Volume do componente (Bruto) (m3) | EI-REV-Chapisco (externo), Massa (kg) | EI-REV-Chapisco (externo), Área de Componente Projetada (Líquida) (m2) | EI-REV-Chapisco (externo), Área de Componente Projetada (Bruta) (m2) | EI-REV-Chapisco (externo), Volume Componente (Líquido) (m3) | EI-REV-Chapisco (externo), Volume do componente (Bruto) (m3) | EI-REV-Pintura Acrílica Cor Cinza, Massa (kg) | EI-REV-Pintura Acrílica Cor Cinza, Área de Componente Projetada (Líquida) (m2) = EI-REV-Pintura Acrílica Cor Cinza, Área de Componente Projetada (Bruta) (m2) | EI-REV-Pintura Acrílica Cor Cinza, Volume Componente (Líquido) (m3) = EI-REV-Pintura Acrílica Cor Cinza, Volume do componente (Bruto) (m3) | EI-REV-Massa única - Fachada, Massa (kg) | EI-REV-Massa única - Fachada, Área de Componente Projetada (Líquida) (m2) | EI-REV-Massa única - Fachada, Área de Componente Projetada (Bruta) (m2) | EI-REV-Massa única - Fachada, Altura do Componente Retangular (m) = EI-REV-Massa Acrílica (externa), Altura do Componente Retangular (m) | EI-REV-Massa única - Fachada, Largura do Componente Retangular (m) = EI-REV-Massa Acrílica (externa), Largura do Componente Retangular (m) | EI-REV-Massa única - Fachada, Área de Seção Transversal do Componente (m2) = EI-REV-Massa Acrílica (externa), Área de Seção Transversal do Componente (m2) | EI-REV-Massa única - Fachada, Volume Componente (Líquido) (m3) | EI-REV-Massa única - Fachada, Volume do componente (Bruto) (m3) | EI-REV-Massa Acrílica (externa), Massa (kg) | EI-REV-Massa Acrílica (externa), Área de Componente Projetada (Líquida) (m2) | EI-REV-Massa Acrílica (externa), Área de Componente Projetada (Bruta) (m2) | EI-REV-Massa Acrílica (externa), Volume Componente (Líquido) (m3) | EI-REV-Massa Acrílica (externa), Volume do componente (Bruto) (m3) | EI-REV-Pintura Acrílica Cor Branco Gelo, Massa (kg) | EI-REV-Pintura Acrílica Cor Branco Gelo, Área de Componente Projetada (Líquida) (m2) | EI-REV-Pintura Acrílica Cor Branco Gelo, Área de Componente Projetada (Bruta) (m2) | EI-REV-Pintura Acrílica Cor Branco Gelo, Volume Componente (Líquido) (m3) | EI-REV-Pintura Acrílica Cor Branco Gelo, Volume do componente (Bruto) (m3) | EI-REV-Chapisco (interno), Massa (kg) | EI-REV-Chapisco (interno), Área de Componente Projetada (Líquida) (m2) | EI-REV-Chapisco (interno), Área de Componente Projetada (Bruta) (m2) | EI-REV-Chapisco (interno), Volume Componente (Líquido) (m3) | EI-REV-Chapisco (interno), Volume do componente (Bruto) (m3) | EI-REV-Cerâmica 30x40, Massa (kg) | EI-REV-Cerâmica 30x40, Área de Componente Projetada (Líquida) (m2) | EI-REV-Cerâmica 30x40, Área de Componente Projetada (Bruta) (m2) | EI-REV-Cerâmica 30x40, Volume Componente (Líquido) (m3) | EI-REV-Cerâmica 30x40, Volume do componente (Bruto) (m3) | EI-REV-Emboço Interno, Massa (kg) | EI-REV-Emboço Interno, Área de Componente Projetada (Líquida) (m2) | EI-REV-Emboço Interno, Área de Componente Projetada (Bruta) (m2) | EI-REV-Emboço Interno, Altura do Componente Retangular (m) | EI-REV-Emboço Interno, Largura do Componente Retangular (m) | EI-REV-Emboço Interno, Área de Seção Transversal do Componente (m2) | EI-REV-Emboço Interno, Volume Componente (Líquido) (m3) | EI-REV-Emboço Interno, Volume do componente (Bruto) (m3)
AL14 | 182.852 | 3.4778 | 3.4778 | 0.282179 | 0.282179 | 20.2106 | 3.10932 | 3.10932 | 0.0155466 | 0.0155466 | 8.70815 | 0.446572 | 0.00669857 | 20.2236 | 3.11132 | 3.11132 | 3.1 | 0.005 | 0.0155 | 0.0155566 | 0.0155566 | 20.2366 | 3.11332 | 3.11332 | 0.0155666 | 0.0155666 | 52.6447 | 2.69973 | 2.69973 | 0.0404959 | 0.0404959 | 10.0027 | 1.53888 | 1.53888 | 0.00769441 | 0.00769441 | 68.4414 | 2.2318 | 2.2318 | 0.0342207 | 0.0342207 | Component Quantities - EI-REV-Chapisco (interno): 2 with these values
AL14 | 424.961 | 5.71785 | 6.73035 | 0.655804 | 0.797554 | 40.4951 | 6.25768 | 7.27018 | 0.0311501 | 0.0362126 | 20.2507 | 1.0385 | 0.0155775 | 40.7757 | 6.27318 | 7.28568 | 3.1 | 0.005 | 0.0155 | 0.0313659 | 0.0364284 | 40.8764 | 6.28868 | 7.30118 | 0.0314434 | 0.0365059 | 102.681 | 5.26569 | 6.27819 | 0.0789853 | 0.0941728 | 36.3763 | 5.59635 | 6.60885 | 0.0279818 | 0.0330443 | 222.147 | 5.55395 | 6.56645 | 0.111074 | 0.131324 | 36.2885 | 5.58285 | 6.59535 | 3.1 | 0.005 | 0.0155 | 0.0279143 | 0.0329768
AL14 | 723.892 | 8.23157 | 8.23157 | 1.11712 | 1.11712 | 51.6561 | 7.94709 | 7.94709 | 0.0397354 | 0.0397354 | 28.249 | 1.44943 | 0.02173 |  |  |  |  |  |  |  |  |  |  |  |  |  | 137.986 | 7.0794 | 7.0794 | 0.106143 | 0.106143 | 52.2657 | 8.04087 | 8.04087 | 0.0402044 | 0.0402044 | 364 | 9.1 | 9.1 | 0.182 | 0.182 | 51.9725 | 7.99577 | 7.99577 | 3.1 | 0.005 | 0.0155 | 0.0399789 | 0.0399789 | Component Quantities - EI-REV-Chapisco (externo): 3 with these values

# IfcWall: FNDE-AL14-I4-E2 (30x40-cinza) 200 x 3100, AL14
In: TÉRREO
Classification: Parede (Classificação Archicad); Material: TIJOLO - CERAMICO 14x19x39 - espessura 20cm, EI-REV-Chapisco (externo), EI-REV-Massa única - Fachada, EI-REV-Massa Acrílica (externa), EI-REV-Pintura Acrílica Cor Cinza, EI-REV-Chapisco (interno), EI-REV-Cerâmica 30x40, EI-REV-Emboço Interno
FNDE - Alvenarias: Alvenaria de Vedação / Edificação; Sistemas de Cobertura: -; Esquadrias - Fechamentos metálicos e Gradis: -; 1_Bloco: BLOCO A; 0_ID: AL14
Pset_WallCommon - IsExternal: yes; LoadBearing: no
Component Quantities - TIJOLO - CERAMICO 14x19x39 - espessura 20cm, Massa: 406.066 kg; TIJOLO - CERAMICO 14x19x39 - espessura 20cm, Área de Componente Projetada (Líquida): 6.06515 m2; TIJOLO - CERAMICO 14x19x39 - espessura 20cm, Área de Componente Projetada (Bruta): 8.16515 m2; TIJOLO - CERAMICO 14x19x39 - espessura 20cm, Altura do Componente Retangular: 3.1 m; TIJOLO - CERAMICO 14x19x39 - espessura 20cm, Largura do Componente Retangular: 0.14 m; TIJOLO - CERAMICO 14x19x39 - espessura 20cm, Área de Seção Transversal do Componente: 0.434 m2; TIJOLO - CERAMICO 14x19x39 - espessura 20cm, Volume Componente (Líquido): 0.626645 m3; TIJOLO - CERAMICO 14x19x39 - espessura 20cm, Volume do componente (Bruto): 0.920645 m3; EI-REV-Chapisco (externo), Massa: 27.771 kg; EI-REV-Chapisco (externo), Área de Componente Projetada (Líquida): 4.27246 m2; EI-REV-Chapisco (externo), Área de Componente Projetada (Bruta): 6.37246 m2; EI-REV-Chapisco (externo), Altura do Componente Retangular: 3.1 m; EI-REV-Chapisco (externo), Largura do Componente Retangular: 0.005 m; EI-REV-Chapisco (externo), Área de Seção Transversal do Componente: 0.0155 m2; EI-REV-Chapisco (externo), Volume Componente (Líquido): 0.0213623 m3; EI-REV-Chapisco (externo), Volume do componente (Bruto): 0.0318623 m3; EI-REV-Massa única - Fachada, Massa: 27.6832 kg; EI-REV-Massa única - Fachada, Área de Componente Projetada (Líquida): 4.25896 m2; EI-REV-Massa única - Fachada, Área de Componente Projetada (Bruta): 6.35896 m2; EI-REV-Massa única - Fachada, Altura do Componente Retangular: 3.1 m; EI-REV-Massa única - Fachada, Largura do Componente Retangular: 0.005 m; EI-REV-Massa única - Fachada, Área de Seção Transversal do Componente: 0.0155 m2; EI-REV-Massa única - Fachada, Volume Componente (Líquido): 0.0212948 m3; EI-REV-Massa única - Fachada, Volume do componente (Bruto): 0.0317948 m3; EI-REV-Massa Acrílica (externa), Massa: 27.7005 kg; EI-REV-Massa Acrílica (externa), Área de Componente Projetada (Líquida): 6.1151 m2; EI-REV-Massa Acrílica (externa), Área de Componente Projetada (Bruta): 8.2151 m2; EI-REV-Massa Acrílica (externa), Altura do Componente Retangular: 3.1 m; EI-REV-Massa Acrílica (externa), Largura do Componente Retangular: 0.005 m; EI-REV-Massa Acrílica (externa), Área de Seção Transversal do Componente: 0.0155 m2; EI-REV-Massa Acrílica (externa), Volume Componente (Líquido): 0.021308 m3; EI-REV-Massa Acrílica (externa), Volume do componente (Bruto): 0.031808 m3; EI-REV-Pintura Acrílica Cor Cinza, Massa: 119.244 kg; EI-REV-Pintura Acrílica Cor Cinza, Área de Componente Projetada (Líquida): 6.1151 m2; EI-REV-Pintura Acrílica Cor Cinza, Área de Componente Projetada (Bruta): 8.2151 m2; EI-REV-Pintura Acrílica Cor Cinza, Altura do Componente Retangular: 3.1 m; EI-REV-Pintura Acrílica Cor Cinza, Largura do Componente Retangular: 0.015 m; EI-REV-Pintura Acrílica Cor Cinza, Área de Seção Transversal do Componente: 0.0465 m2; EI-REV-Pintura Acrílica Cor Cinza, Volume Componente (Líquido): 0.0917265 m3; EI-REV-Pintura Acrílica Cor Cinza, Volume do componente (Bruto): 0.123226 m3; EI-REV-Chapisco (interno), Massa: 37.3374 kg; EI-REV-Chapisco (interno), Área de Componente Projetada (Líquida): 5.74421 m2; EI-REV-Chapisco (interno), Área de Componente Projetada (Bruta): 7.84421 m2; EI-REV-Chapisco (interno), Altura do Componente Retangular: 3.1 m; EI-REV-Chapisco (interno), Largura do Componente Retangular: 0.005 m; EI-REV-Chapisco (interno), Área de Seção Transversal do Componente: 0.0155 m2; EI-REV-Chapisco (interno), Volume Componente (Líquido): 0.0287211 m3; EI-REV-Chapisco (interno), Volume do componente (Bruto): 0.0392211 m3; EI-REV-Cerâmica 30x40, Massa: 226.72 kg; EI-REV-Cerâmica 30x40, Área de Componente Projetada (Líquida): 5.66801 m2; EI-REV-Cerâmica 30x40, Área de Componente Projetada (Bruta): 7.76801 m2; EI-REV-Cerâmica 30x40, Altura do Componente Retangular: 3.1 m; EI-REV-Cerâmica 30x40, Largura do Componente Retangular: 0.02 m; EI-REV-Cerâmica 30x40, Área de Seção Transversal do Componente: 0.062 m2; EI-REV-Cerâmica 30x40, Volume Componente (Líquido): 0.11336 m3; EI-REV-Cerâmica 30x40, Volume do componente (Bruto): 0.15536 m3; EI-REV-Emboço Interno, Massa: 37.0897 kg; EI-REV-Emboço Interno, Área de Componente Projetada (Líquida): 5.70611 m2; EI-REV-Emboço Interno, Área de Componente Projetada (Bruta): 7.80611 m2; EI-REV-Emboço Interno, Altura do Componente Retangular: 3.1 m; EI-REV-Emboço Interno, Largura do Componente Retangular: 0.005 m; EI-REV-Emboço Interno, Área de Seção Transversal do Componente: 0.0155 m2; EI-REV-Emboço Interno, Volume Componente (Líquido): 0.0285306 m3; EI-REV-Emboço Interno, Volume do componente (Bruto): 0.0390306 m3

# IfcWall: FNDE-AL14-I4-I7 (30x40-amarela) 200 x 3100, AL14
In: TÉRREO
Classification: Parede (Classificação Archicad); Material: TIJOLO - CERAMICO 14x19x39 - espessura 20cm, EI-REV-Chapisco (interno) (2), EI-REV-Cerâmica 10x10 Amarela, EI-REV-Cerâmica 10x10 Branca, EI-REV-Emboço Interno (2), EI-REV-Massa única - Maior que 10m², EI-REV-Massa Corrida PVA (interna), EI-REV-Pintura Acrílica Cor Branco Gelo, EI-REV-Cerâmica 30x40
FNDE - Alvenarias: Alvenaria de Vedação / Edificação; Sistemas de Cobertura: -; Esquadrias - Fechamentos metálicos e Gradis: -; 1_Bloco: BLOCO A; 0_ID: AL14
Pset_WallCommon - IsExternal: no; LoadBearing: no
Component Quantities - TIJOLO - CERAMICO 14x19x39 - espessura 20cm, Massa: 517.615 kg; TIJOLO - CERAMICO 14x19x39 - espessura 20cm, Área de Componente Projetada (Líquida): 6.66027 m2; TIJOLO - CERAMICO 14x19x39 - espessura 20cm, Área de Componente Projetada (Bruta): 6.66027 m2; TIJOLO - CERAMICO 14x19x39 - espessura 20cm, Altura do Componente Retangular: 3.1 m; TIJOLO - CERAMICO 14x19x39 - espessura 20cm, Largura do Componente Retangular: 0.14 m; TIJOLO - CERAMICO 14x19x39 - espessura 20cm, Área de Seção Transversal do Componente: 0.434 m2; TIJOLO - CERAMICO 14x19x39 - espessura 20cm, Volume Componente (Líquido): 0.798788 m3; TIJOLO - CERAMICO 14x19x39 - espessura 20cm, Volume do componente (Bruto): 0.798788 m3; EI-REV-Chapisco (interno) 1, Massa: 42.5715 kg; EI-REV-Chapisco (interno) 1, Área de Componente Projetada (Líquida): 6.54947 m2; EI-REV-Chapisco (interno) 1, Área de Componente Projetada (Bruta): 6.54947 m2; EI-REV-Chapisco (interno) 1, Altura do Componente Retangular: 3.1 m; EI-REV-Chapisco (interno) 1, Largura do Componente Retangular: 0.005 m; EI-REV-Chapisco (interno) 1, Área de Seção Transversal do Componente: 0.0155 m2; EI-REV-Chapisco (interno) 1, Volume Componente (Líquido): 0.0327473 m3; EI-REV-Chapisco (interno) 1, Volume do componente (Bruto): 0.0327473 m3; EI-REV-Cerâmica 10x10 Amarela, Massa: 75.4174 kg; EI-REV-Cerâmica 10x10 Amarela, Área de Componente Projetada (Líquida): 1.88544 m2; EI-REV-Cerâmica 10x10 Amarela, Área de Componente Projetada (Bruta): 1.88544 m2; EI-REV-Cerâmica 10x10 Amarela, Altura do Componente Retangular: 0.9 m; EI-REV-Cerâmica 10x10 Amarela, Largura do Componente Retangular: 0.02 m; EI-REV-Cerâmica 10x10 Amarela, Área de Seção Transversal do Componente: 0.018 m2; EI-REV-Cerâmica 10x10 Amarela, Volume Componente (Líquido): 0.0377087 m3; EI-REV-Cerâmica 10x10 Amarela, Volume do componente (Bruto): 0.0377087 m3; EI-REV-Cerâmica 10x10 Branca, Massa: 8.37971 kg; EI-REV-Cerâmica 10x10 Branca, Área de Componente Projetada (Líquida): 0.209493 m2; EI-REV-Cerâmica 10x10 Branca, Área de Componente Projetada (Bruta): 0.209493 m2; EI-REV-Cerâmica 10x10 Branca, Altura do Componente Retangular: 0.1 m; EI-REV-Cerâmica 10x10 Branca, Largura do Componente Retangular: 0.02 m; EI-REV-Cerâmica 10x10 Branca, Área de Seção Transversal do Componente: 0.002 m2; EI-REV-Cerâmica 10x10 Branca, Volume Componente (Líquido): 0.00418986 m3; EI-REV-Cerâmica 10x10 Branca, Volume do componente (Bruto): 0.00418986 m3; EI-REV-Emboço Interno 1, Massa: 42.396 kg; EI-REV-Emboço Interno 1, Área de Componente Projetada (Líquida): 6.52247 m2; EI-REV-Emboço Interno 1, Área de Componente Projetada (Bruta): 6.52247 m2; EI-REV-Emboço Interno 1, Altura do Componente Retangular: 3.1 m; EI-REV-Emboço Interno 1, Largura do Componente Retangular: 0.005 m; EI-REV-Emboço Interno 1, Área de Seção Transversal do Componente: 0.0155 m2; EI-REV-Emboço Interno 1, Volume Componente (Líquido): 0.0326123 m3; EI-REV-Emboço Interno 1, Volume do componente (Bruto): 0.0326123 m3; EI-REV-Massa única - Maior que 10m², Massa: 28.2645 kg; EI-REV-Massa única - Maior que 10m², Área de Componente Projetada (Líquida): 4.34839 m2; EI-REV-Massa única - Maior que 10m², Área de Componente Projetada (Bruta): 4.34839 m2; EI-REV-Massa única - Maior que 10m², Altura do Componente Retangular: 2.06 m; EI-REV-Massa única - Maior que 10m², Largura do Componente Retangular: 0.00499999 m; EI-REV-Massa única - Maior que 10m², Área de Seção Transversal do Componente: 0.0103 m2; EI-REV-Massa única - Maior que 10m², Volume Componente (Líquido): 0.0217419 m3; EI-REV-Massa única - Maior que 10m², Volume do componente (Bruto): 0.0217419 m3; EI-REV-Massa Corrida PVA (interna), Massa: 28.0887 kg; EI-REV-Massa Corrida PVA (interna), Área de Componente Projetada (Líquida): 4.32132 m2; EI-REV-Massa Corrida PVA (interna), Área de Componente Projetada (Bruta): 4.32132 m2; EI-REV-Massa Corrida PVA (interna), Altura do Componente Retangular: 2.06 m; EI-REV-Massa Corrida PVA (interna), Largura do Componente Retangular: 0.00500002 m; EI-REV-Massa Corrida PVA (interna), Área de Seção Transversal do Componente: 0.0103 m2; EI-REV-Massa Corrida PVA (interna), Volume Componente (Líquido): 0.0216067 m3; EI-REV-Massa Corrida PVA (interna), Volume do componente (Bruto): 0.0216067 m3; EI-REV-Pintura Acrílica Cor Branco Gelo, Massa: 55.6937 kg; EI-REV-Pintura Acrílica Cor Branco Gelo, Área de Componente Projetada (Líquida): 4.28413 m2; EI-REV-Pintura Acrílica Cor Branco Gelo, Área de Componente Projetada (Bruta): 4.28413 m2; EI-REV-Pintura Acrílica Cor Branco Gelo, Altura do Componente Retangular: 2.06 m; EI-REV-Pintura Acrílica Cor Branco Gelo, Largura do Componente Retangular: 0.01 m; EI-REV-Pintura Acrílica Cor Branco Gelo, Área de Seção Transversal do Componente: 0.0206 m2; EI-REV-Pintura Acrílica Cor Branco Gelo, Volume Componente (Líquido): 0.0428413 m3; EI-REV-Pintura Acrílica Cor Branco Gelo, Volume do componente (Bruto): 0.0428413 m3; EI-REV-Chapisco (interno) 2, Massa: 37.5551 kg; EI-REV-Chapisco (interno) 2, Área de Componente Projetada (Líquida): 5.77771 m2; EI-REV-Chapisco (interno) 2, Área de Componente Projetada (Bruta): 5.77771 m2; EI-REV-Chapisco (interno) 2, Altura do Componente Retangular: 3.1 m; EI-REV-Chapisco (interno) 2, Largura do Componente Retangular: 0.005 m; EI-REV-Chapisco (interno) 2, Área de Seção Transversal do Componente: 0.0155 m2; EI-REV-Chapisco (interno) 2, Volume Componente (Líquido): 0.0288886 m3; EI-REV-Chapisco (interno) 2, Volume do componente (Bruto): 0.0288886 m3; EI-REV-Cerâmica 30x40, Massa: 250.62 kg; EI-REV-Cerâmica 30x40, Área de Componente Projetada (Líquida): 6.99408 m2; EI-REV-Cerâmica 30x40, Área de Componente Projetada (Bruta): 6.99408 m2; EI-REV-Cerâmica 30x40, Altura do Componente Retangular: 3.1 m; EI-REV-Cerâmica 30x40, Largura do Componente Retangular: 0.02 m; EI-REV-Cerâmica 30x40, Área de Seção Transversal do Componente: 0.062 m2; EI-REV-Cerâmica 30x40, Volume Componente (Líquido): 0.12531 m3; EI-REV-Cerâmica 30x40, Volume do componente (Bruto): 0.12531 m3; EI-REV-Emboço Interno 2, Massa: 37.6429 kg; EI-REV-Emboço Interno 2, Área de Componente Projetada (Líquida): 5.79121 m2; EI-REV-Emboço Interno 2, Área de Componente Projetada (Bruta): 5.79121 m2; EI-REV-Emboço Interno 2, Altura do Componente Retangular: 3.1 m; EI-REV-Emboço Interno 2, Largura do Componente Retangular: 0.005 m; EI-REV-Emboço Interno 2, Área de Seção Transversal do Componente: 0.0155 m2; EI-REV-Emboço Interno 2, Volume Componente (Líquido): 0.0289561 m3; EI-REV-Emboço Interno 2, Volume do componente (Bruto): 0.0289561 m3

# IfcWall: FNDE-AL14-I5-E1 (azul-cinza) 200 x 3100, AL14
In: TÉRREO
Classification: Parede (Classificação Archicad); Material: TIJOLO - CERAMICO 14x19x39 - espessura 20cm, EI-REV-Chapisco (externo), EI-REV-Massa única - Fachada, EI-REV-Massa Acrílica (externa), EI-REV-Chapisco (interno), EI-REV-Cerâmica 30x40, EI-REV-Cerâmica 10x10 Azul, EI-REV-Emboço Interno, EI-REV-Massa única - Maior que 10m², EI-REV-Massa Corrida PVA (interna), EI-REV-Pintura Acrílica Cor Branco Gelo (2), EI-REV-Pintura Acrílica Cor Cinza
FNDE - Alvenarias: Alvenaria de Vedação / Edificação; Sistemas de Cobertura: -; Esquadrias - Fechamentos metálicos e Gradis: -; 1_Bloco: BLOCO A; 0_ID: AL14
Pset_WallCommon - IsExternal: yes; LoadBearing: no
Component Quantities - TIJOLO - CERAMICO 14x19x39 - espessura 20cm, Massa: 343.264 kg; TIJOLO - CERAMICO 14x19x39 - espessura 20cm, Área de Componente Projetada (Líquida): 5.00753 m2; TIJOLO - CERAMICO 14x19x39 - espessura 20cm, Área de Componente Projetada (Bruta): 6.02003 m2; TIJOLO - CERAMICO 14x19x39 - espessura 20cm, Altura do Componente Retangular: 3.1 m; TIJOLO - CERAMICO 14x19x39 - espessura 20cm, Largura do Componente Retangular: 0.14 m; TIJOLO - CERAMICO 14x19x39 - espessura 20cm, Área de Seção Transversal do Componente: 0.434 m2; TIJOLO - CERAMICO 14x19x39 - espessura 20cm, Volume Componente (Líquido): 0.529728 m3; TIJOLO - CERAMICO 14x19x39 - espessura 20cm, Volume do componente (Bruto): 0.671478 m3; EI-REV-Chapisco (externo), Massa: 32.5331 kg; EI-REV-Chapisco (externo), Área de Componente Projetada (Líquida): 5.03551 m2; EI-REV-Chapisco (externo), Área de Componente Projetada (Bruta): 6.04801 m2; EI-REV-Chapisco (externo), Altura do Componente Retangular: 3.1 m; EI-REV-Chapisco (externo), Largura do Componente Retangular: 0.005 m; EI-REV-Chapisco (externo), Área de Seção Transversal do Componente: 0.0155 m2; EI-REV-Chapisco (externo), Volume Componente (Líquido): 0.0250255 m3; EI-REV-Chapisco (externo), Volume do componente (Bruto): 0.030088 m3; EI-REV-Massa única - Fachada, Massa: 32.7308 kg; EI-REV-Massa única - Fachada, Área de Componente Projetada (Líquida): 5.03551 m2; EI-REV-Massa única - Fachada, Área de Componente Projetada (Bruta): 6.04801 m2; EI-REV-Massa única - Fachada, Altura do Componente Retangular: 3.1 m; EI-REV-Massa única - Fachada, Largura do Componente Retangular: 0.005 m; EI-REV-Massa única - Fachada, Área de Seção Transversal do Componente: 0.0155 m2; EI-REV-Massa única - Fachada, Volume Componente (Líquido): 0.0251776 m3; EI-REV-Massa única - Fachada, Volume do componente (Bruto): 0.0302401 m3; EI-REV-Chapisco (interno), Massa: 30.8523 kg; EI-REV-Chapisco (interno), Área de Componente Projetada (Líquida): 4.74653 m2; EI-REV-Chapisco (interno), Área de Componente Projetada (Bruta): 5.75903 m2; EI-REV-Chapisco (interno), Altura do Componente Retangular: 3.1 m; EI-REV-Chapisco (interno), Largura do Componente Retangular: 0.005 m; EI-REV-Chapisco (interno), Área de Seção Transversal do Componente: 0.0155 m2; EI-REV-Chapisco (interno), Volume Componente (Líquido): 0.0237326 m3; EI-REV-Chapisco (interno), Volume do componente (Bruto): 0.0287951 m3; EI-REV-Cerâmica 30x40, Massa: 132.49 kg; EI-REV-Cerâmica 30x40, Área de Componente Projetada (Líquida): 3.31375 m2; EI-REV-Cerâmica 30x40, Área de Componente Projetada (Bruta): 3.31375 m2; EI-REV-Cerâmica 30x40, Altura do Componente Retangular: 1.8 m; EI-REV-Cerâmica 30x40, Largura do Componente Retangular: 0.02 m; EI-REV-Cerâmica 30x40, Área de Seção Transversal do Componente: 0.036 m2; EI-REV-Cerâmica 30x40, Volume Componente (Líquido): 0.0662452 m3; EI-REV-Cerâmica 30x40, Volume do componente (Bruto): 0.0662452 m3; EI-REV-Cerâmica 10x10 Azul, Massa: 7.36389 kg; EI-REV-Cerâmica 10x10 Azul, Área de Componente Projetada (Líquida): 0.184097 m2; EI-REV-Cerâmica 10x10 Azul, Área de Componente Projetada (Bruta): 0.184097 m2; EI-REV-Cerâmica 10x10 Azul, Altura do Componente Retangular: 0.1 m; EI-REV-Cerâmica 10x10 Azul, Largura do Componente Retangular: 0.02 m; EI-REV-Cerâmica 10x10 Azul, Área de Seção Transversal do Componente: 0.002 m2; EI-REV-Cerâmica 10x10 Azul, Volume Componente (Líquido): 0.00368195 m3; EI-REV-Cerâmica 10x10 Azul, Volume do componente (Bruto): 0.00368195 m3; EI-REV-Emboço Interno, Massa: 30.6639 kg; EI-REV-Emboço Interno, Área de Componente Projetada (Líquida): 4.71753 m2; EI-REV-Emboço Interno, Área de Componente Projetada (Bruta): 5.73003 m2; EI-REV-Emboço Interno, Altura do Componente Retangular: 3.1 m; EI-REV-Emboço Interno, Largura do Componente Retangular: 0.005 m; EI-REV-Emboço Interno, Área de Seção Transversal do Componente: 0.0155 m2; EI-REV-Emboço Interno, Volume Componente (Líquido): 0.0235876 m3; EI-REV-Emboço Interno, Volume do componente (Bruto): 0.0286501 m3; EI-REV-Massa única - Maior que 10m², Massa: 7.38042 kg; EI-REV-Massa única - Maior que 10m², Área de Componente Projetada (Líquida): 1.13545 m2; EI-REV-Massa única - Maior que 10m², Área de Componente Projetada (Bruta): 2.14795 m2; EI-REV-Massa única - Maior que 10m², Altura do Componente Retangular: 1.17 m; EI-REV-Massa única - Maior que 10m², Largura do Componente Retangular: 0.00499997 m; EI-REV-Massa única - Maior que 10m², Área de Seção Transversal do Componente: 0.00584996 m2; EI-REV-Massa única - Maior que 10m², Volume Componente (Líquido): 0.00567725 m3; EI-REV-Massa única - Maior que 10m², Volume do componente (Bruto): 0.0107397 m3; EI-REV-Massa Corrida PVA (interna), Massa: 7.31738 kg; EI-REV-Massa Corrida PVA (interna), Área de Componente Projetada (Líquida): 1.12575 m2; EI-REV-Massa Corrida PVA (interna), Área de Componente Projetada (Bruta): 2.13825 m2; EI-REV-Massa Corrida PVA (interna), Altura do Componente Retangular: 1.17 m; EI-REV-Massa Corrida PVA (interna), Largura do Componente Retangular: 0.005 m; EI-REV-Massa Corrida PVA (interna), Área de Seção Transversal do Componente: 0.00585001 m2; EI-REV-Massa Corrida PVA (interna), Volume Componente (Líquido): 0.00562875 m3; EI-REV-Massa Corrida PVA (interna), Volume do componente (Bruto): 0.0106913 m3; EI-REV-Pintura Acrílica Cor Branco Gelo 1, Massa: 14.5087 kg; EI-REV-Pintura Acrílica Cor Branco Gelo 1, Área de Componente Projetada (Líquida): 1.11605 m2; EI-REV-Pintura Acrílica Cor Branco Gelo 1, Área de Componente Projetada (Bruta): 2.12855 m2; EI-REV-Pintura Acrílica Cor Branco Gelo 1, Altura do Componente Retangular: 1.17 m; EI-REV-Pintura Acrílica Cor Branco Gelo 1, Largura do Componente Retangular: 0.01 m; EI-REV-Pintura Acrílica Cor Branco Gelo 1, Área de Seção Transversal do Componente: 0.0117 m2; EI-REV-Pintura Acrílica Cor Branco Gelo 1, Volume Componente (Líquido): 0.0111605 m3; EI-REV-Pintura Acrílica Cor Branco Gelo 1, Volume do componente (Bruto): 0.0212855 m3; EI-REV-Pintura Acrílica Cor Cinza, Massa: 16.7393 kg; EI-REV-Pintura Acrílica Cor Cinza, Área de Componente Projetada (Líquida): 0.858428 m2; EI-REV-Pintura Acrílica Cor Cinza, Área de Componente Projetada (Bruta): 0.858428 m2; EI-REV-Pintura Acrílica Cor Cinza, Altura do Componente Retangular: 0.44 m; EI-REV-Pintura Acrílica Cor Cinza, Largura do Componente Retangular: 0.015 m; EI-REV-Pintura Acrílica Cor Cinza, Área de Seção Transversal do Componente: 0.0066 m2; EI-REV-Pintura Acrílica Cor Cinza, Volume Componente (Líquido): 0.0128764 m3; EI-REV-Pintura Acrílica Cor Cinza, Volume do componente (Bruto): 0.0128764 m3; EI-REV-Pintura Acrílica Cor Branco Gelo 2, Massa: 81.4532 kg; EI-REV-Pintura Acrílica Cor Branco Gelo 2, Área de Componente Projetada (Líquida): 4.17709 m2; EI-REV-Pintura Acrílica Cor Branco Gelo 2, Área de Componente Projetada (Bruta): 5.18959 m2; EI-REV-Pintura Acrílica Cor Branco Gelo 2, Altura do Componente Retangular: 2.66 m; EI-REV-Pintura Acrílica Cor Branco Gelo 2, Largura do Componente Retangular: 0.015 m; EI-REV-Pintura Acrílica Cor Branco Gelo 2, Área de Seção Transversal do Componente: 0.0399 m2; EI-REV-Pintura Acrílica Cor Branco Gelo 2, Volume Componente (Líquido): 0.0626563 m3; EI-REV-Pintura Acrílica Cor Branco Gelo 2, Volume do componente (Bruto): 0.0778438 m3; EI-REV-Massa única - Fachada: 2 with these values

# IfcWall: FNDE-AL14-I5-E1 (vermelha-cinza) 200 x 3100 (2)
In: TÉRREO
Classification: Parede (Classificação Archicad); Material: TIJOLO - CERAMICO 14x19x39 - espessura 20cm, EI-REV-Chapisco (externo), EI-REV-Massa única - Fachada, EI-REV-Massa Acrílica (externa), EI-REV-Chapisco (interno), EI-REV-Cerâmica 30x40, EI-REV-Cerâmica 10x10 Vermelha, EI-REV-Emboço Interno, EI-REV-Massa única - Maior que 10m², EI-REV-Massa Corrida PVA (interna), EI-REV-Pintura Acrílica Cor Branco Gelo (2), EI-REV-Pintura Acrílica Cor Cinza
FNDE - Alvenarias: Alvenaria de Vedação / Edificação; Sistemas de Cobertura: -; Esquadrias - Fechamentos metálicos e Gradis: -; 0_ID: AL14
Pset_WallCommon - IsExternal: yes; LoadBearing: no
Component Quantities - TIJOLO - CERAMICO 14x19x39 - espessura 20cm, Altura do Componente Retangular: 3.1 m; TIJOLO - CERAMICO 14x19x39 - espessura 20cm, Largura do Componente Retangular: 0.14 m; TIJOLO - CERAMICO 14x19x39 - espessura 20cm, Área de Seção Transversal do Componente: 0.434 m2; EI-REV-Chapisco (externo), Altura do Componente Retangular: 3.1 m; EI-REV-Chapisco (externo), Largura do Componente Retangular: 0.005 m; EI-REV-Chapisco (externo), Área de Seção Transversal do Componente: 0.0155 m2; EI-REV-Massa única - Fachada, Altura do Componente Retangular: 3.1 m; EI-REV-Massa única - Fachada, Largura do Componente Retangular: 0.005 m; EI-REV-Massa única - Fachada, Área de Seção Transversal do Componente: 0.0155 m2; EI-REV-Chapisco (interno), Altura do Componente Retangular: 3.1 m; EI-REV-Chapisco (interno), Largura do Componente Retangular: 0.005 m; EI-REV-Chapisco (interno), Área de Seção Transversal do Componente: 0.0155 m2; EI-REV-Cerâmica 30x40, Altura do Componente Retangular: 1.8 m; EI-REV-Cerâmica 30x40, Largura do Componente Retangular: 0.02 m; EI-REV-Cerâmica 30x40, Área de Seção Transversal do Componente: 0.036 m2; EI-REV-Cerâmica 10x10 Vermelha, Altura do Componente Retangular: 0.1 m; EI-REV-Cerâmica 10x10 Vermelha, Largura do Componente Retangular: 0.02 m; EI-REV-Cerâmica 10x10 Vermelha, Área de Seção Transversal do Componente: 0.002 m2; EI-REV-Emboço Interno, Altura do Componente Retangular: 3.1 m; EI-REV-Emboço Interno, Largura do Componente Retangular: 0.005 m; EI-REV-Emboço Interno, Área de Seção Transversal do Componente: 0.0155 m2; EI-REV-Massa única - Maior que 10m², Altura do Componente Retangular: 1.17 m; EI-REV-Massa única - Maior que 10m², Largura do Componente Retangular: 0.00499997 m; EI-REV-Massa única - Maior que 10m², Área de Seção Transversal do Componente: 0.00584996 m2; EI-REV-Massa Corrida PVA (interna), Altura do Componente Retangular: 1.17 m; EI-REV-Massa Corrida PVA (interna), Largura do Componente Retangular: 0.005 m; EI-REV-Massa Corrida PVA (interna), Área de Seção Transversal do Componente: 0.00585001 m2; EI-REV-Pintura Acrílica Cor Branco Gelo 1, Altura do Componente Retangular: 1.17 m; EI-REV-Pintura Acrílica Cor Branco Gelo 1, Largura do Componente Retangular: 0.01 m; EI-REV-Pintura Acrílica Cor Branco Gelo 1, Área de Seção Transversal do Componente: 0.0117 m2; EI-REV-Pintura Acrílica Cor Cinza, Altura do Componente Retangular: 0.44 m; EI-REV-Pintura Acrílica Cor Cinza, Largura do Componente Retangular: 0.015 m; EI-REV-Pintura Acrílica Cor Cinza, Área de Seção Transversal do Componente: 0.0066 m2; EI-REV-Pintura Acrílica Cor Branco Gelo 2, Altura do Componente Retangular: 2.66 m; EI-REV-Pintura Acrílica Cor Branco Gelo 2, Largura do Componente Retangular: 0.015 m; EI-REV-Pintura Acrílica Cor Branco Gelo 2, Área de Seção Transversal do Componente: 0.0399 m2
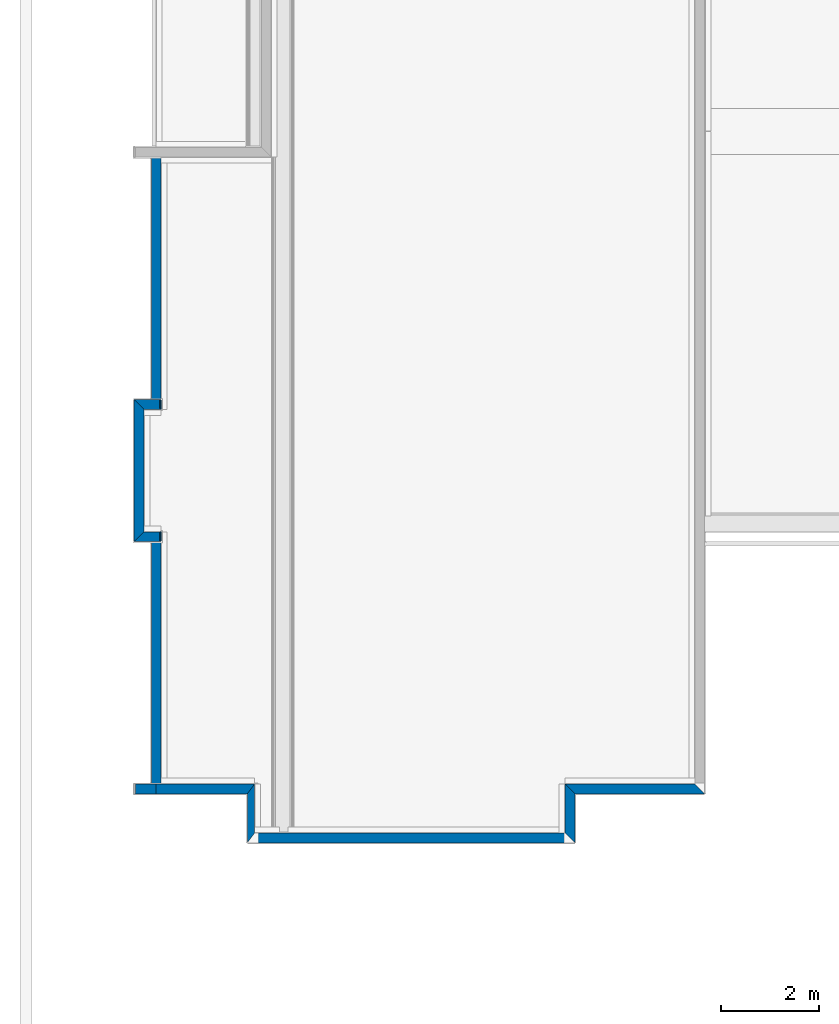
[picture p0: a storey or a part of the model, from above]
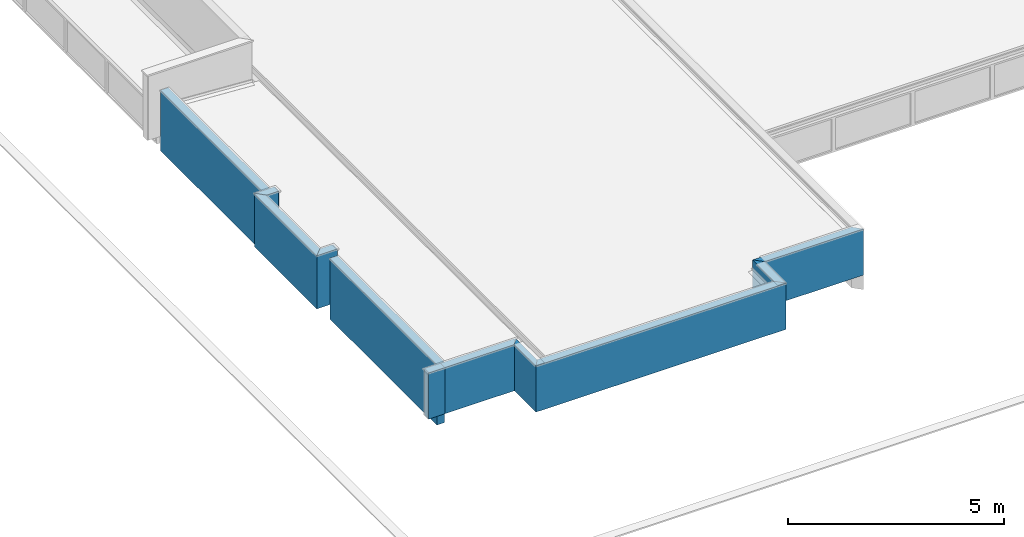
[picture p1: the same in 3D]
Properties of the parts of a building model (IFC4), part 19 of 22

# IfcWall: FNDE-AL14-I5-E1 (vermelha-cinza) 200 x 3100 (2)
Name | 1_Bloco | TIJOLO - CERAMICO 14x19x39 - espessura 20cm, Massa (kg) | TIJOLO - CERAMICO 14x19x39 - espessura 20cm, Área de Componente Projetada (Líquida) (m2) | TIJOLO - CERAMICO 14x19x39 - espessura 20cm, Área de Componente Projetada (Bruta) (m2) | TIJOLO - CERAMICO 14x19x39 - espessura 20cm, Volume Componente (Líquido) (m3) | TIJOLO - CERAMICO 14x19x39 - espessura 20cm, Volume do componente (Bruto) (m3) | EI-REV-Chapisco (externo), Massa (kg) | EI-REV-Chapisco (externo), Área de Componente Projetada (Líquida) (m2) | EI-REV-Chapisco (externo), Área de Componente Projetada (Bruta) (m2) | EI-REV-Chapisco (externo), Volume Componente (Líquido) (m3) | EI-REV-Chapisco (externo), Volume do componente (Bruto) (m3) | EI-REV-Massa única - Fachada, Massa (kg) | EI-REV-Massa única - Fachada, Área de Componente Projetada (Líquida) (m2) | EI-REV-Massa única - Fachada, Área de Componente Projetada (Bruta) (m2) | EI-REV-Massa única - Fachada, Volume Componente (Líquido) (m3) | EI-REV-Massa única - Fachada, Volume do componente (Bruto) (m3) | EI-REV-Chapisco (interno), Massa (kg) | EI-REV-Chapisco (interno), Área de Componente Projetada (Líquida) (m2) | EI-REV-Chapisco (interno), Área de Componente Projetada (Bruta) (m2) | EI-REV-Chapisco (interno), Volume Componente (Líquido) (m3) | EI-REV-Chapisco (interno), Volume do componente (Bruto) (m3) | EI-REV-Cerâmica 30x40, Massa (kg) | EI-REV-Cerâmica 30x40, Área de Componente Projetada (Líquida) (m2) = EI-REV-Cerâmica 30x40, Área de Componente Projetada (Bruta) (m2) | EI-REV-Cerâmica 30x40, Volume Componente (Líquido) (m3) = EI-REV-Cerâmica 30x40, Volume do componente (Bruto) (m3) | EI-REV-Cerâmica 10x10 Vermelha, Massa (kg) | EI-REV-Cerâmica 10x10 Vermelha, Área de Componente Projetada (Líquida) (m2) = EI-REV-Cerâmica 10x10 Vermelha, Área de Componente Projetada (Bruta) (m2) | EI-REV-Cerâmica 10x10 Vermelha, Volume Componente (Líquido) (m3) = EI-REV-Cerâmica 10x10 Vermelha, Volume do componente (Bruto) (m3) | EI-REV-Emboço Interno, Massa (kg) | EI-REV-Emboço Interno, Área de Componente Projetada (Líquida) (m2) | EI-REV-Emboço Interno, Área de Componente Projetada (Bruta) (m2) | EI-REV-Emboço Interno, Volume Componente (Líquido) (m3) | EI-REV-Emboço Interno, Volume do componente (Bruto) (m3) | EI-REV-Massa única - Maior que 10m², Massa (kg) | EI-REV-Massa única - Maior que 10m², Área de Componente Projetada (Líquida) (m2) | EI-REV-Massa única - Maior que 10m², Área de Componente Projetada (Bruta) (m2) | EI-REV-Massa única - Maior que 10m², Volume Componente (Líquido) (m3) | EI-REV-Massa única - Maior que 10m², Volume do componente (Bruto) (m3) | EI-REV-Massa Corrida PVA (interna), Massa (kg) | EI-REV-Massa Corrida PVA (interna), Área de Componente Projetada (Líquida) (m2) | EI-REV-Massa Corrida PVA (interna), Área de Componente Projetada (Bruta) (m2) | EI-REV-Massa Corrida PVA (interna), Volume Componente (Líquido) (m3) | EI-REV-Massa Corrida PVA (interna), Volume do componente (Bruto) (m3) | EI-REV-Pintura Acrílica Cor Branco Gelo 1, Massa (kg) | EI-REV-Pintura Acrílica Cor Branco Gelo 1, Área de Componente Projetada (Líquida) (m2) | EI-REV-Pintura Acrílica Cor Branco Gelo 1, Área de Componente Projetada (Bruta) (m2) | EI-REV-Pintura Acrílica Cor Branco Gelo 1, Volume Componente (Líquido) (m3) | EI-REV-Pintura Acrílica Cor Branco Gelo 1, Volume do componente (Bruto) (m3) | EI-REV-Pintura Acrílica Cor Cinza, Massa (kg) | EI-REV-Pintura Acrílica Cor Cinza, Área de Componente Projetada (Líquida) (m2) = EI-REV-Pintura Acrílica Cor Cinza, Área de Componente Projetada (Bruta) (m2) | EI-REV-Pintura Acrílica Cor Cinza, Volume Componente (Líquido) (m3) = EI-REV-Pintura Acrílica Cor Cinza, Volume do componente (Bruto) (m3) | EI-REV-Pintura Acrílica Cor Branco Gelo 2, Massa (kg) | EI-REV-Pintura Acrílica Cor Branco Gelo 2, Área de Componente Projetada (Líquida) (m2) | EI-REV-Pintura Acrílica Cor Branco Gelo 2, Área de Componente Projetada (Bruta) (m2) | EI-REV-Pintura Acrílica Cor Branco Gelo 2, Volume Componente (Líquido) (m3) | EI-REV-Pintura Acrílica Cor Branco Gelo 2, Volume do componente (Bruto) (m3)
AL14 | BLOCO B | 751.472 | 10.0595 | 10.0595 | 1.15968 | 1.15968 | 65.4862 | 10.0748 | 10.0748 | 0.050374 | 0.050374 | 65.587 | 10.0903 | 10.0903 | 0.0504515 | 0.0504515 | 58.9798 | 9.43502 | 9.43502 | 0.0453691 | 0.0453691 | 218.515 | 5.46289 | 0.109258 | 12.1397 | 0.303494 | 0.00606987 | 61.227 | 9.41952 | 9.41952 | 0.0470977 | 0.0470977 | 23.0409 | 3.5466 | 3.5466 | 0.0177238 | 0.0177238 | 23.0003 | 3.54074 | 3.54074 | 0.0176925 | 0.0176925 | 45.8646 | 3.53104 | 3.53104 | 0.0352805 | 0.0352805 | 28.0989 | 1.44097 | 0.0216146 | 169.871 | 8.71133 | 8.71133 | 0.13067 | 0.13067 | Component Quantities - EI-REV-Massa Acrílica (externa), Massa: 65.6877 kg; EI-REV-Massa Acrílica (externa), Área de Componente Projetada (Líquida): 10.1058 m2; EI-REV-Massa Acrílica (externa), Área de Componente Projetada (Bruta): 10.1058 m2; EI-REV-Massa Acrílica (externa), Altura do Componente Retangular: 3.1 m; EI-REV-Massa Acrílica (externa), Largura do Componente Retangular: 0.005 m; EI-REV-Massa Acrílica (externa), Área de Seção Transversal do Componente: 0.0155 m2; EI-REV-Massa Acrílica (externa), Volume Componente (Líquido): 0.050529 m3; EI-REV-Massa Acrílica (externa), Volume do componente (Bruto): 0.050529 m3
AL14 | BLOCO A | 329.41 | 5.00104 | 6.01354 | 0.508349 | 0.650099 | 32.4664 | 5.0288 | 6.0413 | 0.0249742 | 0.0300367 | 32.6872 | 5.0288 | 6.0413 | 0.025144 | 0.0302065 | 30.8102 | 4.74004 | 5.75254 | 0.0237001 | 0.0287626 | 132.334 | 3.30985 | 0.0661672 | 7.35523 | 0.183881 | 0.00367762 | 30.6218 | 4.71104 | 5.72354 | 0.0235552 | 0.0286177 | 7.36542 | 1.13314 | 2.14564 | 0.0056657 | 0.0107282 | 7.30237 | 1.12344 | 2.13594 | 0.00561721 | 0.0106797 | 14.4786 | 1.11374 | 2.12624 | 0.0111374 | 0.0212624 | 16.7208 | 0.857475 | 0.0128621 | 81.3409 | 4.17133 | 5.18383 | 0.0625699 | 0.0777574 | Component Quantities - EI-REV-Massa única - Fachada: 2 with these values

# IfcWall: FNDE-AL14-I5-E2 (vermelha-cinza) 200 x 3100, AL14
In: TÉRREO
Classification: Parede (Classificação Archicad); Material: TIJOLO - CERAMICO 14x19x39 - espessura 20cm, EI-REV-Chapisco (externo), EI-REV-Massa única - Fachada, EI-REV-Massa Acrílica (externa), EI-REV-Pintura Acrílica Cor Cinza, EI-REV-Chapisco (interno), EI-REV-Cerâmica 30x40, EI-REV-Cerâmica 10x10 Vermelha, EI-REV-Emboço Interno, EI-REV-Massa única - Maior que 10m², EI-REV-Massa Corrida PVA (interna), EI-REV-Pintura Acrílica Cor Branco Gelo
FNDE - Alvenarias: Alvenaria de Vedação / Edificação; Sistemas de Cobertura: -; Esquadrias - Fechamentos metálicos e Gradis: -; 1_Bloco: BLOCO B; 0_ID: AL14
Pset_WallCommon - IsExternal: yes; LoadBearing: no
Component Quantities - TIJOLO - CERAMICO 14x19x39 - espessura 20cm, Massa: 416.619 kg; TIJOLO - CERAMICO 14x19x39 - espessura 20cm, Área de Componente Projetada (Líquida): 6.06782 m2; TIJOLO - CERAMICO 14x19x39 - espessura 20cm, Área de Componente Projetada (Bruta): 8.16782 m2; TIJOLO - CERAMICO 14x19x39 - espessura 20cm, Altura do Componente Retangular: 3.1 m; TIJOLO - CERAMICO 14x19x39 - espessura 20cm, Largura do Componente Retangular: 0.14 m; TIJOLO - CERAMICO 14x19x39 - espessura 20cm, Área de Seção Transversal do Componente: 0.434 m2; TIJOLO - CERAMICO 14x19x39 - espessura 20cm, Volume Componente (Líquido): 0.642931 m3; TIJOLO - CERAMICO 14x19x39 - espessura 20cm, Volume do componente (Bruto): 0.936931 m3; EI-REV-Chapisco (externo), Massa: 39.5911 kg; EI-REV-Chapisco (externo), Área de Componente Projetada (Líquida): 6.11468 m2; EI-REV-Chapisco (externo), Área de Componente Projetada (Bruta): 8.21468 m2; EI-REV-Chapisco (externo), Altura do Componente Retangular: 3.1 m; EI-REV-Chapisco (externo), Largura do Componente Retangular: 0.005 m; EI-REV-Chapisco (externo), Área de Seção Transversal do Componente: 0.0155 m2; EI-REV-Chapisco (externo), Volume Componente (Líquido): 0.0304547 m3; EI-REV-Chapisco (externo), Volume do componente (Bruto): 0.0409547 m3; EI-REV-Massa única - Fachada, Massa: 39.7454 kg; EI-REV-Massa única - Fachada, Área de Componente Projetada (Líquida): 6.11468 m2; EI-REV-Massa única - Fachada, Área de Componente Projetada (Bruta): 8.21468 m2; EI-REV-Massa única - Fachada, Altura do Componente Retangular: 3.1 m; EI-REV-Massa única - Fachada, Largura do Componente Retangular: 0.005 m; EI-REV-Massa única - Fachada, Área de Seção Transversal do Componente: 0.0155 m2; EI-REV-Massa única - Fachada, Volume Componente (Líquido): 0.0305734 m3; EI-REV-Massa única - Fachada, Volume do componente (Bruto): 0.0410734 m3; EI-REV-Pintura Acrílica Cor Cinza, Massa: 119.236 kg; EI-REV-Pintura Acrílica Cor Cinza, Área de Componente Projetada (Líquida): 6.11468 m2; EI-REV-Pintura Acrílica Cor Cinza, Área de Componente Projetada (Bruta): 8.21468 m2; EI-REV-Pintura Acrílica Cor Cinza, Altura do Componente Retangular: 3.1 m; EI-REV-Pintura Acrílica Cor Cinza, Largura do Componente Retangular: 0.015 m; EI-REV-Pintura Acrílica Cor Cinza, Área de Seção Transversal do Componente: 0.0465 m2; EI-REV-Pintura Acrílica Cor Cinza, Volume Componente (Líquido): 0.0917201 m3; EI-REV-Pintura Acrílica Cor Cinza, Volume do componente (Bruto): 0.12322 m3; EI-REV-Chapisco (interno), Massa: 37.8419 kg; EI-REV-Chapisco (interno), Área de Componente Projetada (Líquida): 5.82282 m2; EI-REV-Chapisco (interno), Área de Componente Projetada (Bruta): 7.92282 m2; EI-REV-Chapisco (interno), Altura do Componente Retangular: 3.1 m; EI-REV-Chapisco (interno), Largura do Componente Retangular: 0.005 m; EI-REV-Chapisco (interno), Área de Seção Transversal do Componente: 0.0155 m2; EI-REV-Chapisco (interno), Volume Componente (Líquido): 0.0291091 m3; EI-REV-Chapisco (interno), Volume do componente (Bruto): 0.0396091 m3; EI-REV-Cerâmica 30x40, Massa: 171.824 kg; EI-REV-Cerâmica 30x40, Área de Componente Projetada (Líquida): 4.29561 m2; EI-REV-Cerâmica 30x40, Área de Componente Projetada (Bruta): 4.58961 m2; EI-REV-Cerâmica 30x40, Altura do Componente Retangular: 1.8 m; EI-REV-Cerâmica 30x40, Largura do Componente Retangular: 0.02 m; EI-REV-Cerâmica 30x40, Área de Seção Transversal do Componente: 0.036 m2; EI-REV-Cerâmica 30x40, Volume Componente (Líquido): 0.0859122 m3; EI-REV-Cerâmica 30x40, Volume do componente (Bruto): 0.0917922 m3; EI-REV-Cerâmica 10x10 Vermelha, Massa: 1.79958 kg; EI-REV-Cerâmica 10x10 Vermelha, Área de Componente Projetada (Líquida): 0.0449895 m2; EI-REV-Cerâmica 10x10 Vermelha, Área de Componente Projetada (Bruta): 0.25499 m2; EI-REV-Cerâmica 10x10 Vermelha, Altura do Componente Retangular: 0.1 m; EI-REV-Cerâmica 10x10 Vermelha, Largura do Componente Retangular: 0.02 m; EI-REV-Cerâmica 10x10 Vermelha, Área de Seção Transversal do Componente: 0.002 m2; EI-REV-Cerâmica 10x10 Vermelha, Volume Componente (Líquido): 0.000899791 m3; EI-REV-Cerâmica 10x10 Vermelha, Volume do componente (Bruto): 0.00509979 m3; EI-REV-Emboço Interno, Massa: 37.2553 kg; EI-REV-Emboço Interno, Área de Componente Projetada (Líquida): 5.73157 m2; EI-REV-Emboço Interno, Área de Componente Projetada (Bruta): 7.83157 m2; EI-REV-Emboço Interno, Altura do Componente Retangular: 3.1 m; EI-REV-Emboço Interno, Largura do Componente Retangular: 0.005 m; EI-REV-Emboço Interno, Área de Seção Transversal do Componente: 0.0155 m2; EI-REV-Emboço Interno, Volume Componente (Líquido): 0.0286579 m3; EI-REV-Emboço Interno, Volume do componente (Bruto): 0.0391579 m3; EI-REV-Massa única - Maior que 10m², Massa: 8.90933 kg; EI-REV-Massa única - Maior que 10m², Área de Componente Projetada (Líquida): 1.37067 m2; EI-REV-Massa única - Maior que 10m², Área de Componente Projetada (Bruta): 2.96667 m2; EI-REV-Massa única - Maior que 10m², Altura do Componente Retangular: 1.17 m; EI-REV-Massa única - Maior que 10m², Largura do Componente Retangular: 0.00499997 m; EI-REV-Massa única - Maior que 10m², Área de Seção Transversal do Componente: 0.00584996 m2; EI-REV-Massa única - Maior que 10m², Volume Componente (Líquido): 0.00685333 m3; EI-REV-Massa única - Maior que 10m², Volume do componente (Bruto): 0.0148333 m3; EI-REV-Massa Corrida PVA (interna), Massa: 8.82131 kg; EI-REV-Massa Corrida PVA (interna), Área de Componente Projetada (Líquida): 1.35712 m2; EI-REV-Massa Corrida PVA (interna), Área de Componente Projetada (Bruta): 2.95312 m2; EI-REV-Massa Corrida PVA (interna), Altura do Componente Retangular: 1.17 m; EI-REV-Massa Corrida PVA (interna), Largura do Componente Retangular: 0.005 m; EI-REV-Massa Corrida PVA (interna), Área de Seção Transversal do Componente: 0.00585001 m2; EI-REV-Massa Corrida PVA (interna), Volume Componente (Líquido): 0.00678562 m3; EI-REV-Massa Corrida PVA (interna), Volume do componente (Bruto): 0.0147656 m3; EI-REV-Pintura Acrílica Cor Branco Gelo, Massa: 17.5777 kg; EI-REV-Pintura Acrílica Cor Branco Gelo, Área de Componente Projetada (Líquida): 1.35213 m2; EI-REV-Pintura Acrílica Cor Branco Gelo, Área de Componente Projetada (Bruta): 2.94813 m2; EI-REV-Pintura Acrílica Cor Branco Gelo, Altura do Componente Retangular: 1.17 m; EI-REV-Pintura Acrílica Cor Branco Gelo, Largura do Componente Retangular: 0.01 m; EI-REV-Pintura Acrílica Cor Branco Gelo, Área de Seção Transversal do Componente: 0.0117 m2; EI-REV-Pintura Acrílica Cor Branco Gelo, Volume Componente (Líquido): 0.0135213 m3; EI-REV-Pintura Acrílica Cor Branco Gelo, Volume do componente (Bruto): 0.0294813 m3; EI-REV-Massa única - Fachada: 2 with these values

# IfcWall: FNDE-AL14-I6-E3 (30x40-azul) 200 x 3100 (10)
In: TÉRREO
Classification: Parede (Classificação Archicad); Material: TIJOLO - CERAMICO 14x19x39 - espessura 20cm, EI-REV-Chapisco (externo), EI-REV-Massa única - Fachada, EI-REV-Massa Acrílica (externa), EI-REV-Pintura Acrílica Cor Azul Externa, EI-REV-Chapisco (interno), EI-REV-Cerâmica 30x40 h=1,50, EI-REV-Emboço Interno, EI-REV-Massa única - Maior que 10m², EI-REV-Massa Corrida PVA (interna), EI-REV-Pintura Acrílica Cor Branco Gelo
FNDE - Alvenarias: Alvenaria de Vedação / Edificação; Sistemas de Cobertura: -; Esquadrias - Fechamentos metálicos e Gradis: -; 0_ID: AL14
Pset_WallCommon - IsExternal: yes; LoadBearing: no
Component Quantities - TIJOLO - CERAMICO 14x19x39 - espessura 20cm, Altura do Componente Retangular: 3.1 m; TIJOLO - CERAMICO 14x19x39 - espessura 20cm, Largura do Componente Retangular: 0.14 m; TIJOLO - CERAMICO 14x19x39 - espessura 20cm, Área de Seção Transversal do Componente: 0.434 m2; EI-REV-Chapisco (externo), Altura do Componente Retangular: 3.1 m; EI-REV-Chapisco (externo), Largura do Componente Retangular: 0.005 m; EI-REV-Chapisco (externo), Área de Seção Transversal do Componente: 0.0155 m2; EI-REV-Massa única - Fachada, Altura do Componente Retangular: 3.1 m; EI-REV-Massa única - Fachada, Largura do Componente Retangular: 0.005 m; EI-REV-Massa única - Fachada, Área de Seção Transversal do Componente: 0.0155 m2; EI-REV-Massa Acrílica (externa), Altura do Componente Retangular: 3.1 m; EI-REV-Massa Acrílica (externa), Largura do Componente Retangular: 0.005 m; EI-REV-Massa Acrílica (externa), Área de Seção Transversal do Componente: 0.0155 m2; EI-REV-Pintura Acrílica Cor Azul Externa, Altura do Componente Retangular: 3.1 m; EI-REV-Pintura Acrílica Cor Azul Externa, Largura do Componente Retangular: 0.015 m; EI-REV-Pintura Acrílica Cor Azul Externa, Área de Seção Transversal do Componente: 0.0465 m2; EI-REV-Chapisco (interno), Altura do Componente Retangular: 3.1 m; EI-REV-Chapisco (interno), Largura do Componente Retangular: 0.005 m; EI-REV-Chapisco (interno), Área de Seção Transversal do Componente: 0.0155 m2; EI-REV-Cerâmica 30x40 h=1,50, Altura do Componente Retangular: 1.52 m; EI-REV-Cerâmica 30x40 h=1,50, Largura do Componente Retangular: 0.02 m; EI-REV-Cerâmica 30x40 h=1,50, Área de Seção Transversal do Componente: 0.0304 m2; EI-REV-Emboço Interno, Altura do Componente Retangular: 3.1 m; EI-REV-Emboço Interno, Largura do Componente Retangular: 0.005 m; EI-REV-Emboço Interno, Área de Seção Transversal do Componente: 0.0155 m2; EI-REV-Massa única - Maior que 10m², Altura do Componente Retangular: 1.58 m; EI-REV-Massa única - Maior que 10m², Largura do Componente Retangular: 0.00499999 m; EI-REV-Massa única - Maior que 10m², Área de Seção Transversal do Componente: 0.00789998 m2; EI-REV-Massa Corrida PVA (interna), Altura do Componente Retangular: 1.58 m; EI-REV-Massa Corrida PVA (interna), Largura do Componente Retangular: 0.00500001 m; EI-REV-Massa Corrida PVA (interna), Área de Seção Transversal do Componente: 0.00790001 m2; EI-REV-Pintura Acrílica Cor Branco Gelo, Altura do Componente Retangular: 1.58 m; EI-REV-Pintura Acrílica Cor Branco Gelo, Largura do Componente Retangular: 0.01 m; EI-REV-Pintura Acrílica Cor Branco Gelo, Área de Seção Transversal do Componente: 0.0158 m2
Name | 1_Bloco | TIJOLO - CERAMICO 14x19x39 - espessura 20cm, Massa (kg) | TIJOLO - CERAMICO 14x19x39 - espessura 20cm, Área de Componente Projetada (Líquida) (m2) = TIJOLO - CERAMICO 14x19x39 - espessura 20cm, Área de Componente Projetada (Bruta) (m2) | TIJOLO - CERAMICO 14x19x39 - espessura 20cm, Volume Componente (Líquido) (m3) = TIJOLO - CERAMICO 14x19x39 - espessura 20cm, Volume do componente (Bruto) (m3) | EI-REV-Chapisco (externo), Massa (kg) | EI-REV-Chapisco (externo), Área de Componente Projetada (Líquida) (m2) = EI-REV-Chapisco (externo), Área de Componente Projetada (Bruta) (m2) | EI-REV-Chapisco (externo), Volume Componente (Líquido) (m3) = EI-REV-Chapisco (externo), Volume do componente (Bruto) (m3) | EI-REV-Massa única - Fachada, Massa (kg) | EI-REV-Massa única - Fachada, Área de Componente Projetada (Líquida) (m2) = EI-REV-Massa única - Fachada, Área de Componente Projetada (Bruta) (m2) | EI-REV-Massa única - Fachada, Volume Componente (Líquido) (m3) = EI-REV-Massa única - Fachada, Volume do componente (Bruto) (m3) | EI-REV-Massa Acrílica (externa), Massa (kg) | EI-REV-Massa Acrílica (externa), Área de Componente Projetada (Líquida) (m2) = EI-REV-Massa Acrílica (externa), Área de Componente Projetada (Bruta) (m2) | EI-REV-Massa Acrílica (externa), Volume Componente (Líquido) (m3) = EI-REV-Massa Acrílica (externa), Volume do componente (Bruto) (m3) | EI-REV-Pintura Acrílica Cor Azul Externa, Massa (kg) | EI-REV-Pintura Acrílica Cor Azul Externa, Área de Componente Projetada (Líquida) (m2) = EI-REV-Pintura Acrílica Cor Azul Externa, Área de Componente Projetada (Bruta) (m2) | EI-REV-Pintura Acrílica Cor Azul Externa, Volume Componente (Líquido) (m3) = EI-REV-Pintura Acrílica Cor Azul Externa, Volume do componente (Bruto) (m3) | EI-REV-Chapisco (interno), Massa (kg) | EI-REV-Chapisco (interno), Área de Componente Projetada (Líquida) (m2) = EI-REV-Chapisco (interno), Área de Componente Projetada (Bruta) (m2) | EI-REV-Chapisco (interno), Volume Componente (Líquido) (m3) = EI-REV-Chapisco (interno), Volume do componente (Bruto) (m3) | EI-REV-Cerâmica 30x40 h=1,50, Massa (kg) | EI-REV-Cerâmica 30x40 h=1,50, Área de Componente Projetada (Líquida) (m2) = EI-REV-Cerâmica 30x40 h=1,50, Área de Componente Projetada (Bruta) (m2) | EI-REV-Cerâmica 30x40 h=1,50, Volume Componente (Líquido) (m3) = EI-REV-Cerâmica 30x40 h=1,50, Volume do componente (Bruto) (m3) | EI-REV-Emboço Interno, Massa (kg) | EI-REV-Emboço Interno, Área de Componente Projetada (Líquida) (m2) = EI-REV-Emboço Interno, Área de Componente Projetada (Bruta) (m2) | EI-REV-Emboço Interno, Volume Componente (Líquido) (m3) = EI-REV-Emboço Interno, Volume do componente (Bruto) (m3) | EI-REV-Massa única - Maior que 10m², Massa (kg) | EI-REV-Massa única - Maior que 10m², Área de Componente Projetada (Líquida) (m2) = EI-REV-Massa única - Maior que 10m², Área de Componente Projetada (Bruta) (m2) | EI-REV-Massa única - Maior que 10m², Volume Componente (Líquido) (m3) = EI-REV-Massa única - Maior que 10m², Volume do componente (Bruto) (m3) | EI-REV-Massa Corrida PVA (interna), Massa (kg) | EI-REV-Massa Corrida PVA (interna), Área de Componente Projetada (Líquida) (m2) = EI-REV-Massa Corrida PVA (interna), Área de Componente Projetada (Bruta) (m2) | EI-REV-Massa Corrida PVA (interna), Volume Componente (Líquido) (m3) = EI-REV-Massa Corrida PVA (interna), Volume do componente (Bruto) (m3) | EI-REV-Pintura Acrílica Cor Branco Gelo, Massa (kg) | EI-REV-Pintura Acrílica Cor Branco Gelo, Área de Componente Projetada (Líquida) (m2) = EI-REV-Pintura Acrílica Cor Branco Gelo, Área de Componente Projetada (Bruta) (m2) | EI-REV-Pintura Acrílica Cor Branco Gelo, Volume Componente (Líquido) (m3) = EI-REV-Pintura Acrílica Cor Branco Gelo, Volume do componente (Bruto) (m3)
AL14 | BLOCO B | 115.658 | 1.27489 | 0.178485 | 8.38371 | 1.2898 | 0.00644901 | 8.49019 | 1.3053 | 0.00653092 | 15.1931 | 2.3374 | 0.011687 | 46.2658 | 2.3779 | 0.0355891 | 5.67589 | 0.873214 | 0.00436607 | 28.5815 | 0.942352 | 0.0142907 | 5.58814 | 0.859714 | 0.00429857 | 2.3391 | 0.359862 | 0.00179931 | 2.25966 | 0.348062 | 0.0017382 | 11.9739 | 0.92084 | 0.00921068
AL14 | BLOCO B | 125.709 | 2.31951 | 0.193995 | 8.38385 | 1.28982 | 0.00644912 | 8.4846 | 1.30532 | 0.00652662 | 8.58535 | 1.32082 | 0.00660412 | 46.6043 | 2.39162 | 0.0358495 | 12.3443 | 1.89912 | 0.00949561 | 36.9505 | 0.923763 | 0.0184753 | 12.2565 | 1.88562 | 0.00942811 | 6.16491 | 0.948451 | 0.00474224 | 6.07524 | 0.934651 | 0.00467326 | 11.9711 | 0.920851 | 0.00920851
AL14 | BLOCO B | 115.795 | 1.2764 | 0.178697 | 8.38522 | 1.29003 | 0.00645017 | 8.4798 | 1.30458 | 0.00652292 | 8.57437 | 1.31913 | 0.00659567 | 46.6045 | 2.41962 | 0.0358496 | 5.67602 | 0.873233 | 0.00436617 | 33.1565 | 0.942363 | 0.0165782 | 5.58827 | 0.859733 | 0.00429867 | 2.35782 | 0.955861 | 0.00181371 | 6.11041 | 0.940061 | 0.00470031 | 12.0154 | 0.924261 | 0.00924261
AL14 | BLOCO B | 115.793 | 1.27638 | 0.178693 | 8.38431 | 1.28989 | 0.00644947 | 8.48535 | 1.30439 | 0.0065272 | 15.1931 | 2.3374 | 0.011687 | 46.2658 | 2.3779 | 0.0355891 | 5.67589 | 0.873214 | 0.00436607 | 28.5816 | 0.942352 | 0.0142908 | 5.58814 | 0.859714 | 0.00429857 | 2.3391 | 0.359862 | 0.00179931 | 2.25959 | 0.348062 | 0.00173815 | 12.0152 | 0.92425 | 0.0092425
AL14 | BLOCO B | 629.52 | 7.9359 | 0.971482 | 57.2253 | 8.8039 | 0.0440195 | 57.4268 | 8.8349 | 0.0441745 | 57.6283 | 8.8659 | 0.0443295 | 173.49 | 8.8969 | 0.133453 | 45.9697 | 7.82471 | 0.0353613 | 145.566 | 3.63915 | 0.072783 | 50.3349 | 7.78991 | 0.0387192 | 25.9697 | 3.99535 | 0.0199767 | 25.8801 | 3.98155 | 0.0199078 | 51.3493 | 3.94995 | 0.0394995
AL14 | BLOCO B | 627.049 | 6.91191 | 0.967668 | 55.0471 | 8.8039 | 0.0423439 | 57.4268 | 8.8349 | 0.0441745 | 57.6283 | 8.8659 | 0.0443295 | 173.49 | 8.8969 | 0.133453 | 44.2956 | 6.81471 | 0.0340736 | 145.566 | 3.63915 | 0.072783 | 43.7675 | 6.77991 | 0.0336673 | 19.4048 | 2.98536 | 0.0149268 | 19.3282 | 2.97357 | 0.0148679 | 40.267 | 3.94995 | 0.0309746
AL14 | BLOCO A | 627.073 | 6.91218 | 0.967706 | 49.8432 | 7.66818 | 0.0383409 | 50.0187 | 7.69518 | 0.0384759 | 50.151 | 7.72496 | 0.0385777 | 173.491 | 8.89721 | 0.133454 | 43.8632 | 6.74818 | 0.0337409 | 148.587 | 3.7197 | 0.0742934 | 43.7618 | 6.73258 | 0.0336629 | 19.4898 | 2.99728 | 0.0149922 | 25.9713 | 3.99721 | 0.0199779 | 51.3151 | 3.95011 | 0.0394731
AL14 | BLOCO A | 115.694 | 1.27529 | 0.178541 | 8.37713 | 1.28879 | 0.00644395 | 8.16257 | 1.25578 | 0.0062789 | 8.16262 | 1.25579 | 0.00627894 | 43.4927 | 2.28003 | 0.0334559 | 5.6783 | 0.873584 | 0.00436792 | 33.7865 | 0.942562 | 0.0168932 | 5.59055 | 0.860084 | 0.00430042 | 2.91602 | 0.956063 | 0.00224309 | 6.11175 | 0.940268 | 0.00470135 | 12.0181 | 0.924468 | 0.00924468
AL14 | BLOCO A | 81.4021 | 0.897309 | 0.125621 | 8.28944 | 1.2753 | 0.00637649 | 8.07496 | 1.2423 | 0.00621151 | 8.92837 | 2.28833 | 0.00686798 | 44.6224 | 2.28833 | 0.034325 | 5.74462 | 0.883787 | 0.00441894 | 31.3661 | 0.91216 | 0.015683 | 5.65687 | 0.870287 | 0.00435144 | 2.45587 | 0.377828 | 0.00188913 | 5.78373 | 0.963968 | 0.00444903 | 12.3226 | 0.948168 | 0.0094789
AL14 | BLOCO A | 661.342 | 7.28992 | 1.02059 | 49.9292 | 7.68142 | 0.0384071 | 50.1047 | 7.70842 | 0.0385421 | 50.2821 | 7.73571 | 0.0386785 | 152.466 | 8.94341 | 0.117281 | 51.0215 | 7.91042 | 0.0392473 | 153.214 | 3.83036 | 0.0766071 | 51.2422 | 7.88342 | 0.0394171 | 26.0192 | 4.00297 | 0.0200148 | 25.9296 | 3.98917 | 0.0199459 | 51.5548 | 3.96575 | 0.0396575

# IfcWall: FNDE-AL14-I7 (amarela) 170 x 3100 (3)
In: TÉRREO
Classification: Parede (Classificação Archicad); Material: TIJOLO - CERAMICO 14x19x39 - espessura 20cm, EI-REV-Chapisco (interno), EI-REV-Cerâmica 10x10 Amarela, EI-REV-Cerâmica 10x10 Branca, EI-REV-Emboço Interno, EI-REV-Massa única - Maior que 10m², EI-REV-Massa Corrida PVA (interna), EI-REV-Pintura Acrílica Cor Branco Gelo
FNDE - Alvenarias: Alvenaria de Vedação / Edificação; Sistemas de Cobertura: -; Esquadrias - Fechamentos metálicos e Gradis: -; 0_ID: AL14
Pset_WallCommon - IsExternal: yes; LoadBearing: no
Component Quantities - TIJOLO - CERAMICO 14x19x39 - espessura 20cm, Altura do Componente Retangular: 3.1 m; TIJOLO - CERAMICO 14x19x39 - espessura 20cm, Largura do Componente Retangular: 0.14 m; TIJOLO - CERAMICO 14x19x39 - espessura 20cm, Área de Seção Transversal do Componente: 0.434 m2; EI-REV-Chapisco (interno), Altura do Componente Retangular: 3.1 m; EI-REV-Chapisco (interno), Largura do Componente Retangular: 0.005 m; EI-REV-Chapisco (interno), Área de Seção Transversal do Componente: 0.0155 m2; EI-REV-Cerâmica 10x10 Amarela, Altura do Componente Retangular: 0.9 m; EI-REV-Cerâmica 10x10 Amarela, Largura do Componente Retangular: 0.02 m; EI-REV-Cerâmica 10x10 Amarela, Área de Seção Transversal do Componente: 0.018 m2; EI-REV-Cerâmica 10x10 Branca, Altura do Componente Retangular: 0.1 m; EI-REV-Cerâmica 10x10 Branca, Largura do Componente Retangular: 0.02 m; EI-REV-Cerâmica 10x10 Branca, Área de Seção Transversal do Componente: 0.002 m2; EI-REV-Emboço Interno, Área de Seção Transversal do Componente: 0.0155 m2; EI-REV-Massa única - Maior que 10m², Altura do Componente Retangular: 2.06 m; EI-REV-Massa única - Maior que 10m², Largura do Componente Retangular: 0.00500002 m; EI-REV-Massa única - Maior que 10m², Área de Seção Transversal do Componente: 0.0103 m2; EI-REV-Massa Corrida PVA (interna), Altura do Componente Retangular: 2.06 m; EI-REV-Massa Corrida PVA (interna), Largura do Componente Retangular: 0.00499999 m; EI-REV-Massa Corrida PVA (interna), Área de Seção Transversal do Componente: 0.0103 m2; EI-REV-Pintura Acrílica Cor Branco Gelo, Altura do Componente Retangular: 2.06 m; EI-REV-Pintura Acrílica Cor Branco Gelo, Largura do Componente Retangular: 0.01 m; EI-REV-Pintura Acrílica Cor Branco Gelo, Área de Seção Transversal do Componente: 0.0206 m2
Name | 1_Bloco | TIJOLO - CERAMICO 14x19x39 - espessura 20cm, Massa (kg) | TIJOLO - CERAMICO 14x19x39 - espessura 20cm, Área de Componente Projetada (Líquida) (m2) = TIJOLO - CERAMICO 14x19x39 - espessura 20cm, Área de Componente Projetada (Bruta) (m2) | TIJOLO - CERAMICO 14x19x39 - espessura 20cm, Volume Componente (Líquido) (m3) = TIJOLO - CERAMICO 14x19x39 - espessura 20cm, Volume do componente (Bruto) (m3) | EI-REV-Chapisco (interno), Massa (kg) | EI-REV-Chapisco (interno), Área de Componente Projetada (Líquida) (m2) = EI-REV-Chapisco (interno), Área de Componente Projetada (Bruta) (m2) | EI-REV-Chapisco (interno), Volume Componente (Líquido) (m3) = EI-REV-Chapisco (interno), Volume do componente (Bruto) (m3) | EI-REV-Cerâmica 10x10 Amarela, Massa (kg) | EI-REV-Cerâmica 10x10 Amarela, Área de Componente Projetada (Líquida) (m2) = EI-REV-Cerâmica 10x10 Amarela, Área de Componente Projetada (Bruta) (m2) | EI-REV-Cerâmica 10x10 Amarela, Volume Componente (Líquido) (m3) = EI-REV-Cerâmica 10x10 Amarela, Volume do componente (Bruto) (m3) | EI-REV-Cerâmica 10x10 Branca, Massa (kg) | EI-REV-Cerâmica 10x10 Branca, Área de Componente Projetada (Líquida) (m2) = EI-REV-Cerâmica 10x10 Branca, Área de Componente Projetada (Bruta) (m2) | EI-REV-Cerâmica 10x10 Branca, Volume Componente (Líquido) (m3) = EI-REV-Cerâmica 10x10 Branca, Volume do componente (Bruto) (m3) | EI-REV-Emboço Interno, Massa (kg) | EI-REV-Emboço Interno, Área de Componente Projetada (Líquida) (m2) = EI-REV-Emboço Interno, Área de Componente Projetada (Bruta) (m2) | EI-REV-Emboço Interno, Volume Componente (Líquido) (m3) = EI-REV-Emboço Interno, Volume do componente (Bruto) (m3) | EI-REV-Massa única - Maior que 10m², Massa (kg) | EI-REV-Massa única - Maior que 10m², Área de Componente Projetada (Líquida) (m2) = EI-REV-Massa única - Maior que 10m², Área de Componente Projetada (Bruta) (m2) | EI-REV-Massa única - Maior que 10m², Volume Componente (Líquido) (m3) = EI-REV-Massa única - Maior que 10m², Volume do componente (Bruto) (m3) | EI-REV-Massa Corrida PVA (interna), Massa (kg) | EI-REV-Massa Corrida PVA (interna), Área de Componente Projetada (Líquida) (m2) = EI-REV-Massa Corrida PVA (interna), Área de Componente Projetada (Bruta) (m2) | EI-REV-Massa Corrida PVA (interna), Volume Componente (Líquido) (m3) = EI-REV-Massa Corrida PVA (interna), Volume do componente (Bruto) (m3) | EI-REV-Pintura Acrílica Cor Branco Gelo, Massa (kg) | EI-REV-Pintura Acrílica Cor Branco Gelo, Área de Componente Projetada (Líquida) (m2) = EI-REV-Pintura Acrílica Cor Branco Gelo, Área de Componente Projetada (Bruta) (m2) | EI-REV-Pintura Acrílica Cor Branco Gelo, Volume Componente (Líquido) (m3) = EI-REV-Pintura Acrílica Cor Branco Gelo, Volume do componente (Bruto) (m3)
AL14 | BLOCO A | 42.9298 | 0.769019 | 0.0662496 | 5.01162 | 0.771019 | 0.00385509 | 9.00001 | 0.225 | 0.00450001 | 1 | 0.025 | 0.000500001 | 4.92387 | 0.757519 | 0.00378759 | 3.21362 | 0.494401 | 0.00247201 | 3.14665 | 0.484101 | 0.0024205 | 6.15941 | 0.473801 | 0.00473801
AL14 | BLOCO B | 116.912 | 1.28872 | 0.18042 | 10.1901 | 1.56772 | 0.00783858 | 19.0767 | 0.476918 | 0.00953837 | 2.11964 | 0.0529909 | 0.00105982 | 10.2909 | 1.58322 | 0.00791607 | 6.64639 | 1.02252 | 0.00511261 | 7.29072 | 1.12251 | 0.00560824 | 14.4588 | 1.11221 | 0.0111221
AL14 | BLOCO A | 37.3555 | 0.411766 | 0.0576473 | 4.25598 | 0.654766 | 0.00327383 | 16.6093 | 0.477152 | 0.00830463 | 1.84547 | 0.0530169 | 0.000922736 | 4.34373 | 0.668266 | 0.00334133 | 2.7633 | 1.09215 | 0.00212561 | 7.1659 | 1.10245 | 0.00551223 | 14.4565 | 1.11275 | 0.0111204

# IfcWall: FNDE-AL14-I7-E1 (amarela-cinza) 200 x 3100 (4)
In: TÉRREO
Classification: Parede (Classificação Archicad); Material: TIJOLO - CERAMICO 14x19x39 - espessura 20cm, EI-REV-Chapisco (externo), EI-REV-Pintura Acrílica Cor Cinza, EI-REV-Massa única - Fachada, EI-REV-Massa Acrílica (externa), EI-REV-Pintura Acrílica Cor Branco Gelo (2), EI-REV-Chapisco (interno), EI-REV-Cerâmica 10x10 Amarela, EI-REV-Cerâmica 10x10 Branca, EI-REV-Emboço Interno, EI-REV-Massa única - Maior que 10m², EI-REV-Massa Corrida PVA (interna)
FNDE - Alvenarias: Alvenaria de Vedação / Edificação; Sistemas de Cobertura: -; Esquadrias - Fechamentos metálicos e Gradis: -; 0_ID: AL14
Pset_WallCommon - IsExternal: yes; LoadBearing: no
Component Quantities - TIJOLO - CERAMICO 14x19x39 - espessura 20cm, Altura do Componente Retangular: 3.1 m; TIJOLO - CERAMICO 14x19x39 - espessura 20cm, Largura do Componente Retangular: 0.14 m; TIJOLO - CERAMICO 14x19x39 - espessura 20cm, Área de Seção Transversal do Componente: 0.434 m2; EI-REV-Chapisco (externo), Altura do Componente Retangular: 3.1 m; EI-REV-Chapisco (externo), Largura do Componente Retangular: 0.005 m; EI-REV-Chapisco (externo), Área de Seção Transversal do Componente: 0.0155 m2; EI-REV-Pintura Acrílica Cor Cinza, Altura do Componente Retangular: 0.44 m; EI-REV-Pintura Acrílica Cor Cinza, Largura do Componente Retangular: 0.015 m; EI-REV-Pintura Acrílica Cor Cinza, Área de Seção Transversal do Componente: 0.0066 m2; EI-REV-Pintura Acrílica Cor Branco Gelo 1, Altura do Componente Retangular: 2.66 m; EI-REV-Pintura Acrílica Cor Branco Gelo 1, Largura do Componente Retangular: 0.015 m; EI-REV-Pintura Acrílica Cor Branco Gelo 1, Área de Seção Transversal do Componente: 0.0399 m2; EI-REV-Chapisco (interno), Altura do Componente Retangular: 3.1 m; EI-REV-Chapisco (interno), Largura do Componente Retangular: 0.005 m; EI-REV-Chapisco (interno), Área de Seção Transversal do Componente: 0.0155 m2; EI-REV-Cerâmica 10x10 Amarela, Altura do Componente Retangular: 0.9 m; EI-REV-Cerâmica 10x10 Amarela, Largura do Componente Retangular: 0.02 m; EI-REV-Cerâmica 10x10 Amarela, Área de Seção Transversal do Componente: 0.018 m2; EI-REV-Cerâmica 10x10 Branca, Altura do Componente Retangular: 0.1 m; EI-REV-Cerâmica 10x10 Branca, Largura do Componente Retangular: 0.02 m; EI-REV-Cerâmica 10x10 Branca, Área de Seção Transversal do Componente: 0.002 m2; EI-REV-Emboço Interno, Área de Seção Transversal do Componente: 0.0155 m2; EI-REV-Massa única - Maior que 10m², Altura do Componente Retangular: 2.06 m; EI-REV-Massa única - Maior que 10m², Largura do Componente Retangular: 0.00500002 m; EI-REV-Massa única - Maior que 10m², Área de Seção Transversal do Componente: 0.0103 m2; EI-REV-Massa Corrida PVA (interna), Altura do Componente Retangular: 2.06 m; EI-REV-Massa Corrida PVA (interna), Largura do Componente Retangular: 0.00499999 m; EI-REV-Massa Corrida PVA (interna), Área de Seção Transversal do Componente: 0.0103 m2; EI-REV-Pintura Acrílica Cor Branco Gelo 2, Altura do Componente Retangular: 2.06 m; EI-REV-Pintura Acrílica Cor Branco Gelo 2, Largura do Componente Retangular: 0.01 m; EI-REV-Pintura Acrílica Cor Branco Gelo 2, Área de Seção Transversal do Componente: 0.0206 m2
Name | 1_Bloco | TIJOLO - CERAMICO 14x19x39 - espessura 20cm, Massa (kg) | TIJOLO - CERAMICO 14x19x39 - espessura 20cm, Área de Componente Projetada (Líquida) (m2) = TIJOLO - CERAMICO 14x19x39 - espessura 20cm, Área de Componente Projetada (Bruta) (m2) | TIJOLO - CERAMICO 14x19x39 - espessura 20cm, Volume Componente (Líquido) (m3) = TIJOLO - CERAMICO 14x19x39 - espessura 20cm, Volume do componente (Bruto) (m3) | EI-REV-Chapisco (externo), Massa (kg) | EI-REV-Chapisco (externo), Área de Componente Projetada (Líquida) (m2) = EI-REV-Chapisco (externo), Área de Componente Projetada (Bruta) (m2) | EI-REV-Chapisco (externo), Volume Componente (Líquido) (m3) = EI-REV-Chapisco (externo), Volume do componente (Bruto) (m3) | EI-REV-Pintura Acrílica Cor Cinza, Massa (kg) | EI-REV-Pintura Acrílica Cor Cinza, Área de Componente Projetada (Líquida) (m2) = EI-REV-Pintura Acrílica Cor Cinza, Área de Componente Projetada (Bruta) (m2) | EI-REV-Pintura Acrílica Cor Cinza, Volume Componente (Líquido) (m3) = EI-REV-Pintura Acrílica Cor Cinza, Volume do componente (Bruto) (m3) | EI-REV-Pintura Acrílica Cor Branco Gelo 1, Massa (kg) | EI-REV-Pintura Acrílica Cor Branco Gelo 1, Área de Componente Projetada (Líquida) (m2) = EI-REV-Pintura Acrílica Cor Branco Gelo 1, Área de Componente Projetada (Bruta) (m2) | EI-REV-Pintura Acrílica Cor Branco Gelo 1, Volume Componente (Líquido) (m3) = EI-REV-Pintura Acrílica Cor Branco Gelo 1, Volume do componente (Bruto) (m3) | EI-REV-Chapisco (interno), Massa (kg) | EI-REV-Chapisco (interno), Área de Componente Projetada (Líquida) (m2) = EI-REV-Chapisco (interno), Área de Componente Projetada (Bruta) (m2) | EI-REV-Chapisco (interno), Volume Componente (Líquido) (m3) = EI-REV-Chapisco (interno), Volume do componente (Bruto) (m3) | EI-REV-Cerâmica 10x10 Amarela, Massa (kg) | EI-REV-Cerâmica 10x10 Amarela, Área de Componente Projetada (Líquida) (m2) = EI-REV-Cerâmica 10x10 Amarela, Área de Componente Projetada (Bruta) (m2) | EI-REV-Cerâmica 10x10 Amarela, Volume Componente (Líquido) (m3) = EI-REV-Cerâmica 10x10 Amarela, Volume do componente (Bruto) (m3) | EI-REV-Cerâmica 10x10 Branca, Massa (kg) | EI-REV-Cerâmica 10x10 Branca, Área de Componente Projetada (Líquida) (m2) = EI-REV-Cerâmica 10x10 Branca, Área de Componente Projetada (Bruta) (m2) | EI-REV-Cerâmica 10x10 Branca, Volume Componente (Líquido) (m3) = EI-REV-Cerâmica 10x10 Branca, Volume do componente (Bruto) (m3) | EI-REV-Emboço Interno, Massa (kg) | EI-REV-Emboço Interno, Área de Componente Projetada (Líquida) (m2) = EI-REV-Emboço Interno, Área de Componente Projetada (Bruta) (m2) | EI-REV-Emboço Interno, Volume Componente (Líquido) (m3) = EI-REV-Emboço Interno, Volume do componente (Bruto) (m3) | EI-REV-Massa única - Maior que 10m², Massa (kg) | EI-REV-Massa única - Maior que 10m², Área de Componente Projetada (Líquida) (m2) = EI-REV-Massa única - Maior que 10m², Área de Componente Projetada (Bruta) (m2) | EI-REV-Massa única - Maior que 10m², Volume Componente (Líquido) (m3) = EI-REV-Massa única - Maior que 10m², Volume do componente (Bruto) (m3) | EI-REV-Massa Corrida PVA (interna), Massa (kg) | EI-REV-Massa Corrida PVA (interna), Área de Componente Projetada (Líquida) (m2) = EI-REV-Massa Corrida PVA (interna), Área de Componente Projetada (Bruta) (m2) | EI-REV-Massa Corrida PVA (interna), Volume Componente (Líquido) (m3) = EI-REV-Massa Corrida PVA (interna), Volume do componente (Bruto) (m3) | EI-REV-Pintura Acrílica Cor Branco Gelo 2, Massa (kg) | EI-REV-Pintura Acrílica Cor Branco Gelo 2, Área de Componente Projetada (Líquida) (m2) = EI-REV-Pintura Acrílica Cor Branco Gelo 2, Área de Componente Projetada (Bruta) (m2) | EI-REV-Pintura Acrílica Cor Branco Gelo 2, Volume Componente (Líquido) (m3) = EI-REV-Pintura Acrílica Cor Branco Gelo 2, Volume do componente (Bruto) (m3) | EI-REV-Massa Acrílica (externa), Massa (kg) | EI-REV-Massa Acrílica (externa), Área de Componente Projetada (Líquida) (m2) = EI-REV-Massa Acrílica (externa), Área de Componente Projetada (Bruta) (m2) | EI-REV-Massa Acrílica (externa), Altura do Componente Retangular (m) | EI-REV-Massa Acrílica (externa), Largura do Componente Retangular (m) | EI-REV-Massa Acrílica (externa), Área de Seção Transversal do Componente (m2) | EI-REV-Massa Acrílica (externa), Volume Componente (Líquido) (m3) = EI-REV-Massa Acrílica (externa), Volume do componente (Bruto) (m3)
AL14 | BLOCO B | 450.083 | 5.85838 | 0.694572 | 38.0795 | 5.85838 | 0.0292919 | 16.2145 | 0.831512 | 0.0124727 | 98.024 | 5.02687 | 0.0754031 | 35.5352 | 5.66866 | 0.0273348 | 66.0189 | 1.65136 | 0.0330094 | 7.33787 | 0.183484 | 0.00366894 | 36.8463 | 5.66866 | 0.0283433 | 24.5151 | 3.77404 | 0.0188578 | 24.4773 | 3.76574 | 0.0188287 | 48.6975 | 3.74716 | 0.0374596 | Component Quantities - EI-REV-Chapisco (externo): 3 with these values
AL14 | BLOCO A | 699.561 | 8.804 | 1.07957 | 57.4275 | 8.835 | 0.044175 | 24.882 | 1.276 | 0.01914 | 150.423 | 7.714 | 0.11571 | 44.928 | 6.912 | 0.03456 | 91.8 | 2.295 | 0.0459 | 10.2 | 0.255 | 0.0051 | 50.9907 | 7.9105 | 0.0392236 | 34.0387 | 5.2367 | 0.0261836 | 33.8765 | 5.21178 | 0.0260588 | 67.3784 | 5.1912 | 0.0518296 | 57.8305 | 8.897 | 3.1 | 0.005 | 0.0155 | 0.044485 | Component Quantities - EI-REV-Massa única - Fachada, Massa: 57.629 kg; EI-REV-Massa única - Fachada, Área de Componente Projetada (Líquida): 8.866 m2; EI-REV-Massa única - Fachada, Área de Componente Projetada (Bruta): 8.866 m2; EI-REV-Massa única - Fachada, Altura do Componente Retangular: 3.1 m; EI-REV-Massa única - Fachada, Largura do Componente Retangular: 0.005 m; EI-REV-Massa única - Fachada, Área de Seção Transversal do Componente: 0.0155 m2; EI-REV-Massa única - Fachada, Volume Componente (Líquido): 0.04433 m3; EI-REV-Massa única - Fachada, Volume do componente (Bruto): 0.04433 m3
AL14 | BLOCO A | 14.1149 | 0.155588 | 0.0217823 | 3.48216 | 0.535718 | 0.00267859 | 2.87086 | 0.147383 | 0.00220835 | 17.3512 | 0.890999 | 0.0133471 | 0.923565 | 0.142088 | 0.000710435 | 1.59938 | 0.0449657 | 0.000799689 | 0.177709 | 0.00499619 | 0.0000888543 | 0.83581 | 0.128588 | 0.000642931 | 0.463559 | 0.133821 | 0.000356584 | 0.802888 | 0.123522 | 0.000617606 | 1.33712 | 0.102922 | 0.00102856 | 3.68366 | 0.566718 | 3.1 | 0.005 | 0.0155 | 0.00283359 | Component Quantities - EI-REV-Massa única - Fachada, Massa: 3.58291 kg; EI-REV-Massa única - Fachada, Área de Componente Projetada (Líquida): 0.551218 m2; EI-REV-Massa única - Fachada, Área de Componente Projetada (Bruta): 0.551218 m2; EI-REV-Massa única - Fachada, Altura do Componente Retangular: 3.1 m; EI-REV-Massa única - Fachada, Largura do Componente Retangular: 0.005 m; EI-REV-Massa única - Fachada, Área de Seção Transversal do Componente: 0.0155 m2; EI-REV-Massa única - Fachada, Volume Componente (Líquido): 0.00275609 m3; EI-REV-Massa única - Fachada, Volume do componente (Bruto): 0.00275609 m3
AL14 | BLOCO A | 403.098 | 5.37977 | 0.622064 | 28.4235 | 4.37284 | 0.0218642 | 17.3459 | 0.889962 | 0.013343 | 95.725 | 4.91194 | 0.0736346 | 32.3181 | 4.97202 | 0.0248601 | 65.8769 | 1.64692 | 0.0329384 | 7.31965 | 0.182991 | 0.00365983 | 32.2307 | 4.95857 | 0.0247928 | 19.6795 | 3.02761 | 0.0151381 | 19.6255 | 3.01936 | 0.0150965 | 38.9302 | 2.99461 | 0.0299463 | 28.4241 | 4.37294 | 3.1 | 0.005 | 0.0155 | 0.0218647 | Component Quantities - EI-REV-Chapisco (externo): 2 with these values

# IfcWall: FNDE-CON-E5-E5 320, AL
In: TÉRREO
Classification: Parede (Classificação Archicad); Material: EI-REV-Pintura Acrílica Cor Branco Gelo 0.015 m, EI-REV-Massa Acrílica (externa) 0.005 m, EI-REV-Massa única - Fachada 0.005 m, EI-REV-Chapisco (externo) 0.005 m, GENÉRICO - ESTRUTURAL 0.26 m, EI-REV-Chapisco (externo) 0.005 m, EI-REV-Massa única - Fachada 0.005 m, EI-REV-Massa Acrílica (externa) 0.005 m, EI-REV-Pintura Acrílica Cor Branco Gelo 0.015 m
FNDE - Alvenarias: Alvenaria de Vedação / Edificação; Sistemas de Cobertura: -; Esquadrias - Fechamentos metálicos e Gradis: -; 1_Bloco: BLOCO A; 0_ID: AL
Pset_WallCommon - IsExternal: yes; LoadBearing: no
Component Quantities - EI-REV-Pintura Acrílica Cor Branco Gelo 1, Massa: 81.7732 kg; EI-REV-Pintura Acrílica Cor Branco Gelo 1, Área de Componente Projetada (Líquida): 4.1935 m2; EI-REV-Pintura Acrílica Cor Branco Gelo 1, Área de Componente Projetada (Bruta): 12.7035 m2; EI-REV-Pintura Acrílica Cor Branco Gelo 1, Espessura do Componente: 0.015 m; EI-REV-Pintura Acrílica Cor Branco Gelo 1, Altura do Componente Retangular: 2.69 m; EI-REV-Pintura Acrílica Cor Branco Gelo 1, Largura do Componente Retangular: 0.015 m; EI-REV-Pintura Acrílica Cor Branco Gelo 1, Área de Seção Transversal do Componente: 0.04035 m2; EI-REV-Pintura Acrílica Cor Branco Gelo 1, Volume Componente (Líquido): 0.0629025 m3; EI-REV-Pintura Acrílica Cor Branco Gelo 1, Volume do componente (Bruto): 0.190552 m3; EI-REV-Massa Acrílica (externa) 1, Massa: 27.2577 kg; EI-REV-Massa Acrílica (externa) 1, Área de Componente Projetada (Líquida): 4.1935 m2; EI-REV-Massa Acrílica (externa) 1, Área de Componente Projetada (Bruta): 12.7035 m2; EI-REV-Massa Acrílica (externa) 1, Espessura do Componente: 0.005 m; EI-REV-Massa Acrílica (externa) 1, Altura do Componente Retangular: 2.69 m; EI-REV-Massa Acrílica (externa) 1, Largura do Componente Retangular: 0.005 m; EI-REV-Massa Acrílica (externa) 1, Área de Seção Transversal do Componente: 0.01345 m2; EI-REV-Massa Acrílica (externa) 1, Volume Componente (Líquido): 0.0209675 m3; EI-REV-Massa Acrílica (externa) 1, Volume do componente (Bruto): 0.0635175 m3; GENÉRICO - ESTRUTURAL, Massa: 2551.96 kg; GENÉRICO - ESTRUTURAL, Área de Componente Projetada (Líquida): 4.2675 m2; GENÉRICO - ESTRUTURAL, Área de Componente Projetada (Bruta): 12.7775 m2; GENÉRICO - ESTRUTURAL, Espessura do Componente: 0.26 m; GENÉRICO - ESTRUTURAL, Altura do Componente Retangular: 2.69 m; GENÉRICO - ESTRUTURAL, Largura do Componente Retangular: 0.26 m; GENÉRICO - ESTRUTURAL, Área de Seção Transversal do Componente: 0.6994 m2; GENÉRICO - ESTRUTURAL, Volume Componente (Líquido): 1.10955 m3; GENÉRICO - ESTRUTURAL, Volume do componente (Bruto): 3.32215 m3; EI-REV-Pintura Acrílica Cor Branco Gelo 2, Massa: 81.7728 kg; EI-REV-Pintura Acrílica Cor Branco Gelo 2, Área de Componente Projetada (Líquida): 4.1935 m2; EI-REV-Pintura Acrílica Cor Branco Gelo 2, Área de Componente Projetada (Bruta): 12.7035 m2; EI-REV-Pintura Acrílica Cor Branco Gelo 2, Espessura do Componente: 0.015 m; EI-REV-Pintura Acrílica Cor Branco Gelo 2, Altura do Componente Retangular: 2.69 m; EI-REV-Pintura Acrílica Cor Branco Gelo 2, Largura do Componente Retangular: 0.015 m; EI-REV-Pintura Acrílica Cor Branco Gelo 2, Área de Seção Transversal do Componente: 0.04035 m2; EI-REV-Pintura Acrílica Cor Branco Gelo 2, Volume Componente (Líquido): 0.0629021 m3; EI-REV-Pintura Acrílica Cor Branco Gelo 2, Volume do componente (Bruto): 0.190553 m3; EI-REV-Massa Acrílica (externa) 1: 6 with these values

# IfcWall: FNDE-Cobrimento vigas com pintura AL09 150 x 430 (2)
In: TÉRREO
Classification: Parede (Classificação Archicad); Material: EI-REV-Pintura Acrílica Cor Branco Gelo (3)
FNDE - Alvenarias: Alvenaria de Vedação / Edificação; Sistemas de Cobertura: -; Esquadrias - Fechamentos metálicos e Gradis: -; 1_Bloco: BLOCO B
Pset_WallCommon - IsExternal: no; LoadBearing: no
Component Quantities - EI-REV-Pintura Acrílica Cor Branco Gelo 1, Massa: 3.14045 kg; EI-REV-Pintura Acrílica Cor Branco Gelo 1, Área de Componente Projetada (Líquida): 0.4558 m2; EI-REV-Pintura Acrílica Cor Branco Gelo 1, Área de Componente Projetada (Bruta): 0.4558 m2; EI-REV-Pintura Acrílica Cor Branco Gelo 1, Área de Seção Transversal do Componente: 0.012513 m2; EI-REV-Pintura Acrílica Cor Branco Gelo 1, Volume Componente (Líquido): 0.00241573 m3; EI-REV-Pintura Acrílica Cor Branco Gelo 1, Volume do componente (Bruto): 0.00241573 m3; EI-REV-Pintura Acrílica Cor Branco Gelo 2, Área de Seção Transversal do Componente: 0.012513 m2; EI-REV-Pintura Acrílica Cor Branco Gelo 3, Massa: 4.24677 kg; EI-REV-Pintura Acrílica Cor Branco Gelo 3, Área de Componente Projetada (Líquida): 0.158324 m2; EI-REV-Pintura Acrílica Cor Branco Gelo 3, Área de Componente Projetada (Bruta): 0.158324 m2; EI-REV-Pintura Acrílica Cor Branco Gelo 3, Área de Seção Transversal do Componente: 0.003096 m2; EI-REV-Pintura Acrílica Cor Branco Gelo 3, Volume Componente (Líquido): 0.00326675 m3; EI-REV-Pintura Acrílica Cor Branco Gelo 3, Volume do componente (Bruto): 0.00326675 m3
Name | EI-REV-Pintura Acrílica Cor Branco Gelo 2, Massa (kg) | EI-REV-Pintura Acrílica Cor Branco Gelo 2, Área de Componente Projetada (Líquida) (m2) = EI-REV-Pintura Acrílica Cor Branco Gelo 2, Área de Componente Projetada (Bruta) (m2) | EI-REV-Pintura Acrílica Cor Branco Gelo 2, Volume Componente (Líquido) (m3) = EI-REV-Pintura Acrílica Cor Branco Gelo 2, Volume do componente (Bruto) (m3)
 | 3.34301 | 0.41495 | 0.00257155
 | 3.35472 | 0.41665 | 0.00258055

# IfcWall: FNDE-E1 (faixa cinza) 30 x 3000 (10)
In: TÉRREO
Classification: Parede (Classificação Archicad); Material: EI-REV-Chapisco (externo), EI-REV-Pintura Acrílica Cor Cinza, EI-REV-Massa única - Fachada, EI-REV-Massa Acrílica (externa), EI-REV-Pintura Acrílica Cor Branco Gelo
FNDE - Alvenarias: Alvenaria de Vedação / Edificação; Sistemas de Cobertura: -; Esquadrias - Fechamentos metálicos e Gradis: -
Pset_WallCommon - LoadBearing: no
Component Quantities - EI-REV-Chapisco (externo), Altura do Componente Retangular: 3 m; EI-REV-Chapisco (externo), Largura do Componente Retangular: 0.005 m; EI-REV-Chapisco (externo), Área de Seção Transversal do Componente: 0.015 m2; EI-REV-Pintura Acrílica Cor Cinza, Altura do Componente Retangular: 0.44 m; EI-REV-Pintura Acrílica Cor Cinza, Largura do Componente Retangular: 0.015 m; EI-REV-Pintura Acrílica Cor Cinza, Área de Seção Transversal do Componente: 0.0066 m2; EI-REV-Massa única - Fachada, Altura do Componente Retangular: 3 m; EI-REV-Massa única - Fachada, Largura do Componente Retangular: 0.005 m; EI-REV-Massa única - Fachada, Área de Seção Transversal do Componente: 0.015 m2; EI-REV-Massa Acrílica (externa), Área de Seção Transversal do Componente: 0.015 m2; EI-REV-Pintura Acrílica Cor Branco Gelo, Altura do Componente Retangular: 2.56 m; EI-REV-Pintura Acrílica Cor Branco Gelo, Largura do Componente Retangular: 0.015 m; EI-REV-Pintura Acrílica Cor Branco Gelo, Área de Seção Transversal do Componente: 0.0384 m2
Name | 1_Bloco | 0_ID | IsExternal | EI-REV-Chapisco (externo), Massa (kg) | EI-REV-Chapisco (externo), Área de Componente Projetada (Líquida) (m2) = EI-REV-Chapisco (externo), Área de Componente Projetada (Bruta) (m2) | EI-REV-Chapisco (externo), Volume Componente (Líquido) (m3) = EI-REV-Chapisco (externo), Volume do componente (Bruto) (m3) | EI-REV-Pintura Acrílica Cor Cinza, Massa (kg) | EI-REV-Pintura Acrílica Cor Cinza, Área de Componente Projetada (Líquida) (m2) = EI-REV-Pintura Acrílica Cor Cinza, Área de Componente Projetada (Bruta) (m2) | EI-REV-Pintura Acrílica Cor Cinza, Volume Componente (Líquido) (m3) = EI-REV-Pintura Acrílica Cor Cinza, Volume do componente (Bruto) (m3) | EI-REV-Massa única - Fachada, Massa (kg) | EI-REV-Massa única - Fachada, Área de Componente Projetada (Líquida) (m2) = EI-REV-Massa única - Fachada, Área de Componente Projetada (Bruta) (m2) | EI-REV-Massa única - Fachada, Volume Componente (Líquido) (m3) = EI-REV-Massa única - Fachada, Volume do componente (Bruto) (m3) | EI-REV-Massa Acrílica (externa), Massa (kg) | EI-REV-Massa Acrílica (externa), Área de Componente Projetada (Líquida) (m2) = EI-REV-Massa Acrílica (externa), Área de Componente Projetada (Bruta) (m2) | EI-REV-Massa Acrílica (externa), Volume Componente (Líquido) (m3) = EI-REV-Massa Acrílica (externa), Volume do componente (Bruto) (m3) | EI-REV-Pintura Acrílica Cor Branco Gelo, Massa (kg) | EI-REV-Pintura Acrílica Cor Branco Gelo, Área de Componente Projetada (Líquida) (m2) = EI-REV-Pintura Acrílica Cor Branco Gelo, Área de Componente Projetada (Bruta) (m2) | EI-REV-Pintura Acrílica Cor Branco Gelo, Volume Componente (Líquido) (m3) = EI-REV-Pintura Acrílica Cor Branco Gelo, Volume do componente (Bruto) (m3)
AL15 | BLOCO A | AL15 | no | 3.35141 | 0.515602 | 0.00257801 | 1.97298 | 0.101178 | 0.00151767 | 3.56656 | 0.548702 | 0.00274351 | 3.76189 | 0.578752 | 0.00289376 | 10.4513 | 0.535962 | 0.00803943
AL16 | BLOCO A | AL16 | no | 0 | 0 | 0 | 0.825174 | 0.1012 | 0.00063475 | 0.1755 | 0.027 | 0.000135 | 0.351 | 0.054 | 0.00027 | 4.7959 | 0.588074 | 0.00368915
AL14 | BLOCO A | AL14 | yes | 0.0162796 | 0.00250456 | 0.0000125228 | 0.221241 | 0.0113457 | 0.000170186 | 0.0162796 | 0.00250455 | 0.0000125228 | 0.308778 | 0.0475043 | 0.000237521 | 1.29009 | 0.0661586 | 0.000992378
AL14 | BLOCO B | AL14 | yes | 0.00406798 | 0.000637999 | 0.00000312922 | 0.428629 | 0.022012 | 0.000329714 | 0.555268 | 0.0854242 | 0.000427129 | 0.717789 | 0.119457 | 0.000552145 | 2.37435 | 0.12187 | 0.00182643
AL10 | BLOCO B | AL10 | no | 3.99278 | 0.614274 | 0.00307137 | 2.1021 | 0.1078 | 0.001617 | 4.18778 | 0.644274 | 0.00322137 | 4.38278 | 0.674274 | 0.00337137 | 12.2162 | 0.626474 | 0.00939711
AL13 | BLOCO A | AL13 | no | 3.04851 | 0.469002 | 0.00234501 | 0.634327 | 0.0329782 | 0.000487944 | 3.23506 | 0.497702 | 0.00248851 | 3.40179 | 0.523352 | 0.00261676 | 11.2001 | 0.574362 | 0.00861543
AL09 | BLOCO B | AL09 | no | 4.16309 | 0.640475 | 0.00320238 | 2.41599 | 0.123897 | 0.00185845 | 4.37824 | 0.673575 | 0.00336788 | 4.58057 | 0.704703 | 0.00352351 | 13.0286 | 0.668154 | 0.010022
AL11 | BLOCO B | AL11 | no | 4.07567 | 0.627025 | 0.00313513 | 2.28729 | 0.117297 | 0.00175945 | 4.29082 | 0.660125 | 0.00330063 | 4.48307 | 0.689703 | 0.00344851 | 12.2802 | 0.629753 | 0.0094463
AL14 | BLOCO A | AL14 | no | 3.9975 | 0.615 | 0.003075 | 2.1021 | 0.1078 | 0.001617 | 4.1925 | 0.645 | 0.003225 | 4.3875 | 0.675 | 0.003375 | 12.2304 | 0.6272 | 0.009408
AL12 | BLOCO B | AL12 | no | 3.9 | 0.6 | 0.003 | 1.9734 | 0.1012 | 0.001518 | 4.095 | 0.63 | 0.00315 | 4.29 | 0.66 | 0.0033 | 11.4816 | 0.5888 | 0.008832

# IfcWall: FNDE-E2 30 (3)
In: TÉRREO
Classification: Parede (Classificação Archicad); Material: EI-REV-Pintura Acrílica Cor Cinza 0.015 m, EI-REV-Massa Acrílica (externa) 0.005 m, EI-REV-Massa única - Fachada 0.005 m, EI-REV-Chapisco (externo) 0.005 m
FNDE - Alvenarias: Alvenaria de Vedação / Edificação; Sistemas de Cobertura: -; Esquadrias - Fechamentos metálicos e Gradis: -; 1_Bloco: CASA DE BOMBAS / GÁS / LIXO; 0_ID: AL14
Pset_WallCommon - IsExternal: yes; LoadBearing: no
Component Quantities - EI-REV-Pintura Acrílica Cor Cinza, Espessura do Componente: 0.015 m; EI-REV-Pintura Acrílica Cor Cinza, Altura do Componente Retangular: 0.173 m; EI-REV-Pintura Acrílica Cor Cinza, Largura do Componente Retangular: 0.015 m; EI-REV-Pintura Acrílica Cor Cinza, Área de Seção Transversal do Componente: 0.002595 m2; EI-REV-Massa Acrílica (externa), Espessura do Componente: 0.005 m; EI-REV-Massa Acrílica (externa), Altura do Componente Retangular: 0.173 m; EI-REV-Massa Acrílica (externa), Largura do Componente Retangular: 0.005 m; EI-REV-Massa Acrílica (externa), Área de Seção Transversal do Componente: 0.000865 m2; EI-REV-Massa única - Fachada, Espessura do Componente: 0.005 m; EI-REV-Massa única - Fachada, Altura do Componente Retangular: 0.173 m; EI-REV-Massa única - Fachada, Largura do Componente Retangular: 0.005 m; EI-REV-Massa única - Fachada, Área de Seção Transversal do Componente: 0.000865 m2; EI-REV-Chapisco (externo), Espessura do Componente: 0.005 m; EI-REV-Chapisco (externo), Altura do Componente Retangular: 0.173 m; EI-REV-Chapisco (externo), Largura do Componente Retangular: 0.005 m; EI-REV-Chapisco (externo), Área de Seção Transversal do Componente: 0.000865 m2
Name | EI-REV-Pintura Acrílica Cor Cinza, Massa (kg) | EI-REV-Pintura Acrílica Cor Cinza, Área de Componente Projetada (Líquida) (m2) = EI-REV-Pintura Acrílica Cor Cinza, Área de Componente Projetada (Bruta) (m2) | EI-REV-Pintura Acrílica Cor Cinza, Volume Componente (Líquido) (m3) = EI-REV-Pintura Acrílica Cor Cinza, Volume do componente (Bruto) (m3) | EI-REV-Massa Acrílica (externa), Massa (kg) | EI-REV-Massa Acrílica (externa), Área de Componente Projetada (Líquida) (m2) = EI-REV-Massa Acrílica (externa), Área de Componente Projetada (Bruta) (m2) | EI-REV-Massa Acrílica (externa), Volume Componente (Líquido) (m3) = EI-REV-Massa Acrílica (externa), Volume do componente (Bruto) (m3) | EI-REV-Massa única - Fachada, Massa (kg) | EI-REV-Massa única - Fachada, Área de Componente Projetada (Líquida) (m2) = EI-REV-Massa única - Fachada, Área de Componente Projetada (Bruta) (m2) | EI-REV-Massa única - Fachada, Volume Componente (Líquido) (m3) = EI-REV-Massa única - Fachada, Volume do componente (Bruto) (m3) | EI-REV-Chapisco (externo), Massa (kg) | EI-REV-Chapisco (externo), Área de Componente Projetada (Líquida) (m2) = EI-REV-Chapisco (externo), Área de Componente Projetada (Bruta) (m2) | EI-REV-Chapisco (externo), Volume Componente (Líquido) (m3) = EI-REV-Chapisco (externo), Volume do componente (Bruto) (m3)
AL14 | 6.83656 | 0.350593 | 0.00525889 | 2.27323 | 0.349728 | 0.00174864 | 2.26761 | 0.348863 | 0.00174431 | 2.00041 | 0.307756 | 0.00153878
AL14 | 15.0567 | 1.20413 | 0.0115821 | 2.46159 | 0.378707 | 0.00189353 | 2.45035 | 0.376977 | 0.00188488 | 2.4391 | 0.375247 | 0.00187623
AL14 | 6.83656 | 0.350593 | 0.00525889 | 0.656104 | 0.100939 | 0.000504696 | 0.650482 | 0.100074 | 0.000500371 | 0.644859 | 0.0992091 | 0.000496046

# IfcWall: FNDE-E5 30 (7)
In: TÉRREO
Classification: Parede (Classificação Archicad); Material: EI-REV-Pintura Acrílica Cor Branco Gelo 0.015 m, EI-REV-Massa Acrílica (externa) 0.005 m, EI-REV-Massa única - Fachada 0.005 m, EI-REV-Chapisco (externo) 0.005 m
FNDE - Alvenarias: Alvenaria de Vedação / Edificação; Sistemas de Cobertura: -; Esquadrias - Fechamentos metálicos e Gradis: -
Pset_WallCommon - IsExternal: yes; LoadBearing: no
Component Quantities - EI-REV-Pintura Acrílica Cor Branco Gelo, Espessura do Componente: 0.015 m; EI-REV-Pintura Acrílica Cor Branco Gelo, Largura do Componente Retangular: 0.015 m; EI-REV-Massa Acrílica (externa), Espessura do Componente: 0.005 m; EI-REV-Massa Acrílica (externa), Largura do Componente Retangular: 0.005 m; EI-REV-Massa única - Fachada, Espessura do Componente: 0.005 m; EI-REV-Massa única - Fachada, Largura do Componente Retangular: 0.005 m; EI-REV-Chapisco (externo), Espessura do Componente: 0.005 m; EI-REV-Chapisco (externo), Largura do Componente Retangular: 0.005 m
Name | 1_Bloco | 0_ID | EI-REV-Pintura Acrílica Cor Branco Gelo, Massa (kg) | EI-REV-Pintura Acrílica Cor Branco Gelo, Área de Componente Projetada (Líquida) (m2) = EI-REV-Pintura Acrílica Cor Branco Gelo, Área de Componente Projetada (Bruta) (m2) | EI-REV-Pintura Acrílica Cor Branco Gelo, Altura do Componente Retangular (m) = EI-REV-Massa Acrílica (externa), Altura do Componente Retangular (m) = EI-REV-Massa única - Fachada, Altura do Componente Retangular (m) = EI-REV-Chapisco (externo), Altura do Componente Retangular (m) | EI-REV-Pintura Acrílica Cor Branco Gelo, Área de Seção Transversal do Componente (m2) | EI-REV-Pintura Acrílica Cor Branco Gelo, Volume Componente (Líquido) (m3) = EI-REV-Pintura Acrílica Cor Branco Gelo, Volume do componente (Bruto) (m3) | EI-REV-Massa Acrílica (externa), Massa (kg) | EI-REV-Massa Acrílica (externa), Área de Componente Projetada (Líquida) (m2) = EI-REV-Massa Acrílica (externa), Área de Componente Projetada (Bruta) (m2) | EI-REV-Massa Acrílica (externa), Área de Seção Transversal do Componente (m2) = EI-REV-Massa única - Fachada, Área de Seção Transversal do Componente (m2) = EI-REV-Chapisco (externo), Área de Seção Transversal do Componente (m2) | EI-REV-Massa Acrílica (externa), Volume Componente (Líquido) (m3) = EI-REV-Massa Acrílica (externa), Volume do componente (Bruto) (m3) | EI-REV-Massa única - Fachada, Massa (kg) | EI-REV-Massa única - Fachada, Área de Componente Projetada (Líquida) (m2) = EI-REV-Massa única - Fachada, Área de Componente Projetada (Bruta) (m2) | EI-REV-Massa única - Fachada, Volume Componente (Líquido) (m3) = EI-REV-Massa única - Fachada, Volume do componente (Bruto) (m3) | EI-REV-Chapisco (externo), Massa (kg) | EI-REV-Chapisco (externo), Área de Componente Projetada (Líquida) (m2) = EI-REV-Chapisco (externo), Área de Componente Projetada (Bruta) (m2) | EI-REV-Chapisco (externo), Volume Componente (Líquido) (m3) = EI-REV-Chapisco (externo), Volume do componente (Bruto) (m3)
AL14 | BLOCO B | AL14 | 0.9243 | 0.0474 | 3.1 | 0.0465 | 0.000711 | 0.15405 | 0.0237 | 0.0155 | 0.0001185 | 0.1027 | 0.0158 | 0.000079 | 0 | 0 | 0
AL14 | BLOCO B | AL14 | 1.00171 | 0.0514 | 3.14 | 0.0471 | 0.000770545 | 0.167071 | 0.0257032 | 0.0157 | 0.000128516 | 0.1287 | 0.0198 | 0.000099 | 0.026 | 0.004 | 0.00002
AL14 | BLOCO B | AL14 | 0.923913 | 0.0474 | 3.1 | 0.0465 | 0.000710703 | 0.15405 | 0.0237 | 0.0155 | 0.0001185 | 0.1027 | 0.0158 | 0.000079 | 0 | 0 | 0
AL14 | BLOCO B | AL14 | 0.923709 | 0.0474 | 3.1 | 0.0465 | 0.000710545 | 0.141072 | 0.0217033 | 0.0155 | 0.000108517 | 0.1027 | 0.0158 | 0.000079 | 0 | 0 | 0
AL14 | BLOCO A | AL14 | 1.51112 | 0.0775 | 3.1 | 0.0465 | 0.0011624 | 0.389884 | 0.0599821 | 0.0155 | 0.00029991 | 0.302133 | 0.0464821 | 0.00023241 | 0 | 0 | 0
AL15 | BLOCO A | AL15 | 1.51118 | 0.0775 | 3.1 | 0.0465 | 0.00116244 | 0.391698 | 0.062 | 0.0155 | 0.000301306 | 0.30225 | 0.0465 | 0.0002325 | 0 | 0 | 0
AL14 | BLOCO A | AL14 | 2.43553 | 0.124895 | 3.1 | 0.0465 | 0.00187348 | 0.541985 | 0.0833979 | 0.0155 | 0.000416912 | 0.402986 | 0.0619979 | 0.000309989 | 0 | 0 | 0

# IfcWall: FNDE-I2 (laranja) 30 x 3100, AL09
In: TÉRREO
Classification: Parede (Classificação Archicad); Material: EI-REV-Chapisco (interno), EI-REV-Pintura Epóxi cor Laranja, EI-REV-Massa única - Maior que 10m², EI-REV-Massa Corrida PVA (interna), EI-REV-Pintura Acrílica Cor Branco Gelo
FNDE - Alvenarias: Alvenaria de Vedação / Edificação; Sistemas de Cobertura: -; Esquadrias - Fechamentos metálicos e Gradis: -; 1_Bloco: BLOCO B; 0_ID: AL09
Pset_WallCommon - IsExternal: yes; LoadBearing: no
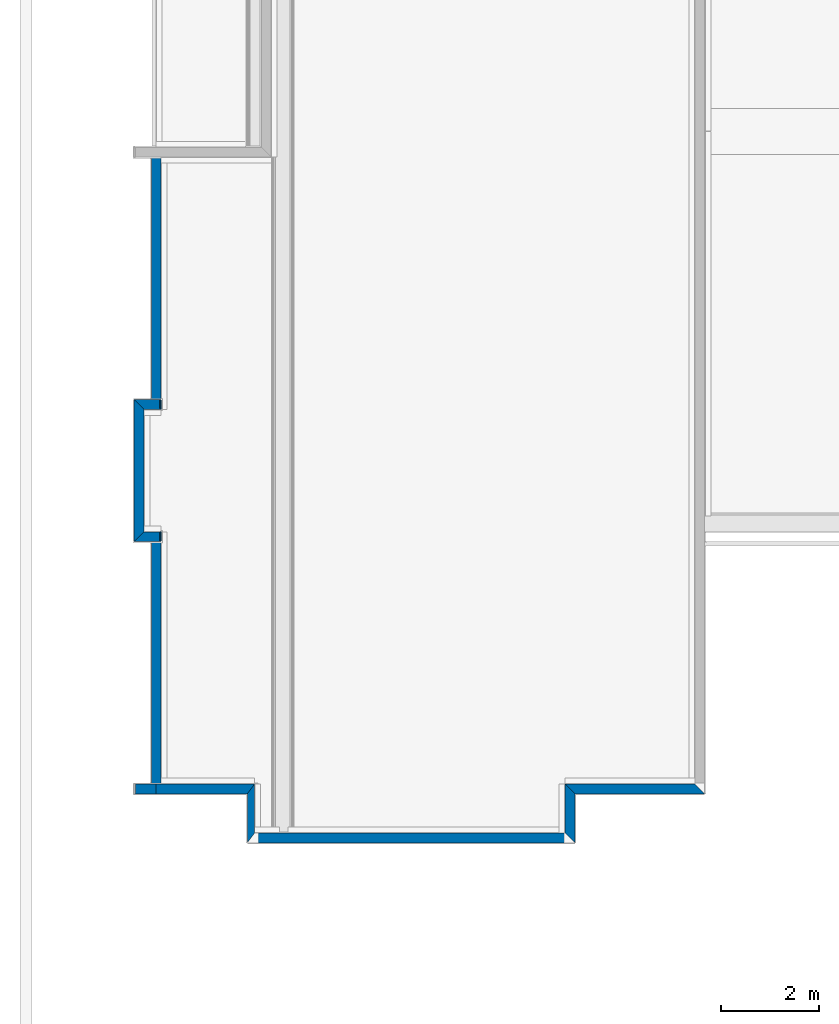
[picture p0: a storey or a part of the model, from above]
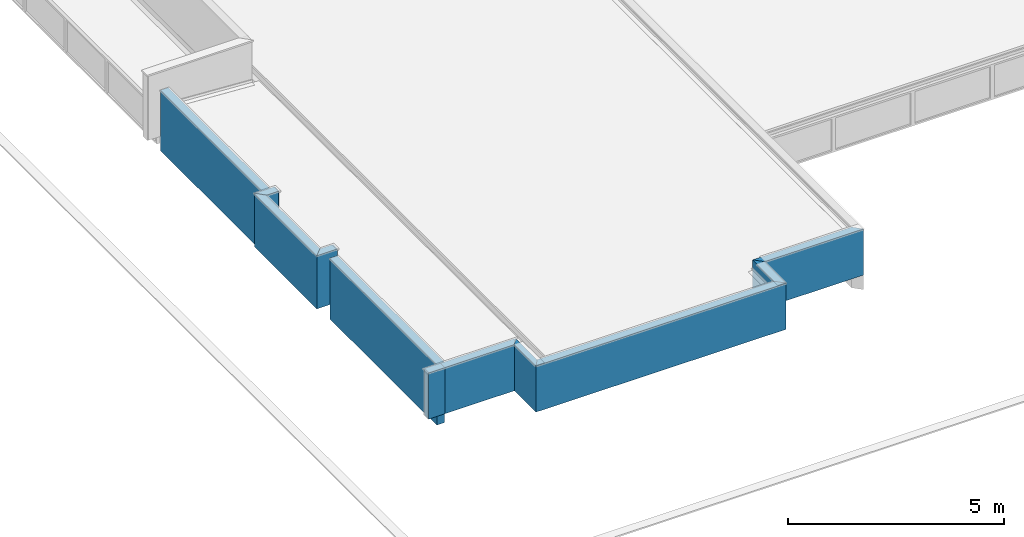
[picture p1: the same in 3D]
Properties of the parts of a building model (IFC4), part 20 of 22

# IfcWall: FNDE-I2 (laranja) 30 x 3100, AL09
Component Quantities - EI-REV-Chapisco (interno), Massa: 0.0052 kg; EI-REV-Chapisco (interno), Área de Componente Projetada (Líquida): 0.000800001 m2; EI-REV-Chapisco (interno), Área de Componente Projetada (Bruta): 0.000800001 m2; EI-REV-Chapisco (interno), Altura do Componente Retangular: 3.1 m; EI-REV-Chapisco (interno), Largura do Componente Retangular: 0.005 m; EI-REV-Chapisco (interno), Área de Seção Transversal do Componente: 0.0155 m2; EI-REV-Chapisco (interno), Volume Componente (Líquido): 0.000004 m3; EI-REV-Chapisco (interno), Volume do componente (Bruto): 0.000004 m3; EI-REV-Pintura Epóxi cor Laranja, Massa: 0 kg; EI-REV-Pintura Epóxi cor Laranja, Área de Componente Projetada (Líquida): 0 m2; EI-REV-Pintura Epóxi cor Laranja, Área de Componente Projetada (Bruta): 0 m2; EI-REV-Pintura Epóxi cor Laranja, Altura do Componente Retangular: 0.9 m; EI-REV-Pintura Epóxi cor Laranja, Largura do Componente Retangular: 0.02 m; EI-REV-Pintura Epóxi cor Laranja, Área de Seção Transversal do Componente: 0.018 m2; EI-REV-Pintura Epóxi cor Laranja, Volume Componente (Líquido): 0 m3; EI-REV-Pintura Epóxi cor Laranja, Volume do componente (Bruto): 0 m3; EI-REV-Massa única - Maior que 10m², Massa: 0.00650001 kg; EI-REV-Massa única - Maior que 10m², Área de Componente Projetada (Líquida): 0.001 m2; EI-REV-Massa única - Maior que 10m², Área de Componente Projetada (Bruta): 0.001 m2; EI-REV-Massa única - Maior que 10m², Área de Seção Transversal do Componente: 0.0155 m2; EI-REV-Massa única - Maior que 10m², Volume Componente (Líquido): 0.00000500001 m3; EI-REV-Massa única - Maior que 10m², Volume do componente (Bruto): 0.00000500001 m3; EI-REV-Massa Corrida PVA (interna), Massa: 0 kg; EI-REV-Massa Corrida PVA (interna), Área de Componente Projetada (Líquida): 0 m2; EI-REV-Massa Corrida PVA (interna), Área de Componente Projetada (Bruta): 0 m2; EI-REV-Massa Corrida PVA (interna), Altura do Componente Retangular: 2.16 m; EI-REV-Massa Corrida PVA (interna), Largura do Componente Retangular: 0.005 m; EI-REV-Massa Corrida PVA (interna), Área de Seção Transversal do Componente: 0.0108001 m2; EI-REV-Massa Corrida PVA (interna), Volume Componente (Líquido): 0 m3; EI-REV-Massa Corrida PVA (interna), Volume do componente (Bruto): 0 m3; EI-REV-Pintura Acrílica Cor Branco Gelo, Massa: 0 kg; EI-REV-Pintura Acrílica Cor Branco Gelo, Área de Componente Projetada (Líquida): 0 m2; EI-REV-Pintura Acrílica Cor Branco Gelo, Área de Componente Projetada (Bruta): 0 m2; EI-REV-Pintura Acrílica Cor Branco Gelo, Altura do Componente Retangular: 2.16 m; EI-REV-Pintura Acrílica Cor Branco Gelo, Largura do Componente Retangular: 0.015 m; EI-REV-Pintura Acrílica Cor Branco Gelo, Área de Seção Transversal do Componente: 0.0324 m2; EI-REV-Pintura Acrílica Cor Branco Gelo, Volume Componente (Líquido): 0 m3; EI-REV-Pintura Acrílica Cor Branco Gelo, Volume do componente (Bruto): 0 m3

# IfcWall: FNDE-I3 (verde) 30 x 3100, AL09
In: TÉRREO
Classification: Parede (Classificação Archicad); Material: EI-REV-Chapisco (interno), EI-REV-Pintura Epóxi cor Verde, EI-REV-Massa única - Maior que 10m², EI-REV-Massa Corrida PVA (interna), EI-REV-Pintura Acrílica Cor Branco Gelo
FNDE - Alvenarias: Alvenaria de Vedação / Edificação; Sistemas de Cobertura: -; Esquadrias - Fechamentos metálicos e Gradis: -; 1_Bloco: BLOCO B; 0_ID: AL09
Pset_WallCommon - IsExternal: no; LoadBearing: no
Component Quantities - EI-REV-Chapisco (interno), Massa: 0.013 kg; EI-REV-Chapisco (interno), Área de Componente Projetada (Líquida): 0.002 m2; EI-REV-Chapisco (interno), Área de Componente Projetada (Bruta): 0.002 m2; EI-REV-Chapisco (interno), Altura do Componente Retangular: 3.1 m; EI-REV-Chapisco (interno), Largura do Componente Retangular: 0.005 m; EI-REV-Chapisco (interno), Área de Seção Transversal do Componente: 0.0155 m2; EI-REV-Chapisco (interno), Volume Componente (Líquido): 0.00001 m3; EI-REV-Chapisco (interno), Volume do componente (Bruto): 0.00001 m3; EI-REV-Pintura Epóxi cor Verde, Massa: 0.936 kg; EI-REV-Pintura Epóxi cor Verde, Área de Componente Projetada (Líquida): 0.036 m2; EI-REV-Pintura Epóxi cor Verde, Área de Componente Projetada (Bruta): 0.036 m2; EI-REV-Pintura Epóxi cor Verde, Altura do Componente Retangular: 0.9 m; EI-REV-Pintura Epóxi cor Verde, Largura do Componente Retangular: 0.02 m; EI-REV-Pintura Epóxi cor Verde, Área de Seção Transversal do Componente: 0.018 m2; EI-REV-Pintura Epóxi cor Verde, Volume Componente (Líquido): 0.00072 m3; EI-REV-Pintura Epóxi cor Verde, Volume do componente (Bruto): 0.00072 m3; EI-REV-Massa única - Maior que 10m², Massa: 0.0156 kg; EI-REV-Massa única - Maior que 10m², Área de Componente Projetada (Líquida): 0.0024 m2; EI-REV-Massa única - Maior que 10m², Área de Componente Projetada (Bruta): 0.0024 m2; EI-REV-Massa única - Maior que 10m², Área de Seção Transversal do Componente: 0.0155 m2; EI-REV-Massa única - Maior que 10m², Volume Componente (Líquido): 0.000012 m3; EI-REV-Massa única - Maior que 10m², Volume do componente (Bruto): 0.000012 m3; EI-REV-Massa Corrida PVA (interna), Massa: 0 kg; EI-REV-Massa Corrida PVA (interna), Área de Componente Projetada (Líquida): 0 m2; EI-REV-Massa Corrida PVA (interna), Área de Componente Projetada (Bruta): 0 m2; EI-REV-Massa Corrida PVA (interna), Altura do Componente Retangular: 2.16 m; EI-REV-Massa Corrida PVA (interna), Largura do Componente Retangular: 0.005 m; EI-REV-Massa Corrida PVA (interna), Área de Seção Transversal do Componente: 0.0108001 m2; EI-REV-Massa Corrida PVA (interna), Volume Componente (Líquido): 0 m3; EI-REV-Massa Corrida PVA (interna), Volume do componente (Bruto): 0 m3; EI-REV-Pintura Acrílica Cor Branco Gelo, Massa: 1.2636 kg; EI-REV-Pintura Acrílica Cor Branco Gelo, Área de Componente Projetada (Líquida): 0.0647999 m2; EI-REV-Pintura Acrílica Cor Branco Gelo, Área de Componente Projetada (Bruta): 0.0647999 m2; EI-REV-Pintura Acrílica Cor Branco Gelo, Altura do Componente Retangular: 2.16 m; EI-REV-Pintura Acrílica Cor Branco Gelo, Largura do Componente Retangular: 0.015 m; EI-REV-Pintura Acrílica Cor Branco Gelo, Área de Seção Transversal do Componente: 0.0324 m2; EI-REV-Pintura Acrílica Cor Branco Gelo, Volume Componente (Líquido): 0.000971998 m3; EI-REV-Pintura Acrílica Cor Branco Gelo, Volume do componente (Bruto): 0.000971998 m3

# IfcWall: FNDE-I5 (azul) 30 x 1930 (2)
In: TÉRREO
Classification: Parede (Classificação Archicad); Material: EI-REV-Chapisco (interno), EI-REV-Cerâmica 30x40, EI-REV-Cerâmica 10x10 Azul, EI-REV-Emboço Interno
FNDE - Sistemas de Cobertura: -; Esquadrias - Fechamentos metálicos e Gradis: -; 1_Bloco: BLOCO B; 0_ID: AL09
Pset_WallCommon - IsExternal: no; LoadBearing: no
Component Quantities - EI-REV-Cerâmica 30x40, Massa: 2.88 kg; EI-REV-Cerâmica 30x40, Área de Componente Projetada (Líquida): 0.072 m2; EI-REV-Cerâmica 30x40, Área de Componente Projetada (Bruta): 0.072 m2; EI-REV-Cerâmica 30x40, Altura do Componente Retangular: 1.8 m; EI-REV-Cerâmica 30x40, Largura do Componente Retangular: 0.02 m; EI-REV-Cerâmica 30x40, Área de Seção Transversal do Componente: 0.036 m2; EI-REV-Cerâmica 30x40, Volume Componente (Líquido): 0.00144 m3; EI-REV-Cerâmica 30x40, Volume do componente (Bruto): 0.00144 m3; EI-REV-Cerâmica 10x10 Azul, Massa: 0.16 kg; EI-REV-Cerâmica 10x10 Azul, Área de Componente Projetada (Líquida): 0.004 m2; EI-REV-Cerâmica 10x10 Azul, Área de Componente Projetada (Bruta): 0.004 m2; EI-REV-Cerâmica 10x10 Azul, Altura do Componente Retangular: 0.1 m; EI-REV-Cerâmica 10x10 Azul, Largura do Componente Retangular: 0.02 m; EI-REV-Cerâmica 10x10 Azul, Área de Seção Transversal do Componente: 0.002 m2; EI-REV-Cerâmica 10x10 Azul, Volume Componente (Líquido): 0.00008 m3; EI-REV-Cerâmica 10x10 Azul, Volume do componente (Bruto): 0.00008 m3
Name | Alvenarias | EI-REV-Chapisco (interno), Massa (kg) | EI-REV-Chapisco (interno), Área de Componente Projetada (Líquida) (m2) = EI-REV-Chapisco (interno), Área de Componente Projetada (Bruta) (m2) | EI-REV-Chapisco (interno), Altura do Componente Retangular (m) | EI-REV-Chapisco (interno), Largura do Componente Retangular (m) | EI-REV-Chapisco (interno), Área de Seção Transversal do Componente (m2) | EI-REV-Chapisco (interno), Volume Componente (Líquido) (m3) = EI-REV-Chapisco (interno), Volume do componente (Bruto) (m3)
AL09 | Mureta | 0.00974998 | 0.0015 | 1.8 | 0.00499999 | 0.00899998 | 0.00000749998 | Component Quantities - EI-REV-Emboço Interno, Massa: 0.0117 kg; EI-REV-Emboço Interno, Área de Componente Projetada (Líquida): 0.0018 m2; EI-REV-Emboço Interno, Área de Componente Projetada (Bruta): 0.0018 m2; EI-REV-Emboço Interno, Altura do Componente Retangular: 1.8 m; EI-REV-Emboço Interno, Largura do Componente Retangular: 0.00499999 m; EI-REV-Emboço Interno, Área de Seção Transversal do Componente: 0.00900001 m2; EI-REV-Emboço Interno, Volume Componente (Líquido): 0.000009 m3; EI-REV-Emboço Interno, Volume do componente (Bruto): 0.000009 m3
AL09 | Alvenaria de Vedação / Edificação | 0 | 0 | 1.93 | 0.005 | 0.00965 | 0 | Component Quantities - EI-REV-Chapisco (interno): 2 with these values

# IfcWall: FNDE-I5 (azul) 30 x 3100 (4)
In: TÉRREO
Classification: Parede (Classificação Archicad); Material: EI-REV-Chapisco (interno), EI-REV-Cerâmica 30x40, EI-REV-Cerâmica 10x10 Azul, EI-REV-Emboço Interno, EI-REV-Massa única - Maior que 10m², EI-REV-Massa Corrida PVA (interna), EI-REV-Pintura Acrílica Cor Branco Gelo
FNDE - Alvenarias: Alvenaria de Vedação / Edificação; Sistemas de Cobertura: -; Esquadrias - Fechamentos metálicos e Gradis: -; 0_ID: AL09
Pset_WallCommon - LoadBearing: no
Component Quantities - EI-REV-Chapisco (interno), Altura do Componente Retangular: 3.1 m; EI-REV-Chapisco (interno), Largura do Componente Retangular: 0.005 m; EI-REV-Chapisco (interno), Área de Seção Transversal do Componente: 0.0155 m2; EI-REV-Cerâmica 30x40, Largura do Componente Retangular: 0.02 m; EI-REV-Cerâmica 10x10 Azul, Altura do Componente Retangular: 0.1 m; EI-REV-Cerâmica 10x10 Azul, Largura do Componente Retangular: 0.02 m; EI-REV-Cerâmica 10x10 Azul, Área de Seção Transversal do Componente: 0.002 m2; EI-REV-Massa Corrida PVA (interna), Largura do Componente Retangular: 0.005 m; EI-REV-Pintura Acrílica Cor Branco Gelo, Largura do Componente Retangular: 0.01 m
Name | 1_Bloco | IsExternal | EI-REV-Chapisco (interno), Massa (kg) | EI-REV-Chapisco (interno), Área de Componente Projetada (Líquida) (m2) = EI-REV-Chapisco (interno), Área de Componente Projetada (Bruta) (m2) | EI-REV-Chapisco (interno), Volume Componente (Líquido) (m3) = EI-REV-Chapisco (interno), Volume do componente (Bruto) (m3) | EI-REV-Cerâmica 30x40, Massa (kg) | EI-REV-Cerâmica 30x40, Área de Componente Projetada (Líquida) (m2) = EI-REV-Cerâmica 30x40, Área de Componente Projetada (Bruta) (m2) | EI-REV-Cerâmica 30x40, Altura do Componente Retangular (m) | EI-REV-Cerâmica 30x40, Área de Seção Transversal do Componente (m2) | EI-REV-Cerâmica 30x40, Volume Componente (Líquido) (m3) = EI-REV-Cerâmica 30x40, Volume do componente (Bruto) (m3) | EI-REV-Cerâmica 10x10 Azul, Massa (kg) | EI-REV-Cerâmica 10x10 Azul, Área de Componente Projetada (Líquida) (m2) = EI-REV-Cerâmica 10x10 Azul, Área de Componente Projetada (Bruta) (m2) | EI-REV-Cerâmica 10x10 Azul, Volume Componente (Líquido) (m3) = EI-REV-Cerâmica 10x10 Azul, Volume do componente (Bruto) (m3) | EI-REV-Emboço Interno, Massa (kg) | EI-REV-Emboço Interno, Área de Componente Projetada (Líquida) (m2) = EI-REV-Emboço Interno, Área de Componente Projetada (Bruta) (m2) | EI-REV-Emboço Interno, Altura do Componente Retangular (m) | EI-REV-Emboço Interno, Largura do Componente Retangular (m) | EI-REV-Emboço Interno, Área de Seção Transversal do Componente (m2) | EI-REV-Emboço Interno, Volume Componente (Líquido) (m3) = EI-REV-Emboço Interno, Volume do componente (Bruto) (m3) | EI-REV-Massa única - Maior que 10m², Massa (kg) | EI-REV-Massa única - Maior que 10m², Área de Componente Projetada (Líquida) (m2) = EI-REV-Massa única - Maior que 10m², Área de Componente Projetada (Bruta) (m2) | EI-REV-Massa única - Maior que 10m², Altura do Componente Retangular (m) = EI-REV-Massa Corrida PVA (interna), Altura do Componente Retangular (m) = EI-REV-Pintura Acrílica Cor Branco Gelo, Altura do Componente Retangular (m) | EI-REV-Massa única - Maior que 10m², Largura do Componente Retangular (m) | EI-REV-Massa única - Maior que 10m², Área de Seção Transversal do Componente (m2) | EI-REV-Massa única - Maior que 10m², Volume Componente (Líquido) (m3) = EI-REV-Massa única - Maior que 10m², Volume do componente (Bruto) (m3) | EI-REV-Massa Corrida PVA (interna), Massa (kg) | EI-REV-Massa Corrida PVA (interna), Área de Componente Projetada (Líquida) (m2) = EI-REV-Massa Corrida PVA (interna), Área de Componente Projetada (Bruta) (m2) | EI-REV-Massa Corrida PVA (interna), Área de Seção Transversal do Componente (m2) | EI-REV-Massa Corrida PVA (interna), Volume Componente (Líquido) (m3) = EI-REV-Massa Corrida PVA (interna), Volume do componente (Bruto) (m3) | EI-REV-Pintura Acrílica Cor Branco Gelo, Massa (kg) | EI-REV-Pintura Acrílica Cor Branco Gelo, Área de Componente Projetada (Líquida) (m2) = EI-REV-Pintura Acrílica Cor Branco Gelo, Área de Componente Projetada (Bruta) (m2) | EI-REV-Pintura Acrílica Cor Branco Gelo, Área de Seção Transversal do Componente (m2) | EI-REV-Pintura Acrílica Cor Branco Gelo, Volume Componente (Líquido) (m3) = EI-REV-Pintura Acrílica Cor Branco Gelo, Volume do componente (Bruto) (m3)
AL09 | BLOCO B | yes | 0.0039 | 0.0006 | 0.000003 | 0 | 0 | 1.2 | 0.024 | 0 | 0 | 0 | 0 | 0.004875 | 0.00075 | 3.1 | 0.005 | 0.0155 | 0.00000375 | 0 | 0 | 1.77 | 0.00499998 | 0.00884996 | 0 | 0 | 0 | 0.00885001 | 0 | 0 | 0 | 0.0177 | 0
AL09 | BLOCO B | yes | 0.0293149 | 0.00451 | 0.00002255 | 1.968 | 0.0492 | 1.2 | 0.024 | 0.000984 | 0.164 | 0.0041 | 0.000082 | 0.0312649 | 0.00481 | 3.1 | 0.005 | 0.0155 | 0.00002405 | 0.011115 | 0.00171001 | 1.77 | 0.00499998 | 0.00884996 | 0.00000854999 | 0.0111151 | 0.00171001 | 0.00885001 | 0.00000855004 | 0.47853 | 0.0368099 | 0.0177 | 0.0003681
AL09 | BLOCO B | yes | 0.0039 | 0.0006 | 0.000003 | 0 | 0 | 1.2 | 0.024 | 0 | 0 | 0 | 0 |  |  |  |  |  |  | 0 | 0 | 1.77 | 0.00499998 | 0.00884996 | 0 | 0 | 0 | 0.00885001 | 0 | 0 | 0 | 0.0177 | 0 | Component Quantities - EI-REV-Chapisco (interno): 2 with these values
AL09 | BLOCO A | no | 0.0102465 | 0.00157638 | 0.00000788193 | 2.87999 | 0.0719999 | 1.8 | 0.036 | 0.00144 | 0.16 | 0.00399999 | 0.0000799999 | 0.0121966 | 0.00187639 | 3.1 | 0.005 | 0.0155 | 0.00000938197 | 0.000189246 | 0.0000291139 | 1.17 | 0.00499997 | 0.00584996 | 1.45574e-07 | 0.000189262 | 0.0000291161 | 0.00585001 | 1.45586e-07 | 0.304199 | 0.0233999 | 0.0117 | 0.000233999

# IfcWall: FNDE-I5 (vermelho) 30 x 1930, AL09
In: TÉRREO
Classification: Parede (Classificação Archicad); Material: EI-REV-Chapisco (interno), EI-REV-Cerâmica 30x40, EI-REV-Cerâmica 10x10 Vermelha, EI-REV-Emboço Interno
FNDE - Alvenarias: Alvenaria de Vedação / Edificação; Sistemas de Cobertura: -; Esquadrias - Fechamentos metálicos e Gradis: -; 1_Bloco: BLOCO B; 0_ID: AL09
Pset_WallCommon - IsExternal: no; LoadBearing: no
Component Quantities - EI-REV-Chapisco (interno), Massa: 0 kg; EI-REV-Chapisco (interno), Área de Componente Projetada (Líquida): 0 m2; EI-REV-Chapisco (interno), Área de Componente Projetada (Bruta): 0 m2; EI-REV-Chapisco (interno), Altura do Componente Retangular: 1.8 m; EI-REV-Chapisco (interno), Largura do Componente Retangular: 0.00499999 m; EI-REV-Chapisco (interno), Área de Seção Transversal do Componente: 0.00899998 m2; EI-REV-Chapisco (interno), Volume Componente (Líquido): 0 m3; EI-REV-Chapisco (interno), Volume do componente (Bruto): 0 m3; EI-REV-Cerâmica 30x40, Massa: 2.87997 kg; EI-REV-Cerâmica 30x40, Área de Componente Projetada (Líquida): 0.072 m2; EI-REV-Cerâmica 30x40, Área de Componente Projetada (Bruta): 0.072 m2; EI-REV-Cerâmica 30x40, Altura do Componente Retangular: 1.8 m; EI-REV-Cerâmica 30x40, Largura do Componente Retangular: 0.02 m; EI-REV-Cerâmica 30x40, Área de Seção Transversal do Componente: 0.036 m2; EI-REV-Cerâmica 30x40, Volume Componente (Líquido): 0.00143998 m3; EI-REV-Cerâmica 30x40, Volume do componente (Bruto): 0.00143998 m3; EI-REV-Cerâmica 10x10 Vermelha, Massa: 0.16 kg; EI-REV-Cerâmica 10x10 Vermelha, Área de Componente Projetada (Líquida): 0.004 m2; EI-REV-Cerâmica 10x10 Vermelha, Área de Componente Projetada (Bruta): 0.004 m2; EI-REV-Cerâmica 10x10 Vermelha, Altura do Componente Retangular: 0.1 m; EI-REV-Cerâmica 10x10 Vermelha, Largura do Componente Retangular: 0.02 m; EI-REV-Cerâmica 10x10 Vermelha, Área de Seção Transversal do Componente: 0.002 m2; EI-REV-Cerâmica 10x10 Vermelha, Volume Componente (Líquido): 0.00008 m3; EI-REV-Cerâmica 10x10 Vermelha, Volume do componente (Bruto): 0.00008 m3; EI-REV-Emboço Interno, Massa: 0 kg; EI-REV-Emboço Interno, Área de Componente Projetada (Líquida): 0 m2; EI-REV-Emboço Interno, Área de Componente Projetada (Bruta): 0 m2; EI-REV-Emboço Interno, Altura do Componente Retangular: 1.8 m; EI-REV-Emboço Interno, Largura do Componente Retangular: 0.00499999 m; EI-REV-Emboço Interno, Área de Seção Transversal do Componente: 0.00900001 m2; EI-REV-Emboço Interno, Volume Componente (Líquido): 0 m3; EI-REV-Emboço Interno, Volume do componente (Bruto): 0 m3

# IfcWall: FNDE-I5 (vermelho) 30 x 3100 (2)
In: TÉRREO
Classification: Parede (Classificação Archicad); Material: EI-REV-Chapisco (interno), EI-REV-Cerâmica 30x40, EI-REV-Cerâmica 10x10 Vermelha, EI-REV-Emboço Interno, EI-REV-Massa única - Maior que 10m², EI-REV-Massa Corrida PVA (interna), EI-REV-Pintura Acrílica Cor Branco Gelo
FNDE - Alvenarias: Alvenaria de Vedação / Edificação; Sistemas de Cobertura: -; Esquadrias - Fechamentos metálicos e Gradis: -; 1_Bloco: BLOCO B; 0_ID: AL09
Pset_WallCommon - IsExternal: yes; LoadBearing: no
Component Quantities - EI-REV-Chapisco (interno), Altura do Componente Retangular: 3.1 m; EI-REV-Chapisco (interno), Largura do Componente Retangular: 0.005 m; EI-REV-Chapisco (interno), Área de Seção Transversal do Componente: 0.0155 m2; EI-REV-Cerâmica 30x40, Altura do Componente Retangular: 1.2 m; EI-REV-Cerâmica 30x40, Largura do Componente Retangular: 0.02 m; EI-REV-Cerâmica 30x40, Área de Seção Transversal do Componente: 0.024 m2; EI-REV-Cerâmica 10x10 Vermelha, Altura do Componente Retangular: 0.1 m; EI-REV-Cerâmica 10x10 Vermelha, Largura do Componente Retangular: 0.02 m; EI-REV-Cerâmica 10x10 Vermelha, Área de Seção Transversal do Componente: 0.002 m2; EI-REV-Emboço Interno, Altura do Componente Retangular: 3.1 m; EI-REV-Emboço Interno, Largura do Componente Retangular: 0.005 m; EI-REV-Emboço Interno, Área de Seção Transversal do Componente: 0.0155 m2; EI-REV-Massa única - Maior que 10m², Massa: 0 kg; EI-REV-Massa única - Maior que 10m², Área de Componente Projetada (Líquida): 0 m2; EI-REV-Massa única - Maior que 10m², Área de Componente Projetada (Bruta): 0 m2; EI-REV-Massa única - Maior que 10m², Altura do Componente Retangular: 1.77 m; EI-REV-Massa única - Maior que 10m², Largura do Componente Retangular: 0.00499998 m; EI-REV-Massa única - Maior que 10m², Área de Seção Transversal do Componente: 0.00884996 m2; EI-REV-Massa única - Maior que 10m², Volume Componente (Líquido): 0 m3; EI-REV-Massa única - Maior que 10m², Volume do componente (Bruto): 0 m3; EI-REV-Massa Corrida PVA (interna), Massa: 0 kg; EI-REV-Massa Corrida PVA (interna), Área de Componente Projetada (Líquida): 0 m2; EI-REV-Massa Corrida PVA (interna), Área de Componente Projetada (Bruta): 0 m2; EI-REV-Massa Corrida PVA (interna), Altura do Componente Retangular: 1.77 m; EI-REV-Massa Corrida PVA (interna), Largura do Componente Retangular: 0.005 m; EI-REV-Massa Corrida PVA (interna), Área de Seção Transversal do Componente: 0.00885001 m2; EI-REV-Massa Corrida PVA (interna), Volume Componente (Líquido): 0 m3; EI-REV-Massa Corrida PVA (interna), Volume do componente (Bruto): 0 m3; EI-REV-Pintura Acrílica Cor Branco Gelo, Altura do Componente Retangular: 1.77 m; EI-REV-Pintura Acrílica Cor Branco Gelo, Largura do Componente Retangular: 0.01 m; EI-REV-Pintura Acrílica Cor Branco Gelo, Área de Seção Transversal do Componente: 0.0177 m2
Name | EI-REV-Chapisco (interno), Massa (kg) | EI-REV-Chapisco (interno), Área de Componente Projetada (Líquida) (m2) = EI-REV-Chapisco (interno), Área de Componente Projetada (Bruta) (m2) | EI-REV-Chapisco (interno), Volume Componente (Líquido) (m3) = EI-REV-Chapisco (interno), Volume do componente (Bruto) (m3) | EI-REV-Cerâmica 30x40, Massa (kg) | EI-REV-Cerâmica 30x40, Área de Componente Projetada (Líquida) (m2) = EI-REV-Cerâmica 30x40, Área de Componente Projetada (Bruta) (m2) | EI-REV-Cerâmica 30x40, Volume Componente (Líquido) (m3) = EI-REV-Cerâmica 30x40, Volume do componente (Bruto) (m3) | EI-REV-Cerâmica 10x10 Vermelha, Massa (kg) | EI-REV-Cerâmica 10x10 Vermelha, Área de Componente Projetada (Líquida) (m2) = EI-REV-Cerâmica 10x10 Vermelha, Área de Componente Projetada (Bruta) (m2) | EI-REV-Cerâmica 10x10 Vermelha, Volume Componente (Líquido) (m3) = EI-REV-Cerâmica 10x10 Vermelha, Volume do componente (Bruto) (m3) | EI-REV-Emboço Interno, Massa (kg) | EI-REV-Emboço Interno, Área de Componente Projetada (Líquida) (m2) = EI-REV-Emboço Interno, Área de Componente Projetada (Bruta) (m2) | EI-REV-Emboço Interno, Volume Componente (Líquido) (m3) = EI-REV-Emboço Interno, Volume do componente (Bruto) (m3) | EI-REV-Pintura Acrílica Cor Branco Gelo, Massa (kg) | EI-REV-Pintura Acrílica Cor Branco Gelo, Área de Componente Projetada (Líquida) (m2) = EI-REV-Pintura Acrílica Cor Branco Gelo, Área de Componente Projetada (Bruta) (m2) | EI-REV-Pintura Acrílica Cor Branco Gelo, Volume Componente (Líquido) (m3) = EI-REV-Pintura Acrílica Cor Branco Gelo, Volume do componente (Bruto) (m3)
AL09 | 0.00975001 | 0.0015 | 0.00000750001 | 1.92001 | 0.0480001 | 0.000960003 | 0.16 | 0.00400001 | 0.0000800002 | 0.0117 | 0.0018 | 0.00000900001 | 0.460202 | 0.0354002 | 0.000354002
AL09 | 0.0039 | 0.0006 | 0.000003 | 0 | 0 | 0 | 0 | 0 | 0 | 0.004875 | 0.00075 | 0.00000375 | 0 | 0 | 0

# IfcWall: FNDE-I7 (amarela) 30 x 3100 (8)
In: TÉRREO
Classification: Parede (Classificação Archicad); Material: EI-REV-Chapisco (interno), EI-REV-Cerâmica 10x10 Amarela, EI-REV-Cerâmica 10x10 Branca, EI-REV-Emboço Interno, EI-REV-Massa única - Maior que 10m², EI-REV-Massa Corrida PVA (interna), EI-REV-Pintura Acrílica Cor Branco Gelo
FNDE - Alvenarias: Alvenaria de Vedação / Edificação; Sistemas de Cobertura: -; Esquadrias - Fechamentos metálicos e Gradis: -
Pset_WallCommon - IsExternal: no; LoadBearing: no
Component Quantities - EI-REV-Chapisco (interno), Altura do Componente Retangular: 3.1 m; EI-REV-Chapisco (interno), Largura do Componente Retangular: 0.005 m; EI-REV-Chapisco (interno), Área de Seção Transversal do Componente: 0.0155 m2; EI-REV-Cerâmica 10x10 Amarela, Altura do Componente Retangular: 0.9 m; EI-REV-Cerâmica 10x10 Amarela, Largura do Componente Retangular: 0.02 m; EI-REV-Cerâmica 10x10 Amarela, Área de Seção Transversal do Componente: 0.018 m2; EI-REV-Cerâmica 10x10 Branca, Altura do Componente Retangular: 0.1 m; EI-REV-Cerâmica 10x10 Branca, Largura do Componente Retangular: 0.02 m; EI-REV-Cerâmica 10x10 Branca, Área de Seção Transversal do Componente: 0.002 m2; EI-REV-Emboço Interno, Área de Seção Transversal do Componente: 0.0155 m2; EI-REV-Massa única - Maior que 10m², Altura do Componente Retangular: 2.06 m; EI-REV-Massa única - Maior que 10m², Largura do Componente Retangular: 0.00500002 m; EI-REV-Massa única - Maior que 10m², Área de Seção Transversal do Componente: 0.0103 m2; EI-REV-Massa Corrida PVA (interna), Altura do Componente Retangular: 2.06 m; EI-REV-Massa Corrida PVA (interna), Largura do Componente Retangular: 0.00499999 m; EI-REV-Massa Corrida PVA (interna), Área de Seção Transversal do Componente: 0.0103 m2; EI-REV-Pintura Acrílica Cor Branco Gelo, Altura do Componente Retangular: 2.06 m; EI-REV-Pintura Acrílica Cor Branco Gelo, Largura do Componente Retangular: 0.01 m; EI-REV-Pintura Acrílica Cor Branco Gelo, Área de Seção Transversal do Componente: 0.0206 m2
Name | 1_Bloco | 0_ID | EI-REV-Chapisco (interno), Massa (kg) | EI-REV-Chapisco (interno), Área de Componente Projetada (Líquida) (m2) = EI-REV-Chapisco (interno), Área de Componente Projetada (Bruta) (m2) | EI-REV-Chapisco (interno), Volume Componente (Líquido) (m3) = EI-REV-Chapisco (interno), Volume do componente (Bruto) (m3) | EI-REV-Cerâmica 10x10 Amarela, Massa (kg) | EI-REV-Cerâmica 10x10 Amarela, Área de Componente Projetada (Líquida) (m2) = EI-REV-Cerâmica 10x10 Amarela, Área de Componente Projetada (Bruta) (m2) | EI-REV-Cerâmica 10x10 Amarela, Volume Componente (Líquido) (m3) = EI-REV-Cerâmica 10x10 Amarela, Volume do componente (Bruto) (m3) | EI-REV-Cerâmica 10x10 Branca, Massa (kg) | EI-REV-Cerâmica 10x10 Branca, Área de Componente Projetada (Líquida) (m2) = EI-REV-Cerâmica 10x10 Branca, Área de Componente Projetada (Bruta) (m2) | EI-REV-Cerâmica 10x10 Branca, Volume Componente (Líquido) (m3) = EI-REV-Cerâmica 10x10 Branca, Volume do componente (Bruto) (m3) | EI-REV-Emboço Interno, Massa (kg) | EI-REV-Emboço Interno, Área de Componente Projetada (Líquida) (m2) = EI-REV-Emboço Interno, Área de Componente Projetada (Bruta) (m2) | EI-REV-Emboço Interno, Volume Componente (Líquido) (m3) = EI-REV-Emboço Interno, Volume do componente (Bruto) (m3) | EI-REV-Massa única - Maior que 10m², Massa (kg) | EI-REV-Massa única - Maior que 10m², Área de Componente Projetada (Líquida) (m2) = EI-REV-Massa única - Maior que 10m², Área de Componente Projetada (Bruta) (m2) | EI-REV-Massa única - Maior que 10m², Volume Componente (Líquido) (m3) = EI-REV-Massa única - Maior que 10m², Volume do componente (Bruto) (m3) | EI-REV-Massa Corrida PVA (interna), Massa (kg) | EI-REV-Massa Corrida PVA (interna), Área de Componente Projetada (Líquida) (m2) = EI-REV-Massa Corrida PVA (interna), Área de Componente Projetada (Bruta) (m2) | EI-REV-Massa Corrida PVA (interna), Volume Componente (Líquido) (m3) = EI-REV-Massa Corrida PVA (interna), Volume do componente (Bruto) (m3) | EI-REV-Pintura Acrílica Cor Branco Gelo, Massa (kg) | EI-REV-Pintura Acrílica Cor Branco Gelo, Área de Componente Projetada (Líquida) (m2) = EI-REV-Pintura Acrílica Cor Branco Gelo, Área de Componente Projetada (Bruta) (m2) | EI-REV-Pintura Acrílica Cor Branco Gelo, Volume Componente (Líquido) (m3) = EI-REV-Pintura Acrílica Cor Branco Gelo, Volume do componente (Bruto) (m3)
AL24 | BLOCO A | AL24 | 0 | 0 | 0 | 2.5067 | 0.198 | 0.00125335 | 0.278522 | 0.022 | 0.000139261 | 0.17355 | 0.0267 | 0.0001335 | 0.215801 | 0.0332 | 0.000166 | 0.362411 | 0.0558 | 0.000278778 | 3.67703 | 0.4944 | 0.00282848
AL20 | BLOCO B | AL20 | 3.991 | 0.614 | 0.00307 | 7.92 | 0.198 | 0.00396 | 0.88 | 0.022 | 0.00044 | 4.19055 | 0.6447 | 0.0032235 | 2.94581 | 0.4532 | 0.00226601 | 3.07969 | 0.4738 | 0.00236899 | 6.4272 | 0.4944 | 0.004944
AL18 | BLOCO B | AL18 | 4.09078 | 0.62935 | 0.00314675 | 8.64 | 0.216 | 0.00432 | 0.96 | 0.024 | 0.00048 | 4.29033 | 0.66005 | 0.00330025 | 3.01276 | 0.4635 | 0.00231751 | 3.14664 | 0.4841 | 0.00242049 | 6.695 | 0.515 | 0.00515
AL17 | BLOCO B | AL17 | 4.15148 | 0.638689 | 0.00319345 | 10.1304 | 0.25326 | 0.00506519 | 1.1256 | 0.0281399 | 0.000562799 | 4.3377 | 0.667339 | 0.00333669 | 2.8735 | 0.442076 | 0.00221039 | 2.99406 | 0.460626 | 0.00230312 | 6.62978 | 0.509983 | 0.00509983
AL19 | BLOCO B | AL19 | 4.06503 | 0.625389 | 0.00312695 | 9.41038 | 0.235259 | 0.00470519 | 1.0456 | 0.0261399 | 0.000522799 | 4.25125 | 0.654039 | 0.00327019 | 2.81988 | 0.433826 | 0.00216914 | 2.94043 | 0.452376 | 0.00226187 | 6.36198 | 0.489383 | 0.00489383
AL21 | BLOCO A | AL21 | 3.42386 | 0.526748 | 0.00263374 | 8.81822 | 0.220456 | 0.00440911 | 0.979802 | 0.0244951 | 0.000489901 | 3.61009 | 0.555398 | 0.00277699 | 2.38517 | 0.366948 | 0.00183475 | 2.50573 | 0.385498 | 0.00192749 | 5.65349 | 0.434883 | 0.00434884
AL22 | BLOCO A | AL22 | 4.09078 | 0.62935 | 0.00314675 | 8.64 | 0.216 | 0.00432 | 0.96 | 0.024 | 0.00048 | 4.29033 | 0.66005 | 0.00330025 | 3.01276 | 0.4635 | 0.00231751 | 3.14664 | 0.4841 | 0.00242049 | 6.695 | 0.515 | 0.00515
AL23 | BLOCO A | AL23 | 3.32409 | 0.511398 | 0.00255699 | 8.09822 | 0.202455 | 0.00404911 | 0.899802 | 0.0224951 | 0.000449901 | 3.51031 | 0.540048 | 0.00270024 | 2.31822 | 0.356648 | 0.00178325 | 2.43878 | 0.375198 | 0.00187599 | 5.33369 | 0.410283 | 0.00410283

# IfcWall: FNDE-PLAT_AL09-Pintura Branca 150 (4)
In: COBERTURA
Classification: Parede (Classificação Archicad); Material: EI-REV-Pintura Acrílica Cor Branco Gelo 0.015 m, EI-REV-Massa Acrílica (externa) 0.005 m, EI-REV-Massa única - Fachada 0.005 m, EI-REV-Chapisco (externo) 0.005 m, TIJOLO - CERAMICO 9x19x39 - espessura 15cm 0.09 m, EI-REV-Chapisco (externo) 0.005 m, EI-REV-Massa única - Fachada 0.005 m, EI-REV-Massa Acrílica (externa) 0.005 m, EI-REV-Pintura Acrílica Cor Branco Gelo 0.015 m
FNDE - Alvenarias: Alvenaria de Vedação / Edificação; Sistemas de Cobertura: PLATIBANDA DE ALVENARIA; Esquadrias - Fechamentos metálicos e Gradis: -; 0_ID: AL09
Pset_WallCommon - IsExternal: yes; LoadBearing: no
Component Quantities - EI-REV-Pintura Acrílica Cor Branco Gelo 1, Espessura do Componente: 0.015 m; EI-REV-Pintura Acrílica Cor Branco Gelo 1, Altura do Componente Retangular: 1.31 m; EI-REV-Pintura Acrílica Cor Branco Gelo 1, Largura do Componente Retangular: 0.015 m; EI-REV-Pintura Acrílica Cor Branco Gelo 1, Área de Seção Transversal do Componente: 0.01965 m2; EI-REV-Massa Acrílica (externa) 1, Espessura do Componente: 0.005 m; EI-REV-Massa Acrílica (externa) 1, Altura do Componente Retangular: 1.31 m; EI-REV-Massa Acrílica (externa) 1, Largura do Componente Retangular: 0.005 m; EI-REV-Massa Acrílica (externa) 1, Área de Seção Transversal do Componente: 0.00655 m2; EI-REV-Massa única - Fachada 1, Espessura do Componente: 0.005 m; EI-REV-Massa única - Fachada 1, Altura do Componente Retangular: 1.31 m; EI-REV-Massa única - Fachada 1, Largura do Componente Retangular: 0.005 m; EI-REV-Massa única - Fachada 1, Área de Seção Transversal do Componente: 0.00655 m2; EI-REV-Chapisco (externo) 1, Espessura do Componente: 0.005 m; EI-REV-Chapisco (externo) 1, Altura do Componente Retangular: 1.31 m; EI-REV-Chapisco (externo) 1, Largura do Componente Retangular: 0.005 m; EI-REV-Chapisco (externo) 1, Área de Seção Transversal do Componente: 0.00655 m2; TIJOLO - CERAMICO 9x19x39 - espessura 15cm, Espessura do Componente: 0.09 m; TIJOLO - CERAMICO 9x19x39 - espessura 15cm, Altura do Componente Retangular: 1.31 m; TIJOLO - CERAMICO 9x19x39 - espessura 15cm, Largura do Componente Retangular: 0.09 m; TIJOLO - CERAMICO 9x19x39 - espessura 15cm, Área de Seção Transversal do Componente: 0.1179 m2; EI-REV-Chapisco (externo) 2, Espessura do Componente: 0.005 m; EI-REV-Chapisco (externo) 2, Altura do Componente Retangular: 1.31 m; EI-REV-Chapisco (externo) 2, Largura do Componente Retangular: 0.005 m; EI-REV-Chapisco (externo) 2, Área de Seção Transversal do Componente: 0.00655 m2; EI-REV-Massa única - Fachada 2, Espessura do Componente: 0.005 m; EI-REV-Massa única - Fachada 2, Altura do Componente Retangular: 1.31 m; EI-REV-Massa única - Fachada 2, Largura do Componente Retangular: 0.005 m; EI-REV-Massa única - Fachada 2, Área de Seção Transversal do Componente: 0.00655 m2; EI-REV-Massa Acrílica (externa) 2, Espessura do Componente: 0.005 m; EI-REV-Massa Acrílica (externa) 2, Altura do Componente Retangular: 1.31 m; EI-REV-Massa Acrílica (externa) 2, Largura do Componente Retangular: 0.005 m; EI-REV-Massa Acrílica (externa) 2, Área de Seção Transversal do Componente: 0.00655 m2; EI-REV-Pintura Acrílica Cor Branco Gelo 2, Espessura do Componente: 0.015 m; EI-REV-Pintura Acrílica Cor Branco Gelo 2, Altura do Componente Retangular: 1.31 m; EI-REV-Pintura Acrílica Cor Branco Gelo 2, Largura do Componente Retangular: 0.015 m; EI-REV-Pintura Acrílica Cor Branco Gelo 2, Área de Seção Transversal do Componente: 0.01965 m2
Name | 1_Bloco | EI-REV-Pintura Acrílica Cor Branco Gelo 1, Massa (kg) | EI-REV-Pintura Acrílica Cor Branco Gelo 1, Área de Componente Projetada (Líquida) (m2) = EI-REV-Pintura Acrílica Cor Branco Gelo 1, Área de Componente Projetada (Bruta) (m2) | EI-REV-Pintura Acrílica Cor Branco Gelo 1, Volume Componente (Líquido) (m3) = EI-REV-Pintura Acrílica Cor Branco Gelo 1, Volume do componente (Bruto) (m3) | EI-REV-Massa Acrílica (externa) 1, Massa (kg) | EI-REV-Massa Acrílica (externa) 1, Área de Componente Projetada (Líquida) (m2) = EI-REV-Massa Acrílica (externa) 1, Área de Componente Projetada (Bruta) (m2) | EI-REV-Massa Acrílica (externa) 1, Volume Componente (Líquido) (m3) = EI-REV-Massa Acrílica (externa) 1, Volume do componente (Bruto) (m3) | EI-REV-Massa única - Fachada 1, Massa (kg) | EI-REV-Massa única - Fachada 1, Área de Componente Projetada (Líquida) (m2) = EI-REV-Massa única - Fachada 1, Área de Componente Projetada (Bruta) (m2) | EI-REV-Massa única - Fachada 1, Volume Componente (Líquido) (m3) = EI-REV-Massa única - Fachada 1, Volume do componente (Bruto) (m3) | EI-REV-Chapisco (externo) 1, Massa (kg) | EI-REV-Chapisco (externo) 1, Área de Componente Projetada (Líquida) (m2) = EI-REV-Chapisco (externo) 1, Área de Componente Projetada (Bruta) (m2) | EI-REV-Chapisco (externo) 1, Volume Componente (Líquido) (m3) = EI-REV-Chapisco (externo) 1, Volume do componente (Bruto) (m3) | TIJOLO - CERAMICO 9x19x39 - espessura 15cm, Massa (kg) | TIJOLO - CERAMICO 9x19x39 - espessura 15cm, Área de Componente Projetada (Líquida) (m2) = TIJOLO - CERAMICO 9x19x39 - espessura 15cm, Área de Componente Projetada (Bruta) (m2) | TIJOLO - CERAMICO 9x19x39 - espessura 15cm, Volume Componente (Líquido) (m3) = TIJOLO - CERAMICO 9x19x39 - espessura 15cm, Volume do componente (Bruto) (m3) | EI-REV-Chapisco (externo) 2, Massa (kg) | EI-REV-Chapisco (externo) 2, Área de Componente Projetada (Líquida) (m2) = EI-REV-Chapisco (externo) 2, Área de Componente Projetada (Bruta) (m2) | EI-REV-Chapisco (externo) 2, Volume Componente (Líquido) (m3) = EI-REV-Chapisco (externo) 2, Volume do componente (Bruto) (m3) | EI-REV-Massa única - Fachada 2, Massa (kg) | EI-REV-Massa única - Fachada 2, Área de Componente Projetada (Líquida) (m2) = EI-REV-Massa única - Fachada 2, Área de Componente Projetada (Bruta) (m2) | EI-REV-Massa única - Fachada 2, Volume Componente (Líquido) (m3) = EI-REV-Massa única - Fachada 2, Volume do componente (Bruto) (m3) | EI-REV-Massa Acrílica (externa) 2, Massa (kg) | EI-REV-Massa Acrílica (externa) 2, Área de Componente Projetada (Líquida) (m2) = EI-REV-Massa Acrílica (externa) 2, Área de Componente Projetada (Bruta) (m2) | EI-REV-Massa Acrílica (externa) 2, Volume Componente (Líquido) (m3) = EI-REV-Massa Acrílica (externa) 2, Volume do componente (Bruto) (m3) | EI-REV-Pintura Acrílica Cor Branco Gelo 2, Massa (kg) | EI-REV-Pintura Acrílica Cor Branco Gelo 2, Área de Componente Projetada (Líquida) (m2) = EI-REV-Pintura Acrílica Cor Branco Gelo 2, Área de Componente Projetada (Bruta) (m2) | EI-REV-Pintura Acrílica Cor Branco Gelo 2, Volume Componente (Líquido) (m3) = EI-REV-Pintura Acrílica Cor Branco Gelo 2, Volume do componente (Bruto) (m3)
AL09 | BLOCO B | 22.7035 | 1.32947 | 0.0174643 | 6.9184 | 1.06437 | 0.00532185 | 6.90865 | 1.06287 | 0.00531435 | 6.8989 | 1.06137 | 0.00530685 | 50.061 | 0.87142 | 0.0772546 | 6.54033 | 1.0062 | 0.00503102 | 6.58258 | 1.0127 | 0.00506352 | 6.62394 | 1.01907 | 0.00509534 | 22.031 | 1.32913 | 0.0169469
AL09 | BLOCO B | 22.2524 | 1.31 | 0.0171172 | 6.85751 | 1.055 | 0.00527501 | 6.84775 | 1.0535 | 0.0052675 | 6.838 | 1.052 | 0.00526 | 50.6463 | 0.868599 | 0.0781579 | 6.59202 | 1.01416 | 0.00507079 | 6.60177 | 1.01566 | 0.00507829 | 6.61152 | 1.01716 | 0.00508579 | 21.7877 | 1.30966 | 0.0167597
AL09 | BLOCO A | 22.2573 | 1.31 | 0.017121 | 5.69392 | 0.875987 | 0.00437994 | 5.68417 | 0.874487 | 0.00437244 | 5.67442 | 0.872987 | 0.00436494 | 50.0658 | 0.858644 | 0.077262 | 6.5402 | 1.00619 | 0.00503093 | 6.58217 | 1.01264 | 0.00506321 | 6.59192 | 1.01414 | 0.00507071 | 21.7665 | 1.30966 | 0.0167435
AL09 | BLOCO A | 22.4931 | 1.30992 | 0.0173024 | 6.6245 | 1.0549 | 0.00509577 | 6.57409 | 1.0114 | 0.00505699 | 6.56458 | 1.00993 | 0.00504967 | 50.6426 | 0.868535 | 0.0781521 | 6.57221 | 1.01111 | 0.00505555 | 6.58196 | 1.01261 | 0.00506305 | 6.59171 | 1.01411 | 0.00507055 | 21.463 | 1.30957 | 0.01651

# IfcWall: FNDE-PLAT_AL14-E4 (Pintura vermelha) 200 (3)
In: COBERTURA
Classification: Parede (Classificação Archicad); Material: EI-REV-Pintura Acrílica Cor Vermelho Externa 0.015 m, EI-REV-Massa Acrílica (externa) 0.005 m, EI-REV-Massa única - Fachada 0.005 m, EI-REV-Chapisco (externo) 0.005 m, TIJOLO - CERAMICO 14x19x39 - espessura 20cm 0.14 m, EI-REV-Chapisco (externo) 0.005 m, EI-REV-Massa única - Fachada 0.005 m, EI-REV-Massa Acrílica (externa) 0.005 m, EI-REV-Pintura Acrílica Cor Branco Gelo 0.015 m
FNDE - Alvenarias: Alvenaria de Vedação / Edificação; Sistemas de Cobertura: PÓRTICO DO ACESSO PRINCIPAL; Esquadrias - Fechamentos metálicos e Gradis: -; 1_Bloco: BLOCO A; 0_ID: AL14
Pset_WallCommon - IsExternal: yes; LoadBearing: no
Component Quantities - EI-REV-Pintura Acrílica Cor Vermelho Externa, Espessura do Componente: 0.015 m; EI-REV-Pintura Acrílica Cor Vermelho Externa, Altura do Componente Retangular: 1.32 m; EI-REV-Pintura Acrílica Cor Vermelho Externa, Largura do Componente Retangular: 0.015 m; EI-REV-Pintura Acrílica Cor Vermelho Externa, Área de Seção Transversal do Componente: 0.0198 m2; EI-REV-Massa Acrílica (externa) 1, Espessura do Componente: 0.005 m; EI-REV-Massa Acrílica (externa) 1, Altura do Componente Retangular: 1.32 m; EI-REV-Massa Acrílica (externa) 1, Largura do Componente Retangular: 0.005 m; EI-REV-Massa Acrílica (externa) 1, Área de Seção Transversal do Componente: 0.0066 m2; TIJOLO - CERAMICO 14x19x39 - espessura 20cm, Espessura do Componente: 0.14 m; TIJOLO - CERAMICO 14x19x39 - espessura 20cm, Altura do Componente Retangular: 1.32 m; TIJOLO - CERAMICO 14x19x39 - espessura 20cm, Largura do Componente Retangular: 0.14 m; TIJOLO - CERAMICO 14x19x39 - espessura 20cm, Área de Seção Transversal do Componente: 0.1848 m2; EI-REV-Chapisco (externo) 2, Espessura do Componente: 0.005 m; EI-REV-Chapisco (externo) 2, Altura do Componente Retangular: 1.32 m; EI-REV-Chapisco (externo) 2, Largura do Componente Retangular: 0.005 m; EI-REV-Chapisco (externo) 2, Área de Seção Transversal do Componente: 0.0066 m2; EI-REV-Pintura Acrílica Cor Branco Gelo, Espessura do Componente: 0.015 m; EI-REV-Pintura Acrílica Cor Branco Gelo, Altura do Componente Retangular: 1.32 m; EI-REV-Pintura Acrílica Cor Branco Gelo, Largura do Componente Retangular: 0.015 m; EI-REV-Pintura Acrílica Cor Branco Gelo, Área de Seção Transversal do Componente: 0.0198 m2
Name | EI-REV-Pintura Acrílica Cor Vermelho Externa, Massa (kg) | EI-REV-Pintura Acrílica Cor Vermelho Externa, Área de Componente Projetada (Líquida) (m2) = EI-REV-Pintura Acrílica Cor Vermelho Externa, Área de Componente Projetada (Bruta) (m2) | EI-REV-Pintura Acrílica Cor Vermelho Externa, Volume Componente (Líquido) (m3) = EI-REV-Pintura Acrílica Cor Vermelho Externa, Volume do componente (Bruto) (m3) | EI-REV-Massa Acrílica (externa) 1, Massa (kg) | EI-REV-Massa Acrílica (externa) 1, Área de Componente Projetada (Líquida) (m2) = EI-REV-Massa Acrílica (externa) 1, Área de Componente Projetada (Bruta) (m2) | EI-REV-Massa Acrílica (externa) 1, Volume Componente (Líquido) (m3) = EI-REV-Massa Acrílica (externa) 1, Volume do componente (Bruto) (m3) | EI-REV-Massa única - Fachada 1, Massa (kg) | EI-REV-Massa única - Fachada 1, Área de Componente Projetada (Líquida) (m2) = EI-REV-Massa única - Fachada 1, Área de Componente Projetada (Bruta) (m2) | EI-REV-Massa única - Fachada 1, Espessura do Componente (m) = EI-REV-Massa única - Fachada 1, Largura do Componente Retangular (m) = EI-REV-Chapisco (externo) 1, Espessura do Componente (m) = EI-REV-Chapisco (externo) 1, Largura do Componente Retangular (m) | EI-REV-Massa única - Fachada 1, Altura do Componente Retangular (m) = EI-REV-Chapisco (externo) 1, Altura do Componente Retangular (m) | EI-REV-Massa única - Fachada 1, Área de Seção Transversal do Componente (m2) = EI-REV-Chapisco (externo) 1, Área de Seção Transversal do Componente (m2) | EI-REV-Massa única - Fachada 1, Volume Componente (Líquido) (m3) = EI-REV-Massa única - Fachada 1, Volume do componente (Bruto) (m3) | EI-REV-Chapisco (externo) 1, Massa (kg) | EI-REV-Chapisco (externo) 1, Área de Componente Projetada (Líquida) (m2) = EI-REV-Chapisco (externo) 1, Área de Componente Projetada (Bruta) (m2) | EI-REV-Chapisco (externo) 1, Volume Componente (Líquido) (m3) = EI-REV-Chapisco (externo) 1, Volume do componente (Bruto) (m3) | TIJOLO - CERAMICO 14x19x39 - espessura 20cm, Massa (kg) | TIJOLO - CERAMICO 14x19x39 - espessura 20cm, Área de Componente Projetada (Líquida) (m2) = TIJOLO - CERAMICO 14x19x39 - espessura 20cm, Área de Componente Projetada (Bruta) (m2) | TIJOLO - CERAMICO 14x19x39 - espessura 20cm, Volume Componente (Líquido) (m3) = TIJOLO - CERAMICO 14x19x39 - espessura 20cm, Volume do componente (Bruto) (m3) | EI-REV-Chapisco (externo) 2, Massa (kg) | EI-REV-Chapisco (externo) 2, Área de Componente Projetada (Líquida) (m2) = EI-REV-Chapisco (externo) 2, Área de Componente Projetada (Bruta) (m2) | EI-REV-Chapisco (externo) 2, Volume Componente (Líquido) (m3) = EI-REV-Chapisco (externo) 2, Volume do componente (Bruto) (m3) | EI-REV-Pintura Acrílica Cor Branco Gelo, Massa (kg) | EI-REV-Pintura Acrílica Cor Branco Gelo, Área de Componente Projetada (Líquida) (m2) = EI-REV-Pintura Acrílica Cor Branco Gelo, Área de Componente Projetada (Bruta) (m2) | EI-REV-Pintura Acrílica Cor Branco Gelo, Volume Componente (Líquido) (m3) = EI-REV-Pintura Acrílica Cor Branco Gelo, Volume do componente (Bruto) (m3) | EI-REV-Chapisco (externo) 2
AL14 | 26.2561 | 1.34647 | 0.020197 | 8.8803 | 1.3662 | 0.006831 | 8.88062 | 1.36625 | 0.005 | 1.32 | 0.0066 | 0.00683125 | 8.88095 | 1.3663 | 0.0068315 | 75.8613 | 1.36635 | 0.11707 | 4.50612 | 0.693249 | 0.00346624 | 13.6809 | 1.16346 | 0.0105238 | 3 with these values
AL14 | 33.8481 | 1.7358 | 0.026037 | 11.3256 | 1.7424 | 0.008712 | 11.3685 | 1.749 | 0.005 | 1.32 | 0.0066 | 0.008745 | 11.4113 | 1.75558 | 0.00877789 | 105.174 | 1.8844 | 0.162306 | 5.89684 | 0.907206 | 0.00453603 | 18.3145 | 1.75525 | 0.0140881 | Component Quantities - EI-REV-Massa única - Fachada 2, Massa: 5.90594 kg; EI-REV-Massa única - Fachada 2, Área de Componente Projetada (Líquida): 0.908606 m2; EI-REV-Massa única - Fachada 2, Área de Componente Projetada (Bruta): 0.908606 m2; EI-REV-Massa única - Fachada 2, Espessura do Componente: 0.005 m; EI-REV-Massa única - Fachada 2, Altura do Componente Retangular: 1.32 m; EI-REV-Massa única - Fachada 2, Largura do Componente Retangular: 0.005 m; EI-REV-Massa única - Fachada 2, Área de Seção Transversal do Componente: 0.0066 m2; EI-REV-Massa única - Fachada 2, Volume Componente (Líquido): 0.00454303 m3; EI-REV-Massa única - Fachada 2, Volume do componente (Bruto): 0.00454303 m3; EI-REV-Massa Acrílica (externa) 2, Massa: 5.91504 kg; EI-REV-Massa Acrílica (externa) 2, Área de Componente Projetada (Líquida): 0.910006 m2; EI-REV-Massa Acrílica (externa) 2, Área de Componente Projetada (Bruta): 0.910006 m2; EI-REV-Massa Acrílica (externa) 2, Espessura do Componente: 0.005 m; EI-REV-Massa Acrílica (externa) 2, Altura do Componente Retangular: 1.32 m; EI-REV-Massa Acrílica (externa) 2, Largura do Componente Retangular: 0.005 m; EI-REV-Massa Acrílica (externa) 2, Área de Seção Transversal do Componente: 0.0066 m2; EI-REV-Massa Acrílica (externa) 2, Volume Componente (Líquido): 0.00455003 m3; EI-REV-Massa Acrílica (externa) 2, Volume do componente (Bruto): 0.00455003 m3
AL14 | 158.301 | 8.118 | 0.12177 | 52.767 | 8.118 | 0.04059 |  |  |  |  |  |  |  |  |  | 368.834 | 8.118 | 0.569188 | 20.7728 | 3.19582 | 0.0159791 | 63.6572 | 8.08507 | 0.0489671 | 3 with these values | Component Quantities - EI-REV-Massa Acrílica (externa) 1: 3 with these values

# IfcWall: FNDE-PLAT_AL14-Pintura Azul - Branca 200 (12)
In: COBERTURA
Classification: Parede (Classificação Archicad); Material: EI-REV-Pintura Acrílica Cor Azul Externa 0.015 m, EI-REV-Massa Acrílica (externa) 0.005 m, EI-REV-Massa única - Fachada 0.005 m, EI-REV-Chapisco (externo) 0.005 m, TIJOLO - CERAMICO 14x19x39 - espessura 20cm 0.14 m, EI-REV-Chapisco (externo) 0.005 m, EI-REV-Massa única - Fachada 0.005 m, EI-REV-Massa Acrílica (externa) 0.005 m, EI-REV-Pintura Acrílica Cor Branco Gelo 0.015 m
FNDE - Alvenarias: Alvenaria de Vedação / Edificação; Sistemas de Cobertura: PLATIBANDA DE ALVENARIA; Esquadrias - Fechamentos metálicos e Gradis: -; 0_ID: AL14
Pset_WallCommon - IsExternal: yes; LoadBearing: no
Component Quantities - EI-REV-Pintura Acrílica Cor Azul Externa, Espessura do Componente: 0.015 m; EI-REV-Pintura Acrílica Cor Azul Externa, Altura do Componente Retangular: 1.51 m; EI-REV-Pintura Acrílica Cor Azul Externa, Largura do Componente Retangular: 0.015 m; EI-REV-Pintura Acrílica Cor Azul Externa, Área de Seção Transversal do Componente: 0.02265 m2; EI-REV-Massa Acrílica (externa) 1, Espessura do Componente: 0.005 m; EI-REV-Massa Acrílica (externa) 1, Altura do Componente Retangular: 1.51 m; EI-REV-Massa Acrílica (externa) 1, Largura do Componente Retangular: 0.005 m; EI-REV-Massa Acrílica (externa) 1, Área de Seção Transversal do Componente: 0.00755 m2; EI-REV-Massa única - Fachada 1, Espessura do Componente: 0.005 m; EI-REV-Massa única - Fachada 1, Altura do Componente Retangular: 1.51 m; EI-REV-Massa única - Fachada 1, Largura do Componente Retangular: 0.005 m; EI-REV-Massa única - Fachada 1, Área de Seção Transversal do Componente: 0.00755 m2; EI-REV-Chapisco (externo) 1, Espessura do Componente: 0.005 m; EI-REV-Chapisco (externo) 1, Altura do Componente Retangular: 1.51 m; EI-REV-Chapisco (externo) 1, Largura do Componente Retangular: 0.005 m; EI-REV-Chapisco (externo) 1, Área de Seção Transversal do Componente: 0.00755 m2; TIJOLO - CERAMICO 14x19x39 - espessura 20cm, Espessura do Componente: 0.14 m; TIJOLO - CERAMICO 14x19x39 - espessura 20cm, Altura do Componente Retangular: 1.51 m; TIJOLO - CERAMICO 14x19x39 - espessura 20cm, Largura do Componente Retangular: 0.14 m; TIJOLO - CERAMICO 14x19x39 - espessura 20cm, Área de Seção Transversal do Componente: 0.2114 m2; EI-REV-Chapisco (externo) 2, Espessura do Componente: 0.005 m; EI-REV-Chapisco (externo) 2, Altura do Componente Retangular: 1.51 m; EI-REV-Chapisco (externo) 2, Largura do Componente Retangular: 0.005 m; EI-REV-Chapisco (externo) 2, Área de Seção Transversal do Componente: 0.00755 m2; EI-REV-Massa única - Fachada 2, Espessura do Componente: 0.005 m; EI-REV-Massa única - Fachada 2, Altura do Componente Retangular: 1.51 m; EI-REV-Massa única - Fachada 2, Largura do Componente Retangular: 0.005 m; EI-REV-Massa única - Fachada 2, Área de Seção Transversal do Componente: 0.00755 m2; EI-REV-Massa Acrílica (externa) 2, Espessura do Componente: 0.005 m; EI-REV-Massa Acrílica (externa) 2, Altura do Componente Retangular: 1.51 m; EI-REV-Massa Acrílica (externa) 2, Largura do Componente Retangular: 0.005 m; EI-REV-Massa Acrílica (externa) 2, Área de Seção Transversal do Componente: 0.00755 m2; EI-REV-Pintura Acrílica Cor Branco Gelo, Espessura do Componente: 0.015 m; EI-REV-Pintura Acrílica Cor Branco Gelo, Altura do Componente Retangular: 1.51 m; EI-REV-Pintura Acrílica Cor Branco Gelo, Largura do Componente Retangular: 0.015 m; EI-REV-Pintura Acrílica Cor Branco Gelo, Área de Seção Transversal do Componente: 0.02265 m2
Name | 1_Bloco | EI-REV-Pintura Acrílica Cor Azul Externa, Massa (kg) | EI-REV-Pintura Acrílica Cor Azul Externa, Área de Componente Projetada (Líquida) (m2) = EI-REV-Pintura Acrílica Cor Azul Externa, Área de Componente Projetada (Bruta) (m2) | EI-REV-Pintura Acrílica Cor Azul Externa, Volume Componente (Líquido) (m3) = EI-REV-Pintura Acrílica Cor Azul Externa, Volume do componente (Bruto) (m3) | EI-REV-Massa Acrílica (externa) 1, Massa (kg) | EI-REV-Massa Acrílica (externa) 1, Área de Componente Projetada (Líquida) (m2) | EI-REV-Massa Acrílica (externa) 1, Área de Componente Projetada (Bruta) (m2) | EI-REV-Massa Acrílica (externa) 1, Volume Componente (Líquido) (m3) | EI-REV-Massa Acrílica (externa) 1, Volume do componente (Bruto) (m3) | EI-REV-Massa única - Fachada 1, Massa (kg) | EI-REV-Massa única - Fachada 1, Área de Componente Projetada (Líquida) (m2) | EI-REV-Massa única - Fachada 1, Área de Componente Projetada (Bruta) (m2) | EI-REV-Massa única - Fachada 1, Volume Componente (Líquido) (m3) | EI-REV-Massa única - Fachada 1, Volume do componente (Bruto) (m3) | EI-REV-Chapisco (externo) 1, Massa (kg) | EI-REV-Chapisco (externo) 1, Área de Componente Projetada (Líquida) (m2) | EI-REV-Chapisco (externo) 1, Área de Componente Projetada (Bruta) (m2) | EI-REV-Chapisco (externo) 1, Volume Componente (Líquido) (m3) | EI-REV-Chapisco (externo) 1, Volume do componente (Bruto) (m3) | TIJOLO - CERAMICO 14x19x39 - espessura 20cm, Massa (kg) | TIJOLO - CERAMICO 14x19x39 - espessura 20cm, Área de Componente Projetada (Líquida) (m2) | TIJOLO - CERAMICO 14x19x39 - espessura 20cm, Área de Componente Projetada (Bruta) (m2) | TIJOLO - CERAMICO 14x19x39 - espessura 20cm, Volume Componente (Líquido) (m3) | TIJOLO - CERAMICO 14x19x39 - espessura 20cm, Volume do componente (Bruto) (m3) | EI-REV-Chapisco (externo) 2, Massa (kg) | EI-REV-Chapisco (externo) 2, Área de Componente Projetada (Líquida) (m2) | EI-REV-Chapisco (externo) 2, Área de Componente Projetada (Bruta) (m2) | EI-REV-Chapisco (externo) 2, Volume Componente (Líquido) (m3) | EI-REV-Chapisco (externo) 2, Volume do componente (Bruto) (m3) | EI-REV-Massa única - Fachada 2, Massa (kg) | EI-REV-Massa única - Fachada 2, Área de Componente Projetada (Líquida) (m2) | EI-REV-Massa única - Fachada 2, Área de Componente Projetada (Bruta) (m2) | EI-REV-Massa única - Fachada 2, Volume Componente (Líquido) (m3) | EI-REV-Massa única - Fachada 2, Volume do componente (Bruto) (m3) | EI-REV-Massa Acrílica (externa) 2, Massa (kg) | EI-REV-Massa Acrílica (externa) 2, Área de Componente Projetada (Líquida) (m2) | EI-REV-Massa Acrílica (externa) 2, Área de Componente Projetada (Bruta) (m2) | EI-REV-Massa Acrílica (externa) 2, Volume Componente (Líquido) (m3) | EI-REV-Massa Acrílica (externa) 2, Volume do componente (Bruto) (m3) | EI-REV-Pintura Acrílica Cor Branco Gelo, Massa (kg) | EI-REV-Pintura Acrílica Cor Branco Gelo, Área de Componente Projetada (Líquida) (m2) | EI-REV-Pintura Acrílica Cor Branco Gelo, Área de Componente Projetada (Bruta) (m2) | EI-REV-Pintura Acrílica Cor Branco Gelo, Volume Componente (Líquido) (m3) | EI-REV-Pintura Acrílica Cor Branco Gelo, Volume do componente (Bruto) (m3)
AL14 | BLOCO B | 11.8514 | 0.607764 | 0.00911646 | 3.68361 | 0.567035 | 0.596714 | 0.00283355 | 0.00298181 | 1.57112 | 0.241707 | 0.264299 | 0.00120855 | 0.00132011 | 1.53475 | 0.236115 | 0.258707 | 0.00118058 | 0.00129353 | 20.9169 | 0.230565 | 0.253158 | 0.0322791 | 0.0354421 | 0.488574 | 0.0751652 | 0.0977567 | 0.000375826 | 0.000488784 | 0.452499 | 0.0696152 | 0.0922067 | 0.000348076 | 0.000461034 | 0.416749 | 0.0641152 | 0.0866567 | 0.000320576 | 0.000433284 | 7.25559 | 0.5285 | 0.551149 | 0.00558122 | 0.00592016
AL14 | BLOCO B | 84.9477 | 4.35629 | 0.0653444 | 28.1196 | 4.32609 | 4.32609 | 0.0216305 | 0.0216305 | 20.754 | 4.31099 | 4.31099 | 0.0159646 | 0.0159646 | 20.5264 | 3.15791 | 3.15791 | 0.0157895 | 0.0157895 | 278.428 | 4.02097 | 4.02097 | 0.429673 | 0.429673 | 25.0344 | 3.85144 | 3.85144 | 0.0192572 | 0.0192572 | 24.9492 | 3.83834 | 3.83834 | 0.0191917 | 0.0191917 | 24.8641 | 3.82524 | 3.82524 | 0.0191262 | 0.0191262 | 74.036 | 3.79704 | 3.79704 | 0.0569508 | 0.0569508
AL14 | BLOCO B | 10.8486 | 0.585141 | 0.00834508 | 1.57203 | 0.241707 | 0.264291 | 0.00120926 | 0.00132097 | 1.53475 | 0.236115 | 0.2587 | 0.00118058 | 0.0012935 | 1.49867 | 0.230565 | 0.25315 | 0.00115283 | 0.00126575 | 11.3859 | 0.536056 | 0.573806 | 0.0175708 | 0.0209611 | 3.43529 | 0.528507 | 0.566255 | 0.00264253 | 0.00283128 | 3.38622 | 0.520957 | 0.558706 | 0.00260479 | 0.00279353 | 3.38622 | 0.520958 | 0.551156 | 0.00260479 | 0.00275578 | 9.86396 | 0.505859 | 0.528508 | 0.00758766 | 0.00792738
AL14 | BLOCO B | 84.9479 | 4.3563 | 0.0653445 | 28.1197 | 4.3261 | 4.3261 | 0.0216305 | 0.0216305 | 28.0215 | 4.311 | 4.311 | 0.021555 | 0.021555 | 27.9234 | 4.2959 | 4.2959 | 0.0214795 | 0.0214795 | 274.523 | 4.07696 | 4.07696 | 0.423647 | 0.423647 | 20.0185 | 3.85745 | 3.85745 | 0.0153989 | 0.0153989 | 24.9752 | 3.84235 | 3.84235 | 0.0192117 | 0.0192117 | 24.8771 | 3.82725 | 3.82725 | 0.0191362 | 0.0191362 | 74.0255 | 3.79705 | 3.79705 | 0.0569427 | 0.0569427
AL14 | BLOCO B | 11.4096 | 0.585107 | 0.00877664 | 1.90521 | 0.293167 | 0.324376 | 0.00146555 | 0.00162077 | 1.85651 | 0.285617 | 0.323376 | 0.00142809 | 0.00161688 | 1.8479 | 0.284627 | 0.322377 | 0.00142146 | 0.00161021 | 6.34769 | 0.0845437 | 0.122294 | 0.00979582 | 0.0150808 | 0.510293 | 0.0785068 | 0.116257 | 0.000392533 | 0.000581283 | 0.461221 | 0.0709573 | 0.108707 | 0.000354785 | 0.000543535 | 0.466688 | 0.520958 | 0.551158 | 0.000358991 | 0.000509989 | 9.86393 | 0.505859 | 0.528509 | 0.00758764 | 0.00792738
AL14 | BLOCO B | 11.8513 | 0.607759 | 0.00911639 | 3.68573 | 0.567035 | 0.596709 | 0.00283517 | 0.00298349 | 1.90464 | 0.293052 | 0.330797 | 0.0014651 | 0.00165376 | 1.89834 | 0.292052 | 0.329797 | 0.00146026 | 0.00164898 | 20.8155 | 0.29745 | 0.3352 | 0.0321227 | 0.0374077 | 0.455058 | 0.0700081 | 0.107752 | 0.000350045 | 0.000538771 | 0.51025 | 0.0785 | 0.116244 | 0.0003925 | 0.000581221 | 0.51025 | 0.0785 | 0.108694 | 0.0003925 | 0.000543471 | 7.38156 | 0.5285 | 0.551144 | 0.00567812 | 0.00601778
AL14 | BLOCO A | 14.9341 | 0.765849 | 0.0114877 | 2.16453 | 0.723493 | 0.758299 | 0.00166502 | 0.00178106 | 2.07814 | 0.319713 | 0.342749 | 0.00159857 | 0.00171375 | 2.02906 | 0.312163 | 0.335199 | 0.00156082 | 0.001676 | 6.8025 | 0.100763 | 0.1238 | 0.0104977 | 0.0137228 | 0.582573 | 0.0932134 | 0.116249 | 0.000448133 | 0.000563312 | 0.556812 | 0.0856634 | 0.108699 | 0.000428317 | 0.000543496 | 0.508062 | 0.0781634 | 0.101149 | 0.000390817 | 0.000505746 | 9.82165 | 0.50585 | 0.528499 | 0.00755512 | 0.00789485
AL14 | BLOCO A | 14.9335 | 0.765849 | 0.0114873 | 2.12821 | 0.327263 | 0.350299 | 0.00163708 | 0.00175079 | 2.07814 | 0.319713 | 0.342749 | 0.00159857 | 0.00171375 | 1.95399 | 0.312155 | 0.335191 | 0.00150307 | 0.00161825 | 6.8013 | 0.100763 | 0.1238 | 0.0104958 | 0.013721 | 0.605887 | 0.0932134 | 0.116249 | 0.000466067 | 0.000581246 | 0.556812 | 0.0856634 | 0.108699 | 0.000428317 | 0.000543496 | 0.508479 | 0.0781634 | 0.101149 | 0.000391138 | 0.000506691 | 9.86319 | 0.50585 | 0.528499 | 0.00758707 | 0.00792678
AL14 | BLOCO A | 85.3925 | 4.3791 | 0.0656865 | 28.1697 | 4.3338 | 4.3338 | 0.021669 | 0.021669 | 28.0716 | 4.3187 | 4.3187 | 0.0215935 | 0.0215935 | 27.978 | 4.3036 | 4.3036 | 0.0215216 | 0.0215216 | 285.988 | 3.15276 | 3.15276 | 0.44134 | 0.44134 | 25.1185 | 3.86484 | 3.86484 | 0.019322 | 0.019322 | 25.0252 | 3.85003 | 3.85003 | 0.0192502 | 0.0192502 | 24.9271 | 3.83493 | 3.83493 | 0.0191747 | 0.0191747 | 74.4839 | 3.81983 | 3.81983 | 0.0572953 | 0.0572953
AL14 | BLOCO A | 85.3544 | 4.37896 | 0.0656572 | 20.7848 | 3.19766 | 3.19766 | 0.0159883 | 0.0159883 | 20.6866 | 3.18256 | 3.18256 | 0.0159128 | 0.0159128 | 20.5885 | 3.16746 | 3.16746 | 0.0158373 | 0.0158373 | 295.956 | 4.17665 | 4.17665 | 0.456722 | 0.456722 | 25.1205 | 3.8647 | 3.8647 | 0.0193235 | 0.0193235 | 25.0243 | 3.84989 | 3.84989 | 0.0192494 | 0.0192494 | 24.9261 | 3.83479 | 3.83479 | 0.0191739 | 0.0191739 | 74.4814 | 3.81969 | 3.81969 | 0.0572934 | 0.0572934
AL14 | BLOCO A | 14.9341 | 0.76585 | 0.0114877 | 2.44643 | 0.723573 | 0.7583 | 0.00188187 | 0.00200248 | 2.08074 | 0.320114 | 0.34275 | 0.00160057 | 0.00171375 | 2.03167 | 0.312564 | 0.3352 | 0.00156282 | 0.001676 | 6.8282 | 0.101164 | 0.1238 | 0.0105373 | 0.0137064 | 0.586151 | 0.0936142 | 0.11625 | 0.000450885 | 0.000564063 | 0.559417 | 0.0860642 | 0.1087 | 0.000430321 | 0.000543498 | 0.510667 | 0.0785642 | 0.10115 | 0.000392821 | 0.000505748 | 9.50386 | 0.50585 | 0.5285 | 0.00731066 | 0.00765033
AL14 | BLOCO A | 14.5395 | 0.765849 | 0.0111842 | 2.12982 | 0.327664 | 0.350299 | 0.00163832 | 0.0017515 | 2.08074 | 0.320114 | 0.342749 | 0.00160057 | 0.00171375 | 1.95229 | 0.312564 | 0.335199 | 0.00150176 | 0.00161494 | 6.82869 | 0.101164 | 0.1238 | 0.0105381 | 0.0137071 | 0.608492 | 0.0936142 | 0.11625 | 0.000468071 | 0.000581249 | 0.559417 | 0.0860642 | 0.1087 | 0.000430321 | 0.000543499 | 0.938503 | 0.52095 | 0.55115 | 0.000721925 | 0.000840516 | 9.86381 | 0.50585 | 0.5285 | 0.00758754 | 0.00792728

# IfcWall: FNDE-PLAT_AL14-Pintura Branca 200 (29)
In: COBERTURA
Classification: Parede (Classificação Archicad); Material: EI-REV-Pintura Acrílica Cor Branco Gelo 0.015 m, EI-REV-Massa Acrílica (externa) 0.005 m, EI-REV-Massa única - Fachada 0.005 m, EI-REV-Chapisco (externo) 0.005 m, TIJOLO - CERAMICO 14x19x39 - espessura 20cm 0.14 m, EI-REV-Chapisco (externo) 0.005 m, EI-REV-Massa única - Fachada 0.005 m, EI-REV-Massa Acrílica (externa) 0.005 m, EI-REV-Pintura Acrílica Cor Branco Gelo 0.015 m
FNDE - Alvenarias: Alvenaria de Vedação / Edificação; Sistemas de Cobertura: PLATIBANDA DE ALVENARIA; Esquadrias - Fechamentos metálicos e Gradis: -; 0_ID: AL14
Pset_WallCommon - IsExternal: yes; LoadBearing: no
Component Quantities - EI-REV-Pintura Acrílica Cor Branco Gelo 1, Espessura do Componente: 0.015 m; EI-REV-Pintura Acrílica Cor Branco Gelo 1, Largura do Componente Retangular: 0.015 m; EI-REV-Massa Acrílica (externa) 1, Espessura do Componente: 0.005 m; EI-REV-Massa Acrílica (externa) 1, Largura do Componente Retangular: 0.005 m; TIJOLO - CERAMICO 14x19x39 - espessura 20cm, Espessura do Componente: 0.14 m; TIJOLO - CERAMICO 14x19x39 - espessura 20cm, Largura do Componente Retangular: 0.14 m; EI-REV-Chapisco (externo) 2, Espessura do Componente: 0.005 m; EI-REV-Chapisco (externo) 2, Largura do Componente Retangular: 0.005 m; EI-REV-Massa Acrílica (externa) 2, Espessura do Componente: 0.005 m; EI-REV-Massa Acrílica (externa) 2, Largura do Componente Retangular: 0.005 m; EI-REV-Pintura Acrílica Cor Branco Gelo 2, Espessura do Componente: 0.015 m; EI-REV-Pintura Acrílica Cor Branco Gelo 2, Largura do Componente Retangular: 0.015 m
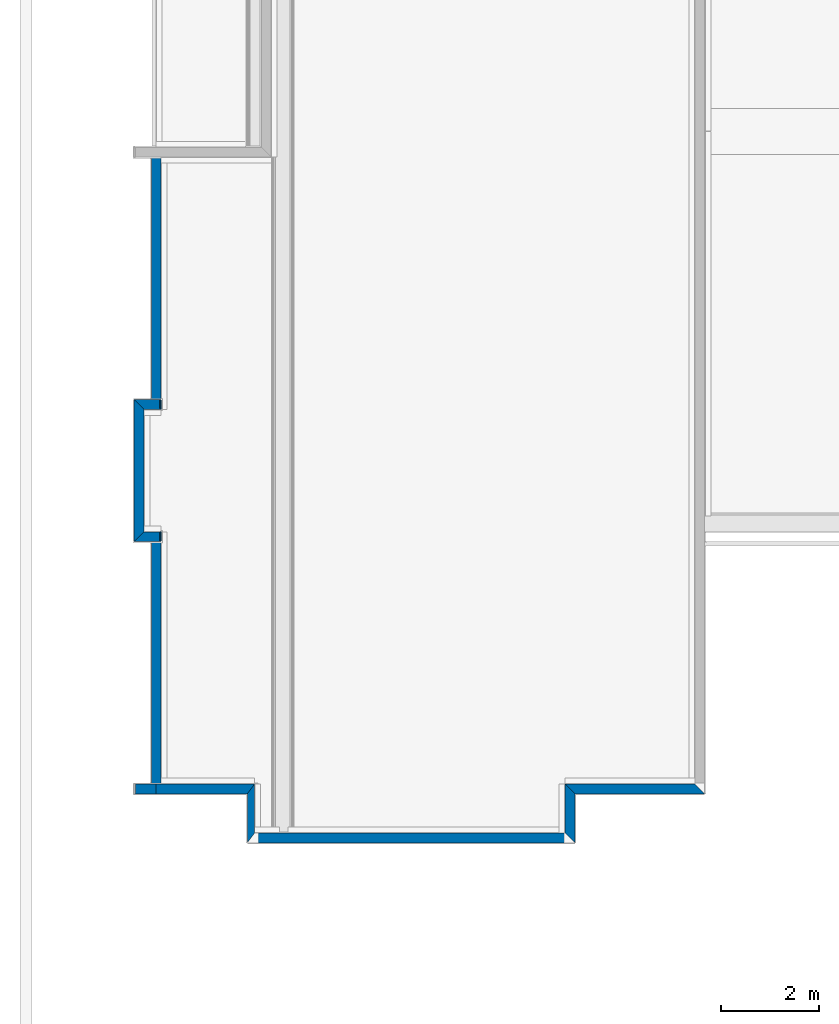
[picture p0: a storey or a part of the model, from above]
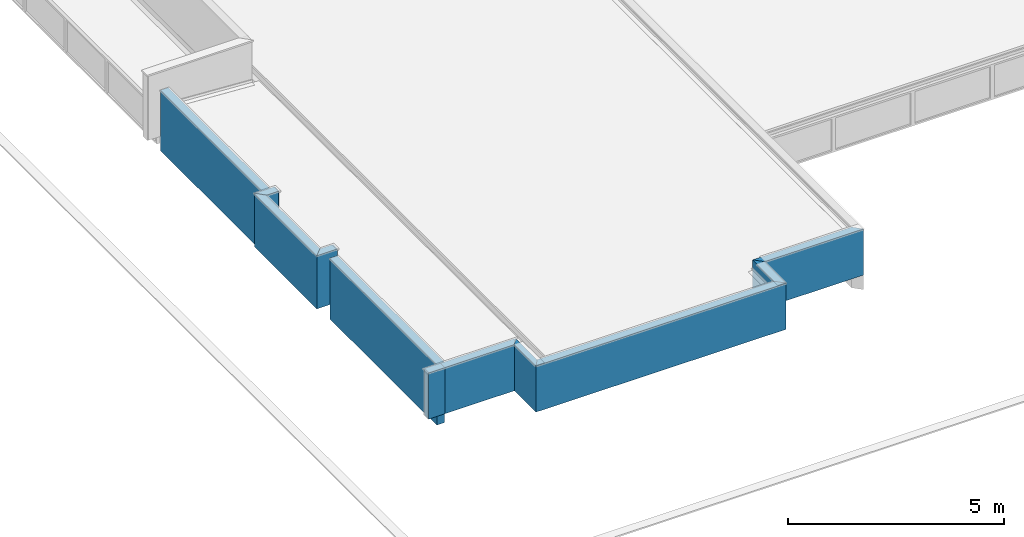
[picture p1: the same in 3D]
Properties of the parts of a building model (IFC4), part 21 of 22

# IfcWall: FNDE-PLAT_AL14-Pintura Branca 200 (29)
Name | 1_Bloco | EI-REV-Pintura Acrílica Cor Branco Gelo 1, Massa (kg) | EI-REV-Pintura Acrílica Cor Branco Gelo 1, Área de Componente Projetada (Líquida) (m2) | EI-REV-Pintura Acrílica Cor Branco Gelo 1, Área de Componente Projetada (Bruta) (m2) | EI-REV-Pintura Acrílica Cor Branco Gelo 1, Altura do Componente Retangular (m) = EI-REV-Massa Acrílica (externa) 1, Altura do Componente Retangular (m) = TIJOLO - CERAMICO 14x19x39 - espessura 20cm, Altura do Componente Retangular (m) = EI-REV-Chapisco (externo) 2, Altura do Componente Retangular (m) = EI-REV-Massa Acrílica (externa) 2, Altura do Componente Retangular (m) = EI-REV-Pintura Acrílica Cor Branco Gelo 2, Altura do Componente Retangular (m) | EI-REV-Pintura Acrílica Cor Branco Gelo 1, Área de Seção Transversal do Componente (m2) = EI-REV-Pintura Acrílica Cor Branco Gelo 2, Área de Seção Transversal do Componente (m2) | EI-REV-Pintura Acrílica Cor Branco Gelo 1, Volume Componente (Líquido) (m3) | EI-REV-Pintura Acrílica Cor Branco Gelo 1, Volume do componente (Bruto) (m3) | EI-REV-Massa Acrílica (externa) 1, Massa (kg) | EI-REV-Massa Acrílica (externa) 1, Área de Componente Projetada (Líquida) (m2) | EI-REV-Massa Acrílica (externa) 1, Área de Componente Projetada (Bruta) (m2) | EI-REV-Massa Acrílica (externa) 1, Área de Seção Transversal do Componente (m2) = EI-REV-Chapisco (externo) 2, Área de Seção Transversal do Componente (m2) = EI-REV-Massa Acrílica (externa) 2, Área de Seção Transversal do Componente (m2) | EI-REV-Massa Acrílica (externa) 1, Volume Componente (Líquido) (m3) | EI-REV-Massa Acrílica (externa) 1, Volume do componente (Bruto) (m3) | EI-REV-Massa única - Fachada 1, Massa (kg) | EI-REV-Massa única - Fachada 1, Área de Componente Projetada (Líquida) (m2) | EI-REV-Massa única - Fachada 1, Área de Componente Projetada (Bruta) (m2) | EI-REV-Massa única - Fachada 1, Espessura do Componente (m) = EI-REV-Massa única - Fachada 1, Largura do Componente Retangular (m) | EI-REV-Massa única - Fachada 1, Altura do Componente Retangular (m) | EI-REV-Massa única - Fachada 1, Área de Seção Transversal do Componente (m2) | EI-REV-Massa única - Fachada 1, Volume Componente (Líquido) (m3) | EI-REV-Massa única - Fachada 1, Volume do componente (Bruto) (m3) | EI-REV-Chapisco (externo) 1, Massa (kg) | EI-REV-Chapisco (externo) 1, Área de Componente Projetada (Líquida) (m2) | EI-REV-Chapisco (externo) 1, Área de Componente Projetada (Bruta) (m2) | EI-REV-Chapisco (externo) 1, Espessura do Componente (m) = EI-REV-Chapisco (externo) 1, Largura do Componente Retangular (m) | EI-REV-Chapisco (externo) 1, Altura do Componente Retangular (m) | EI-REV-Chapisco (externo) 1, Área de Seção Transversal do Componente (m2) | EI-REV-Chapisco (externo) 1, Volume Componente (Líquido) (m3) | EI-REV-Chapisco (externo) 1, Volume do componente (Bruto) (m3) | TIJOLO - CERAMICO 14x19x39 - espessura 20cm, Massa (kg) | TIJOLO - CERAMICO 14x19x39 - espessura 20cm, Área de Componente Projetada (Líquida) (m2) | TIJOLO - CERAMICO 14x19x39 - espessura 20cm, Área de Componente Projetada (Bruta) (m2) | TIJOLO - CERAMICO 14x19x39 - espessura 20cm, Área de Seção Transversal do Componente (m2) | TIJOLO - CERAMICO 14x19x39 - espessura 20cm, Volume Componente (Líquido) (m3) | TIJOLO - CERAMICO 14x19x39 - espessura 20cm, Volume do componente (Bruto) (m3) | EI-REV-Chapisco (externo) 2, Massa (kg) | EI-REV-Chapisco (externo) 2, Área de Componente Projetada (Líquida) (m2) | EI-REV-Chapisco (externo) 2, Área de Componente Projetada (Bruta) (m2) | EI-REV-Chapisco (externo) 2, Volume Componente (Líquido) (m3) | EI-REV-Chapisco (externo) 2, Volume do componente (Bruto) (m3) | EI-REV-Massa única - Fachada 2, Massa (kg) | EI-REV-Massa única - Fachada 2, Área de Componente Projetada (Líquida) (m2) | EI-REV-Massa única - Fachada 2, Área de Componente Projetada (Bruta) (m2) | EI-REV-Massa única - Fachada 2, Espessura do Componente (m) = EI-REV-Massa única - Fachada 2, Largura do Componente Retangular (m) | EI-REV-Massa única - Fachada 2, Altura do Componente Retangular (m) | EI-REV-Massa única - Fachada 2, Área de Seção Transversal do Componente (m2) | EI-REV-Massa única - Fachada 2, Volume Componente (Líquido) (m3) | EI-REV-Massa única - Fachada 2, Volume do componente (Bruto) (m3) | EI-REV-Massa Acrílica (externa) 2, Massa (kg) | EI-REV-Massa Acrílica (externa) 2, Área de Componente Projetada (Líquida) (m2) | EI-REV-Massa Acrílica (externa) 2, Área de Componente Projetada (Bruta) (m2) | EI-REV-Massa Acrílica (externa) 2, Volume Componente (Líquido) (m3) | EI-REV-Massa Acrílica (externa) 2, Volume do componente (Bruto) (m3) | EI-REV-Pintura Acrílica Cor Branco Gelo 2, Massa (kg) | EI-REV-Pintura Acrílica Cor Branco Gelo 2, Área de Componente Projetada (Líquida) (m2) | EI-REV-Pintura Acrílica Cor Branco Gelo 2, Área de Componente Projetada (Bruta) (m2) | EI-REV-Pintura Acrílica Cor Branco Gelo 2, Volume Componente (Líquido) (m3) | EI-REV-Pintura Acrílica Cor Branco Gelo 2, Volume do componente (Bruto) (m3)
AL14 | BLOCO B | 170.512 | 8.74422 | 8.74422 | 1.31 | 0.01965 | 0.131163 | 0.131163 | 56.6671 | 8.71802 | 8.71802 | 0.00655 | 0.0435901 | 0.0435901 | 56.582 | 8.70492 | 8.70492 | 0.005 | 1.31 | 0.00655 | 0.0435246 | 0.0435246 | 56.2644 | 8.69182 | 8.69182 | 0.005 | 1.31 | 0.00655 | 0.0432803 | 0.0432803 | 556.244 | 8.68515 | 8.68515 | 0.1834 | 0.858401 | 0.858401 | 52.6761 | 8.10402 | 8.10402 | 0.0405201 | 0.0405201 | 52.6884 | 8.35453 | 8.35453 | 0.005 | 1.31 | 0.00655 | 0.0405296 | 0.0405296 | 54.2388 | 8.34443 | 8.34443 | 0.0417221 | 0.0417221 | 162.29 | 8.32276 | 8.32276 | 0.124838 | 0.124838
AL14 | BLOCO B | 25.5433 | 1.30991 | 1.30991 | 1.31 | 0.01965 | 0.0196487 | 0.0196487 | 8.51444 | 1.30991 | 1.30991 | 0.00655 | 0.00654957 | 0.00654957 |  |  |  |  |  |  |  |  |  |  |  |  |  |  |  |  | 82.2442 | 1.12795 | 1.12795 | 0.1834 | 0.12692 | 0.12692 | 5.66426 | 0.871425 | 0.871425 | 0.00435712 | 0.00435712 | 5.67401 | 0.872925 | 0.872925 | 0.005 | 1.31 | 0.00655 | 0.00436462 | 0.00436462 | 6.23591 | 1.05642 | 1.05642 | 0.00479685 | 0.00479685 | 23.9643 | 1.30991 | 1.30991 | 0.0184341 | 0.0184341 | Component Quantities - EI-REV-Massa Acrílica (externa) 1: 3 with these values
AL14 | BLOCO B | 25.5467 | 1.31009 | 1.31009 | 1.31 | 0.01965 | 0.0196513 | 0.0196513 | 8.51556 | 1.31009 | 1.31009 | 0.00655 | 0.00655043 | 0.00655043 |  |  |  |  |  |  |  |  |  |  |  |  |  |  |  |  | 88.2747 | 1.31007 | 1.31007 | 0.1834 | 0.136226 | 0.136226 | 6.56555 | 1.01009 | 1.01009 | 0.00505043 | 0.00505043 | 6.57531 | 1.01159 | 1.01159 | 0.005 | 1.31 | 0.00655 | 0.00505793 | 0.00505793 | 6.58506 | 1.01309 | 1.01309 | 0.00506543 | 0.00506543 | 19.7812 | 1.01459 | 1.01459 | 0.0152163 | 0.0152163 | Component Quantities - EI-REV-Massa Acrílica (externa) 1: 3 with these values
AL14 | BLOCO B | 170.512 | 8.74422 | 8.74422 | 1.31 | 0.01965 | 0.131163 | 0.131163 | 56.6671 | 8.71802 | 8.71802 | 0.00655 | 0.0435901 | 0.0435901 | 56.582 | 8.70492 | 8.70492 | 0.005 | 1.31 | 0.00655 | 0.0435246 | 0.0435246 | 56.4968 | 8.69182 | 8.69182 | 0.005 | 1.31 | 0.00655 | 0.0434591 | 0.0434591 | 525.069 | 6.06661 | 6.06661 | 0.1834 | 0.810291 | 0.810291 | 51.8075 | 7.97101 | 7.97101 | 0.039852 | 0.039852 | 51.7476 | 7.96091 | 7.96091 | 0.005 | 1.31 | 0.00655 | 0.0398059 | 0.0398059 | 54.2138 | 8.34059 | 8.34059 | 0.0417029 | 0.0417029 | 162.242 | 8.32039 | 8.32039 | 0.124802 | 0.124802
AL14 | BLOCO B | 308.345 | 15.8296 | 15.8296 | 1.86 | 0.0279 | 0.237189 | 0.237189 | 103.127 | 15.8657 | 15.8657 | 0.0093 | 0.0793285 | 0.0793285 | 103.231 | 15.8817 | 15.8817 | 0.005 | 1.86 | 0.0093 | 0.0794086 | 0.0794086 | 103.335 | 15.8977 | 15.8977 | 0.005 | 1.86 | 0.0093 | 0.0794886 | 0.0794886 | 1157.3 | 16.1311 | 16.1311 | 0.2604 | 1.78595 | 1.78595 | 77.6941 | 11.9529 | 11.9529 | 0.0597647 | 0.0597647 | 77.7544 | 11.9622 | 11.9622 | 0.005 | 1.86 | 0.0093 | 0.0598111 | 0.0598111 | 77.8151 | 11.9716 | 11.9716 | 0.0598578 | 0.0598578 | 251.911 | 16.5253 | 16.5253 | 0.193778 | 0.193778
AL14 | BLOCO B | 166.143 | 8.52017 | 8.52017 | 1.72 | 0.0258 | 0.127803 | 0.127803 | 55.6765 | 8.56561 | 8.56561 | 0.0086 | 0.0428281 | 0.0428281 | 55.6764 | 8.5656 | 8.5656 | 0.005 | 1.72 | 0.0086 | 0.042828 | 0.042828 |  |  |  |  |  |  |  |  | 475.698 | 8.58541 | 8.58541 | 0.2408 | 0.734101 | 0.734101 | 45.8257 | 7.08335 | 7.08335 | 0.0352505 | 0.0352505 | 45.9989 | 7.07675 | 7.07675 | 0.005 | 1.72 | 0.0086 | 0.0353838 | 0.0353838 | 46.2315 | 7.07015 | 7.07015 | 0.0355627 | 0.0355627 | 165.968 | 8.78128 | 8.78128 | 0.127667 | 0.127667 | Component Quantities - EI-REV-Massa única - Fachada 1: 2 with these values
AL14 | BLOCO B | 166.022 | 8.51396 | 8.51396 | 1.72 | 0.0258 | 0.127709 | 0.127709 | 55.6761 | 8.56556 | 8.56556 | 0.0086 | 0.0428278 | 0.0428278 | 55.7879 | 8.58276 | 8.58276 | 0.005 | 1.72 | 0.0086 | 0.0429138 | 0.0429138 | 55.8437 | 8.59135 | 8.59135 | 0.005 | 1.72 | 0.0086 | 0.0429567 | 0.0429567 | 477.426 | 8.6 | 8.6 | 0.2408 | 0.736769 | 0.736769 | 45.7921 | 7.09144 | 7.09144 | 0.0352247 | 0.0352247 | 46.0482 | 7.08434 | 7.08434 | 0.005 | 1.72 | 0.0086 | 0.0354217 | 0.0354217 | 45.956 | 7.07015 | 7.07015 | 0.0353507 | 0.0353507 | 165.76 | 8.51251 | 8.51251 | 0.127508 | 0.127508
AL14 | BLOCO B | 166.523 | 8.53964 | 8.53964 | 1.72 | 0.0258 | 0.128095 | 0.128095 | 55.6753 | 8.56544 | 8.56544 | 0.0086 | 0.0428272 | 0.0428272 | 55.7312 | 8.57404 | 8.57404 | 0.005 | 1.72 | 0.0086 | 0.0428702 | 0.0428702 | 55.7312 | 8.57403 | 8.57403 | 0.005 | 1.72 | 0.0086 | 0.0428701 | 0.0428701 | 476.069 | 8.58723 | 8.58723 | 0.2408 | 0.734674 | 0.734674 | 45.841 | 7.09909 | 7.09909 | 0.0352623 | 0.0352623 | 46.0678 | 7.08736 | 7.08736 | 0.005 | 1.72 | 0.0086 | 0.0354368 | 0.0354368 | 45.9885 | 7.07516 | 7.07516 | 0.0353758 | 0.0353758 | 166.234 | 8.53824 | 8.53824 | 0.127872 | 0.127872
AL14 | BLOCO B | 166.142 | 8.52011 | 8.52011 | 1.72 | 0.0258 | 0.127802 | 0.127802 | 55.6761 | 8.56556 | 8.56556 | 0.0086 | 0.0428278 | 0.0428278 | 43.3315 | 8.57415 | 8.57415 | 0.005 | 1.72 | 0.0086 | 0.0333319 | 0.0333319 | 42.8139 | 6.58675 | 6.58675 | 0.005 | 1.72 | 0.0086 | 0.0329338 | 0.0329338 | 489.595 | 8.6119 | 8.6119 | 0.2408 | 0.755548 | 0.755548 | 46.1389 | 7.09829 | 7.09829 | 0.0354915 | 0.0354915 | 46.0502 | 7.08464 | 7.08464 | 0.005 | 1.72 | 0.0086 | 0.0354232 | 0.0354232 | 45.9614 | 7.07099 | 7.07099 | 0.035355 | 0.035355 | 165.916 | 8.5195 | 8.5195 | 0.127628 | 0.127628
AL14 | BLOCO A | 25.4851 | 1.30693 | 1.30693 | 1.31 | 0.01965 | 0.0196039 | 0.0196039 | 8.48529 | 1.30543 | 1.30543 | 0.00655 | 0.00652714 | 0.00652714 | 8.47554 | 1.30393 | 1.30393 | 0.005 | 1.31 | 0.00655 | 0.00651964 | 0.00651964 | 8.46579 | 1.30243 | 1.30243 | 0.005 | 1.31 | 0.00655 | 0.00651214 | 0.00651214 | 84.4515 | 1.26792 | 1.26792 | 0.1834 | 0.130326 | 0.130326 | 5.61562 | 0.863942 | 0.863942 | 0.00431971 | 0.00431971 | 5.65787 | 0.870442 | 0.870442 | 0.005 | 1.31 | 0.00655 | 0.00435221 | 0.00435221 | 5.70012 | 0.876942 | 0.876942 | 0.00438471 | 0.00438471 | 20.1348 | 1.30979 | 1.30979 | 0.0154883 | 0.0154883
AL14 | BLOCO A | 170.768 | 8.75732 | 8.75732 | 1.31 | 0.01965 | 0.13136 | 0.13136 | 56.7523 | 8.73112 | 8.73112 | 0.00655 | 0.0436556 | 0.0436556 | 56.6671 | 8.71802 | 8.71802 | 0.005 | 1.31 | 0.00655 | 0.0435901 | 0.0435901 | 56.5698 | 8.70492 | 8.70492 | 0.005 | 1.31 | 0.00655 | 0.0435152 | 0.0435152 | 560.707 | 8.48243 | 8.48243 | 0.1834 | 0.865289 | 0.865289 | 39.0211 | 6.00325 | 6.00325 | 0.0300163 | 0.0300163 | 39.1775 | 8.3511 | 8.3511 | 0.005 | 1.31 | 0.00655 | 0.0301365 | 0.0301365 | 54.249 | 8.346 | 8.346 | 0.04173 | 0.04173 | 162.514 | 8.33434 | 8.33434 | 0.125011 | 0.125011
AL14 | BLOCO A | 25.5401 | 1.31008 | 1.31008 | 1.31 | 0.01965 | 0.0196463 | 0.0196463 | 8.51549 | 1.31008 | 1.31008 | 0.00655 | 0.00655038 | 0.00655038 | 8.50592 | 1.3086 | 1.3086 | 0.005 | 1.31 | 0.00655 | 0.00654302 | 0.00654302 | 8.49617 | 1.3071 | 1.3071 | 0.005 | 1.31 | 0.00655 | 0.00653552 | 0.00653552 | 74.0805 | 1.3056 | 1.3056 | 0.1834 | 0.114322 | 0.114322 | 5.52572 | 0.85011 | 0.85011 | 0.00425055 | 0.00425055 | 5.55822 | 0.85511 | 0.85511 | 0.005 | 1.31 | 0.00655 | 0.00427555 | 0.00427555 | 5.59072 | 0.86011 | 0.86011 | 0.00430055 | 0.00430055 | 19.7435 | 1.31008 | 1.31008 | 0.0151873 | 0.0151873
AL14 | BLOCO A | 43.8524 | 2.24891 | 2.26871 | 1.32 | 0.0198 | 0.0337326 | 0.0340296 | 14.6295 | 2.25164 | 2.27804 | 0.0066 | 0.0112534 | 0.0113854 | 14.6097 | 2.24764 | 2.28064 | 0.005 | 1.32 | 0.0066 | 0.0112382 | 0.0114032 | 14.6266 | 2.25024 | 2.28324 | 0.005 | 1.32 | 0.0066 | 0.0112512 | 0.0114162 | 136.903 | 2.25291 | 2.28591 | 0.1848 | 0.21127 | 0.214119 | 9.45189 | 1.45414 | 1.47408 | 0.00727068 | 0.00737038 | 9.43499 | 1.45154 | 1.47148 | 0.005 | 1.32 | 0.0066 | 0.00725768 | 0.00735738 | 13.2179 | 2.07498 | 2.09492 | 0.0101676 | 0.0102673 | 44.2522 | 2.2703 | 2.2703 | 0.0340401 | 0.0340401
AL14 | BLOCO A | 166.023 | 8.514 | 8.514 | 1.72 | 0.0258 | 0.12771 | 0.12771 | 55.341 | 8.514 | 8.514 | 0.0086 | 0.04257 | 0.04257 |  |  |  |  |  |  |  |  |  |  |  |  |  |  |  |  | 497.998 | 8.514 | 8.514 | 0.2408 | 0.768515 | 0.768515 | 45.6791 | 7.02755 | 7.02755 | 0.0351377 | 0.0351377 |  |  |  |  |  |  |  |  | 45.7851 | 8.51255 | 8.51255 | 0.0352193 | 0.0352193 | 165.961 | 8.51255 | 8.51255 | 0.127663 | 0.127663 | Component Quantities - EI-REV-Massa Acrílica (externa) 1: 3 with these values; EI-REV-Chapisco (externo) 2: 2 with these values
AL14 | BLOCO A | 165.88 | 8.51395 | 8.51395 | 1.72 | 0.0258 | 0.1276 | 0.1276 | 42.4707 | 6.53395 | 6.53395 | 0.0086 | 0.0326697 | 0.0326697 |  |  |  |  |  |  |  |  |  |  |  |  |  |  |  |  | 472.337 | 6.534 | 6.534 | 0.2408 | 0.728915 | 0.728915 | 32.809 | 5.04754 | 5.04754 | 0.0252377 | 0.0252377 |  |  |  |  |  |  |  |  | 33.0581 | 8.5125 | 8.5125 | 0.0254293 | 0.0254293 | 165.968 | 8.5125 | 8.5125 | 0.127668 | 0.127668 | Component Quantities - EI-REV-Massa Acrílica (externa) 1: 3 with these values; EI-REV-Chapisco (externo) 2: 2 with these values
AL14 | BLOCO A | 33.3627 | 2.40084 | 2.42064 | 1.32 | 0.0198 | 0.0256636 | 0.0259484 | 8.93954 | 1.37531 | 1.3925 | 0.0066 | 0.00687657 | 0.00696249 | 8.9423 | 1.37592 | 1.39586 | 0.005 | 1.32 | 0.0066 | 0.0068787 | 0.00696979 | 8.94346 | 1.37592 | 1.39586 | 0.005 | 1.32 | 0.0066 | 0.00687959 | 0.00697929 | 133.314 | 2.238 | 2.271 | 0.1848 | 0.205732 | 0.208843 | 14.5463 | 2.2379 | 2.2709 | 0.0111895 | 0.0113545 | 14.546 | 2.23785 | 2.27085 | 0.005 | 1.32 | 0.0066 | 0.0111892 | 0.0113542 | 14.5457 | 2.2378 | 2.2708 | 0.011189 | 0.011354 | 44.27 | 2.2703 | 2.2703 | 0.0340538 | 0.0340538
AL14 | BLOCO A | 166.014 | 8.51406 | 8.51406 | 1.72 | 0.0258 | 0.127703 | 0.127703 | 55.5091 | 8.53986 | 8.53986 | 0.0086 | 0.0426993 | 0.0426993 | 55.565 | 8.54846 | 8.54846 | 0.005 | 1.72 | 0.0086 | 0.0427423 | 0.0427423 | 55.6009 | 8.55706 | 8.55706 | 0.005 | 1.72 | 0.0086 | 0.0427699 | 0.0427699 | 475.27 | 8.56567 | 8.56567 | 0.2408 | 0.733441 | 0.733441 | 45.896 | 7.06313 | 7.06313 | 0.0353046 | 0.0353046 | 45.8642 | 7.05603 | 7.05603 | 0.005 | 1.72 | 0.0086 | 0.0352802 | 0.0352802 | 45.8329 | 7.85388 | 7.85388 | 0.0352561 | 0.0352561 | 165.983 | 8.51261 | 8.51261 | 0.127679 | 0.127679
AL14 | BLOCO A | 166.023 | 8.51399 | 8.51399 | 1.72 | 0.0258 | 0.12771 | 0.12771 | 55.341 | 8.51399 | 8.51399 | 0.0086 | 0.04257 | 0.04257 |  |  |  |  |  |  |  |  | 55.2671 | 8.51399 | 8.51399 | 0.005 | 1.72 | 0.0086 | 0.0425131 | 0.0425131 | 498.06 | 8.51399 | 8.51399 | 0.2408 | 0.76861 | 0.76861 | 45.679 | 7.02754 | 7.02754 | 0.0351377 | 0.0351377 |  |  |  |  |  |  |  |  | 45.7345 | 8.51254 | 8.51254 | 0.0351804 | 0.0351804 | 165.991 | 8.51254 | 8.51254 | 0.127685 | 0.127685 | Component Quantities - EI-REV-Massa Acrílica (externa) 1: 2 with these values; EI-REV-Chapisco (externo) 2: 2 with these values
AL14 | BLOCO A | 710.342 | 46.15 | 46.15 | 1.72 | 0.0258 | 0.546417 | 0.546417 | 137.848 | 21.2074 | 21.2074 | 0.0086 | 0.106037 | 0.106037 | 137.849 | 21.2075 | 21.2075 | 0.005 | 1.72 | 0.0086 | 0.106037 | 0.106037 | 137.848 | 21.2075 | 21.2075 | 0.005 | 1.72 | 0.0086 | 0.106037 | 0.106037 | 2346.88 | 45.6762 | 45.6762 | 0.2408 | 3.62173 | 3.62173 | 296.746 | 45.6532 | 45.6532 | 0.228266 | 0.228266 | 297.332 | 45.8587 | 45.8587 | 0.005 | 1.72 | 0.0086 | 0.228717 | 0.228717 | 289.718 | 44.5719 | 44.5719 | 0.22286 | 0.22286 | 868.382 | 44.5431 | 44.5431 | 0.667986 | 0.667986
AL14 | BLOCO B | 891.318 | 45.8373 | 45.8373 | 1.72 | 0.0258 | 0.685629 | 0.685629 | 256.791 | 45.6429 | 45.6429 | 0.0086 | 0.197532 | 0.197532 | 153.74 | 25.0648 | 25.0648 | 0.005 | 1.72 | 0.0086 | 0.118261 | 0.118261 | 141.984 | 22.1161 | 22.1161 | 0.005 | 1.72 | 0.0086 | 0.109218 | 0.109218 | 2108.08 | 45.9134 | 45.9134 | 0.2408 | 3.25321 | 3.25321 | 299.39 | 46.0599 | 46.0599 | 0.2303 | 0.2303 | 299.432 | 46.0665 | 46.0665 | 0.005 | 1.72 | 0.0086 | 0.230332 | 0.230332 | 299.311 | 46.0479 | 46.0479 | 0.230239 | 0.230239 | 897.218 | 46.021 | 46.021 | 0.690167 | 0.690169
AL14 | BLOCO B | 131.48 | 6.74472 | 6.74472 | 1.31 | 0.01965 | 0.101139 | 0.101139 | 40.2416 | 6.74472 | 6.74472 | 0.00655 | 0.0309551 | 0.0309551 | 31.8054 | 4.89313 | 4.89313 | 0.005 | 1.31 | 0.00655 | 0.0244657 | 0.0244657 | 31.8382 | 4.89818 | 4.89818 | 0.005 | 1.31 | 0.00655 | 0.0244909 | 0.0244909 | 457.059 | 6.5431 | 6.5431 | 0.1834 | 0.705337 | 0.705337 | 43.7223 | 6.7265 | 6.7265 | 0.0336325 | 0.0336325 | 43.7648 | 6.73305 | 6.73305 | 0.005 | 1.31 | 0.00655 | 0.0336653 | 0.0336653 | 43.8074 | 6.7396 | 6.7396 | 0.033698 | 0.033698 | 131.55 | 6.74615 | 6.74615 | 0.101192 | 0.101192
AL14 | BLOCO A | 131.554 | 6.74636 | 6.74636 | 1.31 | 0.01965 | 0.101195 | 0.101195 | 43.8087 | 6.73981 | 6.73981 | 0.00655 | 0.033699 | 0.033699 | 43.7662 | 6.73326 | 6.73326 | 0.005 | 1.31 | 0.00655 | 0.0336663 | 0.0336663 | 43.7236 | 6.72671 | 6.72671 | 0.005 | 1.31 | 0.00655 | 0.0336335 | 0.0336335 | 483.336 | 6.54331 | 6.54331 | 0.1834 | 0.745889 | 0.745889 | 32.6836 | 5.02825 | 5.02825 | 0.0251412 | 0.0251412 | 33.34 | 5.24436 | 5.24436 | 0.005 | 1.31 | 0.00655 | 0.0256462 | 0.0256462 | 34.1306 | 5.25086 | 5.25086 | 0.0262543 | 0.0262543 | 107.003 | 6.74492 | 6.74492 | 0.0823103 | 0.0823103
AL14 | BLOCO A | 84.9479 | 4.3563 | 4.3563 | 1.51 | 0.02265 | 0.0653445 | 0.0653445 | 28.1197 | 4.3261 | 4.3261 | 0.00755 | 0.0216305 | 0.0216305 | 28.0215 | 4.311 | 4.311 | 0.005 | 1.51 | 0.00755 | 0.021555 | 0.021555 | 27.9234 | 4.2959 | 4.2959 | 0.005 | 1.51 | 0.00755 | 0.0214795 | 0.0214795 | 275.612 | 4.07696 | 4.07696 | 0.2114 | 0.425327 | 0.425327 | 18.4342 | 2.83603 | 2.83603 | 0.0141801 | 0.0141801 | 24.5091 | 3.83636 | 3.83636 | 0.005 | 1.51 | 0.00755 | 0.0188532 | 0.0188532 | 24.8642 | 3.82526 | 3.82526 | 0.0191263 | 0.0191263 | 74.0393 | 3.79705 | 3.79705 | 0.0569533 | 0.0569533
AL14 | BLOCO A | 10.2422 | 0.525791 | 0.525791 | 1.51 | 0.02265 | 0.00787864 | 0.00787864 | 1.55231 | 0.238817 | 0.238817 | 0.00755 | 0.00119408 | 0.00119408 | 1.50323 | 0.231267 | 0.231267 | 0.005 | 1.51 | 0.00755 | 0.00115633 | 0.00115633 | 1.45416 | 0.223717 | 0.223717 | 0.005 | 1.51 | 0.00755 | 0.00111858 | 0.00111858 | 5.99112 | 0.066187 | 0.066187 | 0.2114 | 0.00924555 | 0.00926618 | 0.392516 | 0.060387 | 0.060637 | 0.000301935 | 0.000303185 | 0.356441 | 0.054837 | 0.055087 | 0.005 | 1.51 | 0.00755 | 0.000274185 | 0.000275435 | 0.353146 | 0.474693 | 0.504893 | 0.000271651 | 0.000273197 | 9.08954 | 0.466144 | 0.488794 | 0.00699196 | 0.0073317
AL14 | BLOCO A | 10.6946 | 0.548442 | 0.548442 | 1.51 | 0.02265 | 0.00822664 | 0.00822664 | 1.60587 | 0.542424 | 0.542424 | 0.00755 | 0.00123529 | 0.00123529 | 1.55231 | 0.238817 | 0.238817 | 0.005 | 1.51 | 0.00755 | 0.00119408 | 0.00119408 | 1.50324 | 0.231267 | 0.231267 | 0.005 | 1.51 | 0.00755 | 0.00115633 | 0.00115633 | 20.2822 | 0.223717 | 0.223717 | 0.2114 | 0.0312997 | 0.0313204 | 0.42859 | 0.065937 | 0.066187 | 0.000329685 | 0.000330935 | 0.392515 | 0.060387 | 0.060637 | 0.005 | 1.51 | 0.00755 | 0.000301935 | 0.000303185 | 0.376665 | 0.0579484 | 0.0581484 | 0.000289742 | 0.000290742 | 9.52459 | 0.488792 | 0.511442 | 0.00732661 | 0.00766608
AL14 | BLOCO B | 10.7125 | 0.549359 | 0.549359 | 1.51 | 0.02265 | 0.00824038 | 0.00824038 | 1.55555 | 0.546359 | 0.546359 | 0.00755 | 0.00119658 | 0.00119658 | 1.5149 | 0.233061 | 0.233061 | 0.005 | 1.51 | 0.00755 | 0.00116531 | 0.00116531 | 1.47882 | 0.227511 | 0.227511 | 0.005 | 1.51 | 0.00755 | 0.00113756 | 0.00113756 | 20.123 | 0.221961 | 0.221961 | 0.2114 | 0.031054 | 0.0310746 | 0.431024 | 0.0663114 | 0.0665614 | 0.000331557 | 0.000332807 | 0.394949 | 0.0607614 | 0.0610114 | 0.005 | 1.51 | 0.00755 | 0.000303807 | 0.000305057 | 0.381414 | 0.058679 | 0.058879 | 0.000293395 | 0.000294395 | 9.54233 | 0.489685 | 0.512335 | 0.00734025 | 0.00767974
AL14 | BLOCO B | 84.9462 | 4.3563 | 4.3563 | 1.51 | 0.02265 | 0.0653433 | 0.0653433 | 20.7557 | 4.28965 | 4.28965 | 0.00755 | 0.0159659 | 0.0159659 | 20.5986 | 3.16901 | 3.16901 | 0.005 | 1.51 | 0.00755 | 0.0158451 | 0.0158451 | 20.5264 | 3.15792 | 3.15792 | 0.005 | 1.51 | 0.00755 | 0.0157896 | 0.0157896 | 271.885 | 2.99697 | 2.99697 | 0.2114 | 0.419576 | 0.419576 | 18.4342 | 2.83602 | 2.83602 | 0.0141801 | 0.0141801 | 18.362 | 2.82493 | 2.82493 | 0.005 | 1.51 | 0.00755 | 0.0141246 | 0.0141246 | 18.2899 | 2.81383 | 2.81383 | 0.0140691 | 0.0140691 | 73.9541 | 3.79705 | 3.79705 | 0.0568878 | 0.0568878
AL14 | BLOCO B | 10.2574 | 0.526707 | 0.526707 | 1.51 | 0.02265 | 0.0078903 | 0.0078903 | 1.54421 | 0.237571 | 0.237571 | 0.00755 | 0.00118786 | 0.00118786 | 1.50814 | 0.232021 | 0.232021 | 0.005 | 1.51 | 0.00755 | 0.00116011 | 0.00116011 | 1.47206 | 0.226471 | 0.226471 | 0.005 | 1.51 | 0.00755 | 0.00113236 | 0.00113236 | 6.43471 | 0.0710943 | 0.0710943 | 0.2114 | 0.00993011 | 0.00995074 | 0.424407 | 0.0652927 | 0.0655427 | 0.000326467 | 0.000327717 | 0.388342 | 0.0597442 | 0.0599942 | 0.005 | 1.51 | 0.00755 | 0.000298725 | 0.000299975 | 0.365125 | 0.475584 | 0.505784 | 0.000280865 | 0.000282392 | 9.10682 | 0.46706 | 0.48971 | 0.00700524 | 0.00734496
AL14 | BLOCO A | 170.896 | 8.7639 | 8.7639 | 1.31 | 0.01965 | 0.131458 | 0.131458 | 56.7099 | 8.7246 | 8.7246 | 0.00655 | 0.043623 | 0.043623 | 56.6247 | 8.7115 | 8.7115 | 0.005 | 1.31 | 0.00655 | 0.0435575 | 0.0435575 | 56.1363 | 8.6984 | 8.6984 | 0.005 | 1.31 | 0.00655 | 0.0431817 | 0.0431817 | 541.205 | 8.46835 | 8.46835 | 0.1834 | 0.835193 | 0.835193 | 54.2289 | 8.34291 | 8.34291 | 0.0417145 | 0.0417145 | 54.1957 | 8.33781 | 8.33781 | 0.005 | 1.31 | 0.00655 | 0.041689 | 0.041689 | 54.1626 | 8.33271 | 8.33271 | 0.0416635 | 0.0416635 | 162.382 | 8.32761 | 8.32761 | 0.124909 | 0.124909

# IfcWall: FNDE-PLAT_AL14-Pintura cinza 200 (10)
In: COBERTURA
Classification: Parede (Classificação Archicad); Material: EI-REV-Pintura Acrílica Cor Cinza 0.015 m, EI-REV-Massa Acrílica (externa) 0.005 m, EI-REV-Massa única - Fachada 0.005 m, EI-REV-Chapisco (externo) 0.005 m, TIJOLO - CERAMICO 14x19x39 - espessura 20cm 0.14 m, EI-REV-Chapisco (externo) 0.005 m, EI-REV-Massa única - Fachada 0.005 m, EI-REV-Massa Acrílica (externa) 0.005 m, EI-REV-Pintura Acrílica Cor Cinza 0.015 m
FNDE - Alvenarias: Alvenaria de Vedação / Edificação; Sistemas de Cobertura: PLATIBANDA DE ALVENARIA; Esquadrias - Fechamentos metálicos e Gradis: -; 0_ID: AL14
Pset_WallCommon - IsExternal: yes; LoadBearing: no
Component Quantities - EI-REV-Pintura Acrílica Cor Cinza 1, Espessura do Componente: 0.015 m; EI-REV-Pintura Acrílica Cor Cinza 1, Largura do Componente Retangular: 0.015 m; EI-REV-Massa Acrílica (externa) 1, Espessura do Componente: 0.005 m; EI-REV-Massa Acrílica (externa) 1, Largura do Componente Retangular: 0.005 m; EI-REV-Massa única - Fachada 1, Espessura do Componente: 0.005 m; EI-REV-Massa única - Fachada 1, Largura do Componente Retangular: 0.005 m; TIJOLO - CERAMICO 14x19x39 - espessura 20cm, Espessura do Componente: 0.14 m; TIJOLO - CERAMICO 14x19x39 - espessura 20cm, Largura do Componente Retangular: 0.14 m; EI-REV-Chapisco (externo) 2, Espessura do Componente: 0.005 m; EI-REV-Chapisco (externo) 2, Largura do Componente Retangular: 0.005 m; EI-REV-Pintura Acrílica Cor Cinza 2, Espessura do Componente: 0.015 m; EI-REV-Pintura Acrílica Cor Cinza 2, Largura do Componente Retangular: 0.015 m
Name | 1_Bloco | EI-REV-Pintura Acrílica Cor Cinza 1, Massa (kg) | EI-REV-Pintura Acrílica Cor Cinza 1, Área de Componente Projetada (Líquida) (m2) | EI-REV-Pintura Acrílica Cor Cinza 1, Área de Componente Projetada (Bruta) (m2) | EI-REV-Pintura Acrílica Cor Cinza 1, Altura do Componente Retangular (m) = EI-REV-Massa Acrílica (externa) 1, Altura do Componente Retangular (m) = EI-REV-Massa única - Fachada 1, Altura do Componente Retangular (m) = TIJOLO - CERAMICO 14x19x39 - espessura 20cm, Altura do Componente Retangular (m) = EI-REV-Chapisco (externo) 2, Altura do Componente Retangular (m) = EI-REV-Pintura Acrílica Cor Cinza 2, Altura do Componente Retangular (m) | EI-REV-Pintura Acrílica Cor Cinza 1, Área de Seção Transversal do Componente (m2) = EI-REV-Pintura Acrílica Cor Cinza 2, Área de Seção Transversal do Componente (m2) | EI-REV-Pintura Acrílica Cor Cinza 1, Volume Componente (Líquido) (m3) | EI-REV-Pintura Acrílica Cor Cinza 1, Volume do componente (Bruto) (m3) | EI-REV-Massa Acrílica (externa) 1, Massa (kg) | EI-REV-Massa Acrílica (externa) 1, Área de Componente Projetada (Líquida) (m2) | EI-REV-Massa Acrílica (externa) 1, Área de Componente Projetada (Bruta) (m2) | EI-REV-Massa Acrílica (externa) 1, Área de Seção Transversal do Componente (m2) = EI-REV-Massa única - Fachada 1, Área de Seção Transversal do Componente (m2) = EI-REV-Chapisco (externo) 2, Área de Seção Transversal do Componente (m2) | EI-REV-Massa Acrílica (externa) 1, Volume Componente (Líquido) (m3) | EI-REV-Massa Acrílica (externa) 1, Volume do componente (Bruto) (m3) | EI-REV-Massa única - Fachada 1, Massa (kg) | EI-REV-Massa única - Fachada 1, Área de Componente Projetada (Líquida) (m2) | EI-REV-Massa única - Fachada 1, Área de Componente Projetada (Bruta) (m2) | EI-REV-Massa única - Fachada 1, Volume Componente (Líquido) (m3) | EI-REV-Massa única - Fachada 1, Volume do componente (Bruto) (m3) | TIJOLO - CERAMICO 14x19x39 - espessura 20cm, Massa (kg) | TIJOLO - CERAMICO 14x19x39 - espessura 20cm, Área de Componente Projetada (Líquida) (m2) | TIJOLO - CERAMICO 14x19x39 - espessura 20cm, Área de Componente Projetada (Bruta) (m2) | TIJOLO - CERAMICO 14x19x39 - espessura 20cm, Área de Seção Transversal do Componente (m2) | TIJOLO - CERAMICO 14x19x39 - espessura 20cm, Volume Componente (Líquido) (m3) | TIJOLO - CERAMICO 14x19x39 - espessura 20cm, Volume do componente (Bruto) (m3) | EI-REV-Chapisco (externo) 2, Massa (kg) | EI-REV-Chapisco (externo) 2, Área de Componente Projetada (Líquida) (m2) | EI-REV-Chapisco (externo) 2, Área de Componente Projetada (Bruta) (m2) | EI-REV-Chapisco (externo) 2, Volume Componente (Líquido) (m3) | EI-REV-Chapisco (externo) 2, Volume do componente (Bruto) (m3) | EI-REV-Massa única - Fachada 2, Massa (kg) | EI-REV-Massa única - Fachada 2, Área de Componente Projetada (Líquida) (m2) | EI-REV-Massa única - Fachada 2, Área de Componente Projetada (Bruta) (m2) | EI-REV-Massa única - Fachada 2, Espessura do Componente (m) = EI-REV-Massa única - Fachada 2, Largura do Componente Retangular (m) | EI-REV-Massa única - Fachada 2, Altura do Componente Retangular (m) | EI-REV-Massa única - Fachada 2, Área de Seção Transversal do Componente (m2) | EI-REV-Massa única - Fachada 2, Volume Componente (Líquido) (m3) | EI-REV-Massa única - Fachada 2, Volume do componente (Bruto) (m3) | EI-REV-Massa Acrílica (externa) 2, Massa (kg) | EI-REV-Massa Acrílica (externa) 2, Área de Componente Projetada (Líquida) (m2) | EI-REV-Massa Acrílica (externa) 2, Área de Componente Projetada (Bruta) (m2) | EI-REV-Massa Acrílica (externa) 2, Espessura do Componente (m) = EI-REV-Massa Acrílica (externa) 2, Largura do Componente Retangular (m) | EI-REV-Massa Acrílica (externa) 2, Altura do Componente Retangular (m) | EI-REV-Massa Acrílica (externa) 2, Área de Seção Transversal do Componente (m2) | EI-REV-Massa Acrílica (externa) 2, Volume Componente (Líquido) (m3) | EI-REV-Massa Acrílica (externa) 2, Volume do componente (Bruto) (m3) | EI-REV-Pintura Acrílica Cor Cinza 2, Massa (kg) | EI-REV-Pintura Acrílica Cor Cinza 2, Área de Componente Projetada (Líquida) (m2) | EI-REV-Pintura Acrílica Cor Cinza 2, Área de Componente Projetada (Bruta) (m2) | EI-REV-Pintura Acrílica Cor Cinza 2, Volume Componente (Líquido) (m3) | EI-REV-Pintura Acrílica Cor Cinza 2, Volume do componente (Bruto) (m3) | EI-REV-Chapisco (externo) 1, Massa (kg) | EI-REV-Chapisco (externo) 1, Área de Componente Projetada (Líquida) (m2) | EI-REV-Chapisco (externo) 1, Área de Componente Projetada (Bruta) (m2) | EI-REV-Chapisco (externo) 1, Espessura do Componente (m) = EI-REV-Chapisco (externo) 1, Largura do Componente Retangular (m) | EI-REV-Chapisco (externo) 1, Altura do Componente Retangular (m) | EI-REV-Chapisco (externo) 1, Área de Seção Transversal do Componente (m2) | EI-REV-Chapisco (externo) 1, Volume Componente (Líquido) (m3) | EI-REV-Chapisco (externo) 1, Volume do componente (Bruto) (m3)
AL14 | BLOCO B | 11.1112 | 0.569807 | 0.589406 | 1.31 | 0.01965 | 0.00854711 | 0.00884109 | 3.66117 | 0.563257 | 0.589406 | 0.00655 | 0.00281629 | 0.00294703 | 3.6186 | 0.556707 | 0.589406 | 0.00278354 | 0.00294703 | 16.2691 | 0.179334 | 0.206109 | 0.1834 | 0.0251067 | 0.0288552 | 3.02255 | 0.465007 | 0.497706 | 0.00232504 | 0.00248853 | 2.97997 | 0.458457 | 0.491156 | 0.005 | 1.31 | 0.00655 | 0.00229229 | 0.00245578 | 2.9374 | 0.451907 | 0.484606 | 0.005 | 1.31 | 0.00655 | 0.00225954 | 0.00242303 | 8.68447 | 0.445357 | 0.478056 | 0.00668036 | 0.00717084 | Component Quantities - EI-REV-Massa única - Fachada 1: 2 with these values
AL14 | BLOCO B | 94.1506 | 4.8308 | 4.8587 | 1.86 | 0.0279 | 0.0724235 | 0.072842 | 23.3814 | 4.831 | 4.8682 | 0.0093 | 0.0179857 | 0.0181495 | 23.3136 | 3.58717 | 3.62769 | 0.0179336 | 0.0181362 | 330.402 | 3.642 | 3.68252 | 0.2604 | 0.50988 | 0.515553 | 25.0183 | 3.85392 | 3.89443 | 0.0192448 | 0.0194474 | 25.0583 | 3.85513 | 3.89565 | 0.005 | 1.86 | 0.0093 | 0.0192757 | 0.0194782 | 25.086 | 3.85938 | 3.8999 | 0.005 | 1.86 | 0.0093 | 0.0192969 | 0.0194995 | 95.4774 | 4.89944 | 4.94594 | 0.0734441 | 0.0741414 | 23.3686 | 3.59517 | 3.63569 | 0.005 | 1.86 | 0.0093 | 0.0179759 | 0.0181785
AL14 | BLOCO B | 93.5504 | 4.80031 | 4.82821 | 1.86 | 0.0279 | 0.0719619 | 0.0723804 | 23.236 | 3.57562 | 3.60711 | 0.0093 | 0.0178738 | 0.0180326 | 23.2458 | 3.57675 | 3.61604 | 0.0178814 | 0.0180779 | 326.425 | 3.59815 | 3.63744 | 0.2604 | 0.503742 | 0.509242 | 23.499 | 3.61523 | 3.65452 | 0.0180762 | 0.0182726 | 23.4568 | 3.60873 | 3.64802 | 0.005 | 1.86 | 0.0093 | 0.0180437 | 0.0182401 | 23.4192 | 3.60223 | 3.64152 | 0.005 | 1.86 | 0.0093 | 0.0180148 | 0.0182095 | 95.7464 | 4.91023 | 4.95673 | 0.0736511 | 0.0743486 | 23.3009 | 3.58475 | 3.62404 | 0.005 | 1.86 | 0.0093 | 0.0179238 | 0.0181202
AL14 | BLOCO B | 11.1112 | 0.569807 | 0.589457 | 1.31 | 0.01965 | 0.00854711 | 0.00884186 | 3.66117 | 0.563257 | 0.589457 | 0.00655 | 0.00281629 | 0.00294729 | 2.78963 | 0.429217 | 0.455992 | 0.00214587 | 0.00227987 | 17.536 | 0.244859 | 0.277609 | 0.1834 | 0.0270617 | 0.0308701 | 3.02255 | 0.465008 | 0.497758 | 0.00232504 | 0.00248879 | 2.97998 | 0.458458 | 0.491208 | 0.005 | 1.31 | 0.00655 | 0.00229229 | 0.00245604 | 2.9374 | 0.451908 | 0.484658 | 0.005 | 1.31 | 0.00655 | 0.00225954 | 0.00242329 | 8.68448 | 0.445358 | 0.478108 | 0.00668037 | 0.00717162 | 2.78991 | 0.429217 | 0.455992 | 0.005 | 1.31 | 0.00655 | 0.00214609 | 0.00227996
AL14 | BLOCO A | 88.9599 | 4.56637 | 4.59427 | 1.86 | 0.0279 | 0.0684307 | 0.0688491 | 20.3285 | 3.12747 | 3.16065 | 0.0093 | 0.0156373 | 0.0158032 | 20.2814 | 3.12022 | 3.1607 | 0.0156011 | 0.0158035 | 283.198 | 3.12167 | 3.16215 | 0.2604 | 0.437034 | 0.442701 | 20.2912 | 3.12172 | 3.1622 | 0.0156086 | 0.015811 | 20.2915 | 3.12177 | 3.16225 | 0.005 | 1.86 | 0.0093 | 0.0156088 | 0.0158112 | 20.3891 | 4.77596 | 4.82246 | 0.005 | 1.86 | 0.0093 | 0.015684 | 0.0158866 | 93.5154 | 4.79575 | 4.84225 | 0.0719349 | 0.0726324 | 20.2818 | 3.12027 | 3.16075 | 0.005 | 1.86 | 0.0093 | 0.0156013 | 0.0158037
AL14 | BLOCO A | 8.9407 | 0.458497 | 0.478147 | 1.31 | 0.01965 | 0.00687746 | 0.00717221 | 2.98023 | 0.458498 | 0.484698 | 0.00655 | 0.00229249 | 0.00242349 | 2.98023 | 0.458498 | 0.491248 | 0.00229249 | 0.00245624 | 17.1794 | 0.55675 | 0.5895 | 0.1834 | 0.0265113 | 0.0306752 | 3.61888 | 0.55675 | 0.5895 | 0.00278375 | 0.0029475 |  |  |  |  |  |  |  |  |  |  |  |  |  |  |  |  | 10.8566 | 0.55675 | 0.5895 | 0.00835125 | 0.0088425 | 3.00267 | 0.465048 | 0.497798 | 0.005 | 1.31 | 0.00655 | 0.00230975 | 0.00247333 | Component Quantities - EI-REV-Chapisco (externo) 2: 3 with these values
AL14 | BLOCO A | 11.1121 | 0.56985 | 0.58947 | 1.31 | 0.01965 | 0.00854775 | 0.00884205 | 3.66145 | 0.5633 | 0.58947 | 0.00655 | 0.0028165 | 0.00294735 | 3.61888 | 0.55675 | 0.58947 | 0.00278375 | 0.00294735 | 19.4431 | 0.540234 | 0.572984 | 0.1834 | 0.0300048 | 0.0342096 | 3.50792 | 0.540234 | 0.572953 | 0.0026984 | 0.00286188 | 3.51152 | 0.540233 | 0.572953 | 0.005 | 1.31 | 0.00655 | 0.00270117 | 0.00286477 |  |  |  |  |  |  |  |  | 10.5346 | 0.540233 | 0.572953 | 0.0081035 | 0.0085943 | 3.59852 | 0.55675 | 0.58947 | 0.005 | 1.31 | 0.00655 | 0.00276809 | 0.00293169 | Component Quantities - EI-REV-Massa única - Fachada 2: 2 with these values
AL14 | BLOCO A | 94.04 | 4.82256 | 4.86906 | 1.86 | 0.0279 | 0.0723384 | 0.0730359 | 31.3038 | 4.81596 | 4.86246 | 0.0093 | 0.0240798 | 0.0243123 | 31.2609 | 4.80936 | 4.85586 | 0.0240468 | 0.0242793 | 293.159 | 4.65996 | 4.70646 | 0.2604 | 0.452407 | 0.458355 | 29.9368 | 4.61555 | 4.66205 | 0.0230283 | 0.0232606 | 29.9406 | 4.60625 | 4.65275 | 0.005 | 1.86 | 0.0093 | 0.0230312 | 0.0232637 | 29.9406 | 4.60625 | 4.64345 | 0.005 | 1.86 | 0.0093 | 0.0230313 | 0.0232173 | 89.5645 | 4.59305 | 4.62095 | 0.0688957 | 0.0693142 | 31.1891 | 4.81326 | 4.85976 | 0.005 | 1.86 | 0.0093 | 0.0239916 | 0.0242241
AL14 | BLOCO A | 67.8228 | 3.47809 | 3.47809 | 1.31 | 0.01965 | 0.0521714 | 0.0521714 | 15.6249 | 3.46499 | 3.46499 | 0.00655 | 0.0120191 | 0.0120191 | 15.4881 | 2.38278 | 2.38278 | 0.0119139 | 0.0119139 | 228.263 | 2.51613 | 2.51613 | 0.1834 | 0.352258 | 0.352258 | 16.1448 | 2.48382 | 2.48382 | 0.0124191 | 0.0124191 | 16.1773 | 2.48882 | 2.48882 | 0.005 | 1.31 | 0.00655 | 0.0124441 | 0.0124441 | 16.2098 | 2.49382 | 2.49382 | 0.005 | 1.31 | 0.00655 | 0.0124691 | 0.0124691 | 67.6332 | 3.47429 | 3.47429 | 0.0520256 | 0.0520256 | 15.4783 | 2.38128 | 2.38128 | 0.005 | 1.31 | 0.00655 | 0.0119064 | 0.0119064
AL14 | BLOCO A | 58.6274 | 3.47151 | 3.47151 | 1.31 | 0.01965 | 0.045098 | 0.045098 | 15.4705 | 2.76647 | 2.76647 | 0.00655 | 0.0119004 | 0.0119004 | 15.4807 | 2.38164 | 2.38164 | 0.0119082 | 0.0119082 | 231.699 | 3.43702 | 3.43702 | 0.1834 | 0.35756 | 0.35756 | 22.5648 | 3.47151 | 3.47151 | 0.0173576 | 0.0173576 |  |  |  |  |  |  |  |  |  |  |  |  |  |  |  |  | 67.6926 | 3.47151 | 3.47151 | 0.0520712 | 0.0520712 | 15.5132 | 2.38664 | 2.38664 | 0.005 | 1.31 | 0.00655 | 0.0119332 | 0.0119332 | Component Quantities - EI-REV-Chapisco (externo) 2: 3 with these values

# IfcWall: FNDE-PLAT_AL14-Pintura cinza-branca 200 (6)
In: COBERTURA
Classification: Parede (Classificação Archicad); Material: EI-REV-Pintura Acrílica Cor Cinza 0.015 m, EI-REV-Massa Acrílica (externa) 0.005 m, EI-REV-Massa única - Fachada 0.005 m, EI-REV-Chapisco (externo) 0.005 m, TIJOLO - CERAMICO 14x19x39 - espessura 20cm 0.14 m, EI-REV-Chapisco (externo) 0.005 m, EI-REV-Massa única - Fachada 0.005 m, EI-REV-Massa Acrílica (externa) 0.005 m, EI-REV-Pintura Acrílica Cor Branco Gelo 0.015 m
FNDE - Alvenarias: Alvenaria de Vedação / Edificação; Sistemas de Cobertura: PLATIBANDA DE ALVENARIA; Esquadrias - Fechamentos metálicos e Gradis: -; 0_ID: AL14
Pset_WallCommon - IsExternal: yes; LoadBearing: no
Component Quantities - EI-REV-Pintura Acrílica Cor Cinza, Espessura do Componente: 0.015 m; EI-REV-Pintura Acrílica Cor Cinza, Altura do Componente Retangular: 1.31 m; EI-REV-Pintura Acrílica Cor Cinza, Largura do Componente Retangular: 0.015 m; EI-REV-Pintura Acrílica Cor Cinza, Área de Seção Transversal do Componente: 0.01965 m2; EI-REV-Massa Acrílica (externa) 1, Espessura do Componente: 0.005 m; EI-REV-Massa Acrílica (externa) 1, Altura do Componente Retangular: 1.31 m; EI-REV-Massa Acrílica (externa) 1, Largura do Componente Retangular: 0.005 m; EI-REV-Massa Acrílica (externa) 1, Área de Seção Transversal do Componente: 0.00655 m2; TIJOLO - CERAMICO 14x19x39 - espessura 20cm, Espessura do Componente: 0.14 m; TIJOLO - CERAMICO 14x19x39 - espessura 20cm, Altura do Componente Retangular: 1.31 m; TIJOLO - CERAMICO 14x19x39 - espessura 20cm, Largura do Componente Retangular: 0.14 m; TIJOLO - CERAMICO 14x19x39 - espessura 20cm, Área de Seção Transversal do Componente: 0.1834 m2; EI-REV-Chapisco (externo) 2, Espessura do Componente: 0.005 m; EI-REV-Chapisco (externo) 2, Altura do Componente Retangular: 1.31 m; EI-REV-Chapisco (externo) 2, Largura do Componente Retangular: 0.005 m; EI-REV-Chapisco (externo) 2, Área de Seção Transversal do Componente: 0.00655 m2; EI-REV-Massa única - Fachada 2, Espessura do Componente: 0.005 m; EI-REV-Massa única - Fachada 2, Altura do Componente Retangular: 1.31 m; EI-REV-Massa única - Fachada 2, Largura do Componente Retangular: 0.005 m; EI-REV-Massa única - Fachada 2, Área de Seção Transversal do Componente: 0.00655 m2; EI-REV-Massa Acrílica (externa) 2, Espessura do Componente: 0.005 m; EI-REV-Massa Acrílica (externa) 2, Altura do Componente Retangular: 1.31 m; EI-REV-Massa Acrílica (externa) 2, Largura do Componente Retangular: 0.005 m; EI-REV-Massa Acrílica (externa) 2, Área de Seção Transversal do Componente: 0.00655 m2; EI-REV-Pintura Acrílica Cor Branco Gelo, Espessura do Componente: 0.015 m; EI-REV-Pintura Acrílica Cor Branco Gelo, Altura do Componente Retangular: 1.31 m; EI-REV-Pintura Acrílica Cor Branco Gelo, Largura do Componente Retangular: 0.015 m; EI-REV-Pintura Acrílica Cor Branco Gelo, Área de Seção Transversal do Componente: 0.01965 m2
Name | 1_Bloco | EI-REV-Pintura Acrílica Cor Cinza, Massa (kg) | EI-REV-Pintura Acrílica Cor Cinza, Área de Componente Projetada (Líquida) (m2) | EI-REV-Pintura Acrílica Cor Cinza, Área de Componente Projetada (Bruta) (m2) | EI-REV-Pintura Acrílica Cor Cinza, Volume Componente (Líquido) (m3) | EI-REV-Pintura Acrílica Cor Cinza, Volume do componente (Bruto) (m3) | EI-REV-Massa Acrílica (externa) 1, Massa (kg) | EI-REV-Massa Acrílica (externa) 1, Área de Componente Projetada (Líquida) (m2) | EI-REV-Massa Acrílica (externa) 1, Área de Componente Projetada (Bruta) (m2) | EI-REV-Massa Acrílica (externa) 1, Volume Componente (Líquido) (m3) | EI-REV-Massa Acrílica (externa) 1, Volume do componente (Bruto) (m3) | TIJOLO - CERAMICO 14x19x39 - espessura 20cm, Massa (kg) | TIJOLO - CERAMICO 14x19x39 - espessura 20cm, Área de Componente Projetada (Líquida) (m2) = TIJOLO - CERAMICO 14x19x39 - espessura 20cm, Área de Componente Projetada (Bruta) (m2) | TIJOLO - CERAMICO 14x19x39 - espessura 20cm, Volume Componente (Líquido) (m3) = TIJOLO - CERAMICO 14x19x39 - espessura 20cm, Volume do componente (Bruto) (m3) | EI-REV-Chapisco (externo) 2, Massa (kg) | EI-REV-Chapisco (externo) 2, Área de Componente Projetada (Líquida) (m2) | EI-REV-Chapisco (externo) 2, Área de Componente Projetada (Bruta) (m2) | EI-REV-Chapisco (externo) 2, Volume Componente (Líquido) (m3) | EI-REV-Chapisco (externo) 2, Volume do componente (Bruto) (m3) | EI-REV-Massa única - Fachada 2, Massa (kg) | EI-REV-Massa única - Fachada 2, Área de Componente Projetada (Líquida) (m2) | EI-REV-Massa única - Fachada 2, Área de Componente Projetada (Bruta) (m2) | EI-REV-Massa única - Fachada 2, Volume Componente (Líquido) (m3) | EI-REV-Massa única - Fachada 2, Volume do componente (Bruto) (m3) | EI-REV-Massa Acrílica (externa) 2, Massa (kg) | EI-REV-Massa Acrílica (externa) 2, Área de Componente Projetada (Líquida) (m2) | EI-REV-Massa Acrílica (externa) 2, Área de Componente Projetada (Bruta) (m2) | EI-REV-Massa Acrílica (externa) 2, Volume Componente (Líquido) (m3) | EI-REV-Massa Acrílica (externa) 2, Volume do componente (Bruto) (m3) | EI-REV-Pintura Acrílica Cor Branco Gelo, Massa (kg) | EI-REV-Pintura Acrílica Cor Branco Gelo, Área de Componente Projetada (Líquida) (m2) | EI-REV-Pintura Acrílica Cor Branco Gelo, Área de Componente Projetada (Bruta) (m2) | EI-REV-Pintura Acrílica Cor Branco Gelo, Volume Componente (Líquido) (m3) | EI-REV-Pintura Acrílica Cor Branco Gelo, Volume do componente (Bruto) (m3) | EI-REV-Chapisco (externo) 1, Massa (kg) | EI-REV-Chapisco (externo) 1, Área de Componente Projetada (Líquida) (m2) | EI-REV-Chapisco (externo) 1, Área de Componente Projetada (Bruta) (m2) | EI-REV-Chapisco (externo) 1, Espessura do Componente (m) = EI-REV-Chapisco (externo) 1, Largura do Componente Retangular (m) | EI-REV-Chapisco (externo) 1, Altura do Componente Retangular (m) | EI-REV-Chapisco (externo) 1, Área de Seção Transversal do Componente (m2) | EI-REV-Chapisco (externo) 1, Volume Componente (Líquido) (m3) | EI-REV-Chapisco (externo) 1, Volume do componente (Bruto) (m3) | EI-REV-Massa única - Fachada 1, Massa (kg) | EI-REV-Massa única - Fachada 1, Área de Componente Projetada (Líquida) (m2) | EI-REV-Massa única - Fachada 1, Área de Componente Projetada (Bruta) (m2) | EI-REV-Massa única - Fachada 1, Espessura do Componente (m) = EI-REV-Massa única - Fachada 1, Largura do Componente Retangular (m) | EI-REV-Massa única - Fachada 1, Altura do Componente Retangular (m) | EI-REV-Massa única - Fachada 1, Área de Seção Transversal do Componente (m2) | EI-REV-Massa única - Fachada 1, Volume Componente (Líquido) (m3) | EI-REV-Massa única - Fachada 1, Volume do componente (Bruto) (m3)
AL14 | BLOCO B | 67.6949 | 3.47153 | 3.47153 | 0.052073 | 0.052073 | 22.565 | 3.47153 | 3.47153 | 0.0173577 | 0.0173577 | 202.568 | 3.47153 | 0.312605 | 22.4953 | 3.46809 | 3.46809 | 0.0173041 | 0.0173041 | 22.5523 | 3.46959 | 3.46959 | 0.0173479 | 0.0173479 | 22.5621 | 3.47109 | 3.47109 | 0.0173554 | 0.0173554 | 67.6924 | 3.47153 | 3.47153 | 0.0520711 | 0.0520711 | Component Quantities - EI-REV-Massa Acrílica (externa) 1: 3 with these values
AL14 | BLOCO B | 68.0781 | 3.49118 | 3.49118 | 0.0523677 | 0.0523677 | 22.6075 | 3.47808 | 3.47808 | 0.0173904 | 0.0173904 | 228.785 | 3.61293 | 0.353063 | 22.5851 | 3.47464 | 3.47464 | 0.0173732 | 0.0173732 | 22.5949 | 3.47614 | 3.47614 | 0.0173807 | 0.0173807 | 22.6046 | 3.47764 | 3.47764 | 0.0173882 | 0.0173882 | 68.0759 | 3.49118 | 3.49118 | 0.0523661 | 0.0523661 | 22.5159 | 3.47808 | 3.47808 | 0.005 | 1.31 | 0.00655 | 0.0173199 | 0.0173199 | Component Quantities - EI-REV-Massa Acrílica (externa) 1: 2 with these values
AL14 | BLOCO B | 47.5139 | 2.43661 | 2.43661 | 0.0365492 | 0.0365492 | 15.9476 | 2.45326 | 2.45326 | 0.0122674 | 0.0122674 | 179.695 | 2.51566 | 0.277307 | 16.2328 | 2.49757 | 2.49757 | 0.0124867 | 0.0124867 | 16.2439 | 2.49907 | 2.49907 | 0.0124953 | 0.0124953 | 16.2537 | 2.50057 | 2.50057 | 0.0125028 | 0.0125028 | 48.7888 | 2.50207 | 2.50207 | 0.0375299 | 0.0375299 | 12.3751 | 1.90386 | 1.90386 | 0.005 | 1.31 | 0.00655 | 0.00951929 | 0.00951929 | 12.3398 | 1.89881 | 1.89881 | 0.005 | 1.31 | 0.00655 | 0.00949212 | 0.00949212
AL14 | BLOCO B | 47.5139 | 2.43661 | 2.43656 | 0.0365492 | 0.0365484 | 15.9464 | 2.45329 | 2.45324 | 0.0122665 | 0.0122662 | 176.874 | 1.94969 | 0.272954 | 16.2351 | 2.49758 | 2.49752 | 0.0124886 | 0.0124884 | 16.244 | 2.49908 | 2.49902 | 0.0124954 | 0.0124951 | 16.2537 | 2.50058 | 2.50052 | 0.0125029 | 0.0125026 | 48.7889 | 2.50208 | 2.50202 | 0.0375299 | 0.0375292 | 16.0121 | 2.46339 | 2.46334 | 0.005 | 1.31 | 0.00655 | 0.012317 | 0.0123164 | 15.9792 | 2.45834 | 2.45829 | 0.005 | 1.31 | 0.00655 | 0.0122917 | 0.0122915
AL14 | BLOCO A | 47.5137 | 2.4366 | 2.4366 | 0.036549 | 0.036549 | 15.9476 | 2.45347 | 2.45347 | 0.0122674 | 0.0122674 | 173.734 | 2.56832 | 0.268108 | 16.6941 | 2.56832 | 2.56832 | 0.0128416 | 0.0128416 | 16.7354 | 2.57467 | 2.57467 | 0.0128734 | 0.0128734 | 16.7779 | 2.58122 | 2.58122 | 0.0129061 | 0.0129061 | 50.4599 | 2.58777 | 2.58777 | 0.0388153 | 0.0388153 | 15.9663 | 2.46357 | 2.46357 | 0.005 | 1.31 | 0.00655 | 0.0122818 | 0.0122818 | 15.9804 | 2.45852 | 2.45852 | 0.005 | 1.31 | 0.00655 | 0.0122926 | 0.0122926
AL14 | BLOCO A | 47.5143 | 2.43663 | 2.43663 | 0.0365495 | 0.0365495 | 15.9462 | 2.45327 | 2.45327 | 0.0122663 | 0.0122663 | 176.001 | 2.55932 | 0.271606 | 16.1933 | 2.49764 | 2.49764 | 0.0124564 | 0.0124564 | 16.2444 | 2.49914 | 2.49914 | 0.0124957 | 0.0124957 | 16.2542 | 2.50064 | 2.50064 | 0.0125032 | 0.0125032 | 48.7901 | 2.50214 | 2.50214 | 0.0375308 | 0.0375308 | 16.0119 | 2.46337 | 2.46337 | 0.005 | 1.31 | 0.00655 | 0.0123168 | 0.0123168 | 15.9791 | 2.45832 | 2.45832 | 0.005 | 1.31 | 0.00655 | 0.0122916 | 0.0122916

# IfcWall: GENÉRICO - VEDAÇÃO INTERNA 150 (3)
In: TÉRREO
Classification: Parede (Classificação Archicad); Material: GENÉRICO - VEDAÇÃO INTERNA 0.15 m
FNDE - Alvenarias: Mureta; Sistemas de Cobertura: -; Esquadrias - Fechamentos metálicos e Gradis: -; 0_ID: Parede-110
Pset_WallCommon - IsExternal: yes; LoadBearing: no
Component Quantities - GENÉRICO - VEDAÇÃO INTERNA, Massa: 0 kg; GENÉRICO - VEDAÇÃO INTERNA, Área de Componente Projetada (Líquida): 0 m2; GENÉRICO - VEDAÇÃO INTERNA, Espessura do Componente: 0.15 m; GENÉRICO - VEDAÇÃO INTERNA, Altura do Componente Retangular: 2 m; GENÉRICO - VEDAÇÃO INTERNA, Largura do Componente Retangular: 0.15 m; GENÉRICO - VEDAÇÃO INTERNA, Área de Seção Transversal do Componente: 0.3 m2; GENÉRICO - VEDAÇÃO INTERNA, Volume Componente (Líquido): 0 m3
Name | GENÉRICO - VEDAÇÃO INTERNA, Área de Componente Projetada (Bruta) (m2) | GENÉRICO - VEDAÇÃO INTERNA, Volume do componente (Bruto) (m3) | 1_Bloco
Parede-110 | 2.6 | 0.39
2 x Parede-110 | 3 | 0.45 | MURETAS

# IfcWall: GENÉRICO - VEDAÇÃO INTERNA 50, AL09
In: TÉRREO
Classification: Parede (Classificação Archicad); Material: GENÉRICO - VEDAÇÃO INTERNA 0.05 m
FNDE - Alvenarias: Alvenaria de Vedação / Edificação; Sistemas de Cobertura: -; Esquadrias - Fechamentos metálicos e Gradis: -; 1_Bloco: BLOCO A; 0_ID: AL09
Pset_WallCommon - IsExternal: no; LoadBearing: no
Component Quantities - GENÉRICO - VEDAÇÃO INTERNA, Massa: 10.0005 kg; GENÉRICO - VEDAÇÃO INTERNA, Área de Componente Projetada (Líquida): 0.2882 m2; GENÉRICO - VEDAÇÃO INTERNA, Área de Componente Projetada (Bruta): 5.0882 m2; GENÉRICO - VEDAÇÃO INTERNA, Espessura do Componente: 0.05 m; GENÉRICO - VEDAÇÃO INTERNA, Altura do Componente Retangular: 2.06 m; GENÉRICO - VEDAÇÃO INTERNA, Largura do Componente Retangular: 0.05 m; GENÉRICO - VEDAÇÃO INTERNA, Área de Seção Transversal do Componente: 0.103 m2; GENÉRICO - VEDAÇÃO INTERNA, Volume Componente (Líquido): 0.01441 m3; GENÉRICO - VEDAÇÃO INTERNA, Volume do componente (Bruto): 0.25441 m3

# IfcWall: TIJOLO - CERAMICO 9x19x39 - espessura 15cm 90, AL09
In: TÉRREO
Classification: Parede (Classificação Archicad); Material: TIJOLO - CERAMICO 9x19x39 - espessura 15cm 0.09 m
FNDE - Alvenarias: Alvenaria de Vedação / Edificação; Sistemas de Cobertura: -; Esquadrias - Fechamentos metálicos e Gradis: -; 1_Bloco: BLOCO A; 0_ID: AL09
Pset_WallCommon - IsExternal: no; LoadBearing: no
Component Quantities - TIJOLO - CERAMICO 9x19x39 - espessura 15cm, Massa: 50.388 kg; TIJOLO - CERAMICO 9x19x39 - espessura 15cm, Área de Componente Projetada (Líquida): 0.863992 m2; TIJOLO - CERAMICO 9x19x39 - espessura 15cm, Área de Componente Projetada (Bruta): 0.863992 m2; TIJOLO - CERAMICO 9x19x39 - espessura 15cm, Espessura do Componente: 0.09 m; TIJOLO - CERAMICO 9x19x39 - espessura 15cm, Altura do Componente Retangular: 3.1 m; TIJOLO - CERAMICO 9x19x39 - espessura 15cm, Largura do Componente Retangular: 0.09 m; TIJOLO - CERAMICO 9x19x39 - espessura 15cm, Área de Seção Transversal do Componente: 0.279 m2; TIJOLO - CERAMICO 9x19x39 - espessura 15cm, Volume Componente (Líquido): 0.0777592 m3; TIJOLO - CERAMICO 9x19x39 - espessura 15cm, Volume do componente (Bruto): 0.0777592 m3

# IfcWall: TIJOLO - MACIÇO 5x10x20 100 (3)
In: TÉRREO
Classification: Parede (Classificação Archicad); Material: TIJOLO - MACIÇO 5x10x20 0.1 m
FNDE - Alvenarias: Alvenaria de Vedação / Edificação; Sistemas de Cobertura: -; Esquadrias - Fechamentos metálicos e Gradis: -; 1_Bloco: ÁREAS EXTERNAS; 0_ID: Parede-110
Pset_WallCommon - IsExternal: yes; LoadBearing: no
Component Quantities - TIJOLO - MACIÇO 5x10x20, Espessura do Componente: 0.1 m; TIJOLO - MACIÇO 5x10x20, Altura do Componente Retangular: 0.4 m; TIJOLO - MACIÇO 5x10x20, Largura do Componente Retangular: 0.1 m; TIJOLO - MACIÇO 5x10x20, Área de Seção Transversal do Componente: 0.04 m2
Name | TIJOLO - MACIÇO 5x10x20, Massa (kg) | TIJOLO - MACIÇO 5x10x20, Área de Componente Projetada (Líquida) (m2) = TIJOLO - MACIÇO 5x10x20, Área de Componente Projetada (Bruta) (m2) | TIJOLO - MACIÇO 5x10x20, Volume Componente (Líquido) (m3) = TIJOLO - MACIÇO 5x10x20, Volume do componente (Bruto) (m3)
2 x Parede-110 | 227.961 | 3.51792 | 0.351792
Parede-110 | 163.297 | 2.52002 | 0.252002

# IfcWasteTerminal: Grade 27 (4)
In: TÉRREO
Classification: Ralo de Piso (Classificação Archicad)
Component Quantities - Component, Volume Componente (Líquido): 0.00057344 m3; Component, Volume do componente (Bruto): 0.00057344 m3
Name | 1_Bloco
3 x  | BLOCO B
 | BLOCO A

# IfcWasteTerminal: Ralo de Piso Retangular 26 (30)
In: TÉRREO
Classification: Ralo de Piso (Classificação Archicad)
Component Quantities - Component, Volume Componente (Líquido): 0.000518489 m3; Component, Volume do componente (Bruto): 0.000518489 m3
Name | 1_Bloco
12 x  | BLOCO B
17 x  | BLOCO A
CJR-73 | BLOCO A | FNDE - 0_ID: CJR-73

# IfcWindow: FNDE-JA-Guilhotina com tela mosquiteira 110x145, JA-01
In: TÉRREO
Type - PartitioningType: DOUBLE_PANEL_HORIZONTAL
OverallHeight: 1.25 m; OverallWidth: 0.7 m; Classification: Janela (Classificação Archicad); Material: Água
FNDE - Esquadrias - Grupo da Esquadria: JANELA DE ALUMÍNIO; Soleira/Peitoril: PEITORIL EM GRANITO CINZA ANDORINHA E=2cm; Esquadrias - Tipo de Abertura: GUILHOTINA; Esquadrias - Descrição ou Complemento: COM TELA MOSQUITEIRA; Esquadrias - Tipo de Vidro: TEMPERADO INCOLOR 6mm; 1_Bloco: BLOCO A; 0_ID: JA-01; Esquadrias - Verga e Contra-verga: C5-IN - Verga e Contra-verga Interna
Pset_WindowCommon - IsExternal: no
Component Quantities - Água, Massa: 9.68129 kg; Água, Volume Componente (Líquido): 0.00968129 m3; Água, Volume do componente (Bruto): 0.00968129 m3

# IfcWindow: FNDE-JA-Guilhotina com tela mosquiteira e bandeira 110x195, JA-02
In: TÉRREO
OverallHeight: 1.95 m; OverallWidth: 1.1 m; Classification: Janela (Classificação Archicad); Material: Água
FNDE - Esquadrias - Grupo da Esquadria: JANELA DE ALUMÍNIO; Soleira/Peitoril: PEITORIL EM GRANITO CINZA ANDORINHA E=2cm; Esquadrias - Tipo de Abertura: GUILHOTINA; Esquadrias - Descrição ou Complemento: COM TELA MOSQUITEIRA; Esquadrias - Tipo de Vidro: TEMPERADO INCOLOR 6mm; 1_Bloco: BLOCO A; 0_ID: JA-02; Esquadrias - Verga e Contra-verga: C3-IN - Contra-verga Interna
Pset_WindowCommon - IsExternal: no
Component Quantities - Água, Massa: 22.2676 kg; Água, Volume Componente (Líquido): 0.0222676 m3; Água, Volume do componente (Bruto): 0.0222676 m3

# IfcWindow: FNDE-JA-Guilhotina com tela mosquiteira e bandeira 140x195, JA-03
In: TÉRREO
OverallHeight: 1.95 m; OverallWidth: 1.4 m; Classification: Janela (Classificação Archicad); Material: Água
FNDE - Esquadrias - Grupo da Esquadria: JANELA DE ALUMÍNIO; Soleira/Peitoril: PEITORIL EM GRANITO CINZA ANDORINHA E=2cm; Esquadrias - Tipo de Abertura: GUILHOTINA; Esquadrias - Descrição ou Complemento: COM TELA MOSQUITEIRA; Esquadrias - Tipo de Vidro: TEMPERADO INCOLOR 6mm; 1_Bloco: BLOCO A; 0_ID: JA-03; Esquadrias - Verga e Contra-verga: C3-IN - Contra-verga Interna
Pset_WindowCommon - IsExternal: no
Component Quantities - Água, Massa: 26.3657 kg; Água, Volume Componente (Líquido): 0.0263657 m3; Água, Volume do componente (Bruto): 0.0263657 m3

# IfcWindow: FNDE-JA-Janela recepção com peitoril, JA-04
In: TÉRREO
OverallHeight: 1.28 m; OverallWidth: 2 m; Classification: Janela (Classificação Archicad); Material: Água
FNDE - Esquadrias - Grupo da Esquadria: JANELA DE ALUMÍNIO; Soleira/Peitoril: PEITORIL EM GRANITO CINZA ANDORINHA E=2cm; Esquadrias - Tipo de Abertura: FIXA; Esquadrias - Tipo de Vidro: TEMPERADO INCOLOR 6mm; 1_Bloco: BLOCO A; 0_ID: JA-04; Esquadrias - Verga e Contra-verga: C5-IN - Verga e Contra-verga Interna
Pset_WindowCommon - IsExternal: no
Component Quantities - Água, Massa: 39.4305 kg; Água, Volume Componente (Líquido): 0.0394305 m3; Água, Volume do componente (Bruto): 0.0394305 m3

# IfcWindow: FNDE-Janela 8x2 folhas Maxim-ar (3)
In: TÉRREO
Type - PartitioningType: SINGLE_PANEL
OverallHeight: 1 m; OverallWidth: 5.6 m; Classification: Janela (Classificação Archicad); Material: Água
FNDE - Esquadrias - Grupo da Esquadria: JANELA DE ALUMÍNIO; Soleira/Peitoril: PEITORIL EM GRANITO CINZA ANDORINHA E=2cm; Esquadrias - Tipo de Abertura: MAXIM-AR; Esquadrias - Tipo de Vidro: TEMPERADO INCOLOR 6mm; 0_ID: JA-12; Esquadrias - Verga e Contra-verga: C4-EX - Contra-verga Externa
Pset_WindowCommon - IsExternal: yes
Component Quantities - Água, Massa: 143.591 kg; Água, Volume Componente (Líquido): 0.143591 m3; Água, Volume do componente (Bruto): 0.143591 m3
Name | 1_Bloco
2 x JA-12 | BLOCO B
JA-12 | BLOCO A

# IfcWindow: Janela 27 (3)
In: TÉRREO
Type - PartitioningType: DOUBLE_PANEL_HORIZONTAL
OverallHeight: 0.75 m; OverallWidth: 0.7 m; Classification: Janela (Classificação Archicad)
Pset_WindowCommon - ThermalTransmittance: 0; GlazingAreaFraction: 0.28
FNDE - Esquadrias - Grupo da Esquadria: JANELA DE ALUMÍNIO; Soleira/Peitoril: PEITORIL EM GRANITO CINZA ANDORINHA E=2cm; Esquadrias - Tipo de Abertura: MAXIM-AR; Esquadrias - Tipo de Vidro: TEMPERADO INCOLOR 6mm; 1_Bloco: BLOCO A; 0_ID: JA-09; Esquadrias - Verga e Contra-verga: C3-IN - Contra-verga Interna
Component Quantities - Component, Volume Componente (Líquido): 0.014516 m3; Component, Volume do componente (Bruto): 0.014516 m3
Name | IsExternal
JA-09 | yes
2 x JA-09 | no

# IfcWindow: Janela 27 (4)
In: TÉRREO
Type - PartitioningType: SINGLE_PANEL
Classification: Janela (Classificação Archicad)
Pset_WindowCommon - ThermalTransmittance: 0; IsExternal: yes
FNDE - Esquadrias - Grupo da Esquadria: JANELA DE ALUMÍNIO; Soleira/Peitoril: -; Esquadrias - Tipo de Abertura: FIXA; Esquadrias - Tipo de Vidro: TELA DE NYLON EXTERNA; 1_Bloco: CASA DE BOMBAS / GÁS / LIXO
Name | OverallHeight (m) | OverallWidth (m) | GlazingAreaFraction | 0_ID | Esquadrias - Verga e Contra-verga | Component, Volume Componente (Líquido) (m3) = Component, Volume do componente (Bruto) (m3)
JA-13 | 0.21 | 0.6 | 0.081 | JA-13 | C6-EX - Verga e Contra-verga Externa | 0.00225
JA-13 | 0.21 | 0.6 | 0.081 | JA-13 | C4-EX - Contra-verga Externa | 0.00225
JA-14 | 0.2 | 1.2 | 0.1596 | JA-14 | C5-IN - Verga e Contra-verga Interna | 0.00402
JA-14 | 0.2 | 1.2 | 0.1596 | JA-14 | C3-IN - Contra-verga Interna | 0.00402

# IfcWindow: Janela Dupla 27 (5)
In: TÉRREO
Type - PartitioningType: USERDEFINED
OverallHeight: 0.75 m; OverallWidth: 1.35 m; Classification: Janela (Classificação Archicad)
Pset_WindowCommon - ThermalTransmittance: 0; GlazingAreaFraction: 0.55
FNDE - Esquadrias - Grupo da Esquadria: JANELA DE ALUMÍNIO; Soleira/Peitoril: PEITORIL EM GRANITO CINZA ANDORINHA E=2cm; Esquadrias - Tipo de Abertura: MAXIM-AR; Esquadrias - Tipo de Vidro: TEMPERADO INCOLOR 6mm; 1_Bloco: BLOCO A; 0_ID: JA-10
Component Quantities - Component, Volume Componente (Líquido): 0.027531 m3; Component, Volume do componente (Bruto): 0.027531 m3
Name | IsExternal | Esquadrias - Verga e Contra-verga
3 x JA-10 | yes | C4-EX - Contra-verga Externa
2 x JA-10 | no | C3-IN - Contra-verga Interna

# IfcWindow: Janela Multi-Caixilho Horizontal 27 (2)
In: TÉRREO
Type - PartitioningType: USERDEFINED
OverallHeight: 0.5 m; OverallWidth: 4.2 m; Classification: Janela (Classificação Archicad)
Pset_WindowCommon - ThermalTransmittance: 0; GlazingAreaFraction: 1.4391; IsExternal: no
FNDE - Esquadrias - Grupo da Esquadria: JANELA DE ALUMÍNIO; Soleira/Peitoril: PEITORIL EM GRANITO CINZA ANDORINHA E=2cm; Esquadrias - Tipo de Abertura: MAXIM-AR; Esquadrias - Tipo de Vidro: TEMPERADO INCOLOR 6mm; 1_Bloco: BLOCO B; 0_ID: JA-11; Esquadrias - Verga e Contra-verga: C3-IN - Contra-verga Interna
Component Quantities - Component, Volume Componente (Líquido): 0.0538019 m3; Component, Volume do componente (Bruto): 0.0538019 m3

# IfcWindow: Janela Tripla 27, JA-05
In: TÉRREO
Type - PartitioningType: TRIPLE_PANEL_VERTICAL
OverallHeight: 0.5 m; OverallWidth: 2.1 m; Classification: Janela (Classificação Archicad)
Pset_WindowCommon - ThermalTransmittance: 0; GlazingAreaFraction: 0.7137; IsExternal: no
FNDE - Esquadrias - Grupo da Esquadria: JANELA DE ALUMÍNIO; Soleira/Peitoril: PEITORIL EM GRANITO CINZA ANDORINHA E=2cm; Esquadrias - Tipo de Abertura: MAXIM-AR; Esquadrias - Tipo de Vidro: TEMPERADO INCOLOR 6mm; 1_Bloco: BLOCO A; 0_ID: JA-05; Esquadrias - Verga e Contra-verga: C3-IN - Contra-verga Interna
Component Quantities - Component, Volume Componente (Líquido): 0.0270975 m3; Component, Volume do componente (Bruto): 0.0270975 m3

# IfcWindow: Janela Tripla 27 (12)
In: TÉRREO
Type - PartitioningType: USERDEFINED
OverallWidth: 2.1 m; Classification: Janela (Classificação Archicad)
Pset_WindowCommon - ThermalTransmittance: 0
FNDE - Esquadrias - Grupo da Esquadria: JANELA DE ALUMÍNIO; Soleira/Peitoril: PEITORIL EM GRANITO CINZA ANDORINHA E=2cm; Esquadrias - Tipo de Abertura: MAXIM-AR; Esquadrias - Tipo de Vidro: TEMPERADO INCOLOR 6mm
Name | OverallHeight (m) | GlazingAreaFraction | IsExternal | 1_Bloco | 0_ID | Esquadrias - Verga e Contra-verga | Component, Volume Componente (Líquido) (m3) = Component, Volume do componente (Bruto) (m3)
2 x JA-06 | 0.75 | 1.14705 | no | BLOCO B | JA-06 | C3-IN - Contra-verga Interna | 0.0300673
2 x JA-07 | 1 | 1.4823 | yes | BLOCO B | JA-07 | C4-EX - Contra-verga Externa | 0.0475735
2 x JA-08 | 1.5 | 2.2509 | no | BLOCO A | JA-08 | C3-IN - Contra-verga Interna | 0.0655335
4 x JA-06 | 0.75 | 1.14705 | no | BLOCO A | JA-06 | C3-IN - Contra-verga Interna | 0.0300673
2 x JA-07 | 1 | 1.4823 | yes | BLOCO A | JA-07 | C4-EX - Contra-verga Externa | 0.0475735

# IfcWindow: Várias Estruturas- 3 Segmentos - 200 x 1050 x 2136 (25+2086+25), V02
In: TÉRREO
Classification: Janela (Classificação Archicad); Material: EI-MTL-TELA DE NYLON (5), Alumínio (6)
FNDE - Esquadrias - Grupo da Esquadria: -; Soleira/Peitoril: -; Esquadrias - Tipo de Abertura: -; Esquadrias - Tipo de Vidro: -; 1_Bloco: BLOCO A; 0_ID: V02; Esquadrias - Verga e Contra-verga: -
Pset_WindowCommon - IsExternal: yes
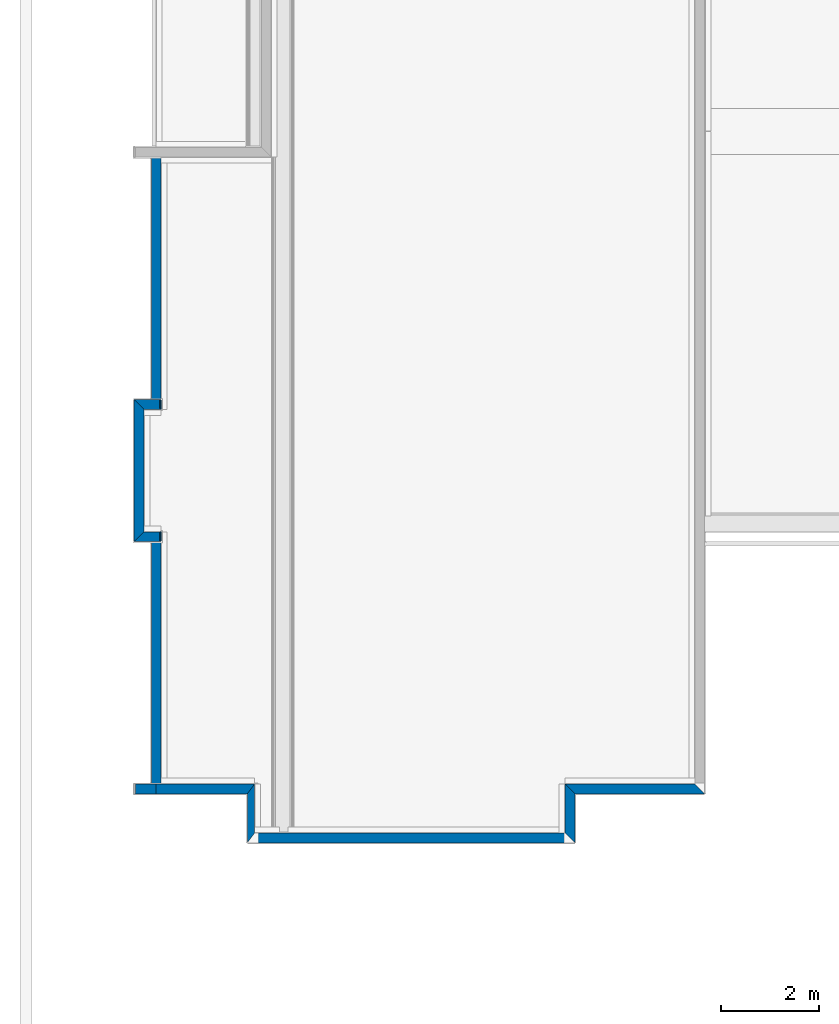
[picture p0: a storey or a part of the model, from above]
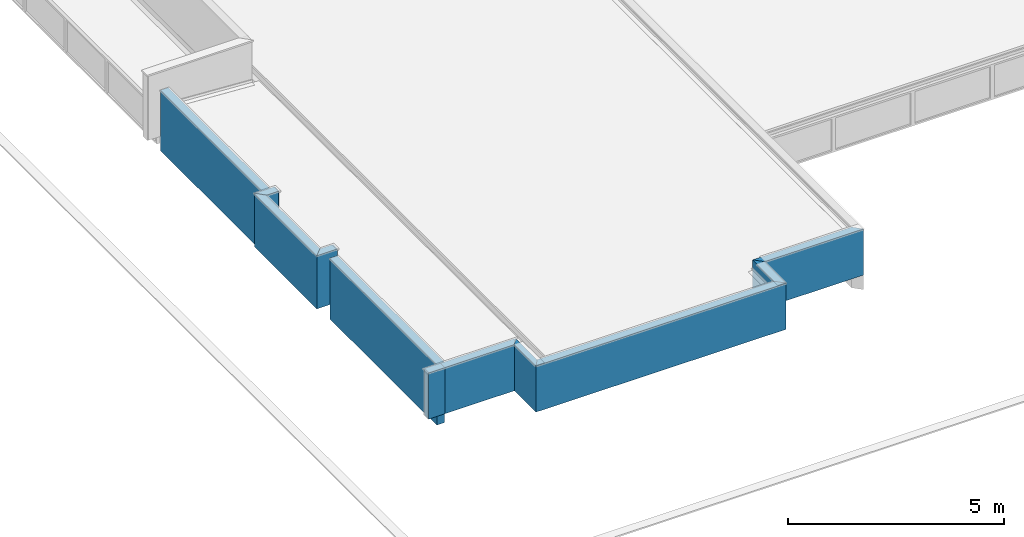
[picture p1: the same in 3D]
Properties of the parts of a building model (IFC4), part 22 of 22

# IfcWindow: Várias Estruturas- 3 Segmentos - 200 x 1050 x 2136 (25+2086+25), V02
Component Quantities - EI-MTL-TELA DE NYLON 1, Massa: 30.0694 kg; EI-MTL-TELA DE NYLON 1, Altura do Componente Retangular: 1.015 m; EI-MTL-TELA DE NYLON 1, Largura do Componente Retangular: 0.15 m; EI-MTL-TELA DE NYLON 1, Área de Seção Transversal do Componente: 0.15225 m2; EI-MTL-TELA DE NYLON 1, Volume Componente (Líquido): 0.00380625 m3; EI-MTL-TELA DE NYLON 1, Volume do componente (Bruto): 0.00380625 m3; Alumínio 1, Massa: 4.0425 kg; Alumínio 1, Área de Seção Transversal do Componente: 0.05775 m2; Alumínio 1, Volume Componente (Líquido): 0.00144375 m3; Alumínio 1, Volume do componente (Bruto): 0.00144375 m3; EI-MTL-TELA DE NYLON 2, Massa: 8.6525 kg; EI-MTL-TELA DE NYLON 2, Altura do Componente Retangular: 0.0035 m; EI-MTL-TELA DE NYLON 2, Largura do Componente Retangular: 0.15 m; EI-MTL-TELA DE NYLON 2, Área de Seção Transversal do Componente: 0.000525 m2; EI-MTL-TELA DE NYLON 2, Volume Componente (Líquido): 0.00109525 m3; EI-MTL-TELA DE NYLON 2, Volume do componente (Bruto): 0.00109525 m3; Alumínio 2, Massa: 2.55559 kg; Alumínio 2, Altura do Componente Retangular: 0.0175 m; Alumínio 2, Largura do Componente Retangular: 0.025 m; Alumínio 2, Área de Seção Transversal do Componente: 0.0004375 m2; Alumínio 2, Volume Componente (Líquido): 0.000912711 m3; Alumínio 2, Volume do componente (Bruto): 0.000912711 m3; EI-MTL-TELA DE NYLON 4, Massa: 83.6407 kg; EI-MTL-TELA DE NYLON 4, Altura do Componente Retangular: 1.015 m; EI-MTL-TELA DE NYLON 4, Largura do Componente Retangular: 0.005 m; EI-MTL-TELA DE NYLON 4, Área de Seção Transversal do Componente: 0.00507499 m2; EI-MTL-TELA DE NYLON 4, Volume Componente (Líquido): 0.0105874 m3; EI-MTL-TELA DE NYLON 4, Volume do componente (Bruto): 0.0105874 m3; Alumínio 4, Massa: 2.55613 kg; Alumínio 4, Altura do Componente Retangular: 0.0175092 m; Alumínio 4, Largura do Componente Retangular: 0.025 m; Alumínio 4, Área de Seção Transversal do Componente: 0.000437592 m2; Alumínio 4, Volume Componente (Líquido): 0.000912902 m3; Alumínio 4, Volume do componente (Bruto): 0.000912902 m3; Alumínio 5, Massa: 2.55559 kg; Alumínio 5, Área de Seção Transversal do Componente: 0.0004375 m2; Alumínio 5, Volume Componente (Líquido): 0.000912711 m3; Alumínio 5, Volume do componente (Bruto): 0.000912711 m3; EI-MTL-TELA DE NYLON 1: 2 with these values; Alumínio 1: 2 with these values; EI-MTL-TELA DE NYLON 2: 2 with these values; Alumínio 2: 2 with these values

# IfcWindow: Várias Estruturas- 3 Segmentos - 200 x 800 x 1400 (25+1350+25) (2)
In: TÉRREO
Classification: Janela (Classificação Archicad); Material: EI-MTL-TELA DE NYLON (5), Alumínio (6)
FNDE - Esquadrias - Grupo da Esquadria: -; Soleira/Peitoril: -; Esquadrias - Tipo de Abertura: -; Esquadrias - Tipo de Vidro: -; 1_Bloco: BLOCO A; 0_ID: V02; Esquadrias - Verga e Contra-verga: -
Pset_WindowCommon - IsExternal: yes
Component Quantities - EI-MTL-TELA DE NYLON 1, Massa: 22.91 kg; EI-MTL-TELA DE NYLON 1, Altura do Componente Retangular: 0.773333 m; EI-MTL-TELA DE NYLON 1, Largura do Componente Retangular: 0.15 m; EI-MTL-TELA DE NYLON 1, Área de Seção Transversal do Componente: 0.116 m2; EI-MTL-TELA DE NYLON 1, Volume Componente (Líquido): 0.0029 m3; EI-MTL-TELA DE NYLON 1, Volume do componente (Bruto): 0.0029 m3; Alumínio 1, Massa: 3.08 kg; Alumínio 1, Área de Seção Transversal do Componente: 0.044 m2; Alumínio 1, Volume Componente (Líquido): 0.0011 m3; Alumínio 1, Volume do componente (Bruto): 0.0011 m3; EI-MTL-TELA DE NYLON 2, Massa: 4.266 kg; EI-MTL-TELA DE NYLON 2, Altura do Componente Retangular: 0.00266667 m; EI-MTL-TELA DE NYLON 2, Largura do Componente Retangular: 0.15 m; EI-MTL-TELA DE NYLON 2, Área de Seção Transversal do Componente: 0.0004 m2; EI-MTL-TELA DE NYLON 2, Volume Componente (Líquido): 0.00054 m3; EI-MTL-TELA DE NYLON 2, Volume do componente (Bruto): 0.00054 m3; Alumínio 2, Massa: 1.26 kg; Alumínio 2, Altura do Componente Retangular: 0.0133333 m; Alumínio 2, Largura do Componente Retangular: 0.025 m; Alumínio 2, Área de Seção Transversal do Componente: 0.000333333 m2; Alumínio 2, Volume Componente (Líquido): 0.00045 m3; Alumínio 2, Volume do componente (Bruto): 0.00045 m3; EI-MTL-TELA DE NYLON 4, Massa: 41.238 kg; EI-MTL-TELA DE NYLON 4, Altura do Componente Retangular: 0.773333 m; EI-MTL-TELA DE NYLON 4, Largura do Componente Retangular: 0.005 m; EI-MTL-TELA DE NYLON 4, Área de Seção Transversal do Componente: 0.00386666 m2; EI-MTL-TELA DE NYLON 4, Volume Componente (Líquido): 0.00521999 m3; EI-MTL-TELA DE NYLON 4, Volume do componente (Bruto): 0.00521999 m3; Alumínio 4, Massa: 1.26026 kg; Alumínio 4, Altura do Componente Retangular: 0.0133403 m; Alumínio 4, Largura do Componente Retangular: 0.025 m; Alumínio 4, Área de Seção Transversal do Componente: 0.000333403 m2; Alumínio 4, Volume Componente (Líquido): 0.000450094 m3; Alumínio 4, Volume do componente (Bruto): 0.000450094 m3; Alumínio 5, Massa: 1.26 kg; Alumínio 5, Área de Seção Transversal do Componente: 0.000333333 m2; Alumínio 5, Volume Componente (Líquido): 0.00045 m3; Alumínio 5, Volume do componente (Bruto): 0.00045 m3; EI-MTL-TELA DE NYLON 1: 2 with these values; Alumínio 1: 2 with these values; EI-MTL-TELA DE NYLON 2: 2 with these values; Alumínio 2: 2 with these values

# IfcWindow: Várias Estruturas- 3 Segmentos - 200 x 800 x 2148 (25+2098+25), V02
In: TÉRREO
Classification: Janela (Classificação Archicad); Material: EI-MTL-TELA DE NYLON (5), Alumínio (6)
FNDE - Esquadrias - Grupo da Esquadria: -; Soleira/Peitoril: -; Esquadrias - Tipo de Abertura: -; Esquadrias - Tipo de Vidro: -; 1_Bloco: BLOCO A; 0_ID: V02; Esquadrias - Verga e Contra-verga: -
Pset_WindowCommon - IsExternal: yes
Component Quantities - EI-MTL-TELA DE NYLON 1, Massa: 22.91 kg; EI-MTL-TELA DE NYLON 1, Altura do Componente Retangular: 0.773333 m; EI-MTL-TELA DE NYLON 1, Largura do Componente Retangular: 0.15 m; EI-MTL-TELA DE NYLON 1, Área de Seção Transversal do Componente: 0.116 m2; EI-MTL-TELA DE NYLON 1, Volume Componente (Líquido): 0.0029 m3; EI-MTL-TELA DE NYLON 1, Volume do componente (Bruto): 0.0029 m3; Alumínio 1, Massa: 3.08 kg; Alumínio 1, Área de Seção Transversal do Componente: 0.044 m2; Alumínio 1, Volume Componente (Líquido): 0.0011 m3; Alumínio 1, Volume do componente (Bruto): 0.0011 m3; EI-MTL-TELA DE NYLON 2, Massa: 6.63003 kg; EI-MTL-TELA DE NYLON 2, Altura do Componente Retangular: 0.00266667 m; EI-MTL-TELA DE NYLON 2, Largura do Componente Retangular: 0.15 m; EI-MTL-TELA DE NYLON 2, Área de Seção Transversal do Componente: 0.0004 m2; EI-MTL-TELA DE NYLON 2, Volume Componente (Líquido): 0.000839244 m3; EI-MTL-TELA DE NYLON 2, Volume do componente (Bruto): 0.000839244 m3; EI-MTL-TELA DE NYLON 3, Massa: 6.63002 kg; EI-MTL-TELA DE NYLON 3, Altura do Componente Retangular: 0.00266667 m; EI-MTL-TELA DE NYLON 3, Largura do Componente Retangular: 0.15 m; EI-MTL-TELA DE NYLON 3, Área de Seção Transversal do Componente: 0.0004 m2; EI-MTL-TELA DE NYLON 3, Volume Componente (Líquido): 0.000839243 m3; EI-MTL-TELA DE NYLON 3, Volume do componente (Bruto): 0.000839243 m3; Alumínio 2, Massa: 1.95823 kg; Alumínio 2, Altura do Componente Retangular: 0.0133333 m; Alumínio 2, Largura do Componente Retangular: 0.025 m; Alumínio 2, Área de Seção Transversal do Componente: 0.000333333 m2; Alumínio 2, Volume Componente (Líquido): 0.000699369 m3; Alumínio 2, Volume do componente (Bruto): 0.000699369 m3; EI-MTL-TELA DE NYLON 4, Massa: 64.0901 kg; EI-MTL-TELA DE NYLON 4, Altura do Componente Retangular: 0.773333 m; EI-MTL-TELA DE NYLON 4, Largura do Componente Retangular: 0.005 m; EI-MTL-TELA DE NYLON 4, Área de Seção Transversal do Componente: 0.00386666 m2; EI-MTL-TELA DE NYLON 4, Volume Componente (Líquido): 0.00811268 m3; EI-MTL-TELA DE NYLON 4, Volume do componente (Bruto): 0.00811268 m3; Alumínio 4, Massa: 1.95864 kg; Alumínio 4, Altura do Componente Retangular: 0.0133403 m; Alumínio 4, Largura do Componente Retangular: 0.025 m; Alumínio 4, Área de Seção Transversal do Componente: 0.000333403 m2; Alumínio 4, Volume Componente (Líquido): 0.000699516 m3; Alumínio 4, Volume do componente (Bruto): 0.000699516 m3; Alumínio 5, Massa: 1.95823 kg; Alumínio 5, Área de Seção Transversal do Componente: 0.000333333 m2; Alumínio 5, Volume Componente (Líquido): 0.000699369 m3; Alumínio 5, Volume do componente (Bruto): 0.000699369 m3; EI-MTL-TELA DE NYLON 1: 2 with these values; Alumínio 1: 2 with these values; Alumínio 2: 2 with these values

# IfcWindow: Várias Estruturas- 3 Segmentos - 200 x 800 x 750 (25+700+25), V02
In: TÉRREO
Classification: Janela (Classificação Archicad); Material: EI-MTL-TELA DE NYLON (5), Alumínio (6)
FNDE - Esquadrias - Grupo da Esquadria: -; Soleira/Peitoril: -; Esquadrias - Tipo de Abertura: -; Esquadrias - Tipo de Vidro: -; 1_Bloco: BLOCO A; 0_ID: V02; Esquadrias - Verga e Contra-verga: -
Pset_WindowCommon - IsExternal: yes
Component Quantities - EI-MTL-TELA DE NYLON 1, Massa: 22.91 kg; EI-MTL-TELA DE NYLON 1, Altura do Componente Retangular: 0.773333 m; EI-MTL-TELA DE NYLON 1, Largura do Componente Retangular: 0.15 m; EI-MTL-TELA DE NYLON 1, Área de Seção Transversal do Componente: 0.116 m2; EI-MTL-TELA DE NYLON 1, Volume Componente (Líquido): 0.0029 m3; EI-MTL-TELA DE NYLON 1, Volume do componente (Bruto): 0.0029 m3; Alumínio 1, Massa: 3.08 kg; Alumínio 1, Área de Seção Transversal do Componente: 0.044 m2; Alumínio 1, Volume Componente (Líquido): 0.0011 m3; Alumínio 1, Volume do componente (Bruto): 0.0011 m3; EI-MTL-TELA DE NYLON 2, Massa: 2.212 kg; EI-MTL-TELA DE NYLON 2, Altura do Componente Retangular: 0.00266667 m; EI-MTL-TELA DE NYLON 2, Largura do Componente Retangular: 0.15 m; EI-MTL-TELA DE NYLON 2, Área de Seção Transversal do Componente: 0.0004 m2; EI-MTL-TELA DE NYLON 2, Volume Componente (Líquido): 0.00028 m3; EI-MTL-TELA DE NYLON 2, Volume do componente (Bruto): 0.00028 m3; Alumínio 2, Massa: 0.653333 kg; Alumínio 2, Altura do Componente Retangular: 0.0133333 m; Alumínio 2, Largura do Componente Retangular: 0.025 m; Alumínio 2, Área de Seção Transversal do Componente: 0.000333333 m2; Alumínio 2, Volume Componente (Líquido): 0.000233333 m3; Alumínio 2, Volume do componente (Bruto): 0.000233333 m3; EI-MTL-TELA DE NYLON 4, Massa: 21.3826 kg; EI-MTL-TELA DE NYLON 4, Altura do Componente Retangular: 0.773333 m; EI-MTL-TELA DE NYLON 4, Largura do Componente Retangular: 0.005 m; EI-MTL-TELA DE NYLON 4, Área de Seção Transversal do Componente: 0.00386666 m2; EI-MTL-TELA DE NYLON 4, Volume Componente (Líquido): 0.00270666 m3; EI-MTL-TELA DE NYLON 4, Volume do componente (Bruto): 0.00270666 m3; Alumínio 4, Massa: 0.65347 kg; Alumínio 4, Altura do Componente Retangular: 0.0133403 m; Alumínio 4, Largura do Componente Retangular: 0.025 m; Alumínio 4, Área de Seção Transversal do Componente: 0.000333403 m2; Alumínio 4, Volume Componente (Líquido): 0.000233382 m3; Alumínio 4, Volume do componente (Bruto): 0.000233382 m3; Alumínio 5, Massa: 0.653333 kg; Alumínio 5, Área de Seção Transversal do Componente: 0.000333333 m2; Alumínio 5, Volume Componente (Líquido): 0.000233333 m3; Alumínio 5, Volume do componente (Bruto): 0.000233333 m3; EI-MTL-TELA DE NYLON 1: 2 with these values; Alumínio 1: 2 with these values; EI-MTL-TELA DE NYLON 2: 2 with these values; Alumínio 2: 2 with these values
